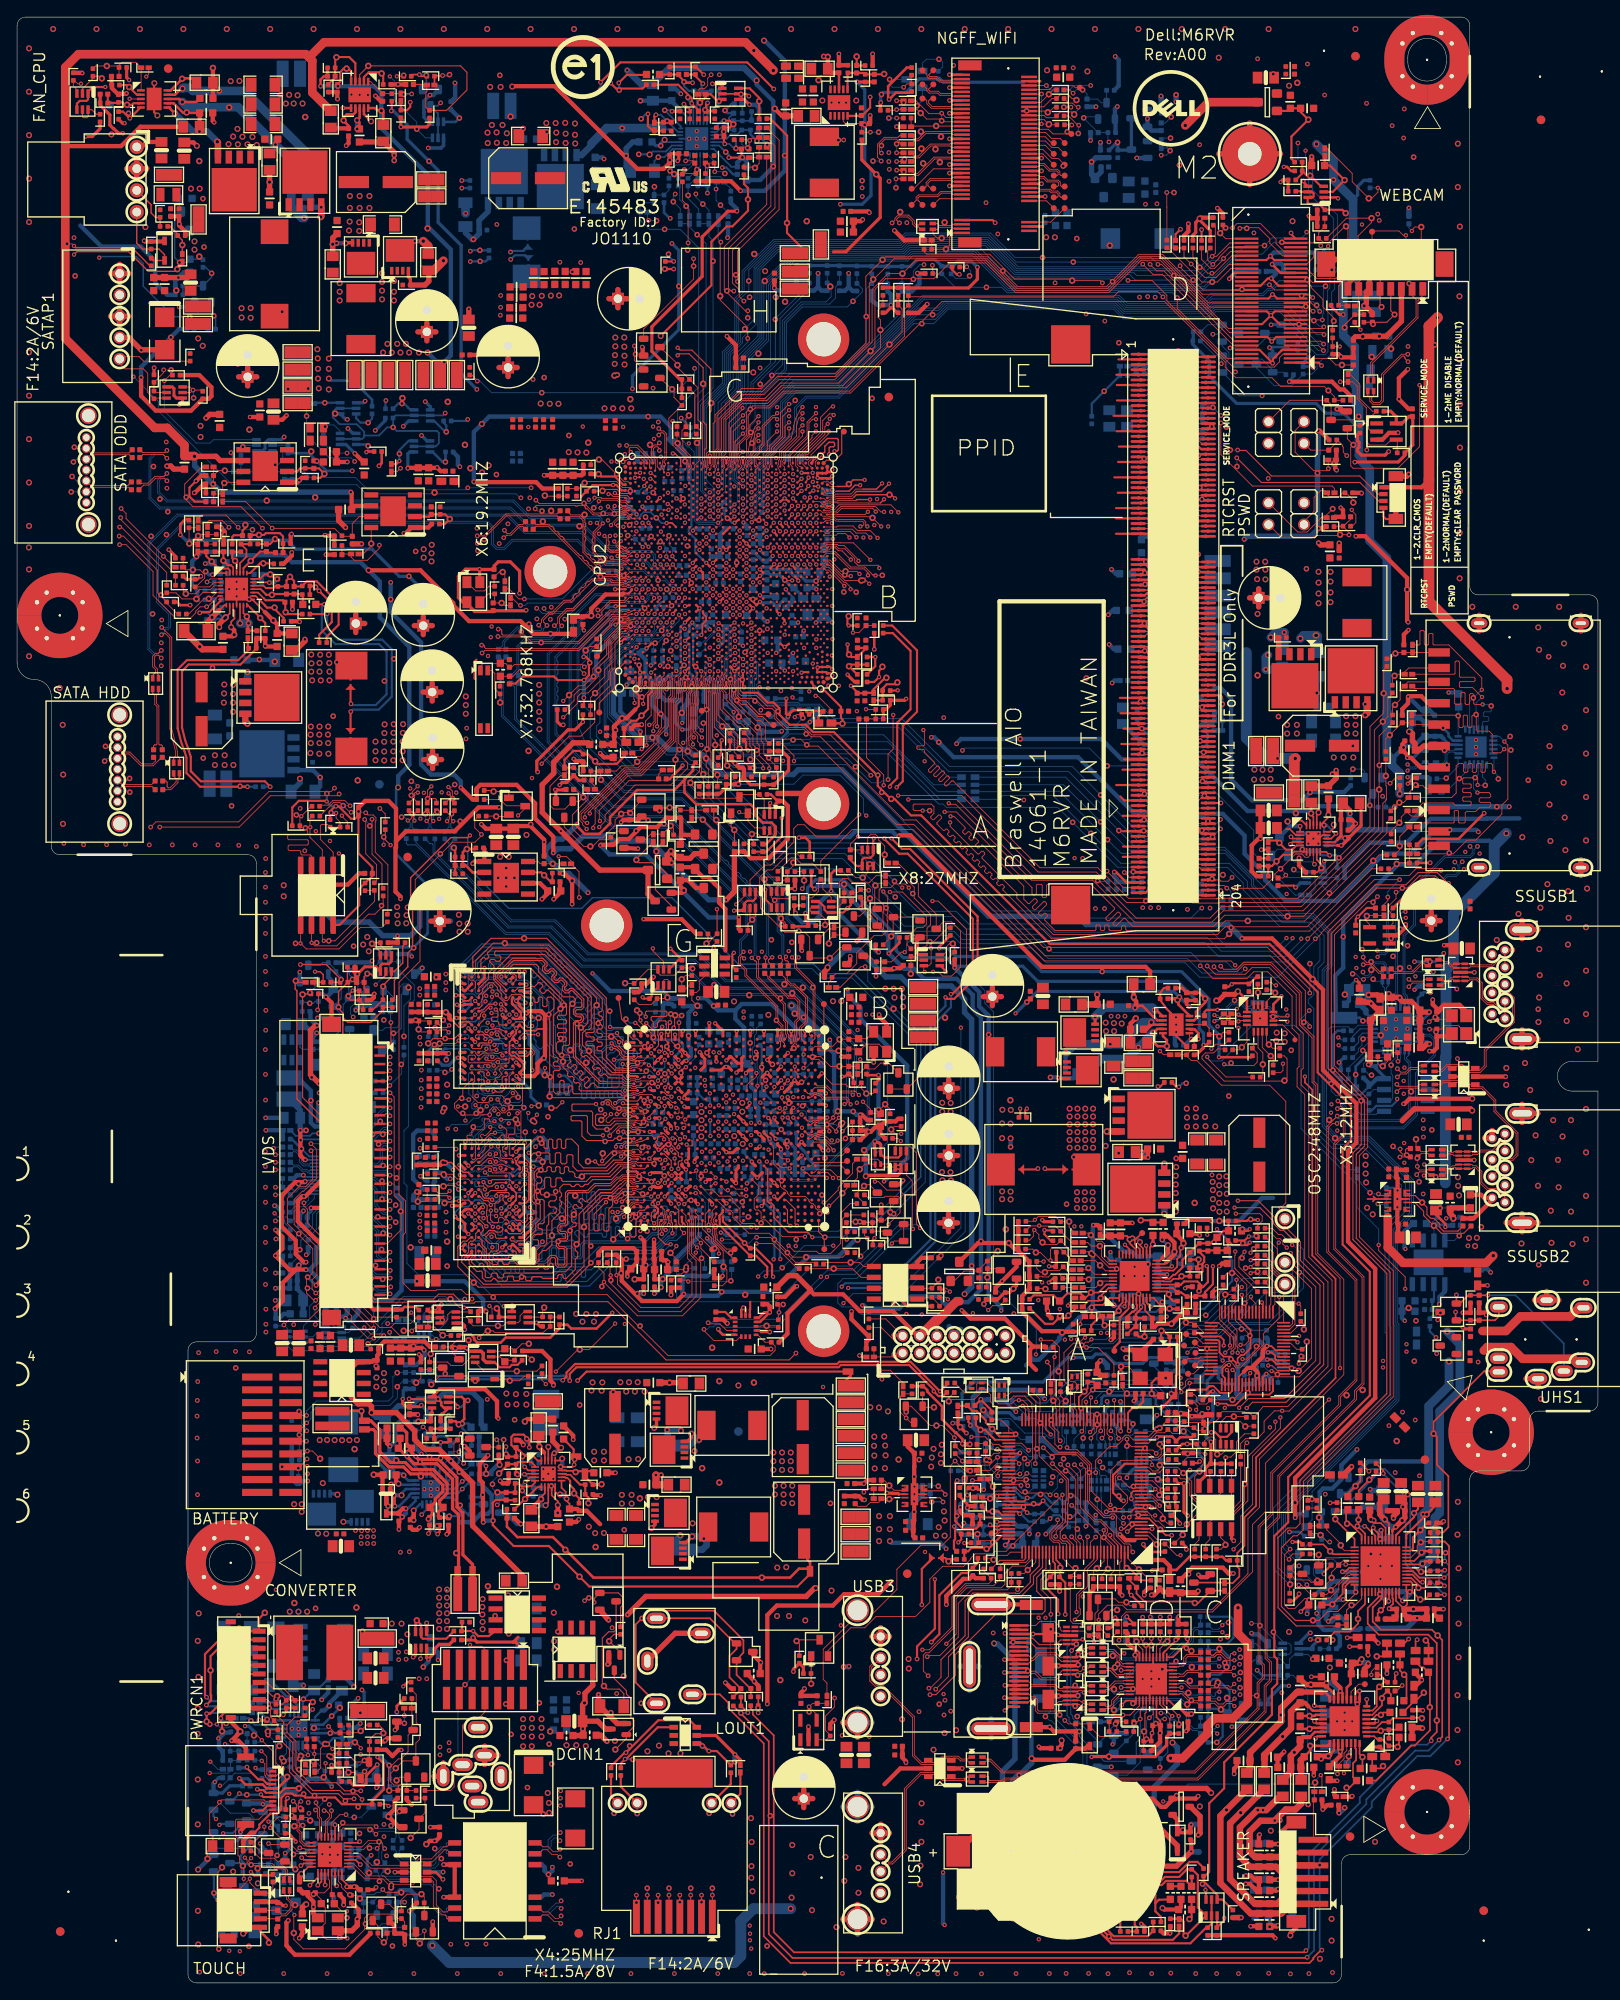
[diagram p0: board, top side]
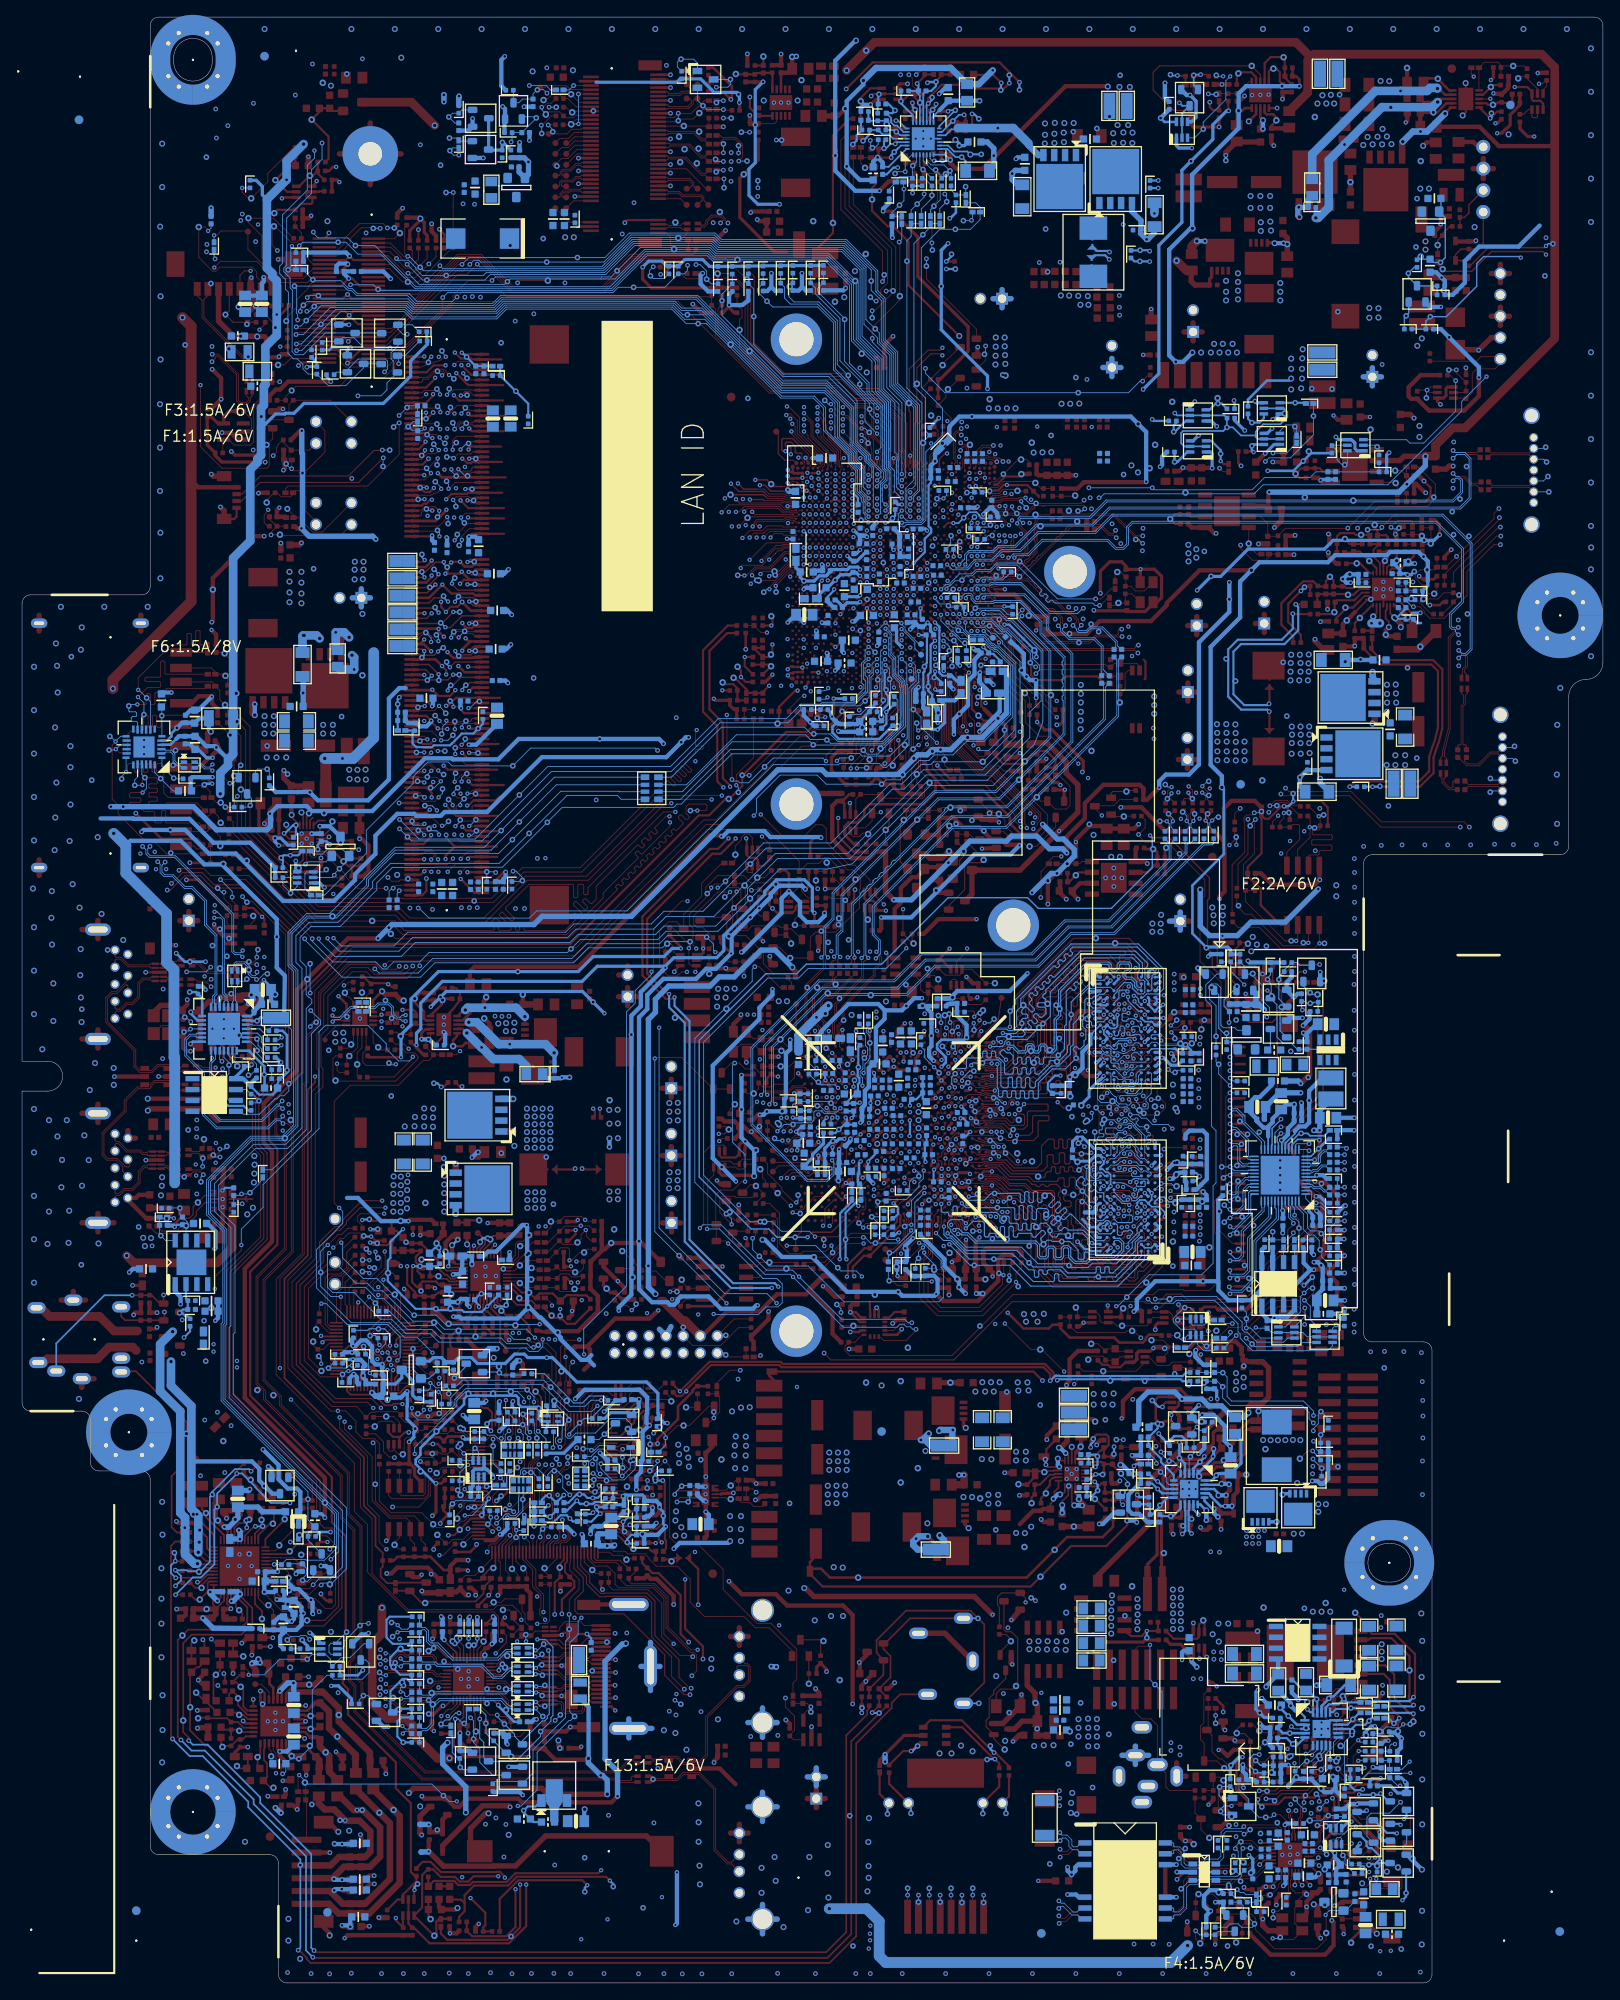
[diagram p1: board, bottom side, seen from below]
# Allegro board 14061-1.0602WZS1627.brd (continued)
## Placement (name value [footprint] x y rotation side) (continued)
R80232  0R3J-0-U-GP  [R603H22]  142.27 68.64 270 bottom
R80233  10KR2J-3-GP  [R402H16]  44.03 109.64 180 bottom
R80234  0R2J-2-GP  [R402H16]  91.73 150.64 180 bottom
R80235  0R0402-PAD-2-GP  [0R0402-PAD-1]  137.1 62 270 top
R80236  0R2J-2-GP  [R402H16]  40.94 113.86 90 top
R80237  0R2J-2-GP  [R402H16]  43.09 135.38 0 top
R80238  0R2J-2-GP  [R402H16]  155.84 110.34 90 bottom
R80239  0R2J-2-GP  [R402H16]  155.84 109.31 90 bottom
R80240  0R3J-0-U-GP  [R603H22]  88.75 154.42 270 bottom
RJ1  RJ45-8P-199-GP  [23-01120-2A03-A]  76.92 21.04 180 top
RN3  SRN33J-7-GP-U  [ARES8-CN24-UH20]  126.6 58.27 180 bottom
RN5  SRN10KJ-6-GP  [ARES8-CN24-MUH20]  127.62 62.33 0 bottom
RN6  SRN10KJ-5-GP  [ARES2H18]  123.76 70.36 0 top
RN7  SRN10KJ-5-GP  [ARES2H18]  122.89 66.01 270 bottom
RN8  SRN10KJ-6-GP  [ARES8-CN24-MUH20]  119.62 59.03 90 bottom
RN9  SRN10KJ-5-GP  [ARES2H18]  112.3 69.88 270 top
RN10  SRN75J-3-GP  [SMD-ARES8-1H28]  111.31 139.78 270 bottom
RN16  SRN2K2J-1-GP  [ARES2H16]  100.74 96.39 0 top
RN4302  SRN10KJ-5-GP  [ARES2H18]  115.22 69.34 180 top
RT1  NTC-10K-19-GP-U  [NTC-402H22-U]  101.35 158.37 0 top
RT2  NTC-10K-19-GP-U  [NTC-402H22-U]  85.8 85.52 180 top
RT3  NTC-10K-19-GP-U  [NTC-402H22-U]  75.86 200.97 0 top
RV5  P4500SCLHLRP-GP  [TVS5436-1121H105]  65.32 19.24 0 top
SATAP1  CLX-CON5-18-GP-U  [CI2505P1H00-LF-U]  12 195 270 top
SC1  SC4D7U6D3V3KX-DLGP  [C603H36]  164.76 145.09 0 bottom
SC2  SC1U16V3KX-4DLGP  [C603H36]  168.7 150.05 0 bottom
SC3  SCD1U16V2KX-3DLGP  [C402H22]  165.93 145.41 0 bottom
SC4  SC6D8P50V2CN-DL-GP  [C402H22]  162.29 156.11 180 top
SC5  SC1U16V3KX-4DLGP  [C603H36]  165.93 139.46 270 bottom
SC6  SC6D8P50V2CN-DL-GP  [C402H22]  162.11 147.88 180 top
SPK1  JWT-CON6-20-GP  [A1501WV0-6PS-5E]  149.7 13 270 top
SR1  6K2R2F-GP  [R402H16]  165.71 140.89 90 bottom
SRCON1  SKT-G6179-GP-U  [G6179-1000000-U]  35.09 127.25 0 top
SSUSB1  SKT-USB11-112-GP-U  [SKT-USB11-138165-1]  176.12 116.84 90 top
SSUSB2  SKT-USB11-112-GP-U  [SKT-USB11-138165-1]  176.12 95.34 90 top
SU1  RTS5170-GR-GP  [QFN24-G2D5H40-U]  170.73 144.6 270 bottom
TC1  ST330U2D5VDM-9GP  [CT7343H75]  131.1 204.09 270 bottom
TC5  ST100U6D3VBM-7GP  [CT3528H79]  17.28 192.98 0 top
TC10  SC10U10V5KX-2DLGP  [C805H50]  156.83 116.18 270 bottom
TC11  E100U16VM-47-GP  [ECAP-100D6D3H237]  165.49 125.55 0 top
TC13  E560U6D3VM-3-GP  [ECAP-100D6D3H375]  71.58 197.05 270 top
TC15  E560U6D3VM-3-GP  [ECAP-100D6D3H375]  57.46 190.27 0 top
TC16  E560U6D3VM-3-GP  [ECAP-100D6D3H375]  48.62 144.4 0 top
TC17  E560U6D3VM-3-GP  [ECAP-100D6D3H375]  48.57 152.3 0 top
TC18  E560U6D3VM-3-GP  [ECAP-100D6D3H375]  47.53 160.07 0 top
TC19  E560U6D3VM-3-GP  [ECAP-100D6D3H375]  39.63 160.32 0 top
TC20  E100U16VM-108-GP-U  [ECAP-100D6D3H237]  92.06 22.83 0 top
TC21  E820U2D5VM-7-GP  [ECAP-100D6D3H355]  49.46 125.5 0 top
TOUCH1  ENT-CON5-GP  [3703K-Q05N-11L]  24.7 8.5 270 top
TP2  -  [TPAD28]  158.56 204.89 270 top
TP13  -  [TPAD28]  138.42 18.54 90 bottom
TP14  -  [TPAD28]  138.29 15.32 90 bottom
TP24  -  [TPAD28]  157.72 34.95 180 top
TP35  -  [TPAD28]  71.39 157.38 180 bottom
TP37  -  [TPAD28]  122.59 214 0 top
TP38  -  [TPAD28]  121.32 215.26 0 top
TP39  -  [TPAD28]  122.59 215.26 0 top
TP46  -  [TPAD28]  114.04 52.59 0 top
TP49  -  [TPAD28]  79.8 155.41 180 bottom
TP50  -  [TPAD28]  79.8 156.65 180 bottom
TP57  -  [TPAD28]  80.12 148.84 0 top
TP62  -  [TPAD28]  107.22 208.03 0 top
TP63  -  [TPAD28]  122.59 207.65 0 top
TP64  -  [TPAD28]  121.32 207.65 0 top
TP65  -  [TPAD28]  121.32 212.72 0 top
TP66  -  [TPAD28]  122.59 212.72 0 top
TP67  -  [TPAD28]  121.32 214 0 top
TP68  -  [TPAD28]  122.59 211.46 0 top
TP69  -  [TPAD28]  121.32 211.46 0 top
TP70  -  [TPAD28]  122.59 210.19 0 top
TP71  -  [TPAD28]  121.32 210.19 0 top
TP72  -  [TPAD28]  122.59 208.91 0 top
TP73  -  [TPAD28]  121.32 208.91 0 top
TP74  -  [TPAD28]  105.95 208.03 0 top
TP75  -  [TPAD28]  104.68 208.03 0 top
TP76  -  [TPAD28]  107.22 209.93 0 top
TP77  -  [TPAD28]  105.95 209.93 0 top
TP78  -  [TPAD28]  104.68 209.93 0 top
TP79  -  [TPAD28]  105.95 220.47 0 top
TP80  -  [TPAD28]  107.22 220.47 0 top
TP81  -  [TPAD28]  105.95 222.12 0 top
TP82  -  [TPAD28]  107.22 222.12 0 top
TP83  -  [TPAD28]  105.95 223.77 0 top
TP84  -  [TPAD28]  107.22 223.77 0 top
TP85  -  [TPAD28]  124.37 221.74 0 top
TP100  -  [TPAD28]  67.88 155.22 0 top
TP101  -  [TPAD28]  123.38 216.33 0 top
TP149  -  [TPAD28]  83.98 85.85 0 top
TP150  -  [TPAD28]  83.98 84.58 0 top
TP155  -  [TPAD28]  81.34 85.83 0 top
TP158  -  [TPAD28]  81.21 89.9 180 bottom
TP159  -  [TPAD28]  88.63 97.95 180 bottom
TP163  -  [TPAD28]  97.14 97.41 0 top
TP164  -  [TPAD28]  97.14 94.92 0 top
TP165  -  [TPAD28]  97.14 96.16 0 top
TP203  -  [TPAD28]  131.67 87.73 270 top
TP204  -  [TPAD28]  128.4 73.95 90 top
TP4116  -  [TPAD28]  96.75 181.51 0 top
TP4117  -  [TPAD28]  68.13 148.64 0 top
TP4118  -  [TPAD24]  149.54 110.34 90 top
TP4124  -  [TPAD28]  137.03 71.27 180 top
TP4125  -  [TPAD28]  137.85 72.23 180 top
TP4126  -  [TPAD28]  136.65 72.69 180 top
TP4127  -  [TPAD28]  137.9 73.71 180 top
TP4128  -  [TPAD28]  136.56 74.57 180 top
TP4129  -  [TPAD28]  137.83 74.94 180 top
TP4130  -  [TPAD28]  136.81 75.92 180 top
TP4131  -  [TPAD28]  70.38 115.24 0 top
TP4132  -  [TPAD28]  94.46 85.86 0 top
TP4133  -  [TPAD28]  94.41 114.53 0 top
TP4134  -  [TPAD28]  87.92 148.44 0 top
TP4135  -  [TPAD28]  88.53 147.17 0 top
TP4136  -  [TPAD28]  80.91 152.55 180 bottom
TR1  FILTER-4P-137-GP-U  [L125100-4P-4H28]  158.41 186.87 270 top
TR3  FILTER-4P-137-GP-U  [L125100-4P-4H28]  160.11 117.82 270 bottom
TR4  FILTER-4P-137-GP-U  [L125100-4P-4H28]  165.26 106.98 180 top
TR5  FILTER-4P-137-GP-U  [L125100-4P-4H28]  112.35 23.85 0 top
TR6  FILTER-4P-137-GP-U  [L125100-4P-4H28]  165.29 104.78 180 top
TR7  FILTER-4P-137-GP-U  [L125100-4P-4H28]  112.35 26.09 0 top
TR12  MCM1012B900FBP-GP-U  [L125100-4P-1H37]  106.54 205.51 180 top
TR13  MCM1012B900FBP-GP-U  [L125100-4P-1H37]  31.55 11.46 90 top
TR20  FILTER-4P-120-GP  [L125100-4P-1H28]  126.41 32.27 0 bottom
TR21  FILTER-4P-120-GP  [L125100-4P-1H28]  126.41 34.43 0 bottom
TR22  FILTER-4P-120-GP  [L125100-4P-1H28]  126.41 36.71 0 bottom
TR23  FILTER-4P-120-GP  [L125100-4P-1H28]  126.41 38.87 0 bottom
TR24  FILTER-4P-120-GP  [L125100-4P-1H28]  126.41 32.27 0 top
TR25  FILTER-4P-120-GP  [L125100-4P-1H28]  126.41 34.43 0 top
TR26  FILTER-4P-120-GP  [L125100-4P-1H28]  126.41 36.71 0 top
TR27  FILTER-4P-120-GP  [L125100-4P-1H28]  126.41 38.87 0 top
TR28  FILTER-4P-137-GP-U  [L125100-4P-4H28]  165.43 142.5 180 bottom
TXE1  JOWLE-CON2-5-GP  [A2541WV0-1EX2PA-6T]  146.45 181.4 270 top
U1  AO6402A-GP  [SOT-6-1H50]  32.16 109.17 0 bottom
U2  SN74AUP1G34DBVR-GP  [SOT-23-5H58]  160.25 181.51 270 top
U6  ALC3661-CG-GP  [QFN48J6-G465H40]  159.55 48.77 90 top
U7  AZ1045-04F-R7G-GP  [DFN10G2510H26]  168.92 118.24 270 top
U8  W25Q64FWSSIG-GP  [SOIC8-1H86]  35.09 127.25 180 top
U9  M24C02-WMN6TP-GP-U  [SOIC8H69]  162.52 103.89 270 bottom
U15  MX25L1006EMI-10G-GP  [SOIC8H69]  140.22 55.63 0 top
U20  RTL8111G-CGT-1-GP-U2  [QFN32J4-G2D85H36]  36.61 14.99 270 top
U21  TPA3131D2RHBR-GP-U  [QFN32-G3D55H40]  155.35 30.61 270 top
U25  M24C64-WMN6TP-2-GP  [SOIC8H69]  38.01 81.79 180 bottom
U35  G2129TL1U-GP  [SC70-6H44]  88.08 135.76 180 top
U41  MBT3904DW1T1G-2-GP  [SOT-363H44]  7.65 220.12 180 top
U42  AO6402A-GP  [SOT-6-1H50]  81.62 118.97 270 top
U49  PM25LD010C-SCE-1-GP  [SOIC8H69]  102.8 81.92 90 top
U51  AZ1045-04F-R7G-GP  [DFN10G2510H26]  169.2 96.27 270 top
U52  TPS22966DPUR-GP  [SON14J3020-G2610H34]  105.01 57.18 90 top
U54  TPS22966DPUR-GP  [SON14J3020-G2610H34]  161.52 91.71 90 top
U55  BQ24727RGRR-1-GP  [QFN20G3D5-G2D15H40]  48.42 57.78 180 bottom
U109  IT8739E-GP  [LQFP128H63]  123.81 58.14 270 top
U119  AZ1117CR-ADJTRG1-GP-U  [SOT-89-4541-3PH63]  122.72 21.34 180 bottom
U120  OZ554ALN-B-0-TR-GP  [QFN20-G2D1H32]  32.93 29.72 90 bottom
U121  AZC099-04S-1-GP  [SOT-6H58]  46.64 12.95 270 top
U122  AZC099-04S-1-GP  [SOT-6H58]  46.64 12.95 270 bottom
U124  AP22802AW5-7-GP  [SOT-23-5H58]  92.62 29.59 0 top
U125  AP22802AW5-7-GP  [SOT-23-5H58]  159.42 122.57 90 top
U126  RTD2136S-CG-GP  [QFN48J6-G4D55H40]  37.78 94.5 270 bottom
U127  PS8407ATQFN40GTR2-A1-GP  [QFN40J5-G3D65H32]  132.74 35.57 270 top
U129  AZ1045-04F-R7G-GP  [DFN10G2510H26]  123.3 33.58 270 top
U130  AZ1045-04F-R7G-GP  [DFN10G2510H26]  123.3 40.64 270 top
U131  AZ1045-04F-R7G-GP  [DFN10G2510H26]  123.3 37.11 90 top
U4101  NPCE948LA0DX-GP  [LQFP64H63]  143.97 74.24 0 top
U6701  KXCNL-1010-GP  [LGA16G3-1H40]  85.25 76.83 90 top
U6702  GL850G-OHY31-GP  [QFN28-G3D75H32]  161.38 111.62 180 bottom
U6703  IP4223CZ6-1-GP  [SOT-6H44]  107.98 25.1 90 top
U6704  IP4223CZ6-1-GP  [SOT-6H44]  169.3 106.05 90 top
U6705  AZC099-04S-1-GP  [SOT-6H58]  78.19 28.96 270 top
U6706  ISL62882CHRTZ-T-GP  [QFN40-G3D5H32]  130.78 82.71 180 top
U9625  TPS2546RTER-GP  [QFN16-G1D8-UH32]  145.47 112.84 90 top
UHS1  AUDIO-JK500-GP  [2SJ3082-038111F]  176.5 75.29 90 top
UR5  330R2F-GP  [R402H16]  83.52 25.04 0 top
UR6  330R2F-GP  [R402H16]  69.5 24.71 0 top
UR7  330R2F-GP  [R402H16]  70.65 24.71 0 top
USB3  SKT-USB6-174-GP  [SKT-USB6-135063]  98.35 37.03 90 top
USB4  SKT-USB6-174-GP  [SKT-USB6-135063]  98.35 14.03 90 top
WEBCM1  JWT-CON8-4-GP  [A1251WR0-8PS-5E]  160.12 201.1 180 top
X3  XTAL-12MHZ-14GP  [SMD-OSC6H30]  168.74 112.12 90 top
X4  XTAL-25MHZ-181-GP  [OSC-3225-4P-4H36]  36.36 6.86 0 top
X6  XTAL-19D2MHZ-3-GP  [OSC-3225-4P-4H32]  53.4 162.71 270 top
X7  XTAL-32D768KHZ-67-GP  [SMD49-6914-0403H56]  54.65 150.18 270 top
X8  XTAL-27MHZ-85-GP-U  [OSC-3225-4P-4H30]  101 110.11 90 top
XDP1  SMC-CONN60A-GP  [BSH-03001-FDA]  144.09 196.82 90 top
XF1  XFORM-12P-48-GP  [XFORM12A127097H91]  55.91 11.94 90 top
XF2  XFORM-12P-48-GP  [XFORM12A127097H91]  55.91 11.94 270 bottom

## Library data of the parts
AFTP1 = AFTE14P-75: tolerance: ZZ.AFT14.101
BAT2 = 50290-0100N-001: tolerance: 20.F2196.010
BT1 = AAA-BAT-034-K01: tolerance: 62.70010.031
C3 C60 C63 C64 C67 C68 C71 C76 C77 C109 C127 C129 C405 C406 C478 C485 C1608 C1609 C1858 C4254 C6710 PC5112 PC5116 PC5212 PC5216 PC5223 PC5225 PC5257 PC5258 PC5260 PC5261 = C603H36: tolerance: 78.10610.5BLDL
C4 = C603H36: tolerance: 78.47523.5BLDL
C5 = C603H36: tolerance: 78.47422.5BLDL
C6 C8 C24 C26-C28 C35 C49 C54 C56 C61 C62 C65 C66 C69 C70 C74 C75 C78 C79 C81 C82 C89 C103 C104 C116 C131 C145 C147 C163 C179 C182 C183 C185 C186 C201 C202 C204 C211 C217 C227 C231 C270 C271 C284 C289 C290 C293 C295 C297-C303 C314-C316 C322 C324 C325 C328 C364 C372 C398 C409 C474 C483 C486 C489 C495 C500 C514 C522 C523 C525 C527-C530 C534 C536-C538 C542 C544 C547-C549 C554 C557 C562 C573 C616 C714 C721 C774 C781 C789-C792 C820 C821 C826 C829 C853 C869 C1603-C1606 C1617 C1668 C1670 C1701 C1703 C1838-C1840 C1842 C1851-C1854 C1856 C1857 C1859-C1861 C1868 C1869 C4265 C4267-C4269 C4272-C4280 C4282 C4283 C4288 C4290-C4298 C6701 C6702 C6711 C6732-C6734 C12327-C12330 C12332-C12336 C12338 C12343-C12348 PC27 PC151 PC4416 PC4516 PC4707 PC5011 PC5229 PC5264 PC5433 PC5440 SC3 = C402H22: tolerance: 78.10421.2FLDL
C7 C9 C30 C31 C170 C207 C558 C559 C561 C864 C1607 C1616 C1827 C4266 = C402H22: tolerance: 78.10523.5FL
C10 C134 C157 C159 C160 C176 C203 C267 C268 C1780 C12350 = C402H22: tolerance: 78.10134.1FLDL
C11 C112 C144 C146 C154 C155 C283 C292 C296 C450 C1674 C4261 C4263 C4289 C12326 PC21 PC4708 PC5005 PC5006 PC5430-PC5432 PC5434 PC5439 TC10 = C805H50: tolerance: 78.10623.51LDL
C14 C114 C115 C118 C119 C141 C142 C149 C151 C755 C1855 C1864 C3452 C3457 C3458 C4281 C4284-C4287 C12331 C12342 C12349 PC4427 PC4513 PC5232 PC5271 = C402H22: tolerance: 78.10324.2FLDL
C16 C90 C234 C272 C852 C1669 C1671 C1702 C1704 = C805H54: tolerance: 78.10623.51L
C20 = C805H54: tolerance: 78.47522.51LDL
C29 C50 C52 C150 C214 C218 C251 C403 C404 C407 C408 C535 C568 C597-C600 C605-C609 C612 C614 C617-C627 C629-C634 C758-C761 C765-C770 C773 C775-C779 C782 C783 C785 C786 C793-C796 C798-C803 C805-C809 C813-C819 C823-C825 C827 C835 C1491 C1633-C1636 C1638-C1641 C1643-C1663 C1665 C1666 C1698 C1699 C1867 C1877 C4101 C4102 C4259 PC1 PC163 PC4428 PC4528 PC4702 PC4905 PC4906 PC5003 PC5004 PC5233 PC5259 PC5443 = C402H22: tolerance: 78.10523.5FLDL
C32 = C603H36: tolerance: 78.10492.4BLLL
C33 = C402H22: tolerance: 78.27034.1FLLL
C36-C39 = C1206H75: tolerance: 078.10525.022D
C40 = C1206H71: tolerance: 78.10525.22LLL
C42 C86 = C402H22: tolerance: 78.10322.2FL
C43 C3456 = C402H22: tolerance: 78.10422.5FLLL
C44 = C402H22: tolerance: 078.15124.02FD
C47 C753 C1846 = C402H22: tolerance: 78.10423.2FL
C48 C543 C551 C3459 C3460 PC4401 PC4406 PC4407 PC5240 PC5241 = C805H58: tolerance: 78.10622.51LDL
C72 C73 C138 C139 C771 C780 C784 C787 C788 C797 C804 C810 C811 C828 C830 PC4917 PC4918 SC1 = C603H36: tolerance: 78.47520.5BLDL
C80 C84 C121 C132 PC5114 PC5219 PC5226 = C402H22: tolerance: 78.10134.1FL
C87 C88 C111 C191 C213 C238 C249 C380 C385 C399 C516 C572 C574-C576 C763 C764 C4230 C4260 C4262 = C402H22: tolerance: 78.10421.2FL
C93 C94 C96 C105 C397 C400 C545 C552 C12324 C12325 PC20 PC28 PC34 PC4204 PC4302 PC4402-PC4404 PC4423 PC4523 PC4703 PC4913 PC4914 PC4916 PC5008 PC5234 PC5236 PC5242 PC5273 PC5442 = C603H35: tolerance: 78.10424.2BLDL
C97 C100 C859 = C603H36: tolerance: 78.10424.2BL
C101 C110 C189 C192 C193 C208 C401 C402 C1801 PC5113 PC5213 PC5224 PC5435 PC5447 = C603H36: tolerance: 78.10522.5BLDL
C106 C107 PC8 = C402H22: tolerance: 78.33034.1FLDL
C126 PC124 = C402H22: tolerance: 78.22034.1FL
C130 = C402H22: tolerance: 78.10422.5FL
C140 C232 C391 C540 C1615 PC4426 PC4526 = C603H36: tolerance: 78.22523.5BLDL
C174 C175 C180 = C402H22: tolerance: 78.10491.4FL
C181 = C402H22: tolerance: 78.22510.5FL
C190 C194 C220 C221 = C603H36: tolerance: 78.47520.5BL
C195 PC12 = C603H36: tolerance: 78.10422.2BL
C198-C200 C210 = C603H36: tolerance: 78.27324.2BLDL
C205 C212 = C402H22: tolerance: 78.15034.1FLDL
C215 C216 C291 C641-C644 C772 = C805H54: tolerance: 78.22610.51LDL
C222 C239 C243 C263 = C603H36: tolerance: 78.10324.2BL
C223 C224 C228 C229 PC16 PC19 PC60 PC4421 PC4521 = C603H36: tolerance: 78.22422.2BLDL
C225 C235 C247 C255 = C603H36: tolerance: 78.68421.5BL
C226 C236 C248 C256 = C603H36: tolerance: 78.10234.1BLDL
C304 C305 C582 C583 C590-C592 C812 C822 C6716-C6722 C6726-C6731 PC5012 = C603H40: tolerance: 78.22610.5BLDL
C313 C752 = C402H22: tolerance: 78.47034.1FL
C393 PC59 = C603H36: tolerance: 78.10421.2BL
C493 C509 C6703 PC5115 PC5215 PC5227 = C603H38: tolerance: 78.10610.5BL
C521 = C603H36: tolerance: 78.10521.5BL
C524 PC4303 PC4413 PC4420 PC4520 = C402H22: tolerance: 78.22224.2FLDL
C531 = C402H22: tolerance: 78.10224.2FL
C571 = C402H22: tolerance: 78.10413.5FLDL
C711 C6715 = C402H22: tolerance: 78.10034.1FL
C756 C757 = C402H22: tolerance: 78.12034.1FLDL
C762 = C402H22: tolerance: 78.12134.1FLDL
C836 C6725 = C402H20: tolerance: 78.10423.5FL
C839 = C402H22: tolerance: 78.68034.1FL
C1601 C1602 = C402H22: tolerance: 78.8R064.1FLDL
C1618 C1619 = C402H22: tolerance: 78.2R774.1FL
C1620-C1625 = C402H22: tolerance: 078.47510.05FD
C1667 C1696 C1700 = C402H22: tolerance: 78.10520.5FLDL
C1672 C1673 C1705 C1706 C4202 C4270 PC7 PC4418 PC4518 PC5235 PC5272 = C402H22: tolerance: 78.10224.2FLDL
C1847 = C402H22: tolerance: 078.82321.02FD
C1848 = C603H38: tolerance: 078.68421.05BD
C1849 = C402H22: tolerance: 78.82321.2FL
C1850 C6724 PC4527 = C402H22: tolerance: 78.10322.2FLDL
C3131 = C1808H87: tolerance: 078.1013N.014D
C3455 PC4405 PC5238 = C402H22: tolerance: 78.10422.5FLDL
C12339-C12341 PC4202 PC4203 = C603H36: tolerance: 78.10422.2BLDL
CMCLR1 CMCLR2 PSWD1 TXE1 = A2541WV0-1EX2PA-6T: tolerance: 21.60909.102
CN1 = 210-41-04GB02: tolerance: 21.62889.104
CN2 = 88459-047N: tolerance: 20.F1897.004
CONVT1 = CI1410M1HRL-NH: tolerance: 20.F2266.010
CPU2 = BGA1170M2725H57: tolerance: 071.BRASW.000U
D1 D33 = SOD323AKH38: tolerance: 83.00355.D1F
D5 = SOT-23-9H44: tolerance: 75.00040.07D
D6 = SOD323AKH38: tolerance: 83.R5003.H8H
D14 = SOT23-2D4-312H48: tolerance: 75.00099.F7D
D18 = SOD323AKH40: tolerance: 83.00355.F1F
D21 = SOD523AKH28: tolerance: 83.02015.0AF
D32 = D4724AKH44: tolerance: 83.3R010.C8M
D34 D5209 = SOT23-2D4-312H44: tolerance: 75.00054.I7D
DCIN1 = 2DC3115-000111F: tolerance: 022.10015.0311
DCIN2 = 88314-077N: tolerance: 20.F1498.007
DIMM1 = AS0A621-J4R6-7H-U: tolerance: 62.10024.S21
F1 F3 F4 F13 = POLYSW-2114H30: tolerance: 069.50001.0031
F2 F14 = POLYSW-2114H30: tolerance: 069.50003.0001
F6 = POLYSW-3217-UH40: tolerance: 69.50007.B91
F16 = FUSE-1608H22: tolerance: 69.43001.441
FANC3 = HF1804H: tolerance: 021.D0086.0104
G5 = CON2C-U: tolerance: ZZ.CON2C.XXX
GPU1 = BGA631M23H82: tolerance: 71.SUNM2.M02
H1-H5 = HOLE237R158: tolerance: ZZ.0HOLE.011
H6 H9 = GEN8D5X8R5X4D5-8-F-A: tolerance: ZZ.00PAD.BV1
H7 = GEN315R138-8-F-A-1: tolerance: ZZ.00PAD.BU1
H10 = GEN315R178-8-F-A-1: tolerance: ZZ.00PAD.BR1
H11 = GEN315R138-8-F-A-2-S: tolerance: ZZ.00PAD.HK1
HDD1 ODD1 = 15-02070-5A61-A: tolerance: 020.80244.0007
HDMI1 = SKT-HDMI22-150077: tolerance: 062.10012.0121
HDMI2 = LVDFH-02004-TP00: tolerance: 20.F2139.020
HS6 = STF256R109H99: tolerance: 34.3NH01.001
L1 = L20125H42: tolerance: 68.00216.121
L2 = L3030-2709H41: tolerance: 68.2R21F.10E
L3 = L603H38: tolerance: 68.00335.091
L4 L5 L36 L37 L4103 L4104 = L125100-4P-1H36: tolerance: 68.12105.201
L7 L9 = L603H38: tolerance: 68.00335.081
L10 L52 L53 = L603H38: tolerance: 68.00335.141
L16 L17 L19 = L603H38: tolerance: 68.00230.231
L20 L21 L47-L51 L54 L62 L4102 = L402H24: tolerance: 68.00213.031
L22 = L402H22: tolerance: 68.00084.541
L31-L34 = L20125H42: tolerance: 68.00216.111
L46 PR36-PR38 PR46 PR47 PR211-PR213 PR4490-PR4493 PR4590 PR4591 PR4790 PR4791 PR4904-PR4910 PR4913 PR4915 PR4916 PR4926 PR4990 PR4991 PR5003-PR5008 PR5012 PR5013 PR5090 PR5091 PR5471 PR9788 PR9789 R101 R157 R183 R185 R1223-R1225 R79935 = 0R0805-PAD: tolerance: ZZ.R0805.ZZZ
L61 = L8080-6020H158: tolerance: 068.33010.1061
L4101 = L402H22: tolerance: 68.00084.I21
LED2 = LED1608AKH30: tolerance: 83.01608.Q70
LOUT1 = JAC331-0140A8B-9H: tolerance: 22.10277.2M1
LPC1 = HL5507F: tolerance: 21.60964.207
LVDS1 = 50524-0300N-001: tolerance: 020.K0005.0030
MEM1-MEM4 = BGA96D075130H48: tolerance: 72.51G63.R0U
MEMCD1 = 156-5101902601: tolerance: 062.10002.0161
NGFF1 = 2199230-7: tolerance: 62.10043.K51
OSC2 = SMD-OSC8H52: tolerance: 82.20013.151
PC4 PC4705 PC4909 PC4910 PC5002 PC5262 PC5446 = C402H22: tolerance: 78.22034.1FLDL
PC5 = C603H40: tolerance: 78.22422.2BL
PC6 = C402H22: tolerance: 78.15134.1FLDL
PC9 PC14 = C402H22: tolerance: 78.10324.2FL
PC11 = C402H22: tolerance: 078.39124.02FD
PC13 PC4411 PC4511 PC5268 = C402H22: tolerance: 78.33124.2FLDL
PC15 = C402H22: tolerance: 078.33322.02FD
PC17 PC18 PC22 PC33 PC58 SC2 SC5 = C603H36: tolerance: 78.10521.2BLDL
PC23 PC5267 = C603H36: tolerance: 78.15224.2BLDL
PC24 PC29 PC31 PC32 PC61 PC4424 PC4524 PC4706 PC4901-PC4904 PC5001 PC5010 PC5269 PC5270 PC5441 = C1206H71: tolerance: 78.10622.22LDL
PC41 = C402H22: tolerance: 78.22034.L1L
PC68 = C402H22: tolerance: 78.27034.1FLDL
PC2127 PC4304 PC4417 PC4517 PC5237 = C402H22: tolerance: 78.47124.2FLDL
PC4201 PC4408 = C805H54: tolerance: 78.10524.21LDL
PC4301 PC4305 = C402H22: tolerance: 78.10034.1FLDL
PC4409 PC4410 PC4509 PC4510 PC4701 PC4801 PC5211 PC5222 PC5243 PC5251 PC5254-PC5256 PC5266 PC5436 PC5444 = C402H22: tolerance: 78.10423.5FLDL
PC4412 PC4512 = C402H22: tolerance: 78.47034.1FLDL
PC4414 PC4514 = C402H22: tolerance: 78.10221.2FLDL
PC4415 PC4515 = C402H22: tolerance: 78.33224.2FLDL
PC4419 = C402H22: tolerance: 78.56124.2FLDL
PC4429 PC4529 PC4704 PC4907 PC4908 PC5009 PC5263 PC5445 = C603H36: tolerance: 78.10224.2BLDL
PC4519 = C402H22: tolerance: 78.18224.2FLDL
PC4911 PC4912 = C402H22: tolerance: 78.18034.1FLDL
PC4915 = C402H22: tolerance: 78.10521.5FLDL
PC5007 = C402H22: tolerance: 78.33321.2FLDL
PC5217 = C402H22: tolerance: 78.10423.2FLDL
PC5221 PC5228 = C402H22: tolerance: 78.22044.1FL
PC5239 = C402H22: tolerance: 78.22124.2FLDL
PC5265 = C402H22: tolerance: 78.68124.2FLDL
PD4202 = D5436AKH97: tolerance: 83.P6SBM.CAG
PD4401 = D1608-035030AKH28: tolerance: 83.1R003.N8F
PD4405 = SOD323AKH42: tolerance: 83.04148.D1H
PG3 PG4 PG4401 PG4402 PG4501 PG4502 = CON2C: tolerance: ZZ.CON2C.XX1
PG4901-PG4908 = GAP-CLOSE-PWR-3: tolerance: ZZ.CLOSE.001
PL1 PL4501 = L115100-2H158: tolerance: 68.R3610.10M
PL3 = L115100-2030H158: tolerance: 68.1R51A.10E
PL4301-PL4303 = L402H24: tolerance: 69.80007.021
PL4401 = L736630H119: tolerance: 68.R3310.201
PL4701 PL5002 PL5004 PL47001 = L686647H119: tolerance: 68.1R51A.10F
PL4903 = L686647H119: tolerance: 68.3R31A.10V
PL4904 = L686647H119: tolerance: 68.2R21B.10J
PL5003 = L7066-1830-UH119: tolerance: 68.5R610.10X
PN4401 PN4402 PN4501 PN4502 = NTC-402H24-U: tolerance: 69.60028.041
PQ7 = PPAK-5PH45: tolerance: 84.00172.A37
PQ8 = PPAK-5PH45: tolerance: 84.SRA12.037
PQ4204 = SOT323CBE2D2H44: tolerance: 84.00124.H1K
PQ4205 = SOT323CBE2D2H44: tolerance: 84.00124.K1K
PQ4206 PQ4408 = SOT23DGS2D4H44: tolerance: 84.2N702.J31
PQ4401 PQ5001 PU4502 = PPAK-8P-5262H40: tolerance: 84.06520.037
PQ4402 PQ5002 PU4503 PU4504 = PPAK-8P-5262H40: tolerance: 084.06510.0037
PQ4406 PQ5006 Q30 Q48 Q49 Q1228-Q1233 Q6701 Q9646 = SOT-363H44: tolerance: 84.2N702.A3F
PQ4409 = SOT23CBE2D4H44: tolerance: 84.T3906.A11
PQ4701 PQ4901 PQ4903 PQ4904 PQ47001 PU4403 PU4405 = PPAK-8P-3232H36: tolerance: 84.07410.A37
PQ4702 PQ4902 PQ47002 = PPAK-8P-3232H36: tolerance: 84.07506.037
PQ5003 PQ5004 Q1 Q3 Q5 Q42 Q56 Q64 Q65 Q68 Q103 Q1246 Q1254 Q1257 Q2301 Q6703 Q9628 Q9636 Q9648 Q9650 = SOT23DGS2D4H48: tolerance: 84.2N702.E31
PQ5005 = SOT-363H44: tolerance: 84.00512.03F
PR1 PR12 PR4431 PR4455 PR4458 PR4462 PR5247-PR5250 PR5476 PR8521 PR9785 R14 R92 R131 R179 R180 R206 R379 R380 R503 R565 R618 R661-R663 R701 R1154 R1155 R1234 R1260 R1261 R1267 R1268 R1576-R1578 R1591 R1620-R1623 R1697 R1791 R1840 R1841 R1846 R1892 R1920 R2079 R6706 R79664 R79665 R79682 R79697-R79700 R79755 R79756 R79913 R79938 R79946-R79948 R79951 R79954-R79957 R79960 R79961 R79964 R80054-R80057 R80059 R80061 R80063-R80065 R80074-R80081 R80090 R80091 R80099 R80100 R80107-R80109 R80113 R80115 R80122 R80123 R80132 R80134 R80147 R80156 R80203-R80211 R80218 R80231 R80234 R80236-R80239 = R402H16: tolerance: 63.R0034.1DL
PR2 PR10 PR14 PR17 PR18 PR23 PR25 PR28-PR30 PR32 PR35 PR44 PR101 PR5014 PR5110 PR5216 PR5245 PR5274 PR5288 PR9773 PR9774 R5 R88 R374 R536 R682 R1160 = 0R0402-PAD: tolerance: ZZ.R0402.ZZZ
PR3 PR4 PR7 PR15 PR26 PR31 PR33 PR96 PR102 PR103 PR4210 PR4401 PR4429 PR4501 PR4529 PR5214 PR5241 PR5251 PR5257 PR5480 PR9768-PR9770 PR9772 PR9775 PR9776 PR9780 PR9787 R46 R64 R143 R199 R225 R277 R278 R287 R293 R314 R316 R331 R336 R368 R375 R477 R544 R572 R627 R635 R646 R677 R680 R1738-R1745 R1792-R1800 R1917 R79675 R79717 R79718 R79759 R79761-R79763 R79766 R79772 R80155 = R402H16: tolerance: 63.10234.1DL
PR5 PR19 PR58 PR77 PR4450 PR4718 PR4917 PR4922 PR5001 PR5112 PR5212 PR5242 PR5282 PR5286 PR9796 R82 R266 R270 R275 R279 R354 R357 R363 R366 R370 R397 R404 R653 R655-R658 R1801-R1819 R79621 R79625 R79692-R79694 R79780 R80125 R80126 R80216 = R402H16: tolerance: 64.10025.6DL
PR6 = R402H16: tolerance: 64.19115.6DL
PR8 PR9 R208 R210 R1896 R79796 R79966 R80133 = R402H16: tolerance: 64.47025.6DL
PR11 PR4410 PR4413 PR4510 PR4513 PR5220-PR5222 PR5232-PR5234 PR5254 PR5261 PR5479 PR9806-PR9811 R15 R22 R23 R34 R35 R47 R53 R74 R86 R178 R205 R207 R222 R280 R283 R305 R318 R381 R385 R386 R395 R399 R400 R507 R515 R532 R539 R651 R652 R664 R668 R725 R729 R1165 R1166 R1203 R1209 R1214 R1240 R1241 R1258 R1263 R1264 R1569 R1571 R1584-R1589 R1592 R1593 R1596-R1599 R1601 R1602 R1604 R1606 R1608-R1612 R1627 R1628 R1637 R1668-R1672 R1683 R1689 R1747 R1776 R1778 R1835-R1839 R1891 R1916 R1984 R1985 R2080 R3586 R79618 R79633 R79634 R79660 R79668 R79684 R79685 R79712 R79713 R79715 R79939 R79949 R79950 R79977 R79980-R79982 R80050-R80053 R80092 R80093 R80103-R80106 R80153 R80154 R80235 = 0R0402-PAD-1: tolerance: ZZ.00PAD.M11
PR13 PR5016 = R402H16: tolerance: 64.80615.6DL
PR16 = R402H16: tolerance: 64.12115.6DL
PR20 = R402H16: tolerance: 64.56205.6DL
PR21 = R402H16: tolerance: 64.18715.6DL
PR34 = R402H16: tolerance: 64.82R55.6DL
PR39 PR41 PR48 PR50 PR4701 PR4713 PR4714 PR4716 PR4902 PR4903 PR4911 PR4912 PR5011 PR5018 PR5019 PR5474 PR5475 PR9783 PR9793 PR9794 PR9797 PR9805 = R805H24: tolerance: 63.2R231.16L
PR40 PR225 PR4402 PR4403 PR4422 PR4502 PR4503 PR4522 PR4712 PR4715 PR4812 PR5002 PR5213 PR5246 PR5258 PR9798 PR9803 R7 R41 R42 R44 R48-R51 R54 R56-R60 R62 R63 R65-R67 R75 R89 R95 R134 R138 R149 R156 R158 R164 R169 R172 R184 R186 R213 R221 R281 R285 R286 R296 R297 R303 R304 R310 R311 R313 R317 R323 R330 R333 R335 R340 R342 R348 R362 R364 R378 R388 R390 R391 R421 R481 R482 R498 R499 R505 R510 R514 R516 R517 R523 R530 R531 R533 R550 R552-R558 R560-R563 R567 R569 R576 R579 R581 R636 R637 R645 R675 R704 R707 R709 R717 R719 R722 R739 R1167 R1208 R1226 R1257 R1262 R1265 R1266 R1568 R1579-R1582 R1615 R1633 R1656 R1661 R1719 R1780 R1782 R1820 R1842 R1843 R1867 R1868 R1870 R1880-R1882 R1885-R1887 R1910 R1915 R5290 R6702 R79657 R79659 R79662 R79666 R79667 R79680 R79683 R79687-R79689 R79701-R79705 R79719-R79721 R79750 R79758 R79765 R79773 R79781 R79797 R79799 R79917 R79936 R79943-R79945 R79952 R79953 R80062 R80116 R80121 R80144 R80146 R80150 R80212 R80217 R80219 R80220 R80230 R80233 = R402H16: tolerance: 63.10334.1DL
PR42 = R402H16: tolerance: 64.26115.6DL
PR43 = R603H22: tolerance: 64.2R205.55L
PR45 = R603H22: tolerance: 64.36515.55L
PR51 = NTC-402H24-U: tolerance: 69.60013.131
PR53 PR4702 PR9804 R20 R1918 = R402H16: tolerance: 64.47035.6DL
PR57 = R402H16: tolerance: 63.51334.1DL
PR59 = R402H16: tolerance: 64.15825.6DL
PR60 = NTC-402H24-U: tolerance: 69.60013.141
PR78 = R402H16: tolerance: 64.69815.6DL
PR79 PR4416 PR4516 PR5283 R220 R284 R1202 R79716 = R402H14: tolerance: 64.10R05.6DL
PR1689 = R402H16: tolerance: 64.12425.6DL
PR4204 = R603H22: tolerance: 63.24434.15L
PR4207 = R603H22: tolerance: 63.47333.15L
PR4214 = R1206H28: tolerance: 63.33232.11L
PR4404 PR4504 = R402H16: tolerance: 64.47R05.6DL
PR4405 PR4505 R61 R1158 R1162 R1163 R1897 R79661 = R402H16: tolerance: 64.10015.6DL
PR4406 PR4506 = R402H16: tolerance: 64.56035.6DL
PR4407 PR4507 = R402H16: tolerance: 64.33015.6DL
PR4411 PR4511 = R402H16: tolerance: 64.15015.6DL
PR4412 PR5272 = R402H16: tolerance: 64.49925.6DL
PR4414 PR4514 = R402H16: tolerance: 64.62025.6DL
PR4415 PR4918 = R402H16: tolerance: 64.56225.6DL
PR4417 = R603H22: tolerance: 64.33035.55L
PR4418 PR9782 = R402H16: tolerance: 64.40215.6DL
PR4419 PR4519 = R402H16: tolerance: 64.75025.6DL
PR4420 PR4520 = R402H16: tolerance: 64.15035.6DL
PR4421 PR4423 PR4424 PR4521 PR4523 PR4524 PR5017 = R1206H28: tolerance: 63.2R232.11L
PR4425 PR4426 PR8519 PR8520 = R402H16: tolerance: 63.33234.1DL
PR4427 PR4901 PR4923 PR5010 PR5273 PR5275 PR5278 PR5281 PR5289 PR5297 PR9813 R26 R30 R33 R94 R132 R144 R151 R153 R155 R162 R181 R273 R321 R338 R360 R361 R424 R501 R512 R676 R1074 R1079 R1126 R1164 R1696 R1832 R1894 R1914 R6703-R6705 R79681 R79723 R79757 R79916 R80120 R80145 = R402H16: tolerance: 63.10434.1DL
PR4428 PR4528 = R805H24: tolerance: 63.1R031.16L
PR4430 PR4530 = R603H22: tolerance: 63.2R233.15L
PR4432 = R402H16: tolerance: 64.22125.6DL
PR4433 PR4533 = R402H16: tolerance: 64.18725.6DL
PR4451 = R402H16: tolerance: 64.68035.6DL
PR4515 = R402H16: tolerance: 64.45325.6DL
PR4517 = R603H22: tolerance: 64.10035.55L
PR4518 R1205 = R402H16: tolerance: 64.49915.6DL
PR4531 = R402H16: tolerance: 64.48725.6DL
PR4532 = R402H16: tolerance: 64.34825.6DL
PR4706-PR4709 PR9790-PR9792 PR9799-PR9802 = 0R0805-PAD-1-U: tolerance: ZZ.00PAD.M31
PR4717 = R402H16: tolerance: 64.36015.6DL
PR4914 = R402H16: tolerance: 64.66515.6DL
PR4919 = R402H16: tolerance: 64.68025.6DL
PR4920 PR4925 = R402H16: tolerance: 64.11035.6DL
PR4921 R332 R422 R80215 = R402H16: tolerance: 64.15025.6DL
PR4924 = R402H16: tolerance: 64.11835.6DL
PR5009 = R402H16: tolerance: 64.75035.6DL
PR5015 SR1 = R402H16: tolerance: 64.62015.6DL
PR5109 PR5209 PR5243 PR5290 PR5291 PR9767 R577 R1244 R1245 R1247 R1250-R1256 R79691 = 0R0603-PAD: tolerance: ZZ.R0603.ZZZ
PR5113 = R402H16: tolerance: 64.86615.6DL
PR5211 = R402H16: tolerance: 64.54915.6DL
PR5268 R80060 = R402H16: tolerance: 64.33025.6DL
PR5269 PR5276 = R3720H40: tolerance: 64.R0105.7FL
PR5270 = R603H22: tolerance: 64.31635.55L
PR5277 = R402H16: tolerance: 64.7R505.6DL
PR5279 = R402H16: tolerance: 64.1R505.6DL
PR5284 = R805H24: tolerance: 64.20R05.16L
PR5285 = R402H16: tolerance: 63.47434.1DL
PR5287 = R402H16: tolerance: 63.33534.1DL
PR5298 = R402H16: tolerance: 64.12035.6DL
PR5467 = R402H16: tolerance: 64.10235.6DL
PR5468 = R402H16: tolerance: 64.16935.6DL
PR5469 = R402H16: tolerance: 64.78725.6DL
PR5470 = R402H16: tolerance: 64.30935.6DL
PR5473 = R402H16: tolerance: 64.18025.6DL
PR9766 = R402H14: tolerance: 63.10134.1DL
PR9771 PR9779 = R402H16: tolerance: 64.1R005.6DL
PR9777 R215 R300 R301 R344-R346 R356 R359 R367 R1182 R1193 R80138 R80139 = 0R0603-PAD-1-U: tolerance: ZZ.00PAD.M21
PR9778 = R402H16: tolerance: 64.93115.6DL
PR9781 = R402H16: tolerance: 64.11025.6DL
PR9795 R302 = R402H16: tolerance: 64.51115.6DL
PR9812 R319 R1557-R1561 R79628 R79722 R80102 R80128 = R402H16: tolerance: 64.10035.6DL
PR9814 R19 R1919 R80112 = R402H16: tolerance: 63.10534.1DL
PT1 PT3 PT4 = ECAP-100D6D3H355: tolerance: 09.8271N.A4L
PT2 PT4491 PT4591 PT5001 PT5002 = SE361416H237: tolerance: 79.47612.A0L
PT4901 = SE361414H241: tolerance: 79.47612.3GL
PT4902 PT4903 = SE331721H237: tolerance: 79.22710.E0L
PTC9 PTC21 PTC4701 PTC4702 TC21 = ECAP-100D6D3H355: tolerance: 09.8271N.A5L
PU1 PU2 = PPAK-8P-5262H40: tolerance: 84.06552.037
PU3 PU5207 = PPAK-8P-5262H40: tolerance: 84.06508.037
PU4 PU4701 PU4705 = DFN10G3-G265175H32: tolerance: 74.08237.B73
PU7 = SOIC8-G3530H63: tolerance: 74.05912.03D
PU4201 PU5204 PU5205 = SOIC8H69: tolerance: 84.04407.G37
PU4401 PU4501 = LFQFN28J4-G2D7H40: tolerance: 074.81201.0073
PU4901 = QFN20-G1D75H32: tolerance: 074.08243.0073
PU5001 = QFN20-G1D75H32: tolerance: 74.08207.C73
PU5201-PU5203 = SOIC8-G3530H63: tolerance: 74.05930.B3D
PU5206 = DFN10G3-G265175H32: tolerance: 74.08068.A43
PWRCN1 = 51530-01041-W01: tolerance: 20.K0642.010
Q4 Q7 Q95 Q97 Q123 = SOT-363H44: tolerance: 75.27002.F7C
Q10 Q18 Q36-Q38 Q40 Q51 Q74-Q76 Q9625 = SOT23CBE2D4H44: tolerance: 84.T3904.C11
Q12 Q13 Q16 Q17 Q20 Q21 Q35 Q63 Q1206 Q9643 = SOT-363H44: tolerance: 84.M3904.B1F
Q19 Q6708 Q6710 Q6711 Q6714 Q9635 Q9642 = SOT23CBE2D4H44: tolerance: 84.T3904.H11
Q23 Q29 = SOT-363H44: tolerance: 75.27002.D7C
Q24 Q46 Q57 = SOT23-2D4-312H46: tolerance: 75.05125.07D
Q28 = SOT23DGS2D4H44: tolerance: 84.27002.W31
Q39 Q1209 Q1240 Q9629 Q9632 Q9640 Q9641 Q9647 Q9649 = SOT23DGS2D8H50: tolerance: 84.03413.B31
Q47 Q1236 Q1253 Q6702 Q6715 = SOT-23-10H44: tolerance: 84.03904.L06
Q66 Q77-Q79 Q1205 Q1214 Q1227 Q1234 Q6706 = SOT23DGS2D4H44: tolerance: 84.27002.Z31
Q1203 Q1204 Q1210 Q1212 Q1213 Q1255 Q1256 = SOT23DGS2D4H48: tolerance: 84.05067.031
Q1250 = SOIC8H69: tolerance: 084.04286.0037
Q6705 Q9624 = SOT23DGS2D8H50: tolerance: 84.03418.A31
Q9634 = SOT23DGS2D4H48: tolerance: 84.03052.031
R8 R644 = R603H22: tolerance: 63.33133.15L
R10 R329 R702 R705 R1129 R1687 R1688 R80228 = R402H16: tolerance: 63.82234.1DL
R13 R706 R1195 R80229 = R402H16: tolerance: 64.39225.6DL
R24 R216 R289 R1246 R1248 R1249 R1720 R6701 R79753 R80148 R80151 R80152 R80232 R80240 = R603H22: tolerance: 63.00000.00L
R27 R79622 = R1206H26: tolerance: 64.R3305.41L
R32 R69 R80 R133 R135 R139 R152 R324 R389 R535 R634 R659 R665 R669 R693 R720 R1883 R79669 R79670 R79673 R79677-R79679 R79686 R79914 R80140-R80142 R80201 R80202 = R402H16: tolerance: 63.47234.1DL
R37 R79631 = 0R1206-PAD-1: tolerance: ZZ.R1206.ZZ1
R39 = R402H16: tolerance: 63.22034.1DL
R43 = R402H16: tolerance: 64.22005.6DL
R45 R68 R382 R1259 R1822 R1823 R1826 R1827 R1888 R1889 R79656 R79787 R79788 = R402H14: tolerance: 64.10005.6DL
R55 R71 R72 R223 R261 R262 R272 R392 R502 R642 R721 R1204 R1844 R79690 R79732 R79733 R79736-R79739 R79764 R79798 R79967 R80110 R80111 = R402H16: tolerance: 63.22234.1DL
R73 R274 R492 R639 R643 R1830 R1831 R1845 R79774 R79786 R80157 = R402H16: tolerance: 63.20334.1DL
R76 = R402H16: tolerance: 64.82015.6DL
R81 = R603H22: tolerance: 64.10055.55L
R87 R91 R268 R80049 = R402H16: tolerance: 64.20025.6DL
R117 R122 R269 R483 R484 R542 R545 R1215 R1216 R1562 R1565 R1570 R79734 R79735 R79741-R79746 R79748 R79749 = R402H16: tolerance: 64.47015.6DL
R146 = R402H16: tolerance: 63.20234.1DL
R163 R79915 = R402H16: tolerance: 63.47334.1DL
R174 = R402H16: tolerance: 64.61905.6DL
R202 R203 R230 R885 R886 R924 R928 R945 R946 R1905 R1911 R1921-R1924 R79968 = R402H16: tolerance: 64.21015.6DL
R209 R309 R312 R337 R373 R393 R426 R681 R689 R1168-R1171 R1733 R1884 R79940-R79942 = R402H16: tolerance: 63.33034.1DL
R212 = R402H16: tolerance: 64.68R05.6DL
R267 = R402H16: tolerance: 64.51015.6DL
R299 R320 R870 R899 = R402H16: tolerance: 64.24305.6DL
R306 = R603H22: tolerance: 63.15234.15L
R322 R369 R1879 = R603H22: tolerance: 64.10045.55L
R347 = R402H16: tolerance: 64.39015.6DL
R351 R352 R667 R673 R79612 = R603H22: tolerance: 64.75R05.55L
R355 R365 = R603H22: tolerance: 64.10525.55L
R358 = R402H16: tolerance: 64.56015.6DL
R372 R394 R940 = R402H16: tolerance: 64.20015.6DL
R376 = R603H22: tolerance: 63.10033.15L
R377 R1242 = R402H16: tolerance: 64.24915.6DL
R396 R403 R415 R419 = R603H22: tolerance: 64.3R305.55L
R398 R963 R1159 R1893 R1895 R79965 = R402H15: tolerance: 63.10334.L0L
R428 R429 R79962 = R402H16: tolerance: 63.47034.1DL
R430 = R402H16: tolerance: 63.15234.1DL
R456-R458 R466 R473 R1746 = R402H16: tolerance: 63.51034.1DL
R511 = R402H16: tolerance: 64.12025.6DL
R513 R519 R1227 R1228 R1236 = R402H16: tolerance: 64.40205.6DL
R524 R1648 R1654 R80149 = R402H16: tolerance: 64.49R95.6DL
R527 R1217 = R402H16: tolerance: 64.18205.6DL
R537 R543 R549 R551 = R402H15: tolerance: 64.10025.L0L
R617 = R402H16: tolerance: 63.33334.1DL
R648 R650 = R402H16: tolerance: 64.17825.6DL
R649 = R402H16: tolerance: 64.64915.6DL
R935 = R402H16: tolerance: 64.45315.6DL
R943 R1900 R79963 = R402H16: tolerance: 64.84515.6DL
R948 R1899 = R402H16: tolerance: 64.47515.6DL
R1161 = R402H16: tolerance: 64.16915.6DL
R1200 R1890 R1906-R1909 = R402H16: tolerance: 64.40R25.6DL
R1201 = R402H16: tolerance: 64.12005.6DL
R1206 R1207 = R402H16: tolerance: 64.51R15.6DL
R1210 = R402H16: tolerance: 64.24905.6DL
R1211 R80137 = R402H16: tolerance: 64.49905.6DL
R1230 R80143 = R402H16: tolerance: 64.15005.6DL
R1239 = R402H16: tolerance: 64.20035.6DL
R1634 R79707-R79711 R79714 = R805H24: tolerance: 63.R0031.16L
R1647 R1653 = R402H16: tolerance: 64.20R05.6DL
R1714 R1729-R1732 = R402H14: tolerance: 63.10034.1DL
R1734 = R402H16: tolerance: 64.56R25.6D1
R1779 = R402H16: tolerance: 64.45R35.6DL
R1784-R1790 = R402H16: tolerance: 64.47005.6DL
R79623 R79627 = R402H16: tolerance: 64.30035.6DL
R79630 = R805H24: tolerance: 63.20131.16L
R79658 = R402H16: tolerance: 64.80R65.6DL
R79724-R79731 = R402H16: tolerance: 63.47134.1DL
R79747 = R402H16: tolerance: 64.43015.6DL
R79751 = R603H22: tolerance: 64.18005.55L
R79752 = R603H22: tolerance: 64.36R05.55L
R79754 R80124 = R805H24: tolerance: 64.10025.16L
R79785 = R402H16: tolerance: 64.11305.6DL
R79790-R79792 R79795 R79937 = R402H16: tolerance: 64.20005.6DL
R79793 R79794 = R402H16: tolerance: 64.30105.6DL
R79800 = R402H16: tolerance: 64.51025.6DL
R79802 = R402H16: tolerance: 64.59025.6DL
R80130 = R402H16: tolerance: 64.57626.6DL
RJ1 = 23-01120-2A03-A: tolerance: 062.10032.0041
RN3 = ARES8-CN24-UH20: tolerance: 66.33036.A8L
RN5 RN8 = ARES8-CN24-MUH20: tolerance: 66.10336.08L
RN6 RN7 RN9 RN4302 = ARES2H18: tolerance: 66.10336.04L
RN10 = SMD-ARES8-1H28: tolerance: 66.75036.A8L
RN16 = ARES2H16: tolerance: 66.22236.04L
RT1-RT3 = NTC-402H22-U: tolerance: 69.60011.121
RV5 = TVS5436-1121H105: tolerance: 069.A0007.0001
SATAP1 = CI2505P1H00-LF-U: tolerance: 021.60197.0105
SC4 SC6 = C402H22: tolerance: 78.6R874.1FLDL
SPK1 = A1501WV0-6PS-5E: tolerance: 21.D0278.106
SRCON1 = G6179-1000000-U: tolerance: 62.10076.011
SSUSB1 SSUSB2 = SKT-USB11-138165-1: tolerance: 022.10005.0391
SU1 = QFN24-G2D5H40-U: tolerance: 71.05170.003
TC1 = CT7343H75: tolerance: 77.23371.13L
TC5 = CT3528H79: tolerance: 77.21071.07L
TC11 = ECAP-100D6D3H237: tolerance: 09.1071D.A5L
TC13 TC15-TC19 = ECAP-100D6D3H375: tolerance: 09.56710.A8L
TC20 = ECAP-100D6D3H237: tolerance: 09.1071D.F5L
TOUCH1 = 3703K-Q05N-11L: tolerance: 020.F0146.0005
TP2 TP13 TP14 TP24 TP35 TP37-TP39 TP46 TP49 TP50 TP57 TP62-TP85 TP100 TP101 TP149 TP150 TP155 TP158 TP159 TP163-TP165 TP203 TP204 TP4116 TP4117 TP4124-TP4136 = TPAD28: tolerance: ZZ.PAD28.XXX
TP4118 = TPAD24: tolerance: ZZ.PAD24.001
TR1 TR3-TR7 TR28 = L125100-4P-4H28: tolerance: 68.01012.20B
TR12 TR13 = L125100-4P-1H37: tolerance: 68.01012.201
TR20-TR27 = L125100-4P-1H28: tolerance: 68.10129.201
U1 U42 = SOT-6-1H50: tolerance: 84.06402.B3D
U2 = SOT-23-5H58: tolerance: 73.01G34.00G
U6 = QFN48J6-G465H40: tolerance: 71.03661.003
U7 U51 U129-U131 = DFN10G2510H26: tolerance: 75.01045.073
U8 = SOIC8-1H86: tolerance: 72.25Q64.S01
U9 = SOIC8H69: tolerance: 72.24C02.M01
U15 = SOIC8H69: tolerance: 72.25106.001
U20 = QFN32J4-G2D85H36: tolerance: 71.08111.U03
U21 = QFN32-G3D55H40: tolerance: 74.03131.013
U25 = SOIC8H69: tolerance: 72.24C64.R01
U35 = SC70-6H44: tolerance: 73.02129.02J
U41 = SOT-363H44: tolerance: 75.03904.A7C
U49 = SOIC8H69: tolerance: 72.25010.R01
U52 U54 = SON14J3020-G2610H34: tolerance: 74.22966.093
U55 = QFN20G3D5-G2D15H40: tolerance: 74.24727.A73
U109 = LQFP128H63: tolerance: 071.08739.000G
U119 = SOT-89-4541-3PH63: tolerance: 074.01117.0038
U120 = QFN20-G2D1H32: tolerance: 074.00554.0073
U121 U122 U6705 = SOT-6H58: tolerance: 75.09904.07C
U124 U125 = SOT-23-5H58: tolerance: 074.22802.009F
U126 = QFN48J6-G4D55H40: tolerance: 71.02136.003
U127 = QFN40J5-G3D65H32: tolerance: 071.08407.0003
U4101 = LQFP64H63: tolerance: 071.00948.000G
U6701 = LGA16G3-1H40: tolerance: 074.01010.00B3
U6702 = QFN28-G3D75H32: tolerance: 71.0850G.003
U6703 U6704 = SOT-6H44: tolerance: 75.04223.07C
U6706 = QFN40-G3D5H32: tolerance: 74.62882.A73
U9625 = QFN16-G1D8-UH32: tolerance: 74.02546.073
UHS1 = 2SJ3082-038111F: tolerance: 022.10002.0881
UR5-UR7 = R402H16: tolerance: 64.33005.6DL
USB3 USB4 = SKT-USB6-135063: tolerance: 022.10005.01E1
WEBCM1 = A1251WR0-8PS-5E: tolerance: 20.F1245.008
X3 = SMD-OSC6H30: tolerance: 82.30006.211
X4 = OSC-3225-4P-4H36: tolerance: 82.30020.G71
X6 = OSC-3225-4P-4H32: tolerance: 82.30071.051
X7 = SMD49-6914-0403H56: tolerance: 82.30001.G11
X8 = OSC-3225-4P-4H30: tolerance: 82.30034.641
XDP1 = BSH-03001-FDA: tolerance: 20.F0441.060
XF1 XF2 = XFORM12A127097H91: tolerance: 68.68167.30D

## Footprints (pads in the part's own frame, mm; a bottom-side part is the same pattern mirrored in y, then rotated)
0R0402-PAD
  custom 0.14x0.14 smd: 1(0,0.445) 2(0,-0.445)
0R0402-PAD-1
  custom 0.14x0.14 smd: 1(0,0.445) 2(0,-0.445)
0R0603-PAD
  custom 0.216x0.216 smd: 1(0,0.851) 2(0,-0.673)
0R0603-PAD-1-U
  custom 0.216x0.216 smd: 1(0,0.762) 2(0,-0.762)
0R0805-PAD
  rect 1.397x1.562 smd: 1(0,0.965)
  rect 1.397x1.569 smd: 2(0,-0.965)
0R0805-PAD-1-U
  rect 1.397x1.562 smd: 1(0,0.965)
  rect 1.397x1.569 smd: 2(0,-0.965)
0R1206-PAD-1
  rect 1.651x2.057 smd: 1(0,1.397) 2(0,-1.397)
2DC3115-000111F
  oval 1.422x2.413 hole 0.711x1.702: 1(-1.1,1.46)
  oval 1.473x2.413 hole 0.762x1.702: 2(2.5,0) 5(4.375,0.7) 7(-4.375,0.7)
  oval 1.524x2.413 hole 0.813x1.702: 3(0,-1.13)
  oval 2.413x1.473 hole 1.702x0.762: 4(1.35,3.375) 6(1.35,-3.375)
2SJ3082-038111F
  round 0.254 hole 1.27 unplated: (0,0) (0,-6)
  oval 1.321x2.134 hole 0.61x1.422: 1(3.8,3.1) 2(-3.7,-4.5) 3(3.7,-6.8) 4(-2.7,-6.6) 5(-2.2,3.1) 6(-3.8,3.1) MS1(-4.6,-1.5) MS2(4.6,-2.5)
15-02070-5A61-A
  round 1.041 hole 0.762: 1(3.81,-0.25) 2(2.54,-0.25) 3(1.27,-0.25) 4(0,-0.25) 5(-1.27,-0.25) 6(-2.54,-0.25) 7(-3.81,-0.25)
  round 1.93 hole 1.524: 8(6.37,0) 9(-6.37,0)
23-01120-2A03-A
  rect 0.813x3.988 smd: 1(-4.445,13.3) 2(-3.175,13.3) 3(-1.905,13.3) 4(-0.635,13.3) 5(0.635,13.3) 6(1.905,13.3) 7(3.175,13.3) 8(4.445,13.3)
  round 1.321 hole 0.914: 9(-6.645,0) 10(-4.355,0) 11(4.355,0) 12(6.645,0)
  rect 8.992x3.404 smd: 13(0,-3.5)
156-5101902601
  round 0.254 hole 1.702 unplated: (-12.65,0) (12.65,0)
  rect 0.991x2.54 smd: 1(-7.57,8.245) 2(-5.07,8.245) 3(-2.57,8.245) 4(-0.07,8.245) 5(2.43,8.245) 6(4.93,8.245) 7(7.43,8.245) 8(9.055,8.245) 9(-10.07,8.245) 10(10.875,8.245) 11(-11.755,8.245)
  oval 1.118x1.93 hole 0.406x1.219: 12(-14.3,3.55) 13(14.3,3.55) 14(-14.3,-8.35) 15(14.3,-8.35)
210-41-04GB02
  round 1.422 hole 1.016: 1(-3.81,0) 3(1.27,0) 4(3.81,0)
  rect 0.025x0.025 smd: 2(-1.27,0)
3703K-Q05N-11L
  rect 0.61x1.549 smd: 1(-2,3.775) 2(-1,3.775) 3(0,3.775) 4(1,3.775) 5(2,3.775)
  rect 1.194x2.007 smd: 6(-3.3,0) 7(3.3,0)
50290-0100N-001
  rect 0.838x3.556 smd: 1A(-6.75,-3.9) 2A(-5.25,-3.9) 3A(-3.75,-3.9) 4A(-2.25,-3.9) 5A(-0.75,-3.9) 6A(0.75,-3.9) 7A(2.25,-3.9) 8A(3.75,-3.9) 9A(5.25,-3.9) 10A(6.75,-3.9)
  rect 0.838x2.642 smd: 1B(-6.75,0) 2B(-5.25,0) 3B(-3.75,0) 4B(-2.25,0) 5B(-0.75,0) 6B(0.75,0) 7B(2.25,0) 8B(3.75,0) 9B(5.25,0) 10B(6.75,0)
50524-0300N-001
  rect 0.305x1.295 smd: 1(-14.5,5.65) 2(-13.5,5.65) 3(-12.5,5.65) 4(-11.5,5.65) 5(-10.5,5.65) 6(-9.5,5.65) 7(-8.5,5.65) 8(-7.5,5.65) 9(-6.5,5.65) 10(-5.5,5.65) 11(-4.5,5.65) 12(-3.5,5.65) 13(-2.5,5.65) 14(-1.5,5.65) 15(-0.5,5.65) 16(0.5,5.65) 17(1.5,5.65) 18(2.5,5.65) 19(3.5,5.65) 20(4.5,5.65) 21(5.5,5.65) 22(6.5,5.65) 23(7.5,5.65) 24(8.5,5.65) 25(9.5,5.65) 26(10.5,5.65) 27(11.5,5.65) 28(12.5,5.65) 29(13.5,5.65) 30(14.5,5.65)
  rect 1.803x2.21 smd: 31(-17.15,0) 32(17.15,0)
51530-01041-W01
  rect 0.305x0.838 smd: 1(-2.25,3.175) 2(-1.75,3.175) 3(-1.25,3.175) 4(-0.75,3.175) 5(-0.25,3.175) 6(0.25,3.175) 7(0.75,3.175) 8(1.25,3.175) 9(1.75,3.175) 10(2.25,3.175)
  rect 0.813x2.007 smd: 11(-3.95,0) 12(3.95,0)
88314-077N
  rect 0.838x3.556 smd: 1(-4.5,-3.225) 2(-3,-3.225) 3(-1.5,-3.225) 4(0,-3.225) 5(1.5,-3.225) 6(3,-3.225) 7(4.5,-3.225)
  rect 0.838x2.642 smd: 8(-4.5,0.675) 9(-3,0.675) 10(-1.5,0.675) 11(0,0.675) 12(1.5,0.675) 13(3,0.675) 14(4.5,0.675)
88459-047N
  rect 0.508x0.991 smd: 1(1.2,1.455) 2(0.4,1.455) 3(-0.4,1.455) 4(-1.2,1.455)
  rect 1.194x1.702 smd: 5(2.5,0) 6(-2.5,0)
2199230-7
  round 0.254 hole 1.6 unplated: (-10,0)
  round 0.254 hole 1.118 unplated: (10,0)
  rect 0.305x1.854 smd: 1(9.25,-5.423) 2(9,2.423) 3(8.75,-5.423) 4(8.5,2.423) 5(8.25,-5.423) 6(8,2.423) 7(7.75,-5.423) 16(5.5,2.423) 17(5.25,-5.423) 18(5,2.423) 19(4.75,-5.423) 20(4.5,2.423) 21(4.25,-5.423) 22(4,2.423) 23(3.75,-5.423) 24(3.5,2.423) 25(3.25,-5.423) 26(3,2.423) 27(2.75,-5.423) 28(2.5,2.423) 29(2.25,-5.423) 30(2,2.423) 31(1.75,-5.423) 32(1.5,2.423) 33(1.25,-5.423) 34(1,2.423) 35(0.75,-5.423) 36(0.5,2.423) 37(0.25,-5.423) 38(0,2.423) 39(-0.25,-5.423) 40(-0.5,2.423) 41(-0.75,-5.423) 42(-1,2.423) 43(-1.25,-5.423) 44(-1.5,2.423) 45(-1.75,-5.423) 46(-2,2.423) 47(-2.25,-5.423) 48(-2.5,2.423) 49(-2.75,-5.423) 50(-3,2.423) 51(-3.25,-5.423) 52(-3.5,2.423) 53(-3.75,-5.423) 54(-4,2.423) 55(-4.25,-5.423) 56(-4.5,2.423) 57(-4.75,-5.423) 58(-5,2.423) 59(-5.25,-5.423) 60(-5.5,2.423) 61(-5.75,-5.423) 62(-6,2.423) 63(-6.25,-5.423) 64(-6.5,2.423) 65(-6.75,-5.423) 66(-7,2.423) 67(-7.25,-5.423) 68(-7.5,2.423) 69(-7.75,-5.423) 70(-8,2.423) 71(-8.25,-5.423) 72(-8.5,2.423) 73(-8.75,-5.423) 74(-9,2.423) 75(-9.25,-5.423)
  rect 1.194x2.743 smd: 76(10.35,-4.5) 77(-10.35,-4.5)
A1251WR0-8PS-5E
  rect 0.813x1.6 smd: 1(-4.375,2.9) 2(-3.125,2.9) 3(-1.875,2.9) 4(-0.625,2.9) 5(0.625,2.9) 6(1.875,2.9) 7(3.125,2.9) 8(4.375,2.9)
  rect 2.108x2.997 smd: 9(-6.925,0) 10(6.925,0)
A1501WV0-6PS-5E
  rect 0.711x3.505 smd: 1(3.75,2) 2(2.25,2) 3(0.75,2) 4(-0.75,2) 5(-2.25,2) 6(-3.75,2)
  rect 1.499x2.311 smd: 7(5.8,0) 8(-5.8,0)
A2541WV0-1EX2PA-6T
  round 1.397 hole 0.991: 1(-1.27,0) 2(1.27,0)
AAA-BAT-034-K01
  round 0.254 hole 1.067 unplated: (-7.5,0)
  round 0.254 hole 1.372 unplated: (0,0)
  rect 2.794x3.607 smd: 1(6.2,0)
  rect 2.997x2.591 smd: 2(-15.1,0)
AFTE14P-75
  round 0.356 smd: 1(0,0)
ARES2H16
  rect 0.356x0.66 smd: 1(-0.325,-0.599) 2(0.325,-0.599) 3(0.325,0.599) 4(-0.325,0.599)
ARES2H18
  rect 0.356x0.66 smd: 1(-0.325,-0.599) 2(0.325,-0.599) 3(0.325,0.599) 4(-0.325,0.599)
ARES8-CN24-MUH20
  rect 0.61x0.66 smd: 1(-0.9,-0.486) 4(0.9,-0.486) 5(0.9,0.486) 8(-0.9,0.486)
  rect 0.305x0.66 smd: 2(-0.25,-0.486) 3(0.25,-0.486) 6(0.25,0.486) 7(-0.25,0.486)
ARES8-CN24-UH20
  rect 0.61x0.66 smd: 1(-0.9,-0.486) 4(0.9,-0.486) 5(0.9,0.486) 8(-0.9,0.486)
  rect 0.305x0.66 smd: 2(-0.25,-0.486) 3(0.25,-0.486) 6(0.25,0.486) 7(-0.25,0.486)
AS0A621-J4R6-7H-U
  round 0.254 hole 1.118 unplated: (-33.4,0)
  round 0.254 hole 1.6 unplated: (33.4,0)
  custom 0.114x0.114 smd: 1(31.65,4.1) 2(31.35,-4.1) 3(31.05,4.1) 4(30.751,-4.1) 5(30.45,4.1) 6(30.15,-4.1) 7(29.85,4.1) 8(29.55,-4.1) 9(29.251,4.1) 10(28.95,-4.1) 11(28.65,4.1) 12(28.35,-4.1) 13(28.051,4.1) 14(27.751,-4.1) 15(27.45,4.1) 16(27.15,-4.1) 17(26.851,4.1) 18(26.551,-4.1) 19(26.25,4.1) 20(25.95,-4.1) 21(25.65,4.1) 22(25.35,-4.1) 23(25.051,4.1) 24(24.75,-4.1) 25(24.45,4.1) 26(24.15,-4.1) 27(23.851,4.1) 28(23.55,-4.1) 29(23.25,4.1) 30(22.95,-4.1) 31(22.651,4.1) 32(22.351,-4.1) 33(22.05,4.1) 34(21.75,-4.1) 35(21.451,4.1) 36(21.151,-4.1) 37(20.85,4.1) 38(20.55,-4.1) 39(20.25,4.1) 40(19.95,-4.1) 41(19.65,4.1) 42(19.35,-4.1) 43(19.049,4.1) 44(18.749,-4.1) 45(18.45,4.1) 46(18.15,-4.1) 47(17.85,4.1) 48(17.549,-4.1) 49(17.25,4.1) 50(16.95,-4.1) 51(16.65,4.1) 52(16.349,-4.1) 53(16.049,4.1) 54(15.75,-4.1) 55(15.45,4.1) 56(15.15,-4.1) 57(14.849,4.1) 58(14.549,-4.1) 59(14.25,4.1) 60(13.95,-4.1) 61(13.649,4.1) 62(13.349,-4.1) 63(13.05,4.1) 64(12.75,-4.1) 65(12.45,4.1) 66(12.149,-4.1) 67(11.85,4.1) 68(11.55,-4.1) 69(11.25,4.1) 70(10.95,-4.1) 71(10.649,4.1) 72(10.349,-4.1) 73(7.65,4.1) 74(7.35,-4.1) 75(7.049,4.1) 76(6.749,-4.1) 77(6.45,4.1) 78(6.15,-4.1) 79(5.85,4.1) 80(5.549,-4.1) 81(5.25,4.1) 82(4.95,-4.1) 83(4.65,4.1) 84(4.349,-4.1) 85(4.05,4.1) 86(3.75,-4.1) 87(3.45,4.1) 88(3.15,-4.1) 89(2.849,4.1) 90(2.549,-4.1) 91(2.25,4.1) 92(1.95,-4.1) 93(1.649,4.1) 94(1.349,-4.1) 95(1.05,4.1) 96(0.75,-4.1) 97(0.45,4.1) 98(0.149,-4.1) 99(-0.15,4.1) 100(-0.45,-4.1) 101(-0.75,4.1) 102(-1.051,-4.1) 103(-1.351,4.1) 104(-1.65,-4.1) 105(-1.95,4.1) 106(-2.25,-4.1) 107(-2.551,4.1) 108(-2.851,-4.1) 109(-3.15,4.1) 110(-3.45,-4.1) 111(-3.751,4.1) 112(-4.051,-4.1) 113(-4.35,4.1) 114(-4.65,-4.1) 115(-4.95,4.1) 116(-5.251,-4.1) 117(-5.55,4.1) 118(-5.85,-4.1) 119(-6.15,4.1) 120(-6.451,-4.1) 121(-6.751,4.1) 122(-7.051,-4.1) 123(-7.35,4.1) 124(-7.65,-4.1) 125(-7.951,4.1) 126(-8.251,-4.1) 127(-8.55,4.1) 128(-8.85,-4.1) 129(-9.15,4.1) 130(-9.451,-4.1) 131(-9.75,4.1) 132(-10.05,-4.1) 133(-10.35,4.1) 134(-10.651,-4.1) 135(-10.95,4.1) 136(-11.25,-4.1) 137(-11.55,4.1) 138(-11.85,-4.1) 139(-12.151,4.1) 140(-12.451,-4.1) 141(-12.75,4.1) 142(-13.05,-4.1) 143(-13.351,4.1) 144(-13.651,-4.1) 145(-13.95,4.1) 146(-14.25,-4.1) 147(-14.55,4.1) 148(-14.851,-4.1) 149(-15.15,4.1) 150(-15.45,-4.1) 151(-15.75,4.1) 152(-16.051,-4.1) 153(-16.35,4.1) 154(-16.65,-4.1) 155(-16.95,4.1) 156(-17.25,-4.1) 157(-17.551,4.1) 158(-17.851,-4.1) 159(-18.15,4.1) 160(-18.45,-4.1) 161(-18.751,4.1) 162(-19.051,-4.1) 163(-19.35,4.1) 164(-19.65,-4.1) 165(-19.95,4.1) 166(-20.251,-4.1) 167(-20.55,4.1) 168(-20.85,-4.1) 169(-21.15,4.1) 170(-21.451,-4.1) 171(-21.751,4.1) 172(-22.051,-4.1) 173(-22.35,4.1) 174(-22.65,-4.1) 175(-22.951,4.1) 176(-23.251,-4.1) 177(-23.55,4.1) 178(-23.85,-4.1) 179(-24.151,4.1) 180(-24.451,-4.1) 181(-24.75,4.1) 182(-25.05,-4.1) 183(-25.35,4.1) 184(-25.651,-4.1) 185(-25.95,4.1) 186(-26.25,-4.1) 187(-26.55,4.1) 188(-26.851,-4.1) 189(-27.151,4.1) 190(-27.451,-4.1) 191(-27.75,4.1) 192(-28.05,-4.1) 193(-28.351,4.1) 194(-28.651,-4.1) 195(-28.95,4.1) 196(-29.25,-4.1) 197(-29.55,4.1) 198(-29.851,-4.1) 199(-30.15,4.1) 200(-30.45,-4.1) 201(-30.75,4.1) 202(-31.05,-4.1) 203(-31.349,4.1) 204(-31.649,-4.1)
  rect 4.496x4.597 smd: 205(32.8,12) 206(-32.8,12)
BGA96D075130H48
  round 0.356 smd: A1(-3.2,6) A2(-2.4,6) A3(-1.6,6) A7(1.6,6) A8(2.4,6) A9(3.2,6) B1(-3.2,5.2) B2(-2.4,5.2) B3(-1.6,5.2) B7(1.6,5.2) B8(2.4,5.2) B9(3.2,5.2) C1(-3.2,4.4) C2(-2.4,4.4) C3(-1.6,4.4) C7(1.6,4.4) C8(2.4,4.4) C9(3.2,4.4) D1(-3.2,3.6) D2(-2.4,3.6) D3(-1.6,3.6) D7(1.6,3.6) D8(2.4,3.6) D9(3.2,3.6) E1(-3.2,2.8) E2(-2.4,2.8) E3(-1.6,2.8) E7(1.6,2.8) E8(2.4,2.8) E9(3.2,2.8) F1(-3.2,2) F2(-2.4,2) F3(-1.6,2) F7(1.6,2) F8(2.4,2) F9(3.2,2) G1(-3.2,1.2) G2(-2.4,1.2) G3(-1.6,1.2) G7(1.6,1.2) G8(2.4,1.2) G9(3.2,1.2) H1(-3.2,0.4) H2(-2.4,0.4) H3(-1.6,0.4) H7(1.6,0.4) H8(2.4,0.4) H9(3.2,0.4) J1(-3.2,-0.4) J2(-2.4,-0.4) J3(-1.6,-0.4) J7(1.6,-0.4) J8(2.4,-0.4) J9(3.2,-0.4) K1(-3.2,-1.2) K2(-2.4,-1.2) K3(-1.6,-1.2) K7(1.6,-1.2) K8(2.4,-1.2) K9(3.2,-1.2) L1(-3.2,-2) L2(-2.4,-2) L3(-1.6,-2) L7(1.6,-2) L8(2.4,-2) L9(3.2,-2) M1(-3.2,-2.8) M2(-2.4,-2.8) M3(-1.6,-2.8) M7(1.6,-2.8) M8(2.4,-2.8) M9(3.2,-2.8) N1(-3.2,-3.6) N2(-2.4,-3.6) N3(-1.6,-3.6) N7(1.6,-3.6) N8(2.4,-3.6) N9(3.2,-3.6) P1(-3.2,-4.4) P2(-2.4,-4.4) P3(-1.6,-4.4) P7(1.6,-4.4) P8(2.4,-4.4) P9(3.2,-4.4) R1(-3.2,-5.2) R2(-2.4,-5.2) R3(-1.6,-5.2) R7(1.6,-5.2) R8(2.4,-5.2) R9(3.2,-5.2) T1(-3.2,-6) T2(-2.4,-6) T3(-1.6,-6) T7(1.6,-6) T8(2.4,-6) T9(3.2,-6)
BGA631M23H82
  round 0.406 smd: A3(-10,10.8) A5(-9.2,10.8) A28(9.2,10.8) A30(10,10.8) A32(10.8,10.8) AH1(-10.8,-9.2) AH3(-10,-9.2) AH5(-9.2,-9.2) AH28(9.2,-9.2) AH30(10,-9.2) AH32(10.8,-9.2) AK1(-10.8,-10) AK3(-10,-10) AK5(-9.2,-10) AK28(9.2,-10) AK30(10,-10) AK32(10.8,-10) AM1(-10.8,-10.8) AM3(-10,-10.8) AM5(-9.2,-10.8) AM28(9.2,-10.8) AM30(10,-10.8) AM32(10.8,-10.8) C1(-10.8,10) C3(-10,10) C5(-9.2,10) C28(9.2,10) C30(10,10) C32(10.8,10) E1(-10.8,9.2) E3(-10,9.2) E5(-9.2,9.2) E28(9.2,9.2) E30(10,9.2) E32(10.8,9.2)
  round 0.356 smd: A7(-7.6,10.8) A9(-6,10.8) A11(-4.4,10.8) A13(-2.8,10.8) A15(-1.2,10.8) A17(0.4,10.8) A19(2,10.8) A21(3.6,10.8) A23(5.2,10.8) A25(6.8,10.8) A27(8.4,10.8) AA1(-10.8,-3.6) AA3(-10,-3.6) AA5(-9.2,-3.6) AA6(-8.4,-3.6) AA11(-4.4,-3.4) AA12(-3.4,-3.4) AA13(-2.4,-3.4) AA15(-1.4,-3.4) AA16(-0.4,-3.4) AA17(0.4,-3.4) AA18(1.4,-3.4) AA20(2.4,-3.4) AA21(3.4,-3.4) AA22(4.4,-3.4) AA27(8.4,-3.6) AA29(9.6,-3.6) AA31(10.4,-3.6) AB2(-10.4,-4.4) AB4(-9.6,-4.4) AB6(-8.4,-4.4) AB7(-7.6,-4.2) AB8(-6.8,-4.2) AB9(-6,-4.2) AB10(-5.2,-4.2) AB11(-4.4,-4.4) AB12(-3.4,-4.4) AB13(-2.4,-4.4) AB15(-1.4,-4.4) AB16(-0.4,-4.4) AB17(0.4,-4.4) AB18(1.4,-4.4) AB20(2.4,-4.4) AB21(3.4,-4.4) AB22(4.4,-4.4) AB23(5.2,-4.2) AB24(6,-4.2) AB25(6.8,-4.2) AB26(7.6,-4.2) AB27(8.4,-4.4) AB28(9.2,-4.4) AB30(10,-4.4) AB32(10.8,-4.4) AC1(-10.8,-5.2) AC3(-10,-5.2) AC5(-9.2,-5.2) AC6(-8.4,-5.2) AC7(-7.6,-5.2) AC8(-6.8,-5.2) AC9(-6,-5.2) AC10(-5.2,-5.2) AC11(-4.2,-5.2) AC13(-3,-5.2) AC14(-1.8,-5.2) AC16(-0.6,-5.2) AC17(0.6,-5.2) AC19(1.8,-5.2) AC20(3,-5.2) AC22(4.2,-5.2) AC23(5.2,-5.2) AC24(6,-5.2) AC25(6.8,-5.2) AC26(7.6,-5.2) AC27(8.4,-5.2) AC29(9.6,-5.2) AC31(10.4,-5.2) AD2(-10.4,-6) AD4(-9.6,-6) AD6(-8.4,-6) AD7(-7.6,-6) AD8(-6.8,-6) AD9(-6,-6) AD10(-5.2,-6) AD11(-4.2,-6) AD13(-3,-6) AD14(-1.8,-6) AD16(-0.6,-6) AD17(0.6,-6) AD19(1.8,-6) AD20(3,-6) AD22(4.2,-6) AD23(5.2,-6) AD24(6,-6) AD25(6.8,-6) AD26(7.6,-6) AD27(8.4,-6) AD28(9.2,-6) AD30(10,-6) AD32(10.8,-6) AE1(-10.8,-6.8) AE3(-10,-6.8) AE5(-9.2,-6.8) AE6(-8.4,-6.8) AE7(-7.6,-6.8) AE8(-6.8,-6.8) AE9(-6,-6.8) AE10(-5.2,-6.8) AE11(-4.2,-6.8) AE13(-3,-6.8) AE14(-1.8,-6.8) AE16(-0.6,-6.8) AE17(0.6,-6.8) AE19(1.8,-6.8) AE20(3,-6.8) AE22(4.2,-6.8) AE23(5.2,-6.8) AE24(6,-6.8) AE25(6.8,-6.8) AE26(7.6,-6.8) AE27(8.4,-6.8) AE29(9.6,-6.8) AE31(10.4,-6.8) AF2(-10.4,-7.6) AF4(-9.6,-7.6) AF6(-8.4,-7.6) AF7(-7.6,-7.6) AF8(-6.8,-7.6) AF9(-6,-7.6) AF10(-5.2,-7.6) AF11(-4.2,-7.6) AF13(-3,-7.6) AF14(-1.8,-7.6) AF16(-0.6,-7.6) AF17(0.6,-7.6) AF19(1.8,-7.6) AF20(3,-7.6) AF22(4.2,-7.6) AF23(5.2,-7.6) AF24(6,-7.6) AF25(6.8,-7.6) AF26(7.6,-7.6) AF27(8.4,-7.6) AF28(9.2,-7.6) AF30(10,-7.6) AF32(10.8,-7.6) AG1(-10.8,-8.4) AG3(-10,-8.4) AG5(-9.2,-8.4) AG6(-8.4,-8.4) AG7(-7.6,-8.4) AG8(-6.8,-8.4) AG9(-6,-8.4) AG10(-5.2,-8.4) AG11(-4.4,-8.4) AG12(-3.6,-8.4) AG13(-2.8,-8.4) AG14(-2,-8.4) AG15(-1.2,-8.4) AG16(-0.4,-8.4) AG17(0.4,-8.4) AG18(1.2,-8.4) AG19(2,-8.4) AG20(2.8,-8.4) AG21(3.6,-8.4) AG22(4.4,-8.4) AG23(5.2,-8.4) AG24(6,-8.4) AG25(6.8,-8.4) AG26(7.6,-8.4) AG27(8.4,-8.4) AG29(9.6,-8.4) AG31(10.4,-8.4) AH6(-8.4,-9.2) AH8(-6.8,-9.2) AH10(-5.2,-9.2) AH12(-3.6,-9.2) AH14(-2,-9.2) AH16(-0.4,-9.2) AH18(1.2,-9.2) AH20(2.8,-9.2) AH22(4.4,-9.2) AH24(6,-9.2) AH26(7.6,-9.2) AJ7(-7.6,-9.6) AJ9(-6,-9.6) AJ11(-4.4,-9.6) AJ13(-2.8,-9.6) AJ15(-1.2,-9.6) AJ17(0.4,-9.6) AJ19(2,-9.6) AJ21(3.6,-9.6) AJ23(5.2,-9.6) AJ25(6.8,-9.6) AJ27(8.4,-9.6) AK6(-8.4,-10) AK8(-6.8,-10) AK10(-5.2,-10) AK12(-3.6,-10) AK14(-2,-10) AK16(-0.4,-10) AK18(1.2,-10) AK20(2.8,-10) AK22(4.4,-10) AK24(6,-10) AK26(7.6,-10) AL7(-7.6,-10.4) AL9(-6,-10.4) AL11(-4.4,-10.4) AL13(-2.8,-10.4) AL15(-1.2,-10.4) AL17(0.4,-10.4) AL19(2,-10.4) AL21(3.6,-10.4) AL23(5.2,-10.4) AL25(6.8,-10.4) AL27(8.4,-10.4) AM6(-8.4,-10.8) AM8(-6.8,-10.8) AM10(-5.2,-10.8) AM12(-3.6,-10.8) AM14(-2,-10.8) AM16(-0.4,-10.8) AM18(1.2,-10.8) AM20(2.8,-10.8) AM22(4.4,-10.8) AM24(6,-10.8) AM26(7.6,-10.8) B6(-8.4,10.4) B8(-6.8,10.4) B10(-5.2,10.4) B12(-3.6,10.4) B14(-2,10.4) B16(-0.4,10.4) B18(1.2,10.4) B20(2.8,10.4) B22(4.4,10.4) B24(6,10.4) B26(7.6,10.4) C7(-7.6,10) C9(-6,10) C11(-4.4,10) C13(-2.8,10) C15(-1.2,10) C17(0.4,10) C19(2,10) C21(3.6,10) C23(5.2,10) C25(6.8,10) C27(8.4,10) D6(-8.4,9.6) D8(-6.8,9.6) D10(-5.2,9.6) D12(-3.6,9.6) D14(-2,9.6) D16(-0.4,9.6) D18(1.2,9.6) D20(2.8,9.6) D22(4.4,9.6) D24(6,9.6) D26(7.6,9.6) E7(-7.6,9.2) E9(-6,9.2) E11(-4.4,9.2) E13(-2.8,9.2) E15(-1.2,9.2) E17(0.4,9.2) E19(2,9.2) E21(3.6,9.2) E23(5.2,9.2) E25(6.8,9.2) E27(8.4,9.2) F2(-10.4,8.4) F4(-9.6,8.4) F6(-8.4,8.4) F7(-7.6,8.4) F8(-6.8,8.4) F9(-6,8.4) F10(-5.2,8.4) F11(-4.4,8.4) F12(-3.6,8.4) F13(-2.8,8.4) F14(-2,8.4) F15(-1.2,8.4) F16(-0.4,8.4) F17(0.4,8.4) F18(1.2,8.4) F19(2,8.4) F20(2.8,8.4) F21(3.6,8.4) F22(4.4,8.4) F23(5.2,8.4) F24(6,8.4) F25(6.8,8.4) F26(7.6,8.4) F27(8.4,8.4) F28(9.2,8.4) F30(10,8.4) F32(10.8,8.4) G1(-10.8,7.6) G3(-10,7.6) G5(-9.2,7.6) G6(-8.4,7.6) G7(-7.6,7.6) G8(-6.8,7.6) G9(-6,7.6) G10(-5.2,7.6) G11(-4.2,7.6) G13(-3,7.6) G14(-1.8,7.6) G16(-0.6,7.6) G17(0.6,7.6) G19(1.8,7.6) G20(3,7.6) G22(4.2,7.6) G23(5.2,7.6) G24(6,7.6) G25(6.8,7.6) G26(7.6,7.6) G27(8.4,7.6) G29(9.6,7.6) G31(10.4,7.6) H2(-10.4,6.8) H4(-9.6,6.8) H6(-8.4,6.8) H7(-7.6,6.8) H8(-6.8,6.8) H9(-6,6.8) H10(-5.2,6.8) H11(-4.2,6.8) H13(-3,6.8) H14(-1.8,6.8) H16(-0.6,6.8) H17(0.6,6.8) H19(1.8,6.8) H20(3,6.8) H22(4.2,6.8) H23(5.2,6.8) H24(6,6.8) H25(6.8,6.8) H26(7.6,6.8) H27(8.4,6.8) H28(9.2,6.8) H30(10,6.8) H32(10.8,6.8) J1(-10.8,6) J3(-10,6) J5(-9.2,6) J6(-8.4,6) J7(-7.6,6) J8(-6.8,6) J9(-6,6) J10(-5.2,6) J11(-4.2,6) J13(-3,6) J14(-1.8,6) J16(-0.6,6) J17(0.6,6) J19(1.8,6) J20(3,6) J22(4.2,6) J23(5.2,6) J24(6,6) J25(6.8,6) J26(7.6,6) J27(8.4,6) J29(9.6,6) J31(10.4,6) K2(-10.4,5.2) K4(-9.6,5.2) K6(-8.4,5.2) K7(-7.6,5.2) K8(-6.8,5.2) K9(-6,5.2) K10(-5.2,5.2) K11(-4.2,5.2) K13(-3,5.2) K14(-1.8,5.2) K16(-0.6,5.2) K17(0.6,5.2) K19(1.8,5.2) K20(3,5.2) K22(4.2,5.2) K23(5.2,5.2) K24(6,5.2) K25(6.8,5.2) K26(7.6,5.2) K27(8.4,5.2) K28(9.2,5.2) K30(10,5.2) K32(10.8,5.2) L1(-10.8,4.4) L3(-10,4.4) L5(-9.2,4.4) L6(-8.4,4.4) L7(-7.6,4.2) L8(-6.8,4.2) L9(-6,4.2) L10(-5.2,4.2) L11(-4.4,4.4) L12(-3.4,4.4) L13(-2.4,4.4) L15(-1.4,4.4) L16(-0.4,4.4) L17(0.4,4.4) L18(1.4,4.4) L20(2.4,4.4) L21(3.4,4.4) L22(4.4,4.4) L23(5.2,4.2) L24(6,4.2) L25(6.8,4.2) L26(7.6,4.2) L27(8.4,4.4) L29(9.6,4.4) L31(10.4,4.4) M2(-10.4,3.6) M4(-9.6,3.6) M6(-8.4,3.6) M11(-4.4,3.4) M12(-3.4,3.4) M13(-2.4,3.4) M15(-1.4,3.4) M16(-0.4,3.4) M17(0.4,3.4) M18(1.4,3.4) M20(2.4,3.4) M21(3.4,3.4) M22(4.4,3.4) M27(8.4,3.6) M28(9.2,3.6) M30(10,3.6) M32(10.8,3.6) N1(-10.8,2.8) N3(-10,2.8) N5(-9.2,2.8) N6(-8.4,2.8) N7(-7.6,3) N8(-6.8,3) N9(-6,3) N10(-5.2,3) N11(-4.4,2.4) N12(-3.4,2.4) N13(-2.4,2.4) N15(-1.4,2.4) N16(-0.4,2.4) N17(0.4,2.4) N18(1.4,2.4) N20(2.4,2.4) N21(3.4,2.4) N22(4.4,2.4) N23(5.2,3) N24(6,3) N25(6.8,3) N26(7.6,3) N27(8.4,2.8) N29(9.6,2.8) N31(10.4,2.8) P2(-10.4,2) P4(-9.6,2) P6(-8.4,2) P7(-7.6,1.8) P8(-6.8,1.8) P9(-6,1.8) P10(-5.2,1.8) P23(5.2,1.8) P24(6,1.8) P25(6.8,1.8) P26(7.6,1.8) P27(8.4,2) P28(9.2,2) P30(10,2) P32(10.8,2) R1(-10.8,1.2) R3(-10,1.2) R5(-9.2,1.2) R6(-8.4,1.2) R11(-4.4,1.4) R12(-3.4,1.4) R13(-2.4,1.4) R15(-1.4,1.4) R16(-0.4,1.4) R17(0.4,1.4) R18(1.4,1.4) R20(2.4,1.4) R21(3.4,1.4) R22(4.4,1.4) R27(8.4,1.2) R29(9.6,1.2) R31(10.4,1.2) T2(-10.4,0.4) T4(-9.6,0.4) T6(-8.4,0.4) T7(-7.6,0.6) T8(-6.8,0.6) T9(-6,0.6) T10(-5.2,0.6) T11(-4.4,0.4) T12(-3.4,0.4) T13(-2.4,0.4) T15(-1.4,0.4) T16(-0.4,0.4) T17(0.4,0.4) T18(1.4,0.4) T20(2.4,0.4) T21(3.4,0.4) T22(4.4,0.4) T23(5.2,0.6) T24(6,0.6) T25(6.8,0.6) T26(7.6,0.6) T27(8.4,0.4) T28(9.2,0.4) T30(10,0.4) T32(10.8,0.4) U1(-10.8,-0.4) U3(-10,-0.4) U5(-9.2,-0.4) U6(-8.4,-0.4) U7(-7.6,-0.6) U8(-6.8,-0.6) U9(-6,-0.6) U10(-5.2,-0.6) U11(-4.4,-0.4) U12(-3.4,-0.4) U13(-2.4,-0.4) U15(-1.4,-0.4) U16(-0.4,-0.4) U17(0.4,-0.4) U18(1.4,-0.4) U20(2.4,-0.4) U21(3.4,-0.4) U22(4.4,-0.4) U23(5.2,-0.6) U24(6,-0.6) U25(6.8,-0.6) U26(7.6,-0.6) U27(8.4,-0.4) U29(9.6,-0.4) U31(10.4,-0.4) V2(-10.4,-1.2) V4(-9.6,-1.2) V6(-8.4,-1.2) V11(-4.4,-1.4) V12(-3.4,-1.4) V13(-2.4,-1.4) V15(-1.4,-1.4) V16(-0.4,-1.4) V17(0.4,-1.4) V18(1.4,-1.4) V20(2.4,-1.4) V21(3.4,-1.4) V22(4.4,-1.4) V27(8.4,-1.2) V28(9.2,-1.2) V30(10,-1.2) V32(10.8,-1.2) W1(-10.8,-2) W3(-10,-2) W5(-9.2,-2) W6(-8.4,-2) W7(-7.6,-1.8) W8(-6.8,-1.8) W9(-6,-1.8) W10(-5.2,-1.8) W23(5.2,-1.8) W24(6,-1.8) W25(6.8,-1.8) W26(7.6,-1.8) W27(8.4,-2) W29(9.6,-2) W31(10.4,-2) Y2(-10.4,-2.8) Y4(-9.6,-2.8) Y6(-8.4,-2.8) Y7(-7.6,-3) Y8(-6.8,-3) Y9(-6,-3) Y10(-5.2,-3) Y11(-4.4,-2.4) Y12(-3.4,-2.4) Y13(-2.4,-2.4) Y15(-1.4,-2.4) Y16(-0.4,-2.4) Y17(0.4,-2.4) Y18(1.4,-2.4) Y20(2.4,-2.4) Y21(3.4,-2.4) Y22(4.4,-2.4) Y23(5.2,-3) Y24(6,-3) Y25(6.8,-3) Y26(7.6,-3) Y27(8.4,-2.8) Y28(9.2,-2.8) Y30(10,-2.8) Y32(10.8,-2.8)
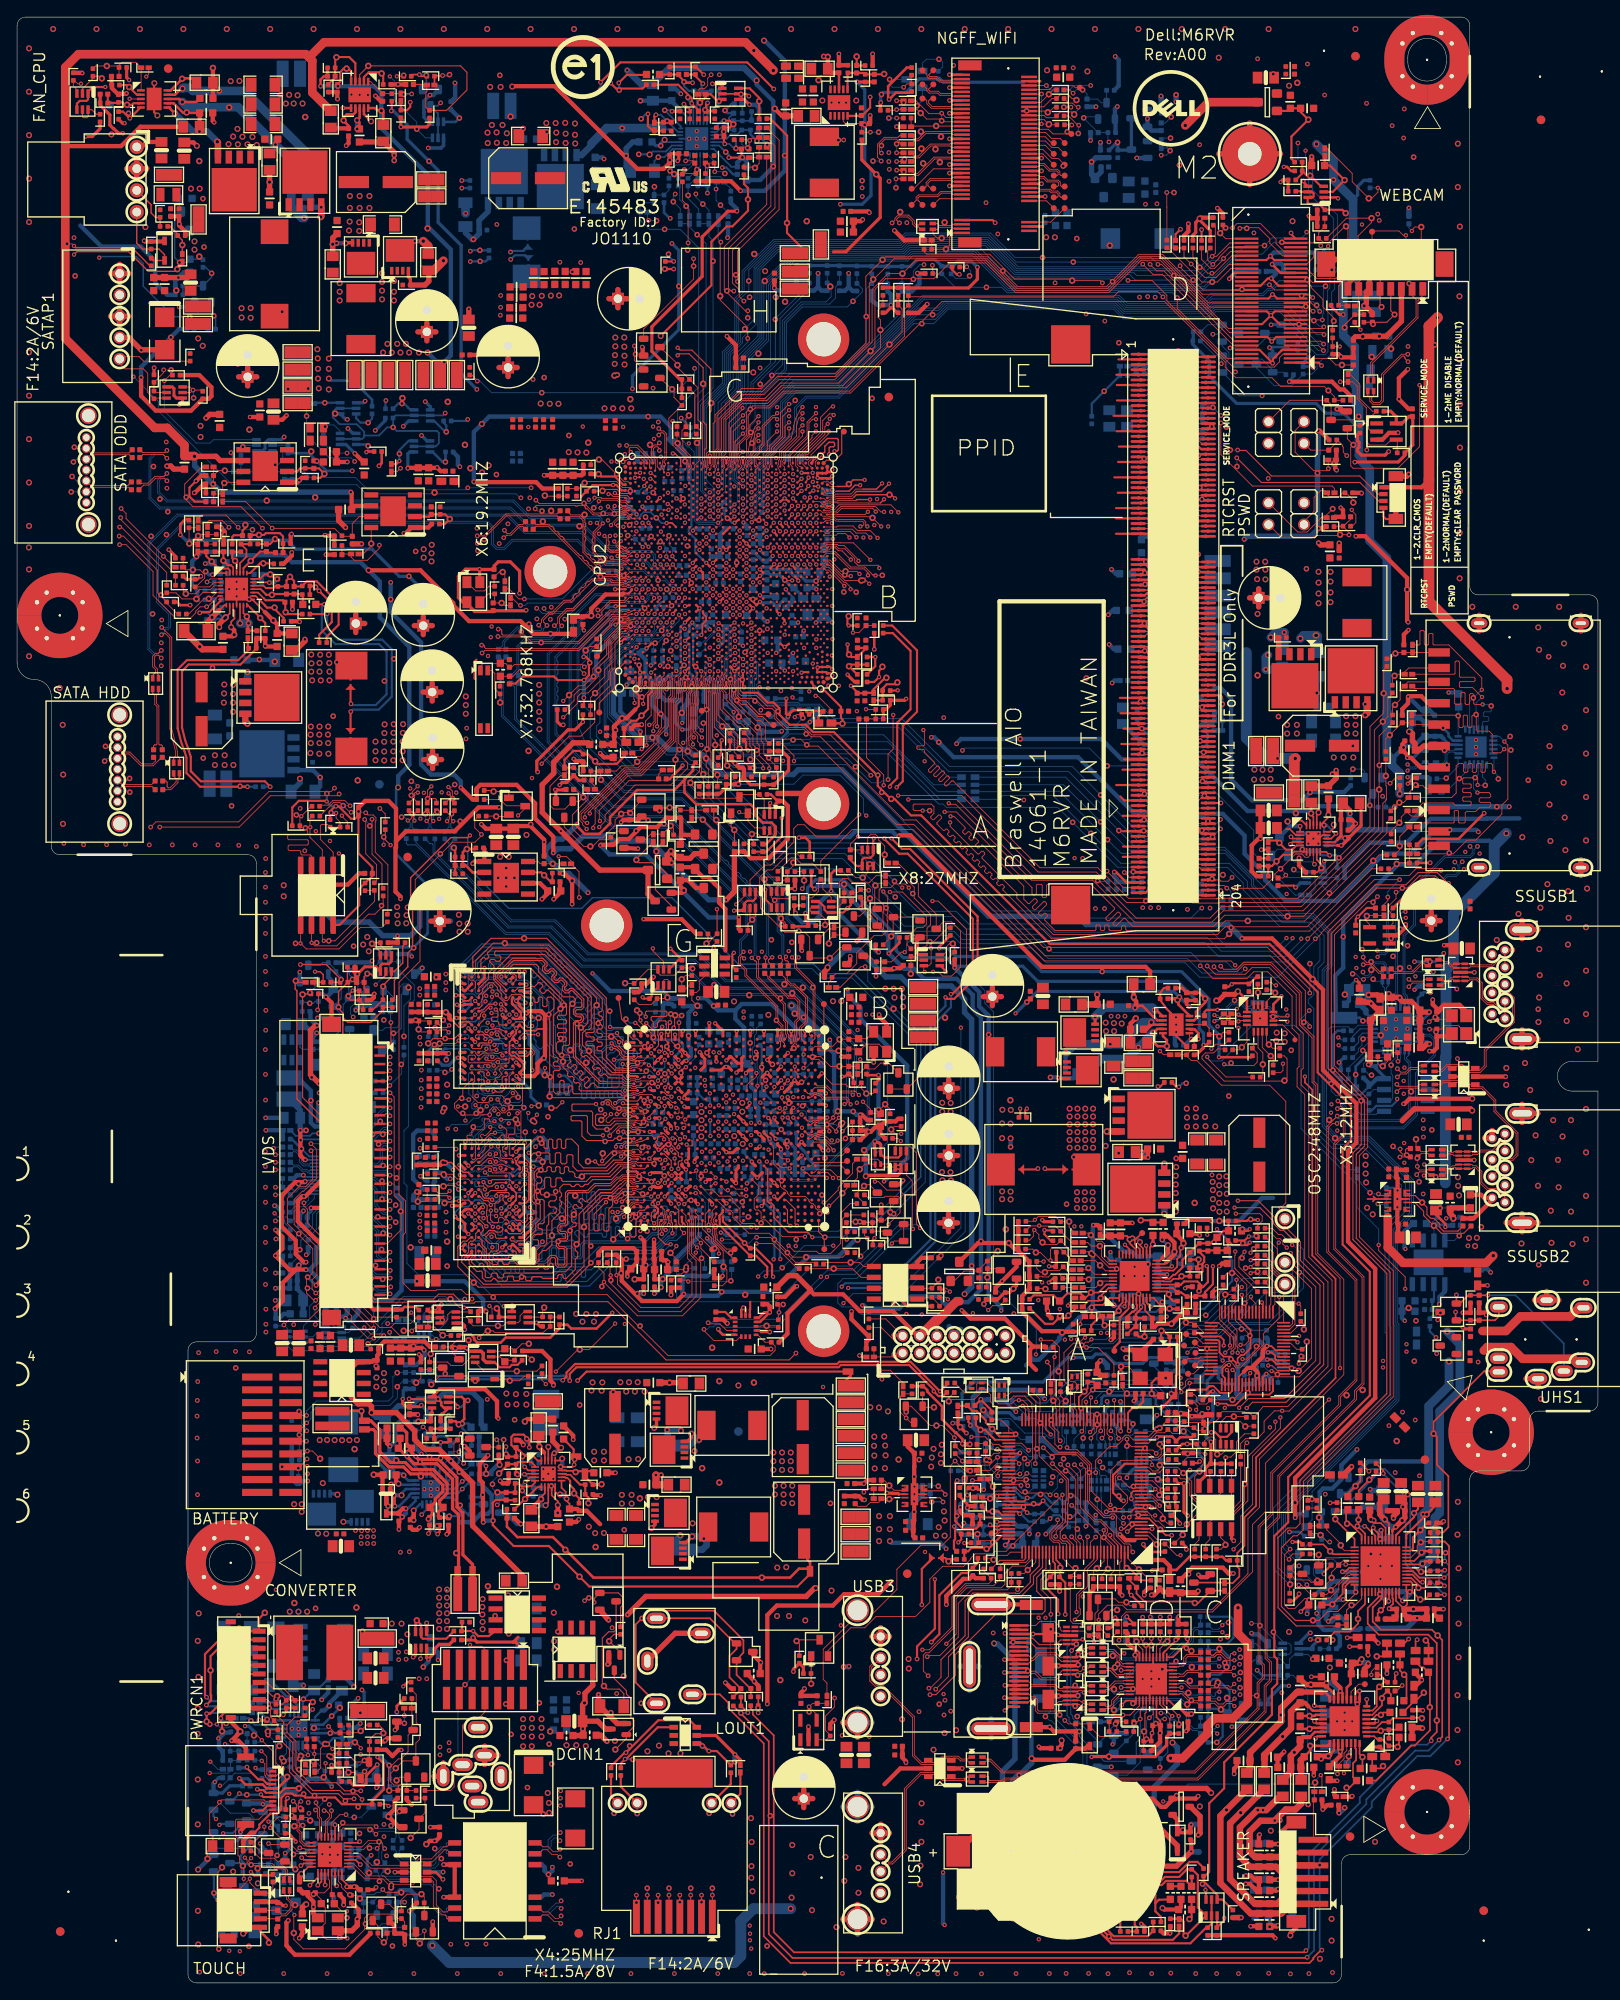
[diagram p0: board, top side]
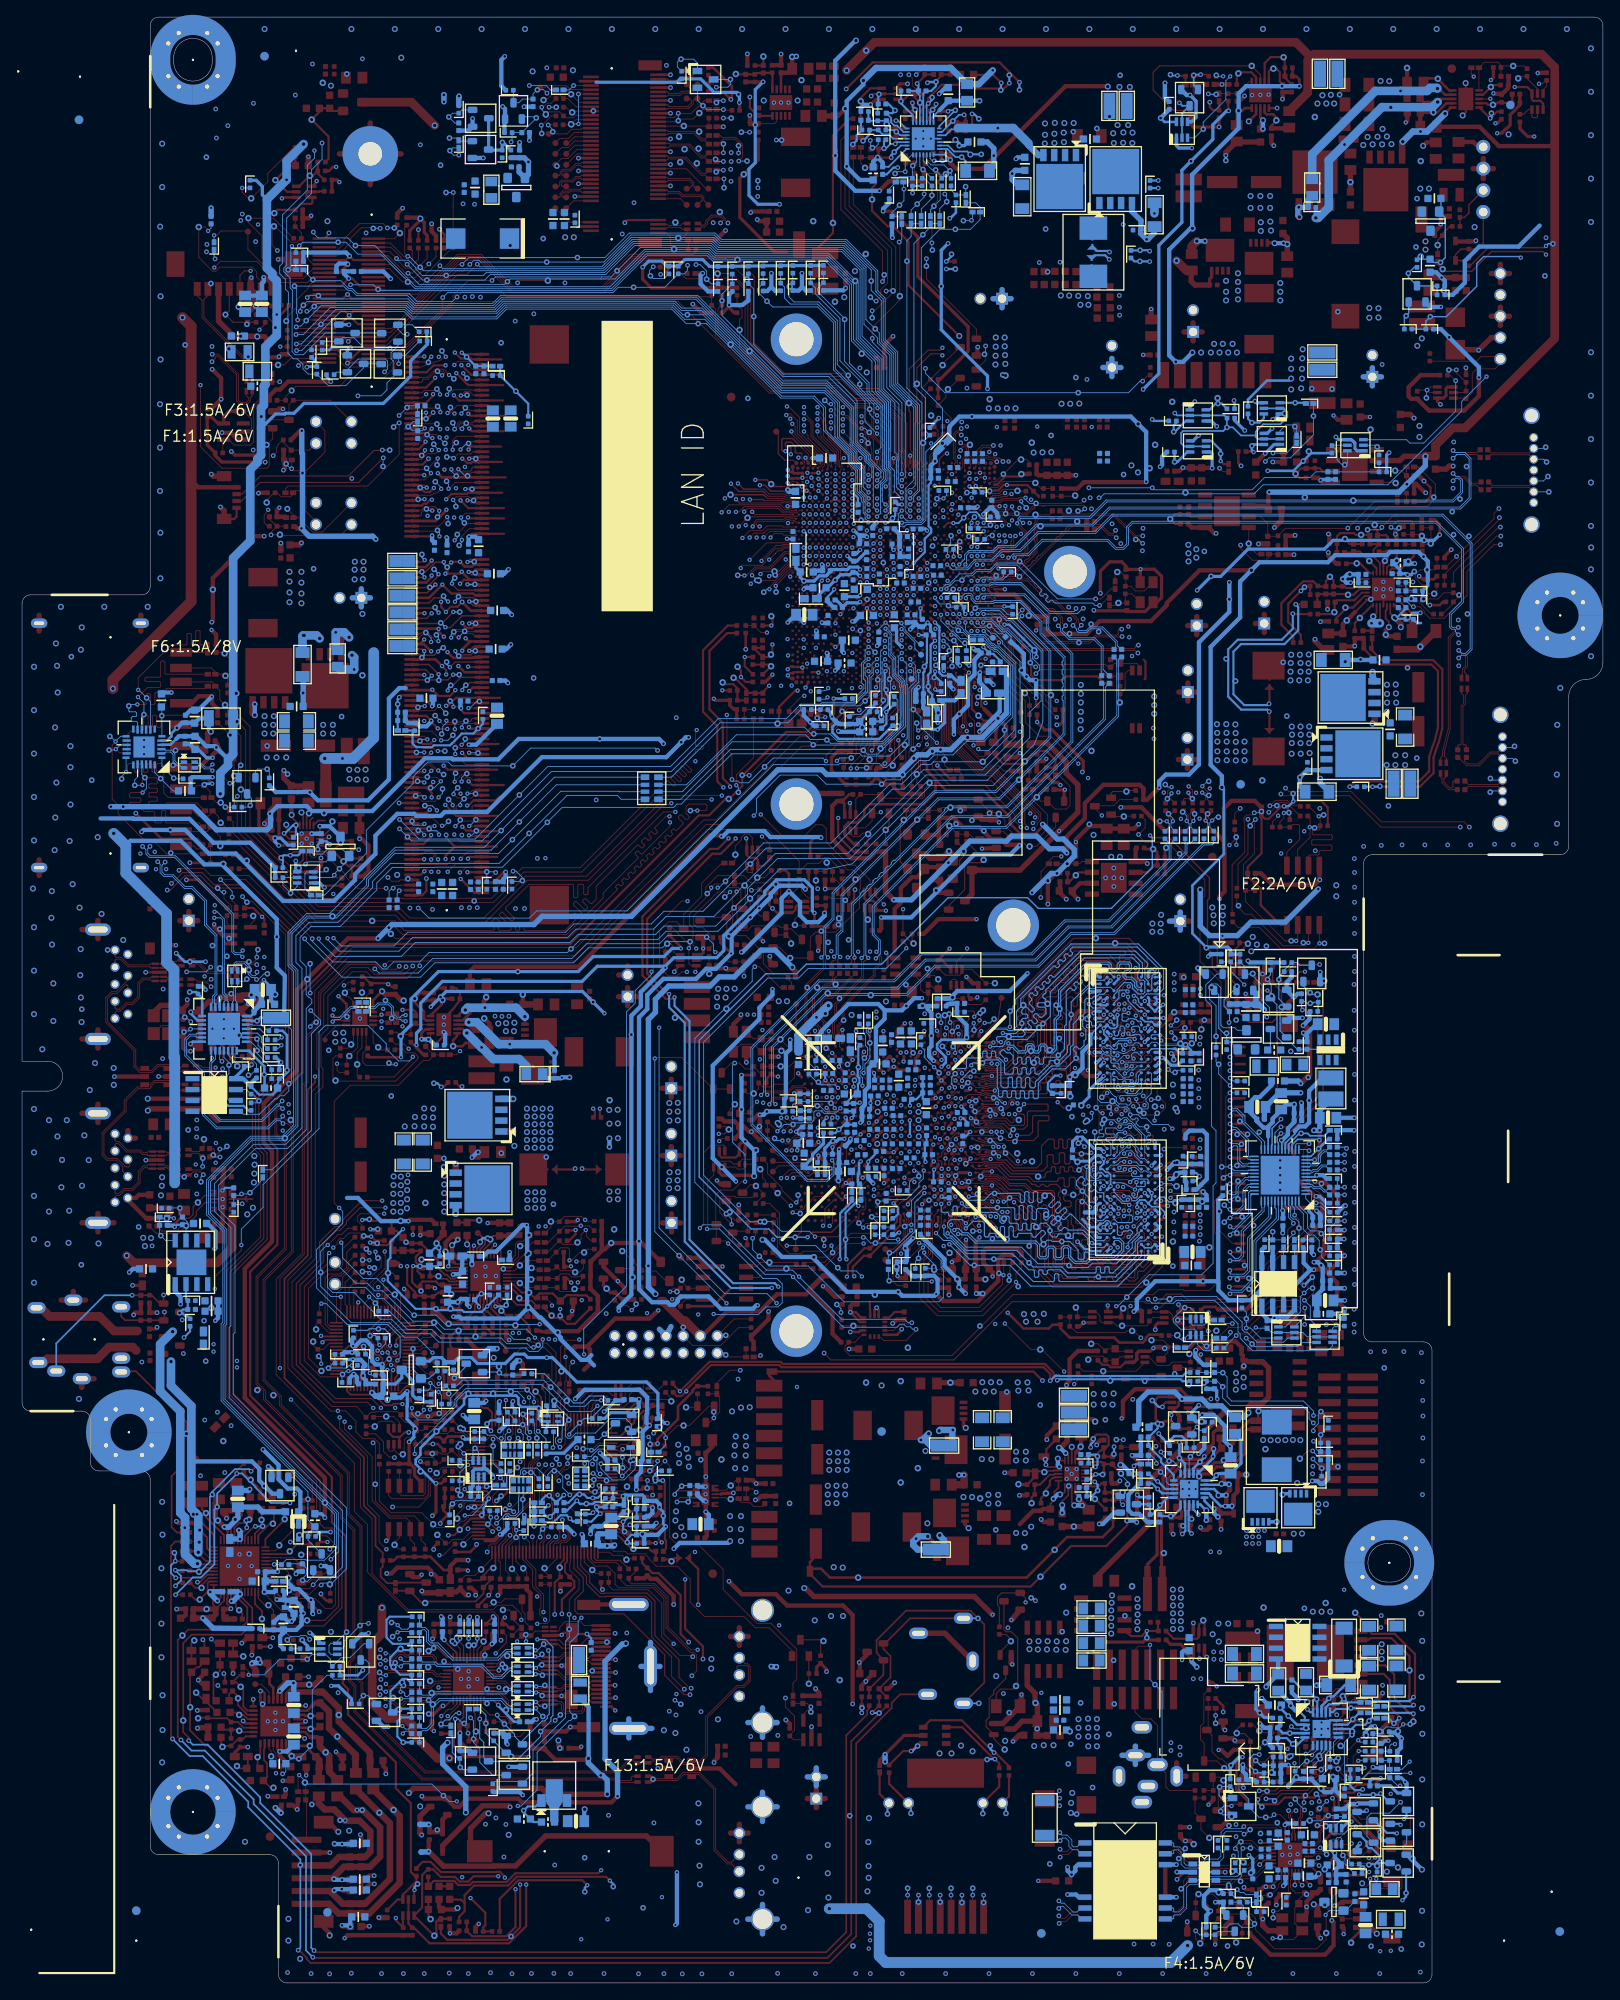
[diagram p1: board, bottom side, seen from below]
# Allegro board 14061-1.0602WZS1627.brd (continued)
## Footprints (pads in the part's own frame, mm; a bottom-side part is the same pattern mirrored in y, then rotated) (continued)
BGA1170M2725H57
  round 0.508 smd: A3(11.951,-11.814) A52(-12.383,-11.814) B2(12.383,-11.383) B53(-12.814,-11.383) BH1(12.814,11.383) BH53(-12.814,11.383) BJ2(12.383,11.814) BJ52(-12.383,11.814) C1(12.814,-10.951)
  round 0.406 smd: A5(11.17,-11.814) A6(10.447,-11.814) A49(-10.992,-11.814) A51(-11.773,-11.814) B52(-12.225,-11.225) BE1(12.814,9.992) BE53(-12.814,9.992) BG1(12.814,10.773) BG53(-12.814,10.773) BH2(12.225,11.225) BH52(-12.225,11.225) BJ3(11.773,11.814) BJ5(10.992,11.814) BJ49(-10.992,11.814) BJ51(-11.773,11.814) C53(-12.814,-10.773) E1(12.814,-10.17) E53(-12.814,-9.992) F1(12.814,-9.447)
  round 0.356 smd: A7(9.748,-11.814) A9(8.836,-11.814) A47(-9.621,-11.814) A48(-10.294,-11.814) B4(11.632,-11.238) B5(11.038,-11.222) B6(10.445,-11.221) B8(9.258,-11.224) B46(-9.258,-11.224) B48(-10.445,-11.221) B49(-11.038,-11.222) B50(-11.632,-11.238) BC1(12.814,8.621) BC2(12.246,8.852) BC52(-12.246,8.852) BC53(-12.814,8.621) BD1(12.814,9.294) BD2(12.221,9.445) BD52(-12.221,9.445) BD53(-12.814,9.294) BE2(12.222,10.038) BE52(-12.222,10.038) BF2(12.238,10.632) BF52(-12.238,10.632) BG3(11.644,10.644) BG51(-11.644,10.644) BH4(11.632,11.238) BH5(11.038,11.222) BH6(10.445,11.221) BH8(9.258,11.224) BH46(-9.258,11.224) BH48(-10.445,11.221) BH49(-11.038,11.222) BH50(-11.632,11.238) BJ6(10.294,11.814) BJ7(9.621,11.814) BJ47(-9.621,11.814) BJ48(-10.294,11.814) C3(11.644,-10.644) C51(-11.644,-10.644) D2(12.238,-10.632) D52(-12.238,-10.632) E2(12.222,-10.038) E52(-12.222,-10.038) F2(12.221,-9.445) F52(-12.221,-9.445) F53(-12.814,-9.294) G1(12.814,-8.679) G2(12.246,-8.852) G52(-12.246,-8.852) G53(-12.814,-8.621) J1(12.814,-7.816)
  oval 0.254x0.343 smd: A11(7.774,-11.814) A13(6.803,-11.814) A15(5.831,-11.814) A17(4.859,-11.814) A19(3.887,-11.814) A21(2.915,-11.814) A23(1.944,-11.814) A25(0.972,-11.814) A27(0,-11.814) A29(-0.972,-11.814) A31(-1.944,-11.814) A33(-2.915,-11.814) A35(-3.887,-11.814) A37(-4.859,-11.814) A39(-5.831,-11.814) A41(-6.803,-11.814) A43(-7.774,-11.814) A45(-8.746,-11.814) BJ9(8.746,11.814) BJ11(7.774,11.814) BJ13(6.803,11.814) BJ15(5.831,11.814) BJ17(4.859,11.814) BJ19(3.887,11.814) BJ21(2.915,11.814) BJ23(1.944,11.814) BJ25(0.972,11.814) BJ27(0,11.814) BJ29(-0.972,11.814) BJ31(-1.944,11.814) BJ33(-2.915,11.814) BJ35(-3.887,11.814) BJ37(-4.859,11.814) BJ39(-5.831,11.814) BJ41(-6.803,11.814) BJ43(-7.774,11.814) BJ45(-8.746,11.814)
  oval 0.343x0.254 smd: AA1(12.814,-1.944) AA53(-12.814,-1.944) AC1(12.814,-0.972) AC53(-12.814,-0.972) AE1(12.814,0) AE53(-12.814,0) AG1(12.814,0.972) AG53(-12.814,0.972) AJ1(12.814,1.944) AJ53(-12.814,1.944) AL1(12.814,2.915) AL53(-12.814,2.915) AN1(12.814,3.887) AN53(-12.814,3.887) AR1(12.814,4.859) AR53(-12.814,4.859) AU1(12.814,5.831) AU53(-12.814,5.831) AW1(12.814,6.803) AW53(-12.814,6.803) BA1(12.814,7.774) BA53(-12.814,7.774) J53(-12.814,-7.774) L1(12.814,-6.803) L53(-12.814,-6.803) N1(12.814,-5.831) N53(-12.814,-5.831) R1(12.814,-4.859) R53(-12.814,-4.859) U1(12.814,-3.887) U53(-12.814,-3.887) W1(12.814,-2.915) W53(-12.814,-2.915)
  round 0.279 smd: AA3(12.071,-1.944) AA51(-12.071,-1.944) AB2(12.429,-1.458) AB3(11.73,-1.458) AB51(-11.73,-1.458) AB52(-12.429,-1.458) AC3(12.071,-0.972) AC51(-12.071,-0.972) AD2(12.429,-0.486) AD3(11.715,-0.48) AD51(-11.715,-0.48) AD52(-12.429,-0.486) AE3(12.071,0) AE4(11.366,0) AE50(-11.366,0) AE51(-12.071,0) AF2(12.429,0.486) AF3(11.715,0.48) AF51(-11.715,0.48) AF52(-12.429,0.486) AG3(12.071,0.972) AG51(-12.071,0.972) AH2(12.429,1.458) AH3(11.73,1.458) AH51(-11.73,1.458) AH52(-12.429,1.458) AJ3(12.071,1.944) AJ51(-12.071,1.944) AK2(12.429,2.43) AK3(11.73,2.43) AK51(-11.73,2.43) AK52(-12.429,2.43) AL3(12.071,2.915) AL51(-12.071,2.915) AM2(12.429,3.401) AM3(11.73,3.401) AM51(-11.73,3.401) AM52(-12.429,3.401) AN3(12.071,3.887) AN51(-12.071,3.887) AP2(12.429,4.373) AP3(11.73,4.373) AP51(-11.73,4.373) AP52(-12.429,4.373) AR3(12.071,4.859) AR51(-12.071,4.859) AT2(12.429,5.345) AT3(11.73,5.345) AT51(-11.73,5.345) AT52(-12.429,5.345) AU3(12.071,5.831) AU51(-12.071,5.831) AV2(12.429,6.317) AV3(11.73,6.317) AV51(-11.73,6.317) AV52(-12.429,6.317) AW3(12.071,6.803) AW51(-12.071,6.803) AY2(12.429,7.289) AY3(11.73,7.289) AY51(-11.73,7.289) AY52(-12.429,7.289) B10(8.26,-11.429) B12(7.289,-11.429) B14(6.317,-11.429) B16(5.345,-11.429) B18(4.373,-11.429) B20(3.401,-11.429) B22(2.43,-11.429) B24(1.458,-11.429) B26(0.486,-11.429) B28(-0.486,-11.429) B30(-1.458,-11.429) B32(-2.43,-11.429) B34(-3.401,-11.429) B36(-4.373,-11.429) B38(-5.345,-11.429) B40(-6.317,-11.429) B42(-7.289,-11.429) B44(-8.26,-11.429) BA3(12.071,7.774) BA51(-12.071,7.774) BB3(11.929,8.351) BB51(-11.929,8.351) BF27(0,10.366) BG9(8.698,11.028) BG11(7.774,11.071) BG12(7.289,10.73) BG13(6.803,11.071) BG14(6.317,10.73) BG15(5.831,11.071) BG16(5.345,10.73) BG17(4.859,11.071) BG18(4.373,10.73) BG19(3.887,11.071) BG20(3.401,10.73) BG21(2.915,11.071) BG22(2.43,10.73) BG23(1.944,11.071) BG24(1.458,10.73) BG25(0.972,11.071) BG26(0.48,10.715) BG27(0,11.071) BG28(-0.48,10.715) BG29(-0.972,11.071) BG30(-1.458,10.73) BG31(-1.944,11.071) BG32(-2.43,10.73) BG33(-2.915,11.071) BG34(-3.401,10.73) BG35(-3.887,11.071) BG36(-4.373,10.73) BG37(-4.859,11.071) BG38(-5.345,10.73) BG39(-5.831,11.071) BG40(-6.317,10.73) BG41(-6.803,11.071) BG42(-7.289,10.73) BG43(-7.774,11.071) BG45(-8.698,11.028) BH10(8.26,11.429) BH12(7.289,11.429) BH14(6.317,11.429) BH16(5.345,11.429) BH18(4.373,11.429) BH20(3.401,11.429) BH22(2.43,11.429) BH24(1.458,11.429) BH26(0.486,11.429) BH28(-0.486,11.429) BH30(-1.458,11.429) BH32(-2.43,11.429) BH34(-3.401,11.429) BH36(-4.373,11.429) BH38(-5.345,11.429) BH40(-6.317,11.429) BH42(-7.289,11.429) BH44(-8.26,11.429) C9(8.698,-11.028) C11(7.774,-11.071) C12(7.289,-10.73) C13(6.803,-11.071) C14(6.317,-10.73) C15(5.831,-11.071) C16(5.345,-10.73) C17(4.859,-11.071) C18(4.373,-10.73) C19(3.887,-11.071) C20(3.401,-10.73) C21(2.915,-11.071) C22(2.43,-10.73) C23(1.944,-11.071) C24(1.458,-10.73) C25(0.972,-11.071) C26(0.48,-10.715) C27(0,-11.071) C28(-0.48,-10.715) C29(-0.972,-11.071) C30(-1.458,-10.73) C31(-1.944,-11.071) C32(-2.43,-10.73) C33(-2.915,-11.071) C34(-3.401,-10.73) C35(-3.887,-11.071) C36(-4.373,-10.73) C37(-4.859,-11.071) C38(-5.345,-10.73) C39(-5.831,-11.071) C40(-6.317,-10.73) C41(-6.803,-11.071) C42(-7.289,-10.73) C43(-7.774,-11.071) C45(-8.698,-11.028) D27(0,-10.366) H3(11.929,-8.351) H51(-11.929,-8.351) J3(12.071,-7.774) J51(-12.071,-7.774) K2(12.429,-7.289) K3(11.73,-7.289) K51(-11.73,-7.289) K52(-12.429,-7.289) L3(12.071,-6.803) L51(-12.071,-6.803) M2(12.429,-6.317) M3(11.73,-6.317) M51(-11.73,-6.317) M52(-12.429,-6.317) N3(12.071,-5.831) N51(-12.071,-5.831) P2(12.429,-5.345) P3(11.73,-5.345) P51(-11.73,-5.345) P52(-12.429,-5.345) R3(12.071,-4.859) R51(-12.071,-4.859) T2(12.429,-4.373) T3(11.73,-4.373) T51(-11.73,-4.373) T52(-12.429,-4.373) U3(12.071,-3.887) U51(-12.071,-3.887) V2(12.429,-3.401) V3(11.73,-3.401) V51(-11.73,-3.401) V52(-12.429,-3.401) W3(12.071,-2.915) W51(-12.071,-2.915) Y2(12.429,-2.43) Y3(11.73,-2.43) Y51(-11.73,-2.43) Y52(-12.429,-2.43)
  round 0.33 smd: AA16(5.307,-1.961) AA18(4.549,-1.961) AA19(3.791,-1.961) AA21(3.033,-1.961) AA22(2.275,-1.961) AA24(1.516,-1.961) AA25(0.758,-1.961) AA27(0,-1.961) AA29(-0.758,-1.961) AA30(-1.516,-1.961) AA32(-2.275,-1.961) AA33(-3.033,-1.961) AA35(-3.791,-1.961) AA36(-4.549,-1.961) AA38(-5.307,-1.961) AC16(5.307,-1.177) AC18(4.549,-1.177) AC19(3.791,-1.177) AC21(3.033,-1.177) AC22(2.275,-1.177) AC24(1.516,-1.177) AC25(0.758,-1.177) AC27(0,-1.177) AC29(-0.758,-1.177) AC30(-1.516,-1.177) AC32(-2.275,-1.177) AC33(-3.033,-1.177) AC35(-3.791,-1.177) AC36(-4.549,-1.177) AC38(-5.307,-1.177) AD16(5.307,-0.392) AD18(4.549,-0.392) AD19(3.791,-0.392) AD21(3.033,-0.392) AD22(2.275,-0.392) AD24(1.516,-0.392) AD25(0.758,-0.392) AD27(0,-0.392) AD29(-0.758,-0.392) AD30(-1.516,-0.392) AD32(-2.275,-0.392) AD33(-3.033,-0.392) AD35(-3.791,-0.392) AD36(-4.549,-0.392) AD38(-5.307,-0.392) AF16(5.307,0.392) AF18(4.549,0.392) AF19(3.791,0.392) AF21(3.033,0.392) AF22(2.275,0.392) AF24(1.516,0.392) AF25(0.758,0.392) AF27(0,0.392) AF29(-0.758,0.392) AF30(-1.516,0.392) AF32(-2.275,0.392) AF33(-3.033,0.392) AF35(-3.791,0.392) AF36(-4.549,0.392) AF38(-5.307,0.392) AG16(5.307,1.177) AG18(4.549,1.177) AG19(3.791,1.177) AG21(3.033,1.177) AG22(2.275,1.177) AG24(1.516,1.177) AG25(0.758,1.177) AG27(0,1.177) AG29(-0.758,1.177) AG30(-1.516,1.177) AG32(-2.275,1.177) AG33(-3.033,1.177) AG35(-3.791,1.177) AG36(-4.549,1.177) AG38(-5.307,1.177) AJ16(5.307,1.961) AJ18(4.549,1.961) AJ19(3.791,1.961) AJ21(3.033,1.961) AJ22(2.275,1.961) AJ24(1.516,1.961) AJ25(0.758,1.961) AJ27(0,1.961) AJ29(-0.758,1.961) AJ30(-1.516,1.961) AJ32(-2.275,1.961) AJ33(-3.033,1.961) AJ35(-3.791,1.961) AJ36(-4.549,1.961) AJ38(-5.307,1.961) AK16(5.307,2.745) AK18(4.549,2.745) AK19(3.791,2.745) AK21(3.033,2.745) AK22(2.275,2.745) AK24(1.516,2.745) AK25(0.758,2.745) AK27(0,2.745) AK29(-0.758,2.745) AK30(-1.516,2.745) AK32(-2.275,2.745) AK33(-3.033,2.745) AK35(-3.791,2.745) AK36(-4.549,2.745) AK38(-5.307,2.745) AM16(5.307,3.53) AM18(4.549,3.53) AM19(3.791,3.53) AM21(3.033,3.53) AM22(2.275,3.53) AM24(1.516,3.53) AM25(0.758,3.53) AM27(0,3.53) AM29(-0.758,3.53) AM30(-1.516,3.53) AM32(-2.275,3.53) AM33(-3.033,3.53) AM35(-3.791,3.53) AM36(-4.549,3.53) AM38(-5.307,3.53) AN16(5.307,4.314) AN18(4.549,4.314) AN19(3.791,4.314) AN21(3.033,4.314) AN22(2.275,4.314) AN24(1.516,4.314) AN25(0.758,4.314) AN27(0,4.314) AN29(-0.758,4.314) AN30(-1.516,4.314) AN32(-2.275,4.314) AN33(-3.033,4.314) AN35(-3.791,4.314) AN36(-4.549,4.314) AN38(-5.307,4.314) U16(5.307,-4.314) U18(4.549,-4.314) U19(3.791,-4.314) U21(3.033,-4.314) U22(2.275,-4.314) U24(1.516,-4.314) U25(0.758,-4.314) U27(0,-4.314) U29(-0.758,-4.314) U30(-1.516,-4.314) U32(-2.275,-4.314) U33(-3.033,-4.314) U35(-3.791,-4.314) U36(-4.549,-4.314) U38(-5.307,-4.314) V16(5.307,-3.53) V18(4.549,-3.53) V19(3.791,-3.53) V21(3.033,-3.53) V22(2.275,-3.53) V24(1.516,-3.53) V25(0.758,-3.53) V27(0,-3.53) V29(-0.758,-3.53) V30(-1.516,-3.53) V32(-2.275,-3.53) V33(-3.033,-3.53) V35(-3.791,-3.53) V36(-4.549,-3.53) V38(-5.307,-3.53) Y16(5.307,-2.745) Y18(4.549,-2.745) Y19(3.791,-2.745) Y21(3.033,-2.745) Y22(2.275,-2.745) Y24(1.516,-2.745) Y25(0.758,-2.745) Y27(0,-2.745) Y29(-0.758,-2.745) Y30(-1.516,-2.745) Y32(-2.275,-2.745) Y33(-3.033,-2.745) Y35(-3.791,-2.745) Y36(-4.549,-2.745) Y38(-5.307,-2.745)
  round 0.305 smd: AB4(11.137,-1.448) AB6(10.463,-1.448) AB7(9.752,-1.448) AB9(9.041,-1.448) AB10(8.33,-1.448) AB12(7.618,-1.448) AB13(6.907,-1.448) AB14(6.196,-1.448) AB40(-6.196,-1.448) AB41(-6.907,-1.448) AB42(-7.618,-1.448) AB44(-8.33,-1.448) AB45(-9.041,-1.448) AB47(-9.752,-1.448) AB48(-10.463,-1.448) AB50(-11.137,-1.448) AD4(10.995,-0.463) AD6(10.404,-0.525) AD7(9.752,-0.475) AD9(9.041,-0.475) AD10(8.33,-0.475) AD12(7.618,-0.475) AD13(6.907,-0.475) AD14(6.196,-0.475) AD40(-6.196,-0.475) AD41(-6.907,-0.475) AD42(-7.618,-0.475) AD44(-8.33,-0.475) AD45(-9.041,-0.475) AD47(-9.752,-0.475) AD48(-10.404,-0.525) AD50(-10.995,-0.463) AE6(10.108,0) AE8(9.396,0) AE9(8.685,0) AE11(7.974,0) AE12(7.263,0) AE14(6.552,0) AE40(-6.552,0) AE42(-7.263,0) AE43(-7.974,0) AE45(-8.685,0) AE46(-9.396,0) AE48(-10.108,0) AF4(10.995,0.463) AF6(10.404,0.525) AF7(9.752,0.475) AF9(9.041,0.475) AF10(8.33,0.475) AF12(7.618,0.475) AF13(6.907,0.475) AF14(6.196,0.475) AF40(-6.196,0.475) AF41(-6.907,0.475) AF42(-7.618,0.475) AF44(-8.33,0.475) AF45(-9.041,0.475) AF47(-9.752,0.475) AF48(-10.404,0.525) AF50(-10.995,0.463) AH4(11.137,1.448) AH6(10.463,1.448) AH7(9.752,1.448) AH9(9.041,1.448) AH10(8.33,1.448) AH12(7.618,1.448) AH13(6.907,1.448) AH14(6.196,1.448) AH40(-6.196,1.448) AH41(-6.907,1.448) AH42(-7.618,1.448) AH44(-8.33,1.448) AH45(-9.041,1.448) AH47(-9.752,1.448) AH48(-10.463,1.448) AH50(-11.137,1.448) AK4(11.137,2.439) AK6(10.463,2.439) AK7(9.752,2.439) AK9(9.041,2.439) AK10(8.33,2.439) AK12(7.618,2.439) AK13(6.907,2.439) AK14(6.196,2.439) AK40(-6.196,2.439) AK41(-6.907,2.439) AK42(-7.618,2.439) AK44(-8.33,2.439) AK45(-9.041,2.439) AK47(-9.752,2.439) AK48(-10.463,2.439) AK50(-11.137,2.439) AM4(11.137,3.386) AM6(10.463,3.412) AM7(9.752,3.412) AM9(9.041,3.412) AM10(8.33,3.412) AM12(7.618,3.412) AM13(6.907,3.412) AM14(6.196,3.412) AM40(-6.196,3.412) AM41(-6.907,3.412) AM42(-7.618,3.412) AM44(-8.33,3.412) AM45(-9.041,3.412) AM47(-9.752,3.412) AM48(-10.463,3.412) AM50(-11.137,3.386) AN5(10.819,3.887) AN6(10.108,3.887) AN8(9.396,3.887) AN9(8.685,3.887) AN11(7.974,3.887) AN12(7.263,3.887) AN14(6.552,3.887) AN40(-6.552,3.887) AN42(-7.263,3.887) AN43(-7.974,3.887) AN45(-8.685,3.887) AN46(-9.396,3.887) AN48(-10.108,3.887) AN49(-10.819,3.887) AP4(11.137,4.388) AP6(10.463,4.362) AP7(9.752,4.362) AP9(9.041,4.362) AP10(8.33,4.362) AP12(7.618,4.362) AP13(6.907,4.362) AP14(6.196,4.362) AP40(-6.196,4.362) AP41(-6.907,4.362) AP42(-7.618,4.362) AP44(-8.33,4.362) AP45(-9.041,4.362) AP47(-9.752,4.362) AP48(-10.463,4.362) AP50(-11.137,4.388) AT4(11.137,5.336) AT6(10.463,5.336) AT7(9.752,5.336) AT9(9.041,5.336) AT10(8.33,5.336) AT12(7.618,5.336) AT13(6.907,5.336) AT14(6.305,5.336) AT16(5.336,5.196) AT18(4.362,5.196) AT19(3.887,5.552) AT20(3.412,5.196) AT22(2.439,5.196) AT24(1.448,5.196) AT26(0.475,5.196) AT27(0,5.552) AT28(-0.475,5.196) AT30(-1.448,5.196) AT32(-2.439,5.196) AT34(-3.412,5.196) AT35(-3.887,5.552) AT36(-4.362,5.196) AT38(-5.336,5.196) AT40(-6.305,5.336) AT41(-6.907,5.336) AT42(-7.618,5.336) AT44(-8.33,5.336) AT45(-9.041,5.336) AT47(-9.752,5.336) AT48(-10.463,5.336) AT50(-11.137,5.336) AU16(5.336,5.907) AU18(4.362,5.907) AU20(3.412,5.907) AU22(2.439,5.907) AU24(1.448,5.907) AU26(0.475,5.907) AU28(-0.475,5.907) AU30(-1.448,5.907) AU32(-2.439,5.907) AU34(-3.412,5.907) AU36(-4.362,5.907) AU38(-5.336,5.907) AV4(11.137,6.326) AV6(10.463,6.326) AV7(9.752,6.326) AV9(9.041,6.326) AV10(8.33,6.326) AV12(7.618,6.326) AV13(6.907,6.326) AV14(6.326,6.446) AV16(5.336,6.618) AV18(4.362,6.618) AV19(3.887,6.263) AV20(3.412,6.618) AV22(2.439,6.618) AV24(1.448,6.618) AV26(0.475,6.618) AV27(0,6.263) AV28(-0.475,6.618) AV30(-1.448,6.618) AV32(-2.439,6.618) AV34(-3.412,6.618) AV35(-3.887,6.263) AV36(-4.362,6.618) AV38(-5.336,6.618) AV40(-6.326,6.446) AV41(-6.907,6.326) AV42(-7.618,6.326) AV44(-8.33,6.326) AV45(-9.041,6.326) AV47(-9.752,6.326) AV48(-10.463,6.326) AV50(-11.137,6.326) AW13(6.751,6.915) AW19(3.887,6.974) AW27(0,6.974) AW35(-3.887,6.974) AW41(-6.751,6.915) AY4(11.137,7.317) AY6(10.463,7.317) AY7(9.752,7.317) AY9(9.041,7.317) AY10(8.33,7.317) AY12(7.317,7.34) AY14(6.326,7.33) AY16(5.336,7.33) AY18(4.362,7.33) AY20(3.412,7.33) AY22(2.439,7.33) AY24(1.448,7.33) AY26(0.475,7.33) AY28(-0.475,7.33) AY30(-1.448,7.33) AY32(-2.439,7.33) AY34(-3.412,7.33) AY36(-4.362,7.33) AY38(-5.336,7.33) AY40(-6.326,7.33) AY42(-7.317,7.34) AY44(-8.33,7.317) AY45(-9.041,7.317) AY47(-9.752,7.317) AY48(-10.463,7.317) AY50(-11.137,7.317) B7(9.852,-11.23) B47(-9.852,-11.23) BA12(7.317,8.041) BA14(6.326,8.041) BA16(5.336,8.041) BA18(4.362,8.041) BA19(3.887,7.685) BA20(3.412,8.041) BA22(2.439,8.041) BA24(1.448,8.041) BA26(0.475,8.041) BA27(0,7.685) BA28(-0.475,8.041) BA30(-1.448,8.041) BA32(-2.439,8.041) BA34(-3.412,8.041) BA35(-3.887,7.685) BA36(-4.362,8.041) BA38(-5.336,8.041) BA40(-6.326,8.041) BA42(-7.317,8.041) BB4(11.258,8.307) BB5(10.547,8.307) BB7(9.835,8.307) BB8(9.124,8.307) BB10(8.307,8.17) BB19(3.887,8.396) BB27(0,8.396) BB35(-3.887,8.396) BB44(-8.307,8.17) BB46(-9.124,8.307) BB47(-9.835,8.307) BB49(-10.547,8.307) BB50(-11.258,8.307) BC10(8.307,8.764) BC12(7.317,8.752) BC14(6.326,8.752) BC16(5.336,8.752) BC18(4.362,8.752) BC20(3.412,8.752) BC22(2.439,8.752) BC24(1.448,8.752) BC26(0.475,8.752) BC28(-0.475,8.752) BC30(-1.448,8.752) BC32(-2.439,8.752) BC34(-3.412,8.752) BC36(-4.362,8.752) BC38(-5.336,8.752) BC40(-6.326,8.752) BC42(-7.317,8.752) BC44(-8.307,8.764) BD5(10.565,9.302) BD7(9.712,9.302) BD10(8.307,9.457) BD12(7.317,9.463) BD14(6.326,9.463) BD16(5.336,9.463) BD18(4.362,9.463) BD19(3.887,9.108) BD20(3.412,9.463) BD22(2.439,9.463) BD24(1.448,9.463) BD26(0.525,9.404) BD27(0,9.108) BD28(-0.525,9.404) BD30(-1.448,9.463) BD32(-2.439,9.463) BD34(-3.412,9.463) BD35(-3.887,9.108) BD36(-4.362,9.463) BD38(-5.336,9.463) BD40(-6.326,9.463) BD42(-7.317,9.463) BD44(-8.307,9.457) BD47(-9.712,9.302) BD49(-10.565,9.302) BE3(11.643,9.58) BE8(9.32,9.747) BE19(3.887,9.819) BE35(-3.887,9.819) BE46(-9.32,9.747) BE51(-11.643,9.58) BF4(11.163,10.163) BF6(10.113,10.238) BF10(8.307,10.168) BF12(7.317,10.137) BF14(6.326,10.137) BF16(5.336,10.137) BF18(4.388,10.137) BF20(3.386,10.137) BF22(2.439,10.137) BF24(1.448,10.137) BF26(0.463,9.995) BF28(-0.463,9.995) BF30(-1.448,10.137) BF32(-2.439,10.137) BF34(-3.386,10.137) BF36(-4.388,10.137) BF38(-5.336,10.137) BF40(-6.326,10.137) BF42(-7.317,10.137) BF44(-8.307,10.168) BF48(-10.113,10.238) BF50(-11.163,10.163) BG5(10.58,10.643) BG7(9.553,10.709) BG47(-9.553,10.709) BG49(-10.58,10.643) BH7(9.852,11.23) BH47(-9.852,11.23) C5(10.58,-10.643) C7(9.553,-10.709) C47(-9.553,-10.709) C49(-10.58,-10.643) D4(11.163,-10.163) D6(10.113,-10.238) D10(8.307,-10.168) D12(7.317,-10.137) D14(6.326,-10.137) D16(5.336,-10.137) D18(4.388,-10.137) D20(3.386,-10.137) D22(2.439,-10.137) D24(1.448,-10.137) D26(0.463,-9.995) D28(-0.463,-9.995) D30(-1.448,-10.137) D32(-2.439,-10.137) D34(-3.386,-10.137) D36(-4.388,-10.137) D38(-5.336,-10.137) D40(-6.326,-10.137) D42(-7.317,-10.137) D44(-8.307,-10.168) D48(-10.113,-10.238) D50(-11.163,-10.163) E3(11.643,-9.58) E8(9.32,-9.747) E19(3.887,-9.819) E35(-3.887,-9.819) E46(-9.32,-9.747) E51(-11.643,-9.58) F5(10.565,-9.302) F7(9.712,-9.302) F10(8.307,-9.457) F12(7.317,-9.463) F14(6.326,-9.463) F16(5.336,-9.463) F18(4.362,-9.463) F19(3.887,-9.108) F20(3.412,-9.463) F22(2.439,-9.463) F24(1.448,-9.463) F26(0.525,-9.404) F27(0,-9.108) F28(-0.525,-9.404) F30(-1.448,-9.463) F32(-2.439,-9.463) F34(-3.412,-9.463) F35(-3.887,-9.108) F36(-4.362,-9.463) F38(-5.336,-9.463) F40(-6.326,-9.463) F42(-7.317,-9.463) F44(-8.307,-9.457) F47(-9.712,-9.302) F49(-10.565,-9.302) G10(8.307,-8.764) G12(7.317,-8.752) G14(6.326,-8.752) G16(5.336,-8.752) G18(4.362,-8.752) G20(3.412,-8.752) G22(2.439,-8.752) G24(1.448,-8.752) G26(0.475,-8.752) G28(-0.475,-8.752) G30(-1.448,-8.752) G32(-2.439,-8.752) G34(-3.412,-8.752) G36(-4.362,-8.752) G38(-5.336,-8.752) G40(-6.326,-8.752) G42(-7.317,-8.752) G44(-8.307,-8.764) H4(11.258,-8.307) H5(10.547,-8.307) H7(9.835,-8.307) H8(9.124,-8.307) H10(8.307,-8.17) H19(3.887,-8.396) H27(0,-8.396) H35(-3.887,-8.396) H44(-8.307,-8.17) H46(-9.124,-8.307) H47(-9.835,-8.307) H49(-10.547,-8.307) H50(-11.258,-8.307) J12(7.317,-8.041) J14(6.326,-8.041) J16(5.336,-8.041) J18(4.362,-8.041) J19(3.887,-7.685) J20(3.412,-8.041) J22(2.439,-8.041) J24(1.448,-8.041) J26(0.475,-8.041) J27(0,-7.685) J28(-0.475,-8.041) J30(-1.448,-8.041) J32(-2.439,-8.041) J34(-3.412,-8.041) J35(-3.887,-7.685) J36(-4.362,-8.041) J38(-5.336,-8.041) J40(-6.326,-8.041) J42(-7.317,-8.041) K4(11.137,-7.317) K6(10.463,-7.317) K7(9.752,-7.317) K9(9.041,-7.317) K10(8.33,-7.317) K12(7.317,-7.34) K14(6.326,-7.33) K16(5.336,-7.33) K18(4.362,-7.33) K20(3.412,-7.33) K22(2.439,-7.33) K24(1.448,-7.33) K26(0.475,-7.33) K28(-0.475,-7.33) K30(-1.448,-7.33) K32(-2.439,-7.33) K34(-3.412,-7.33) K36(-4.362,-7.33) K38(-5.336,-7.33) K40(-6.326,-7.33) K42(-7.317,-7.34) K44(-8.33,-7.317) K45(-9.041,-7.317) K47(-9.752,-7.317) K48(-10.463,-7.317) K50(-11.137,-7.317) L13(6.751,-6.915) L19(3.887,-6.974) L27(0,-6.974) L35(-3.887,-6.974) L41(-6.751,-6.915) M4(11.137,-6.326) M6(10.463,-6.326) M7(9.752,-6.326) M9(9.041,-6.326) M10(8.33,-6.326) M12(7.618,-6.326) M13(6.907,-6.326) M14(6.326,-6.446) M16(5.336,-6.618) M18(4.362,-6.618) M19(3.887,-6.263) M20(3.412,-6.618) M22(2.439,-6.618) M24(1.448,-6.618) M26(0.475,-6.618) M27(0,-6.263) M28(-0.475,-6.618) M30(-1.448,-6.618) M32(-2.439,-6.618) M34(-3.412,-6.618) M35(-3.887,-6.263) M36(-4.362,-6.618) M38(-5.336,-6.618) M40(-6.326,-6.446) M41(-6.907,-6.326) M42(-7.618,-6.326) M44(-8.33,-6.326) M45(-9.041,-6.326) M47(-9.752,-6.326) M48(-10.463,-6.326) M50(-11.137,-6.326) N16(5.336,-5.907) N18(4.362,-5.907) N20(3.412,-5.907) N22(2.439,-5.907) N24(1.448,-5.907) N26(0.475,-5.907) N28(-0.475,-5.907) N30(-1.448,-5.907) N32(-2.439,-5.907) N34(-3.412,-5.907) N36(-4.362,-5.907) N38(-5.336,-5.907) P4(11.137,-5.336) P6(10.463,-5.336) P7(9.752,-5.336) P9(9.041,-5.336) P10(8.33,-5.336) P12(7.618,-5.336) P13(6.907,-5.336) P14(6.305,-5.336) P16(5.336,-5.196) P18(4.362,-5.196) P19(3.887,-5.552) P20(3.412,-5.196) P22(2.439,-5.196) P24(1.448,-5.196) P26(0.475,-5.196) P27(0,-5.552) P28(-0.475,-5.196) P30(-1.448,-5.196) P32(-2.439,-5.196) P34(-3.412,-5.196) P35(-3.887,-5.552) P36(-4.362,-5.196) P38(-5.336,-5.196) P40(-6.305,-5.336) P41(-6.907,-5.336) P42(-7.618,-5.336) P44(-8.33,-5.336) P45(-9.041,-5.336) P47(-9.752,-5.336) P48(-10.463,-5.336) P50(-11.137,-5.336) T4(11.137,-4.388) T6(10.463,-4.362) T7(9.752,-4.362) T9(9.041,-4.362) T10(8.33,-4.362) T12(7.618,-4.362) T13(6.907,-4.362) T14(6.196,-4.362) T40(-6.196,-4.362) T41(-6.907,-4.362) T42(-7.618,-4.362) T44(-8.33,-4.362) T45(-9.041,-4.362) T47(-9.752,-4.362) T48(-10.463,-4.362) T50(-11.137,-4.388) U5(10.819,-3.887) U6(10.108,-3.887) U8(9.396,-3.887) U9(8.685,-3.887) U11(7.974,-3.887) U12(7.263,-3.887) U14(6.552,-3.887) U40(-6.552,-3.887) U42(-7.263,-3.887) U43(-7.974,-3.887) U45(-8.685,-3.887) U46(-9.396,-3.887) U48(-10.108,-3.887) U49(-10.819,-3.887) V4(11.137,-3.386) V6(10.463,-3.412) V7(9.752,-3.412) V9(9.041,-3.412) V10(8.33,-3.412) V12(7.618,-3.412) V13(6.907,-3.412) V14(6.196,-3.412) V40(-6.196,-3.412) V41(-6.907,-3.412) V42(-7.618,-3.412) V44(-8.33,-3.412) V45(-9.041,-3.412) V47(-9.752,-3.412) V48(-10.463,-3.412) V50(-11.137,-3.386) Y4(11.137,-2.439) Y6(10.463,-2.439) Y7(9.752,-2.439) Y9(9.041,-2.439) Y10(8.33,-2.439) Y12(7.618,-2.439) Y13(6.907,-2.439) Y14(6.196,-2.439) Y40(-6.196,-2.439) Y41(-6.907,-2.439) Y42(-7.618,-2.439) Y44(-8.33,-2.439) Y45(-9.041,-2.439) Y47(-9.752,-2.439) Y48(-10.463,-2.439) Y50(-11.137,-2.439)
BSH-03001-FDA
  round 0.254 hole 1.016 unplated: (-10.065,0) (10.065,0)
  rect 0.279x2.769 smd: 1(-7.25,-5.526) 2(-7.25,0.198) 3(-6.75,-5.526) 4(-6.75,0.198) 5(-6.25,-5.526) 6(-6.25,0.198) 7(-5.751,-5.526) 8(-5.751,0.198) 9(-5.25,-5.526) 10(-5.25,0.198) 11(-4.75,-5.526) 12(-4.75,0.198) 13(-4.249,-5.526) 14(-4.249,0.198) 15(-3.75,-5.526) 16(-3.75,0.198) 17(-3.25,-5.526) 18(-3.25,0.198) 19(-2.75,-5.526) 20(-2.75,0.198) 21(-2.25,-5.526) 22(-2.25,0.198) 23(-1.75,-5.526) 24(-1.75,0.198) 25(-1.25,-5.526) 26(-1.25,0.198) 27(-0.751,-5.526) 28(-0.751,0.198) 29(-0.25,-5.526) 30(-0.25,0.198) 31(0.25,-5.526) 32(0.25,0.198) 33(0.751,-5.526) 34(0.751,0.198) 35(1.25,-5.526) 36(1.25,0.198) 37(1.75,-5.526) 38(1.75,0.198) 39(2.25,-5.526) 40(2.25,0.198) 41(2.75,-5.526) 42(2.75,0.198) 43(3.25,-5.526) 44(3.25,0.198) 45(3.75,-5.526) 46(3.75,0.198) 47(4.249,-5.526) 48(4.249,0.198) 49(4.75,-5.526) 50(4.75,0.198) 51(5.25,-5.526) 52(5.25,0.198) 53(5.751,-5.526) 54(5.751,0.198) 55(6.25,-5.526) 56(6.25,0.198) 57(6.75,-5.526) 58(6.75,0.198) 59(7.25,-5.526) 60(7.25,0.198)
C402H20
  custom 0.152x0.152 smd: 1(0,0.445) 2(0,-0.445)
C402H22
  custom 0.152x0.152 smd: 1(0,0.445) 2(0,-0.445)
C603H35
  custom 0.216x0.216 smd: 1(0,0.762) 2(0,-0.762)
C603H36
  custom 0.216x0.216 smd: 1(0,0.762) 2(0,-0.762)
C603H38
  custom 0.216x0.216 smd: 1(0,0.762) 2(0,-0.762)
C603H40
  custom 0.216x0.216 smd: 1(0,0.762) 2(0,-0.762)
C805H50
  rect 1.397x1.143 smd: 1(0,0.965) 2(0,-0.965)
C805H54
  rect 1.397x1.143 smd: 1(0,0.965) 2(0,-0.965)
C805H58
  rect 1.397x1.143 smd: 1(0,0.965) 2(0,-0.965)
C1206H71
  rect 1.651x1.27 smd: 1(0,1.397) 2(0,-1.397)
C1206H75
  rect 1.651x1.27 smd: 1(0,1.397) 2(0,-1.397)
C1808H87
  rect 2.286x1.27 smd: 1(0,2.032) 2(0,-2.032)
CI1410M1HRL-NH
  rect 0.61x1.549 smd: 1(-4.5,3.325) 2(-3.5,3.325) 3(-2.5,3.325) 4(-1.5,3.325) 5(-0.5,3.325) 6(0.5,3.325) 7(1.5,3.325) 8(2.5,3.325) 9(3.5,3.325) 10(4.5,3.325)
  rect 0.61x1.194 smd: 11(-5.6,0) 12(5.6,0)
CI2505P1H00-LF-U
  round 1.422 hole 1.016: 1(-5,0) 2(-2.5,0) 3(0,0) 4(2.5,0) 5(5,0)
CON2C
  custom 0.171x0.171 smd: 1(0,0.533) 2(0,-0.533)
CON2C-U
  custom 0.171x0.171 smd: 1(0,0.533) 2(0,-0.533)
CT3528H79
  rect 2.286x2.286 smd: 1(0,1.905) 2(0,-1.905)
CT7343H75
  rect 2.413x2.286 smd: 1(0,3.15) 2(0,-3.15)
D1608-035030AKH28
  rect 0.559x0.991 smd: A(0,0.691) K(0,-0.691)
D4724AKH44
  rect 2.007x1.549 smd: A(0,2.221) K(0,-2.221)
D5436AKH97
  rect 2.286x2.032 smd: A(0,2.438) K(0,-2.438)
DFN10G3-G265175H32
  rect 0.305x0.914 smd: 1(1,1.549) 2(0.5,1.549) 3(0,1.549) 4(-0.5,1.549) 5(-1,1.549) 6(-1,-1.549) 7(-0.5,-1.549) 8(0,-1.549) 9(0.5,-1.549) 10(1,-1.549)
  rect 2.642x1.753 smd: 11(0,0)
DFN10G2510H26
  rect 0.305x0.787 smd: 1(1,0.494) 5(-1,0.494) 6(-1,-0.494) 10(1,-0.494)
  rect 0.254x0.787 smd: 2(0.521,0.494) 4(-0.521,0.494) 7(-0.521,-0.494) 9(0.521,-0.494)
  rect 0.025x0.025 smd: 3(0,0.494)
  rect 0.406x1.753 smd: 8(0,-0.494)
ECAP-100D6D3H237
  rect 1.397x1.397 hole 0.991: 1(0,-1.27)
  round 1.397 hole 0.991: 2(0,1.27)
ECAP-100D6D3H355
  rect 1.397x1.397 hole 0.991: 1(0,-1.27)
  round 1.397 hole 0.991: 2(0,1.27)
ECAP-100D6D3H375
  rect 1.397x1.397 hole 0.991: 1(0,-1.27)
  round 1.397 hole 0.991: 2(0,1.27)
FUSE-1608H22
  custom 0.216x0.216 smd: 1(0,0.762) 2(0,-0.762)
G6179-1000000-U
  rect 0.635x2.108 smd: 1(1.905,3.47) 2(0.635,3.47) 3(-0.635,3.47) 4(-1.905,3.47) 5(-1.905,-3.47) 6(-0.635,-3.47) 7(0.635,-3.47) 8(1.905,-3.47)
GAP-CLOSE-PWR-3
  rect 0.66x0.762 smd: 1(-0.305,0) 2(0.305,0)
GEN8D5X8R5X4D5-8-F-A
  round 0.254 hole 5.004x4.521 unplated: (0,0)
  round 0.864 hole 0.508: 1(3.136,1.664) 2(1.918,2.882) 3(-1.918,2.882) 4(-3.136,1.664) 5(-3.136,-1.664) 6(-1.918,-2.882) 7(1.918,-2.882) 8(3.136,-1.664)
GEN315R138-8-F-A-1
  round 0.254 hole 3.505 unplated: (0,0)
  round 0.864 hole 0.508: 1(2.667,1.54) 2(1.54,2.667) 3(-1.54,2.667) 4(-2.667,1.54) 5(-2.667,-1.54) 6(-1.54,-2.667) 7(1.54,-2.667) 8(2.667,-1.54)
GEN315R138-8-F-A-2-S
  round 0.254 hole 3.505 unplated: (0,0)
  round 0.864 hole 0.508: 1(2.667,1.54) 2(1.54,2.667) 3(-1.54,2.667) 4(-2.667,1.54) 5(-2.667,-1.54) 6(-1.54,-2.667) 7(1.54,-2.667) 8(2.667,-1.54)
GEN315R178-8-F-A-1
  round 0.254 hole 4.521 unplated: (0,0)
  round 0.864 hole 0.508: 1(2.882,1.664) 2(1.664,2.882) 3(-1.664,2.882) 4(-2.882,1.664) 5(-2.882,-1.664) 6(-1.664,-2.882) 7(1.664,-2.882) 8(2.882,-1.664)
HF1804H
  round 1.651 hole 1.016: 1(-3.81,0) 2(-1.27,0) 3(1.27,0) 4(3.81,0)
HL5507F
  round 0.254 hole 1.016 unplated: (5,0)
  round 1.321 hole 0.914: 1(-6,-1) 2(-6,1) 3(-4,-1) 4(-4,1) 5(-2,-1) 6(-2,1) 7(0,-1) 8(0,1) 9(2,-1) 10(2,1) 11(4,-1) 12(4,1) 13(6,-1) 14(6,1)
HOLE237R158
  round 6.02 hole 4.013: 1(0,0)
JAC331-0140A8B-9H
  oval 1.321x2.235 hole 0.61x1.524: 1(-4.95,2.1) 4(5,2.1) P(3.25,-3.15) Q(-3.9,-2.1)
  oval 2.235x1.422 hole 1.524x0.711: 5(0,3.17)
L402H22
  custom 0.14x0.14 smd: 1(0,0.445) 2(0,-0.445)
L402H24
  custom 0.14x0.14 smd: 1(0,0.445) 2(0,-0.445)
L603H38
  custom 0.216x0.216 smd: 1(0,0.762) 2(0,-0.762)
L3030-2709H41
  rect 2.946x1.778 smd: 1(0,1.235) 2(0,-1.235)
L7066-1830-UH119
  rect 3.505x2.921 smd: 1(0,2.78) 2(0,-2.78)
L8080-6020H158
  rect 6.502x3.15 smd: 1(0,2.944) 2(0,-2.944)
L20125H42
  rect 1.397x1.143 smd: 1(0,0.965) 2(0,-0.965)
L115100-2H158
  rect 3.759x3.251 smd: 1(0,5.022) 2(0,-5.022)
L115100-2030H158
  rect 3.251x2.896 smd: 1(0,4.944) 2(0,-4.944)
L125100-4P-1H28
  rect 0.762x0.432 smd: 1(0.625,0.341) 2(-0.625,0.341) 3(-0.625,-0.341) 4(0.625,-0.341)
L125100-4P-1H36
  rect 0.762x0.432 smd: 1(0.625,0.341) 2(-0.625,0.341) 3(-0.625,-0.341) 4(0.625,-0.341)
L125100-4P-1H37
  rect 0.762x0.432 smd: 1(0.625,0.341) 2(-0.625,0.341) 3(-0.625,-0.341) 4(0.625,-0.341)
L125100-4P-4H28
  rect 0.762x0.432 smd: 1(-0.625,0.341) 2(0.625,0.341) 3(0.625,-0.341) 4(-0.625,-0.341)
L686647H119
  rect 2.159x3.429 smd: 1(-3.111,0) 2(3.111,0)
L736630H119
  rect 3.251x2.743 smd: 1(0,2.819) 2(0,-2.819)
LED1608AKH30
  custom 0.216x0.216 smd: A(0,0.762) K(0,-0.762)
LFQFN28J4-G2D7H40
  rect 0.203x0.559 smd: 1(1.2,1.873) 2(0.8,1.873) 3(0.4,1.873) 4(0,1.873) 5(-0.4,1.873) 6(-0.8,1.873) 7(-1.2,1.873) 15(-1.2,-1.873) 16(-0.8,-1.873) 17(-0.4,-1.873) 18(0,-1.873) 19(0.4,-1.873) 20(0.8,-1.873) 21(1.2,-1.873)
  rect 0.559x0.203 smd: 8(-1.873,1.2) 9(-1.873,0.8) 10(-1.873,0.4) 11(-1.873,0) 12(-1.873,-0.4) 13(-1.873,-0.8) 14(-1.873,-1.2) 22(1.873,-1.2) 23(1.873,-0.8) 24(1.873,-0.4) 25(1.873,0) 26(1.873,0.4) 27(1.873,0.8) 28(1.873,1.2)
  rect 2.692x2.692 smd: 29(0,0)
LGA16G3-1H40
  rect 0.305x0.559 smd: 1(1,1.221) 2(0.5,1.221) 3(0,1.221) 4(-0.5,1.221) 5(-1,1.221) 9(-1,-1.221) 10(-0.5,-1.221) 11(0,-1.221) 12(0.5,-1.221) 13(1,-1.221)
  rect 0.559x0.305 smd: 6(-1.221,0.5) 7(-1.221,0) 8(-1.221,-0.5) 14(1.221,-0.5) 15(1.221,0) 16(1.221,0.5)
LQFP64H63
  rect 0.203x1.524 smd: 1(3,4.242) 2(2.6,4.242) 3(2.2,4.242) 4(1.8,4.242) 5(1.4,4.242) 6(0.999,4.242) 7(0.599,4.242) 8(0.199,4.242) 9(-0.199,4.242) 10(-0.599,4.242) 11(-0.999,4.242) 12(-1.4,4.242) 13(-1.8,4.242) 14(-2.2,4.242) 15(-2.6,4.242) 16(-3,4.242) 33(-3,-4.242) 34(-2.6,-4.242) 35(-2.2,-4.242) 36(-1.8,-4.242) 37(-1.4,-4.242) 38(-0.999,-4.242) 39(-0.599,-4.242) 40(-0.199,-4.242) 41(0.199,-4.242) 42(0.599,-4.242) 43(0.999,-4.242) 44(1.4,-4.242) 45(1.8,-4.242) 46(2.2,-4.242) 47(2.6,-4.242) 48(3,-4.242)
  rect 1.524x0.203 smd: 17(-4.242,3) 18(-4.242,2.6) 19(-4.242,2.2) 20(-4.242,1.8) 21(-4.242,1.4) 22(-4.242,0.999) 23(-4.242,0.599) 24(-4.242,0.199) 25(-4.242,-0.199) 26(-4.242,-0.599) 27(-4.242,-0.999) 28(-4.242,-1.4) 29(-4.242,-1.8) 30(-4.242,-2.2) 31(-4.242,-2.6) 32(-4.242,-3) 49(4.242,-3) 50(4.242,-2.6) 51(4.242,-2.2) 52(4.242,-1.8) 53(4.242,-1.4) 54(4.242,-0.999) 55(4.242,-0.599) 56(4.242,-0.199) 57(4.242,0.199) 58(4.242,0.599) 59(4.242,0.999) 60(4.242,1.4) 61(4.242,1.8) 62(4.242,2.2) 63(4.242,2.6) 64(4.242,3)
LQFP128H63
  rect 0.203x1.524 smd: 1(6.2,7.747) 2(5.8,7.747) 3(5.4,7.747) 4(5,7.747) 5(4.6,7.747) 6(4.2,7.747) 7(3.8,7.747) 8(3.4,7.747) 9(3,7.747) 10(2.6,7.747) 11(2.2,7.747) 12(1.8,7.747) 13(1.4,7.747) 14(0.999,7.747) 15(0.599,7.747) 16(0.199,7.747) 17(-0.199,7.747) 18(-0.599,7.747) 19(-0.999,7.747) 20(-1.4,7.747) 21(-1.8,7.747) 22(-2.2,7.747) 23(-2.6,7.747) 24(-3,7.747) 25(-3.4,7.747) 26(-3.8,7.747) 27(-4.2,7.747) 28(-4.6,7.747) 29(-5,7.747) 30(-5.4,7.747) 31(-5.8,7.747) 32(-6.2,7.747) 65(-6.2,-7.747) 66(-5.8,-7.747) 67(-5.4,-7.747) 68(-5,-7.747) 69(-4.6,-7.747) 70(-4.2,-7.747) 71(-3.8,-7.747) 72(-3.4,-7.747) 73(-3,-7.747) 74(-2.6,-7.747) 75(-2.2,-7.747) 76(-1.8,-7.747) 77(-1.4,-7.747) 78(-0.999,-7.747) 79(-0.599,-7.747) 80(-0.199,-7.747) 81(0.199,-7.747) 82(0.599,-7.747) 83(0.999,-7.747) 84(1.4,-7.747) 85(1.8,-7.747) 86(2.2,-7.747) 87(2.6,-7.747) 88(3,-7.747) 89(3.4,-7.747) 90(3.8,-7.747) 91(4.2,-7.747) 92(4.6,-7.747) 93(5,-7.747) 94(5.4,-7.747) 95(5.8,-7.747) 96(6.2,-7.747)
  rect 1.524x0.203 smd: 33(-7.747,6.2) 34(-7.747,5.8) 35(-7.747,5.4) 36(-7.747,5) 37(-7.747,4.6) 38(-7.747,4.2) 39(-7.747,3.8) 40(-7.747,3.4) 41(-7.747,3) 42(-7.747,2.6) 43(-7.747,2.2) 44(-7.747,1.8) 45(-7.747,1.4) 46(-7.747,0.999) 47(-7.747,0.599) 48(-7.747,0.199) 49(-7.747,-0.199) 50(-7.747,-0.599) 51(-7.747,-0.999) 52(-7.747,-1.4) 53(-7.747,-1.8) 54(-7.747,-2.2) 55(-7.747,-2.6) 56(-7.747,-3) 57(-7.747,-3.4) 58(-7.747,-3.8) 59(-7.747,-4.2) 60(-7.747,-4.6) 61(-7.747,-5) 62(-7.747,-5.4) 63(-7.747,-5.8) 64(-7.747,-6.2) 97(7.747,-6.2) 98(7.747,-5.8) 99(7.747,-5.4) 100(7.747,-5) 101(7.747,-4.6) 102(7.747,-4.2) 103(7.747,-3.8) 104(7.747,-3.4) 105(7.747,-3) 106(7.747,-2.6) 107(7.747,-2.2) 108(7.747,-1.8) 109(7.747,-1.4) 110(7.747,-0.999) 111(7.747,-0.599) 112(7.747,-0.199) 113(7.747,0.199) 114(7.747,0.599) 115(7.747,0.999) 116(7.747,1.4) 117(7.747,1.8) 118(7.747,2.2) 119(7.747,2.6) 120(7.747,3) 121(7.747,3.4) 122(7.747,3.8) 123(7.747,4.2) 124(7.747,4.6) 125(7.747,5) 126(7.747,5.4) 127(7.747,5.8) 128(7.747,6.2)
LVDFH-02004-TP00
  rect 0.305x1.295 smd: 1(-4.75,-1.95) 2(-4.25,-1.95) 3(-3.75,-1.95) 4(-3.25,-1.95) 5(-2.75,-1.95) 6(-2.25,-1.95) 7(-1.75,-1.95) 8(-1.25,-1.95) 9(-0.75,-1.95) 10(-0.25,-1.95) 11(0.25,-1.95) 12(0.75,-1.95) 13(1.25,-1.95) 14(1.75,-1.95) 15(2.25,-1.95) 16(2.75,-1.95) 17(3.25,-1.95) 18(3.75,-1.95) 19(4.25,-1.95) 20(4.75,-1.95)
  rect 1.194x2.692 smd: 21(-7.15,0) 22(7.15,0)
  rect 2.261x1.346 smd: 23(3.9,1.975) 24(0,1.975) 25(-3.9,1.975)
NTC-402H22-U
  custom 0.14x0.14 smd: 1(0,0.445) 2(0,-0.445)
NTC-402H24-U
  custom 0.14x0.14 smd: 1(0,0.445) 2(0,-0.445)
OSC-3225-4P-4H30
  rect 1.397x1.067 smd: 1(-1.171,-0.756) 2(1.171,-0.756) 3(1.171,0.756) 4(-1.171,0.756)
OSC-3225-4P-4H32
  rect 1.397x1.067 smd: 1(-1.171,-0.756) 2(1.171,-0.756) 3(1.171,0.756) 4(-1.171,0.756)
OSC-3225-4P-4H36
  rect 1.397x1.067 smd: 1(-1.171,-0.756) 2(1.171,-0.756) 3(1.171,0.756) 4(-1.171,0.756)
POLYSW-2114H30
  rect 1.6x0.965 smd: 1(0,0.94) 2(0,-0.94)
POLYSW-3217-UH40
  rect 1.905x1.143 smd: 1(0,1.418) 2(0,-1.418)
PPAK-5PH45
  rect 0.762x1.524 smd: 1(-1.905,-3.81) 2(-0.635,-3.81) 3(0.635,-3.81) 4(1.905,-3.81)
  rect 5.283x5.08 smd: 5(0,0)
  rect 0.025x0.025 smd: 6(0.635,2.032) 7(-0.635,2.032) 8(-1.905,2.032)
PPAK-8P-3232H36
  rect 0.406x0.914 smd: 1(-0.975,-2.396) 2(-0.325,-2.396) 3(0.325,-2.396) 4(0.975,-2.396)
  rect 3.353x2.692 smd: 5(0,0)
  rect 0.025x0.025 smd: 6(0.65,0.838) 7(0,0.838) 8(-0.65,0.838)
PPAK-8P-5262H40
  rect 0.762x1.448 smd: 1(-1.905,-3.684) 2(-0.635,-3.684) 3(0.635,-3.684) 4(1.905,-3.684)
  rect 5.512x5.309 smd: 5(0,0)
  rect 0.025x0.025 smd: 6(0.635,2.146) 7(-0.635,2.146) 8(-1.905,2.146)
QFN16-G1D8-UH32
  rect 0.305x0.914 smd: 1(0.75,1.551) 2(0.25,1.551) 3(-0.25,1.551) 4(-0.75,1.551) 9(-0.75,-1.551) 10(-0.25,-1.551) 11(0.25,-1.551) 12(0.75,-1.551)
  rect 0.914x0.305 smd: 5(-1.551,0.75) 6(-1.551,0.25) 7(-1.551,-0.25) 8(-1.551,-0.75) 13(1.551,-0.75) 14(1.551,-0.25) 15(1.551,0.25) 16(1.551,0.75)
  rect 1.778x1.778 smd: 17(0,0)
QFN20-G1D75H32
  rect 0.203x0.914 smd: 1(0.8,1.551) 2(0.4,1.551) 3(0,1.551) 4(-0.4,1.551) 5(-0.8,1.551) 11(-0.8,-1.551) 12(-0.4,-1.551) 13(0,-1.551) 14(0.4,-1.551) 15(0.8,-1.551)
  rect 0.914x0.203 smd: 6(-1.551,0.8) 7(-1.551,0.4) 8(-1.551,0) 9(-1.551,-0.4) 10(-1.551,-0.8) 16(1.551,-0.8) 17(1.551,-0.4) 18(1.551,0) 19(1.551,0.4) 20(1.551,0.8)
  rect 1.753x1.753 smd: 21(0,0)
QFN20-G2D1H32
  rect 0.305x1.092 smd: 1(0.999,1.956) 5(-0.999,1.956) 11(-0.999,-1.956) 15(0.999,-1.956)
  rect 0.305x1.143 smd: 2(0.5,1.93) 3(0,1.93) 4(-0.5,1.93) 12(-0.5,-1.93) 13(0,-1.93) 14(0.5,-1.93)
  rect 1.092x0.305 smd: 6(-1.956,0.999) 10(-1.956,-0.999) 16(1.956,-0.999) 20(1.956,0.999)
  rect 1.143x0.305 smd: 7(-1.93,0.5) 8(-1.93,0) 9(-1.93,-0.5) 17(1.93,-0.5) 18(1.93,0) 19(1.93,0.5)
  rect 2.108x2.108 smd: 21(0,0)
QFN20G3D5-G2D15H40
  rect 0.305x0.914 smd: 1(1,1.801) 5(-1,1.801) 11(-1,-1.801) 15(1,-1.801)
  rect 0.305x0.965 smd: 2(0.5,1.775) 3(0,1.775) 4(-0.5,1.775) 12(-0.5,-1.775) 13(0,-1.775) 14(0.5,-1.775)
  rect 0.914x0.305 smd: 6(-1.801,1) 10(-1.801,-1) 16(1.801,-1) 20(1.801,1)
  rect 0.965x0.305 smd: 7(-1.775,0.5) 8(-1.775,0) 9(-1.775,-0.5) 17(1.775,-0.5) 18(1.775,0) 19(1.775,0.5)
  rect 2.159x2.159 smd: 21(0,0)
QFN24-G2D5H40-U
  rect 0.305x0.838 smd: 1(1.25,2.095) 6(-1.25,2.095) 13(-1.25,-2.095) 18(1.25,-2.095)
  rect 0.305x0.965 smd: 2(0.751,2.032) 3(0.25,2.032) 4(-0.25,2.032) 5(-0.751,2.032) 14(-0.751,-2.032) 15(-0.25,-2.032) 16(0.25,-2.032) 17(0.751,-2.032)
  rect 0.838x0.305 smd: 7(-2.095,1.25) 12(-2.095,-1.25) 19(2.095,-1.25) 24(2.095,1.25)
  rect 0.965x0.305 smd: 8(-2.032,0.751) 9(-2.032,0.25) 10(-2.032,-0.25) 11(-2.032,-0.751) 20(2.032,-0.751) 21(2.032,-0.25) 22(2.032,0.25) 23(2.032,0.751)
  rect 2.489x2.489 smd: 25(0,0)
QFN28-G3D75H32
  rect 0.305x0.914 smd: 1(1.5,2.551) 2(1,2.551) 3(0.5,2.551) 4(0,2.551) 5(-0.5,2.551) 6(-1,2.551) 7(-1.5,2.551) 15(-1.5,-2.551) 16(-1,-2.551) 17(-0.5,-2.551) 18(0,-2.551) 19(0.5,-2.551) 20(1,-2.551) 21(1.5,-2.551)
  rect 0.914x0.305 smd: 8(-2.551,1.5) 9(-2.551,1) 10(-2.551,0.5) 11(-2.551,0) 12(-2.551,-0.5) 13(-2.551,-1) 14(-2.551,-1.5) 22(2.551,-1.5) 23(2.551,-1) 24(2.551,-0.5) 25(2.551,0) 26(2.551,0.5) 27(2.551,1) 28(2.551,1.5)
  rect 3.759x3.759 smd: 29(0,0)
QFN32-G3D55H40
  rect 0.305x0.838 smd: 1(1.75,2.591) 8(-1.75,2.591) 17(-1.75,-2.591) 24(1.75,-2.591)
  rect 0.305x0.94 smd: 2(1.25,2.54) 3(0.751,2.54) 4(0.25,2.54) 5(-0.25,2.54) 6(-0.751,2.54) 7(-1.25,2.54) 18(-1.25,-2.54) 19(-0.751,-2.54) 20(-0.25,-2.54) 21(0.25,-2.54) 22(0.751,-2.54) 23(1.25,-2.54)
  rect 0.838x0.305 smd: 9(-2.591,1.75) 16(-2.591,-1.75) 25(2.591,-1.75) 32(2.591,1.75)
  rect 0.94x0.305 smd: 10(-2.54,1.25) 11(-2.54,0.751) 12(-2.54,0.25) 13(-2.54,-0.25) 14(-2.54,-0.751) 15(-2.54,-1.25) 26(2.54,-1.25) 27(2.54,-0.751) 28(2.54,-0.25) 29(2.54,0.25) 30(2.54,0.751) 31(2.54,1.25)
  rect 3.531x3.531 smd: 33(0,0)
QFN32J4-G2D85H36
  rect 0.203x0.864 smd: 1(1.4,2.085) 2(1,2.085) 3(0.6,2.085) 4(0.2,2.085) 5(-0.2,2.085) 6(-0.6,2.085) 7(-1,2.085) 8(-1.4,2.085) 17(-1.4,-2.085) 18(-1,-2.085) 19(-0.6,-2.085) 20(-0.2,-2.085) 21(0.2,-2.085) 22(0.6,-2.085) 23(1,-2.085) 24(1.4,-2.085)
  rect 0.864x0.203 smd: 9(-2.085,1.4) 10(-2.085,1) 11(-2.085,0.6) 12(-2.085,0.2) 13(-2.085,-0.2) 14(-2.085,-0.6) 15(-2.085,-1) 16(-2.085,-1.4) 25(2.085,-1.4) 26(2.085,-1) 27(2.085,-0.6) 28(2.085,-0.2) 29(2.085,0.2) 30(2.085,0.6) 31(2.085,1) 32(2.085,1.4)
  rect 2.845x2.845 smd: 33(0,0)
QFN40-G3D5H32
  rect 0.203x0.914 smd: 1(1.8,2.553) 10(-1.8,2.553) 21(-1.8,-2.553) 30(1.8,-2.553)
  rect 0.203x0.965 smd: 2(1.4,2.527) 3(1,2.527) 4(0.6,2.527) 5(0.2,2.527) 6(-0.2,2.527) 7(-0.6,2.527) 8(-1,2.527) 9(-1.4,2.527) 22(-1.4,-2.527) 23(-1,-2.527) 24(-0.6,-2.527) 25(-0.2,-2.527) 26(0.2,-2.527) 27(0.6,-2.527) 28(1,-2.527) 29(1.4,-2.527)
  rect 0.914x0.203 smd: 11(-2.553,1.8) 20(-2.553,-1.8) 31(2.553,-1.8) 40(2.553,1.8)
  rect 0.965x0.203 smd: 12(-2.527,1.4) 13(-2.527,1) 14(-2.527,0.6) 15(-2.527,0.2) 16(-2.527,-0.2) 17(-2.527,-0.6) 18(-2.527,-1) 19(-2.527,-1.4) 32(2.527,-1.4) 33(2.527,-1) 34(2.527,-0.6) 35(2.527,-0.2) 36(2.527,0.2) 37(2.527,0.6) 38(2.527,1) 39(2.527,1.4)
  rect 3.505x3.505 smd: 41(0,0)
QFN40J5-G3D65H32
  rect 0.203x0.94 smd: 1(1.8,2.538) 10(-1.8,2.538) 21(-1.8,-2.538) 30(1.8,-2.538)
  rect 0.203x0.965 smd: 2(1.4,2.526) 3(1,2.526) 4(0.6,2.526) 5(0.2,2.526) 6(-0.2,2.526) 7(-0.6,2.526) 8(-1,2.526) 9(-1.4,2.526) 22(-1.4,-2.526) 23(-1,-2.526) 24(-0.6,-2.526) 25(-0.2,-2.526) 26(0.2,-2.526) 27(0.6,-2.526) 28(1,-2.526) 29(1.4,-2.526)
  rect 0.94x0.203 smd: 11(-2.538,1.8) 20(-2.538,-1.8) 31(2.538,-1.8) 40(2.538,1.8)
  rect 0.965x0.203 smd: 12(-2.526,1.4) 13(-2.526,1) 14(-2.526,0.6) 15(-2.526,0.2) 16(-2.526,-0.2) 17(-2.526,-0.6) 18(-2.526,-1) 19(-2.526,-1.4) 32(2.526,-1.4) 33(2.526,-1) 34(2.526,-0.6) 35(2.526,-0.2) 36(2.526,0.2) 37(2.526,0.6) 38(2.526,1) 39(2.526,1.4)
  rect 3.658x3.658 smd: 41(0,0)
QFN48J6-G4D55H40
  rect 0.203x1.016 smd: 1(2.2,3) 2(1.8,3) 3(1.4,3) 4(1,3) 5(0.6,3) 6(0.2,3) 7(-0.2,3) 8(-0.6,3) 9(-1,3) 10(-1.4,3) 11(-1.8,3) 12(-2.2,3) 25(-2.2,-3) 26(-1.8,-3) 27(-1.4,-3) 28(-1,-3) 29(-0.6,-3) 30(-0.2,-3) 31(0.2,-3) 32(0.6,-3) 33(1,-3) 34(1.4,-3) 35(1.8,-3) 36(2.2,-3)
  rect 1.016x0.203 smd: 13(-3,2.2) 14(-3,1.8) 15(-3,1.4) 16(-3,1) 17(-3,0.6) 18(-3,0.2) 19(-3,-0.2) 20(-3,-0.6) 21(-3,-1) 22(-3,-1.4) 23(-3,-1.8) 24(-3,-2.2) 37(3,-2.2) 38(3,-1.8) 39(3,-1.4) 40(3,-1) 41(3,-0.6) 42(3,-0.2) 43(3,0.2) 44(3,0.6) 45(3,1) 46(3,1.4) 47(3,1.8) 48(3,2.2)
  rect 4.547x4.547 smd: 49(0,0)
QFN48J6-G465H40
  rect 0.203x0.965 smd: 1(2.2,3.025) 2(1.8,3.025) 3(1.4,3.025) 4(1,3.025) 5(0.6,3.025) 6(0.2,3.025) 7(-0.2,3.025) 8(-0.6,3.025) 9(-1,3.025) 10(-1.4,3.025) 11(-1.8,3.025) 12(-2.2,3.025) 25(-2.2,-3.025) 26(-1.8,-3.025) 27(-1.4,-3.025) 28(-1,-3.025) 29(-0.6,-3.025) 30(-0.2,-3.025) 31(0.2,-3.025) 32(0.6,-3.025) 33(1,-3.025) 34(1.4,-3.025) 35(1.8,-3.025) 36(2.2,-3.025)
  rect 0.965x0.203 smd: 13(-3.025,2.2) 14(-3.025,1.8) 15(-3.025,1.4) 16(-3.025,1) 17(-3.025,0.6) 18(-3.025,0.2) 19(-3.025,-0.2) 20(-3.025,-0.6) 21(-3.025,-1) 22(-3.025,-1.4) 23(-3.025,-1.8) 24(-3.025,-2.2) 37(3.025,-2.2) 38(3.025,-1.8) 39(3.025,-1.4) 40(3.025,-1) 41(3.025,-0.6) 42(3.025,-0.2) 43(3.025,0.2) 44(3.025,0.6) 45(3.025,1) 46(3.025,1.4) 47(3.025,1.8) 48(3.025,2.2)
  rect 4.648x4.648 smd: 49(0,0)
R402H14
  custom 0.14x0.14 smd: 1(0,0.445) 2(0,-0.445)
R402H15
  custom 0.14x0.14 smd: 1(0,0.445) 2(0,-0.445)
R402H16
  custom 0.14x0.14 smd: 1(0,0.445) 2(0,-0.445)
R603H22
  custom 0.216x0.216 smd: 1(0,0.762) 2(0,-0.762)
R805H24
  rect 1.397x1.143 smd: 1(0,0.965) 2(0,-0.965)
R1206H26
  rect 1.651x1.27 smd: 1(0,1.397) 2(0,-1.397)
R1206H28
  rect 1.651x1.27 smd: 1(0,1.397) 2(0,-1.397)
R3720H40
  rect 4.013x1.041 smd: 1(0,0.867) 2(0,-0.867)
SC70-6H44
  rect 0.406x1.016 smd: 1(-0.65,-0.94) 2(0,-0.94) 3(0.65,-0.94) 4(0.65,0.94) 5(0,0.94) 6(-0.65,0.94)
SE331721H237
  rect 1.422x3.556 smd: 1(0,2.574) 2(0,-2.574)
SE361414H241
  rect 1.372x3.607 smd: 1(0,2.499) 2(0,-2.499)
SE361416H237
  rect 1.422x3.556 smd: 1(0,2.574) 2(0,-2.574)
SKT-HDMI22-150077
  rect 0.305x2.007 smd: 1(4.21,3.37) 2(3.71,3.37) 3(3.21,3.37) 4(2.71,3.37) 5(2.21,3.37) 6(1.71,3.37) 7(1.21,3.37) 8(0.71,3.37) 9(0.21,3.37) 10(-0.29,3.37) 11(-0.79,3.37) 12(-1.29,3.37) 13(-1.79,3.37) 14(-2.29,3.37) 15(-2.79,3.37) 16(-3.29,3.37) 17(-3.79,3.37) 18(-4.29,3.37) 19(-4.79,3.37)
  oval 4.928x1.524 hole 4.216x0.813: 20(0,-2.53)
  oval 1.524x4.674 hole 0.813x3.962: 21(-7.25,0) 22(7.25,0)
SKT-USB6-135063
  round 1.346 hole 0.94: 1(3.5,-2.71) 2(1,-2.71) 3(-1,-2.71) 4(-3.5,-2.71)
  round 2.718 hole 2.311: 5(6.57,0) 6(-6.57,0)
SKT-USB11-138165-1
  round 1.067 hole 0.711: 1(3.5,3.5) 2(1,3.5) 3(-1,3.5) 4(-3.5,3.5) 5(-4,2) 6(-2,2) 7(0,2) 8(2,2) 9(4,2)
  oval 1.422x3.023 hole 0.711x2.311: 10(-6.4,0) 11(6.4,0)
SMD49-6914-0403H56
  rect 1.168x0.559 smd: 1(-3.38,-0.427) 2(3.38,-0.427) 3(3.38,0.427) 4(-3.38,0.427)
SMD-ARES8-1H28
  rect 0.686x1.016 smd: 1(-1.295,-0.787) 4(1.295,-0.787) 5(1.295,0.787) 8(-1.295,0.787)
  rect 0.508x1.016 smd: 2(-0.406,-0.787) 3(0.406,-0.787) 6(0.406,0.787) 7(-0.406,0.787)
SMD-OSC6H30
  rect 1.524x1.422 smd: 1(-1.048,-0.847) 2(1.048,-0.847) 3(1.048,0.847) 4(-1.048,0.847)
SMD-OSC8H52
  rect 1.803x1.6 smd: 1(-1.469,-1.4) 2(1.469,-1.4) 3(1.469,1.4) 4(-1.469,1.4)
SOD323AKH38
  rect 0.559x1.016 smd: A(0,1.143) K(0,-1.143)
SOD323AKH40
  rect 0.559x1.016 smd: A(0,1.143) K(0,-1.143)
SOD323AKH42
  rect 0.559x1.016 smd: A(0,1.143) K(0,-1.143)
SOD523AKH28
  rect 0.559x1.016 smd: A(0,0.762) K(0,-0.762)
SOIC8-1H86
  rect 0.635x1.651 smd: 1(-1.905,-3.493) 2(-0.635,-3.493) 3(0.635,-3.493) 4(1.905,-3.493) 5(1.905,3.493) 6(0.635,3.493) 7(-0.635,3.493) 8(-1.905,3.493)
SOIC8-G3530H63
  rect 0.635x1.651 smd: 1(-1.905,-2.555) 2(-0.635,-2.555) 3(0.635,-2.555) 4(1.905,-2.555) 5(1.905,2.555) 6(0.635,2.555) 7(-0.635,2.555) 8(-1.905,2.555)
  rect 3.505x2.997 smd: 9(0,0)
SOIC8H69
  rect 0.635x1.651 smd: 1(-1.905,-2.54) 2(-0.635,-2.54) 3(0.635,-2.54) 4(1.905,-2.54) 5(1.905,2.54) 6(0.635,2.54) 7(-0.635,2.54) 8(-1.905,2.54)
SON14J3020-G2610H34
  rect 0.025x0.025 smd: 1(1.2,1.105) 6(-0.8,1.105) 9(-0.8,-1.105) 14(1.2,-1.105)
  custom 0.151x0.151 smd: 2(0.8,1.105) 7(-1.2,1.105) 8(-1.2,-1.105) 13(0.8,-1.105)
  rect 0.203x0.813 smd: 3(0.4,1.105) 4(0,1.105) 5(-0.4,1.105) 10(-0.4,-1.105) 11(0,-1.105) 12(0.4,-1.105)
  rect 2.591x0.889 smd: 15(0,0)
SOT23-2D4-312H44
  custom 0.191x0.191 smd: 1(-0.984,-0.953) 2(0.984,-0.953) 3(0,0.953)
SOT23-2D4-312H46
  custom 0.191x0.191 smd: 1(-0.984,-0.953) 2(0.984,-0.953) 3(0,0.953)
SOT23-2D4-312H48
  custom 0.191x0.191 smd: 1(-0.984,-0.953) 2(0.984,-0.953) 3(0,0.953)
SOT23CBE2D4H44
  custom 0.191x0.191 smd: B(-0.984,-0.953) C(0,0.953) E(0.984,-0.953)
SOT23DGS2D4H44
  custom 0.191x0.191 smd: D(0,0.953) G(-0.984,-0.953) S(0.984,-0.953)
SOT23DGS2D4H48
  custom 0.191x0.191 smd: D(0,0.953) G(-0.984,-0.953) S(0.984,-0.953)
SOT23DGS2D8H50
  custom 0.254x0.254 smd: D(0,1.118) G(-1.016,-1.118) S(1.016,-1.118)
SOT323CBE2D2H44
  custom 0.152x0.152 smd: B(-0.65,-0.902) C(0,0.902) E(0.65,-0.902)
SOT-6-1H50
  rect 0.584x1.219 smd: 1(-0.95,-1.194) 2(0,-1.194) 3(0.95,-1.194) 4(0.95,1.194) 5(0,1.194) 6(-0.95,1.194)
SOT-6H44
  rect 0.584x1.016 smd: 1(-0.953,-1.346) 2(0,-1.346) 3(0.953,-1.346) 4(0.953,1.346) 5(0,1.346) 6(-0.953,1.346)
SOT-6H58
  rect 0.584x1.016 smd: 1(-0.953,-1.346) 2(0,-1.346) 3(0.953,-1.346) 4(0.953,1.346) 5(0,1.346) 6(-0.953,1.346)
SOT-23-5H58
  rect 0.508x1.524 smd: 1(-0.95,-1.143) 2(0,-1.143) 3(0.95,-1.143) 4(0.95,1.143) 5(-0.95,1.143)
SOT-23-9H44
  custom 0.178x0.178 smd: 1(-0.95,-0.999) 2(0.95,-0.999) 3(0,0.999)
SOT-23-10H44
  rect 0.762x1.143 smd: 1(-0.984,-0.953) 2(0.984,-0.953) 3(0,0.953)
SOT-89-4541-3PH63
  rect 0.991x1.499 smd: 1(-1.5,0) 3(1.5,0)
  custom 0.502x0.502 smd: 2(0,0)
SOT-363H44
  rect 0.406x1.016 smd: 1(-0.65,-0.94) 2(0,-0.94) 3(0.65,-0.94) 4(0.65,0.94) 5(0,0.94) 6(-0.65,0.94)
STF256R109H99
  round 6.502 hole 2.769: 1(0,0)
TPAD24
  round 0.61 smd: 1(0,0)
TPAD28
  round 0.711 smd: 1(0,0)
TVS5436-1121H105
  rect 2.337x2.007 smd: 1(0,2.299) 2(0,-2.299)
unnamed
  round 0.254 hole 2.184 unplated: (0,0)
XFORM12A127097H91
  rect 0.635x1.524 smd: 1(-4.445,-4.699) 2(-3.175,-4.699) 3(-1.905,-4.699) 4(1.905,-4.699) 5(3.175,-4.699) 6(4.445,-4.699) 7(4.445,4.699) 8(3.175,4.699) 9(1.905,4.699) 10(-1.905,4.699) 11(-3.175,4.699) 12(-4.445,4.699)

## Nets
3V_VA: C483.1 C485.2 C493.1 C495.1 L21.2 U6.23 U6.25
19V_AMP_AVCC: C208.1 R376.2 U21.12
19V_AMP_PVCC: C543.1 C545.1 C551.2 C552.1 L10.2 R376.1 U21.13 U21.14 U21.27 U21.28
+1.5V_GPU_PG: PC151.1 PR225.2 PU7.7
+3VL: PG4904.2
+5V_PWR: PC4906.1 PG4903.1 PL4904.2 PR4907.2 PR4909.2 PR4913.2 PR4915.2 PR4916.2 PR4926.2 PT4903.1
+5VL: PG4901.2 PR4918.1
AGND: C134.2 C140.2 C144.2 C145.1 C146.2 C147.1 C154.1 C155.1 C157.2 C159.2 C160.2 C267.1 C268.1 C270.1 C450.1 C483.2 C485.1 C493.2 C495.2 C1491.2 LOUT1.5 LOUT1.P Q28.S R215.2 R216.2 R221.2 R268.2 R281.2 R300.2 R301.2 R1182.2 R1193.2 U6.22 U6.28 U6.42 UHS1.5
AVCC33_2136: C292.2 C293.2 C298.1 L17.2 U126.5
AVCC_EC: C4102.1 L4101.2 R80130.1 R80133.2 U4101.52
DVCC33_2136: C283.2 C284.1 C289.1 C290.1 C291.1 L16.2 R69.1 R1074.1 R79686.1 U126.18 U126.22
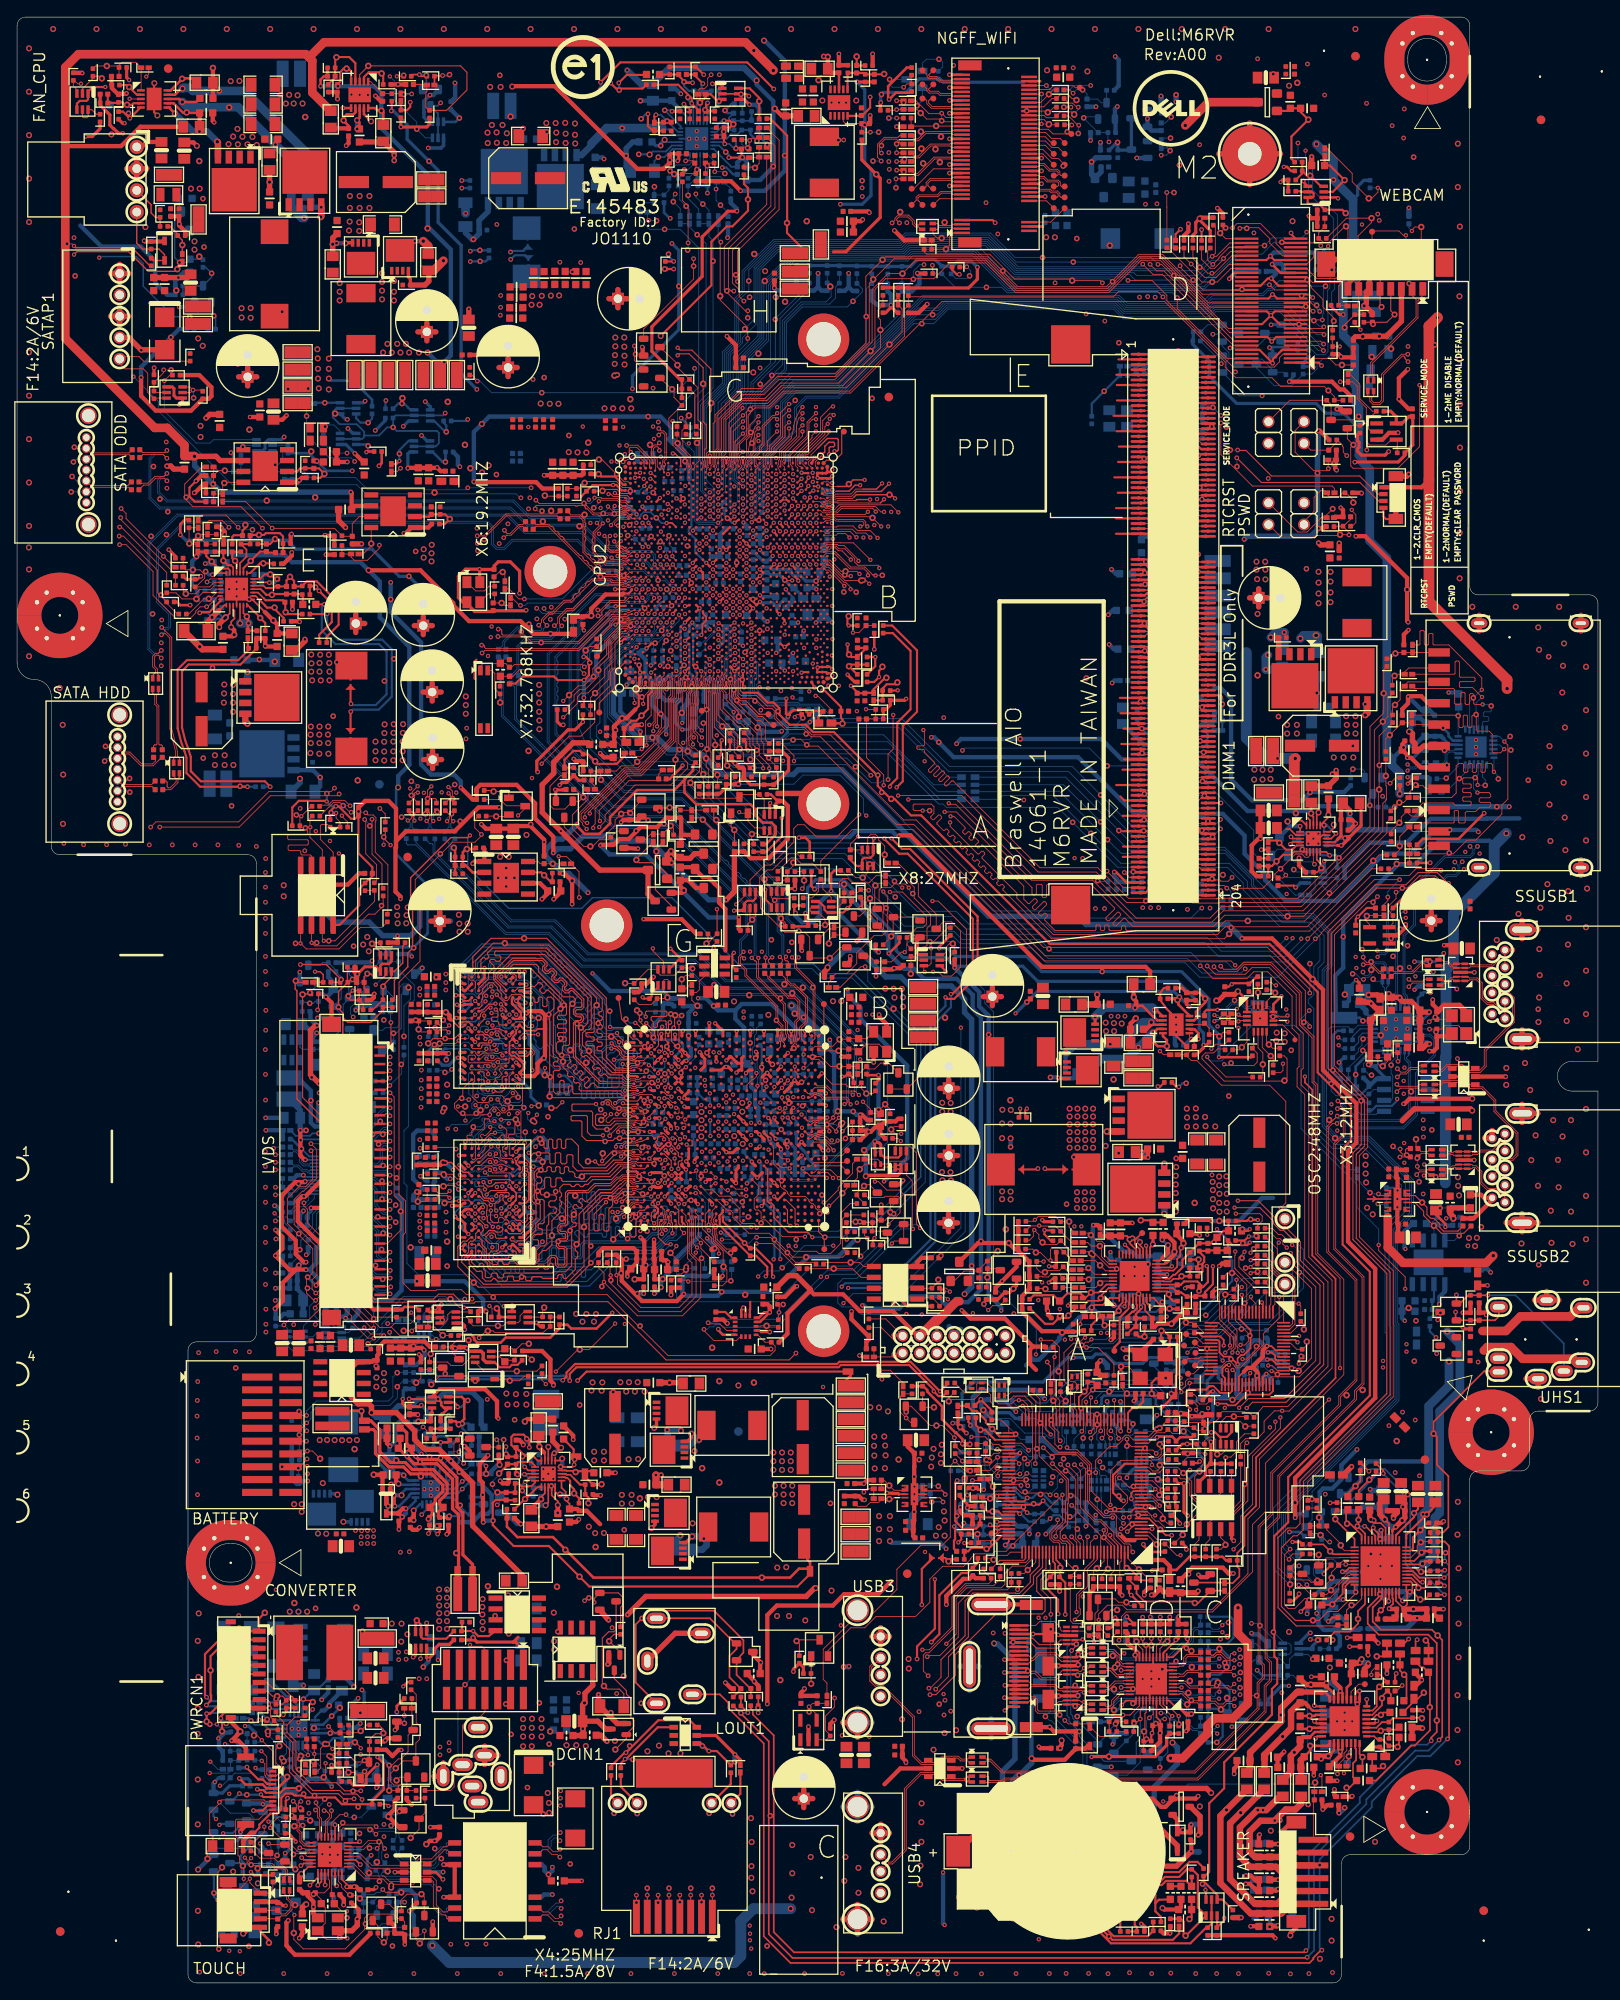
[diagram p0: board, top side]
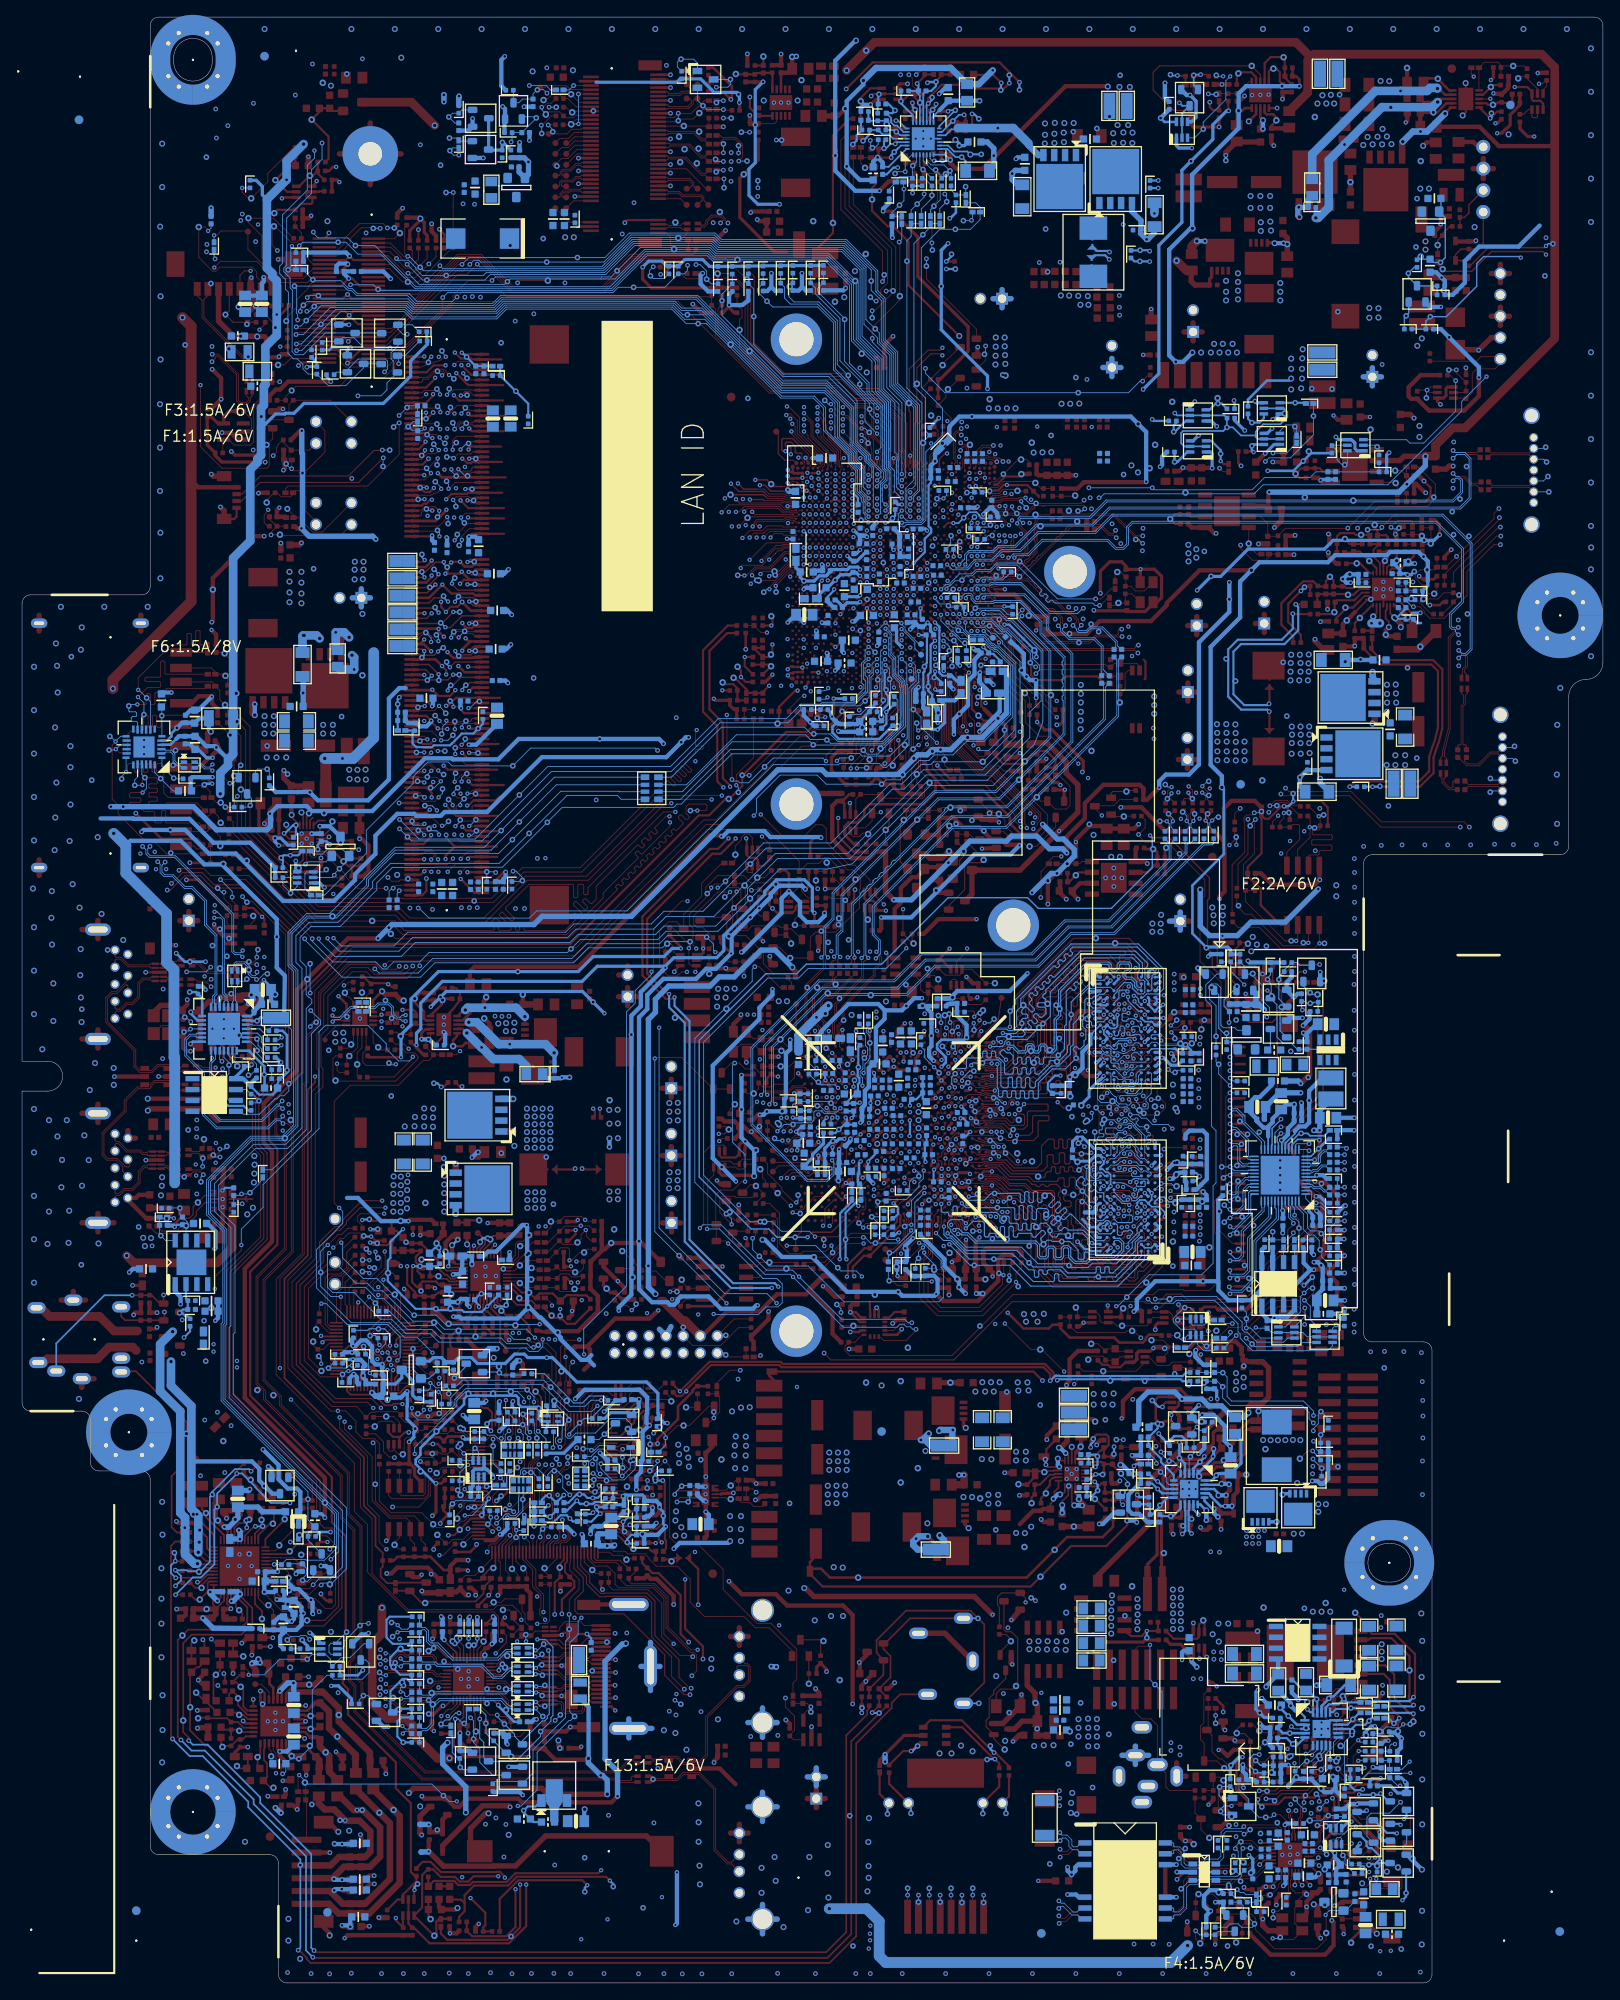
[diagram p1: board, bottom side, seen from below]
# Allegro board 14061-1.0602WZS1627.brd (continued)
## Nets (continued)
GND: AFTP1.1 BAT2.9B BAT2.10B BT1.2 C3.2 C6.2 C7.2 C8.1 C9.2 C11.2 C14.1 C16.2 C20.2 C24.1 C26.1 C27.1 C28.1 C29.2 C30.2 C31.2 C32.2 C33.2 C35.2 C36.2 C37.2 C38.2 C39.2 C40.2 C42.2 C44.1 C47.2 C48.2 C49.2 C50.2 C52.2 C60.1 C61.1 C62.1 C63.1 C64.1 C65.1 C66.1 C67.1 C68.1 C69.1 C70.1 C71.1 C72.1 C73.1 C74.1 C75.1 C76.1 C77.1 C78.1 C79.1 C80.2 C81.2 C82.1 C84.2 C86.2 C87.2 C88.2 C89.1 C90.2 C93.1 C94.1 C96.2 C100.2 C101.2 C105.1 C106.1 C107.1 C109.2 C110.2 C111.1 C112.2 C116.1 C121.1 C126.1 C127.1 C129.1 C131.1 C132.1 C163.2 C170.2 C174.1 C175.2 C176.2 C179.2 C180.2 C181.1 C182.2 C183.2 C185.2 C186.2 C189.2 C190.2 C191.2 C194.2 C195.2 C202.1 C205.2 C207.2 C212.2 C213.2 C214.2 C215.2 C216.2 C217.2 C218.2 C220.2 C221.2 C222.2 C225.2 C226.2 C227.1 C232.2 C234.1 C235.2 C236.2 C238.2 C239.2 C243.2 C247.2 C248.2 C249.2 C251.2 C255.2 C256.2 C263.2 C270.2 C271.2 C272.1 C283.1 C284.2 C289.2 C290.2 C291.2 C292.1 C293.1 C295.2 C296.1 C297.2 C298.2 C299.2 C302.2 C303.1 C304.2 C305.2 C313.2 C314.2 C364.2 C372.1 C380.1 C385.2 C391.2 C393.2 C397.1 C398.1 C399.2 C400.1 C401.2 C402.2 C403.2 C404.2 C405.1 C406.1 C407.2 C408.2 C409.2 C474.2 C478.1 C486.2 C489.2 C500.2 C509.2 C514.2 C516.2 C521.2 C522.2 C523.2 C530.1 C531.1 C534.1 C536.1 C537.1 C538.1 C540.2 C542.1 C543.2 C544.1 C545.2 C547.1 C548.1 C549.1 C551.1 C552.2 C554.1 C557.2 C558.2 C559.2 C561.2 C562.1 C568.2 C571.2 C572.2 C573.1 C574.1 C575.1 C576.1 C582.2 C583.2 C590.2 C591.2 C592.2 C597.2 C598.2 C599.2 C600.2 C605.2 C606.2 C607.2 C608.2 C609.2 C612.2 C614.2 C616.2 C617.2 C618.2 C619.2 C620.2 C621.2 C622.2 C623.2 C624.2 C625.2 C626.2 C627.2 C629.2 C630.2 C631.2 C632.2 C633.2 C634.2 C641.2 C642.2 C643.2 C644.2 C711.2 C714.1 C721.1 C752.2 C753.2 C755.1 C756.2 C757.2 C758.2 C759.2 C760.2 C761.2 C762.2 C765.2 C766.2 C767.2 C768.2 C769.2 C770.2 C771.2 C772.2 C773.2 C774.2 C775.2 C776.2 C777.2 C778.2 C779.2 C780.2 C781.2 C782.2 C783.2 C784.2 C785.2 C786.2 C787.2 C788.2 C789.2 C790.2 C791.2 C792.2 C793.2 C794.2 C795.2 C796.2 C797.2 C798.2 C799.2 C800.2 C801.2 C802.2 C803.2 C804.2 C805.2 C806.2 C807.2 C808.2 C809.2 C810.2 C811.2 C812.2 C813.2 C814.2 C815.2 C816.2 C817.2 C818.2 C819.2 C820.2 C821.2 C822.2 C823.2 C824.2 C825.2 C826.2 C827.2 C828.2 C829.2 C830.2 C835.2 C839.2 C852.2 C853.2 C859.2 C864.2 C869.2 C1601.1 C1602.1 C1605.1 C1606.2 C1607.2 C1608.1 C1609.1 C1615.2 C1616.2 C1617.2 C1618.2 C1619.2 C1620.2 C1621.2 C1622.2 C1623.2 C1624.2 C1625.2 C1633.2 C1634.2 C1635.2 C1636.2 C1638.2 C1639.2 C1640.2 C1641.2 C1643.2 C1644.2 C1645.2 C1646.2 C1647.2 C1648.2 C1649.2 C1650.2 C1651.2 C1652.2 C1653.2 C1654.2 C1655.2 C1656.2 C1657.2 C1658.2 C1659.2 C1660.2 C1661.2 C1662.2 C1663.2 C1665.2 C1666.2 C1667.2 C1668.2 C1669.2 C1670.2 C1671.2 C1672.2 C1673.2 C1674.2 C1696.2 C1698.2 C1699.2 C1700.2 C1701.2 C1702.2 C1703.2 C1704.2 C1705.2 C1706.2 C1801.2 C1827.2 C1846.2 C1847.2 C1848.2 C1849.1 C1850.2 C1851.2 C1852.2 C1853.2 C1854.2 C1855.1 C1856.2 C1857.2 C1858.2 C1859.2 C1860.2 C1861.2 C1864.2 C1867.2 C1868.2 C1869.2 C1877.2 C3131.2 C3452.2 C3459.2 C3460.2 C4101.2 C4102.2 C4202.2 C4230.1 C4254.2 C4259.2 C4260.2 C4261.1 C4262.2 C4263.1 C4266.2 C4280.1 C4281.2 C4282.2 C4283.2 C4284.2 C4285.2 C4286.2 C4287.2 C4288.2 C4289.1 C4290.1 C6701.1 C6702.1 C6703.2 C6710.2 C6711.2 C6715.2 C6716.2 C6717.2 C6718.2 C6719.2 C6720.2 C6721.2 C6722.2 C6724.1 C6726.2 C6727.2 C6728.2 C6729.2 C6730.2 C6731.2 C6732.2 C6733.2 C6734.2 C12324.2 C12326.2 C12327.2 C12328.2 C12329.2 C12330.2 C12331.1 C12332.2 C12333.2 C12334.2 C12335.2 C12336.2 C12338.2 C12339.2 C12340.2 C12341.2 C12342.2 C12343.1 C12344.1 C12345.1 C12346.1 C12347.1 C12348.1 C12349.2 C12350.1 CN1.1 CN2.4 CN2.5 CN2.6 CONVT1.10 CONVT1.11 CONVT1.12 CPU2.A5 CPU2.A7 CPU2.A11 CPU2.A15 CPU2.A19 CPU2.A23 CPU2.A31 CPU2.A39 CPU2.A43 CPU2.A47 CPU2.AA16 CPU2.AA27 CPU2.AA38 CPU2.AA53 CPU2.AB4 CPU2.AB6 CPU2.AB10 CPU2.AB12 CPU2.AB13 CPU2.AB14 CPU2.AB42 CPU2.AB47 CPU2.AB50 CPU2.AC16 CPU2.AC29 CPU2.AC33 CPU2.AC35 CPU2.AC38 CPU2.AD4 CPU2.AD21 CPU2.AD30 CPU2.AD32 CPU2.AD36 CPU2.AD44 CPU2.AE1 CPU2.AE6 CPU2.AE8 CPU2.AE9 CPU2.AE11 CPU2.AE12 CPU2.AE14 CPU2.AE40 CPU2.AE42 CPU2.AE43 CPU2.AE45 CPU2.AE46 CPU2.AE48 CPU2.AE50 CPU2.AE53 CPU2.AF10 CPU2.AF24 CPU2.AF25 CPU2.AF32 CPU2.AF38 CPU2.AF47 CPU2.AG25 CPU2.AH9 CPU2.AH10 CPU2.AH12 CPU2.AH13 CPU2.AH14 CPU2.AH41 CPU2.AH42 CPU2.AH44 CPU2.AH47 CPU2.AJ1 CPU2.AJ3 CPU2.AJ16 CPU2.AJ18 CPU2.AJ25 CPU2.AJ51 CPU2.AJ53 CPU2.AK4 CPU2.AK7 CPU2.AK16 CPU2.AK22 CPU2.AK25 CPU2.AK27 CPU2.AK29 CPU2.AK32 CPU2.AK38 CPU2.AK40 CPU2.AK44 CPU2.AK45 CPU2.AK47 CPU2.AK50 CPU2.AM4 CPU2.AM13 CPU2.AM16 CPU2.AM24 CPU2.AM27 CPU2.AM30 CPU2.AM35 CPU2.AM38 CPU2.AM42 CPU2.AM50 CPU2.AN1 CPU2.AN3 CPU2.AN5 CPU2.AN6 CPU2.AN8 CPU2.AN9 CPU2.AN11 CPU2.AN12 CPU2.AN14 CPU2.AN16 CPU2.AN21 CPU2.AN24 CPU2.AN25 CPU2.AN29 CPU2.AN30 CPU2.AN33 CPU2.AN38 CPU2.AN40 CPU2.AN42 CPU2.AN43 CPU2.AN45 CPU2.AN46 CPU2.AN48 CPU2.AN49 CPU2.AN51 CPU2.AN53 CPU2.AP4 CPU2.AP9 CPU2.AP45 CPU2.AP50 CPU2.AT3 CPU2.AT9 CPU2.AT18 CPU2.AT19 CPU2.AT27 CPU2.AT35 CPU2.AT36 CPU2.AT45 CPU2.AT51 CPU2.AU1 CPU2.AU3 CPU2.AU51 CPU2.AU53 CPU2.AV14 CPU2.AV19 CPU2.AV24 CPU2.AV27 CPU2.AV30 CPU2.AV35 CPU2.AV40 CPU2.AW13 CPU2.AW19 CPU2.AW27 CPU2.AW35 CPU2.AW41 CPU2.AY3 CPU2.AY7 CPU2.AY9 CPU2.AY20 CPU2.AY22 CPU2.AY24 CPU2.AY26 CPU2.AY28 CPU2.AY30 CPU2.AY32 CPU2.AY34 CPU2.AY45 CPU2.AY47 CPU2.AY51 CPU2.B2 CPU2.B28 CPU2.B36 CPU2.BA19 CPU2.BA24 CPU2.BA27 CPU2.BA30 CPU2.BA35 CPU2.BB4 CPU2.BB19 CPU2.BB27 CPU2.BB35 CPU2.BB50 CPU2.BC10 CPU2.BC14 CPU2.BC16 CPU2.BC26 CPU2.BC28 CPU2.BC38 CPU2.BC40 CPU2.BC44 CPU2.BD1 CPU2.BD19 CPU2.BD27 CPU2.BD35 CPU2.BD53 CPU2.BE19 CPU2.BE35 CPU2.BF4 CPU2.BF12 CPU2.BF22 CPU2.BF26 CPU2.BF27 CPU2.BF28 CPU2.BF32 CPU2.BF42 CPU2.BF50 CPU2.BG1 CPU2.BG5 CPU2.BG7 CPU2.BG14 CPU2.BG16 CPU2.BG18 CPU2.BG19 CPU2.BG20 CPU2.BG24 CPU2.BG27 CPU2.BG30 CPU2.BG34 CPU2.BG35 CPU2.BG36 CPU2.BG38 CPU2.BG40 CPU2.BG47 CPU2.BG49 CPU2.BG53 CPU2.BH1 CPU2.BH2 CPU2.BH52 CPU2.BJ7 CPU2.BJ11 CPU2.BJ15 CPU2.BJ19 CPU2.BJ23 CPU2.BJ27 CPU2.BJ31 CPU2.BJ35 CPU2.BJ39 CPU2.BJ43 CPU2.BJ47 CPU2.C1 CPU2.C3 CPU2.C20 CPU2.C22 CPU2.C28 CPU2.C30 CPU2.C36 CPU2.C39 CPU2.C47 CPU2.D10 CPU2.D16 CPU2.D24 CPU2.D27 CPU2.D32 CPU2.D38 CPU2.D40 CPU2.D42 CPU2.E19 CPU2.E35 CPU2.E46 CPU2.E51 CPU2.F1 CPU2.F5 CPU2.F19 CPU2.F24 CPU2.F27 CPU2.F32 CPU2.F35 CPU2.G12 CPU2.G14 CPU2.G22 CPU2.G26 CPU2.G28 CPU2.G30 CPU2.H8 CPU2.H19 CPU2.H27 CPU2.H35 CPU2.J18 CPU2.J19 CPU2.J22 CPU2.J27 CPU2.J30 CPU2.J35 CPU2.J38 CPU2.J42 CPU2.J53 CPU2.K4 CPU2.K12 CPU2.K14 CPU2.K16 CPU2.K22 CPU2.K24 CPU2.K30 CPU2.K32 CPU2.K34 CPU2.K36 CPU2.K45 CPU2.K50 CPU2.L1 CPU2.L19 CPU2.L27 CPU2.L35 CPU2.L41 CPU2.M9 CPU2.M14 CPU2.M19 CPU2.M24 CPU2.M27 CPU2.M35 CPU2.M40 CPU2.M45 CPU2.M50 CPU2.N22 CPU2.N24 CPU2.N32 CPU2.N51 CPU2.N53 CPU2.P4 CPU2.P10 CPU2.P19 CPU2.P22 CPU2.P27 CPU2.P32 CPU2.P35 CPU2.P36 CPU2.P42 CPU2.R1 CPU2.T9 CPU2.T14 CPU2.T47 CPU2.U5 CPU2.U6 CPU2.U8 CPU2.U9 CPU2.U11 CPU2.U12 CPU2.U14 CPU2.U18 CPU2.U21 CPU2.U25 CPU2.U29 CPU2.U30 CPU2.U32 CPU2.U33 CPU2.U36 CPU2.U38 CPU2.U40 CPU2.U42 CPU2.U43 CPU2.U45 CPU2.U46 CPU2.U48 CPU2.U49 CPU2.U53 CPU2.V16 CPU2.V21 CPU2.V25 CPU2.V32 CPU2.V38 CPU2.V41 CPU2.V42 CPU2.V44 CPU2.W1 CPU2.Y4 CPU2.Y9 CPU2.Y10 CPU2.Y14 CPU2.Y16 CPU2.Y19 CPU2.Y21 CPU2.Y22 CPU2.Y24 CPU2.Y29 CPU2.Y38 CPU2.Y40 CPU2.Y45 CPU2.Y50 D14.1 D21.A DCIN1.2 DCIN1.4 DCIN1.5 DCIN1.6 DCIN1.7 DCIN2.5 DCIN2.6 DCIN2.7 DCIN2.12 DCIN2.13 DCIN2.14 DIMM1.2 DIMM1.3 DIMM1.8 DIMM1.9 DIMM1.13 DIMM1.14 DIMM1.19 DIMM1.20 DIMM1.25 DIMM1.26 DIMM1.31 DIMM1.32 DIMM1.37 DIMM1.38 DIMM1.43 DIMM1.44 DIMM1.48 DIMM1.49 DIMM1.54 DIMM1.55 DIMM1.60 DIMM1.61 DIMM1.65 DIMM1.66 DIMM1.71 DIMM1.72 DIMM1.127 DIMM1.128 DIMM1.133 DIMM1.134 DIMM1.138 DIMM1.139 DIMM1.144 DIMM1.145 DIMM1.150 DIMM1.151 DIMM1.155 DIMM1.156 DIMM1.161 DIMM1.162 DIMM1.167 DIMM1.168 DIMM1.172 DIMM1.173 DIMM1.178 DIMM1.179 DIMM1.184 DIMM1.185 DIMM1.189 DIMM1.190 DIMM1.195 DIMM1.196 DIMM1.205 DIMM1.206 FANC3.1 GPU1.A3 GPU1.A30 GPU1.AA11 GPU1.AA13 GPU1.AA16 GPU1.AA27 GPU1.AB6 GPU1.AB10 GPU1.AB15 GPU1.AB24 GPU1.AB32 GPU1.AC9 GPU1.AC17 GPU1.AC24 GPU1.AC26 GPU1.AC27 GPU1.AD6 GPU1.AD8 GPU1.AD23 GPU1.AD25 GPU1.AD32 GPU1.AE7 GPU1.AE14 GPU1.AE22 GPU1.AE27 GPU1.AF19 GPU1.AF20 GPU1.AF23 GPU1.AF32 GPU1.AG12 GPU1.AG14 GPU1.AG23 GPU1.AG27 GPU1.AH10 GPU1.AH14 GPU1.AH28 GPU1.AH32 GPU1.AM14 GPU1.AM16 GPU1.AM18 GPU1.AM20 GPU1.AM22 GPU1.AM24 GPU1.B6 GPU1.B8 GPU1.B10 GPU1.B12 GPU1.B14 GPU1.B16 GPU1.B18 GPU1.B20 GPU1.B22 GPU1.B24 GPU1.B26 GPU1.C1 GPU1.C32 GPU1.E28 GPU1.F2 GPU1.F6 GPU1.F8 GPU1.F10 GPU1.F12 GPU1.F14 GPU1.F16 GPU1.F18 GPU1.F20 GPU1.F22 GPU1.F24 GPU1.F26 GPU1.G8 GPU1.G10 GPU1.G27 GPU1.G31 GPU1.H2 GPU1.H6 GPU1.H14 GPU1.H17 GPU1.H20 GPU1.J7 GPU1.J27 GPU1.J31 GPU1.K2 GPU1.K6 GPU1.K11 GPU1.K22 GPU1.K28 GPU1.K32 GPU1.L27 GPU1.M6 GPU1.M12 GPU1.M32 GPU1.N11 GPU1.N13 GPU1.N16 GPU1.N18 GPU1.N21 GPU1.N25 GPU1.N27 GPU1.P6 GPU1.P9 GPU1.P25 GPU1.P32 GPU1.R11 GPU1.R12 GPU1.R15 GPU1.R17 GPU1.R20 GPU1.R27 GPU1.T6 GPU1.T11 GPU1.T13 GPU1.T16 GPU1.T18 GPU1.T21 GPU1.T25 GPU1.T32 GPU1.U9 GPU1.U15 GPU1.U17 GPU1.U20 GPU1.U25 GPU1.U27 GPU1.V11 GPU1.V13 GPU1.V16 GPU1.V18 GPU1.V32 GPU1.W25 GPU1.W26 GPU1.W27 GPU1.Y10 GPU1.Y15 GPU1.Y17 GPU1.Y20 GPU1.Y25 GPU1.Y32 H1.1 H2.1 H3.1 H4.1 H5.1 H6.1 H6.2 H6.3 H6.4 H6.5 H6.6 H6.7 H6.8 H7.1 H7.2 H7.3 H7.4 H7.5 H7.6 H7.7 H7.8 H9.1 H9.2 H9.3 H9.4 H9.5 H9.6 H9.7 H9.8 H10.1 H10.2 H10.3 H10.4 H10.5 H10.6 H10.7 H10.8 H11.1 H11.2 H11.3 H11.4 H11.5 H11.6 H11.7 H11.8 HDD1.1 HDD1.4 HDD1.7 HDD1.8 HDD1.9 HDMI1.2 HDMI1.5 HDMI1.8 HDMI1.11 HDMI1.17 HDMI1.20 HDMI1.21 HDMI1.22 HDMI2.3 HDMI2.9 HDMI2.12 HDMI2.15 HDMI2.18 HDMI2.20 HDMI2.21 HDMI2.22 HDMI2.23 HDMI2.24 HDMI2.25 HS6.1 LED2.K LPC1.12 LPC1.14 LVDS1.7 LVDS1.14 LVDS1.31 LVDS1.32 MEM1.A9 MEM1.B1 MEM1.B3 MEM1.B9 MEM1.D1 MEM1.D8 MEM1.E1 MEM1.E2 MEM1.E8 MEM1.F9 MEM1.G1 MEM1.G8 MEM1.G9 MEM1.J2 MEM1.J8 MEM1.M1 MEM1.M9 MEM1.P1 MEM1.P9 MEM1.T1 MEM1.T9 MEM2.A9 MEM2.B1 MEM2.B3 MEM2.B9 MEM2.D1 MEM2.D8 MEM2.E1 MEM2.E2 MEM2.E8 MEM2.F9 MEM2.G1 MEM2.G8 MEM2.G9 MEM2.J2 MEM2.J8 MEM2.M1 MEM2.M9 MEM2.P1 MEM2.P9 MEM2.T1 MEM2.T9 MEM3.A9 MEM3.B1 MEM3.B3 MEM3.B9 MEM3.D1 MEM3.D8 MEM3.E1 MEM3.E2 MEM3.E8 MEM3.F9 MEM3.G1 MEM3.G8 MEM3.G9 MEM3.J2 MEM3.J8 MEM3.M1 MEM3.M9 MEM3.P1 MEM3.P9 MEM3.T1 MEM3.T9 MEM4.A9 MEM4.B1 MEM4.B3 MEM4.B9 MEM4.D1 MEM4.D8 MEM4.E1 MEM4.E2 MEM4.E8 MEM4.F9 MEM4.G1 MEM4.G8 MEM4.G9 MEM4.J2 MEM4.J8 MEM4.M1 MEM4.M9 MEM4.P1 MEM4.P9 MEM4.T1 MEM4.T9 MEMCD1.3 MEMCD1.6 MEMCD1.12 MEMCD1.13 MEMCD1.14 MEMCD1.15 NGFF1.7 NGFF1.18 NGFF1.23 NGFF1.24 NGFF1.29 NGFF1.30 NGFF1.33 NGFF1.36 NGFF1.39 NGFF1.45 NGFF1.57 NGFF1.63 NGFF1.69 NGFF1.75 NGFF1.76 NGFF1.77 ODD1.1 ODD1.4 ODD1.7 ODD1.8 ODD1.9 OSC2.2 PC12.2 PC17.2 PC18.2 PC21.2 PC22.2 PC24.2 PC27.2 PC28.2 PC29.2 PC31.2 PC32.2 PC33.1 PC61.2 PC124.1 PC151.2 PC2127.1 PC4202.2 PC4203.2 PC4204.1 PC4301.2 PC4302.2 PC4303.2 PC4304.2 PC4305.2 PC4401.2 PC4405.2 PC4406.2 PC4407.2 PC4409.2 PC4410.2 PC4415.2 PC4416.1 PC4417.2 PC4418.2 PC4423.2 PC4424.2 PC4426.2 PC4427.2 PC4428.2 PC4429.2 PC4509.2 PC4510.2 PC4515.2 PC4516.1 PC4517.2 PC4518.2 PC4523.1 PC4524.2 PC4526.2 PC4527.2 PC4528.2 PC4529.2 PC4701.2 PC4702.2 PC4704.2 PC4706.2 PC4707.2 PC4708.2 PC4801.2 PC4901.2 PC4902.2 PC4903.2 PC4904.2 PC4905.2 PC4906.2 PC4907.2 PC4908.2 PC4911.2 PC4912.2 PC4915.2 PC4916.1 PC4917.2 PC4918.2 PC5001.2 PC5003.2 PC5004.2 PC5005.2 PC5006.2 PC5007.2 PC5009.2 PC5010.2 PC5011.2 PC5012.2 PC5112.1 PC5113.2 PC5115.2 PC5116.1 PC5211.2 PC5212.1 PC5213.2 PC5215.2 PC5216.1 PC5217.2 PC5221.2 PC5222.2 PC5223.1 PC5224.2 PC5225.1 PC5227.2 PC5228.2 PC5229.2 PC5233.1 PC5237.2 PC5240.2 PC5241.2 PC5242.2 PC5243.2 PC5251.2 PC5254.2 PC5255.2 PC5256.2 PC5257.2 PC5258.2 PC5259.2 PC5260.2 PC5261.2 PC5263.2 PC5264.2 PC5266.2 PC5267.2 PC5269.2 PC5270.2 PC5271.1 PC5273.1 PC5430.2 PC5431.2 PC5432.2 PC5433.2 PC5434.2 PC5435.2 PC5436.2 PC5439.2 PC5440.2 PC5441.2 PC5443.2 PC5444.2 PC5445.2 PD4202.A PL4301.2 PL4302.2 PL4303.2 PN4401.2 PN4501.2 PQ8.1 PQ8.2 PQ8.3 PQ4204.E PQ4206.S PQ4402.1 PQ4402.2 PQ4402.3 PQ4406.1 PQ4406.4 PQ4408.S PQ4702.1 PQ4702.2 PQ4702.3 PQ4902.1 PQ4902.2 PQ4902.3 PQ4903.1 PQ4903.2 PQ4903.3 PQ5002.1 PQ5002.2 PQ5002.3 PQ5003.S PQ5004.S PQ5005.1 PQ5005.4 PQ47002.1 PQ47002.2 PQ47002.3 PR2.2 PR3.2 PR7.2 PR26.2 PR29.1 PR31.2 PR33.2 PR41.2 PR53.2 PR57.2 PR58.2 PR77.2 PR4207.2 PR4403.2 PR4406.2 PR4414.2 PR4415.2 PR4431.2 PR4432.2 PR4433.2 PR4451.2 PR4503.2 PR4506.2 PR4514.2 PR4515.2 PR4531.2 PR4532.2 PR4533.2 PR4702.2 PR4718.2 PR4917.2 PR4919.2 PR4920.2 PR4922.2 PR4924.2 PR4925.2 PR5001.2 PR5112.2 PR5212.2 PR5242.2 PR5251.2 PR5274.1 PR5285.2 PR5298.2 PR5473.2 PR9768.2 PR9770.2 PR9780.2 PR9796.2 PR9804.2 PR9812.1 PR9814.2 PSWD1.1 PT1.2 PT2.2 PT3.2 PT4.2 PT4491.2 PT4591.2 PT4901.2 PT4902.2 PT4903.2 PT5001.2 PT5002.2 PTC9.2 PTC21.2 PTC4701.2 PTC4702.2 PU3.1 PU3.2 PU3.3 PU4.11 PU7.1 PU4401.11 PU4401.29 PU4405.1 PU4405.2 PU4405.3 PU4501.11 PU4501.29 PU4503.1 PU4503.2 PU4503.3 PU4504.1 PU4504.2 PU4504.3 PU4701.11 PU4705.11 PU4901.21 PU5001.1 PU5001.3 PU5001.14 PU5001.21 PU5201.1 PU5202.1 PU5203.1 PU5206.11 PU5207.1 PU5207.2 PU5207.3 PWRCN1.4 PWRCN1.11 PWRCN1.12 Q1.S Q3.S Q5.S Q10.E Q12.1 Q12.4 Q13.1 Q13.4 Q16.1 Q16.4 Q17.1 Q17.4 Q20.1 Q20.4 Q21.1 Q21.4 Q23.1 Q23.4 Q24.3 Q29.1 Q29.4 Q30.1 Q30.4 Q35.1 Q35.4 Q36.E Q37.E Q38.E Q40.E Q46.3 Q48.1 Q48.4 Q49.1 Q49.4 Q57.3 Q63.1 Q64.S Q65.S Q66.S Q68.S Q74.E Q75.E Q76.E Q77.S Q79.S Q97.1 Q97.4 Q103.S Q1205.S Q1206.1 Q1206.4 Q1214.S Q1227.S Q1228.1 Q1228.4 Q1229.1 Q1229.4 Q1230.1 Q1230.4 Q1231.1 Q1231.4 Q1232.1 Q1232.4 Q1233.1 Q1233.4 Q1234.S Q1240.D Q1246.S Q1254.S Q1257.S Q6701.1 Q6701.4 Q6703.S Q6706.S Q6708.E Q6710.E Q6711.E Q6714.E Q9625.E Q9628.S Q9635.E Q9636.S Q9642.E Q9643.1 Q9643.4 Q9648.S Q9650.S R19.2 R27.2 R30.2 R33.2 R37.1 R73.1 R86.2 R94.1 R122.2 R132.2 R144.2 R146.1 R151.2 R152.2 R155.2 R156.1 R162.2 R174.2 R179.2 R181.1 R202.1 R210.2 R215.1 R216.1 R274.2 R299.1 R300.1 R301.1 R317.1 R320.1 R332.2 R360.2 R366.2 R368.2 R377.1 R394.2 R422.2 R456.1 R466.1 R483.2 R501.2 R507.1 R511.2 R512.2 R523.2 R524.1 R527.1 R533.2 R542.2 R552.2 R553.2 R555.2 R557.2 R560.2 R562.2 R579.2 R581.2 R646.2 R675.2 R676.2 R677.2 R729.2 R739.1 R870.1 R886.1 R899.1 R924.1 R940.2 R946.1 R948.2 R963.2 R1079.2 R1158.1 R1182.1 R1193.1 R1201.1 R1205.2 R1206.2 R1207.2 R1209.1 R1210.1 R1216.2 R1217.1 R1230.2 R1234.1 R1242.1 R1257.1 R1259.1 R1265.2 R1268.1 R1557.2 R1558.2 R1559.2 R1565.2 R1596.2 R1633.2 R1637.1 R1661.1 R1779.2 R1791.2 R1801.2 R1802.2 R1803.2 R1806.2 R1807.2 R1808.2 R1811.2 R1814.2 R1816.2 R1823.2 R1827.2 R1880.2 R1881.2 R1882.2 R1886.2 R1888.2 R1889.2 R1892.1 R1894.2 R1897.2 R1899.2 R1905.1 R1911.1 R1914.2 R1917.1 R1919.2 R1921.1 R1923.1 R79622.2 R79658.2 R79664.1 R79665.1 R79681.2 R79701.1 R79722.2 R79734.2 R79741.2 R79743.2 R79745.2 R79747.2 R79752.2 R79757.2 R79758.2 R79774.2 R79785.2 R79787.1 R79788.2 R79797.2 R79800.2 R79802.2 R79914.2 R79916.2 R79950.1 R80049.2 R80060.2 R80102.2 R80125.2 R80128.2 R80137.1 R80141.1 R80142.1 R80143.1 R80144.1 R80147.1 R80149.2 R80157.1 R80215.2 R80217.2 RJ1.13 RV5.1 SATAP1.2 SATAP1.4 SC1.1 SC2.2 SC3.1 SC4.2 SC5.1 SC6.2 SPK1.5 SPK1.7 SPK1.8 SR1.2 SRCON1.4 SSUSB1.4 SSUSB1.7 SSUSB1.10 SSUSB1.11 SSUSB2.4 SSUSB2.7 SSUSB2.10 SSUSB2.11 SU1.25 TC1.2 TC5.2 TC10.1 TC11.2 TC13.2 TC15.2 TC16.2 TC17.2 TC18.2 TC19.2 TC20.2 TC21.2 TOUCH1.2 TXE1.2 U2.3 U6.49 U7.3 U7.8 U8.4 U9.1 U9.2 U9.3 U9.4 U15.4 U20.33 U21.8 U21.9 U21.10 U21.17 U21.20 U21.21 U21.24 U21.33 U25.1 U25.2 U25.4 U25.7 U35.2 U41.1 U41.4 U49.4 U51.3 U51.8 U52.11 U52.15 U54.11 U54.15 U55.14 U55.21 U109.4 U109.35 U109.71 U120.20 U121.2 U122.2 U124.2 U125.2 U126.6 U126.49 U127.8 U127.15 U127.35 U127.41 U129.3 U129.8 U130.3 U130.8 U131.3 U131.8 U4101.10 U4101.21 U4101.45 U4101.53 U6701.5 U6701.10 U6701.12 U6701.13 U6701.15 U6701.16 U6702.29 U6703.2 U6704.2 U6705.2 U6706.22 U6706.27 U9625.14 U9625.17 UHS1.MS1 UHS1.MS2 USB3.4 USB3.5 USB3.6 USB4.4 USB4.5 USB4.6 WEBCM1.6 WEBCM1.8 WEBCM1.9 WEBCM1.10 X3.2 X3.4 X4.2 X4.4 X6.2 X6.4 X7.2 X7.3 X8.2 X8.4 XDP1.1 XDP1.2 XDP1.7 XDP1.8 XDP1.13 XDP1.14 XDP1.19 XDP1.20 XDP1.25 XDP1.26 XDP1.31 XDP1.32 XDP1.37 XDP1.38 XDP1.49 XDP1.50 XDP1.59
GND_AUD: C144.1 C145.2 U6.40
V1P8_FUSE: C1660.1 CPU2.U16 R1253.2
VBAT1: BT1.1 R199.1 TP14.1
VBAT1_R: D5.2 D6.A R199.2 TP13.1
VBAT2: D6.K R381.1
VBAT_SIO: C218.1 R381.2 U109.66
VCC: C20.1 C714.2 C1668.1 C1669.1 D33.A F13.1 LPC1.8 PC5435.1 PR11.1 PR44.2 PR9771.1 PU7.6 Q9624.D R183.1 R185.1 R421.1 R617.1 R650.2 R1688.1 R2080.1 R6705.1 R79935.1 U1.1 U1.2 U1.5 U1.6 U52.13 U52.14
VCC0_HOT: PU4401.2 R1604.2 R1734.2 R79786.2
VCC0_PG: PC4409.1 PR4401.2 PU4401.6 R1577.1
VCC0_SENSEN_CPU_N: CPU2.AJ32 R1585.1
VCC0_SENSEN_CPU_P: CPU2.AG32 R1584.1
VCC0_SENSEN_N: PC4414.2 PR4411.2 R1585.2 R1587.2 R1823.1
VCC0_SENSEN_P: PR4410.1 R1584.2 R1586.2 R1822.2
VCC1_SENSEN_CPU_N: CPU2.AF27 R1587.1
VCC1_SENSEN_CPU_P: CPU2.AD29 R1586.1
VCC3: C398.2 C399.1 C474.1 C478.2 C509.1 C516.1 C522.1 C836.2 C1670.1 C1671.1 C4283.1 C4285.1 C4289.2 D1.K D14.2 DIMM1.199 F1.1 F6.2 L16.1 L17.1 L21.1 LPC1.4 PR5.1 Q1255.G Q1256.G Q2301.G Q9629.S R7.1 R24.1 R32.1 R41.1 R44.2 R50.2 R64.1 R71.1 R134.1 R138.1 R143.1 R149.1 R184.1 R206.1 R213.1 R293.1 R297.1 R303.2 R310.2 R323.2 R324.1 R330.2 R331.1 R333.2 R335.2 R336.2 R354.2 R362.1 R375.2 R430.1 R482.1 R516.2 R517.1 R576.2 R634.2 R644.2 R649.2 R707.2 R1126.2 R1129.2 R1615.2 R1719.1 R1744.1 R1745.1 R6701.1 R6703.1 R6704.1 R79662.1 R79666.2 R79669.1 R79673.1 R79677.1 R79678.1 R79679.1 R79680.2 R79683.1 R79689.2 R79723.1 R79735.1 R79742.1 R79744.1 R79746.1 R79748.1 R79749.1 R79766.2 R79773.2 R79780.2 R79781.2 R79936.1 R80110.1 R80111.1 R80112.1 RN5.5(B) RN5.6(B) RN5.7(B) RN5.8(B) SC1.2 SC3.2 SU1.4 U6.11 U25.3 U25.8 U35.6 U52.8 U52.9 U119.3 U127.11 U127.37 U4101.4
VCC3_CAM: C8.2 C11.1 C16.1 F1.2 F3.2 R24.2 R79753.2 WEBCM1.3
VCC3_CARD: Q9632.S Q9641.D R80152.1
VCC3_EN: C1667.1 R1747.1 U52.5
VCC5_PANEL: C3.1 C6.1 C4254.1 F2.2 LVDS1.2 LVDS1.3 Q9647.S R481.1 R1163.1 R80233.2
VCC_EN: C1696.1 R1776.1 U52.3
VCC_FAN: C12325.2 C12326.1 C12327.1 F14.1 Q9624.S R101.2 R79914.1 R79935.2
VCC_FAN_PWR: C48.1 F14.2 FANC3.2 R80.1 R101.1
VCC_SVID_ALERT: PU4401.4 R1654.2
VCC_SVID_ALERT_R: PR5234.2 R1654.1
VCC_SVID_CLK: PU4401.5 R79790.2
VCC_SVID_CLK_R: PR5233.2 R79790.1 R79795.2
VCC_SVID_DATA: PU4401.3 R1653.2
VCC_SVID_DATA_R: PR5232.2 R1653.1 R79794.2
VCCCFIOAZA_1P80: C1656.1 CPU2.AF4 CPU2.AH4 R1248.2 R1249.2
VCCCLKDDR_1P24_1P35: C1634.1 C6722.1 CPU2.AM25 R1244.2
VCCFHVCPU0SI0_1P15: CPU2.AJ35 CPU2.AK33 R1224.1
VCCPADCF1SI0_1P8_3P3: C1655.1 CPU2.G1 R1247.2
VCCPADCF1SI0_1P80: C1651.1 C1652.1 CPU2.AD33 CPU2.AF33 CPU2.AK18 CPU2.AK19 R1251.2
VCCPADCF2SI0_E_1P80: C1648.1 C1649.1 C1650.1 CPU2.Y18 R1250.2
VCCPADCF3SI0_1P8_3P3: C1653.1 C1654.1 CPU2.E1 CPU2.E2 R1246.2 R80148.2
VCCRAM0CPU0SI1_1P15: C625.1 C626.1 C627.1 C629.1 C630.1 C631.1 CPU2.AK30 CPU2.AK35 CPU2.AK36 CPU2.AM29 R1225.1
VCCRTC_3P3: C1663.1 CPU2.B6 CPU2.C5 R1255.2
VCCRTCSUS_3P3: C1662.1 CPU2.D4 CPU2.E3 R1254.1
VCCSFRPLLDDR_1P24_1P35: C1633.1 C6721.1 CPU2.AN27 R1245.2
VCCSRAMGEN_1P15: C632.1 C633.1 C634.1 CPU2.AK21 CPU2.AM19 R1223.1
VCCUSB2_1P8: C1657.1 C1658.1 CPU2.AA29 R1252.2
VCCUSB2_3P3: C1659.1 CPU2.B22 CPU2.C23 R1256.1
VDDC_CT: C779.1 C780.1 C781.1 GPU1.AA20 GPU1.AA21 GPU1.AB20 GPU1.AB21 L48.2
VSS5: CPU2.B52
0D95V_VGA_S0: C798.1 C799.1 C800.1 C801.1 C802.1 C803.1 C804.1 GPU1.L23 GPU1.L24 GPU1.L25 GPU1.L26 GPU1.M22 GPU1.N22 GPU1.N23 GPU1.N24 GPU1.R21 GPU1.R22 GPU1.T22 GPU1.U21 GPU1.U22 GPU1.V22 L51.1 L53.1 PR4706.2 PR4707.2 PR4708.2 PR4709.2 R1161.2 R1162.2
0P95V_A: PC4705.1 PC4707.1 PC4708.1 PL4701.2 PR4706.1 PR4707.1 PR4708.1 PR4709.1 PR4717.1 PTC4701.1
1D5V_S0: PR5109.1 R205.1 R1248.1
1D8V_CARD: Q9634.S Q9640.D R80151.1
1D8V_S0: C28.2 C89.2 C90.1 C97.2 C523.1 Q6705.S R152.1 R389.2 R514.2 R645.1 R680.1 R693.2 R1266.1 R1696.2 R79688.2 R79690.1 R79764.1 R79765.2 R79798.1 R79799.2 U35.1 XDP1.44
1D8V_S0_EN: C100.1 Q23.2 R1683.1
1D8V_S0_EN1: Q23.5 Q23.6 R151.1 R153.2
1D8V_S0_EN2: Q23.3 R162.1 R163.2 R164.1
1D8V_S0_EN_G: C96.1 C97.1 Q6705.G R164.2
1D8V_S0_EN_R: PR5.2 R1683.2
1D8V_S5: C26.2 C27.2 PC5431.1 PC5432.1 PR36.2 PR37.2 PR38.2 PR211.2 PR212.2 PR213.2 PR5243.1 PR9767.1 PU7.5 PU7.9 Q1203.G Q1204.G Q1210.G Q6705.D Q9640.S R43.1 R49.2 R55.1 R56.2 R58.2 R59.2 R63.2 R72.1 R89.2 R392.1 R457.1 R458.1 R473.1 R492.2 R498.2 R499.1 R502.1 R505.2 R510.2 R530.2 R554.1 R556.1 R558.1 R561.1 R563.1 R567.1 R642.1 R709.2 R720.1 R1208.1 R1226.1 R1249.1 R1250.1 R1251.1 R1252.1 R1253.1 R1262.1 R1560.1 R1561.1 R1562.1 R1570.1 R1582.2 R1593.1 R1738.1 R1739.1 R1742.1 R1746.1 R1780.1 R1782.1 R1790.1 R1792.2 R1793.2 R1794.2 R1795.2 R1796.2 R1797.2 R1798.2 R1799.2 R1800.2 R1804.1 R1805.1 R1809.1 R1810.1 R1812.1 R1813.1 R1815.1 R1817.1 R1818.1 R1819.1 R1830.1 R1832.2 R1843.2 R1845.1 R1910.2 R79659.2 R79736.1 R79737.1 R79786.1 R80120.2 R80145.2 R80151.2 R80220.2 U2.5 U42.1 U42.2 U42.5 U42.6 XDP1.43
1D8V_S5_D: Q1231.6 R1790.2
1D8V_SPI: C116.2 R169.1 R172.1 R186.1 R1593.2 SRCON1.8 U8.8
1D8V_VGA_AVDD: C12344.2 C12346.2 GPU1.AG24 R80138.1
1D8V_VGA_S0: C794.1 C795.1 C796.1 C797.1 C852.1 C853.1 GPU1.AM30 L47.1 L48.1 L49.1 L50.1 L52.1 L4102.2 R935.1 R943.2 R1211.2 R1900.2 R1917.2 R79963.2 R80138.2 R80139.2 U42.4
1D8V_VGA_VDD1DI: C12343.2 C12345.2 GPU1.AE23 R80139.1
1D8V_VGA_VDDR4: C12347.2 C12348.2 GPU1.U12 GPU1.V12 GPU1.Y12 L4102.1
1D24V_S5: C1635.1 C1636.1 C1638.1 C1639.1 C1640.1 C1641.1 C1643.1 C1644.1 C1645.1 C1646.1 C1647.1 CPU2.AC30 CPU2.AC36 CPU2.AD35 CPU2.AD38 CPU2.AF35 CPU2.H44 CPU2.M41 CPU2.P38 CPU2.P40 CPU2.P41 CPU2.T40 CPU2.U35 CPU2.V30 CPU2.V35 CPU2.V36 CPU2.Y25 CPU2.Y27 CPU2.Y36 PR5209.1 R1787.1
1D24V_S5_D: Q1230.6 R1787.2
1D35V_S3_PWRGD: PR5010.2 PU5001.10 R1891.2
1D35V_S3_PWRGD_R: C4230.2 Q48.2 Q1240.S R1891.1
1D35V_VGA_S0: C186.1 C486.1 C489.1 C500.1 C514.1 C557.1 C616.1 C765.1 C766.1 C767.1 C768.1 C769.1 C770.1 C771.1 C772.1 C773.1 C774.1 C775.1 C776.1 C777.1 C778.1 C1851.1 C1852.1 C1853.1 C1856.1 C1857.1 C1858.1 C1859.1 C6710.1 C6711.1 C12328.1 C12329.1 C12330.1 C12332.1 C12333.1 C12336.1 C12338.1 GPU1.H13 GPU1.H16 GPU1.H19 GPU1.J9 GPU1.J10 GPU1.J23 GPU1.J24 GPU1.K9 GPU1.K10 GPU1.K23 GPU1.K24 GPU1.L11 GPU1.L12 GPU1.L13 GPU1.L20 GPU1.L21 GPU1.L22 MEM1.A1 MEM1.A8 MEM1.B2 MEM1.C1 MEM1.C9 MEM1.D2 MEM1.D9 MEM1.E9 MEM1.F1 MEM1.G7 MEM1.H2 MEM1.H9 MEM1.K2 MEM1.K8 MEM1.N1 MEM1.N9 MEM1.R1 MEM1.R9 MEM2.A1 MEM2.A8 MEM2.B2 MEM2.C1 MEM2.C9 MEM2.D2 MEM2.D9 MEM2.E9 MEM2.F1 MEM2.G7 MEM2.H2 MEM2.H9 MEM2.K2 MEM2.K8 MEM2.N1 MEM2.N9 MEM2.R1 MEM2.R9 MEM3.A1 MEM3.A8 MEM3.B2 MEM3.C1 MEM3.C9 MEM3.D2 MEM3.D9 MEM3.E9 MEM3.F1 MEM3.G7 MEM3.H2 MEM3.H9 MEM3.K2 MEM3.K8 MEM3.N1 MEM3.N9 MEM3.R1 MEM3.R9 MEM4.A1 MEM4.A8 MEM4.B2 MEM4.C1 MEM4.C9 MEM4.D2 MEM4.D9 MEM4.E9 MEM4.F1 MEM4.G7 MEM4.H2 MEM4.H9 MEM4.K2 MEM4.K8 MEM4.N1 MEM4.N9 MEM4.R1 MEM4.R9 PC5430.1 PC5434.1 PR79.2 PU7.3 PU7.4 R203.2 R230.2 R885.2 R928.2 R945.2 R1200.1 R1204.1 R1890.1 R1922.2 R1924.2 R79968.2 TC21.1
1P05V_A: PC5439.1 PC5440.1 PC5446.1 PL47001.2 PR9766.2 PR9790.1 PR9791.1 PR9792.1 PR9795.1 PR9799.1 PR9800.1 PR9801.1 PR9802.1 PTC4702.1
1P5V_GUP_FB_M: PC68.2 PR77.1 PR78.2 PU7.2
1P5V_GUP_FB_M1: PC68.1 PR78.1 PR79.1
1P05V_S5: C605.1 C606.1 C607.1 C608.1 C609.1 C612.1 C614.1 C617.1 C618.1 C619.1 C620.1 C621.1 C622.1 C623.1 C624.1 C1661.1 C6719.1 C6720.1 CPU2.AA32 CPU2.AA33 CPU2.AA35 CPU2.AA36 CPU2.AC32 CPU2.AM21 CPU2.AM22 CPU2.AM32 CPU2.AM33 CPU2.AN22 CPU2.AN32 CPU2.G10 CPU2.H10 CPU2.N18 CPU2.U19 CPU2.U22 CPU2.U24 CPU2.U27 CPU2.V18 CPU2.V19 CPU2.V22 CPU2.V24 CPU2.V27 CPU2.V29 CPU2.V33 CPU2.Y30 CPU2.Y32 CPU2.Y33 CPU2.Y35 PR9790.2 PR9791.2 PR9792.2 PR9803.1 R1734.1 R1785.1 R1831.1 R79791.1 R79793.1 R79794.1 R79795.1 R79937.1 R80240.1
1P05V_S5_D: Q1228.3 R1785.2
1P8V_PWR: PC21.1 PC22.1 PC41.1 PL3.2 PR36.1 PR37.1 PR38.1 PR59.1 PR211.1 PR212.1 PR213.1 PTC9.1
1P8V_PWR_BOOT: PR50.1 PU4.10
1P8V_PWR_BOOT_R: PC34.1 PR50.2
1P8V_PWR_CS: PR57.1 PU4.2
1P8V_PWR_FB: PC41.2 PR58.1 PR59.2 PU4.4
1P8V_PWR_LGATE: PQ8.4 PU4.6
1P8V_PWR_PHASE: PC23.1 PC34.2 PL3.1 PQ7.1 PQ7.2 PQ7.3 PQ8.5 PQ8.6 PQ8.7 PQ8.8 PU4.8 R95.2
1P8V_PWR_RF: PR53.1 PU4.5
1P8V_PWR_SNB: PC23.2 PR41.1
1P8V_PWR_UGATE: PR39.1 PU4.9
1P8V_PWR_UGATE_R: PQ7.4 PR39.2 R95.1
1P8V_PWR_V5IN: PC33.2 PR48.2 PU4.7
1P8V_S5_PG: C568.1 PU4.1 R720.2 R721.2 R79949.1
1P15V_S5: PR4812.1 PR5471.2 R1223.2 R1224.2 R1225.2 R1786.1
1P15V_S5_D: Q1229.6 R1786.2
3D3V_AUX_EC: L4101.1 PR8519.1 PR8520.1 Q9649.D R80126.1 R80230.2 R80232.2 U4101.11 U4101.22 U4101.38 U4101.44 U4101.56
3D3V_RUN_FFS: C6701.2 C6702.2 C6703.1 R6701.2 U6701.1 U6701.7 U6701.8 U6701.14
3D3V_VGA_S0: C753.1 C782.1 C783.1 C784.1 GPU1.AA17 GPU1.AA18 GPU1.AB17 GPU1.AB18 PR4.1 PR6.1 PR15.1 PR19.1 PR96.1 PR102.1 PR103.1 PR225.1 PR9769.1 PR9772.1 PR9775.1 PR9776.1 Q123.2 Q123.5 Q9629.D R302.2 R398.2 R1159.2 R1167.1 R1883.1 R1885.1 R1887.1 R1893.2 R1895.2 R79965.2 R80116.1 R80140.1 RN16.3(B) RN16.4(B) U49.3 U49.7 U49.8
1117 ADJ: R79751.2 R79752.1 U119.1
62882_COMP_R: PC6.2 PR8.1
62882_FB_VSEN: PC11.1 PR20.2
62882_NTC_R: PR60.1 PR9782.2
62883AGND: PC5.1 PC9.2 PC20.2 PC58.2 PC60.2 PC5268.2 PC5272.1 PR1.1 PR2.1 PR9.2 PR9782.1 U6706.40 U6706.41
+3D3V_PWR: C1606.1 PC4905.1 PG4902.2 PL4903.1 PR4906.2 PR4908.2 PR4910.2 PR4923.1 PT4902.1
+DCBATOUT_RT8243_1: PC4901.1 PC4902.1 PC4903.1 PC4904.1 PC4916.2 PQ4901.5 PQ4901.6 PQ4901.7 PQ4901.8 PQ4904.5 PQ4904.6 PQ4904.7 PQ4904.8 PR4492.2 PR4493.2 PR4901.1 PR4990.2 PR4991.2 PT4901.1 PU4901.11
+VGA_CORE_PHASE1: PG3.1 PR9779.2
A20GATE: R333.1 R80231.2
AC_IN: PQ5004.D PQ5005.2 PR5281.2
AC_IN_KBC#: TP4124.1 U4101.29
AC_OK#: PQ5004.G PR4427.2 R80208.1 U55.5 U4101.37
AC_OK#_ECIO: R80208.2 U109.99
AC_PRESENT_CPU: CPU2.C13 R1262.2 R1265.1
AC_PROTECT: PQ4408.G PR5287.1 PR5289.2 PR5297.2 PR5298.1 U55.3
AD+_2: PC4201.2 PQ4205.C PR4204.2 PR4207.1 PU4201.4
AD+_G_1: PQ5005.5 PQ5005.6 PR5272.2
AD+_G_2: PR5272.1 PR5275.2 PU5204.4
AD+_TO_SYS: PG4907.1 PR5275.1 PR5276.1 PU5204.1 PU5204.2 PU5204.3 R79707.2 R79708.2 R79709.2 R79710.2 R79711.2
AD_IA: PR5288.2 R80216.1 U4101.48
AD_IA_HW1: PQ5006.5 R79705.1 U109.106 U4101.59
AD_IA_HW2: PQ5006.2 R79704.1 U109.107 U4101.60
AD_JK: C4202.1 DCIN1.1 DCIN2.1 DCIN2.2 DCIN2.3 DCIN2.8 DCIN2.9 DCIN2.10 PC4201.1 PC4202.1 PC4203.1 PC4204.2 PD4202.K PQ4205.E PR4204.1 PR4214.1 PU4201.1 PU4201.2 PU4201.3
AD_OFF: R1867.1 R80210.1 U4101.36
AD_OFF_ECIO: R80210.2 U109.97
AD_OFF_L: PQ4204.C PQ4205.B
ADAPTOR_PSID_R: Q42.S R426.1
ADAPTOR_PSID_R_R: D14.3 R426.2 R430.2 R1602.1
ADAPTOR_PSID_SIO: R1602.2 R80203.1 U109.119
AMD_RST#: C752.1 GPU1.AL27 R1160.1
AMP_GND: C192.1 C193.1 C208.2 C531.2 R344.1 R346.1 R347.1 R355.2 R358.2 R365.2 R1596.1 U21.4
AMP_SPKR_L: C199.1 R355.1 R356.2
AMP_SPKR_R: C210.1 R365.1 R367.2
APU_PROCHOT#: C313.1 PQ4408.D PR4455.1 R1258.1 R1604.1 R1606.1 R79947.1 U4101.14
APU_PROCHOT#_IO: R79947.2 U109.8
APU_PROCHOT#_R: CPU2.AD50 R1258.2
APU_PWNBTN_N: CPU2.M16 R1264.1
APU_PWNBTN_N_R: Q18.C R56.1 R1264.2
APU_SATA_LED_B: Q37.B R342.2
APU_SATA_LED_N: CPU2.AH3 Q9646.4 R342.1 R514.1
APU_SPKR: CPU2.H4 R208.1
AUD_BEEP_C: C130.2 U6.2
AUD_BEEP_R: C130.1 R207.2 R208.2 R210.1
AUD_DMIC_CLK: C121.2 L54.2 WEBCM1.4
AUD_DMIC_CLK_R: R212.1 U6.12
AUD_DMIC_CLK_R_1: L54.1 R212.2
AUD_DMIC_DATA: C132.2 R222.1 WEBCM1.5
AUD_DMIC_DATA_R: R222.2 U6.13
AUD_DVDD: C127.2 C131.2 R205.2 R206.2 U6.7
AUD_GP3: R213.2 U6.3
AUD_LINK_BCLK: C126.2 RN10.4(A) U6.5
AUD_LINK_RST_N: R314.1 RN10.2(A) U6.6
AUD_LINK_RST_N_2: Q63.4 Q63.6
AUD_LINK_RST_N_R: C170.1 Q6711.B R314.2
AUD_LINK_SDIN: CPU2.AD7 R209.1
AUD_LINK_SDIN_1: R209.2 U6.8
AUD_LINK_SDO: C1780.1 Q56.D R618.2 RN10.3(A)
AUD_LINK_SDO_1: C1780.2 Q56.G R617.2
AUD_LINK_SDO_N: Q56.S R618.1 U6.4
AUD_LINK_SYNC: RN10.1(A) U6.9
AUD_REGREF: C129.2 U6.10
AZ_BCLK_M: CPU2.AD9 RN10.5(B)
AZ_RST_N_M: CPU2.AF13 RN10.7(B)
AZ_SDOUT_M: C86.1 CPU2.AF14 RN10.6(B)
AZ_SYNC_M: CPU2.AF12 RN10.8(B)
BAT_ALERT: BAT2.8B R79665.2
BAT_IN#: R1868.1 R79942.1 R80209.1 U4101.5
BAT_IN#_1: BAT2.6B PC4304.1 PL4301.1 R79942.2
BAT_IN#_ECIO: R80209.2 U109.98
BATA_SCL_1: BAT2.4B PC4305.1 PL4302.1 R79940.2
BATA_SDA_1: BAT2.5B PC4301.1 PL4303.1 R79941.2
BATT_AMBER_LED#: R80122.2 U4101.9
BATT_AMBER_LED#_C: PWRCN1.10 R79754.2 R80122.1
BATT_WHITE_LED#: R80123.2 U4101.58
BATT_WHITE_LED#_C: PWRCN1.8 Q36.C Q38.C R80123.1 R80124.2
BIST_DISABLE: R531.2 R533.1 R79670.1 U109.112
BIST_DISABLE_1: Q12.5 R79670.2
BIST_EN: Q12.3 Q12.6 Q13.2 R79683.2
BIST_EN_INV: Q13.3 Q13.6 R517.2 R79681.1 R80235.1 U126.2
BIST_EN_SIO: R311.1 R80235.2 U109.25
BIST_ENABLE: R515.1 U109.113
BIST_ENABLE_1: Q13.5 R515.2 R523.1 R79687.2
BIST_PIN25: Q9650.G R286.1 U109.24
BKLT_ADJ: C33.1 C87.1 R133.2 R79621.2
BKLT_EN: C88.1 Q6710.C R138.2 R139.2 R79625.2
BKLT_EN1: Q6710.B R135.2
BOARD1: CPU2.AH7 R557.1 R561.2
BOARD2: CPU2.AH6 R552.1 R554.2
BOARD3: CPU2.AF7 R553.1 R556.2
BOOT1_PHASE1: PC19.2 PR43.2
BQ24737_CSON_1: PC5236.2 PC5238.1 PG4908.1 PR5277.2
BQ24737_CSOP_1: PC5236.1 PG4906.1 PR5283.2
BQ24737_REGN: PC5233.2 PD4401.A PR5297.1 U55.16
BT+: BAT2.1B BAT2.2B BAT2.3B PC4302.1 PC4303.1 PC4401.1 PC5240.1 PC5241.1 PC5242.1 PG4908.2 PR5269.2 PU5205.5 PU5205.6 PU5205.7 PU5205.8
BT+_R: PG4906.2 PL5003.2 PR5269.1
BUZZER_SPKR_R: C203.1 R207.1
BVCCRTC_EXTPAD: C49.1 CPU2.F16
C_GPP_TXN2: C56.1 CPU2.C26
C_GPP_TXP2: C54.1 CPU2.B26
CAGND: C4.1 C5.2 C10.2 C43.2 C3455.2 C3456.2 C3457.2 C3458.2 C4270.2 R37.2 R61.2 R82.2 R79623.2 R79627.2 R79628.2 U120.15 U120.21
CASA0#: GPU1.G19 MEM1.K3 MEM3.K3
CASA1#: GPU1.G16 MEM2.K3 MEM4.K3
CBN: C150.2 U6.21
CBP: C150.1 U6.24
CFG: R79748.2 U127.23
CHAR_CTL1: R80063.1 U9625.6
CHAR_CTL2: R80064.1 U9625.7
CHAR_CTL3: R80065.1 U9625.8
CHAR_EN: Q9643.3 R80062.1 U9625.5
CHAR_EN_CPU: CPU2.AE4 Q9643.2 R1795.1
CHAR_ILIM_HI: R80049.1 U9625.16
CHAR_ILIM_LO: R80060.1 U9625.15
CHAR_ILIM_SEL: R80059.1 U9625.4
CHAR_STATUS: TP4118.1 U9625.9
CHAR_USBOC#: R80061.1 U9625.13
CHG_AGND: PC4403.2 PC4404.2 PC4408.2 PC5232.2 PC5238.2 PC5239.2 PQ5006.1 PQ5006.4 PR4412.2 PR5268.2 PR5274.2 PR5468.2
CHG_ON#: PQ5003.G PR5273.2 R1870.1 R80207.1 U4101.17
CHG_ON#_ECIO: R80207.2 U109.101
CHG_SMB2_CLK: PR4425.2 R380.1 R79940.1 U55.9 U4101.35
CHG_SMB2_DATA: PR4426.2 R379.1 R79941.1 U55.8 U4101.34
CK_25M_SIO: C80.1 R664.2 R79699.2 U109.44
CK_48M_SIO: OSC2.3 R318.1
CK_GLAN_DN: CPU2.A17 U20.16
CK_GLAN_DP: CPU2.C17 U20.15
CK_M_DDR0_A_DN: CPU2.BF40 DIMM1.103
CK_M_DDR0_A_DP: CPU2.BD40 DIMM1.101
CK_M_DDR1_A_DN: CPU2.BF38 DIMM1.104
CK_M_DDR1_A_DP: CPU2.BD38 DIMM1.102
CK_P_33M_EC: R79699.1 U4101.2
CK_PCIEX1_WLAN_DN: CPU2.B18 R23.2
CK_PCIEX1_WLAN_DP: CPU2.C18 R22.2
CK_PE_100M_16PORT_DN: CPU2.C21 GPU1.AK32
CK_PE_100M_16PORT_DP: CPU2.A21 GPU1.AK30
CKEA0: GPU1.K20 MEM1.K9 MEM3.K9
CKEA1: GPU1.J17 MEM2.K9 MEM4.K9
CLINK_CLK_LAN: NGFF1.42 TP67.1
CLINK_DATA_LAN: NGFF1.40 TP66.1
CLINK_RST_LAN_N: NGFF1.38 TP65.1
CLK_48M_SIO_C: R318.2 U109.34
CLK_DIFF_N4: CPU2.B16 R1267.2
CLK_DIFF_P4: CPU2.C16 R1267.1
CLKA0: GPU1.H26 MEM1.J7 MEM3.J7 R1907.1
CLKA0#: GPU1.H25 MEM1.K7 MEM3.K7 R1906.1
CLKA1: GPU1.G9 MEM2.J7 MEM4.J7 R1909.1
CLKA1#: GPU1.H9 MEM2.K7 MEM4.K7 R1908.1
CLKTESTA: C764.1 GPU1.K8
CLKTESTA_C: C764.2 R1207.1
CLKTESTB: C763.1 GPU1.L7
CLKTESTB_C: C763.2 R1206.1
COREPWROK: C111.2 CPU2.G16 R178.1 R181.2 R184.2 R1820.1
COREPWROK_XDP: R1820.2 XDP1.45
CPU_FAN_CTRL_SIO: R68.1 U109.6
CPU_FAN_TACH_SIO: R74.1 U109.5
CPU_HPD: CPU2.R51 Q6703.D R498.1
CPU_LVDS_BL_ADJ: CPU2.P52 R80219.1 R80220.1 R80236.1
CPU_LVDS_BL_ADJ_B: C29.1 Q21.2 R80219.2
CPU_LVDS_BL_ADJ_C: Q21.5 Q21.6 R50.1
CPVEE: C1491.1 U6.20
CSA0#_0: GPU1.H22 MEM1.L2 MEM3.L2
CSA1#_0: GPU1.G13 MEM2.L2 MEM4.L2
CTF_TRIP: C755.2 Q9625.B R79967.2
CTFB: Q9625.C R1920.2 R79964.2
DBG0: CPU2.AM40 XDP1.9
DBG1: CPU2.AM41 XDP1.11
DBG2: CPU2.AM44 XDP1.15
DBG3: CPU2.AM45 XDP1.17
DBG4: CPU2.AM47 XDP1.27
DBG5: CPU2.AK48 XDP1.29
DBG6: CPU2.AM48 XDP1.33
DBG7: CPU2.AK41 XDP1.35
DBG8: CPU2.AB41 XDP1.10
DBG9: CPU2.AB45 XDP1.12
DBG10: CPU2.AB44 XDP1.16
DBG11: CPU2.AC53 XDP1.18
DBG12: CPU2.AB51 XDP1.28
DBG13: CPU2.AB52 XDP1.30
DBG14: CPU2.AA51 XDP1.34
DBG15: CPU2.AB40 XDP1.36
DBG16: CPU2.AK42 XDP1.21
DC_19V: PC5235.2 PR5270.1 PR5282.1 PR5284.1 PR5285.1 PR9813.1 PU4201.5 PU4201.6 PU4201.7 PU4201.8 PU5204.5 PU5204.6 PU5204.7 PU5204.8 PU5205.4 R79707.1 R79708.1 R79709.1 R79710.1 R79711.1
DC_IN_D: PQ5005.3 PR5282.2
DCBATOUT: C32.1 C12339.1 C12340.1 C12341.1 F16.1 L10.1 PC24.1 PC61.1 PC4405.1 PC4406.1 PC4407.1 PC5235.1 PC5269.1 PC5270.1 PC5273.2 PG4905.1 PR46.2 PR47.2 PR101.1 PR4429.1 PR4458.1 PR4490.1 PR4491.1 PR4492.1 PR4493.1 PR4529.1 PR4590.1 PR4591.1 PR4790.1 PR4791.1 PR4990.1 PR4991.1 PR5090.1 PR5091.1 PR5276.2 PR9788.1 PR9789.1 PT2.1 PU1.5 PU1.6 PU1.7 PU1.8 PU2.5 PU2.6 PU2.7 PU2.8 PU4403.5 PU4403.6 PU4403.7 PU4403.8 PU5205.1 PU5205.2 PU5205.3 R20.1 R26.1 R153.1 R163.1 R273.1 R1164.1 R1918.1 R79631.1 R79915.1
DCBATOUT_1D8V: PC28.1 PC29.1 PC31.1 PC32.1 PQ7.5 PQ7.6 PQ7.7 PQ7.8 PR46.1 PR47.1
DCIN_EN: R79749.2 U127.13
DDC1L_GPU_CLK: GPU1.AE6 R80092.2
DDC1L_GPU_DATA: GPU1.AE5 R80093.2
DDCBUF: R79743.1 R79744.2 U127.14
DDI0_DDCCLK: CPU2.T51 R1234.2
DDI0_DDCDATA: CPU2.T52 R1268.2
DDI0_HPD: CPU2.U51 R1226.2 R1892.2
DDI0_RCOMP_N: CPU2.G38 R1228.1
DDI0_RCOMP_P: CPU2.F38 R1228.2
DDI1_RCOMP_N: CPU2.F49 R1227.1
DDI1_RCOMP_P: CPU2.F47 R1227.2
DDPC_CTRL_CLK_CONN: HDMI1.15 HDMI2.5 Q1255.D R79733.1 R79738.2 U127.32 U130.1 U130.10
DDPC_CTRL_DATA_CONN: HDMI1.16 HDMI2.4 Q1256.D R79732.1 R79739.2 U127.33 U130.2 U130.9
DDR3_DRAM_PWROK: C575.2 CPU2.AV28 R532.1 R537.2
DDR3_DRAM_PWROK_D: Q48.3 R532.2
DDR3_DRAMRST_N: C576.2 CPU2.BA42 R1672.2
DDR3_DRAMRST_N_A_1: C47.1 DIMM1.30 R1672.1
DDR3_VCCA_PWRGD: C380.2 C574.2 CPU2.AV26 Q49.3 R543.2 R550.2
DDR3_VCCA_PWRGD_3P3: Q49.2 R1601.1
DDR3_VCCA_PWRGD_G: Q49.5 Q49.6 R551.2
DDR3_VREF_CA: C372.2 C385.1 CPU2.AT28 R539.2
DDR3_VREF_CA_R: R539.1 R542.1 R545.2
DDR3_VREF_DQ: C572.1 C573.2 CPU2.AU28 R1214.2
DDR3_VREF_DQ_R: R1214.1 R1215.2 R1216.1
DDR_VDDQ: C60.2 C61.2 C62.2 C63.2 C64.2 C65.2 C66.2 C67.2 C68.2 C69.2 C70.2 C71.2 C76.2 C77.2 C78.2 C79.2 C641.1 C642.1 C643.1 C644.1 CPU2.AM18 CPU2.AM36 CPU2.AN18 CPU2.AN19 CPU2.AN35 CPU2.AN36 CPU2.AU18 CPU2.AU36 CPU2.AV10 CPU2.AV16 CPU2.AV38 CPU2.AV44 CPU2.AY10 CPU2.AY44 CPU2.BE1 CPU2.BE3 CPU2.BE51 CPU2.BE53 CPU2.BG3 CPU2.BG51 CPU2.BH4 CPU2.BH5 CPU2.BH49 CPU2.BH50 CPU2.BJ2 CPU2.BJ3 CPU2.BJ5 CPU2.BJ49 CPU2.BJ51 CPU2.BJ52 DIMM1.75 DIMM1.76 DIMM1.81 DIMM1.82 DIMM1.87 DIMM1.88 DIMM1.93 DIMM1.94 DIMM1.99 DIMM1.100 DIMM1.105 DIMM1.106 DIMM1.111 DIMM1.112 DIMM1.117 DIMM1.118 DIMM1.123 DIMM1.124 PR5003.2 PR5004.2 PR5005.2 PR5006.2 PR5007.2 PR5008.2 R117.1 R484.1 R537.1 R543.1 R545.1 R550.1 R572.1 R1215.1 R1244.1 R1245.1
DDSP_C_HPD_CONN: HDMI1.19 HDMI2.1 R80113.2 U127.28 U130.4 U130.7
DDSP_D_TX_N0: Q1254.D R79724.2 R79725.2 R79726.2 R79727.2 R79728.2 R79729.2 R79730.2 R79731.2
DDSP_D_TX_N2: Q1254.G R79723.2
DGPU_PWROK: PR6.2 PR14.2 PR5261.2 PR9785.2 Q97.5
DGPU_PWROK_1D5V: PC5433.1 PR5261.1 PU7.8
DIMM1_SA0: DIMM1.197 R579.1
DIMM1_SA1: DIMM1.201 R581.1
DIMM_TMPIN2+: C231.2 R397.1 RT1.1 U109.86
DIMM_TMPIN2-: C231.1 R399.2 RT1.2
DISCHANGE_EN: R1841.1 R79945.1 U109.20
DP1_AUXN: C4269.1 R1074.2 R80091.2 R80100.2
DP1_AUXP: C4268.1 R1079.1 R80090.2 R80099.2
DP1_HPD: Q6703.G R80237.1
DP1_TXN0: C301.1 R80075.1 R80078.2
DP1_TXN1: C4267.1 R80077.1 R80080.2
DP1_TXP0: C300.1 R80074.1 R80079.2
DP1_TXP1: C4265.1 R80076.1 R80081.2
DP_AUXN: NGFF1.20 TP73.1
DP_AUXP: NGFF1.22 TP72.1
DP_CPU_AUXN: CPU2.K42 R80100.1
DP_CPU_AUXP: CPU2.M42 R80099.1
DP_CPU_TXN0: CPU2.H51 R80075.2
DP_CPU_TXN1: CPU2.K52 R80077.2
DP_CPU_TXP0: CPU2.J51 R80074.2
DP_CPU_TXP1: CPU2.K51 R80076.2
DP_GPU_AUXN: GPU1.AD11 R80091.1
DP_GPU_AUXP: GPU1.AD13 R80090.1
DP_GPU_TXN0: GPU1.AK22 R80078.1
DP_GPU_TXN1: GPU1.AJ21 R80080.1
DP_GPU_TXP0: GPU1.AL23 R80079.1
DP_GPU_TXP1: GPU1.AH22 R80081.1
DP_HPD: NGFF1.31 TP78.1
DP_ML0N: NGFF1.32 TP69.1
DP_ML0P: NGFF1.34 TP68.1
DP_ML1N: NGFF1.26 TP71.1
DP_ML1P: NGFF1.28 TP70.1
DP_ML2N: NGFF1.25 TP76.1
DP_ML2P: NGFF1.27 TP77.1
DP_ML3N: NGFF1.19 TP74.1
DP_ML3P: NGFF1.21 TP75.1
DPLL_PVDD: C827.1 C829.1 C830.1 GPU1.AF14 GPU1.AF16 GPU1.AG15 GPU1.AG16 GPU1.AG17 GPU1.AG18 GPU1.AG19 L52.2
DPLL_VDDC: C825.1 C826.1 C828.1 GPU1.AD14 GPU1.AF22 GPU1.AG20 GPU1.AG21 GPU1.AG22 L53.2
DPLVDS_AUXN: C4269.2 U126.3
DPLVDS_AUXP: C4268.2 U126.4
DPLVDS_BL_EN: R1985.2 R79939.1 U126.44
DPLVDS_EDIDCLK: C1827.1 R32.2 R35.2 U126.46
DPLVDS_EDIDCLK_C: R35.1 U25.6
DPLVDS_EDIDSDA: C7.1 R79668.2 R79673.2 U126.45
DPLVDS_EDIDSDA_C: R79668.1 U25.5
DPLVDS_FWCLK: C9.1 R79678.2 U126.48
DPLVDS_FWSDA: C4266.1 R79677.2 U126.47
DPLVDS_HPD: R79675.1 U126.1
DPLVDS_ISPCLK: Q7.1 Q95.4 R69.2 U126.13
DPLVDS_ISPDAT: Q4.1 Q95.1 R79686.2 U126.14
DPLVDS_PANEL_VCC: R39.2 U126.20
DPLVDS_PIN12: R511.1 U126.12
DPLVDS_PIN16: R507.2 U126.16
DPLVDS_PWMIN: R501.1 R503.2 R79682.1 R80134.1 U126.21
DPLVDS_PWMOUT: R1984.2 U126.19
DQMA0: GPU1.E32 MEM3.E7
DQMA1: GPU1.E30 MEM3.D3
DQMA2: GPU1.A21 MEM1.D3
DQMA3: GPU1.C21 MEM1.E7
DQMA4: GPU1.E13 MEM4.E7
DQMA5: GPU1.D12 MEM2.D3
DQMA6: GPU1.E3 MEM2.E7
DQMA7: GPU1.F4 MEM4.D3
DRAM_RCOMP_0: CPU2.BA28 R527.2
DRAM_RST: C839.1 GPU1.L10 R1202.1 R1205.1
DRAM_RST_R: C762.1 R1202.2 R79962.1
DRX0N: C301.2 U126.8
DRX0P: C300.2 U126.7
DRX1N: C4267.2 U126.10
DRX1P: C4265.2 U126.9
EAPD_DEPOP: R635.1 U6.14
EAPD_DEPOP_1: R634.1 R635.2 R636.1
EAPD_DEPOP_2: Q63.2 R636.2
EC_3P3_CTL: C6724.2 PR8521.2 Q9648.G
EC_3P3_CTL_2: C6725.1 Q9649.G R80229.2
EC_3P3_CTL_3: Q9648.D R80228.1 R80229.1
EC_A20GATE: R80231.1 U109.43
EC_EUP: R304.1 R305.1 U109.127
EC_EUP_EN: C180.1 Q6706.G R305.2 R725.2
EC_HDMI_PD_N: Q1257.G R79750.2 U109.105
EC_IMS: R79951.2 U109.52
EC_PSID: R80203.2 U4101.12
EC_PWREN: PR8521.1 R363.1 R366.1 U109.57
EC_SCI: R80132.1 U4101.15
EC_SMB2_CLK: PR8519.2 R80204.1 U4101.32
EC_SMB2_DATA: PR8520.2 R80205.1 U4101.33
EC_VCORF: C4101.1 U4101.20
ECIO_GP26: R79762.1 U109.18
ECIO_GP32: R79759.1 U109.14
ECIO_GP34: R79761.1 U109.12
ECIO_GP63: R316.1 U109.3
EDM_SOC: CPU2.M13 R1257.2
EEPROM_WP: R179.1 R180.2 U9.7
EQ: R79734.1 R79735.2 U127.17
EXT_RST#: R80125.1 R80126.2 U4101.41
F_USB0N: CPU2.B42 TR4.2
F_USB0N_H: CPU2.A45 TR1.3
F_USB0P: CPU2.C42 TR4.3
F_USB0P_H: CPU2.C45 TR1.2
F_USB1N: CPU2.B44 R80050.1 U9625.2
F_USB1N_H: TR12.4 U6702.6
F_USB1P: CPU2.C43 R80052.1 U9625.3
F_USB1P_H: TR12.1 U6702.7
F_USB2N: TR7.3 U6702.12
F_USB2N_H: CPU2.A41 TR13.4
F_USB2P: TR7.2 U6702.13
F_USB2P_H: CPU2.C41 TR13.1
F_USB3N: TR5.2 U6702.15
F_USB3N_H: TR28.3 U6702.3
F_USB3N_SD: SU1.2 TR28.4
F_USB3P: TR5.3 U6702.16
F_USB3P_H: TR28.2 U6702.4
F_USB3P_SD: SU1.3 TR28.1
FALL_INT2: Q6701.2 Q6701.3 R6703.2
FAN_CTRL_POWER: R79913.1 R79936.2 U109.125
FAN_OFF_D: Q1227.D R79915.2 R79916.1 R79917.1
FAN_OFF_G: Q1227.G R79913.2
FAN_OFF_G2: C12324.1 C12325.1 Q9624.G R79917.2
FFS_INT1: Q6702.2 R6702.2 R79756.2 U109.110
FFS_INT1_C: R79756.1 U6701.11
FFS_INT2_APU: Q6715.2 R79755.2
FFS_INT2_C: Q6701.5 R6704.2 R6706.1 R79755.1 R79757.1 U6701.9
FFS_INT2_Q: Q6701.6 R6705.2 R6706.2 SATAP1.5
FWH_ID0: LPC1.6 R317.2
GP_CAMERASB09: CPU2.Y42 R1558.1 R1819.2
GP_CAMERASB11: CPU2.V40 R1557.1 R1818.2
GPIO17_THERMAL_INT: GPU1.R6 R1884.2 R1887.2 R1896.2
GPIO19_CTF: GPU1.M2 R1886.1 R79966.2
GPIO19_CTF_R: D5209.3 R1894.1 R1896.1 R79966.1 R79967.1
GPIO_8_ROMSO: GPU1.P10 R1169.1
GPIO_9_ROMSI: GPU1.P4 R1171.2
GPIO_10_ROMSCK: GPU1.P2 R1170.2
GPIO_22_ROMCS#: GPU1.N8 R1168.1
GPIO_RCOMP18: CPU2.AH40 R79787.2
GPIO_SUS0: CPU2.AD51 R1562.2 R1801.1
GPIO_SUS1: CPU2.AD52 R1570.2 R1802.1
GPIO_SUS2: CPU2.AH50 R1803.1 R1804.2
GPIO_SUS3: CPU2.AH48 R1805.2 R1806.1
GPIO_SVC: GPU1.AJ11 TP165.1
GPIO_SVD: GPU1.AK12 TP163.1
GPIO_SVT: GPU1.AL11 TP164.1
GPIO_VGA_03_DATA: Q123.4 R1165.1 RN16.2(A)
GPIO_VGA_03_DATA_R: GPU1.U8 R1165.2
GPIO_VGA_04_CLK: Q123.1 R1166.1 RN16.1(A)
GPIO_VGA_04_CLK_R: GPU1.U7 R1166.2
GPU_CLKA0_T: C1855.2 R1906.2 R1907.2
GPU_CLKA1_T: C12331.2 R1908.2 R1909.2
GPU_DMINUS: C524.2 GPU1.T2 R651.2 RT2.2
GPU_DP_DET_CN: GPU1.Y9 R80115.1
GPU_DPLUS: C524.1 GPU1.T4 R658.1 RT2.1 U109.85
GPU_GPIO16: GPU1.M4 TP155.1
GPU_HDMI_DET_CN: GPU1.AC14 R3586.2
GPU_HSYNC: GPU1.AH26 R80140.2 R80141.2
GPU_LVDS_BL_ADJ: GPU1.AB11 R80134.2
GPU_SCL: GPU1.R1 TP149.1
GPU_SDA: GPU1.R3 TP150.1
GPU_THERM_SHUTDOWN*: PR18.1 R79964.1
GPU_THERMAL_INT: R1884.1 R1885.2 R79773.1 U109.28
GPU_VCC3_CTL: C1864.1 PR5476.2 Q9628.G R1126.1
GPU_VCC3_CTL_2: C836.1 Q9629.G R1195.2
GPU_VCC3_CTL_3: Q9628.D R1129.1 R1195.1
GPU_VREFG: C1846.1 GPU1.AC16 R1210.2 R1211.1
GPU_WAKEB: GPU1.AJ27 R1883.2 R80142.2
GPU_XO_IN: GPU1.AC22 R1880.1
GPU_XO_IN2: GPU1.AB22 R1881.1
H_VID0: GPU1.T8 PR9768.1 PR9772.2 PR9774.1
H_VID1: GPU1.N1 PR103.2 PR9770.1 PR9773.1
H_VID2: GPU1.P8 PR35.1 PR102.2 PR9780.1
H_VID3: GPU1.AK10 PR32.1 PR33.1 PR9769.2
H_VID4: GPU1.AM10 PR30.1 PR31.1 PR9776.2
H_VID5: GPU1.T9 PR25.1 PR26.1 PR96.2
H_VID6: PR23.1 PR5251.1 PR9775.2
HDD_FALL_INT2_C: CPU2.M6 Q6715.3 R79799.1
HDM2_CPU_HPD: CPU2.W51 Q1246.D R1910.1
HDMI1_DATA_IC_N0: C4294.2 U127.2
HDMI1_DATA_IC_N1: C4298.2 U127.5
HDMI1_DATA_IC_N2: C4297.2 U127.7
HDMI1_DATA_IC_N3: C4291.2 U127.10
HDMI1_DATA_IC_P0: C4295.2 U127.1
HDMI1_DATA_IC_P1: C4296.2 U127.4
HDMI1_DATA_IC_P2: C4293.2 U127.6
HDMI1_DATA_IC_P3: C4292.2 U127.9
HDMI2_HPD: Q1246.G U127.3
HDMI_CTRL_CLK: CPU2.Y51 R79736.2 U127.38
HDMI_CTRL_DATA: CPU2.Y52 R79737.2 U127.39
HDMI_DATA_CPU_N0: C4294.1 CPU2.C51
HDMI_DATA_CPU_N1: C4298.1 CPU2.H50
HDMI_DATA_CPU_N2: C4297.1 CPU2.F52
HDMI_DATA_CPU_N3: C4291.1 CPU2.G52
HDMI_DATA_CPU_P0: C4295.1 CPU2.D50
HDMI_DATA_CPU_P1: C4296.1 CPU2.H49
HDMI_DATA_CPU_P2: C4293.1 CPU2.F53
HDMI_DATA_CPU_P3: C4292.1 CPU2.G53
HDMI_DATA_GPU_N0: C4279.1 GPU1.AJ17
HDMI_DATA_GPU_N1: C4274.1 GPU1.AK16
HDMI_DATA_GPU_N2: C4276.1 GPU1.AJ15
HDMI_DATA_GPU_N3: C4278.1 GPU1.AK14
HDMI_DATA_GPU_P0: C4272.1 GPU1.AH18
HDMI_DATA_GPU_P1: C4273.1 GPU1.AL17
HDMI_DATA_GPU_P2: C4275.1 GPU1.AH16
HDMI_DATA_GPU_P3: C4277.1 GPU1.AL15
HDMI_DP2_HPD: C4280.2 D33.K R79732.2 R79733.2 R79738.1 R79739.1
HDMI_GPU_CTRL_CLK: Q1255.S R80092.1 R80110.2
HDMI_GPU_CTRL_DATA: Q1256.S R80093.1 R80111.2
HDMI_HTPLG_CN1: Q2301.D R80113.1 R80157.2
HDMI_LANE0_DN: HDMI1.3 HDMI2.17 TR20.3 TR24.2 U129.2 U129.9
HDMI_LANE0_DN_C: C4279.2 R79724.1 TR20.4
HDMI_LANE0_DP: HDMI1.1 HDMI2.19 TR20.2 TR24.3 U129.1 U129.10
HDMI_LANE0_DP_C: C4272.2 R79726.1 TR20.1
HDMI_LANE0_IC_DN: TR24.1 U127.29
HDMI_LANE0_IC_DP: TR24.4 U127.30
HDMI_LANE1_DN: HDMI1.6 HDMI2.14 TR21.3 TR25.2 U129.5 U129.6
HDMI_LANE1_DN_C: C4274.2 R79725.1 TR21.4
HDMI_LANE1_DP: HDMI1.4 HDMI2.16 TR21.2 TR25.3 U129.4 U129.7
HDMI_LANE1_DP_C: C4273.2 R79728.1 TR21.1
HDMI_LANE1_IC_DN: TR25.1 U127.26
HDMI_LANE1_IC_DP: TR25.4 U127.27
HDMI_LANE2_DN: HDMI1.9 HDMI2.11 TR22.3 TR26.2 U131.4 U131.7
HDMI_LANE2_DN_C: C4276.2 R79727.1 TR22.4
HDMI_LANE2_DP: HDMI1.7 HDMI2.13 TR22.2 TR26.3 U131.5 U131.6
HDMI_LANE2_DP_C: C4275.2 R79729.1 TR22.1
HDMI_LANE2_IC_DN: TR26.1 U127.24
HDMI_LANE2_IC_DP: TR26.4 U127.25
HDMI_LANE3_DN: HDMI1.12 HDMI2.8 TR23.3 TR27.2 U131.1 U131.10
HDMI_LANE3_DN_C: C4278.2 R79730.1 TR23.4
HDMI_LANE3_DP: HDMI1.10 HDMI2.10 TR23.2 TR27.3 U131.2 U131.9
HDMI_LANE3_DP_C: C4277.2 R79731.1 TR23.1
HDMI_LANE3_IC_DN: TR27.1 U127.21
HDMI_LANE3_IC_DP: TR27.4 U127.22
HM_VCCP: G5.2 R653.1
HM_VCCP_R: C525.2 R653.2 U109.95
HPOL_CON: C134.1 Q57.1 R220.2 R221.1 R223.2 R225.2 UHS1.1
HPOR_CON: C159.1 Q57.2 R262.2 R281.1 R284.2 R627.2 UHS1.2
HPOUT-JD: R267.1 UHS1.6
HPOUT-L: R220.1 U6.26
HPOUT-R: R284.1 U6.27
HSI_C_DN2: CPU2.F22 R1609.2
HSI_C_DP2: CPU2.D22 R1608.2
HSI_LAN_DN1_R: C201.1 U20.18
HSI_LAN_DN3: C201.2 CPU2.J24
HSI_LAN_DP1_R: C204.1 U20.17
HSI_LAN_DP3: C204.2 CPU2.G24
HSO_C_DN2: C56.2 R1611.2
HSO_C_DP2: C54.2 R1610.2
HSO_C_LAN_DN3: C316.2 U20.14
HSO_C_LAN_DP3: C315.2 U20.13
HSO_LAN_DN3: C316.1 CPU2.C27
HSO_LAN_DP3: C315.1 CPU2.A27
HUB_AVDD: C105.2 C397.2 C400.2 C401.1 C402.1 R577.2 U6702.5 U6702.9 U6702.14
HUB_DVDD: C93.2 C94.2 C393.1 L3.1 R158.2 R180.1 R569.1 R577.1 R79702.1 R79703.1 R79943.1 TC10.2 U9.8 U6702.28
HUB_DVDD_R: L3.2 U6702.21
HUB_PGANG: R155.1 U6702.23
HUB_PSELF: R156.2 R569.2 U6702.22
HUB_RESET#: C101.1 R79701.2 R79702.2 U6702.17
HUB_RREF: R174.1 U6702.8
HUB_SDA: R158.1 U9.5 U6702.26
HUB_TEST/SCL: U9.6 U6702.18
HUB_VCC: R157.2 U6702.27
HUB_X1: C106.2 U6702.10 X3.3
HUB_X2: C107.2 U6702.11 X3.1
I2C0_SCL: CPU2.AK6 R1792.1
I2C1_SCL: CPU2.AF6 R1793.1
I2C2_SCL: CPU2.AF9 R1794.1
I2C4_SCL: CPU2.AC1 R1796.1
I2C5_SCL: CPU2.AB2 R1797.1
I2C6_SCL: CPU2.AA1 R1798.1
ICH_RSMRST_N_R: R1592.2 U109.82
ICLKICOMP: CPU2.P20 R1242.2
ICLKRCOMP: CPU2.N20 R524.2
IMS: LVDS1.4 R79661.2 R79758.1 R79951.1
INIT_3V: LPC1.2 R324.2
INT_SERIRQ_CPU: CPU2.T2 Q1253.3 R79688.1 U35.3
INT_SERIRQ_OE: R645.2 R646.1 U35.5
INT_TP#: CPU2.AH51 R1561.2 R1807.1
IO_SMI_N: CPU2.AM10 R510.1 R642.2 R79946.1 U4101.13
IO_SMI_R: R79946.2 U109.9
ISEN1: R79712.2 U120.17
ISEN2: R53.2 U120.16
ISEN3: R79713.2 U120.14
ISEN4: R79715.2 U120.13
ISET: R79741.1 R79742.2 U127.34
ISP_CLK1: Q7.3 Q7.6 R79679.2
ISP_DAT1: Q4.3 Q4.6 R79669.2
ISW: C10.1 R79630.2 U120.19
ISW_1: Q1250.1 Q1250.2 Q1250.3 R27.1 R79622.1 R79630.1
JACK_PSID: DCIN1.3 DCIN2.4 DCIN2.11 L22.1
JDREF: R268.1 U6.35
JENK#: TP4125.1 U4101.28
JTAG_TCK_VGA: GPU1.L3 R963.1
JTAG_TDI_VGA: GPU1.L5 R79965.1
JTAG_TDO_VGA: GPU1.K4 R1895.1
JTAG_TMS_VGA: GPU1.L1 R398.1
JTAG_TRST#_VGA: GPU1.L6 R1893.1
KBCLK: RN8.3(A) U109.78
KBRST: R330.1 U109.42
KDAT: RN8.4(A) U109.77
LAD0_FWH0: CPU2.M3 LPC1.5 R79956.2 RN5.4(A) U109.38
LAD0_FWH0_EC: R79956.1 U4101.62
LAD1_FWH1: CPU2.M2 LPC1.7 R79955.2 RN5.3(A) U109.39
LAD1_FWH1_EC: R79955.1 U4101.63
LAD2_FWH2: CPU2.N3 LPC1.9 R79954.2 RN5.2(A) U109.40
LAD2_FWH2_EC: R79954.1 U4101.64
LAD3_FWH3: CPU2.N1 LPC1.11 R79700.2 RN5.1(A) U109.41
LAD3_FWH3_EC: R79700.1 U4101.1
LAN_DISABLE_C: R374.1 R378.1 R704.1 R739.2
LAN_DISABLE_N: R374.2 U109.58
LAN_DISABLE_N_1: C558.1 Q74.B R701.1 R704.2
LAN_DISABLE_N_2: Q74.C Q75.B R701.2 R702.2
LAN_DISABLE_N_3: Q75.C Q76.C R705.2 R706.1
LAN_DISABLE_N_4: C559.1 PC163.2 Q39.G R706.2
LAN_DISABLE_V3: C561.1 Q76.B R707.1
LAN_LEDACT_R#: RJ1.10 UR5.2
LAN_MDI0_C_DN: RJ1.2 XF1.2
LAN_MDI0_C_DP: RJ1.1 XF1.1
LAN_MDI0_DN: U20.2 U121.3 XF1.11
LAN_MDI0_DP: U20.1 U121.4 XF1.12
LAN_MDI1_C_DN: RJ1.6 XF1.6
LAN_MDI1_C_DP: RJ1.3 XF1.5
LAN_MDI1_DN: U20.5 U121.1 XF1.7
LAN_MDI1_DP: U20.4 U121.6 XF1.8
LAN_MDI2_C_DN: RJ1.5 XF2.5
LAN_MDI2_C_DP: RJ1.4 XF2.6
LAN_MDI2_DN: PR5250.2 U122.3 XF2.8
LAN_MDI2_DN_R: PR5250.1 U20.7
LAN_MDI2_DP: PR5249.2 U122.4 XF2.7
LAN_MDI2_DP_R: PR5249.1 U20.6
LAN_MDI3_C_DN: RJ1.8 XF2.1
LAN_MDI3_C_DP: RJ1.7 XF2.2
LAN_MDI3_DN: PR5248.2 U122.1 XF2.12
LAN_MDI3_DN_R: PR5248.1 U20.10
LAN_MDI3_DP: PR5247.2 U122.6 XF2.11
LAN_MDI3_DP_R: PR5247.1 U20.9
LAN_RSET: R377.2 U20.31
LAN_XTALI: C205.1 R369.2 U20.28 X4.1
LAN_XTALO: C212.1 R369.1 U20.29 X4.3
LANCLK_REQ_U_N: Q47.3 R516.1 U20.12
LDR: R79714.2 U120.1
LDR_1: Q1250.4 R79714.1
LDRQ#: R303.1 R79957.2 U109.2
LDRQ#_EC: R79957.1 U4101.61
LED_5VSB: LED2.A R306.2
LEDC_ISET: R82.1 U120.12
LFRAMEJ_FW4: CPU2.P3 LPC1.13 R146.2 R149.2 R79698.2 U109.37
LFRAMEJ_FW4_EC: R79698.1 U4101.3
LINE2-VREFO: R261.1 R272.1 U6.29
LINEOUT-JD: LOUT1.Q R266.1
LINEOUT-L: R429.1 U6.19
LINEOUT-R: R428.1 U6.18
LINEOUT_C-L: L62.1 R429.2
LINEOUT_C-R: L20.1 R428.2
LINEOUT_CON-L: C268.2 L62.2 LOUT1.4 Q46.1
LINEOUT_CON-R: C267.2 L20.2 LOUT1.1 Q46.2
LINK_ACTIVITY_N: U20.27 U6705.4 UR5.1
LINK_PWR: R79618.2 RJ1.9
LPC_CLK0_R: CPU2.P2 R664.1
LPC_CLK1: C84.1 LPC1.1 R1571.2
LPC_CLK1_R: CPU2.R3 R1571.1
LPC_CLKRUN#: CPU2.T3 R79662.2
LPC_PME_N: CPU2.AD2 R392.2 R79948.2 R80132.2
LPC_PME_R: R79948.1 U109.70
LPE_I2S2_DATAOUT_1: Q1205.D R544.1 TXE1.1
LPF: C3455.1 U120.9
LVDS_BL_ADJ: R131.1 R132.1 R133.1 R134.2 R1984.1
LVDS_BL_EN_1: R79939.2 U109.54
LVDS_DET_A*: LVDS1.17 R482.2 U109.116
LVDS_DET_B*: Q103.D R79657.2 U109.117
LVDS_DET_B_C*: C869.1 LVDS1.1 Q103.G
LVDS_PU_5: LVDS1.5 R1163.2
LVDS_PU_5_1: Q9647.D R79656.1
LVDS_PU_6: LVDS1.6 R79656.2
LVDS_PU_24: LVDS1.24 R481.2
LX: D32.A L61.2 Q1250.5 Q1250.6 Q1250.7 Q1250.8
M1_SMB_CLK: NGFF1.60 R14.2
M1_SMB_DATA: NGFF1.58 R1622.2
M_CAS_A_N: CPU2.BG45 DIMM1.115
M_DATA_A0: CPU2.AK51 DIMM1.4
M_DATA_A1: CPU2.AL51 DIMM1.5
M_DATA_A2: CPU2.AT52 DIMM1.15
M_DATA_A3: CPU2.AR51 DIMM1.17
M_DATA_A4: CPU2.AL53 DIMM1.7
M_DATA_A5: CPU2.AK52 DIMM1.6
M_DATA_A6: CPU2.AR53 DIMM1.16
M_DATA_A7: CPU2.AP51 DIMM1.18
M_DATA_A8: CPU2.AP48 DIMM1.22
M_DATA_A9: CPU2.AT47 DIMM1.23
M_DATA_A10: CPU2.AY48 DIMM1.33
M_DATA_A11: CPU2.AV50 DIMM1.34
M_DATA_A12: CPU2.AP47 DIMM1.24
M_DATA_A13: CPU2.AT50 DIMM1.21
M_DATA_A14: CPU2.AY50 DIMM1.35
M_DATA_A15: CPU2.AV45 DIMM1.36
M_DATA_A16: CPU2.AT40 DIMM1.42
M_DATA_A17: CPU2.AP42 DIMM1.41
M_DATA_A18: CPU2.AT38 DIMM1.51
M_DATA_A19: CPU2.AP40 DIMM1.40
M_DATA_A20: CPU2.AT44 DIMM1.50
M_DATA_A21: CPU2.AV41 DIMM1.52
M_DATA_A22: CPU2.AP41 DIMM1.39
M_DATA_A23: CPU2.AV42 DIMM1.53
M_DATA_A24: CPU2.BD52 DIMM1.67
M_DATA_A25: CPU2.AV52 DIMM1.58
M_DATA_A26: CPU2.BC53 DIMM1.69
M_DATA_A27: CPU2.AV51 DIMM1.56
M_DATA_A28: CPU2.AW51 DIMM1.57
M_DATA_A29: CPU2.BC52 DIMM1.70
M_DATA_A30: CPU2.AW53 DIMM1.59
M_DATA_A31: CPU2.BB51 DIMM1.68
M_DATA_A32: CPU2.BG42 DIMM1.129
M_DATA_A33: CPU2.BG43 DIMM1.132
M_DATA_A34: CPU2.BG37 DIMM1.141
M_DATA_A35: CPU2.BJ37 DIMM1.140
M_DATA_A36: CPU2.BH42 DIMM1.130
M_DATA_A37: CPU2.BJ41 DIMM1.131
M_DATA_A38: CPU2.BH36 DIMM1.143
M_DATA_A39: CPU2.BH38 DIMM1.142
M_DATA_A40: CPU2.BC36 DIMM1.147
M_DATA_A41: CPU2.BA36 DIMM1.149
M_DATA_A42: CPU2.AU34 DIMM1.157
M_DATA_A43: CPU2.AU32 DIMM1.158
M_DATA_A44: CPU2.BF36 DIMM1.146
M_DATA_A45: CPU2.BD36 DIMM1.148
M_DATA_A46: CPU2.AV34 DIMM1.159
M_DATA_A47: CPU2.AV32 DIMM1.160
M_DATA_A48: CPU2.BF34 DIMM1.163
M_DATA_A49: CPU2.BC34 DIMM1.166
M_DATA_A50: CPU2.BA32 DIMM1.176
M_DATA_A51: CPU2.BD30 DIMM1.177
M_DATA_A52: CPU2.BD34 DIMM1.165
M_DATA_A53: CPU2.BA34 DIMM1.164
M_DATA_A54: CPU2.BF30 DIMM1.174
M_DATA_A55: CPU2.BD28 DIMM1.175
M_DATA_A56: CPU2.BJ33 DIMM1.181
M_DATA_A57: CPU2.BG29 DIMM1.194
M_DATA_A58: CPU2.BH34 DIMM1.180
M_DATA_A59: CPU2.BG32 DIMM1.183
M_DATA_A60: CPU2.BG28 DIMM1.193
M_DATA_A61: CPU2.BJ29 DIMM1.192
M_DATA_A62: CPU2.BH28 DIMM1.191
M_DATA_A63: CPU2.BG33 DIMM1.182
M_DQS_A_DN0: CPU2.AM51 DIMM1.10
M_DQS_A_DN1: CPU2.AV48 DIMM1.27
M_DQS_A_DN2: CPU2.AT41 DIMM1.45
M_DQS_A_DN3: CPU2.BA51 DIMM1.62
M_DQS_A_DN4: CPU2.BG39 DIMM1.135
M_DQS_A_DN5: CPU2.AT34 DIMM1.152
M_DQS_A_DN6: CPU2.BC32 DIMM1.169
M_DQS_A_DN7: CPU2.BG31 DIMM1.186
M_DQS_A_DP0: CPU2.AM52 DIMM1.12
M_DQS_A_DP1: CPU2.AV47 DIMM1.29
M_DQS_A_DP2: CPU2.AT42 DIMM1.47
M_DQS_A_DP3: CPU2.AY52 DIMM1.64
M_DQS_A_DP4: CPU2.BH40 DIMM1.137
M_DQS_A_DP5: CPU2.AT32 DIMM1.154
M_DQS_A_DP6: CPU2.BC30 DIMM1.171
M_DQS_A_DP7: CPU2.BH32 DIMM1.188
M_MA_DM0: CPU2.AP52 DIMM1.11
M_MA_DM1: CPU2.AT48 DIMM1.28
M_MA_DM2: CPU2.AP44 DIMM1.46
M_MA_DM3: CPU2.BA53 DIMM1.63
M_MA_DM4: CPU2.BG41 DIMM1.136
M_MA_DM5: CPU2.AY36 DIMM1.153
M_MA_DM6: CPU2.BD32 DIMM1.170
M_MA_DM7: CPU2.BH30 DIMM1.187
M_MAA_A0: CPU2.BB47 DIMM1.98
M_MAA_A1: CPU2.BC42 DIMM1.97
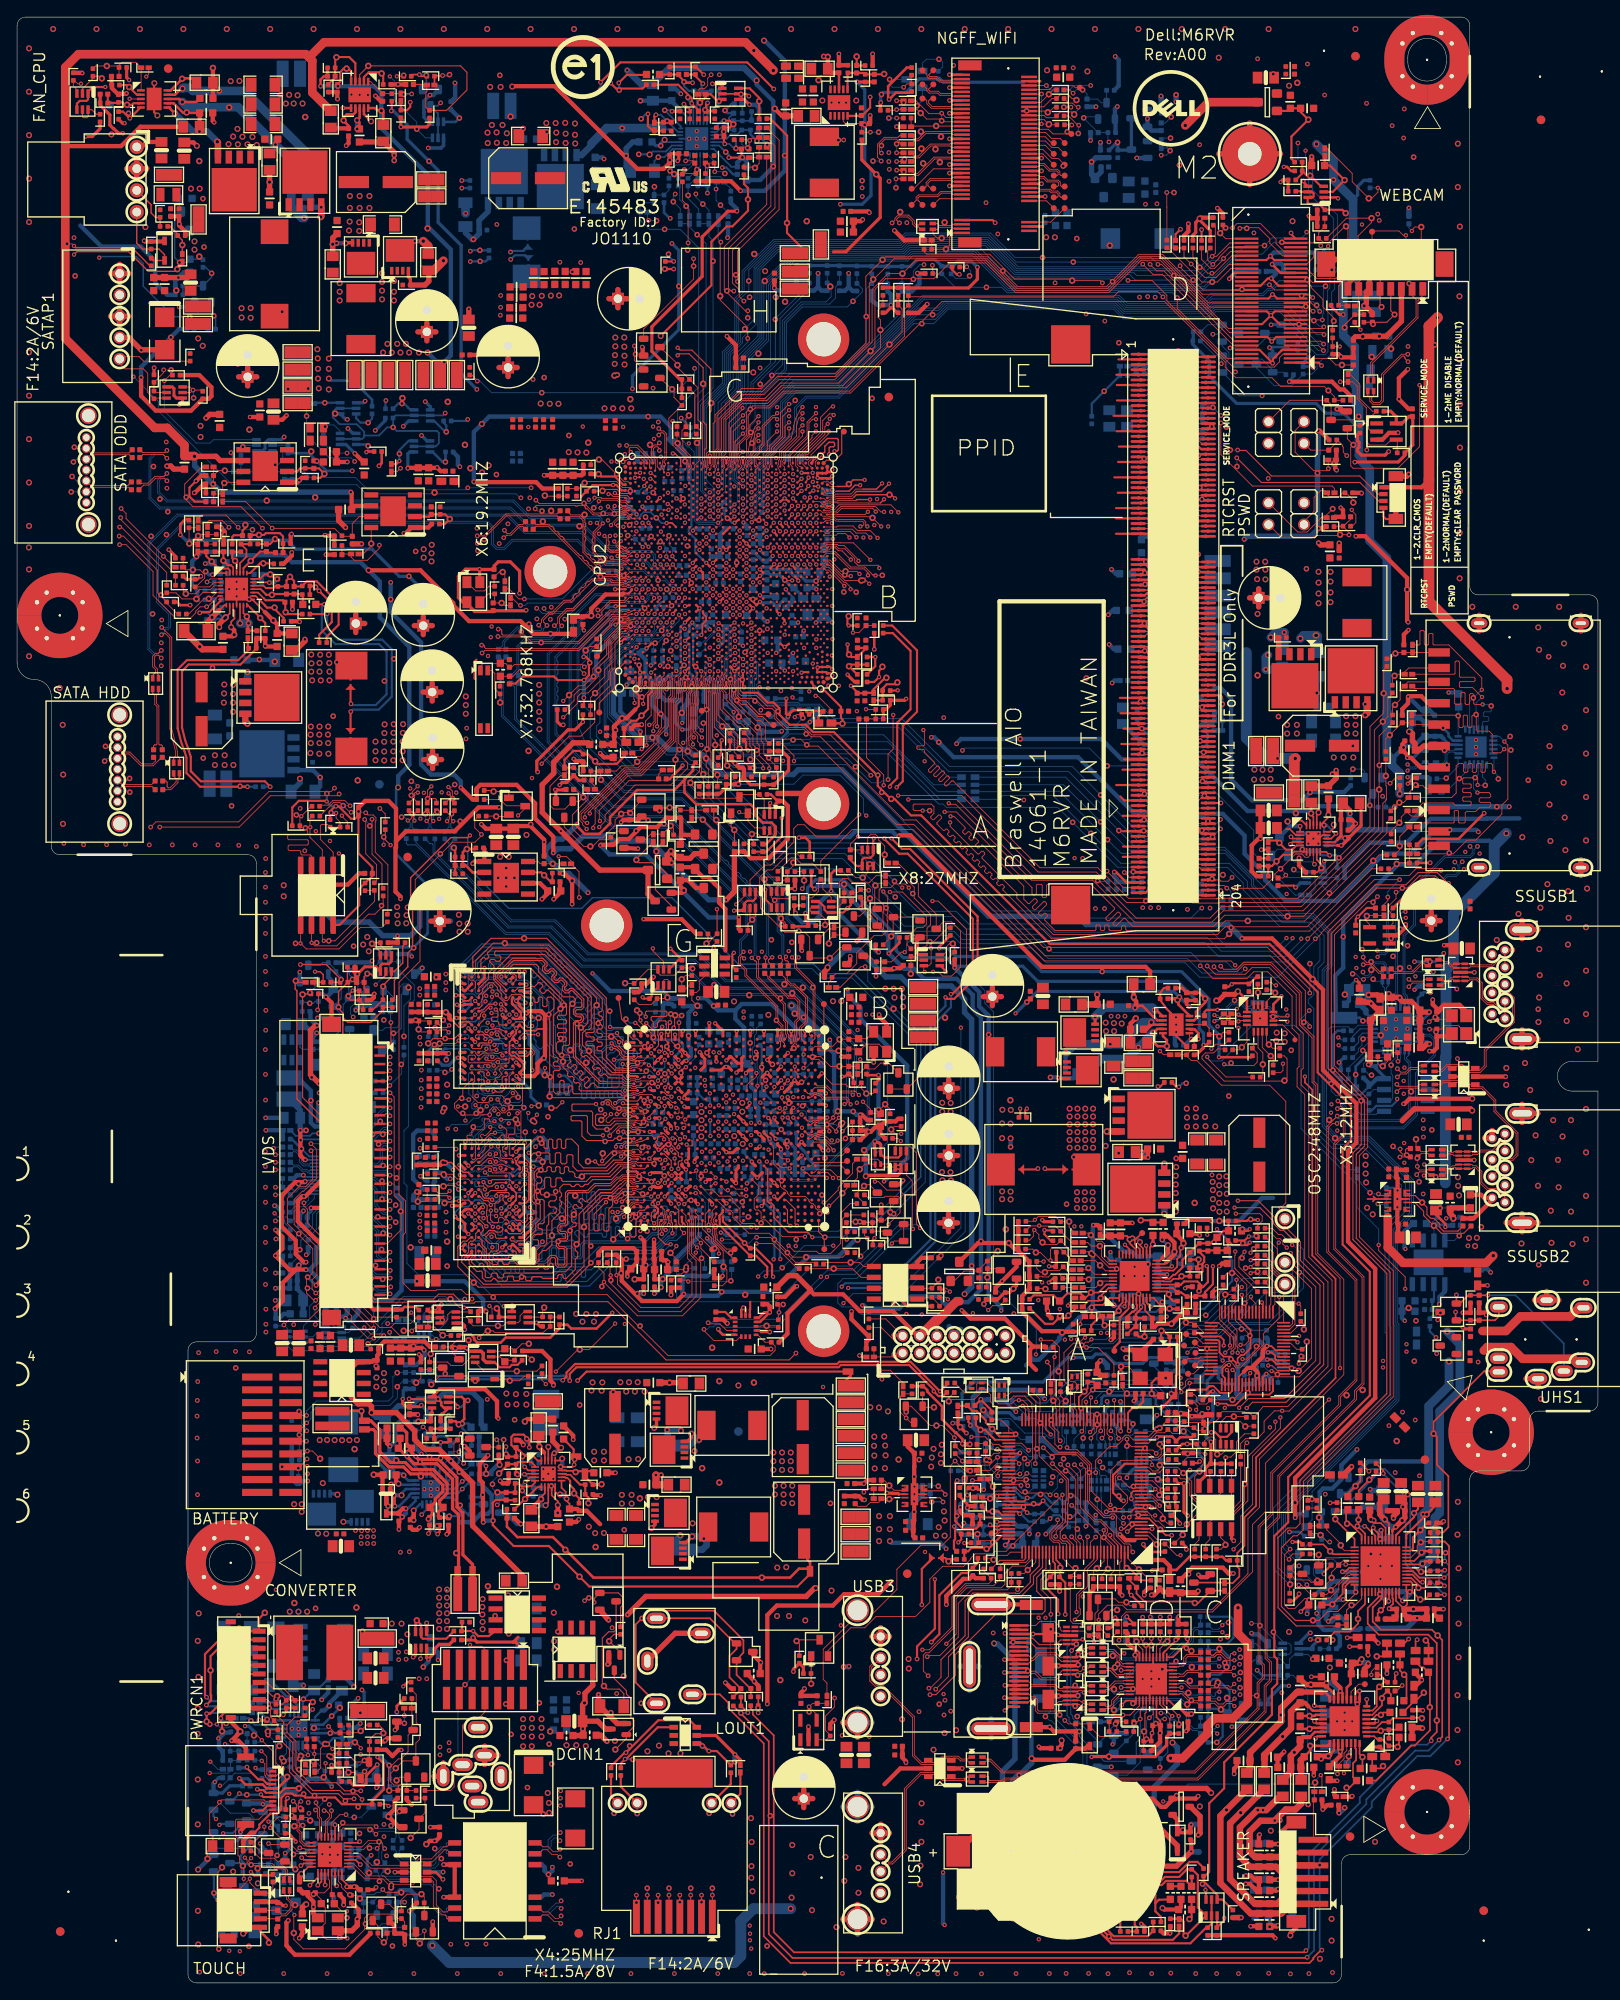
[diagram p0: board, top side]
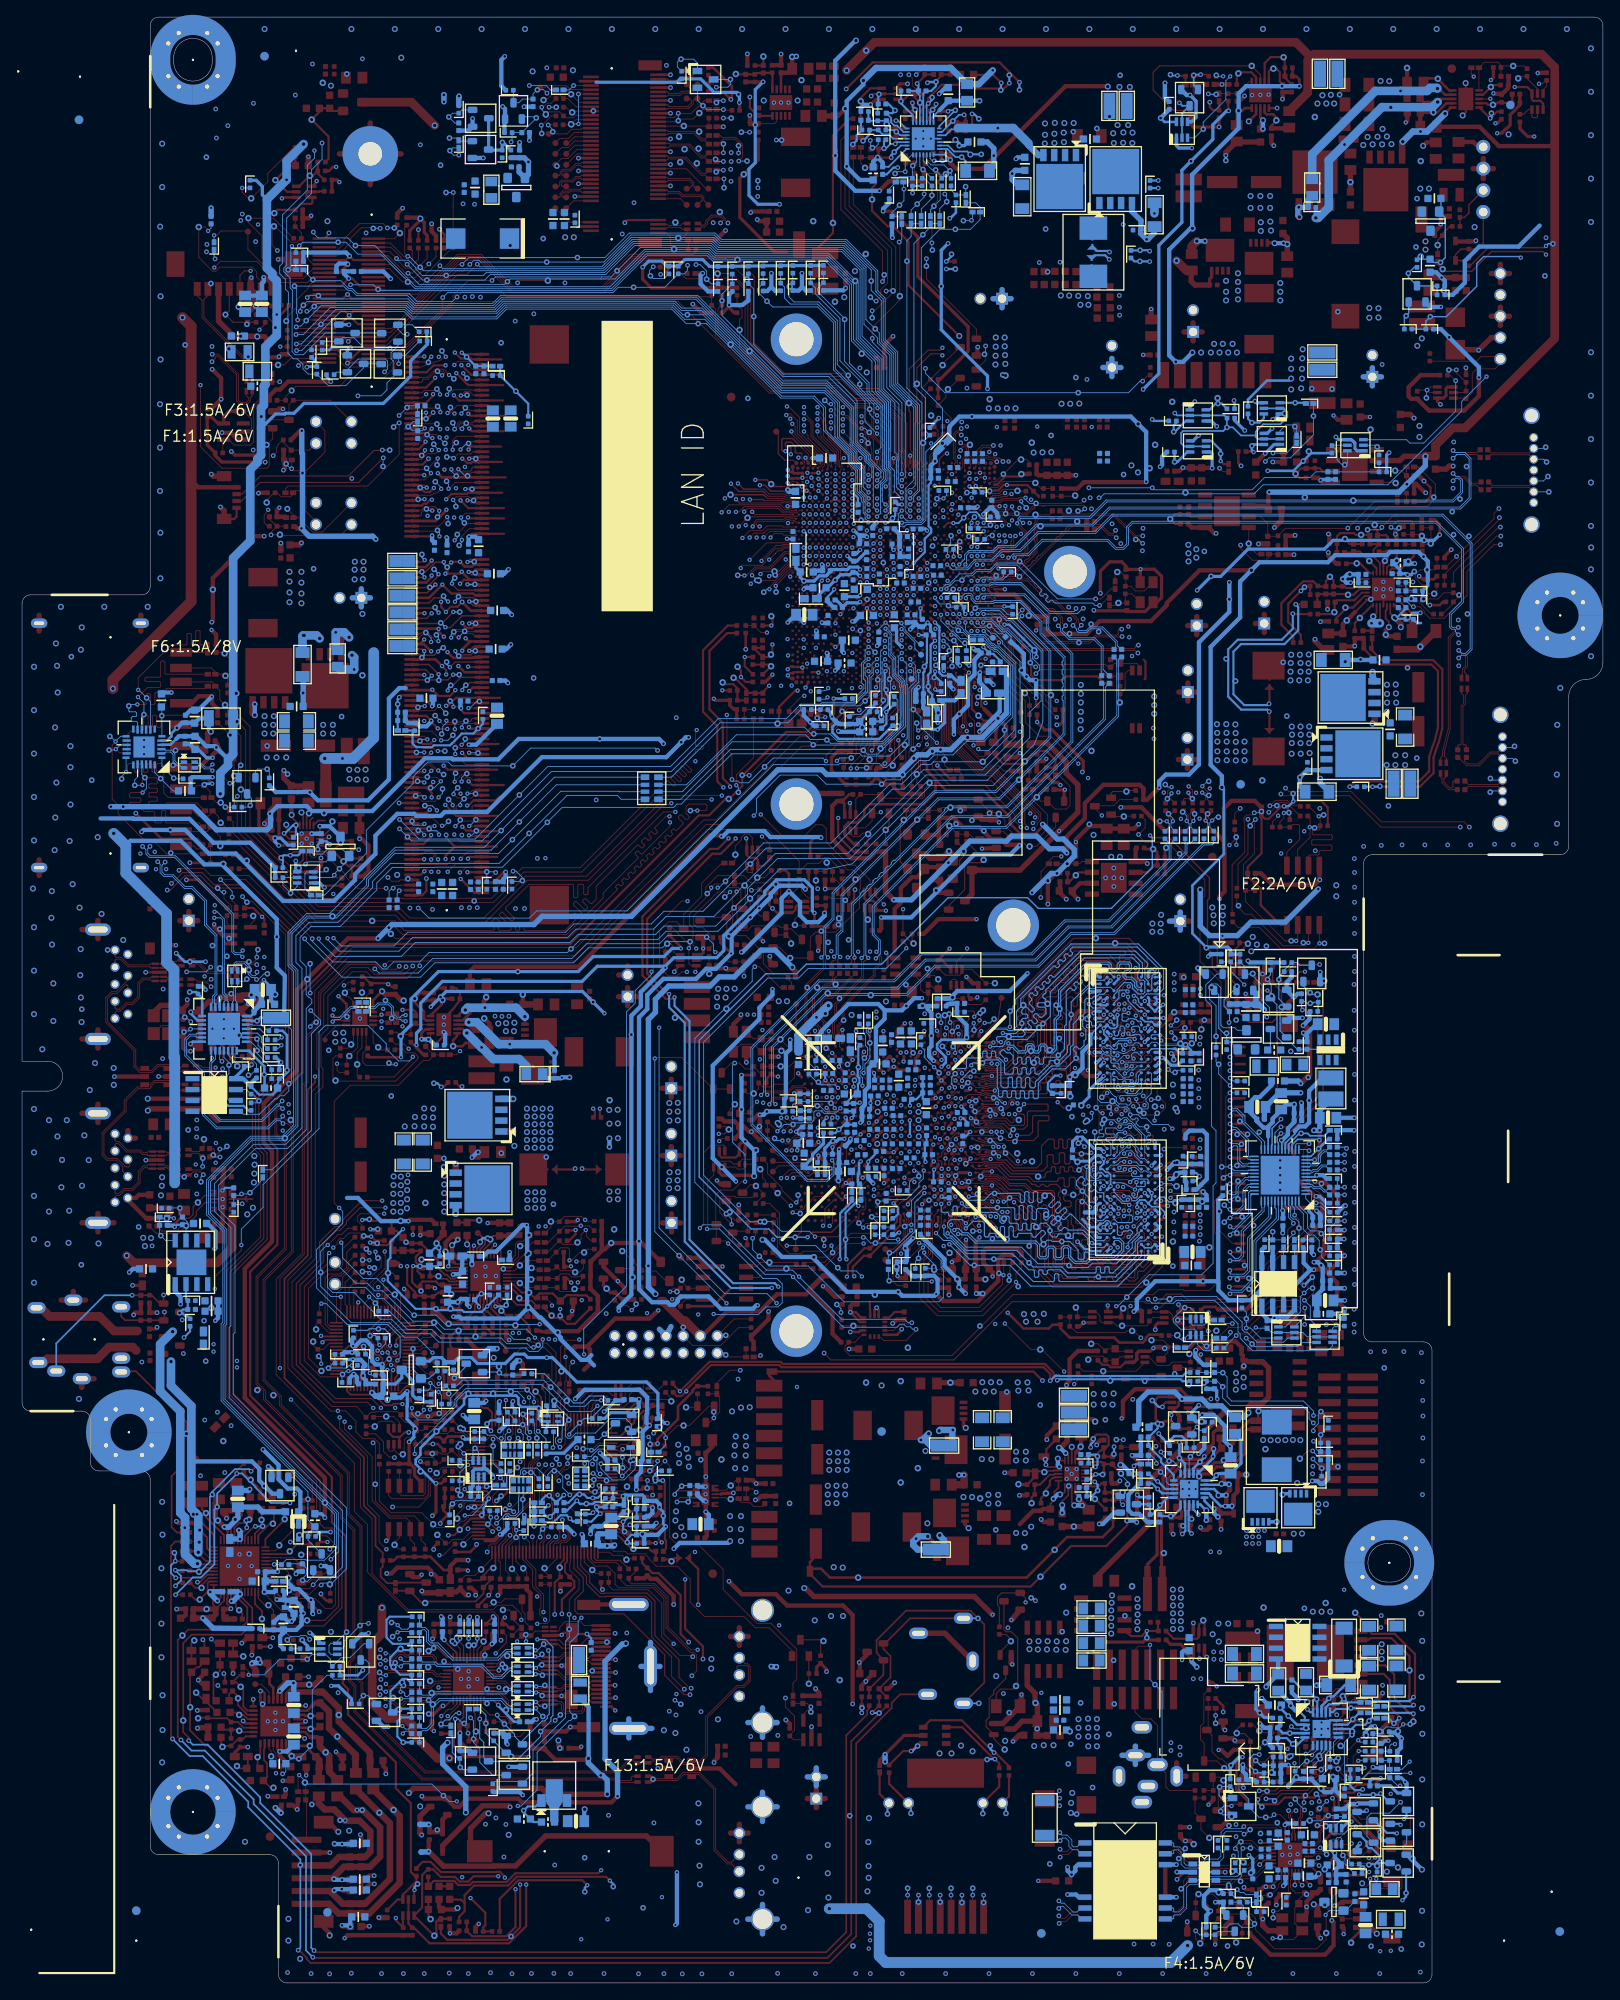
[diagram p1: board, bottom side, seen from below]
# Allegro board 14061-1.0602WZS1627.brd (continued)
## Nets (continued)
M_MAA_A2: CPU2.BJ48 DIMM1.96
M_MAA_A3: CPU2.BH47 DIMM1.95
M_MAA_A4: CPU2.BD42 DIMM1.92
M_MAA_A5: CPU2.BH48 DIMM1.91
M_MAA_A6: CPU2.BB46 DIMM1.90
M_MAA_A7: CPU2.BE46 DIMM1.86
M_MAA_A8: CPU2.BD44 DIMM1.89
M_MAA_A9: CPU2.BE52 DIMM1.85
M_MAA_A10: CPU2.BJ45 DIMM1.107
M_MAA_A11: CPU2.BB49 DIMM1.84
M_MAA_A12: CPU2.BF48 DIMM1.83
M_MAA_A13: CPU2.BF44 DIMM1.119
M_MAA_A14: CPU2.BD47 DIMM1.80
M_MAA_A15: CPU2.BD49 DIMM1.78
M_ODT_A0: CPU2.AV36 DIMM1.116
M_ODT_A1: CPU2.BA38 DIMM1.120
M_RAS_A_N: CPU2.BA40 DIMM1.110
M_SBS_A0: CPU2.BH46 DIMM1.109
M_SBS_A1: CPU2.AY40 DIMM1.108
M_SBS_A2: CPU2.BF52 DIMM1.79
M_SCKE_A0: CPU2.BB44 DIMM1.73
M_SCKE_A1: CPU2.AY42 DIMM1.74
M_SCS_A_N0: CPU2.AY38 DIMM1.114
M_SCS_A_N1: CPU2.AU38 DIMM1.121
M_WE_A_N: CPU2.BH44 DIMM1.113
MAA0: GPU1.K17 MEM1.N3 MEM2.N3 MEM3.N3 MEM4.N3
MAA1: GPU1.J20 MEM1.P7 MEM2.P7 MEM3.P7 MEM4.P7
MAA2: GPU1.H23 MEM1.P3 MEM2.P3 MEM3.P3 MEM4.P3
MAA3: GPU1.G23 MEM1.N2 MEM2.N2 MEM3.N2 MEM4.N2
MAA4: GPU1.G24 MEM1.P8 MEM2.P8 MEM3.P8 MEM4.P8
MAA5: GPU1.H24 MEM1.P2 MEM2.P2 MEM3.P2 MEM4.P2
MAA6: GPU1.J19 MEM1.R8 MEM2.R8 MEM3.R8 MEM4.R8
MAA7: GPU1.K19 MEM1.R2 MEM2.R2 MEM3.R2 MEM4.R2
MAA8: GPU1.J14 MEM1.T8 MEM2.T8 MEM3.T8 MEM4.T8
MAA9: GPU1.K14 MEM1.R3 MEM2.R3 MEM3.R3 MEM4.R3
MAA10: GPU1.J11 MEM1.L7 MEM2.L7 MEM3.L7 MEM4.L7
MAA11: GPU1.J13 MEM1.R7 MEM2.R7 MEM3.R7 MEM4.R7
MAA12: GPU1.H11 MEM1.N7 MEM2.N7 MEM3.N7 MEM4.N7
MAA13: GPU1.G20 MEM1.T3 MEM2.T3 MEM3.T3 MEM4.T3
MAA14: GPU1.G14 MEM1.T7 MEM2.T7 MEM3.T7 MEM4.T7
MAA_BA0: GPU1.J16 MEM1.M2 MEM2.M2 MEM3.M2 MEM4.M2
MAA_BA1: GPU1.L15 MEM1.N8 MEM2.N8 MEM3.N8 MEM4.N8
MAA_BA2: GPU1.G11 MEM1.M3 MEM2.M3 MEM3.M3 MEM4.M3
MCLK: RN8.1(A) U109.80
MCSI_COMP: CPU2.P44 R1230.1
MCT_R: R79612.2 RV5.2 XF1.3 XF1.4 XF2.3 XF2.4
MCT_R_1: C3131.1 R79612.1
MDA0: GPU1.K27 MEM3.F8
MDA1: GPU1.J29 MEM3.F7
MDA2: GPU1.H30 MEM3.H3
MDA3: GPU1.H32 MEM3.E3
MDA4: GPU1.G29 MEM3.G2
MDA5: GPU1.F28 MEM3.F2
MDA6: GPU1.F32 MEM3.H8
MDA7: GPU1.F30 MEM3.H7
MDA8: GPU1.C30 MEM3.D7
MDA9: GPU1.F27 MEM3.C8
MDA10: GPU1.A28 MEM3.B8
MDA11: GPU1.C28 MEM3.A7
MDA12: GPU1.E27 MEM3.A3
MDA13: GPU1.G26 MEM3.A2
MDA14: GPU1.D26 MEM3.C2
MDA15: GPU1.F25 MEM3.C3
MDA16: GPU1.A25 MEM1.A2
MDA17: GPU1.C25 MEM1.C2
MDA18: GPU1.E25 MEM1.A3
MDA19: GPU1.D24 MEM1.C3
MDA20: GPU1.E23 MEM1.A7
MDA21: GPU1.F23 MEM1.D7
MDA22: GPU1.D22 MEM1.B8
MDA23: GPU1.F21 MEM1.C8
MDA24: GPU1.E21 MEM1.G2
MDA25: GPU1.D20 MEM1.E3
MDA26: GPU1.F19 MEM1.H3
MDA27: GPU1.A19 MEM1.F2
MDA28: GPU1.D18 MEM1.H8
MDA29: GPU1.F17 MEM1.H7
MDA30: GPU1.A17 MEM1.F7
MDA31: GPU1.C17 MEM1.F8
MDA32: GPU1.E17 MEM4.F8
MDA33: GPU1.D16 MEM4.H8
MDA34: GPU1.F15 MEM4.F7
MDA35: GPU1.A15 MEM4.H7
MDA36: GPU1.D14 MEM4.H3
MDA37: GPU1.F13 MEM4.G2
MDA38: GPU1.A13 MEM4.E3
MDA39: GPU1.C13 MEM4.F2
MDA40: GPU1.E11 MEM2.C3
MDA41: GPU1.A11 MEM2.A3
MDA42: GPU1.C11 MEM2.A2
MDA43: GPU1.F11 MEM2.C2
MDA44: GPU1.A9 MEM2.A7
MDA45: GPU1.C9 MEM2.B8
MDA46: GPU1.F9 MEM2.D7
MDA47: GPU1.D8 MEM2.C8
MDA48: GPU1.E7 MEM2.E3
MDA49: GPU1.A7 MEM2.H3
MDA50: GPU1.C7 MEM2.F2
MDA51: GPU1.F7 MEM2.G2
MDA52: GPU1.A5 MEM2.H8
MDA53: GPU1.E5 MEM2.F7
MDA54: GPU1.C3 MEM2.H7
MDA55: GPU1.E1 MEM2.F8
MDA56: GPU1.G7 MEM4.D7
MDA57: GPU1.G6 MEM4.C8
MDA58: GPU1.G1 MEM4.A2
MDA59: GPU1.G3 MEM4.A7
MDA60: GPU1.J6 MEM4.B8
MDA61: GPU1.J1 MEM4.C2
MDA62: GPU1.J3 MEM4.C3
MDA63: GPU1.J5 MEM4.A3
MDAT: RN8.2(A) U109.79
ME_FWP_SOC: CPU2.AH52 R544.2 R1560.2
MEM_CALRP0: GPU1.K25 R1201.2
MEM_MA_EVENT_L: DIMM1.198 Q51.E R576.1
MEM_RST: MEM1.T2 MEM2.T2 MEM3.T2 MEM4.T2 R1204.2 R79962.2
MEM_VTT: C403.1 C404.1 C405.2 C406.2 C407.1 C408.1 DIMM1.203 DIMM1.204 PR5012.1
MIC2-L: C139.1 U6.47
MIC2-L-1: C139.2 R225.1
MIC2-R: C138.1 U6.48
MIC2-R-1: C138.2 R627.1
MIC2-VREFO-L: R223.1 U6.1
MIC2-VREFO-R: R262.1 U6.30
MIC-CAP: C154.2 U6.36
MINI_POWER_CTRL: R15.1 RN7.4(B) U109.55
MLPS_EN#: GPU1.R5 R1882.1
MODEL_ID_DET: R79722.1 R80130.2 U4101.50
MPCIE_DISABLE_N: R1620.1 RN7.3(B) U109.56
MPV18: C786.1 C790.1 C791.1 GPU1.L8 L50.2
MVREFDA: C760.1 GPU1.K26 R1888.1 R1890.2
MVREFSA: C761.1 GPU1.J26 R1200.2 R1889.1
NFC_SCL: CPU2.AA3 R1799.1
NFC_SDA: CPU2.Y2 R1800.1
NGFF_ALERT_N: NGFF1.62 R1623.2
NGFF_BT_DISABLE: R1621.1 U109.120
NGFF_CLKREQ0_N: NGFF1.53 R1612.1
NGFF_CLKREQ1_N: NGFF1.68 TP85.1
NGFF_DETECT_PCIE: CPU2.T10 R1155.2
NGFF_DETECT_PCIE_C: NGFF1.51 R1155.1 R1209.2
NGFF_DETECT_USB: CPU2.T7 R1154.2
NGFF_DETECT_USB_C: NGFF1.1 R1154.1 R1637.2
NGFF_PCIE0_RXN: NGFF1.43 R1609.1
NGFF_PCIE0_RXP: NGFF1.41 R1608.1
NGFF_PCIE0_TXN: NGFF1.37 R1611.1
NGFF_PCIE0_TXP: NGFF1.35 R1610.1
NGFF_PCIE1_RXN: NGFF1.67 TP82.1
NGFF_PCIE1_RXP: NGFF1.65 TP81.1
NGFF_PCIE1_TXN: NGFF1.61 TP80.1
NGFF_PCIE1_TXP: NGFF1.59 TP79.1
NGFF_PEWAKE0_N: NGFF1.55 NGFF1.70 R1627.2 R1628.1
NGFF_POWER_CTRL_1: Q3.G R15.2
NGFF_POWER_CTRL_V2: C864.1 Q6708.B R1615.1
NGFF_REFCLKN0: NGFF1.49 R23.1
NGFF_REFCLKN1: NGFF1.73 TP84.1
NGFF_REFCLKP0: NGFF1.47 R22.1
NGFF_REFCLKP1: NGFF1.71 TP83.1
NGFF_W_DISABLE1_N: NGFF1.56 R1620.2
NGFF_W_DISABLE2_N: NGFF1.54 R1621.2
OBSFN_C0: CPU2.Y44 R1559.1 R1817.2 XDP1.4
OCS_48M_1: L7.2 OSC2.4
OCS_48M_2: C185.1 OSC2.1 R321.2
ODTA0: GPU1.L18 MEM1.K1 MEM3.K1
ODTA1: GPU1.K16 MEM2.K1 MEM4.K1
OSD_BIST_N: R535.1 R682.2
OSD_BIST_N_1: Q12.2 R535.2
OSD_DN: C227.2 CPU2.AH2 R389.1 R393.1
OSD_DN_R: PWRCN1.2 R393.2
OSD_MENU: C549.2 CPU2.AK14 R689.1 R693.1 R80206.1 R80218.1
OSD_MENU_R: PWRCN1.1 R689.2
OSD_MENU_SIO: R80206.2 R80218.2 U109.109
OSD_UP: C542.2 CPU2.AG3 R680.2 R681.1 R682.1
OSD_UP_R: PWRCN1.3 R681.2
OVCUR1#: R80238.1 U6702.25
OVCUR2#: R80239.1 U6702.24
OZ554_ENA: C3458.1 R79625.1 R79627.1 U120.3
OZ554_PWM: C4270.1 R79621.1 R79623.1 U120.5
OZ554_VIN: C3457.1 R79716.2 U120.4
P_GFX_TXN0: C322.1 CPU2.B24
P_GFX_TXN1: C328.1 CPU2.C25
P_GFX_TXP0: C325.1 CPU2.C24
P_GFX_TXP1: C324.1 CPU2.A25
PANEL_ON_1: R33.1 R39.1 R41.2 R42.1
PANEL_ON_2: Q10.B R42.2
PANEL_ON_3: C14.2 Q5.D R19.1 R20.2 U1.3
PANEL_ON_4: Q1.G Q5.G Q10.C R26.2 R30.1
PANEL_ON_5: Q1.D R8.1
PANEL_SEL1_CABLE: CONVT1.7 R79717.2 R79721.2
PANEL_SEL1_CABLE_EC: R79717.1 U109.102
PANEL_SEL2_CABLE: CONVT1.8 R287.2 R79719.2
PANEL_SEL2_CABLE_EC: R287.1 U109.103
PANEL_SEL3_CABLE: CONVT1.9 R79718.2 R79720.2
PANEL_SEL3_CABLE_EC: R79718.1 U109.104
PB_IN_N_1: C530.2 R662.2 R668.2 R79938.2 U109.72
PB_IN_N_1_C: R79938.1 U109.111
PB_IN_SW1: PWRCN1.6 R370.2 R373.1
PCB_VER_ID: R80128.1 R80133.1 U4101.49
PCH_AUD_RST_N: R313.1 R637.1 U109.19
PCH_AUD_RST_N_1: Q63.5 R637.2
PCH_CHAR_CTL3: R80059.2 R80065.2
PCH_PCIECLKRQ2_N: CPU2.AM12 Q1236.3 R1782.2 R1843.1 R80234.1
PCH_PCIECLKRQ2_N_1: Q1236.2 R1612.2 R1842.1
PCH_PCIECLKRQ2_N_B: Q1236.1 R1844.2
PCH_RTCRST_DOWN: CMCLR1.1 R86.1
PCH_RTCRST_PULLUP: C50.1 CMCLR1.2 CPU2.J16 R87.2 R92.1
PCH_RTCX1: C1619.1 CPU2.M18 R81.1 X7.1
PCH_RTCX2: C1618.1 CPU2.K18 R81.2 R1261.1
PCH_SATA_LED_1: Q36.B Q37.C R340.2
PCH_SRTCRST_DOWN: CMCLR2.1 R729.1
PCH_SRTCRSTB_PULLUP: C52.1 CMCLR2.2 CPU2.D18 R91.2 R92.2
PCIE_CALR_RX: GPU1.AA22 R1162.1
PCIE_CALR_TX: GPU1.Y22 R1161.1
PCIE_OBS_DN: CPU2.F26 R513.2
PCIE_OBS_DP: CPU2.D26 R513.1
PCIE_RST#: NGFF1.52 NGFF1.66 RN3.1(A)
PCIE_WAKE#_CPU: Q19.C R59.1 R1263.2 R80234.2
PCIE_WAKE#_CPU_B: Q19.B R58.1
PCIRST1#: R79953.2 RN3.6(B) U109.30
PCIRST3#: R79952.2 RN3.7(B) RN3.8(B) U109.81
PD4405_A: PD4405.A PQ4409.B
PD4405_K: PD4405.K PR4458.2
PD_N: Q1257.D U127.36
PEG_C_RXN0: C1840.1 GPU1.AG31
PEG_C_RXN1: C1842.1 GPU1.AF28
PEG_C_RXP0: C1838.1 GPU1.AH30
PEG_C_RXP1: C1839.1 GPU1.AG29
PEG_RXN0: C1840.2 CPU2.J20
PEG_RXN1: C1842.2 CPU2.F20
PEG_RXP0: C1838.2 CPU2.G20
PEG_RXP1: C1839.2 CPU2.D20
PEG_TXN0: C322.2 GPU1.AE31
PEG_TXN1: C328.2 GPU1.AD28
PEG_TXP0: C325.2 GPU1.AF30
PEG_TXP1: C324.2 GPU1.AE29
PHASE1_R: PG4.1 PR45.2
PLT_RST#_CPU: C42.1 C44.2 CPU2.F14 R46.2 R72.2 R75.2
PLT_RST#_CPU_G: Q20.2 R75.1
PLT_RST#_D: Q20.5 Q20.6 R65.2
PLT_RST#_XDP: R46.1 XDP1.46
PLTRST*_EC: R79697.1 U4101.6
PLTRST*_SIO: C571.1 R336.1 R337.1 U109.46
PLTRST_LAN_N: RN3.2(A) U20.19
PLTRST_N: LPC1.3 Q20.3 R64.2 R337.2 R79697.2
PLTRST_SL_N: D34.3 D5209.1 D5209.2 R1159.1 R1160.2 RN3.3(A)
PM_DPRSLPVR: PR7.1 PR15.2 PR17.1
PM_SLP_S3#_CPU: CPU2.B14 R48.2 R49.1
PM_SLP_S3#_CPU_D: Q16.5 Q16.6 R51.1
PM_SLP_S3#_CPU_G: C30.1 Q16.2 R48.1
PM_SLP_S4#_CPU: CPU2.C12 R62.2 R63.1
PM_SLP_S4#_CPU_D: Q17.5 Q17.6 R66.1
PM_SLP_S4#_CPU_G: C31.1 Q17.2 R62.1
PMC_BATLOW#: CPU2.C14 R492.1
PMC_SUS_STAT: CPU2.D14 TP35.1
PORTC_SPK_L: R345.1 U6.43
PORTC_SPK_L_1: R345.2 R356.1
PORTC_SPK_R: R359.1 U6.44
PORTC_SPK_R_1: R359.2 R367.1
PQ4206_D: PQ4206.D PR4214.2
PQ4406_2: PQ4406.2 PR4462.2
PQ4406_3: PQ4406.3 PR4455.2
PQ4406_5: PC5447.1 PQ4406.5 PR9812.2
PQ4406_6: PC5447.2 PQ4406.6 PR4450.1
PQ4409_C: PQ4409.C PR4451.1 PR4462.1
PQ4409_E: PQ4409.E PR9813.2 PR9814.1
PRE: R79745.1 R79746.2 U127.16
PRW_VGA_CORE_RBIAS: PR9.1 U6706.3
PS_0: C1847.1 GPU1.AC19 R394.1 R79963.1
PS_1: C1849.2 GPU1.AD19 R943.1 R948.1
PS_2: C1850.1 GPU1.AE17 R1899.1 R1900.1
PS_3: C1848.1 GPU1.AE20 R935.2 R940.1
PSI#: PR3.1 PR4.2 PR10.2
PSID_D: L22.2 Q42.D R424.1
PSID_D_1: Q40.B R422.1 R424.2
PSID_G: Q40.C Q42.G R421.2
PSTBTN_N: C24.2 CPU2.AF2 R1208.2 R1266.2 XDP1.48
PW_CLEAR: CPU2.Y7 R88.2
PW_CLEAR_H: PSWD1.2 R88.1 R89.1
PWR_0P95V_BOOT: PR4714.2 PU4705.10
PWR_0P95V_BOOT_1: PC4703.1 PR4714.1
PWR_0P95V_CS: PU4705.2 R79802.1
PWR_0P95V_FB: PC4705.2 PR4717.2 PR4718.1 PU4705.4
PWR_0P95V_HG: PR4716.2 PU4705.9
PWR_0P95V_HG_1: PQ4701.4 PR4715.2 PR4716.1
PWR_0P95V_LG: PQ4702.4 PU4705.6
PWR_0P95V_LX: PC4703.2 PL4701.1 PQ4701.1 PQ4701.2 PQ4701.3 PQ4702.5 PQ4702.6 PQ4702.7 PQ4702.8 PR4713.1 PR4715.1 PU4705.8
PWR_0P95V_PG: PC4701.1 PR4712.2 PU4705.1 R1835.1 R79763.1 U109.17
PWR_0P95V_PG_L: Q1233.3 R1835.2
PWR_0P95V_RF: PR4702.1 PU4705.5
PWR_0P95V_SN: PC4704.1 PR4713.2
PWR_0P95V_VCC: PC4702.1 PR4701.1 PU4705.7
PWR_0P95V_VIN: PC4706.1 PQ4701.5 PQ4701.6 PQ4701.7 PQ4701.8 PR4790.2 PR4791.2
PWR_1D15V_A: PC5258.1 PC5261.1 PC5262.1 PC5264.1 PL5004.2 PR5471.1 R79796.1
PWR_1D15V_EN: PC5266.1 PR5479.1 PR5480.2 PU5206.5
PWR_1D15V_FB: PC5262.2 PC5265.1 PU5206.6 R79796.2 R79800.1
PWR_1D15V_FB_N: PC5265.2 PR5473.1
PWR_1D15V_LX: PL5004.1 PR5474.1 PU5206.1 PU5206.2 PU5206.3
PWR_1D15V_PVIN: PC5257.1 PC5260.1 PR5290.1 PR5291.1 PR5475.1 PU5206.9 PU5206.10
PWR_1D15V_SN: PC5263.1 PR5474.2
PWR_1D15V_SVIN: PC5259.1 PR5475.2 PU5206.8
PWR_1P05V_BOOT: PR9794.2 PU4701.10
PWR_1P05V_BOOT_1: PC5442.1 PR9794.1
PWR_1P05V_CS: PU4701.2 R80102.1
PWR_1P05V_FB: PC5446.2 PR9795.2 PR9796.1 PU4701.4
PWR_1P05V_HG: PR9797.2 PU4701.9
PWR_1P05V_HG_1: PQ47001.4 PR9797.1 PR9798.2
PWR_1P05V_LG: PQ47002.4 PU4701.6
PWR_1P05V_LX: PC5442.2 PL47001.1 PQ47001.1 PQ47001.2 PQ47001.3 PQ47002.5 PQ47002.6 PQ47002.7 PQ47002.8 PR9798.1 PR9805.1 PU4701.8
PWR_1P05V_PG: PC5444.1 PR5479.2 PR9803.2 PU4701.1 R1838.1
PWR_1P05V_PG_L: Q1229.3 R1838.2
PWR_1P05V_RF: PR9804.1 PU4701.5
PWR_1P05V_SN: PC5445.1 PR9805.2
PWR_1P05V_VCC: PC5443.1 PR9793.1 PU4701.7
PWR_1P05V_VIN: PC5441.1 PQ47001.5 PQ47001.6 PQ47001.7 PQ47001.8 PR9788.2 PR9789.2 PT5002.1
PWR_1P15V_PG: PC4801.1 PC5222.1 PR4812.2 PR5216.2 PR5241.2 PU5206.4 R1839.1
PWR_1P15V_PG_L: Q1230.3 R1839.2
PWR_3D3V_SN: PC4907.1 PR4911.2
PWR_3V_BOOT2: PR4902.2 PU4901.7
PWR_3V_BOOT2_R: PC4913.2 PR4902.1
PWR_3V_ENTRIP2: PC4912.1 PR4924.1 PU4901.4
PWR_3V_FB: PC4910.2 PG4902.1 PR4914.1
PWR_3V_FB2: PC4910.1 PR4914.2 PR4917.1 PU4901.5
PWR_3V_LGATE2: PQ4903.4 PU4901.10
PWR_3V_PHASE2: PC4913.1 PL4903.2 PQ4901.1 PQ4901.2 PQ4901.3 PQ4903.5 PQ4903.6 PQ4903.7 PQ4903.8 PR4911.1 PU4901.9
PWR_3V_UGATE2: PR4904.2 PU4901.8
PWR_3V_UGATE2R: PQ4901.4 PR4904.1
PWR_5V_BOOT1: PR4903.1 PU4901.19
PWR_5V_BOOT1_R: PC4914.1 PR4903.2
PWR_5V_BYP1: PC4909.1 PC4915.1 PG4903.2 PR4921.2 PU4901.20
PWR_5V_ENTRIP1: PC4911.1 PR4925.1 PU4901.2
PWR_5V_FB1: PC4909.2 PR4921.1 PR4922.1 PU4901.1
PWR_5V_LGATE1: PQ4902.4 PU4901.16
PWR_5V_PHASE1: PC4914.2 PL4904.1 PQ4902.5 PQ4902.6 PQ4902.7 PQ4902.8 PQ4904.1 PQ4904.2 PQ4904.3 PR4912.1 PU4901.17
PWR_5V_SN: PC4908.1 PR4912.2
PWR_5V_UGATE1: PR4905.2 PU4901.18
PWR_5V_UGATE1R: PQ4904.4 PR4905.1
PWR_CHG_ACDET: PC5232.1 PR4412.1 PR5270.2 U55.6
PWR_CHG_ACN: PC4402.1 PC4404.1 PG4905.2 U55.1
PWR_CHG_ACP: PC4402.2 PC4403.1 PG4907.2 U55.2
PWR_CHG_AD_OFF: PQ4206.G PR4210.1 R80230.1 U4101.19
PWR_CHG_AD_OFF_R: PQ4204.B PR4210.2
PWR_CHG_BTST: PR5279.1 U55.17
PWR_CHG_BTST_1: PC5234.1 PD4401.K PR5279.2
PWR_CHG_CMPIN: PR5287.2 PR5467.2 PR5468.1 PR5469.2 PR5470.1 U55.4
PWR_CHG_CMPIN_R: PQ5006.3 PR5470.2
PWR_CHG_CMPIN_RR: PQ5006.6 PR5469.1
PWR_CHG_HIDRV: PU4403.4 U55.18
PWR_CHG_ILIM: PQ5003.D PR5268.1 PR5278.2 U55.10
PWR_CHG_IOUT: PC5239.1 PR5288.1 PR5467.1 U55.7
PWR_CHG_LODRV: PC5237.1 PU4405.4 U55.15
PWR_CHG_NC: PR5286.1 U55.11
PWR_CHG_PHASE: PC5234.2 PL5003.1 PU4403.1 PU4403.2 PU4403.3 PU4405.5 PU4405.6 PU4405.7 PU4405.8 U55.19
PWR_CHG_SRN: PR5277.1 U55.12
PWR_CHG_SRP: PR5283.1 U55.13
PWR_CHG_VCC: PC4408.1 PR5284.2 U55.20
PWR_DDR4_BT: PR5019.2 PU5001.18
PWR_DDR4_BT1: PC5008.1 PR5019.1
PWR_DDR4_CS: PR5015.2 PU5001.13
PWR_DDR4_FB: PC5002.2 PR5001.1 PR5016.2 PU5001.6
PWR_DDR4_LDOIN: PR5013.1 PU5001.19
PWR_DDR4_LG: PQ5002.4 PU5001.15
PWR_DDR4_LX: PC5008.2 PL5002.1 PQ5001.1 PQ5001.2 PQ5001.3 PQ5002.5 PQ5002.6 PQ5002.7 PQ5002.8 PR5002.2 PR5017.1 PU5001.16
PWR_DDR4_SN: PC5009.1 PR5017.2
PWR_DDR4_TON: PR5009.2 PU5001.9
PWR_DDR4_UG: PR5018.2 PU5001.17
PWR_DDR4_UG1: PQ5001.4 PR5002.1 PR5018.1
PWR_DDR4_VDD: PC5004.1 PR5011.1 PR5015.1 PU5001.11
PWR_DDR4_VDDQ: PR5014.1 PU5001.5
PWR_DDR4_VIN: PC5001.1 PC5010.1 PQ5001.5 PQ5001.6 PQ5001.7 PQ5001.8 PR5009.1 PR5090.2 PR5091.2 PT5001.1
PWR_DDR4_VTT: PC5005.1 PC5006.1 PR5012.2 PU5001.2 PU5001.20
PWR_DDR4_VTTREF: PC5007.1 PU5001.4
PWR_LED_YELLOW_C: PWRCN1.9 Q65.D R351.2 R661.1
PWR_LED_YELLOW_C2: R351.1 R352.2
PWR_RT8243_EMN: PR4918.2 PR4920.1 PU4901.13
PWR_RT8243_ENLDO: PR4901.2 PU4901.12
PWR_RT8243_LDO3: PC4918.1 PG4904.1 PU4901.15
PWR_RT8243_LDO5: PC4917.1 PG4901.1 PU4901.14
PWR_RT8243_PGOOD: PR4923.2 PU4901.6
PWR_RT8243_TON: PR4919.1 PU4901.3
PWR_V1P5A: PC5114.1 PC5115.1 PC5116.2 PR5109.2 PR5113.1 PU5202.3 PU5202.4
PWR_V1P5A_FB: PC5114.2 PR5112.1 PR5113.2 PU5202.2
PWR_V1P5S_EN: PC5221.1 PR5110.1 PU5202.8
PWR_V1P5S_PG: PC27.1 PR40.2 PU5202.7
PWR_V1P8A: PC5225.2 PC5226.1 PC5227.1 PR1689.1 PR5243.2 PR9767.2 PU5203.3 PU5203.4
PWR_V1P8A_EN: PC5228.1 PR5245.1 PR5257.2 PU5203.8
PWR_V1P8A_FB: PC5226.2 PR1689.2 PR5242.1 PU5203.2
PWR_V1P8A_PG: PC5229.1 PR5246.2 PU5203.7 R1689.2
PWR_V1P24A: PC5215.1 PC5216.2 PC5219.1 PR5209.2 PR5211.1 PU5201.3 PU5201.4
PWR_V1P24A_EN: PR5216.1 PU5201.8
PWR_V1P24A_FB: PC5219.2 PR5211.2 PR5212.1 PU5201.2
PWR_V1P24A_PG: PC5217.1 PR5213.2 PR5245.2 PU4.3 PU5201.7 R1837.1
PWR_V1P24A_PG_L: Q1231.3 R1837.2
PWR_VCC0_BT: PR4424.2 PU4401.8
PWR_VCC0_BTR: PC4421.1 PR4424.1
PWR_VCC0_COMP: PC4412.1 PC4413.1 PU4401.23
PWR_VCC0_COMP1: PC4411.2 PR4404.1
PWR_VCC0_COMP2: PC4413.2 PR4407.1
PWR_VCC0_CSCOMP: PC4419.1 PC4420.2 PN4402.1 PR4418.2 PR4419.2 PU4401.19
PWR_VCC0_CSMP1: PN4402.2 PR4419.1 PR4420.2
PWR_VCC0_CSN: PG4402.2 PR4416.2
PWR_VCC0_CSP: PG4401.2 PR4417.2
PWR_VCC0_CSREF: PC4418.1 PR4416.1 PU4401.17
PWR_VCC0_CSSUM: PC4419.2 PC4420.1 PR4417.1 PR4420.1 PU4401.18
PWR_VCC0_DIFFOUT: PR4404.2 PR4405.2 PU4401.25
PWR_VCC0_FB: PC4411.1 PC4412.2 PR4405.1 PR4406.1 PR4407.2 PU4401.24
PWR_VCC0_HG: PR4423.2 PU4401.9
PWR_VCC0_HGR: PQ4401.4 PR4422.1 PR4423.1
PWR_VCC0_ILIM: PR4418.1 PU4401.21
PWR_VCC0_IMAX: PR4432.1 PU4401.16
PWR_VCC0_IOUT: PC4417.1 PR4415.1 PU4401.20
PWR_VCC0_LG: PQ4402.4 PU4401.12
PWR_VCC0_PVCC: PC4426.1 PR4428.2 PU4401.15
PWR_VCC0_ROSC: PR4433.1 PU4401.22
PWR_VCC0_SN: PC4429.1 PR4421.2
PWR_VCC0_SW: PC4421.2 PG4401.1 PL4401.1 PQ4401.1 PQ4401.2 PQ4401.3 PQ4402.5 PQ4402.6 PQ4402.7 PQ4402.8 PR4421.1 PR4422.2 PU4401.10
PWR_VCC0_TSEN: PC4416.2 PR4413.2 PU4401.13
PWR_VCC0_TSEN1: PN4401.1 PR4413.1 PR4414.1
PWR_VCC0_VBOOT/ADDR: PR4431.1 PU4401.14
PWR_VCC0_VCC: PC4428.1 PR4430.2 PU4401.28
PWR_VCC0_VIN: PC4423.1 PC4424.1 PQ4401.5 PQ4401.6 PQ4401.7 PQ4401.8 PR4490.2 PR4491.2 PT4491.1
PWR_VCC0_VRMP: PC4427.1 PR4429.2 PU4401.7
PWR_VCC0_VSN: PC4415.1 PR4411.1 PU4401.26
PWR_VCC0_VSP: PC4414.1 PR4410.2 PU4401.27
PWR_VCORE_VCC0: C304.1 C305.1 C582.1 C583.1 C1620.1 C1621.1 C1622.1 C1623.1 C1624.1 C1625.1 C6726.1 C6727.1 C6728.1 C6729.1 C6730.1 C6731.1 CPU2.AF29 CPU2.AF30 CPU2.AF36 CPU2.AG27 CPU2.AG29 CPU2.AG30 CPU2.AG33 CPU2.AG35 CPU2.AG36 CPU2.AG38 CPU2.AJ27 CPU2.AJ29 CPU2.AJ30 CPU2.AJ33 CPU2.AJ36 CPU2.AJ38 G5.1 PG4402.1 PL4401.2 R1822.1 TC13.1 TC15.1
PWR_VCORE_VGG: C590.1 C591.1 C592.1 CPU2.AD16 CPU2.AD18 CPU2.AD19 CPU2.AF16 CPU2.AF18 CPU2.AF19 CPU2.AF21 CPU2.AF22 CPU2.AG16 CPU2.AG18 CPU2.AG19 CPU2.AG21 CPU2.AG22 CPU2.AG24 CPU2.AJ19 CPU2.AJ21 CPU2.AJ22 CPU2.AJ24 CPU2.AK24 PG4502.1 PL4501.2 R1826.1 R80240.2 TC16.1 TC17.1 TC18.1 TC19.1
PWR_VCORE_VNN: C597.1 C598.1 C599.1 C600.1 C6716.1 C6717.1 C6718.1 CPU2.AA18 CPU2.AA19 CPU2.AA21 CPU2.AA22 CPU2.AA24 CPU2.AA25 CPU2.AC18 CPU2.AC19 CPU2.AC21 CPU2.AC22 CPU2.AC24 CPU2.AC25 CPU2.AD25 CPU2.AD27 PR9799.2 PR9800.2 PR9801.2 PR9802.2 R1784.1
PWR_VCORE_VNN_D: Q1228.6 R1784.2
PWR_VGA_CORE_BOOT1: PR43.1 U6706.19
PWR_VGA_CORE_COMP: PC4.2 PC6.1 PC7.2 PC8.1 PR1.2 PR13.2 U6706.7
PWR_VGA_CORE_DPRSLPVR: PR17.2 U6706.39
PWR_VGA_CORE_FB: PC8.2 PR8.2 PR20.1 PR21.1 U6706.8
PWR_VGA_CORE_FB2: PC4.1 PC5.2 U6706.9
PWR_VGA_CORE_IMON: PC59.2 PR9777.1 PR9778.2 U6706.18
PWR_VGA_CORE_ISEN1: PR12.2 U6706.11
PWR_VGA_CORE_ISEN2: PR11.2 PR12.1 U6706.10
PWR_VGA_CORE_ISUM+: PC15.1 PC16.1 PR34.1 PR42.1 PR45.1 PR9781.1 U6706.15
PWR_VGA_CORE_ISUM-: PC14.1 PR16.2 U6706.14
PWR_VGA_CORE_LGATE1A: PU3.4 PU5207.4 U6706.23
PWR_VGA_CORE_LGATE1B: TP203.1 U6706.24
PWR_VGA_CORE_NTC: PC9.1 PR60.2 U6706.5
PWR_VGA_CORE_ON: PC12.1 PR18.2 PR19.2 U6706.38
PWR_VGA_CORE_PGOOD: PR14.1 U6706.1
PWR_VGA_CORE_PHASE1: PC19.1 PG4.2 PL1.1 PR9783.1 PU1.1 PU1.2 PU1.3 PU2.1 PU2.2 PU2.3 PU3.5 PU3.6 PU3.7 PU3.8 PU5207.5 PU5207.6 PU5207.7 PU5207.8 U6706.21
PWR_VGA_CORE_PSI#: PR10.1 U6706.2
PWR_VGA_CORE_RTN: PC13.2 PC59.1 PC5272.2 PR29.2 PR9778.1 U6706.13
PWR_VGA_CORE_SNB1: PC5267.1 PR9783.2
PWR_VGA_CORE_UGATE1: PU1.4 PU2.4 U6706.20
PWR_VGA_CORE_VCCP: PC17.1 PC18.1 PR44.1 U6706.25
PWR_VGA_CORE_VDD: PC58.1 PR9771.2 PR9777.2 U6706.16
PWR_VGA_CORE_VID0: PR9774.2 U6706.31
PWR_VGA_CORE_VID1: PR9773.2 U6706.32
PWR_VGA_CORE_VID2: PR35.2 U6706.33
PWR_VGA_CORE_VID3: PR32.2 U6706.34
PWR_VGA_CORE_VID4: PR30.2 U6706.35
PWR_VGA_CORE_VID5: PR25.2 U6706.36
PWR_VGA_CORE_VID6: PR23.2 U6706.37
PWR_VGA_CORE_VIN: PC60.1 PR101.2 U6706.17
PWR_VGA_CORE_VSEN: PC11.2 PC13.1 PC5268.1 PR21.2 PR28.2 U6706.12
PWR_VGA_CORE_VSUM-: PC15.2 PC16.2 PC20.1 PR16.1 PR51.2 PR9779.1 PR9781.2
PWR_VGA_CORE_VW: PC7.1 PR13.1 U6706.6
PWR_VGG_BT: PR4524.2 PU4501.8
PWR_VGG_BTR: PC4521.1 PR4524.1
PWR_VGG_COMP: PC4512.1 PC4513.2 PU4501.23
PWR_VGG_COMP1: PC4511.2 PR4504.1
PWR_VGG_COMP2: PC4513.1 PR4507.1
PWR_VGG_CSCOMP: PC4519.1 PC4520.2 PN4502.1 PR4518.2 PR4519.2 PU4501.19
PWR_VGG_CSMP1: PN4502.2 PR4519.1 PR4520.2
PWR_VGG_CSN: PG4502.2 PR4516.2
PWR_VGG_CSP: PG4501.2 PR4517.1
PWR_VGG_CSREF: PC4518.1 PR4516.1 PU4501.17
PWR_VGG_CSSUM: PC4519.2 PC4520.1 PR4517.2 PR4520.1 PU4501.18
PWR_VGG_DIFFOUT: PR4504.2 PR4505.2 PU4501.25
PWR_VGG_FB: PC4511.1 PC4512.2 PR4505.1 PR4506.1 PR4507.2 PU4501.24
PWR_VGG_HG: PR4523.2 PU4501.9
PWR_VGG_HGR: PR4522.1 PR4523.1 PU4502.4
PWR_VGG_ILIM: PR4518.1 PU4501.21
PWR_VGG_IMAX: PR4532.1 PU4501.16
PWR_VGG_IOUT: PC4517.1 PR4515.1 PU4501.20
PWR_VGG_LG: PU4501.12 PU4503.4 PU4504.4
PWR_VGG_PVCC: PC4526.1 PR4528.2 PU4501.15
PWR_VGG_ROSC: PR4533.1 PU4501.22
PWR_VGG_SN: PC4529.1 PR4521.2
PWR_VGG_SW: PC4521.2 PG4501.1 PL4501.1 PR4521.1 PR4522.2 PU4501.10 PU4502.1 PU4502.2 PU4502.3 PU4503.5 PU4503.6 PU4503.7 PU4503.8 PU4504.5 PU4504.6 PU4504.7 PU4504.8
PWR_VGG_TSEN: PC4516.2 PR4513.2 PU4501.13
PWR_VGG_TSEN1: PN4501.1 PR4513.1 PR4514.1
PWR_VGG_VBOOT/ADDR: PR4531.1 PU4501.14
PWR_VGG_VCC: PC4528.1 PR4530.2 PU4501.28
PWR_VGG_VIN: PC4523.2 PC4524.1 PR4590.2 PR4591.2 PT4591.1 PU4502.5 PU4502.6 PU4502.7 PU4502.8
PWR_VGG_VRMP: PC4527.1 PR4529.2 PU4501.7
PWR_VGG_VSN: PC4515.1 PR4511.1 PU4501.26
PWR_VGG_VSP: PC4514.1 PR4510.2 PU4501.27
PWRBTN_N: C213.1 R373.2 R668.1 R1260.2 U4101.47
PWRCN_DET_N: C12350.2 PWRCN1.5 R536.1
PWRCN_DET_N_C: CPU2.T12 R530.1 R536.2
PWRGD_3V: C176.1 Q1214.G R278.1 R283.2 R1591.1 R1668.1 R79774.1
PWRGD_3V_B: Q1214.D Q6714.B R1687.2
PWRGD_3V_B_1: Q30.5 Q30.6 R79772.2
PWRGD_3V_C: PC5243.1 Q1212.G Q1213.G Q6714.C R1688.2
PWRGD_3V_D: Q77.D Q78.S
PWRGD_3V_G: Q77.G R1668.2
PWRGD_3V_LL: Q30.3 R278.2
PWRGD_3V_SIO: R1591.2 U109.31
PWRGD_PS_L: C174.2 Q29.2 R273.2 R274.1
PWRGD_PS_L1: Q29.5 Q29.6 R269.2
PWRGD_PS_L2: Q29.3 R280.1
PWRGOOD_GPU: GPU1.N10 R1158.2
PWROK3_1: R309.2 U109.29
PWROK3_1_R: R283.1 R293.2 R309.1
PWROK3_2: R386.1 U109.75
PWROK3_2_R: R277.1 R386.2 R79781.1
PX_EN: GPU1.AB16 TP159.1
QSAN_0: GPU1.H27 MEM3.G3
QSAN_1: GPU1.A27 MEM3.B7
QSAN_2: GPU1.C23 MEM1.B7
QSAN_3: GPU1.C19 MEM1.G3
QSAN_4: GPU1.C15 MEM4.G3
QSAN_5: GPU1.E9 MEM2.B7
QSAN_6: GPU1.C5 MEM2.G3
QSAN_7: GPU1.H4 MEM4.B7
QSAP_0: GPU1.H28 MEM3.F3
QSAP_1: GPU1.C27 MEM3.C7
QSAP_2: GPU1.A23 MEM1.C7
QSAP_3: GPU1.E19 MEM1.F3
QSAP_4: GPU1.E15 MEM4.F3
QSAP_5: GPU1.D10 MEM2.C7
QSAP_6: GPU1.D6 MEM2.F3
QSAP_7: GPU1.G5 MEM4.C7
R_USB1N: R80050.2 R80051.1
R_USB1P: R80052.2 R80053.1
RASA0#: GPU1.G22 MEM1.J3 MEM3.J3
RASA1#: GPU1.G17 MEM2.J3 MEM4.J3
RCOMP_LPC_HVT: CPU2.T4 R1259.2
RDY#: TP4130.1 U4101.23
REMOTE1+: C211.2 R404.1 RT3.1 U109.87
REMOTE1-: C211.1 R400.2 RT3.2
REXT: R79747.1 U127.18
RING2: C157.1 Q24.2 R261.2 U6.31 UHS1.3
ROM_CS#: R1167.2 R1168.2 U49.1
ROM_SI_D3: R1171.1 U49.5
ROM_SLK_D4: R1170.1 U49.6
ROM_SO_C4: R1169.2 U49.2
RSMRST*_R: Q30.2 R277.2
RSMRST_N: CPU2.F18 R94.2 R390.2 R477.2 R722.2 R1592.1 U41.3
RSMRST_N_XDP: R477.1 XDP1.39
RT: R79628.1 U120.10
RTC_INTRUDER: CPU2.G18 R79797.1
RTCX_L: R1261.2 X7.4
RTD_LVDS_BL_ADJ: Q21.3 R44.1 R79682.2 R80236.2
RTL_ISOLATE_N: Q35.6 R331.2 R332.1 U20.20
RTL_ISOLATE_N_1: C207.1 Q35.5 R368.1 R372.2
RTL_ISOLATE_N_2: Q35.2 Q35.3 R329.2
RTN1: CONVT1.1 R79712.1
RTN2: CONVT1.2 R53.1
RTN3: CONVT1.5 R79713.1
RTN4: CONVT1.6 R79715.1
S_LVDS_BL_EN: R135.1 R139.1 R143.2 R144.1 R1985.1
S_TXE0+: LVDS1.18 U126.31
S_TXE0-: LVDS1.19 U126.32
S_TXE1+: LVDS1.15 U126.29
S_TXE1-: LVDS1.16 U126.30
S_TXE2+: LVDS1.12 U126.27
S_TXE2-: LVDS1.13 U126.28
S_TXE3+: LVDS1.8 U126.23
S_TXE3-: LVDS1.9 U126.24
S_TXEC+: LVDS1.10 U126.25
S_TXEC-: LVDS1.11 U126.26
S_TXO0+: LVDS1.29 U126.41
S_TXO0-: LVDS1.30 U126.42
S_TXO1+: LVDS1.27 U126.39
S_TXO1-: LVDS1.28 U126.40
S_TXO2+: LVDS1.25 U126.37
S_TXO2-: LVDS1.26 U126.38
S_TXO3+: LVDS1.20 U126.33
S_TXO3-: LVDS1.21 U126.34
S_TXOC+: LVDS1.22 U126.35
S_TXOC-: LVDS1.23 U126.36
SATA__RXN0_C: C149.2 HDD1.5
SATA__RXN1_C: C118.2 ODD1.5
SATA__RXP0_C: C151.2 HDD1.6
SATA__RXP1_C: C119.2 ODD1.6
SATA__TXN0_C: C142.2 HDD1.3
SATA__TXN1_C: C115.2 ODD1.3
SATA__TXP0_C: C141.2 HDD1.2
SATA__TXP1_C: C114.2 ODD1.2
SATA_LED_N_C_1: Q9646.3 Q9646.6 R80201.2
SATA_RCOMP_DN: CPU2.M30 R519.1
SATA_RCOMP_DP: CPU2.N30 R519.2
SATAHDR_RX_DN0: CPU2.M28 L4104.4
SATAHDR_RX_DN0_EMI: C149.1 L4104.3
SATAHDR_RX_DN1: C118.1 CPU2.K28
SATAHDR_RX_DP0: CPU2.N28 L4104.1
SATAHDR_RX_DP0_EMI: C151.1 L4104.2
SATAHDR_RX_DP1: C119.1 CPU2.J28
SATAHDR_TX_DN0: CPU2.B30 L4103.1
SATAHDR_TX_DN0_EMI: C142.1 L4103.2
SATAHDR_TX_DN1: C115.1 CPU2.A29
SATAHDR_TX_DP0: CPU2.C31 L4103.4
SATAHDR_TX_DP0_EMI: C141.1 L4103.3
SATAHDR_TX_DP1: C114.1 CPU2.C29
SB3V: C540.1 C562.2 C1615.1 C1617.1 C1701.1 C1702.1 F3.1 PC1.1 PC163.1 PC5112.2 PR40.1 PR4401.1 PR4402.1 PR4501.1 PR4502.1 PR5010.1 PU5202.5 PU5202.9 Q39.S Q1209.S Q9641.S R10.1 R54.2 R60.2 R67.2 R269.1 R286.2 R289.2 R311.2 R316.2 R329.1 R348.1 R378.2 R382.2 R388.2 R390.1 R391.1 R531.1 R549.1 R551.1 R659.1 R665.1 R702.1 R705.1 R717.1 R722.1 R1247.1 R1254.2 R1256.2 R1568.1 R1580.2 R1634.1 R1740.1 R1741.1 R1743.1 R1789.1 R6702.1 R79657.1 R79661.1 R79687.1 R79719.1 R79720.1 R79721.1 R79750.1 R79753.1 R79759.2 R79761.2 R79762.2 R79763.2 R79772.1 R79944.2 R79952.1 R79953.1 R80062.2 R80121.2 R80146.2 R80148.1 R80150.2 R80152.2 R80155.2 R80201.1 R80202.1 RN9.1(A) RN9.2(A) RN4302.1(A) RN4302.2(A) U54.8 U54.9
SB3V_5V_PG: R1689.1 R1778.1 R1836.1 R79949.2
SB3V_5V_PG_L: Q1232.3 R1836.2
SB3V_D: Q1232.6 R1789.2
SB3V_EN: C1700.1 PR5258.2 R1778.2 U54.3 U54.5
SB5V: C1703.1 C1704.1 CN2.1 F4.1 PC5003.1 PC5113.1 PR4428.1 PR4430.1 PR4528.1 PR4530.1 PR4701.2 PR5011.2 PU5001.12 PU5202.6 R157.1 R306.1 R340.1 R352.1 R648.2 R673.1 R1687.1 R1720.1 R1788.1 R79754.1 R80124.1 RN8.5(B) RN8.6(B) RN8.7(B) RN8.8(B) U54.13 U54.14
SB5V_D: Q1233.6 R1788.2
SCALAR_SIO_PU: R285.2 R289.1 R313.2 R669.1 R1867.2 R1868.2 R1870.2 R79691.2 R79704.2 R79705.2 R79945.2 RN7.1(A) RN7.2(A)
SD_CD_BD: MEMCD1.11 R1696.1 R1832.1 R80105.1 R80109.2
SD_CD_BD_CPU: CPU2.K3 R80109.1
SD_CD_BD_IC: R80105.2 SU1.13
SD_CLK_BD: MEMCD1.5 R80103.2 R80107.2 SC6.1
SD_CLK_BD_CPU: CPU2.F2 R80107.1
SD_CLK_BD_IC: R80103.1 SU1.15
SD_CMD_BD: MEMCD1.2 R1656.2 R80104.2 R80108.2
SD_CMD_BD_CPU: CPU2.D2 R80108.1
SD_CMD_BD_IC: R80104.1 SU1.18
SD_DATA0_B: R79982.2 SU1.11
SD_DATA0_BD: MEMCD1.7 R79982.1 R80057.2
SD_DATA0_CPU: CPU2.J1 R80057.1
SD_DATA1_B: R79981.2 SU1.10
SD_DATA1_BD: MEMCD1.8 R79981.1 R80056.2
SD_DATA1_CPU: CPU2.J3 R80056.1
SD_DATA2_B: R79977.1 SU1.21
SD_DATA2_BD: MEMCD1.9 R79977.2 R80055.2
SD_DATA2_CPU: CPU2.H3 R80055.1
SD_DATA3_B: R79980.1 SU1.20
SD_DATA3_BD: MEMCD1.1 R79980.2 R80054.2
SD_DATA3_CPU: CPU2.G2 R80054.1
SD_WP_BD: MEMCD1.10 R80106.1 R80156.2 SC4.1
SD_WP_BD_CPU: CPU2.AM14 R1780.2 R80156.1
SD_WP_BD_IC: R80106.2 SU1.8
SDCARD_PWR_EN: PR9810.2 PR9811.2 Q9642.C R80146.1
SDMMC1_RCOMP: CPU2.P13 R79788.1
SDMMC3_1P8_EN: PR9806.2 R1661.2 R80120.1 R80153.1
SDMMC3_1P8_EN_R: CPU2.K2 R80153.2
SDMMC3_PWR_EN: PR9809.2 R80144.2 R80145.1 R80154.1
SDMMC3_PWR_EN_G: C12349.1 PR9809.1 Q9642.B
SDMMC3_PWR_EN_R: CPU2.L3 R80154.2
SDMMC_PWR_EN: C12342.1 PR9806.1 Q9635.B
SDMMC_PWR_EN_G: Q9635.C Q9636.G R80150.1
SDMMC_PWR_SEL: PR9807.2 PR9808.2 Q9636.D R80121.1
SEC_GPIO_SUS8: CPU2.AF51 R1565.1 R1812.2
SEC_GPIO_SUS9: CPU2.AF52 R1813.2 R1814.1
SEC_GPIO_SUS10: CPU2.AE51 R1815.2 R1816.1
SENSE_B: R266.2 R267.2 U6.33
SER_IRQ: Q1253.2 R323.1 R79689.1 U35.4 U109.36
SFD_GPIO: Q1205.G R79944.1 U109.108
SIDE_USB3_RX0+: L5.3 SSUSB1.6 U7.2 U7.9
SIDE_USB3_RX0-: L5.2 SSUSB1.5 U7.1 U7.10
SIDE_USB3_RX1+: L37.3 SSUSB2.6 U51.2 U51.9
SIDE_USB3_RX1-: L37.2 SSUSB2.5 U51.1 U51.10
SIDE_USB3_TX0+: L4.3 SSUSB1.9 U7.5 U7.6
SIDE_USB3_TX0-: L4.2 SSUSB1.8 U7.4 U7.7
SIDE_USB3_TX1+: L36.3 SSUSB2.9 U51.5 U51.6
SIDE_USB3_TX1-: L36.2 SSUSB2.8 U51.4 U51.7
SIO_AGND: C525.1 C527.1 C528.1 C529.1 C535.2 R399.1 R400.1 R651.1 R655.2 R656.2 R657.2 R79950.2 U109.83 U109.84
SIO_AMD SVID_EN: R310.1 U109.26
SIO_ATXPG: R280.2 R79780.1 U109.16
SIO_AVCC3: C214.1 C215.1 L9.2 U109.96
SIO_CE_N: R270.1 U15.1 U109.27
SIO_CLK_DB: CN1.4 RN6.2(A) U109.48
SIO_COPEN#: R677.1 U109.65
SIO_DAT_DB: CN1.3 RN6.1(A) U109.49
SIO_DEBUG_RX: R79666.1 U109.122
SIO_DEBUG_TX: R335.1 U109.121
SIO_EUP_EN#: PR5254.2 Q6706.D R296.1 R725.1 R1840.1
SIO_EUP_EN#_D: Q1228.2 Q1228.5 Q1229.2 Q1229.5 Q1230.2 Q1230.5 Q1231.2 Q1231.5 Q1232.2 Q1232.5 Q1233.2 Q1233.5 Q1234.D R5290.2
SIO_EUP_EN#_G: Q1234.G R1840.2 R1841.2
SIO_GPU_EN: PR5476.1 R354.1 U109.124
SIO_GPU_RST: D34.1 D34.2 R79766.1 U109.126
SIO_GREEN: Q9646.2 Q9646.5 R80202.2 U109.23
SIO_GREEN_PWM: R652.1 U109.15
SIO_GREEN_PWM_C_1: Q65.G Q9646.1 R652.2 R659.2 R663.1
SIO_HDD_LED: R362.2 R364.1 U109.11
SIO_HDD_LED_1: Q38.B R364.2
SIO_HOLD#: R79692.1 U15.7
SIO_INT#: R80211.1 R80212.1 U4101.39
SIO_INT_C: R80211.2 U109.100
SIO_K8PWR_EN: R79667.1 R80217.1 U109.123
SIO_LVDS_BL_ADJ: R131.2 R503.1 U109.10
SIO_MAIN_VCC3: R375.1 U109.89
SIO_MEM_EVENT_L: R348.2 R565.1 U109.53
SIO_MEM_EVENT_L_B: Q51.B R572.2
SIO_MEM_EVENT_L_C: Q51.C R565.2
SIO_PCIRSTIN#: R285.1 U109.128
SIO_PSON_D: Q66.D R644.1
SIO_PSON_N: Q66.G R669.2 U109.73
SIO_PWNBTN_B: Q18.B R55.2
SIO_PWNBTN_N: Q18.E R47.1 R57.1 R395.2 R662.1 R1260.1
SIO_SCK: C175.1 R312.2 R79693.1 U15.6
SIO_SCK_R: R312.1 U109.22
SIO_SI: R79694.1 U15.5 U109.21
SIO_SMB2_CLK: R380.2 R80204.2 RN9.3(B) U109.63
SIO_SMB2_DATA: R379.2 R80205.2 RN9.4(B) U109.62
SIO_SMCLK0: R79633.2 R79685.2 RN4302.4(B) U109.60
SIO_SMCLK0_D: Q95.3 R79685.1
SIO_SMDAT0: R79634.2 R79684.2 RN4302.3(B) U109.61
SIO_SMDAT0_D: Q95.6 R79684.1
SIO_SO: R275.1 U15.2 U109.45
SIO_VCORE: C181.2 C182.1 U109.33
SIO_VIN1: R80215.1 R80216.2 U109.94
SIO_VIN3: C527.2 R648.1 R655.1 U109.92
SIO_VIN4: C528.2 R649.1 R656.1 U109.91
SIO_VIN5: C529.2 R650.1 R657.1 U109.90
SIO_VREF: C535.1 R397.2 R404.2 R658.2 U109.88
SIO_WP#: R279.1 U15.3
SIO_WRST#: C189.1 R338.2 U109.47
SIO_YELLOW: Q68.G R661.2 R665.2 U109.7
SKEW1: CPU2.AD3 R562.1 R567.2
SKEW2: CPU2.AC3 R560.1 R563.2
SKEW3: CPU2.AB3 R555.1 R558.2
SLEEVE: C160.1 Q24.1 Q28.D R272.2 U6.32 UHS1.4
SLEEVE_G: Q28.G Q6711.C R319.2 R322.1
SLP_S0_N: Q1206.3 R1578.1 R1580.1
SLP_S3_N: D18.A PC4510.1 PR4502.2 PR4503.1 PR5110.2 PU4501.1 Q16.3 R54.1 R1576.1 R1669.1 R1747.2 R1776.2 R79961.2 R80063.2 U109.68
SLP_S3_N_EC: R79961.1 U4101.30
SLP_S3_N_G: Q78.G R1669.2
SLP_S3_N_R3: D18.K R676.1 U109.76
SLP_S4_N: PU5001.8 Q17.3 Q1240.G R67.1 R385.2 R1599.2 R79660.2 R79960.2 R80064.2
SLP_S4_N_C: R385.1 U109.74
SLP_S5_N_D: Q48.5 Q48.6 R549.2
SLP_S5_N_EC: R79960.1 U4101.51
SLP_SLP_S0#_CPU: CPU2.A13 R1581.2 R1582.1
SLP_SLP_S0#_CPU_D: Q1206.5 Q1206.6 R1579.1
SLP_SLP_S0#_CPU_G: C1607.1 Q1206.2 R1581.1
SM_RCOMP_1: CPU2.BA26 R1217.2
SMB0_ALERT#: PC5254.1 Q1210.D R1623.1 R1743.2
SMB0_ALERT#_C: CPU2.AM9 PC5251.1 Q1210.S R1742.2
SMB0_CLK_C: CPU2.AM6 Q1204.S R1739.2
SMB0_CLK_MAIN: DIMM1.202 PC5256.1 Q7.4 Q123.6 Q1212.S R1744.2 U6701.4 XDP1.53
SMB0_CLK_RESUME: Q1204.D Q1212.D R14.1 R1741.2 R80238.2
SMB0_CVT_CLK: C3456.1 R79633.1 U120.6
SMB0_CVT_DATA: C43.1 R79634.1 U120.7
SMB0_DATA_C: CPU2.AM7 Q1203.S R1738.2
SMB0_DATA_MAIN: DIMM1.200 PC5255.1 Q4.4 Q123.3 Q1213.S R1745.2 U6701.6 XDP1.51
SMB0_DATA_RESUME: Q1203.D Q1213.D R1622.1 R1740.2 R80239.2
SMBUS_ISP: C1877.1 Q4.2 Q4.5 Q7.2 Q7.5 R297.2 R2079.2 U109.115
SMBUS_ISP_G: Q95.2 Q95.5 R2079.1 R2080.2
SOC_EXTSMI_N: CPU2.AG53 R1810.2 R1811.1
SOC_RUNTIME_SCI#: CPU2.AG51 R1569.1 R1808.1 R1809.2
SOC_RUNTIME_SCI#_XDP: C1605.2 R1569.2 XDP1.47
SPEED_100*_CON: RJ1.12 UR6.2
SPEED_100_N: U20.26 U6705.6 UR6.1
SPEED_1000*_CON: RJ1.11 UR7.2
SPEED_1000_N: U20.25 U6705.1 UR7.1
SPI_CLK: CPU2.W3 R1714.1
SPI_CLK_1: R1714.2 SRCON1.6 U8.6
SPI_CS0_N: CPU2.V4 R1733.1
SPI_CS0_N_ROM_1: R172.2 R1733.2 SRCON1.1 U8.1
SPI_DATAIN: CPU2.V3 R1731.2
SPI_DATAOUT: CPU2.V2 R1732.1
SPI_IO2: CPU2.U1 R1730.2
SPI_IO3: CPU2.U3 R1729.1
SPI_MISO_ROM_1: R1731.1 SRCON1.2 U8.2
SPI_MOSI_1: R1732.2 SRCON1.5 U8.5
SPI_WP#: R169.2 R1730.1 SRCON1.3 U8.3
SPKR_DET: R388.1 R1203.1 U109.59
SPKR_DET_C: PC2127.2 R1203.2 SPK1.6
SPKR_IN_L: C199.2 C203.2 U21.6
SPKR_IN_R: C210.2 U21.31
SPKR_L+_C: C226.1 L31.2 R396.1 SPK1.1
SPKR_L+_SNB: C222.1 R396.2
SPKR_L-_C: C236.1 L32.2 R403.1 SPK1.2
SPKR_L-_SNB: C239.1 R403.2
SPKR_OUT_L+: C224.2 C225.1 L31.1 U21.16
SPKR_OUT_L-: C228.2 C235.1 L32.1 U21.18
SPKR_OUT_R+: C223.2 C247.1 L33.1 U21.25
SPKR_OUT_R-: C229.2 C255.1 L34.1 U21.23
SPKR_R+_C: C248.1 L33.2 R415.1 SPK1.4
SPKR_R+_SNB: C243.1 R415.2
SPKR_R-_C: C256.1 L34.2 R419.1 SPK1.3
SPKR_R-_SNB: C263.1 R419.2
SPV10: C785.1 C787.1 C789.1 GPU1.H8 L51.2
SPV18: C788.1 C792.1 C793.1 GPU1.H7 L49.2
SST_HOLDJ_1: R186.2 R1729.2 SRCON1.7 U8.7
SSTCMP: R45.1 U120.11
SSTCMP_1: C5.1 R45.2
STATUS: R61.1 U120.8
SUS_LED_GREEN_C: PWRCN1.7 Q68.D R663.2 R667.2
SUS_LED_GREEN_C2: R667.1 R673.2
SUS_PWR_ACK_CPU: R1697.2 U109.13
SUS_PWR_ACK_CPU_R: CPU2.AE3 R499.2 R1697.1
SUSCLK_NGFF: NGFF1.50 TP101.1
SUSCLK_SIO_C: CPU2.C15 TP100.1
SW_ON_N_SIO: R391.2 R395.1 U109.69
SWR_LX: L2.2 U126.17
SWR_V12: C295.1 C296.2 C297.1 C299.1 L2.1 U126.11 U126.15 U126.43
SYNC: TP24.1 U21.11
SYS_3VSB: R382.1 U109.67
SYS_FAN_TACH1_1: FANC3.3 R76.2 R80.2
SYS_FAN_TACH1_2: R73.2 R74.2 R76.1
SYS_PRES: BAT2.7B R79664.2
SYS_PWRGD: Q79.D R178.2 R1601.2 R1920.1
SYS_PWRGD_G: Q78.D Q79.G R717.2
SYSTEM_FAN_PWM1_1: D1.A FANC3.4 R68.2 R71.2
TAP_PRDY#: CPU2.AD45 XDP1.5
TAP_PREQ#: CPU2.AF41 R34.2 R1746.2 U2.4
TAP_PREQ#_R: C35.1 R34.1 R43.2 U2.2 XDP1.3
TCK: TP4126.1 U4101.27
TDI: TP4128.1 U4101.25
TDO: TP4129.1 U4101.24
TESTEN: GPU1.K7 R302.1 R1897.1
TMS: TP4127.1 U4101.26
TP_AD13: CPU2.AD13 TP49.1
TP_AD14: CPU2.AD14 TP50.1
TP_DET: R1719.2 TOUCH1.1 U109.118
TP_GPU_CLKREQ#: GPU1.N7 TP158.1
TP_NGFF_COEX1: NGFF1.48 TP39.1
TP_NGFF_COEX2: NGFF1.46 TP38.1
TP_NGFF_COEX3: NGFF1.44 TP37.1
TP_NGFF_LED1: NGFF1.6 TP63.1
TP_NGFF_LED2: NGFF1.16 TP64.1
TP_NGFF_MLDIR: NGFF1.17 TP62.1
TP_SIO_VIN0: TP46.1 U109.93
TP_Y3: CPU2.Y3 TP57.1
TPA3131_BSNL: C228.1 U21.19
TPA3131_BSNR: C229.1 U21.22
TPA3131_BSPL: C224.1 U21.15
TPA3131_BSPR: C223.1 U21.26
TPA3131_FAULT#: R1597.2 U21.30
TPA3131_GAIN: R358.1 R361.2 U21.3
TPA3131_GVDD: C192.2 R357.2 R361.1 U21.2
TPA3131_LINN: C200.2 U21.5
TPA3131_LINN_1: C200.1 R346.2
TPA3131_MUTE: R360.1 R1598.1 U21.7
TPA3131_PLIMIT: C193.2 R347.2 R357.1 U21.1
TPA3131_RINN: C198.2 U21.32
TPA3131_RINN_1: C198.1 R344.2
TPA3131_SD: Q63.3 Q64.G R639.2 R1598.2
TPA3131_SD1#: C521.1 Q64.D R643.2 R1597.1 U21.29
TSVDD: C758.1 C759.1 GPU1.AD17 L47.2
U1.1: SR1.1 SU1.1
U1.6: SC2.1 SU1.6
U1.24: SC5.2 SU1.24
UART1_RX: CN2.3 CPU2.AD12
UART1_TX: CN2.2 CPU2.AD10
USB1N_C_EXT: SSUSB2.2 TR6.1 U6704.6
USB1P_C_EXT: SSUSB2.3 TR6.4 U6704.1
USB2N_EXT: TR7.4 U6703.3 USB3.2
USB2P_EXT: TR7.1 U6703.4 USB3.3
USB3_OBSN: CPU2.F34 R1236.1
USB3_OBSP: CPU2.D34 R1236.2
USB3N_EXT: TR5.1 U6703.1 USB4.2
USB3P_EXT: TR5.4 U6703.6 USB4.3
USB30_RX_CPU_N0: CPU2.D28 L5.1
USB30_RX_CPU_N1: CPU2.D30 L37.1
USB30_RX_CPU_P0: CPU2.F28 L5.4
USB30_RX_CPU_P1: CPU2.F30 L37.4
USB30_TX_CPU_N0: C104.1 CPU2.C32
USB30_TX_CPU_N0_EMI: C104.2 L4.1
USB30_TX_CPU_N1: C1604.2 CPU2.C33
USB30_TX_CPU_N1_EMI: C1604.1 L36.1
USB30_TX_CPU_P0: C103.1 CPU2.B32
USB30_TX_CPU_P0_EMI: C103.2 L4.4
USB30_TX_CPU_P1: C1603.2 CPU2.A33
USB30_TX_CPU_P1_EMI: C1603.1 L36.4
USB_CPU_PN4: CPU2.C40 TR3.1
USB_CPU_PP4: CPU2.B40 TR3.4
USB_EN_1: C4260.1 R79660.1 U125.4
USB_EN_2: C249.1 R1599.1 U124.4
USB_HSIC_RCOMP: CPU2.N38 R1779.1
USB_OBSP: CPU2.B46 R80149.1
USB_OTG_ID: CPU2.B48 R1791.1
USB_PCH_DN1_NN: TR1.4 WEBCM1.2
USB_PCH_DN4_NN: C6715.1 TOUCH1.4 TR13.3
USB_PCH_DN5_NN: NGFF1.5 TR12.3
USB_PCH_DP1_PP: TR1.1 WEBCM1.1
USB_PCH_DP4_PP: C711.1 TOUCH1.3 TR13.2
USB_PCH_DP5_PP: NGFF1.3 TR12.2
USB_PN4_L: TR3.2 U6702.1
USB_PP4_L: TR3.3 U6702.2
USB_RCOMP: CPU2.A48 R79785.1
USB_VBUSSNS: CPU2.B47 R1846.1 R80147.2
USB_VBUSSNS_R: R1845.2 R1846.2
USBDN1_CHAR: R80051.2 TR6.2 U9625.11
USBDP1_CHAR: R80053.2 TR6.3 U9625.10
USBOC01: CPU2.P14 R79659.1 R80061.2 U125.3
USBOC01_H: R79943.2 U6702.20
USBOC02: CPU2.P16 R709.1 U124.3
USBOC02_H: R79703.2 U6702.19
USBP0N_EXT: SSUSB1.2 TR4.1 U6704.4
USBP0P_EXT: SSUSB1.3 TR4.4 U6704.3
USBVCC14: C409.1 C4261.2 C4262.1 C4263.2 SSUSB1.1 SSUSB2.1 TC11.1 U125.1 U6704.5 U9625.12
USBVCC56: C234.2 C238.1 C271.1 C272.2 TC20.1 U124.1 U6703.5 USB3.1 USB4.1
USBVCCTP: C1674.1 F4.2 R1720.2 TOUCH1.5
V_1P5_HDMI: C4281.1 C4282.1 C4284.1 C4286.1 C4287.1 C4288.1 C4290.2 R79751.1 U119.2 U127.12 U127.19 U127.20 U127.31 U127.40
V_1P05_LAN: C190.1 C191.1 C202.2 C534.2 C538.2 C544.2 C547.2 C548.2 C1801.1 U20.3 U20.8 U20.22 U20.24 U20.30
V_3_CARD_BD: C72.2 C73.2 C74.2 C75.2 F6.1 MEMCD1.4 SU1.5
V_3P0_BAT_VREG: D5.3 R87.1 R91.1 R322.2 R1255.1
V_3P3_A: C179.1 C183.1 C216.1 C217.1 C1666.1 C1699.1 C6725.2 D5.1 L7.1 L9.1 PC5212.2 PC5223.2 PR4425.1 PR4426.1 PR4427.1 PR4450.2 PR4712.1 PR4906.1 PR4908.1 PR4910.1 PR5213.1 PR5214.1 PR5241.1 PR5246.1 PR5257.1 PR5258.1 PR5273.1 PR5278.1 PR5281.1 PR5286.2 PR5289.1 PR5480.1 PR9787.1 PU5201.5 PU5201.9 PU5203.5 PU5203.9 Q9649.S R51.2 R57.2 R65.1 R66.2 R270.2 R275.2 R279.2 R296.2 R304.2 R319.1 R321.1 R338.1 R363.2 R370.1 R639.1 R643.1 R719.1 R1579.2 R5290.1 R79667.2 R79691.1 R79692.2 R79693.2 R79694.2 R80212.2 R80228.2 R80232.1 RN6.3(B) RN6.4(B) U15.8 U52.6 U52.7 U54.6 U54.7 U109.1 U109.32 U109.64
V_3P3_LAN: C194.1 C195.1 C220.1 C221.1 C232.1 C536.2 C537.2 C554.2 C6732.1 C6733.1 C6734.1 Q39.D R372.1 R675.1 R79618.1 U20.11 U20.23 U20.32 U121.5 U122.5 U6705.5
V_3P3_PCIVAUX: C364.1 C391.1 C1608.2 C1609.2 NGFF1.2 NGFF1.4 NGFF1.72 NGFF1.74 Q1209.D R1633.1 R1634.2 R1842.2 R1844.1 TC1.1
V_5_CODEC: C146.1 C147.2 C450.2 L19.1 U6.39
V_5_LCD1: L1.1 U1.4
V_5_LCD2: F2.1 L1.2 R8.2
V_5HDD: C109.1 C110.1 C112.1 R183.2 R185.2 SATAP1.1 SATAP1.3 TC5.1
V_5P0_A: C251.1 C314.1 C1665.1 C1698.1 C4259.1 D21.K L19.2 PC5213.1 PC5224.1 PR48.1 PR4907.1 PR4909.1 PR4913.1 PR4915.1 PR4916.1 PR4926.1 PR5290.2 PR5291.2 PR9793.2 PU5201.6 PU5203.6 U52.1 U52.2 U52.4 U54.1 U54.2 U54.4 U124.5 U125.5 U9625.1
V_5P0_HDMI_CONN: C721.2 HDMI1.18 HDMI2.2 L46.1
V_5P0_HDMI_CONN_L: F13.2 L46.2
V_19_INV: C3459.1 C3460.1 F16.2 L61.1 R79631.2 R79716.1
V_SM: PC5002.1 PC5011.1 PC5012.1 PL5002.2 PR5003.1 PR5004.1 PR5005.1 PR5006.1 PR5007.1 PR5008.1 PR5013.2 PR5014.2 PR5016.1 PTC21.1
VGA_1P8_EN1: Q97.2 Q97.3 R1164.2 R1914.1
VGA_1P8_EN2: Q97.6 R1915.1 R1918.2 R1919.1
VGA_1P8_EN3: R1916.2 U42.3
VGA_1P8_EN4: C859.1 R1915.2 R1916.1
VGA_CORE: C805.1 C806.1 C807.1 C808.1 C809.1 C810.1 C811.1 C812.1 C813.1 C814.1 C815.1 C816.1 C817.1 C818.1 C819.1 C820.1 C821.1 C822.1 C823.1 C824.1 GPU1.AA12 GPU1.AA15 GPU1.M11 GPU1.M13 GPU1.M15 GPU1.M16 GPU1.M17 GPU1.M18 GPU1.M20 GPU1.M21 GPU1.N12 GPU1.N15 GPU1.N17 GPU1.N20 GPU1.R13 GPU1.R16 GPU1.R18 GPU1.T12 GPU1.T15 GPU1.T17 GPU1.T20 GPU1.U11 GPU1.U13 GPU1.U16 GPU1.U18 GPU1.V15 GPU1.V17 GPU1.V20 GPU1.V21 GPU1.Y13 GPU1.Y16 GPU1.Y18 GPU1.Y21 PC5271.2 PG3.2 PL1.2 PR28.1 PT1.1 PT3.1 PT4.1
VGG_HOT: PU4501.2 R1606.2 R1830.2 R1831.2
VGG_PG: PC4410.1 PC4509.1 PR4402.2 PR4403.1 PR4501.2 PU4401.1 PU4501.6
VGG_SENSEN_CPU_N: CPU2.AD22 R1589.1
VGG_SENSEN_CPU_P: CPU2.AD24 R1588.1
VGG_SENSEN_N: PC4514.2 PR4511.2 R1589.2 R1827.1
VGG_SENSEN_P: PR4510.1 R1588.2 R1826.2
VGG_SVID_ALERT: PU4501.4 R1648.2
VGG_SVID_ALERT_R: PR5222.2 R1648.1
VGG_SVID_CLK: PU4501.5 R79792.2
VGG_SVID_CLK_R: PR5220.2 R79792.1 R79937.2
VGG_SVID_DATA: PU4501.3 R1647.2
VGG_SVID_DATA_R: PR5221.2 R1647.1 R79793.2
VNN_SENSEN_CPU: CPU2.AC27 PR9766.1
VOUT_INV: C36.1 C37.1 C38.1 C39.1 C40.1 CONVT1.3 CONVT1.4 D32.K U120.18
VR_SVID_ALERT#: CPU2.AD40 PR5222.1 PR5234.1 R79791.2
VR_SVID_CLK: CPU2.AD42 PR5220.1 PR5233.1
VR_SVID_DATA: CPU2.AD41 PR5221.1 PR5232.1
VR_TT#: TP204.1 U6706.4
VRAM1_VREFCA: C12335.1 MEM3.M8 R885.1 R886.2
VRAM1_VREFDQ: C12334.1 MEM3.H1 R924.2 R928.1
VRAM2_VREFCA: C163.1 MEM1.M8 R230.1 R1905.2
VRAM2_VREFDQ: C835.1 C1854.1 MEM1.H1 R202.2 R203.1
VRAM3_VREFCA: C1869.1 MEM4.M8 R1923.2 R1924.1
VRAM3_VREFDQ: C1867.1 C1868.1 MEM4.H1 R1921.2 R1922.1
VRAM4_VREFCA: C1861.1 MEM2.M8 R1911.2 R79968.1
VRAM4_VREFDQ: C1860.1 MEM2.H1 R945.1 R946.2
VRAM_ZQ1: MEM3.L8 R870.2
VRAM_ZQ2: MEM1.L8 R899.2
VRAM_ZQ3: MEM4.L8 R299.2
VRAM_ZQ4: MEM2.L8 R320.2
VREF: C4.2 U120.2
VREF_1: C140.1 U6.41
VREF_CA_0: R117.2 R122.1 R1671.2
VREF_CA_DIMM1: C81.1 C82.2 DIMM1.126 R1671.1
VREF_DQ_0: R483.1 R484.2 R1670.2
VREF_DQ_DIMM1: C302.1 C303.2 DIMM1.1 R1670.1
VREG_PCIAUX_PCH: Q3.D Q6708.C R10.2 R13.1
VREG_PCIAUX_PCH_1: C1616.1 PC1.2 Q1209.G R13.2
VRP: C155.2 U6.38
VSDIO: Q9632.D Q9634.D R1246.1 R1656.1
VSUM_RC: PC14.2 PR34.2
VSUM_RR: PR42.2 PR51.1
VTT_EN: PU5001.7 R1576.2 R1577.2 R1578.2
WAKE_N: Q19.E R60.1 R1627.1 R1628.2 U20.21
WAKE_N_APU: CPU2.N16 R1263.1
WEA0#: GPU1.G25 MEM1.L3 MEM3.L3
WEA1#: GPU1.H10 MEM2.L3 MEM4.L3
WEBCAM_DET: R5.2 R7.2 U109.114
WEBCAM_DET_M: PC124.2 R5.1 WEBCM1.7
XDP_H_TCK: CPU2.AF42 R466.2 XDP1.57
XDP_H_TDI: CPU2.AD47 R457.2 XDP1.56
XDP_H_TDO: CPU2.AF40 R473.2 XDP1.52
XDP_H_TMS: CPU2.AD48 R458.2 XDP1.58
XDP_H_TRST_N: CPU2.AB48 R456.2 XDP1.54
XDP_PRESENT_N: R1568.2 XDP1.60
XDP_PWNBTN_N: R47.2 TP2.1 XDP1.41
XRF_TDC2: C3452.1 XF1.9 XF1.10 XF2.9 XF2.10
XTAL19D2M_IN: C1601.2 R1239.1 R1240.2 X6.1
XTAL19D2M_IN_R: CPU2.P24 R1240.1
XTAL19D2M_OUT: C1602.2 R1239.2 R1241.2 X6.3
XTAL19D2M_OUT_R: CPU2.M22 R1241.1
XTALIN: C756.1 GPU1.AM28 R1879.1 X8.1
XTALOUT: C757.1 GPU1.AK28 R1879.2 X8.3
N29033036: R721.1 U41.2
N29033116: R719.2 U41.5 U41.6
N31212897: Q47.2 R505.1
N31244723: PC5211.1 PR5214.2 PR5254.1 PU4701.3
N31772467: C1673.1 U52.12
N31772502: C1672.1 U52.10
N31826669: CPU2.BH53 TP4116.1
N31993654: Q47.1 R502.2
N32783600: C1706.1 U54.12
N32783618: C1705.1 U54.10
N33728196: R512.1 R79675.2 R79680.1 R80115.2 R80116.2 R80237.2
N33875524: CPU2.P12 R79658.1
N33886165: CPU2.Y6 TP4136.1
N34111482: CPU2.AF3 TP4135.1
N34111484: CPU2.AG1 TP4134.1
N34388192: Q6702.1 R79764.2
N34388234: Q6702.3 R79765.1
N35052779: Q6715.1 R79798.2
N35059072: Q1253.1 R79690.2
N37176357: CPU2.A6 TP4117.1
N37302844: PC5436.1 PR9785.1 PR9787.2 PU4705.3
N37429584: PR9807.1 Q9632.G
N37429627: PR9808.1 Q9634.G
N37652823: GPU1.AD22 R80137.2
N37662300: GPU1.AF17 R80143.2
N37690583: PR9810.1 Q9640.G
N37690585: PR9811.1 Q9641.G
N37778405: Q9643.5 Q9643.6 R80155.1
N37779677: Q2301.S R3586.1 R80112.2
N37842456: GPU1.A32 TP4131.1
N37842467: GPU1.AM1 TP4132.1
N37842487: GPU1.AM32 TP4133.1
N38212737: Q9647.G Q9650.D R80233.1

Pads without a net: BAT2 1A 2A 3A 4A 5A 6A 7A 8A 9A 10A; CN1 2; CPU2 A3 A9 A35 A37 A49 A51 A52 AA30 AB7 AB9 AC51 AD6 AF44 AF45 AF48 AF50 AH45 AK2 AK3 AK9 AK10 AK12 AK13 AL1 AL3 AM2 AM3 AP2 AP3 AP6 AP7 AP10 AP12 AP13 AP14 AR1 AR3 AT2 AT4 AT6 AT7 AT10 AT12 AT13 AT14 AT16 AT20 AT22 AT24 AT26 AT30 AU16 AU20 AU22 AU24 AU26 AU30 AV2 AV3 AV4 AV6 AV7 AV9 AV12 AV13 AV18 AV20 AV22 AW1 AW3 AY2 AY4 AY6 AY12 AY14 AY16 AY18 B4 B5 B7 B8 B10 B12 B20 B34 B38 B49 B50 B53 BA1 BA3 BA12 BA14 BA16 BA18 BA20 BA22 BB3 BB5 BB7 BB8 BB10 BC1 BC2 BC12 BC18 BC20 BC22 BC24 BD2 BD5 BD7 BD10 BD12 BD14 BD16 BD18 BD20 BD22 BD24 BD26 BE2 BE8 BF2 BF6 BF10 BF14 BF16 BF18 BF20 BF24 BG9 BG11 BG12 BG13 BG15 BG17 BG21 BG22 BG23 BG25 BG26 BH6 BH7 BH8 BH10 BH12 BH14 BH16 BH18 BH20 BH22 BH24 BH26 BJ6 BJ9 BJ13 BJ17 BJ21 BJ25 C7 C9 C11 C19 C34 C35 C37 C38 C49 C53 D6 D12 D36 D44 D48 D52 E8 E52 E53 F7 F10 F12 F36 F40 F42 F44 G32 G34 G36 G40 G42 G44 H5 H7 H46 H47 J12 J14 J26 J32 J34 J36 J40 K6 K7 K9 K10 K20 K26 K38 K40 K44 K47 K48 L13 L51 L53 M4 M7 M10 M12 M20 M26 M32 M34 M36 M38 M44 M47 M48 M51 M52 N26 N34 N36 P6 P7 P9 P18 P26 P28 P30 P34 P45 P47 P48 P50 P51 R53 T6 T13 T41 T42 T44 T45 T48 T50 V6 V7 V9 V10 V12 V13 V14 V45 V47 V48 V50 V51 V52 W53 Y12 Y13 Y41 Y47 Y48; DIMM1 77 122 125; GPU1 AA1 AA3 AA5 AA6 AA29 AA31 AB2 AB4 AB7 AB8 AB9 AB12 AB13 AB23 AB25 AB26 AB27 AB28 AB30 AC1 AC3 AC5 AC6 AC7 AC8 AC10 AC11 AC13 AC20 AC23 AC25 AC29 AC31 AD2 AD4 AD7 AD9 AD10 AD16 AD20 AD24 AD26 AD27 AD30 AE1 AE3 AE8 AE9 AE10 AE11 AE13 AE16 AE19 AE24 AE25 AE26 AF2 AF4 AF6 AF7 AF8 AF9 AF10 AF11 AF13 AF24 AF25 AF26 AF27 AG1 AG3 AG5 AG6 AG7 AG8 AG9 AG10 AG11 AG13 AG25 AG26 AH1 AH3 AH5 AH6 AH8 AH12 AH20 AH24 AJ7 AJ9 AJ13 AJ19 AJ23 AJ25 AK1 AK3 AK5 AK6 AK8 AK18 AK20 AK24 AK26 AL7 AL9 AL13 AL19 AL21 AL25 AM3 AM5 AM6 AM8 AM12 AM26 J8 J22 J25 K13 K30 L9 L16 L17 L29 L31 M27 M28 M30 N3 N5 N6 N9 N26 N29 N31 P7 P23 P24 P26 P27 P28 P30 R29 R31 T7 T10 T23 T24 T26 T27 T28 T30 U1 U3 U5 U6 U10 U23 U24 U26 U29 U31 V2 V4 V6 V27 V28 V30 W1 W3 W5 W6 W7 W8 W9 W10 W23 W24 W29 W31 Y2 Y4 Y6 Y7 Y8 Y11 Y23 Y24 Y26 Y27 Y28 Y30; HDMI1 13 14; HDMI2 6 7; LPC1 10; MEM1 J1 J9 L1 L9 M7; MEM2 J1 J9 L1 L9 M7; MEM3 J1 J9 L1 L9 M7; MEM4 J1 J9 L1 L9 M7; NGFF1 64; PU5206 7; RN3 4 5; SU1 7 9 12 14 16 17 19 22 23; TOUCH1 6 7; U2 1; U6 15 16 17 34 37 45 46; U109 50 51; U130 5 6; U4101 7 8 16 18 31 40 42 43 46 54 55 57; U6701 2 3; U6705 3; U6706 26 28 29 30; XDP1 6 22 23 24 40 42 55

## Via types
v1: diameter 0.508, hole 0.254, TOP to BOTTOM, 2049 vias
v2: diameter 0.559, hole 0.305, TOP to BOTTOM, 1416 vias
v3: diameter 0.762, hole 0.381, TOP to BOTTOM, 669 vias
v4: diameter 0.66, hole 0.33, TOP to BOTTOM, 1164 vias
v5: diameter 0.711, hole 0.356, TOP to BOTTOM, 15 vias
v6: diameter 0.711, hole 0.406, TOP to BOTTOM, 837 vias
v7: diameter 0.102, hole 0.051, TOP to BOTTOM, 1 via

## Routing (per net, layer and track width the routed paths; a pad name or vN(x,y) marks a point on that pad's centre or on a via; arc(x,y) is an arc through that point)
3V_VA: length 19.1
  TOP w0.203: U6.23 161.35,45.08 161.36,45.07 161.36,44.71 C495.1 162.33,43.94 162.67,44.28 162.67,45.75 162.57,45.85 U6.25
  TOP w0.635: 163.53,42.7 C493.1 162.33,43.14 C495.1 v3(163.41,43.74) C483.1 164.97,42.71 C485.2 164.91,42.69 164.06,42.69 163.53,42.7 ; 163.53,42.7 v2(163.84,42.7)
  BOTTOM w0.635: v2(163.84,42.7) 162.64,41.5 L21.2
19V_AMP_AVCC: length 5.8
  TOP w0.305: C208.1 156.04,36.07 156.04,34.98 155.6,34.54 U21.12
  TOP w0.635: C208.1 156.14,37.29 R376.2 156.9,37.41 v3(157.34,37.86)
19V_AMP_PVCC: length 14.3
  TOP w0.305: U21.13 155.1,33.89 v2(154.85,34.14) 154.6,33.89 U21.14 ; U21.28 155.1,27.32 v2(154.85,27.07) 154.6,27.32 U21.27
  TOP w0.508: C552.1 154.06,25.78 154.85,26.58 v2(154.85,27.07) ; C545.1 154.16,35.23 154.85,34.54 v2(154.85,34.14)
  BOTTOM w0.508: v2(154.85,27.07) 153.99,27.07 C551.2
  BOTTOM w0.635: C543.1 153.2,35.06 v4(153.24,35.1) 153.9,35.1 v2(154.85,34.14)
  vias: v6(153.63,36.91)
+1.5V_GPU_PG: length 4.3
  TOP w0.254: PR225.2 PC151.1 62.44,128.83 61.68,129.59 v3(61.68,129.6) 61.67,129.6 61.34,129.93 PU7.7
+5V_PWR: length 2
  TOP w0.305: PG4903.1 97.54,71.03 97.38,70.87 97.37,70.87 96.6,70.1 PR4907.2
  vias: v3(86.23,70.24)
+5VL: length 2.4
  TOP w0.254: PR4918.1 66.45,59.23 PG4901.2
  TOP w0.381: PR4918.1 68.36,58.3 v3(68.4,58.34)
AGND: length 41.5
  TOP w0.203: v2(159.62,52.96) 159.74,52.84 U6.42 ; U6.22 160.95,45.01 161.02,44.94 161.02,44.35 160.56,43.89 v2(160.56,43.79) ; U6.28 163.29,47.77 164.17,46.89 v2(164.47,46.89)
  TOP w0.381: C157.2 169.39,76.52 v2(169.2,76.71) ; R1182.2 v2(172.07,81.61)
  TOP w0.508: R216.2 85.44,36.16 86.25,35.34 v2(86.25,35.27) 86.76,34.77 C267.1 ; v2(159.29,39.75) 158.63,40.41 R300.2 ; R281.2 R221.2 v2(169.2,78.42) ; v2(171.94,78.16) 171.94,78.23 171.75,78.42 C134.2 C159.2 ; v2(154.69,19.89) 154.66,19.93 C270.1 ; v2(82.89,35.13) 83.6,34.42 C268.1 ; v2(166.94,54) 166.89,54 166.71,53.82 R268.2 ; v2(160.56,43.79) 160.66,43.79 160.71,43.74 C495.2 161.44,42.89 C493.2 ; v2(166.91,43.74) 165.88,43.74 C483.2 165.86,43.01 C485.1
  TOP w0.635: v2(156.17,60.4) 155.2,59.44 R1193.2 ; v2(161.07,54.36) 161.07,54.58 161.51,55.03 C147.1 C145.1 ; C1491.2 161.12,42.57 C493.2 ; LOUT1.P 77.01,40.91 LOUT1.5
  BOTTOM w0.635: Q28.S 155.8,60.04 v2(156.17,60.4) ; C450.1 158.5,57.61 v2(158.35,57.75) ; R215.2 159.52,51.94 v4(159.49,51.92) 159.47,51.94 159.47,52.79 159.62,52.94 v2(159.62,52.96) ; v4(155.35,20.5) 154.74,19.89 v2(154.69,19.89)
  vias: v2(161.27,59.72) v2(163.62,65.86) v2(164.12,59.33) v2(170.98,72.64) v3(161.45,63.4) v6(152.46,2.82)
AVCC33_2136: length 20.7
  TOP w0.508: v2(33.71,93.78) 33.69,93.78 33.6,93.69 32.54,93.69 30.97,92.13 30.97,88.49 32.61,86.85 32.61,85.28 33.56,84.33 v2(33.82,84.33)
  BOTTOM w0.203: v2(33.71,93.78) 33.84,93.9 U126.5
  BOTTOM w0.508: C292.2 33.47,80.48 32.79,81.16 C293.2 C298.1 32.79,83.77 v4(32.97,83.95) 33.35,84.33 v2(33.82,84.33)
  BOTTOM w0.635: L17.2 C292.2
AVCC_EC: length 8.8
  TOP w0.203: U4101.52 147.33,72.44 146.83,72.94 v1(146.3,72.94)
  BOTTOM w0.381: v1(146.3,72.94) 147.05,72.94 R80130.1
  BOTTOM w0.508: L4101.2 144.38,70.08 144.38,70.08 C4102.1 144.75,70.47 145.09,70.82 v4(145.09,71.05) 145.09,71.1 145.09,71.1 145.09,72.04 R80133.2 144.86,72.39 145.37,72.9 146.26,72.9 v1(146.3,72.94)
DVCC33_2136: length 58.3
  TOP w0.305: 45.03,78.78 45.35,79.1 46.65,79.1 R69.1
  TOP w0.508: v2(37.63,98.59) 36.15,97.12 36.15,94.45 33.72,92.02 v2(33.56,92.02) 33.39,92.02 32.85,91.49 32.85,89.1 35.92,86.03 35.92,82.55 ; 45.03,78.78 R79686.1 44.39,78.79 41.73,78.79 38.33,82.19 36.28,82.19 35.92,82.55 ; 35.92,82.55 v2(34.98,81.61)
  BOTTOM w0.203: U126.22 39.18,99.02 ; U126.18 37.58,98.54 v2(37.63,98.59)
  BOTTOM w0.305: v2(34.98,81.61) 34.97,81.61 v4(34,82.58)
  BOTTOM w0.381: v2(33.56,92.02) 33.12,92.02 32.28,91.19 R1074.1
  BOTTOM w0.508: 36.14,102.78 v4(36.13,102.79) ; 36.14,102.78 37.05,102.78 C291.1 37.65,102.11 38.65,101.1 38.65,100.7 39.18,100.18 39.18,100.06 ; 36.14,102.78 C290.1 C289.1 36.14,100.69 36.86,99.96 36.86,99.26 37.52,98.6 37.62,98.6 v2(37.63,98.59) ; 39.18,100.06 39.73,100.06 40.49,100.82 40.51,100.82 C284.1 41.41,101.97 C283.2 41.41,102.92 40.7,103.63 40.17,103.63 38.78,105.02 L16.2 ; 39.18,100.06 39.18,99.02
GND: length 2005.2
  TOP w0.127: GPU1.B22 v1(71.17,104.4) ; GPU1.B26 72.59,107.59 71.54,107.59 v1(71.53,107.58) ; v1(59.52,95.79) 59.16,95.42 59.16,95.02 58.81,94.68 MEM2.M1 ; GPU1.B6 72.59,91.6 72.56,91.63 71.72,91.63 71.52,91.43 v1(71.46,91.43) ; v1(71.49,93.3) 71.6,93.2 GPU1.B8 ; GPU1.H2 76.27,89.53 v1(76.27,88.69) ; v1(71.65,96.4) GPU1.B12 ; v1(94.75,94.18) 94.52,94.41 92.82,94.41 92.43,94.8 GPU1.AH10 ; v1(71.34,97.82) 71.41,97.82 71.59,98 GPU1.B14 ; GPU1.B20 71.02,102.8 v1(70.9,102.93)
  TOP w0.203: U4101.45 145.77,70.83 v1(146.18,71.25) ; PU5001.14 152.76,134.28 152.36,133.88 v1(151.7,133.88) ; v1(132.74,34.68) 132.54,34.48 U127.35 ; U109.35 129.21,64.63 v2(129.14,64.57) ; U127.8 134.63,36.57 v1(133.63,35.57) ; v1(143.31,80.49) 143.37,80.43 U4101.10 ; v1(141.21,74.57) 141.21,75.23 140.8,75.64 U4101.21 138.68,75.64 138.25,76.07 C4101.2 ; U6706.27 130.18,85.83 v1(129.65,86.36) ; U4101.53 147.44,72.84 147.37,72.91 147.36,72.91 147.22,73.04 147.22,73.38 146.83,73.77 v1(146.39,73.77) ; U127.15 132.94,36.66 v1(132.74,36.46) ; U52.11 v1(105.01,57.18) ; U109.4 v2(132.82,53.14) ; v2(117.36,62) 117.29,61.94 U109.71 ; PU4501.11 v1(25.69,162.23) ; v1(132.12,86.26) 132.18,86.2 U6706.22 ; v2(149.08,134.09) 149.28,133.88 PU5001.3 ; PU5001.1 v2(150.15,135.33)
  TOP w0.229: v1(75.08,97.48) 75.25,97.48 75.56,97.79 75.57,97.79 75.68,97.91 75.72,97.91 76.01,98.2 GPU1.H14
  TOP w0.254: v2(155.66,40.39) 155.68,40.41 R300.1 ; v1(134.46,185.75) 133.86,185.15 DIMM1.19 128.72,185.15 ; v2(135.36,134.32) 135.36,133.95 134.36,132.95 ; v1(71.51,106.11) 72.44,106.11 72.55,106 GPU1.B24 ; v1(132.75,179.4) 132.75,179.54 132.54,179.75 DIMM1.37 128.94,179.75 ; CN2.6 161.33,171.27 160.18,171.27 159.89,171.56 CN2.4 ; DIMM1.144 138.4,145.25 138.11,144.96 137.22,144.96 v1(136.76,145.42) ; v2(146.92,189.5) 146.85,189.57 XDP1.2 ; v2(146.92,189.5) 146.92,189.53 145.38,191.07 XDP1.8 ; v2(146.92,189.5) 146.95,189.53 146.95,189.97 147.3,190.32 147.3,190.32 147.99,191.01 148.06,191.08 149.6,191.08 XDP1.7 ; C4290.1 R79747.2 130.71,42.01 v2(129.87,42.84) ; v1(89.49,136.3) 89.49,134.14 87.7,132.35 C522.2 R646.2 ; DIMM1.44 138.13,177.65 v2(137.45,178.33) ; PC5228.2 20.78,173.3 20.18,173.91 20.18,174.96 v2(20.94,175.72) ; v2(136.89,183.73) 137.57,183.05 DIMM1.26 ; XDP1.32 146.44,197.07 v2(146.91,197.55) 146.99,197.55 147.46,197.07 XDP1.31 ; C24.1 135.57,204.6 v2(136.15,205.18) ; v1(132.72,144.87) 132.64,144.95 DIMM1.145 129.23,144.95 ; C4283.2 132.9,29.31 v2(132.81,29.22) 132.73,29.13 R79741.2 ; R360.2 161.26,36.07 v2(161.39,36.2) ; 129.36,141.95 DIMM1.155 135.2,141.95 v1(135.67,142.42) ; GPU1.Y20 85.66,102.66 85.66,102.88 v1(85.72,102.94) ; Q1206.4 88.26,126.1 87.62,126.73 87.62,127.81 v2(87.52,127.91) ; v2(114.46,205.94) 114.15,206.25 NGFF1.7 ; v1(73.03,88.6) 73,88.63 GPU1.C1 ; C4260.2 157.94,125.77 v1(156.91,124.74) 156.65,124.48 C4259.2 ; v1(137.13,147.68) 137.13,147.56 v1(136.35,146.79) 136.28,146.71 v1(135.24,146.71) ; v1(137.13,147.68) 137.19,147.61 137.19,147.56 137.7,147.05 DIMM1.138 ; v1(137.13,147.68) 137.7,148.25 DIMM1.134 ; v1(120.73,81.94) 121.22,82.42 PR26.2 ; Q9643.4 85.12,126.3 85.42,126.61 86.15,126.61 86.42,126.88 Q9643.1 ; MEM1.T1 52.4,105.68 52.14,105.94 v1(51.94,105.94) ; U41.4 7,219.87 7.33,220.2 8.14,220.2 8.3,220.37 U41.1 8.3,221.27 8.85,221.82 v1(10.32,221.82) ; v1(133.59,189.28) 133.17,188.86 133.15,188.86 132.46,188.17 132.46,188.15 DIMM1.9 128.64,188.15 ; C380.1 97.51,131.4 98.22,130.69 Q49.4 98.89,131.42 99.11,131.64 99.88,131.64 100.2,131.96 Q49.1 100.2,133.84 v1(100.26,133.91) ; XDP1.25 147.2,195.57 v2(146.72,195.1) ; U21.17 151.91,32.36 v2(151.81,32.46) ; v1(87.13,90.91) 87.4,91.18 GPU1.AB6 ; v2(152.94,47.85) 152.94,48.04 C126.1 ; XDP1.38 145.52,198.57 146.36,199.42 v2(146.77,199.42) 147.61,198.57 XDP1.37 ; v1(90.59,111.37) 90.6,111.36 GPU1.AF32 ; Q97.1 75,116.49 74.25,115.75 74.25,115.4 R1914.2 73.36,115.16 v1(73.21,115.32) ; v2(139.75,64.41) 140.21,64.41 140.74,63.88 140.84,63.88 ; DIMM1.128 137.69,150.05 v1(137.01,149.37) ; PC4701.2 135.64,110.81 v1(135.64,111.25) ; 129.39,136.55 DIMM1.173 132.14,136.55 132.15,136.54 134.19,136.54 v1(135.47,137.82) ; 140.84,63.88 141.58,63.88 142.14,64.44 Q30.1 ; 140.84,63.88 Q30.4 ; v1(137.94,131.47) 138.53,131.47 138.55,131.45 DIMM1.190 ; PR4718.2 134.2,116.4 133.77,115.81 PR4702.2 133.77,114.99 134.56,113.93 135.01,113.48 135.01,112.73 135.37,112.37 135.39,112.37 v1(135.64,112.12) ; U21.20 152.07,30.86 v2(151.82,30.61) 152.07,30.36 U21.21 ; 128.84,177.95 DIMM1.43 132.32,177.95 132.46,177.81 132.89,177.81 133.41,178.33 v1(133.48,178.33) ; C1618.2 57.65,152.02 58.33,152.02 59.16,152.86 62.82,152.86 63.25,152.43 v2(66.35,152.43) 66.92,152.99 66.92,154.81 66.58,155.14 v2(66.3,155.14) ; R1217.1 100.43,154.05 v1(100.43,155.13) R1216.2 ; v2(150.22,43.43) 151.01,44.22 C129.1 ; DIMM1.2 137.98,190.25 v1(137.93,190.3) ; v1(135.36,173.58) 134.73,174.22 132.93,174.22 132.8,174.35 DIMM1.55 128.81,174.35 ; v2(29.62,139.95) 28.99,140.59 21.51,140.59 20.42,141.68 20.42,141.68 20.33,141.77 20.33,143.45 19.99,144.51 19.68,145.36 19.3,146.87 19.3,153.48 20.07,154.25 26.14,154.25 27.99,156.1 PR4514.2 ; v1(132.77,183.59) 132.53,183.35 DIMM1.25 128.31,183.35 ; v1(84.94,178.42) CPU2.AJ53 ; U21.8 v2(157.94,33.17) ; v6(16.06,222.28) 16.04,222.25 PU4.11 16.04,218.87 v6(16.42,218.49) ; R562.2 85.3,145.15 85.3,144.45 v1(85.55,144.2) ; R80157.1 130.4,45.36 v2(130.39,45.36) 130.12,45.63 C180.2 ; v1(134.18,188.34) 132.79,186.95 DIMM1.13 128.7,186.95 ; v1(70.04,161.06) 70.09,161.11 CPU2.A19 ; C545.2 v2(151.47,35.81) ; 128.6,172.55 DIMM1.61 132.78,172.55 v1(133.69,173.46) ; v1(132.7,169.21) 132.36,169.55 DIMM1.71 128.6,169.55 ; v1(132.81,171.46) 132.7,171.35 DIMM1.65 128.59,171.35 ; GPU1.A3 71.95,90 v1(71.64,89.69) ; 14.58,191.08 v2(14.54,191.03) ; v1(132.82,131.53) 132.79,131.53 132.57,131.75 DIMM1.189 129.39,131.75 ; v1(110.15,51.54) 110.48,51.88 R80215.2 ; v1(132.7,146.92) 132.53,146.75 DIMM1.139 129.47,146.75 ; DIMM1.72 137.11,169.25 v1(137.02,169.34) ; v1(70.67,156.82) 70.67,156.88 71.02,157.23 CPU2.A11 ; U9625.14 145.72,113.09 v1(145.47,112.84) ; GPU1.F14 74.6,97.89 74.99,97.5 75.06,97.5 v1(75.08,97.48) ; v2(152.65,189.23) 152.31,189.57 XDP1.1 ; v1(83.88,120.52) 83.71,120.36 83.71,118.89 84.07,118.53 R1917.1 ; v1(134.35,190.75) 134.35,190.75 133.64,190.05 132.46,190.05 132.36,189.95 DIMM1.3 128.88,189.95 ; DIMM1.14 137.71,186.65 136.66,187.71 v1(136.66,187.81) ; DIMM1.8 137.64,188.45 136.84,189.26 v1(135.44,189.26) ; v1(137.13,134.29) 137.13,134.13 138.01,133.25 DIMM1.184 ; 51.94,90.04 v1(51.92,90.04) ; v1(136.74,135.36) 137.37,135.36 137.65,135.08 138.32,135.08 138.35,135.05 DIMM1.178 ; PQ4406.4 55.9,72.6 56.47,72.03 57.62,72.03 57.9,72.31 58.57,72.31 PR9812.1 ; DIMM1.38 138.57,179.45 137.79,180.22 v1(137.79,180.33) ; v1(133.5,143.91) 132.74,143.15 DIMM1.151 129.53,143.15 ; v1(82.22,161.59) 82.59,161.97 CPU2.AD21 ; XDP1.59 149.09,204.6 v2(149.09,204.75) ; v1(137.07,181.84) 137.57,181.33 138.21,181.33 138.29,181.25 DIMM1.32 ; v1(132.75,140.59) 132.31,140.15 DIMM1.161 128.63,140.15 ; 128.41,176.15 DIMM1.49 ; CPU2.A15 70.37,159.17 70.12,158.92 v1(70.04,158.92) ; R542.2 103.03,151.21 v1(103.06,151.23) ; v2(66.33,150.37) 66.33,149.59 R1265.2 ; CPU2.BJ43 v1(95.42,172.77) ; v1(71.51,94.94) 72.46,94.94 GPU1.B10 ; v1(76.46,121.01) 77.81,119.66 R1919.2 77.35,119.65 Q97.4 ; v1(121.84,40.72) 121.6,40.97 HDMI2.25 120.52,40.82 v2(118.9,40.82) ; v1(78.14,151.35) CPU2.R1 ; CPU2.AE1 83,151.65 82.96,151.61 v1(82.96,151.56) ; GPU1.A30 71.98,110 71.94,110.04 71.55,110.04 71.53,110.02 v1(71.32,110.02) ; GPU1.AC17 88.2,100.91 v1(87.92,101.19) ; 131.43,73.56 OSC2.2 ; 129.37,134.75 DIMM1.179 132.38,134.75 132.45,134.82 133.03,134.82 v1(133.48,135.28) ; v1(100.34,87.15) 100.15,86.96 R1894.2 ; 53.75,154.81 53.53,154.59 53.53,152.62 53.63,152.53 ; v1(132.66,181.86) 132.37,181.57 132.37,181.55 DIMM1.31 128.66,181.55 ; v1(136.89,140.51) 136.89,140.39 137.42,139.85 137.67,139.85 ; CPU2.AJ1 84.94,151.72 v1(85.07,151.59) ; PR31.2 121.51,83.82 120.81,83.82 120.78,83.85 v1(120.76,83.85) ; GPU1.F6 74.38,91.38 74.38,91.13 v1(74.37,91.12) 74.68,90.81 74.77,90.81 75.01,90.57 75.01,90.18 74.6,89.77 GPU1.F2 ; U21.24 152.18,28.86 v2(151.93,28.6) ; MEM1.D8 58.01,115.21 57.9,115.1 57.9,114.59 MEM1.E8 58.38,114.11 MEM1.F9 58.96,113.54 58.96,113.14 58.81,113 MEM1.G9 58.73,112.8 58.1,112.8 MEM1.G8 ; U21.9 v2(157.1,34.15) 156.87,34.15 156.6,33.89 U21.10 ; CPU2.A43 v1(70.61,172.77) ; C132.1 153.92,42.76 153.5,42.34 153.5,42.34 v2(153.45,42.29) ; DIMM1.156 138.1,141.65 v1(137.93,141.82) ; R332.2 31.43,21.29 31.64,21.5 v2(31.64,21.62) ; v1(96.53,106.05) 96.85,106.05 97.15,106.34 C752.2 97.73,105.95 R80142.1 ; 129.43,132.95 DIMM1.185 134.36,132.95 ; PR9770.2 121.12,88.05 120.26,88.05 v1(120.23,88.09) 120.23,87.58 120.96,86.84 PR9780.2 ; 134.36,132.95 135.44,131.87 v1(135.44,131.5) ; XDP1.14 146.32,192.58 146.82,192.07 v2(146.82,192.05) 146.85,192.05 147.37,192.58 XDP1.13 ; Q17.4 108.05,119.01 108.67,118.39 v2(108.67,118.3) ; 137.67,139.85 DIMM1.162 ; 137.67,139.85 137.07,139.24 v1(137.07,138.71) ; v2(146.72,195.1) 147.76,194.06 149.36,194.06 149.38,194.08 XDP1.19 ; v2(146.72,195.1) 146.24,195.57 XDP1.26 ; v2(146.72,195.1) 145.7,194.08 XDP1.20 ; Q16.4 93.85,126.53 94.48,125.9 94.48,125.56 94.81,125.23 Q16.1 96.69,125.23 v2(97.18,125.72) 97.58,126.12 97.58,126.5 C30.2 ; 91.8,98.37 v1(91.8,98.4) ; DIMM1.196 138.33,129.65 v1(137.92,130.06) ; R677.2 114.05,66.98 112.82,68.21 112.82,68.25 v2(112.78,68.29) 112.78,68.25 C218.2 ; v1(140.47,113.85) 139.2,113.85 138.95,113.59 PC5436.2 ; v1(71.69,101.39) 72.41,101.39 GPU1.B18 ; DIMM1.20 137.74,184.85 136.9,185.69 v1(136.9,185.88) ; R555.2 82.36,143.68 82.36,145.29 v1(82.46,145.39) ; v1(88.59,92.01) GPU1.AD6 GPU1.AE7 ; CPU2.AD36 82.63,169.55 CPU2.AF38 ; v2(26.9,25.25) 26.9,25.13 28.23,23.8 28.75,23.8 29.26,23.29 29.34,23.29 29.47,23.29 29.51,23.25 PWRCN1.4 ; v1(69.98,163.06) 69.99,163.06 CPU2.A23 ; v1(137.04,173.53) 137.21,173.53 137.68,173.06 138,173.06 138.21,172.85 DIMM1.60 ; v1(137.93,176.4) 137.98,176.45 DIMM1.48 ; v1(76.01,151.36) 76.2,151.55 CPU2.L1 ; XDP1.50 146.21,201.57 v2(146.67,202.03) 147.12,201.57 XDP1.49 ; C4230.1 149.41,128.38 149.61,128.18 v2(149.61,128.17) ; C531.1 v2(155.94,39.34) ; v2(138.38,61.01) 138.18,60.81 C175.2 ; 129.12,148.55 DIMM1.133 133.24,148.55 133.63,148.93 v1(133.63,149.13) ; U7.8 U7.3 v2(170.53,118.24) ; v1(135.37,149.41) 135.18,149.41 134.24,150.35 DIMM1.127 129.06,150.35 ; v1(80.08,151.6) CPU2.W1 ; C314.2 141.78,116.55 142.07,116.84 v1(142.15,116.84) 142.27,116.96 144.07,116.96 R80049.2 144.39,117.08 144.95,117.64 R80060.2 ; GPU1.B16 72.58,99.58 71.69,99.58 71.69,99.59 v1(71.58,99.59) ; DIMM1.168 v2(140.88,138.05) ; CPU2.AA53 v1(81.06,178.69) ; DIMM1.150 138.19,143.45 138.18,143.43 137.63,143.43 v1(137.13,143.94) ; 174.19,106.05 v2(174.2,106.03) ; v1(78.01,88.61) 77.98,88.64 77.98,88.84 77.8,89.02 GPU1.K2 ; v1(73.52,151.61) 73.55,151.65 CPU2.F1 ; v1(92.2,111.38) GPU1.AH32 ; R456.1 v2(138.62,205.13) ; DIMM1.172 137.71,136.85 v1(137.29,137.26) ; R1558.2 109.42,200.44 109.96,199.9 v2(110.27,199.9) ; U54.11 v1(161.52,91.71) ; v1(132.88,129.95) DIMM1.195 ; 66.02,173.82 66.02,173.99 66.09,173.99 R80149.2 67.34,175.24 69.73,175.24 v1(69.76,175.26) 70.12,175.26 70.76,174.62 CPU2.A47 ; v1(132.91,137.76) 132.76,137.76 132.17,138.35 DIMM1.167 129.57,138.35 129.11,138.81 ; CPU2.A31 v1(70.26,166.94) ; v1(83.37,144.25) 83.42,144.3 R560.2 ; CPU2.AE53 v1(83,178.39) ; C1659.2 66.17,158.39 v1(66.33,158.24) ; DIMM1.54 138.1,174.65 137.87,174.42 137.3,174.42 v1(136.81,174.91) ; v1(84.94,153.47) CPU2.AJ3
  TOP w0.305: HDMI1.2 HDMI2.18 115.61,33.32 v2(115.55,33.38) ; v1(115.58,31.88) 116.02,32.32 HDMI2.20 ; v2(120.31,209.01) 120.29,209 NGFF1.18 ; MEM2.J8 53.21,92.02 v1(53.61,92.42) ; MEM2.E1 58.81,88.81 v1(58.41,88.41) ; v2(43.64,103.25) 43.4,103.5 LVDS1.7 ; MEM1.D1 52.14,115.56 v1(51.36,115.56) ; MEM2.A9 52.39,85.62 v1(52.01,86) 52.04,86.03 52.04,86.05 MEM2.B9 ; v1(150.53,210.82) 150.53,210.7 Q23.4 ; U6701.12 86.94,77.34 v2(88.07,78.46) 87.43,78.46 86.81,77.83 U6701.13 ; Q21.1 42.51,119.01 42.73,119.23 43.49,119.23 43.81,119.55 Q21.4 ; v1(58.76,118.32) 58.76,117.73 MEM1.A9 ; MEM2.G1 v1(58.41,90.02) ; v1(77.88,142.44) 77.88,142.38 76.37,140.87 C80.2 ; MEM2.E2 58.01,88.81 v1(58.41,88.41) ; MEM2.B3 57.15,86.42 v1(56.78,86.06) ; U6701.10 86.89,76.33 87.07,76.16 v2(88.07,76.16) ; NGFF1.24 v2(119.88,210.5) ; U6701.16 84.75,78.75 v2(85,78.99) 85.25,78.74 U6701.15 ; v1(57.62,91.62) 58.01,92.02 MEM2.J2 ; v1(51.48,114.44) 51.53,114.39 52.25,114.39 52.34,114.48 MEM1.E1 MEM1.E2 ; MEM2.D1 58.81,88.02 v1(58.41,88.41) ; v1(52.81,95.62) 52.41,96.01 MEM2.P9 ; NGFF1.23 v2(109.12,210.25) ; C1704.2 166.05,89.89 167.14,88.8 v1(167.14,88.44) ; MEM2.T1 58.79,97.62 58.41,97.24 v1(58.4,97.24) ; v1(54.7,118.75) 54.7,117.56 MEM1.B3 ; v1(58.43,106.09) 58.43,106.06 MEM1.T9 ; NGFF1.30 v2(119.88,212) ; v2(82.06,76.49) 82.06,76.37 82.59,75.84 U6701.5 ; HDMI1.11 v2(115.55,37.82) ; MEM2.E8 53.24,88.82 v1(53.63,88.42) 53.23,88.02 MEM2.D8 ; MEM1.B1 52.23,116.88 52.13,116.98 52,116.98 v1(51.9,117.08) ; MEM2.P1 59.29,96.02 v1(59.52,95.79) ; MEM2.G8 53.11,90.52 52.51,90.52 MEM2.G9 52.36,90.42 51.97,90.04 51.94,90.04 52.36,89.62 MEM2.F9 ; HDMI1.17 v2(118.9,40.82) ; v1(52.46,98.42) 52.41,98.37 MEM2.T9 ; MEM1.B9 59.51,116.88 v1(59.6,116.79) ; NGFF1.63 v2(109.12,220.25) ; NGFF1.69 v2(109.12,221.75) ; v2(43.64,96.62) 43.52,96.5 LVDS1.14 ; NGFF1.36 v2(119.88,213.5) ; v1(51.82,94.53) 51.93,94.42 MEM2.M9 ; v1(59.81,86.58) 59.65,86.42 MEM2.B1 ; Q23.1 154.48,208.9 v1(154.59,208.79) ; v1(148.24,212.47) 148.62,212.47 149.09,212 R162.2 ; NGFF1.33 v2(109.12,212.75) ; NGFF1.57 v2(109.12,218.75) ; HDMI1.8 HDMI2.12 v2(115.55,36.32) ; NGFF1.29 v2(109.12,211.75) ; NGFF1.39 v2(109.12,214.25) ; v2(115.6,34.82) HDMI1.5 ; NGFF1.45 v2(109.12,215.75) ; NGFF1.75 v2(109.12,223.25)
  TOP w0.33: v1(136.34,176.64) 135.85,176.15 DIMM1.49 ; v1(135.34,172.36) 135.34,172.31 136.6,171.05 DIMM1.66
  TOP w0.356: v1(59.48,108.87) 59.46,108.88 MEM1.M9 ; v1(58.4,107.68) 58.42,107.68 MEM1.P9 ; v1(105.29,121.03) 105.29,120.52 105.5,120.31 Q17.1 ; GPU1.Y25 85.65,106.8 v1(85.3,106.45) ; v1(76.52,99.95) 76.52,100.26 76.2,100.58 GPU1.H17 ; GPU1.AD25 v1(89.4,107.2) ; GPU1.AG12 91.4,96.4 v1(91.8,96.8) ; GPU1.U9 84.02,93.58 v1(84.13,93.58) 84.13,95.1 84.4,95.37 GPU1.V11 ; v1(86.9,97.85) 86.65,97.6 GPU1.AA13 ; v1(81.69,112.27) 82.6,111.36 GPU1.T32 ; v1(121.87,37.11) U131.3 U131.8 ; GPU1.F26 74.91,107.91 74.92,107.91 v1(75,107.99) 75.4,108.39 GPU1.G27 ; v1(81.34,91.09) 81.34,91.26 GPU1.P6 ; v1(78.27,95.15) 77.8,95.62 GPU1.K11 ; GPU1.AF20 90.18,103.42 v1(90.18,103.63) ; GPU1.AC9 88.2,94 v1(88.6,93.6) 89,93.2 GPU1.AD8 ; GPU1.F24 74.58,106.02 v1(74,106.02) ; MEM1.J2 53.21,111.28 v1(52.81,111.69) ; v1(45.13,68.33) 45.13,67.78 45.48,67.42 PR5274.1 47.14,67.42 v2(47.3,67.59) ; v1(83.01,107.93) 83.4,108.32 GPU1.U27 83.5,108.4 84.3,107.6 GPU1.W26 ; GPU1.P32 v1(81,112.29) ; GPU1.AM22 94.34,104.4 v1(94.65,104.09) ; Q1206.1 89.9,128.03 90.97,128.03 v2(91.01,127.98) ; v1(79.41,111.37) 79.4,111.36 GPU1.M32 ; Q1229.4 85.1,220.37 v2(85.7,219.76) ; GPU1.F22 74.3,104.4 v1(74.05,104.65) ; GPU1.J27 77,108.39 77.4,107.99 v1(77.4,107.98) ; Q6701.4 18.18,186.73 18.36,186.55 18.36,185.71 18.65,185.43 Q6701.1 19.37,185.05 v2(19.01,184.68) ; v1(90.15,97.77) 90.15,97.85 GPU1.AE14 ; GPU1.AC27 87.82,108.02 87.81,108.02 v1(87.8,108.01) 87.82,107.98 87.82,107.98 GPU1.AC26 ; GPU1.F20 74.73,102.8 75,102.53 v1(75.09,102.53) ; Q1229.1 82.53,221.95 82.29,222.19 v2(81.38,222.19) ; v1(74.04,99.57) 74.11,99.57 74.13,99.6 GPU1.F16 ; v1(57.95,79.26) 57.95,78.61 Q12.1 ; GPU1.K32 77.8,111.26 v1(77.93,111.4) ; GPU1.AA11 85.97,96.03 v1(85.97,96.09) ; GPU1.AF19 90.6,102.15 v1(90.84,102.39) ; R533.2 61.22,76.81 60.78,77.25 v1(60.78,77.25) Q12.4 ; GPU1.AE22 90.6,105 GPU1.AF23 90.63,105.2 90.99,105.55 v1(90.99,105.61) 91,105.61 91.4,105.2 GPU1.AG23 ; PQ4406.1 52.96,73.9 v1(52.61,74.26) ; GPU1.H6 76.51,91.29 76.51,91.21 v1(76.54,91.18) ; v1(86.47,108.94) 86.6,108.81 GPU1.AA27 ; v1(83.9,125.45) 83.93,125.48 84.84,125.48 Q9643.4 ; R523.2 48.29,78.5 Q13.4 49.46,79.17 v2(49.66,79.38) ; GPU1.J7 77.36,92.04 77.36,92.03 v1(77.39,92) 77.4,92 GPU1.K6 ; GPU1.AD23 89,105.21 v1(89.41,105.61) ; GPU1.AA16 86.55,99.6 v1(86.87,99.28) 87.4,98.75 GPU1.AB15 ; U129.8 121.88,33.58 v1(121.87,33.57) ; U130.8 122.78,40.67 121.9,40.67 v1(121.84,40.72) ; v1(81.84,107.8) 81.8,107.85 GPU1.R27 ; MEM1.P1 52.4,107.28 52.03,107.65 v1(51.92,107.65) ; GPU1.T6 82.99,91.21 v1(83.01,91.21) ; v1(84.18,106.5) 84.48,106.8 GPU1.W25 GPU1.W26 ; GPU1.W26 84.8,108.2 GPU1.W27 ; GPU1.Y10 86.03,94.8 v1(86.62,94.21) 87.2,94.79 GPU1.AB10 ; GPU1.AE27 v1(90.2,108.8) ; GPU1.K22 77.79,104.2 v1(77.37,104.62) ; GPU1.E28 73.82,109.2 v1(74.22,109.61) ; GPU1.AC24 88.2,106 87.72,106.48 87.76,106.48 v1(87.79,106.45) 87.79,106.55 87.76,106.55 87.21,106 GPU1.AB24 ; v1(75.24,96.32) 75.16,96.4 GPU1.F12 ; GPU1.G31 v1(75.4,111.03) ; v1(59.39,112.82) 59.33,112.88 MEM1.G9 ; GPU1.Y17 85.01,100.79 v1(84.99,100.79) 84.4,101.39 GPU1.V18 ; MEM1.G1 51.77,112.88 51.76,112.9 v1(51.42,112.9) ; GPU1.V16 84.41,99.6 v1(84.94,99.06) 85.4,98.61 GPU1.Y15 ; v1(75.16,101.15) 75.14,101.15 75.1,101.2 GPU1.F18 ; GPU1.V13 84.21,97.6 83.75,97.13 83.06,97.13 v1(82.99,97.21) 82.99,97.21 GPU1.T13 ; GPU1.AD32 v1(89,111.51) ; GPU1.N25 80.49,107.29 80.49,108.11 GPU1.N27 80.11,108.49 80.11,108.67 v1(79.89,108.89) ; v1(76.54,102.54) 76.54,102.59 76.2,102.93 GPU1.H20 ; GPU1.AM20 94.49,102.8 v1(94.64,102.65) ; Q21.1 41.97,118.88 40.69,118.88 v2(39.83,118.03) ; GPU1.J31 v1(77,110.96) ; GPU1.K28 78.12,108.88 78.12,108.87 v1(78.19,108.8) 78.59,108.4 GPU1.L27 ; MEM1.J8 v1(57.61,110.88) ; v1(79.67,91.11) 79.4,91.37 GPU1.M6 ; GPU1.V32 v1(84.2,111.36) ; v1(80.57,93.71) 80.87,94 GPU1.P9 ; v1(79.28,96.06) 79.28,96.28 GPU1.M12 ; v1(72.75,111.36) 73,111.11 GPU1.C32 ; GPU1.AM24 94.17,106.37 v1(94.17,106.43) ; U35.2 88.08,138 v1(88.13,138.05) ; Q13.1 52.07,77.2 52.38,76.89 v2(52.38,76.43) ; GPU1.AH14 91.83,98.37 91.8,98.37 91.43,98 GPU1.AG14 ; GPU1.AM14 94.11,97.69 94.11,97.59 v1(94.29,97.41) ; v1(74.06,94.64) 74.08,94.64 74.24,94.8 GPU1.F10 GPU1.G10 ; GPU1.G8 75.27,93.07 74.73,93.07 GPU1.F8 74.6,93.2 74.37,93.2 v1(74.09,92.91) ; GPU1.AM16 94.41,99.6 v1(94.42,99.59) ; GPU1.P25 GPU1.T25 82.78,107.18 v1(82.99,107.18) 83.22,107.18 GPU1.U25 ; GPU1.Y32 v1(85.8,111.4) ; MEM1.M1 51.89,108.88 v1(51.86,108.84) ; v1(94.8,101.24) 94.76,101.2 GPU1.AM18 ; GPU1.AB32 v1(87.4,111.36)
  TOP w0.381: PR33.2 121.61,83.87 PR31.2 ; v2(59.57,160.6) 59.51,160.54 55.74,160.54 C1602.1 55.6,160.45 53.56,160.45 52.64,161.37 X6.2 52.18,161.54 51.65,162.08 51.65,164.57 52.48,165.4 v1(54.11,165.4) 54.14,165.38 ; U15.4 142.12,51.98 142.37,51.73 v2(142.37,51.73) ; v1(119.97,89.26) 120.16,89.06 PR9768.2 ; C12342.2 63.9,139.63 63.84,139.58 63.15,139.58 63.12,139.6 v1(62.97,139.6) 63.05,139.52 Q9635.E ; PR53.2 12.35,217.58 v1(12.58,217.58) ; X6.4 54.14,163.9 54.14,165.38 ; v1(132.82,48.23) 132.9,48.31 C179.2 ; R1801.2 102.98,195.41 102.26,196.14 ; 102.26,196.14 102.26,196.03 101.65,195.41 R1802.2 ; 102.26,196.14 v2(102.26,196.3) ; v1(31.43,9.04) 31.1,9.04 30.83,9.31 30.57,9.31 C711.2 ; v2(58.81,162.59) 58.81,165.18 57.72,166.27 56.31,166.27 55.84,165.8 55.84,165.42 C1601.1 55.82,165.38 54.14,165.38 ; U121.2 v2(44.2,12.95) ; v2(42.01,11.18) 42.01,11.17 41.75,10.92 41.56,10.92 C554.1 ; R79757.2 16.02,188.96 v2(16.04,188.98) ; C94.1 157.08,116.97 v1(156.7,117.35)
  TOP w0.406: v2(170.52,96.27) U51.3 U51.8 ; PQ5005.4 v2(47.93,42.11) ; v2(46.35,38.11) 46.63,38.39 PQ5005.1 ; PQ4406.4 54.9,72.6 54.54,72.96 54.54,73.66 54.3,73.9 PQ4406.1
  TOP w0.508: X8.2 101.75,112.17 100.87,113.06 v2(100.87,113.28) ; v1(162.52,123.85) 162.52,123.57 161.51,122.57 U125.2 ; v2(161.6,181.38) 161.58,181.36 160.55,181.36 159.75,180.56 U2.3 ; v2(135.95,42.85) 135.91,42.81 C4288.2 C4285.2 ; U124.2 v2(92.62,29.97) ; D14.1 44.44,29.81 v2(44.23,29.59) ; LVDS1.31 36.8,114.69 v2(36.13,115.36) ; C793.2 C792.2 75.57,84.55 75.99,84.55 v1(76.19,84.34) 76.12,84.27 C788.2 ; C1607.2 91.03,128.07 91.01,128.05 v2(91.01,127.98) ; v2(68.28,57.05) 67.49,57.05 PR4920.2 ; C27.1 162.83,184.16 v2(161.7,185.29) 161.7,187.75 v2(162.75,188.8) ; v2(52.31,62.79) 52.41,62.79 52.98,62.22 PQ5004.S ; PC18.2 PC17.2 130.49,88.93 v1(130.51,88.9) ; Q6706.S 139.27,47.47 138.53,47.47 v1(138.24,47.76) ; v2(154.16,22.63) 154.16,21.98 R1596.2 ; v2(165.29,109.02) 165.76,109.02 166.15,109.41 C107.1 166.21,110.77 167.55,110.77 167.84,111.07 X3.4 ; v2(53.32,130.96) 53.56,131.2 PU7.1 54.68,132.69 PR77.2 ; v2(88.62,198.29) 88.63,198.29 C634.2 ; v2(145.4,17.35) 145.32,17.27 C248.2 ; v2(99.65,99.59) 99.91,99.59 100.53,100.22 C1848.2 ; v2(99.65,99.59) 98.72,98.66 C1850.2 ; v2(99.65,99.59) 99.52,99.72 R1899.2 ; PC22.2 v1(27.26,183.21) ; PR3.2 128.35,75.54 128.04,75.22 v1(127.99,75.22) ; v2(99.73,207.13) 99.6,207.26 PC5264.2 ; R1791.2 66.28,177.59 66.28,176.6 R79785.2 66.07,176.39 C6716.2 C6717.2 C6718.2 v2(61.68,176.39) ; v1(166.99,121.41) 167.72,121.41 C4261.1 ; v1(47.05,73.53) 47.25,73.33 PR4451.2 ; PWRCN1.12 26.75,18.41 26.14,17.81 v1(26.14,17.64) ; C226.2 145.3,6.63 v2(144.36,6.63) ; PC5433.2 v1(61.68,133.48) 61.68,133.76 60.08,135.36 58.37,135.36 PC5432.2 56.08,135.05 PC5431.2 54.85,135.04 v2(54.34,135.56) ; v2(45.27,169.6) 45.47,169.6 46.16,170.28 PU5201.1 48.13,170.28 PR5212.2 ; v2(92.13,34.43) 92.13,34.34 91.73,33.93 C251.2 C249.2 ; v2(39.53,178.94) 40.52,177.95 PC5212.1 ; R963.2 68.05,85.45 68.56,85.97 72.12,85.97 C785.2 C789.2 72.51,84.24 C787.2 71.41,83.15 v1(71.41,82.66) ; PC4916.1 65.44,53.92 v2(65.74,54.23) ; PR4533.2 31.19,166.03 32.14,166.98 v2(32.14,167.36) ; C1703.2 161.51,95.13 C1698.2 C1665.2 161.55,94.17 v1(161.55,92.71) ; FANC3.1 14.59,214.81 15.17,215.39 C48.2 ; R181.1 C111.1 ; C111.1 151.45,206.47 v1(151.16,206.76) ; C111.1 152.16,206.48 R151.2 ; v1(30.34,5.71) 30.35,5.72 30.35,6.43 C6715.2 ; v6(149,5.55) 149,5.81 149.7,6.5 SPK1.7 ; v2(65.07,63.56) 65.07,64.05 PC4918.2 ; v1(44.97,27.25) 44.64,27.25 AFTP1.1 43.19,27.28 C88.2 ; v1(148.27,27.05) 148.27,27.03 147.66,26.42 C235.2 147.51,25.25 C255.2 ; PC4515.2 24.16,169.36 v2(24.28,169.48) 24.28,169.81 23.72,170.37 R1827.2 ; v2(143.77,11.58) 144.27,11.58 145.06,10.79 C236.2 C256.2 144.86,12.06 144.38,12.55 v2(143.8,12.55) ; Q46.3 86.1,38.42 v2(87.03,37.49) 86.97,37.43 R216.1 ; PC5003.2 156.19,136.09 v2(156.65,135.64) 155.89,134.88 PC5004.2 ; v2(126.78,72.81) 126.39,72.42 C189.2 ; v2(98.96,206.31) 98.93,206.31 98.74,206.12 PC5261.2 PC5258.2 ; v1(91.84,120.76) 91.77,120.84 Q1214.S ; C1848.2 101.61,100.8 R940.2 102.8,100.8 103.11,101.1 R1880.2 ; C1848.2 101.03,99.35 R1881.2 ; SPK1.8 149.11,18.8 v6(147.99,17.68) ; PC4917.2 v2(70.01,59.69) ; PU5203.1 32.8,175.57 v2(33.03,175.81) 33.33,176.1 PR5242.2 ; v2(38.21,9.12) 38.23,9.14 38.23,9.8 37.78,10.25 C212.2 ; v2(73.16,191.39) 73.21,191.34 73.21,190.62 Q1246.S ; v2(96.17,225.68) PC5259.2 96.18,224.37 R79800.2 ; CONVT1.12 25,30.58 26.12,29.46 v3(26.12,29.41) 25.76,29.06 25.76,29.01 v1(25.1,28.35) 25.89,28.35 26.75,27.49 PWRCN1.11 ; v2(99.83,218.49) 99.83,217.63 PC4801.2 ; v2(38.64,177.95) PC5225.1 PC5227.2 ; v2(62.8,126.8) 63.58,127.58 63.58,127.73 PC5435.2 63.54,127.85 PC151.2 ; U6703.2 v2(110.6,25.1) ; HDMI2.22 120.81,29.92 v2(120.84,29.95) 121.36,29.43 C4280.1 C714.1 ; Q6710.E 42.17,22.93 v2(42.07,22.83) ; Q9628.S 116.96,83.79 v1(115.27,82.11) 114.5,81.34 C1864.2 ; PC21.2 31.02,182.88 v1(31.53,183.39) ; C568.2 11.04,222.1 PR57.2 11.09,221.69 PR58.2 11.98,221.03 12.76,221.03 v1(12.81,221.08) ; PR5473.2 v2(100.12,225.69) ; C106.1 166.15,114 165.67,114.48 v2(165.67,115.04) ; PC5229.2 21.57,176.35 v2(20.94,175.72) ; SC6.2 162.11,149.05 162.77,149.71 162.77,150.47 v1(162.8,150.5) 162.85,150.55 164.32,150.55 165.15,149.72 MEMCD1.6 ; C12326.2 20.63,215.34 v6(21.04,214.93) ; C552.2 153.68,23.65 v1(154.49,23.65) ; C12341.2 C12340.2 C12339.2 46.16,74.29 47.37,74.29 v2(47.63,74.03) ; R1886.2 R1882.2 82.31,82.47 v1(82.56,82.71) ; C205.2 34.01,10.19 34.68,9.51 v2(34.68,8.9) 34.68,8.12 X4.4 ; v1(136.81,29.46) 137.03,29.68 C4282.2 ; PR5251.2 PR26.2 ; Q76.E 44.16,6.73 44.16,5.86 C561.2 44.25,5.77 45.18,5.77 C559.2 45.35,5.12 45.37,5.09 v1(45.37,4.5) ; C755.1 v2(101.13,91.03) ; v2(97.65,78.56) 97.65,77.65 99.52,75.78 R317.1 99.68,75.31 99.39,75.02 C84.2 ; R80102.2 v2(44.58,222.12) PC5211.2 ; v2(129.42,74.22) 129.6,74.04 130.94,74.04 131.43,73.56 131.43,73.75 C185.2 ; Q6714.E 97.49,119.58 v2(97.49,120.12) ; v2(32.11,169.52) 32.01,169.42 PR4506.2 ; v1(105.01,58.06) 104.99,58.09 v2(104.99,59.23) 104.99,60.41 105,60.43 C1668.2 104.22,62.75 C1669.2 ; C711.2 30.38,9.5 TOUCH1.2 ; Q9625.E 103.25,93.44 v1(103.69,93.88) ; v2(45.73,177.22) 45.78,177.27 PC5216.1 PC5215.2 49.13,177.27 v2(49.16,177.29) 49.57,176.88 C1647.2 ; C8.1 156.39,191.3 C35.2 155.01,190.19 v2(154.92,190.27) 154.63,190.56 R94.1 ; C52.2 154.39,178.24 R729.2 154.29,178.14 154.29,177.74 154.26,177.72 154.26,177.14 v2(154.41,176.99) ; C31.2 103.37,118.72 v2(102.65,118.72) 102.57,118.72 102.43,118.58 PC5243.2 ; v1(104.99,56.34) v2(104.99,55.12) 104.99,54.09 C1699.2 C1666.2 104.87,52.29 C1670.2 ; v2(39.81,7.47) 39.97,7.64 39.97,8.51 39.94,8.55 39.94,8.6 39.46,9.08 39.4,9.08 R377.1 ; v1(161.53,90.75) 161.53,88.86 C1701.2 161.62,87.52 C1702.2 ; LED2.K 171.33,92.21 171.69,91.84 SSUSB2.4 172.62,91.61 170.45,89.44 C1705.2 C1706.2 ; C12327.2 R79914.2 18.96,205.82 v2(18.98,205.79) 18.98,205.61 19.68,204.92 R73.1 ; PR9814.2 52.38,74.37 52.49,74.37 v1(52.61,74.26) ; C4284.2 119.74,27.46 v1(119.57,27.64) ; v2(88.07,78.46) 88.07,79.15 87.8,79.41 C6702.1 ; PC5006.2 PC5005.2 v2(145.51,133.86) 145.25,133.86 144.47,133.07 144.47,130.09 145.07,129.49 PR5001.2 ; MEMCD1.3 164.24,142.22 163.13,143.33 v1(162.69,143.33) 162.69,143.66 C73.1 162.11,144.89 C75.1 ; WEBCM1.8 155.75,198.77 156.55,199.57 v1(156.73,199.57) ; PC4518.2 v2(32.23,160.71) ; PC5440.2 v1(53.8,190.47) ; PC5237.2 46.3,53.01 46.81,53.01 v2(47.09,53.29) ; PR9796.2 36.43,221.23 PR9804.2 37.47,220.43 v2(37.5,220.41) ; PC12.2 120.52,78.73 v1(120.63,78.61) 120.63,78.19 PR7.2 ; v1(154.89,172.6) 155.17,172.32 C50.2 154.21,171.53 R86.2 ; C270.2 153.31,20.8 v2(152.8,20.29) PC2127.1 ; C6701.1 82.65,77.61 83.09,77.17 v2(83.12,77.17) ; v2(142.43,24.46) 142.43,25.07 142.76,25.4 C225.2 ; Q79.S 105.29,121.96 v1(105.29,121.03) ; SRCON1.4 33.18,129.11 v2(33.13,129.06) 33.18,129.06 33.74,128.5 38.69,128.5 40.01,129.81 C116.1 ; C217.2 135.75,66.56 R79774.2 136.89,66.56 137.16,66.29 v1(137.5,66.29) 138.71,66.29 138.87,66.45 ; HDMI1.21 118.63,44.28 HDMI2.21 ; C1655.2 72.33,147.19 73.07,147.19 v2(73.1,147.22) ; v2(59.24,62.94) 59.24,63.06 58.78,63.51 PC4915.2 ; C631.2 C630.2 84.11,191.62 v2(83.08,192.65) ; v2(148.98,15.24) 148.99,15.25 SPK1.5 ; v1(46.16,20.85) 45.6,21.41 R422.2 ; C1606.2 58.9,53.7 v2(58.95,53.7) ; R1559.2 105.4,200 v2(105.36,200.04) ; C232.2 33.38,5.74 33.31,5.66 33.31,5.62 33.26,5.57 33.26,5.46 v2(33.03,5.23) ; CONVT1.10 27.45,32.15 25.79,33.81 v2(25.79,33.91) ; PC4905.2 C1667.2 98.52,56.96 98.97,56.52 v2(99.17,56.52) ; C756.2 v1(96.48,108.37) ; C6703.2 v2(88.22,74.17) ; C1696.2 99.5,58.83 v2(99.09,58.42) PC4906.2 ; v1(36.8,25.48) R144.2 ; PC4526.2 29.09,156.36 v2(29.04,156.41) PR4531.2 PC4516.1 27.99,157.23 PR4514.2 ; PC5443.2 38.79,215.24 v2(38.51,214.96) ; U6704.2 174.19,106.05 ; R80144.1 66.25,142.86 R1661.1 66.11,142.88 66.03,142.95 65.41,142.95 v1(65.14,143.22) ; v1(103.03,83.82) U49.4 105.34,84.33 105.85,84.84 C753.2 ; PC5444.2 42.57,220.15 v2(41.94,220.78) ; PR4532.2 33,159.31 v2(33.05,159.26) ; PR4922.2 57.53,58.57 PR4917.2 56.82,58.45 v2(56.53,58.74) ; Q9636.S 72.65,132.69 v1(72.66,132.71) ; PC5233.1 v2(44.69,53.06) ; R1808.2 105.48,195.39 v2(106.51,196.42) ; v1(70.68,135.79) 70.93,136.04 71.68,136.04 C12349.2 72.7,136.08 Q9642.E ; PC33.1 22.89,217.86 v1(23.07,217.68) ; v2(104.02,25.78) 104.02,25.93 103.6,26.35 C238.2 C271.2 ; v2(102.67,205.03) 103.82,203.89 R1637.1 ; v1(98.28,121.87) 98.91,122.5 Q77.S ; v1(151.75,24.28) C247.2 ; v2(48.37,18.22) C3452.2 ; R1209.1 v2(102.93,217.17) ; C182.2 130.88,68.29 v1(130.69,68.1) ; X8.4 v2(100.24,107.71) ; v2(76.51,80.48) 76.54,80.5 76.54,80.6 76.54,80.61 R1207.2 R1206.2 ; v1(162.82,158.29) 162.29,157.76 SC4.2 ; Q75.E v2(48.64,7.16) ; PC5222.2 v2(36.15,167.11)
  TOP w0.635: 171.1,158.17 MEMCD1.13 171.1,160 ; C176.2 138.89,66.47 138.87,66.45 ; 176.12,87.87 SSUSB2.10 ; SSUSB2.10 174.25,88.94 ; SSUSB2.10 177.99,88.94 ; SSUSB2.10 176.12,90.01 ; v1(121.87,33.57) 121.07,33.57 HDMI2.23 ; Q1205.S 155.13,183.86 154.85,184.15 v1(154.47,184.15) ; X3.2 169.59,113.57 168.79,114.37 166.98,114.37 166.24,113.63 C106.1 ; 176.12,100.67 SSUSB2.11 ; SSUSB2.11 176.12,102.81 ; SSUSB2.11 177.99,101.74 ; 96.64,7.46 USB4.6 ; USB4.6 100.07,7.46 ; USB4.6 98.35,5.74 ; USB4.6 98.35,9.17 ; v6(130.41,19.84) 130.75,19.84 132.52,18.07 132.52,16.48 BT1.2 ; CN2.5 162.62,176.29 v2(162.85,176.52) ; v1(69.12,37.27) 69.24,37.39 PQ4204.E ; v2(22.11,183.08) 22.54,183.51 PC5223.1 ; v2(17.53,177.47) 17.99,177.47 18.35,177.11 PC5224.2 ; v2(161.78,172.67) 161.35,172.24 CN2.6 ; PC5011.2 v2(154.72,168.45) ; X4.2 39.18,6.1 39.81,6.73 v2(39.81,7.47) ; WEBCM1.10 153.7,201.1 154.25,201.65 v1(155.02,201.65) ; SATAP1.4 13.07,192.5 14.49,191.08 TC5.2 ; 115.18,117.93 PTC4701.2 114.13,118.99 ; C205.2 33.45,10.54 C202.1 ; R501.2 39.54,118.33 v2(39.83,118.03) 39.72,117.92 C29.2 ; HDMI2.24 120.7,37.11 v1(121.87,37.11) ; PC5012.2 152.53,168.25 v2(152.31,168.48) ; HS6.1 144.25,217.61 ; HS6.1 144.25,210.39 ; HS6.1 140.64,214 ; HS6.1 147.86,214 ; 49.88,25.74 DCIN1.6 48.79,24.18 ; 183,131.4 MEMCD1.14 183,129.58 ; PQ4206.S 69.08,42.6 v1(69.22,42.46) ; SSUSB1.10 177.99,110.44 ; SSUSB1.10 176.12,109.37 ; SSUSB1.10 176.12,111.51 ; H3.1 93.14,139.17 C523.2 ; C100.2 v1(151.5,213.66) ; 178,69.67 UHS1.MS1 176.58,70.69 ; 177.58,79.89 UHS1.MS2 ; UHS1.MS2 179,80.91 ; UHS1.MS2 180.42,79.89 ; C110.2 C109.2 v2(18.88,199.52) 19.93,199.52 C112.2 ; PR4207.2 68.31,28.98 v1(69.03,28.26) ; PC5213.2 37.63,171.09 v2(38.44,170.28) ; 183,160 MEMCD1.15 183,158.17 ; SSUSB1.11 177.99,123.24 ; SSUSB1.11 176.12,124.31 ; SSUSB1.11 176.12,122.17 ; C121.1 158.6,195.37 157.76,196.22 v5(157.64,196.22) 157.89,196.47 157.89,197.84 WEBCM1.6 158.25,199.36 158.17,199.44 v1(158.17,199.51) ; C571.2 126.79,71.08 C189.2 ; PC5439.2 v1(52.87,195.83) ; 98.35,28.74 USB3.6 96.64,30.46 ; PC5217.2 v2(40.3,168.36)
  L3 w0.254: v1(134.18,188.34) 134,188.16 134,188.06 133.63,187.69 132.69,187.69 v2(125.11,195.28) 121.48,198.91 v2(121.47,198.91) 120.48,199.9 v2(110.27,199.9) 110.14,200.03 105.37,200.03 v2(105.36,200.04) 105.33,200.04 105.32,200.03 v2(97.32,200.03) v2(93.73,200.03) 90.38,200.03 88.65,198.29 v2(88.62,198.29) 88.62,198.27 86.8,196.44 86.8,189.1 v2(86.95,188.95)
  L3 w0.635: 170.17,61.76 H11.2 171.75,61.76 ; 175.17,62.1 H11.4 175.17,63.68 ; 163.34,16.33 H10.2 162.55,17.12 ; 166.66,16.33 H10.3 167.45,17.12 ; MEMCD1.15 183,160 ; MEMCD1.15 183,158.17 ; MEMCD1.15 181.68,159.09 ; 176.58,70.69 UHS1.MS1 178,69.67 ; 174.83,61.76 H11.3 173.25,61.76 ; 167.45,22.88 H10.6 166.66,23.67 ; MEMCD1.14 183,131.4 ; MEMCD1.14 181.68,130.49 ; MEMCD1.14 183,129.58 ; 168.67,18.34 H10.4 167.88,17.55 ; 23.08,45.48 H9.6 22.29,46.27 ; 22.29,52.03 H9.3 23.08,52.82 ; 168.67,226.92 H6.3 167.88,227.71 ; 175.17,66.76 H11.5 175.17,65.18 ; 168.67,223.08 H6.2 167.88,222.29 ; 167.88,22.45 H10.5 168.67,21.66
  L4 w0.254: v2(86.95,188.95) 86.95,189.65 88.57,191.27 88.7,191.48 89.86,193.32 89.94,193.46 90.35,194.15 90.43,194.29 92.64,196.5 97.82,196.5 v2(102.26,196.3) 102.37,196.42 v2(106.51,196.42) 106.83,196.1 v2(125.11,195.28) 125.53,195.26 126.6,195.13 v2(127.29,194.44) 132.14,194.44 135.5,194.02 136.17,193.36 136.36,193.17 137.93,191.59 v1(137.93,190.3) ; 121.19,134.82 121.65,134.82 122.72,133.76 133,133.76 v2(133.54,134.29)
  L4 w0.635: 167.88,22.45 H10.5 168.67,21.66 ; 167.45,17.12 H10.3 166.66,16.33 ; 175.17,66.76 H11.5 175.17,65.18 ; 173.25,61.76 H11.3 174.83,61.76 ; 167.88,222.29 H6.2 168.67,223.08 ; 168.67,18.34 H10.4 167.88,17.55 ; 175.17,63.68 H11.4 175.17,62.1 ; 23.08,45.48 H9.6 22.29,46.27 ; 168.67,226.92 H6.3 167.88,227.71 ; 170.17,61.76 H11.2 171.75,61.76 ; 167.45,22.88 H10.6 166.66,23.67 ; 23.08,52.82 H9.3 22.29,52.03
  BOTTOM w0.127: MEM2.M1 59.13,94.11 59.58,94.11 60,94.53 60,95.32 59.54,95.79 59.53,95.79 v1(59.52,95.79) ; v1(72.52,159.17) 72.39,159.3 71.58,159.3 71.08,158.8 71.08,158.79 70.36,158.08 69.8,158.08 69.27,157.55 C49.2
  BOTTOM w0.203: v2(33.5,94.51) 33.7,94.3 U126.6 ; MEM2.B9 52.83,86.01 53.6,86.01 MEM4.B3 ; PU4401.11 v1(78.65,215.77) v1(79.54,215.77)
  BOTTOM w0.254: MEM2.E2 58.01,88.81 v1(58.41,88.41) 58.02,88.02 MEM4.D8 ; v1(94.29,97.41) 94.29,98.2 C830.2 93.64,98.94 C829.2 94.09,99.27 v1(94.42,99.59) 93.88,100.13 C827.2 ; MEM1.G9 59.33,112.88 v1(59.39,112.82) ; v1(75.09,102.53) 74.67,102.11 C770.2 ; PC4428.2 83.81,211.59 83.01,212.39 v2(82.53,212.39) ; R552.2 82.94,149.61 v1(83.85,148.69) 83.85,147.29 84.35,146.8 C1656.2 ; C762.2 82.77,87.55 82.53,87.79 v1(82.35,87.79) ; C768.2 79.6,103.52 C812.2 ; C768.2 C765.2 C766.2 ; C768.2 80.36,103.38 C798.2 81.08,103.19 81.08,103.07 81.1,103.05 v1(81.1,102.65) ; R394.2 C1847.2 94.71,101.16 v1(94.8,101.24) ; C767.2 74.53,99.09 v1(74.04,99.57) ; C721.1 118.4,40.32 v2(118.9,40.82) ; R1259.1 77.68,151.17 77.96,151.17 v1(78.14,151.35) ; v1(57.62,91.62) 58.01,92.02 MEM2.J2 ; v1(58.41,90.02) 58.81,89.62 MEM4.F9 ; v1(58.41,90.02) 58.01,90.41 MEM4.G8 ; v1(58.41,90.02) MEM2.G1 ; C769.2 77.25,91.86 v1(77.39,92) ; v1(59.52,95.79) 59.29,96.02 MEM2.P1 ; v1(90.84,101.24) 90.84,101.21 91.21,100.84 R80143.1 ; v1(56.67,117.73) 56.67,117.46 57.21,116.91 MEM3.B3 ; v1(53.61,92.42) 53.21,92.02 MEM2.J8 ; C1869.2 47.59,94.76 v2(47.2,94.37) 47.2,94.31 47.69,93.82 R1923.1 ; v1(161.5,103.43) 161.5,103.24 160.88,102.62 159.06,102.62 158.53,102.08 R179.2 ; v1(161.55,92.71) 161.23,93.03 C1700.2 ; C1663.2 70.53,154.7 71.33,155.5 71.78,155.5 C617.2 71.88,155.66 v1(72.5,156.29) ; MEM1.B1 52.4,116.88 52.3,116.98 52,116.98 v1(51.9,117.08) ; MEM3.D8 53.21,115.23 53.1,115.11 53.1,114.59 MEM1.E2 MEM3.F9 52.3,113.79 52.3,113.85 51.98,114.17 51.74,114.17 v1(51.48,114.44) ; v1(79.28,96.06) 79.34,96.13 C774.2 79.34,98.04 C807.2 79.15,98.24 C806.2 ; 29.09,101.22 v2(29.08,101.21) ; v1(63.48,106.15) 64.12,106.15 64.96,105.32 64.96,104.55 64.62,104.22 64.56,104.22 C12334.2 R924.1 ; v1(59.81,86.58) 59.7,86.47 58.87,86.47 MEM2.B1 ; v4(61.59,19.75) 62.11,19.75 v6(62.26,19.9) ; v1(85.3,106.45) 85.3,106.27 85.22,106.2 C813.2 ; PN4401.2 v2(52.04,209.99) ; R1210.1 91.8,96.09 v1(91.8,96.8) ; v2(29.11,99.75) 29.13,99.77 ; v1(88.6,93.6) 88.47,93.48 PC5271.1 87.89,92.55 PR29.1 ; C79.1 95.44,168.92 v1(95.48,168.96) ; R79797.2 69.99,161.02 v1(70.04,161.06) ; PN4501.2 v2(29.62,139.95) ; R948.2 C1849.1 94.49,104.03 94.55,104.09 v1(94.65,104.09) ; C818.2 85.67,102.99 v1(85.72,102.94) 85.68,102.9 85.68,102.37 C782.2 C783.2 ; v1(51.42,112.9) 51.72,112.9 51.73,112.88 MEM1.G1 MEM3.G8 ; v1(90.15,97.77) 90.15,97.25 C1846.2 ; v1(87.92,101.19) 87.68,101.43 C779.2 C781.2 ; C12344.1 91.91,108.48 v1(92.04,108.62) 91.97,108.7 R80141.1 ; MEM3.D1 59.05,115.05 59.15,115.05 v1(59.5,114.69) 59.3,114.48 MEM3.E1 58.71,114.38 58.12,114.38 MEM1.E8 ; R1205.2 82.99,89.45 82.48,89.96 82.48,90.69 82.92,91.14 82.94,91.14 v1(83.01,91.21) ; C775.2 78.33,95.09 v1(78.27,95.15) ; U120.20 34.25,31.67 v2(34.58,32) ; v1(90.99,105.61) 91.02,105.64 C12345.1 91.07,106.34 R80137.1 ; v1(89.4,107.2) 89.31,107.29 C12346.1 ; v1(81.13,99.09) 81.11,99.12 v1(81.11,100.92) ; v1(82.56,82.71) 82.61,82.76 R1897.2 ; v1(87.84,174.4) 87.64,174.19 87.63,174.19 87.19,173.75 C627.2 ; U55.14 47.92,55.38 47.35,54.81 v2(47.35,54.79) ; C773.2 74.43,100.73 74.85,101.15 v1(75.16,101.15) ; R524.1 75.86,161.86 75.57,161.57 75.38,161.57 R1242.1 74.77,160.33 v1(74.6,160.16) ; v1(70.04,158.92) 69.47,158.92 66.3,155.75 v2(66.3,155.14) ; C819.2 85.17,97.17 85.17,96.95 85.97,96.15 v1(85.97,96.09) 85.99,96.07 C12347.1 ; MEM1.B9 59.51,116.88 v1(59.6,116.79) ; MEM3.A9 52.04,117.68 51.94,117.78 v1(51.86,117.78) ; PR5112.2 165.34,76.23 v2(166.05,75.51) ; PC27.2 166.87,88.71 v1(167.14,88.44) ; MEM4.A9 59.95,85.62 60.18,85.85 60.61,85.85 v2(61.48,86.72) ; C632.2 90.75,162.15 89.96,162.94 v1(89.96,163.05)
  BOTTOM w0.305: v1(156.7,117.35) 155.86,116.51 TC10.1
  BOTTOM w0.356: v1(52.46,98.42) 52.41,98.37 MEM2.T9 ; MEM2.B9 52.01,86.02 v1(52.01,86) ; MEM2.P9 52.41,96.01 v1(52.81,95.62) ; v1(29.42,18.87) 29.77,18.87 30.52,18.12 Q35.4 ; MEM1.J2 53.21,111.28 v1(52.81,111.69) ; C776.2 62.07,98.45 61.56,98.96 60.9,98.96 59.56,97.62 MEM2.T1 58.79,97.62 58.41,97.24 v1(58.4,97.24) ; MEM1.P9 58.42,107.68 v1(58.4,107.68) ; MEM4.D1 52.3,88.02 v1(51.86,88.47) 52.01,88.47 52.36,88.82 MEM4.E1 ; MEM1.P1 52.29,107.28 v1(51.92,107.65) ; MEM2.G9 52.36,90.42 51.97,90.04 v1(51.92,90.04) ; MEM2.E8 53.24,88.82 v1(53.63,88.42) ; MEM2.M9 51.93,94.42 v1(51.82,94.53) ; v1(58.43,106.09) 58.43,106.06 MEM1.T9 58.88,105.68 59,105.56 59.01,105.56 60.13,104.45 60.13,103.67 C777.2 ; MEM1.M9 59.46,108.88 v1(59.48,108.87) ; v1(51.94,105.94) 52.2,105.68 MEM1.T1 ; v1(51.86,108.84) 51.89,108.88 MEM1.M1 ; v2(31.25,180.87) 30.93,180.56 Q20.4 29.44,180.56 29.29,180.42 29.27,180.42 29.09,180.24 29.09,180.21 29.01,180.14 29.01,179.51 28.76,179.26 Q20.1 ; MEM1.J8 v1(57.61,110.88)
  BOTTOM w0.381: v1(25.1,28.35) 25.48,28.35 25.83,28 C227.1 ; Q1231.4 40.51,184.88 40.7,185.06 v2(40.72,185.06) ; R155.2 155.27,108.27 v2(154.69,107.7) 154.9,107.49 R156.1 ; v1(162.69,143.33) 163.39,143.33 164.39,144.33 SC1.1 ; v2(47.33,181.05) 47.96,180.42 Q1230.4 ; Q68.S 24.03,22.22 24.87,23.06 C12350.1 ; C542.1 25.94,25.16 26.81,25.16 v2(26.9,25.25) ; v2(33.03,175.81) 32.93,175.91 C44.1 C42.2 ; Q1232.4 39.29,181.3 v2(38.72,181.86) ; v2(45.19,182.12) 45.82,182.75 Q1228.4 ; v1(23.15,23.5) 23.15,23.56 23.59,24 C213.2 ; v1(82.05,172.97) 82.5,172.97 R79787.1 ; v2(47.3,67.59) 48.1,66.79 PQ4408.S 47.63,65.66 46.66,65.66 PR5298.2 ; v2(39.53,178.94) 38.48,179.99 Q1232.1 ; C612.2 79.52,158.66 v1(79.02,159.16) 78.69,158.83 78.69,158.18 78.31,157.81 C1648.2 ; C591.2 82.67,158.29 82.67,156.92 82.3,156.55 82.29,156.55 v1(82.05,156.31) ; C549.1 27.81,29.35 27.11,30.05 v1(26.68,30.05) ; Q1231.1 38.45,182.93 v2(38.64,182.93) ; v2(45.73,177.22) 45.73,178.92 45.93,179.12 Q1230.1 ; v1(88.43,166.95) 87.81,166.34 C614.2 87.31,166.34 86.25,167.4 C625.2 ; Q63.1 151.17,40.92 151.31,40.92 v2(151.34,40.95) ; C607.2 79.28,170.11 v1(79.09,169.92) ; C629.2 87.01,169.32 87.62,169.93 v1(87.71,169.93) ; v1(45.13,68.33) 45.19,68.39 45.19,69.31 45.38,69.5 PC4301.2 ; v2(47.76,185.01) 48.34,184.43 Q1228.1 ; C537.1 40.98,14.48 v2(41.44,14.94) ; R366.2 116.81,66.04 116.14,66.71 114.06,66.71 113.8,66.45 Q66.S
  BOTTOM w0.406: Q38.E 25.74,16.64 26.14,17.04 v1(26.14,17.64) ; Q1233.4 48.14,217.75 47.62,218.27 47.62,218.88 47.61,218.89 47.61,220.17 v2(48.32,220.88) ; Q1233.1 49.91,214.98 49.61,214.68 v2(48.12,214.68) ; v1(28.44,16.31) 28.44,16.22 28.75,15.92 Q36.E ; Q48.4 152.97,130.14 v2(152.97,131.27) ; 130.93,60.31 130.69,60.07 130.59,60.07 129.88,59.36 v2(129.88,59.11) ; 130.93,60.31 Q29.4 ; 130.93,60.31 131.12,60.12 132.01,60.12 132.23,59.9 Q29.1 132.23,58.14 C174.1 ; Q48.1 150.18,128.69 149.66,128.17 v2(149.61,128.17) ; v2(31.38,15.19) 31.45,15.19 31.87,15.61 Q35.1
  BOTTOM w0.508: v2(48.32,220.88) 48.71,220.88 Q1234.S ; v2(128.05,25.27) 126.46,25.27 Q1257.S ; R80217.2 126.23,53.88 v1(126.23,54.75) ; v2(37.47,87.73) 37.45,87.76 C295.2 ; C1827.2 U25.7 38.64,83.24 38.34,82.93 v2(37.75,82.93) ; v1(137.13,147.68) 137.13,147.56 137.68,147.02 138.41,147.02 138.8,147.4 R122.2 139.85,147.4 C81.2 140.15,148.66 C82.1 ; C64.1 128.58,164.87 v2(128.07,165.38) ; 112.83,68.24 112.83,67.28 Q66.S ; 112.83,68.24 C183.2 ; 112.83,68.24 v2(112.78,68.29) ; v1(23.15,23.5) 22.98,23.33 Q68.S ; C6722.2 93.36,163.22 v1(93.53,163.06) ; v2(38.44,77.77) 38.44,78.08 38.64,78.28 U25.2 ; v2(38.44,77.77) 38.26,77.95 36.91,77.95 36.1,78.77 U25.4 ; v2(38.44,77.77) 38.73,77.48 C1877.2 39.3,77.7 39.91,78.31 U25.1 ; v6(21.18,13.26) 22.93,15.01 Q37.E ; C313.2 83.19,204.24 v2(83.14,204.19) ; Q1254.S 143.4,30.66 142.7,29.97 v1(142.15,29.97) ; v1(36.8,25.48) 36.82,25.5 37.59,25.5 C87.2 C33.2 R132.2 ; v1(163.53,116.2) 163.91,116.59 R174.2 ; v2(35.16,112.9) 36.69,112.9 Q1.S ; PC5113.2 163.28,88.85 162.36,87.94 162.36,85.98 v1(162.47,85.88) ; v1(87.82,159.3) 87.6,159.3 C592.2 ; v1(105.01,58.06) 105.82,58.06 105.95,58.19 C1673.2 ; v2(47.63,74.03) 47.69,73.97 47.69,73.26 46.73,72.3 PL4302.2 46.39,72.31 PC4305.2 ; C4281.2 125.33,30.56 125.05,30.84 v2(124.8,30.84) ; R80128.2 146.67,70.76 v1(146.18,71.25) 145.81,70.87 145.81,70.25 C4102.2 ; v1(156.73,199.57) 156.73,199.05 156.94,198.84 C16.2 C11.2 ; Q3.S v2(131.03,213.52) ; C393.2 155.86,114.91 TC10.1 ; v1(49.25,37.78) 49.25,38.66 49.06,38.86 C32.2 ; PC5115.2 162.06,79.79 PC5116.1 162.06,77.8 v1(162.39,77.47) ; R80125.2 145.89,73.77 v1(146.39,73.77) 146.4,73.79 147.26,73.79 R79722.2 ; C6733.2 31.22,13.32 C194.2 30.74,14.03 31.38,14.66 v2(31.38,15.19) ; C6733.2 31.22,11.74 C6732.2 ; C6733.2 31.17,12.69 C562.1 ; C181.1 129.19,67.94 v2(129.12,68.02) ; C633.2 90.05,160.94 90.75,161.65 C632.2 ; v1(81.05,158.36) 80.52,158.9 C599.2 ; v2(166.45,79.41) 166.45,80.26 167.08,80.89 PU5202.1 ; PQ5003.S 57.19,55.02 58.52,53.7 v2(58.95,53.7) ; R274.2 C174.1 ; v1(91.4,165.95) 91.32,165.87 C1633.2 92.26,165.23 C6721.2 ; SC3.1 165.4,144.97 SC1.1 ; SC2.2 168.53,150.98 v1(167.52,150.98) ; v1(162.72,141.07) 165.08,141.07 SR1.2 165.26,139.56 SC5.1 ; C864.2 132.73,216.73 Q6708.E v2(132.28,218.12) ; v1(46.18,120.09) 45.91,120.37 R79758.2 ; C20.2 33.55,112.17 34.58,111.15 v2(35.06,111.15) 35.06,111.12 34.63,110.69 C14.1 R19.2 ; v1(92.06,158.22) 92.06,158.13 92.01,158.08 C78.1 ; v1(75.24,154.14) 75.53,154.43 R79788.2 ; C77.1 92.46,178.41 v1(92.47,178.39) ; C216.2 130.92,67.87 v1(130.69,68.1) ; C1621.2 82.29,169.49 C605.2 82.3,169.22 C1651.2 82.3,167.74 v1(82.21,167.66) 82.27,167.6 C1624.2 82.26,166.88 C606.2 ; 97.32,198.42 97.78,197.95 R1811.2 ; 97.32,198.42 v2(97.32,200.03) ; 97.32,198.42 96.87,197.98 R1565.2 ; C1662.2 71.8,152.36 v1(71.33,151.89) ; C4266.2 v2(30.23,83.06) ; C7.2 34.07,85.42 v2(33.84,85.19) ; C6720.2 89.01,155.78 v1(88.83,155.6) ; v1(137.01,149.37) 136.91,149.47 C71.1 ; C60.1 131.94,169.21 v1(132.7,169.21) 132.75,169.16 C61.1 ; v1(76.01,151.36) 76.46,151.82 C1660.2 ; R79734.2 v2(131.72,42.78) ; C12324.2 19.51,200.15 v2(18.88,199.52) 18.51,199.16 R79916.2 ; PR4406.2 86.84,219.34 86.44,219.74 85.73,219.74 v2(85.7,219.76) ; v2(30.29,87.04) R512.2 31.08,87.04 C9.2 ; v2(129.87,42.84) 129.69,42.67 C4286.2 ; R1257.1 74.48,154.46 v1(74.17,154.14) ; v2(33.51,90.33) 33.06,89.88 C299.2 C297.2 ; v2(45.35,9.45) C558.2 44.42,8.29 Q74.E ; C170.2 152.71,48.15 152.94,47.91 v2(152.94,47.85) ; PL4301.2 PC4304.2 32.14,61.17 R79664.1 32.15,58.97 32.73,58.39 R79665.1 33.07,58.39 33.4,58.72 v2(34.01,58.72) ; v2(33.08,118.26) Q10.E ; R1807.2 88.89,198.03 v2(88.62,198.29) ; C65.1 135.26,169.06 v1(135.31,169.11) ; v2(77.67,221.02) 76.95,221.74 PC4426.2 ; C68.1 128.33,156.06 v2(127.8,156.59) ; v1(137.02,169.34) 137.02,168.78 136.75,168.52 C66.1 ; v1(162.8,150.5) 164.37,148.92 C72.1 165.27,148.92 C74.1 ; v1(151.11,134.47) 151.1,134.45 PC5007.2 ; v1(132.72,144.87) 131.85,144.87 C641.2 ; v2(127.69,160.07) 128.2,160.58 C67.1 ; R1079.2 32.36,94.11 32.76,94.51 v2(33.5,94.51) ; C1671.2 104.63,54.76 v2(104.99,55.12) ; Q65.S 28.67,21 v1(28.76,20.9) 29.69,20.9 R368.2 C207.2 ; v2(105.36,200.04) 105.6,199.8 105.6,198.79 104.71,197.9 R1557.2 ; v1(18.96,196.09) 20.19,196.09 Q1227.S ; R1806.2 100.01,196.83 100.74,196.3 v2(102.26,196.3) 102.26,197.53 R1803.2 ; v2(150.02,48.79) 149.99,48.77 149.43,48.77 Q6711.E ; v1(91.4,159.17) 91.33,159.11 C62.1 ; v1(72.5,171.82) 71.73,172.59 C1641.2 70.89,171.96 70.89,171.62 R1779.2 ; v1(86.14,169.17) 86.3,169.33 C629.2 86.93,168.49 C1622.2 ; R676.2 C530.1 117.34,62 v2(117.36,62) ; C516.2 154.91,42.82 C509.2 153.88,42.29 v2(153.45,42.29) 153.45,42.31 153.17,42.6 C478.1 153.87,43.93 C474.2 ; v2(93.73,200.03) 93.73,198.45 93.71,198.42 ; R553.2 92.31,147.07 v1(92.77,147.52) 93.52,148.27 R557.2 ; v1(93.48,159.16) 93.52,159.16 94.42,160.06 C642.2 94.49,160.07 v1(95.39,159.17) ; v1(127.95,85.5) 127.95,84.86 127.97,84.84 PR2.2 ; v2(144.46,40.92) 144.61,40.77 145.28,40.77 Q64.S ; v2(30.13,90.93) 30.28,90.93 31.04,90.17 R79681.2 ; C76.1 90.73,155.52 v1(90.81,155.6) ; v1(84.95,156.44) 84.74,156.64 C86.2 ; v2(49.86,12.98) 49.83,12.95 U122.2 ; PL4303.2 46.39,69.5 PC4301.2 ; v2(172.45,83.13) 172.04,83.54 PC5112.1 ; v2(146.77,199.42) 147.32,199.96 C26.1 146.2,200.25 C28.1 ; R79743.2 v2(133.78,42.82) ; v6(119.16,20.32) 119.21,20.27 C4289.1 ; 93.71,198.42 94.13,198.01 R1814.2 ; 93.71,198.42 93.29,198.01 R1816.2 ; R79802.2 135.49,109.83 135.49,111.1 v1(135.64,111.25) ; C1636.2 73.31,172.6 v1(73.19,172.72) ; v2(35.29,102.98) 35.25,102.95 C290.2 C289.2 ; Q1240.D 148.98,135.33 v2(150.15,135.33) ; PC5254.2 v2(126.26,219.52) ; v1(104.99,56.34) 105.09,56.44 105.28,56.44 105.96,57.05 C1672.2 ; C70.1 128.43,152.38 v2(128.15,152.1) ; C598.2 80.53,159.18 C599.2 ; C1616.2 v2(126.78,215.34) ; C296.1 29.09,101.22 ; v2(30.23,81.28) C293.1 C298.2 ; C1605.1 152.07,201.42 R466.1 147.08,202.45 v2(146.67,202.03) ; C4287.2 135.79,42.69 v2(135.95,42.85) ; v1(133.63,149.13) 133.7,149.21 C69.1 ; PC4429.2 68.51,213.59 v2(68.69,213.41) ; v1(80.08,151.6) 80.41,151.28 C1649.2 ; v2(66.33,150.37) 66.33,152.4 v2(66.35,152.43) 67.05,152.43 v4(67.46,152.84) 67.77,153.15 67.77,155.51 68.55,156.29 C49.2 ; C1620.2 85.44,170.42 v1(85,170.87) ; R79658.2 v1(77.15,153.49) ; v1(167.14,88.44) 167.29,88.6 PC5221.2 ; R146.1 128.19,65.52 v2(129.14,64.57) ; C599.2 80,158.66 C612.2 ; C292.1 v2(30.21,79.85) ; R30.2 36.42,118.32 36.42,117.67 37,117.08 Q5.S 37,116.12 36.24,115.36 v2(36.13,115.36) 36.09,115.36 35.72,115.72 R33.2 ; v2(132.62,42.82) 132.74,42.71 R79745.2 ; v2(118.47,52.53) 118.45,52.55 118.45,53.09 118.1,53.43 C214.2 117.06,53.43 C215.2 115.18,54.43 R79950.1 ; 29.13,99.77 31.06,99.77 R507.1 R511.2 ; PC5251.2 v2(125.62,215.57)
  BOTTOM w0.635: v2(129.42,74.22) 130.34,74.22 Q9648.S ; 96.64,20.6 USB4.5 ; USB4.5 100.07,20.6 ; USB4.5 98.35,18.88 ; USB4.5 98.35,22.31 ; TC20.2 93.11,24.1 ; TC20.2 92.06,25.16 ; TC20.2 92.06,23.05 ; TC20.2 91,24.1 ; 98.35,28.74 USB3.6 ; USB3.6 98.35,32.17 ; USB3.6 100.07,30.46 ; USB3.6 96.64,30.46 ; 111.3,29.78 HDMI1.22 ; HDMI1.22 113.99,28.66 ; HDMI1.22 113.99,30.9 ; C4254.2 C3.2 41.82,114.53 C6.2 43.7,114.53 C869.2 ; C4254.2 40.59,115.79 Q103.S ; C4254.2 40.26,114.48 39.64,113.87 v1(39.64,113.8) ; PC124.1 v1(162.88,207.68) ; HDMI1.20 112.58,37.03 ; HDMI1.20 110.34,37.03 ; HDMI1.20 111.46,39.85 ; HDMI1.20 111.46,34.21 ; USB4.6 100.07,7.46 ; USB4.6 96.64,7.46 ; USB4.6 98.35,5.74 ; USB4.6 98.35,9.17 ; C1650.2 80.41,149.95 C1649.2 ; v2(35.36,104.14) 37.63,104.14 C291.2 37.85,104.11 C283.1 39.62,102.35 C284.2 ; v2(33.52,34.8) 33.47,34.85 C39.2 ; Q9650.S 46.69,118.03 v2(47.4,118.75) ; C63.1 95.22,174.51 v1(95.4,174.69) ; C6724.1 127.59,72.27 127.05,72.81 v2(126.78,72.81)
  vias: v1(24.82,163.07) v1(24.82,3.76) v1(25.69,163.93) v1(25.69,163.07) v1(26.07,3.71) v1(26.55,163.07) v1(35.72,15.06) v1(36.61,15.88) v1(36.61,14.99) v1(36.61,14.07) v1(37.52,14.99) v1(39.12,220.93) v1(40.09,220.9) v1(41.05,220.88) v1(46.01,139.75) v1(47.2,136.22) v1(47.61,139.24) v1(47.66,57.78) v1(48.42,58.55) v1(48.42,57.78) v1(48.42,57.02) v1(49.18,57.78) v1(49.39,136.19) v1(49.69,139.29) v1(51.39,139.27) v1(55.1,155.24) v1(55.43,157.44) v1(55.53,158.7) v1(59.82,182.04) v1(61.59,60.12) v1(61.58,58.98) v1(62.16,59.56) v1(62.71,60.1) v1(62.75,58.97) v1(66.2,182.09) v1(66.91,173.53) v1(67.09,170.81) v1(68.11,169.54) v1(68.23,146.39) v1(68.28,172.57) v1(69.15,171.12) v1(69.55,178) v1(70.02,169.35) v1(70.49,179.88) v1(70.67,169.36) v1(70.73,165.49) v1(70.92,182.04) v1(70.95,170.36) v1(71.13,178.87) v1(72.47,170.83) v1(72.47,169.84) v1(72.53,166.98) v1(72.47,163.06) v1(73.34,175.97) v1(73.87,173.77) v1(73.89,164.05) v1(73.89,158.18) v1(74.43,182.09) v1(74.53,180.64) v1(75.22,167.89) v1(75.34,178.56) v1(75.34,169.8) v1(75.26,166.93) v1(75.31,159.17) v1(75.43,171.79) v1(76.18,176.53) v1(76.17,174.35) v1(76.71,182.74) v1(76.69,164.03) v1(77.17,171.5) v1(77.17,156.34) v1(78.14,172.97) v1(78.14,163.98) v1(78.19,175.15) v1(78.16,166.94) v1(78.16,163.06) v1(78.16,160.16) v1(78.16,155.6) v1(78.61,180.12) v1(79.54,216.66) v1(79.54,214.88) v1(80.07,173.69) v1(80.42,215.77) v1(80.65,163.86) v1(80.65,162.36) v1(81.06,176.53) v1(81.06,174.4) v1(81.06,156.24) v1(81.06,153.47) v1(81.08,101.88) v1(81.14,97.27) v1(81.08,95.89) v1(81.43,164.62) v1(82.05,153.47) v1(82.08,96) v1(82.99,103.02) v1(82.99,100.79) v1(83.04,99.09) v1(83.79,163.1) v1(83.93,175.08) v1(84.03,157.02) v1(84.94,181.98) v1(84.91,176.51) v1(84.94,173.69) v1(84.94,172.97) v1(84.96,159.05) v1(85.77,120.66) v1(85.93,172.26) v1(85.93,157.74) v1(85.93,153.47) v1(85.96,176.45) v1(86.13,163.87) v1(86.76,180.4) v1(86.89,178.39) v1(86.91,163.87) v1(86.89,151.61) v1(87.16,120.65) v1(87.74,96.09) v1(87.84,155.6) v1(87.94,97.49) v1(88.83,178.41) v1(88.83,176.53) v1(88.83,174.4) v1(88.83,153.47) v1(88.94,184.37) v1(88.94,182.23) v1(89.82,172.26) v1(89.82,157.74) v1(90.34,183.3) v1(90.3,120.72) v1(90.69,167.93) v1(90.81,176.53) v1(90.81,174.4) v1(90.81,153.47) v1(91.4,170.83) v1(91.92,182.94) v1(92.11,171.82) v1(92.1,156.2) v1(92.16,173.8) v1(92.7,151.12) v1(93.1,176.68) v1(93.12,175.62) v1(93.12,154.36) v1(93.49,184.37) v1(93.49,182.23) v1(93.52,173.8) v1(93.53,172.81) v1(93.53,170.83) v1(93.53,166.94) v1(93.53,157.19) v1(93.52,156.2) v1(94.15,178.46) v1(94.94,151.79) v1(95.1,183) v1(95.1,164.54) v1(95.31,219.99) v1(95.36,170.8) v1(95.39,163.08) v1(95.39,161.11) v1(95.42,157.23) v1(95.36,155.31) v1(95.64,166.55) v1(96.18,220) v1(96.17,151.76) v1(97.01,219.99) v1(98.28,148.79) v1(98.27,102.97) v1(98.35,111.49) v1(99.04,169.11) v1(99.35,113.28) v1(100.11,113.28) v1(100.31,170.56) v1(100.64,173.61) v1(101.93,170.41) v1(102.29,172.11) v1(123.76,131.6) v1(131.72,35.56) v1(132.74,35.57) v1(133.18,177.37) v1(133.69,139.14) v1(134.22,174.88) v1(134.4,183.62) v1(134.44,171.45) v1(135.24,181.84) v1(135.32,180.82) v1(135.42,179.37) v1(135.57,177.06) v1(135.62,112.98) v1(136.23,190.24) v1(136.28,130) v1(137.04,179.35) v1(137.54,171.66) v1(140.48,111.91) v1(142.74,113.97) v1(142.93,111.73) v1(148.52,113.89) v1(151.11,133.3) v1(152.28,134.47) v1(152.28,133.3) v1(153.8,102.79) v1(153.76,101.81) v1(154.49,99.72) v1(154.47,30.61) v1(155.28,24.54) v1(155.35,31.62) v1(155.35,30.61) v1(155.35,29.59) v1(156.24,30.61) v1(156.65,120.04) v1(156.73,118.75) v1(157.39,205.73) v1(158.12,48.77) v1(159.55,50.14) v1(159.55,48.77) v1(159.55,47.27) v1(160.21,111.63) v1(160.89,48.79) v1(161.37,112.75) v1(161.38,111.62) v1(161.4,110.52) v1(162.26,105.54) v1(162.28,104.03) v1(162.32,98.26) v1(162.34,95.96) v1(162.44,126.09) v1(162.35,107.09) v1(162.72,111.63) v1(163.64,117.76) v1(164.63,94.46) v1(164.68,95.76) v1(168.14,130.31) v1(169.32,130.3) v1(169.48,132.33) v1(170.72,145.41) v1(170.73,144.6) v1(170.72,143.76) v1(171.15,132.13) v2(5.47,133.32) v2(7.78,133.17) v2(10.47,133.17) v2(12.68,133.22) v2(15.48,133.15) v2(16.92,159.46) v2(16.87,156.79) v2(16.87,154.1) v2(17.46,180.29) v2(17.53,174.88) v2(18.17,133.15) v2(20.84,133.15) v2(21.14,70.36) v2(21.09,68.15) v2(21.06,66.32) v2(21.06,63.75) v2(21.12,61.06) v2(21.12,57.12) v2(21.24,73.74) v2(21.36,1.26) v2(23.3,73.86) v2(23.5,133.15) v2(25.56,73.89) v2(25.79,34.82) v2(25.94,133.1) v2(25.94,42.98) v2(25.99,41.57) v2(26.12,1.09) v2(27.19,73.84) v2(28,132.97) v2(29.05,109.19) v2(29.09,131.55) v2(29.07,129.92) v2(29.07,128.2) v2(29.07,126.44) v2(29.07,124.54) v2(29.07,122.78) v2(29.07,120.1) v2(29.07,118.34) v2(29.13,116.82) v2(29.11,113.79) v2(29.09,111.47) v2(29.07,106.3) v2(29.07,103.29) v2(29.06,97.29) v2(29.06,95.53) v2(29.07,93.1) v2(29.07,91.34) v2(29.07,88.4) v2(29.07,86.64) v2(29.07,83.47) v2(29.07,81.71) v2(29.12,78.82) v2(29.12,77.06) v2(29.12,76.15) v2(31.2,1.09) v2(32.37,77.01) v2(33.94,60.44) v2(33.98,59.56) v2(34.07,21.11) v2(34.15,19.84) v2(34.91,77.04) v2(36.28,1.09) v2(36.53,20.88) v2(37.78,96.23) v2(37.78,95.36) v2(37.78,94.5) v2(37.78,93.64) v2(37.78,92.77) v2(39.61,52.93) v2(40.32,52.91) v2(40.27,52.2) v2(40.27,51.41) v2(41,52.93) v2(41,52.2) v2(41,51.41) v2(41.36,1.09) v2(41.71,52.93) v2(41.71,52.2) v2(41.74,51.41) v2(42.93,18.54) v2(42.93,17.12) v2(43.24,14.86) v2(44.64,38.68) v2(44.66,37.82) v2(45.55,38.73) v2(45.52,37.87) v2(46.44,1.09) v2(47.05,35.59) v2(47.12,116.34) v2(47.12,115.57) v2(47.12,110.64) v2(47.12,98.65) v2(47.12,89.89) v2(47.12,89.12) v2(47.13,88.36) v2(47.12,87.55) v2(47.17,109.83) v2(47.17,97.64) v2(47.21,86.78) v2(47.31,106.8) v2(47.3,105.63) v2(47.3,104.62) v2(47.3,103.52) v2(47.27,102.46) v2(47.94,35.59) v2(49.49,27.6) v2(49.49,26.68) v2(50.55,28.11) v2(50.55,27.19) v2(50.76,4.52) v2(51.52,1.09) v2(52.53,145.57) v2(52.61,146.81) v2(52.64,4.55) v2(53.82,170.19) v2(53.89,167.56) v2(54.87,4.55) v2(55.02,68.28) v2(56.42,168.4) v2(56.59,197.43) v2(56.59,196.04) v2(56.56,195.12) v2(56.6,1.09) v2(57.44,170.71) v2(59.85,172.47) v2(60,173.76) v2(60.83,159.58) v2(61.68,1.09) v2(62.41,159.53) v2(62.52,160.96) v2(63.52,201.33) v2(63.61,22.48) v2(63.58,21.62) v2(63.59,20.74) v2(64.09,159.56) v2(65.96,201.28) v2(66.76,1.09) v2(71.84,1.09) v2(74.42,186.59) v2(75.04,182.63) v2(76.92,1.09) v2(79.37,113.39) v2(82,1.09) v2(85.73,1.09) v2(87.43,1.09) v2(92.16,1.09) v2(96.55,28.96) v2(96.58,1.12) v2(99.73,28.83) v2(102.01,214.15) v2(102.01,213.11) v2(102.04,210.79) v2(101.95,1.07) v2(102.07,212.19) v2(104.12,205.94) v2(105.44,1.06) v2(107.74,1.06) v2(108.44,148.03) v2(109.59,224.35) v2(109.88,1.08) v2(111.06,18.72) v2(112.86,1.06) v2(114.76,204.62) v2(116.9,1.09) v2(117.81,138.4) v2(120.8,1.09) v2(122.76,1.11) v2(123.59,224.07) v2(124.7,131.57) v2(125.39,1.11) v2(126.2,125.7) v2(127.26,125.7) v2(127.66,1.07) v2(128.02,113.11) v2(128.38,18.54) v2(128.84,113.08) v2(129.65,113.11) v2(130.18,1.19) v2(131.73,125.81) v2(132.05,208.1) v2(132.65,125.81) v2(132.78,1.09) v2(133.39,208.15) v2(133.59,125.81) v2(135.01,1.15) v2(136.96,125.6) v2(137.93,1.09) v2(139.83,94.54) v2(140.38,1.09) v2(140.83,40.23) v2(142.93,1.09) v2(143.01,35.51) v2(143.06,38.99) v2(143.06,37.29) v2(143.11,33.73) v2(145.17,225.12) v2(146.47,1.13) v2(149.01,1.06) v2(151.01,224.51) v2(151.18,1.09) v2(153.02,220.88) v2(153.09,57.18) v2(153.93,1.22) v2(157.92,219.91) v2(160.54,65.2) v2(160.92,217.3) v2(162.14,66.78) v2(162.34,219.25) v2(162.25,215.85) v2(162.77,191.47) v2(164.55,100.97) v2(164.57,99.95) v2(164.57,98.96) v2(166.12,73.63) v2(166.25,77.57) v2(168.49,116.28) v2(168.56,108.14) v3(24.82,219.43) v3(45.8,116.46) v3(46.06,86.06) v3(72.88,56.69) v3(127.87,203.28) v3(137.8,91.26) v3(159.6,110.87) v3(162.85,78.97) v4(22.87,153.87) v4(23.6,3.96) v4(25.59,71.96) v4(27.16,161.87) v4(43.92,4.32) v4(46.64,112.65) v4(61.98,216.59) v4(62.52,58.14) v4(64.57,181.05) v4(66.2,29.74) v4(69.48,31.62) v4(69.76,69.14) v4(87.76,4.32) v4(88.15,19.56) v4(94.39,225.4) v4(100.06,185.39) v4(111.16,23.83) v4(112.33,8.79) v4(122.41,212.57) v4(127.77,5.44) v4(128.94,191.9) v4(132.09,126.59) v4(135.64,96.47) v4(136.41,17.91) v4(147,223.34) v4(151.09,20.88) v4(156.32,144.73) v4(156.85,32.61) v4(158.43,50.19) v4(163.43,213.61) v4(165.56,99.8) v4(165.92,191.64) v4(178.01,113.92) v4(178.06,84.02) v4(179.23,155.17) v6(1.4,226.34) v6(1.4,221.26) v6(1.4,216.18) v6(1.4,211.1) v6(1.4,206.02) v6(1.4,190.78) v6(1.4,185.7) v6(1.4,180.62) v6(1.4,175.54) v6(1.4,170.46) v6(1.38,167.94) v6(1.4,165.38) v6(1.4,155.22) v6(4.22,228.6) v6(4.99,151.51) v6(5.34,147.19) v6(5.39,141.38) v6(5.37,135.61) v6(9.3,228.6) v6(14.38,228.6) v6(19.46,228.6) v6(21.15,40.02) v6(21.13,29.15) v6(21.15,23.8) v6(21.15,18.55) v6(21.22,35.79) v6(21.16,32.13) v6(21.16,8.43) v6(21.2,4.5) v6(21.25,43.23) v6(24.25,151.91) v6(24.22,150.86) v6(24.19,149.79) v6(24.54,228.6) v6(24.75,215.14) v6(25,222.5) v6(25.28,216.03) v6(25.27,151.89) v6(25.26,150.81) v6(25.26,149.79) v6(25.26,148.72) v6(25.79,216.92) v6(25.84,215.11) v6(26.02,222.53) v6(26.37,216) v6(26.96,215.11) v6(27.54,215.98) v6(28.05,215.04) v6(29.62,228.6) v6(34.7,228.6) v6(38.84,205.03) v6(38.95,209.07) v6(38.95,207.67) v6(38.92,206.07) v6(39.78,228.6) v6(40.04,205.99) v6(40.04,204.98) v6(40.09,209.07) v6(40.09,207.67) v6(41.23,209.07) v6(41.23,207.67) v6(44.86,228.6) v6(49.94,228.6) v6(55.02,228.6) v6(60.1,228.6) v6(61.93,217.6) v6(62.1,22.23) v6(62.24,21.06) v6(63.03,217.6) v6(63.1,216.48) v6(63.08,215.37) v6(64.14,217.63) v6(64.19,216.36) v6(64.19,215.26) v6(64.3,27.81) v6(65.18,228.6) v6(65.29,217.55) v6(65.29,216.23) v6(65.31,215.21) v6(65.44,27.81) v6(66.56,27.71) v6(67.22,69.32) v6(67.34,70.26) v6(68.41,69.29) v6(68.49,70.26) v6(70.26,228.6) v6(70.59,70.28) v6(70.77,57.1) v6(70.77,56.08) v6(71.28,69.19) v6(71.61,70.28) v6(71.92,57.1) v6(71.92,56.08) v6(72.3,69.19) v6(72.63,70.28) v6(73.44,69.19) v6(73.82,56.85) v6(73.77,27.1) v6(74.84,56.85) v6(75.12,27.76) v6(75.34,228.6) v6(76.23,26.85) v6(77.63,26.85) v6(80.42,228.6) v6(85.5,228.6) v6(85.89,19.28) v6(85.94,13.67) v6(85.92,12.29) v6(85.96,16.48) v6(86.06,10.72) v6(88.5,62.05) v6(88.5,61.04) v6(88.5,60.02) v6(88.68,58.17) v6(88.68,57.15) v6(89.52,62.05) v6(89.52,61.04) v6(89.52,60.02) v6(89.7,58.17) v6(89.7,57.15) v6(89.7,56.13) v6(90.54,62.05) v6(90.54,61.04) v6(90.54,60.02) v6(90.58,228.6) v6(90.63,9.98) v6(90.71,58.17) v6(90.71,57.15) v6(90.71,56.13) v6(90.71,16.13) v6(90.71,12.83) v6(92.87,14.73) v6(93.02,8.51) v6(94.24,220.24) v6(95.66,228.6) v6(95.89,6.53) v6(96.81,11.94) v6(96.93,14.73) v6(98.2,220.24) v6(98.46,13.46) v6(98.46,10.54) v6(100.74,228.6) v6(101.4,7.19) v6(104.33,37.9) v6(104.35,36.78) v6(105.72,13.72) v6(105.67,11.53) v6(105.82,228.6) v6(105.85,21.01) v6(105.82,18.8) v6(105.82,16.51) v6(107.25,27.28) v6(108.54,29.24) v6(109.89,29.57) v6(110.9,228.6) v6(115.98,228.6) v6(121.06,228.6) v6(126.14,228.6) v6(127.39,112.34) v6(127.44,111.35) v6(128.05,17.32) v6(128.35,112.29) v6(128.38,111.35) v6(129.27,112.24) v6(131.22,228.6) v6(135.64,95.45) v6(135.59,94.44) v6(135.59,93.42) v6(135.59,92.41) v6(135.59,91.26) v6(135.59,90.25) v6(136.3,228.6) v6(139.91,93.73) v6(139.94,92.76) v6(139.94,91.69) v6(139.96,90.63) v6(140.67,94.34) v6(140.67,93.32) v6(140.7,92.33) v6(140.67,91.26) v6(140.7,90.22) v6(141.38,228.6) v6(141.51,94.36) v6(141.54,93.34) v6(141.56,92.33) v6(141.56,91.24) v6(141.56,90.25) v6(146.46,228.6) v6(146.72,17.81) v6(153.83,7.49) v6(153.83,4.95) v6(154.08,143.38) v6(155.23,143.38) v6(155.53,148.21) v6(155.61,147.19) v6(155.61,146.18) v6(156.37,143.38) v6(156.62,228.6) v6(156.62,148.21) v6(156.62,147.19) v6(156.62,146.18) v6(158.91,16.51) v6(168.6,215.19) v6(168.6,210.11) v6(168.6,56.28) v6(168.56,52.45) v6(168.56,33.66) v6(168.56,29.59) v6(168.6,25.8) v6(168.69,48.51) v6(168.69,44.96) v6(168.69,42.04) v6(168.69,38.1) v6(168.84,205.49) v6(168.79,197.33) v6(168.79,189.94) v6(168.82,169.67) v6(168.82,164.34) v6(168.86,184.71) v6(168.86,179.63) v6(168.86,174.55) v6(170.3,161) v6(174.27,107.05) v6(174.26,105.07) v6(175.38,161) v6(175.7,125.07) v6(176.06,86.51) v6(176.46,107.62) v6(177.07,104.47) v6(177.2,96.27) v6(177.71,99.16) v6(178.01,158.6) v6(178.04,112.42) v6(177.99,93.27) v6(178.11,155.98) v6(178.14,120.95) v6(178.11,115.29) v6(178.19,117.91) v6(178.26,125.81) v6(178.34,68.33) v6(179.08,128.55) v6(179.33,144.7) v6(179.33,142.24) v6(179.33,137.87) v6(179.43,133.6) v6(179.48,90.35) v6(179.56,86.59) v6(179.76,100.94) v6(180.32,96.29) v6(180.4,93.09) v6(180.46,161) v6(180.83,150.98) v6(180.91,154.1) v6(180.86,99.03) v6(181.03,156.72) v6(180.98,140.44) v6(181.14,146.89) v6(181.11,136.35) v6(181.19,132.54) v6(181.34,116.94) v6(181.34,112.55) v6(181.52,127.74) v6(181.49,121.49) v6(181.57,124.61) v6(181.85,100.94) v6(181.85,90.25) v6(182.02,86.46) v6(182.64,109.24) v6(183.6,153.99) v6(183.6,148.91) v6(183.6,143.83) v6(183.6,138.75) v6(183.6,133.67) v6(183.6,123.51) v6(183.6,118.43) v6(183.6,113.35) v6(183.6,102.24) v6(183.6,97.16) v6(183.6,92.08) v6(183.6,87) v6(183.6,81.92) v6(183.73,128.04)
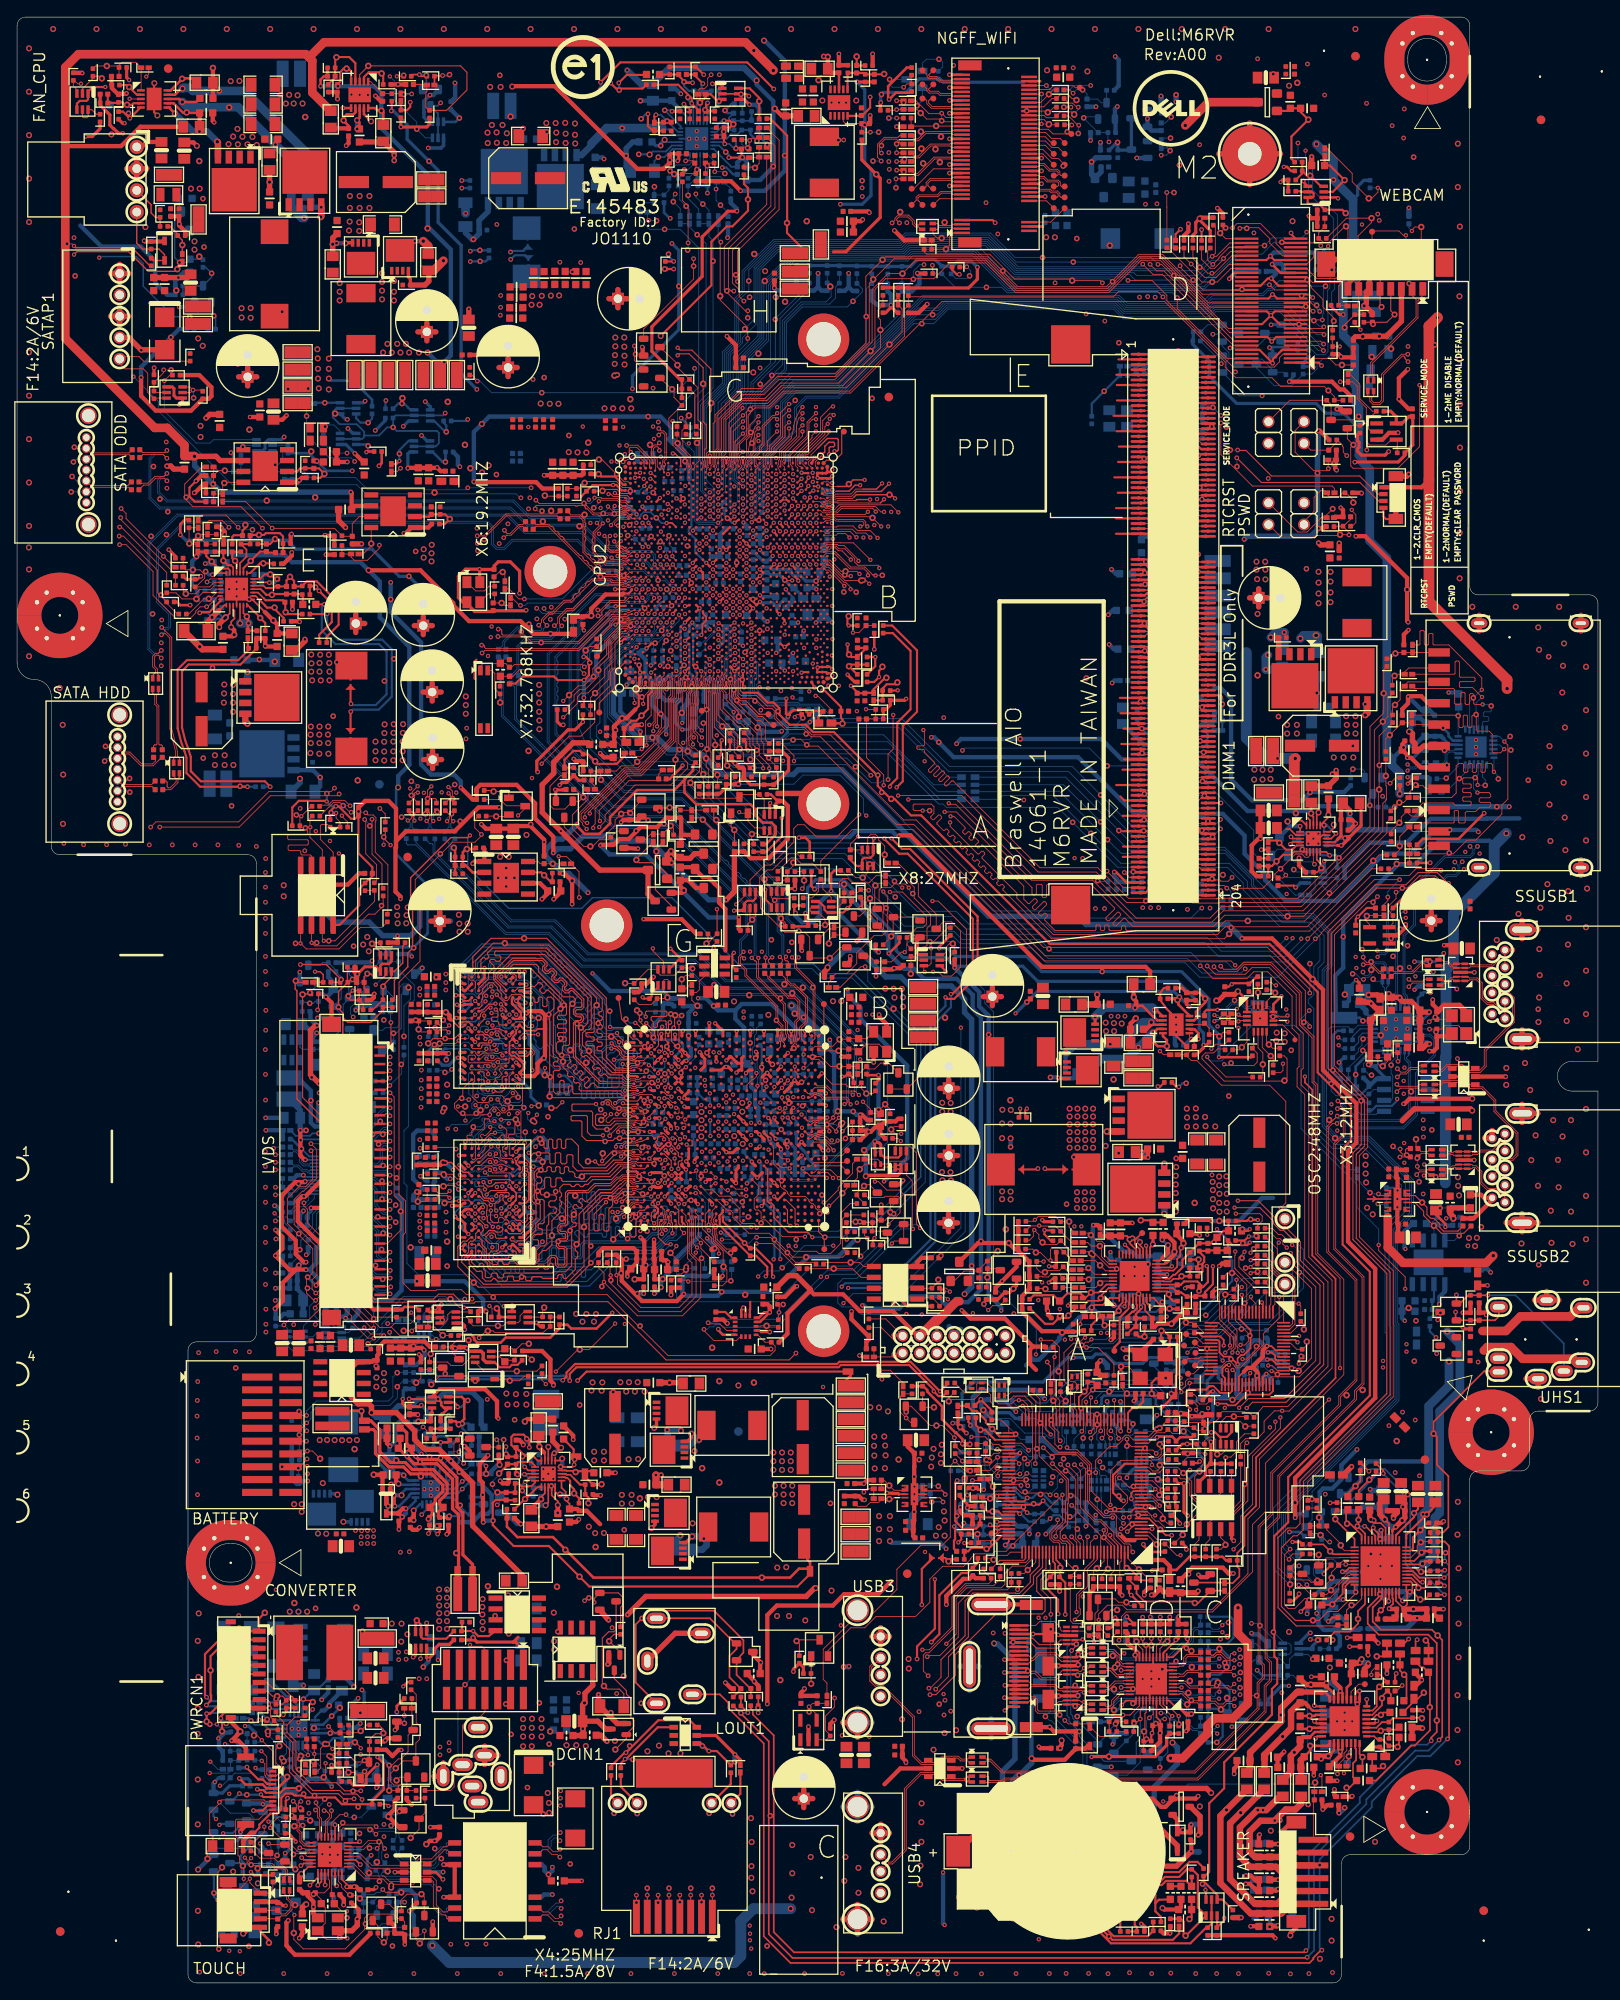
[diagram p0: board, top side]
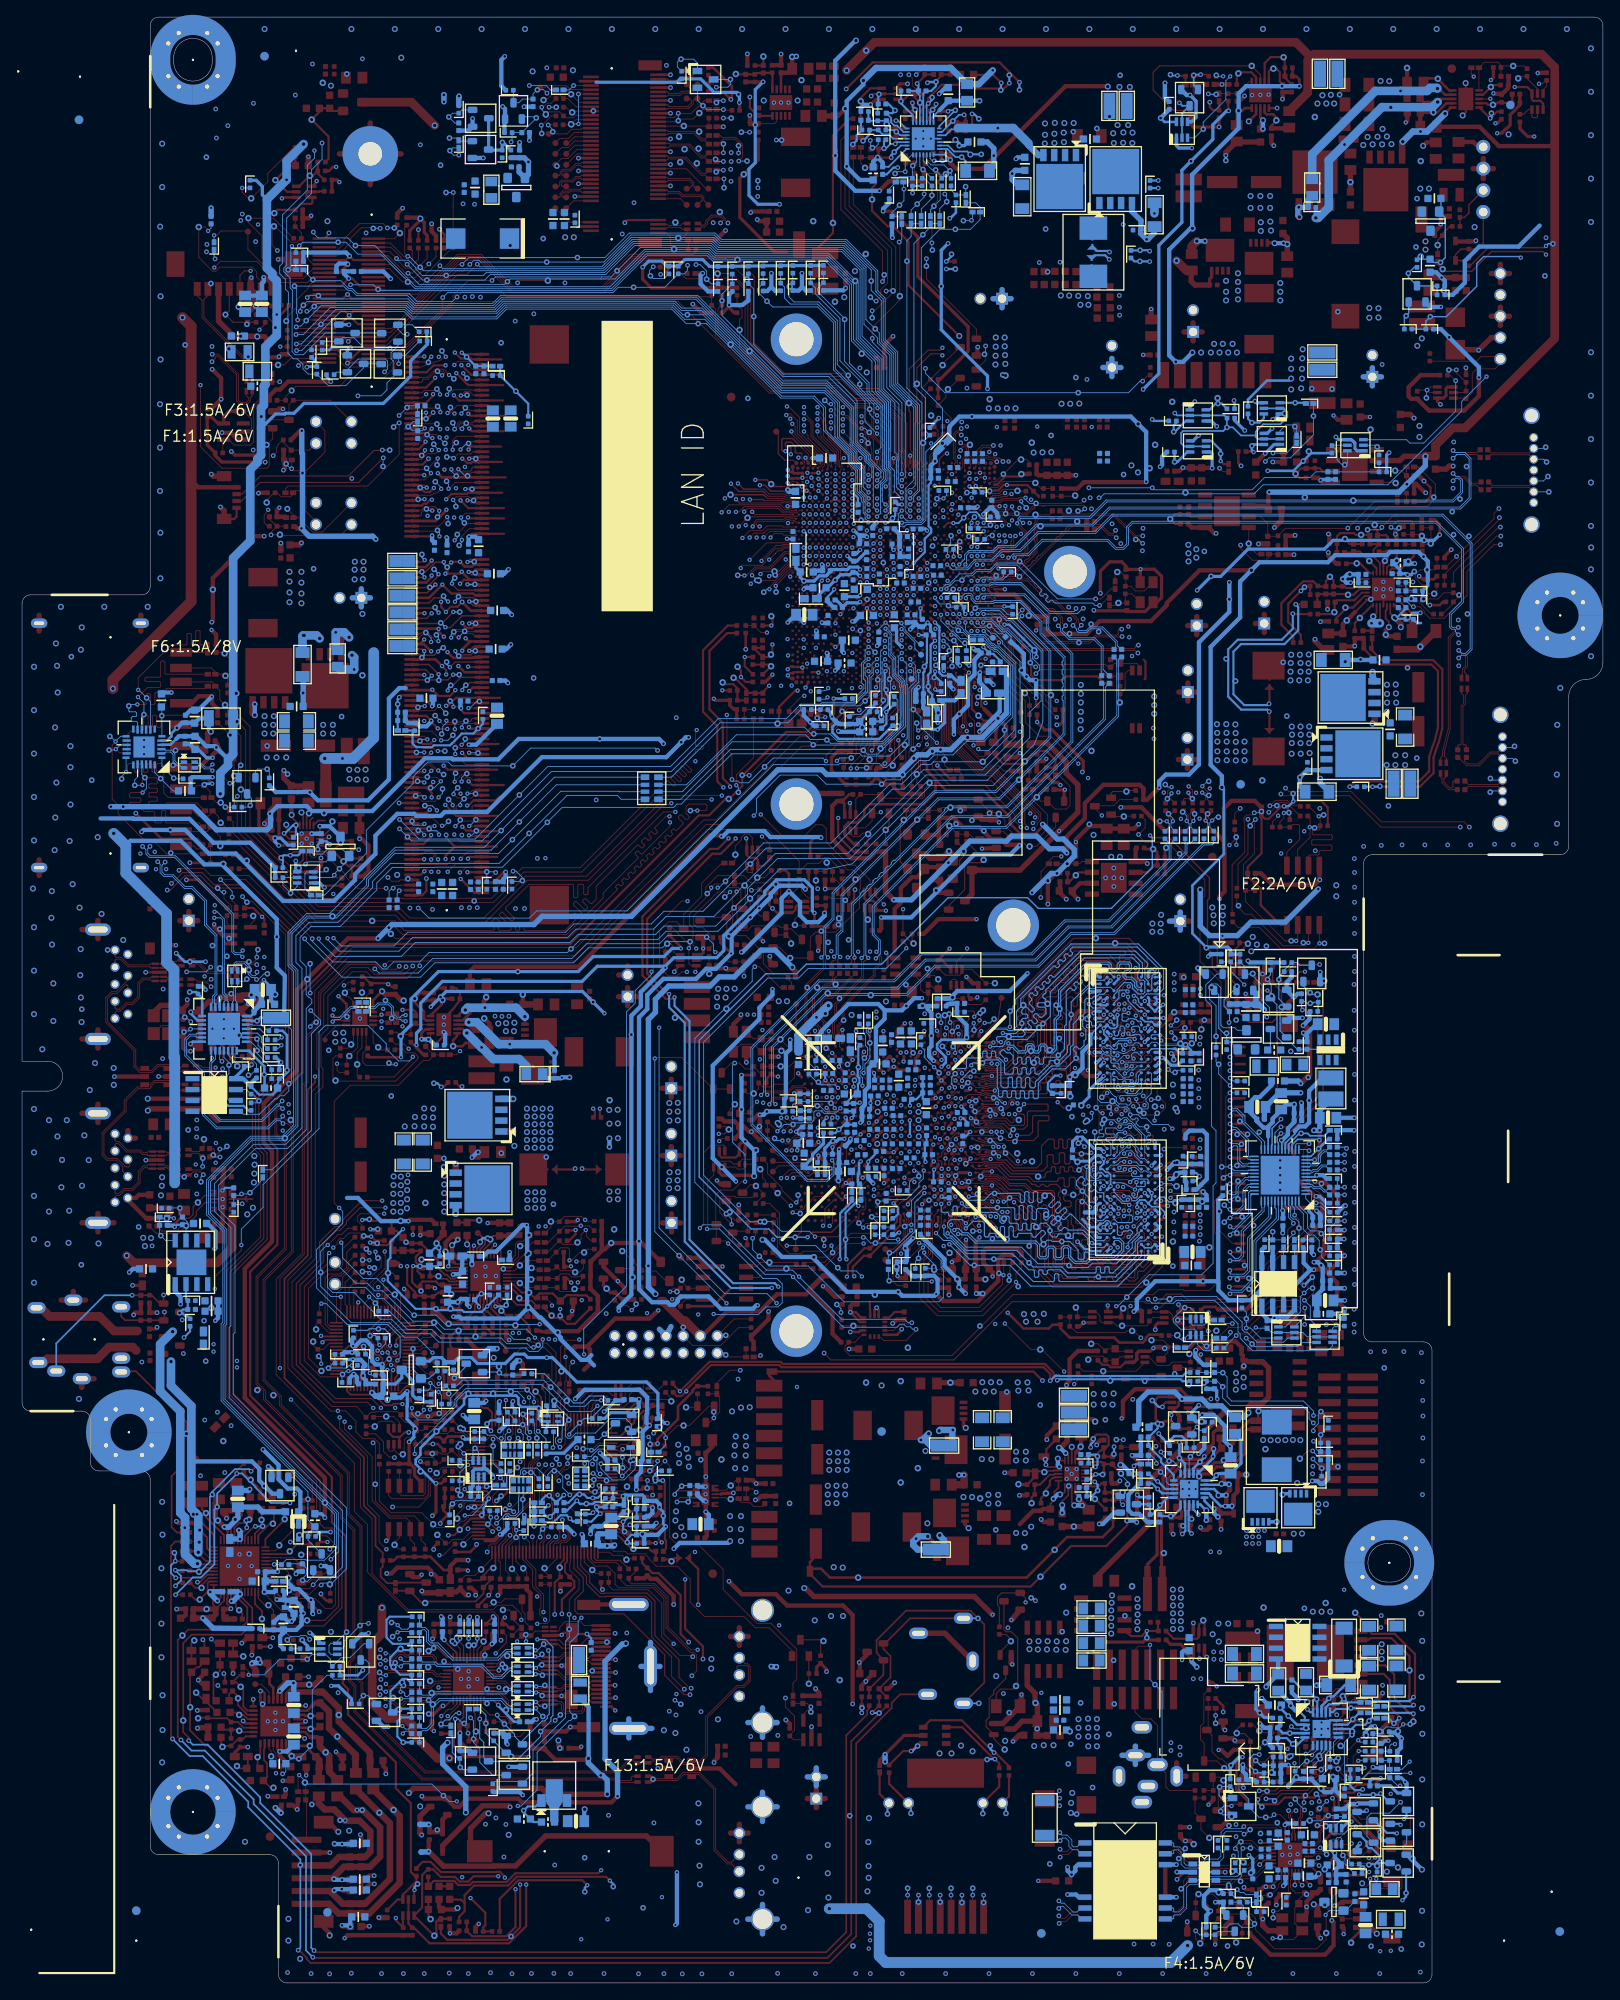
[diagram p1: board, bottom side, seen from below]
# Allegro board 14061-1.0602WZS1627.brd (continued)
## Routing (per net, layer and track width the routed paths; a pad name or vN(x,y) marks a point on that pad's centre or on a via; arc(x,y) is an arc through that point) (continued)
GND_AUD: length 5.4
  TOP w0.203: U6.40 160.55,53.74 v3(160.05,54.23)
  TOP w0.635: v3(160.05,54.23) 159.48,54.8 C145.2 159.48,56.12 C144.1
V1P8_FUSE: length 10.1
  TOP w0.305: CPU2.U16 78.68,159.69 v1(78.16,159.17)
  BOTTOM w0.254: C1660.1 77.28,152.95 77.66,153.32 77.66,153.75 v4(78.06,154.16) 78.06,154.17 77.66,154.58 77.66,158.21 77.63,158.24 77.63,158.64 v1(78.16,159.17)
  BOTTOM w0.381: R1253.2 75.62,152.34 76.23,152.95 C1660.1
VBAT1: length 32.5
  TOP w0.508: v1(137.41,15.38) 137.41,16.66 R199.1
  TOP w0.635: v1(137.41,15.38) 135.69,13.66 129.79,13.66 129.77,13.69 127.24,13.69 123.73,17.2 111.93,17.2 BT1.1
  BOTTOM w0.635: v1(137.41,15.38) 137.47,15.32 TP14.1
VBAT1_R: length 5.7
  TOP w0.559: D5.2 135.78,19.11 D6.A 135.78,17.66 R199.2 137.3,17.67 137.3,18.43 v1(137.39,18.52)
  BOTTOM w0.635: v1(137.39,18.52) 137.42,18.54 TP13.1
VBAT2: length 106.3
  TOP w0.381: v2(111.09,64.32) 111.07,64.32 v3(110.36,65.03) 110.12,65.28 110.12,66.12 110.08,66.15 R381.1
  TOP w0.635: v2(127.9,20.59) 128.04,20.73 131.12,20.73 135.78,16.07 D6.K
  L3 w0.508: v2(111.09,64.32) 111.23,64.32 111.42,64.52 111.95,64.52 112.48,63.98 114.83,63.98 115.29,63.53 121.23,63.53 121.79,64.09 123.32,64.09 124.44,62.97 130.53,62.97 131.45,63.88 132.17,63.88 133.03,64.74 133.79,64.74 133.85,64.68 138.4,64.68 139.17,65.46 146.13,65.46 146.59,65 v1(146.62,65)
  L4 w0.508: v2(127.9,20.59) 131.34,24.03 136.2,24.03 141.36,29.19 141.36,38.07 141.33,38.09 141.33,39.6 142.63,40.89 142.63,42.29 143.77,43.43 143.77,56.36 145.64,58.23 145.64,61.85 146.54,62.75 146.54,64.92 v1(146.62,65)
VBAT_SIO: length 7.7
  TOP w0.203: U109.66 114.98,63.94
  TOP w0.254: R381.2 111.16,67.52 C218.1 111.21,67.51 111.79,66.93 112.26,66.93 113.38,65.82 113.38,65.55 v3(114.11,64.81) 114.98,63.94
VCC: length 368.7
  TOP w0.305: R1688.1 100.57,118.36 100.52,118.31 v2(100.52,117.78) ; R421.1 45.69,35.19 v1(45.19,34.7) ; v2(150.02,45.52) 150.02,45.36 149.35,44.69 R617.1
  TOP w0.381: v1(134.53,77.95) 134.45,77.95 134.28,77.79 PR11.1
  TOP w0.508: v2(61.42,126.8) 62.1,127.47 PC5435.1 61.2,128.66 PU7.6 ; PR44.2 126.46,88.67 v1(125.94,88.67) ; v6(118.73,26.26) 118.8,26.26 118.96,26.11 122.6,26.11 C714.2 123.9,27.41 124.98,27.41 125.28,27.71 D33.A
  TOP w0.635: v6(116.52,22.07) 123.48,22.07 124.16,22.76 139.2,22.76 v6(139.73,22.23)
  L3 w0.508: v6(139.73,22.23) 140.27,22.76 142.3,22.76 143.75,24.21 143.75,26.31 146.38,28.94 146.38,36.04 146.39,36.05 146.39,41.99 149.92,45.52 v2(150.02,45.52)
  L3 w0.635: v6(118.73,26.26) 116.67,28.32 106.08,28.32 v6(103.56,30.84)
  L3 w1.016: v6(92.24,42.42) 92.24,65.3 87.64,69.9 v6(84.41,69.9) ; v1(45.19,34.7) 45.22,34.67 50.45,34.67 51.67,35.89 v6(71,35.89)
  L3 w2.54: 64.1,78.54 62.29,78.54 58.81,82.02 49.21,82.02 45.42,85.8 45.42,118.36
  L4 w0.508: v2(100.52,117.78) 97.65,117.78 95.41,120.02 94.16,120.02 93.37,119.23 80.19,119.23 78.9,120.52 78.18,120.52 69.65,129.05 63.68,129.05 v2(61.42,126.8) 61.33,126.7 56.39,126.7 53.79,129.3 46.13,129.3 40.98,124.14 v6(40.98,122.38)
  L4 w0.762: v6(92.24,42.42) 94.37,40.28 94.37,37.83 101.37,30.84 v6(103.56,30.84)
  L4 w1.016: v6(92.24,42.42) 92.24,36.14 91.24,35.15 87.67,35.15 86.63,36.19 82.65,36.19 82.36,35.89 v6(71,35.89)
  BOTTOM w0.508: 125.69,79.1 124.44,77.85 124.31,77.85 121.98,75.52 121.98,75.32 119.56,72.9 118.92,72.9 ; 125.69,79.1 125.89,79.3 v4(125.89,85.19) 125.89,88.37 125.92,88.4 125.92,88.56 125.94,88.58 v1(125.94,88.67) 126.42,88.67 129.52,85.57 130.45,85.57 131.02,85 PR9771.1 ; 125.69,79.1 127.05,77.74 133.61,77.74 133.83,77.95 v1(134.53,77.95) ; 118.92,72.9 118.37,73.44 ; 118.92,72.9 118.71,72.9 118.07,72.25 ; F13.1 118.7,32.28 118.7,26.29 v6(118.73,26.26)
  BOTTOM w0.635: 109.06,76.78 LPC1.8 110.41,76.48 ; v6(118.73,26.26) 118.73,25.73 v4(117.28,24.28) 117.08,24.28 116.52,23.72 v6(116.52,22.07)
  vias: v3(21.32,201.98) v4(21.88,203.1) v4(39.38,121.3) v4(51.29,74.24) v4(72.91,76.86) v4(105.57,61.21) v6(20.76,203.76) v6(20.76,202.79) v6(21.19,192.41) v6(21.72,191.54) v6(31.2,128.42) v6(31.2,127.14) v6(40.5,121.49) v6(41.16,120.7) v6(65.43,78.28) v6(66.16,77.36) v6(66.62,78.26) v6(67.51,77.37) v6(67.75,78.25) v6(107.04,61.47) v6(106.97,60.4) v6(107.25,62.48) v6(108.11,61.85) v6(108.11,60.83) v6(108.21,62.97)
VCC0_HOT: length 6.7
  BOTTOM w0.102: R79786.2 83.52,209.92 R1604.2 82.75,210.88 82.3,211.33 81,211.33 R1734.2 80.81,212.58 v4(80.77,212.61) 80.34,213.05 PU4401.2
VCC0_PG: length 6.1
  TOP w0.102: v2(78.24,213.18) 79.04,213.18 PC4409.1 79.43,212.79 PR4401.2 77.93,211.7 R1577.1 76.9,211.62 v3(76.89,211.63)
  BOTTOM w0.102: v2(78.24,213.18) 78.47,213.18 78.73,213.45 PU4401.6
VCC0_SENSEN_CPU_N: length 56.4
  TOP w0.102: v2(85.05,196.77) 84.51,197.31 84.51,198.09 83.73,198.88 83.73,202.32 83.73,202.72 88.69,207.69 88.69,214.93 R1585.1 ; CPU2.AJ32 v1(85.35,166.9)
  L4 w0.127: v2(85.05,196.77) 85.05,195.89 85,195.85 85,193.53 83.14,191.67 83.14,178.85 83.42,178.57 83.42,178.22 83.28,178.09 83.28,170.52 83.92,169.89 83.92,166.95 84.4,166.48 84.93,166.48 v1(85.35,166.9)
  BOTTOM w0.102: v2(85.05,196.77) 85.26,196.77 v4(85.72,197.23)
VCC0_SENSEN_CPU_P: length 52.7
  TOP w0.102: R1584.1 87.73,208.09 82.76,203.12 82.76,198.1 85.22,195.64 v2(85.51,195.64) ; CPU2.AG32 v1(84.57,166.9)
  L4 w0.127: v1(84.57,166.9) 84.15,167.32 84.15,169.98 84.13,170 84.13,170 83.51,170.62 83.51,177.99 83.65,178.13 83.65,191.46 85.51,193.32 v2(85.51,195.64)
  BOTTOM w0.102: v4(85.51,194.82) v2(85.51,195.64)
VCC0_SENSEN_N: length 6.7
  TOP w0.102: R1823.1 85.66,215.65 v2(85.73,215.57) ; v2(85.73,215.57) 85.99,215.82 86.76,215.82 R1585.2 R1587.2 ; v2(85.73,215.57) 85.65,215.49 PC4414.2
  BOTTOM w0.102: v2(85.73,215.57) 85.73,214.96 v4(85.48,214.71) 85.22,214.71 84.81,215.13 R1823.1
VCC0_SENSEN_P: length 5.1
  TOP w0.102: R1586.2 R1584.2 ; R1584.2 86.78,213.56 PR4410.1 ; R1584.2 86.84,212.85 v3(86.35,212.37) 86.26,212.45 R1822.2
VCC1_SENSEN_CPU_N: length 60
  TOP w0.102: v1(82.99,164.62) 83.37,165 CPU2.AF27 ; R1587.1 89.17,215.6 89.17,207.49 84.31,202.62 v2(84.31,199.06)
  L4 w0.127: v2(84.31,199.06) 84.18,198.93 83.94,198.93 80.47,195.46 80.47,187.53 81.28,186.73 81.28,179.26 81.77,178.77 81.77,177.73 82.47,177.03 82.47,168.82 81.57,167.92 81.57,167.39 82.16,166.8 82.16,165.5 82.99,164.67 v1(82.99,164.62)
  BOTTOM w0.102: v4(84.1,199.85) 84.1,199.27 v2(84.31,199.06)
VCC1_SENSEN_CPU_P: length 56.3
  TOP w0.102: v2(83.88,197.94) 83.6,197.94 83.24,198.3 83.24,202.12 83.24,202.52 83.24,202.52 83.24,202.92 88.21,207.89 88.21,214.21 87.73,214.69 R1586.1 ; v1(83,165.38) CPU2.AD29
  L4 w0.127: v2(83.88,197.94) 83.67,197.94 80.98,195.25 80.98,187.81 81.51,187.29 81.51,179.36 82,178.87 82,177.83 82.69,177.13 82.69,168.73 81.8,167.83 81.8,167.48 82.41,166.87 82.41,165.97 v1(83,165.38)
  BOTTOM w0.102: v2(83.88,197.94) 83.85,197.97 v4(83.07,197.97)
VCC3: length 1125.9
  TOP w0.203: C4283.1 133.79,30.63 133.34,31.08 U127.37 ; v2(155.18,44.86) 155.45,45.13 155.45,46.42 155.99,46.97 U6.11 ; v2(136.96,40.24) 137.02,40.19 137.02,39.86 135.26,38.11 U127.11 ; v1(145.66,79.62) 145.7,79.58 145.7,79.46 145.77,79.39 U4101.4
  TOP w0.305: R303.2 134.27,50.42 132.54,50.42 131.83,51.13 131.83,51.16 131.81,51.18 v2(131.81,51.31) ; R293.1 137.5,63.85 136.11,63.85 R310.2 135.63,63.47 135.17,63.93 133.51,63.93 v2(133.41,63.83) ; v2(44.43,31.7) 44.43,32.4 R430.1 ; v1(128.5,42.77) 128.78,42.49 128.78,41.99 R79748.1 128.41,41.98 127.96,41.53 R80112.1 ; R79781.2 110.32,56.9 111.16,56.06 111.16,55.66 v2(111.21,55.6) ; v6(161.81,139.12) 161.83,139.14 R576.2 ; R213.1 150.13,51.59 v1(149.26,51.59) ; v1(27.37,12.98) 27.75,12.6 29.81,12.6 R1719.1 ; v2(128.4,129.97) 128.6,129.97 129.82,128.75 DIMM1.199 ; v1(32.6,16.51) 32.6,16.65 32.04,17.2 32.04,17.25 31.79,17.5 R331.1 ; R7.1 153.77,196.15 154.72,195.2 v2(155.19,195.2) ; R143.1 39.36,23.09 40.57,23.09 40.88,23.39 40.88,24.27 v2(42.14,25.53) ; v2(65.57,135.56) 65.57,135.29 66.41,134.44 68.16,134.44 69.4,135.68 69.4,136.42 72.54,139.56 76.91,139.56 78.1,140.75 ; 78.1,140.75 78.1,139.28 79.48,137.9 85.82,137.9 86.43,137.29 86.43,136.59 87.26,135.76 88.3,135.76 88.78,135.28 U35.6 88.72,134.72 88.72,134.3 87.66,133.24 C522.1 ; 78.1,140.75 78.1,140.84 78.21,140.95 78.21,140.96 79.1,141.85 79.1,142.47 R79662.1
  TOP w0.508: 32.65,83.46 31.86,83.46 v2(30.23,85.09) 31.02,85.88 31.02,87.32 v2(30.25,88.09) ; 32.65,83.46 33.79,83.46 v2(33.82,83.44) ; 32.65,83.46 31.1,81.92 31.1,79.79 30.2,78.89 v2(30.18,78.89) ; R79742.1 133.75,28.21 v2(133.75,29.24) 133.79,29.27 C4283.1 ; R79683.1 R517.1 54.08,78.66 54.77,78.66 v2(54.88,78.55) ; LPC1.4 105.38,75.7 102.51,78.57 R324.1 99.65,78.6 98.62,78.6 96.65,80.57 93.25,80.57 92.82,81 90.15,78.33 90.15,75.96 R6704.1 ; D1.K 17.19,203.75 R71.1 14.98,203.75 14.89,203.84 v2(14.87,203.84) ; R50.2 R44.2 v1(44.52,122.5) ; v2(14.51,187.83) 14.51,185.67 16.23,183.96 20.35,183.96 R6703.1 22.42,185.33 22.74,185.65 22.74,186.69 21.32,188.11 R64.1 ; v1(131.55,6.91) 131.92,6.54 R362.1 ; R138.1 42.96,28.24 v2(43.09,28.37) 43.32,28.61 D14.2 ; v2(136.96,40.24) 136.96,40.34 136.78,40.52 136.78,40.96 136.8,40.99 C4285.1 ; v2(111.21,55.6) 111.23,55.6 111.41,55.78 R375.2 ; v2(31.73,7.32) 31.73,7.29 31.52,7.08 31.52,4.38 31.88,4.01 31.88,3.94 32.52,3.3 38.89,3.3 41.33,5.74 R707.2 ; Q2301.G 125.5,45.59 125.94,46.03 R335.2 R79666.2 R354.2 R79766.2 129.04,45.62 v2(129.32,45.34) ; v2(134.9,42.82) R79749.1 134.89,41.99 R79744.1 133.78,41.98 R79746.1 R79735.1
  TOP w0.635: R184.1 94.48,118.32 94.85,118.69 v6(94.85,118.82) ; v2(35.36,105.23) 34.34,106.26 34.34,111.45 34.9,112.01 v2(35.09,112.01) ; 92.82,81 92.82,81.13 91.19,82.75 90.25,82.75 R6701.1
  TOP w1.016: 110.27,79.76 109.98,79.76 107.72,77.5 107.43,77.5 LPC1.4
  L3 w0.381: v1(149.26,51.59) 150.73,50.11 150.73,47.83 151.65,46.91 151.65,43.66 v2(152.08,43.23)
  L3 w0.508: v2(14.51,187.83) 14.6,187.75 14.6,184.32 14.63,184.29 14.63,152.34 15.4,151.56 15.4,141.26 15.43,141.24 15.43,140.7 19.18,136.94 28.72,136.94 28.72,136.93 28.9,136.93 32.62,133.21 32.62,133.18 32.72,133.08 32.72,130.73 33.79,129.67 33.79,128.37 33.58,128.26 v2(33.31,127.98) 33.62,127.67 33.62,122.07 33.8,121.89 33.8,121.36 33.62,121.19 33.62,120.46 35.5,118.58 35.5,115.66 35.47,115.63 35.47,114.46 35.82,114.11 35.82,112.63 35.43,112.24 35.31,112.24 v2(35.09,112.01) ; 145.68,78.21 145.68,79.61 v1(145.66,79.62) ; v2(130.77,18.57) 132.13,19.93 v6(133.07,19.93)
  L3 w0.635: v2(31.73,7.32) 31.73,8.23 32.35,8.85 32.35,16.24 32.6,16.48 v1(32.6,16.51) 35.47,19.38 37.03,19.38 38.49,20.84 38.49,21.88 v2(42.14,25.53) 42.27,25.53 43.09,26.34 v2(43.09,28.37) 43.09,30.33 44.33,31.57 44.33,31.6 v2(44.43,31.7) 45.05,32.32 51.67,32.32 52.34,32.99 65.29,32.99 v6(69.96,28.32) ; v6(138.41,20.65) 139.51,20.65 140.66,21.81 142.69,21.81 145.19,24.31 145.19,25.15 148.9,28.85 148.9,34.33 148.83,34.4 v1(148.83,34.75) 148.85,34.77 148.85,35.66 154.67,41.48 154.67,44.35 v2(155.18,44.86) ; v6(135.21,28.12) 135.21,29.13 136.74,30.66 136.74,33.96 137.03,34.25 137.03,34.37 137.09,34.43 137.09,40.12 v2(136.96,40.24) 136.99,40.24 136.99,40.27 137.02,40.29 137.02,41.35 136.26,42.11 135.49,42.11 134.9,42.7 v2(134.9,42.82) 134.1,43.62 129.55,43.62 128.72,42.8 128.53,42.8 ; v2(37.88,81.03) 38.5,81.65 38.5,102.1 v2(35.36,105.23) ; 128.53,42.8 v1(128.5,42.77) ; 128.53,42.8 128.53,44.55 v2(129.32,45.34) 129.32,46.97 132.05,49.71 132.05,51.07 v2(131.81,51.31)
  L3 w1.016: v2(130.77,18.57) 126.14,13.94 122.82,13.94 v2(122.66,13.79) ; v6(129.8,73.14) 132.01,75.35 133.18,75.35 135.38,77.55 138.82,77.55 139.45,78.18 145.65,78.18 145.68,78.21 145.89,78.21 147.1,79.41 148.09,79.41 150.96,82.28 150.96,87 152.15,88.19 152.15,103.48 152.48,103.81 152.48,111.94 154.36,113.82 154.36,127.28 161.81,134.72 v6(161.81,139.12)
  L4 w0.381: v2(128.4,129.97) 129.79,128.58 138.96,128.58 140.69,130.31 148.61,130.31 148.66,130.26 154.2,130.26 161.81,137.87 v6(161.81,139.12)
  L4 w0.508: v1(32.6,16.51) 31.76,16.51 28.23,12.98 v1(27.37,12.98) ; 129.7,66.57 128.43,66.57 127.64,67.36 127.64,67.94 v2(127.55,68.03) ; v1(131.55,6.91) 131.43,7.04 131.43,9.96 132.65,11.18 132.65,16.46 130.77,18.34 v2(130.77,18.57)
  L4 w0.635: v2(14.87,203.84) 14.89,203.81 14.89,203.66 15.26,203.29 15.26,188.58 v2(14.51,187.83) ; v6(135.21,28.12) 135.21,28.19 134.17,29.24 v2(133.75,29.24) 133.75,28.82 132.85,27.91 v1(128.2,27.91) ; v6(152.05,215.14) 147.38,219.81 138.28,219.81 137.55,219.07 135.19,219.07 133.87,220.4 v2(133.87,220.75) ; v6(133.07,19.93) 136.6,19.93 137.32,20.65 v6(138.41,20.65) ; v2(116.37,19.61) 111.74,24.23 95.18,24.23 93.49,25.92 73.3,25.92 70.9,28.32 v6(69.96,28.32) ; v6(47.12,127.91) 53.17,127.91 55.72,125.36 62.39,125.36 64.74,127.72 66.65,127.72 v2(66.81,127.56) 68.95,127.56 75.75,120.75 75.75,120.72 78.58,117.9 93.93,117.9 v6(94.85,118.82)
  L4 w1.016: LPC1.4 104.34,77 103.1,77 102.34,76.24 102.34,73.16 103.39,72.11 107.59,72.11 109.94,69.76 113.41,69.76 115.51,67.66 115.51,66.92 117.38,65.05 121.75,65.05 124.72,62.08 124.72,61.9 125.64,60.98 v2(126.72,60.98)
  BOTTOM w0.305: SU1.4 167.9,144.88 167.63,144.88 166.96,145.54
  BOTTOM w0.381: PR5.1 157.6,210.9 156.88,210.19 156.88,209.19 156.34,208.66 ; R323.2 R79689.2 133.2,63.63 v2(133.41,63.83) ; v2(127.55,68.03) 127.64,67.94 127.64,67.44 127.3,67.09 R149.1 ; R1745.1 137.64,192.15 R1744.1 137.59,191.71 139.53,189.76 139.53,187.99 142.72,184.8 152.01,184.8 153.16,183.65 154.15,183.65 154.24,183.57 155.33,183.57 157.03,181.86 ; R336.2 123.59,61.98 121.6,61.98 120.35,63.22 120.31,63.22 R644.2 ; R79723.1 146.44,33.23 147.96,34.75 v1(148.83,34.75)
  BOTTOM w0.457: R79680.2 v2(30.25,88.09) ; R79677.1 31.09,85.05 R79678.1 30.26,85.06 v2(30.23,85.09)
  BOTTOM w0.508: v2(35.09,112.01) 34.33,112.77 34.33,113.59 R41.1 ; R32.1 39.91,85.79 U25.8 39.91,81.1 39.83,81.03 ; 34.22,83.44 36.38,81.28 37.63,81.28 v2(37.88,81.03) ; 34.22,83.44 v2(33.82,83.44) ; 34.22,83.44 35.02,84.24 35.02,85.98 R79673.1 ; R80110.1 128.65,29.21 Q1255.G 128.34,28.05 v1(128.2,27.91) ; C474.1 154.31,45.76 R206.1 ; C474.1 153.23,44.82 C478.2 153.1,44.75 152.31,43.96 152.31,43.46 v2(152.08,43.23) 152.28,43.03 152.28,42.23 152.29,42.21 152.29,41.92 152.92,41.3 C509.1 ; C474.1 155.14,44.82 v2(155.18,44.86) ; C399.1 C398.2 128.68,129.15 128.4,129.43 v2(128.4,129.97) ; C509.1 154.41,40.94 154.8,40.56 154.8,39.48 R634.2 ; C509.1 154.43,41.31 C516.1 157.06,41.31 L21.1 ; 45.14,82.07 45.02,82.19 45.02,91.58 R482.1 ; 45.14,82.07 44.99,81.92 44.99,81.03 43.84,79.87 R79669.1 41.22,79.87 40.06,81.03 39.83,81.03 ; 45.14,82.07 45.17,82.09 v4(46.79,82.09) 52.38,82.09 54.54,79.93 54.54,78.89 v2(54.88,78.55) ; 39.83,81.03 v2(37.88,81.03) ; L17.1 31.21,78.28 30.67,77.74 R79679.1 30.26,78.82 v2(30.18,78.89) ; 160.89,143.18 v4(162.26,144.54) 162.42,144.7 163.46,144.7 164.61,145.86 SC1.2 164.76,145.86 SC3.2 166.64,145.86 166.96,145.54 ; v2(37.88,81.03) 37.88,80.95 37.37,80.44 U25.3 ; R649.2 112.1,54.46 111.97,54.58 111.64,54.58 111.24,54.98 111.24,55.58 v2(111.21,55.6) ; R79936.1 18.96,193.5 v4(17.99,192.53) 14.51,189.05 v2(14.51,187.83) ; v2(120.38,52.5) 121.22,53.34 R297.1 ; R134.1 40.76,23.72 41.65,23.72 R516.2 41.77,23.84 41.77,24.38 42.14,24.76 v2(42.14,25.53) ; Q1256.G 132.54,27.15 R80111.1 133.75,27.17 v2(133.75,29.24)
  BOTTOM w0.635: v6(133.07,19.93) 133.07,22.93 135.78,25.64 135.78,27.55 v6(135.21,28.12) ; v6(94.85,118.82) 96.87,120.84 98.52,120.84 101.65,117.7 103.41,117.7 104.48,116.64 109.33,116.64 110.88,115.08 110.88,113.55 111.7,112.73 v4(111.7,83.9) 111.7,81.42 v6(110.88,80.59) ; L16.1 35.66,105.52 v2(35.36,105.23) ; v2(66.81,127.56) 64.56,129.81 v4(63.89,129.81) 61.86,131.84 61.86,132.58 63.11,133.83 63.84,133.83 v2(65.57,135.56) ; v6(47.12,127.91) 47.12,123.62 46.04,122.53 44.55,122.53 v1(44.52,122.5) 44.5,122.53 42.78,122.53 41.19,124.12 37.17,124.12 v2(33.31,127.98) ; R1615.2 133.89,220.52 133.87,220.55 v2(133.87,220.75)
  BOTTOM w1.016: v6(152.05,215.14) 154.05,213.14 v4(154.05,210.96) 156.34,208.66 156.34,200.62 155.71,199.99 155.71,199.67 155.19,199.15 v2(155.19,195.2) 155.19,192.76 156.52,191.43 F1.1 156.52,186.99 R24.1 156.7,184.6 157.03,184.27 157.03,178.74 157.46,178.31 157.46,177.9 158.3,177.07 158.3,168.71 160.3,166.71 F6.2 160.3,143.77 160.89,143.18 160.89,142.47 161.81,141.55 v6(161.81,139.12)
  vias: v4(119.16,14.66) v6(107.53,52.32) v6(107.86,53.31) v6(108.47,55.17) v6(108.54,54.1) v6(108.54,52.32)
VCC3_CAM: length 10.4
  TOP w0.584: v6(157.47,192.62) 156.61,192.62 156.39,192.4 C8.2
  TOP w0.635: WEBCM1.3 162,194.42 160.24,192.66 v3(159.42,192.66) 157.54,192.66 157.5,192.62 v6(157.47,192.62)
  vias: v4(158.69,194.06)
VCC3_CARD: length 5.8
  TOP w0.635: Q9641.D 79.3,132.13 78.75,131.57 77.62,131.57 R80152.1 77.24,131.69 v3(76.52,132.41) 76.07,131.96 Q9632.S
VCC3_EN: length 6.5
  TOP w0.102: U52.5 102.62,56.78 102.44,56.6 v3(102.07,56.6) 101.2,56.6 R1747.1 101.14,56.53 100.82,56.21 99.83,56.21 99.38,55.75 98.39,55.75 C1667.1
VCC5_PANEL:
  vias: v2(43.64,108.33) v2(43.64,107.52) v4(42.92,112.66)
VCC_EN: length 4.3
  TOP w0.102: U52.3 103.39,57.58 103.33,57.63 102.62,57.63 v3(102.06,58.19) 101.43,58.83 C1696.1 R1776.1
VCC_FAN:
  vias: v3(21.32,213.16) v4(21.75,208.76) v6(20.35,209.93) v6(21.37,209.93)
VCC_FAN_PWR: length 4.7
  TOP w0.635: 14,211.09 FANC3.2 ; FANC3.2 14,213.45 ; FANC3.2 15.18,212.27 ; FANC3.2 12.82,212.27
VCC_SVID_ALERT: length 3.9
  BOTTOM w0.102: R1654.2 77.38,211.38 78.09,212.09 v4(78.09,212.12) 78.48,212.12 79.54,213.17 PU4401.4
VCC_SVID_ALERT_R: length 4.1
  BOTTOM w0.102: PR5234.2 78.7,207.47 78.29,207.87 v4(78.29,207.88) 78.29,207.88 77.55,208.61 77.55,210.07 R1654.1
VCC_SVID_CLK: length 4.8
  BOTTOM w0.102: R79790.2 76.28,211.88 76.41,212.01 v4(76.41,212.01) 77.1,212.7 78.62,212.7 79.13,213.21 PU4401.5
VCC_SVID_CLK_R: length 3.5
  BOTTOM w0.102: R79790.1 76.28,209.76 R79795.2 74.58,209.19 PR5233.2 74.55,210.13 v4(74.58,210.16)
VCC_SVID_DATA: length 3.4
  BOTTOM w0.102: R1653.2 78.53,211.14 v4(79.56,212.17) 79.94,212.54 PU4401.3
VCC_SVID_DATA_R: length 5.6
  BOTTOM w0.102: R79794.2 79.41,211.14 R1653.1 v4(78.52,209.14) 78.52,208.79 79.76,207.54 79.76,206.74 PR5232.2
VCCCFIOAZA_1P80: length 10
  TOP w0.254: CPU2.AH4 v1(83.95,153.47) 83.64,153.81 83.47,153.98 83.47,154 CPU2.AF4
  BOTTOM w0.254: v1(83.95,153.47) 84.06,153.37 84.06,151.46 v4(83.88,151.28) 83.88,150.82 83.63,150.57 83.63,149.63 84.41,148.84 C1656.1 84.5,147.6 R1249.2 R1248.2
VCCCLKDDR_1P24_1P35: length 7.1
  TOP w0.254: CPU2.AM25 86.54,164.24 v1(86.92,164.62)
  BOTTOM w0.381: v1(86.92,164.62) 87.01,164.62 87.39,165.01 C1634.1 87.9,165 88.14,164.76 89.21,164.76 v4(89.84,164.13) 90.74,163.22 C6722.1 91.96,162.18 R1244.2
VCCFHVCPU0SI0_1P15: length 32.2
  TOP w0.254: CPU2.AJ35 v1(85.35,168.41) CPU2.AK33
  L4 w0.254: v1(85.35,168.41) 85.12,168.64 85.12,170.05 84.46,170.71 84.46,175.23 84.28,175.41 84.28,177.24
  L4 w0.508: 84.28,177.24 84.28,189.51 88.78,194.01 v6(88.78,197.23)
  vias: v3(89.87,196.7)
VCCPADCF1SI0_1P8_3P3: length 8.8
  TOP w0.254: C1655.1 71.04,146.85 71.08,146.89 71.13,146.89 71.91,147.68 72.47,147.68 v3(73.07,148.28) 73.85,149.05 73.85,150.63 74.28,151.06 74.28,152.01 74.32,152.06 CPU2.G1
  TOP w0.381: R1247.2 71.04,145.41 C1655.1
VCCPADCF1SI0_1P80: length 30.8
  TOP w0.254: v1(94.24,151.2) 94.5,151.2 96.41,149.29 C1652.1 96.41,148.01 96.59,147.83 v3(96.59,147.34) 96.57,147.36 95.92,147.36 95.87,147.41 R1251.2 ; CPU2.AF33 83.37,168.03 v1(83,167.65) 82.61,168.03 CPU2.AD33 ; CPU2.AK19 85.76,161.21 v1(86.14,160.83) CPU2.AK18
  L4 w0.254: v1(94.24,151.2) 94.24,151.54 92,153.79 91.36,153.79 86.54,158.6 86.54,160.43 v1(86.14,160.83) 86.04,160.93 86.04,162.41 84.28,164.16 84.28,165.63 83.12,166.8 83.12,167.54 v1(83,167.65)
  BOTTOM w0.254: v1(83,167.65) 83.19,167.84 C1651.1
VCCPADCF2SI0_E_1P80: length 13.4
  TOP w0.203: CPU2.Y18 80.25,160.23 80.64,159.85 80.64,159.4 80.19,158.96 80.19,157.84 v1(80.06,157.71)
  BOTTOM w0.254: v1(80.06,157.71) 80.04,157.69 79.23,157.69 C1648.1 79.11,157.62 79.11,154.46 79.4,154.17 v4(79.4,154.02) 79.4,153.43 79.53,153.3 79.53,151.59 79.52,151.58 C1649.1
  BOTTOM w0.508: R1250.2 79.53,149.15 C1650.1 79.53,150.82 C1649.1
VCCPADCF3SI0_1P8_3P3: length 11
  TOP w0.254: CPU2.E1 72.83,151.9 72.45,151.52 72.45,150.95 72.74,150.66 72.74,149.39 72.37,149.01
  TOP w0.305: CPU2.E2 72.83,152.65 CPU2.E1
  TOP w0.508: 72.37,149.01 71.32,147.96 v3(70.79,147.96) 69.88,147.05 C1653.1 C1654.1 69.88,145.04 R80148.2 69.74,144.9 R1246.2
VCCRAM0CPU0SI1_1P15: length 5.3
  L4 w0.127: 86.09,176.96 86.42,176.63 86.42,171.75
  vias: v1(85.35,166.13) v1(86.14,169.93) v3(86.27,202.29) v3(86.75,190.63) v4(86.81,171.14) v6(86.15,188.43)
VCCRTC_3P3:
  vias: v1(72.24,154.93) v4(72.79,154.18)
VCCRTCSUS_3P3: length 5
  TOP w0.254: CPU2.E3 73.38,153.32 v1(72.9,153.32) 72.84,153.38 CPU2.D4
  BOTTOM w0.508: v1(72.9,153.32) 72.93,153.29 72.93,152.39 C1662.1 72.96,152.18 72.11,151.32 72.11,151 R1254.1 72.65,150.46 v4(73.12,150.46)
VCCSFRPLLDDR_1P24_1P35: length 10.7
  TOP w0.254: v1(86.92,165.38) CPU2.AN27
  BOTTOM w0.381: v1(86.92,165.38) 87.19,165.65 88.13,165.65 88.43,165.35 90.3,165.35 C1633.1 90.43,165.1 90.81,164.72 90.81,164.72 90.9,164.63 91.69,164.63 92.3,164.02 v4(93.51,164.02) 93.94,164.45 C6721.1 94.44,165.58 R1245.2
VCCSRAMGEN_1P15: length 48.3
  TOP w0.254: v1(86.93,161.59) 86.55,161.21 CPU2.AM19 85.77,161.97 CPU2.AK21
  L4 w0.254: v1(86.93,161.59) 86.93,161.67 86.39,162.21 86.39,162.59 84.64,164.34 84.64,165.81 83.62,166.83 83.62,169.77 82.99,170.4 82.99,177.29 82.29,177.99 82.29,179.35
  L4 w0.508: 82.29,179.35 82.06,179.58 82.06,194.8 v6(87.54,200.28)
  BOTTOM w0.381: C632.1 89.76,161.85 89,161.08 C633.1 88.47,161.47 87.05,161.47 v1(86.93,161.59)
  vias: v3(87.5,199.13)
VCCUSB2_1P8: length 15.3
  TOP w0.254: CPU2.AA29 81.04,165.76 v1(80.65,166.14)
  BOTTOM w0.254: v1(80.65,166.14) 80.6,166.14 79.35,167.39 79.35,168.97 78.6,169.72 78.6,170.12 78.91,170.42 78.91,175.27 78.66,175.51 C1658.1
  BOTTOM w0.508: C1658.1 C1657.1 78.66,177.52 v4(78.15,178.03) 78.15,178.95 R1252.2
VCCUSB2_3P3: length 8.8
  TOP w0.254: CPU2.C23 71.92,163.04 71.92,162.91 CPU2.B22 70.95,162.57
  TOP w0.508: 70.95,162.57 70.82,162.45 68.87,162.45 67.19,160.77 v3(67.19,159.97) 67.11,159.89 66.21,159.89 C1659.1 65.73,159.85 65.35,159.85 R1256.1
VDDC_CT: length 9.4
  BOTTOM w0.254: v1(86.98,103) 87.08,102.89 C779.1 C781.1 88.57,102.96 87.52,104 C780.1 87.18,104.08 87.18,105.12 87,105.3 87,105.87 87.21,106.07 87.21,107.01 87.13,107.08 v4(87.13,107.13) 87.13,109.53 L48.2
0D95V_VGA_S0: length 72.6
  TOP w0.508: L51.1 v2(73.34,80.65)
  L4 w0.508: v1(101.46,93.78) 100.01,92.33 91.54,92.33 88.48,89.27 88.48,85.53 81.63,78.69 74.75,78.69 73.34,80.1 v2(73.34,80.65)
  BOTTOM w0.508: v2(73.34,80.65) v4(72.58,80.65) ; v1(97.19,116.28) 97.19,115.61 98.71,114.09 98.71,112.78 104.17,107.31 104.17,96.49 v4(103.13,95.45) v1(101.46,93.78)
  BOTTOM w1.016: L53.1 94.13,110.85 92.03,112.95 v4(92.03,112.98) 92.01,112.98 v6(90.63,114.35)
  vias: v1(79.35,107.07) v1(80.47,105.64) v1(80.51,104.96) v1(81.07,104.07) v1(82.98,103.81) v1(83.79,103.92) v1(85.02,113.64) v1(85.02,112.93) v3(102.57,113.97) v6(101.61,116.33) v6(102.57,116.31) v6(102.67,115.29) v6(103.54,116.31) v6(103.67,115.32) v6(103.67,114.22)
0P95V_A: length 28.3
  TOP w0.381: v1(137.17,114.2) 136.86,114.5 PC4705.1 136.88,114.96 PR4717.1
  TOP w0.635: PTC4701.1 114.13,116.45 ; PTC4701.1 114.13,114.34 ; PTC4701.1 113.08,115.39 ; PTC4701.1 115.18,115.39
  BOTTOM w0.381: v1(116.85,113.44) v4(118.17,114.76) 119.41,116 135.36,116 v4(136.02,115.34) v1(137.17,114.2)
  vias: v3(108.59,112.93)
1D5V_S0: length 206.2
  L3 w0.635: v2(106.99,145.73) 105.45,145.73 104.81,146.38 89.54,146.38 v2(89.47,146.46)
  L4 w0.381: v2(150.96,43.18) 151.53,43.75 151.53,46.88 150.85,47.56 150.85,59.63 153.82,62.6 153.82,63.66 162.59,72.43 v1(162.59,73.86)
  L4 w0.508: v2(171,134.67) 172.91,132.77 172.91,129.69 167.83,124.61 167.83,93.04 166.97,92.19 166.97,91.03 163.4,87.46 163.4,85.74 161.75,84.1 161.75,76.52 162.59,75.68 v1(162.59,74.73) v1(162.59,73.86)
  BOTTOM w0.508: R1248.1 89.39,146.38 v2(89.47,146.46) ; v2(171,134.67) 170.77,134.9 v4(167.65,134.9) 165.91,134.9 163.13,132.13 159.98,132.13 154.45,126.59 148.49,126.59 146.03,129.05 146.03,129.72 143.64,132.11 143.64,134.23 141.1,136.78 139.1,136.78 138.87,136.55 135.99,136.55 135.54,136.99 130.58,136.99 124.16,143.41 109.61,143.41 v4(107.86,145.16) 107.86,145.2 107.32,145.73 v2(106.99,145.73) ; R205.1 154.04,46.99 153.13,46.07 152.62,46.07 151.35,44.81 v4(151.19,44.81) 151.19,44.74 151.01,44.57 151.01,43.23 v2(150.96,43.18)
  vias: v4(163.51,72.75)
1D8V_CARD: length 6.1
  TOP w0.508: Q9634.S 77.78,127.54 78.03,127.8 v3(78.03,127.82) 78.03,127.85 77.62,128.27 R80151.1 78.53,129.02 79.45,128.1 Q9640.D
1D8V_S0: length 700.9
  TOP w0.254: v2(141.87,199.39) 141.87,199.49 142.45,200.07 XDP1.44
  TOP w0.305: v2(171.69,136.86) 168.69,133.86 164.51,133.86 R1696.2 ; R79688.2 88.21,139.05 88.86,138.4 88.94,138.4 C523.1 88.78,137.99 88.78,137.26 U35.1
  TOP w0.381: v2(90.85,36.42) 90.85,36.7 R79765.2 92.02,36.93 R79764.1
  TOP w0.508: R79690.1 83.95,132.38 R645.1 85.85,131.58 87.96,131.58 90.19,133.82 90.19,137.71 89.62,138.28 C523.1 ; v1(51.93,139.85) 53.33,138.45 R79799.2 R79798.1 53.77,139.75 54.2,140.17 58.45,140.17 60.62,138 60.62,136.23 62.75,134.11 v1(62.75,132.21) ; v2(137.07,205.81) 137.07,204.93 136.56,204.42 R1266.1
  TOP w0.635: v1(82.99,126.72) 83.95,127.68 R79690.1 ; R514.2 143.03,7.64 143.04,7.65 v2(143.24,7.65)
  L3 w0.508: v1(23.55,28.6) 23.71,28.75 23.78,28.75 24.26,29.24 29.47,29.24 30.33,28.37 33.27,28.37 34.73,29.84 34.73,30.67 41.06,37.01 49.39,37.01 52.56,40.18 53.88,40.18 53.93,40.13 61.42,40.13 62.85,41.55 v2(69.63,41.55)
  L3 w0.635: v2(90.85,36.42) 90.85,30.71 98.58,22.99 119.35,22.99 122.66,19.68 128.92,19.68 129.3,19.3 v2(129.55,19.3) ; v1(119.57,5.11) 119.83,4.84 142.25,4.84 143.24,5.83 v2(143.24,7.65) ; v2(141.87,199.39) 142.3,199.82 142.3,203.42 143.81,204.93 143.81,205.58 143.4,205.99 143.37,206.02 143.32,206.06 140.84,206.06 139.19,204.41 138.32,204.41 137.07,205.65 v2(137.07,205.81) 137.07,206.04 135.63,207.48 v2(135.63,220.09) ; v2(171.69,136.86) 172.51,136.03 172.51,129.14 170.09,126.72 170.09,121.69 167.23,118.83 167.23,102.35 169.78,99.8 169.78,90.7 171.71,88.78 171.71,85.71 164.94,78.95 164.94,71.59 152.22,58.86 152.22,47.54 152.8,46.95 152.8,42.93 151.55,41.68 151.04,41.68 147.94,38.57 147.94,34.04 v2(148.01,33.96)
  L4 w0.508: v2(137.07,205.81) 137.04,205.84 127.79,205.84 126.57,207.07 119.08,207.07 118.9,207.25 101.18,207.25 98.78,204.85 82.87,204.85 82.41,204.4 76.13,204.4 67.5,195.76 67.5,194.66 64.98,192.15 60.66,192.15 58.73,190.22 57.15,190.22 56.07,189.13 56.07,182.64 54.23,180.8 51.73,180.8 43.49,172.56 43.49,164.09 v2(43.72,163.86) ; v2(90.85,36.42) 88.49,38.79 75.14,38.79 72.37,41.55 v2(69.63,41.55)
  L4 w0.635: v2(171.69,136.86) 171.69,147.93 169.41,150.2 169.41,159.73 167.35,161.79 167.35,190.8 164.54,193.61 164.54,207.6 162.09,210.06 160.76,210.06 v6(148.85,221.97) 136.72,221.97 135.63,220.88 v2(135.63,220.09) ; v2(148.01,33.96) 147.71,33.66 147.71,32.73 137.15,22.17 131.58,22.17 129.55,20.14 v2(129.55,19.3) 129.55,18.01 131.49,16.07 131.49,11.65 128.58,8.74 121.35,8.74 119.77,7.16 119.77,5.31 v1(119.57,5.11)
  BOTTOM w0.508: C28.2 142.72,200.24 v2(141.87,199.39) ; v2(43.72,163.86) v4(43.72,161.87) 43.72,160.4 47.28,156.84 47.28,142.54 48.44,141.38 51.14,141.38 51.93,140.59 v1(51.93,139.85) ; R680.1 24.07,27.08 R389.2 23.63,27.52 23.63,28.52 v1(23.55,28.6) 23.71,28.75 23.78,28.75 24.31,29.29 24.92,29.29 R693.2
  BOTTOM w0.635: v1(82.99,126.72) 80.93,126.72 v4(76.59,131.06) 74.06,133.59 69.79,133.59 69.21,134.18 66.25,134.18 64.76,132.69 63.23,132.69 v1(62.75,132.21) ; v2(135.63,220.09) v4(135.63,220.9)
  vias: v3(149.81,222.31)
1D8V_S0_EN: length 7.2
  TOP w0.254: R1683.1 153.02,213.74 C100.1 153.64,212.63 v3(155.35,210.92) 153.97,209.55 Q23.2
1D8V_S0_EN1: length 8.9
  TOP w0.254: v3(155.48,207.06) 155.09,207.45 R151.1 152.34,208.15 151.16,208.15 151.03,208.29 Q23.6 151.61,208.9 151.72,209.01 151.72,209.37 151.54,209.55 Q23.5 150.27,209.55 150.21,209.62 R153.2
1D8V_S0_EN2: length 5.7
  TOP w0.254: R164.1 150.4,213.03 R162.1 ; R162.1 150.96,211.44 v3(151.33,211.44) 152.57,210.2 Q23.3 ; R162.1 150.4,211.71 R163.2
1D8V_S0_EN_G: length 10.5
  TOP w0.254: R164.2 149.13,213.41 149.13,216.02 v3(151.11,218) 150.2,218.91 C96.1 C97.1 148.7,219.02 Q6705.G
1D8V_S0_EN_R: length 10.9
  TOP w0.102: v1(159.25,210.01) 159.25,209.51 158.53,208.79 v3(158.18,208.79) 156.24,210.73 156.24,211.71 153.31,214.64 R1683.2
  BOTTOM w0.102: PR5.2 v1(159.25,210.01)
1D8V_S5: length 1119
  TOP w0.254: R505.2 38.01,20.9 37.22,21.69 33.72,21.69 33.49,21.92 32.63,21.92 32.6,21.95 32.42,21.95 32.21,22.15 31.42,22.15 30.92,21.65 30.92,20.73 30.9,20.63 30.89,20.63 30.89,20.38 30.87,20.26 30.42,19.81 29.64,19.81 28.35,18.53 28.35,18.16 27.77,17.58
  TOP w0.305: v1(42.17,26.42) 42.89,25.7 42.89,22.63 41.57,21.31 41.55,21.31 R505.2 ; R49.2 98.87,127.01 98.87,125.88 v2(98.71,125.73) ; XDP1.43 147.87,200.07 146.87,201.07 v2(146.87,201.07) ; R1251.1 93.77,148.2 R1780.1 94.29,148.82 93.11,148.82 R556.1 92.39,148.73 92.39,148.81 92.22,148.97 91.43,148.97 91.38,148.92 90.82,148.92 90.38,148.48 90.38,148.32 90.21,148.15 ; R79659.2 164.3,129.06 v2(165.77,129.06) ; v2(93.33,127.97) 92.94,128.36 92.94,129.58 R1582.2 ; R63.2 103.26,121.69 v1(102.01,120.45) ; R1782.1 104.54,221.15 102.84,221.15 102.12,220.43 ; 90.21,148.15 90.21,148.26 89.99,148.48 89.99,150.23 v1(90.03,150.27) ; 90.21,148.15 v1(90.21,148.15) ; R56.2 R55.1 106.07,69.81 106.51,69.37 106.51,69.19 108.24,67.46 108.24,65.95 109.8,64.39 109.87,64.39 110.62,63.63 v2(110.62,63.09) ; R79737.1 R79736.1 ; 102.12,220.43 101.94,220.61 101.94,221.91 104.12,224.09 R1843.2 ; 102.12,220.43 v2(102.05,220.37) ; R1910.2 77.8,187.6 R1226.1 77.8,185.47 R498.2 ; R1832.2 165.34,131.04 v2(165.36,131.06) ; R1262.1 v1(66.21,147.52)
  TOP w0.381: R1208.1 R642.1 89.5,144.13 90.28,143.36 90.28,141.88 88.65,140.25 88.58,140.25 R499.1 R1795.2 85.82,140.2 85.06,140.96 R567.1 84.21,140.25 R1797.2 R558.1 82.99,139.9 82.25,139.17 82.01,139.17 R1798.2 R1799.2 R1800.2 ; R1570.1 R1562.1 104.27,198.34 R1809.1 111.35,198.31 112.38,199.34 v2(112.38,200.74) ; v1(13.11,222.63) 12.82,222.92 R720.1 ; R80145.2 65.72,140.72 R80120.2 64.3,140.44 63.78,140.44 v1(63.49,140.15) ; R1830.1 18.53,166.91 v2(17.75,167.69) ; R473.1 137.6,204.47 137.93,204.8 137.93,205.97 v6(138.39,206.43) 138.39,206.26 139.63,205.01 R457.1 ; R43.1 160.75,183.89 161.4,183.24 U2.5 161.43,182.43 162.04,182.43 162.89,183.27 C27.2 163.33,183.22 163.33,179.95 R1746.1 162.4,178.73 161.63,177.95 156.57,177.95 v2(156.55,177.93) ; R79736.1 134.53,28.8 134.53,27.81 133.19,26.48 v3(127.77,26.48) 125.78,26.48 v1(125.74,26.44) ; v2(60.92,141.68) 60.82,141.78 60.82,142.96 64.47,146.61 65.3,146.61 v1(66.21,147.52) ; v2(63.91,147.19) 63.6,147.19 63.22,147.57 R492.2 ; v2(84.23,207.29) 83.19,207.29 80.17,204.27 80.17,199.65 74.28,193.77 74.28,190.9 77.58,187.61 R1910.2
  TOP w0.508: R563.1 83.59,143.12 v2(84.03,142.67) 84.54,142.16 R1796.2 85.06,141.99 R567.1 ; R458.1 138.5,206.54 v6(138.39,206.43) ; R1560.1 156.05,185.67 155.29,186.44 154.78,186.44 153.87,187.35 v2(148.88,187.35) ; R80220.2 41.44,115.01 41.74,115.32 41.74,115.66 v1(41.81,115.72) ; v2(53.45,175.64) 53.5,175.59 60.74,175.59 61.49,174.84 R1845.1 ; R80151.2 79.14,130.54 Q9640.S 79.34,130.29 80.26,129.37 80.88,129.37 81.63,128.63 82.16,128.09 82.16,126.38 82.89,125.65 82.89,120.79 ; R709.2 95.16,30.3 v2(95.63,30.77) ; v2(87.8,32.64) 87.8,43.03 88.91,44.15 95.46,44.15 96.78,45.47 100.76,45.47 v2(102.27,46.98) ; R1593.1 40.74,138.29 43.47,138.29 44.34,137.41 44.34,133.58 ; R392.1 110.7,63.02 v2(110.62,63.09) ; 44.34,133.58 44.34,132.85 44.28,132.79 44.28,127.69 44.86,127.1 v1(44.86,126.82) ; 44.34,133.58 45.5,134.73 51.2,134.73 54.01,137.54 v2(56.42,137.54) ; v2(162.8,159.21) 162.67,159.33 v3(162.67,163.02) 162.67,164.36 157.77,169.27 v2(156.66,169.27) ; v2(157.34,174.29) 157.28,174.35 R89.2 ; 27.77,17.58 27.39,17.58 26.46,16.65 R59.2 R58.2
  TOP w1.016: v6(136.71,217.32) 139.43,220.04 Q6705.D
  L3 w0.508: v6(59.61,134.32) 62.09,134.32 63.81,136.04 64.09,136.04 66.91,138.86 83.45,138.86 84.01,139.42 ; v1(71.12,77.09) 79.59,77.09 82.66,80.16 98.03,80.16 v1(98.92,79.27) ; v2(102.05,220.37) 102.05,217.11 106.51,212.65 106.51,209.42 107.22,208.71 112.96,208.71 v2(113.39,208.29) 112.68,207.58 112.68,201.04 v2(112.38,200.74) ; 84.01,139.42 84.01,142.34 84.03,142.37 v2(84.03,142.67) 84.03,143.28 84.71,143.96 84.71,145.08 85.61,145.97 87.94,145.97 90.12,148.15 v1(90.21,148.15) ; 84.01,139.42 85.12,138.3 85.12,138.28 86.77,136.63 86.77,134.52 v2(93.33,127.97) ; v2(157.34,174.29) 157.13,174.5 157.13,177.34 v2(156.55,177.93) 156.43,178.04 156.43,191.42 155.99,191.86 155.99,201.31 155.79,201.51 155.79,202.97 153.14,205.61 149.77,205.61 v6(149.26,206.12) 148.37,205.23 148.37,202.57 v2(146.87,201.07) 146.87,200.99 147.57,200.29 147.57,194.82 v2(146.74,194) 146.74,193.95 147.48,193.22 147.48,191.77 147.04,191.33 v2(146.57,191.33) 148.37,189.53 148.37,188.37 148.88,187.86 v2(148.88,187.35) ; v1(125.74,26.44) 123.4,26.44 121.27,24.31 99.85,24.31 95.63,28.53 v2(95.63,30.77) ; v2(63.91,147.19) 64.04,147.32 66.01,147.32 v1(66.21,147.52) ; v1(44.86,126.82) 43.82,126.82 39.28,122.28 39.28,120.86 40.86,119.28 40.86,116.67 v1(41.81,115.72) ; v2(70.16,33.86) 69.45,34.57 52.31,34.57 51.01,33.27 44.84,33.27 42.08,30.52 42.08,26.51 v1(42.17,26.42)
  L3 w0.635: v1(13.11,222.63) 13.93,221.82 13.93,219.05 17.37,215.61 17.37,208.43 21.56,204.24 21.56,202.46 21.05,201.95 21.05,199.71 22.93,197.83 22.93,196.46 27.19,192.2 28.02,192.2 30.61,189.61 33.74,189.61
  L3 w1.016: v6(136.71,217.32) 136.76,217.27 136.76,208.41 138.39,206.78 v6(138.39,206.43)
  L4 w0.381: v2(162.8,159.21) 163.48,158.52 163.48,147.62 166.45,144.65 166.45,136.09 165.34,134.98 165.34,131.09 v2(165.36,131.06) 165.34,131.04 165.34,129.49 v2(165.77,129.06) ; v2(84.03,142.67) 83.98,142.72 83.52,142.72 80.73,145.52 80.73,146.73 80.35,147.1 79.01,147.1 78.54,146.63 v1(77.86,146.63)
  L4 w0.508: v2(70.16,33.86) 70.17,33.85 76.06,33.85 77.73,32.18 81.82,32.18 82.28,32.64 v2(87.8,32.64) 88.49,33.33 94.55,33.33 95.63,32.26 v2(95.63,30.77) ; v6(136.71,217.32) 131.63,217.32 129.42,219.53 v2(128.76,219.53) ; v2(156.66,169.27) 157.49,170.09 157.49,174.14 v2(157.34,174.29) ; v2(102.27,46.98) 102.27,47.65 95.19,54.73 95.19,62.94 83.39,74.74 73.48,74.74 71.14,77.09 v1(71.12,77.09) ; v1(98.92,79.27) 98.92,78.56 97.54,77.19 97.54,71.33 100.83,68.05 103.34,68.05 106.55,64.83 108.85,64.83 109.24,64.44 109.96,64.44 110.62,63.77 v2(110.62,63.09)
  L4 w0.635: v6(35.31,186.56) 35.31,183.11 31.24,179.04 v2(25.03,179.04) 25.03,175.16 25.05,175.13 25.05,173.4 19.34,167.69 v2(17.75,167.69) ; v6(138.39,206.43) 138.76,206.06 142.55,206.06 142.6,206.01 143.38,206.01 143.4,205.99 143.48,205.91 143.52,205.91 143.55,205.9 143.59,205.87 143.68,205.83 143.75,205.81 143.8,205.8 143.84,205.79 143.89,205.78 143.95,205.77 144.05,205.76 144.11,205.76 144.16,205.76 144.21,205.77 144.26,205.77 144.31,205.78 144.37,205.79 144.46,205.82 144.51,205.84 144.56,205.86 144.61,205.89 144.66,205.91 149.05,205.91 v6(149.26,206.12)
  L4 w1.016: v6(138.39,206.43) 137.93,206.88 128.19,206.88 126.99,208.09 119.5,208.09 119.3,208.29 v2(113.39,208.29) 99.59,208.29 98.82,207.51 98.82,207.5 98.18,206.86 84.67,206.86 v2(84.23,207.29) 83.87,207.29 81.99,205.41 75.02,205.41 65.49,195.88 62.44,195.88 59.75,193.19 57.23,193.19 55.02,190.99 55.02,183.03 54.41,182.42 ; 54.41,182.42 54.41,182.73 51.09,186.06 38.51,186.06 36.86,187.71 v6(36.48,187.71) ; 54.41,182.42 v6(54.39,182.4)
  BOTTOM w0.305: R1794.2 85.29,149.57 85.29,149.4 85.82,148.87 R1793.2 85.86,148.72 R1249.1 ; R1739.1 149.37,187.96 148.88,187.46 v2(148.88,187.35) ; R1790.1 41.54,185.24 39.3,187.48 36.71,187.48 v6(36.48,187.71) ; 89.43,147.31 89.83,147.31 90.16,146.98 90.16,146.29 89.42,145.54 84.68,145.54 R554.1 ; v2(146.57,191.33) 146.84,191.33 146.9,191.4 148.69,191.4 149.04,191.05 R1738.1 ; R510.2 v1(90.03,150.27)
  BOTTOM w0.381: v2(146.74,194) 146.77,194.02 Q1203.G ; R72.1 25.31,178.76 v2(25.03,179.04) ; R530.2 77.04,149.49 77.04,147.44 77.78,146.7 77.8,146.7 v1(77.86,146.63) 77.88,146.66 78.56,146.66 R1250.1 ; v2(146.57,191.33) 146.64,191.26 146.64,191.26 146.93,190.97 Q1204.G ; R502.1 43.61,23.88 43.61,25.39 v4(43.54,25.45) 42.58,26.42 v1(42.17,26.42) ; R1561.1 92.69,200.95 R1815.1 R1813.1 96.2,200.93 R1812.1 98.25,200.9 R1810.1 99.98,200.88 R1805.1 101.86,200.85 R1804.1 R1818.1 104.54,200.83 105.35,201.64 107.42,201.64 R1817.1 R1819.1 109.52,200.85 110.12,201.45 111.67,201.45 v2(112.38,200.74) ; v1(90.21,148.15) 90.34,148.28 90.34,148.61 R561.1
  BOTTOM w0.508: R1742.1 128.54,218 Q1210.G 128.47,219.25 v2(128.76,219.53) ; C26.2 148.2,200.87 147.91,201.17 146.97,201.17 v2(146.87,201.07) ; v2(93.33,127.97) 93.73,128.37 96.42,128.37 97.39,127.4 97.39,127.05 v2(98.71,125.73) v4(99.77,124.67) 101.96,122.48 101.96,120.5 v1(102.01,120.45) 103.8,118.66 104.94,118.66 106.12,117.47 109.96,117.47 111.82,115.61 111.82,115.59 111.83,115.58 111.83,113.95 112.8,112.98 v4(112.8,86.78) 112.8,81.16 111.27,79.64 109.48,79.64 109.19,79.35 108.66,79.35 108.29,79.72 108.29,79.95 107.92,80.31 104.66,80.31 103.22,78.88 99.46,78.88 99.07,79.27 v1(98.92,79.27) ; v2(84.23,207.29) 84.23,207.56 83.52,208.27 83.52,208.74 R79786.1 ; R1252.1 76.49,180.61 76.49,181.99 76.4,182.17 75.3,183.26 v4(73.85,183.26) 55.25,183.26 v6(54.39,182.4) 53.45,181.46 v2(53.45,175.64) ; R1249.1 87.29,147.28 R1792.2 89.24,147.28 89.26,147.31 89.43,147.31 89.77,147.65 89.83,147.65 90.21,148.03 v1(90.21,148.15) ; R530.2 76.94,150.06 75.86,150.06 R1253.1
  vias: v2(56.29,129.29) v2(57.24,130.44) v2(57.24,129.3) v2(57.24,128.28) v2(58.2,129.29) v3(37.22,183.62) v4(34.07,186.54) v4(46.64,167.49) v4(60.1,135.56) v6(35.14,191.13) v6(35.19,190.07) v6(35.21,188.85) v6(35.21,187.71) v6(36.48,190.04) v6(36.48,188.85) v6(36.48,186.44) v6(47.58,167.73) v6(47.58,166.76) v6(48.52,168.26) v6(48.5,167.26) v6(48.5,166.32) v6(56.52,131.75) v6(57.54,131.75)
1D8V_S5_D: length 3.3
  BOTTOM w0.254: R1790.2 41.54,183.01 v4(41.08,182.55) 40.19,182.55 39.68,183.05 Q1231.6
1D8V_SPI: length 29.9
  TOP w0.254: SRCON1.8 37.73,123.78 40.04,126.09 40.04,128.01 R186.1 41.1,129.08 41.16,129.08 41.57,129.49 C116.2 41.57,130.55 39.95,132.17 R1593.2 39.54,136.2 39.09,136.2 37.62,137.67 v2(37.31,137.67) 37.21,137.67 36.64,137.09 R172.1 ; R169.1 32.21,137.53 32.98,138.3 36.15,138.3 v1(36.23,138.23)
  BOTTOM w0.254: v4(36.25,139.15) 36.25,138.25 v1(36.23,138.23) 36.79,137.67 v2(37.31,137.67)
1D8V_VGA_AVDD: length 1.4
  TOP w0.127: GPU1.AG24 91.4,106.29 91.02,106.67 v1(91.02,107.2)
  vias: v4(90.91,109.35)
1D8V_VGA_S0: length 75.9
  TOP w0.508: R935.1 99.49,100.95 98.86,101.57 v1(98.66,101.57) 98.66,101.3 98.65,101.28 R1900.2 ; v2(74.58,80.65) 74.61,80.67 L49.1
  L3 w0.508: v1(91.96,95.3) 91.96,94.99 91.18,94.21 87.87,94.21 87.26,93.6 85.45,93.6 v1(85.4,93.55)
  L4 w0.508: v1(91.96,95.3) 91.98,95.33 91.98,95.38 92.54,95.94 92.54,100.24 94.15,101.85 98.38,101.85 v1(98.66,101.57) ; v2(74.58,80.65) 74.58,80.65 75.59,79.64 80.78,79.64 87.18,86.04 87.18,88.93 86.19,89.92 86.19,92.81 85.45,93.55 v1(85.4,93.55)
  BOTTOM w0.381: L52.1 92.49,96.55 92.49,96.93 91.21,98.21 L47.1
  BOTTOM w0.508: v1(85.4,93.55) 85.97,94.12 L4102.2 ; v2(74.58,80.65) 74.62,80.65 v4(75.35,81.38) 75.35,82.18 77.05,83.87 77.05,84.67 79.23,86.86 79.29,86.86 79.88,87.44 L50.1 ; R1211.2 91.91,95.26 v1(91.96,95.3) 92.01,95.3 92.03,95.33 93.24,95.33 L52.1 ; v2(95.11,110.34) 95.11,109.25 95.61,108.74 95.61,103.57 R943.2 95.79,102.05 R79963.2 97.83,101.98 v4(97.85,101.96) 98.23,101.57 v1(98.66,101.57)
  vias: v3(85.68,115.57) v4(88.86,112.62) v6(83.9,114.83) v6(87.92,113.26) v6(95.49,114.86) v6(96.45,114.86)
1D8V_VGA_VDD1DI: length 0.6
  TOP w0.127: v1(90.2,105.6) GPU1.AE23
  vias: v4(88.4,107.47)
1D8V_VGA_VDDR4:
  vias: v1(84.01,96.22) v1(84.95,96.19)
1D24V_S5: length 9.2
  TOP w0.254: v1(75.22,173.74) 75.09,173.61 75.09,173.57 CPU2.H44 ; v1(79.86,165.38) 80.24,165 CPU2.Y27 CPU2.Y25 ; v1(79.07,166.13) 79.45,166.52 CPU2.V30 ; CPU2.AC30 v1(81.43,166.14)
  L4 w0.203: v1(81.43,169.94) 81.43,168.54 81.07,168.17 81.07,167.11 81.43,166.75 v1(81.43,166.14)
  BOTTOM w0.508: v2(51.81,177.39) 51.59,177.62 51.59,178.56 R1787.1
  vias: v1(77.22,172.29) v1(78.16,171.55) v1(78.16,170.84) v1(78.17,168.98) v3(53.04,177.22) v4(56.09,176.48) v4(70.16,176.53) v4(78.44,168.12) v6(54.41,176.73) v6(55.18,177.55)
1D24V_S5_D: length 3.5
  BOTTOM w0.305: R1787.2 50.13,177.97 v4(50.12,177.95) 49.79,177.95 48.63,179.12 Q1230.6
1D35V_S3_PWRGD: length 5.4
  TOP w0.203: v2(153.6,131.93) 153.2,132.33 PU5001.10
  BOTTOM w0.254: PR5010.2 154.48,131.39 154.69,131.61 v4(154.69,131.64) 154.4,131.93 v2(153.6,131.93) 152.7,131.93 R1891.2
1D35V_S3_PWRGD_R: length 11.9
  TOP w0.102: C4230.2 148.13,129.27 v2(148.46,129.6)
  BOTTOM w0.102: R1891.1 150.95,132.08 149.82,132.08 149.26,132.64 147.51,132.64 Q1240.S 146.72,131.5 147.86,130.36 v4(147.86,130.36) 147.86,130.36 148.46,129.75 v2(148.46,129.6) 148.46,129.57 148.7,129.34 Q48.2
1D35V_VGA_S0: length 171
  TOP w0.203: v1(51.88,112.27) 51.91,112.27 52.1,112.47 52.24,112.47 52.25,112.47 52.58,112.47 52.59,112.47 52.82,112.47 53.2,112.08 MEM1.H2 ; v1(58.41,111.68) 58.41,111.68 58.41,111.12 58.07,110.78 58.07,110.54 MEM1.K8 57.62,110.09 57.62,108.72 57.86,108.47 58.2,108.47 58.52,108.15 58.75,108.15 MEM1.N9 ; v1(51.99,114.9) 52.83,114.9 MEM1.D2 ; v1(58.42,96.39) 58.42,95.84 58.81,95.45 MEM2.N1 ; 61.78,111.61 60.89,111.61 60.69,111.41 59.49,111.41 MEM1.H9 ; MEM2.H2 58.28,91.48 58.41,91.61 58.41,92.43 MEM2.K2
  TOP w0.305: MEM2.A1 MEM2.B2 58.01,86.42 57.61,86.02 v1(57.61,86.01) ; MEM2.H2 58.01,91.21 v1(57.61,90.81) ; v1(54.51,90.76) 54.33,90.76 54.01,90.44 MEM2.G7 ; GPU1.L11 78.6,95.81 78.3,96.11 v1(78.3,96.12) 78.3,96.13 78.31,96.14 78.31,96.16 78.6,96.46 GPU1.L12 GPU1.L13 ; v1(51.6,87.31) 51.69,87.22 MEM2.C9 ; v1(52.82,87.62) 52.41,88.02 MEM2.D9 MEM2.E9 51.9,89.33 51.6,89.33 v1(51.27,89.66) ; MEM2.A8 53.21,85.39 52.6,84.77 v1(52.5,84.77) ; MEM2.H9 52.23,91.22 52.05,91.04 ; v1(57.61,93.22) 57.61,93.22 MEM2.K2 ; v1(57.63,88.43) 57.63,88.4 58,88.02 MEM2.D2 ; v1(52.81,92.42) 52.81,92.42 MEM2.K8 ; v2(60.16,88.55) 60.14,88.53 60.14,88.18 59.74,87.78 59.74,87.78 v1(59.36,87.4) 59.18,87.22 MEM2.C1 ; MEM2.N9 51.94,95.7 v1(51.75,95.7) ; v1(58.42,96.39) 58.81,96.78 MEM2.R1 ; MEM1.H9 58.81,112.08 v1(58.41,111.68) ; v1(59.59,113.45) 59.59,113.45 59.33,113.72 59.33,113.78 58.81,114.29 MEM1.E9 ; MEM1.B2 MEM1.C1 52.28,116.08 51.96,116.4 v1(51.95,116.4) ; v1(51.71,96.82) 51.71,96.82 MEM2.R9
  TOP w0.356: GPU1.K9 77.8,94.01 v1(77.4,94.41) ; v1(51.78,113.65) 51.81,113.68 MEM1.F1 ; GPU1.J23 77.01,105.2 v1(77.41,105.6) ; MEM1.C9 59.16,116.08 59.35,115.89 v1(60.06,115.89) ; MEM1.D9 58.81,115.28 v1(58.41,114.89) 58.81,114.49 MEM1.E9 ; v1(59.36,90.75) 59.36,90.16 MEM2.F1 ; v1(78.08,102.53) 78.12,102.53 78.25,102.4 GPU1.L20 ; v1(75.88,97.43) 75.93,97.38 75.93,97.31 76.2,97.04 GPU1.H13 ; v1(77.4,94.41) 77,94.01 GPU1.J9 ; v1(77.4,94.41) 77.01,94.8 GPU1.J10 ; v1(77.4,94.41) 77.79,94.8 GPU1.K10 ; MEM1.R1 52.12,106.77 51.91,106.77 51.89,106.79 v1(51.89,106.79) ; v1(77.41,105.6) 77.01,106 GPU1.J24 ; v1(77.41,105.6) 77.8,105.99 GPU1.K24 ; v1(77.41,105.6) 77.8,105.21 GPU1.K23 ; v1(58.45,110.08) 58.42,110.08 MEM1.K8 ; GPU1.H19 76.2,101.76 v1(76.58,101.38) ; MEM1.N1 52.35,108.08 52.21,108.23 51.62,108.23 v1(51.61,108.24) ; v1(50.89,90.93) 51.94,90.93 52.05,91.04 ; MEM1.K2 v1(53.61,110.08) ; MEM1.G7 57.07,112.88 56.82,113.12 56.82,113.22 56.81,113.23 v1(56.81,113.27) ; MEM1.N9 59.23,107.67 v1(59.32,107.67) 59.32,106.99 MEM1.R9 59.2,106.1 v1(59.22,106.1) ; GPU1.L21 78.32,103.4 78.18,103.55 v1(78.09,103.55) 78.09,103.79 78.6,104.3 GPU1.L22 ; GPU1.H16 75.87,99.73 v1(75.87,99.95) ; MEM1.A8 58.01,117.67 v1(57.62,117.28)
  TOP w0.508: v1(59.22,106.1) 60.48,106.1 60.9,106.52 60.9,107.56 61.78,108.44 61.78,112.76 61.79,112.77 61.79,113.23 61.32,113.7 59.89,113.7 59.64,113.45 v1(59.59,113.45)
  TOP w0.635: TC21.1 50.52,124.23 ; TC21.1 49.46,125.29 ; TC21.1 49.46,123.18 ; TC21.1 48.41,124.23
  L3 w0.508: v1(60.06,115.89) 60.01,115.84 59.36,115.84 58.67,115.15 58.67,115.15 v1(58.41,114.89) 58.23,115.07 58.23,116.67 v1(57.62,117.28) 57.95,117.61 58.93,117.61 59.39,118.06 59.39,118.22 59.4,118.23 v1(59.4,118.31) 66.5,118.31 67.14,118.31 v1(67.34,118.11)
  L3 w0.635: TC21.1 50.52,124.23 ; TC21.1 48.41,124.23 ; TC21.1 49.46,125.29 ; TC21.1 49.46,123.18
  L4 w0.305: v1(59.36,90.75) 58.81,91.31 58.11,91.31 v1(57.61,90.81)
  L4 w0.635: TC21.1 50.52,124.23 ; TC21.1 49.46,123.18 ; TC21.1 49.46,125.29
  BOTTOM w0.152: MEM4.E9 58.76,88.87 58.48,88.87 58.18,89.18 57.87,89.18 57.63,88.94 v1(57.63,88.43)
  BOTTOM w0.203: v1(56.81,113.27) 56.81,113.23 56.81,113.23 56.81,111.92 57.06,111.67 57.61,111.67 MEM3.H2 ; MEM3.H9 52.81,112.47 53.61,112.47 MEM3.G7 ; MEM1.K8 58.01,110.59 58.08,110.65 58.08,110.69 58.41,111.02 v1(58.41,111.68) ; v1(54.51,90.76) 54.51,91.27 54.17,91.6 53.6,91.6 MEM4.H2 ; v1(57.61,93.22) 57.61,94.56 57.89,94.84 58.17,94.84 58.55,95.22 MEM2.N1 ; MEM4.H2 52.81,90.81 51.93,90.81 51.27,90.16 v1(51.27,89.66) ; MEM4.H2 52.81,91.63 52.81,92.18 v1(52.81,92.42)
  BOTTOM w0.229: MEM2.N1 58.81,95.45 58.42,95.84 58.42,96.18 58.42,96.19 v1(58.42,96.39)
  BOTTOM w0.305: v1(51.61,108.24) 52.25,108.24 MEM1.N1 ; MEM2.K2 58.01,92.82 v1(57.61,93.22) ; MEM4.G7 57.21,90.45 57.57,90.81 v1(57.61,90.81) ; v1(51.89,106.79) 52.2,106.48 MEM1.R1 ; v1(51.75,95.7) 52.23,95.22 MEM2.N9 ; v1(52.81,92.42) 52.81,92.42 MEM2.K8 ; MEM4.E9 59.22,88.41 59.23,88.41 ; v1(59.36,87.4) 59.18,87.22 MEM2.C1 ; 59.23,88.41 58.84,88.02 MEM4.D9 ; 59.23,88.41 60.02,88.41 v2(60.16,88.55) 60.59,88.99 60.59,89.04 60.93,89.38 ; v1(59.36,90.75) 59.36,90.79 58.93,91.22 MEM4.H9 ; v1(51.71,96.82) 51.71,96.82 MEM2.R9
  BOTTOM w0.356: v1(59.32,107.67) 59.22,107.67 MEM1.N9 ; MEM3.H9 52.08,112.08 51.89,112.27 v1(51.88,112.27) ; MEM3.B2 v1(57.62,117.28) ; MEM3.E9 52.41,114.54 52.06,114.89 52,114.89 v1(51.99,114.9) 51.99,114.9 52.37,115.28 MEM3.D9 ; v1(51.95,116.4) 51.98,116.4 52.03,116.35 52.05,116.35 52.32,116.08 MEM1.C1 ; MEM1.C9 58.84,116.06 59.17,116.06 59.26,115.97 59.91,115.97 59.99,115.89 v1(60.06,115.89) ; v1(57.61,86.01) 58,85.62 MEM4.A8 ; v1(58.41,111.68) MEM3.H2 ; v1(59.59,113.45) 59.59,113.45 59.59,113.49 59.41,113.68 MEM3.F1 ; MEM1.K2 v1(53.61,110.08) ; MEM3.A1 58.99,117.68 59.4,118.09 v1(59.4,118.31) ; MEM3.D2 58.02,115.28 v1(58.41,114.89) ; v1(52.45,118.56) 52.49,118.6 52.89,118.6 53.21,118.27 MEM3.A8 ; MEM1.K8 58.42,110.08 v1(58.45,110.08) ; v1(58.42,96.39) 58.81,96.78 MEM2.R1 59.39,96.82 60.06,96.14 61.64,96.14 C776.1 ; v1(59.22,106.1) 58.84,106.48 MEM1.R9
  BOTTOM w0.381: R230.2 49.26,107.89 49.78,107.37 50.54,107.37 51.42,108.24 v1(51.61,108.24)
  BOTTOM w0.508: R1204.1 v1(85.91,88.43) ; R1924.2 47.59,92.81 46.36,94.04 46.36,99.26 46.81,99.71 48.39,99.71 48.85,99.26 48.85,98.81 48.89,98.78 ; 60.63,90.15 59.62,90.15 59.36,90.41 v1(59.36,90.75) ; R1890.1 R1200.1 76.42,115.18 75.55,116.05 69.4,116.05 v1(67.34,118.11)
  BOTTOM w0.635: 49.46,123.18 TC21.1 ; TC21.1 50.73,124.23 ; TC21.1 49.46,125.29
  vias: v2(50.17,118.03) v2(50.17,117.04) v2(50.17,116.17) v2(50.19,90.19) v2(50.22,89.05) v2(50.19,87.83) v2(51.34,99.88) v3(49.99,102.34) v3(50.33,86.74) v4(49.06,117.65) v4(49.81,101.93) v4(50.33,83.87) v4(62.14,101.35) v4(63.03,92.58) v4(72.68,99.57) v4(72.8,94.36) v6(50.32,105.1) v6(50.32,103.75) v6(51.7,124.97) v6(51.75,123.93) v6(51.77,122.99) v6(52.73,123.94) v6(52.74,122.99)
1P05V_A: length 56.1
  TOP w0.305: PR9795.1 36.33,224.06 PC5446.1 35.91,223.08 35.52,222.69 v2(35.52,221.91)
  TOP w0.635: 47.96,192.12 PTC4702.1 ; PTC4702.1 46.9,193.17 ; PTC4702.1 47.96,194.22 ; PTC4702.1 49.01,193.17
  L3 w0.635: 47.96,192.12 PTC4702.1 ; PTC4702.1 46.9,193.17 ; PTC4702.1 49.01,193.17 ; PTC4702.1 47.96,194.22
  BOTTOM w0.508: v6(48.04,190.75) 49.13,189.66 v4(49.99,189.66) 50.76,190.42 50.76,202.8 48.07,205.49 48.07,211.57 42.63,217 42.63,221.06 41.77,221.91 v4(37.55,221.91) v2(35.52,221.91)
  vias: v6(42.83,190.75) v6(43.34,191.77) v6(43.85,190.75) v6(44.48,191.77) v6(44.86,190.75) v6(45.5,191.77) v6(45.88,190.75) v6(47.02,190.75)
1P5V_GUP_FB_M: length 6.3
  TOP w0.305: PU7.2 53.31,129.93 52.47,130.77 PC68.2 52.15,131.81 PR78.2 52.17,132.3 52.53,132.66 v3(52.64,132.66) 53.55,132.66 PR77.1
1P5V_GUP_FB_M1: length 3.3
  TOP w0.305: PR79.1 PC68.1 51.26,131.81 PR78.1 51.26,132.67 v3(51.11,132.82)
1P05V_S5: length 168.2
  TOP w0.254: v2(43.8,219.02) 43.85,219.07 PR9803.1 ; CPU2.N18 v1(76.74,160.16) ; CPU2.V18 v1(79.86,160.83) CPU2.V19 ; v1(73.67,156.15) 73.69,156.15 CPU2.G10 CPU2.H10 ; v1(78.16,161.09) 78.34,161.09 CPU2.U19 ; v2(21.5,164.58) 21.14,164.22 R1831.1 ; v1(79.08,165.38) 79.46,165.76 CPU2.V29
  TOP w0.305: R1831.1 19.78,164.22 R79793.1 ; R79937.1 18.72,161.58 19.1,161.2 v2(20.25,161.2)
  L3 w0.254: v2(89.39,151.19) 87.11,148.92 v2(87.03,148.92) 85.38,148.92 84.57,148.12 83.49,148.12 83,147.62 80.91,147.62 80.82,147.71 80.42,147.71 80.42,147.71 79.65,147.71 78.07,146.13 76,146.13 v1(75.95,146.08)
  L3 w0.508: v2(76.63,203.51) 76.44,203.71 v2(76.44,206.46) 76.52,206.54 77.91,206.54 v2(80.79,209.41)
  L4 w0.381: v2(20.25,161.2) 20.25,163.47 21.36,164.58 v2(21.5,164.58) 21.43,164.65 22.25,165.46 22.3,165.46 26.62,169.78 26.62,170.23 37.56,181.18 39.78,181.18 41.32,182.71 52.52,182.71 v2(52.74,182.93)
  L4 w0.508: v1(86.93,167.67) 87.53,167.06 87.53,163.16 86.93,162.56 v1(86.93,162.36) 87.04,162.36 88.43,160.97 88.43,159.05 88.07,158.69 88.07,158.69 v2(87.8,158.42)
  BOTTOM w0.254: C612.1 79.86,159.75 v1(79.86,160.83) ; R1785.1 52.56,182.75 v2(52.74,182.93) ; v2(80.79,209.41) 80.79,209.64 80.81,209.66 R1734.1 R79794.1
  BOTTOM w0.305: R79795.1 75.71,208.3 75.71,207.12 76.38,206.46 v2(76.44,206.46) ; R79791.1 78.28,182.47 78.28,182.51 v2(77.71,183.08)
  BOTTOM w0.381: v1(86.93,167.67) 87.36,167.23 C614.1 ; v2(53.8,186.44) 51.96,188.28 51.96,203.3 49.27,205.99 49.27,212.07 v4(48.21,213.13) 45.65,215.69 45.65,217.4 44.03,219.02 v2(43.8,219.02) ; v2(72.02,186.51) 72.02,188.01 77.43,193.43 v4(77.43,198.5) 77.43,202.71 v2(76.63,203.51) ; v1(86.93,162.36) 87.1,162.18 C6719.1
  BOTTOM w0.508: v1(75.95,146.08) 75.95,147.83 v4(75.31,148.47) 74.31,149.47 74.31,152.33 73.54,153.1 73.54,154.83 C617.1 73.09,155.92 73.44,155.92 v1(73.67,156.15)
  vias: v1(79.08,164.62) v1(79.08,163.09) v1(79.86,168.41) v1(79.85,167.66) v1(80.65,169.16) v1(80.65,168.4) v3(50.4,184.99) v3(71.76,185.29) v4(78.9,163.8) v4(86.89,158.21) v6(61.27,184.78) v6(62.34,184.76) v6(63.36,184.76) v6(68.74,184.23) v6(69.76,184.23) v6(70.82,184.23) v6(71.86,184.23)
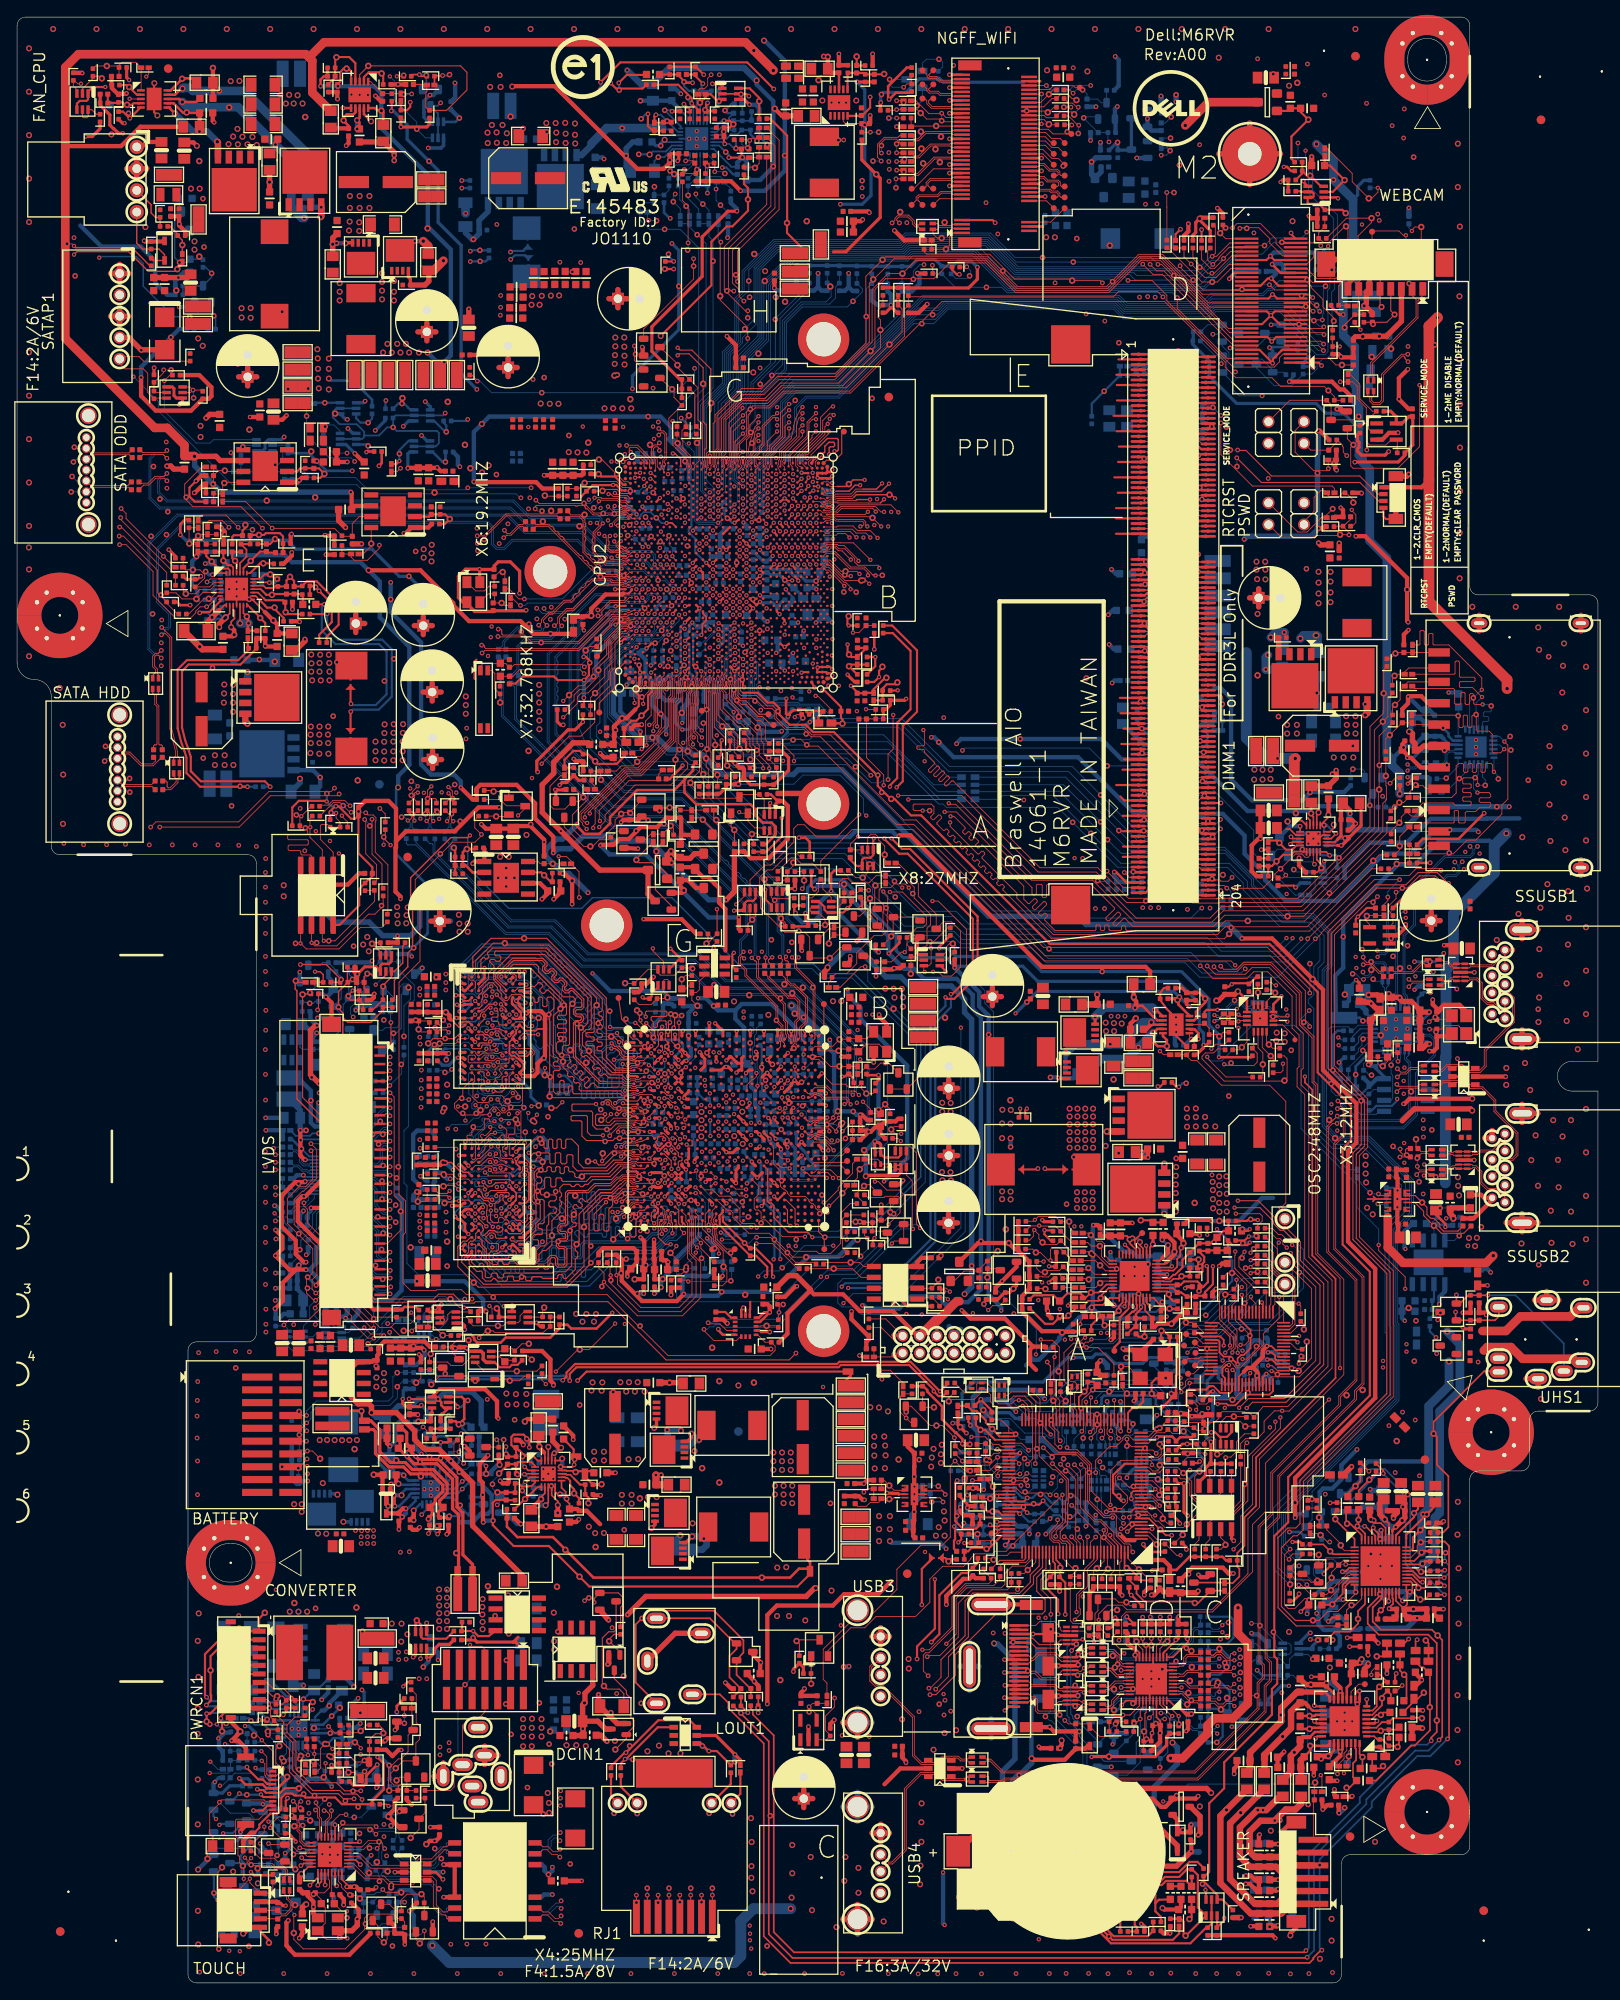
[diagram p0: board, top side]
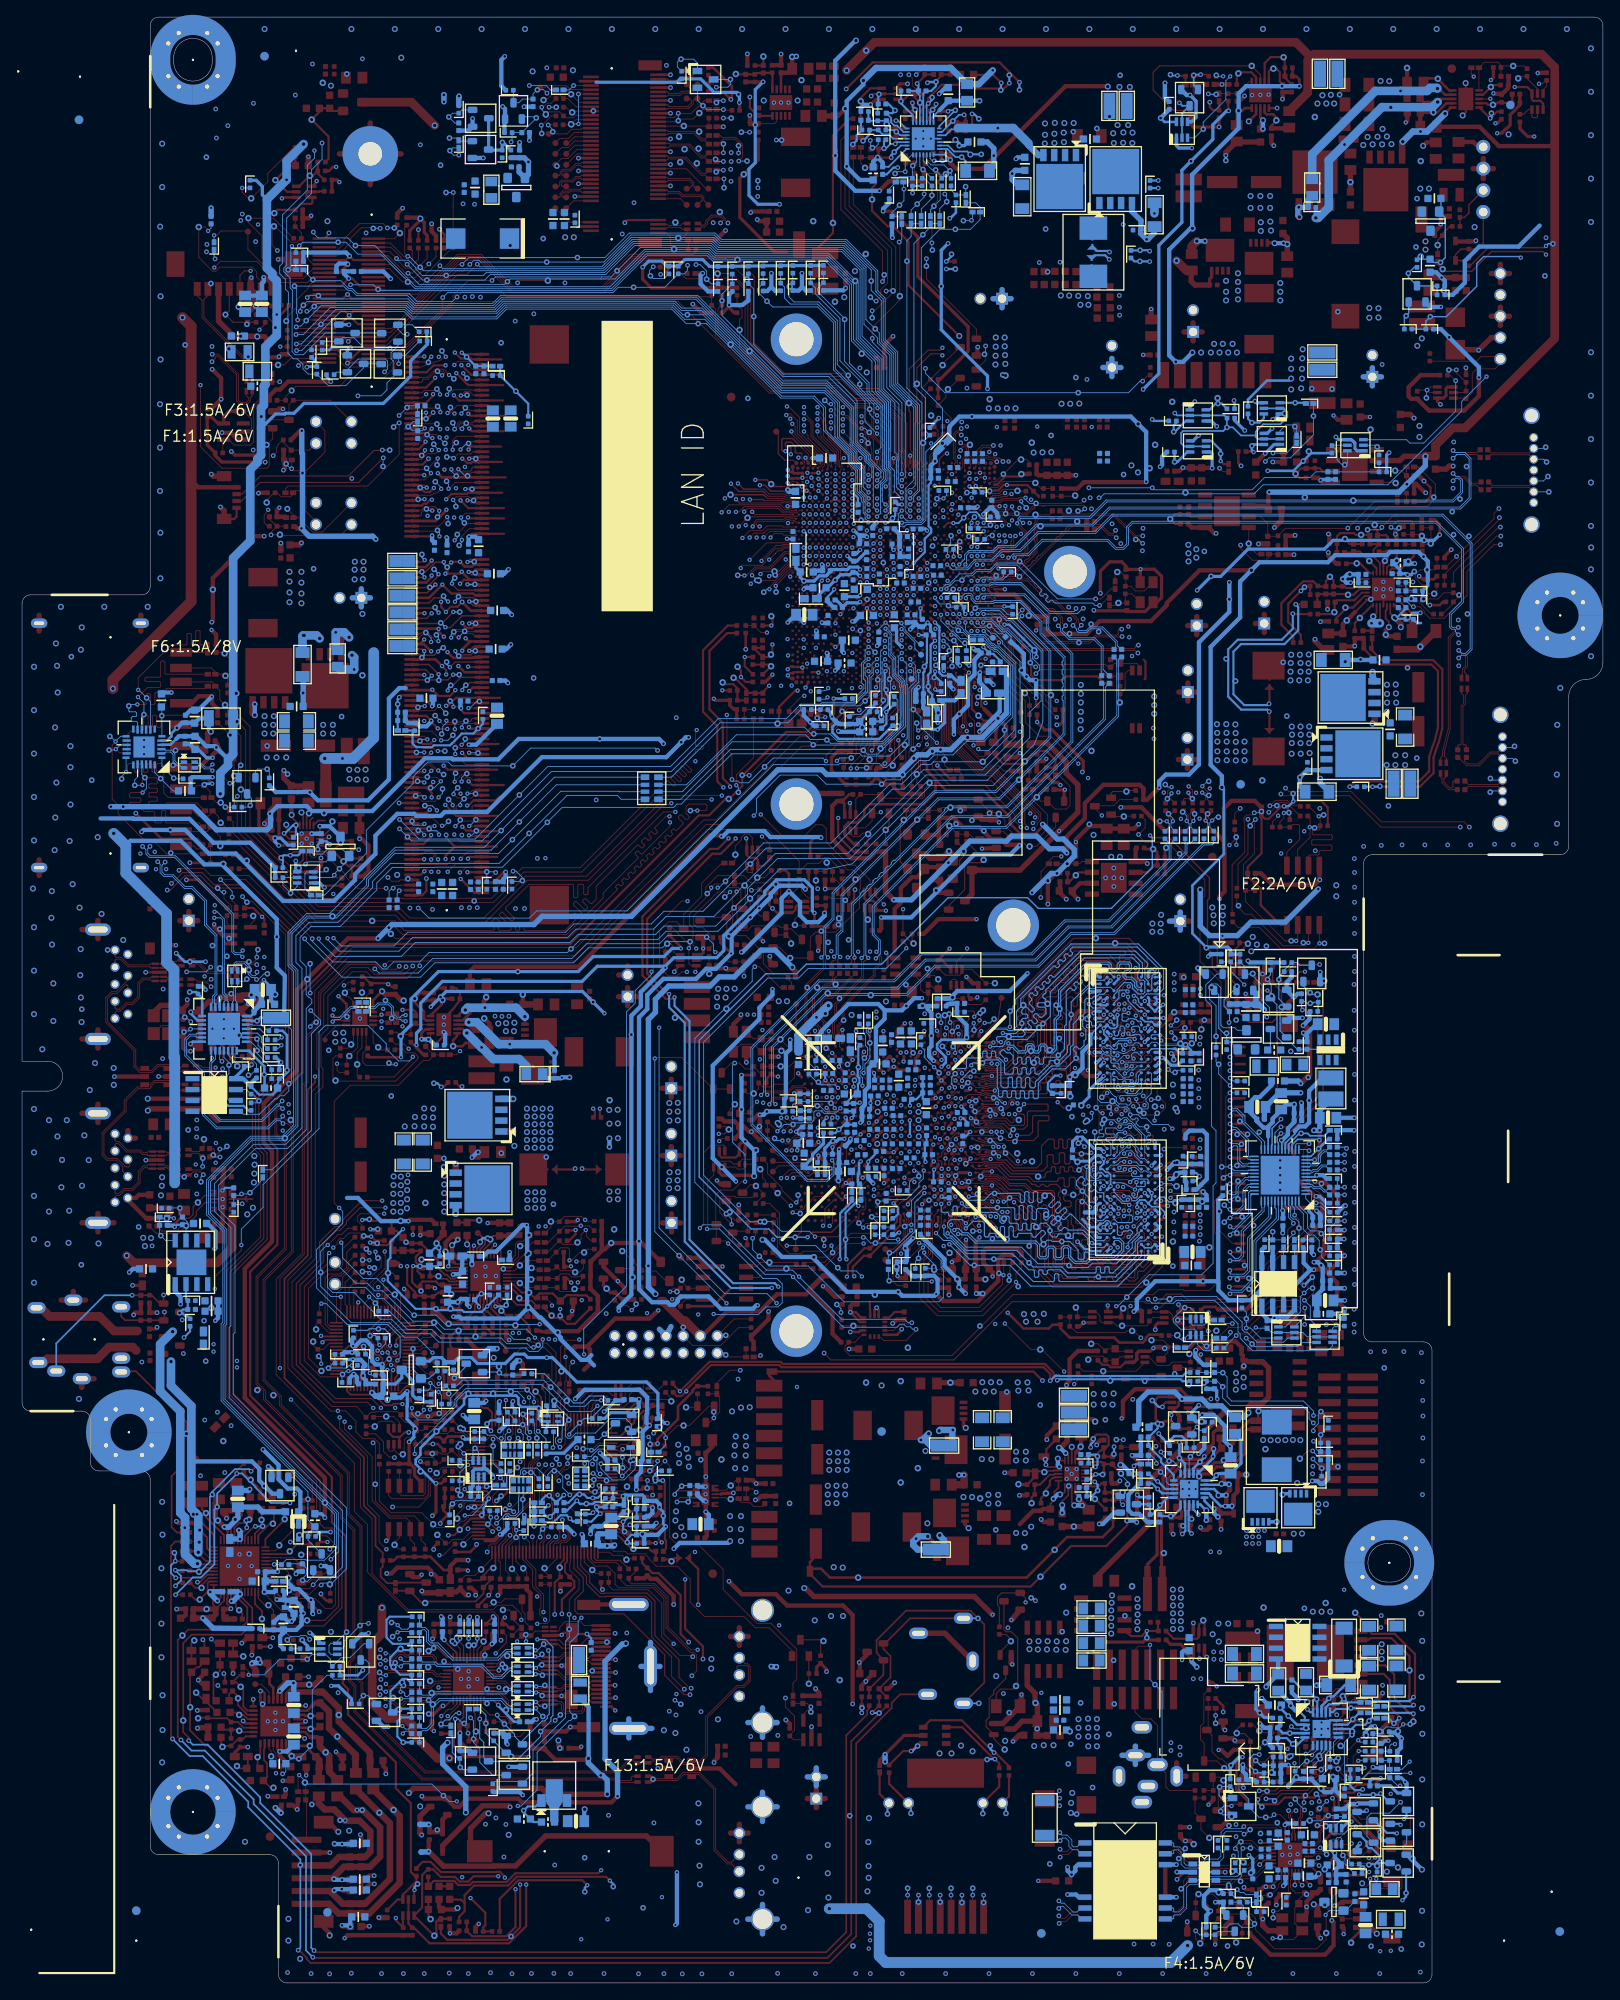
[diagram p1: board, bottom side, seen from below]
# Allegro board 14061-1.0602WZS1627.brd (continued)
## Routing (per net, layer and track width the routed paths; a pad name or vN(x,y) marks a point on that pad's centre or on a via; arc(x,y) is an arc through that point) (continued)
1P05V_S5_D: length 3.8
  BOTTOM w0.254: R1785.2 49.92,182.53 50.23,182.22 v4(50.23,181.47) 50.1,181.47 48.82,182.75 Q1228.3
1P8V_PWR: length 48.1
  TOP w0.381: v1(12.38,216.41) 11.86,216.41 11.71,216.55 11.32,216.95 11.27,216.95 10.85,217.37 10.85,218.57 9.72,219.7 PR59.1 PC41.1
  TOP w0.635: PTC9.1 26.98,188.96 ; PTC9.1 26.98,186.85 ; PTC9.1 25.93,187.91 ; PTC9.1 28.04,187.91
  L3 w0.508: v2(25.84,189.36) 25.28,189.92 25.28,192.23 21.6,195.91 21.6,197.28 19.72,199.16 19.72,204.11 16.04,207.8 16.04,214.48 14.11,216.41 v1(12.38,216.41)
  BOTTOM w0.635: PTC9.1 28.04,187.91 ; PTC9.1 26.98,186.85 ; PTC9.1 25.93,187.91 ; PTC9.1 26.98,188.96
  vias: v4(31.02,195.53) v4(31.71,186.49) v6(26.27,195.93) v6(26.27,194.85) v6(27.34,195.96) v6(27.34,194.82)
1P8V_PWR_BOOT: length 4.2
  TOP w0.305: PU4.10 17.97,221.42 19.26,222.71 19.26,222.73 v3(19.31,222.78) 19.36,222.83 20.48,222.83 PR50.1
1P8V_PWR_BOOT_R: length 3.6
  TOP w0.508: v3(22.92,224.05) PR50.2 PC34.1
1P8V_PWR_CS: length 3
  TOP w0.254: PR57.1 12.89,222.05 v3(13.11,221.82) 14.01,220.92 PU4.2
1P8V_PWR_FB: length 5.1
  TOP w0.254: PU4.4 13.63,219.92 13.44,219.74 v3(12.86,219.74) 12.58,219.74 12.29,220.03 PR58.1 11.81,219.96 PR59.2 PC41.2
1P8V_PWR_LGATE: length 9.3
  TOP w0.305: PU4.6 17.77,219.42 v6(18.47,218.72)
  TOP w0.762: PQ8.4 23.5,215.34 v6(23.43,215.42)
  BOTTOM w0.762: v6(23.43,215.42) 22.23,216.61 v4(21.34,216.61) 20.58,216.61 v6(18.47,218.72)
1P8V_PWR_PHASE: length 28.5
  TOP w0.305: PC34.2 20.96,220.07 v6(19.34,220.07) 18.98,220.42 PU4.8
  BOTTOM w0.508: R95.2 v6(33.6,206.5)
  BOTTOM w1.016: v6(19.34,220.07) 19.95,219.46 25.86,219.46 v4(30.23,215.09) 32.09,213.23 32.09,207.75 33.33,206.5 v6(33.6,206.5)
1P8V_PWR_RF: length 4.1
  TOP w0.254: PU4.5 14.45,219.42 v2(13.19,218.16) 13.17,218.16 12.39,218.94 PR53.1
  BOTTOM w0.254: v4(13.04,218.75) 13.04,218.31 v2(13.19,218.16)
1P8V_PWR_SNB: length 2.6
  TOP w0.635: PC23.2 v3(29.55,210.69) PR41.1
1P8V_PWR_UGATE: length 22.9
  TOP w0.305: v6(19.36,221.64) 19.21,221.64 18.49,220.92 PU4.9
  BOTTOM w1.016: v6(19.36,221.64) 19.44,221.72 20.23,221.72 20.58,221.36 v4(23.68,221.36) 26.63,221.36 34.02,213.97 PR39.1
1P8V_PWR_UGATE_R: length 5.4
  TOP w0.762: PQ7.4 35.59,206.68 v6(35.52,206.6)
  BOTTOM w0.635: PR39.2 34.49,208.62 R95.1 v4(35.59,207.75) 35.69,207.65 35.69,206.78 v6(35.52,206.6)
1P8V_PWR_V5IN: length 5.9
  TOP w0.305: PC33.2 19.9,218.8 v3(19.85,218.85) 19.79,218.8 19.44,218.8 18.31,219.92 PU4.7
  TOP w0.508: PR48.2 PC33.2
1P8V_S5_PG: length 10.2
  TOP w0.102: R720.2 C568.1 ; R720.2 11.76,224.28 v3(10.5,224.28) 9.19,224.28 R721.2 ; R720.2 11.93,224.37 12.28,224.71 13.88,224.71 R79949.1 14.51,221.45 PU4.1
1P15V_S5: length 34.9
  TOP w0.254: R1786.1 88.14,218.12 90.11,216.14 90.11,205.93 v3(90.1,205.92) 90.1,204.75 91.98,202.87 R1225.2
  TOP w0.381: PR4812.1 98.85,213.3 v3(100.54,211.61) 101,211.15 101,206.56 96.98,202.54 95.54,202.54
  vias: v3(95.16,198.48)
1P15V_S5_D: length 5.3
  TOP w0.254: R1786.2 v3(86.85,220.15) 86.85,220.55 85.73,221.67 Q1229.6
3D3V_AUX_EC: length 44.7
  TOP w0.203: 143.57,71.53 142.97,70.93 U4101.38 ; v1(146.26,74.51) 146.78,74.51 147.25,74.04 U4101.56 ; 145.17,71.46 145.37,71.26 U4101.44 ; U4101.22 140.49,75.24 140.7,75.03 140.7,73.78 141.19,73.28 141.92,73.28 v1(142.83,72.36) 142.83,73.06 143.22,73.45 143.52,73.45 144.34,74.27 144.34,76.36 142.97,77.73 U4101.11
  TOP w0.508: 144.68,71.96 144.68,72.18 145.78,73.28 145.78,74.03 146.25,74.5 146.25,74.5 v1(146.26,74.51) ; 144.68,71.96 145.17,71.46 ; 144.68,71.96 144,71.96 143.57,71.53
  BOTTOM w0.381: PR8519.1 137.89,67.98 138.3,68.39 PR8520.1 138.93,68.39 139.28,68.73 139.28,70.45 Q9649.D 140.56,70.81 141.3,70.08 L4101.1
  BOTTOM w0.508: R80230.2 146.37,75.32 146.37,74.62 v1(146.26,74.51) 145.99,74.51 145.33,75.18 144.73,75.18 144.04,74.48 144.04,72.76 143.64,72.36 v1(142.83,72.36) 142.83,72 142.86,71.97 142.86,71.2 R80126.1 142.7,71.05 142.7,70.12 L4101.1
  BOTTOM w0.635: L4101.1 142.74,68.93 R80232.2 143.63,68.64 v4(144.05,69.06)
3D3V_RUN_FFS: length 4.2
  TOP w0.254: U6701.1 83.54,77.83 82.88,78.5 C6701.2 ; 85.79,79.7 85.79,78.83 85.75,78.79 U6701.14
  vias: v3(81.34,74.32) v3(85.2,80.52)
3D3V_VGA_S0: length 165.5
  TOP w0.254: RN16.3 101.49,96.57 103.13,96.57 103.41,96.85 Q123.5
  TOP w0.305: R1167.1 104.16,79.17 102.27,81.06 ; R1883.1 100.9,105.71 100.9,106.11 v2(100.81,106.2) 99.5,106.2 R1159.2
  TOP w0.356: RN16.4 100.42,97.55 100.36,97.61 v2(100.36,98.45) 100.37,98.45 100.39,98.41 100.9,98.27 101.07,98.1 RN16.3
  TOP w0.381: PR6.1 124.25,76.19 124.39,76.33 PR4.1
  TOP w0.406: Q123.2 103.41,94.87 103.03,94.49 99.42,94.49 v6(99.32,94.39)
  TOP w0.508: PR9769.1 117.13,86.42 117.15,86.44 117.15,86.88 PR102.1 PR103.1 117.17,89.11 PR9772.1 ; PR9769.1 116.78,85.85 v3(116.06,86.56) 112.46,86.56 Q9629.D ; PR9769.1 117.15,85.7 117.15,85.67 117.63,85.19 117.66,85.19 PR9776.1 118.46,84.38 118.46,83.03 PR96.1 118.49,82.65 PR9775.1 117.61,80.36 PR19.1 PR15.1 117.61,78.58 119.94,76.25 122.16,76.25 v3(122.31,76.1) 122.4,76.19 PR6.1 ; v1(73.31,124.46) 77.76,124.46 79.48,122.74 R80116.1 ; PR225.1 64.01,129.85 64.9,128.96 v3(64.96,128.96) v2(64.96,126.21) ; v1(78.03,80.6) 77.21,79.78 73.14,79.78 70.76,82.15 70.76,84.66 70.48,84.94 70.36,84.94 R1895.2 69.09,85.18 R398.2
  L3 w0.508: v1(79.69,115.21) 75.47,119.43 75.11,119.43 73.03,121.5 73.03,124.18 v1(73.31,124.46) 70.87,126.9 67.22,126.9 66.44,126.12 65.05,126.12 v2(64.96,126.21)
  BOTTOM w0.508: 84.06,113.79 82.02,113.79 v4(81.51,114.31) 80.6,115.21 v1(79.69,115.21) ; 84.06,113.79 84.06,112.79 85.07,111.78 85.07,107.87 C784.1 85.91,107.03 85.91,104.83 86.37,104.37 86.37,102.74 86.71,102.4 C782.1 C783.1 86.71,100.84 v1(86.89,100.66) ; 84.06,113.79 84.79,114.53 88.3,114.53 91.45,111.38 91.45,111.23 91.97,110.71 R80140.1 ; R302.2 80.8,82.69 R79965.2 79.33,82.69 R1893.2 78.98,82.72 78.96,82.75 78.27,82.75 77.87,82.35 77.87,80.75 v1(78.03,80.6) 78.23,80.39 82,80.39 v4(82.46,80.85) 88.46,80.85 92.54,84.94 96.07,84.94 98.08,86.94 v6(98.36,86.94) ; v6(99.32,94.39) 99.32,97.41 v2(100.36,98.45) 100.81,98.89 v4(100.81,102.18) v2(100.81,106.2)
1117 ADJ: length 5.3
  BOTTOM w0.254: R79751.2 125.15,18.82 R79752.1 126.3,19.96 v4(126.3,20.17) 125.81,20.65 124.9,20.65 124.22,21.34 U119.1
62882_COMP_R: length 2.3
  TOP w0.254: PR8.1 131.95,75.63 v3(131.94,75.62) 131.26,75.62 PC6.2
62882_FB_VSEN: length 1.1
  TOP w0.508: PC11.1 137.93,78.45 PR20.2
62882_NTC_R: length 27.7
  TOP w0.254: PR9782.2 139.26,87.55 v1(139.28,87.53) ; v2(135.95,104.83) 135.68,104.83 PR60.1
  L4 w0.254: v2(135.95,104.83) 136.91,103.86 138.96,103.86 143.54,99.28 143.54,90.83 143.29,90.58 143.29,89.46 142.7,88.87 140.32,88.87 139.37,87.93 139.37,87.63 v1(139.28,87.53)
  BOTTOM w0.254: v2(135.95,104.83) 136.38,105.26 v4(136.81,105.26)
62883AGND: length 8.3
  TOP w0.203: U6706.40 128.98,80.91 v1(130.78,82.71)
  TOP w0.381: v1(136.69,81.28) 136.74,81.28 136.91,81.45 PC5272.1
  TOP w0.508: PC60.2 138.21,87.66 138.37,87.49 ; v1(140.29,81.2) 139.9,80.81 PC5268.2 ; PR9782.1 138.37,87.49 ; 138.37,87.49 v1(138.39,87.48) ; PC20.2 141.03,84.18 140.72,83.87 v1(140.67,83.87)
  vias: v1(129.55,82.7) v1(130.78,83.79) v1(131.91,82.7) v4(128.68,83.54) v4(138.31,80.95) v4(140.06,86.66)
+3D3V_PWR: length 41.7
  TOP w0.305: PR4923.1 C1606.1 57.32,53.38 58.54,52.16 62.71,52.16 64.16,50.71 ; 92.46,49.56 92.79,49.23 PG4902.2 91.5,48.46 90.46,47.42 v3(87.16,47.42) 67.44,47.42 64.16,50.71 ; 64.16,50.71 v3(64.16,50.67)
+DCBATOUT_RT8243_1: length 8
  TOP w0.203: PU4901.11 63.71,57.94 64.19,57.46 64.19,56.52 64.65,56.06 PC4916.2
  TOP w0.508: 68.23,53.67 66.66,55.24 PR4901.1 65.55,55.45 PC4916.2
  vias: v3(67.7,51) v4(65.84,67.61) v4(71.05,53.01) v6(66.91,53.37) v6(67.53,62.15) v6(67.53,61.13) v6(67.65,52.62) v6(68.67,62.15) v6(68.67,61.13) v6(68.67,52.64) v6(71.56,61.26) v6(72.68,61.29)
+VGA_CORE_PHASE1: length 55.3
  TOP w0.254: v2(119.46,95.28) 119.36,95.17 PG3.1 ; v1(144.15,87.33) 144.13,87.33 143.66,86.86 PR9779.2
  L4 w0.254: v1(144.15,87.33) 144.87,88.04 144.87,88.54 144.69,88.72 144.69,89.63 145.63,90.57 145.63,100.04 139.8,105.87 138.24,105.87 137.55,106.55 128.89,106.55 126.02,103.68 121.91,103.68 121.91,103.68 121.59,103.68 119.64,101.73 119.64,95.45 v2(119.46,95.28)
  BOTTOM w0.254: v1(144.15,87.33) 144.94,87.33 v4(145.01,87.4)
A20GATE: length 3.3
  BOTTOM w0.102: R333.1 124.7,63.68 v4(124.76,63.74) 124.76,64.06 125.05,64.35 125.05,65.48 R80231.2
AC_IN: length 38.9
  TOP w0.102: PQ5005.2 47.28,38 v2(47.21,37.93) ; PQ5004.D 56.36,62.69 PR5281.2 56.37,63.3 v2(56.12,63.55)
  L4 w0.127: v2(47.21,37.93) 48.27,38.99 48.9,38.99 53.84,43.93 53.84,59.86 52.29,61.42 51.77,61.42 51.25,61.93 51.25,62.4 52.4,63.55 v2(56.12,63.55)
  BOTTOM w0.102: v4(56.94,63.56) 56.94,63.55 v2(56.12,63.55)
AC_IN_KBC#: length 3.2
  TOP w0.102: TP4124.1 137.68,71.27 138.84,72.44 U4101.29
AC_OK#: length 168.8
  TOP w0.102: PQ5004.G 52.48,63.67 51.75,62.94 51.75,62.15 v2(51.72,62.13) ; R80208.1 114.97,47.17 114.28,46.48 111.06,46.48 109.64,45.06 109.64,41.56 106.72,38.63 106.32,38.63 106.05,38.37 106.05,36.5 v2(106.62,35.93) ; U4101.37 142.57,71.39 v1(142.25,71.72)
  L4 w0.127: v1(142.25,71.72) 142.25,71.6 141.21,70.56 141.21,67.81 140.76,67.37 140.76,65.39 140.27,64.9 140.27,63.07 139.53,62.33 139.53,59.72 137.96,58.15 137.96,50.04 135.97,48.06 135.97,43.54 135.48,43.04 135.48,42.68 133.28,40.49 133.28,39.93 125.06,31.7 121.94,31.7 121.3,32.34 110.51,32.34 106.91,35.93 v2(106.62,35.93) 103.35,32.67 100.7,32.67 95.6,37.77 95.6,40.69 92.62,43.68 69.04,43.68 68.56,43.19 63.95,43.19 55.04,52.1 55.04,59.02 51.93,62.13 v2(51.72,62.13)
  BOTTOM w0.102: U55.5 49.42,60.18 50.3,61.06 v4(50.77,61.06) 50.77,61.06 50.79,61.06 51.72,62 v2(51.72,62.13) 51.67,62.18 50.92,62.18 PR4427.2
AC_OK#_ECIO: length 4.8
  TOP w0.102: R80208.2 115.04,48.77 115.48,49.2 118.04,49.2 118.41,49.57 U109.99
AC_PRESENT_CPU: length 12.3
  TOP w0.089: CPU2.C13 71.78,158.2 71.77,158.19 71.63,158.19 71.34,157.91 70.79,157.91 70.31,157.42
  TOP w0.102: R1262.2 R1265.1 67.1,150.38 67.62,150.9 v3(67.65,150.9) 67.65,150.93 69.25,152.53 69.25,153.45 69.6,153.81 69.6,156.72 70.31,157.42
AC_PROTECT: length 10
  TOP w0.102: v2(47.51,65.05) 47.94,64.62 PR5287.1
  BOTTOM w0.102: U55.3 48.42,61.41 v4(48.27,61.57) 47.85,61.99 PR5289.2 47.85,63.31 48.1,63.56 PQ4408.G 48.1,64.45 v2(47.51,65.05) 47.08,64.63 PR5297.2 45.74,65.46 PR5298.1
AD+_2: length 12.9
  TOP w0.635: PC4201.2 66.25,30.56 PR4207.1 66.21,28.94 PR4204.2 ; PC4201.2 66.18,32.53 v3(66.4,32.75) 66.4,32.81 66.45,32.86 66.45,33.9 67.37,34.81 PU4201.4 ; PC4201.2 67.94,30.62 68.87,29.7 PQ4205.C
AD+_G_1: length 7.9
  TOP w0.254: PQ5005.6 46.63,42.28 v3(46.77,42.42) 47.28,41.91 PQ5005.5 47.28,40.47 47.47,40.27 50.22,40.27 PR5272.2
AD+_G_2: length 6.3
  TOP w0.254: PU5204.4 55.2,40.58 53.97,40.58 v1(53.37,41.17) 52.01,41.17 ; 52.01,41.17 52.06,41.22 PR5275.2 ; 52.01,41.17 PR5272.1
  BOTTOM w0.254: v1(53.37,41.17) v4(53.37,40.39)
AD+_TO_SYS: length 2.3
  TOP w0.254: PR5276.1 53.3,45.51 PG4907.1
  vias: v3(55.1,46.41) v4(55.94,42.95) v4(57.26,37.74) v6(54.48,44.91) v6(54.45,43.99) v6(54.45,43.1) v6(54.48,42.24) v6(54.48,41.38) v6(57.45,45.34) v6(57.49,44.48) v6(57.54,43.59) v6(57.54,42.7) v6(57.54,41.78) v6(57.54,40.87)
AD_IA: length 158.6
  TOP w0.203: v1(140.49,67.72) 140.53,67.77 141.53,67.77 141.73,67.57 142.56,67.57 143.82,68.83 146.56,68.83 146.97,69.24 U4101.48
  TOP w0.254: v1(107.4,47.22) 107.4,41.45 105.32,39.37 v2(105.32,37.9) ; v2(54.87,60.47) 54.87,59.8 54.9,59.78 v3(54.9,59.56) ; R80216.1 111.58,51.46 v1(110.85,51.46)
  L3 w0.254: v1(106.26,50.42) 106.28,50.44 107.35,50.44 108.24,51.33 109.63,51.33 109.94,51.03 110.37,51.03 110.8,51.46 v1(110.85,51.46)
  L4 w0.254: v1(107.4,47.22) 107.4,48.67 106.26,49.81 v1(106.26,50.42) ; v2(54.87,60.47) 54.87,59.89 55.49,59.28 55.49,52.28 64.13,43.64 68.38,43.64 68.86,44.12 92.8,44.12 95.98,40.94 99.5,40.94 100.01,41.46 101.63,41.46 105.19,37.9 v2(105.32,37.9) 105.58,37.9 110.63,32.84 122.03,32.84 122.63,33.44 125.18,33.44 131.12,39.39 131.12,40.45 131.76,41.09 132.8,41.09 134.32,42.61 134.32,43 135.53,44.21 135.53,48.24 137.51,50.22 137.51,58.33 138.91,59.73 138.91,61.23 138.54,61.6 138.54,62.23 139.17,62.86 139.17,64.59 140.32,65.74 140.32,67.55 140.49,67.72 v1(140.49,67.72)
  BOTTOM w0.254: PR5288.2 54.64,60.71 v2(54.87,60.47)
AD_IA_HW1: length 158.9
  TOP w0.203: U4101.59 149.56,75.24 v1(149.84,74.96) ; R79705.1 121.47,48.07 121.47,49.05 121.21,49.31 U109.106
  TOP w0.254: PQ5006.5 51.16,67.92 51.54,67.54 v2(51.54,67.39) ; R79705.1 120.9,47.51 120.38,46.99 120.38,46.28 121.83,44.84 v2(121.83,43.18)
  L3 w0.254: v1(136.16,70.8) 136.18,70.82 136.25,70.82 136.8,71.37 139.11,71.37 139.26,71.21 143.32,71.21 143.53,71.01 143.77,70.76 146.67,70.76 149.84,73.94 v1(149.84,74.96)
  L4 w0.254: v1(136.16,70.8) 136.09,70.73 135.96,70.73 134.03,68.8 134.03,61.9 133.33,61.2 133.33,60.4 131.87,58.94 131.87,52.28 132.34,51.82 132.34,51.09 130.43,49.17 122.57,49.17 120.04,46.64 120.04,44.97 v2(121.83,43.18) 121.83,42.98 121.06,42.21 119.33,42.21 118.3,43.25 118.3,46.52 117.58,47.24 109.03,47.24 107.81,46.01 102.05,46.01 100.08,47.98 65.35,47.98 60.51,52.82 60.51,60.73 58.68,62.56 58.68,63.28 56.99,64.97 56.56,64.97 55.22,66.31 52.62,66.31 v2(51.54,67.39)
  BOTTOM w0.254: v4(52.74,68.15) 51.98,67.39 v2(51.54,67.39)
AD_IA_HW2: length 168
  TOP w0.203: v1(150.02,75.69) 149.96,75.64 U4101.60 ; R79704.1 122.08,47.61 v3(122.08,48.59) 122.08,49 121.61,49.47 U109.107
  TOP w0.254: R79704.1 122.66,46.82 v2(122.66,43.1) ; v2(45.88,68.33) 45.91,68.3 47.56,68.3 47.94,67.92 PQ5006.2
  L3 w0.254: v1(136.24,70.09) 137.01,70.86 143.17,70.86 143.62,70.41 147.03,70.41 150.35,73.73 150.35,75.26 150.02,75.59 v1(150.02,75.69)
  L4 w0.254: v1(136.24,70.09) 134.54,68.39 134.54,61.86 133.75,61.07 133.75,60.21 132.26,58.71 132.26,52.44 132.72,51.97 132.72,50.93 130.46,48.67 122.78,48.67 120.54,46.43 120.54,45.22 121.41,44.35 121.42,44.35 v2(122.66,43.1) 121.27,41.71 119.12,41.71 117.77,43.05 117.77,46.32 117.37,46.73 109.24,46.73 108.02,45.5 101.7,45.5 99.73,47.47 65.14,47.47 60,52.61 60,60.52 58.16,62.36 58.16,63.08 56.77,64.47 56.34,64.47 55.01,65.8 51.85,65.8 51.01,66.64 51.01,66.66 50.71,66.95 49.94,66.95 48.93,65.94 46.68,65.94 45.88,66.73 v2(45.88,68.33)
AD_JK: length 20.4
  TOP w0.635: DCIN1.1 54.71,27.7 ; DCIN1.1 54.71,25.56 ; DCIN1.1 56.28,26.63 ; v1(68.04,33.73) 68.04,32.54 PR4214.1 70.23,30.35 PQ4205.E
  L3 w0.635: 54.71,25.56 DCIN1.1 ; DCIN1.1 54.71,27.7 ; DCIN1.1 56.28,26.63
  L4 w0.635: v1(65.72,33.93) 67.84,33.93 v1(68.04,33.73)
  BOTTOM w0.635: DCIN1.1 56.28,26.63 ; DCIN1.1 54.71,25.56 ; DCIN1.1 53.15,26.63 ; DCIN1.1 54.71,27.7
  vias: v3(62.38,29.42) v4(57.18,32.64) v4(57.82,29.08) v4(59.72,22.86) v4(61.12,32.77) v4(62.26,27.94) v4(62.57,25.63) v6(59.22,30.86) v6(59.22,29.84) v6(59.22,28.83) v6(59.22,27.69) v6(60.23,29.84) v6(60.23,28.83) v6(60.23,27.69) v6(60.26,30.91) v6(61.37,30.86) v6(61.37,29.84) v6(61.37,28.83)
AD_OFF: length 144.5
  TOP w0.203: 139.82,69.82 140.02,69.82 140.67,69.17 140.67,69.15 140.79,69.03 141.96,69.03 142.17,69.24 U4101.36
  TOP w0.254: v1(137.26,67.08) 137.24,67.11 137.24,67.22 136.84,67.63 136.84,69.16 137.1,69.42 139.14,69.42 139.54,69.82 139.82,69.82 ; R80210.1 112.43,49.14 R1867.1 111.59,48.3 111.58,48.3 111.24,47.96 110.52,47.96 107.93,45.37 107.93,40.82 v2(106.99,39.88)
  L4 w0.254: v1(137.26,67.08) 136.82,66.64 136.82,64.38 135.94,63.49 135.94,61.27 135.2,60.54 135.2,59.68 134.88,59.36 134.88,56.82 134.98,56.72 134.98,55.24 134.5,54.76 134.5,52.45 134.12,52.06 134.12,49.48 133.45,48.81 133.45,45.1 133.02,44.68 131.53,44.68 130.85,43.99 129.01,43.99 125.2,40.18 125.2,39.93 123.62,38.35 114.26,38.35 112.43,40.18 107.3,40.18 v2(106.99,39.88) 106.56,39.88 103.03,43.41 100.85,43.41 99.04,45.21 95.01,45.21 94.91,45.3 92.98,45.3 92.97,45.31 67,45.31 v2(66.41,44.72) 64.3,44.72 56.73,52.3 56.73,56.92 55.99,57.65 55.99,59.75 55.58,60.16 55.58,61.11 v2(57.21,62.74)
  BOTTOM w0.254: v4(57.22,61.87) 57.21,61.88 57.21,62.19 57.21,62.19 v2(57.21,62.74) ; v4(66.91,45.05) 66.73,45.05 v2(66.41,44.72)
AD_OFF_ECIO: length 4.7
  TOP w0.102: U109.97 116.24,50.39 115.87,50.03 114.78,50.03 v3(114.27,49.52) 114.1,49.69 R80210.2
AD_OFF_L: length 11.1
  TOP w0.127: PQ4204.C 69.89,35.6 71.31,34.19 71.31,33.8 71.82,33.28 71.82,31.07 72.18,30.72 72.18,29.98 71.29,29.09 PQ4205.B 71.29,28.58 v3(70.01,27.3)
ADAPTOR_PSID_R: length 4.8
  TOP w0.508: R426.1 44.18,21.27 44.18,20.33 43.47,19.62 43.47,19.46 ; 43.47,19.46 44.71,18.22 Q42.S ; 43.47,19.46 v3(43.45,19.46)
ADAPTOR_PSID_R_R: length 13.2
  TOP w0.102: R426.2 43.56,22.52 v3(43.54,22.5) 43.47,22.58 43.47,25.06 44.62,26.21 44.91,26.21 45.75,27.05 45.75,28.99 D14.3 46.2,29.74 R1602.1 R430.2
ADAPTOR_PSID_SIO: length 157.5
  TOP w0.102: v1(123.79,42.49) 124.42,43.12 124.42,43.74 124.28,43.87 124.28,45.38 125.26,46.35 125.26,48.39 126.41,49.54 U109.119 ; R1602.2 45.32,32.12 v2(45.32,31.29)
  L3 w0.127: v1(123.79,42.49) 123.87,42.42 123.87,42.12 120.82,39.07 115.37,39.07 113.95,37.65 113.95,35.83 108.99,30.86 106.54,30.86 105.66,31.74 v2(105.54,31.74)
  L4 w0.127: v1(143.41,73.98) 143.58,74.15 143.58,74.82 142.73,75.68 140.32,75.68 137.89,73.26 137.89,69.42 136.65,68.17 135.62,67.14 135.62,64.88 135.11,64.37 135.11,61.62 134.32,60.83 134.32,59.97 133.65,59.3 133.65,57.58 133.26,57.19 133.26,55.4 132.74,54.88 132.74,54.51 133.29,53.96 133.29,52.95 133.04,52.69 133.04,50.72 132.07,49.75 132.07,49.65 130.63,48.21 122.95,48.21 120.99,46.24 120.99,45.4 121.6,44.79 121.64,44.79 123.13,43.3 123.13,43.07 123.71,42.49 v1(123.79,42.49) ; v2(105.54,31.74) 105.54,31.11 104.06,29.63 102.9,29.63 101.63,28.36 96.38,28.36 94.64,30.1 94.63,30.1 93.91,30.82 92.26,30.82 91.7,30.26 82.63,30.26 81.56,31.33 73.6,31.33 72.55,32.38 65.9,32.38 62.6,35.69 62.6,35.69 62.42,35.86 49.04,35.86 45.32,32.14 v2(45.32,31.29)
  BOTTOM w0.102: R80203.1 142.48,74.76 143.26,73.98 v1(143.41,73.98) ; v2(45.32,31.29) v4(45.32,30.38)
AMD_RST#: length 5.4
  TOP w0.102: GPU1.AL27 94.02,108.4 95.19,107.23 96.21,107.23 v3(96.22,107.24) 96.23,107.23 C752.1 R1160.1
AMP_GND: length 15.1
  TOP w0.305: v2(159.13,30.65) 158.84,30.36 U21.4
  TOP w0.381: R344.1 160.1,26.96 R347.1 158.59,27.6 v2(158.58,27.58)
  TOP w0.508: R365.2 163.63,36.22 164.37,35.48 v2(164.37,35.43) 163.7,34.76 R346.1 ; C531.2 158.06,38.4 v2(158.11,38.35) ; v2(156.24,21.84) 156.19,21.79 R1596.1 ; R355.2 v2(160.31,36.2) ; v2(164.5,31.88) 164.46,31.92 R358.2
  TOP w0.635: v2(164.47,29.81) 164.33,29.81 164.28,29.86 163.38,29.86 C192.1 C193.1 ; C208.2 157.67,36.73 158.12,37.19 v2(158.12,37.37)
  BOTTOM w0.635: v4(157.16,37.47) 158.02,37.47 v2(158.12,37.37)
AMP_SPKR_L: length 5.9
  TOP w0.203: C199.1 162.59,33.32 162.59,35.78 v3(162.32,36.06) 161.83,36.54 R355.1 R356.2
AMP_SPKR_R: length 18.5
  TOP w0.203: R367.2 163.63,37.6 164.32,36.92 164.59,36.92 R365.1 165.34,36.17 165.34,32.26 v3(165.32,32.25) 165.34,32.24 165.34,29.54 163.56,27.76 163.1,27.76 159.01,23.67 C210.1
APU_PROCHOT#: length 485.3
  TOP w0.102: v2(12.17,172.5) 12.75,171.92 12.75,171.33 17.13,166.95 v2(17.13,166.9) 18.4,165.63 R1606.1 ; PR4455.1 61.42,70.51 v1(61.87,70.07) ; v1(142.84,73.72) 142.84,74.39 142.76,74.48 142.76,76.36 141.77,77.34 U4101.14
  L3 w0.127: v2(129.47,54.45) 130.68,53.25 130.68,50.97 131.03,50.61 131.03,50.22 130.76,49.95 130.45,49.95 130.39,49.89 130.03,49.89 124.77,44.63 123.87,44.63 122.91,43.66 118.91,43.66 116.75,41.5 114.79,41.5 v2(114.23,40.94) ; v1(50.5,66.45) 50.67,66.61 59.68,66.61 61.87,68.81 v1(61.87,70.07) 60.74,71.2 55.43,71.2 55.25,71.37 53.82,72.81 43.7,72.81 41.07,75.45 41.07,76.87 40.76,77.17 40.76,104.55 37.74,107.57 37.74,119.34 36.39,120.69 36.39,130.4 29.27,137.52 20.48,137.52 15.97,142.03 15.97,152.03 15.25,152.76 15.25,165.02 v2(17.13,166.9)
  L4 w0.127: v1(142.84,73.72) 142.74,73.82 142.74,74.69 141.98,75.45 140.63,75.45 138.27,73.1 138.27,69.26 136.81,67.79 136,66.99 136,64.72 135.36,64.08 135.36,61.51 134.63,60.77 134.63,59.92 134.16,59.45 134.16,55.58 133.68,55.1 133.68,52.79 133.29,52.41 133.29,50.61 132.33,49.65 132.33,49.37 130.79,47.83 123.11,47.83 121.37,46.08 121.37,45.56 121.75,45.17 121.8,45.17 123.54,43.43 123.54,43.2 123.8,42.94 123.98,42.94 124.24,42.68 124.24,42.31 122.21,40.28 114.9,40.28 v2(114.23,40.94) 113.13,42.05 106.29,42.05 103.46,44.88 101.51,44.88 99.36,47.03 64.95,47.03 58.44,53.54 58.44,59.8 57.69,60.55 57.69,62.92 56.59,64.02 56.16,64.02 54.9,65.28 51.7,65.28 50.53,66.45 v1(50.5,66.45) ; v2(12.17,172.5) 12.17,184.57 5.07,191.68 5.07,225.04 6,225.97 80.91,225.97 83.2,223.68 83.2,219.96 82.25,219.01 82.25,213.57 83,212.82 83,211.95 81.8,210.75 v2(81.8,209.88)
  BOTTOM w0.102: PQ4408.D 50.01,65.32 50.5,65.81 v1(50.5,66.45) ; R1604.1 81.86,209.94 v2(81.8,209.88) 81.8,208.52 v4(82.32,208) 83.19,207.13 C313.1 R1258.1 ; R79947.1 129.38,54.54 v2(129.47,54.45)
APU_PROCHOT#_IO: length 3.3
  TOP w0.102: U109.8 130.42,54.74 v2(130.16,54.48)
  BOTTOM w0.102: v4(130.5,53.65) 130.16,53.99 v2(130.16,54.48) 130.27,54.6 R79947.2
APU_PROCHOT#_R: length 32.9
  TOP w0.102: CPU2.AD50 82.54,176.04 v1(82.05,176.53) ; v2(82.35,203.68) 82.35,203.45 82.28,203.38 v3(82.28,197.35) 82.28,196.9 85.5,193.68 v2(85.5,192.41)
  BOTTOM w0.102: v1(82.05,176.53) 82.05,179.12 82.03,179.14 82.03,184.88 83.8,186.64 83.8,188.96 83.8,190.29 85.5,191.99 v2(85.5,192.41) ; v2(82.35,203.68) 82.05,203.99 R1258.2
APU_PWNBTN_N: length 201.6
  TOP w0.102: CPU2.M16 v1(76.03,159.17) ; v2(100.95,71.68) 102.19,71.68 103.69,70.18 R1264.1
  L3 w0.127: v1(122.61,75.26) 123.04,74.83 124.23,74.83 124.51,75.1 124.51,75.65 128.89,80.04 137.8,80.04 138.4,80.64 141.89,80.64 143.33,82.09 144.75,82.09 146.31,83.65 146.31,85.22 146.5,85.41 146.5,86.86 147.38,87.73 147.38,104.27 145.15,106.49 145.15,109.04 144.39,109.8 144.39,110.36 143.52,111.24 143.52,113.81 138.84,118.49 138.21,118.49 137.7,119 136.61,120.09 135.24,121.46 133.51,123.19 123.26,123.19 119.74,126.72 112.26,126.72 111.39,127.58 104.15,127.58 v1(103.59,128.14)
  L4 w0.127: v2(100.95,71.68) 100.37,72.26 100.37,77.05 102.28,78.97 102.99,78.97 103.33,79.3 106.34,79.3 107.39,78.24 111.02,78.24 111.61,78.83 112.1,78.83 112.66,78.27 113.84,78.27 115.11,79.54 117.45,79.54 119.84,77.15 120.72,77.15 v1(122.61,75.26)
  BOTTOM w0.102: v1(76.03,159.17) 75.89,159.17 75.48,158.76 75.24,158.76 74.81,158.33 74.81,158.23 74.15,157.57 72.55,157.57 72.13,157.15 72.13,157.07 71.52,156.46 71.33,156.46 71.07,156.21 70.73,156.21 68.91,154.38 68.91,146.48 72.51,142.88 78.33,142.88 78.66,142.54 79.78,142.54 82.04,140.28 83.43,140.28 90.33,133.38 98.2,133.38 v4(102.68,128.9) 103.43,128.14 v1(103.59,128.14)
APU_PWNBTN_N_R: length 6.2
  TOP w0.102: R56.1 R1264.2 103.36,68.59 103.36,66.78 v2(104.04,66.1) 104.57,65.57 Q18.C
  BOTTOM w0.102: v4(104.05,66.8) 104.04,66.8 v2(104.04,66.1)
APU_SATA_LED_B: length 133.3
  TOP w0.254: R342.2 138.93,13.36 138.13,14.16 137.19,14.16 135.99,12.96 129.51,12.96 129.48,12.99 129.06,12.99 128.5,12.43 v1(128.5,12.31)
  L3 w0.254: v1(23.46,9.67) 23.25,9.46 23.25,3.59 24.25,2.6 84.18,2.6 84.83,3.25 84.83,4.89 85.69,5.75 v1(85.77,5.75)
  L4 w0.254: v1(128.5,12.31) 127.95,12.31 127.67,12.6 119.06,12.6 110.95,4.5 87.03,4.5 v1(85.77,5.75)
  BOTTOM w0.254: v1(23.46,9.67) 23.04,10.1 v4(23.04,10.52) 23.04,11.81 Q37.B
APU_SATA_LED_N: length 206.4
  TOP w0.089: CPU2.AH3 84.46,152.99 84.74,152.7 84.74,152.43 84.67,152.35 84.67,151.23 84.95,150.95
  TOP w0.254: R514.1 141.05,9.75 Q9646.4 140.43,10.31 138.85,11.9 R342.1 139,12.49 139.5,12.99 139.5,21.02 141.26,22.77 141.26,25.81 146.85,31.39 146.85,34.39 147.47,35.01 147.47,37.86 147.12,38.2 147.12,52.27 148.75,53.9 148.75,59.18 158.3,68.73 158.3,83.21 155.12,86.39 155.12,97.61 156.09,98.58 156.09,102.63 152.19,106.53 152.19,115.94 146.57,121.56 120.84,121.56 105.8,136.6 104.6,136.6 102.68,138.53 v3(102.3,138.53) 102.23,138.53 100.72,140.04 100.72,141.22 95.58,146.36 93.15,146.36 92.3,147.21 90.4,147.21 89.21,148.39 89.21,149.13 88.54,149.81 87.84,149.81 86.69,150.95 84.95,150.95
APU_SPKR: length 178.8
  TOP w0.102: CPU2.H4 v1(74.2,153.3) ; v2(159.2,127.1) 158.64,126.54 158.07,126.54 154.16,122.64 154.16,107.33 158.05,103.44 158.05,97.76 157.08,96.79 157.08,87.27 161.04,83.31 161.04,68.57 151.04,58.56 R208.1
  L4 w0.127: v1(74.2,153.3) 74.3,153.2 74.3,152.47 77.8,148.97 81.26,148.97 85.54,144.69 103.09,144.69 108.49,139.29 109.43,139.29 121.72,127 148.35,127 148.39,126.96 148.76,126.96 148.89,127.1 v2(159.2,127.1)
  BOTTOM w0.102: v4(158.68,126.44) 158.68,126.42 159.2,126.94 v2(159.2,127.1)
AUD_BEEP_C: length 4.9
  TOP w0.102: U6.2 155.33,50.57 154.9,51 v3(154.9,51.2) 154.9,51.37 153.26,53.01 C130.2
AUD_BEEP_R: length 4.3
  TOP w0.102: R207.2 151.33,53.47 C130.1 152.36,53.48 v3(152.36,54.46) 152.36,55.31 R210.1 R208.2
AUD_DMIC_CLK: length 7.1
  TOP w0.127: WEBCM1.4 160.75,195.65 v5(161.2,195.2) 160.29,194.3 C121.2 158.6,194.3 L54.2
AUD_DMIC_CLK_R: length 188.8
  TOP w0.127: v2(168,127.86) 167.63,127.86 165.96,129.53 164.11,129.53 162.68,128.09 159.1,128.09 153.8,122.79 153.8,107.17 157.68,103.29 157.68,97.91 156.93,97.16 156.71,96.95 156.71,87.12 160.68,83.16 160.68,68.82 150.53,58.67 150.53,53.02 149.82,52.31 149.35,52.31 147.95,50.91 147.95,44.05 149.58,42.42 v3(151.65,42.42) 152.35,42.42 153.4,43.46 154.54,43.46 156.52,45.44 U6.12 ; v1(157.22,193.42) 156.54,194.09 R212.1
  L4 w0.127: v2(168,127.86) 168,129.16 167.69,129.47 167.69,135.12 167.98,135.41 167.98,145.47 165.55,147.9 165.55,158.95 164.63,159.88 164.63,181.6 158.57,187.66 158.57,192.3 157.45,193.42 v1(157.22,193.42)
AUD_DMIC_CLK_R_1: length 3.1
  TOP w0.127: L54.1 157.6,195.18 R212.2 155.35,193.99 v5(155.35,193.68)
AUD_DMIC_DATA: length 197.2
  TOP w0.127: v5(159.67,196.09) 159.5,196.26 WEBCM1.5 159.5,199.77 158.96,200.31 v1(158.25,200.31) ; R222.1 155.56,41.87 C132.2 154.35,41.87 154.25,41.77 149.69,41.77 147.57,43.89 147.57,52.09 148.71,53.23 149.64,53.23 150.13,53.72 150.13,58.82 160.29,68.98 160.29,83 156.33,86.97 156.33,97.1 156.33,97.1 157.3,98.07 157.3,103.13 153.41,107.02 153.41,122.94 158.94,128.48 162.52,128.48 163.95,129.91 166.2,129.91 167.46,128.64 v2(167.51,128.64)
  L4 w0.127: v2(167.51,128.64) 167.31,128.84 167.31,135.3 167.6,135.59 167.6,145.16 165.07,147.69 165.07,158.72 164.22,159.57 164.22,180.99 156.73,188.49 156.73,198.78 v1(158.25,200.31)
AUD_DMIC_DATA_R: length 3.9
  TOP w0.127: R222.2 155.58,43.61 v3(156.17,44.2) 156.57,44.2 157.35,44.97 U6.13
AUD_DVDD: length 8.1
  TOP w0.203: U6.7 155.9,48.57 155.49,48.16 155.15,48.16 v2(155.1,48.11)
  BOTTOM w0.508: C127.2 156.52,46.99 R205.2 ; C127.2 156.64,46.92 v4(156.64,45.73) 155.51,45.73 R206.2 ; C127.2 156.55,48.09 C131.2 v2(155.1,48.11)
AUD_GP3: length 5.7
  TOP w0.203: R213.2 152.85,51.31 v3(153.66,50.5) 153.99,50.17 U6.3
AUD_LINK_BCLK: length 147.2
  TOP w0.102: U6.5 155.9,49.37 155.79,49.48 155.27,49.48 C126.2 153.83,48.04 v3(153.83,47.4) 153.83,47.26 152.7,46.13 151.39,46.13 v2(150.93,46.58)
  BOTTOM w0.102: RN10.4 114.89,138.48 115.35,138.94 121.22,138.94 v4(125.66,134.49) 129.17,130.99 141.87,130.99 143.97,128.88 143.97,128.14 148.03,124.09 151.38,124.09 152.94,122.53 152.94,119.41 152.24,118.71 152.24,100.03 154.15,98.12 157.88,98.12 162.47,93.54 162.47,90.27 160.56,88.37 160.56,76.89 160.76,76.68 160.76,68.5 147.51,55.24 147.51,48.67 148.9,47.27 150.25,47.27 v2(150.93,46.58)
AUD_LINK_RST_N: length 143.4
  TOP w0.102: U6.6 155.59,48.97 155.58,48.97 v2(155.48,48.97)
  BOTTOM w0.102: RN10.2 122.46,140.18 v4(126.8,135.84) 130.11,132.54 141.32,132.54 144.69,129.18 144.69,128.44 148.31,124.82 151.66,124.82 153.65,122.83 153.65,119.1 152.95,118.4 152.95,100.33 154.45,98.83 158.18,98.83 163.18,93.83 163.18,89.97 161.27,88.06 161.27,77.19 161.48,76.99 161.48,68.2 148.22,54.94 148.22,50.85 149.61,49.45 151.75,49.45 151.83,49.53 154.07,49.53 R314.1 155.46,48.95 v2(155.48,48.97)
AUD_LINK_RST_N_2: length 4.7
  BOTTOM w0.102: v4(147.02,41.05) 148.12,39.95 Q63.6 148.84,39.74 149.08,39.5 149.08,38.68 148.84,38.44 Q63.4
AUD_LINK_RST_N_R: length 6.1
  BOTTOM w0.102: R314.2 153.68,49.03 C170.1 152.2,48.99 151.72,48.51 151.72,47.77 152.17,47.32 v4(152.17,47.11) 152.06,46.99 151.57,46.99 150.93,47.63 Q6711.B
AUD_LINK_SDIN: length 185.2
  TOP w0.102: v2(149.99,46.56) 150.27,46.56 151.38,45.44 R209.1 ; CPU2.AD7 v1(82.05,154.89)
  BOTTOM w0.102: v2(149.99,46.56) 149.77,46.79 148.7,46.79 147.02,48.47 147.02,55.58 160.28,68.83 160.28,75.9 160.08,76.1 160.08,88.57 161.98,90.47 161.98,93.34 157.68,97.64 153.93,97.64 151.75,99.83 151.75,114 151.09,114.65 151.09,115.05 151.36,115.32 151.43,115.32 151.75,115.64 151.75,118.9 152.46,119.61 152.46,122.33 151.2,123.6 147.77,123.6 143.49,127.88 143.49,128.68 141.67,130.51 136.74,130.51 136.71,130.53 128.79,130.53 v4(123.53,135.79) 121.78,137.54 108.75,137.54 108.36,137.92 107.86,137.92 105.78,140 105.74,140 101.94,143.8 88.39,143.8 88.36,143.83 86.97,143.83 86.67,143.54 83.47,143.54 83.21,143.79 82.79,144.22 81.41,145.59 81.41,151.89 81.46,151.93 81.46,154.31 v1(82.05,154.89)
AUD_LINK_SDIN_1: length 4.9
  TOP w0.102: U6.8 155.97,48.17 155.68,47.88 155.65,47.88 154.44,46.67 154.44,46.63 v3(153.75,45.95) 153.25,45.44 R209.2
AUD_LINK_SDO: length 141.2
  TOP w0.102: Q56.D 149.65,47.85 C1780.1 150.41,50.01 R618.2 149.28,50.19 148.85,49.76 v2(148.85,49.56)
  BOTTOM w0.102: v2(148.85,49.56) 147.99,50.42 147.99,55.04 161.25,68.3 161.25,76.89 161.04,77.09 161.04,88.16 162.95,90.07 162.95,93.74 158.08,98.6 154.35,98.6 152.73,100.23 152.73,118.5 153.43,119.2 153.43,122.73 151.57,124.59 148.21,124.59 144.46,128.34 144.46,129.08 141.38,132.16 129.22,132.16 v4(127.62,133.76) 121.96,139.42 115.15,139.42 115.1,139.37 RN10.3
AUD_LINK_SDO_1: length 5.8
  TOP w0.102: R617.2 148.93,46.58 v3(148.98,46.63) 148.95,46.66 C1780.2 149.17,47.66 149.69,47.14 151.16,47.14 151.44,46.87 Q56.G
AUD_LINK_SDO_N: length 6.9
  TOP w0.102: U6.4 154.77,49.77 154.73,49.73 153.21,49.73 Q56.S 152.32,50.08 v3(152.33,50.09) 152.23,50.19 R618.1
AUD_LINK_SYNC: length 151.9
  TOP w0.102: U6.9 156.03,47.77 155.91,47.65 155.74,47.65 154.67,46.57 154.67,46.07 153.58,44.98 150.71,44.98 149.53,43.81 148.75,43.81 148.32,44.25 148.32,50.09 v2(148.98,50.75)
  BOTTOM w0.102: RN10.1 122.69,141.07 v4(128.94,134.82) 130.89,132.87 141.32,132.87 144.97,129.22 144.97,129.15 148.99,125.12 151.68,125.12 153.88,122.92 153.88,119 153.24,118.36 153.24,100.36 154.54,99.06 158.27,99.06 163.41,93.93 163.41,89.87 161.5,87.96 161.5,77.32 161.7,77.11 161.7,68.1 148.45,54.85 148.45,51.31 148.98,50.77 v2(148.98,50.75)
AUD_REGREF: length 5.8
  TOP w0.203: C129.2 153.83,44.22 v3(153.91,44.3) 154.67,45.06 154.67,45.07 155.12,45.51 155.12,46.56 155.93,47.37 U6.10
AZ_BCLK_M: length 42.6
  TOP w0.102: CPU2.AD9 v1(82.05,155.6)
  BOTTOM w0.102: v1(82.05,155.6) 82.45,155.2 82.45,153.09 81.69,152.33 81.69,151.88 81.62,151.8 81.62,147 84.86,143.76 86.09,143.76 v4(86.55,144.22) 86.65,144.32 102.1,144.32 107.94,138.48 RN10.5
AZ_RST_N_M: length 44.9
  TOP w0.102: CPU2.AF13 v1(83.95,158.45)
  BOTTOM w0.089: 83.1,155.12 83.41,155.43 83.41,157.76 83.95,158.3 v1(83.95,158.45)
  BOTTOM w0.102: RN10.7 107.25,140.18 101.4,146.02 93.3,146.02 92.77,145.49 90.88,145.49 v4(90.82,145.43) 90.77,145.43 90.38,145.03 84.2,145.03 82.02,147.21 82.02,151.63 82.1,151.71 82.1,152.16 82.96,153.02 82.96,153.16 82.97,153.17 82.97,154.99 83.1,155.12
AZ_SDOUT_M: length 47.2
  TOP w0.102: CPU2.AF14 v1(83.95,159.16)
  BOTTOM w0.089: v1(83.95,159.16) 83.55,158.76 83.55,158.18 83.22,157.85 83.22,155.53 82.9,155.21
  BOTTOM w0.102: RN10.6 107.74,139.37 101.89,145.21 92.77,145.21 v4(92.41,144.86) 92.39,144.83 84.11,144.83 81.82,147.12 81.82,151.72 81.9,151.79 81.9,152.25 82.76,153.11 82.76,155.07 82.9,155.21 ; C86.1 84.74,158.37 v1(83.95,159.16)
AZ_SYNC_M: length 44
  TOP w0.102: v1(83.95,157.74) 83.6,157.38 CPU2.AF12
  BOTTOM w0.089: v1(83.95,157.74) 83.6,157.39 83.6,155.28 83.17,154.85
  BOTTOM w0.102: RN10.8 109,141.07 103.16,146.91 93.43,146.91 92.65,146.13 v4(92.34,146.13) 90.44,146.13 89.54,145.24 84.28,145.24 82.23,147.29 82.23,151.55 82.3,151.63 82.3,152.08 83.17,152.95 83.17,154.85
BAT_ALERT: length 4.8
  TOP w0.102: BAT2.8B 33.07,60.39 33.93,61.25 v2(33.93,61.3)
  BOTTOM w0.102: R79665.2 32.91,60.17 32.91,60.18 v4(32.91,60.22) 33.93,61.23 v2(33.93,61.3)
BAT_IN#: length 190.5
  TOP w0.102: R80209.1 113.13,48.21 R1868.1 113.99,47 113.7,46.71 110.96,46.71 109.41,45.15 109.41,41.65 106.74,38.98 v1(105.94,38.98) ; U4101.5 145.37,74.48 143.88,72.99 v1(143.41,72.99)
  L3 w0.127: v2(33.89,64.59) 31.87,62.58 31.87,55.75 34.65,52.97 34.65,52.37 36.1,50.91 57.55,50.91 61.34,47.12 82.08,47.12 89.54,39.66 94.23,39.66 v1(96.4,41.83)
  L4 w0.127: v1(96.4,41.83) 96.44,41.8 99.36,41.8 99.72,42.16 101.92,42.16 105.1,38.98 v1(105.94,38.98) 106.37,38.98 106.98,38.37 106.98,38.1 110.96,34.12 116.37,34.12 117.84,35.6 124.99,35.6 128.12,38.72 128.12,40.28 129.76,41.92 130.2,41.92 131.82,43.55 133.24,43.55 134.83,45.14 134.83,48.53 135.45,49.15 135.45,50.79 136.09,51.42 136.09,52.98 135.59,53.47 135.59,54.28 135.94,54.62 135.94,58.04 135.83,58.15 135.83,59.15 136.02,59.34 136.02,60.13 136.76,60.87 136.76,61.87 138.17,63.28 138.17,65.01 138.68,65.52 138.68,67.55 139.49,68.36 139.49,72.44 141.21,74.16 141.56,74.16 141.8,73.91 141.8,73.59 142.4,72.99 v1(143.41,72.99)
  BOTTOM w0.102: R79942.1 32.14,65.99 v4(33,66.85) 33.3,66.55 33.3,65.43 33.89,64.84 v2(33.89,64.59)
BAT_IN#_1: length 6.8
  TOP w0.102: v2(33.87,63.39) 33.86,63.39 BAT2.6B
  BOTTOM w0.102: v2(33.87,63.39) 33.56,63.08 33.56,62.48 33.24,62.16 PC4304.1 PL4301.1 v4(33.03,64.13) 33.03,64.21 32.32,64.92 R79942.2
BAT_IN#_ECIO: length 5.2
  TOP w0.127: R80209.2 115.02,49.44 117.8,49.44 118.01,49.65 U109.98
BATA_SCL_1: length 19.1
  TOP w0.102: BAT2.4B v2(33.87,66.39)
  BOTTOM w0.102: v2(33.87,66.39) 33.87,66.9 35.05,68.08 43.44,68.08 43.98,68.61 43.98,70.88 v4(44.49,71.39) 44.51,71.42 PC4305.1 46.39,71.42 PL4302.1 46.41,71.43 R79940.2
BATA_SDA_1: length 18.9
  TOP w0.102: v2(33.89,65.52) 33.89,65.5 33.28,64.89 BAT2.5B
  BOTTOM w0.102: R79941.2 47.42,70.4 PL4303.1 45.46,70.4 PC4301.1 45.14,70.39 v4(44.5,69.75) 44.5,68.45 43.61,67.56 35.22,67.56 34.38,66.73 34.38,66.01 v2(33.89,65.52)
BATT_AMBER_LED#: length 6.8
  TOP w0.102: U4101.9 143.77,79.33 143.9,79.46 143.9,81.68 142.53,83.06 v3(142.17,83.06) 141.64,83.06 R80122.2
BATT_AMBER_LED#_C: length 190.3
  TOP w0.102: R80122.1 141.13,81.28 140.72,80.87 140.72,77.65 142.55,75.82 142.55,74.26 142.22,73.93 v1(142.22,73.76) ; v1(26.53,12.18) 26.53,13.59 v3(26.42,13.69) 26.04,14.07 26.04,14.73 25.84,14.93 25.84,16.89 25.57,17.16 25.57,19.03 25.69,19.15 28.3,19.15 29.4,20.25 PWRCN1.10
  L3 w0.127: v1(108.43,33.79) 108.43,37.05 113.6,42.21 116.54,42.21 118.37,44.04 122.74,44.04 123.89,45.19 124.7,45.19 v1(124.72,45.2)
  L4 w0.127: v1(26.53,12.18) 26.55,12.2 26.55,13.51 27.08,14.05 27.45,14.05 28.95,15.54 28.95,16.5 29.23,16.78 30.48,16.78 31.19,17.49 37.39,17.49 44.17,24.27 44.17,27.83 47.09,30.76 47.09,31.75 49.53,34.19 61.68,34.19 65.11,30.76 71.76,30.76 72.72,29.81 80.74,29.81 81.81,28.74 93.75,28.74 95.65,26.83 102.27,26.83 103.3,27.86 104.45,27.86 107.22,30.63 107.22,32.58 v1(108.43,33.79) ; v1(142.22,73.76) 142.36,73.9 142.36,74.75 141.89,75.22 140.94,75.22 138.66,72.94 138.66,69.1 136.96,67.41 136.38,66.83 136.38,64.56 135.62,63.8 135.62,61.41 134.88,60.67 134.88,59.81 134.46,59.39 134.46,56.61 134.54,56.53 134.54,55.42 134.06,54.94 134.06,52.63 133.68,52.25 133.68,49.67 132.69,48.68 132.64,48.68 131.38,47.42 126.93,47.42 v1(124.72,45.2)
  BOTTOM w0.102: v1(142.22,73.76) 142.05,73.59 v4(142.05,72.99) ; R79754.2 26.53,11.94 26.55,11.96 26.53,11.96 v1(26.53,12.18)
BATT_WHITE_LED#: length 3.6
  TOP w0.102: v3(150.93,75.03) 150.93,74.62 150.44,74.13 R80123.2 149.75,74.13 149.05,74.83 148.71,74.83 148.7,74.84 U4101.58
BATT_WHITE_LED#_C: length 231.1
  TOP w0.102: v1(147.84,66.17) 147.84,64.9 144.58,61.65 144.58,56 143.21,54.63 143.21,51.59 v1(142.36,50.73) ; R80123.1 149.99,72.85 v1(149.99,72.44) ; PWRCN1.8 29.05,21.25 28.89,21.41 23.94,21.41 v2(23.68,21.15) 23.68,21.01 22.54,19.86 22.54,17.48 22.87,17.14 R80124.2 22.28,15.42 v3(22.28,14.53)
  L3 w0.127: v1(142.36,50.73) 140.61,48.99 140.61,43.41 141.49,42.53 141.49,26.67 136.93,22.11 136.93,16.26 134.64,13.98 134.64,9.69 135.12,9.21 135.12,8.32 134.49,7.68 116.73,7.68 v1(116.49,7.44)
  L4 w0.127: v1(147.84,66.17) 147.91,66.17 148.65,66.91 148.65,70.08 149.77,71.2 149.77,72.21 v1(149.99,72.44) ; v1(116.49,7.44) 116.49,7.42 112.42,3.34 27.94,3.34 26.53,4.75 26.12,4.75 23.91,6.96 23.91,9.86 23.29,10.47 23.29,14.7 24.59,16 24.59,19.79 24,20.38 23.68,20.7 v2(23.68,21.15)
  BOTTOM w0.102: Q38.C 22.98,16.27 23.5,15.75 26.18,15.75 Q36.C 27.62,17.18 27.62,19.37 27.12,19.86 24.97,19.86 24.38,20.45 v2(23.68,21.15) ; v4(150.27,73.32) 149.99,73.04 v1(149.99,72.44)
BIST_DISABLE: length 101.8
  TOP w0.102: R531.2 63.29,77.9 R79670.1 R533.1 61.55,76.09 55.89,76.09 55.68,76.29 v3(55.09,76.29) 54.88,76.29 v2(54.07,75.48) ; v2(122.54,52.2) 122.68,52.2 123.61,51.26 U109.112
  L3 w0.127: v2(54.07,75.48) 54.25,75.48 56.88,72.85 88.48,72.85 95.49,65.84 95.49,52.89 99.22,49.16 103.98,49.16 104.4,49.58 113.91,49.58 114.25,49.92 120.26,49.92 v2(122.54,52.2)
BIST_DISABLE_1: length 2.9
  TOP w0.102: Q12.5 61.47,77.9 R79670.2 61.5,78.84 v3(61.68,79.02)
BIST_EN: length 10
  TOP w0.102: Q13.2 52.66,77.85 R79683.2 53.07,77.19 53.37,76.89 v3(56.27,76.89) 56.9,76.89 57.26,77.25 Q12.3 58.64,77.25 58.86,77.47 58.86,78.05 59.35,78.55 Q12.6
BIST_EN_INV: length 146.1
  TOP w0.102: v2(33.56,91.26) 33.56,90.92 33.97,90.52 33.97,88.93 39.17,83.72 39.17,82.19 41.72,79.64 49,79.64 49.37,80.01 v3(50.71,80.01) 50.78,80.01 51.79,79.01 v1(52.29,79.01) 52.31,78.99 52.61,78.99 R517.2 53.03,78.5 Q13.3 50.72,78.5 50.4,78.18 50.4,77.62 49.98,77.2 Q13.6 ; v1(139.05,61.89) 138.93,62 R80235.1
  L3 w0.127: v1(119.5,79.88) 119.15,80.24 113.05,80.24 111.34,78.52 111.34,78.42 111.07,78.16 107.93,78.16 106.85,79.24 103.68,79.24 97.89,73.44 93.75,73.44 92.24,74.96 92.03,74.96 89.85,77.14 87.42,77.14 86.18,75.9 59.6,75.9 55.86,79.64 54.48,79.64 53.84,79.01 v1(52.29,79.01)
  L4 w0.127: v1(126.26,67.96) 126.26,75.39 125.08,76.57 123.56,76.57 121.07,79.06 120.33,79.06 v1(119.5,79.88)
  BOTTOM w0.102: U126.2 34.22,92.7 34.09,92.57 34.09,91.59 33.76,91.26 v2(33.56,91.26) 32.96,91.26 31.97,90.28 R79681.1 ; v1(126.26,67.96) 126.26,68.43 127.01,69.18 133.09,69.18 134.12,68.15 134.12,67.56 139.08,62.6 139.08,61.92 v1(139.05,61.89)
BIST_EN_SIO: length 5.9
  TOP w0.102: R80235.2 136.08,62 135.95,61.87 135.2,61.87 R311.1 134.69,62.33 133.62,61.26 132.82,61.26 132.55,61.54 U109.25
BIST_ENABLE: length 101.7
  TOP w0.102: v2(123.4,52.2) 123.4,52.13 124.01,51.52 U109.113 ; v3(45.24,76.3) 46.16,76.3 v2(46.18,76.28) 46.64,76.73 R515.1
  L3 w0.127: v2(46.18,76.28) 46.24,76.23 48.83,76.23 49.99,75.06 50,75.06 50.22,74.84 53.77,74.84 54.17,74.44 56.01,72.59 88.37,72.59 95.23,65.73 95.23,52.79 99.11,48.91 104.11,48.91 104.5,49.3 113.99,49.3 114.35,49.66 120.69,49.66 123.22,52.2 v2(123.4,52.2)
BIST_ENABLE_1: length 5.6
  TOP w0.102: Q13.5 48.06,77.85 R523.1 R515.2 48.85,76.73 v3(49.79,75.79) 49.84,75.74 R79687.2
BIST_PIN25: length 171
  TOP w0.102: v1(132.81,60.6) 132.81,60.92 132.59,61.14 U109.24 129.17,61.14 127.95,59.92 v1(127.95,55.93)
  L3 w0.127: v1(120.35,42.72) 120.44,42.63 122.86,42.63 123.13,42.91 123.13,43.35 124.03,44.25 125.19,44.25 125.35,44.41 130.64,49.69 130.86,49.69 131.29,50.12 131.29,50.72 130.93,51.07 130.93,53.35 130.63,53.66 130.63,54.68 130.34,54.97 128.91,54.97 v1(127.95,55.93)
  L4 w0.127: v1(120.35,42.72) 118.99,44.08 118.99,46.81 117.83,47.97 108.78,47.97 107.54,46.74 105.05,46.74 96.81,54.98 96.81,63.17 84.16,75.82 74.62,75.82 71.21,79.24 58.61,79.24 58.13,78.75 57.37,78.75 v1(56.95,79.17)
  BOTTOM w0.102: v1(56.95,79.17) 56.77,79.17 v4(55.71,80.23) 53.09,82.85 46.96,82.85 45.63,84.19 45.63,93.24 45.28,93.59 45.28,99.71 45.8,100.23 45.8,114.3 46.48,114.97 46.48,116.76 46.18,117.06 46.16,117.06 45.18,118.03 Q9650.G ; v1(132.81,60.6) 132.88,60.6 133.78,59.7 R286.1 133.78,57.9 v4(134.02,57.66)
BKLT_ADJ: length 4.2
  BOTTOM w0.165: C87.1 38.64,25.46 R133.2 40.08,25.46 v4(40.64,26.02) ; C87.1 C33.1 ; C87.1 R79621.2
BKLT_EN: length 9
  TOP w0.127: R139.2 39.61,25.84 Q6710.C 41.24,25.91 C88.1 R138.2 41.24,28.47 41.93,29.16 42.79,29.16 v3(42.85,29.22) 42.85,29.66 42.33,30.19 R79625.2
BKLT_EN1: length 2.9
  TOP w0.127: Q6710.B 39.51,24.63 v3(38.79,24.63) 38.58,24.83 R135.2
BOARD1: length 12.8
  TOP w0.102: CPU2.AH7 v1(84.94,154.89)
  BOTTOM w0.089: v1(84.94,154.89) 85.53,154.3 85.53,153.3 85.66,153.17
  BOTTOM w0.102: R557.1 91.6,148.98 R561.2 91.32,149.26 91.15,149.43 86.9,149.43 v4(86.34,149.99) 86.34,149.99 85.86,150.47 85.86,152.97 85.66,153.17
BOARD2: length 7.6
  TOP w0.102: v1(83.95,154.18) CPU2.AH6
  BOTTOM w0.102: v1(83.95,154.18) 83.47,153.7 v4(83.47,152.53) 83.37,152.43 83.37,150.94 R552.1 82.51,150.08 82.51,148.6 R554.2
BOARD3: length 15.1
  TOP w0.102: R556.2 91.21,148.41 91.01,148.21 v1(91.01,148.09) ; CPU2.AF7 83.95,155.6 v1(84.03,155.6)
  L4 w0.127: v1(84.03,155.6) 84.03,155.43 84.42,155.04 84.42,153.4 89.23,148.59 90.39,148.59 90.9,148.09 v1(91.01,148.09)
  BOTTOM w0.102: R553.1 91.16,147.2 v4(91.96,148) 91.27,148 91.24,148.03 91.07,148.03 v1(91.01,148.09)
BOOT1_PHASE1: length 2.7
  TOP w0.254: v3(131.5,89.22) 132.66,89.22 132.67,89.23 PC19.2 PR43.2
BQ24737_CSON_1: length 20.1
  TOP w0.381: 44.37,60.88 43.71,60.88 42.45,62.14 42.45,64.71 41.39,65.77 PG4908.1 ; 44.37,60.88 v3(44.37,61.15) ; 44.37,60.88 45.44,60.88 46.26,60.06 48.72,60.06 49.54,59.23 49.62,59.16 50.33,58.45 50.33,57.3 49.44,56.41 49.44,56.04 PC5236.2 49.29,55.09 49.29,54.59 PR5277.2 50.48,54.44 PC5238.1
BQ24737_CSOP_1: length 18
  TOP w0.381: PG4906.1 41.69,64.76 41.94,64.5 41.94,61.93 43.5,60.38 43.92,60.38 45.23,60.38 46.05,59.55 47.25,59.55 ; 47.25,59.55 48.51,59.55 49.19,58.87 49.82,58.24 49.82,57.51 48.93,56.62 48.93,56.25 PC5236.1 48.59,55.36 48.59,54.82 PR5283.2 ; 47.25,59.55 v3(47.25,59.27)
BQ24737_REGN: length 26.8
  TOP w0.508: PD4401.A 44.68,54.93 PC5233.2 44.69,55.05 45.13,55.5 v2(45.5,55.5)
  L4 w0.508: v2(45.5,55.5) 45.5,55.14 46.51,54.13 51.95,54.13 52.76,54.94 52.76,58.95 51.37,60.34 51.32,60.34 50.17,61.49 50.17,61.54 49.82,61.89 v1(47.32,61.89)
  BOTTOM w0.305: v2(45.5,55.5) 45.73,55.5 46.62,56.39 U55.16
  BOTTOM w0.508: PR5297.1 46.65,62.56 v1(47.32,61.89) ; v2(45.5,55.5) 45.5,54.95 45.07,54.52 v4(45.06,54.52)
BT+: length 2.3
  TOP w0.305: PG4908.2 40.34,66.86 v3(40.29,66.9) 40.25,66.94 39.14,66.94 39.12,66.93
BT+_R:
  vias: v3(39.49,62.45) v6(35.41,63.52) v6(36.28,63.53) v6(37.16,63.51) v6(38.03,63.49) v6(38.89,63.51) v6(39.77,63.52)
BUZZER_SPKR_R: length 26.1
  TOP w0.102: v2(162.09,34.8) 161.45,34.16 C203.1 ; v2(153.6,51.59) 153.35,51.59 v3(152.53,52.4) 152.34,52.59 R207.1
  L4 w0.127: v2(162.09,34.8) 161.96,34.67 161.07,34.67 159.16,36.58 157.69,36.58 156.8,37.47 156.8,48.97 154.19,51.59 v2(153.6,51.59)
BVCCRTC_EXTPAD: length 4.6
  TOP w0.102: CPU2.F16 v1(73.18,159.17)
  BOTTOM w0.089: v1(73.18,159.17) 72.78,158.77 71.81,158.77 v4(71.8,158.78)
  BOTTOM w0.102: 69.89,157.51 70.24,157.85 70.71,157.85 71.64,158.78 v4(71.8,158.78)
C_GPP_TXN2: length 14.7
  TOP w0.089: 70.14,164.57 70.16,164.57 70.16,164.56 70.18,164.56 70.21,164.52 70.22,164.52 70.43,164.31 71.35,164.31 71.45,164.22 71.69,164.22 72,164.52 CPU2.C26
  TOP w0.102: 70.14,164.57 68,164.57 62.15,170.42 60.74,170.42 C56.1
C_GPP_TXP2: length 14.9
  TOP w0.089: 70.14,164.78 70.15,164.78 70.17,164.76 70.22,164.76 70.24,164.75 70.25,164.75 70.29,164.71 70.3,164.71 70.35,164.66 70.5,164.51 CPU2.B26
  TOP w0.102: 61.53,170.64 60.73,170.64 C54.1 ; 61.53,170.64 62.24,170.64 62.45,170.42 62.61,170.42 62.83,170.21 62.83,170.05 63.04,169.83 63.2,169.83 63.42,169.62 63.42,169.46 63.63,169.24 63.79,169.24 64,169.03 64,168.87 65.64,167.23 65.64,167.23 65.86,167.02 66.01,167.02 66.23,166.8 66.23,166.64 66.45,166.43 66.6,166.43 66.82,166.21 66.82,166.06 67.03,165.84 67.19,165.84 67.41,165.62 67.41,165.47 68.09,164.78 68.4,164.78 68.51,164.89 68.81,164.89 68.93,164.78 70.14,164.78 ; 61.53,170.64 v3(61.53,170.99)
CAGND: length 28.3
  L3 w0.508: v1(36.81,22.96) 38.08,22.96 39.33,24.21 39.33,29.51 v2(40.17,30.35)
  BOTTOM w0.305: U120.15 31.93,30.72 v1(32.93,29.72)
  BOTTOM w0.508: R79623.2 38.99,27.84 38.99,28.62 C4270.2 C3457.2 39.66,29.84 v2(40.17,30.35) ; R82.2 30.63,21.85 31.3,22.52 31.3,22.83 ; 31.3,22.83 31.81,22.33 32.62,22.33 34.07,23.78 R79628.2 C3455.2 36,23.86 R61.2 36.81,23.1 v1(36.81,22.96) ; 31.3,22.83 C5.2 ; C4.1 39.91,33.27 v2(39.91,33.3) ; v2(35.64,33.12) 35.64,33.2 36.41,33.96 C10.2
  vias: v1(32.16,29.74) v1(32.93,30.48) v1(32.95,29.01) v1(33.69,29.69) v3(34.74,29.83) v3(37.77,32.19)
CASA0#: length 44.7
  TOP w0.127: GPU1.G19 75.78,102.18 v1(75.78,102.59) ; v1(63.81,103.04) 63.14,102.37 v3(62.51,102.37) ; MEM1.K3 53.78,110.48 53.65,110.61 53.65,110.8 53.78,110.93 54.48,110.93 54.68,110.74 54.68,110.74 54.8,110.62 v1(54.8,110.44)
  L3 w0.102: v1(75.78,102.59) 75.3,103.08 74.78,103.08 74.31,103.55 73.97,103.55 73.79,103.36 73.67,103.36
  L3 w0.165: v1(63.81,103.04) 63.89,102.96 64.91,102.96 65.03,103.09 65.03,103.29 65.16,103.41 66.4,103.41 66.53,103.29 66.53,103.08 66.65,102.95 67.17,102.95 67.3,103.08 67.3,103.24 67.42,103.36 71.62,103.36 71.76,103.23 71.76,102.89 71.9,102.75 73,102.75 73.13,102.87 73.13,103.24 73.26,103.36 73.67,103.36
  L4 w0.165: v1(54.8,110.44) 54.95,110.59 55.67,110.59 55.74,110.52 56.65,110.52 57.53,109.64 58.65,109.64 58.89,109.89 60.84,109.89 62.62,108.11 62.62,105.8 62.74,105.67 63.94,105.67 64.06,105.54 64.06,105.14 63.94,105.01 62.74,105.01 62.62,104.88 62.62,104.48 62.74,104.35 63.96,104.35 64.09,104.22 64.09,103.82 63.96,103.69 62.74,103.69 62.62,103.56 62.62,101.76 62.74,101.63 63.68,101.63 63.81,101.76 v1(63.81,103.04)
  BOTTOM w0.127: MEM3.K3 55.79,110.48 55.69,110.58 54.94,110.58 v1(54.8,110.44)
CASA1#: length 43.4
  TOP w0.127: v1(77.37,95.25) 77.37,96.04 77.5,96.17 77.73,96.17 77.83,96.27 77.83,96.52 77.71,96.65 77.5,96.65 77.37,96.78 77.37,97.13 76.99,97.52 76.99,97.65 76.54,98.09 76.54,98.34 76.29,98.59 76.29,98.78 75.68,99.4 GPU1.G16 ; MEM2.K3 57.1,92.7 55.41,92.7 v1(54.95,92.24)
  L3 w0.165: v2(60.67,97.84) 60.67,97.38 61,97.05 61.39,97.05 61.91,96.53 61.91,96.14 62.17,95.88 67.19,95.88 67.54,95.54 68.66,95.54 68.85,95.73 72.55,95.73 72.85,95.43 74.48,95.43 75.04,94.87 75.84,94.87 76.1,95.12 76.1,95.86 76.22,95.99 76.88,95.99 77.37,95.5 v1(77.37,95.25)
  L4 w0.102: 55.9,93.49 55.9,93.75 56.06,93.91 59.76,93.91
  L4 w0.165: v2(60.67,97.84) 61.09,97.84 61.22,97.71 61.22,97.16 61.09,97.04 60.75,97.04 60.62,96.91 60.62,96.29 61.25,95.66 61.25,94.25 60.9,93.91 59.76,93.91 ; 55.9,93.49 55.3,92.89 55.3,92.59 v1(54.95,92.24)
  BOTTOM w0.127: MEM4.K3 54.06,92.87 54.23,92.87 54.33,92.77 54.33,92.62 54.48,92.48 54.48,92 54.63,91.84 54.84,91.84 54.95,91.95 v1(54.95,92.24) ; v2(60.67,97.84) 60.67,97.84 61.08,98.24 v4(61.38,98.24)
CBN: length 3.7
  TOP w0.203: v2(160.51,44.65) 160.55,44.69 U6.21
  BOTTOM w0.635: v2(160.51,44.65) 160.32,44.65 v4(159.48,45.49) 159.76,45.77 C150.2
CBP: length 4.1
  TOP w0.203: v2(162.14,44.7) 161.74,45.09 U6.24
  BOTTOM w0.635: v2(162.14,44.7) 162.98,45.55 v4(162.98,45.75) 162.97,45.77 C150.1
CFG: length 7.3
  TOP w0.127: U127.23 v2(129.2,36.57) ; R79748.2 128.33,40.65 128.33,39.8 v1(129.57,38.56)
  L3 w0.127: v1(129.57,38.56) 129.2,38.18 v2(129.2,36.57)
  BOTTOM w0.127: v2(129.2,36.57) 129.2,36.88 v4(128.79,37.29)
CHAR_CTL1: length 5.7
  TOP w0.102: U9625.6 145.22,109.41 145.78,108.85 v3(145.78,107.47) 145.78,106.28 R80063.1
CHAR_CTL2: length 4.4
  TOP w0.102: U9625.7 145.72,109.43 v3(146.71,108.45) 146.99,108.16 R80064.1
CHAR_CTL3: length 3.1
  TOP w0.102: R80065.1 146.93,109.36 v3(146.49,109.79) 146.22,110.07 U9625.8
CHAR_EN: length 77.3
  TOP w0.102: v1(84.16,126.19) 84.36,126.39 84.36,126.41 85.12,127.17 Q9643.3 ; v1(141.25,107.48) 141.4,107.34 144.74,107.34 145.12,107.72 145.12,108.78 144.56,109.33 R80062.1 144.72,109.52 U9625.5
  L3 w0.127: v1(141.25,107.48) 140.78,107.48 139,109.27 138.45,109.27 137.58,110.13 137.58,113.08 134.56,116.1 134.55,116.1 132.39,118.26 132.36,118.26 131.98,118.65 121.88,118.65 118,122.53 105.31,122.53 105.14,122.71 97.87,122.71 97.82,122.66 87.82,122.66 84.28,126.19 v1(84.16,126.19)
  BOTTOM w0.102: v1(141.25,107.48) 141.92,107.48 v4(142.06,107.63)
CHAR_EN_CPU: length 49.4
  TOP w0.089: 82.6,151.34 82.56,151.38 82.56,151.73 82.7,151.87 82.7,152.34 82.8,152.43 82.8,152.71 82.7,152.81 82.7,152.93 arc(82.71,153) 82.73,153.07 82.77,153.13 82.92,153.3 83,153.46 CPU2.AE4
  TOP w0.102: Q9643.2 85.77,129.04 87.51,130.78 88.2,130.78 90.89,133.48 90.89,135.06 91.34,135.51 92.12,135.51 93.54,134.09 95.93,134.09 v1(98.55,136.71) ; R1795.1 88.02,141.69 v1(88.02,142.1) 88.02,142.44 86.85,143.61 86.85,144.81 86.6,145.06 86.6,146.16 84.62,148.14 v3(84.45,148.14) 84.45,148.67 84.26,148.86 84.02,149.1 84.02,149.1 82.96,150.15 82.96,150.98 82.6,151.34
  L3 w0.127: v1(98.55,136.71) 98.55,139.68 96.83,141.4 90.43,141.4 89.74,142.1 v1(88.02,142.1)
CHAR_ILIM_HI: length 1.8
  TOP w0.102: U9625.16 144.72,115.42 R80049.1
CHAR_ILIM_LO: length 2.5
  TOP w0.102: U9625.15 145.22,115.76 145.22,115.76 v3(145.22,115.87) 145.22,116.19 145.19,116.21 R80060.1
CHAR_ILIM_SEL: length 4.1
  TOP w0.102: U9625.4 143.92,110.06 v3(143.32,109.46) 143.03,109.17 R80059.1
CHAR_STATUS: length 3.4
  TOP w0.102: TP4118.1 149.54,110.66 148.1,112.09 U9625.9
CHAR_USBOC#: length 3.2
  TOP w0.102: R80061.1 146.88,116.19 v3(147.23,115.85) 147.23,115.54 147.1,115.42 146.79,115.42 146.22,114.84 U9625.13
CHG_AGND: length 60.8
  TOP w0.305: 49.74,66.52 50.43,67.21 PQ5006.4 49.96,67.27 49.64,67.59 49.64,67.94 49.01,68.57 PQ5006.1
  TOP w0.356: 49.44,69.46 PQ5006.1
  TOP w0.508: v1(56.32,66.04) 56.17,66.19 56.17,68.07 54.77,69.46 49.44,69.46 ; PR5274.2 46.83,66.54 v2(46.9,66.47) ; v2(50.29,52.49) 50.49,52.7 PC5238.2 ; 49.74,66.52 49.56,66.34 PR5468.2 ; v1(43.64,62.79) 43.29,63.14 PC4404.2 PC4403.2 ; v2(55.1,61.72) 54.14,60.76 54.14,58.88 54.49,58.52 v2(54.49,57.11) 54.49,57.02 54.52,57 54.52,53.92 v2(54.55,53.89)
  L3 w0.508: v2(55.1,61.72) 55.1,64.23 56.33,65.45 56.33,66.03 v1(56.32,66.04) 56.01,66.04 55.38,65.41 48.08,65.41 47.78,65.71 47.66,65.71 v2(46.9,66.47) ; v2(54.55,53.89) 51.68,53.89 v2(50.29,52.49)
  BOTTOM w0.305: PR5268.2 54.24,56.83 54.49,57.09 v2(54.49,57.11)
  BOTTOM w0.508: v2(46.9,66.47) 45.55,66.47 44.26,65.17 44.26,63.4 v1(43.64,62.79) 43.57,62.71 PC4408.2 ; v2(54.55,53.89) 54.76,54.09 v4(55.7,54.09) ; v2(55.1,61.72) PC5239.2 PR4412.2 PC5232.2
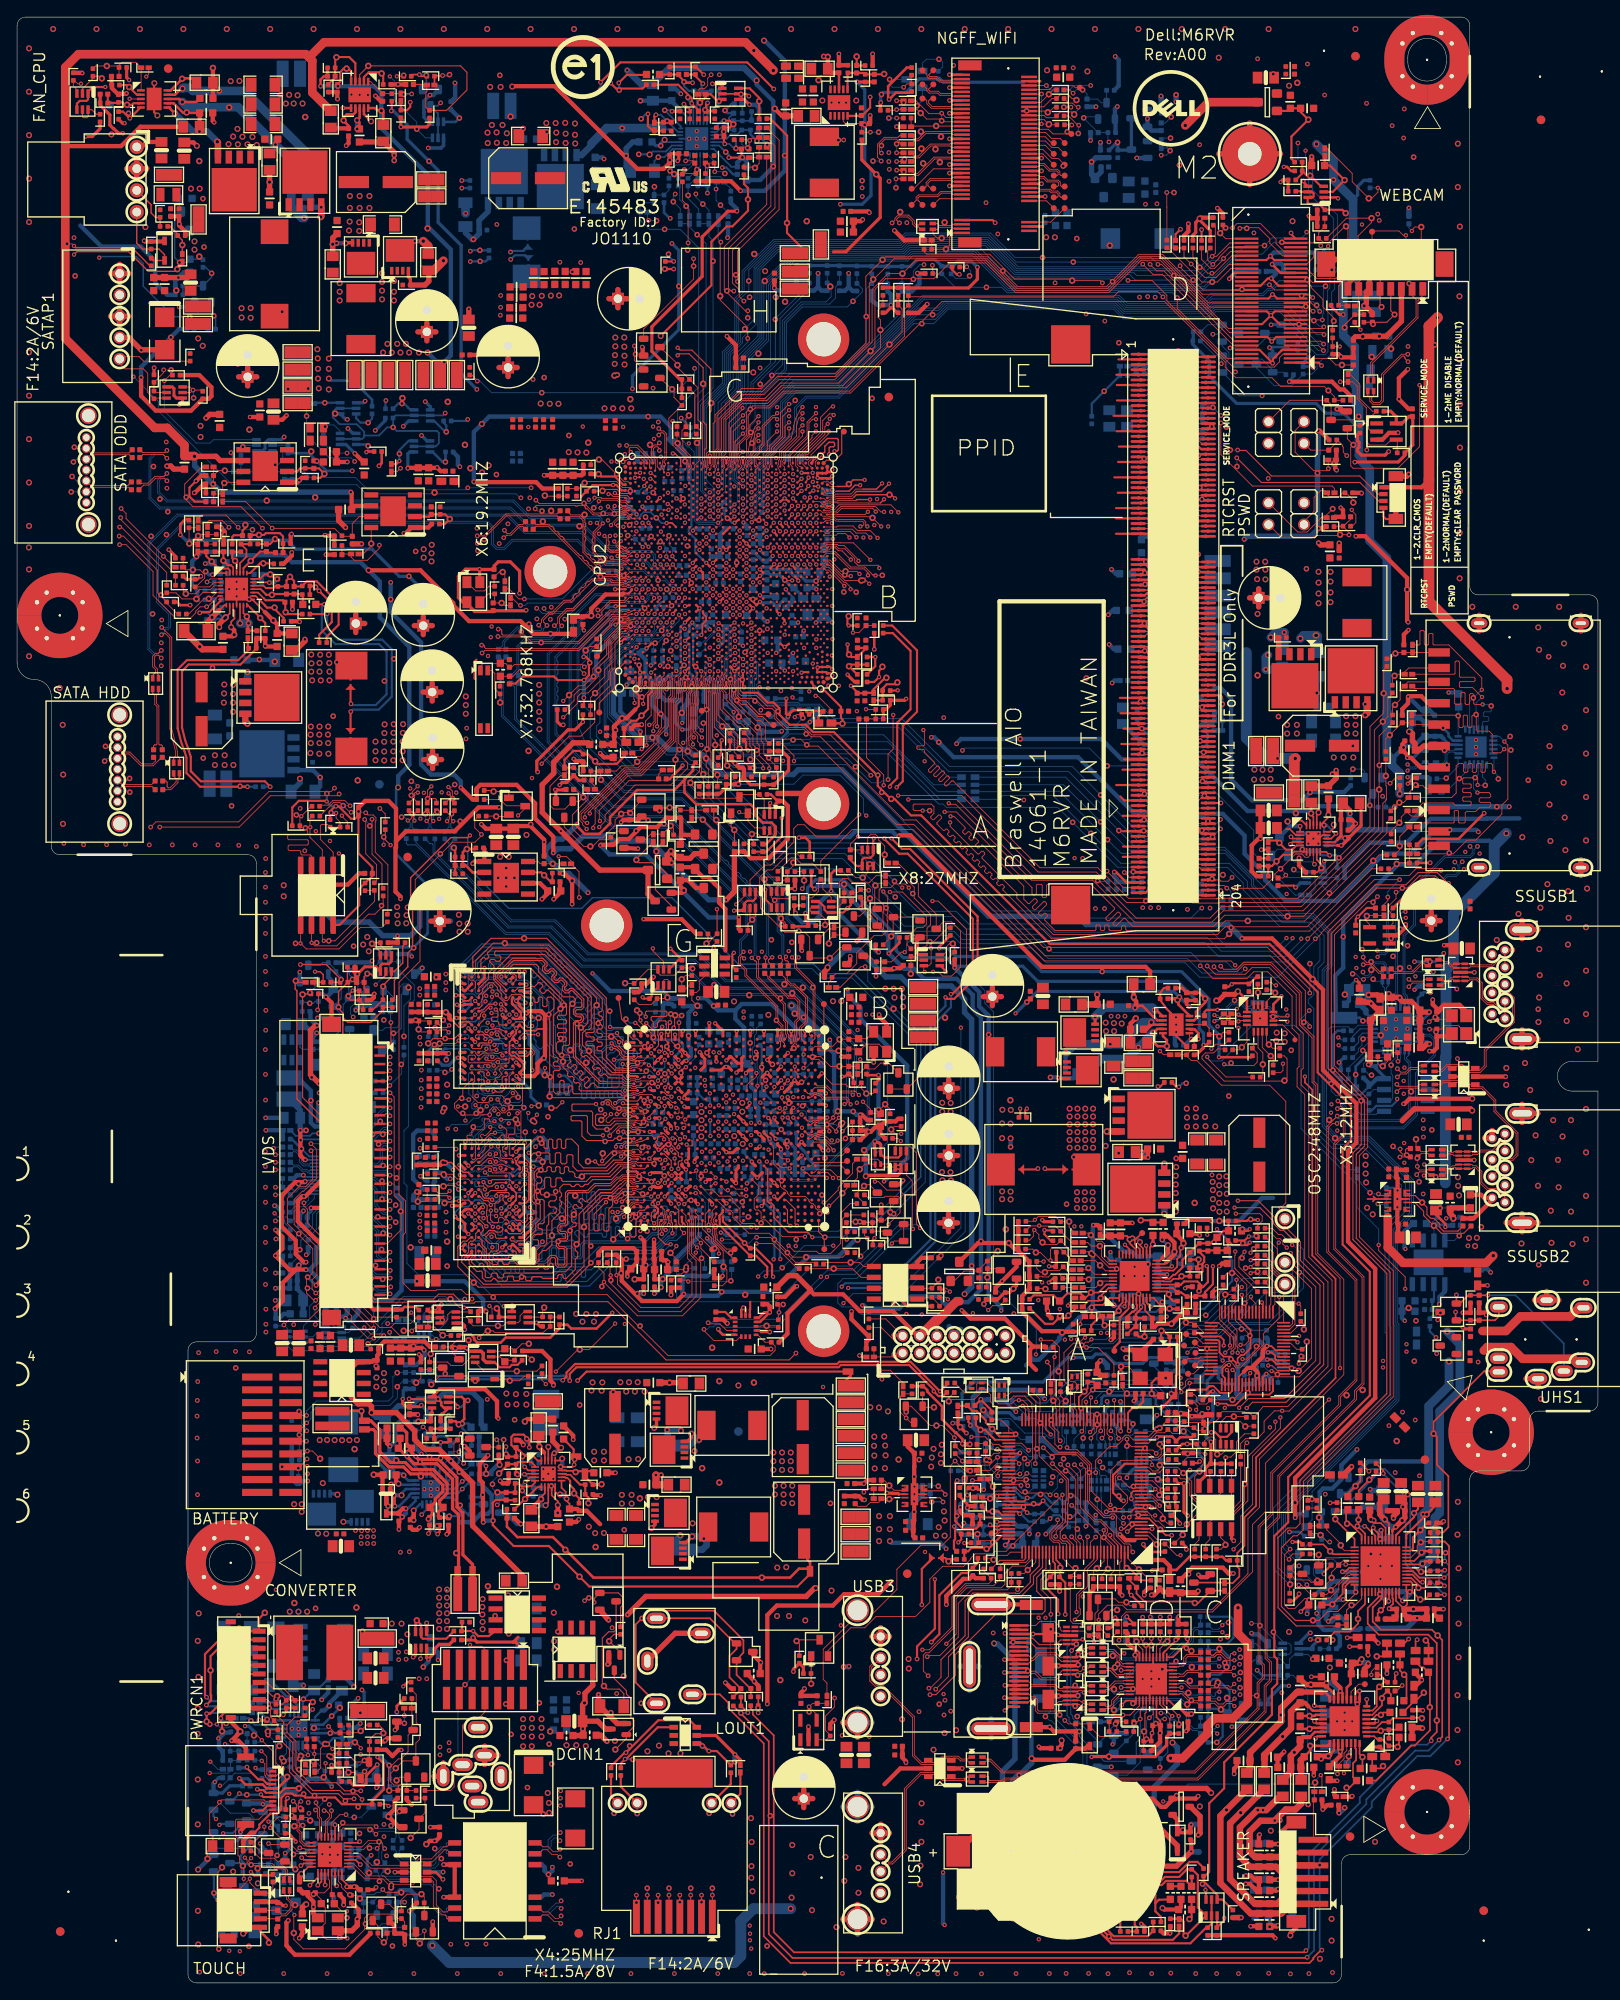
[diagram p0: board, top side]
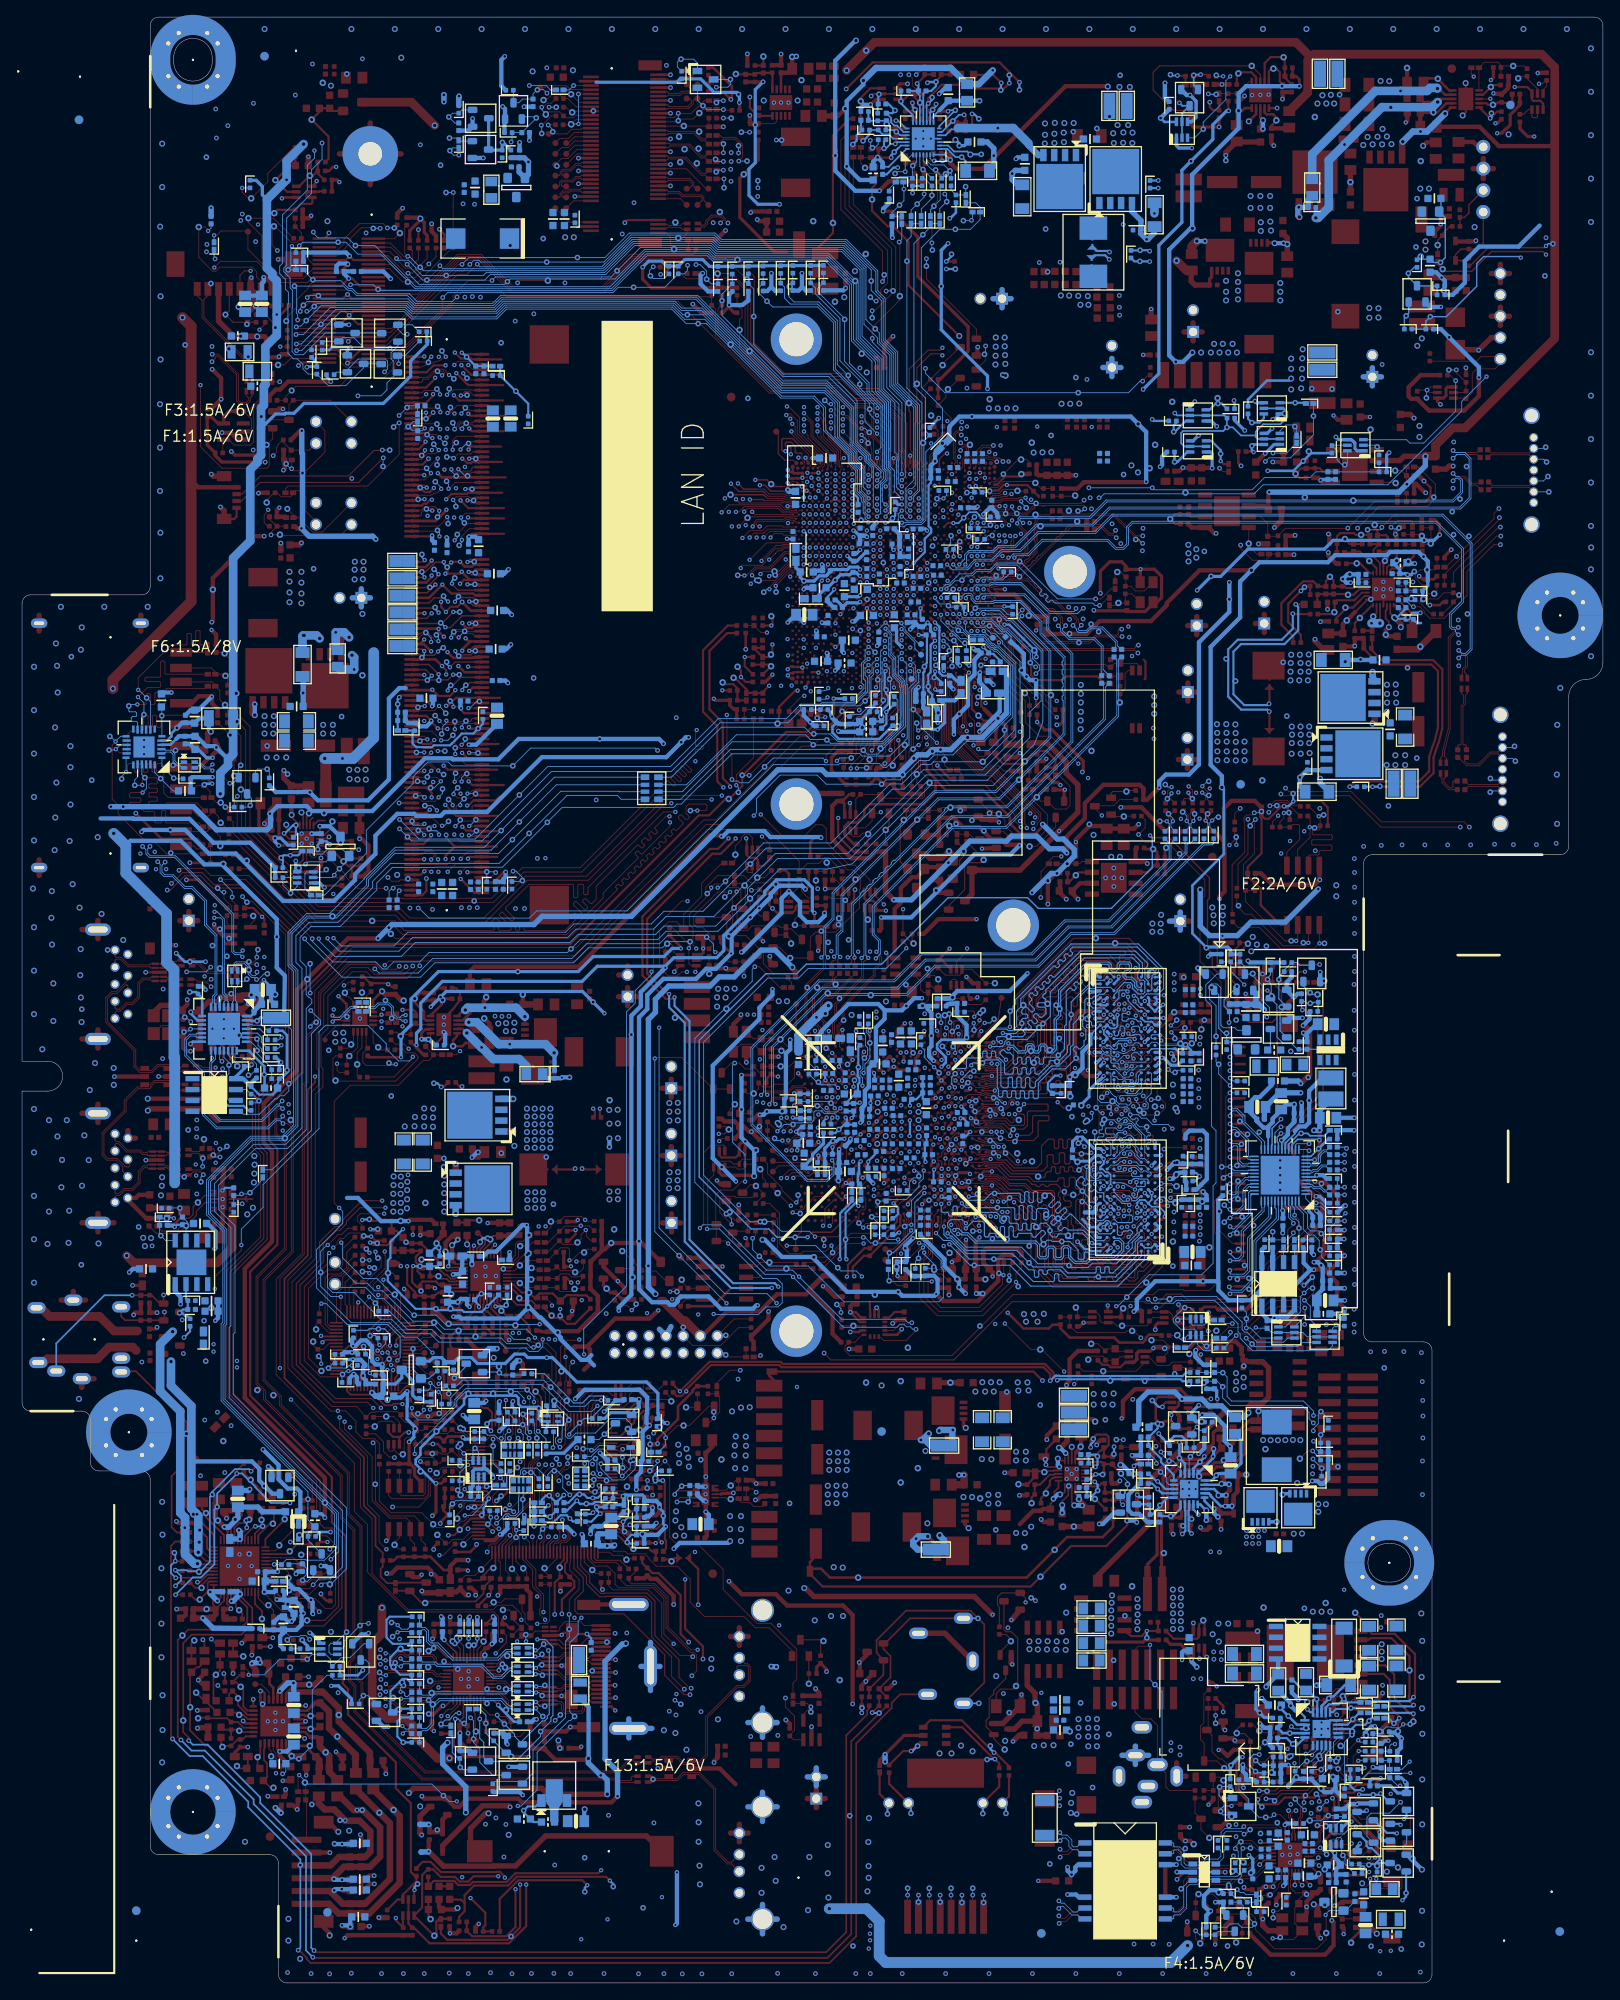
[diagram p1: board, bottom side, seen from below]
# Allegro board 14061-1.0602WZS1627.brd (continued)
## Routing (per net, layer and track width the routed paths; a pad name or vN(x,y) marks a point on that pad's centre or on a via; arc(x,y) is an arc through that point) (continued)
CHG_ON#: length 155.6
  TOP w0.102: v1(141.38,73.74) 141.82,74.17 142.11,74.17 142.35,74.41 142.35,75.48 140.59,77.24 U4101.17 ; R80207.1 R1870.1 116.35,46.47 115.88,46 111.73,46 110.14,44.41 110.14,40.46 107.98,38.3 106.64,38.3 v2(106.51,38.18)
  L4 w0.127: v1(141.38,73.74) 140.5,72.85 140.5,69.01 138.93,67.44 138.93,65.41 138.42,64.91 138.42,63.17 137.02,61.76 137.02,60.76 136.28,60.03 136.28,59.23 136.09,59.04 136.09,58.25 136.2,58.14 136.2,54.28 136.53,53.95 136.53,51.51 135.71,50.68 135.71,49.05 135.08,48.43 135.08,44.79 133.09,42.8 133.09,42.63 132.13,41.67 129.86,41.67 128.39,40.2 128.39,38.64 125.07,35.31 117.95,35.31 116.51,33.87 110.82,33.87 v2(106.51,38.18) 106.32,38.37 105.35,38.37 101.81,41.9 99.83,41.9 99.32,41.39 96.16,41.39 92.98,44.56 68.47,44.56 67.99,44.08 64.32,44.08 56.19,52.21 v2(56.19,55.94)
  BOTTOM w0.102: v2(56.19,55.94) 56.48,56.23 PQ5003.G 55.63,57.84 v4(55.63,58.34) 55.63,58.67 56.36,59.4 PR5273.2
CHG_ON#_ECIO: length 3.7
  TOP w0.102: U109.101 119.21,49.24 v3(118.27,48.31) 117.87,47.9 R80207.2
CHG_SMB2_CLK: length 126.4
  TOP w0.203: U4101.35 141.77,71.51 v1(141.57,71.7)
  TOP w0.254: v2(64.67,70.46) 64.67,71.25 65.45,72.03 96.13,72.03 96.38,72.29 104.4,72.29 107.27,69.41 v1(107.27,69.22) 107.83,68.66 108.36,68.66 R380.1
  L3 w0.254: v2(64.67,70.46) 64.67,68.5 59.64,63.47 59.02,63.47 58.2,62.65 58.2,59.12 56.91,57.83 52.15,57.83 v2(52.1,57.78) ; v1(107.27,69.22) 107.63,68.86 107.65,68.86 107.8,68.71 108.22,68.71 108.37,68.86 119.1,68.86 122.17,68.86 122.32,69.01 131.71,69.01 133.27,70.57 135.07,70.57 136.42,71.92 141.36,71.92 v1(141.57,71.7)
  BOTTOM w0.254: 50.11,71.01 63.6,71.01 63.64,71.05 63.95,71.05 63.95,71.05 64.08,71.05 64.66,70.46 v2(64.67,70.46) ; 50.11,71.01 v4(50.11,71.27) ; 50.11,71.01 49.18,71.01 48.76,71.43 R79940.1 ; U55.9 51.6,57.28 v2(52.1,57.78) 52.74,58.42 PR4425.2
CHG_SMB2_DATA: length 126.5
  TOP w0.203: v1(141.82,72.3) 141.49,72.3 141.05,71.86 141.05,71.06 141.37,70.75 U4101.34
  TOP w0.254: R379.1 108.84,70.04 v1(108.01,69.22) 104.55,72.67 96.22,72.67 95.97,72.42 65.3,72.42 64.29,71.41 64.29,70.94 v2(63.86,70.51)
  L3 w0.254: v2(63.86,70.51) 64.27,70.1 64.27,68.64 59.49,63.86 58.86,63.86 57.82,62.81 57.82,59.28 56.75,58.21 52.57,58.21 v2(52.1,58.67) ; v1(108.01,69.22) 108.19,69.22 108.21,69.24 122.01,69.24 122.16,69.39 131.55,69.39 133.11,70.95 134.91,70.95 136.26,72.3 v1(141.82,72.3)
  BOTTOM w0.254: R79941.1 48.76,70.39 49.18,70.39 49.41,70.62 53.62,70.62 ; v2(63.86,70.51) 63.75,70.62 53.62,70.62 ; U55.8 51.18,57.78 52.07,58.67 v2(52.1,58.67) 52.23,58.67 53.12,59.56 PR4426.2 ; 53.62,70.62 v4(53.62,70.39)
CK_25M_SIO: length 181.7
  TOP w0.102: U109.44 125.61,68.44 v1(125.67,68.5) ; v1(143.64,85.55) 142.98,84.89 142.98,83.8 144.79,81.99 R79699.2 ; v1(68.21,135.94) 68.13,136.02 68.13,137.19 71.61,140.67 74.87,140.67 C80.1 75.08,141.43 R664.2
  L3 w0.127: v2(116.64,78.31) 119.44,78.31 120.09,77.66 122.49,77.66 127.03,82.19 133.22,82.19 134.43,83.4 135.53,83.4 135.76,83.63 138.04,83.63 138.99,84.58 142.92,84.58 143.64,85.3 v1(143.64,85.55) 143.71,85.61 143.71,88.93 144.15,89.37 144.15,89.37 144.86,90.09 144.86,90.93 144.86,103.61 142.99,105.48 142.99,105.58 142.99,108.15 142.23,108.9 142.23,109.47 139.62,112.09 139.62,114.53 137.82,116.33 137.32,116.33 136.46,117.19 135.42,118.23 135.3,118.23 133.23,120.29 133.21,120.29 132.72,120.78 132.3,120.78 132.3,120.78 122.62,120.78 118.84,124.56 106.16,124.56 105.7,125.02 99.42,125.02 99.14,124.74 98.28,124.74 98,125.02 97.21,125.02 96.88,124.69 88.73,124.69 77.18,136.24 68.58,136.24 68.28,135.94 v1(68.21,135.94)
  L4 w0.127: v1(125.67,68.5) 125.67,74.48 125.34,74.82 124.95,74.82 124.53,74.4 124.53,73.41 123.8,72.68 123.1,72.68 119.94,75.84 119.11,75.84 v2(116.64,78.31)
  BOTTOM w0.102: v1(143.64,85.55) 143.64,85.1 v4(143.35,84.81)
CK_48M_SIO: length 4.2
  TOP w0.102: R318.1 129.19,71.01 v3(129.19,72.11) 130.05,72.11 OSC2.3
CK_GLAN_DN: length 189.3
  TOP w0.089: CPU2.A17 71.12,160.07 69.84,160.07 69.83,160.09 69.81,160.09
  TOP w0.102: v2(54.36,156.51) 54.62,156.51 54.72,156.41 54.72,156.24 54.85,156.11 65.62,156.11 69.59,160.09 69.81,160.09 ; v2(34.92,20.23) 35.17,19.98 35.17,19.37 35.39,19.15 35.39,17.68 35.21,17.5 U20.16
  L4 w0.127: v2(54.36,156.51) 53.98,156.51 53.85,156.39 53.85,154.93 54.86,153.92 54.86,145.55 53.75,144.45 53.75,138.95 52.6,137.8 52.6,135.29 49.72,132.41 45.14,132.41 35.14,122.41 35.14,118.68 35.31,118.5 35.31,117.95 34.17,116.8 34.17,102.45 35.78,100.83 35.78,91.29 32.47,87.98 32.47,78.1 32.96,77.61 32.96,76.49 26.33,69.87 26.33,55.54 38.12,43.75 38.12,34.45 34.39,30.72 34.39,29.7 30.6,25.92 30.6,20.98 31.21,20.37 34.79,20.37 v2(34.92,20.23)
  BOTTOM w0.102: v4(36,21.51) 35.77,21.29 35.77,21.08 v2(34.92,20.23)
CK_GLAN_DP: length 188.5
  TOP w0.089: 69.68,159.87 69.7,159.88 70.95,159.88 70.95,159.88 71,159.88 71.02,159.86 71.35,159.86 71.52,160.02 CPU2.C17
  TOP w0.102: 69.68,159.87 65.71,155.89 54.71,155.89 v2(54.42,155.6) ; U20.15 35.61,19.24 35.39,19.46 35.39,20.45 34.98,20.85 v2(34.98,21.1)
  L4 w0.127: v2(34.98,21.1) 34.53,20.64 31.32,20.64 30.87,21.09 30.87,25.81 34.65,29.59 34.65,30.61 38.39,34.34 38.39,43.86 26.6,55.65 26.6,69.76 33.22,76.38 33.22,77.73 32.74,78.21 32.74,87.87 36.05,91.18 36.05,100.94 34.43,102.56 34.43,116.69 35.58,117.84 35.58,118.61 35.4,118.79 35.4,122.3 45.25,132.15 49.83,132.15 52.87,135.18 52.87,137.69 54.02,138.84 54.02,144.34 55.12,145.44 55.12,154.03 54.12,155.04 54.12,155.38 54.33,155.6 v2(54.42,155.6)
  BOTTOM w0.102: v2(34.98,21.1) 34.98,21.75 v4(34.81,21.92)
CK_M_DDR0_A_DN: length 61.2
  TOP w0.102: v1(133.9,157.42) 134.08,157.42 134.31,157.65 134.31,158 134.18,158.13 133.57,158.13 133.32,157.88 132.87,157.88 132.86,157.87 132.28,157.87 131.96,157.55 DIMM1.103 ; CPU2.BF40 v1(93.53,171.82)
  L4 w0.089: 94.53,172.66 94.38,172.5 94.27,172.5 93.99,172.22 93.49,172.22 93.39,172.12 93.39,171.96 v1(93.53,171.82)
  L4 w0.127: 94.53,172.66 95.12,173.24 95.88,173.24 100.37,177.73 112.15,177.73 112.24,177.64 128.31,161.57 129.76,160.13 130.74,160.13 131.02,160.41 131.02,160.87 131.15,161 131.66,161 131.79,160.87 131.79,160.41 132.07,160.13 133.09,160.13 133.92,159.29 133.92,159.29 134.44,158.77 134.44,158.32 134.32,158.19 133.66,158.19 133.54,158.06 133.54,157.55 133.66,157.42 v1(133.9,157.42)
  BOTTOM w0.102: v1(133.9,157.42) 133.9,157.44 v4(133.2,158.15)
CK_M_DDR0_A_DP: length 60.9
  TOP w0.102: CPU2.BD40 v1(92.82,171.82) ; DIMM1.101 132.11,158.15 132.18,158.09 132.77,158.09 132.78,158.09 133.23,158.09 133.48,158.34 134.27,158.34 134.53,158.09 134.53,157.66 v1(134.78,157.4)
  L4 w0.089: v1(92.82,171.82) 93.41,172.41 93.91,172.41 93.95,172.45 94.19,172.69 94.27,172.69 94.33,172.76 94.33,172.84 94.34,172.85
  L4 w0.127: v1(134.78,157.4) 134.71,157.47 134.71,158.88 134.19,159.4 133.2,160.39 132.18,160.39 132.05,160.52 132.05,160.98 131.77,161.26 131.04,161.26 130.76,160.98 130.76,160.52 130.63,160.39 129.87,160.39 112.26,178 100.26,178 95.77,173.51 95.01,173.51 94.34,172.85
  BOTTOM w0.102: v1(134.78,157.4) 134.78,157.76 v4(134.47,158.07)
CK_M_DDR1_A_DN: length 62.2
  TOP w0.102: v1(92.82,170.83) CPU2.BF38 ; v1(137.13,156.89) 137.08,156.94 137.08,157.23 137.58,157.73 138.18,157.73 138.67,157.25 DIMM1.104
  L4 w0.089: 96.39,171.72 96.38,171.71 96.33,171.71 96.3,171.68 96.29,171.68 95.84,171.23 95.68,171.23 95.6,171.23 95.6,171.23 92.78,171.23 92.7,171.16 92.7,170.95 v1(92.82,170.83)
  L4 w0.127: 96.39,171.72 101.38,176.71 111.72,176.71 127.89,160.54 128.16,160.27 128.16,160.21 129.84,158.54 130.24,158.54 130.62,158.92 130.8,158.92 131.16,158.56 131.16,158.38 130.78,158 130.78,157.6 131.98,156.39 136.31,156.39 136.8,156.89 v1(137.13,156.89)
  BOTTOM w0.102: v1(137.13,156.89) 137.13,157.37 v4(137.75,157.99)
CK_M_DDR1_A_DP: length 61.7
  TOP w0.102: DIMM1.102 138.4,157.85 138.3,157.95 137.5,157.95 136.54,156.99 v1(136.28,156.99) ; v1(92.11,170.83) CPU2.BD38
  L4 w0.089: 96.2,171.91 96.2,171.86 95.76,171.42 92.7,171.42 v1(92.11,170.83)
  L4 w0.127: 96.2,171.91 97.05,172.76 101.27,176.97 111.83,176.97 128,160.81 128.43,160.38 128.43,160.32 129.95,158.8 130.13,158.8 130.51,159.19 130.91,159.19 131.43,158.67 131.43,158.27 131.05,157.89 131.05,157.71 132.09,156.66 135.79,156.66 136.12,156.99 v1(136.28,156.99)
  BOTTOM w0.102: v4(136.51,157.72) 136.28,157.49 v1(136.28,156.99)
CK_P_33M_EC: length 3.9
  TOP w0.102: U4101.2 146.57,79.26 146.72,79.41 146.72,81.32 R79699.1
CK_PCIEX1_WLAN_DN: length 123.1
  TOP w0.102: CPU2.B18 71.5,160.69 70.79,160.69 70.73,160.63 69.36,160.63 65.69,156.96 60.14,156.96 59.4,157.7 56.85,157.7 56.73,157.82 56.73,158.26 56.6,158.39 v2(56.31,158.39) ; R23.2 103.31,216.15 103.09,215.93 101.49,215.93 100.69,215.14 100.69,213.59 v2(101.13,213.16)
  L3 w0.127: v2(101.13,213.16) 100.99,213.3 100.73,213.3 100.51,213.08 100.51,206.78 98.29,204.56 85.09,204.56 82.84,202.31 69.91,202.31 65.78,198.18 56.59,198.18 55.84,197.43 55.84,194.17 53.25,191.58 53.25,184.96 56.16,182.04 56.16,172.56 55.04,171.45 55.04,158.47 55.35,158.17 55.58,158.17 55.74,158.09 56.01,158.09 v2(56.31,158.39)
  BOTTOM w0.102: v2(101.13,213.16) v4(100.16,213.16)
CK_PCIEX1_WLAN_DP: length 123.1
  TOP w0.089: CPU2.C18 71.78,160.41 71.69,160.33 71.45,160.33 71.3,160.48
  TOP w0.102: v2(56.27,157.53) 56.32,157.48 59.32,157.48 60.05,156.74 65.78,156.74 69.45,160.42 70.82,160.42 70.88,160.48 71.3,160.48 ; R22.2 103.49,215.14 102.91,215.72 101.58,215.72 100.91,215.05 100.91,214.34 v2(101.15,214.1)
  L3 w0.127: v2(101.15,214.1) 100.25,213.19 100.25,206.89 98.18,204.83 84.98,204.83 82.73,202.58 69.8,202.58 65.67,198.45 56.48,198.45 55.57,197.54 55.57,194.28 52.98,191.69 52.98,184.84 55.89,181.93 55.89,172.67 54.78,171.56 54.78,158.36 55.24,157.9 55.52,157.9 55.8,157.76 56.24,157.56 v2(56.27,157.53)
  BOTTOM w0.102: v2(101.15,214.1) v4(101.15,214.96)
CK_PE_100M_16PORT_DN: length 72.9
  TOP w0.102: GPU1.AK32 92.84,110.8 92.72,110.93 92.72,111.15 92.84,111.28 93.07,111.28 93.15,111.36 93.15,116.61 90.98,118.78 90.98,119.68 v1(90.68,119.98) ; CPU2.C21 71.63,162.08 71.06,161.51 69.47,161.51 68.44,160.48 68.44,160.1 68.28,159.94 v2(67.98,159.94)
  BOTTOM w0.102: 90.95,121.74 90.95,120.26 v1(90.68,119.98) ; 90.95,121.74 v4(90.66,121.74) ; 90.95,121.74 90.95,123.48 89.99,124.45 89.99,127.46 78.18,139.27 71.01,139.27 64.61,145.66 64.61,155.87 68.24,159.5 68.24,159.68 v2(67.98,159.94)
CK_PE_100M_16PORT_DP: length 73
  TOP w0.102: CPU2.A21 71.19,161.94 70.97,161.73 69.38,161.73 68.29,160.63 v2(67.95,160.63) ; GPU1.AK30 93,110.13 93.37,110.5 93.37,116.7 91.2,118.86 91.2,119.73 v1(91.46,119.98)
  BOTTOM w0.102: 91.17,123.06 91.17,120.27 v1(91.46,119.98) ; 91.17,123.06 91.17,123.57 90.2,124.54 90.2,127.55 78.27,139.48 71.1,139.48 64.83,145.75 64.83,155.78 68.46,159.41 68.46,160.12 v2(67.95,160.63) ; 91.17,123.06 v4(91.47,123.06)
CKEA0: length 54.9
  TOP w0.127: v1(77.48,103.53) 77.48,103.32 GPU1.K20 ; MEM1.K9 58.81,110.68 59.22,111.09 59.63,111.09 59.77,110.94 60.95,110.94 v1(60.97,110.96) ; v3(48.11,109.93) 48.66,110.47 51.16,110.47 51.56,110.87 v1(51.83,110.87)
  L3 w0.165: v1(51.83,110.87) 51.13,110.87 51.01,111 51.01,111.71 51.13,111.84 52.22,111.84 52.33,111.73 52.33,111.35 52.54,111.14 53.78,111.14 54.18,111.55 54.18,111.63 54.64,112.09 54.7,112.09 54.95,112.34 v1(55.07,112.34) 55.18,112.45 55.81,112.45 56.06,112.2 56.06,112.01 56.89,111.18 56.89,110.6 57.32,110.17 57.91,110.17 58.25,110.52 58.67,110.52 59.22,109.96 61.72,109.96 62.39,109.3 68.92,109.3 69.36,108.86 73.5,108.86 73.76,108.59 73.76,108.59 74.02,108.33 74.03,108.33 74.8,107.55 75.98,107.55 76.78,108.35 76.78,108.35 77.15,108.72 77.65,108.72 78.01,108.36 78.45,108.36 78.75,108.06 78.75,104.81 77.93,103.98 77.9,103.98 77.65,103.73 77.65,103.71 v1(77.48,103.53)
  L4 w0.165: v1(55.07,112.34) 55.18,112.45 55.81,112.45 55.81,112.45 56.07,112.45 56.92,111.59 57.88,111.59 58.25,111.23 59.72,111.23 60,110.94 60.71,110.94 60.73,110.96 v1(60.97,110.96)
  BOTTOM w0.127: MEM3.K9 52.77,110.48 52.87,110.57 52.87,110.8 52.74,110.93 51.89,110.93 v1(51.83,110.87)
CKEA1: length 47.5
  TOP w0.127: MEM2.K9 51.67,92.82 v2(51.66,92.84) 51.18,93.32 49.98,93.32 v3(49.88,93.22) ; v1(77.26,100) 77,100.26 GPU1.J17
  L3 w0.165: v2(51.66,92.84) 51.68,92.86 53.79,92.86 54.05,92.6 54.05,92.41 54.67,91.79 55.13,91.79 55.41,92.07 55.46,92.07 55.88,92.49 56,92.49 56.19,92.68 56.33,92.68 56.78,93.14 v1(56.78,93.18) 56.78,93.46 56.98,93.66 58.65,93.66 59.26,93.05 59.62,93.05 59.88,93.31 59.88,93.74 60.43,94.29 61.52,94.29 61.6,94.21 66.39,94.21 66.56,94.04 69.7,94.04 69.84,93.89 72.22,93.89 72.76,93.35 74.38,93.35 74.59,93.14 76.77,93.14 77.34,93.71 77.65,93.71 78.07,94.13 78.07,94.29 78.71,94.93 78.71,95.33 78.45,95.59 78.21,95.59 77.81,95.98 77.81,96.34 79.03,97.56 79.03,98.7 78.14,99.59 77.81,99.59 77.4,100 v1(77.26,100)
  L4 w0.165: v1(58.42,93.22) 58.59,93.39 58.92,93.39 59.08,93.23 59.08,92.94 58.77,92.63 56.96,92.63 56.86,92.53 56.86,92.37 56.73,92.24 56.55,92.24 56.29,92.5 56.29,92.65 56.59,92.94 56.59,92.99 v1(56.78,93.18)
  BOTTOM w0.127: v1(58.42,93.22) 58.71,93.22 58.81,93.12 MEM4.K9
CLINK_CLK_LAN: length 3.3
  TOP w0.102: NGFF1.42 120.31,215 TP67.1
CLINK_DATA_LAN: length 4.9
  TOP w0.102: NGFF1.40 120.06,214.5 121.1,213.46 121.85,213.46 TP66.1
CLINK_RST_LAN_N: length 3.4
  TOP w0.102: TP65.1 120.04,214 NGFF1.38
CLK_48M_SIO_C: length 4.4
  TOP w0.102: R318.2 129.37,69.47 v3(129.88,68.96) 129.61,68.69 U109.34
CLK_DIFF_N4: length 5
  TOP w0.089: 69.9,159.68 70.08,159.68 70.11,159.66 CPU2.B16
  TOP w0.102: R1267.2 68.05,157.47 68.05,157.54 69.36,158.85 69.36,159.14 69.9,159.68
CLK_DIFF_P4: length 7.9
  TOP w0.089: 69.99,159.46 71.34,159.46 71.45,159.36 71.69,159.36 71.83,159.49 72.11,159.49 CPU2.C16
  TOP w0.102: v3(66.54,155.91) 66.97,156.35 R1267.1 68.27,156.79 68.27,157.45 69.58,158.76 69.58,159.05 69.99,159.46
CLKA0: length 48.9
  TOP w0.127: GPU1.H26 76.6,107.2 v1(76.6,107.2) ; MEM1.J7 56.66,111.52 56.4,111.63 55.88,111.63 55.68,111.6 55.58,111.59 v1(54.95,111.39) ; R1907.1 49.75,111.76 50.3,111.76 v1(50.57,112.03)
  L4 w0.152: v1(76.6,107.2) 76.42,107.2 76.24,107.38 74.98,107.38 73.25,109.11 73.25,109.18 63.08,119.35 55.91,119.35 52.85,116.29 52.85,112.71 53.24,112.32 53.95,112.32 54.75,111.52 54.82,111.52 v1(54.95,111.39) 54.78,111.23 52.6,111.23 52.17,111.65 50.94,111.65 v1(50.57,112.03)
  BOTTOM w0.127: MEM3.J7 54.21,111.48 54.21,111.76 54.38,111.93 54.86,111.93 54.89,111.9 55.01,111.9 55.16,111.75 55.16,111.6 v1(54.95,111.39) ; v4(49.88,112.65) 50.5,112.03 v1(50.57,112.03)
CLKA0#: length 49.3
  TOP w0.127: v1(55.53,111.08) 55.69,111.08 56,111.38 56.34,111.38 57.21,110.51 MEM1.K7 ; v1(76.6,106.41) 76.58,106.41 76.2,106.79 GPU1.H25 ; v1(50.51,111.22) 50.22,111.51 49.4,111.51 R1906.1
  L4 w0.152: v1(76.6,106.41) 76.6,106.64 76.47,106.77 76.42,106.77 76.11,107.07 74.85,107.07 72.94,108.98 72.94,109.06 62.96,119.04 56.04,119.04 53.15,116.16 53.15,112.84 53.37,112.62 54.07,112.62 54.84,111.86 55.17,111.86 55.55,111.48 55.55,111.09 v1(55.53,111.08) 55.24,111.08 55.09,110.92 52.47,110.92 52.05,111.35 50.64,111.35 v1(50.51,111.22)
  BOTTOM w0.127: v4(50.09,110.49) 50.09,110.8 v1(50.51,111.22) ; v1(55.53,111.08) 55.32,110.86 55,110.86 54.95,110.91 54.8,110.91 54.74,110.98 54.28,110.98 54.01,110.71 MEM3.K7
CLKA1: length 49.7
  TOP w0.127: R1909.1 49.33,92.11 50.35,92.11 v1(50.6,91.86) ; v1(55.43,91.01) 55.43,91.18 55.09,91.52 54.65,91.52 54.15,92.02 MEM2.J7 ; GPU1.G9 75.4,93.76 75.24,93.6 v1(75.01,93.6)
  L4 w0.152: v1(75.01,93.6) 75.21,93.6 75.44,93.83 75.44,94.2 74.49,95.15 74.49,96.56 74.34,96.72 74.34,98.09 72.31,100.12 66.19,100.12 65.85,100.45 65.85,100.87 65.73,100.99 65.37,100.99 65.25,100.87 65.25,100.45 64.91,100.12 64.36,100.12 64.03,100.45 64.03,100.66 63.87,100.82 63.57,100.82 62.87,100.12 62.6,100.12 61.94,99.46 61.94,98.84 62.53,98.26 62.53,97.65 62.22,97.34 61.97,97.34 61.81,97.19 61.81,96.89 61.97,96.74 62.23,96.74 62.56,96.4 62.56,95.85 62.23,95.52 61.97,95.52 61.81,95.36 61.81,95.06 61.97,94.91 62.23,94.91 62.56,94.58 62.56,93.67 61.1,92.22 59.16,92.22 59,92.05 57.37,92.05 56.62,91.29 55.86,91.29 55.77,91.2 55.62,91.2 v1(55.43,91.01) 55.06,91.39 52.66,91.39 52.08,91.97 50.71,91.97 v1(50.6,91.86)
  BOTTOM w0.127: MEM4.J7 57.08,92.02 56.25,91.19 55.61,91.19 v1(55.43,91.01) ; v4(74.23,93.75) 74.38,93.6 v1(75.01,93.6)
CLKA1#: length 50.2
  TOP w0.127: R1908.1 49.33,92.36 50.31,92.36 v1(50.61,92.67) ; v1(55.59,91.64) 55.2,91.79 55.14,91.81 54.76,91.81 54.72,91.82 54.5,92.05 54.34,92.49 MEM2.K7 ; GPU1.H9 76.2,93.99 v1(75.81,93.6)
  L4 w0.152: v1(75.81,93.6) 75.75,93.65 75.75,94.32 74.8,95.27 74.8,96.69 74.64,96.84 74.64,98.22 72.43,100.42 66.31,100.42 66.16,100.58 66.16,100.99 65.85,101.3 65.25,101.3 64.94,100.99 64.94,100.58 64.79,100.42 64.48,100.42 64.33,100.58 64.33,100.79 64,101.12 63.44,101.12 62.74,100.42 62.48,100.42 61.64,99.58 61.64,98.72 62.22,98.13 62.22,97.78 62.1,97.65 61.84,97.65 61.51,97.32 61.51,96.76 61.84,96.43 62.1,96.43 62.25,96.28 62.25,95.97 62.1,95.82 61.84,95.82 61.51,95.49 61.51,94.93 61.84,94.6 62.1,94.6 62.25,94.45 62.25,93.8 60.98,92.52 59.04,92.52 58.87,92.35 57.25,92.35 56.49,91.6 55.63,91.6 v1(55.59,91.64) 55.54,91.69 52.79,91.69 52.21,92.27 51.01,92.27 v1(50.61,92.67)
  BOTTOM w0.127: MEM4.K7 57.21,92.53 56.14,91.46 55.77,91.46 v1(55.59,91.64) ; v4(75.75,94.44) 75.81,94.38 v1(75.81,93.6)
CLKTESTA: length 10
  TOP w0.102: C764.1 77.15,84.71 76.46,85.4 v3(76.46,85.42) 77.15,86.1 v1(77.15,86.21) ; GPU1.K8 77.48,92.88 77.48,92.83 v1(77.45,92.8)
  L3 w0.127: v1(77.15,86.21) 77.15,87.86 76.7,88.31 76.7,90.42 76.95,90.67 76.95,92.31 v1(77.45,92.8)
CLKTESTA_C: length 3.4
  TOP w0.102: C764.2 78.22,83.48 v3(78.27,83.44) 77.76,82.93 77.38,82.93 76.67,82.22 R1207.1
CLKTESTB: length 10.7
  TOP w0.102: v1(79.41,92.41) 79.32,92.41 79.32,92.4 GPU1.L7
  BOTTOM w0.102: C763.1 83.62,85.3 v4(83.5,85.42) 83.01,85.42 80.98,87.46 80.96,87.46 80.52,87.9 80.52,91.29 v1(79.41,92.41)
CLKTESTB_C: length 7.5
  TOP w0.102: v1(78.55,82.07) 78.39,82.22 R1206.1
  BOTTOM w0.102: C763.2 83.62,82.24 v4(83.53,82.14) 83.44,82.06 78.55,82.06 v1(78.55,82.07)
COREPWROK: length 224.9
  TOP w0.102: CPU2.G16 v1(73.89,159.17) ; v2(155.13,202.69) 155.74,203.3 155.74,205.31 v3(155.52,205.52) 155.39,205.52 153.51,203.64 152.88,203.64 152.41,204.11 R1820.1 152.32,204.77 R181.2 C111.2 ; R178.1 94.97,117.08 95.23,117.34 95.23,117.51 R184.2 95.83,118.11 97.1,118.11 98.26,119.26 98.26,120.51 100.27,122.53 101.25,122.53 101.89,123.17 101.89,124.27 101.81,124.35 101.81,125.03 101.89,125.11 101.89,127.14 101.36,127.67 v1(101.38,127.69)
  L3 w0.127: v1(149.26,122.23) 149.26,122.79 150.74,124.27 150.74,128.89 150.75,128.89 150.75,130.47 152.35,132.08 152.85,132.08 153.18,132.41 154.98,132.41 157.92,135.34 157.92,140.7 159.96,142.75 159.96,144.46 160.03,144.53 160.03,167.46 155.33,172.16 155.33,172.79 154.97,173.15 154.97,179.21 155.39,179.63 155.39,191.47 154.58,192.28 154.58,202.15 v2(155.13,202.69)
  BOTTOM w0.089: 71.93,158.22 71.94,158.22 72.3,158.58 73.3,158.58 v1(73.89,159.17)
  BOTTOM w0.102: 71.93,158.22 71.63,157.91 71.17,157.91 70.86,157.6 70.86,157.58 70.26,156.99 70.26,156.68 68.21,154.62 68.21,147.46 67.82,147.07 67.82,145.8 72.3,141.33 79.2,141.33 88.38,132.15 96.85,132.15 100.72,128.28 100.72,128.24 101.27,127.69 v1(101.38,127.69) 101.38,127.44 104.05,124.76 109.63,124.76 111.11,123.29 120.18,123.29 121.14,122.33 139.28,122.33 140.89,120.72 147.88,120.72 149.26,122.09 v1(149.26,122.23)
COREPWROK_XDP: length 20.4
  TOP w0.102: XDP1.45 150.96,200.57 150.96,200.53 152.07,199.42 154.48,199.42 156.93,201.88 156.93,204.4 158.51,205.97 v3(158.51,206.47) 155.57,206.47 R1820.2
CPU_FAN_CTRL_SIO: length 293.9
  TOP w0.165: v2(129.2,53.14) 129.57,53.14 130.37,53.94 U109.6 ; v1(6.66,203.23) 6.87,203.02 13.42,203.02 15.54,200.9 R68.1
  L3 w0.165: v1(6.66,203.23) 7.2,202.69 7.2,189.03 13.59,182.63 13.59,151.77 14.29,151.06 14.29,140.23 18.59,135.93 28.3,135.93 31.48,132.74 31.48,130.26 32.19,129.56 32.19,123.68 32.18,123.67 32.18,98.88 32.91,98.15 32.91,78.58 33.28,78.21 33.28,74.14 29.33,70.19 29.33,54.63 32.1,51.85 32.1,51.32 35.56,47.85 58.46,47.85 60.68,45.63 81.46,45.63 88.93,38.17 96.75,38.17 100.64,42.06 107.83,42.06 112.05,46.28 115.07,46.28 115.96,47.17 123.38,47.17 128.6,52.39 128.6,52.67 128.87,52.94 129,52.94 v2(129.2,53.14)
  BOTTOM w0.165: v1(6.66,203.23) 6.41,203.48 v4(5.85,203.48)
CPU_FAN_TACH_SIO: length 296.9
  TOP w0.165: R74.1 19.34,201.09 v3(18.75,200.51) 18.5,200.25 15.35,200.25 13.04,202.56 7.02,202.56 v1(6.66,202.21) ; U109.5 130.66,53.54 v2(129.93,52.81)
  L3 w0.165: v1(6.66,202.21) 6.66,188.62 13.17,182.11 13.17,151.59 13.87,150.89 13.87,140.05 18.41,135.51 28.13,135.51 31.07,132.57 31.07,130.09 31.77,129.39 31.77,123.85 31.76,123.84 31.76,98.7 32.37,98.09 32.37,78.51 32.86,78.02 32.86,74.33 28.91,70.38 28.91,54.46 31.68,51.68 31.68,51.14 35.39,47.43 58.29,47.43 60.51,45.21 81.29,45.21 88.75,37.75 96.94,37.75 100.79,41.61 107.98,41.61 112.22,45.85 115.25,45.85 116.15,46.75 123.99,46.75 129.93,52.68 v2(129.93,52.81)
CPU_HPD: length 13.5
  TOP w0.089: 78.15,178.5 78.41,178.23 78.41,177.64 78.33,177.55 78.33,177.26 CPU2.R51
  TOP w0.102: Q6703.D v3(76.65,186.45) 76.88,186.22 76.88,185.49 R498.1 77.77,184.57 76.27,183.07 76.27,182.15 76.74,181.69 76.74,179.91 78.15,178.5
CPU_LVDS_BL_ADJ: length 106.4
  TOP w0.165: R80220.1 40.49,114.56 R80236.1 ; R80220.1 40.04,115.01 R80219.1 40.01,116.1 v1(39.26,116.1) 39.26,116.07 38.76,115.56 v5(38.76,115.46) 38.76,115.23 39.01,114.99 R80220.1 ; CPU2.P52 77.66,178.28 77,178.94 v1(76.74,178.94)
  L3 w0.165: v1(39.26,116.1) 39.26,119.86 38.01,121.12 38.01,131.8 v1(37.66,132.14)
  L4 w0.165: v1(76.74,178.94) 76.36,179.32 76.36,181.96 73.53,184.79 64.34,184.79 49.18,169.63 49.18,157.73 47.26,155.81 47.26,142.09 45.37,140.21 45.37,139.64 42.65,136.93 42.05,136.93 41.58,137.39 40.6,137.39 40.31,137.11 40.31,136.45 40.18,136.32 40.18,134.77 37.66,132.24 v1(37.66,132.14)
CPU_LVDS_BL_ADJ_B: length 5.2
  TOP w0.165: R80219.2 40.61,116.4 C29.1 40.61,117.72 v5(40.98,118.08) 41.36,118.08 41.82,117.62 42.85,117.62 43.16,117.93 Q21.2
CPU_LVDS_BL_ADJ_C: length 4.6
  TOP w0.165: Q21.6 42.51,120.61 v3(41.54,121.59) 41.66,121.72 R50.1 42.51,121.45 43.16,120.8 Q21.5
CPVEE: length 3.6
  TOP w0.203: U6.20 160.14,45.03 159.98,44.86 159.98,43.99 v3(159.6,43.61) 159.23,43.24 C1491.1
CSA0#_0: length 44.6
  TOP w0.127: v1(56.1,109.15) 55.49,109.15 55.36,109.28 55.36,109.61 55.24,109.74 54.49,109.74 54.38,109.62 54.38,109.44 54.25,109.31 53.34,109.31 53.21,109.43 MEM1.L2 ; v1(75.84,104.78) 75.84,104.4 76.04,104.2 GPU1.H22
  L3 w0.102: 73.11,106.14 73.4,106.43 74.26,106.43 74.7,105.99 75.94,105.99 76.17,105.76 76.17,105.11 v1(75.84,104.78)
  L3 w0.165: v1(56.1,109.15) 55.95,109.3 55.55,109.3 55.07,108.82 54.44,108.82 54.23,109.02 54.23,109.38 54.03,109.58 52.89,109.58 52.66,109.35 52.66,107.9 52.86,107.7 55.51,107.7 55.73,107.92 55.79,107.92 56.06,108.18 56.51,108.18 56.67,108.03 57.26,108.03 58.12,107.17 60.07,107.17 60.18,107.28 61.07,107.28 61.19,107.15 61.19,106.84 61.43,106.6 61.96,106.6 62.14,106.79 62.39,106.79 62.67,106.51 62.97,106.51 63.25,106.79 66.96,106.79 67.09,106.91 67.09,107.56 67.21,107.69 68.23,107.69 68.61,107.31 69.08,106.84 69.35,106.84 69.53,106.66 69.86,106.66 69.98,106.53 69.98,106.2 70.11,106.07 70.73,106.07 70.86,106.2 70.86,106.52 71,106.66 72.01,106.66 72.27,106.41 72.27,106.18 72.47,105.97 72.94,105.97 73.11,106.14
  BOTTOM w0.127: v1(75.84,104.78) 76.21,105.15 76.21,105.97 v4(75.8,106.38) ; v1(56.1,109.15) 56.1,109.37 56.3,109.57 56.3,109.75 56.43,109.87 56.7,109.87 56.85,109.72 56.85,109.37 56.98,109.24 57.29,109.24 57.73,109.68 MEM3.L2
CSA1#_0: length 43.7
  TOP w0.127: MEM2.L2 57.65,93.98 55.6,93.98 v1(55.32,93.7) ; v1(76.59,95.23) 76.54,95.27 76.54,96.2 76.09,96.66 76.06,96.66 75.71,97 GPU1.G13
  L3 w0.165: v1(76.59,95.23) 76.59,95.08 76.06,94.55 74.78,94.55 74.5,94.83 74.24,95.08 72.57,95.08 72.23,95.42 70.63,95.42 70.49,95.27 67.06,95.27 66.9,95.44 62.24,95.44 60.08,97.59 58.66,97.59 58.58,97.67 57.36,97.67 57.23,97.8 57.23,98.35 57.36,98.48 59.19,98.48 v2(59.4,98.28)
  L4 w0.102: 58.97,94.38 58.71,94.12 55.74,94.12 v1(55.32,93.7)
  L4 w0.165: 58.97,94.38 58.97,95.89 59.33,96.26 60.2,96.26 60.33,96.38 60.33,97.43 60.14,97.62 60.14,97.69 60.14,97.69 60.14,98.58 60.04,98.68 59.81,98.68 v2(59.4,98.28)
  BOTTOM w0.127: MEM4.L2 53.21,93.92 53.34,94.05 54.32,94.05 54.4,94.13 54.76,94.13 54.82,94.07 54.96,94.07 v1(55.32,93.7) ; v2(59.4,98.28) 59.47,98.34 v4(59.47,99.55)
CTF_TRIP: length 4.4
  TOP w0.102: Q9625.B 102.19,91.08 v3(102.19,90.17) 102.19,89.84 101.59,89.24 C755.2 100.72,89.24 R79967.2
CTFB: length 4.8
  TOP w0.102: R79964.2 98.27,92.08 R1920.2 98.27,92.39 v3(99.12,93.24) 99.27,93.4 99.74,93.4 Q9625.C
DBG0: length 88.8
  TOP w0.102: v1(85.97,170.89) 86.01,170.89 CPU2.AM40 ; XDP1.9 152.29,191.57 v2(152.88,190.98)
  BOTTOM w0.102: v2(152.88,190.98) 152.28,190.98 147.71,195.55 140.29,195.55 139.43,194.69 129.45,194.69 128.3,195.84 108.98,195.84 107.27,194.13 v4(105.87,194.13) 104.91,194.13 104.83,194.06 96.2,185.42 92.39,185.42 91.21,184.23 91.21,181.65 88.31,178.75 88.31,177.8 87.43,176.93 87.43,174.43 86.75,173.74 86.75,173.35 86.57,173.17 86.57,172.01 86.34,171.78 86.34,171.38 86.32,171.36 86.32,171.35 85.97,171 v1(85.97,170.89)
DBG1: length 88.2
  TOP w0.102: v2(152.89,191.74) 152.56,192.07 XDP1.11 ; CPU2.AM41 v1(85.93,171.55)
  BOTTOM w0.102: v2(152.89,191.74) 152.33,191.74 v4(150.02,194.06) 148.29,195.78 140.2,195.78 139.33,194.92 129.54,194.92 128.39,196.07 108.89,196.07 107.46,194.64 105.09,194.64 96.1,185.65 92.3,185.65 90.97,184.31 90.97,181.7 88.11,178.84 88.11,177.89 87.22,177.01 87.22,174.51 86.54,173.83 86.54,173.43 86.34,173.23 86.34,172.07 85.93,171.66 v1(85.93,171.55)
DBG2: length 87.3
  TOP w0.102: XDP1.15 152.73,193.07 v2(152.94,192.86) ; CPU2.AM44 v1(85.93,172.97)
  BOTTOM w0.102: v1(85.93,172.97) 85.93,173.11 86.34,173.52 86.34,173.91 86.98,174.55 86.98,177.05 87.9,177.97 87.9,178.92 89.88,180.9 89.88,184.83 91.1,186.06 96.19,186.06 105.3,195.17 v4(107.14,195.17) 107.67,195.17 108.79,196.3 128.48,196.3 129.43,195.35 139.44,195.35 140.1,196.01 148.93,196.01 152.08,192.86 v2(152.94,192.86)
DBG3: length 86.5
  TOP w0.102: CPU2.AM45 v1(85.93,173.69) ; v2(152.92,193.75) 152.74,193.57 XDP1.17
  BOTTOM w0.102: v2(152.92,193.75) 152.82,193.85 152.39,193.85 v4(151.75,194.49) 149.99,196.24 140.01,196.24 139.35,195.58 129.53,195.58 128.58,196.53 108.7,196.53 107.85,195.68 105.49,195.68 96.13,186.32 91.04,186.32 89.55,184.83 89.55,180.86 87.7,179.01 87.7,178.06 86.77,177.13 86.77,174.63 85.93,173.79 v1(85.93,173.69)
DBG4: length 83.1
  TOP w0.102: XDP1.27 151.18,196.07 v2(151.67,195.58) ; CPU2.AM47 v1(85.93,174.4)
  BOTTOM w0.102: v1(85.93,174.4) 86.57,175.03 86.57,177.22 87.5,178.14 87.5,179.09 89.35,180.95 89.35,184.95 90.99,186.59 96.08,186.59 105.45,195.96 107.81,195.96 108.6,196.76 128.67,196.76 129.62,195.81 139.25,195.81 139.91,196.47 150.48,196.47 v4(150.81,196.14) 151.37,195.58 v2(151.67,195.58)
DBG5: length 84.8
  TOP w0.102: XDP1.29 151.43,196.57 v2(152.44,195.56) ; v1(85.93,175.11) CPU2.AK48
  BOTTOM w0.102: v1(85.93,175.11) 86.37,175.54 86.37,177.3 87.29,178.23 87.29,179.18 88.1,179.98 88.1,184.09 90.95,186.94 96.1,186.94 106.15,196.99 128.78,196.99 129.73,196.04 139.16,196.04 139.85,196.73 151.64,196.73 v4(152.08,196.29) 152.44,195.93 v2(152.44,195.56)
DBG6: length 82.4
  TOP w0.102: XDP1.33 151.23,197.58 v2(151.62,197.18) ; CPU2.AM48 v1(85.93,175.82)
  BOTTOM w0.102: v2(151.62,197.18) 151.4,197.41 v4(150.32,197.41) 149.94,197.03 139.82,197.03 139.06,196.27 129.83,196.27 128.88,197.22 106.05,197.22 96.01,187.17 90.85,187.17 87.89,184.21 87.89,180.06 86.37,178.54 86.37,178.07 85.55,177.26 85.55,176.29 85.59,176.25 85.59,176.16 v1(85.93,175.82)
DBG7: length 95
  TOP w0.102: XDP1.35 147.17,198.07 v2(146.56,198.68) ; CPU2.AK41 v1(84.94,171.55)
  BOTTOM w0.102: v2(146.56,198.68) 143.88,198.68 v4(143.34,198.15) 143.19,197.99 115.95,197.99 111.81,202.13 104.86,202.13 104.17,201.45 90.98,201.45 88.17,198.64 88.17,189.51 85.88,187.23 85.88,186.18 84.28,184.58 84.28,177.14 83.97,176.83 83.97,175.9 84.54,175.33 84.54,174.83 84.54,174.82 84.54,171.96 v1(84.94,171.55)
DBG8: length 97
  TOP w0.102: CPU2.AB41 v1(81.06,172.26) ; v2(131.73,201.09) 132.93,199.9 134.02,199.9 142.34,191.57 XDP1.10
  BOTTOM w0.089: 80.85,174.84 81.18,174.84 81.46,174.56 81.46,172.69 81.06,172.29 v1(81.06,172.26)
  BOTTOM w0.102: v2(131.73,201.09) 131.43,200.79 117.14,200.79 116.82,201.11 116.81,201.11 113.72,204.21 104.02,204.21 103.32,203.5 88.71,203.5 85.63,200.42 v4(85.63,199.13) 85.63,198.04 84.45,196.86 84.45,192.09 82.99,190.63 82.99,186.98 80.42,184.41 80.42,175.26 80.85,174.84
DBG9: length 95.4
  TOP w0.102: XDP1.12 142.43,192.07 134.2,200.3 133.36,200.3 v2(132.6,201.07) ; CPU2.AB45 v1(81.06,173.69)
  BOTTOM w0.102: v2(132.6,201.07) 132.11,201.55 131.54,201.55 131.34,201.34 v4(123.6,201.34) 116.91,201.34 113.75,204.5 103.99,204.5 103.23,203.73 88.62,203.73 85.08,200.2 85.08,197.88 85.04,197.84 85.04,197.83 84.22,197.01 84.22,192.18 82.76,190.72 82.76,187.08 80.19,184.51 80.19,174.65 81.06,173.79 v1(81.06,173.69)
DBG10: length 96.1
  TOP w0.102: v2(133.51,201.07) 133.93,201.07 141.91,193.09 142.14,193.07 XDP1.16 ; CPU2.AB44 v1(81.06,172.97)
  BOTTOM w0.102: v2(133.51,201.07) 132.71,201.87 v4(120.01,201.87) 116.79,201.87 113.93,204.73 103.9,204.73 103.13,203.96 88.52,203.96 84.85,200.29 84.85,197.98 83.99,197.12 83.99,192.28 82.53,190.82 82.53,187.17 79.96,184.6 79.96,174.59 80.65,173.9 80.65,173.38 v1(81.06,172.97)
DBG11: length 84.6
  TOP w0.089: CPU2.AC53 82.03,178.28 82.17,178.43 82.17,179.19 82.28,179.3
  TOP w0.102: XDP1.18 141.75,193.57 133.77,201.55 131.54,201.55 127.76,197.76 116.84,197.76 113.36,201.24 109.14,201.24 107.29,199.39 101.64,199.39 100.39,198.13 100.39,191.44 v3(99.87,190.92) 96.12,187.17 89.32,187.17 87.51,185.37 84.79,185.37 82.41,182.98 82.41,179.42 82.28,179.3
DBG12: length 85
  TOP w0.089: 82.08,179.38 81.85,179.16 81.85,178.38 81.76,178.28 81.76,177.64 81.83,177.57 81.83,177.29 81.73,177.19 81.73,176.92 CPU2.AB51
  TOP w0.102: 82.08,179.38 82.14,179.44 82.14,183.04 84.95,185.85 87.41,185.85 89.14,187.59 95.68,187.59 100.06,191.96 100.06,198.13 101.93,200 v3(103.61,200) 105.11,201.5 113.43,201.5 116.94,197.99 127.66,197.99 131.45,201.78 133.87,201.78 139.57,196.07 XDP1.28
DBG13: length 85
  TOP w0.089: 81.82,179.42 81.66,179.26 81.66,178.46 81.54,178.34 CPU2.AB52
  TOP w0.102: XDP1.30 139.39,196.57 133.96,202.01 131.35,202.01 127.57,198.22 117.03,198.22 113.53,201.73 102.63,201.73 100.22,199.31 v3(100.19,199.31) 100.19,199.28 99.73,198.83 99.73,191.95 95.72,187.95 88.99,187.95 87.23,186.18 84.74,186.18 81.91,183.35 81.91,179.51 81.82,179.42
DBG14: length 86
  TOP w0.089: 81.46,178.9 81.46,178.52 81.34,178.41 81.34,177.65 81.2,177.51 81.2,177.21 CPU2.AA51
  TOP w0.102: 81.46,178.9 81.46,182.46 81.68,182.68 81.68,183.44 84.77,186.54 87.05,186.54 88.84,188.32 95.77,188.32 99.32,191.87 99.32,199.65 v3(101.28,201.61) 101.62,201.96 113.62,201.96 117.13,198.45 127.47,198.45 131.26,202.24 134.06,202.24 138.72,197.58 XDP1.34
DBG15: length 94.6
  TOP w0.102: XDP1.36 138.77,198.07 136.1,200.75 v2(136.1,200.91) ; CPU2.AB40 v1(81.06,171.55)
  BOTTOM w0.089: v1(81.06,171.55) 81.06,171.6 81.65,172.2 81.65,174.82 81.09,175.38
  BOTTOM w0.102: v2(136.1,200.91) 135.75,200.56 117.02,200.56 113.62,203.96 104.1,203.96 103.41,203.28 88.81,203.28 86.24,200.71 86.24,194.61 v4(85.15,193.52) 84.68,193.05 84.68,191.99 83.22,190.53 83.22,186.89 80.65,184.32 80.65,175.82 81.09,175.38
DBG16: length 93.3
  TOP w0.102: CPU2.AK42 85.08,172.26 v1(84.94,172.26) ; v2(152.75,194.56) 152.74,194.57 XDP1.21
  BOTTOM w0.102: v1(84.94,172.26) 85.38,172.7 85.38,176.16 85.35,176.18 85.35,177.34 86.16,178.16 86.16,178.62 87.69,180.15 87.69,184.33 90.78,187.43 95.92,187.43 105.94,197.45 128.98,197.45 129.93,196.49 138.97,196.49 139.88,197.41 145.84,197.41 146.43,198 146.84,198 147.37,198.53 v4(153.12,198.53) 152.86,198.27 152.86,195.79 152.9,195.75 152.9,195.37 152.75,195.23 v2(152.75,194.56)
DC_19V: length 74.3
  TOP w0.381: 58.57,39.65 58.34,39.88 58.07,39.88 ; 58.07,39.88 58.63,40.44 ; 58.07,39.88 53.82,39.88 53.57,40.13 PR5282.1
  TOP w0.508: PU5205.4 41.54,72.67 41.71,72.85 42.11,72.85 PC5235.2 42.15,72.89 42.15,73.41 42.3,73.56 42.3,74.14 PR5285.1 42.27,74.35 42.97,75.04 47.7,75.04 48.32,74.42 PR9813.1
  TOP w0.635: R79708.1 59.11,47.68 53.31,53.48 53.31,58.49 49.38,62.42 47.78,62.42 47.61,62.59 47.51,62.59 46.53,63.58 46.53,64.59 44.4,66.72 v6(41.48,66.72) 41.48,67.44 41.17,67.74 39.91,67.74 39.13,68.53 39.13,71.99 39.81,72.67 PU5205.4
  BOTTOM w0.635: PR5270.1 54.31,65.35 54.31,68.07 53.25,69.14 50.08,69.14 v4(49.26,68.31) 46.92,68.31 46.12,67.51 44.62,67.51 43.28,66.17 PR5284.1 42.03,66.17 v6(41.48,66.72)
  vias: v3(63.18,46.35) v4(63.28,41.1) v6(62.81,43.32) v6(62.82,39.98) v6(62.87,38.96) v6(63.91,39.95) v6(63.96,38.99) v6(64.98,39.98) v6(65.06,39.01) v6(66.05,39.98) v6(66.12,39.01) v6(67.11,39.95) v6(67.11,39.04)
DC_IN_D: length 6.8
  TOP w0.381: PR5282.2 50.6,39.61 49.4,39.61 48.83,39.04 48.83,38.6 48.14,37.91 v1(48.14,37.85) 47.93,38.06 PQ5005.3
  BOTTOM w0.508: v4(47.53,36.96) 47.53,36.98 48.14,37.59 v1(48.14,37.85)
DCBATOUT: length 174.4
  TOP w0.254: PG4905.1 51.54,45.53 PR5276.2
  TOP w0.381: v1(147.86,210.69) 148.12,210.95 R163.1 R153.1
  TOP w0.508: v1(74.48,117.7) 74.47,117.7 73.71,116.94 R1918.1 73.1,116.33 72.74,115.91 R1164.1 ; v6(57.95,221.87) 58,221.92 62.9,221.92 72.58,212.24 75.66,212.24 PR4429.1 ; v1(139.78,89.13) 139.63,89.28 137.08,89.28 PR101.1
  L3 w0.508: v2(146.41,176.02) 148.46,178.07 148.46,186.42 145.47,189.41 145.47,202.9 146.74,204.17 146.74,209.58 v1(147.86,210.69) ; v1(74.48,117.7) 71.23,120.95 60.89,120.95 54.36,127.48 54.36,127.58 52.37,129.58 52.27,129.58 52.23,129.62 47.78,129.62 46.03,127.86 46.03,126.14 v6(45.71,125.82)
  L4 w0.508: v6(144.8,141.96) 144.14,142.62 144.14,148.73 142.69,150.17 142.69,159.4 143.58,160.29 143.58,167.95 144.27,168.64 144.27,173.88 v2(146.41,176.02)
  BOTTOM w0.305: PR4529.1 21.74,159.11 21.29,159.11
  BOTTOM w0.508: 146.97,91.85 145.7,91.85 142.98,89.13 v1(139.78,89.13) ; 7.4,205.61 9.86,203.15 14.47,203.15 16.16,201.45 16.16,198.91 17.56,197.51 R79915.1 ; R26.1 38.88,119.38 R20.1 41.35,119.39 v2(41.54,119.58)
  vias: v4(6.79,199.72) v4(25.1,137.71) v4(31.01,60.39) v4(42.02,72.18) v4(42.65,126.04) v4(56.49,223.19) v4(58.22,65.89) v4(141.8,103.77) v4(143.67,58.35) v4(149.1,109.12) v6(32.42,56.01) v6(33.31,56.01) v6(33.31,55.12) v6(35.21,52.58) v6(36.18,52.55) v6(42.05,70.83) v6(42.04,69.75) v6(42.93,71.34) v6(42.92,70.35) v6(42.96,69.41) v6(43.85,42.04) v6(44.47,125.87) v6(44.48,124.91) v6(44.53,123.97) v6(44.99,42.04) v6(44.95,39.93) v6(45.54,123.98) v6(45.58,124.92) v6(45.68,40.79) v6(49.39,46.04) v6(49.39,45.07) v6(49.39,44.16) v6(49.39,43.24) v6(49.39,42.33) v6(49.39,41.41) v6(50.33,46.01) v6(50.31,45.07) v6(50.31,44.16) v6(50.31,43.24) v6(50.31,42.33) v6(50.31,41.41) v6(55.36,221.83) v6(56.58,221.83) v6(57.26,68.96) v6(57.39,67.67) v6(58.38,68.88) v6(58.43,67.69) v6(59.6,68.91) v6(59.6,67.67) v6(136.89,102.29) v6(136.91,101.25) v6(136.91,100.17) v6(137.94,102.31) v6(137.94,101.3) v6(137.94,100.2) v6(139.02,101.32) v6(139.07,100.23) v6(140.22,100.2) v6(144.76,140.78) v6(145.75,140.79) v6(145.75,141.94) v6(146.71,141.95) v6(146.67,140.86) v6(147.4,111.18) v6(147.35,110.24) v6(148.34,111.1) v6(148.34,110.11) v6(148.85,41.07)
DCBATOUT_1D8V:
  vias: v3(33.71,218.31) v4(30.82,220.93) v6(31.45,219.89) v6(31.83,220.9) v6(32.37,219.89) v6(32.82,220.85) v6(33.41,219.89)
DCIN_EN: length 3.5
  TOP w0.127: U127.13 133.74,39.1 v3(134.61,39.97) 134.9,40.26 R79749.2
DDC1L_GPU_CLK: length 114
  TOP w0.127: v1(91.26,88.59) 91.04,88.81 91.04,90.55 89.99,91.6 GPU1.AE6
  L4 w0.127: v1(91.26,88.59) 97.48,88.59 98.99,87.08 98.99,86.97 100.52,85.43 103.5,85.43 103.86,85.07 104.45,84.48 119.01,84.48 120.11,83.38 122.37,83.38 128.35,77.39 135.27,77.39 135.32,77.35 139.1,77.35 139.15,77.39 141.98,77.39 144.35,75.02 144.35,72.16 142.48,70.28 142.48,67.16 141.96,66.64 141.96,65.33 141.13,64.5 141.13,62.67 140.41,61.94 140.41,59.38 138.82,57.79 138.82,49.61 137.68,48.46 137.68,47.08 136.88,46.28 136.88,42.23 136.85,42.2 136.85,42.1 135.06,40.31 135.06,33.17 134.48,32.59 134.48,31.07 v2(134.3,30.89)
  BOTTOM w0.127: R80092.2 133,31.76 133,30.61 v4(133.26,30.35) 133.41,30.35 133.94,30.89 v2(134.3,30.89)
DDC1L_GPU_DATA: length 113.4
  TOP w0.127: GPU1.AE5 90.15,90.45 90.15,88.92 v1(90.5,88.57)
  L4 w0.127: v2(133.87,31.57) 133.92,31.62 133.92,32.92 134.4,33.4 134.4,40.26 136.42,42.28 136.42,47.89 138.39,49.86 138.39,57.97 139.97,59.55 139.97,62.14 140.7,62.87 140.7,64.72 141.51,65.53 141.51,66.8 142.04,67.34 142.04,70.41 144.12,72.49 144.12,74.93 142.14,76.91 128.12,76.91 122.12,82.92 119.83,82.92 118.7,84.05 104.27,84.05 103.55,84.77 103.32,85 99.53,85 97.54,86.98 97.54,87.14 96.55,88.14 90.93,88.14 v1(90.5,88.57)
  BOTTOM w0.127: R80093.2 135.79,30.09 v4(135.98,30.28) 135.48,30.77 135,30.77 134.74,31.03 134.74,31.1 134.27,31.57 v2(133.87,31.57)
DDCBUF: length 5.9
  TOP w0.127: U127.14 133.34,39.44 133.79,39.89 133.79,40.26 v2(133.75,40.29) 133.78,40.32 R79744.2
  BOTTOM w0.127: R79744.2 134.4,40.48 134.4,39.75 v4(134.36,39.71) 134.08,39.71 133.75,40.04 v2(133.75,40.29)
DDI0_DDCCLK: length 7.6
  TOP w0.089: 78.24,179.25 78.82,178.67 78.82,177.66 78.93,177.55 78.93,177.31 78.63,177.01 CPU2.T51
  TOP w0.102: v3(78.62,183.39) 78.27,183.03 R1234.2 77.81,181.62 77.81,180.57 77.91,180.47 77.91,179.58 78.24,179.25
DDI0_DDCDATA: length 4.4
  TOP w0.089: CPU2.T52 78.63,178.54 77.92,179.25
  TOP w0.102: R1268.2 77.22,180.21 v3(77.3,180.14) 77.3,179.87 77.92,179.25
DDI0_HPD: length 10.6
  TOP w0.089: CPU2.U51 79.3,177.26 79.3,177.55 79.81,178.07 79.81,179.93 v3(79.56,180.19)
  TOP w0.102: v3(79.56,180.19) 80.02,180.64 80.02,181.57 R1892.2 79.32,182.27 79.32,185.87 R1226.2
DDI0_RCOMP_N: length 2.2
  TOP w0.102: CPU2.G38 74.25,170.48 v1(73.89,170.83)
  BOTTOM w0.102: R1228.1 74.01,170.71 v1(73.89,170.83) 73.89,171.16 v4(73.54,171.51)
DDI0_RCOMP_P: length 2.9
  TOP w0.102: CPU2.F38 73.54,170.48 v1(73.18,170.83)
  BOTTOM w0.102: v1(73.18,170.83) 73.12,170.77 R1228.2 72.92,170.18 72.77,170.33 71.93,170.33 v4(71.68,170.59)
DDI1_RCOMP_N: length 2.5
  TOP w0.102: v1(73.4,175.14) 73.4,175.27 CPU2.F49
  BOTTOM w0.102: v1(73.4,175.14) 73.39,175.14 R1227.1 71.9,174.41 v4(71.76,174.55)
DDI1_RCOMP_P: length 2.5
  TOP w0.102: v1(74.12,175.08) 74.01,175.08 73.7,174.78 CPU2.F47
  BOTTOM w0.102: v4(74.42,174.37) 73.59,174.37 R1227.2 73.55,174.63 74,175.08 v1(74.12,175.08)
DDPC_CTRL_CLK_CONN: length 31
  TOP w0.127: R79733.1 R79738.2 128.41,31.17 129.22,31.17 v2(129.4,31.34) 130.25,31.34 131.34,32.43 U127.32 ; v2(123.4,38.89) 123.79,39.28 U130.1 U130.10 122.27,39.64 121.8,39.17 119.29,39.17 118.63,39.82 HDMI1.15
  BOTTOM w0.127: v2(129.4,31.34) 129.4,31.15 v4(128.54,30.3) 128.54,30.29 127.36,29.11 127.36,28.84 Q1255.D 126.44,28.33 124.12,30.65 123.84,30.65 123.54,30.96 123.54,31.23 123.3,31.47 123.3,38.79 v2(123.4,38.89)
DDPC_CTRL_DATA_CONN: length 38.2
  TOP w0.127: v1(124.69,40.19) 124.58,40.19 124.51,40.12 U130.2 U130.9 122.12,40.12 121.57,39.57 119.62,39.57 118.87,40.32 HDMI1.16 ; U127.33 131.74,32.17 131.44,31.88 v2(131.44,30.89) 131.11,30.56 R79739.2 R79732.1
  BOTTOM w0.127: v2(131.44,30.89) 131.44,28.62 130.97,28.14 130.97,26.37 130.54,25.93 Q1256.D 127.22,25.93 124.32,28.84 v4(124.32,29.41) 123.11,30.62 123.11,31.05 122.87,31.29 122.87,39.29 123.77,40.19 v1(124.69,40.19)
DDR3_DRAM_PWROK: length 85.2
  TOP w0.102: CPU2.AV28 v1(89.97,165.95) ; R537.2 C575.2 98.52,157.99 v1(97.82,157.99)
  L3 w0.127: v1(89.97,165.95) 90.84,165.09 91.91,165.09 92.7,164.3 92.7,162.71 95.47,159.94 95.71,159.94 96.9,158.76 96.9,158.64 97.55,157.99 v1(97.82,157.99)
  L4 w0.127: v2(110.63,144.2) 109.91,144.2 105.09,149.02 103.79,149.02 97.82,154.99 v1(97.82,157.99)
  BOTTOM w0.102: v2(110.63,144.2) 110.91,144.48 125.48,144.48 v4(127.57,142.39) 134.68,142.39 135.14,142.85 137.51,142.85 137.99,142.37 139.23,141.13 139.23,140.35 144.71,134.86 144.71,132.16 149.59,127.28 R532.1
DDR3_DRAM_PWROK_D: length 5.5
  BOTTOM w0.102: R532.2 151.9,128 151.9,129.79 151.71,129.99 Q48.3 149.69,129.99 149.42,130.26 v4(149.4,130.26)
DDR3_DRAMRST_N: length 81.1
  TOP w0.102: CPU2.BA42 v1(91.4,172.81)
  L4 w0.127: v2(140.88,183.39) 140.4,182.91 140.4,181.78 140.95,181.23 140.95,175.08 140.12,174.25 140.12,166.03 137.24,163.16 128.18,163.16 112.7,178.64 100.41,178.64 95.64,173.86 94.6,173.86 93.99,173.25 91.95,173.25 91.51,172.81 v1(91.4,172.81)
  BOTTOM w0.102: R1672.2 138.73,183.57 C576.2 139.73,184.53 v4(139.94,184.32) v2(140.88,183.39)
DDR3_DRAMRST_N_A_1: length 5.1
  TOP w0.102: DIMM1.30 139.19,181.85 139.19,181.85 137.92,181.85 137.88,181.89 v1(137.88,181.89)
  BOTTOM w0.102: v1(137.88,181.89) 138.17,181.6 C47.1 139.31,181.6 v4(139.81,182.09) 139.24,182.66 R1672.1
DDR3_VCCA_PWRGD: length 43.3
  TOP w0.102: v1(101.42,140.13) 101.42,141.33 99.4,143.35 C574.2 R550.2 R543.2 99.37,149 v1(99.35,149.02) ; v1(90.71,164.09) 90.05,164.09 CPU2.AV26 ; v1(98.41,134.13) 97.51,133.24 C380.2 Q49.3
  L3 w0.127: v1(101.42,140.13) 101.42,140.12 100.79,139.49 100.79,136.62 98.41,134.24 v1(98.41,134.13) ; v1(99.35,149.02) 99.35,152.94 95.84,156.45 95.84,157.62 91.18,162.29 91.18,162.84 90.71,163.31 v1(90.71,164.09)
  BOTTOM w0.102: v1(101.42,140.13) 101.42,140.12 101.18,139.88 v4(101.18,139.29)
DDR3_VCCA_PWRGD_3P3: length 6.5
  TOP w0.102: R1601.1 101.53,131.41 v3(101.53,132) 101.53,133.01 100.82,133.72 100.82,134.01 100.43,134.4 99.93,134.4 99.55,134.02 Q49.2
DDR3_VCCA_PWRGD_G: length 5
  TOP w0.102: Q49.6 100.2,130.06 100.04,129.91 99.61,129.91 99.55,129.97 ; 99.55,129.97 99.55,129.9 v3(98.96,129.31) 98.13,129.31 R551.2 ; 99.55,129.97 Q49.5
DDR3_VREF_CA: length 24.2
  TOP w0.254: v1(88.6,165.99) 88.2,165.58 CPU2.AT28 ; v1(97.58,151.76) 98.31,151.04 C372.2 98.31,150.89 C385.1 99.26,150.94 R539.2 100.24,151.35 101.58,152.7 v3(101.73,152.7)
  L3 w0.254: v1(97.58,151.76) 96.43,152.91 96.43,155.19 88.65,162.97 88.65,165.94 v1(88.6,165.99)
DDR3_VREF_CA_R: length 4.5
  TOP w0.254: R539.1 101.28,150.05 R545.2 R542.1 101.29,151.47 101.77,151.94 102.8,151.94 v3(103.01,152.16)
DDR3_VREF_DQ: length 19
  TOP w0.254: v1(89.26,165.95) 88.91,165.6 CPU2.AU28 ; C572.1 98.35,156.2 C573.2 99.32,156.12 R1214.2 97.65,155.13 v3(97.36,155.42) 97.19,155.59 v1(97.19,156.59)
  L3 w0.254: v1(97.19,156.59) 97.19,157.93 96.6,158.52 96.6,158.64 95.59,159.65 95.35,159.65 92.38,162.62 92.38,164.18 91.76,164.8 90.42,164.8 v1(89.26,165.95)
DDR3_VREF_DQ_R: length 3.6
  TOP w0.254: R1215.2 98.3,153.1 v3(97.35,154.05) 97.54,154.24 R1214.1 R1216.1
DDR_VDDQ: length 123.4
  TOP w0.254: v1(133.55,165.1) 133.77,164.88 135.22,164.88 ; CPU2.AY10 v1(89.82,156.31) CPU2.AV10 ; CPU2.AY44 v1(89.82,173.69) CPU2.AV44 ; DIMM1.87 131.99,162.35 132.2,162.56 134.77,162.56 v1(135.82,163.6) ; 138.46,156.65 v1(137.94,157.18) ; CPU2.AV16 89.81,159.48 v1(89.81,159.08) ; v1(134.3,151.26) 134.3,151.19 134.91,150.57 136.26,150.57 v1(136.99,151.31) ; v1(91.8,176.7) 91.86,176.64 CPU2.BE51 ; v1(89.23,160.14) 88.91,160.46 CPU2.AU18 ; v1(135.36,153.09) 135.36,153.59 v1(135.85,154.08) ; CPU2.BE53 v1(93.32,178.44) ; v1(133.74,166.27) 134.7,166.27 v1(134.78,166.19) 135.22,165.75 135.22,164.88 ; CPU2.AU36 v1(88.55,169.84) ; 135.22,164.88 v1(135.46,164.88) ; v1(91.8,153.3) 91.86,153.36 CPU2.BE3 ; v1(136.25,158.42) 136.25,158.12 v1(135.64,157.51) ; CPU2.AV38 v1(89.26,170.83) ; 132.59,164.15 133.29,164.15 v1(133.74,163.7) ; v1(95.4,153.7) 95.08,154.01 CPU2.BJ5 94.77,153.96 CPU2.BH5 93.74,153.96 v1(93.68,153.9) 93.64,153.87 CPU2.BG3 93.66,153.37 CPU2.BH4 94.67,153.37 CPU2.BJ3 95.13,153.23 v1(95.39,152.97) 95.03,152.62 CPU2.BJ2 ; CPU2.BE1 v1(93.32,151.56) ; v1(135.96,161.59) 135.96,160.97 v1(135.39,160.4) 135.39,160.44 134.82,161.01 134.06,161.01 v2(133.5,161.57) ; CPU2.BJ52 CPU2.BJ51
  TOP w0.305: v1(137.07,166.42) 137.07,166.34 137.76,165.65 DIMM1.76 ; DIMM1.75 132.13,165.95 132.37,165.71 133.18,165.71 v1(133.74,166.27) ; v1(135.85,154.08) 136.62,154.85 DIMM1.112 ; v1(135.82,163.6) 137.37,162.05 DIMM1.88 ; DIMM1.100 136.28,158.45 v1(136.25,158.42) ; DIMM1.123 132.28,151.55 v1(132.68,151.15) ; 132.55,156.95 DIMM1.105 ; 132.55,156.95 133.49,156.01 v1(133.49,155.86) ; 132.55,156.95 132.73,156.95 v1(133.1,157.32) ; DIMM1.81 132.59,164.15 v1(133.55,165.1) ; v1(137.13,155.8) 137.14,155.8 137.98,156.64 138.16,156.64 138.17,156.65 DIMM1.106 ; DIMM1.111 131.29,155.06 132.22,155.06 132.25,155.03 134.54,155.03 v1(135.21,155.7) ; v1(133.48,159.11) 133.43,159.06 133.43,158.98 132.98,158.52 132.36,158.52 132.13,158.75 DIMM1.99 ; DIMM1.117 133.22,153.35 v1(133.94,154.08) ; v1(137.93,153.03) 138.46,153.03 138.48,153.05 DIMM1.118 ; v1(95.4,176.3) 95.08,175.99 CPU2.BJ49 94.77,176.04 CPU2.BH49 93.74,176.04 v1(93.68,176.1) 93.64,176.13 CPU2.BG51 94.23,176.64 CPU2.BH50 94.67,176.63 CPU2.BJ51 95.13,176.77 v1(95.39,177.03) ; v1(137.07,164.67) 137.09,164.64 137.09,164.47 137.71,163.85 DIMM1.82 ; R537.1 v2(100.31,156.03) ; DIMM1.94 137.9,160.25 v1(137.9,160.25)
  TOP w0.33: DIMM1.124 137.05,151.25 v1(136.99,151.31) ; DIMM1.93 132.47,160.55 v2(133.5,161.57)
  TOP w0.381: R550.1 R543.1 101.39,149.02 101.71,149.02 102.18,149.49 R545.1 103.87,150.06 v1(104.05,150.24) ; v1(97.19,153.06) 97.19,153.03 98.01,152.21 R1215.1
  BOTTOM w0.508: 140.1,151.5 140.85,151.5 142.07,150.28 142.07,140.81 144.51,138.37 150.39,138.37 v4(151.32,139.29) 151.37,139.34 152.74,139.34 152.76,139.32 155.3,139.32 R572.1
  vias: v1(87.71,169.17) v1(87.71,160.83) v4(125.13,152.67)
DDSP_C_HPD_CONN: length 18.5
  TOP w0.102: v1(126.02,39.95) 126.02,40.07 R80113.2 124.92,41.16 U130.4 U130.7 122.27,41.16 122.08,41.35 122.08,41.61 121.41,42.28 119.65,42.28 119.2,41.82 HDMI1.19 ; U127.28 v2(129.2,34.57)
  L3 w0.127: v1(126.02,39.95) 128.15,37.82 128.15,35.64 129.2,34.59 v2(129.2,34.57)
  BOTTOM w0.102: v1(126.02,39.95) 126.04,39.98 v4(126.04,40.74)
DDSP_D_TX_N0: length 32.4
  BOTTOM w0.254: R79726.2 v4(140.39,28.14) 141.08,28.83 141.08,30.61 140.62,31.06 R79724.2 R79728.2 141.19,32.08 Q1254.D 141.89,31.92 141.89,34.14 140.47,35.56 139.95,35.56 R79725.2 R79729.2 139.44,36.07 140.77,36.07 141.92,37.22 141.92,38.07 141.05,38.94 R79727.2 R79731.2 139.67,39.67 141.63,39.67 142.35,40.4 142.35,42.47 141.97,42.85 R79730.2
DDSP_D_TX_N2: length 3.1
  BOTTOM w0.102: Q1254.G 144.5,33.61 145.04,33.61 v4(145.05,33.61) 145.55,33.11 R79723.2
DGPU_PWROK: length 171.2
  TOP w0.102: v2(65.79,126.99) 65.76,127.03 65.76,130.01 PR5261.2 64.83,131.25 64.28,131.8 v1(63.38,131.8) ; PR6.2 124.4,77.08 v1(124.42,77.06) 124.42,77.41 PR14.2 ; v1(139.76,109.3) 140.29,109.83 141.32,109.83 PR9785.2 ; Q97.5 75.65,119.51 74.4,120.75 v1(74.4,121.03)
  L3 w0.127: v1(63.38,131.8) 63.38,131.8 79.41,131.8 88.04,123.16 97.59,123.16 97.65,123.22 105.35,123.22 105.52,123.04 118.21,123.04 122.09,119.16 132.19,119.16 132.58,118.77 132.6,118.77 134.67,116.71 134.78,116.71 135.18,116.31 136.69,114.81 137.19,114.81 138.09,113.9 138.09,111.45 139.76,109.78 v1(139.76,109.3) ; v1(74.4,121.03) 74.4,124.41 70.78,128.03 66.61,128.03 65.79,127.2 v2(65.79,126.99)
  L4 w0.127: v1(147.65,86.61) 149.44,88.4 149.44,100.17 140.31,109.3 v1(139.76,109.3)
  BOTTOM w0.102: v1(124.42,77.06) 124.45,77.03 135.43,77.03 136.53,78.13 v4(139.11,78.13) 139.18,78.13 143.48,82.42 145.07,82.42 147.48,84.83 147.48,86.45 v1(147.65,86.61)
DGPU_PWROK_1D5V: length 4.3
  TOP w0.102: PU7.8 60.97,131.2 61.21,130.95 PC5433.1 61.69,130.94 v3(62.69,130.94) 63.94,130.94 PR5261.1
DIMM1_SA0: length 4.1
  TOP w0.102: v2(129.57,129.92) 130.14,129.35 DIMM1.197
  BOTTOM w0.102: v2(129.57,129.92) 129.65,130 v4(130.61,130) R579.1
DIMM1_SA1: length 7.5
  TOP w0.102: v2(127.54,130.07) 127.54,130.07 129.47,128.15 DIMM1.201
  BOTTOM w0.102: R581.1 126.55,128.87 v4(126.45,128.97) 126.45,129.34 127.18,130.07 v2(127.54,130.07)
DIMM_TMPIN2+: length 162.4
  TOP w0.203: U109.86 119.6,55.94 v2(120.07,56.41)
  TOP w0.254: v1(108.64,115.32) 108.82,115.14 109.67,115.14 112.4,117.87 112.4,124.26 112.4,124.73 112.4,124.73 112.4,124.78 104.5,132.68 103.56,132.68 v1(102.33,133.91) ; v1(102.93,139.88) 103.65,140.59 103.65,147.06 105.31,148.73 105.31,155.91 102.41,158.81 RT1.1
  L3 w0.254: v1(102.93,139.88) 102.34,139.29 102.34,133.92 v1(102.33,133.91)
  L4 w0.254: v1(96.5,81.46) 95.51,80.47 92.77,80.47 90.84,78.53 90.84,74.79 95.21,70.42 95.21,68.9 99.54,64.57 101.71,64.57 104.24,62.03 104.24,61.47 106.48,59.23 107.46,59.23 107.77,59.54 108.79,59.54 109.15,59.89 111.09,59.89 111.57,60.38 114.81,60.38 116.18,59.01 118.94,59.01 119.21,59.28 122.4,59.28 122.85,58.84 122.85,56.89 122.37,56.41 v2(120.07,56.41)
  BOTTOM w0.254: C231.2 121.22,55.27 v2(120.07,56.41) 119.72,56.06 v4(118.96,56.06) 118.2,56.06 118.05,56.21 118,56.21 117.95,56.26 117.17,56.26 R397.1 ; v1(108.64,115.32) 108.64,114.31 106.89,112.55 106.89,86.96 101.79,81.86 96.91,81.86 v1(96.5,81.46)
DIMM_TMPIN2-: length 151.2
  TOP w0.254: v1(101.49,133.9) 101.49,133.84 103.21,132.12 104.22,132.12 111.84,124.5 111.84,118.1 109.44,115.7 v1(109.28,115.7) ; v1(102.14,139.95) 102.14,140.1 102.99,140.95 102.99,147.44 104.55,149.01 104.55,155.85 102.48,157.92 RT1.2
  L3 w0.254: v1(102.14,139.95) 102.12,139.95 101.66,139.5 101.66,134.06 v1(101.49,133.9)
  L4 w0.254: v2(123.41,55.87) 123.41,58.82 122.08,60.15 115.58,60.15 114.8,60.93 111.34,60.93 110.86,60.45 108.91,60.45 108.63,60.17 107.6,60.17 107.23,59.79 106.71,59.79 104.8,61.7 104.8,62.26 101.94,65.13 99.78,65.13 95.77,69.14 95.77,70.65 91.4,75.02 91.4,78.3 93,79.91 95.87,79.91 v1(97.26,81.31)
  BOTTOM w0.254: v2(123.41,55.87) 123.45,55.87 R399.2 123.57,54.54 v4(123.21,54.54) 122.47,55.27 C231.1 ; v1(109.28,115.7) 109.28,114.15 107.45,112.32 107.45,86.73 102.02,81.31 v1(97.26,81.31)
DISCHANGE_EN: length 317.9
  TOP w0.102: U109.20 130.09,59.54 130.07,59.56 128.85,59.56 128.56,59.27 128.56,58.34 129.93,56.97 129.93,56.48 129.94,56.47 129.94,56.21 129.23,55.5 127.77,55.5 125.71,57.56 125.71,60.72 124.05,62.38 123.12,62.38 v2(122.87,62.64) ; v1(44.44,223.07) 44.48,223.07 44.48,223.08 R1841.1
  L3 w0.127: v1(44.44,223.07) 41.52,225.99 11.99,225.99 6.57,220.58 6.57,205.55 10.08,202.04 10.08,189.66 11.36,188.38 14.95,188.38 15.32,188.01 15.32,169.39 17.6,167.12 17.6,166.66 15.63,164.69 15.63,153.03 16.4,152.26 16.4,142.55 16.4,142.13 20.64,137.9 29.49,137.9 30.29,137.09 30.29,137.09 31.25,136.13 36.77,130.6 36.77,120.88 38.12,119.53 38.12,115.9 39.43,114.59 39.85,114.59 41.4,113.04 41.4,80.05 43.55,77.89 49.44,77.89 50.33,77 54.88,77 57.51,74.37 87.04,74.37 87.82,75.15 88.89,75.15 92.79,71.25 95.6,71.25 96.03,70.82 101.02,70.82 v2(101.2,70.64)
  L4 w0.127: v2(122.87,62.64) 122.84,62.64 121.99,61.79 118.24,61.79 117.55,62.47 116.86,62.47 111.56,67.77 107.04,67.77 104.67,70.14 103.93,70.14 102.58,70.14 101.7,70.14 v2(101.2,70.64)
  BOTTOM w0.102: v2(122.87,62.64) 122.8,62.7 R79945.1 ; v4(45.25,223.19) 45.13,223.07 v1(44.44,223.07)
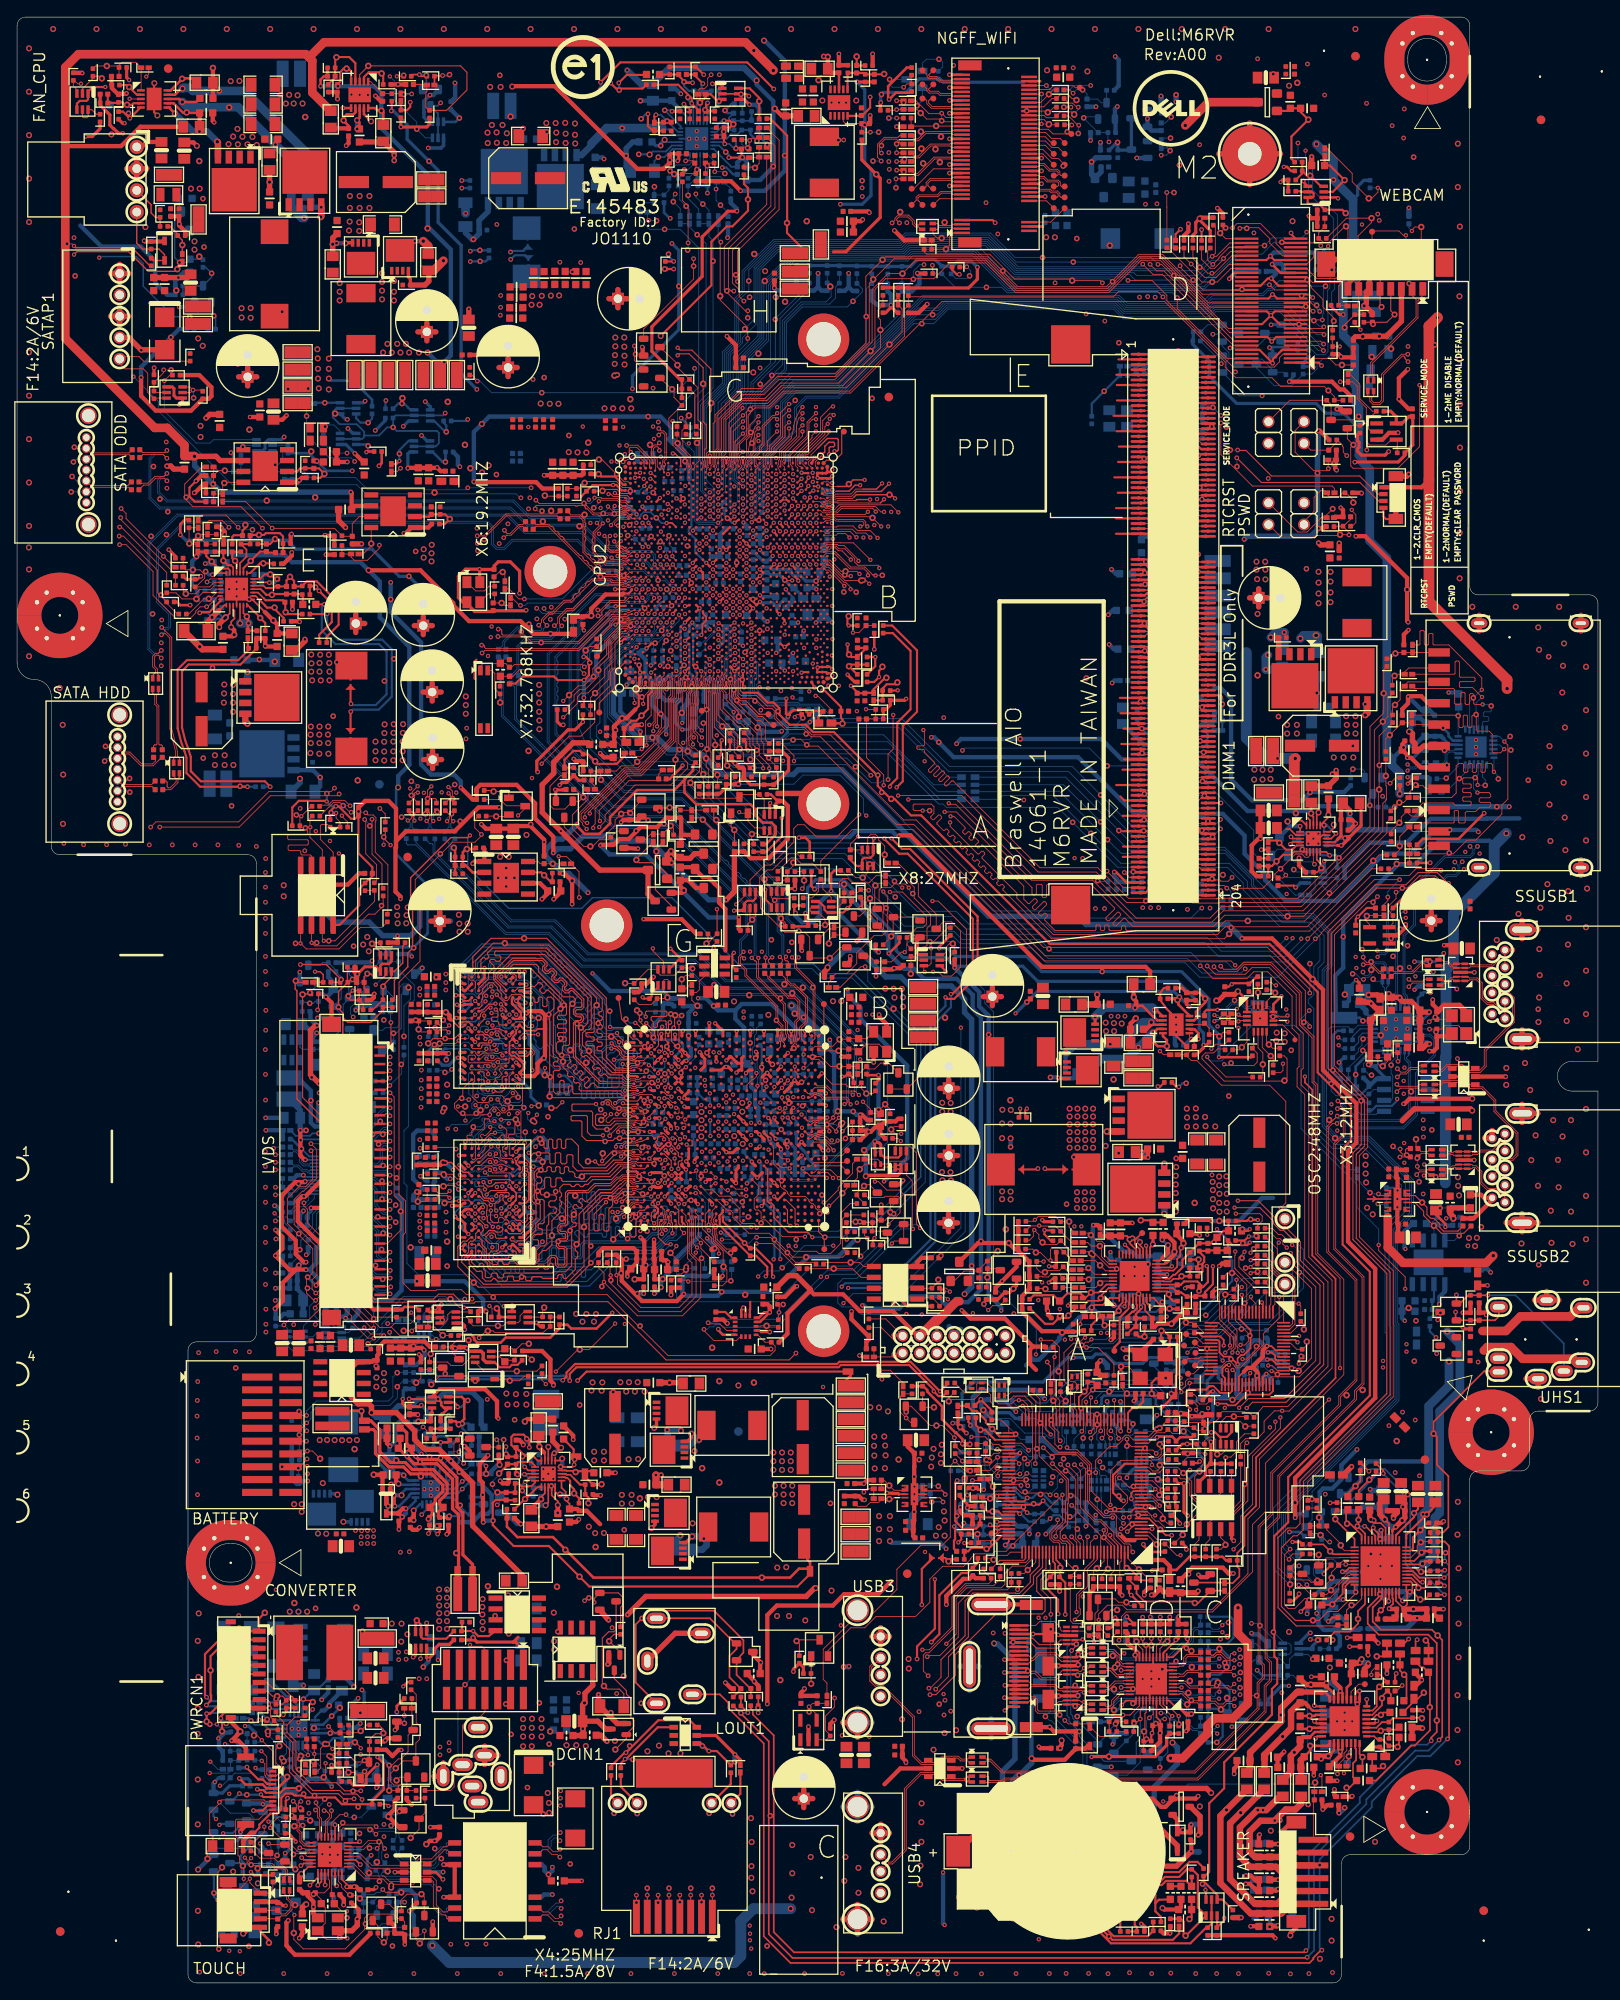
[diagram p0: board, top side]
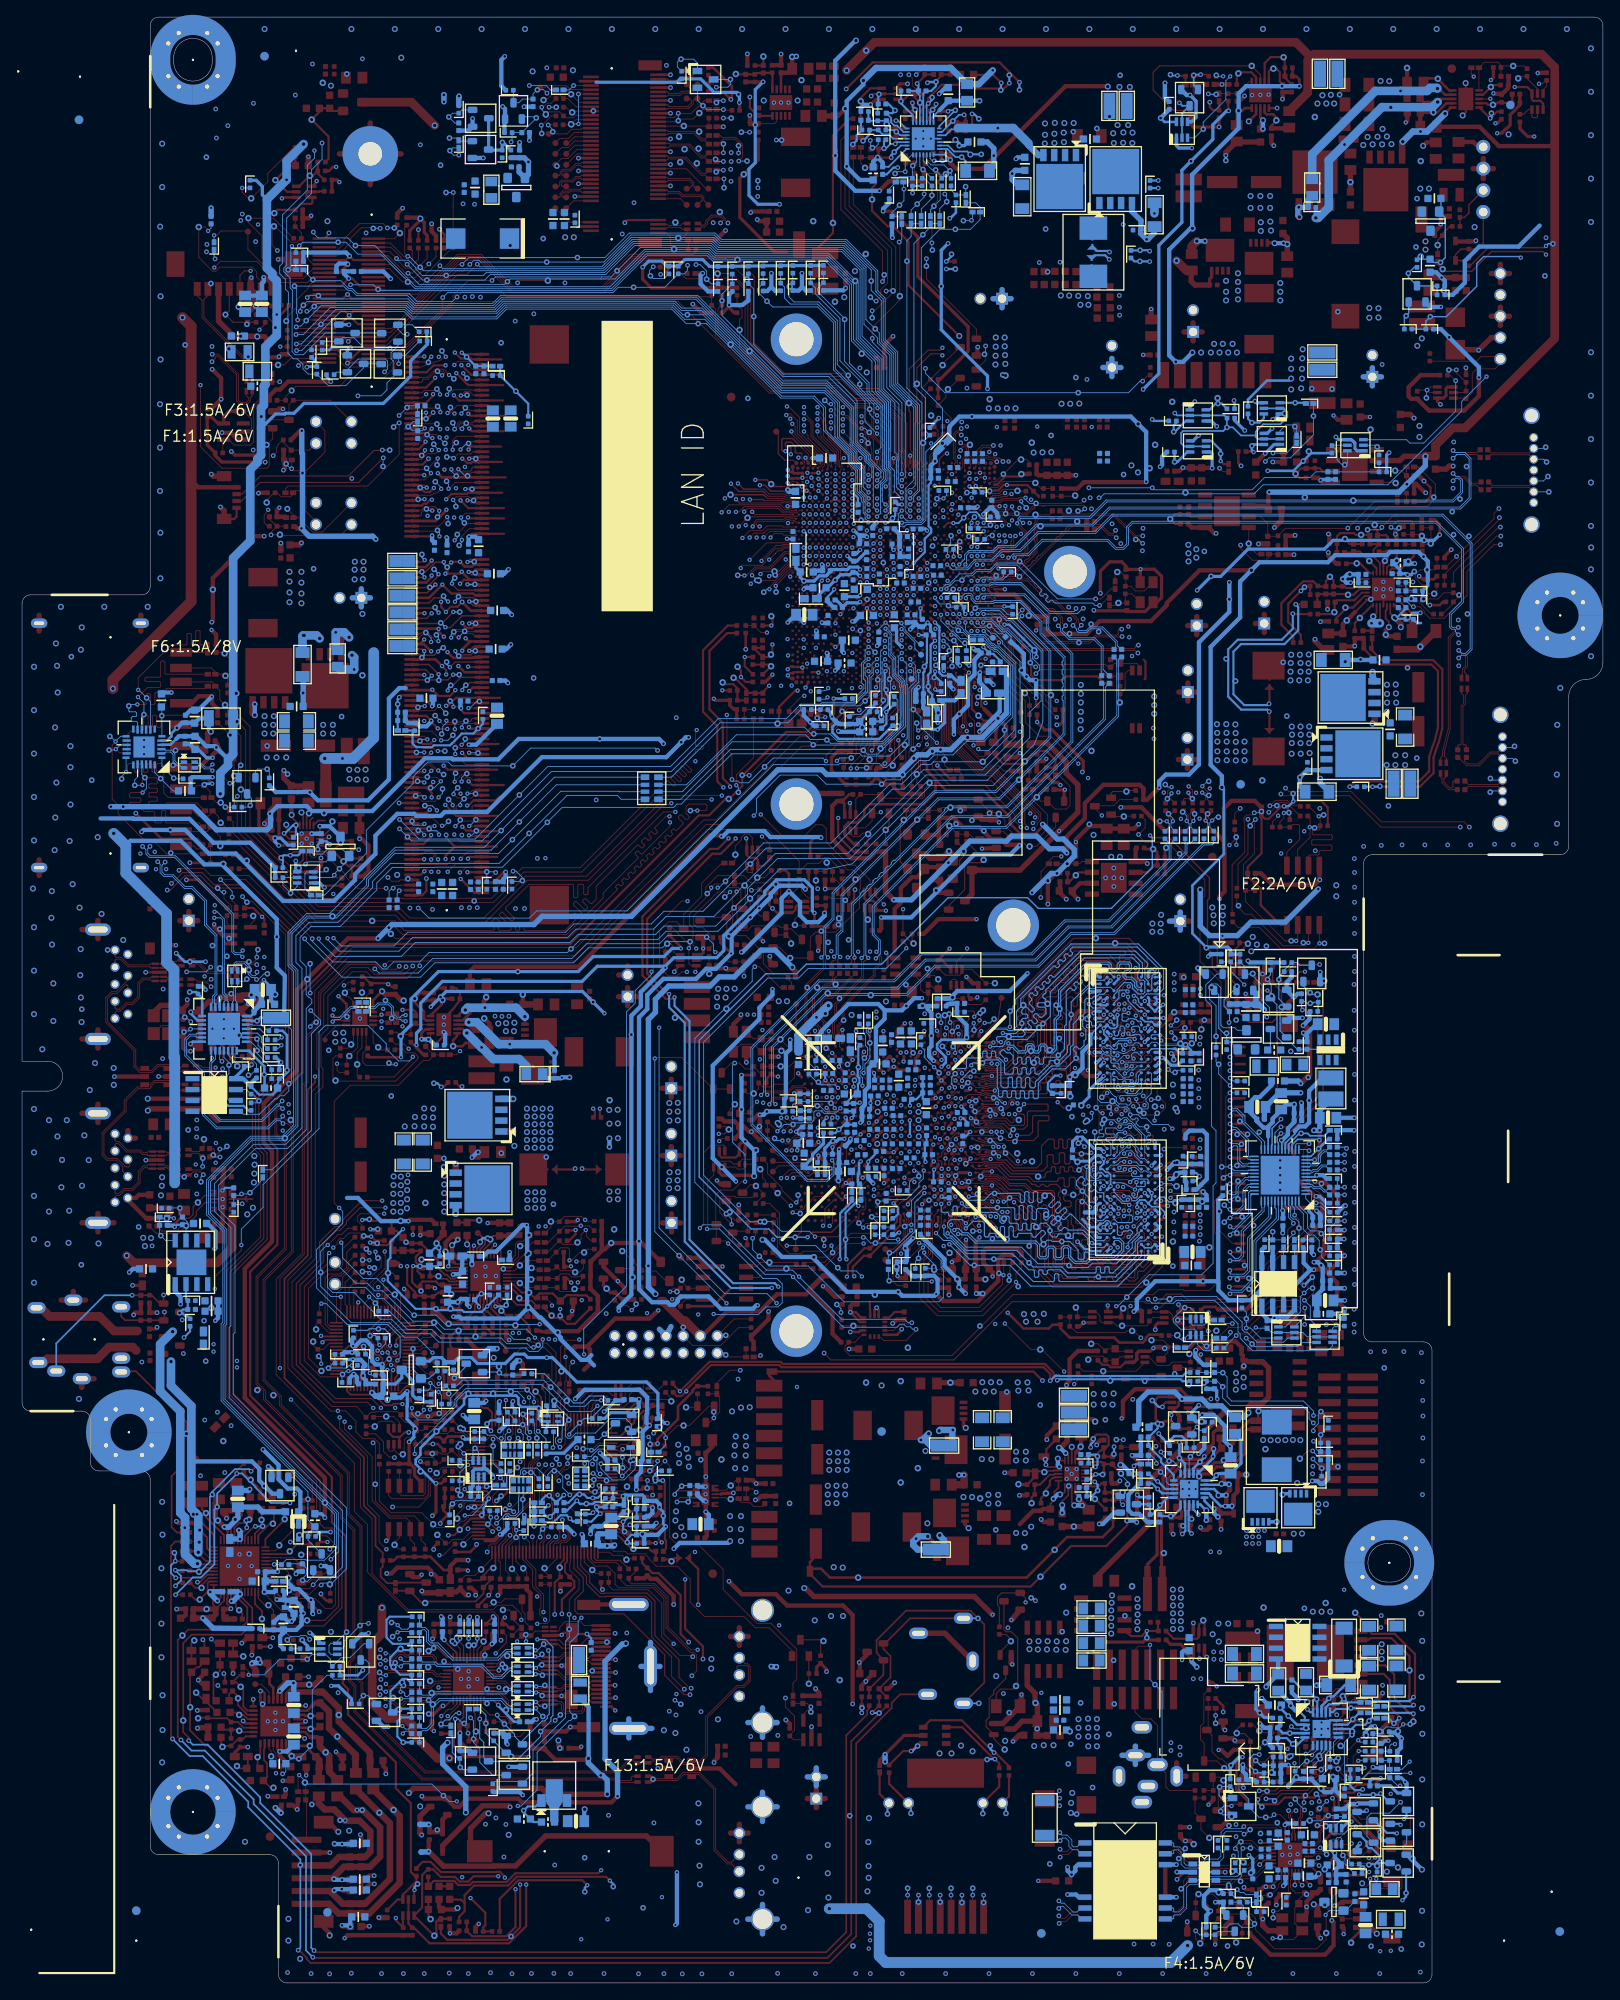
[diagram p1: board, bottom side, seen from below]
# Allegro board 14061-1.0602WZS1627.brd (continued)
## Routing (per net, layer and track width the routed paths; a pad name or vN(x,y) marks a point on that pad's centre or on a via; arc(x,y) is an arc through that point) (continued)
DP1_AUXN: length 62.1
  TOP w0.102: R80100.2 50.6,136.67 50.6,136.21 v1(50.32,135.92)
  L4 w0.127: v2(30.23,92.2) 30.54,92.51 30.87,92.51 31.38,93.02 31.38,94.75 32.59,95.97 32.59,99.35 31.67,100.27 31.67,122.6 43.02,133.95 48.48,133.95 50.15,135.62 50.15,135.75 v1(50.32,135.92)
  BOTTOM w0.102: v4(50.83,136.78) 50.32,136.26 v1(50.32,135.92) 50.54,135.69 50.54,135.22 R80091.2 ; v2(30.23,92.2) C4269.1 R1074.2
DP1_AUXP: length 62.2
  TOP w0.102: v1(51.04,135.91) 50.82,136.14 50.82,136.79 R80099.2
  L4 w0.127: v2(30.23,93.09) 31.11,93.97 31.11,94.86 32.32,96.08 32.32,99.24 31.41,100.16 31.41,122.71 42.91,134.22 48.37,134.22 49.84,135.69 49.84,136.1 50.11,136.36 50.59,136.36 v1(51.04,135.91)
  BOTTOM w0.102: R80090.2 50.76,135.22 50.76,135.63 v1(51.04,135.91) v4(51.85,135.91) ; v2(30.23,93.09) C4268.1 R1079.1
DP1_HPD: length 78.1
  TOP w0.102: v2(42.45,137.41) 43.09,136.78 R80237.1 ; Q6703.G 72.24,189.84 v2(72.24,191.52)
  L4 w0.127: v2(42.45,137.41) 42.45,138.51 44.89,140.94 45.09,140.94 46.45,142.31 46.45,167.96 60.38,181.89 60.38,186.16 63.84,189.61 65.47,189.61 68.92,193.06 71.28,193.06 72.24,192.1 v2(72.24,191.52)
  BOTTOM w0.102: v4(72.37,190.55) 72.24,190.68 v2(72.24,191.52)
DP1_TXN0: length 57.3
  TOP w0.102: v1(47.92,135.94) 47.96,135.94 48.3,136.28 48.3,136.86 R80075.1
  L4 w0.127: v2(30.23,96.01) 30.54,95.7 30.85,95.7 31.55,96.4 31.55,98.82 30.63,99.74 30.63,123.11 42.57,135.05 48.09,135.05 48.42,135.38 48.42,135.59 48.22,135.79 48.07,135.79 v1(47.92,135.94)
  BOTTOM w0.102: C301.1 v2(30.23,96.01) ; v4(47.79,136.78) 47.79,136.08 v1(47.92,135.94) 48,135.87 48,135.85 48.21,135.63 48.21,135.21 R80078.2
DP1_TXN1: length 54.4
  TOP w0.102: v1(45.73,136) 45.89,136 46.2,136.31 46.2,136.51 45.86,136.85 R80077.1
  L4 w0.127: v1(45.73,136) 45.55,135.82 44.68,135.82 44.27,136.23 42.64,136.23 31.62,125.21 30.86,125.21 29.82,124.17 29.82,99.44 29.95,99.31 29.96,99.31 30.77,98.5 30.77,97.49 30.65,97.36 30.36,97.36 30.08,97.64 v2(30.01,97.64)
  BOTTOM w0.102: C4267.1 30.13,97.79 30.01,97.66 v2(30.01,97.64) ; v4(44.99,136.4) 45.33,136.4 v1(45.73,136) 46,135.72 46,135.23 R80080.2
DP1_TXP0: length 57.8
  TOP w0.102: v1(48.7,135.94) 48.52,136.12 48.52,136.6 R80074.1
  L4 w0.127: v1(48.7,135.94) 48.7,135.28 48.2,134.78 42.68,134.78 30.9,123 30.9,99.85 31.82,98.93 31.82,96.29 30.96,95.43 30.54,95.43 v2(30.23,95.12)
  BOTTOM w0.102: R80079.2 48.43,135.21 48.43,135.6 48.7,135.88 v1(48.7,135.94) 48.7,136.53 v4(49.18,137.01) ; C300.1 v2(30.23,95.12)
DP1_TXP1: length 54.5
  TOP w0.102: R80076.1 46.41,136.67 46.41,136.08 v1(46.5,135.99)
  L4 w0.127: v2(30.23,96.9) 30.42,97.09 30.76,97.09 31.04,97.37 31.04,98.61 30.12,99.53 30.12,99.54 30.09,99.58 30.09,124.06 30.97,124.94 31.73,124.94 42.75,135.97 44.16,135.97 44.57,135.56 46.07,135.56 v1(46.5,135.99)
  BOTTOM w0.102: v4(46.26,136.78) 46.5,136.54 v1(46.5,135.99) 46.22,135.71 46.22,135.23 R80081.2 ; C4265.1 v2(30.23,96.9)
DP_AUXN: length 4.4
  TOP w0.102: NGFF1.20 119.5,209.5 119.65,209.65 120.81,209.65 121.01,209.45 121.67,209.45 121.83,209.3 121.83,209.04 121.7,208.91 TP73.1
DP_AUXP: length 4.8
  TOP w0.102: TP72.1 122.16,208.91 122.03,209.04 122.03,209.38 121.76,209.65 121.1,209.65 120.9,209.85 119.65,209.85 119.5,210 NGFF1.22
DP_CPU_AUXN: length 69
  TOP w0.102: R80100.1 50.72,138.65 50.72,138.96 v1(50.49,139.19) ; CPU2.K42 75.68,172.34 v1(76.23,172.34)
  L4 w0.127: v1(50.49,139.19) 51.67,140.37 51.67,168.81 64.18,181.32 71.62,181.32 75.33,177.6 75.33,174.21 75.64,173.91 75.64,172.93 75.96,172.61 75.97,172.61 v1(76.23,172.34)
  BOTTOM w0.102: v4(50.97,138.55) 50.49,139.03 v1(50.49,139.19)
DP_CPU_AUXP: length 69.3
  TOP w0.102: R80099.1 50.93,138.29 50.93,139.45 v1(50.47,139.91) ; CPU2.M42 76.27,173.02 v1(76.13,173.02)
  L4 w0.127: v1(76.13,173.02) 75.9,173.25 75.9,174.02 75.6,174.33 75.6,177.72 71.73,181.58 64.07,181.58 51.4,168.92 51.4,140.48 50.83,139.91 v1(50.47,139.91)
  BOTTOM w0.102: v4(51.21,140.21) 50.91,139.91 v1(50.47,139.91)
DP_CPU_TXN0: length 68.6
  TOP w0.089: 74.46,178.47 74.48,178.47 74.72,178.23 74.72,177 CPU2.H51
  TOP w0.102: R80075.2 48.04,138.08 48.04,139.55 v1(48.48,139.99) ; 74.34,179.69 74.24,179.59 74.24,178.7 74.46,178.47 ; 74.34,179.69 v3(74.07,179.96) ; 74.34,179.69 74.59,179.94 74.92,179.94 v2(75.17,180.19)
  L4 w0.127: v2(75.17,180.19) 75.14,180.19 74.92,179.96 74.58,179.96 71.74,182.8 64.19,182.8 50.57,169.18 50.57,141.36 49.18,139.97 48.5,139.97 v1(48.48,139.99)
DP_CPU_TXN1: length 71.6
  TOP w0.089: CPU2.K52 75.87,177.58 75.87,177.74 75.87,177.74 75.72,177.89 75.72,177.91 75.71,177.91 75.71,178.03 76,178.32 76,179.03 76.02,179.05 76.02,179.07
  TOP w0.102: v2(75.09,181.86) 75.37,181.58 75.66,181.58 76.02,181.23 76.02,179.07 ; v1(46.88,140.01) 46.3,139.43 46.3,138.48 45.87,138.05 R80077.2
  L4 w0.127: v2(75.09,181.86) 74.9,181.67 74.19,181.67 72.28,183.58 63.87,183.58 49.79,169.49 49.79,142.47 47.33,140.01 v1(46.88,140.01)
  BOTTOM w0.102: v4(46.13,140.59) 46.3,140.59 v1(46.88,140.01)
DP_CPU_TXP0: length 69
  TOP w0.089: CPU2.J51 74.91,177.38 74.91,178.31 74.66,178.56 74.66,178.58 74.66,178.58
  TOP w0.102: 74.66,178.58 74.46,178.79 74.46,179.5 74.68,179.73 74.95,179.73 75.17,179.51 v2(75.17,179.3) ; v1(48.5,139.25) 48.25,139 48.25,138.71 48.38,138.58 48.94,138.58 49.07,138.46 R80074.2
  L4 w0.127: v2(75.17,179.3) 74.77,179.69 74.47,179.69 71.63,182.54 64.3,182.54 50.84,169.07 50.84,141.25 49.26,139.67 48.8,139.67 48.5,139.38 v1(48.5,139.25)
  BOTTOM w0.102: v1(48.5,139.25) 48.5,139.02 v4(48.04,138.56)
DP_CPU_TXP1: length 71.4
  TOP w0.089: CPU2.K51 75.67,176.77 75.67,177.03 75.41,177.29 75.41,177.56 75.52,177.67 75.52,178.11 75.81,178.4 75.81,179.03 75.8,179.05 75.8,179.07
  TOP w0.102: 75.8,179.07 75.8,181.14 75.57,181.37 75.35,181.37 v2(75.09,181.1) ; R80076.2 46.91,138.06 46.51,138.46 46.51,139.19 46.59,139.27 v1(46.89,139.27)
  L4 w0.127: v1(46.89,139.27) 46.96,139.27 50.06,142.36 50.06,169.38 63.98,183.31 72.17,183.31 74.08,181.41 74.79,181.41 v2(75.09,181.1)
  BOTTOM w0.102: v1(46.89,139.27) 46.56,138.94 v4(46.13,138.94)
DP_GPU_AUXN: length 84.6
  TOP w0.102: GPU1.AD11 89.02,95.8 89.39,95.43 90.28,95.43 v1(90.41,95.3)
  BOTTOM w0.102: 98.98,99.94 93.05,94.01 90.84,94.01 90.22,94.63 90.22,95.14 90.38,95.3 v1(90.41,95.3) ; 98.98,99.94 99.49,100.44 99.49,109.35 91.7,117.13 82.89,117.13 79.74,120.28 66.78,120.28 62.91,124.15 57.79,124.15 50.54,131.39 50.54,133.37 R80091.1 ; 98.98,99.94 v4(98.71,100.2)
DP_GPU_AUXP: length 86.1
  TOP w0.102: v1(90.21,96.24) 90.03,96.42 89.58,96.42 GPU1.AD13
  BOTTOM w0.102: v1(90.21,96.24) 90,96.03 90,94.54 90.75,93.79 93.14,93.79 99.7,100.35 99.7,109.44 92.9,116.24 ; 92.9,116.24 91.79,117.35 82.98,117.35 79.83,120.5 66.87,120.5 63,124.37 57.88,124.37 50.76,131.48 50.76,133.37 R80090.1 ; 92.9,116.24 v4(93.12,116.46)
DP_GPU_TXN0: length 72.2
  TOP w0.102: v1(97.8,103.91) 97.8,103.94 97.61,104.12 95.32,104.12 94.71,104.74 93.34,104.74 GPU1.AK22
  BOTTOM w0.102: v1(97.8,103.91) 98,104.11 98,109.58 91.31,116.27 82.51,116.27 81.78,117 ; 81.78,117 79.21,119.57 66.36,119.57 62.49,123.44 57.44,123.44 48.67,132.21 48.67,133.19 48.57,133.29 48.31,133.29 R80078.1 ; 81.78,117 v4(81.57,116.79)
DP_GPU_TXN1: length 74.6
  TOP w0.102: GPU1.AJ21 92.7,103.6 arc(92.85,103.62) 93,103.69 arc(93.05,103.72) 93.1,103.77 93.2,103.87 arc(93.22,103.88) 93.23,103.89 arc(93.29,103.92) 93.35,103.93 93.46,103.93 93.52,103.92 93.75,103.82 93.87,103.82 94.28,103.42 97.02,103.42 97.15,103.29 97.15,102.98 96.98,102.82 v1(96.83,102.82)
  BOTTOM w0.102: v4(89.34,115.19) 89.34,115.54 ; 89.34,115.54 81.42,115.54 78.1,118.85 66,118.85 62.2,122.66 57.15,122.66 46.66,133.15 45.73,133.15 45.54,133.33 R80080.1 ; 89.34,115.54 90.97,115.54 97.07,109.44 97.07,103.06 v1(96.83,102.82)
DP_GPU_TXP0: length 72.1
  TOP w0.102: GPU1.AL23 93.65,104.95 94.8,104.95 95.41,104.34 97.62,104.34 97.62,104.34 97.98,104.34 97.98,104.34 98,104.34 98,104.34 98.06,104.34 v1(98.51,103.89)
  BOTTOM w0.102: v1(98.51,103.89) 98.22,104.18 98.22,109.67 91.4,116.48 82.6,116.48 79.3,119.79 66.45,119.79 62.58,123.65 57.53,123.65 49.31,131.88 ; 49.31,131.88 48.89,132.3 R80079.1 ; 49.31,131.88 v4(49.54,132.11)
DP_GPU_TXP1: length 74.4
  TOP w0.102: v1(97.54,102.79) 97.37,102.97 97.37,103.38 97.11,103.63 94.37,103.63 93.96,104.04 93.79,104.04 93.59,104.12 arc(93.53,104.14) 93.48,104.15 93.35,104.15 arc(93.22,104.13) 93.11,104.07 93.11,104.07 arc(93.08,104.05) 93.05,104.02 93.04,104.01 92.75,104.01 92.73,104.02 arc(92.59,104.05) 92.47,104.13 GPU1.AH22
  BOTTOM w0.102: 78.82,118.44 81.51,115.76 91.06,115.76 97.29,109.53 97.29,103.15 97.54,102.89 v1(97.54,102.79) ; 78.82,118.44 v4(79.05,118.67) ; 78.82,118.44 78.19,119.07 66.09,119.07 62.29,122.87 57.24,122.87 46.68,133.43 R80081.1
DP_HPD: length 6.9
  TOP w0.102: TP78.1 104.94,209.93 107.25,212.25 NGFF1.31
DP_ML0N: length 4.6
  TOP w0.102: NGFF1.32 119.5,212.5 119.65,212.65 120.12,212.65 120.78,211.99 121.67,211.99 121.83,211.84 121.83,211.58 121.7,211.46 TP69.1
DP_ML0P: length 5
  TOP w0.102: TP68.1 122.16,211.46 122.03,211.58 122.03,211.92 121.76,212.19 120.87,212.19 120.21,212.85 119.65,212.85 119.5,213 NGFF1.34
DP_ML1N: length 4.6
  TOP w0.102: NGFF1.26 119.5,211 119.65,211.15 120.1,211.15 120.53,210.72 121.77,210.72 121.88,210.61 121.88,210.31 121.75,210.19 TP71.1
DP_ML1P: length 4.9
  TOP w0.102: NGFF1.28 119.5,211.5 119.65,211.35 120.18,211.35 120.61,210.92 121.85,210.92 122.08,210.69 122.08,210.31 122.21,210.19 TP70.1
DP_ML2N: length 5.3
  TOP w0.102: TP76.1 106.94,209.93 106.59,210.29 106.59,210.57 106.92,210.9 109.35,210.9 109.5,210.75 NGFF1.25
DP_ML2P: length 5.4
  TOP w0.102: TP77.1 106.13,209.93 106.38,210.19 106.38,210.65 106.83,211.1 109.35,211.1 109.5,211.25 NGFF1.27
DP_ML3N: length 6.5
  TOP w0.102: NGFF1.19 109.5,209.25 109.35,209.4 108.17,209.4 107.76,208.99 105.57,208.99 105.42,208.84 105.42,208.56 TP74.1
DP_ML3P: length 6.8
  TOP w0.102: NGFF1.21 109.5,209.75 109.35,209.6 108.09,209.6 107.68,209.19 105.48,209.19 105.21,208.93 105.21,208.56 TP75.1
DPLL_PVDD:
  vias: v1(91.8,101.6) v1(91.85,100.05) v1(91.85,99.16) v4(94.55,96.49)
DPLL_VDDC: length 4.5
  TOP w0.356: v1(89.39,97.54) 89.39,97.67 89,98.06 GPU1.AD14
  BOTTOM w0.508: v4(89.47,93.86) 89.47,93.9 89.46,93.9 C828.1 89.46,94.98 89.39,95.05 C825.1 v1(89.39,97.54)
  vias: v1(90.84,103.63) v1(91.98,103.63)
DPLVDS_AUXN: length 3.3
  BOTTOM w0.102: U126.3 34.32,93.1 34.23,93.19 34.15,93.19 33.88,92.93 33.03,92.93 32.63,92.54 32.31,92.54 C4269.2
DPLVDS_AUXP: length 3.6
  BOTTOM w0.102: 32.94,93.15 33.79,93.15 34.06,93.41 34.23,93.41 34.33,93.5 U126.4 ; 32.94,93.15 v4(32.94,93.51) ; 32.94,93.15 32.55,92.75 32.31,92.75 C4268.2
DPLVDS_BL_EN: length 182.3
  TOP w0.127: v1(40.22,27.46) 40.22,27.54 39.6,28.15 v3(39.54,28.15) 38.79,28.15 R1985.2 ; R79939.1 120.91,70.16 120.91,72.19 120.63,72.47 120.63,72.57 v2(120.56,72.64) ; v2(36.23,88.87) 36.23,88.74 36.89,88.08 36.89,86.61 39.58,83.92 39.58,82.3 41.88,80 48.74,80 49.32,80.58 51.05,80.58 52.1,79.54 53.46,79.54 53.63,79.7 69.13,79.7 75.95,72.89 90.34,72.89 v2(91.14,73.69)
  L3 w0.127: v2(45.91,50.44) 45.32,49.86 35.67,49.86 33.59,51.93 33.59,52.54 30.82,55.31 30.82,69.27 35.76,74.21 35.76,88.4 v2(36.23,88.87) ; v2(120.56,72.64) 120.43,72.52 102.99,72.52 101.68,71.21 96.48,71.21 96.05,71.64 93.19,71.64 v2(91.14,73.69)
  L4 w0.127: v1(40.22,27.46) 43.3,30.54 43.3,43.32 45.78,45.8 45.78,50.32 v2(45.91,50.44)
  BOTTOM w0.102: v2(36.23,88.87) 36.23,89 36.77,89.55 36.77,90.49 37.18,90.89 U126.44
DPLVDS_EDIDCLK: length 9.1
  TOP w0.102: v2(36.23,87.76) 36.23,87.83 35.59,88.47 35.59,89.34 v2(36.09,89.83)
  BOTTOM w0.102: v2(36.09,89.83) 36.09,90.64 36.38,90.93 U126.46 ; C1827.1 R32.2 ; C1827.1 v4(38.64,87.89) ; C1827.1 R35.2 36.9,86.93 36.23,87.6 v2(36.23,87.76)
DPLVDS_EDIDCLK_C: length 1.7
  BOTTOM w0.102: U25.6 R35.1
DPLVDS_EDIDSDA: length 7.5
  BOTTOM w0.102: C7.1 R79673.2 R79668.2 35.57,87.47 v4(35.57,88.31) 35.57,89.01 35.92,89.37 36.28,89.37 36.54,89.64 36.54,90.77 36.78,91 U126.45
DPLVDS_EDIDSDA_C: length 1.7
  BOTTOM w0.102: U25.5 R79668.1
DPLVDS_FWCLK: length 8.5
  BOTTOM w0.102: U126.48 35.58,90.96 35.01,90.39 35.01,90.38 34.57,89.95 34.57,88.36 34.2,87.99 33.29,87.99 v4(32.97,87.67) 32.68,87.38 32.68,86.86 31.97,86.15 C9.1 31.97,85.06 R79678.2
DPLVDS_FWSDA: length 10.4
  BOTTOM w0.102: U126.47 35.98,90.93 35.06,90.02 35.06,88.16 34.4,87.5 33.83,87.5 33.2,86.88 33.2,85.9 v4(33.09,85.78) 32.9,85.6 32.9,84.95 R79677.2 31.97,84.02 C4266.1
DPLVDS_HPD: length 57.6
  L4 w0.127: v1(42.9,133.16) 42.9,132.93 32.24,122.28 32.24,101.65 33.65,100.24 33.65,97.32 33.1,96.77 33.1,95.53 32.04,94.46 32.04,92.86 30.69,91.52 30.69,90.6 v1(30.13,90.04)
  BOTTOM w0.102: U126.1 34.78,91.76 33.82,90.81 32.93,90.81 32.42,90.29 32.42,89.41 32.17,89.15 R79675.1 31.97,89.17 31.53,89.61 30.56,89.61 v1(30.13,90.04) ; v1(42.9,133.16) 42.91,133.18 v4(42.91,134.06)
DPLVDS_ISPCLK: length 48.9
  TOP w0.102: R69.2 46.73,77.84 46.03,77.14 44.15,77.14 43.77,76.76 ; 43.77,76.76 43.7,76.68 42.45,76.68 41.84,77.29 41.49,77.29 38.44,80.34 35.42,80.34 v2(34.93,79.86) 34.73,79.86 33.87,80.72 33.87,82.34 34.6,83.08 34.6,85.88 31.63,88.85 31.63,91.8 32.98,93.14 33.73,93.14 34.58,93.99 34.58,97.18 34.39,97.37 v2(34.39,97.37) ; 43.77,76.76 44.79,75.74 47.97,75.74 48.4,75.31 v2(49.06,75.31)
  BOTTOM w0.102: v2(34.93,79.86) 34.25,79.17 34.25,77.6 33.51,76.86 Q7.1 ; v2(34.39,97.37) 34.53,97.5 U126.13 ; Q95.4 48.57,75.79 v2(49.06,75.31) 49.44,75.31 v4(49.87,75.74)
DPLVDS_ISPDAT: length 44
  TOP w0.102: v1(46.13,78.42) 45.6,77.89 R79686.2 41.66,77.89 38.07,81.48 35.85,81.48 35.09,80.72 v2(34.96,80.72) 34.53,81.15 34.53,82.27 35.09,82.83 35.09,86.08 32.42,88.74 32.42,91.66 33.39,92.63 33.54,92.63 35.06,94.15 35.06,97.51 v2(34.39,98.19)
  BOTTOM w0.102: Q95.1 46.8,77.67 46.13,78.34 v1(46.13,78.42) ; U126.14 35.98,98.04 35.83,98.19 v2(34.39,98.19) ; Q4.1 37.15,76.75 35.42,78.48 35.42,80.26 v2(34.96,80.72) 34.39,81.29 v4(33.98,81.29)
DPLVDS_PANEL_VCC: length 21.7
  TOP w0.127: v2(37.68,100.15) 36.86,100.15 33.41,103.61 v3(33.41,115.65) 33.48,115.72 R39.2
  BOTTOM w0.102: v2(37.68,100.15) 38.38,99.45 U126.20
DPLVDS_PIN12: length 3.6
  BOTTOM w0.203: U126.12 34.18,96.7 v4(33.27,97.6)
  BOTTOM w0.305: v4(33.27,97.6) 32.15,98.73 R511.1
DPLVDS_PIN16: length 6.3
  BOTTOM w0.203: U126.16 36.78,98.13 35.51,99.39 v4(35.33,99.39) 34.55,99.39 34.27,99.11 32.61,99.11 R507.2
DPLVDS_PWMIN: length 29.6
  TOP w0.165: v2(37.68,101.07) 38.11,101.51 38.11,112.97 ; 38.11,112.97 38.11,113.49 37.62,113.99 v5(37.62,114.17) 37.62,115.99 R503.2 38.65,117.11 R501.1 ; 38.11,112.97 38.69,112.39 41.42,112.39 42.79,113.77 42.79,114.12 R79682.1 43.9,114.15 R80134.1
  BOTTOM w0.165: U126.21 38.78,98.01 38.71,98.07 38.71,99.98 37.68,101.02 v2(37.68,101.07)
DPLVDS_PWMOUT: length 23.9
  TOP w0.165: v2(37.68,99.39) 36.79,99.39 32.75,103.43 32.75,116.08 32.55,116.28 32.55,117.17 v3(32.61,117.24) 32.78,117.07 R1984.2
  BOTTOM w0.165: v2(37.68,99.39) 38.12,98.95 38.12,98.39 37.98,98.25 U126.19
DQMA0: length 37
  TOP w0.127: GPU1.E32 73.47,111.13 73.47,111.28 72.43,112.32 v1(72.34,112.32)
  L3 w0.165: v1(72.34,112.32) 71.94,111.91 71.94,111.18 71.81,111.05 71.07,111.05 70.95,111.18 70.95,111.43 70.57,111.82 70.13,111.82 69.5,111.18 69.25,111.18 68.92,110.85 62.62,110.85 62.07,111.4 60.79,111.4 60.55,111.16 59.97,111.16 59.67,111.46 59.07,111.46 58.78,111.17 58.15,111.17 57.7,111.63 57.39,111.63 56,113.02 55.39,113.02 55.37,113.04 55.34,113.04 55.09,113.3 55.09,113.4 54.84,113.64 54.11,113.64 53.8,113.95 53.14,113.95 53.02,113.82 53.02,113.06 52.89,112.93 52.53,112.93 52.41,113.06 52.41,114.39 52.53,114.51 52.84,114.51 52.96,114.64 52.96,115.47 53.09,115.6 54.06,115.6 54.18,115.47 54.18,114.43 54.39,114.23 54.91,114.23 55.22,114.54 55.22,114.54 55.35,114.67 55.35,114.97 55.13,115.19 55.13,115.25 v1(54.9,115.49)
  BOTTOM w0.127: MEM3.E7 54.34,114.8 54.34,115.09 54.73,115.49 v1(54.9,115.49) ; v4(71.25,112.77) 71.7,112.32 v1(72.34,112.32)
DQMA1: length 35.6
  TOP w0.127: v1(71.71,109.55) 71.79,109.63 73.43,109.63 GPU1.E30
  BOTTOM w0.127: v1(71.71,109.55) 70.31,109.55 70,109.87 70,110.11 69.73,110.37 67.39,110.37 v4(65.53,112.23) 64.67,113.09 64.67,115.93 60.67,119.93 55.03,119.93 54.26,119.16 54.26,118.47 54.44,118.28 54.44,117.59 54.16,117.32 53.76,117.32 53.61,117.16 53.61,115.89 53.79,115.71 54.38,115.71 55.05,116.39 55.05,116.78 55.31,117.03 56.02,117.03 56.86,116.18 56.86,115.92 57.21,115.57 MEM3.D3
DQMA2: length 36.1
  TOP w0.102: 57.59,115.17 57.37,114.95 57.08,114.95 56.72,115.31 56.72,115.68 56.39,116.01
  TOP w0.127: 56.39,116.01 56.21,116.19 56.21,116.47 55.66,117.01 55.2,117.01 54.49,116.31 54.49,116 54.01,115.52 MEM1.D3 ; GPU1.A21 72.17,103.57 62.48,103.57 v3(62.32,103.73) 62.32,113.51 62.82,114.01 62.82,115.01 62.49,115.34 62.14,115.34 62.02,115.22 62.02,114.36 61.89,114.23 61.64,114.23 61.51,114.36 61.51,115.22 61.38,115.34 61.13,115.34 61,115.22 61,114.84 60.87,114.71 60.62,114.71 60.49,114.84 60.49,115.22 60.37,115.34 59.24,115.34 58.96,115.62 57.87,115.62 57.59,115.34 57.59,115.17
DQMA3: length 36.1
  TOP w0.127: v1(56.13,115.62) 56.13,115.59 57.21,114.5 MEM1.E7 ; GPU1.C21 72.58,103.18 71.28,103.18 71.11,103.34 70.4,103.34 v1(69.98,102.93)
  L4 w0.165: v1(56.13,115.62) 56.13,116.07 56.38,116.33 58.21,116.33 58.55,116.67 59.1,116.67 59.44,116.33 60.04,116.33 60.43,116.72 61.06,116.72 61.45,116.33 62.02,116.33 66.01,112.34 66.01,111.74 65.62,111.35 65.62,111.17 65.94,110.85 66.12,110.85 66.66,111.4 66.9,111.4 67.13,111.16 67.13,110.93 66.56,110.36 66.56,110.18 66.85,109.89 67.03,109.89 67.27,110.14 67.56,110.14 67.72,109.97 67.72,108.2 69.24,106.68 69.4,106.68 69.98,106.1 69.98,105.69 69.88,105.59 69.53,105.59 69.4,105.47 69.4,105.05 69.56,104.88 70.45,104.88 70.62,104.72 70.62,104.35 70.45,104.19 69.61,104.19 69.45,104.02 69.45,103.69 69.61,103.53 69.82,103.53 69.98,103.36 v1(69.98,102.93)
  BOTTOM w0.127: v4(71.31,103.56) 70.92,103.56 70.29,102.93 v1(69.98,102.93)
DQMA4: length 35.5
  TOP w0.102: v1(70.67,96.7) 70.84,96.87 71.14,96.87 71.28,97.01 71.88,97.01 72.11,96.87 72.27,96.87 72.42,96.93 72.78,96.93 72.93,96.87 73.2,96.87 73.53,97.2 GPU1.E13
  L4 w0.165: v1(70.67,96.7) 69.98,96.7 69.69,96.99 67.17,96.99 66.58,96.4 66.58,89.84 62.19,85.45 58.96,85.45 58.76,85.65 58.76,86.35 58.63,86.48 58.21,86.48 58.08,86.35 58.08,85.67 57.86,85.45 56.77,85.45 56.35,85.87 56.35,86.46 v1(55.52,87.29)
  BOTTOM w0.127: MEM4.E7 56.99,88.82 56.81,88.64 56.81,87.6 56.68,87.47 56.38,87.47 56.25,87.6 56.25,87.77 56.06,87.96 55.58,87.96 55.45,88.09 55.27,88.09 55.05,87.86 55.05,87.68 55.44,87.29 v1(55.52,87.29) ; v1(70.67,96.7) 71.07,97.1 v4(71.31,97.1)
DQMA5: length 36.8
  TOP w0.102: 71.09,96.53 71.37,96.81 71.82,96.81 72.05,96.67 72.31,96.67 72.33,96.68 72.53,96.72 72.57,96.73 72.72,96.73 72.9,96.6 73.1,96.4 GPU1.D12
  TOP w0.127: MEM2.D3 57.56,87.68 58.96,87.68 59.22,87.94 59.22,88.24 59.99,89.02 60.3,89.02 60.73,89.45 60.73,91 60.25,91.48 60.25,95.03 59.97,95.31 59.97,95.95 59.28,96.64 59.28,97.48 60.52,98.72 v3(61.19,98.72) 61.54,98.72 61.66,98.59 61.66,97.76 61.79,97.63 62.04,97.63 62.17,97.76 62.17,98.59 62.3,98.72 62.55,98.72 62.68,98.59 62.68,97.76 62.81,97.63 63.06,97.63 63.19,97.76 63.19,98.59 63.31,98.72 63.57,98.72 63.7,98.59 63.7,97.76 63.82,97.63 64.08,97.63 64.2,97.76 64.2,98.59 64.33,98.72 64.9,98.72 65.69,97.93 65.69,95.93 66.27,95.36 68.89,95.36 69.8,96.27 70.83,96.27 71.09,96.53 71.09,96.53
DQMA6: length 30.7
  TOP w0.127: v1(73.41,89.6) 73.8,89.99 GPU1.E3 ; v1(56.31,88.4) 56.32,88.41 56.69,88.41 56.85,88.25 56.85,88.1 56.59,87.84 56.06,87.84 55.88,88.02 55.22,88.02 54.64,87.44 54.48,87.44 54.28,87.64 54.28,87.77 54.58,88.06 54.58,88.23 54.47,88.33 54.47,88.57 54.23,88.82 MEM2.E7
  L3 w0.165: v1(73.41,89.6) 72.94,89.13 72.12,89.13 72.11,89.13 69.61,89.13 69.45,88.96 69.45,88.55 69.28,88.38 68.95,88.38 68.79,88.55 68.79,88.96 68.62,89.13 68.23,89.13 68.06,88.96 68.06,87.84 67,86.77 66.38,86.77 66.21,86.61 66.21,86.42 66.05,86.25 65.72,86.25 65.55,86.42 65.55,86.61 65.39,86.77 65.05,86.77 64.89,86.61 64.89,86.42 64.72,86.25 64.39,86.25 64.23,86.42 64.23,86.61 64.06,86.77 63.73,86.77 63.57,86.61 63.57,86.42 63.4,86.25 63.07,86.25 62.91,86.42 62.91,86.61 62.74,86.77 62.36,86.77 62.13,86.54 62.13,86.37 61.97,86.2 60.05,86.2 59.99,86.14 59.62,86.14 59.37,86.4 59.37,86.67 58.54,87.5 56.92,87.5 56.31,88.12 v1(56.31,88.4)
  BOTTOM w0.127: v4(72.4,89.61) 72.41,89.6 v1(73.41,89.6)
DQMA7: length 31.9
  TOP w0.127: v1(74.55,88.88) 74.23,89.21 74.23,90.08 74.54,90.4 GPU1.F4
  BOTTOM w0.127: v1(74.55,88.88) 74.98,89.3 76.32,89.3 76.69,88.94 76.69,88.52 76.32,88.15 76.32,87.9 74.51,86.09 68.05,86.09 66.1,84.14 62.69,84.14 v4(62.49,83.94) 62.25,83.7 60.25,83.7 59.75,84.21 56.89,84.21 55.08,86.01 55.08,86.66 54.26,87.48 54.26,87.77 MEM4.D3
DRAM_RCOMP_0: length 13.5
  TOP w0.254: CPU2.BA28 v1(90.69,165.95) ; v3(97.32,159.9) 97.17,159.76 97.17,158.96 v1(97.32,158.81) R527.2
  L3 w0.254: v1(90.69,165.95) 91.26,165.38 92.14,165.38 93.18,164.35 93.18,163.39 93.05,163.26 93.05,162.86 93.18,162.73 93.18,162.65 95.59,160.24 95.84,160.24 97.27,158.81 v1(97.32,158.81)
DRAM_RST: length 10.9
  TOP w0.102: v1(79.48,95.05) 79.48,95.03 79.26,94.8 GPU1.L10
  BOTTOM w0.102: v1(79.48,95.05) 79.53,95 79.53,94.12 80.04,93.6 80.04,93.15 81.54,91.65 83.71,91.65 C839.1 84.75,91.48 v4(84.87,91.37) 84.87,90.96 84.24,90.34 R1202.1 R1205.1
DRAM_RST_R: length 4.5
  BOTTOM w0.102: C762.1 84.13,88.43 R79962.1 84.37,88.43 v4(85.57,89.63) 84.31,89.63 R1202.2
DRX0N: length 3.3
  BOTTOM w0.102: C301.2 32.29,95.69 32.94,95.69 33.45,95.18 33.91,95.18 34.1,95 34.22,95 34.33,95.1 U126.8
DRX0P: length 3.3
  BOTTOM w0.102: U126.7 34.25,94.7 34.17,94.78 34.01,94.78 33.82,94.96 33.36,94.96 32.85,95.48 32.33,95.48 C300.2
DRX1N: length 4.1
  BOTTOM w0.102: U126.10 34.31,95.9 34.22,95.81 33.58,95.81 33.28,96.11 33.28,96.88 32.7,97.45 32.31,97.45 C4267.2
DRX1P: length 4.1
  BOTTOM w0.102: C4265.2 32.31,97.24 32.61,97.24 33.06,96.79 33.06,96.02 33.49,95.59 34.23,95.59 34.33,95.5 U126.9
EAPD_DEPOP: length 8.5
  TOP w0.203: R635.1 154.23,41.1 155.99,41.1 156.93,42.04 v3(156.93,42.59) 156.93,43.51 157.74,44.33 U6.14
EAPD_DEPOP_1: length 6.3
  TOP w0.102: v2(151.34,40.19) 151.41,40.13 R635.2
  BOTTOM w0.102: R636.1 R634.1 153.51,39.68 v4(153.96,40.13) 153.56,40.53 152.53,40.53 152.41,40.64 151.79,40.64 v2(151.34,40.19)
EAPD_DEPOP_2: length 2.9
  BOTTOM w0.381: v4(152.2,40.13) 152.13,40.06 152.13,39.96 151.58,39.41 R636.2 Q63.2
EC_3P3_CTL: length 5.1
  BOTTOM w0.127: Q9648.G 129.22,71.47 v4(129.14,71.4) 128.86,71.12 C6724.2 126.41,71.12 PR8521.2
EC_3P3_CTL_2: length 7.1
  BOTTOM w0.127: C6725.1 136.42,71.62 R80229.2 137.42,70.72 Q9649.G 138.33,70.86 139.26,71.79 139.26,74.08 139.25,74.09 v4(139.25,74.19)
EC_3P3_CTL_3: length 4.3
  BOTTOM w0.127: Q9648.D 133.02,72.16 v4(134.41,70.76) 134.49,70.85 R80228.1 134.96,71.72 R80229.1
EC_A20GATE: length 5.2
  TOP w0.127: v1(125.56,64.44) 126.01,64.89 U109.43
  BOTTOM w0.127: v1(125.56,64.44) 125.81,64.69 125.81,65.83 126.38,66.41 v4(126.38,66.54) 126.26,66.65 R80231.1
EC_EUP: length 5.6
  TOP w0.203: U109.127 129.61,48.78 v3(129.85,48.54) 130.16,48.54 131.03,47.65 R305.1 131.27,47.1 R304.1
EC_EUP_EN: length 13.5
  TOP w0.203: R305.2 130.14,47.14 C180.1 131,45.75 131,45.56 131.93,44.63 137.65,44.63 v3(137.83,44.45) 138.22,44.45 Q6706.G 139.65,45.89 R725.2
EC_HDMI_PD_N: length 34
  TOP w0.102: v2(120.98,43.11) 120.96,43.13 120.96,44.88 120.67,45.17 120.67,45.2 119.82,46.05 119.82,47.22 120.9,48.3 120.9,49.1 120.81,49.2 U109.105
  BOTTOM w0.102: R79750.2 129.64,23.57 126.68,23.57 Q1257.G 125.2,24.56 125.2,27.25 121.39,31.06 121.39,40.01 120.97,40.43 v4(120.97,41.38) 120.96,41.38 120.96,43.1 v2(120.98,43.11)
EC_IMS: length 3.7
  TOP w0.102: R79951.2 122.11,68.69 v3(122.72,68.08) 122.41,67.78 U109.52
EC_PSID: length 7.1
  TOP w0.102: v1(143.16,74.65) 143.19,74.63 143.66,74.63 144.09,75.06 144.09,75.98 142.57,77.5 U4101.12
  BOTTOM w0.102: v1(143.16,74.65) 143.37,74.85 R80203.2 143.64,75.73 v4(144.27,75.73)
EC_PWREN: length 19.3
  TOP w0.127: v1(120.96,64.16) 120.41,64.72 U109.57
  BOTTOM w0.127: v1(120.96,64.16) 120.96,64.3 v4(119.74,65.52) 119.22,66.04 R366.1 118.3,66.18 116.44,68.03 R363.1 116.96,68.67 118.61,68.67 119.43,67.86 120.45,67.86 123.87,71.28 PR8521.1
EC_SCI: length 3.2
  TOP w0.102: U4101.15 141.37,80.53 v3(141.38,80.54) 142.14,80.54 R80132.1
EC_SMB2_CLK: length 8.5
  TOP w0.102: U4101.32 138.97,71.24 138.4,70.66 137.02,70.66 136.74,70.38 136.74,69.85 136.25,69.37 v1(136.25,69.13)
  BOTTOM w0.102: v4(136.19,66.62) 135.9,66.92 R80204.1 135.92,67.75 135.92,68.8 v1(136.25,69.13) 136.86,69.13 PR8519.2
EC_SMB2_DATA: length 9
  TOP w0.102: v1(137.22,70.18) 140.79,70.18 U4101.33
  BOTTOM w0.102: PR8520.2 137.54,69.28 137.22,69.6 v1(137.22,70.18) 137.13,70.18 136.58,69.63 135.62,69.63 R80205.1 135.07,69.52 v4(135.07,68.94)
EC_VCORF: length 3.5
  TOP w0.102: U4101.20 138.93,76.04 138.01,76.96 C4101.1 137.49,77.27 v3(136.79,77.27)
ECIO_GP26: length 3.5
  TOP w0.102: R79762.1 133.81,57.81 132.89,58.74 U109.18
ECIO_GP32: length 3.8
  TOP w0.102: R79759.1 134.55,55.73 133.76,56.52 133.46,56.52 132.83,57.14 U109.14
ECIO_GP34: length 5.1
  TOP w0.102: U109.12 132.98,56.34 133.28,56.04 133.28,55.61 134.08,54.81 v3(134.08,54.32) 134.08,54.29 134.59,53.78 R79761.1
ECIO_GP63: length 5.8
  TOP w0.102: U109.3 132.53,52.74 133.38,51.89 134.59,51.89 135.02,51.46 R316.1 135.47,51.49 v3(136.41,52.43)
EDM_SOC: length 3.5
  TOP w0.102: v1(76.24,157.74) 76.32,157.74 CPU2.M13
  BOTTOM w0.102: R1257.2 74.48,156.58 v4(74.66,156.76) 74.95,156.76 75.75,157.56 75.76,157.56 75.95,157.74 v1(76.24,157.74)
EEPROM_WP: length 4.3
  BOTTOM w0.102: U9.7 158.73,104.52 R180.2 158,103.99 157.28,103.28 v4(157.28,103.2) 157.51,102.97 R179.1
EQ: length 4.9
  TOP w0.127: R79735.2 v2(131.72,40.29) 131.72,39.56 132.14,39.14 U127.17
  BOTTOM w0.127: R79735.2 v2(131.72,40.29) 131.72,39.91 v4(132.11,39.52)
EXT_RST#: length 5.6
  TOP w0.102: v1(144.3,71.35) 144.3,71.31 144.17,71.19 U4101.41
  BOTTOM w0.102: v4(145.03,74.47) 144.8,74.24 R80125.1 144.44,73.22 144.44,71.49 v1(144.3,71.35) 144.04,71.09 R80126.2
F_USB0N: length 153.3
  TOP w0.089: v1(69.15,172.75) 69.72,172.17 70.84,172.17 70.94,172.28 70.95,172.28 71.41,172.28 71.42,172.29 CPU2.B42
  TOP w0.102: v2(161.53,105.99) 161.88,106.34 162.55,106.34 163.09,106.88 163.87,106.88 164.11,106.64 TR4.2
  L4 w0.127: v2(161.53,105.99) 161.2,106.32 161.2,106.57 161.07,106.69 160.55,106.69 160.01,107.23 160.01,108.37 155.85,112.54 155.85,114.53 152.16,118.22 144.53,118.22 144.21,117.91 137.9,117.91 137.43,118.37 118.84,118.37 107.65,129.56 78.89,129.56 65.63,142.81 65.63,143.55 65.37,143.81 65.37,158.61 65.63,158.86 65.63,161.73 65.93,162.04 65.93,170.65 66.85,171.56 68.43,171.56 69.16,172.3 69.16,172.68 69.15,172.69 v1(69.15,172.75)
  BOTTOM w0.102: v4(68.59,171.92) 69.15,172.48 v1(69.15,172.75)
F_USB0N_H: length 226
  TOP w0.102: v1(69.21,174.2) 69.47,174.2 69.76,173.91 70.39,173.91 70.48,173.82 71.11,173.82 CPU2.A45 ; v2(162.78,189.69) 162.41,190.05 162.41,190.21 162.29,190.33 162.1,190.33 159.89,188.12 159.89,185.08 159.51,184.7 158.67,184.7 158.3,185.06 158.3,185.48 158.07,185.71 TR1.3
  L4 w0.127: v2(162.78,189.69) 163.07,189.98 163.07,190.13 163.22,190.28 163.75,190.28 166.17,187.87 166.17,161 167.98,159.18 167.98,147.76 169.69,146.05 169.69,134.41 170.33,133.77 170.33,133.27 v2(170.03,132.97) ; v1(69.21,174.2) 69.47,174.2 69.85,173.82 70.15,173.82 71.37,172.6 71.37,167.41 69.3,165.33 69.3,157.88 69.71,157.48 69.71,144.1 80.64,133.17 110.15,133.17 120.99,122.33 141.37,122.33 141.94,122.9 154.51,122.9 155.91,121.5 158.81,121.5 159.18,121.13 v1(159.18,120.78)
  BOTTOM w0.102: v1(159.18,120.78) 159.44,120.53 160.03,120.53 160.24,120.73 160.24,125.07 165.65,130.49 167.04,131.88 167.6,131.88 ; 167.6,131.88 169.99,131.88 170.29,132.18 170.29,132.71 v2(170.03,132.97) ; 167.6,131.88 v4(167.6,132.21)
F_USB0P: length 153
  TOP w0.089: v1(69.93,172.8) 69.73,172.6 69.73,172.43 69.8,172.37 70.76,172.37 70.86,172.47 70.87,172.47 71.33,172.47 71.45,172.59 71.69,172.59 71.99,172.29 CPU2.C42
  TOP w0.102: v2(161.53,106.96) 161.93,106.56 162.47,106.56 163,107.09 163.87,107.09 164.11,107.33 TR4.3
  L4 w0.127: v2(161.53,106.96) 160.66,106.96 160.28,107.34 160.28,108.48 156.12,112.65 156.12,114.64 152.27,118.49 144.42,118.49 144.1,118.17 138.01,118.17 137.54,118.64 118.95,118.64 107.76,129.82 79,129.82 65.9,142.92 65.9,143.66 65.64,143.92 65.64,158.5 65.9,158.75 65.9,161.62 66.2,161.93 66.2,170.54 66.96,171.3 68.54,171.3 69.93,172.69 v1(69.93,172.8)
  BOTTOM w0.102: v4(69.9,171.9) 69.9,172.76 v1(69.93,172.8)
F_USB0P_H: length 226.5
  TOP w0.102: TR1.2 158.75,185.71 158.52,185.48 158.52,185.15 158.76,184.91 159.42,184.91 159.67,185.17 159.67,188.21 162.01,190.55 v2(162.75,190.55) ; v1(69.96,174.32) 70.15,174.13 70.48,174.13 70.57,174.03 71.39,174.03 71.72,173.7 CPU2.C45
  L4 w0.127: v1(69.96,174.32) 70.03,174.32 71.64,172.71 71.64,167.29 69.57,165.22 69.57,157.99 69.82,157.74 69.97,157.59 69.97,144.21 80.75,133.43 110.26,133.43 121.1,122.6 141.26,122.6 141.83,123.17 154.62,123.17 156.02,121.77 158.92,121.77 159.64,121.04 159.64,120.48 v1(159.21,120.05) ; v2(170.9,132.97) 170.59,133.27 170.59,133.88 169.96,134.52 169.96,146.16 168.25,147.87 168.25,159.29 166.43,161.11 166.43,187.98 163.86,190.55 v2(162.75,190.55)
  BOTTOM w0.102: v1(159.21,120.05) 159.47,120.31 160.12,120.31 160.45,120.64 160.45,122.2 ; 160.45,122.2 160.45,124.99 165.8,130.34 167.13,131.66 170.08,131.66 170.51,132.09 170.51,132.58 v2(170.9,132.97) ; 160.45,122.2 v4(160.79,122.2)
F_USB1N: length 133
  TOP w0.102: U9625.2 143.12,113.09 v1(142.93,113.28) 142.21,113.28 R80050.1 ; CPU2.B44 71.45,173.26 71.42,173.29 71.24,173.46 70.53,173.46 70.3,173.69 68.43,173.69 68.35,173.76 v1(67.57,173.76)
  L4 w0.127: v1(67.57,173.76) 67.57,173.22 65.12,170.77 65.12,162.54 64.71,162.14 64.71,159.29 64.43,159.01 64.43,142.74 78.51,128.66 107.17,128.66 118.36,117.47 137.06,117.47 137.52,117.01 140.4,117.01 143.82,113.58 143.82,113.15 143.66,112.99 143.23,112.99 v1(142.93,113.28)
  BOTTOM w0.102: v1(67.57,173.76) 67.57,173.58 67.1,173.11 v4(66.34,173.11)
F_USB1N_H: length 159
  TOP w0.102: v3(103.34,207.2) 103.34,206.83 ; 103.34,206.83 103.11,206.83 102.73,206.45 102.73,206.24 v2(102.4,205.92) ; 103.34,206.83 104.33,206.83 104.99,206.17 104.99,205.89 105.21,205.66 105.49,205.66 105.68,205.85 TR12.4
  L4 w0.127: v2(168.26,131.14) 168.61,131.5 168.61,145.74 166.19,148.16 166.19,159.39 165.26,160.32 165.26,182.53 160.87,186.92 160.87,199.43 158.14,202.16 157.76,202.16 157.23,202.69 157.23,202.87 156.38,203.72 126.62,203.72 125.14,205.2 103.29,205.2 102.58,205.92 v2(102.4,205.92)
  BOTTOM w0.102: U6702.6 162.38,114.57 162.47,114.67 162.47,115.38 162.2,115.66 162.2,122.62 163.43,123.85 163.43,126.64 165.06,128.27 165.92,128.27 167.3,129.65 168.29,129.65 168.63,129.99 168.63,130.77 v2(168.26,131.14)
F_USB1P: length 132.5
  TOP w0.089: CPU2.C43 71.83,172.88 71.53,172.88 71.37,173.04 71.36,173.04
  TOP w0.102: 71.36,173.04 71.15,173.25 70.44,173.25 70.21,173.47 68.2,173.47 v1(68.08,173.35) ; R80052.1 142.26,112.5 v1(142.93,112.5) 143.03,112.59 U9625.3
  L4 w0.127: v1(142.93,112.5) 143.16,112.73 143.77,112.73 144.09,113.04 144.09,113.69 140.51,117.27 137.63,117.27 137.17,117.73 118.47,117.73 107.28,128.92 78.62,128.92 64.7,142.85 64.7,158.9 64.98,159.18 64.98,162.03 65.39,162.43 65.39,170.66 v1(68.08,173.35)
  BOTTOM w0.102: v1(68.08,173.35) 68.08,173.18 v4(67.49,172.59)
F_USB1P_H: length 158.8
  TOP w0.102: TR12.1 105.77,205.17 105.49,205.45 105.12,205.45 104.77,205.8 104.77,206.08 104.24,206.62 103.2,206.62 102.94,206.36 102.94,206.23 v2(103.26,205.92)
  L4 w0.127: v2(103.26,205.92) 103.26,205.61 103.4,205.47 105.22,205.47 105.36,205.6 105.74,205.6 105.88,205.47 106.26,205.47 106.4,205.6 106.78,205.6 106.92,205.47 107.3,205.47 107.43,205.6 107.81,205.6 107.95,205.47 108.33,205.47 108.47,205.6 108.85,205.6 108.99,205.47 109.37,205.47 109.51,205.6 109.89,205.6 110.02,205.47 125.26,205.47 126.73,203.99 156.49,203.99 157.5,202.98 157.5,202.8 157.87,202.43 158.25,202.43 161.14,199.54 161.14,187.03 165.53,182.64 165.53,160.43 166.46,159.5 166.46,148.27 168.88,145.85 168.88,131.42 v2(169.12,131.18)
  BOTTOM w0.102: 162.42,121.36 162.42,115.75 162.69,115.47 162.69,114.76 162.88,114.58 U6702.7 ; 162.42,121.36 162.42,122.53 163.65,123.76 163.65,126.55 165.15,128.05 166.01,128.05 167.39,129.44 168.38,129.44 168.84,129.9 168.84,130.9 v2(169.12,131.18) ; 162.42,121.36 v4(162.72,121.36)
F_USB2N: length 134.9
  TOP w0.102: 155.33,69.01 156.79,70.47 156.79,82.28 153.48,85.59 153.48,100.1 153.94,100.56 v2(154.47,100.56) ; 155.33,69.01 154.88,68.57 154.88,67.58 146.93,59.63 146.93,54.82 145.45,53.34 145.45,37.72 145.96,37.21 145.96,35.66 145.33,35.04 145.33,32.04 137.87,24.57 115.24,24.57 113.86,25.96 113.42,25.96 113.2,25.74 TR7.3 ; 155.33,69.01 v3(155.58,68.76)
  BOTTOM w0.102: v2(154.47,100.56) 154.78,100.88 155.24,100.88 156.19,99.92 162.26,99.92 163.86,101.52 163.86,106.37 165.96,108.47 165.96,110.43 165.39,111 164.66,111 164.53,111.12 U6702.12
F_USB2N_H: length 213.8
  TOP w0.102: v1(27.38,14.61) 27.13,14.35 27.13,14.17 27.33,13.97 29.85,13.97 30.26,13.56 31.3,13.56 31.66,13.2 31.66,12.6 31.9,12.37 TR13.4 ; CPU2.A41 71.05,171.8 71.01,171.76 70.44,171.76 70.36,171.68 70.19,171.68 70.11,171.76 69.86,171.76 69.78,171.68 69.58,171.68 69.5,171.76 69.17,171.76 69.09,171.68 68.87,171.68 68.79,171.76 68.44,171.76 68.33,171.65 68.08,171.65 67.98,171.76 67.42,171.76 66.71,172.47 66.58,172.47 66.48,172.57 66.48,172.69 66.3,172.87 65.67,172.87 65.59,172.8 65.36,172.8 65.29,172.87 60.76,172.87 60.64,172.75 v2(60.64,172.47)
  L4 w0.127: v1(27.38,14.61) 27.08,14.91 27.08,16 28.49,17.41 30.22,17.41 30.93,18.12 36.06,18.12 37.61,19.67 37.61,20.89 35.49,23.01 35.49,27.69 41.1,33.3 41.1,43.7 28.4,56.4 28.4,68.98 35.9,76.48 35.9,82.58 38.68,85.36 38.68,123.01 45.95,130.28 51.67,130.28 55.39,134 55.39,137.39 56,138 56,143.7 57.11,144.81 57.11,158.72 55.91,159.92 55.91,169.96 58.92,172.96 60.47,172.96 60.64,172.8 v2(60.64,172.47)
  BOTTOM w0.102: v4(61.42,172.21) 60.89,172.21 v2(60.64,172.47)
F_USB2P: length 134.6
  TOP w0.102: 153.8,100.72 153.27,100.19 153.27,85.5 156.57,82.19 156.57,70.56 154.67,68.66 154.67,67.67 146.72,59.72 146.72,54.91 145.23,53.43 145.23,37.63 145.74,37.12 145.74,35.75 145.12,35.13 145.12,32.13 137.78,24.79 115.33,24.79 113.95,26.17 113.43,26.17 113.18,26.43 TR7.2 ; 153.8,100.72 v2(154.5,101.42) ; 153.8,100.72 v3(153.55,100.96)
  BOTTOM w0.102: v2(154.5,101.42) 154.5,101.29 154.69,101.09 155.33,101.09 156.28,100.14 162.17,100.14 163.65,101.61 163.65,106.46 165.74,108.56 165.74,110.34 165.3,110.78 164.7,110.78 164.54,110.62 U6702.13
F_USB2P_H: length 213.7
  TOP w0.089: 70.91,171.97 71.03,172.09 71.35,172.09 71.63,171.81 71.93,171.81 CPU2.C41
  TOP w0.102: 70.91,171.97 67.51,171.97 66.63,172.85 66.39,173.08 61.11,173.08 v2(60.71,173.48) ; v1(26.65,14.66) 26.91,14.4 26.91,14.08 27.24,13.75 28.15,13.75 ; 28.15,13.75 v3(28.15,13.4) ; 28.15,13.75 29.76,13.75 30.17,13.35 31.21,13.35 31.45,13.11 31.45,12.6 31.21,12.37 TR13.1
  L4 w0.127: v2(60.71,173.48) 60.46,173.23 58.81,173.23 55.65,170.07 55.65,159.81 56.84,158.61 56.84,144.92 55.74,143.81 55.74,138.11 55.13,137.5 55.13,134.11 51.56,130.54 45.84,130.54 38.41,123.12 38.41,85.47 35.63,82.69 35.63,76.59 28.13,69.09 28.13,56.29 40.84,43.59 40.84,33.41 35.22,27.8 35.22,22.9 37.35,20.78 37.35,19.78 35.95,18.39 30.82,18.39 30.11,17.68 28.38,17.68 26.81,16.11 26.81,14.82 v1(26.65,14.66)
F_USB3N: length 132.3
  TOP w0.102: TR5.2 113.57,24.19 113.7,24.06 113.7,23.8 113.83,23.67 115.25,23.67 115.54,23.96 138.12,23.96 145.94,31.79 145.94,34.79 146.13,34.98 146.13,34.98 146.57,35.41 146.57,37.46 146.06,37.97 146.06,53.03 147.54,54.52 147.54,59.35 154.4,66.21 156.52,68.33 156.52,69.29 157.4,70.17 157.4,82.53 154.09,85.84 154.09,98.2 154.48,98.59 ; 154.48,98.59 155.19,99.3 155.19,101.99 154.9,102.29 v2(154.52,102.29) ; 154.48,98.59 v3(154.24,98.83)
  BOTTOM w0.102: U6702.15 162.88,108.56 162.61,108.29 162.61,108.14 162.62,108.12 162.88,107.87 163.02,107.72 163.02,101.98 161.82,100.77 156.92,100.77 155.08,102.62 154.85,102.62 v2(154.52,102.29)
F_USB3N_H: length 34.8
  L4 w0.127: v1(162.72,141.84) 162.89,142.01 163.56,142.01 163.91,141.66 163.91,137.19 162.67,135.94 162.67,126.92 163.66,125.93 163.66,125.3 163.46,125.09 162.95,125.09 162.72,125.32 v1(162.47,125.32)
  BOTTOM w0.102: v4(161.02,120.12) 161.34,120.12 ; 161.34,120.12 161.34,124.5 162.16,125.32 v1(162.47,125.32) ; 161.34,120.12 161.34,115.84 161.02,115.52 161.02,114.92 160.88,114.78 U6702.3 ; TR28.3 164.61,142.16 164.37,142.4 164.36,142.4 164.35,142.41 164.02,142.41 163.65,142.04 162.92,142.04 v1(162.72,141.84)
F_USB3N_SD: length 4.3
  BOTTOM w0.102: TR28.4 166.27,142.16 166.52,142.41 166.82,142.41 167.11,142.69 ; 167.11,142.69 167.33,142.92 167.33,143.74 167.6,144.01 168.19,144.01 168.35,143.85 SU1.2 ; 167.11,142.69 v4(167.33,142.47)
F_USB3P: length 132.6
  TOP w0.102: 157.18,69.65 157.61,70.08 157.61,82.62 154.31,85.93 154.31,98.11 155.4,99.21 155.4,102.08 154.88,102.61 154.88,102.87 v2(154.57,103.18) ; 157.18,69.65 v3(157.46,69.37) ; 157.18,69.65 156.74,69.2 156.74,68.24 147.76,59.26 147.76,54.43 146.27,52.95 146.27,38.06 146.78,37.55 146.78,35.32 146.35,34.89 146.35,34.89 146.16,34.7 146.16,31.7 138.21,23.75 115.63,23.75 115.34,23.46 113.03,23.46 TR5.3
  BOTTOM w0.102: U6702.16 162.38,108.07 162.66,107.78 162.72,107.72 162.81,107.63 162.81,102.07 161.73,100.99 157.01,100.99 155.16,102.83 154.92,102.83 v2(154.57,103.18)
F_USB3P_H: length 35.2
  L4 w0.127: v1(162.72,142.55) 162.99,142.28 163.67,142.28 164.18,141.77 164.18,137.07 162.94,135.83 162.94,127.03 163.93,126.04 163.93,125.19 163.57,124.83 162.95,124.83 162.73,124.61 v1(162.52,124.61)
  BOTTOM w0.102: TR28.2 164.56,142.84 164.35,142.62 163.93,142.62 163.56,142.25 163.02,142.25 v1(162.72,142.55) ; v1(162.52,124.61) 161.76,124.61 161.55,124.41 161.55,123.29 ; 161.55,123.29 161.55,115.75 161.23,115.43 161.23,114.92 161.38,114.78 U6702.4 ; 161.55,123.29 v4(161.86,123.29)
F_USB3P_SD: length 4.3
  BOTTOM w0.102: TR28.1 166.19,142.84 166.4,142.63 166.73,142.63 167.12,143.01 167.12,143.83 167.27,143.98 ; 167.27,143.98 167.51,144.22 168.19,144.22 168.31,144.35 SU1.3 ; 167.27,143.98 v4(167.04,144.21)
FALL_INT2: length 4.8
  TOP w0.102: R6703.2 21.58,186.36 v2(20.58,186.36) ; Q6701.3 20.22,186.73 v2(20.58,186.36) ; Q6701.2 20.3,186.08 v2(20.58,186.36)
  BOTTOM w0.102: v4(20.66,185.45) 20.66,186.26 20.58,186.33 v2(20.58,186.36)
FAN_CTRL_POWER: length 297.4
  TOP w0.127: v2(127.9,52.37) 127.9,52.12 128.81,51.21 U109.125
  L3 w0.165: v2(127.9,52.37) 127.64,52.12 127.64,52.08 123.18,47.61 115.67,47.61 114.76,46.71 110.47,46.71 106.24,42.48 100.45,42.48 96.56,38.59 89.1,38.59 81.64,46.05 60.86,46.05 58.63,48.27 35.74,48.27 32.52,51.49 32.52,52.03 29.74,54.8 29.74,70.01 33.85,74.11 33.85,82.3 34.36,82.82 34.36,89.72 35.31,90.66 35.31,100.13 32.6,102.84 32.6,123.49 32.61,123.51 32.61,129.73 31.9,130.44 31.9,132.92 28.47,136.35 18.76,136.35 14.71,140.4 14.71,151.24 14.01,151.94 14.01,183.89 9.68,188.22 9.68,201.78 v1(9.61,201.85)
  BOTTOM w0.165: R79913.1 R79936.2 20.72,194.42 v4(20.2,194.94) 18.32,194.94 14.77,198.5 14.77,201.17 13.95,201.98 9.74,201.98 v1(9.61,201.85)
FAN_OFF_D: length 6.6
  BOTTOM w0.165: R79917.1 22.07,200.72 v4(22.77,200.03) 22.77,199.58 Q1227.D 21.74,198.55 R79916.1 R79915.2
FAN_OFF_G: length 3.4
  BOTTOM w0.165: Q1227.G 22.73,195.33 v4(23.02,195.05) 23.24,194.83 R79913.2
FAN_OFF_G2: length 11
  BOTTOM w0.165: R79917.2 21.69,201.68 C12324.1 19.85,201.29 v4(19.01,201.29) 18.45,201.85 18.45,206.53 Q9624.G 18.96,207.44 C12325.1
FFS_INT1: length 96.4
  TOP w0.102: R6702.2 89.19,79.18 89.19,78.47 v2(89.16,78.44) 89.09,78.37 R79756.2 ; U109.110 122.81,51.31 122.68,51.44 122.26,51.44 121.9,51.79 121.36,51.79 121.09,52.06 121.09,52.67 122.34,53.92 v1(122.34,57.11) 118.75,53.52 115.73,50.5 114.42,50.5 114.12,50.2 112.11,50.2 111.6,49.69 111.6,49.58 110.77,48.74 108.31,48.74 106.81,47.25 106.81,44.54 105.15,42.88 100.52,42.88 99.2,41.55 97.56,41.55 94.9,38.89 Q6702.2
  L4 w0.127: v2(89.16,78.44) 89.54,78.06 89.54,73.61 98.69,64.47 98.69,61.1 101.15,58.64 107.71,58.64 108.02,58.94 109.04,58.94 109.4,59.3 111.34,59.3 111.82,59.78 114.96,59.78 116.07,58.67 118.49,58.67 119.19,57.98 121.47,57.98 v1(122.34,57.11)
  BOTTOM w0.102: v4(89.64,79.38) 89.16,78.89 v2(89.16,78.44)
FFS_INT1_C: length 2.7
  TOP w0.102: U6701.11 87.02,76.83 87.07,76.88 v3(87.71,76.88) 88.9,76.88 R79756.1
FFS_INT2_APU: length 2.8
  TOP w0.102: R79755.2 56.02,136.52 v3(56.07,136.47) 57.33,136.47 Q6715.2
FFS_INT2_C: length 205.2
  TOP w0.102: Q6701.5 16.18,186.08 R6706.1 16.02,187.26 R79757.1 17.15,188.4 v2(17.15,188.72) ; U6701.9 86.66,75.84 87.54,74.96 R6704.2 88.71,74.51 88.71,74.01 88.11,73.41 76.17,73.41 69.04,80.53 52.57,80.53 52,81.1 49.11,81.1 49.01,81.01 46.05,81.01 45.15,81.9 45.15,87.48 45.45,87.78 45.45,91.5 44.69,92.25 44.69,117.08 47.15,119.54 47.15,126.59 46.59,127.15 46.59,129.09 50.97,133.46 53.58,133.46 54.34,134.22 v2(54.34,134.37) 53.56,135.14 53.56,136.07 R79755.1
  L3 w0.127: v2(54.34,134.37) 53.73,134.37 53.17,133.81 44.59,133.81 44.3,134.1 41.39,134.1 40.92,134.57 38.48,134.57 38.4,134.65 36.69,134.65 33.29,138.05 32.22,138.05 30.83,139.45 21.28,139.45 18.54,142.19 18.54,165.37 19.58,166.41 19.58,169.63 18.52,170.69 18.52,187.59 17.53,188.58 17.29,188.58 v2(17.15,188.72)
  BOTTOM w0.102: v2(17.15,188.72) 17.16,188.71 v4(18.03,188.71)
FFS_INT2_Q: length 17.7
  TOP w0.102: Q6701.6 16.09,185.43 R6706.2 15.29,186.08 15.29,188.33 14.77,188.85 12.61,188.85 12,189.46 SATAP1.5 12.27,190.27 14.28,190.27 14.82,189.74 20.24,189.74 R6705.2
FWH_ID0: length 10.3
  TOP w0.102: LPC1.6 106.51,74.57 103.23,74.57 101.14,76.67 R317.2
  BOTTOM w0.102: v4(107.63,76.71) 107.63,75.71 LPC1.6
GP_CAMERASB09: length 63.9
  TOP w0.102: R1558.1 111.11,200.76 v2(111.13,200.79) ; v1(80.07,172.26) 80.21,172.26 CPU2.Y42
  L4 w0.127: v2(111.13,200.79) 109.57,200.79 109.1,200.32 105.79,200.32 105.28,200.83 85.12,200.83 78.67,194.37 78.67,187.57 80.41,185.83 80.41,174.13 80.48,174.05 80.48,172.68 v1(80.07,172.26)
  BOTTOM w0.102: R1819.2 109.85,199.42 111.15,199.42 v4(111.47,199.73) 111.57,199.84 111.57,200.35 v2(111.13,200.79)
GP_CAMERASB11: length 60.6
  TOP w0.102: CPU2.V40 79.84,171.45 v1(80.07,171.45)
  L4 w0.127: v2(106.13,201.04) 105.84,201.33 84.91,201.33 78.16,194.58 78.16,187.43 79.41,186.18 79.41,173.43 79.65,173.19 79.65,172.09 80.07,171.67 v1(80.07,171.45)
  BOTTOM w0.102: v2(106.13,201.04) 105.65,201.04 104.88,200.28 v4(104.88,199.32) 104.35,198.79 R1557.1 R1818.2
GPIO17_THERMAL_INT: length 25.5
  TOP w0.102: R1896.2 R1884.2 96.6,89.4 96.6,85.99 R1887.2 96.62,84.91 v3(92.34,84.91) 90.81,84.91 88.3,87.43 88.02,87.71 85.63,87.71 83.76,89.57 83.76,90.1 83.47,90.4 83.09,90.4 81.89,91.6 GPU1.R6
GPIO19_CTF: length 41.3
  TOP w0.102: GPU1.M2 79.4,87.19 v1(80.02,86.57) 80.02,85.94 R1886.1 ; v2(99.5,87.12) 99.16,87.46 99.16,87.94 R79966.2
  BOTTOM w0.102: v1(80.02,86.57) 79.9,86.45 79.4,86.45 77.45,84.5 77.45,83.7 77.18,83.43 77.18,80.19 77.69,79.69 88.8,79.69 92.98,83.87 97.57,83.87 v4(98.71,85.01) 99.5,85.8 v2(99.5,87.12)
GPIO19_CTF_R: length 6.9
  TOP w0.102: v3(98.13,89.05) 98.22,88.96 R1896.1 R79967.1 100.11,88.01 R79966.1 101.68,87.95 D5209.3 101.85,86.87 101.32,86.33 R1894.1
GPIO_8_ROMSO: length 39.7
  TOP w0.102: R1169.1 108.75,81.28 v1(109.15,80.88) ; v1(81.74,94.21) 81.74,94.26 GPU1.P10
  L3 w0.127: v1(81.74,94.21) 81.31,93.78 81.31,92.32 83.77,89.87 86.04,89.87 88.05,87.86 88.05,84.38 88.98,83.44 99.83,83.44 101,82.27 107.76,82.27 v1(109.15,80.88)
  BOTTOM w0.102: v4(108.36,80.88) v1(109.15,80.88)
GPIO_9_ROMSI: length 17.5
  TOP w0.102: v2(86.55,87.22) 88.18,87.22 91.1,84.3 93.29,84.3 R1171.2 ; GPU1.P4 80.53,89.93 80.53,89.05 80.53,89.05 80.53,88.47 v1(80.96,88.04)
  BOTTOM w0.102: v2(86.55,87.22) 86.34,87.22 85.69,86.57 v4(85.14,86.57) 82.31,86.57 80.96,87.92 v1(80.96,88.04)
GPIO_10_ROMSCK: length 14.6
  TOP w0.102: GPU1.P2 80.91,89.51 80.91,88.72 v1(80.93,88.7) ; R1170.2 91.33,83.57 88.38,86.51 v1(86.52,86.51)
  L3 w0.127: v1(86.52,86.51) 85.68,86.51 83.5,88.7 v1(80.93,88.7)
  BOTTOM w0.102: v1(80.93,88.7) 81.54,88.7 v4(81.73,88.5)
GPIO_22_ROMCS#: length 39.3
  TOP w0.102: R1168.1 108.69,80.21 v1(108.92,79.98) ; GPU1.N8 80.09,93.2 80.5,92.79 81.41,92.79 82.15,92.05 83.42,92.05 83.75,91.72 83.75,91.41 84.59,90.58 84.59,89.14 84.88,88.85 86.24,88.85 86.56,88.53 v1(86.56,88.36)
  L3 w0.127: v1(86.56,88.36) 86.73,88.36 87.61,87.48 87.61,84.18 88.6,83.19 99.19,83.19 100.71,81.67 106.8,81.67 108.49,79.98 v1(108.92,79.98)
  BOTTOM w0.102: v4(87.07,88.91) 87.07,88.88 v1(86.56,88.36)
GPIO_RCOMP18: length 2.8
  TOP w0.254: CPU2.AH40 v1(83.95,170.84)
  BOTTOM w0.254: R79787.2 82.82,171.67 v4(83.13,171.36) 83.65,170.84 v1(83.95,170.84)
GPIO_SUS0: length 35.8
  TOP w0.089: 82.95,179.25 82.95,178.91 82.6,178.56 82.6,178.23 82.7,178.14 82.7,178.13 82.7,178.12 82.7,177.66 82.8,177.57 82.8,177.29 82.52,177.01 CPU2.AD51
  TOP w0.102: R1562.2 R1801.1 103.56,195.85 103.56,193.17 v3(102.09,191.7) 97.03,186.64 89.64,186.64 87.79,184.78 84.85,184.78 82.95,182.88 82.95,179.25
GPIO_SUS1: length 34
  TOP w0.089: 82.7,179.25 82.41,178.96 82.41,178.15 82.51,178.05 CPU2.AD52
  TOP w0.102: R1570.2 R1802.1 100.74,195.72 100.74,194.87 101.03,194.58 v3(101.03,193.4) 101.03,191.29 96.61,186.87 89.44,186.87 87.71,185.14 84.89,185.14 82.7,182.95 82.7,179.25
GPIO_SUS2: length 36.2
  TOP w0.102: CPU2.AH50 84.94,175.82 v1(84.94,175.79)
  BOTTOM w0.102: R1804.2 R1803.1 103.09,197.59 v4(103.09,196.83) 103.09,195.09 95.96,187.96 90.64,187.96 87.49,184.8 87.49,180.23 85.96,178.71 85.96,178.24 84.51,176.79 84.51,176.23 v1(84.94,175.79)
GPIO_SUS3: length 35.7
  TOP w0.102: CPU2.AH48 84.73,175.26 84.97,175.09 v1(84.97,175.08)
  BOTTOM w0.102: R1805.2 R1806.1 99.37,198.18 v4(99.37,194.97) 99.37,191.69 95.91,188.23 90.37,188.23 87.28,185.14 87.28,180.31 85.73,178.77 85.73,178.3 84.18,176.75 84.18,176.03 84.54,175.67 84.54,175.62 84.97,175.19 v1(84.97,175.08)
GPIO_SVC: length 4.8
  TOP w0.102: TP165.1 96.98,96.01 93.3,96.01 92.89,95.6 GPU1.AJ11
GPIO_SVD: length 4.6
  TOP w0.102: TP163.1 96.5,96.77 93.37,96.77 GPU1.AK12
GPIO_SVT: length 4
  TOP w0.102: TP164.1 96.46,95.6 GPU1.AL11
GPIO_VGA_03_DATA: length 7.6
  TOP w0.102: v3(99.12,97.43) 99.12,96.43 R1165.1 100.71,96.37 101.07,96.02 RN16.2 101.33,95.79 101.34,95.81 101.76,95.81 102.09,96.14 103.87,96.14 104.06,96.33 Q123.4
GPIO_VGA_03_DATA_R: length 19.3
  TOP w0.102: v1(94.39,91.31) 94.62,91.31 96.1,92.79 96.1,93.07 97.77,94.74 97.77,95.85 R1165.2 ; GPU1.U8 83.77,93.2 84.1,92.87 85.27,92.87 v1(85.3,92.84)
  L3 w0.127: v1(85.3,92.84) 92.87,92.84 v1(94.39,91.31)
  BOTTOM w0.102: v4(94.18,92.18) 94.18,91.52 v1(94.39,91.31)
GPIO_VGA_04_CLK: length 7.1
  TOP w0.102: R1166.1 97.99,93.84 98.33,94.18 98.33,94.92 v3(98.61,95.2) 99.2,95.79 RN16.1 100.42,95.44 100.64,95.21 101.25,95.21 101.49,95.45 Q123.1
GPIO_VGA_04_CLK_R: length 15.7
  TOP w0.102: R1166.2 97.1,92.92 v3(96.58,92.41) 95.11,90.93 v1(95.03,90.93) ; v1(85.33,92.08) 84.94,92.08 84.94,92.07 84.54,92.07 84.21,92.4 GPU1.U7
  L3 w0.127: v1(95.03,90.93) 94.99,90.89 94.03,90.89 92.5,92.43 85.68,92.43 v1(85.33,92.08)
GPU_CLKA0_T: length 4.8
  TOP w0.102: C1855.2 48.08,112.55 R1907.2 R1906.2 47.29,111.26 v3(46.99,111.56) C1855.2
GPU_CLKA1_T: length 3.5
  TOP w0.102: C12331.2 47.02,92.09 46.9,91.96 v3(46.9,91.41) 47.25,91.41 47.26,91.43 47.77,91.43 R1909.2 R1908.2
GPU_DMINUS: length 71.6
  TOP w0.254: v1(88.48,82.63) 88.35,82.75 88.35,84.02 86.41,85.96 RT2.2 85.72,85.96 82.6,89.09 GPU1.T2
  L4 w0.254: v1(88.48,82.63) 88.43,82.58 88.43,81.86 87.54,80.98 87.54,74.07 98.03,63.58 98.03,56.9 99.15,55.78 103.57,55.78 104.76,54.58 105.21,54.58 106.08,55.46 106.08,56.15 108.17,58.24 112.02,58.24 112.58,58.8 114.43,58.8 115.6,57.63 121.12,57.63 121.6,57.15 v2(121.6,57.07)
  BOTTOM w0.254: R651.2 124.18,56.53 123.69,57.02 v4(123.31,57.02) C524.2 122.47,56.2 v2(121.6,57.07)
GPU_DP_DET_CN: length 72.4
  TOP w0.102: v1(81.52,121.06) 81.52,121.46 R80115.1 ; v1(92.21,87.3) 89.56,87.3 87.6,89.27 87.26,89.27 87.07,89.46 87.07,90.13 86.77,90.42 86.44,90.42 86.27,90.6 86.27,91.73 86.77,92.24 86.77,93.23 GPU1.Y9
  BOTTOM w0.102: v1(92.21,87.3) 92.84,87.93 96.12,87.93 97.25,89.07 98.62,89.07 v4(98.62,89.06) 98.62,89.07 99.8,89.07 105.24,94.5 105.24,110.06 97.74,117.56 94.13,117.56 93.01,118.68 83.89,118.68 v1(81.52,121.06)
GPU_DPLUS: length 74.2
  TOP w0.203: v2(118.22,56.74) 117.82,56.34 U109.85
  TOP w0.254: v1(87.61,82.68) 87.79,82.85 87.79,83.77 86.49,85.07 RT2.1 82.23,88.64 82.23,89.38 82.19,89.42 82.19,89.78 82.6,90.19 GPU1.T4
  L4 w0.254: v2(118.22,56.74) 118.05,56.91 115.54,56.91 114.2,58.24 112.81,58.24 112.25,57.68 108.4,57.68 106.64,55.92 106.64,55.22 105.44,54.03 104.53,54.03 103.34,55.22 98.92,55.22 97.47,56.67 97.47,63.32 86.98,73.81 86.98,81.21 87.61,81.84 v1(87.61,82.68)
  BOTTOM w0.254: R658.1 116.73,57.65 117.61,56.77 118.19,56.77 v2(118.22,56.74) 118.83,56.74 119.24,57.16 v4(119.76,57.16) 120.08,57.16 121.06,56.18 C524.1
GPU_GPIO16: length 5.4
  TOP w0.102: TP155.1 79.73,87.44 79.73,89.75 79.4,90.09 GPU1.M4
GPU_HDMI_DET_CN: length 116.1
  TOP w0.102: GPU1.AC14 88.53,97.87 88.53,95.8 89.34,94.99 89.34,93.19 89.66,92.87 89.8,92.87 90.18,92.49 90.18,92.36 90.53,92 92.27,92 92.67,91.6 92.67,91.46 92.97,91.16 93.15,91.16 93.44,90.86 93.44,90.65 93.65,90.44 94.52,90.44 v1(94.83,90.13) ; v1(127.06,39.95) 127.06,40.12 R3586.2
  L3 w0.127: v1(94.32,69.72) 95.94,68.1 95.94,52.8 99.32,49.42 103.86,49.42 104.27,49.83 113.8,49.83 114.14,50.17 120.14,50.17 122.07,52.1 122.07,52.39 122.36,52.68 125.35,52.68 126.92,54.25 126.92,55.53 127.76,56.38 128.13,56.38 128.5,56.01 128.5,55.99 129.27,55.22 130.44,55.22 130.88,54.78 130.88,53.76 131.19,53.46 131.19,51.18 131.54,50.82 131.54,50.01 130.97,49.44 130.76,49.44 127.59,46.27 127.59,40.49 v1(127.06,39.95)
  L4 w0.127: v1(94.32,69.72) 94.32,69.85 90.08,74.09 90.08,85.12 89.83,85.36 89.83,88.5 90.79,89.46 94.15,89.46 v1(94.83,90.13)
  BOTTOM w0.102: v1(94.83,90.13) 94.71,90.02 v4(93.94,90.02)
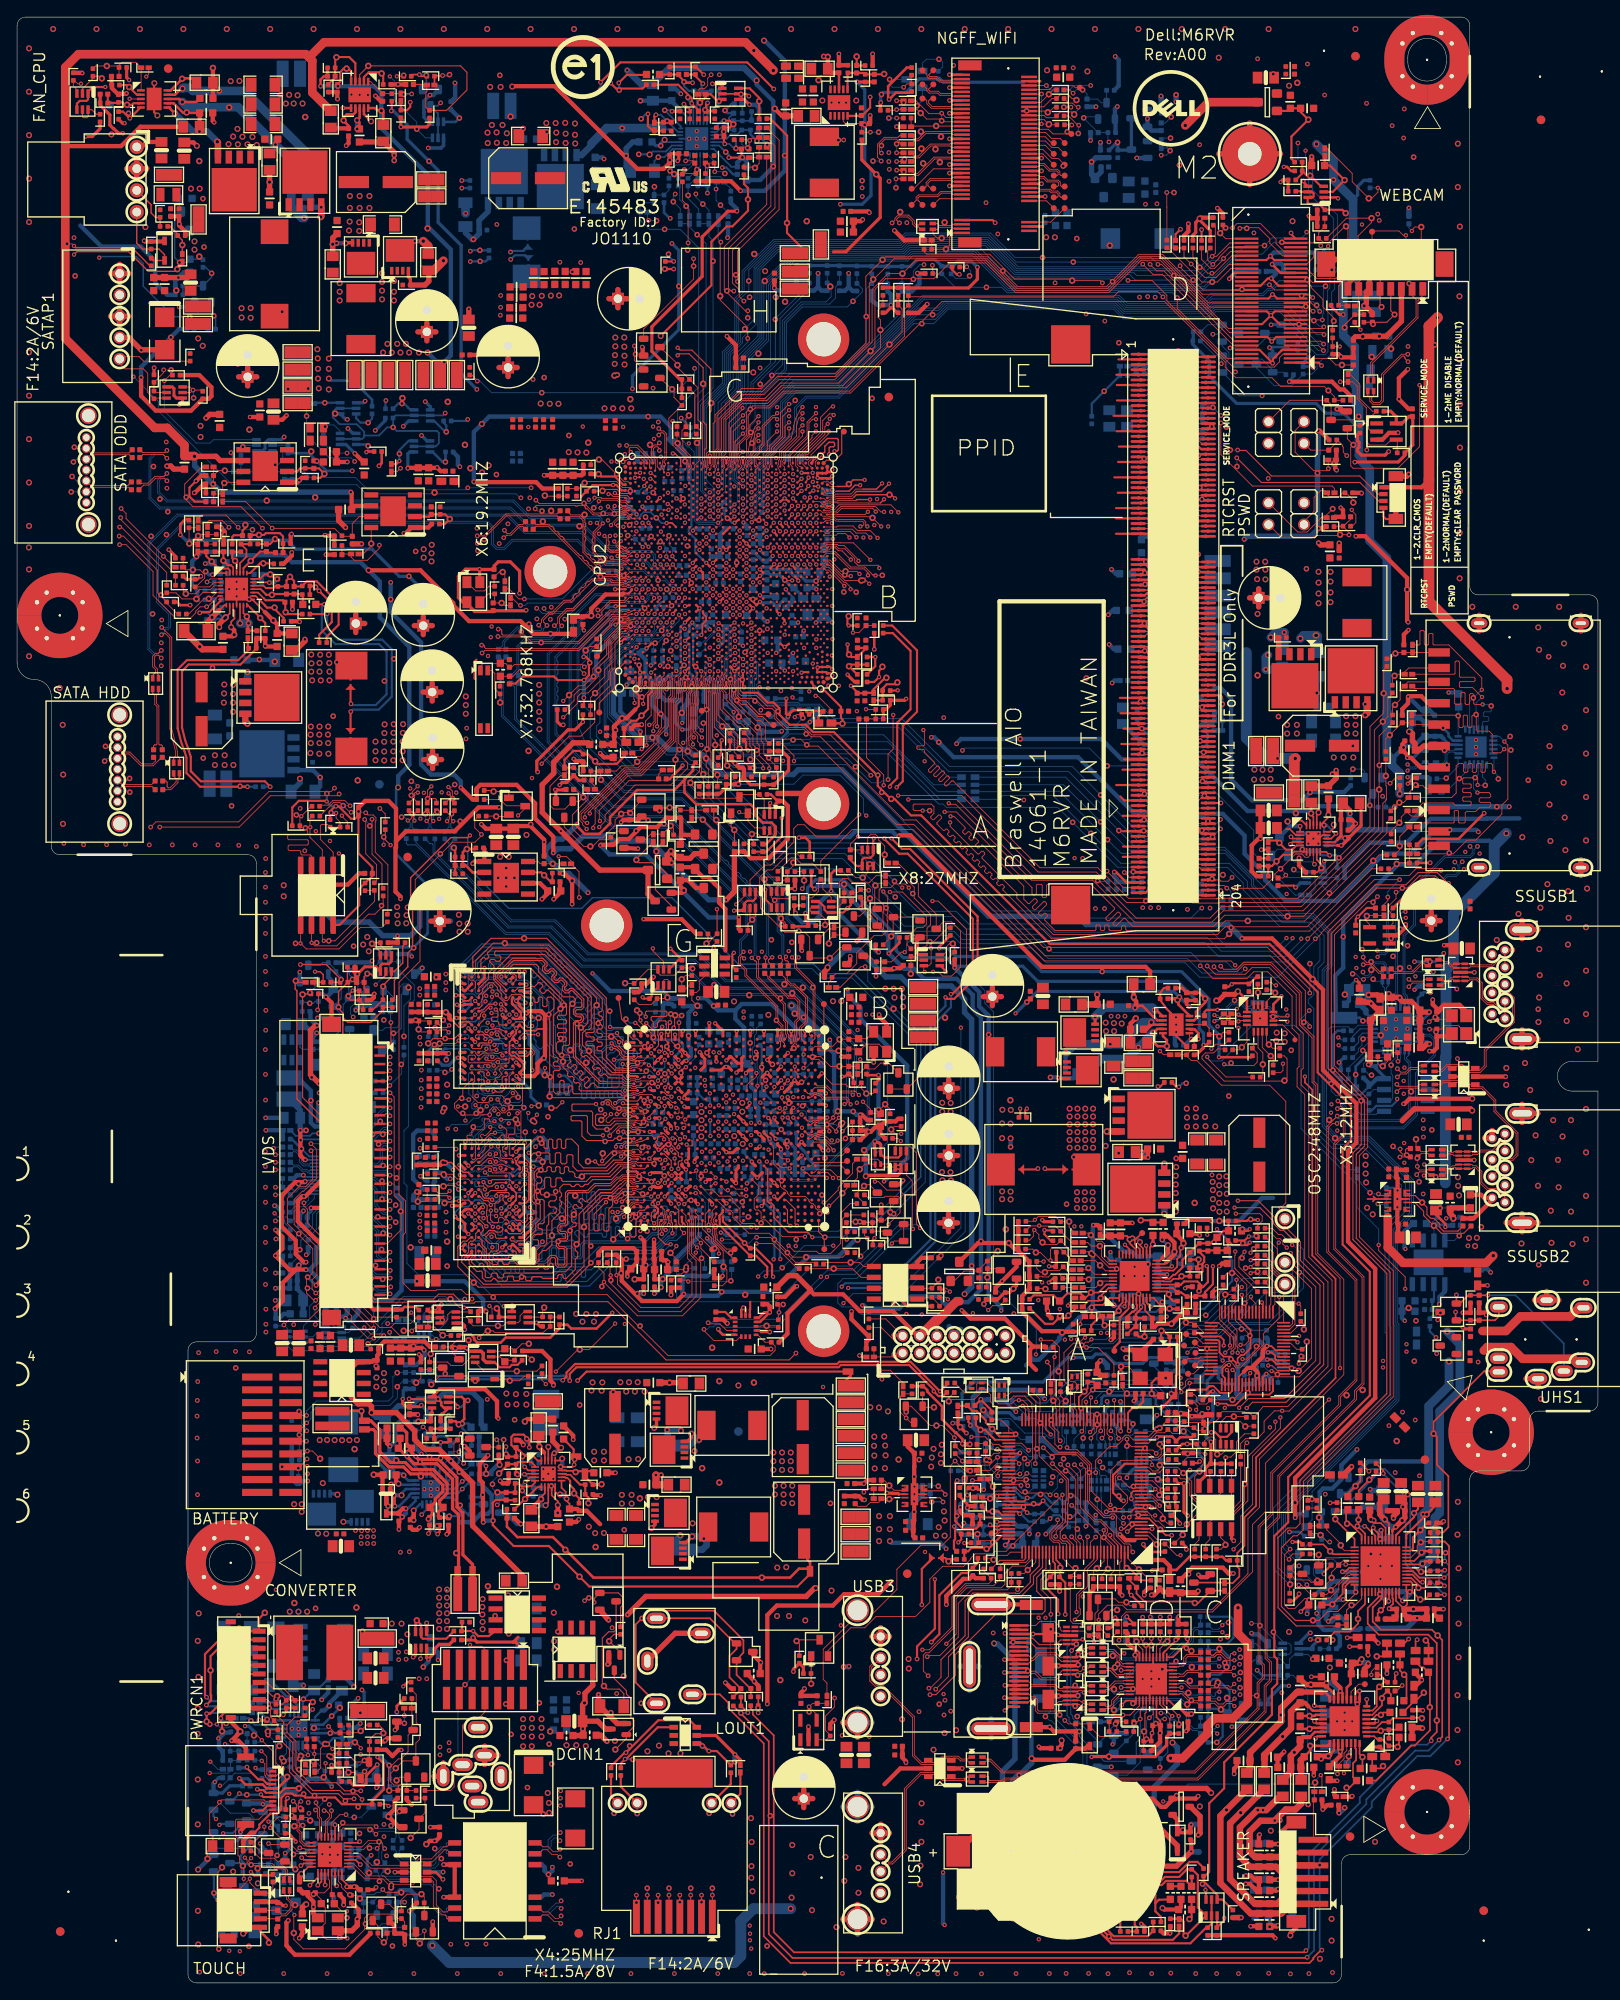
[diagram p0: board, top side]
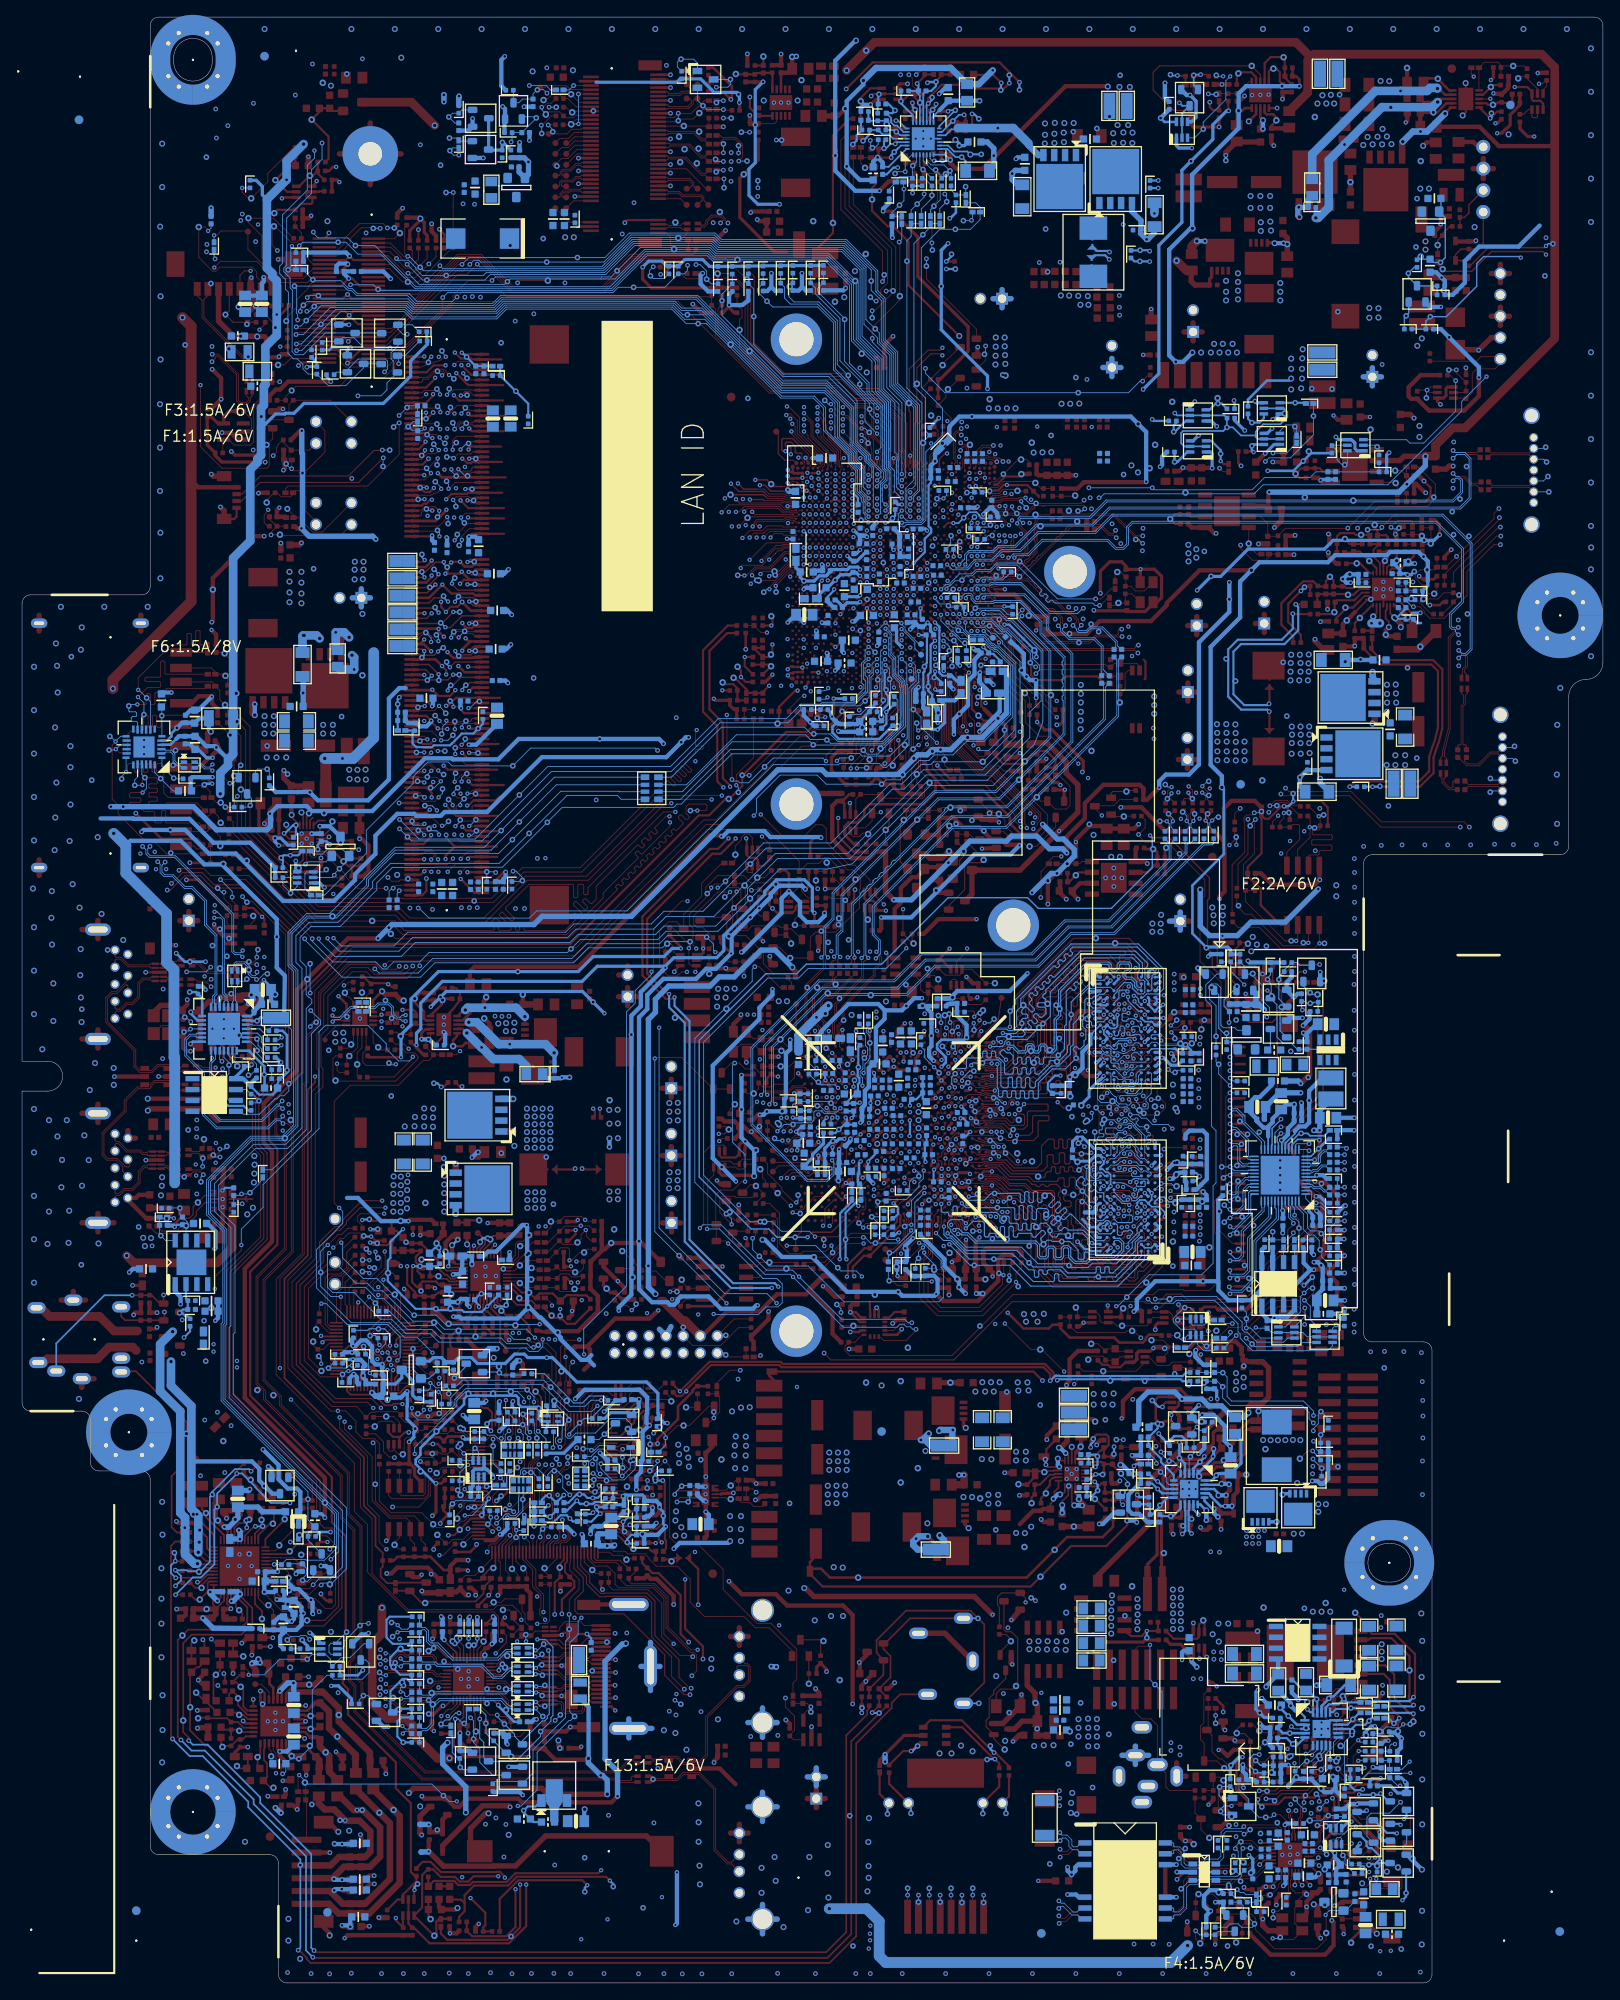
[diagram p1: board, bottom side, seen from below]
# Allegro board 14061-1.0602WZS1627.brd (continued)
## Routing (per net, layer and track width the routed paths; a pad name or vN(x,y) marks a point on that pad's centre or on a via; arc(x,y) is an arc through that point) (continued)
GPU_HSYNC: length 4.7
  TOP w0.102: v1(92.02,107.04) 92.2,107.21 GPU1.AH26
  BOTTOM w0.102: R80140.2 R80141.2 93.08,109.1 v4(93.08,108.36) 93.08,107.83 92.29,107.04 v1(92.02,107.04)
GPU_LVDS_BL_ADJ: length 134.3
  TOP w0.165: v1(52.99,134.25) 52.73,134 50.74,134 46.05,129.31 46.05,126.9 46.28,126.68 46.28,121.05 45.72,120.49 45.72,118.87 44.15,117.31 44.15,115.26 R80134.2 ; GPU1.AB11 87.84,95.16 87.84,91.45 88.05,91.24 88.27,91.24 88.56,90.95 88.56,89.53 90.25,87.83 92.49,87.83 v1(93.07,87.25)
  BOTTOM w0.165: v1(52.99,134.25) 52.74,134 52.74,130.51 57.52,125.72 66.08,125.72 67.32,126.97 76.62,126.97 84.4,119.2 93.22,119.2 94.34,118.08 97.03,118.08 97.95,118.08 105.4,110.62 105.75,110.27 105.75,94.29 104.44,92.97 104.44,92.97 99.67,88.21 97.61,88.21 96.65,87.25 v4(94.53,87.25) v1(93.07,87.25)
GPU_SCL: length 4.8
  TOP w0.102: GPU1.R1 81.8,87.63 81.92,87.5 81.92,86.96 83.02,85.86 83.98,85.86 TP149.1
GPU_SDA: length 6.6
  TOP w0.102: TP150.1 81.72,86.84 81.72,87.4 81.59,87.53 81.59,88.84 arc(81.58,88.92) 81.53,88.99 arc(81.49,89.05) 81.47,89.13 81.47,89.33 81.47,89.34 81.64,89.5 arc(81.76,89.68) 81.8,89.9 GPU1.R3
GPU_THERM_SHUTDOWN*: length 51.2
  TOP w0.102: v1(122.98,79.25) 122.98,79.44 123.68,80.14 PR18.1 ; v1(90.28,86.26) 90.94,85.6 93.56,85.6 93.83,85.32 95.19,85.32 96.38,86.51 96.38,90.07 97.49,91.19 R79964.1
  L4 w0.127: v1(90.28,86.26) 90.28,85.69 94.33,81.64 95.26,81.64 95.52,81.9 98.32,81.9 98.57,81.65 111.32,81.65 111.85,81.11 118.14,81.11 118.89,80.37 121.86,80.37 v1(122.98,79.25)
  BOTTOM w0.102: v4(90.15,85.44) 90.15,86.13 v1(90.28,86.26)
GPU_THERMAL_INT: length 81.9
  TOP w0.102: R1884.1 97.12,88.9 R1885.2 97.12,87.01 v1(97.09,86.97) ; v2(129.88,63.63) 129.88,63.27 130.41,62.74 U109.28
  L3 w0.127: v1(141.33,67.28) 140.33,66.28 139.19,66.28 138.16,65.25 132.9,65.25 131.99,64.34 130.89,64.34 130.18,63.63 v2(129.88,63.63)
  L4 w0.127: v1(141.33,67.28) 141.61,67.56 141.61,70.37 143.9,72.66 143.9,74.83 142.32,76.41 128,76.41 121.93,82.49 119.65,82.49 118.52,83.62 104.1,83.62 103.14,84.57 99.35,84.57 97.09,86.83 v1(97.09,86.97)
  BOTTOM w0.102: R79773.1 129.88,60.79 v4(129.88,62.81) v2(129.88,63.63)
GPU_VCC3_CTL: length 5.1
  TOP w0.381: C1864.1 114.73,79.94 115.57,80.77 PR5476.2 116.14,80.77 v3(116.59,81.23) 116.96,81.6 Q9628.G
  TOP w0.508: C1864.1 113.43,79.94 R1126.1
GPU_VCC3_CTL_2: length 7
  TOP w0.102: Q9629.G 109.67,82.13 110.83,83.29 112.46,83.29 C836.1 112.55,83.45 R1195.2 114.59,85.5 114.64,85.5 v3(114.76,85.62)
GPU_VCC3_CTL_3: length 3.8
  TOP w0.102: Q9628.D 114.88,83.57 R1195.1 113.55,82.56 v3(113.55,82.55) 113.43,82.43 R1129.1
GPU_VREFG: length 6.7
  TOP w0.254: v1(88.77,98.76) 88.77,98.83 GPU1.AC16
  BOTTOM w0.381: R1210.2 91.06,96.02 C1846.1 91.06,97.64 90.2,98.5 v4(90.1,98.5) 89.64,98.5 89.39,98.76 v1(88.77,98.76)
  BOTTOM w0.508: R1210.2 R1211.1
GPU_WAKEB: length 11.3
  TOP w0.102: R1883.2 100.13,104.06 v3(99.38,104.06) 98.8,104.63 R80142.2 98.32,104.83 97.26,104.83 96.93,105.16 95.38,105.16 94.6,105.94 94.6,107.27 93.81,108.06 92.94,108.06 GPU1.AJ27
GPU_XO_IN: length 21.2
  TOP w0.102: GPU1.AC22 88.2,104.23 88.62,104.64 v1(88.62,104.83) ; R1880.1 102.66,100.22 v3(102.29,99.85) 102.29,99.82 102.78,99.34 v1(103.46,99.34)
  L4 w0.127: v1(88.62,104.83) 88.66,104.83 88.97,105.14 98.24,105.14 100.06,103.33 100.06,102.74 v1(103.46,99.34)
GPU_XO_IN2: length 21.8
  TOP w0.102: GPU1.AB22 87.69,104.69 v1(87.69,104.86) ; R1881.1 103.11,98.81 v1(103.41,98.5)
  L4 w0.127: v1(103.41,98.5) 103.41,98.68 99.73,102.36 99.73,103.3 98.33,104.7 90.11,104.7 89.71,104.3 88.25,104.3 v1(87.69,104.86)
  BOTTOM w0.102: v1(87.69,104.86) 87.69,105.51 v4(87.59,105.61)
H_VID0: length 48.8
  TOP w0.102: PR9774.1 123.11,88.43 v3(123.11,89.08) 123.1,89.06 PR9768.1 121.49,89.69 119.51,89.69 v1(119.11,89.28) 118.94,89.11 PR9772.2 ; v1(83.17,92.75) 82.85,92.75 GPU1.T8
  L3 w0.127: v1(83.17,92.75) 83.79,92.75 85.06,91.48 90.92,91.48 95.96,86.44 95.96,86.21 96.69,85.48 111.14,85.48 114.94,89.28 v1(119.11,89.28)
H_VID1: length 53.8
  TOP w0.102: GPU1.N1 80.2,89.01 80.19,89 80.19,88.23 80.96,87.46 80.98,87.46 81.29,87.15 81.29,86.66 82.13,85.82 v1(82.13,85.32) ; PR103.2 118.61,88.57 119.59,88.57 v1(119.62,88.6) 119.67,88.54 121.5,88.54 122.1,87.95 PR9770.1 123.43,86.63 PR9773.1
  L3 w0.127: v1(82.13,85.32) 84.31,85.32 86.72,82.91 v1(86.72,82.65) ; v1(119.62,88.6) 118.93,88.6 118.61,88.91 114.99,88.91 111.27,85.2 96.57,85.2 v1(95.51,86.26)
  BOTTOM w0.102: v1(86.72,82.65) 87.37,83.3 89.16,83.3 v4(89.54,83.68) 92.12,86.26 v1(95.51,86.26)
H_VID2: length 54
  TOP w0.102: GPU1.P8 81.55,93.55 v1(81.73,93.55) ; PR102.2 118.48,86.89 118.93,87.35 118.93,87.99 v1(119.03,88.09) 119.57,87.55 119.57,87.07 v3(120,86.64) 120.26,86.38 121.66,86.38 PR9780.1 123.41,85.55 PR35.1
  L3 w0.127: v1(81.73,93.55) 81.87,93.55 82.49,94.17 83.19,94.17 83.43,93.93 83.43,93.58 83.18,93.32 83.15,93.32 82.75,92.92 82.75,92.57 85,90.32 88.15,90.32 93.56,84.92 111.42,84.92 115.13,88.63 118.49,88.63 v1(119.03,88.09)
H_VID3: length 50.8
  TOP w0.102: GPU1.AK10 93.26,94.8 93.59,95.13 95.2,95.13 v1(96.17,94.16) ; PR32.1 123.49,84.51 PR33.1 121.99,86 121.11,86 120.94,85.83 v1(120.94,84.53) 120.68,84.53 119.75,85.47 v3(119.23,85.47) 118.84,85.85 PR9769.2
  L3 w0.127: v1(120.94,84.53) 120.95,84.55 120.95,89.3 120.25,90 114.85,90 110.88,86.03 97.23,86.03 96.5,86.76 96.5,93.83 v1(96.17,94.16)
H_VID4: length 48.1
  TOP w0.102: PR30.1 122.78,83.44 PR31.1 121.97,83.34 120.47,83.34 v3(120.28,83.16) 119.75,83.16 119.32,83.58 PR9776.2 119.94,84.41 119.95,84.4 v1(120.12,84.4) ; GPU1.AM10 94.87,94.8 v1(95.49,94.18)
  L3 w0.127: v1(95.49,94.18) 96.27,93.4 96.27,86.29 96.8,85.76 111.01,85.76 114.98,89.73 120.13,89.73 120.67,89.19 120.67,85.2 120.12,84.66 v1(120.12,84.4)
H_VID5: length 50.5
  TOP w0.102: v1(83.01,93.75) 82.94,93.75 82.69,94 GPU1.T9 ; PR25.1 123.29,82.4 PR26.1 121.99,82.96 121.04,82.96 120.68,82.59 120.02,82.59 119.94,82.68 PR96.2 119.35,82.46 119.84,81.97 119.95,81.97 v1(119.96,81.95)
  L3 w0.127: v1(91.12,86.21) 87.23,90.09 84.91,90.09 82.52,92.48 82.52,93.26 v1(83.01,93.75)
  L4 w0.127: v1(91.12,86.21) 93.19,84.14 102.08,84.14 103.04,83.19 118.24,83.19 119.46,81.97 119.95,81.97 v1(119.96,81.95)
  BOTTOM w0.102: v4(91.18,86.98) 91.18,86.27 v1(91.12,86.21)
H_VID6: length 4.9
  TOP w0.102: PR9775.2 120.3,81.23 v3(120.34,81.19) 120.63,80.9 122.08,80.9 122.37,81.19 PR5251.1 PR23.1
HDD_FALL_INT2_C: length 51.9
  TOP w0.102: R79799.1 56.54,138.45 57.26,137.73 59.41,137.73 Q6715.3 59.46,137.42 v1(58.63,136.6) ; v1(76.24,154.88) 76.59,154.54 CPU2.M6
  L3 w0.127: v1(81.88,145.97) 81.88,144.2 78.31,140.63 66.25,140.63 63.38,137.76 63.1,137.76 62.24,136.89 59.57,136.89 59.27,136.6 v1(58.63,136.6)
  L4 w0.127: v1(76.24,154.88) 76.22,154.86 76.22,154.53 75.42,153.72 74.02,153.72 73.78,153.48 73.78,152.67 77.99,148.46 80.68,148.46 81.94,147.21 81.94,146.02 v1(81.88,145.97)
  BOTTOM w0.102: v1(76.24,154.88) 76.18,154.82 76.18,154.05 v4(76.16,154.03)
HDM2_CPU_HPD: length 16.6
  TOP w0.089: 80.27,177.49 80.27,177.55 80.36,177.64 80.36,177.99 80.22,178.13 80.22,179.78
  TOP w0.102: 80.22,179.78 80.22,182.35 79.68,182.88 79.68,186.61 R1910.1 78.69,187.61 77.27,189.03 v3(77.27,189.28) 77.27,189.44 Q1246.D ; 80.27,177.49 80.27,177.26 CPU2.W51
HDMI1_DATA_IC_N0: length 4.2
  TOP w0.102: 136.81,33.68 136.38,34.11 135.98,34.11 135.98,34.11 135.92,34.17 U127.2 ; 136.81,33.68 v3(137.07,33.93) ; 136.81,33.68 137.47,33.02 138.25,33.02 C4294.2
HDMI1_DATA_IC_N1: length 4
  TOP w0.102: 136.98,35.06 136.74,35.31 136,35.31 135.93,35.37 U127.5 ; 136.98,35.06 v3(137.24,35.33) ; 136.98,35.06 137.29,34.75 138.18,34.75 C4298.2
HDMI1_DATA_IC_N2: length 4
  TOP w0.102: 137.47,36.58 136.89,36.58 136.44,36.13 136.1,36.13 136.06,36.17 U127.7 ; 137.47,36.58 v3(137.47,36.96) ; 137.47,36.58 138.2,36.58 C4297.2
HDMI1_DATA_IC_N3: length 4.5
  TOP w0.102: U127.10 136.01,37.37 136.05,37.33 136.31,37.33 136.53,37.55 136.53,38.06 136.9,38.43 137.42,38.43 ; 137.42,38.43 138.25,38.43 C4291.2 ; 137.42,38.43 v3(137.42,38.84)
HDMI1_DATA_IC_P0: length 4.3
  TOP w0.102: 137.24,32.89 136.27,33.86 136.1,33.86 136.01,33.77 U127.1 ; 137.24,32.89 137.37,32.77 138.15,32.77 C4295.2 ; 137.24,32.89 v3(136.94,32.59)
HDMI1_DATA_IC_P1: length 3.6
  TOP w0.102: U127.4 135.91,34.97 136,35.05 136.63,35.05 137.19,34.49 138.22,34.49 C4296.2
HDMI1_DATA_IC_P2: length 3.6
  TOP w0.102: U127.6 135.91,35.77 136.02,35.87 136.55,35.87 136.99,36.32 138.2,36.32 C4293.2
HDMI1_DATA_IC_P3: length 4.2
  TOP w0.102: U127.9 135.94,36.97 136.04,37.07 136.41,37.07 136.78,37.44 136.78,37.95 137.01,38.18 138.15,38.18 C4292.2
HDMI2_HPD: length 288.3
  TOP w0.102: v1(153.53,68.25) 146.11,60.83 146.11,55.17 144.58,53.64 144.58,48.1 139.89,43.4 129.78,43.4 129.24,42.86 129.24,40.38 v2(128.95,40.09) ; v2(79.17,201.73) 79.17,199.35 73.32,193.51 Q1246.G ; v1(136.27,34.57) U127.3
  L3 w0.127: v2(128.95,40.09) 128.98,40.13 128.98,40.65 129.79,41.46 135.06,41.46 135.17,41.35 135.34,41.35 136.2,40.49 136.2,39.93 136.32,39.81 136.32,34.74 136.27,34.69 v1(136.27,34.57)
  L4 w0.127: v1(153.53,68.25) 156.72,68.25 160.35,71.88 160.35,86.19 165.62,91.47 165.62,93.19 166.24,93.81 166.24,121.79 166.94,122.48 166.94,127.42 166.09,128.27 165.84,128.27 164.83,129.28 164.83,135.2 165.93,136.31 165.93,144.42 162.3,148.05 162.3,150.73 162.34,150.77 162.34,158.95 162.33,158.96 162.33,159.46 162.76,159.89 162.76,175.94 159.81,178.88 159.81,180.87 153.74,186.94 150.29,186.94 145.73,191.5 145.73,193.45 136.3,202.88 83.34,202.88 82.19,201.73 v2(79.17,201.73)
  BOTTOM w0.102: v2(79.17,201.73) v4(79.17,200.86)
HDMI_CTRL_CLK: length 351.4
  TOP w0.089: CPU2.Y51 80.69,176.85 80.69,177.13 80.86,177.29 80.86,177.31 80.86,177.57 80.78,177.64 80.78,178.4 80.66,178.52 80.66,178.94 80.77,179.05
  TOP w0.102: 81.05,179.62 81.05,179.33 80.77,179.05
  TOP w0.127: R79736.2 134.9,30.93 v1(135.19,31.22) 135.11,31.22 133.74,32.59 U127.38 ; v1(77.3,191.31) 77.58,191.03 78.98,191.03 81.19,188.82 81.19,184.86 v3(81.21,184.84) 81.21,183.93 81.05,183.77 81.05,179.62 ; v1(143.01,67.28) 144.09,68.36 148.32,68.36 152.47,72.52 152.47,81.63 149.75,84.35 149.75,86.5 148.2,88.05 147.82,88.05 147.04,88.83 147.04,89.11 145.44,90.7 v1(142.48,90.7)
  L3 w0.127: v1(142.48,90.7) 142.48,90.91 142.4,90.98 142.4,102.49 135.16,109.73 135.16,113.29 131.63,116.81 120.63,116.81 118.12,119.33 102.83,119.33 102.75,119.41 97.52,119.41 95.71,121.21 83.57,121.21 75.45,129.33 60.74,129.33 57.78,132.3 55.46,132.3 54.61,131.44 41.69,131.44 40.04,133.1 36.49,133.1 34.96,134.63 v1(34.96,134.75)
  L4 w0.127: v1(34.96,134.75) 34.96,136.3 32.58,138.68 23.4,138.68 19.64,142.44 19.64,156.98 22.81,160.15 22.81,163.62 25.56,166.37 38.71,166.37 41.76,163.32 44.06,163.32 44.33,163.59 44.33,171.18 53.02,179.87 53.37,179.87 54.18,179.87 57.04,182.73 57.04,186.22 61.93,191.11 65.41,191.11 68.23,193.93 75.47,193.93 77.3,192.09 v1(77.3,191.31) ; v1(143.01,67.28) 143.01,67.06 142.45,66.5 142.45,66.49 142.39,66.43 142.39,65.15 141.56,64.32 141.56,62.49 140.84,61.76 140.84,59.14 139.26,57.57 139.26,48.06 137.31,46.1 137.31,41.67 136.25,40.61 136.25,39.96 135.82,39.53 135.82,33.3 135.19,32.66 v1(135.19,31.22)
HDMI_CTRL_DATA: length 349.2
  TOP w0.089: CPU2.Y52 80.57,178.05 80.47,178.15 80.47,179.4
  TOP w0.127: 135.93,31.22 v1(135.94,31.22) ; 135.93,31.22 135.15,32 134.72,32 134.14,32.59 U127.39 ; 135.93,31.22 135.93,31.18 135.94,31.18 R79737.2 ; 80.47,179.4 80.65,179.58 80.65,182.3 80.28,182.66 v3(80.28,187.1) 80.28,188.96 78.65,190.6 77.48,190.6 v1(77.3,190.42) ; v1(142.86,91.52) 145.24,91.52 147.47,89.28 147.47,89.01 148,88.48 148.38,88.48 150.19,86.68 150.19,84.53 152.91,81.81 152.91,72.34 148.5,67.93 144.57,67.93 v1(143.9,67.26)
  L3 w0.127: v1(142.86,91.52) 142.83,91.54 142.83,102.69 136.57,108.96 136.57,112.66 134.14,115.08 134.13,115.08 131.97,117.25 121.57,117.25 119.06,119.76 103.01,119.76 102.93,119.84 98.94,119.84 97.14,121.64 83.8,121.64 75.67,129.77 60.92,129.77 57.96,132.73 55.28,132.73 54.43,131.88 42.14,131.88 40.49,133.53 36.69,133.53 v1(36.61,133.6)
  L4 w0.127: v1(143.9,67.26) 143.82,67.26 142.82,66.26 142.82,64.97 141.99,64.14 141.99,59.69 139.69,57.39 139.69,46.11 137.74,44.16 137.74,33.02 v1(135.94,31.22) ; v1(77.3,190.42) 76.47,191.25 76.47,192.31 75.29,193.49 68.51,193.49 65.69,190.68 62.11,190.68 57.48,186.04 57.48,182.54 54.38,179.44 53.19,179.44 44.76,171.01 44.76,163.41 44.16,162.81 41.66,162.81 38.53,165.94 35.38,165.94 25.74,165.94 23.24,163.44 23.24,159.97 20.07,156.8 20.07,142.62 23.57,139.12 33.24,139.12 36.61,135.75 v1(36.61,133.6)
HDMI_DATA_CPU_N0: length 240.4
  TOP w0.102: CPU2.C51 72.87,176.64 v1(72.9,176.68) ; 141.59,32.94 141.46,32.94 141.14,32.63 140.58,32.63 140.24,32.97 139.72,32.97 C4294.1 ; 141.59,32.94 v3(141.59,33.35) ; 141.59,32.94 142.16,32.94 v1(142.48,33.26)
  L4 w0.102: v1(142.48,33.26) 144.14,33.26 146.59,35.71 146.59,55.09 148.48,56.98 148.48,60.71 151.34,63.57 151.34,68.32 152.66,69.64 152.66,95.51 152.9,95.75 153.63,95.75 153.75,95.87 153.75,96.13 153.63,96.26 152.9,96.26 152.66,96.49 152.66,96.99 152.9,97.22 153.69,97.22 153.82,97.35 153.82,97.6 153.69,97.73 152.9,97.73 152.66,97.96 152.66,101.07 141.99,111.74 141.99,114.21 140.04,116.15 137.17,116.15 136.71,116.62 117.88,116.62 110.7,123.8 78.98,123.8 70.61,132.18 64.91,132.18 59.24,137.85 59.24,142.67 60.08,143.51 60.08,162.02 58.83,163.26 58.83,166.59 63.74,171.5 63.74,173.52 65.89,175.67 67.91,175.67 68.92,176.68 v1(72.9,176.68)
HDMI_DATA_CPU_N1: length 243.1
  TOP w0.102: 140.52,34.77 141.77,34.77 141.92,34.62 142.07,34.62 v1(142.43,34.98) ; 140.52,34.77 v3(140.52,35.15) ; 140.52,34.77 139.72,34.77 C4298.1 ; CPU2.H50 v1(74.13,176.66)
  L4 w0.102: v1(74.13,176.66) 74.05,176.58 73.9,176.58 73.16,177.33 68.53,177.33 67.58,176.38 65.57,176.38 62.99,173.8 62.99,171.8 58.1,166.9 58.1,160.87 59.34,159.62 59.34,143.81 58.53,143 58.53,137.39 64.49,131.43 70.29,131.43 78.63,123.09 110.28,123.09 116.11,117.26 116.11,116.93 116.58,116.45 116.91,116.45 117.46,115.91 136.41,115.91 136.88,115.44 138.59,115.44 138.77,115.27 138.77,113.71 139.03,113.45 139.7,113.45 139.96,113.71 139.96,114.58 140.09,114.71 140.49,114.71 141.28,113.91 141.28,111.45 151.91,100.82 151.91,69.91 150.61,68.62 150.61,63.85 147.77,61 147.77,57.28 145.88,55.39 145.88,38.13 145.62,37.88 145.62,37.33 145.88,37.07 145.88,36.47 145.11,35.71 144.97,35.71 144.28,36.39 143.95,36.39 143.6,36.04 143.6,35.71 144.28,35.02 144.28,34.88 143.87,34.47 142.93,34.47 v1(142.43,34.98)
HDMI_DATA_CPU_N2: length 242.6
  TOP w0.089: CPU2.F52 73.37,177.41 73.37,177.96 73.35,177.99 73.35,178
  TOP w0.102: 141.54,36.55 142.1,36.55 v1(142.43,36.88) ; 141.54,36.55 v3(141.54,36.96) ; 141.54,36.55 139.75,36.55 C4297.1 ; v2(70.92,177.98) 71.05,178.1 71.28,178.1 71.43,178.26 71.94,178.26 72.12,178.44 72.92,178.44 73.35,178.01 73.35,178
  L4 w0.102: v1(142.43,36.88) 142.48,36.83 143.31,36.83 145.17,38.68 145.17,39.32 145.07,39.42 144.08,39.42 143.82,39.68 143.82,40.1 144.08,40.36 145.07,40.36 145.17,40.46 145.17,55.77 147.04,57.64 147.04,61.27 149.89,64.13 149.89,68.95 151.18,70.24 151.18,100.21 137.96,113.43 137.96,114.23 137.45,114.73 136.58,114.73 136.12,115.19 116.66,115.19 115.37,113.9 113.33,113.9 112.43,114.8 112.43,119.41 109.46,122.38 78.32,122.38 69.99,130.7 61.38,130.7 57.74,134.34 57.74,143.33 58.55,144.15 58.55,159.32 57.34,160.54 57.34,167.21 62.24,172.12 62.24,174.29 65.19,177.24 67.36,177.24 68.76,178.64 70.26,178.64 v2(70.92,177.98)
HDMI_DATA_CPU_N3: length 241.3
  TOP w0.089: 74.04,177.8 74.04,178.13
  TOP w0.102: 140.7,38.68 140.34,38.68 140.01,38.35 139.75,38.35 C4291.1 ; 140.7,38.68 140.95,38.68 141.64,38 141.84,38 141.97,38.13 141.97,38.43 142.1,38.56 v1(142.45,38.56) ; 140.7,38.68 v3(140.7,39.09) ; v1(71.81,179.12) 71.81,179.14 71.64,179.32 71.64,179.53 71.76,179.65 72.53,179.65 74.04,178.14 74.04,178.13 ; 74.04,177.8 74.04,177.67 74,177.63 74,177.37 74.12,177.25 CPU2.G52
  L4 w0.102: v1(142.45,38.56) 142.25,38.76 142.25,39.22 143.62,40.59 143.62,41.99 144.69,43.05 144.69,55.98 146.55,57.85 146.55,61.47 149.39,64.31 149.39,69.15 150.7,70.47 150.7,99.93 136.13,114.5 135.92,114.71 116.87,114.71 116.73,114.58 115.58,113.42 113.12,113.42 110.75,115.79 110.75,120.12 109.02,121.84 103.87,121.84 103.46,121.44 82.07,121.44 81.79,121.72 81.24,121.72 80.96,121.44 78.56,121.44 69.79,130.21 60.94,130.21 57.26,133.88 57.26,143.69 58,144.43 58,159.07 56.78,160.29 56.78,167.45 61.69,172.36 61.69,174.47 65.16,177.94 67.27,177.94 68.53,179.2 70.76,179.2 70.98,179.42 71.52,179.42 v1(71.81,179.12)
HDMI_DATA_CPU_P0: length 240.3
  TOP w0.102: v3(140.88,31.98) 140.88,32.37 ; 140.88,32.37 140.48,32.37 140.14,32.71 139.72,32.71 C4295.1 ; 140.88,32.37 141.25,32.37 141.57,32.69 142.15,32.69 v1(142.45,32.38) ; CPU2.D50 72.38,176.16 v1(72.32,176.1)
  L4 w0.102: v1(72.32,176.1) 72.32,176.31 72.18,176.45 69.01,176.45 68,175.44 65.98,175.44 63.96,173.42 63.96,171.4 59.06,166.5 59.06,163.36 60.31,162.11 60.31,143.42 59.47,142.58 59.47,137.94 65,132.41 70.7,132.41 79.08,124.03 110.8,124.03 117.98,116.85 136.8,116.85 137.27,116.38 140.14,116.38 142.22,114.3 142.22,111.83 152.89,101.17 152.89,98.06 152.99,97.96 153.79,97.96 154.05,97.7 154.05,97.25 153.79,96.99 152.99,96.99 152.89,96.89 152.89,96.59 152.99,96.48 153.72,96.48 153.98,96.22 153.98,95.78 153.72,95.52 152.99,95.52 152.89,95.42 152.89,69.55 151.57,68.22 151.57,63.47 148.71,60.61 148.71,56.88 146.82,54.99 146.82,35.62 144.23,33.03 143.1,33.03 v1(142.45,32.38)
HDMI_DATA_CPU_P1: length 243.6
  TOP w0.102: v1(74.11,175.98) 74.26,175.98 CPU2.H49 ; v1(142.43,34.07) 142.13,34.37 141.82,34.37 141.67,34.52 139.72,34.52 C4296.1
  L4 w0.102: v1(74.11,175.98) 73.74,176.35 73.74,176.42 73.06,177.1 68.62,177.1 67.67,176.15 65.67,176.15 63.22,173.71 63.22,171.7 58.33,166.8 58.33,160.96 59.57,159.72 59.57,143.72 58.76,142.91 58.76,137.48 64.59,131.66 70.39,131.66 78.73,123.32 110.37,123.32 116.33,117.35 116.33,117.02 116.68,116.68 117.01,116.68 117.55,116.13 136.51,116.13 136.97,115.67 138.69,115.67 139,115.36 139,113.8 139.12,113.68 139.61,113.68 139.73,113.8 139.73,114.67 139.99,114.94 140.58,114.94 141.51,114.01 141.51,111.54 152.13,100.92 152.13,69.82 150.84,68.53 150.84,63.75 148,60.91 148,57.19 146.11,55.3 146.11,38.04 145.85,37.78 145.85,37.42 146.11,37.17 146.11,36.38 145.21,35.48 144.87,35.48 144.19,36.16 144.05,36.16 143.83,35.94 143.83,35.8 144.51,35.12 144.51,34.78 143.97,34.24 142.59,34.24 v1(142.43,34.07)
  BOTTOM w0.102: v1(142.43,34.07) 142.65,34.07 v4(143.13,34.54)
HDMI_DATA_CPU_P2: length 243.2
  TOP w0.102: v2(70.21,178) 70.62,178.41 71.23,178.41 71.33,178.51 71.83,178.51 72.01,178.69 73.03,178.69 73.65,178.07 73.65,177.87 CPU2.F53 ; C4293.1 139.7,36.3 142.12,36.3 v1(142.43,35.99)
  L4 w0.102: v2(70.21,178) 69.81,178.41 68.85,178.41 67.46,177.01 65.29,177.01 62.47,174.19 62.47,172.02 57.56,167.12 57.56,160.63 58.78,159.41 58.78,144.05 57.97,143.24 57.97,134.44 61.48,130.93 70.09,130.93 78.41,122.61 109.56,122.61 112.66,119.51 112.66,114.9 113.42,114.13 115.28,114.13 116.57,115.42 136.21,115.42 136.68,114.96 137.55,114.96 138.19,114.32 138.19,113.53 151.41,100.3 151.41,70.14 150.12,68.85 150.12,64.03 147.26,61.18 147.26,57.54 145.4,55.68 145.4,40.37 145.16,40.13 144.18,40.13 144.05,40.01 144.05,39.78 144.18,39.65 145.16,39.65 145.4,39.41 145.4,38.59 143.41,36.6 143.04,36.6 142.91,36.47 142.91,36.12 142.78,35.99 v1(142.43,35.99)
  BOTTOM w0.102: v4(143.16,36.32) 142.83,35.99 v1(142.43,35.99)
HDMI_DATA_CPU_P3: length 241.7
  TOP w0.102: v1(142.45,37.74) 141.53,37.74 140.85,38.43 140.42,38.43 140.11,38.12 139.72,38.12 C4292.1 ; v2(71.33,179.88) 71.36,179.91 72.64,179.91 74.38,178.16 CPU2.G53
  L4 w0.102: v1(142.45,37.74) 142.45,37.8 142.07,38.18 142.07,38.33 142.02,38.38 142.02,39.31 143.39,40.68 143.39,42.08 144.46,43.15 144.46,56.08 146.32,57.94 146.32,61.57 149.16,64.4 149.16,69.25 150.47,70.57 150.47,99.83 136.03,114.27 135.82,114.48 116.96,114.48 115.67,113.19 113.03,113.19 110.52,115.7 110.52,120.02 108.93,121.62 103.96,121.62 103.56,121.21 81.97,121.21 81.7,121.49 81.34,121.49 81.06,121.21 78.46,121.21 69.69,129.98 60.84,129.98 57.03,133.79 57.03,143.79 57.77,144.53 57.77,158.97 56.55,160.19 56.55,167.54 61.46,172.45 61.46,174.57 65.06,178.17 67.18,178.17 68.43,179.43 70.67,179.43 71.12,179.88 v2(71.33,179.88)
  BOTTOM w0.102: v1(142.45,37.74) 142.81,37.74 v4(143.16,38.1)
HDMI_DATA_GPU_N0: length 127
  TOP w0.102: v1(96.17,101.22) 95.54,100.58 93.79,100.58 93.67,100.65 93.65,100.66 93.59,100.67 93.57,100.69 93.52,100.72 93.46,100.73 93.35,100.73 arc(93.29,100.72) 93.23,100.69 arc(93.22,100.68) 93.2,100.67 93.1,100.57 arc(93.05,100.52) 93,100.49 arc(92.85,100.42) 92.7,100.4 GPU1.AJ17
  L4 w0.102: v1(96.17,101.22) 95.54,100.58 93.78,100.58 93.33,100.13 93.33,96.93 94.39,95.86 101.35,95.86 102.45,94.76 102.45,93.39 102.9,92.93 102.9,87.3 104.94,85.27 121.57,85.27 128.22,78.61 135.08,78.61 135.62,78.07 142.29,78.07 144.93,75.43 144.93,67.3 143.6,65.98 143.6,64.73 142.72,63.84 142.72,59.39 140.42,57.09 140.42,45.81 138.46,43.86 138.46,33.56 138.64,33.39 138.64,30.51 139.09,30.06 v1(140.5,30.06)
  BOTTOM w0.102: C4279.1 139.75,29.7 140.14,29.7 v1(140.5,30.06) ; v4(96.6,100.63) 96.17,101.07 v1(96.17,101.22)
HDMI_DATA_GPU_N1: length 122.3
  TOP w0.102: v1(95.05,99.64) 95.05,99.9 94.93,100.03 93.1,100.03 93,99.93 GPU1.AK16
  L4 w0.102: v1(95.05,99.64) 95.36,99.93 95.36,99.93 95.36,100.03 95.29,100.1 94.18,100.1 93.89,99.8 93.89,97.18 94.5,96.57 101.75,96.57 103.16,95.17 103.16,93.74 103.64,93.26 103.64,87.58 105.24,85.98 121.86,85.98 128.03,79.81 133.14,79.81 133.62,79.32 133.9,79.32 134.14,79.56 135.16,79.56 135.8,78.92 142.49,78.92 145.73,75.68 145.73,67.09 144.32,65.68 144.32,64.4 143.43,63.51 143.43,59.09 141.13,56.79 141.13,45.52 139.17,43.56 139.17,36.93 139.44,36.67 139.44,36 139.2,35.76 139.2,33.83 139.61,33.43 140.09,33.43 140.22,33.55 140.22,33.91 140.34,34.04 140.67,34.04 v1(140.7,34.06)
  BOTTOM w0.102: v4(140.37,34.8) 140.44,34.8 140.7,34.54 v1(140.7,34.06) 140.67,34.04 140.34,34.04 140.22,33.91 140.22,33.63 140.09,33.5 139.88,33.5 C4274.1
HDMI_DATA_GPU_N2: length 113.8
  TOP w0.102: v1(96.02,98.55) 95.64,98.17 95.16,98.17 94.39,98.93 93.96,98.93 93.66,99.06 93.65,99.06 93.59,99.07 93.57,99.09 93.52,99.12 93.46,99.13 93.35,99.13 arc(93.29,99.12) 93.23,99.09 arc(93.22,99.08) 93.2,99.07 93.1,98.97 arc(93.05,98.92) 93,98.89 arc(92.85,98.82) 92.7,98.8 GPU1.AJ15
  L4 w0.102: v1(96.02,98.55) 96.02,98.21 96.95,97.28 102.13,97.28 104.35,95.07 104.35,87.96 105.54,86.77 122.08,86.77 128.33,80.52 135.2,80.52 136.05,79.68 142.86,79.68 147.76,74.78 147.76,71.6 146.44,70.28 146.44,66.8 145.03,65.39 145.03,63.22 144.24,62.43 144.24,58.81 142.37,56.94 142.37,54.45 141.84,53.92 141.84,53.64 142.08,53.4 142.08,52.33 141.84,52.1 141.84,47.3 142.08,47.06 142.08,46.39 141.84,46.15 141.84,44.86 139.94,42.95 139.94,38.09 140.19,37.84 140.59,37.84 v1(140.7,37.95)
  BOTTOM w0.102: v4(96.93,98.81) 96.68,98.55 v1(96.02,98.55) ; C4276.1 139.73,37.59 140.34,37.59 v1(140.7,37.95)
HDMI_DATA_GPU_N3: length 127.4
  TOP w0.102: v1(94.93,97.41) 94.91,97.42 94.91,97.75 94.29,98.37 93.2,98.37 93,98.17 GPU1.AK14
  L4 w0.102: v1(94.93,97.41) 95.05,97.54 95.05,97.82 94.6,98.28 94.6,98.82 94.99,99.21 96.37,99.21 97.59,97.99 102.57,97.99 105.24,95.33 105.24,89.78 107.44,87.58 112.77,87.58 112.87,87.68 112.87,88.89 113.13,89.15 113.55,89.15 113.81,88.89 113.81,87.68 113.91,87.58 114.19,87.58 114.29,87.68 114.29,88.92 114.55,89.18 114.97,89.18 115.23,88.92 115.23,87.68 115.33,87.58 115.61,87.58 115.71,87.68 115.71,88.23 115.98,88.49 116.39,88.49 116.65,88.23 116.65,87.68 116.76,87.58 117.04,87.58 117.14,87.68 117.14,88.23 117.4,88.49 117.82,88.49 118.08,88.23 118.08,87.68 118.18,87.58 122.44,87.58 128.79,81.23 135.54,81.23 135.92,80.85 136.94,80.85 138.39,82.3 141.82,82.3 142.76,81.36 142.76,80.44 143.14,80.06 143.56,80.06 143.88,79.75 144.16,79.46 145.05,78.58 145.19,78.58 146.17,79.55 146.54,79.55 146.83,79.26 146.83,78.89 145.86,77.91 145.86,77.77 146.05,77.57 146.2,77.57 147.17,78.54 147.54,78.54 147.84,78.25 147.84,77.88 146.86,76.9 146.86,76.76 148.42,75.2 148.42,71.37 147.4,70.36 147.4,66.76 145.81,65.17 145.81,63 144.95,62.14 144.95,58.51 143.09,56.64 143.09,44.96 140.72,42.6 140.72,42.21 141.04,41.9 v1(141.04,41.86)
  BOTTOM w0.102: v4(141.77,42.16) 141.38,42.16 141.08,41.86 v1(141.04,41.86) 141.04,41.82 140.6,41.38 139.88,41.38 C4278.1
HDMI_DATA_GPU_P0: length 127.1
  TOP w0.102: v3(96.05,101.98) 95.51,101.45 v1(95.51,101.24) 95.1,100.84 93.79,100.84 93.74,100.86 93.59,100.92 arc(93.53,100.94) 93.48,100.95 93.35,100.95 arc(93.22,100.93) 93.11,100.87 arc(93.11,100.87) 93.11,100.87 arc(93.08,100.85) 93.05,100.82 93.04,100.81 92.75,100.81 92.73,100.82 arc(92.59,100.85) 92.47,100.93 GPU1.AH18
  L4 w0.102: v1(95.51,101.24) 95.08,100.81 93.68,100.81 93.1,100.23 93.1,96.83 94.3,95.63 101.25,95.63 102.22,94.67 102.22,93.29 102.67,92.84 102.67,87.21 104.84,85.04 121.47,85.04 128.13,78.38 134.98,78.38 135.53,77.84 142.2,77.84 144.7,75.33 144.7,67.4 143.38,66.07 143.38,64.82 142.49,63.94 142.49,59.48 140.19,57.18 140.19,45.91 138.23,43.95 138.23,33.47 138.41,33.29 138.41,30.41 138.99,29.83 140.05,29.83 140.15,29.73 140.15,29.46 v1(140.44,29.17)
  BOTTOM w0.102: v1(140.44,29.17) 140.17,29.44 139.67,29.44 C4272.1
HDMI_DATA_GPU_P1: length 122.6
  TOP w0.102: GPU1.AL17 93.52,100.28 95.21,100.28 v1(95.87,99.62) 95.87,99.9 v3(96.43,100.46)
  L4 w0.102: v1(140.66,33.25) 140.62,33.25 140.57,33.2 139.51,33.2 138.97,33.74 138.97,35.86 139.21,36.09 139.21,36.57 138.95,36.84 138.95,43.66 140.9,45.61 140.9,56.89 143.2,59.19 143.2,63.61 144.09,64.49 144.09,65.78 145.5,67.19 145.5,75.58 142.4,78.69 135.71,78.69 135.06,79.33 134.23,79.33 134,79.1 133.53,79.1 133.04,79.58 127.94,79.58 121.77,85.75 105.15,85.75 103.41,87.48 103.41,93.17 102.93,93.65 102.93,95.07 101.66,96.34 94.4,96.34 93.66,97.09 93.66,99.9 94.09,100.33 95.38,100.33 95.59,100.12 95.59,99.91 v1(95.87,99.62)
  BOTTOM w0.102: C4273.1 139.53,33.25 v1(140.66,33.25)
HDMI_DATA_GPU_P2: length 113.9
  TOP w0.102: GPU1.AH16 92.47,99.33 arc(92.59,99.25) 92.73,99.22 92.75,99.21 93.04,99.21 93.05,99.22 arc(93.08,99.25) 93.11,99.27 arc(93.11,99.27) 93.11,99.27 arc(93.22,99.33) 93.35,99.35 93.48,99.35 arc(93.53,99.34) 93.59,99.32 93.71,99.27 93.74,99.26 94.01,99.19 94.5,99.19 95.11,98.58 v1(95.33,98.58)
  L4 w0.102: v1(140.67,37.03) 140.02,37.68 139.71,38 139.71,43.05 141.61,44.95 141.61,46.25 141.85,46.48 141.85,46.97 141.61,47.2 141.61,52.19 141.85,52.43 141.85,53.31 141.61,53.54 141.61,54.01 142.15,54.55 142.15,57.03 144.01,58.9 144.01,62.53 144.8,63.31 144.8,65.48 146.21,66.89 146.21,70.38 147.53,71.7 147.53,74.69 142.77,79.45 135.95,79.45 135.11,80.29 128.23,80.29 121.99,86.54 105.45,86.54 104.12,87.87 104.12,94.97 102.04,97.05 96.86,97.05 v1(95.33,98.58)
  BOTTOM w0.102: v4(141.34,37.46) 141.34,37.42 140.95,37.03 v1(140.67,37.03) 140.37,37.34 139.71,37.34 139.41,37.04 C4275.1
HDMI_DATA_GPU_P3: length 127.3
  TOP w0.102: GPU1.AL15 93.57,98.63 94.4,98.63 95.33,97.69 95.33,97.59 95.52,97.41 v1(95.56,97.41)
  L4 w0.102: v1(141.05,41.03) 141.05,41.04 140.5,41.59 140.5,42.7 142.86,45.06 142.86,56.74 144.72,58.61 144.72,62.23 145.59,63.09 145.59,65.26 147.18,66.85 147.18,70.45 148.19,71.47 148.19,75.11 146.63,76.67 146.63,77 147.61,77.97 147.61,78.15 147.45,78.32 147.27,78.32 146.29,77.34 145.96,77.34 145.63,77.67 145.63,78 146.6,78.98 146.6,79.16 146.44,79.32 146.26,79.32 145.28,78.35 144.95,78.35 144.07,79.23 143.78,79.52 143.47,79.83 143.04,79.83 142.53,80.35 142.53,81.26 141.72,82.07 138.48,82.07 137.03,80.62 135.82,80.62 135.44,81 128.69,81 122.34,87.35 118.08,87.35 117.85,87.59 117.85,88.14 117.72,88.27 117.49,88.27 117.37,88.14 117.37,87.59 117.13,87.35 116.66,87.35 116.43,87.59 116.43,88.14 116.3,88.27 116.07,88.27 115.94,88.14 115.94,87.59 115.71,87.35 115.24,87.35 115,87.59 115,88.82 114.88,88.95 114.65,88.95 114.52,88.82 114.52,87.59 114.29,87.35 113.82,87.35 113.58,87.59 113.58,88.8 113.45,88.93 113.23,88.93 113.1,88.8 113.1,87.59 112.86,87.35 107.35,87.35 105.01,89.69 105.01,95.23 102.48,97.76 97.49,97.76 96.27,98.98 95.08,98.98 94.83,98.73 94.83,98.37 95.28,97.92 95.28,97.69 v1(95.56,97.41)
  BOTTOM w0.102: C4277.1 139.53,41.12 140.96,41.12 v1(141.05,41.03) 141.08,41.03 141.08,41.01 141.09,41.01 141.59,40.51 v4(141.64,40.51)
HDMI_DP2_HPD: length 11.3
  TOP w0.102: R79733.2 R79732.2 ; R79733.2 128.69,29.39 128.13,28.83 126.7,28.83 D33.K 125.22,30.31 C4280.2 123.01,30.31 v2(122.61,30.71) ; R79733.2 R79738.1 R79739.1
  BOTTOM w0.102: v4(122,31.37) 122,31.32 v2(122.61,30.71)
HDMI_GPU_CTRL_CLK: length 6.8
  BOTTOM w0.127: Q1255.S 128.42,26.93 R80110.2 130.72,29.22 v4(130.72,30.36) 130.72,31.34 131.42,32.05 R80092.1
HDMI_GPU_CTRL_DATA: length 6.1
  BOTTOM w0.127: Q1256.S 133.45,24.95 v4(133.71,25.21) 133.77,25.27 R80111.2 133.95,26.26 134.65,26.96 134.65,29.04 R80093.1
HDMI_HTPLG_CN1: length 8.4
  TOP w0.102: R80113.1 126.14,42.22 126.14,43.2 126.49,43.55 Q2301.D 126.54,44.93 128.51,44.93 128.91,44.53 v3(129.81,44.53) 130.23,44.12 R80157.2
HDMI_LANE0_DN: length 13.3
  TOP w0.102: TR24.2 125.14,32.61 v1(124.88,32.87) 124.53,32.87 124.33,33.06 U129.2 U129.9 122.42,33.06 122.28,32.92 121.9,32.92 121.62,32.64 121.62,32.03 121.39,31.8 119.57,31.8 119.41,31.96 119.41,33.18 119.12,33.47 118.71,33.47 118.37,33.82 HDMI1.3
  BOTTOM w0.102: TR24.2 125.14,32.61 v1(124.88,32.87) 124.38,32.37 v4(123.83,32.37)
HDMI_LANE0_DN_C: length 16
  BOTTOM w0.102: TR20.4 127.57,32.61 127.78,32.39 127.98,32.39 128.86,33.27 136.21,33.27 137.12,32.37 137.12,31.47 ; 137.12,31.47 137.12,30.33 137.68,29.77 138.21,29.77 C4279.2 R79724.1 ; 137.12,31.47 v4(137.42,31.47)
HDMI_LANE0_DP: length 13.4
  TOP w0.102: TR24.3 125.09,31.93 v1(124.87,32.14) 124.75,32.14 124.32,32.58 U129.1 U129.10 122.37,32.58 122.28,32.66 122.01,32.66 121.88,32.53 121.88,31.93 121.5,31.55 119.46,31.55 119.16,31.85 119.16,33.07 119.01,33.22 118.71,33.22 118.32,32.82 HDMI1.1
  BOTTOM w0.102: v4(124.06,31.17) 124.87,31.99 v1(124.87,32.14) 125.09,31.93 TR24.3
HDMI_LANE0_DP_C: length 16.1
  BOTTOM w0.102: v4(130.59,32.69) 130.59,33.02 ; 130.59,33.02 128.97,33.02 128.09,32.14 127.78,32.14 127.57,31.93 TR20.1 ; 130.59,33.02 136.11,33.02 136.86,32.26 136.86,30.22 137.57,29.51 138.16,29.51 C4272.2 R79726.1
HDMI_LANE0_IC_DN: length 4.3
  TOP w0.102: TR24.1 127.18,32.61 127.41,32.38 127.89,32.38 128.09,32.57 128.09,33.06 129.09,34.06 129.45,34.06 129.56,34.17 U127.29
HDMI_LANE0_IC_DP: length 4.6
  TOP w0.102: v3(128.36,31.94) 128.09,32.21 ; 128.09,32.21 128.34,32.47 128.34,32.96 129.19,33.81 129.41,33.81 129.45,33.77 U127.30 ; 128.09,32.21 128,32.12 127.45,32.12 127.26,31.93 TR24.4
HDMI_LANE1_DN: length 11.1
  TOP w0.102: HDMI1.6 118.32,35.32 118.71,34.92 121.48,34.92 121.95,34.44 122.31,34.44 122.45,34.58 U129.6 U129.5 124.15,34.58 124.27,34.47 124.62,34.47 v1(124.83,34.68) 124.92,34.77 TR25.2
  BOTTOM w0.102: TR25.2 124.92,34.77 v1(124.83,34.68) 124,34.68 123.87,34.81 v4(123.82,34.81)
HDMI_LANE1_DN_C: length 13.4
  BOTTOM w0.102: 130.59,34.06 128.51,34.06 128.1,34.47 127.77,34.47 127.47,34.77 TR21.4 ; 130.59,34.06 v4(130.59,34.39) ; 130.59,34.06 136.77,34.06 137.16,33.67 138.18,33.67 C4274.2 R79725.1
HDMI_LANE1_DP: length 10.9
  TOP w0.102: TR25.3 124.95,34.09 v1(124.84,33.97) 124.6,34.21 124.24,34.21 124.13,34.1 U129.4 U129.7 122.38,34.1 122.29,34.19 121.85,34.19 121.37,34.67 118.67,34.67 118.33,34.32 HDMI1.4
  BOTTOM w0.102: TR25.3 124.95,34.09 v1(124.84,33.97) 124.49,33.97 v4(124.14,33.62)
HDMI_LANE1_DP_C: length 13.3
  BOTTOM w0.102: 137.42,33.42 138.19,33.42 C4273.2 R79728.1 ; 137.42,33.42 137.05,33.42 136.66,33.81 128.4,33.81 127.99,34.21 127.7,34.21 127.57,34.09 TR21.1 ; 137.42,33.42 v4(137.42,33.07)
HDMI_LANE1_IC_DN: length 3.6
  TOP w0.102: TR25.1 127.3,34.77 127.48,34.59 127.72,34.59 128.45,35.32 129.46,35.32 129.51,35.37 U127.26
HDMI_LANE1_IC_DP: length 4
  TOP w0.102: 128.11,34.62 128.56,35.06 129.48,35.06 129.57,34.97 U127.27 ; 128.11,34.62 v3(128.37,34.36) ; 128.11,34.62 127.83,34.33 127.42,34.33 127.17,34.09 TR25.4
HDMI_LANE2_DN: length 11.4
  TOP w0.102: HDMI1.9 118.28,36.82 118.63,36.47 119.19,36.47 119.95,35.71 121.47,35.71 122.35,36.59 U131.4 U131.7 124.12,36.59 124.26,36.45 124.48,36.45 v1(124.86,36.83) 125.36,36.83 125.58,37.05 TR26.2
  BOTTOM w0.102: v4(124.18,37.22) 124.47,37.22 v1(124.86,36.83) 125.09,37.05 TR26.2
HDMI_LANE2_DN_C: length 14.1
  BOTTOM w0.102: 135.62,37.29 131.17,37.29 129.78,35.89 128.94,35.89 127.99,36.84 127.78,36.84 127.57,37.05 TR22.4 ; 135.62,37.29 v4(135.62,37.62) ; 135.62,37.29 136.35,37.29 136.61,37.54 138.11,37.54 C4276.2 R79727.1
HDMI_LANE2_DP: length 11.2
  TOP w0.102: HDMI1.7 118.32,35.82 118.71,36.22 119.09,36.22 119.84,35.46 121.58,35.46 122.23,36.11 U131.5 U131.6 124.15,36.11 124.24,36.2 124.81,36.2 v1(124.89,36.12) 124.89,36.12 125.14,36.37 TR26.3
  BOTTOM w0.102: v4(124.11,36) 124.23,36.12 v1(124.89,36.12) 125.14,36.37 TR26.3
HDMI_LANE2_DP_C: length 14.1
  BOTTOM w0.102: 134.02,37.03 131.28,37.03 129.88,35.64 128.83,35.64 127.88,36.59 127.78,36.59 127.57,36.37 TR22.1 ; 134.02,37.03 136.46,37.03 136.71,37.29 138.26,37.29 C4275.2 R79729.1 ; 134.02,37.03 v4(134.02,36.7)
HDMI_LANE2_IC_DN: length 4
  TOP w0.102: 128.2,36.62 128,36.82 127.51,36.82 127.28,37.05 TR26.1 ; 128.2,36.62 128.73,36.09 128.74,36.08 129.48,36.08 129.57,36.17 U127.24 ; 128.2,36.62 v3(128.48,36.91)
HDMI_LANE2_IC_DP: length 3.6
  TOP w0.102: TR26.4 127.26,36.37 127.45,36.57 127.9,36.57 128.55,35.91 128.64,35.82 129.49,35.82 129.54,35.77 U127.25
HDMI_LANE3_DN: length 11.8
  TOP w0.102: HDMI1.12 118.37,38.32 118.71,37.97 118.81,37.97 119.47,38.63 121.55,38.63 122.07,38.11 U131.1 U131.10 124.12,38.11 124.91,38.89 v1(124.91,38.91) 124.92,38.91 125.22,39.21 TR27.2
  BOTTOM w0.102: TR27.2 125.22,39.21 124.92,38.91 v1(124.91,38.91) 124.69,38.91 v4(123.96,39.65)
HDMI_LANE3_DN_C: length 15.6
  BOTTOM w0.102: R79730.1 138.5,42.8 C4278.2 138.21,41.58 137.8,41.58 137.42,41.2 137.42,40.05 137.14,39.78 136.3,39.78 134.55,38.02 130.84,38.02 ; 130.84,38.02 v4(130.84,38.35) ; 130.84,38.02 129.37,38.02 128.39,39 127.78,39 127.57,39.21 TR23.4
HDMI_LANE3_DP: length 11.4
  TOP w0.102: TR27.3 125.27,38.53 v1(124.92,38.18) 124.72,38.18 124.18,37.63 U131.9 U131.2 122.19,37.63 121.45,38.38 119.57,38.38 118.91,37.72 118.71,37.72 118.32,37.32 HDMI1.10
  BOTTOM w0.102: TR27.3 125.27,38.53 v1(124.92,38.18) 124.44,38.18 124.18,38.44 v4(124.17,38.44)
HDMI_LANE3_DP_C: length 15.6
  BOTTOM w0.102: 136.84,39.52 137.25,39.52 137.68,39.95 137.68,41.09 137.91,41.33 138.16,41.33 C4277.2 R79731.1 ; 136.84,39.52 v4(136.84,39.17) ; 136.84,39.52 136.41,39.52 134.66,37.77 129.26,37.77 128.29,38.74 127.78,38.74 127.57,38.53 TR23.1
HDMI_LANE3_IC_DN: length 4.3
  TOP w0.102: U127.21 129.54,37.37 129.49,37.32 129.39,37.32 128.97,37.74 128.97,38.38 128.33,39.02 127.45,39.02 127.26,39.21 TR27.1
HDMI_LANE3_IC_DP: length 4.7
  TOP w0.102: 128.47,38.52 128.71,38.27 128.71,37.64 129.29,37.06 129.48,37.06 129.57,36.97 U127.22 ; 128.47,38.52 128.22,38.76 127.51,38.76 127.28,38.53 TR27.4 ; 128.47,38.52 v3(128.23,38.28)
HM_VCCP: length 2.1
  TOP w0.254: R653.1 109.23,49.56 v3(109,49.33) 108.62,49.71 G5.2
HM_VCCP_R: length 7
  TOP w0.203: 114.85,51.98 115.21,52.34 U109.95
  TOP w0.254: 114.85,51.98 113.66,50.78 v3(113.46,50.78) 113.34,50.91 111.7,50.91 111.29,50.5 C525.2 R653.2
HPOL_CON: length 58.5
  TOP w0.203: R223.2 153.79,56.2 153.75,56.16 v2(153.65,56.16) ; UHS1.1 173.4,77.99 172.94,77.53 C134.1 R221.1 168.46,77.53 Q57.1 168.34,77.62 v2(168.34,78.49) ; R225.2 159.88,59.93 v2(159.88,59.6) ; R220.2 v2(167.04,45.42)
  L4 w0.203: v2(168.34,78.49) 168.34,77.62 168.61,77.34 168.61,68.88 159.88,60.15 v2(159.88,59.6)
  BOTTOM w0.203: v2(153.65,56.16) 155.87,56.16 157.68,57.96 157.68,58.03 159.25,59.6 v2(159.88,59.6) 159.88,59.55 162.17,57.26 v4(162.17,55.7) 162.49,55.38 162.49,48.98 164.03,47.45 165.01,47.45 v2(167.04,45.42)
HPOR_CON: length 69.3
  TOP w0.203: R262.2 166.99,48.21 v2(167.06,48.29) ; v2(167.04,46.46) 166.68,46.81 R284.2 ; v2(172.12,80.45) C159.1 R281.1 169.82,80.45 168.85,79.48 Q57.2 v2(168.44,80.49) ; R627.2 157.22,60.85 v2(158.2,59.87)
  L4 w0.203: v2(158.2,59.87) 158.95,59.87 168.16,69.07 168.16,76.86 167.8,77.22 167.8,79.85 v2(168.44,80.49)
  BOTTOM w0.203: v2(167.04,46.46) 166.4,47.09 166.4,47.62 v2(167.06,48.29) 165.72,48.29 165.62,48.18 164.11,48.18 163.02,49.27 163.02,56.85 v4(162.74,57.14) 162.74,57.46 160.09,60.11 158.44,60.11 v2(158.2,59.87) ; UHS1.2 181,74.81 175.36,80.45 v2(172.12,80.45)
HPOUT-JD: length 24.7
  TOP w0.203: R267.1 166.89,52.7 167.5,53.31 167.5,59.28 166.15,60.63 166.15,63.88 v3(165.77,64.26) 165.77,65.66 171.67,71.56 173.33,71.56 UHS1.6
HPOUT-L: length 4.4
  TOP w0.203: U6.26 163.08,46.97 163.28,46.76 163.28,45.77 164.19,44.86 v3(164.21,44.86) 164.74,44.86 R220.1
HPOUT-R: length 3.6
  TOP w0.203: U6.27 163.15,47.37 164,46.52 v3(164,46.22) 164.73,46.22 R284.1
HSI_C_DN2: length 116.8
  TOP w0.102: v1(73.89,163.06) CPU2.F22 ; v2(102.93,214.12) R1609.2
  L3 w0.127: v2(102.93,214.12) 103.3,213.75 104.12,213.75 105.63,212.23 105.63,206.29 102.05,202.7 86.3,202.7 82.49,198.89 69.04,198.89 65.72,195.57 62.88,195.57 59.75,192.44 57.04,192.44 55.62,191.01 55.62,185.14 58.9,181.86 58.9,178.19 61.56,175.53 61.56,169.49 59.57,167.49 59.57,163.6 61.37,161.8 61.37,161.1 v2(61.67,160.81)
  BOTTOM w0.089: 70.93,163.84 70.95,163.84 70.96,163.83 71.64,163.83 71.82,163.65 73.3,163.65 v1(73.89,163.06)
  BOTTOM w0.102: 70.93,163.84 68.07,163.84 64.66,160.44 61.89,160.44 61.67,160.67 v2(61.67,160.81) ; v2(102.93,214.12) v4(102.93,215.16)
HSI_C_DP2: length 116.8
  TOP w0.102: CPU2.D22 72.86,162.74 v1(73.18,163.06) ; v2(102.93,213.11) R1608.2
  L3 w0.127: v2(60.8,160.83) 61.11,161.14 61.11,161.69 59.3,163.49 59.3,167.6 61.3,169.6 61.3,175.42 58.63,178.08 58.63,181.75 55.35,185.03 55.35,191.12 56.93,192.7 59.64,192.7 62.77,195.83 65.61,195.83 68.93,199.16 82.37,199.16 86.19,202.97 101.94,202.97 105.37,206.4 105.37,212.12 104.01,213.48 103.3,213.48 v2(102.93,213.11)
  BOTTOM w0.089: 70.93,163.63 70.95,163.63 70.96,163.64 71.56,163.64 71.74,163.46 73.22,163.46 73.35,163.33 73.35,163.22 v1(73.18,163.06)
  BOTTOM w0.102: 70.93,163.63 68.16,163.63 64.75,160.22 61.48,160.22 60.87,160.83 v2(60.8,160.83) ; v4(103.84,213.36) 103.59,213.11 v2(102.93,213.11)
HSI_LAN_DN1_R: length 5.1
  TOP w0.102: 32.76,18.34 32.76,17.81 33.09,17.48 33.09,16.52 33.59,16.03 33.89,16.03 33.93,15.99 U20.18 ; 32.76,18.34 v3(32.43,18.34) ; 32.76,18.34 32.76,19.02 C201.1
HSI_LAN_DN3: length 216.5
  TOP w0.102: C201.2 32.68,20.52 32.68,20.89 v2(32.32,21.26) ; CPU2.J24 v1(75.31,163.06)
  L4 w0.127: v2(32.32,21.26) 32.55,21.49 32.55,21.5 32.56,21.51 32.56,26.45 35.59,29.49 35.59,30.33 39.11,33.85 39.11,44.03 28.25,54.9 28.25,54.9 27.23,55.92 27.23,69.47 33.88,76.11 33.88,82.66 36.7,85.48 36.7,122.7 45.48,131.48 51.04,131.48 53.5,133.94 53.5,137.34 54.77,138.61 54.77,144.17 55.81,145.21 55.81,156.06 54.67,157.2 54.67,170.69 64.59,180.61 71.64,180.61 74.88,177.36 74.88,174.68 74.8,174.6 74.8,166.88 74.18,166.27 74.18,164.99 75.17,164.01 75.17,163.2 v1(75.31,163.06)
  BOTTOM w0.102: v4(33.17,20.42) 33.12,20.47 33.11,20.47 v2(32.32,21.26)
HSI_LAN_DP1_R: length 5.8
  TOP w0.102: v3(34.3,19) 33.93,19.37 C204.1 33.17,19.37 32.98,19.18 32.98,18.73 33.09,18.62 33.09,18.32 32.98,18.2 32.98,17.9 33.31,17.57 33.31,16.61 33.68,16.24 33.88,16.24 34.02,16.39 U20.17
HSI_LAN_DP3: length 216.6
  TOP w0.102: CPU2.G24 v1(74.6,163.06) ; v2(33.21,21.23) 33.1,21.23 32.9,21.03 32.9,20.47 33.12,20.26 C204.2
  L4 w0.127: v1(74.6,163.06) 74.9,163.35 74.9,163.9 73.92,164.88 73.92,166.38 74.53,166.99 74.53,174.71 74.62,174.79 74.62,177.25 71.53,180.34 64.7,180.34 54.94,170.58 54.94,157.31 56.08,156.17 56.08,145.1 55.04,144.06 55.04,138.5 53.77,137.23 53.77,133.82 51.15,131.21 50.92,131.21 50.92,131.21 50.81,131.21 50.8,131.21 45.59,131.21 36.96,122.58 36.96,85.37 34.14,82.55 34.14,76 27.5,69.35 27.5,56.03 28.52,55.01 28.52,55.01 39.38,44.14 39.38,43.76 39.52,43.62 39.52,43.24 39.38,43.11 39.38,42.73 39.52,42.59 39.52,42.21 39.38,42.07 39.38,41.69 39.52,41.55 39.52,41.17 39.38,41.03 39.38,35.95 39.52,35.82 39.52,35.44 39.38,35.3 39.38,33.74 35.86,30.22 35.86,29.38 32.82,26.34 32.82,24.72 32.96,24.59 32.96,24.21 32.82,24.07 32.82,23.69 32.96,23.55 32.96,23.17 32.82,23.03 32.82,22.65 32.96,22.51 32.96,22.13 32.82,22 32.82,21.62 v2(33.21,21.23)
  BOTTOM w0.102: v4(33.54,22.1) 33.21,21.77 v2(33.21,21.23)
HSO_C_DN2: length 89.1
  TOP w0.102: v2(56.95,169.09) 57.3,169.38 57.42,169.37 57.8,169.37 58.84,170.41 59.17,170.41 C56.2 ; v2(102.93,212.09) R1611.2
  L3 w0.127: v2(56.95,169.09) 56.68,169.37 56.45,169.37 56.04,169.77 56.04,171.19 57.01,172.16 57.01,182.1 54.44,184.66 54.44,191.69 56.36,193.61 59.22,193.61 62.42,196.8 65.3,196.8 68.56,200.06 81.92,200.06 85.78,203.92 98.55,203.92 98.55,203.93 101.24,206.62 101.24,211.15 101.8,211.71 102.55,211.71 v2(102.93,212.09)
  BOTTOM w0.102: v4(103.77,211.89) 103.56,212.09 v2(102.93,212.09)
HSO_C_DP2: length 89.3
  TOP w0.102: R1610.2 v2(102.85,211.07) ; v2(57.03,169.95) 57.32,169.6 57.37,169.6 57.43,169.59 57.71,169.59 58.75,170.63 59.17,170.63 C54.2
  L3 w0.127: v2(102.85,211.07) 102.48,211.44 101.91,211.44 101.51,211.04 101.51,206.51 99.35,204.34 98.66,203.66 85.9,203.66 82.03,199.79 68.67,199.79 65.41,196.53 62.53,196.53 59.33,193.34 56.47,193.34 54.71,191.58 54.71,184.77 57.27,182.21 57.27,181.71 57.41,181.57 57.41,181.19 57.27,181.06 57.27,180.68 57.41,180.54 57.41,180.16 57.27,180.02 57.27,179.64 57.41,179.5 57.41,179.12 57.27,178.98 57.27,178.41 57.41,178.27 57.41,177.89 57.27,177.75 57.27,177.37 57.41,177.24 57.41,176.85 57.27,176.72 57.27,176.34 57.41,176.2 57.41,175.82 57.27,175.68 57.27,174.94 57.41,174.8 57.41,174.42 57.27,174.28 57.27,173.9 57.41,173.77 57.41,173.39 57.27,173.25 57.27,172.05 56.31,171.08 56.31,169.88 56.56,169.63 56.71,169.63 v2(57.03,169.95)
  BOTTOM w0.102: v2(102.85,211.07) v4(102.85,210.03)
HSO_C_LAN_DN3: length 197.3
  TOP w0.102: U20.14 36.01,17.48 36.09,17.55 36.09,18.96 36.57,19.45 36.57,19.73 36.32,19.98 36.32,19.98 36.13,20.16 v2(35.92,20.16) ; C316.2 63.19,171.65 57.28,171.65 54.06,168.43 v2(53.86,168.43)
  L4 w0.127: v2(53.86,168.43) 53.17,167.74 53.17,154.33 54.03,153.46 54.03,145.72 52.9,144.59 52.9,139.23 51.96,138.29 51.96,135.56 49.45,133.05 44.85,133.05 33.98,122.18 33.98,117.7 33.4,117.12 33.4,102.17 35.13,100.44 35.13,93.89 33.88,92.64 33.49,92.64 31.96,91.11 31.96,89.36 31.17,88.57 31.17,78.36 30.56,77.76 30.56,75.16 25.68,70.27 25.68,55.2 29.78,51.1 29.78,51.08 37.27,43.59 37.27,43.21 37.41,43.07 37.41,42.69 37.27,42.55 37.27,42.17 37.41,42.03 37.41,41.65 37.27,41.51 37.27,41.13 37.41,41 37.41,40.61 37.27,40.48 37.27,35.89 37,35.62 37,35.43 36.73,35.16 36.54,35.16 36.27,34.89 36.27,34.69 36,34.42 35.8,34.42 35.53,34.16 35.53,33.96 35.27,33.69 35.07,33.69 31.48,30.1 31.48,29.91 31.21,29.64 31.02,29.64 30.75,29.37 30.75,29.17 30.48,28.9 30.28,28.9 29.79,28.41 29.79,19.94 30.4,19.34 30.6,19.34 30.74,19.47 31.12,19.47 31.26,19.34 31.64,19.34 31.77,19.47 32.16,19.47 32.29,19.34 32.67,19.34 32.81,19.47 33.19,19.47 33.33,19.34 35.59,19.34 35.94,19.69 35.94,20.14 v2(35.92,20.16)
  BOTTOM w0.102: v2(53.86,168.43) 54.32,168.88 v4(54.67,168.88)
HSO_C_LAN_DP3: length 196.9
  TOP w0.102: C315.2 63.18,171.87 62.49,171.87 ; 62.49,171.87 57.19,171.87 54.62,169.3 v2(53.85,169.3) ; 62.49,171.87 v3(62.49,172.24) ; v2(36.79,20.16) 36.79,19.36 36.3,18.87 36.3,17.58 36.41,17.47 U20.13
  L4 w0.127: v2(53.85,169.3) 52.91,168.36 52.91,154.21 53.77,153.35 53.77,145.83 52.64,144.7 52.64,139.34 51.7,138.4 51.7,135.67 49.34,133.31 44.74,133.31 44.58,133.16 33.71,122.29 33.71,117.81 33.13,117.23 33.13,102.06 34.86,100.32 34.86,94 33.77,92.91 33.38,92.91 31.69,91.22 31.69,89.47 30.9,88.68 30.9,78.47 30.3,77.87 30.3,75.27 25.42,70.38 25.42,55.09 29.51,50.99 29.51,50.97 37,43.48 37,36 29.52,28.52 29.52,19.83 30.29,19.07 35.7,19.07 v2(36.79,20.16)
HSO_LAN_DN3: length 13.1
  TOP w0.089: 70.01,165.19 70.19,165.19 70.68,164.7 71.16,164.7 71.17,164.71 71.35,164.71 71.63,165 CPU2.C27
  TOP w0.102: C316.1 64.67,171.54 65.78,171.54 66.23,171.09 66.23,170.43 ; 70.01,165.19 68.4,165.19 66.23,167.36 66.23,170.43 ; 66.23,170.43 v3(65.82,170.43)
HSO_LAN_DP3: length 13
  TOP w0.089: 70.01,165.41 70.02,165.41 70.04,165.39 70.09,165.39 70.1,165.38 70.27,165.38 70.76,164.9 71.08,164.9 CPU2.A27
  TOP w0.102: 66.12,171.5 65.87,171.75 64.8,171.75 64.43,172.12 C315.1 ; 66.12,171.5 66.44,171.18 66.44,170.88 66.55,170.77 66.55,170.46 66.44,170.35 66.44,170.05 66.55,169.93 66.55,169.63 66.44,169.52 66.44,169.21 66.55,169.1 66.55,168.8 66.44,168.68 66.44,167.45 66.72,167.17 66.88,167.17 67.09,166.96 67.09,166.8 67.31,166.58 67.47,166.58 67.68,166.37 67.68,166.21 67.9,166 68.05,166 68.27,165.78 68.27,165.62 68.49,165.41 70.01,165.41 ; 66.12,171.5 v3(66.4,171.78)
HUB_AVDD: length 18.1
  TOP w0.635: C401.1 C402.1 164.17,110.69 C400.2 C105.2 164.57,109.45 164.99,109.86 v2(165.29,109.86) ; C401.1 164.4,113.59 v2(165.26,113.59) ; C401.1 163.15,114.83 162.11,114.83 161.82,115.13 v2(161.82,115.27) 161.77,115.32 C397.2 160.76,115.27 R577.2 159.16,115.6 v3(158.17,115.6)
  BOTTOM w0.305: v2(165.29,109.86) 165.29,109.88 165.04,110.12 U6702.14 ; v2(165.26,113.59) 165.26,113.41 164.47,112.62 U6702.9 ; U6702.5 161.88,115.21 v2(161.82,115.27)
HUB_DVDD: length 34.5
  TOP w0.635: v2(158.15,107.44) 158.35,107.65 R79702.1 158.38,108.41 C93.2 159.49,113.72 R577.1 159.32,113.74 v2(158.48,114.58) 158.35,114.71 157.79,114.71 157.64,114.86 C94.2
  BOTTOM w0.254: R569.1 155.2,104.83 L3.1 155.25,104.34 155.66,103.94 157.26,103.94 R180.1
  BOTTOM w0.305: R158.2 154.52,111.4 153.98,110.87 v4(153.98,106.78) 153.98,106.52 154.65,105.89 R569.1 ; 157.84,113.49 158.21,113.12 U6702.28
  BOTTOM w0.381: v2(158.15,107.44) 158.35,107.24 R79703.1 159,107 159.98,106.02 U9.8
  BOTTOM w0.508: R79943.1 158.2,105.27 R180.1 159.11,105.79 U9.8
  BOTTOM w0.635: v2(158.48,114.58) 158,115.06 158,115.98 TC10.2 156.98,115.37 C393.1 157.12,114.5 157.84,113.78 157.84,113.49
HUB_DVDD_R: length 6.6
  BOTTOM w0.305: U6702.21 158.39,109.07 158.39,108.98 156.65,107.24 v4(156.65,106.27) 156.65,106.2 156.62,106.17 L3.2
HUB_PGANG: length 4.1
  BOTTOM w0.102: U6702.23 157.72,110.62 157.54,110.44 v4(157.51,110.44) 157.38,110.31 157.38,109.71 156.98,109.3 156.98,108.97 R155.1
HUB_PSELF: length 5.9
  BOTTOM w0.102: U6702.22 158.24,110.12 157.49,109.37 v4(157.49,109.09) 157.49,108.74 155.79,107.03 R156.2 R569.2
HUB_RESET#: length 6.6
  TOP w0.102: R79702.2 159.24,107.57 159.55,107.26 v3(159.81,107.26) 160.38,107.83 C101.1 160.89,108.84 R79701.2 161.55,107.87 v2(161.6,107.82)
  BOTTOM w0.102: v2(161.6,107.82) 161.62,107.82 161.88,108.07 U6702.17
HUB_RREF: length 3.9
  BOTTOM w0.305: v4(165.39,115.93) 164.63,115.93 R174.1 163.93,115.23 U6702.8
HUB_SDA: length 20.8
  BOTTOM w0.102: U6702.26 158.06,112.12 157.98,112.04 156.93,112.04 156.29,111.4 R158.1 156.12,111.53 155.79,111.86 153.78,111.86 153.47,111.55 153.47,105.52 v4(153.78,105.21) 153.78,104.37 154.36,103.79 154.82,103.79 155.17,103.44 155.42,103.44 157.23,101.63 159.06,101.63 159.42,101.98 U9.5
HUB_TEST/SCL: length 7
  BOTTOM w0.102: 159.98,103.25 160.76,103.25 160.98,103.47 160.98,106.18 160.79,106.37 v4(160.79,107.39) 160.79,107.7 161.38,108.28 U6702.18
HUB_VCC: length 2.7
  BOTTOM w0.305: U6702.27 158.2,112.62 158.13,112.55 v4(157.5,112.55) 157.13,112.92 R157.2
HUB_X1: length 5.3
  TOP w0.102: X3.3 167.47,112.74 C106.2 165.54,112.74 v2(165.26,112.46)
  BOTTOM w0.102: v4(165.96,112.99) 165.79,112.99 v2(165.26,112.46) 164.93,112.12 U6702.10
HUB_X2: length 7.2
  TOP w0.102: X3.1 168.79,111.86 168.79,111.89 168.68,112.01 167.11,112.01 166.73,111.63 166.73,111.59 C107.2 165.29,111.59 v2(165.29,111.6)
  BOTTOM w0.102: v4(166.05,111.25) 166,111.25 165.87,111.38 165.5,111.38 v2(165.29,111.6) 165.26,111.62 U6702.11
I2C0_SCL: length 9.7
  TOP w0.102: CPU2.AK6 v1(84.94,154.18)
  BOTTOM w0.089: 85.45,152.96 85.34,153.07 85.34,153.78 v1(84.94,154.18)
  BOTTOM w0.102: 85.45,152.96 85.66,152.76 85.66,149.61 86.84,148.42 87.92,148.42 R1792.1 88.44,148.17 v4(89.03,148.77)
I2C1_SCL: length 7.2
  TOP w0.102: CPU2.AF6 83.91,154.86 v1(84.01,154.86)
  BOTTOM w0.089: v1(84.01,154.86) 84.35,154.52 84.35,152.27 84.39,152.24 84.39,150.87
  BOTTOM w0.102: 84.39,150.87 84.39,150.23 v4(84.21,150.06) 84.21,149.74 84.93,149.01 R1793.1
I2C2_SCL: length 7
  TOP w0.102: v1(84.01,156.31) 83.95,156.31 CPU2.AF9
  BOTTOM w0.089: v1(84.01,156.31) 84.54,155.77 84.54,153.16 84.87,152.84 v4(84.87,152.47)
  BOTTOM w0.102: R1794.1 84.62,151.14 84.62,152.22 v4(84.87,152.47)
I2C4_SCL: length 11.6
  TOP w0.089: 81.97,150.98 81.97,152 82.03,152.05 CPU2.AC1
  TOP w0.102: 81.97,150.98 82.05,150.9 82.05,148.31 84.34,146.03 84.34,144.63 v3(84.54,144.42) 84.54,144.37 85,143.92 85,142.94 R1796.1
I2C5_SCL: length 12.5
  TOP w0.089: CPU2.AB2 81.54,150.99
  TOP w0.102: 81.54,150.99 81.54,150.99 81.54,150.82 81.59,150.77 81.59,146.91 82.89,145.62 82.89,142.65 v3(83.1,142.43) 83.88,141.66 83.88,141.6 84.03,141.45 R1797.1
I2C6_SCL: length 12.6
  TOP w0.089: 81.08,151.12 81.06,151.15 CPU2.AA1
  TOP w0.102: R1798.1 v3(81.95,141.35) 81.95,141.45 81.2,142.2 81.2,144.01 81.09,144.11 81.09,151.11 81.08,151.12
ICH_RSMRST_N_R: length 3.7
  TOP w0.102: U109.82 114.52,57.54 113.87,56.9 v3(113.87,56.68) 113.09,56.68 R1592.2
ICLKICOMP: length 3.7
  TOP w0.102: CPU2.P20 77.8,161.71 v1(78.16,162.07)
  BOTTOM w0.102: R1242.2 76.41,160.96 v4(76.59,161.14) 76.79,161.34 77.61,161.34 78.16,161.89 v1(78.16,162.07)
ICLKRCOMP: length 3.9
  TOP w0.102: v1(77.45,162.07) 77.09,161.71 CPU2.N20
  BOTTOM w0.102: v1(77.45,162.07) 77.45,162.3 77.05,162.7 76.53,162.7 76.18,163.05 v4(76.03,163.05) 76.03,162.8 R524.2
IMS: length 135.1
  TOP w0.102: R79951.1 122.03,70.14 122.03,71.41 v3(121.89,71.55) 121.97,71.63 121.97,74.4 121.18,75.18 119.88,75.18 v1(119.79,75.27) ; v2(43.65,106.73) 43.42,106.5 LVDS1.4
  L3 w0.127: v1(41.97,116.79) 43.05,115.71 43.05,107.33 v2(43.65,106.73) 42.65,105.73 42.65,80.23 43.24,79.64 48.73,79.64 49.47,78.91 49.86,78.91 50.75,78.02 55.3,78.02 57.93,75.39 86.39,75.39 87.64,76.63 89.64,76.63 93.33,72.94 98.88,72.94 103.18,77.24 104.91,77.24 v1(105.87,78.21)
  L4 w0.127: v1(105.87,78.21) 105.98,78.21 107.26,76.92 112.9,76.92 113.03,77.06 117.16,77.06 118.88,75.34 119.73,75.34 v1(119.79,75.27)
  BOTTOM w0.102: R79758.1 R79661.2 43.56,119.47 43.56,118.38 v1(41.97,116.79)
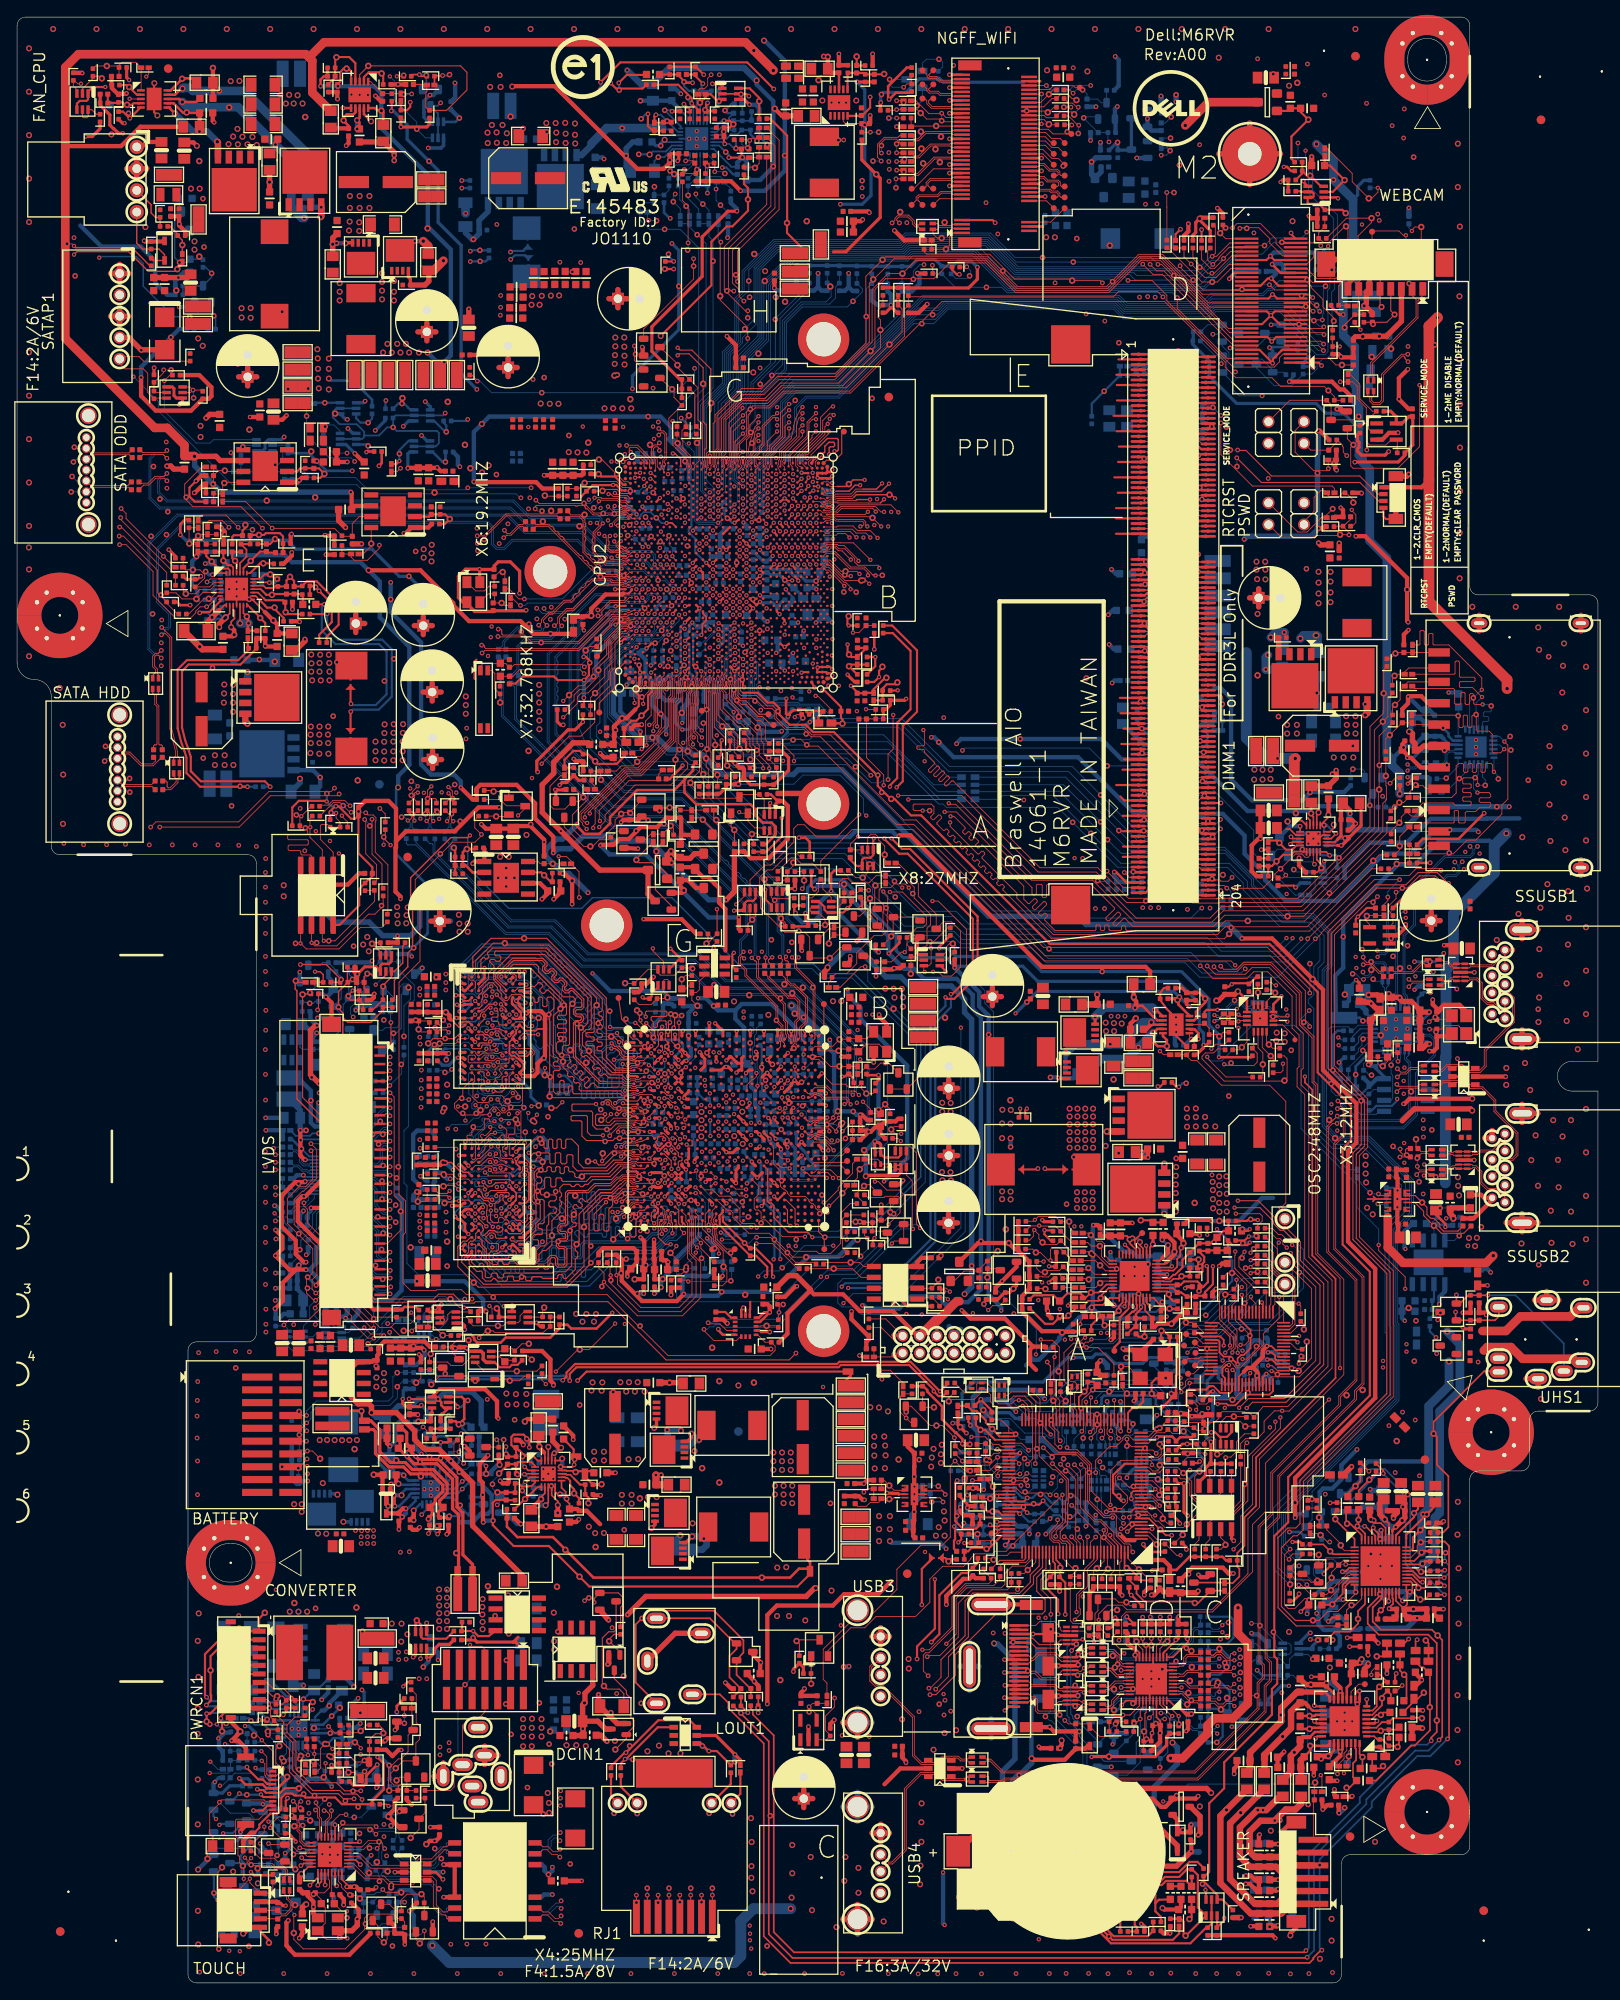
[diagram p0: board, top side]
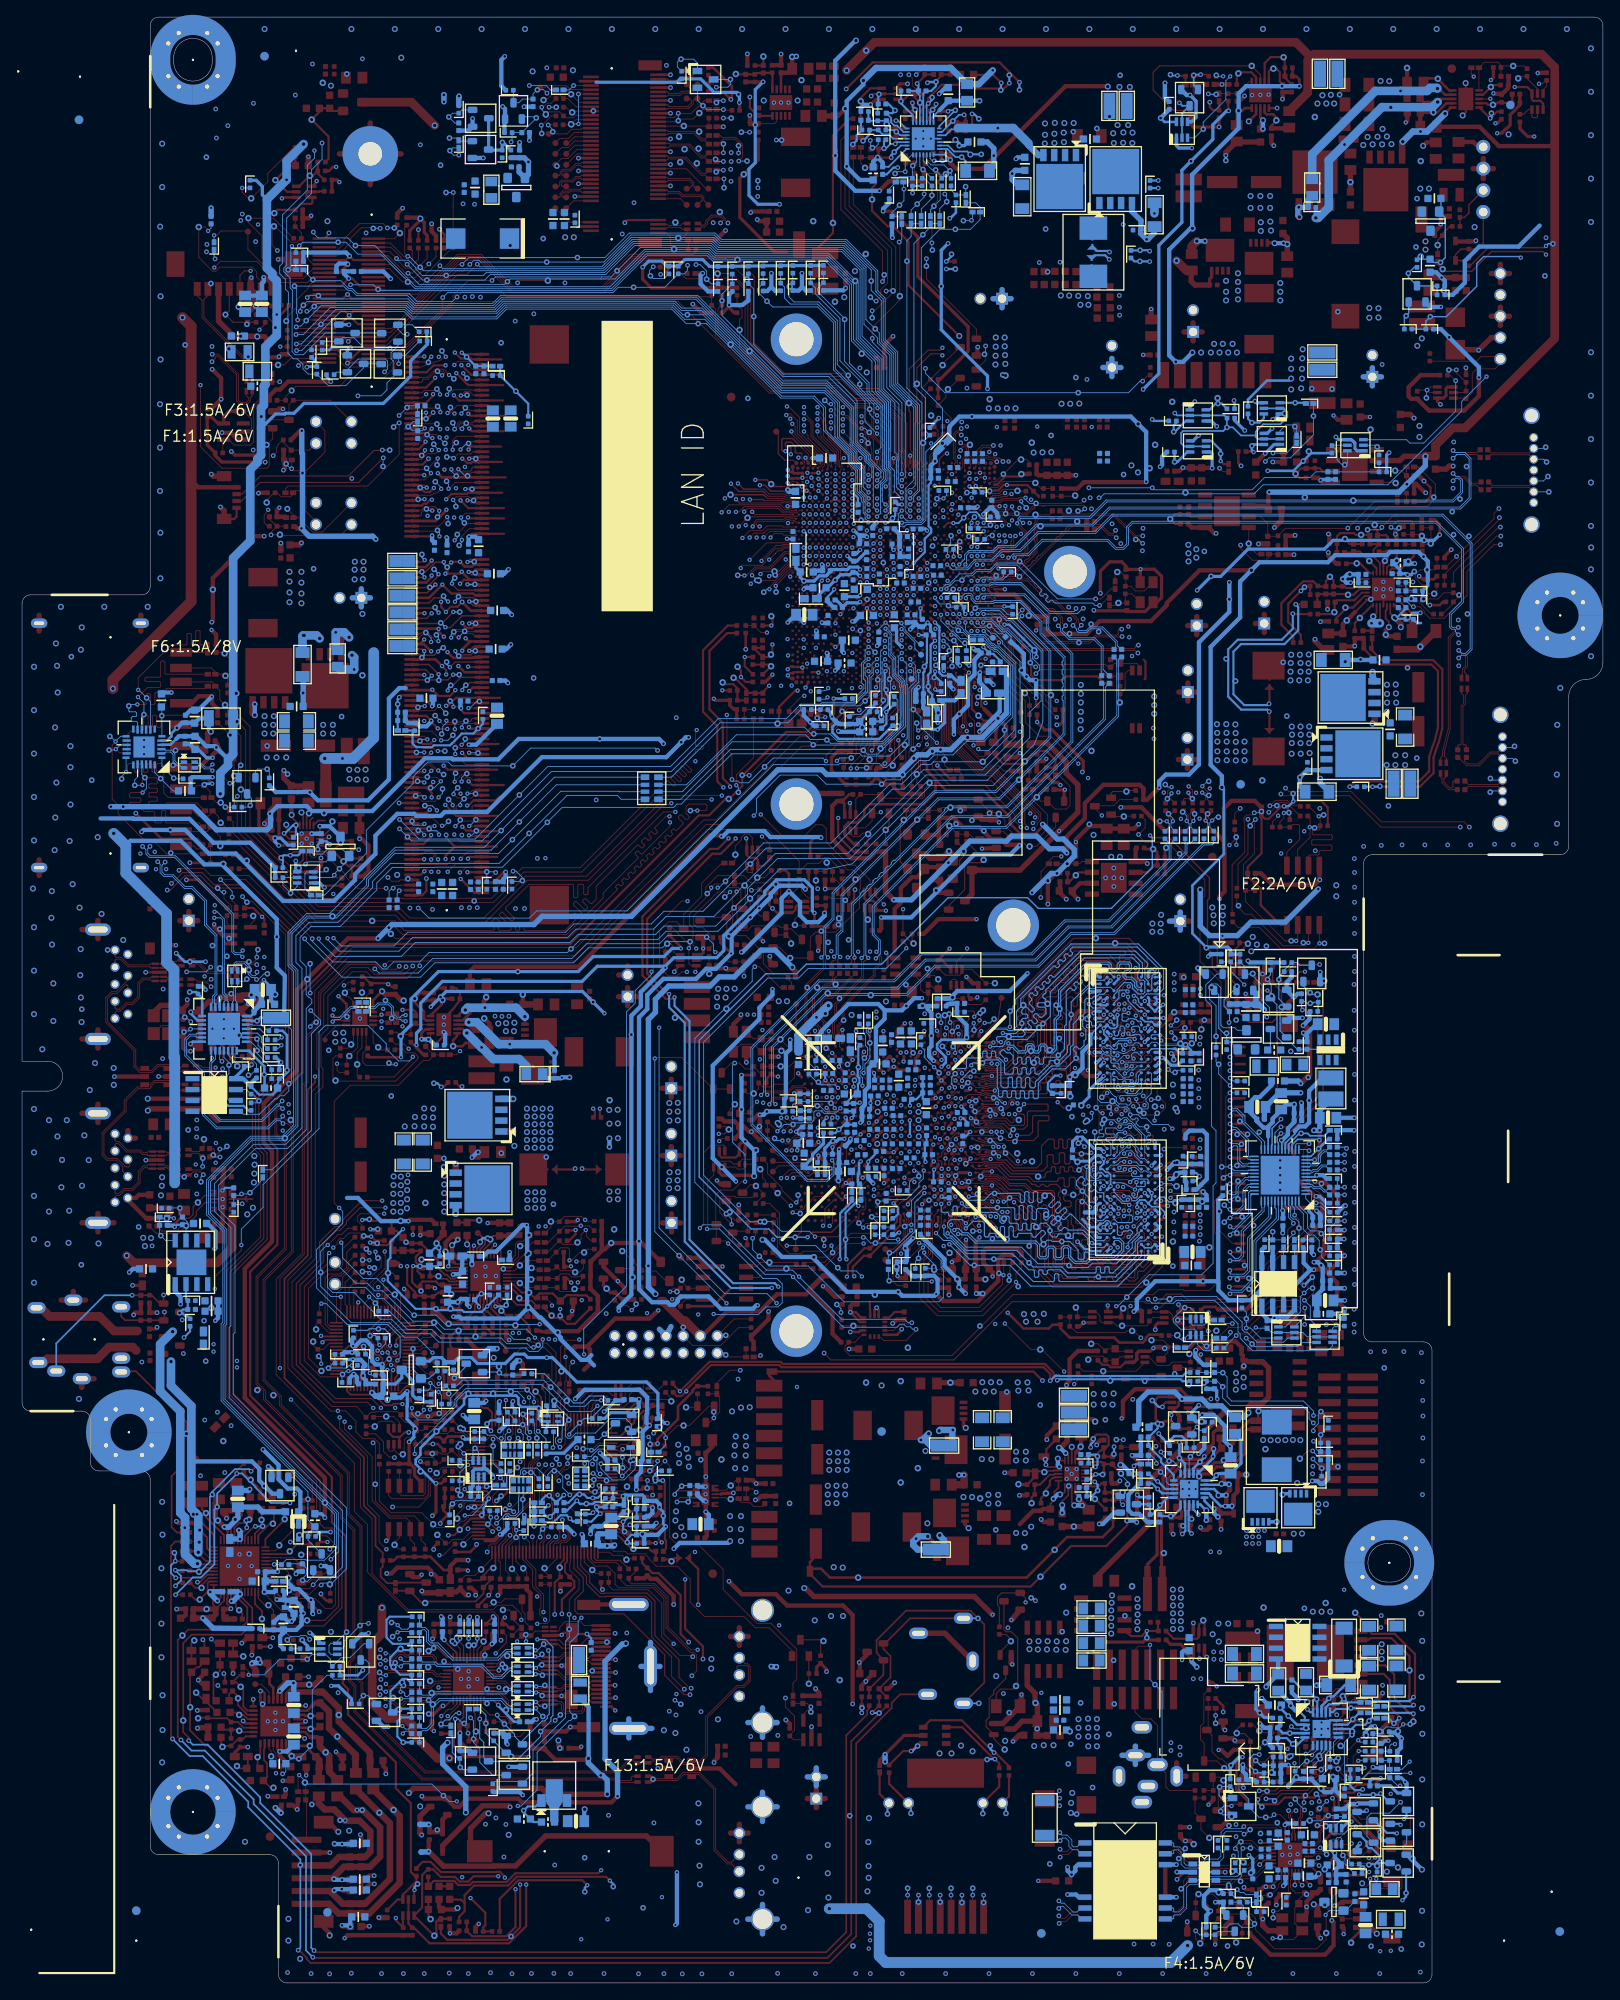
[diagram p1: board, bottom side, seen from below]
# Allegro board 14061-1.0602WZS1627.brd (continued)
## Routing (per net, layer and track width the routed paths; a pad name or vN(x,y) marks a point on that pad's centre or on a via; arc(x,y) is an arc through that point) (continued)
INIT_3V: length 5.8
  TOP w0.102: LPC1.2 101.65,77.69 R324.2
  BOTTOM w0.102: v4(102.65,75.77) 102.72,75.7 LPC1.2
INT_SERIRQ_CPU: length 25.6
  TOP w0.089: 78.56,150.63 78.56,150.91 78.73,151.09 78.73,151.63 78.63,151.73 CPU2.T2
  TOP w0.102: U35.3 87.43,138.5 R79688.1 84.84,139.05 Q1253.3 84.39,138.61 79.6,138.61 79.38,138.82 79.38,139.7 78.8,140.28 v3(78.8,140.41) 78.8,140.72 79.85,141.77 79.85,143.93 79.3,144.48 78.96,144.48 78.62,144.81 78.62,145.36 78.56,145.43 78.56,150.63
INT_SERIRQ_OE: length 5.2
  TOP w0.102: U35.5 88.08,134.49 87.7,134.11 87.03,134.11 86.62,134.52 86.09,134.52 v3(85.99,134.42) 85.96,134.39 85.96,133.78 86.19,133.55 R646.1 85.08,133.24 R645.2
INT_TP#: length 27.3
  TOP w0.089: v1(84.94,179.13) 84.54,178.73 84.54,178.25 84.66,178.14 84.66,177.65 84.76,177.55 84.76,177.31 84.46,177.01 CPU2.AH51
  BOTTOM w0.102: R1561.2 R1807.1 91.9,198.23 91.9,197.9 88.74,194.73 v4(88.74,194.63) 88.74,189.7 86.13,187.09 86.13,186.1 84.49,184.46 84.49,179.63 84.94,179.17 v1(84.94,179.13)
IO_SMI_N: length 196
  TOP w0.102: CPU2.AM10 v1(85.93,156.31) ; v2(101.93,140.79) 101.93,143.75 102.51,144.34 102.51,147.94 102.53,147.96 v1(102.53,148.35) ; v1(90.91,142.95) 90.91,143.59 89.48,145.02 R642.2 ; R79946.1 143.19,63.11 143.76,63.68 145.13,63.68 145.93,64.48 145.93,65.71 147.15,66.93 v1(148.04,66.93) 148.06,66.9 148.85,66.9 153.88,71.94 153.88,82.21 151.16,84.93 151.16,104.19 150.27,105.08 150.27,106.78 150.5,107.01 150.5,111.1 149.69,111.91 149.69,115.64 146.55,118.78 144.51,118.78 143.73,118 140.25,118 v2(139.28,118.97) ; v1(143.31,81.41) 142.86,80.95 142.86,80.59 142.85,80.59 142.85,79.94 142.17,79.26 U4101.13
  L3 w0.127: v2(101.93,140.79) 101.98,140.84 108.38,140.84 125.01,124.21 133.93,124.21 138.42,119.72 138.53,119.72 v2(139.28,118.97)
  L4 w0.127: v1(102.53,148.35) 101.03,149.85 91.9,149.85 90.92,150.83 90.38,150.83 89.83,151.37 89.83,151.38 89.57,151.64 89.57,151.64 86.62,154.58 86.62,155.63 v1(85.93,156.31) ; v1(148.04,66.93) 148.14,67.03 148.14,70.41 149.13,71.4 149.13,78.11 145.83,81.41 v1(143.31,81.41)
  BOTTOM w0.102: R510.1 87.65,150.27 86.48,151.44 86.48,151.84 86.59,151.95 86.75,152.1 86.75,154.41 86.34,154.82 86.34,155.91 v1(85.93,156.31) 85.81,156.31 v4(85.18,155.68) ; v2(101.93,140.79) 101.9,140.79 101.72,140.61 101.22,140.61 101.02,140.42 99.98,140.42 v4(98.11,142.29) 97.09,143.31 91.27,143.31 v1(90.91,142.95)
IO_SMI_R: length 18.1
  TOP w0.102: R79946.2 143.19,56.39 141.82,55.02 138.24,55.02 v3(136.89,53.66) 136.51,53.29 134.31,53.29 133.57,54.03 133.24,54.03 132.75,54.52 132.75,54.66 132.27,55.14 U109.9
ISEN1: length 5.2
  BOTTOM w0.254: U120.17 32.43,32.23 32.07,32.59 30.94,32.59 v4(30.31,33.22) 29.9,32.82 R79712.2
ISEN2: length 5.7
  BOTTOM w0.254: U120.16 31.6,31.67 31.22,32.05 29.6,32.05 v4(29.5,32.16) 26.66,32.16 R53.2
ISEN3: length 3.2
  BOTTOM w0.254: U120.14 29.89,30.22 v4(29.27,30.84) 28.51,31.6 R79713.2
ISEN4: length 5.1
  BOTTOM w0.254: U120.13 29.8,29.72 29.79,29.71 29.4,29.71 28.91,30.2 27.82,30.2 v4(27.36,30.66) 27.36,30.71 27.11,30.96 R79715.2
ISET: length 6
  TOP w0.127: U127.34 132.14,31.68 131.99,31.52 131.99,29.51 v3(131.88,29.41) 131.84,29.37 R79741.1 R79742.2
ISP_CLK1: length 24.1
  TOP w0.102: v2(31.22,76.99) 31.83,77.6 34.16,77.6 35.05,78.49 35.09,78.49 35.36,78.77 35.36,78.82 35.67,79.12 38.06,79.12 39.12,78.05 39.12,77.37 41.05,75.44 v2(41.74,75.44)
  BOTTOM w0.102: Q7.6 31.63,76.58 v2(31.22,76.99) 31.08,76.85 R79679.2 ; Q7.3 35.2,74.94 35.69,74.45 40.75,74.45 v4(41.06,74.76) 41.74,75.44 v2(41.74,75.44)
ISP_DAT1: length 18.2
  TOP w0.102: v2(34.88,78.97) 34.88,79.1 35.64,79.86 38.23,79.86 41.47,76.62 v2(41.73,76.62)
  BOTTOM w0.102: Q4.3 40.07,75.45 41.24,76.62 v2(41.73,76.62) 41.72,76.62 v4(41.72,77.71) 41.72,78.46 R79669.2 ; Q4.6 34.86,77.99 34.86,78.94 v2(34.88,78.97)
ISW: length 5.4
  BOTTOM w0.254: C10.1 36.29,35.45 35.06,34.21 R79630.2 34.53,34.21 v4(33.51,33.2) 33.43,33.11 U120.19
ISW_1:
  vias: v4(40.42,41.15)
JACK_PSID: length 34.7
  TOP w0.102: DCIN2.11 54.75,31.7 53.93,30.89 52.88,30.89 52.12,30.13 DCIN1.3 51.14,24.54 51.14,22.94 50.72,22.52 L22.1 ; v1(53,39.55) 53.17,39.38 54.38,39.38 54.75,39.01 DCIN2.4
  BOTTOM w0.102: v1(53,39.55) 53,35.48 v4(52.42,34.9) 51.6,34.07 51.6,26.06 DCIN1.3
JDREF: length 4.8
  TOP w0.203: 163.33,50.81 163.09,50.57 U6.35
  TOP w0.254: 163.33,50.81 163.36,50.84 163.36,52.12 v3(164.21,52.98) 165.06,53.82 R268.1
JENK#: length 2.1
  TOP w0.102: TP4125.1 138.45,72.84 U4101.28
JTAG_TCK_VGA: length 27.4
  TOP w0.102: GPU1.L3 78.93,89.27 78.93,85.38 80,84.3 80,80.19 77.87,78.06 72.59,78.06 68.68,81.96 v1(68.68,82) 68.68,83.05 68.05,83.68 R963.1
  BOTTOM w0.102: v4(68.43,81.48) 68.43,81.75 v1(68.68,82)
JTAG_TDI_VGA: length 8
  TOP w0.102: GPU1.L5 78.98,90.42 78.98,89.65 79.13,89.32 79.13,86.48 v1(79.57,86.05)
  BOTTOM w0.102: v1(79.57,86.05) 80.09,85.52 v4(80.09,84.78) 80.45,84.42 80.45,83.61 R79965.1
JTAG_TDO_VGA: length 24.1
  TOP w0.102: R1895.1 70.12,82.83 v1(70.15,82.8) 70.26,82.69 70.26,81.75 72.99,79.02 77.47,79.02 78.98,80.53 78.98,84.25 78.45,84.78 78.45,88.88 78.27,89.06 78.27,89.77 77.8,90.24 GPU1.K4
  BOTTOM w0.102: v1(70.15,82.8) 70.45,82.8 v4(70.68,83.03)
JTAG_TMS_VGA: length 24.5
  TOP w0.102: R398.1 69.08,84.09 69.4,83.77 69.4,82.86 v1(69.47,82.79) 69.47,81.86 72.79,78.54 77.67,78.54 79.46,80.33 79.46,84.51 78.65,85.32 78.65,89.15 GPU1.L1
  BOTTOM w0.102: v4(69.49,82.21) 69.47,82.24 v1(69.47,82.79)
JTAG_TRST#_VGA: length 10.6
  TOP w0.102: GPU1.L6 78.11,91.11 v1(78.07,91.11)
  L3 w0.127: v1(79.43,85.45) 77.59,87.29 77.59,90.63 v1(78.07,91.11)
  BOTTOM w0.102: v1(79.43,85.45) 79.37,85.39 79.37,85.17 78.31,84.12 v4(78.31,83.77) 78.48,83.61 R1893.1
KBCLK: length 5.4
  TOP w0.102: U109.78 117.11,59.14 117.17,59.08 117.64,59.08 v2(118.17,59.61)
  BOTTOM w0.102: RN8.3 118.75,59.28 118.42,59.61 v2(118.17,59.61) 118.08,59.61 117.55,59.08 116.91,59.08 v4(116.61,58.78)
KBRST: length 5.3
  TOP w0.102: U109.42 126.41,64.93 126.3,64.82 126.3,64.47 125.66,63.84 v2(125.66,63.73)
  BOTTOM w0.102: R330.1 125.71,63.67 125.66,63.72 v2(125.66,63.73) 125.66,63.87 126.08,64.28 126.08,64.99 v4(126.41,65.32)
KDAT: length 5.5
  TOP w0.102: v2(117.35,59.54) 117.35,59.54 U109.77
  BOTTOM w0.102: v2(117.35,59.54) 117.72,59.92 117.72,61.18 v4(117.89,61.35) 118.23,61.35 118.7,60.88 118.7,60.36 RN8.4
LAD0_FWH0: length 214.8
  TOP w0.089: CPU2.M3 76.68,152.99 76.4,152.71 76.4,152.43 76.48,152.35 76.48,150.69
  TOP w0.102: v1(66.66,135) 66.66,135.03 66.18,135.51 66.18,135.69 65.78,136.08 65.78,136.86 71.08,142.15 72.64,142.15 75.1,144.61 75.1,145.89 76.21,147 76.21,150.42 76.48,150.69 ; U109.38 v2(128.01,64.59) ; v1(144.35,85.43) 144.35,85.43 R79956.2
  L3 w0.127: LPC1.5 108.49,74.56 108.49,76.12 109.51,77.14 112.22,77.14 112.48,77.39 119.49,77.39 119.73,77.15 122.7,77.15 127.24,81.69 133.43,81.69 134.04,82.3 135.46,82.3 136.28,83.12 141.85,83.12 142.73,84 143.06,84 144.15,85.09 144.15,85.24 v1(144.35,85.43) 144.35,85.64 144.81,86.11 144.81,87.6 145.73,88.52 145.73,103.48 143.5,105.71 143.5,105.79 143.5,108.36 142.74,109.12 142.74,109.68 141.15,111.27 141.15,113.8 138.11,116.84 137.53,116.84 136.83,117.53 135.63,118.74 135.62,118.74 133.07,121.29 122.84,121.29 119.05,125.07 106.37,125.07 105.91,125.53 99.19,125.53 98.93,125.26 98.5,125.26 97.57,126.19 94.93,126.19 94.47,125.73 88.41,125.73 77.4,136.75 68.34,136.75 67.62,136.02 67.62,135.97 v1(66.66,135)
  L4 w0.127: v2(128.01,64.59) 128.01,64.36 128.44,63.92 128.44,63.53 127.92,63.01 124.93,63.01 122.07,65.86 120.36,65.86 114.49,71.73 109.61,71.73 LPC1.5
  BOTTOM w0.102: v1(144.35,85.43) 144.71,85.8 v4(144.71,85.88) ; v2(128.01,64.59) 128.46,64.14 128.46,63.51 128.52,63.45 RN5.4
LAD0_FWH0_EC: length 13.1
  TOP w0.102: U4101.62 148.91,76.44 149.54,77.06 149.54,82.5 149.1,82.93 147.78,82.93 147,83.72 147,85.47 146.26,86.21 R79956.1
LAD1_FWH1: length 209.7
  TOP w0.089: 76.68,150.52 CPU2.M2
  TOP w0.102: R79955.2 144.94,85.14 v1(144.36,84.56) ; v1(66.71,135.71) 66.49,135.71 66.01,136.19 66.01,136.76 71.17,141.93 72.74,141.93 76.41,145.6 76.41,150.25 76.68,150.52 ; v2(127.97,63.73) 127.97,63.81 127.55,64.24 127.55,64.78 127.61,64.84 U109.39
  L3 w0.127: v1(66.71,135.71) 66.88,135.71 68.17,137 79.21,137 90.23,125.98 94.22,125.98 94.67,126.44 99.02,126.44 99.69,125.78 106.01,125.78 106.47,125.32 119.16,125.32 122.69,121.79 132.92,121.79 135.72,118.99 135.73,118.99 136.94,117.78 137.63,117.09 138.21,117.09 141.4,113.91 141.4,111.38 143,109.78 143,109.22 143.75,108.46 143.75,106.63 143.75,105.83 145.98,103.61 145.98,88.39 145.11,87.52 145.11,85.99 144.91,85.8 144.91,85.12 v1(144.36,84.56) 144.2,84.56 143.38,83.74 142.83,83.74 141.95,82.87 136.39,82.87 135.56,82.04 134.15,82.04 133.54,81.43 127.34,81.43 122.81,76.9 119.53,76.9 119.29,77.14 112.73,77.14 112.48,76.89 109.61,76.89 108.78,76.05 108.78,74.55 LPC1.7
  L4 w0.127: LPC1.7 111.17,72.16 114.43,72.16 120.48,66.12 122.36,66.12 125.21,63.26 127.5,63.26 v2(127.97,63.73)
  BOTTOM w0.102: RN5.3 127.87,63.62 v2(127.97,63.73) ; v4(145.14,84.58) 144.38,84.58 v1(144.36,84.56)
LAD1_FWH1_EC: length 11.1
  TOP w0.102: R79955.1 146.77,84.39 146.77,83.62 147.69,82.7 148.69,82.7 149.26,82.13 149.26,77.14 148.95,76.84 U4101.63
LAD2_FWH2: length 203
  TOP w0.089: 76.9,150.42 76.9,152.36 76.98,152.45 76.98,152.74 CPU2.N3
  TOP w0.102: v1(144.35,83.75) 144.72,84.12 R79954.2 ; v2(126.96,63.74) 127.26,64.05 127.26,64.78 127.21,64.84 U109.40 ; v1(66.44,136.37) 66.44,136.87 71.27,141.7 72.83,141.7 76.61,145.48 76.61,150.14 76.9,150.42
  L3 w0.127: v1(66.44,136.37) 67.18,136.37 68.07,137.25 79.34,137.25 90.36,126.24 94.09,126.24 94.55,126.7 99.31,126.7 99.97,126.03 106.12,126.03 106.58,125.58 119.26,125.58 122.79,122.05 133.03,122.05 135.83,119.25 135.84,119.25 137.03,118.05 137.74,117.35 138.32,117.35 141.66,114.01 141.66,111.49 143.25,109.89 143.25,109.33 144.01,108.57 144.01,106.53 144.01,105.96 146.24,103.73 146.24,88.27 145.36,87.39 145.36,85.89 145.17,85.7 145.17,84.57 v1(144.35,83.75) 143.83,83.75 143.57,83.49 142.94,83.49 142.06,82.61 136.49,82.61 135.67,81.79 134.25,81.79 133.64,81.18 127.45,81.18 122.92,76.64 119.25,76.64 119.01,76.89 113.19,76.89 112.5,76.2 112.5,74.66 112.24,74.4 LPC1.9
  L4 w0.127: v2(126.96,63.74) 126.14,64.56 126.14,64.72 124.42,66.45 120.88,66.45 120.85,66.42 120.56,66.42 114.36,72.62 112.72,72.62 LPC1.9
  BOTTOM w0.102: v1(144.35,83.75) 143.88,83.75 v4(143.77,83.64) ; RN5.2 127.37,63.33 v2(126.96,63.74)
LAD2_FWH2_EC: length 7.8
  TOP w0.102: U4101.64 148.21,80.65 147.48,81.38 147.48,82.58 146.02,84.04 R79954.1
LAD3_FWH3: length 199.2
  TOP w0.089: CPU2.N1 77.17,150.38
  TOP w0.102: v1(144.36,83.04) 144.43,83.11 R79700.2 ; 77.17,150.38 76.82,150.03 76.82,145.36 72.93,141.47 71.4,141.47 67.01,137.08 v1(67.01,136.83) ; U109.41 v2(126.81,64.59)
  L3 w0.127: LPC1.11 112.76,74.58 112.76,76.1 113.29,76.63 118.75,76.63 119.21,76.17 122.17,76.17 122.8,76.17 127.55,80.92 133.75,80.92 134.36,81.53 136.07,81.53 136.73,82.19 142,82.19 142.84,83.04 v1(144.36,83.04) 145.42,84.11 145.42,85.59 145.61,85.78 145.61,87.26 146.49,88.14 146.49,103.86 144.26,106.09 144.26,106.11 144.26,108.67 143.5,109.43 143.5,110 141.91,111.59 141.91,114.12 138.42,117.6 137.84,117.6 137.07,118.37 135.94,119.5 135.94,119.5 133.13,122.3 122.9,122.3 119.37,125.83 106.68,125.83 106.23,126.29 100.08,126.29 99.42,126.95 94.42,126.95 93.96,126.49 90.48,126.49 79.47,137.51 67.89,137.51 67.22,136.83 v1(67.01,136.83)
  L4 w0.127: LPC1.11 113.96,73.7 120.96,66.7 124.54,66.7 124.77,66.47 124.93,66.47 v2(126.81,64.59)
  BOTTOM w0.102: v1(144.36,83.04) 144.55,83.24 v4(145.17,83.24) ; v2(126.81,64.59) 126.35,64.14 126.35,63.59 126.72,63.22 RN5.1
LAD3_FWH3_EC: length 5.2
  TOP w0.102: U4101.1 146.97,79.18 147.2,79.41 147.2,81.93 R79700.1
LAN_DISABLE_C: length 5.6
  BOTTOM w0.102: R739.2 40.53,9.42 R374.1 41.61,9.44 R704.1 42.24,10.06 43.15,10.06 R378.1 43.53,11.19 v4(43.8,11.46)
LAN_DISABLE_N: length 153.6
  TOP w0.102: v2(42.8,10.92) 42.91,10.81 42.91,10.81 43.13,10.59 44.91,10.59 44.91,10.59 v3(44.96,10.59) ; U109.58 120.01,63.96 121.89,62.08 124.03,62.08 125.48,60.62 125.48,56.45 127.28,54.66 127.82,54.66 128.03,54.88 128.39,54.88 128.65,54.62 128.65,54.27 128.63,54.25 128.63,52.3 129.57,51.36 130.16,51.36 130.36,51.16 130.36,50.62 v2(130.56,50.42)
  L3 w0.127: v2(130.56,50.42) 130.28,50.14 129.01,50.14 124.58,45.7 123.68,45.7 122.53,44.55 118.02,44.55 116.19,42.72 113.39,42.72 107.09,36.42 107.09,35.74 106.23,34.88 106.23,33.67 108.02,31.88 109.17,31.88 v2(109.26,31.8)
  L4 w0.127: v2(109.26,31.8) 109.26,30.87 104.89,26.5 104.87,26.5 104.85,26.52 103.8,26.52 102.84,25.55 94.94,25.55 93.19,27.3 81.44,27.3 80.21,28.54 71.71,28.54 71.16,29.08 64.57,29.08 60.89,32.77 49.97,32.77 48.36,31.16 48.36,30.15 45.99,27.77 45.99,23.75 43.91,21.67 43.91,14.21 42.8,13.1 v2(42.8,10.92)
  BOTTOM w0.102: R374.2 41.78,10.33 42.02,10.57 42.44,10.57 v2(42.8,10.92)
LAN_DISABLE_N_1: length 9.7
  BOTTOM w0.102: C558.1 R704.2 42.1,9.04 Q74.B 41.75,7.94 40.77,6.95 v4(40.77,6.91) 40.77,6.78 41.04,6.5 42.27,6.5 42.68,6.91 43.6,6.91 43.99,6.52 R701.1
LAN_DISABLE_N_2: length 8.2
  TOP w0.102: Q75.B 46.67,5.07 v3(47.12,4.62) 47.66,5.16 v2(47.66,6.1)
  BOTTOM w0.102: v2(47.66,6.1) 47.19,5.63 R702.2 R701.2 44.99,6.03 Q74.C
LAN_DISABLE_N_3: length 9.3
  TOP w0.102: Q76.C 43.57,9.2 44.35,8.42 R706.1 44.98,9.03 44.89,9.12 44.89,9.64 45.64,10.39 v3(47.32,10.39) 47.65,10.06 R705.2 47.65,7.9 Q75.C
LAN_DISABLE_N_4: length 23.9
  TOP w0.102: v1(32.44,7.95) 32.38,7.89 v3(32.38,5.84) 32.38,5.09 33.48,3.99 38.41,3.99 40.66,6.24 40.66,7.57 41.14,8.05 44.04,8.05 44.56,7.53 R706.2 45.35,7.17 C559.1
  BOTTOM w0.102: v1(32.44,7.95) 32.44,8.05 32.04,8.46 Q39.G 30.11,8.46 PC163.2
LAN_DISABLE_V3: length 4.4
  TOP w0.102: Q76.B 42.21,6.7 R707.1 42.21,5.38 42.85,4.74 v3(42.92,4.74) 43.31,5.13 C561.1
LAN_LEDACT_R#: length 5.8
  TOP w0.254: UR5.2 83.52,23.29 RJ1.10
  BOTTOM w0.254: RJ1.10 80.98,20.75 v4(80.98,19.84)
LAN_MDI0_C_DN: length 28.5
  TOP w0.089: XF1.2 61.08,8.76 61.55,8.3 62.21,8.3 62.97,7.54 63.36,7.54 v2(63.66,7.84) ; RJ1.2 v2(80.1,10.27)
  L4 w0.102: v2(63.66,7.84) 63.97,7.53 65.44,7.53 66.49,6.48 79.75,6.48 80.78,7.52 80.78,10.14 80.65,10.27 v2(80.1,10.27)
  BOTTOM w0.089: v2(80.1,10.27) v4(80.1,9.45)
LAN_MDI0_C_DP: length 28.5
  TOP w0.089: XF1.1 61.01,7.49 61.47,7.96 62.07,7.96 62.83,7.19 63.39,7.19 v2(63.63,6.96) ; RJ1.1 v2(81.37,10.27)
  L4 w0.102: v2(81.37,10.27) 81.11,10.01 81.11,7.38 79.88,6.15 79.61,6.15 66.35,6.15 65.3,7.2 63.87,7.2 v2(63.63,6.96)
  BOTTOM w0.089: v2(81.37,10.27) v4(81.37,11.08)
LAN_MDI0_DN: length 17.7
  TOP w0.089: 41.19,12.52 40.8,12.52 39.34,13.99 U20.2 ; 41.19,12.52 42.92,12.52 43.56,11.88 45.18,11.88 U121.3 45.42,11.88 46.23,11.88 46.81,12.47 48.57,12.47 49.06,11.98 49.06,9.12 49.87,8.3 50.32,8.3 50.78,8.76 XF1.11 ; 41.19,12.52 v3(41.19,12.88)
LAN_MDI0_DP: length 17.7
  TOP w0.089: XF1.12 50.38,7.49 50.3,7.57 50.3,7.75 50.09,7.96 49.73,7.96 48.71,8.98 48.71,11.84 48.55,12 U121.4 47.87,12.12 46.95,12.12 46.37,11.54 43.77,11.54 ; v3(43.77,11.16) 43.77,11.54 ; 43.77,11.54 43.42,11.54 42.78,12.18 40.66,12.18 39.25,13.59 U20.1
LAN_MDI1_C_DN: length 29.6
  TOP w0.089: RJ1.6 v2(75.02,10.27) ; v2(63.53,15.64) 63.24,15.35 62.74,15.35 62.17,15.92 61.54,15.92 61.08,16.38 XF1.6
  L4 w0.102: v2(63.53,15.64) 63.84,15.34 64.48,15.34 64.9,14.92 64.9,11.08 68.11,7.87 76.53,7.87 76.89,8.23 76.89,9.53 76.76,9.65 75.22,9.65 75.02,9.85 v2(75.02,10.27)
  BOTTOM w0.089: v2(75.02,10.27) v4(75.02,9.4)
LAN_MDI1_C_DP: length 29.5
  TOP w0.089: v2(63.52,14.72) 63.23,15.01 62.59,15.01 62.03,15.58 61.49,15.58 61.03,15.11 XF1.5 ; RJ1.3 v2(78.83,10.27)
  L4 w0.102: v2(63.52,14.72) 63.8,15.01 64.35,15.01 64.57,14.79 64.57,10.94 67.97,7.54 76.67,7.54 77.22,8.09 77.22,9.53 77.35,9.65 78.21,9.65 v2(78.83,10.27)
  BOTTOM w0.089: v4(78.83,11.08) 78.83,10.62 78.83,10.61 v2(78.83,10.27)
LAN_MDI1_DN: length 14.7
  TOP w0.089: XF1.7 50.76,16.38 50.29,15.92 49.89,15.92 48.47,14.5 47,14.5 46.25,13.76 45.78,13.76 45.63,13.91 U121.1 45.15,13.76 42.1,13.76 ; 42.1,13.76 41.52,13.76 40.13,15.15 39.2,15.15 39.17,15.19 U20.5 ; 42.1,13.76 v3(42.1,14.14)
LAN_MDI1_DP: length 14.8
  TOP w0.089: 43.37,13.42 46.4,13.42 47.14,14.16 47.74,14.16 U121.6 48.24,14.16 48.61,14.16 50.03,15.58 50.32,15.58 50.78,15.11 XF1.8 ; 43.37,13.42 v3(43.37,13.05) ; 43.37,13.42 41.38,13.42 39.99,14.81 39.15,14.81 39.12,14.79 U20.4
LAN_MDI2_C_DN: length 25.2
  TOP w0.089: RJ1.5 v2(76.29,10.27)
  L3 w0.102: v2(76.29,10.27) 76.81,10.27 76.93,10.14 76.93,7.84 76.26,7.16 66.87,7.16 66.02,8.01 66.02,8.85 65.55,9.33 63.93,9.33 v2(63.66,9.6)
  BOTTOM w0.089: XF2.5 61.07,8.76 61.54,8.29 62.01,8.29 63.06,9.34 63.41,9.34 v2(63.66,9.6) ; v2(76.29,10.27) v4(76.29,11.08)
LAN_MDI2_C_DP: length 25.2
  TOP w0.089: RJ1.4 v2(77.56,10.27)
  L3 w0.102: v2(63.67,8.71) 63.96,9 65.41,9 65.69,8.71 65.69,7.87 66.73,6.83 76.39,6.83 77.26,7.7 77.26,9.98 v2(77.56,10.27)
  BOTTOM w0.089: XF2.6 61.01,7.49 61.47,7.95 62.15,7.95 63.14,8.93 63.45,8.93 v2(63.67,8.71) ; v2(77.56,10.27) v4(77.56,9.45)
LAN_MDI2_DN: length 13.3
  BOTTOM w0.089: PR5250.2 42.65,12.79 42.65,12.6 42.78,12.47 46.92,12.47 47.51,11.88 47.87,11.88 U122.3 48.11,11.88 48.48,11.88 49.06,11.3 49.06,11.01 ; 49.06,11.01 v4(49.36,11.01) ; 49.06,11.01 49.06,8.86 49.62,8.3 50.13,8.3 50.22,8.39 50.22,8.67 50.31,8.76 XF2.8
LAN_MDI2_DN_R: length 8.4
  TOP w0.089: U20.7 39.11,15.99 39.17,15.93 40.37,15.93 41.12,16.68 42.44,16.68 42.73,16.38 42.73,16 v2(43.02,15.71)
  BOTTOM w0.089: v4(42.36,16.52) 42.39,16.48 42.49,16.48 43.02,15.95 v2(43.02,15.71) 42.67,15.37 42.67,14.42 PR5250.1
LAN_MDI2_DP: length 13.9
  BOTTOM w0.089: PR5249.2 42.31,12.83 42.31,12.46 42.64,12.13 ; 42.64,12.13 v4(42.4,11.89) ; 42.64,12.13 45.17,12.13 U122.4 45.42,12.13 46.78,12.13 47.37,11.54 48.33,11.54 48.71,11.16 48.71,8.72 49.48,7.96 50.13,7.96 50.22,7.87 50.22,7.58 50.31,7.49 XF2.7
LAN_MDI2_DP_R: length 7.5
  TOP w0.089: v2(42.13,15.74) 42.39,15.99 42.39,16.24 42.3,16.33 41.26,16.33 40.51,15.58 38.7,15.58 U20.6
  BOTTOM w0.089: PR5249.1 42.33,14.42 42.33,15.54 v2(42.13,15.74) 42.09,15.78 v4(41.24,15.78)
LAN_MDI3_C_DN: length 25.9
  TOP w0.089: RJ1.8 v2(72.48,10.27)
  L3 w0.102: v2(63.56,17.59) 63.56,17.42 63.76,17.22 64.9,17.22 65.61,16.51 65.61,11.3 68.39,8.52 72.55,8.52 73.05,9.01 73.05,10.03 72.81,10.27 v2(72.48,10.27)
  BOTTOM w0.089: v2(72.48,10.27) v4(72.48,9.4) ; XF2.1 61.07,16.38 61.53,15.93 61.96,15.93 62.15,16.12 62.15,16.72 62.72,17.3 63.33,17.3 63.56,17.53 v2(63.56,17.59)
LAN_MDI3_C_DP: length 26
  TOP w0.089: RJ1.7 v2(73.75,10.27)
  L3 w0.102: v2(73.75,10.27) 73.74,10.27 73.38,9.91 73.38,8.88 72.69,8.19 68.26,8.19 65.28,11.16 65.28,16.38 64.77,16.89 63.78,16.89 v2(63.52,16.64)
  BOTTOM w0.089: v2(63.52,16.64) 63.23,16.96 62.87,16.96 62.49,16.58 62.49,15.98 62.1,15.59 61.51,15.59 61.03,15.11 XF2.2 ; v2(73.75,10.27) v4(73.75,11.08)
LAN_MDI3_DN: length 10.5
  BOTTOM w0.089: PR5248.2 44.71,15.46 44.71,14.81 45.03,14.49 46.43,14.49 47.14,13.78 47.86,13.78 U122.1 48.12,13.78 48.76,13.78 49.02,14.04 49.02,15.38 49.12,15.48 ; XF2.12 50.31,16.38 50.22,16.29 50.22,16.01 50.13,15.92 49.55,15.92 49.12,15.48 ; v4(48.87,15.72) 49.12,15.48
LAN_MDI3_DN_R: length 10
  TOP w0.089: v2(42.02,18.29) 41.83,18.48 38.02,18.48 37.64,18.1 37.64,17.53 37.61,17.5 U20.10
  BOTTOM w0.089: v4(43.76,18.4) 43.76,18.08 ; 43.76,18.08 42.22,18.08 v2(42.02,18.29) ; 43.76,18.08 44.23,18.08 44.69,17.62 44.69,17.02 PR5248.1
LAN_MDI3_DP: length 11.1
  BOTTOM w0.089: XF2.11 50.31,15.11 50.22,15.2 50.22,15.49 50.13,15.58 49.7,15.58 49.36,15.24 49.36,14.55 ; 49.36,14.55 49.36,13.89 48.9,13.44 47,13.44 46.28,14.15 45.54,14.15 U122.6 45.27,13.91 45.03,14.15 44.88,14.15 44.37,14.66 44.37,15.42 PR5247.2 ; 49.36,14.55 v4(49.65,14.55)
LAN_MDI3_DP_R: length 9.9
  TOP w0.089: v2(41.99,17.4) 41.64,17.75 41.64,18.01 41.51,18.14 38.16,18.14 37.98,17.96 37.98,17.53 38.01,17.5 U20.9
  BOTTOM w0.089: v4(41.29,17.94) 41.82,17.4 v2(41.99,17.4) 42.34,17.74 44.09,17.74 44.35,17.48 44.35,17.02 PR5247.1
LAN_RSET: length 4.6
  TOP w0.102: v3(40.12,9.88) 39.75,10.25 R377.2 38.91,10.25 37.96,11.2 37.96,11.51 37.61,11.85 U20.31
LAN_XTALI: length 13.9
  TOP w0.102: v1(38.64,5.21) 38.13,5.21 38.01,5.08 36.21,5.08 X4.1 36.06,6.98 36.06,8.8 R369.2 35.59,9.75 34.89,10.45 C205.1 35.95,10.54 36.56,11.15 36.56,12 36.41,12.15 U20.28
  BOTTOM w0.102: v1(38.64,5.21) 38.01,5.21 37.88,5.33 v4(37.75,5.33)
LAN_XTALO: length 7.8
  TOP w0.102: U20.29 36.81,10.4 C212.1 36.89,9.5 R369.1 37.99,8.39 v1(38.59,8.39) 37.81,7.61 X4.3
  BOTTOM w0.102: v1(38.59,8.39) v4(38.59,7.62)
LANCLK_REQ_U_N: length 11
  TOP w0.102: v2(38.49,19.68) 37.76,19.68 36.75,18.68 36.75,17.87 36.81,17.81 U20.12
  BOTTOM w0.102: v2(38.49,19.68) 38.79,19.38 v4(39.46,19.38) 40.25,19.38 41.45,20.58 Q47.3 41.45,21.5 42.59,22.64 R516.1
LDR: length 5
  BOTTOM w0.254: 35.64,31.88 34.88,31.11 U120.1
  BOTTOM w0.508: R79714.2 36.53,32.72 v4(36.53,32.44) 35.97,31.88 35.64,31.88
LDR_1: length 3.9
  BOTTOM w0.508: v4(39.4,34.65) 39.4,34.72 R79714.1 38.01,37.64 Q1250.4
LDRQ#: length 45.7
  TOP w0.102: v1(136.15,50.04) 136.13,50.01 135.72,50.01 134.37,51.36 R303.1 133.41,51.36 v3(133.36,51.31) 132.33,52.34 U109.2 ; R79957.2 150.22,79.22 v1(149.97,79.48)
  L4 w0.127: v1(141.08,72.82) 140.8,72.54 140.8,68.66 139.86,67.72 139.86,65.91 138.73,64.78 138.73,63.04 137.79,62.1 137.79,59.8 137.07,59.08 137.07,55.69 136.51,55.13 136.51,54.41 136.84,54.08 136.84,51.38 136.15,50.7 v1(136.15,50.04)
  BOTTOM w0.102: v1(141.08,72.82) 140.75,73.15 140.75,75.57 142.23,77.04 146.96,77.04 149.39,79.48 v1(149.97,79.48)
LDRQ#_EC: length 3.8
  TOP w0.102: v3(150.59,76.46) 150.59,77.04 R79957.1 150.22,77.2 149.06,76.04 U4101.61
LED_5VSB: length 3.7
  TOP w0.635: v3(168.08,89.43) 168.08,89.64 167.7,90.02 R306.2 167.86,90.68 LED2.A
LEDC_ISET: length 8.3
  BOTTOM w0.102: U120.12 29.56,29.22 v4(29.37,29.03) 30.23,28.17 R82.1
LFRAMEJ_FW4: length 201.4
  TOP w0.089: CPU2.P3 77.66,152.99 77.37,152.71 77.37,152.43 77.44,152.36 77.44,152.01 77.36,151.93 77.36,150.91 77.4,150.87
  TOP w0.102: v1(128.38,68.18) 128.41,68.15 U109.37 ; v1(142.55,85.57) 142.55,85.14 142.5,85.09 142.5,83.6 142.55,83.55 142.55,83.54 145.16,80.94 R79698.2 ; 77.4,150.87 77.4,150.19 77.02,149.81 77.02,145.24 73.02,141.24 71.5,141.24 67.65,137.39 67.65,135.6 67.42,135.37 v1(67.42,135.13)
  L3 w0.127: v1(67.42,135.13) 67.98,134.57 77.36,134.57 88.25,123.67 97.37,123.67 97.42,123.72 99.6,123.72 99.88,124 105.28,124 105.73,123.55 118.42,123.55 122.2,119.76 132.3,119.76 132.79,119.28 132.81,119.28 134.88,117.21 134.99,117.21 135.63,116.57 136.9,115.32 137.4,115.32 138.6,114.11 138.6,111.66 141.22,109.04 141.22,108.48 141.98,107.73 141.98,105.02 143.85,103.15 143.85,90.51 143.13,89.79 143.13,89.79 142.63,89.29 142.63,85.72 142.55,85.65 v1(142.55,85.57) 142.48,85.65 138.62,85.65 137.77,84.8 134.16,84.8 133.74,84.38 126.77,84.38 122.03,79.64 v1(122.03,78.84)
  L4 w0.127: v1(122.03,78.84) 122.26,78.61 123.53,78.61 128.4,73.74 128.4,68.2 ; 128.4,68.2 127.96,68.64 127.35,68.64 126.86,68.15 126.86,67.93 126.44,67.52 124.91,67.52 120.04,72.4 120.04,73.35 119.41,73.98 115.91,73.98 LPC1.13 ; 128.4,68.2 v1(128.38,68.18)
  BOTTOM w0.102: v1(128.38,68.18) 128.42,68.14 128.42,67.01 R149.2 127.3,65.89 R146.2 ; v4(122.03,78.05) v1(122.03,78.84)
LFRAMEJ_FW4_EC: length 2.4
  TOP w0.102: U4101.3 146.17,80.75 R79698.1
LINE2-VREFO: length 10.2
  TOP w0.203: U6.29 163.36,48.17 164.13,47.4 v2(167.01,47.4) ; v2(167.06,49.35) 167.04,49.33 R261.1 R272.1
  BOTTOM w0.203: v2(167.01,47.4) 167.57,47.96 167.57,48.84 v2(167.06,49.35) 167.06,50.23 v4(167.17,50.33)
LINEOUT-JD: length 157
  TOP w0.203: LOUT1.Q 82.24,33.76 83.23,32.77 83.23,32.17 87.38,28.02 87.38,5.46 90.51,2.34 151.24,2.34 151.7,2.79 151.7,2.95 152.58,3.83 v2(152.69,3.83) ; v2(167.39,28.55) 167.57,28.73 167.57,51.13 167.06,51.64 R266.1
  BOTTOM w0.203: v2(167.39,28.55) 165.39,26.54 163.86,26.54 158.53,21.21 158.53,20.55 152.43,14.45 v4(152.43,13.79) 152.43,4.08 v2(152.69,3.83)
LINEOUT-L: length 150.1
  TOP w0.203: v2(166.4,28.42) 166.77,28.79 166.77,40.11 v3(166.24,40.65) 165.56,41.33 159.59,41.33 158.64,42.27 158.64,43.93 159.65,44.93 159.65,45 159.74,45.1 U6.19 ; R429.1 87.97,28.26 87.97,5.7 90.75,2.92 150.89,2.92 v2(150.97,3)
  BOTTOM w0.203: v2(150.97,3) 151.77,3.8 151.77,14.81 157.89,20.93 157.89,21.46 163.61,27.18 165.16,27.18 v2(166.4,28.42)
LINEOUT-R: length 147.5
  TOP w0.203: U6.18 159.35,45.16 158.06,43.87 158.06,42.03 159.34,40.74 165.14,40.74 166.14,39.75 v3(166.14,30.71) 166.14,29.35 165.49,28.7 v2(165.49,28.35) ; v2(150.83,3.78) 150.63,3.58 90.92,3.58 88.55,5.95 88.55,28.95 86.1,31.4 86.1,31.86 85.85,32.12 R428.1
  BOTTOM w0.203: v2(165.49,28.35) 165.02,27.88 163.29,27.88 157.13,21.72 157.13,21.06 151.16,15.09 151.16,4.12 v2(150.83,3.78)
LINEOUT_C-L: length 3
  TOP w0.203: L62.1 R429.2 84.73,32.41 v2(85.52,31.62)
  BOTTOM w0.203: v4(84.71,31.58) 85.11,31.58 85.11,31.57 85.47,31.57 v2(85.52,31.62)
LINEOUT_C-R: length 2.5
  TOP w0.203: L20.1 R428.2 86.74,31.6 v2(86.73,31.6)
  BOTTOM w0.203: v4(86.71,32.18) v2(86.73,31.6)
LINEOUT_CON-L: length 19.8
  TOP w0.203: L62.2 84.7,34.34 C268.2 83.37,35.75 83.37,38.25 84.2,39.08 Q46.1 84.01,39.72 81.07,42.66 LOUT1.4
  BOTTOM w0.203: v4(73.13,42.65) 73.15,42.66 LOUT1.4
LINEOUT_CON-R: length 34.4
  TOP w0.203: L20.2 85.87,33.5 C267.2 85.81,34.44 84.2,36.06 Q46.2 85,38.65 85,40.11 81.55,43.55 74,43.55 72.4,41.94 72.4,35.14 LOUT1.1
  BOTTOM w0.203: LOUT1.1 v4(73.03,32.71)
LINK_ACTIVITY_N: length 60.9
  TOP w0.203: U20.27 36.01,11.99
  TOP w0.254: U6705.4 80.08,28 v2(80.96,27.13) 81.88,27.13 UR5.1 ; 36.01,11.99 36.01,11.5 v2(36.05,11.46)
  L3 w0.254: v2(36.05,11.46) 36.74,12.15 37.88,12.15 39.5,13.76 39.5,17.22 41.54,19.26 57.24,19.26 62.53,24.55 78.38,24.55 v2(80.96,27.13)
  BOTTOM w0.254: v2(80.96,27.13) 80.79,27.13 v4(80.2,27.72)
LINK_PWR: length 5.4
  TOP w0.254: R79618.2 84.64,22.12 RJ1.9
  BOTTOM w0.254: v4(83.73,19.76) 83.73,20.88 RJ1.9
LPC_CLK0_R: length 11.3
  TOP w0.089: 77.69,150.45 77.69,150.96 77.55,151.1 77.55,151.85 77.66,151.95 CPU2.P2
  TOP w0.102: R664.1 77.05,142.51 v3(77.05,143.13) 77.05,143.67 77.22,143.85 77.22,149.61 77.69,150.07 77.69,150.45
LPC_CLK1: length 5.6
  TOP w0.102: LPC1.1 103.18,73.25 100.29,73.25 R1571.2 C84.1
  BOTTOM w0.102: v4(102.65,73.48) 102.87,73.7 LPC1.1
LPC_CLK1_R: length 189.4
  TOP w0.089: 77.9,150.42 77.9,151.03 77.74,151.18 77.74,151.77 77.86,151.88 77.86,152.35 77.95,152.45 77.95,152.74 CPU2.R3
  TOP w0.102: R1571.1 98.76,73.23 v2(98.59,73.41) ; v1(68.13,135.23) 68.81,135.92 68.81,136.66 72.31,140.16 76.49,140.16 78.47,142.14 78.47,142.74 77.88,143.32 77.88,144.55 77.43,145 77.43,148.25 v3(77.78,148.6) 77.9,148.72 77.9,150.42
  L3 w0.127: v1(68.13,135.23) 77.45,135.23 88.5,124.18 97.11,124.18 97.16,124.23 99.37,124.23 99.65,124.51 105.49,124.51 105.94,124.05 118.63,124.05 122.41,120.27 132.51,120.27 133,119.79 133.02,119.79 135.09,117.72 135.2,117.72 136,116.93 137.11,115.82 137.61,115.82 139.11,114.32 139.11,111.88 141.73,109.26 141.73,108.69 142.48,107.94 142.48,105.23 144.36,103.36 144.36,90.3 143.64,89.58 143.64,89.58 143.14,89.08 143.14,85.51 142.75,85.13 138.82,85.13 137.98,84.29 134.6,84.29 133.46,83.15 126.26,83.15 122.54,79.43 122.54,78.43 122.27,78.17 120.3,78.17 119.65,78.82 115.65,78.82 115.36,79.11 114.67,79.11 113.83,78.27 112.57,78.27 111.95,77.65 107.63,77.65 106.55,78.73 103.91,78.73 v2(98.59,73.41)
LPC_CLKRUN#: length 10.6
  TOP w0.089: 78.33,150.87 78.33,150.96 78.54,151.18 78.54,151.54 78.42,151.66 78.42,152.36 78.34,152.43 78.34,152.71 78.63,152.99 CPU2.T3
  TOP w0.102: R79662.2 78.93,143.65 v3(78.48,144.09) 78.38,144.19 78.38,145.27 78.33,145.33 78.33,148.36 78.34,148.37 78.34,148.83 78.33,148.85 78.33,150.87
LPC_PME_N: length 199
  TOP w0.089: CPU2.AD2 82.51,151.95 82.37,151.81 82.37,151.28 82.64,151.01 82.64,150.94
  TOP w0.102: v1(142.7,82.27) 142.7,81.48 R80132.2 ; R392.2 112.4,63.11 R79948.2 113.41,63.11 114.08,62.43 v2(114.71,62.43) ; v1(87.31,142.11) 87.31,142.47 86.37,143.41 86.37,144.6 86.11,144.86 86.11,145.96 84.71,147.37 84.44,147.37 82.64,149.16 82.64,150.94
  L3 w0.127: v1(123.35,75.34) 123.43,75.34 128.63,80.54 137.58,80.54 138.83,81.79 142.22,81.79 v1(142.7,82.27) 143.04,82.6 144.17,82.6 144.17,82.59 144.54,82.59 145.8,83.86 145.8,85.43 145.99,85.62 145.99,87.08 146.87,87.96 146.87,104.04 144.64,106.27 144.64,108.83 143.89,109.59 143.89,110.15 142.29,111.75 142.29,114.27 138.58,117.98 138,117.98 137.34,118.64 136.1,119.88 136.1,119.88 133.29,122.68 123.05,122.68 119.53,126.21 112.05,126.21 111.18,127.08 103.87,127.08 102.32,128.63 99.32,128.63 93.09,134.86 93.09,135.58 87.31,141.36 v1(87.31,142.11)
  L4 w0.127: v2(114.71,62.43) 113.76,62.43 111.87,64.33 111.75,64.33 109.84,66.24 106.41,66.24 104.04,68.62 102.45,68.62 101.07,68.62 98.12,71.57 98.12,76.95 101.65,80.49 106.59,80.49 107.54,79.54 110.05,79.54 110.56,80.05 117.72,80.05 120.1,77.66 121.03,77.66 v1(123.35,75.34)
  BOTTOM w0.102: v4(86.17,142.16) 86.17,142.16 87.26,142.16 v1(87.31,142.11)
LPC_PME_R: length 4.1
  TOP w0.102: R79948.1 113.34,61.32 v3(113.44,61.21) 113.57,61.21 114.32,61.96 114.88,61.96 114.89,61.98 114.9,61.98 115.27,62.34 U109.70
LPE_I2S2_DATAOUT_1: length 13.7
  TOP w0.102: v5(157.01,183.26) 156.75,183.26 156.37,182.88 Q1205.D 153.77,184.66 R544.1 148.95,185.17 TXE1.1
LPF: length 4.4
  BOTTOM w0.102: C3455.1 34.54,25.25 34.04,25.25 33.08,26.21 v4(33.08,26.21) 33.08,26.59 32.43,27.25 U120.9
LVDS_BL_ADJ: length 117.5
  TOP w0.165: R1984.1 R131.1 35.82,117.96 35.47,118.31 v1(34.87,118.31)
  L3 w0.165: v2(44.86,50.39) 44.86,50.39 35.88,50.39 34.12,52.15 34.12,52.76 31.34,55.53 31.34,68.62 36.72,74 36.72,100.73 34.57,102.88 34.57,118.01 v1(34.87,118.31)
  L4 w0.165: v2(44.86,50.39) 44.89,50.37 44.89,45.66 42.77,43.54 42.77,31.56 42.77,31.56 42.77,31.35 39.75,28.33 39.75,27.18 v2(40.22,26.72)
  BOTTOM w0.165: v2(40.22,26.72) 40.88,26.72 41.33,26.26 41.33,25.41 v4(40.66,24.73) 40.5,24.57 R133.1 39.66,23.51 R134.2 R132.1
LVDS_BL_EN_1: length 3.6
  TOP w0.102: R79939.2 120.98,68.89 120.99,68.88 120.99,68.39 v3(121.26,68.12) 121.53,67.85 121.53,67.26 121.61,67.18 U109.54
LVDS_DET_A*: length 137.1
  TOP w0.102: LVDS1.17 v2(43.63,93.5) ; v2(125.28,52.2) 125.21,52.12 U109.116 ; v1(63.05,71.53) 65.63,74.1 v3(65.84,74.1) 66.94,74.1 v1(69.98,77.14)
  L3 w0.127: v1(69.98,77.14) 69.26,76.42 60.16,76.42 57.5,79.07 57.5,79.25 56.86,79.9 53.79,79.9 53.43,79.54 52.19,79.54 51.58,80.15 43.45,80.15 43.16,80.44 43.16,93.03 v2(43.63,93.5) ; v1(63.05,71.53) 87.95,71.53 94.22,65.26 94.22,52.37 98.69,47.89 104.57,47.89 104.81,48.13 114.26,48.13 115.2,49.07 122.16,49.07 v2(125.28,52.2)
  BOTTOM w0.102: R482.2 43.99,93.5 v2(43.63,93.5)
LVDS_DET_B*: length 154.1
  TOP w0.102: v2(126.22,52.17) 125.61,51.56 U109.117
  L3 w0.127: v2(126.22,52.17) 122.74,48.69 115.2,48.69 114.38,47.88 104.94,47.88 104.69,47.64 98.59,47.64 93.96,52.26 93.96,65.15 88.03,71.08 62.17,71.08 61.68,71.58 55.59,71.58 54.03,73.14 54.03,73.14 53.98,73.19 49.79,73.19 48.28,74.7 43.09,74.7 42.73,75.07 42.72,75.07 42.21,75.58 42.21,75.63 42.17,75.67 42.17,76.4 42.2,76.43 42.2,76.82 42.17,76.84 42.17,78.64 41.14,79.67 41.14,104.7 39.47,106.38 39.47,112.87 v2(39.33,113.01)
  BOTTOM w0.102: v2(39.33,113.01) 39.33,113.03 39.02,113.34 39.02,114.12 39.88,114.99 39.88,116.72 41.18,118.02 Q103.D 41.9,118.9 R79657.2
LVDS_DET_B_C*: length 8.8
  TOP w0.127: LVDS1.1 43.39,109.5 43.75,109.86 v2(43.75,112.37)
  BOTTOM w0.127: v2(43.75,112.37) 43.7,112.42 C869.1 43.95,113.89 43.96,113.89 44.33,114.27 44.33,115.02 43.24,116.12 Q103.G
LVDS_PU_5: length 2.3
  TOP w0.102: LVDS1.5 43.25,105.5 v2(43.62,105.87)
  BOTTOM w0.102: R1163.2 43.28,105.52 v2(43.62,105.87)
LVDS_PU_5_1: length 16.8
  BOTTOM w0.102: Q9647.D 42.77,111.46 43.08,111.76 44.42,111.76 44.71,112.05 44.71,116.43 45.16,116.88 45.83,116.88 46.05,116.65 46.05,115.11 45.27,114.33 v4(45.27,110.75) R79656.1
LVDS_PU_6: length 5.6
  TOP w0.102: LVDS1.6 43.12,104.5 v2(43.62,105)
  BOTTOM w0.102: v2(43.62,105) 44.97,106.35 v4(44.97,107.47) 45.27,107.77 R79656.2
LVDS_PU_24: length 20.6
  TOP w0.102: LVDS1.24 43.31,86.5 44.94,88.13 44.94,90.22 v5(44.89,90.27) 44.94,90.32 44.94,91.29 44.13,92.1 44.13,103.66 v2(43.64,104.14)
  BOTTOM w0.102: R481.2 v2(43.64,104.14)
LX:
  vias: v3(32.44,44.45) v4(34.93,43.83) v6(31.91,43.43) v6(32.93,43.43) v6(33.94,43.43)
M1_SMB_CLK: length 6.4
  TOP w0.102: v3(123.98,220.29) 123.81,220.46 123.46,220.46 123.15,220.77 122.97,220.95 122.12,220.95 R14.2 121.11,220.47 120.14,219.5 NGFF1.60
M1_SMB_DATA: length 3.5
  TOP w0.102: R1622.2 121.35,219.46 120.75,218.85 v3(120.62,218.85) 120.47,219 NGFF1.58
M_CAS_A_N: length 55.4
  TOP w0.089: CPU2.BG45 94.41,173.7 94.58,173.53 94.65,173.46 94.99,173.46 95.14,173.6 95.8,173.6 95.87,173.68 96.03,173.68
  TOP w0.102: 97.95,173.86 97.78,173.68 96.03,173.68
  TOP w0.165: v1(102.75,173.69) 102.32,174.12 v3(102.09,174.12) 98.21,174.12 97.95,173.86 ; DIMM1.115 132.75,153.95 v1(132.8,154)
  L3 w0.216: v1(132.8,154) 132.77,153.97 130.94,153.97 130.81,153.84 130.81,152.35 130.69,152.22 130.08,152.22 129.95,152.35 129.95,153.84 129.82,153.97 126.74,153.97 126.52,153.76 126.52,152.81 126.3,152.6 125.87,152.6 125.66,152.81 125.66,153.76 125.44,153.97 124.37,153.97 110.29,168.05 110.29,169.45 109.59,170.15 108.48,170.15 105.19,173.44 102.99,173.44 v1(102.75,173.69)
M_DATA_A0: length 70.1
  TOP w0.089: 85.36,179.25 85.36,178.27 85.23,178.14 85.23,177.65 85.13,177.55 85.13,177.31 85.43,177.01 CPU2.AK51
  TOP w0.102: 85.36,179.25 85.36,180.53 85.76,180.93 85.76,182.3 v1(86.76,183.3) ; v1(137.12,190.27) 137.73,189.65 DIMM1.4
  L4 w0.102: v1(86.76,183.3) 86.76,187.03
  L4 w0.127: 86.76,187.03 89.34,191.13 90.56,193.08 90.98,193.79 91.01,193.85 92.94,195.78 95.45,195.78 126.35,193.59 127.47,193.33 131.82,192.5 132.06,192.27 132.23,192.23 134.47,191.26 134.66,191.07 136.21,190.85 v1(137.12,190.27)
  BOTTOM w0.102: v1(137.12,190.27) 137.45,189.93 v4(137.45,189.6)
M_DATA_A1: length 69.1
  TOP w0.089: 85.8,178.97 85.8,178.89 85.8,178.89 85.8,178.14 85.63,177.98 85.63,177.65 85.92,177.37 CPU2.AL51
  TOP w0.102: v1(86.76,181.88) 86.37,181.48 86.26,180.78 86.15,180.54 86.15,180.38 86.15,180.37 86.15,179.32 85.8,178.97 ; v1(134.41,189.3) 133.99,189.72 132.6,189.72 132.23,189.35 DIMM1.5
  L4 w0.102: 87.75,186.01 87.45,185.47 87.45,182.56 v1(86.76,181.88)
  L4 w0.127: 87.75,186.01 88.23,187.03 89.79,189.65 89.97,189.69 90.32,189.48 90.49,189.52 90.62,189.74 90.58,189.92 90.23,190.13 90.18,190.3 90.31,190.52 90.49,190.56 90.84,190.35 91.01,190.4 91.14,190.62 91.1,190.79 90.75,191 90.71,191.17 91.98,193.3 93.39,194.71 95.41,194.71 125.83,192.56 127.69,192.2 130.53,191.66 130.74,191.62 132.54,189.82 133,189.82 133.09,189.73 133.99,189.73 v1(134.41,189.3)
  BOTTOM w0.102: v1(86.76,181.88) 86.32,181.88 v4(85.85,181.41)
M_DATA_A2: length 68.8
  TOP w0.089: 88.81,179.37 88.81,179.04 88.35,178.58 88.35,177.58 88.35,177.58 CPU2.AT52
  TOP w0.102: v1(90.34,181.88) 90.34,180.91 88.81,179.37 ; DIMM1.15 132.44,186.35 132.49,186.4 134.46,186.4 135.05,185.81 v1(135.27,185.81)
  L4 w0.102: 91.82,187.35 89.53,185.06 89.53,182.69 v1(90.34,181.88)
  L4 w0.127: 91.82,187.35 96.44,187.35 96.7,187.61 97.58,188.49 97.66,188.49 99.14,189.97 100.04,189.97 100.16,189.84 100.16,189.1 100.29,188.98 100.57,188.98 100.7,189.1 100.7,189.84 100.82,189.97 101.1,189.97 101.23,189.84 101.23,189.1 101.36,188.98 101.64,188.98 101.76,189.1 101.76,189.84 101.89,189.97 102.17,189.97 102.3,189.84 102.3,189.1 102.42,188.98 102.7,188.98 102.83,189.1 102.83,189.84 102.96,189.97 120.25,189.97 121.73,188.49 127.6,188.49 127.97,188.86 128.55,188.86 128.92,188.49 129.83,188.49 131.44,186.88 131.78,186.54 132.06,186.26 134.83,186.26 v1(135.27,185.81)
  BOTTOM w0.102: v4(135.01,186.51) 135.01,186.16 135.27,185.89 v1(135.27,185.81)
M_DATA_A3: length 71.6
  TOP w0.089: 88.58,179.25 88.58,179.08 88.16,178.66 88.16,177.66 88.14,177.65 88.05,177.55 88.05,177.26 CPU2.AR51
  TOP w0.102: DIMM1.17 132.16,185.75 132.59,186.17 133.2,186.17 v1(133.65,185.72) ; v1(90.34,182.59) 89.86,182.11 89.86,180.85 88.58,179.57 88.58,179.25
  L4 w0.102: v1(90.34,182.59) 89.73,183.2 89.73,184.97 91.59,186.84 91.73,186.84
  L4 w0.127: 91.73,186.84 96.68,186.84 97.8,187.96 97.88,187.96 99.09,189.16 99.35,189.16 100.07,188.44 102.92,188.44 103.91,189.43 104.45,189.43 104.57,189.31 104.57,188.49 104.7,188.37 109.61,188.37 109.74,188.49 109.74,188.77 109.61,188.9 105.23,188.9 105.11,189.03 105.11,189.31 105.23,189.43 120.03,189.43 121.51,187.96 129.61,187.96 131.84,185.72 133.65,185.72 v1(133.65,185.72)
  BOTTOM w0.102: v1(133.65,185.72) 132.98,185.72 v4(132.92,185.77)
M_DATA_A4: length 70.5
  TOP w0.102: CPU2.AL53 86,177.9 86,178.8 86.35,179.15 86.35,180.19 86.35,180.21 86.35,180.5 86.43,180.66 86.76,180.99 v1(86.76,181.12) ; v1(132.78,189.29) 132.24,188.75 DIMM1.7
  L4 w0.102: 88.59,186.29 87.7,185.39 87.7,182.05 v1(86.76,181.12)
  L4 w0.127: 88.59,186.29 88.59,186.6 91.35,189.36 91.63,189.36 91.76,189.48 91.76,189.87 91.89,189.99 92.14,189.99 92.27,189.87 92.27,189.48 92.39,189.36 93.05,189.36 93.17,189.48 93.17,189.79 93.3,189.91 93.58,189.91 93.71,189.79 93.71,189.48 93.83,189.36 95.16,189.36 96.62,190.82 98.62,192.82 98.62,193 98.42,193.2 98.24,193.2 97.25,192.2 97.07,192.2 96.87,192.4 96.87,192.58 97.33,193.05 97.33,193.8 97.44,193.9 97.77,193.9 97.82,193.85 99.97,193.85 100.5,193.81 100.62,193.68 100.58,193.14 100.7,193 100.98,192.98 101.11,193.1 101.15,193.64 101.29,193.76 101.56,193.74 101.68,193.6 101.64,193.06 101.76,192.92 102.04,192.9 102.18,193.02 102.21,193.57 102.35,193.68 125.76,192.03 130.48,191.13 132.32,189.29 v1(132.78,189.29)
  BOTTOM w0.102: v1(86.76,181.12) 85.99,180.34 v4(85.99,180.15)
M_DATA_A5: length 68.3
  TOP w0.089: CPU2.AK52 85.43,178.05 85.55,178.16 85.55,178.97 85.61,179.44
  TOP w0.102: 85.61,179.44 85.73,180.08 85.79,180.36 86.15,181.41 86.15,181.55 86.35,182.05 86.59,182.28 v1(86.76,182.59) ; DIMM1.6 138.29,189.05 137.01,189.55 136.18,189.79 135.97,189.89 135.88,189.98 v1(135.42,190.26)
  L4 w0.102: 87.7,187.22 87.19,185.93 87.19,183.34 87.12,183.09 86.94,182.91 v1(86.76,182.59)
  L4 w0.127: v1(135.42,190.26) 133.31,190.26 133.02,190.55 130.97,192.12 130.84,192.15 126.11,193.05 126.09,193.07 95.43,195.24 93.16,195.24 91.45,193.53 87.7,187.22
  BOTTOM w0.102: v1(135.42,190.26) 135.42,190.33 135.86,190.78 v4(135.86,190.94)
M_DATA_A6: length 71.6
  TOP w0.089: 88.3,179.37 88.3,179.13 87.86,178.68 87.86,178.68 CPU2.AR53
  TOP w0.102: v1(136.09,185.86) 136.54,186.31 137.94,186.31 138.2,186.05 DIMM1.16 ; v1(90.34,184.01) 89.6,183.27 89.6,180.96 88.3,179.65 88.3,179.37
  L4 w0.102: v1(90.34,184.01) 89.93,184.42 89.93,184.89 91.43,186.39 91.98,186.39
  L4 w0.127: 91.98,186.39 96.98,186.39 98.02,187.43 98.1,187.43 98.51,187.83 118.98,187.83 119.11,187.96 119.11,188.24 118.98,188.37 115.32,188.37 115.2,188.49 115.2,188.77 115.32,188.9 119.52,188.9 119.64,188.77 119.64,187.96 119.77,187.83 120.88,187.83 121.28,187.43 128.74,187.43 131.4,184.76 135.52,184.76 136.09,185.33 v1(136.09,185.86)
  BOTTOM w0.102: v4(136.45,186.48) 136.09,186.12 v1(136.09,185.86)
M_DATA_A7: length 73.2
  TOP w0.089: 88.05,179.2 87.57,178.72 87.57,177.65 87.67,177.55 87.67,177.31 87.5,177.13 87.37,177.01 CPU2.AP51
  TOP w0.102: DIMM1.18 138.19,185.45 137.76,185.88 v1(137.71,185.88) ; v1(90.34,184.72) 89.35,183.73 89.35,181.13 88.05,179.83 88.05,179.2
  L4 w0.102: 91.98,186 91.62,186 v1(90.34,184.72)
  L4 w0.127: 91.98,186 97.22,186 97.52,186.3 97.73,186.3 98.68,187.25 120.71,187.25 121.06,186.89 122.56,186.89 122.69,186.77 122.69,185.95 122.82,185.83 127.86,185.83 127.98,185.95 127.98,186.23 127.86,186.36 123.55,186.36 123.43,186.49 123.43,186.77 123.55,186.89 128.52,186.89 131.18,184.23 136.01,184.23 137.66,185.88 v1(137.71,185.88)
  BOTTOM w0.102: v4(91.06,185.15) 90.63,184.72 v1(90.34,184.72)
M_DATA_A8: length 80.2
  TOP w0.102: v1(136.05,183.77) 136.53,184.25 DIMM1.22 ; CPU2.AP48 v1(87.84,175.82)
  L3 w0.089: 87.94,177.25 87.38,176.69 87.38,176.28 v1(87.84,175.82)
  L3 w0.127: 87.94,177.25 87.94,187.48 88.06,187.6 88.06,194.93 91.76,198.63 114.85,198.63 115.78,197.7 119.49,197.7 132.51,184.69 135.13,184.69 v1(136.05,183.77)
  BOTTOM w0.102: v4(136.37,184.45) 136.37,184.44 136.05,184.12 v1(136.05,183.77)
M_DATA_A9: length 81.7
  TOP w0.102: v1(133.59,183.62) 133.18,184.02 132.59,184.02 132.52,183.95 DIMM1.23 ; v1(88.83,175.11) CPU2.AT47
  L3 w0.089: 89.23,178.76 89.23,177.85 88.24,176.86 88.24,175.7
  L3 w0.102: 88.83,175.11 88.24,175.7
  L3 w0.127: v1(133.59,183.62) 133.59,183.34 133.4,183.15 132.54,183.15 119.05,196.63 118.61,196.63 112.53,196.63 112.41,196.76 112.41,197.44 112.28,197.57 112,197.57 111.87,197.44 111.87,196.76 111.75,196.63 111.47,196.63 111.34,196.76 111.34,197.44 111.21,197.57 110.93,197.57 110.81,197.44 110.81,196.76 110.68,196.63 110.4,196.63 110.27,196.76 110.27,197.44 110.15,197.57 109.87,197.57 109.74,197.44 109.74,196.76 109.61,196.63 109.08,196.63 108.85,196.87 108.85,197.41 108.69,197.57 92.2,197.57 89.12,194.49 89.12,187.35 88.52,186.75 88.52,179.47 89.23,178.76 ; v1(88.83,175.11) 88.83,175.11
  BOTTOM w0.102: v4(133.12,184.29) 133.12,184.13 133.59,183.67 v1(133.59,183.62)
M_DATA_A10: length 76.5
  TOP w0.102: CPU2.AY48 v1(90.81,175.11) ; DIMM1.33 134.14,180.95 134.6,180.49 v1(134.6,179.37)
  L3 w0.089: v1(90.81,175.11) 91.4,175.7 91.4,177.1 91.49,177.19 91.71,177.19 91.8,177.27 91.8,177.45 91.71,177.54 91.49,177.54 91.4,177.63 91.4,177.81 91.49,177.9 91.71,177.9 91.8,177.99 91.8,178.16 91.71,178.25 91.49,178.25 91.4,178.34 91.4,178.52 91.49,178.61 91.71,178.61 91.8,178.7 91.8,178.87 91.71,178.96 91.49,178.96 91.4,179.05 91.4,179.24 91.51,179.35
  L3 w0.102: 91.79,185.52 91.51,185.25 91.51,179.35
  L3 w0.127: 91.79,185.52 98.29,192.03 117.25,192.03 130.91,178.37 132.03,177.5 132.67,177.5 132.99,177.81 133.36,177.81 133.58,177.6 134.7,177.6 134.83,177.72 134.83,177.88 134.96,178 135.29,178 135.42,177.88 135.42,177.62 135.53,177.51 135.75,177.51 135.94,177.32 136.12,177.32 136.35,177.55 136.35,177.73 135.91,178.17 135.91,178.3 135.9,178.31 135.9,178.77 135.77,178.89 135.39,178.89 135.24,178.74 134.83,178.74 134.6,178.97 v1(134.6,179.37)
  BOTTOM w0.102: v4(134.19,180.21) 134.6,179.8 v1(134.6,179.37)
M_DATA_A11: length 76.4
  TOP w0.102: DIMM1.34 138.4,180.65 138.07,180.99 137.36,180.99 137.17,181.18 136.49,181.18 v1(136.14,180.82) ; CPU2.AV50 v1(89.82,176.53)
  L3 w0.102: 90.75,185.14 90.75,177.6 89.82,176.67 v1(89.82,176.53)
  L3 w0.127: 90.75,185.14 90.75,186.63 91.45,187.33 91.45,193.53 91.51,193.58 92.23,194.31 93.16,195.24 100.03,195.24 101.27,194.01 101.8,194.01 101.93,194.13 101.93,194.18 102.06,194.31 102.34,194.31 102.46,194.18 102.46,194.13 102.59,194.01 103.19,194.01 103.31,194.13 103.31,194.18 103.44,194.31 103.72,194.31 103.85,194.18 103.85,194.13 103.97,194.01 104.25,194.01 104.38,194.13 104.38,194.18 104.51,194.31 104.79,194.31 104.91,194.18 104.91,194.13 105.04,194.01 105.32,194.01 105.45,194.13 105.45,194.18 105.57,194.31 105.85,194.31 105.98,194.18 105.98,194.13 106.11,194.01 118.39,194.01 131.86,180.54 131.86,180.52 131.99,180.39 134.06,180.39 134.93,181.27 135.84,181.27 135.85,181.25 135.99,181.25 136.14,181.1 v1(136.14,180.82)
  BOTTOM w0.102: v1(136.14,180.82) 136.14,180.74 v4(135.52,180.12)
M_DATA_A12: length 81
  TOP w0.102: CPU2.AP47 v1(87.84,175.11) ; DIMM1.24 137.79,183.65 v1(137.73,183.72)
  L3 w0.089: 87.6,179.25 87.6,178.56 87.18,176.73 87.18,176.09 87.81,175.11 v1(87.84,175.11)
  L3 w0.127: v1(137.73,183.72) 137.73,183.81 135.32,185.22 133.7,185.22 133.48,185.25 132.1,185.99 119.95,198.14 116.02,199.17 91.54,199.17 87.52,195.15 87.52,183.63 87.54,183.62 87.54,179.31 87.6,179.25
  BOTTOM w0.102: v4(137.73,183) 137.73,183.01 v1(137.73,183.72)
M_DATA_A13: length 79.7
  TOP w0.102: DIMM1.21 134.08,184.55 134.95,183.68 v1(135.21,183.68) ; CPU2.AT50 v1(87.84,176.53)
  L3 w0.102: 88.24,177.25 88.24,177.23 87.84,176.82 v1(87.84,176.53)
  L3 w0.127: v1(135.21,183.68) 134.73,184.15 132.29,184.15 119.27,197.17 118.39,197.17 114.76,197.17 114.63,197.3 114.63,197.92 114.5,198.04 114.22,198.04 114.1,197.92 114.1,197.3 113.97,197.17 113.43,197.17 112.5,198.1 91.98,198.1 88.59,194.71 88.59,187.39 88.37,187.16 88.24,187.03 88.24,177.25
  BOTTOM w0.102: v4(134.86,184.33) 134.86,184.03 v1(135.21,183.68)
M_DATA_A14: length 78.5
  TOP w0.102: CPU2.AY50 v1(90.81,175.82) ; DIMM1.35 132.74,180.35 v1(133.69,179.4)
  L3 w0.089: 91.26,179.48 91.21,179.44 91.21,176.22 v1(90.81,175.82)
  L3 w0.102: 91.26,185.14 91.26,179.48
  L3 w0.127: v1(133.69,179.4) 133.69,178.97 133.56,178.84 132.55,178.84 132.25,178.54 131.56,178.54 131.38,178.68 131.38,178.96 117.77,192.56 117.58,192.56 100.36,192.56 100.23,192.69 100.23,193.32 100.1,193.45 99.82,193.45 99.7,193.32 99.7,192.69 99.57,192.56 99.29,192.56 99.16,192.69 99.16,193.32 99.04,193.45 98.76,193.45 98.63,193.32 98.63,192.69 98.5,192.56 97.97,192.56 97.39,193.15 97.09,193.15 96.91,192.97 96.91,192.79 97.39,192.31 97.39,192.07 97.26,191.95 97.07,191.95 96.94,191.82 96.94,191.43 95.5,189.99 95.09,189.99 94.96,189.87 94.96,189.45 93.36,187.85 93.18,187.85 93,188.03 93,188.21 94.33,189.54 94.33,189.72 94.15,189.91 93.84,189.91 93.6,189.67 93.18,189.67 92.96,189.89 92.64,189.89 92.51,189.76 92.51,189.54 92.97,189.08 92.97,188.9 92.58,188.51 92.58,187.07 91.26,185.75 91.26,185.14
  BOTTOM w0.102: v4(132.74,180.11) 133,180.11 133.69,179.42 v1(133.69,179.4)
M_DATA_A15: length 80.5
  TOP w0.102: CPU2.AV45 v1(89.82,174.4) ; DIMM1.36 138.68,180.05 137.97,180.76 137.23,180.76 137.22,180.75 v1(136.99,180.75)
  L3 w0.102: 91,185.14 91,177.42 90.37,176.78 90.37,174.94 v1(89.82,174.4)
  L3 w0.127: v1(136.99,180.75) 136.99,180.19 136.86,180.06 134.53,180.06 134.33,179.86 131.48,179.86 117.97,193.37 101.15,193.37 99.94,194.58 99.7,194.58 99.58,194.46 99.58,194.06 99.45,193.93 99.31,193.93 98.96,194.28 98.96,194.58 98.83,194.71 98.24,194.71 98.11,194.58 98.11,193.88 97.98,193.75 97.7,193.75 97.58,193.88 97.58,194.58 97.45,194.71 97.17,194.71 97.04,194.58 97.04,193.88 96.92,193.75 96.64,193.75 96.51,193.88 96.51,194.58 96.38,194.71 93.39,194.71 91.98,193.3 91.98,187.22 91,186.25 91,185.14
  BOTTOM w0.102: v4(137.6,181.14) 137.59,181.14 137.19,180.75 v1(136.99,180.75)
M_DATA_A16: length 69.5
  TOP w0.102: DIMM1.42 138.24,178.25 137.57,178.92 136.58,178.92 136.23,179.27 v1(136.23,179.35) ; CPU2.AT40 v1(87.84,171.55)
  L4 w0.089: v1(87.84,171.55) 87.44,171.95 87.44,172.39 86.87,172.96 86.87,177.03 87.74,177.91 87.74,178.54
  L4 w0.102: 87.74,178.54 90.18,180.97 90.41,180.97
  L4 w0.127: 90.41,180.97 91.96,180.97 92.77,181.78 92.77,184.24 93.57,185.04 97.9,185.04 98.47,185.61 119.87,185.61 120.75,184.73 120.93,184.73 121.12,184.91 121.3,184.91 121.49,184.71 121.49,184.53 121.31,184.35 121.31,184.17 123.35,182.13 123.95,182.13 124.08,182.26 124.08,182.37 124.21,182.5 124.49,182.5 124.62,182.37 124.62,182.26 124.74,182.13 128.35,182.13 130.63,179.84 134.92,179.84 135.45,179.84 135.73,179.77 136.16,179.35 v1(136.23,179.35)
  BOTTOM w0.102: v1(136.23,179.35) 136.82,179.94 v4(136.82,180.03)
M_DATA_A17: length 69.5
  TOP w0.102: DIMM1.41 132.46,178.55 v1(132.67,178.33) ; CPU2.AP42 v1(87.84,172.97)
  L4 w0.089: 93.66,180.64 93.35,180.34 90.18,180.34 88.17,178.33 88.17,177.7 87.25,176.77 87.25,173.62 87.84,173.03 v1(87.84,172.97)
  L4 w0.127: v1(132.67,178.33) 130.53,178.33 129.79,179.07 129.13,179.07 128.93,179.27 128.93,179.46 127.81,180.58 126.23,180.58 125.75,181.06 124.1,181.06 122.98,179.95 122.98,179.91 122.78,179.71 122.43,179.71 118.55,183.58 118.55,183.8 118.71,183.95 118.93,183.95 121.72,181.17 121.94,181.17 122.1,181.32 122.1,181.54 119.15,184.49 100.08,184.49 99.78,184.19 98.98,184.19 95.85,181.05 95.32,181.05 95.27,181.1 94.11,181.1 93.66,180.64
  BOTTOM w0.102: v1(132.67,178.33) v4(131.9,178.33)
M_DATA_A18: length 63.3
  TOP w0.102: v1(135.08,174.83) 135.01,174.83 134.29,175.55 DIMM1.51 ; CPU2.AT38 88.2,170.48 v1(88.55,170.83)
  L4 w0.089: v1(88.55,170.83) 88.87,171.15 89,171.15 89.1,171.26 89.76,171.26 90.25,171.75 90.25,173.07 90.41,173.23 90.41,176.7 91.34,177.62 94.49,177.62 95,178.13
  L4 w0.127: v1(135.08,174.83) 135.08,174.82 134.51,174.24 132.82,174.24 131.22,172.64 123.43,172.64 115.54,180.54 113.09,180.54 99.93,180.54 97.52,178.13 95,178.13
  BOTTOM w0.102: v4(135.32,175.7) 135.32,175.57 135.08,175.34 v1(135.08,174.83)
M_DATA_A19: length 67
  TOP w0.102: DIMM1.40 138.73,178.85 138.15,179.03 v1(137.85,179.32) ; CPU2.AP40 v1(87.66,170.71)
  L4 w0.089: 86.68,177.21 86.68,172.9 86.82,172.56 v1(87.66,170.71)
  L4 w0.127: v1(137.85,179.32) 137.23,179.79 135.89,180.31 135.77,180.31 135.52,180.38 135.14,180.38 134.53,180.38 128.57,182.66 120.09,186.14 98.43,186.14 98.27,185.98 97.5,185.64 96.25,185.42 94.01,185.42 91.72,184.77 91.35,184.39 91.14,183.61 90.8,181.75 90.46,181.4 90.3,181.4 90.09,181.19 87.53,178.63 87.53,178.59 86.68,177.21
  BOTTOM w0.102: v1(137.85,179.32) 137.85,179.09 v4(138.23,178.71)
M_DATA_A20: length 69.7
  TOP w0.102: DIMM1.50 137.87,175.85 137.17,176.56 137.17,176.62 v1(137.15,176.64) ; CPU2.AT44 v1(88.83,173.69)
  L4 w0.089: v1(88.83,173.69) 89.23,174.09 89.23,176.88 89.22,176.89
  L4 w0.102: 89.22,176.89 90.87,178.53 91.52,178.53 92.21,179.22 93.78,179.22 94.44,179.88 97.24,179.88
  L4 w0.127: 97.24,179.88 99.5,182.14 109.47,182.14 116.45,182.14 122.7,175.88 130.19,175.88 130.32,175.76 130.32,175.44 130.44,175.31 130.72,175.31 130.85,175.44 130.85,175.76 130.98,175.88 134.63,175.88 134.64,175.9 134.78,175.9 134.97,176.09 134.97,176.23 135.22,176.48 135.53,176.48 135.73,176.28 135.73,176.09 135.93,175.88 136.4,175.88 136.41,175.88 139.81,175.88 140.01,176.09 140.01,177.42 139.81,177.62 137.36,177.62 137.15,177.42 v1(137.15,176.64)
  BOTTOM w0.102: v4(137.66,177.21) 137.66,177.16 137.15,176.65 v1(137.15,176.64)
M_DATA_A21: length 68.4
  TOP w0.102: DIMM1.52 139.4,175.25 137.95,175.25 v1(137.65,174.96) ; CPU2.AV41 v1(88.83,171.55)
  L4 w0.089: v1(88.83,171.55) 89.42,172.14 89.42,176.75 89.46,176.79
  L4 w0.102: 89.46,176.79 90.95,178.28 91.67,178.28 92.24,178.85 93.81,178.85 93.94,178.98 93.94,179.09 94.35,179.5 94.61,179.5 94.73,179.63 95.07,179.63 95.2,179.5 95.37,179.5 95.5,179.63 95.94,179.63 96.12,179.45
  L4 w0.127: 96.12,179.45 97.46,179.45 99.62,181.61 109.69,181.61 116.03,181.61 122.86,174.78 123.39,174.78 123.52,174.9 123.52,175.22 123.64,175.35 123.92,175.35 124.05,175.22 124.05,174.9 124.18,174.78 124.71,174.78 124.84,174.9 124.84,175.22 124.97,175.35 125.24,175.35 125.37,175.22 125.37,174.9 125.5,174.78 125.78,174.78 125.91,174.9 125.91,175.22 126.03,175.35 126.31,175.35 126.44,175.22 126.44,174.9 126.57,174.78 126.85,174.78 126.97,174.9 126.97,175.22 127.1,175.35 127.38,175.35 127.51,175.22 127.51,174.9 127.63,174.78 127.91,174.78 128.04,174.9 128.04,175.22 128.17,175.35 128.45,175.35 128.57,175.22 128.57,174.9 128.7,174.78 128.98,174.78 129.11,174.9 129.11,175.22 129.23,175.35 129.51,175.35 129.64,175.22 129.64,174.9 129.77,174.78 130.51,174.78 131.06,174.23 131.31,174.23 131.57,174.5 131.57,175.11 131.77,175.31 134.02,175.31 134.04,175.32 134.83,175.32 134.86,175.36 135.31,175.36 135.32,175.35 136.63,175.35 136.63,175.35 137.07,175.35 137.46,174.96 v1(137.65,174.96)
  BOTTOM w0.102: v1(137.65,174.96) v4(138.4,174.96)
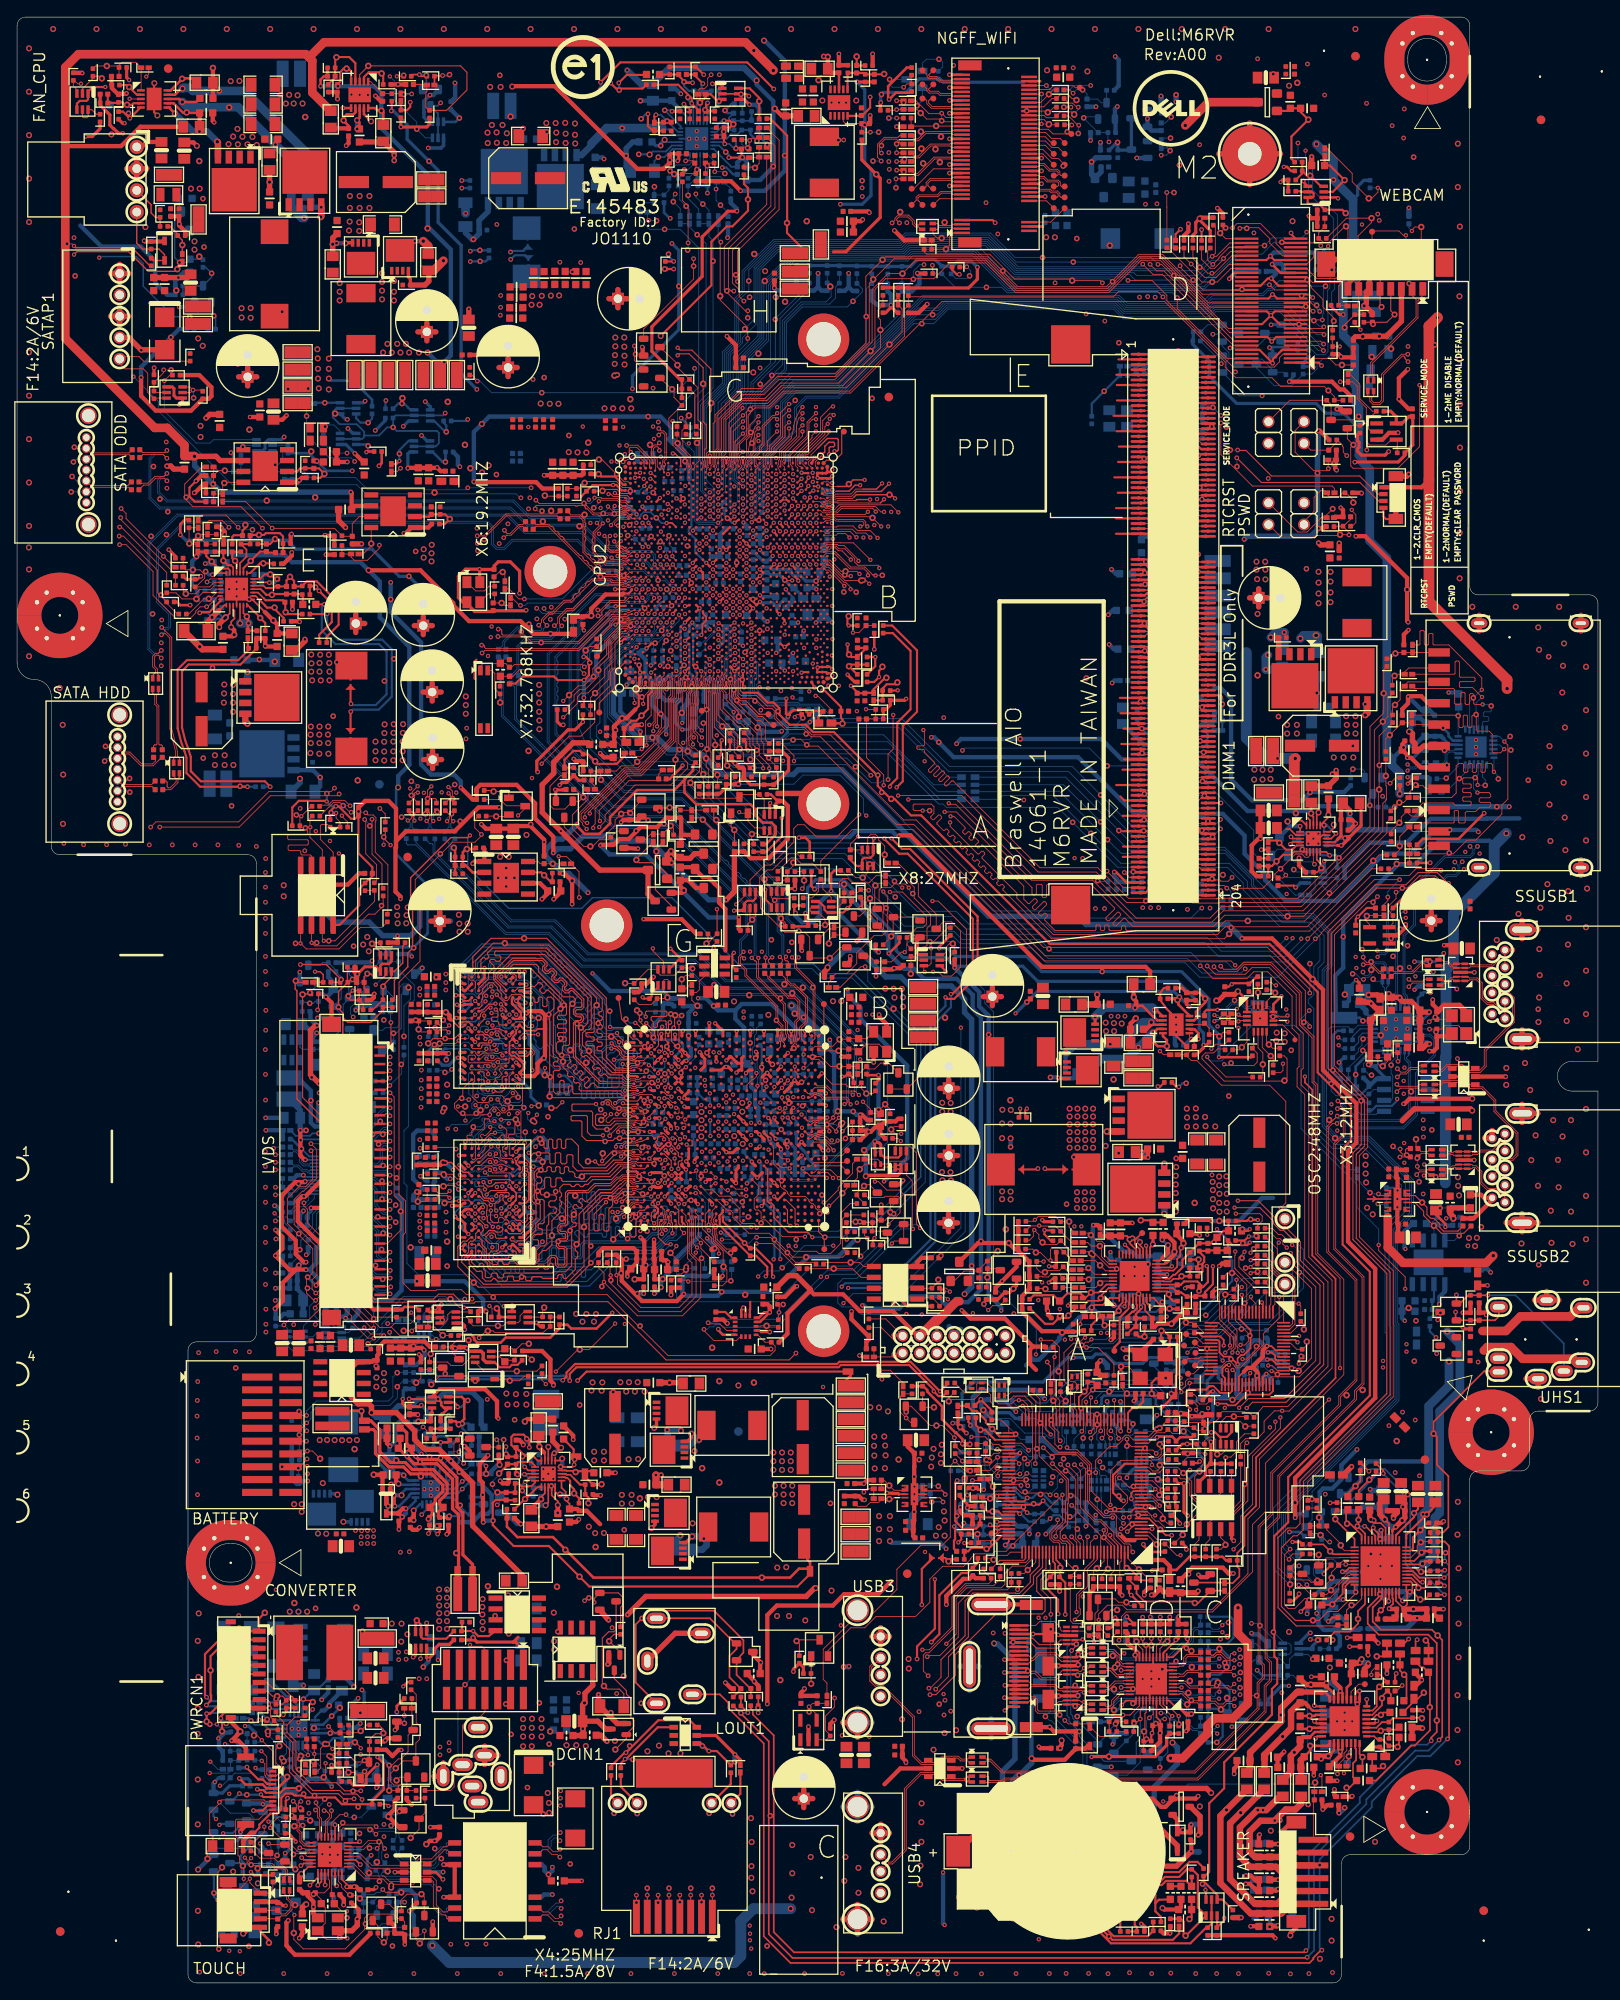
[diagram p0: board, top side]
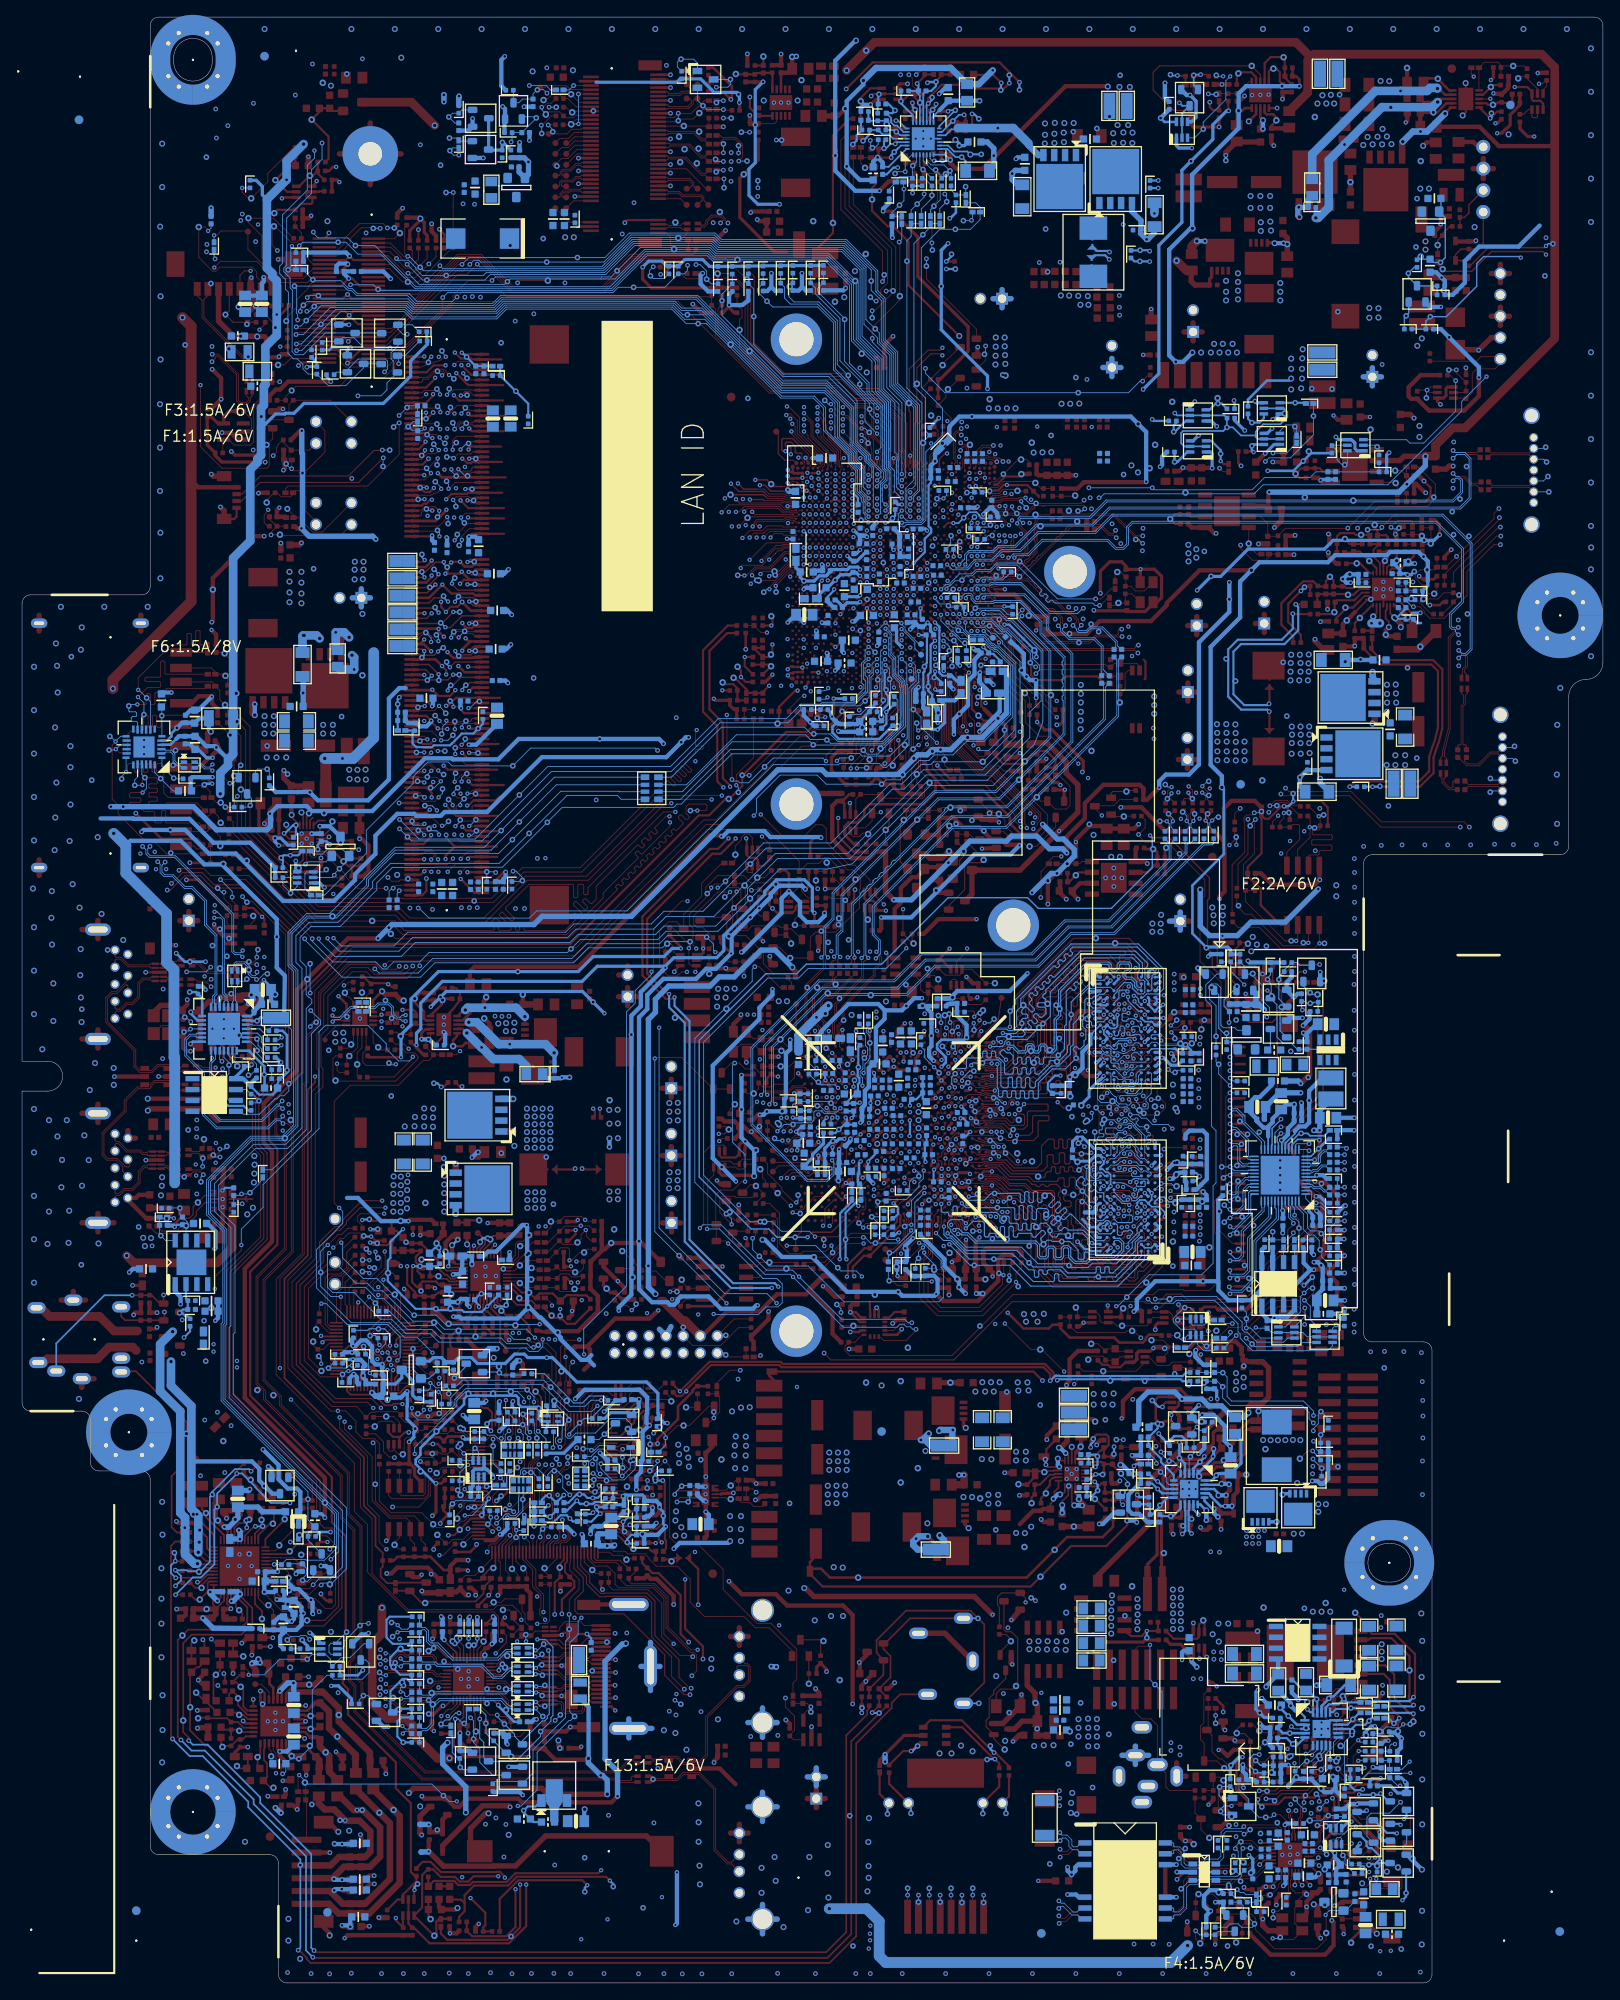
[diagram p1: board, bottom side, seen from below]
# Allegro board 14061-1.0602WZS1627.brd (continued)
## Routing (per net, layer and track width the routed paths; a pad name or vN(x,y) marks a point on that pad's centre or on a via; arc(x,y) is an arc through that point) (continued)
M_DATA_A22: length 66
  TOP w0.102: DIMM1.39 132.24,179.15 132.52,178.87 134.02,178.87 v2(134.5,178.38) ; CPU2.AP41 v1(87.84,172.26)
  L4 w0.089: v1(87.84,172.26) 87.06,173.04 87.06,176.94 87.94,177.82 87.94,178.36 90.15,180.57 90.28,180.57
  L4 w0.127: 90.28,180.57 93.13,180.57 94.37,181.81 94.37,182.89 95.4,183.92 96.2,183.92 96.58,183.54 97.15,183.54 98.69,185.08 119.51,185.08 122.61,181.98 122.61,181.78 122.63,181.76 122.63,181.25 122.83,181.05 123.33,181.05 123.63,181.35 123.63,181.38 123.83,181.58 123.87,181.58 123.88,181.6 125.97,181.6 125.98,181.58 128.14,181.58 130.86,178.87 134.27,178.87 134.5,178.64 v2(134.5,178.38)
  BOTTOM w0.102: v4(135.29,178.53) 134.65,178.53 v2(134.5,178.38)
M_DATA_A23: length 69.5
  TOP w0.102: v1(133.13,174.78) 132.96,174.95 DIMM1.53 ; CPU2.AV42 v1(89.82,172.97)
  L4 w0.089: v1(89.82,172.97) 90.22,173.37 90.22,176.77 91.3,177.85 94.31,177.85 94.9,178.43
  L4 w0.127: v1(133.13,174.78) 132.6,174.78 131,173.18 123.76,173.18 123.6,173.33 123.6,173.55 123.76,173.71 130.08,173.71 130.23,173.87 130.23,174.09 130.08,174.24 122.64,174.24 115.81,181.07 113.31,181.07 113.31,181.08 109.91,181.08 109.91,181.07 99.88,181.07 97.24,178.43 94.9,178.43
  BOTTOM w0.102: v1(133.13,174.78) v4(132.34,174.78)
M_DATA_A24: length 64.4
  TOP w0.089: 92.96,179.25 92.51,178.8 92.32,178.8 91.96,178.45 91.96,177.67 92.15,177.48 92.16,177.48 92.42,177.22 CPU2.BD52
  TOP w0.102: v1(94.96,181.52) 94.96,181.26 92.96,179.25 ; v1(134.37,168.78) 134.37,168.92 134.35,168.95 134.35,169.24 132.84,170.75 DIMM1.67
  L3 w0.127: v1(134.37,168.78) 134.5,168.66 136.35,168.66 136.48,168.53 136.48,168.15 136.35,168.02 135.72,168.02 135.64,168.1 132.77,168.1 132.1,168.77 131.77,168.77 114.57,185.97 101.63,185.97 101.33,185.67 99.19,185.67 95.04,181.52 v1(94.96,181.52)
  BOTTOM w0.102: v4(134.07,169.47) 134.07,169.08 v1(134.37,168.78)
M_DATA_A25: length 66
  TOP w0.089: CPU2.AV52 89.32,178.05 89.47,178.21 89.47,179.25 89.48,179.25
  TOP w0.102: v1(137.9,173.6) 138.05,173.45 DIMM1.58 ; 89.48,179.25 91.22,180.99 91.22,182.19 91.45,183.05 91.92,183.52 v1(91.92,183.66)
  L3 w0.127: v1(137.9,173.6) 137.66,173.84 136.45,174.22 134.86,174.22 134.64,174.43 134.04,174.43 133.78,174.69 133.78,175.27 133.58,175.47 133.4,175.56 131.72,176.36 131.62,176.46 130.2,177.57 116.81,190.96 98.73,190.96 92.33,184.56 92.33,184.07 v1(91.92,183.66)
  BOTTOM w0.102: v1(137.9,173.6) 138.62,173.6 v4(138.65,173.57)
M_DATA_A26: length 65
  TOP w0.089: 92.59,179.25 92.34,179 92.24,179 91.77,178.52 91.77,178.52 91.62,178.37 CPU2.BC53
  TOP w0.102: 92.59,179.25 94.53,181.2 94.53,182.08 v1(94.86,182.41) ; v1(133.53,168.83) 133.61,168.92 133.61,169.19 132.65,170.15 DIMM1.69
  L3 w0.127: v1(94.86,182.41) 94.86,182.65 94.66,182.85 94.37,182.85 94.24,182.73 94.24,181.81 94.37,181.69 94.54,181.69 94.79,181.94 95.14,181.94 95.46,182.26 95.46,182.66 98.85,186.05 100.95,186.05 101.4,186.5 114.8,186.5 131.21,170.09 131.91,169.39 132.25,169.39 132.39,169.54 132.39,169.75 132.49,169.85 134.83,169.85 134.96,169.72 134.96,169.44 134.83,169.31 133.33,169.31 133.23,169.21 133.23,168.96 133.36,168.83 v1(133.53,168.83)
  BOTTOM w0.102: v1(133.53,168.83) 133.53,168.58 133.84,168.27 133.84,168.26 133.85,168.25 v4(133.85,168.19)
M_DATA_A27: length 67.3
  TOP w0.089: 89.23,179.36 89.23,178.31 89.23,178.31 89.23,178.23 89.17,178.18 89.12,178.12 89.12,177.65 89.02,177.55 89.02,177.42 arc(89.04,177.31) 89.1,177.22 89.11,177.22 CPU2.AV51
  TOP w0.102: DIMM1.56 137.23,174.05 136.35,174.41 v1(135.95,174.8) ; 89.23,179.36 90.59,180.72 90.83,181.72 90.87,182.19 91.1,183.02 91.6,183.98 v1(91.92,184.37)
  L3 w0.127: v1(91.92,184.37) 91.92,184.9 98.51,191.5 117.03,191.5 130.55,177.97 132.07,176.79 135.72,175.03 v1(135.95,174.8)
  BOTTOM w0.102: v1(135.95,174.8) 135.95,174.95 v4(136.64,175.64)
M_DATA_A28: length 66.2
  TOP w0.089: CPU2.AW51 89.8,177.37 89.52,177.65 89.52,177.98 89.71,178.17 89.71,179.14 91.07,180.49
  TOP w0.102: 91.07,180.49 91.51,180.93 91.51,181.83 v1(91.92,182.23) ; v1(134.55,173.52) 134.18,173.89 132.7,173.89 132.56,173.75 DIMM1.57
  L3 w0.127: v1(134.55,173.52) 134.17,173.9 133.18,173.9 132.83,174.26 132.81,174.26 132.68,174.38 132.68,174.64 132.47,174.85 132,174.85 131.83,175.02 131.83,175.56 131.53,175.86 131.52,175.87 131.02,175.87 116.45,190.43 98.95,190.43 94.84,186.31 94.52,186.31 92.61,184.4 92.61,183.64 92.36,183.4 92.36,183.13 92.61,182.89 92.61,182.02 92.48,181.89 92.14,181.89 91.92,182.11 v1(91.92,182.23)
  BOTTOM w0.102: v4(134.24,172.74) 134.24,173.12 134.55,173.43 v1(134.55,173.52)
M_DATA_A29: length 65
  TOP w0.089: 92.23,179.25 92.22,179.25 91.28,178.31 91.28,177.67 91.54,177.42 91.68,177.42 CPU2.BC52
  TOP w0.102: DIMM1.70 136.69,169.85 136.15,169.32 v1(136.15,169.24) ; 92.23,179.25 93.01,180.04 94.28,181.3 94.28,182.78 95.09,183.59 95.41,183.59 v1(95.56,183.44)
  L3 w0.127: v1(136.15,169.24) 136.7,169.79 137.04,169.79 137.17,169.91 137.17,170.23 137.04,170.36 136.51,170.36 136.35,170.21 135.23,170.21 135.05,170.38 131.67,170.38 115.02,187.04 101,187.04 100.87,186.91 100.87,186.73 100.57,186.43 98.89,186.43 96.14,183.67 95.8,183.67 v1(95.56,183.44)
  BOTTOM w0.102: v1(136.15,169.24) 136.15,169.72 v4(136.39,169.95)
M_DATA_A30: length 64
  TOP w0.089: 90.13,179.2 89.91,178.98 89.91,177.92 CPU2.AW53
  TOP w0.102: v1(91.92,181.52) 91.92,180.99 90.13,179.2 ; DIMM1.59 132.44,173.15 132.75,173.46 v1(132.88,173.46)
  L3 w0.127: v1(132.88,173.46) 132.61,173.72 132.37,173.72 116.2,189.89 99.18,189.89 95.36,186.08 94.93,186.08 94.61,186.08 92.84,184.3 92.84,180.39 92.71,180.26 92.54,180.26 92.41,180.14 92.41,179.88 92.29,179.76 92.03,179.76 91.83,179.96 91.83,180.67 91.96,180.8 92.21,180.8 92.34,180.92 92.34,181.39 92.21,181.52 v1(91.92,181.52)
  BOTTOM w0.102: v4(132.16,173.45) 132.16,173.46 v1(132.88,173.46)
M_DATA_A31: length 66.7
  TOP w0.089: 91.99,179.37 91.09,178.48 91.09,177.52 91.35,177.26 CPU2.BB51
  TOP w0.102: v1(95.49,184.45) 95.3,184.45 94.02,183.17 94.02,181.41 91.99,179.37 ; DIMM1.68 136.2,170.45 135.25,171.4 v1(135.25,171.51)
  L3 w0.127: v1(135.25,171.51) 135.39,171.65 135.69,171.65 135.87,171.47 136.51,171.47 136.63,171.35 136.63,171.02 136.51,170.89 136.29,170.89 136.18,170.79 135.4,170.79 135.27,170.92 131.89,170.92 115.24,187.57 100.14,187.57 99.97,187.4 99.97,186.93 99.84,186.8 98.83,186.8 96.47,184.45 v1(95.49,184.45)
  BOTTOM w0.102: v4(135.14,170.74) 135.14,171.4 v1(135.25,171.51)
M_DATA_A32: length 57.9
  TOP w0.089: CPU2.BG42 94.01,172.29 94.31,171.99 94.55,171.99 94.65,172.09 94.98,172.09 95.07,171.99 95.97,171.99 96.03,172.06
  TOP w0.102: DIMM1.129 133.62,149.75 134.07,149.3 v1(134.53,149.3) ; v1(100.49,172.13) 100.09,172.53 96.5,172.53 96.03,172.06
  L4 w0.127: v1(100.49,172.13) 100.19,172.13 100.06,172.01 100.06,171.7 100.19,171.58 108.19,171.58 125.92,153.85 125.92,153.67 125.65,153.4 125.65,153.22 125.85,153.03 126.03,153.03 126.3,153.29 126.48,153.29 127.15,152.62 127.15,151.68 127.73,151.09 128.69,151.09 129.85,149.93 130.16,149.62 134.4,149.62 134.53,149.49 v1(134.53,149.3)
  BOTTOM w0.102: v1(134.53,149.3) 134.53,149.61 v4(134.9,149.98)
M_DATA_A33: length 58.2
  TOP w0.089: 96.03,172.77 95.64,172.37 95.25,172.37 95.14,172.49 94.65,172.49 94.37,172.77 94.23,172.77 94.22,172.77 CPU2.BG43
  TOP w0.102: 96.03,172.77 96.2,172.93 102.25,172.93 v1(103.13,172.06) ; DIMM1.132 136.76,148.85 v1(136.2,149.4)
  L4 w0.127: v1(103.13,172.06) 103.33,172.26 104.94,172.26 105.09,172.11 108.41,172.11 127.68,152.84 127.68,151.9 127.96,151.63 128.91,151.63 130.38,150.15 136.22,150.15 136.41,149.96 136.41,149.61 v1(136.2,149.4)
  BOTTOM w0.102: v4(135.42,148.55) 135.65,148.79 135.65,148.85 v1(136.2,149.4)
M_DATA_A34: length 60
  TOP w0.089: CPU2.BG37 94.37,169.86 94.65,169.57 94.99,169.57 95.24,169.83 96.03,169.83
  TOP w0.102: v1(133.54,146.89) 132.8,146.15 DIMM1.141 ; v1(98.23,169.14) 98.17,169.14 97.49,169.83 96.03,169.83
  L4 w0.127: v1(98.23,169.14) 98.47,169.14 98.87,169.53 100.02,169.53 100.06,169.49 101.1,169.49 101.53,169.06 103.95,169.06 104.66,168.35 105.32,167.96 105.66,167.76 106,167.42 106,167.24 105.78,167.03 105.78,166.85 105.98,166.65 106.16,166.65 106.37,166.86 106.55,166.86 106.75,166.66 106.75,166.48 106.54,166.27 106.54,166.09 106.73,165.89 106.91,165.89 107.13,166.11 107.31,166.11 107.51,165.91 107.51,165.73 107.29,165.52 107.29,165.34 107.49,165.14 107.67,165.14 107.88,165.35 108.06,165.35 122.99,150.43 122.99,150.25 122.78,150.03 122.78,149.85 122.97,149.66 123.15,149.66 123.37,149.87 123.55,149.87 123.74,149.67 123.74,149.49 123.53,149.28 123.53,149.1 123.73,148.9 123.91,148.9 124.12,149.12 124.3,149.12 124.5,148.92 124.5,148.74 124.28,148.52 124.28,148.34 124.85,147.78 125.03,147.78 125.29,148.04 125.47,148.04 125.67,147.85 125.67,147.67 125.41,147.4 125.41,147.22 125.89,146.74 126.43,146.74 126.55,146.86 126.55,147.22 126.68,147.35 126.95,147.35 126.96,147.34 127.09,147.22 127.09,146.86 127.21,146.74 131.86,146.74 132.12,146.48 133.13,146.48 v1(133.54,146.89)
  BOTTOM w0.102: v4(133.05,147.64) 133.05,147.61 133.54,147.13 v1(133.54,146.89)
M_DATA_A35: length 58.9
  TOP w0.089: 96.03,170.08 95.04,170.08 CPU2.BJ37
  TOP w0.102: 96.03,170.08 97.74,170.08 98.19,169.63 99.33,169.63 v1(99.85,169.11) ; DIMM1.140 137.02,146.45 v1(135.95,145.38)
  L4 w0.127: v1(99.85,169.11) 99.85,168.81 99.72,168.68 99.14,168.68 99.02,168.55 99.02,168.34 99.14,168.21 102.91,168.21 125.71,145.41 135.92,145.41 v1(135.95,145.38)
  BOTTOM w0.102: v4(134.59,145.98) 134.68,145.89 134.68,145.87 135.17,145.38 v1(135.95,145.38)
M_DATA_A36: length 56.2
  TOP w0.089: 96.03,172.37 95.85,172.18 95.17,172.18 95.07,172.29 CPU2.BH42
  TOP w0.102: v1(137.88,149.38) 137.95,149.45 DIMM1.130 ; v1(101.45,172.11) 101.09,172.11 100.47,172.73 96.39,172.73 96.03,172.37
  L4 w0.127: v1(137.88,149.38) 136.57,150.68 130.61,150.68 108.64,172.64 102.23,172.64 101.7,172.11 v1(101.45,172.11)
  BOTTOM w0.102: v1(137.88,149.38) 138.38,149.38 138.52,149.24 v4(138.67,149.24)
M_DATA_A37: length 56.8
  TOP w0.089: CPU2.BJ41 96.03,171.8
  TOP w0.102: 96.03,171.8 99.24,171.8 v1(99.56,172.12) ; v1(132.75,149.15) 132.75,149.15 DIMM1.131
  L4 w0.127: v1(132.75,149.15) 132.66,149.06 129.01,149.06 128.55,149.52 128.55,149.7 128.84,150 128.84,150.18 128.65,150.38 128.47,150.56 127.51,150.56 126.61,151.46 126.61,152.31 126.43,152.49 125.63,152.49 125.12,153 125.12,153.9 124.63,154.39 124.45,154.39 124.19,154.13 124.01,154.13 123.81,154.32 123.81,154.5 124.07,154.76 124.07,154.94 123.88,155.14 123.7,155.14 123.44,154.88 123.26,154.88 123.06,155.08 123.06,155.26 123.32,155.52 123.32,155.7 123.12,155.9 122.94,155.9 122.68,155.64 122.5,155.64 122.3,155.83 122.3,156.01 122.56,156.27 122.56,156.45 122.37,156.65 122.19,156.65 121.93,156.39 121.75,156.39 121.55,156.59 121.55,156.77 121.81,157.03 121.81,157.21 107.97,171.04 105.09,171.04 105.05,171.09 99.91,171.09 99.56,171.44 v1(99.56,172.12)
  BOTTOM w0.102: v4(131.48,149.94) 131.81,149.94 132.6,149.15 v1(132.75,149.15)
M_DATA_A38: length 58.1
  TOP w0.089: 96.03,169.57 95.84,169.38 94.44,169.38 CPU2.BH36
  TOP w0.102: DIMM1.143 132.87,145.55 v1(133.56,144.86) ; v1(97.41,169.11) 96.95,169.57 96.03,169.57
  L4 w0.127: v1(97.41,169.11) 97.68,169.11 97.81,168.98 97.81,168.96 98.05,168.72 98.08,168.72 98.2,168.59 98.2,168.35 98.08,168.22 97.67,168.22 97.54,168.1 97.54,167.95 97.75,167.74 102.44,167.74 125.75,144.43 126.34,144.43 126.47,144.55 126.47,144.75 126.6,144.88 126.88,144.88 127,144.75 127,144.55 127.13,144.43 127.41,144.43 127.54,144.55 127.54,144.75 127.66,144.88 127.94,144.88 128.07,144.75 128.07,144.55 128.2,144.43 128.48,144.43 128.6,144.55 128.6,144.75 128.73,144.88 129.01,144.88 129.14,144.75 129.14,144.55 129.26,144.43 129.54,144.43 129.67,144.55 129.67,144.75 129.8,144.88 130.08,144.88 130.2,144.75 130.2,144.55 130.33,144.43 130.61,144.43 130.74,144.55 130.74,144.75 130.86,144.88 131.14,144.88 131.27,144.75 131.27,144.55 131.4,144.43 133.43,144.43 133.56,144.55 v1(133.56,144.86)
  BOTTOM w0.102: v4(133.13,145.54) 133.13,145.29 v1(133.56,144.86)
M_DATA_A39: length 59.4
  TOP w0.089: CPU2.BH38 95.91,170.34 96.03,170.46
  TOP w0.102: DIMM1.142 137.93,145.85 v1(137.57,145.49) ; v1(100.69,169.06) 99.83,169.92 98.36,169.92 97.82,170.46 96.03,170.46
  L4 w0.127: v1(137.57,145.49) 137.12,145.94 125.93,145.94 116.88,154.99 116.88,155.17 117.07,155.35 117.07,155.53 116.87,155.73 116.69,155.73 116.51,155.55 116.33,155.55 116.13,155.74 116.13,155.92 116.31,156.11 116.31,156.29 116.12,156.48 115.94,156.48 115.75,156.3 115.57,156.3 115.38,156.5 115.38,156.68 115.56,156.86 115.56,157.04 115.36,157.24 115.18,157.24 115,157.06 114.82,157.06 114.62,157.25 114.62,157.43 114.8,157.62 114.8,157.8 114.61,157.99 114.43,157.99 114.24,157.81 114.06,157.81 103.24,168.63 101.15,168.63 100.71,169.06 v1(100.69,169.06)
  BOTTOM w0.102: v4(138.44,145.31) 138.26,145.49 v1(137.57,145.49)
M_DATA_A40: length 67.8
  TOP w0.102: DIMM1.147 132.32,144.35 132.39,144.42 133.74,144.42 134.35,145.03 v1(134.35,146.69) ; CPU2.BC36 v1(92.11,169.84)
  L3 w0.089: v1(92.11,169.84) 92.11,170.28 92.26,170.43 94.03,170.43 94.83,171.23 97.36,171.23
  L3 w0.127: v1(134.35,146.69) 134.51,146.85 134.51,147.83 134.64,147.96 134.88,147.96 135.01,148.08 135.01,148.54 134.88,148.67 133.99,148.67 133.87,148.54 133.87,147.55 133.7,147.38 133.42,147.38 133.33,147.47 133.33,148.49 133.21,148.62 132.86,148.62 132.74,148.49 132.74,147.59 131.96,146.81 131.78,146.81 131.58,147.02 131.58,147.2 132.04,147.66 132.04,148.21 130.75,149.5 125.96,149.5 104.02,171.44 97.57,171.44 97.36,171.23
  BOTTOM w0.102: v4(134.36,147.59) 134.35,147.58 v1(134.35,146.69)
M_DATA_A41: length 67.2
  TOP w0.102: CPU2.BA36 v1(91.4,169.84) ; v1(132.69,143.93) 132.51,143.75 DIMM1.149
  L3 w0.089: v1(91.4,169.84) 91.4,169.7 91.65,169.44 93.96,169.44 94.17,169.65 96.8,169.65 97.04,169.89
  L3 w0.127: 97.04,169.89 103.31,169.89 126.03,147.17 127.54,147.17 129.8,144.91 129.8,144.73 129.6,144.53 129.42,144.53 127.36,146.59 127.14,146.59 126.98,146.43 126.98,146.21 129.27,143.93 130.26,143.93 130.39,144.05 130.39,144.87 130.51,144.99 131.94,144.99 132.06,144.87 132.06,144.59 131.94,144.46 131.07,144.46 130.94,144.33 130.94,144.05 131.07,143.93 v1(132.69,143.93)
  BOTTOM w0.102: v4(131.65,143.9) 131.68,143.93 v1(132.69,143.93)
M_DATA_A42: length 67
  TOP w0.102: v1(134.37,140.54) 133.56,141.35 DIMM1.157 ; CPU2.AU34 v1(89.26,167.93)
  L3 w0.089: 94.34,168.52 89.81,168.52 89.54,168.47 89.26,168.2 v1(89.26,167.93)
  L3 w0.127: 94.34,168.52 94.87,167.99 102.32,167.99 104.5,165.81 104.5,165.41 127.86,142.05 128.69,141.22 128.95,141.22 129.33,141.6 130.06,141.6 130.16,141.5 130.16,141.05 130.26,140.94 130.87,140.94 130.97,141.05 130.97,141.5 131.07,141.6 132.47,141.6 132.6,141.48 132.6,141.32 132.87,141.05 133.21,141.05 133.33,141.17 133.33,141.43 133.46,141.55 133.63,141.55 134.17,141.38 134.22,141.37 134.39,141.2 134.6,141.12 134.96,140.99 135.16,140.92 135.34,140.74 135.34,140.46 135.21,140.34 135.07,140.34 134.86,140.12 134.49,140.12 134.37,140.23 v1(134.37,140.54)
  BOTTOM w0.102: v1(134.37,140.54) 134.37,141.4 134.27,141.51 v4(134.27,141.53)
M_DATA_A43: length 66.7
  TOP w0.102: v1(136,140.59) 136.46,141.05 DIMM1.158 ; CPU2.AU32 v1(89.26,166.94)
  L3 w0.089: v1(89.26,166.94) 89.85,167.53 93.97,167.53 94.12,167.38
  L3 w0.127: 94.12,167.38 101.68,167.38 103.59,165.47 103.59,164.57 103.72,164.44 103.83,164.44 129.46,138.81 132.28,138.81 132.43,138.96 132.43,139.33 132.69,139.59 135.08,139.59 135.3,139.8 135.91,139.8 136.23,140.12 136.23,140.46 136.1,140.59 v1(136,140.59)
  BOTTOM w0.102: v1(136,140.59) 136.76,139.83 v4(137.19,139.83)
M_DATA_A44: length 66
  TOP w0.102: v1(136.34,144.14) 136.54,144.14 136.86,144.45 138.07,144.45 138.27,144.65 DIMM1.146 ; CPU2.BF36 93.14,169.45 v1(93.53,169.84)
  L3 w0.089: 96.59,170.13 96.31,169.84 v1(93.53,169.84)
  L3 w0.127: 96.59,170.13 97.46,170.13 98.31,170.98 103.27,170.98 104.91,169.34 104.91,169.04 125.73,148.22 126.38,148.22 126.51,148.1 126.51,147.98 126.63,147.85 126.91,147.85 127.04,147.98 127.04,148.1 127.17,148.22 128.75,148.22 130.5,146.47 130.5,146.24 130.35,146.09 130.13,146.09 128.53,147.68 128.31,147.68 128.15,147.53 128.15,147.31 129.93,145.53 132.16,145.53 132.25,145.43 134.58,145.43 135.68,144.34 136.01,144.34 136.21,144.14 v1(136.34,144.14)
  BOTTOM w0.102: v4(135.52,144.13) 135.53,144.14 v1(136.34,144.14)
M_DATA_A45: length 65.5
  TOP w0.102: DIMM1.148 138.04,144.05 137.96,143.97 v1(137.94,143.97) ; CPU2.BD36 v1(92.82,169.84)
  L3 w0.089: v1(92.82,169.84) 93.22,170.24 94.54,170.24
  L3 w0.102: 94.54,170.24 94.67,170.37 96.99,170.37
  L3 w0.127: v1(137.94,143.97) 138.06,143.97 138.18,144.09 138.18,146.02 138.06,146.15 131.58,146.15 129.8,147.93 129.8,148.15 129.95,148.31 130.18,148.31 130.95,147.53 131.13,147.53 131.33,147.73 131.33,147.91 130.35,148.89 125.81,148.89 103.5,171.21 97.83,171.21 96.99,170.37
  BOTTOM w0.102: v1(137.94,143.97) v4(138.84,143.97)
M_DATA_A46: length 67
  TOP w0.102: v1(133.56,140.56) 133.1,141.02 132.57,141.02 132.3,140.75 DIMM1.159 ; CPU2.AV34 v1(89.97,167.93)
  L3 w0.089: v1(89.97,167.93) 90.37,168.33 93.92,168.33 94.11,168.14
  L3 w0.127: 94.11,168.14 94.11,167.9 94.29,167.71 102.1,167.71 104.12,165.69 104.12,164.91 128.91,140.12 129.04,140.12 129.17,140.25 129.17,140.69 129.29,140.82 129.62,140.82 129.75,140.69 129.75,139.52 129.87,139.4 130.34,139.4 130.46,139.52 130.46,140.28 130.59,140.41 130.94,140.41 131.07,140.28 131.07,139.45 131.17,139.34 131.55,139.34 131.66,139.45 131.66,140.94 131.78,141.07 132.09,141.07 132.21,140.94 132.21,140.26 132.34,140.13 133.48,140.13 133.61,140.26 133.61,140.51 v1(133.56,140.56)
  BOTTOM w0.102: v4(132.95,141.48) 133.08,141.48 133.56,141 v1(133.56,140.56)
M_DATA_A47: length 67.2
  TOP w0.102: v1(89.97,166.94) 89.62,167.3 CPU2.AV32 ; DIMM1.160 v1(137.93,140.45)
  L3 w0.089: v1(89.97,166.94) 90.37,167.34 93.82,167.34 94.14,167.03
  L3 w0.127: 94.14,167.03 101.28,167.03 103.06,165.25 103.06,164.19 103.18,164.06 103.46,164.06 129.24,138.28 135.12,138.28 135.39,138.55 135.39,139.14 135.52,139.27 136.53,139.27 136.66,139.4 136.66,139.8 136.79,139.93 137.27,139.93 137.4,139.8 137.4,139.4 137.52,139.27 138.16,139.27 138.26,139.37 138.26,140.34 138.14,140.45 v1(137.93,140.45)
  BOTTOM w0.102: v4(138.72,140.59) 138.7,140.6 138.08,140.6 v1(137.93,140.45)
M_DATA_A48: length 63.1
  TOP w0.102: DIMM1.163 132.26,139.55 132.67,139.14 v1(132.88,139.14) ; CPU2.BF34 v1(93.53,167.93)
  L4 w0.127: v1(93.53,167.93) 94.09,167.93 94.92,167.1 95.67,167.1 98.65,164.12 102.82,164.12 123.33,143.62 123.33,143.44 123.15,143.26 123.15,143.08 123.35,142.88 123.53,142.88 123.71,143.06 123.89,143.06 124.08,142.86 124.08,142.68 123.9,142.5 123.9,142.32 124.1,142.12 124.28,142.12 124.46,142.3 124.64,142.3 124.84,142.11 124.84,141.93 124.66,141.75 124.66,141.57 124.85,141.37 125.03,141.37 125.21,141.55 125.39,141.55 125.59,141.35 125.59,141.17 125.41,140.99 125.41,140.81 125.61,140.62 125.79,140.62 125.97,140.8 126.15,140.8 126.43,140.51 126.96,140.51 127.09,140.39 127.09,140 127.22,139.88 127.5,139.88 127.62,140 127.62,140.39 127.75,140.51 128.03,140.51 128.16,140.39 128.16,140 128.29,139.88 128.56,139.88 128.69,140 128.69,140.39 128.82,140.51 129.1,140.51 129.23,140.39 129.23,140 129.35,139.88 129.63,139.88 129.76,140 129.76,140.39 129.89,140.51 130.26,140.51 130.39,140.39 130.39,139.42 130.51,139.29 130.94,139.29 131.07,139.42 131.07,140.39 131.2,140.51 131.64,140.51 131.77,140.39 131.77,140.18 131.77,139.75 131.9,139.62 132.33,139.62 132.34,139.61 132.61,139.61 132.88,139.34 v1(132.88,139.14)
  BOTTOM w0.102: v4(131.93,139.13) 131.94,139.14 v1(132.88,139.14)
M_DATA_A49: length 64
  TOP w0.102: DIMM1.166 138.58,138.65 138.18,138.25 136.71,138.25 v1(136.25,138.71) ; CPU2.BC34 v1(92.11,167.93)
  L4 w0.102: v1(92.11,167.93) 92.73,168.56 94.26,168.56 94.77,168.05
  L4 w0.127: 94.77,168.05 95.05,167.77 95.73,167.77 97.54,165.95 100.33,165.95 100.46,166.08 100.46,166.29 100.58,166.42 100.84,166.42 100.96,166.29 100.96,166.08 101.09,165.95 101.96,165.95 102.09,165.82 102.09,165.74 102.65,165.18 103.29,165.18 103.47,165 103.53,164.96 103.76,164.83 125.17,143.43 125.87,143.28 126.39,143.15 126.48,143 126.37,142.55 126.46,142.4 126.74,142.33 126.89,142.43 127,142.87 127.15,142.97 134.34,141.2 134.98,140.55 134.98,140.22 135.03,140.17 135.03,139.12 135.44,138.71 v1(136.25,138.71)
  BOTTOM w0.102: v4(135.8,139.7) 135.8,139.17 v1(136.25,138.71)
M_DATA_A50: length 64
  TOP w0.102: v1(90.69,166.94) 91.04,167.3 CPU2.BA32 ; v1(137.91,135.61) 137.95,135.65 DIMM1.176
  L4 w0.089: v1(90.69,166.94) 91.04,166.59 92.11,166.35 93.61,166.35 93.83,166.28 94.37,165.44
  L4 w0.127: 94.37,165.44 94.41,165.26 94.48,165 94.48,164.93 94.69,164.36 94.74,164.31 94.79,164.25 94.93,164.12 94.93,164.12 95.68,163.44 96.85,162.27 97.62,161.72 98.14,161.54 99.82,161.07 105.99,157.67 118.25,145.41 118.25,144.1 119.33,143.02 121.11,141.1 124.16,138.29 126.18,137.05 126.84,136.9 126.99,136.85 128.58,136.5 134.65,136.5 135.44,136.42 135.62,136.37 v1(137.91,135.61)
  BOTTOM w0.102: v1(137.91,135.61) 138.07,135.46 139.22,135.46 139.36,135.59 v4(139.36,135.92)
M_DATA_A51: length 64.5
  TOP w0.102: DIMM1.177 132.66,135.35 v1(132.67,135.36) ; v1(92.82,165.95) 92.46,166.31 CPU2.BD30
  L4 w0.127: v1(92.82,165.95) 92.82,164.74 97.19,160.37 98.96,159.86 100.83,159.29 105.34,156.81 111.65,150.5 111.65,150.32 111.01,149.68 111.01,149.5 111.2,149.31 111.38,149.31 112.02,149.95 112.2,149.95 112.4,149.75 112.4,149.57 111.76,148.93 111.76,148.75 111.96,148.55 112.14,148.55 112.78,149.19 112.96,149.19 113.15,148.99 113.15,148.81 112.52,148.17 112.52,148 112.71,147.8 112.89,147.8 113.53,148.44 113.71,148.44 113.91,148.24 113.91,148.06 113.27,147.42 113.27,147.24 113.47,147.04 113.65,147.04 114.29,147.68 114.47,147.68 114.84,147.3 114.84,145.65 116.11,144.38 116.45,144.38 118.56,142.28 120.36,140.34 123.52,137.44 125.77,136.05 126.55,135.87 126.7,135.82 127.1,135.73 127.47,135.36 v1(132.67,135.36)
  BOTTOM w0.102: v4(131.88,136.09) 132.62,135.36 v1(132.67,135.36)
M_DATA_A52: length 63.7
  TOP w0.102: CPU2.BD34 v1(92.82,167.93) ; DIMM1.165 132.08,138.95 132.39,138.63 134.04,138.63 v1(134.5,139.09)
  L4 w0.102: 94.07,168.34 93.23,168.34 v1(92.82,167.93)
  L4 w0.127: 94.07,168.34 94.97,167.44 95.74,167.44 97.74,165.43 100.41,165.43 101.12,164.72 102.98,164.72 126.65,141.05 127.22,141.05 127.34,141.17 127.34,142.11 127.47,142.24 127.75,142.24 127.88,142.11 127.88,141.17 128,141.05 128.28,141.05 128.41,141.17 128.41,141.78 128.54,141.91 128.82,141.91 128.94,141.78 128.94,141.17 129.07,141.05 129.73,141.05 129.86,141.17 129.86,141.25 129.99,141.38 130.26,141.38 130.39,141.25 130.39,141.17 130.52,141.05 131.66,141.05 131.71,141.1 132.18,141.1 132.3,140.97 132.3,140.4 132.56,140.14 132.83,140.14 132.86,140.12 134.08,140.12 134.5,139.7 v1(134.5,139.09)
  BOTTOM w0.102: v4(134.02,139.83) 134.5,139.34 v1(134.5,139.09)
M_DATA_A53: length 61.4
  TOP w0.102: CPU2.BA34 v1(91.4,167.93) ; v2(137.9,138.71) 138.44,139.25 DIMM1.164
  L4 w0.102: v1(91.4,167.93) 91.94,168.34 92.85,168.88 94.44,168.88
  L4 w0.127: 94.44,168.88 95.19,168.42 96.9,167.59 97.7,167.27 100.31,167.02 101.83,166.51 104.08,165.27 125.43,143.92 125.99,143.8 134.61,141.69 135.52,140.78 135.52,140.44 135.89,140.07 v2(137.9,138.71)
  BOTTOM w0.102: v4(138.95,138.9) 138.09,138.9 v2(137.9,138.71)
M_DATA_A54: length 65.2
  TOP w0.102: DIMM1.174 136.89,136.25 136.02,135.38 v1(135.85,135.38) ; CPU2.BF30 v1(93.53,165.95)
  L4 w0.127: v1(135.85,135.38) 135.34,135.89 127.69,135.89 127.36,136.22 126.84,136.33 126.7,136.39 125.97,136.55 123.84,137.87 120.73,140.72 118.94,142.65 117.71,143.88 117.71,145.19 117.34,145.57 117.16,145.57 116.51,144.92 116.33,144.92 116.13,145.12 116.13,145.3 116.78,145.94 116.78,146.12 116.58,146.32 116.4,146.32 115.75,145.67 115.57,145.67 115.38,145.87 115.38,146.05 116.02,146.7 116.02,146.88 105.66,157.24 101.04,159.78 98.98,160.42 96.8,161.09 93.53,164.35 v1(93.53,165.95)
  BOTTOM w0.102: v4(135.09,135.9) 135.61,135.38 v1(135.85,135.38)
M_DATA_A55: length 63.9
  TOP w0.102: CPU2.BD28 92.4,165.66 v1(92.11,165.95) ; v1(134.29,135.34) 133.68,135.95 DIMM1.175
  L4 w0.127: v1(92.11,165.95) 92.59,164.65 93.14,164.1 97.05,160.18 98.2,159.53 98.81,159.35 100.63,158.8 100.73,158.74 108.39,151.08 108.57,151.08 109.15,151.66 109.33,151.66 109.53,151.46 109.53,151.28 108.95,150.7 108.95,150.52 109.15,150.32 109.33,150.32 109.91,150.9 110.09,150.9 110.29,150.71 110.29,150.53 109.7,149.94 109.7,149.76 124.64,134.82 133.77,134.82 v1(134.29,135.34)
  BOTTOM w0.102: v4(133.72,136.07) 133.72,135.91 v1(134.29,135.34)
M_DATA_A56: length 62.3
  TOP w0.089: 95.85,168.1 95.85,168.1 95,168.1 CPU2.BJ33
  TOP w0.102: 95.85,168.1 96.16,167.79 96.87,167.79 98.02,166.64 98.02,166.23 98.39,165.86 100.77,165.86 100.9,165.74 v1(100.9,165.53) ; v1(132.7,134.26) 132.65,134.26 132.53,134.15 DIMM1.181
  L3 w0.127: v1(100.9,165.53) 100.97,165.61 101.18,165.61 101.3,165.48 101.3,165.07 101.43,164.94 101.81,164.94 101.94,164.81 101.94,164.56 101.81,164.43 101.58,164.43 101.46,164.3 101.46,163.79 128.47,136.78 128.48,136.78 128.88,136.37 129.22,136.37 129.52,136.68 129.67,136.68 129.9,136.45 129.9,136.27 129.42,135.79 129.42,135.61 129.6,135.43 129.88,135.43 131.12,136.68 131.45,136.68 131.63,136.5 131.63,136.32 130.54,135.23 130.54,135.05 130.69,134.9 130.97,134.9 131.3,135.23 131.56,135.23 131.69,135.09 131.69,134.86 131.55,134.72 131.55,134.54 131.73,134.37 132.59,134.37 v1(132.7,134.26)
  BOTTOM w0.102: v4(131.83,134.8) 132.37,134.26 v1(132.7,134.26)
M_DATA_A57: length 63.1
  TOP w0.089: 94.98,166.26 94.66,166.26 94.42,166.03 94.13,166.03 CPU2.BG29
  TOP w0.102: 94.98,166.26 96.65,164.59 v1(97.57,164.59) ; v1(137.1,130) 137.24,130 137.74,130.49 138.38,130.49 138.62,130.25 DIMM1.194
  L3 w0.127: v1(97.57,164.59) 97.99,164.17 97.99,161.49 100.07,159.41 125.13,134.35 128.92,130.56 136.55,130.56 v1(137.1,130)
  BOTTOM w0.102: v4(96.86,164.72) 97.44,164.72 v1(97.57,164.59)
M_DATA_A58: length 62.2
  TOP w0.089: 96.34,168.49 96.32,168.5 94.53,168.5 CPU2.BH34
  TOP w0.102: v1(99.86,166.5) 97.86,168.49 96.34,168.49 ; v1(136.2,134.34) 136.61,134.74 138.19,134.74 138.48,134.45 DIMM1.180
  L3 w0.127: v1(136.2,134.34) 136.2,134.35 134.25,136.3 134.25,136.48 134.4,136.63 134.4,136.81 134.2,137 134.02,137 133.87,136.86 133.69,136.86 133.24,137.31 132.73,137.31 132.29,137.74 129.02,137.74 102.56,164.21 102.56,165.22 101.47,166.31 101.37,166.31 101.18,166.5 v1(99.86,166.5)
  BOTTOM w0.102: v4(137.37,135.03) 137.16,134.82 136.51,134.82 136.2,134.51 v1(136.2,134.34)
M_DATA_A59: length 62.5
  TOP w0.089: CPU2.BG32 94.01,167.43 94.29,167.72 94.57,167.72 94.64,167.64 94.99,167.64 95.24,167.9
  TOP w0.102: 95.24,167.9 95.76,167.9 96.09,167.56 96.53,167.56 v7(96.83,167.26) 96.93,167.16 96.93,167.15 v1(97.57,166.52) ; v1(134.42,134.37) 134.42,134.26 133.71,133.55 DIMM1.183
  L3 w0.127: v1(134.42,134.37) 133.96,134.83 133.07,134.83 133,134.91 132.37,134.91 132.22,135.05 132.22,135.54 132.48,135.8 133.21,135.8 133.33,135.93 133.33,136.47 133.02,136.78 132.5,136.78 132.07,137.21 130.84,137.21 130.64,137.01 130.28,137.01 130.08,137.21 128.8,137.21 128.7,137.31 128.69,137.31 103.11,162.89 103.11,162.91 102.26,163.75 102.26,165.19 101.37,166.08 99.46,166.08 98.75,166.79 98.1,166.79 97.84,166.52 v1(97.57,166.52)
M_DATA_A60: length 64.1
  TOP w0.089: CPU2.BG28 94,165.48 94.31,165.78 94.55,165.78 94.71,165.63
  TOP w0.102: v1(133.76,129.92) 133.64,129.92 133.01,130.55 DIMM1.193 ; 94.71,165.63 94.99,165.63 96.74,163.88 96.95,163.88 97.54,163.29 v1(97.54,163.06)
  L3 w0.127: v1(133.76,129.92) 133.61,129.92 132.7,129.01 132.16,129.01 132.04,129.13 132.04,129.59 131.91,129.72 131.63,129.72 131.5,129.59 131.5,129.13 131.38,129.01 131.1,129.01 130.97,129.13 130.97,129.59 130.84,129.72 130.56,129.72 130.44,129.59 130.44,129.13 130.31,129.01 127.9,129.01 126,130.9 126,132.72 124.91,133.81 99.69,159.04 99.06,159.66 98.84,159.66 97.54,160.97 v1(97.54,163.06)
  BOTTOM w0.102: v1(97.54,163.06) 97.86,163.06 v4(98.2,162.71)
M_DATA_A61: length 63.3
  TOP w0.102: v1(99.73,163.7) 99.35,164.08 v3(98.79,164.08) 96.87,164.08 95.1,165.86 94.93,165.86 CPU2.BJ29 ; v1(134.58,131.55) 135.27,130.85 DIMM1.192
  L3 w0.127: v1(99.73,163.7) 99.73,162.01 127.16,134.58 127.16,134.4 126.96,134.2 126.96,134.02 127.16,133.83 127.34,133.83 127.53,134.02 127.71,134.02 127.91,133.82 127.91,133.64 127.72,133.45 127.72,133.27 127.91,133.07 128.09,133.07 128.29,133.27 128.47,133.27 128.67,133.07 128.67,132.89 128.47,132.7 128.47,132.52 128.67,132.32 128.85,132.32 129.04,132.51 129.22,132.51 129.41,132.32 129.41,131.93 129.54,131.8 129.81,131.8 130.04,132.03 130.24,132.03 130.37,131.9 130.37,131.75 130.49,131.62 130.77,131.62 130.9,131.75 130.9,131.9 131.03,132.03 134.09,132.03 v1(134.58,131.55)
M_DATA_A62: length 64.6
  TOP w0.102: v1(96.81,163.45) 96.27,163.99 96.27,164 94.97,165.3 94.61,165.3 CPU2.BH28 ; DIMM1.191 132.6,131.15 132.81,130.94 134.25,130.94 v1(135.19,130)
  L3 w0.127: v1(96.81,163.45) 96.81,160.83 125.38,132.26 125.38,130.73 127.68,128.44 134.06,128.44 135.19,129.57 v1(135.19,130)
  BOTTOM w0.102: v1(96.81,163.45) 96.76,163.4 v4(96.76,162.74)
M_DATA_A63: length 62.2
  TOP w0.089: CPU2.BG33 94.24,168.09 94.54,168.09 94.75,168.3 95.72,168.3
  TOP w0.102: v1(98.46,166.37) 98.46,166.49 96.78,168.17 96.13,168.17 95.99,168.3 95.73,168.3 95.72,168.3 ; v1(137.94,134.31) 137.94,134.19 138.28,133.85 DIMM1.182
  L3 w0.127: v1(98.46,166.37) 99.05,165.77 99.49,165.77 100.17,165.09 100.64,165.09 100.88,164.84 100.88,163.39 129.9,134.37 130.68,134.37 131.23,133.82 134.33,133.82 134.52,133.79 134.63,133.76 137.35,133.76 137.9,134.31 v1(137.94,134.31)
  BOTTOM w0.102: v4(138.64,134.84) 138.39,134.84 137.94,134.39 v1(137.94,134.31)
M_DQS_A_DN0: length 72.1
  TOP w0.089: 86.48,178.47 86.48,177.77 86.7,177.55 86.7,177.31 86.4,177.01 CPU2.AM51
  TOP w0.102: v1(135.03,188.13) 135.29,188.39 135.29,188.46 135.63,188.8 136.63,188.8 137.58,187.85 DIMM1.10 ; 86.48,178.47 86.48,178.56 87.09,179.17 87.09,179.63 87.41,179.95 87.41,182.08 88.46,183.14 88.75,183.14 v1(88.94,182.94)
  L4 w0.089: 91.21,187.91 88.2,184.9 88.2,183.51 88.45,183.26 88.51,183.2 88.77,182.94 v1(88.94,182.94)
  L4 w0.127: v1(135.03,188.13) 134.87,188.13 134.31,187.56 132.21,187.56 130.25,189.52 129.34,189.52 128.98,189.89 127.54,189.89 127.18,189.52 126.27,189.52 126.19,189.6 126.14,189.65 126.14,190.33 125.77,190.7 125.22,190.7 124.85,190.33 124.85,189.65 124.72,189.52 124.21,189.52 124.08,189.65 124.08,190.59 123.81,190.86 123.06,190.86 122.79,190.59 122.79,189.65 122.66,189.52 122.15,189.52 122.03,189.65 122.03,190.72 121.74,191.01 98.72,191.01 97.24,189.52 97.15,189.52 95.69,188.06 91.37,188.06 91.21,187.91
  BOTTOM w0.102: v1(135.03,188.13) 134.92,188.13 v4(134.47,187.68)
M_DQS_A_DN1: length 79
  TOP w0.102: DIMM1.27 132.09,182.75 132.33,182.51 132.85,182.51 133.21,182.64 133.83,182.64 134.07,182.39 134.07,182.13 v2(134.38,181.79) ; CPU2.AV48 v1(89.82,175.82)
  L3 w0.089: v1(89.82,175.82) 89.55,175.82 89.42,175.95 89.42,176.96 90.08,177.62 90.08,179.68 89.94,179.83 89.94,185.34 89.97,185.38 89.97,185.39
  L3 w0.127: v2(134.38,181.79) 134.15,181.79 133.51,181.15 132.32,181.15 118.41,195.07 108.11,195.07 107.82,195.36 107.82,195.68 107.7,195.81 107.19,195.81 107.06,195.68 107.06,195.36 106.78,195.07 106.05,195.07 105.77,195.36 105.77,195.88 105.64,196.01 105.13,196.01 105,195.88 105,195.36 104.72,195.07 103.99,195.07 103.71,195.36 103.71,195.88 103.58,196.01 103.07,196.01 102.95,195.88 102.95,195.36 102.66,195.07 101.68,195.07 100.75,196.01 92.85,196.01 91.92,195.07 91.91,195.07 90.74,193.9 90.68,193.84 90.68,187.35 89.97,186.64 89.97,185.39
  BOTTOM w0.102: v4(134.59,182.53) 134.38,182.32 v2(134.38,181.79)
M_DQS_A_DN2: length 71.8
  TOP w0.102: CPU2.AT41 v1(88.83,172.26) ; DIMM1.45 132.24,177.35 132.37,177.22 132.37,177.01 132.51,176.87 133.84,176.87 133.94,176.98 v1(133.94,177.11)
  L4 w0.089: v1(88.83,172.26) 88.48,172.26 88.35,172.39 88.35,172.64 88.43,172.73 88.43,173.1 88.24,173.3 88.24,173.45 88.24,176.77 90.52,179.06 91.29,179.06 92,179.77 93.68,179.77 94.41,180.5 95.44,180.5 95.48,180.54 95.51,180.54
  L4 w0.127: 95.51,180.54 96.8,180.54 99.46,183.2 117.1,183.2 123.39,176.91 124.15,176.91 124.28,177.04 124.28,179.41 124.64,179.77 125.21,179.77 125.57,179.41 125.57,177.04 125.7,176.91 126.21,176.91 126.33,177.04 126.33,178.93 126.69,179.29 127.27,179.29 127.63,178.93 127.63,177.04 127.76,176.91 128.3,176.91 128.43,177.04 128.43,177.49 128.71,177.77 129.26,177.77 129.75,177.28 129.75,177.04 129.88,176.91 133.75,176.91 v1(133.94,177.11)
  BOTTOM w0.102: v4(132.86,176.32) 132.89,176.34 133.17,176.34 133.94,177.11 v1(133.94,177.11)
M_DQS_A_DN3: length 66
  TOP w0.089: 90.98,179.22 90.48,178.73 90.48,177.66 90.7,177.44 90.7,177.15 CPU2.BA51
  TOP w0.102: v1(93.49,182.94) 93.08,182.94 92.66,182.52 92.66,180.91 90.98,179.22 ; DIMM1.62 138.34,172.25 137.89,172.71 136.65,172.71 v1(136.18,172.24)
  L3 w0.089: 94.61,185.04 94.23,184.66 94.23,183.68 v1(93.49,182.94)
  L3 w0.127: 94.61,185.04 94.94,185.37 96.1,185.37 96.77,186.04 96.77,186.4 97.07,186.71 97.44,186.71 97.87,187.13 97.87,187.5 98.17,187.8 98.54,187.8 99.6,188.87 115.77,188.87 131.95,172.69 134.73,172.69 134.84,172.81 135.6,172.81 135.91,173.11 136.24,173.11 136.33,173.03 136.33,172.38 v1(136.18,172.24)
  BOTTOM w0.102: v1(136.18,172.24) 136.18,171.71 136.38,171.51 v4(136.38,171.51)
M_DQS_A_DN4: length 58.5
  TOP w0.089: CPU2.BG39 94.33,170.83 94.52,171.02 94.55,171.02 94.67,171.14 95.14,171.14 95.23,171.23 95.6,171.23 95.8,171.03 96.14,171.03 96.16,171.01
  TOP w0.102: v1(98.68,170.41) 98.86,170.41 99.09,170.64 99.09,170.84 98.93,171.01 96.16,171.01 ; v1(135.34,147.68) 135.12,147.46 133.91,147.46 133.8,147.57 132.57,147.57 132.44,147.7 132.44,147.82 132.32,147.95 DIMM1.135
  L4 w0.127: v1(98.68,170.41) 98.66,170.41 98.53,170.28 98.53,170.08 98.66,169.95 99.83,169.95 100.08,169.83 100.18,169.78 100.34,169.78 100.49,169.76 100.84,169.72 103.64,169.72 104.21,169.5 104.24,169.49 104.93,169.07 105.22,168.9 105.32,168.85 105.51,168.73 106.13,168.37 106.13,168.37 125.7,148.8 128.34,147.52 128.39,147.5 134.18,147.5 134.42,147.74 134.86,147.74 135.32,147.7 v1(135.34,147.68)
  BOTTOM w0.102: v4(135.9,146.12) 135.78,146.24 135.78,146.99 135.34,147.42 v1(135.34,147.68)
M_DQS_A_DN5: length 65
  TOP w0.102: CPU2.AT34 v1(87.84,167.93) ; v1(136.29,141.85) 136.47,141.85 136.69,142.06 136.69,142.22 137.18,142.71 137.98,142.71 138.12,142.85 DIMM1.152
  L3 w0.089: 97.46,168.59 97.35,168.59 97.31,168.55 94.99,168.55 94.62,168.92 94.11,168.92 94.11,168.92 91.33,168.92 91.33,168.92 89.9,168.92 89.86,168.92 88.64,168.7 88.54,168.64 87.84,167.94 v1(87.84,167.93)
  L3 w0.127: 97.46,168.59 102.77,168.59 128.73,142.63 133.63,142.63 134.85,142.25 135.04,142.06 136.11,141.67 v1(136.29,141.85)
  BOTTOM w0.102: v1(136.29,141.85) 135.83,141.38 v4(135.67,141.38)
M_DQS_A_DN6: length 62.9
  TOP w0.102: CPU2.BC32 91.7,167.39 91.7,167.21 91.8,167.11 91.8,167.06 91.92,166.94 v1(92.11,166.94) ; DIMM1.169 132.21,137.75 132.34,137.63 132.34,137.16 132.43,137.06 133.88,137.06 134.2,137.38 134.22,137.43 134.22,137.57 134.17,137.62 134.17,137.69 134.06,137.8 v1(133.72,137.8)
  L4 w0.089: 94.29,166.92 94.29,166.99 93.93,167.34 91.93,167.34 91.8,167.22 91.8,167.07 91.93,166.94 v1(92.11,166.94)
  L4 w0.127: 94.29,166.92 96.64,164.57 96.64,164.55 98.2,162.99 99.43,162.99 99.61,162.81 100.43,162.81 100.6,162.99 102.5,162.99 121.09,144.4 122.12,143.37 122.12,142.65 125.29,139.48 126.16,139.48 126.79,138.85 127.19,138.85 127.31,138.72 127.31,138.51 127.6,138.23 128.32,138.23 128.61,138.51 128.61,138.72 128.73,138.85 129.24,138.85 129.37,138.72 129.37,138.51 129.5,138.38 129.65,138.23 132.6,138.23 132.65,138.28 133.69,138.28 133.89,138.07 133.89,137.97 v1(133.72,137.8)
  BOTTOM w0.102: v1(133.72,137.8) 133.72,138.09 v4(133.26,138.55)
M_DQS_A_DN7: length 63
  TOP w0.089: 95.68,167.22 95.65,167.25 95.64,167.25 94.67,167.25 94.38,166.96 94.36,166.94 CPU2.BG31
  TOP w0.102: DIMM1.186 137.98,132.65 137.9,132.56 137.07,132.56 136.57,132.07 136.57,131.7 v1(136.31,131.45) ; 95.68,167.22 95.85,167.05 95.99,166.9 97.46,165.44 99.13,165.44 99.57,165 v1(99.57,164.69)
  L3 w0.127: v1(99.57,164.69) 100.19,164.07 100.19,162.62 129.48,133.34 130.26,133.34 130.8,132.79 134.27,132.79 135.89,132.3 136.31,131.87 v1(136.31,131.45)
  BOTTOM w0.102: v1(99.57,164.69) 99.02,164.14 v4(99.02,164.11)
M_DQS_A_DP0: length 72.1
  TOP w0.089: CPU2.AM52 86.28,177.55 86.28,177.64
  TOP w0.102: DIMM1.12 138.28,187.25 138.13,187.4 138.13,187.53 138.03,187.63 137.49,187.63 136.55,188.58 135.72,188.58 135.56,188.43 135.56,188.37 v1(135.84,188.09) ; 86.28,177.64 86.28,178.37 86.26,178.39 86.26,178.65 86.87,179.26 86.87,179.72 87.19,180.04 87.19,182.17 88.38,183.36 88.65,183.36 v1(88.94,183.66)
  L4 w0.089: v1(88.94,183.66) 88.94,183.5 88.77,183.33 88.65,183.33 88.39,183.59 88.39,184.82 91.27,187.7 91.3,187.7 91.31,187.71 91.39,187.71 91.4,187.72
  L4 w0.127: v1(135.84,188.09) 135.84,187.83 135.7,187.69 134.81,187.69 134.42,187.3 132.1,187.3 131.98,187.42 130.14,189.26 129.23,189.26 128.87,189.62 127.66,189.62 127.29,189.26 126.16,189.26 126,189.41 125.87,189.54 125.87,190.22 125.66,190.44 125.33,190.44 125.11,190.22 125.11,189.54 124.83,189.26 124.1,189.26 123.82,189.54 123.82,190.47 123.7,190.59 123.17,190.59 123.05,190.47 123.05,189.54 122.77,189.26 122.04,189.26 121.76,189.54 121.76,190.61 121.63,190.74 98.83,190.74 97.35,189.26 97.26,189.26 95.8,187.79 91.48,187.79 91.4,187.72
  BOTTOM w0.102: v4(136.39,188.57) 135.91,188.09 v1(135.84,188.09)
M_DQS_A_DP1: length 79
  TOP w0.102: v1(89.82,175.11) CPU2.AV47 ; v2(133.52,181.84) 133.72,181.84 133.86,181.97 133.86,182.3 133.74,182.42 133.24,182.42 132.89,182.3 132.27,182.3 132.12,182.15 DIMM1.29
  L3 w0.089: v1(89.82,175.11) 89.23,175.7 89.23,177.04 89.89,177.7 89.89,179.6 89.75,179.75 89.75,185.34 89.71,185.38 89.71,185.39
  L3 w0.127: 89.71,185.39 89.71,186.75 90.42,187.46 90.42,193.95 90.48,194.01 91.8,195.34 92.74,196.27 100.86,196.27 101.79,195.34 102.55,195.34 102.68,195.47 102.68,195.99 102.96,196.27 103.69,196.27 103.98,195.99 103.98,195.47 104.1,195.34 104.61,195.34 104.74,195.47 104.74,195.99 105.02,196.27 105.75,196.27 106.03,195.99 106.03,195.47 106.16,195.34 106.67,195.34 106.8,195.47 106.8,195.79 107.08,196.08 107.81,196.08 108.09,195.79 108.09,195.47 108.22,195.34 117.66,195.34 118.52,195.34 132.43,181.42 133.4,181.42 133.52,181.54 v2(133.52,181.84)
  BOTTOM w0.102: v4(133.02,182.48) 133.04,182.48 133.52,182 v2(133.52,181.84)
M_DQS_A_DP2: length 71.4
  TOP w0.102: v1(134.76,177.09) 134.42,176.87 134.03,176.66 132.42,176.66 132.32,176.75 DIMM1.47 ; CPU2.AT42 v1(88.83,172.97)
  L4 w0.089: v1(88.83,172.97) 88.62,173.18 88.43,173.37 88.43,176.7 90.6,178.87 91.37,178.87 92.08,179.58 93.76,179.58 94.49,180.31 95.44,180.31 95.48,180.27 95.51,180.27
  L4 w0.127: v1(134.76,177.09) 134.31,176.64 129.77,176.64 129.48,176.93 129.48,177.17 129.15,177.51 128.82,177.51 128.69,177.38 128.69,176.93 128.41,176.64 127.65,176.64 127.36,176.93 127.36,178.82 127.16,179.02 126.8,179.02 126.6,178.82 126.6,176.93 126.32,176.64 125.59,176.64 125.31,176.93 125.31,179.3 125.1,179.5 124.75,179.5 124.54,179.3 124.54,176.93 124.26,176.64 123.28,176.64 116.99,182.93 99.57,182.93 96.92,180.27 95.51,180.27
  BOTTOM w0.102: v1(134.76,177.09) 134.76,176.88 v4(134.18,176.3)
M_DQS_A_DP3: length 65.9
  TOP w0.089: CPU2.AY52 90.29,177.43 90.29,178.8 90.78,179.29 90.78,179.3 90.82,179.34 90.82,179.37 90.82,179.37
  TOP w0.102: v1(136.99,172.26) 137.23,172.49 137.8,172.49 138.27,172.02 138.27,171.78 138.4,171.65 DIMM1.64 ; 90.82,179.37 92.45,181 92.45,182.61 v1(93.49,183.66)
  L3 w0.089: 94.4,185.21 94.4,185.1 94.04,184.74 94.04,183.76 93.86,183.59 93.56,183.59 v1(93.49,183.66)
  L3 w0.127: v1(136.99,172.26) 136.82,172.26 136.6,172.48 136.6,173.14 136.35,173.38 135.8,173.38 135.49,173.08 134.73,173.08 134.62,172.96 132.06,172.96 115.88,189.13 99.49,189.13 98.43,188.07 98.06,188.07 97.6,187.61 97.6,187.42 97.6,187.24 97.33,186.97 96.96,186.97 96.5,186.51 96.5,186.33 96.5,186.15 95.99,185.64 94.83,185.64 94.4,185.21
  BOTTOM w0.102: v1(136.99,172.26) 137.49,172.26 v4(137.68,172.45)
M_DQS_A_DP4: length 57.6
  TOP w0.089: 96.22,171.22 95.87,171.22 95.67,171.42 95.15,171.42 95.06,171.33 94.44,171.33 CPU2.BH40
  TOP w0.102: v1(136.15,147.65) 135.75,147.25 133.82,147.25 133.71,147.35 132.43,147.35 132.42,147.35 DIMM1.137 ; 96.22,171.22 99.02,171.22 99.31,170.93 99.31,170.52 99.42,170.41 v1(99.5,170.41)
  L4 w0.127: v1(136.15,147.65) 135.59,148.06 135.52,148.12 135.15,148.12 135.04,148.01 134.31,148.01 134.07,147.76 128.46,147.76 125.85,149.02 106.28,168.59 106.25,168.6 105.45,169.08 105.36,169.13 105.07,169.3 104.37,169.72 104.34,169.73 104.33,169.74 103.69,169.99 100.86,169.99 100.35,170.05 100.24,170.05 100.2,170.07 v1(99.5,170.41)
  BOTTOM w0.102: v4(136.66,148.27) 136.15,147.76 v1(136.15,147.65)
M_DQS_A_DP5: length 65
  TOP w0.102: DIMM1.154 138.52,142.25 138.28,142.49 137.27,142.49 136.9,142.13 136.9,142.02 v1(137.11,141.82) ; v1(88.55,167.93) CPU2.AT32
  L3 w0.089: v1(88.55,167.93) 88.55,168.39 88.65,168.49 88.7,168.51 89.89,168.73 89.91,168.73 91.25,168.73 91.25,168.73 94.19,168.73 94.19,168.73 94.54,168.73 94.91,168.36 97.41,168.36 97.45,168.32 97.46,168.32
  L3 w0.127: 97.46,168.32 102.66,168.32 128.62,142.37 133.59,142.37 134.7,142.02 134.89,141.83 136.06,141.4 136.69,141.4 v1(137.11,141.82)
  BOTTOM w0.102: v4(137.57,141.1) 137.57,141.35 v1(137.11,141.82)
M_DQS_A_DP6: length 62.9
  TOP w0.102: CPU2.BC30 v1(91.4,166.94) ; v1(134.6,137.79) 134.39,137.26 133.97,136.84 132.34,136.84 132.04,137.15 DIMM1.171
  L4 w0.089: 94.48,167.11 94.47,167.12 94.42,167.12 94.01,167.53 91.85,167.53 91.61,167.3 v1(91.4,166.94)
  L4 w0.127: v1(134.6,137.79) 134.55,137.79 133.8,138.54 132.54,138.54 132.49,138.49 129.76,138.49 129.69,138.57 129.64,138.62 129.64,138.83 129.35,139.12 128.62,139.12 128.34,138.83 128.34,138.62 128.21,138.49 127.71,138.49 127.58,138.62 127.58,138.83 127.3,139.12 126.9,139.12 126.27,139.75 125.4,139.75 122.39,142.76 122.39,143.48 121.28,144.59 102.61,163.26 100.49,163.26 100.31,163.08 99.72,163.08 99.55,163.26 98.31,163.26 96.91,164.66 96.91,164.68 94.48,167.11
  BOTTOM w0.102: v1(134.6,137.79) 134.6,137.97 v4(135.09,138.45)
M_DQS_A_DP7: length 63
  TOP w0.089: 95.83,167.38 95.77,167.44 95.73,167.44 95.72,167.44 94.59,167.44 94.58,167.44 94.44,167.44 CPU2.BH32
  TOP w0.102: v1(137.13,131.44) 136.79,131.78 136.79,131.98 137.16,132.35 137.83,132.35 138.13,132.05 DIMM1.188 ; v1(100.46,164.67) 100.41,164.72 100.15,164.72 99.22,165.66 97.55,165.66 96.21,166.99 96.06,167.14 96.06,167.14 95.83,167.38
  L3 w0.127: v1(100.46,164.67) 100.46,162.73 129.59,133.6 130.37,133.6 130.91,133.06 134.27,133.06 134.35,133.05 135.96,132.55 136.08,132.49 v1(137.13,131.44)
  BOTTOM w0.102: v4(101.25,164.69) 100.59,164.67 v1(100.46,164.67)
M_MA_DM0: length 70.6
  TOP w0.089: 87.65,179.25 87.31,178.91 87.31,177.68 87.37,177.62 CPU2.AP52
  TOP w0.102: DIMM1.11 132.59,187.55 v1(133.37,188.33) ; v1(88.94,181.52) 87.79,180.37 87.79,179.93 87.79,179.93 87.79,179.39 87.65,179.25
  L4 w0.102: v1(88.94,181.52) 88,182.46 88,185.25 89.02,186.27
  L4 w0.127: 89.02,186.27 91.57,188.82 94.93,188.82 94.94,188.82 95.38,188.82 96.84,190.28 96.92,190.28 98.43,191.8 99.16,191.8 99.28,191.92 99.28,193.01 99.41,193.14 99.69,193.14 99.82,193.01 99.82,191.92 99.94,191.8 105.13,191.8 105.25,191.92 105.25,192.2 105.13,192.33 102.78,192.33 102.65,192.46 102.65,192.74 102.78,192.86 105.66,192.86 105.79,192.74 105.79,191.92 105.91,191.8 121.48,191.8 125.69,191.5 128.73,190.92 130.22,190.64 130.57,190.28 130.57,190.28 132.53,188.33 v1(133.37,188.33)
  BOTTOM w0.102: v1(133.37,188.33) 133.37,188.19 v4(132.93,187.76)
M_MA_DM1: length 81.1
  TOP w0.102: DIMM1.28 139.37,182.42 136.71,182.42 v1(136.08,181.79) ; v1(88.83,175.82) CPU2.AT48
  L3 w0.089: v1(88.83,175.82) 88.43,176.22 88.43,176.7 88.67,176.93 88.7,176.93 89.57,177.8 89.57,179.38
  L3 w0.102: 89.35,185.53 89.35,179.59 89.57,179.38
  L3 w0.127: 89.35,185.53 89.35,187.02 89.66,187.33 89.66,194.27 92.42,197.03 107.93,197.03 108.86,196.1 118.83,196.1 132.32,182.61 133.19,182.61 133.2,182.6 134.73,182.6 134.86,182.73 134.86,182.91 134.98,183.03 136.96,183.03 137.09,182.91 137.09,182.49 136.84,182.25 136.2,182.25 136.08,182.12 v1(136.08,181.79)
  BOTTOM w0.102: v4(136.45,182.39) 136.45,182.16 v1(136.08,181.79)
M_MA_DM2: length 68.5
  TOP w0.102: DIMM1.46 137.66,177.05 v1(136.35,178.36) ; CPU2.AP44 v1(87.84,173.69)
  L4 w0.089: v1(87.84,173.69) 87.44,174.09 87.44,176.7 88.36,177.62 88.6,177.62 88.99,178.01 89,178.01 89.23,178.24 89.23,178.25 89.77,178.79
  L4 w0.102: 94.72,180.82 94.39,180.82 93.63,180.06 91.04,180.06 89.77,178.79
  L4 w0.127: v1(136.35,178.36) 136.58,178.36 136.79,178.16 136.79,177.81 136.58,177.6 135.9,177.6 135.77,177.72 135.77,178.36 135.57,178.56 135.24,178.56 135.03,178.36 135.03,177.88 134.83,177.67 134.26,177.67 134.06,177.87 133.6,177.87 133.58,177.89 133.3,177.89 133.29,177.9 133.1,177.9 133.01,177.81 132.99,177.81 132.85,177.67 130.43,177.67 129.57,178.54 128.6,178.54 128.39,178.74 128.39,179.24 127.59,180.05 126.01,180.05 125.53,180.53 124.32,180.53 123.52,179.72 123.52,178.51 123.31,178.31 123.07,178.31 117.42,183.96 99.08,183.96 95.94,180.82 94.72,180.82
  BOTTOM w0.102: v1(136.35,178.36) 136.35,177.74 136.43,177.67 v4(136.43,177.61)
M_MA_DM3: length 63.4
  TOP w0.089: 91.63,179.37 90.77,178.52 CPU2.BA53
  TOP w0.102: 91.63,179.37 93.03,180.78 93.03,181.06 v1(93.49,181.52) ; v1(133.63,171.45) 133.61,171.45 133.11,171.95 DIMM1.63
  L3 w0.127: v1(93.49,181.52) 93.3,181.52 93.17,181.39 93.17,180.85 93.3,180.72 93.9,180.72 93.93,180.74 94.19,181 94.19,181.46 93.91,181.74 93.91,182.85 94.52,183.46 94.99,183.46 95.21,183.68 95.21,183.92 95.11,184.02 94.75,184.02 94.62,184.15 94.62,184.56 95,184.94 96.53,184.94 98.72,187.13 99.31,187.13 99.45,187.27 99.45,187.64 99.92,188.1 115.46,188.1 132.04,171.53 132.24,171.53 132.65,171.93 133.5,171.93 133.63,171.81 v1(133.63,171.45)
  BOTTOM w0.102: v1(133.63,171.45) 133.63,171.2 133.25,170.83 v4(133.24,170.83)
M_MA_DM4: length 56.6
  TOP w0.089: CPU2.BG41 94.26,171.62 94.55,171.62 94.65,171.52 94.98,171.52 95.07,171.61 95.97,171.61 96.03,171.55
  TOP w0.102: DIMM1.136 v1(137.94,147.65) ; v1(101.12,170.41) 101.11,170.41 v3(100.1,171.42) 99.97,171.55 96.03,171.55
  L4 w0.127: v1(101.12,170.41) 101.54,170.83 104.78,170.83 105.09,170.51 106.8,170.51 112.82,164.5 113,164.5 113.01,164.52 113.19,164.52 113.39,164.32 113.39,164.14 113.37,164.12 113.37,163.94 113.57,163.74 113.75,163.74 113.77,163.76 113.95,163.76 114.14,163.56 114.14,163.38 114.13,163.37 114.13,163.19 128.79,148.53 133.75,148.53 133.99,148.77 134.75,148.77 134.86,148.88 135.84,148.88 135.96,148.77 136.82,148.77 v1(137.94,147.65)
M_MA_DM5: length 67.6
  TOP w0.102: v1(134.3,143.79) 133.06,142.55 DIMM1.153 ; CPU2.AY36 v1(90.69,169.84)
  L3 w0.089: 97.25,169.57 97.04,169.36 94.27,169.36 94.16,169.25 91.56,169.25 91.37,169.44 91.23,169.44 91.23,169.44 91.03,169.44 90.84,169.25 90.41,169.25 90.28,169.38 90.28,169.58 90.54,169.84 v1(90.69,169.84)
  L3 w0.127: v1(134.3,143.79) 134.3,144.22 134.43,144.35 134.85,144.35 135.08,144.12 135.08,143.66 135.2,143.54 136.54,143.54 136.71,143.36 136.71,142.82 136.58,142.7 136.13,142.7 135.96,142.86 135.31,142.86 135.25,142.92 133.79,143.38 133.78,143.39 129.05,143.39 102.87,169.57 97.25,169.57
  BOTTOM w0.102: v1(134.3,143.79) v4(134.3,144.5)
M_MA_DM6: length 65.9
  TOP w0.102: DIMM1.170 137.72,137.45 137.47,137.69 136.96,137.69 v1(136.46,137.19) ; CPU2.BD32 v1(92.82,166.94)
  L4 w0.089: 94.22,166.54 93.22,166.54 v1(92.82,166.94)
  L4 w0.127: 94.22,166.54 96.21,164.55 96.21,163.64 96.39,163.46 96.39,163.28 96.63,163.03 96.82,163.03 97.62,162.23 102.18,162.23 119.26,145.15 119.26,144.98 118.78,144.5 118.78,144.32 118.98,144.12 119.16,144.12 119.63,144.6 119.81,144.6 120.01,144.4 120.01,144.22 119.54,143.75 119.54,143.57 119.73,143.37 119.91,143.37 120.39,143.84 120.57,143.84 121.36,143.05 121.36,142.33 124.97,138.72 125.78,138.72 127.13,137.36 132.67,137.36 132.73,137.31 133.13,137.31 133.41,137.04 134.39,137.04 134.4,137.03 135.04,137.03 135.37,137.36 136.33,137.36 136.46,137.24 v1(136.46,137.19)
  BOTTOM w0.102: v1(136.46,137.19) 137.01,137.74 v4(137.86,137.74)
M_MA_DM7: length 61.5
  TOP w0.102: CPU2.BH30 94.44,166.47 95.13,166.47 96.45,165.15 v3(96.95,165.15) 98.28,165.15 v1(98.58,164.85) ; v1(133.66,131.52) 132.83,132.35 DIMM1.187
  L3 w0.127: v1(98.59,164.85) 98.59,161.65 123.26,136.97 123.44,136.97 123.52,137.05 123.7,137.05 123.9,136.85 123.9,136.67 123.82,136.59 123.82,136.41 124.02,136.22 124.2,136.22 124.39,136.41 124.57,136.41 124.77,136.21 124.77,136.03 124.57,135.84 124.57,135.66 124.77,135.46 124.95,135.46 125.14,135.66 125.32,135.66 125.52,135.46 125.52,135.28 125.33,135.09 125.33,134.91 125.52,134.71 125.7,134.71 125.9,134.9 126.08,134.9 126.28,134.7 126.28,134.53 126.08,134.33 126.08,134.15 129.14,131.09 133.23,131.09 v1(133.66,131.52)
M_MAA_A0: length 64.5
  TOP w0.165: v1(91.75,175.23) 91.75,175.23 CPU2.BB47 ; DIMM1.98 135.88,159.05 v1(134.53,160.4)
  L3 w0.089: 95.8,174.47 95.62,174.29 94.84,174.29 93.76,173.21 91.47,173.21 91.35,173.34 91.35,175.11 91.47,175.23 v1(91.75,175.23)
  L3 w0.102: 95.8,174.47 97.09,175.76
  L3 w0.216: v1(134.53,160.4) 134.5,160.38 129.55,160.38 128.41,161.51 127.85,161.51 126.3,161.51 123.68,164.13 123.68,164.71 123.35,165.04 123.35,165.05 122.35,166.05 121.66,166.05 120.89,166.81 118.85,168.86 118.85,168.86 118.18,169.53 118.18,170.9 118.5,171.22 118.5,171.43 110.86,179.07 100.08,179.07 97.86,176.85 97.86,176.53 97.09,175.76
  BOTTOM w0.165: v1(134.53,160.4) 133.78,160.4 v4(133.78,160.4)
M_MAA_A1: length 67.6
  TOP w0.165: v1(132.67,159.05) 132.37,159.35 DIMM1.97 ; CPU2.BC42 v1(92.11,172.81)
  L3 w0.089: v1(92.11,172.81) 91.96,172.81 91.75,172.6 91.75,172.35 91.88,172.22 94.01,172.22 94.97,173.18
  L3 w0.216: 94.97,173.18 95.31,173.52 96.03,173.52 96.44,173.93 96.75,173.93 96.96,173.72 97.14,173.72 97.57,174.15 97.57,174.33 97.36,174.54 97.36,174.85 97.77,175.29 100.29,177.8 109,177.8 109.13,177.67 109.13,177.52 108.29,176.68 108.29,176.5 108.95,175.85 109.13,175.85 109.91,176.63 109.91,177.5 110.04,177.62 110.54,177.62 111.35,176.81 111.35,176.51 109.96,175.12 109.96,174.94 110.39,174.5 110.57,174.5 111.96,175.9 112.27,175.9 112.78,175.38 112.78,175.08 112.09,174.38 112.09,173.91 112.93,173.06 114.15,171.84 115.46,170.54 116.11,170.54 116.55,170.98 116.81,170.98 116.93,170.85 116.93,169.81 116.67,169.54 116.67,169.27 116.93,169.01 117.6,168.34 121.14,164.8 121.84,164.8 122.11,164.54 122.11,164.53 122.44,164.2 122.44,163.62 125.06,161 125.79,160.27 126.96,160.27 127.18,160.05 127.18,159.86 127.48,159.56 128.61,159.56 129.03,159.13 132.59,159.13 v1(132.67,159.05)
  BOTTOM w0.165: v4(131.92,159.06) 131.93,159.05 v1(132.67,159.05)
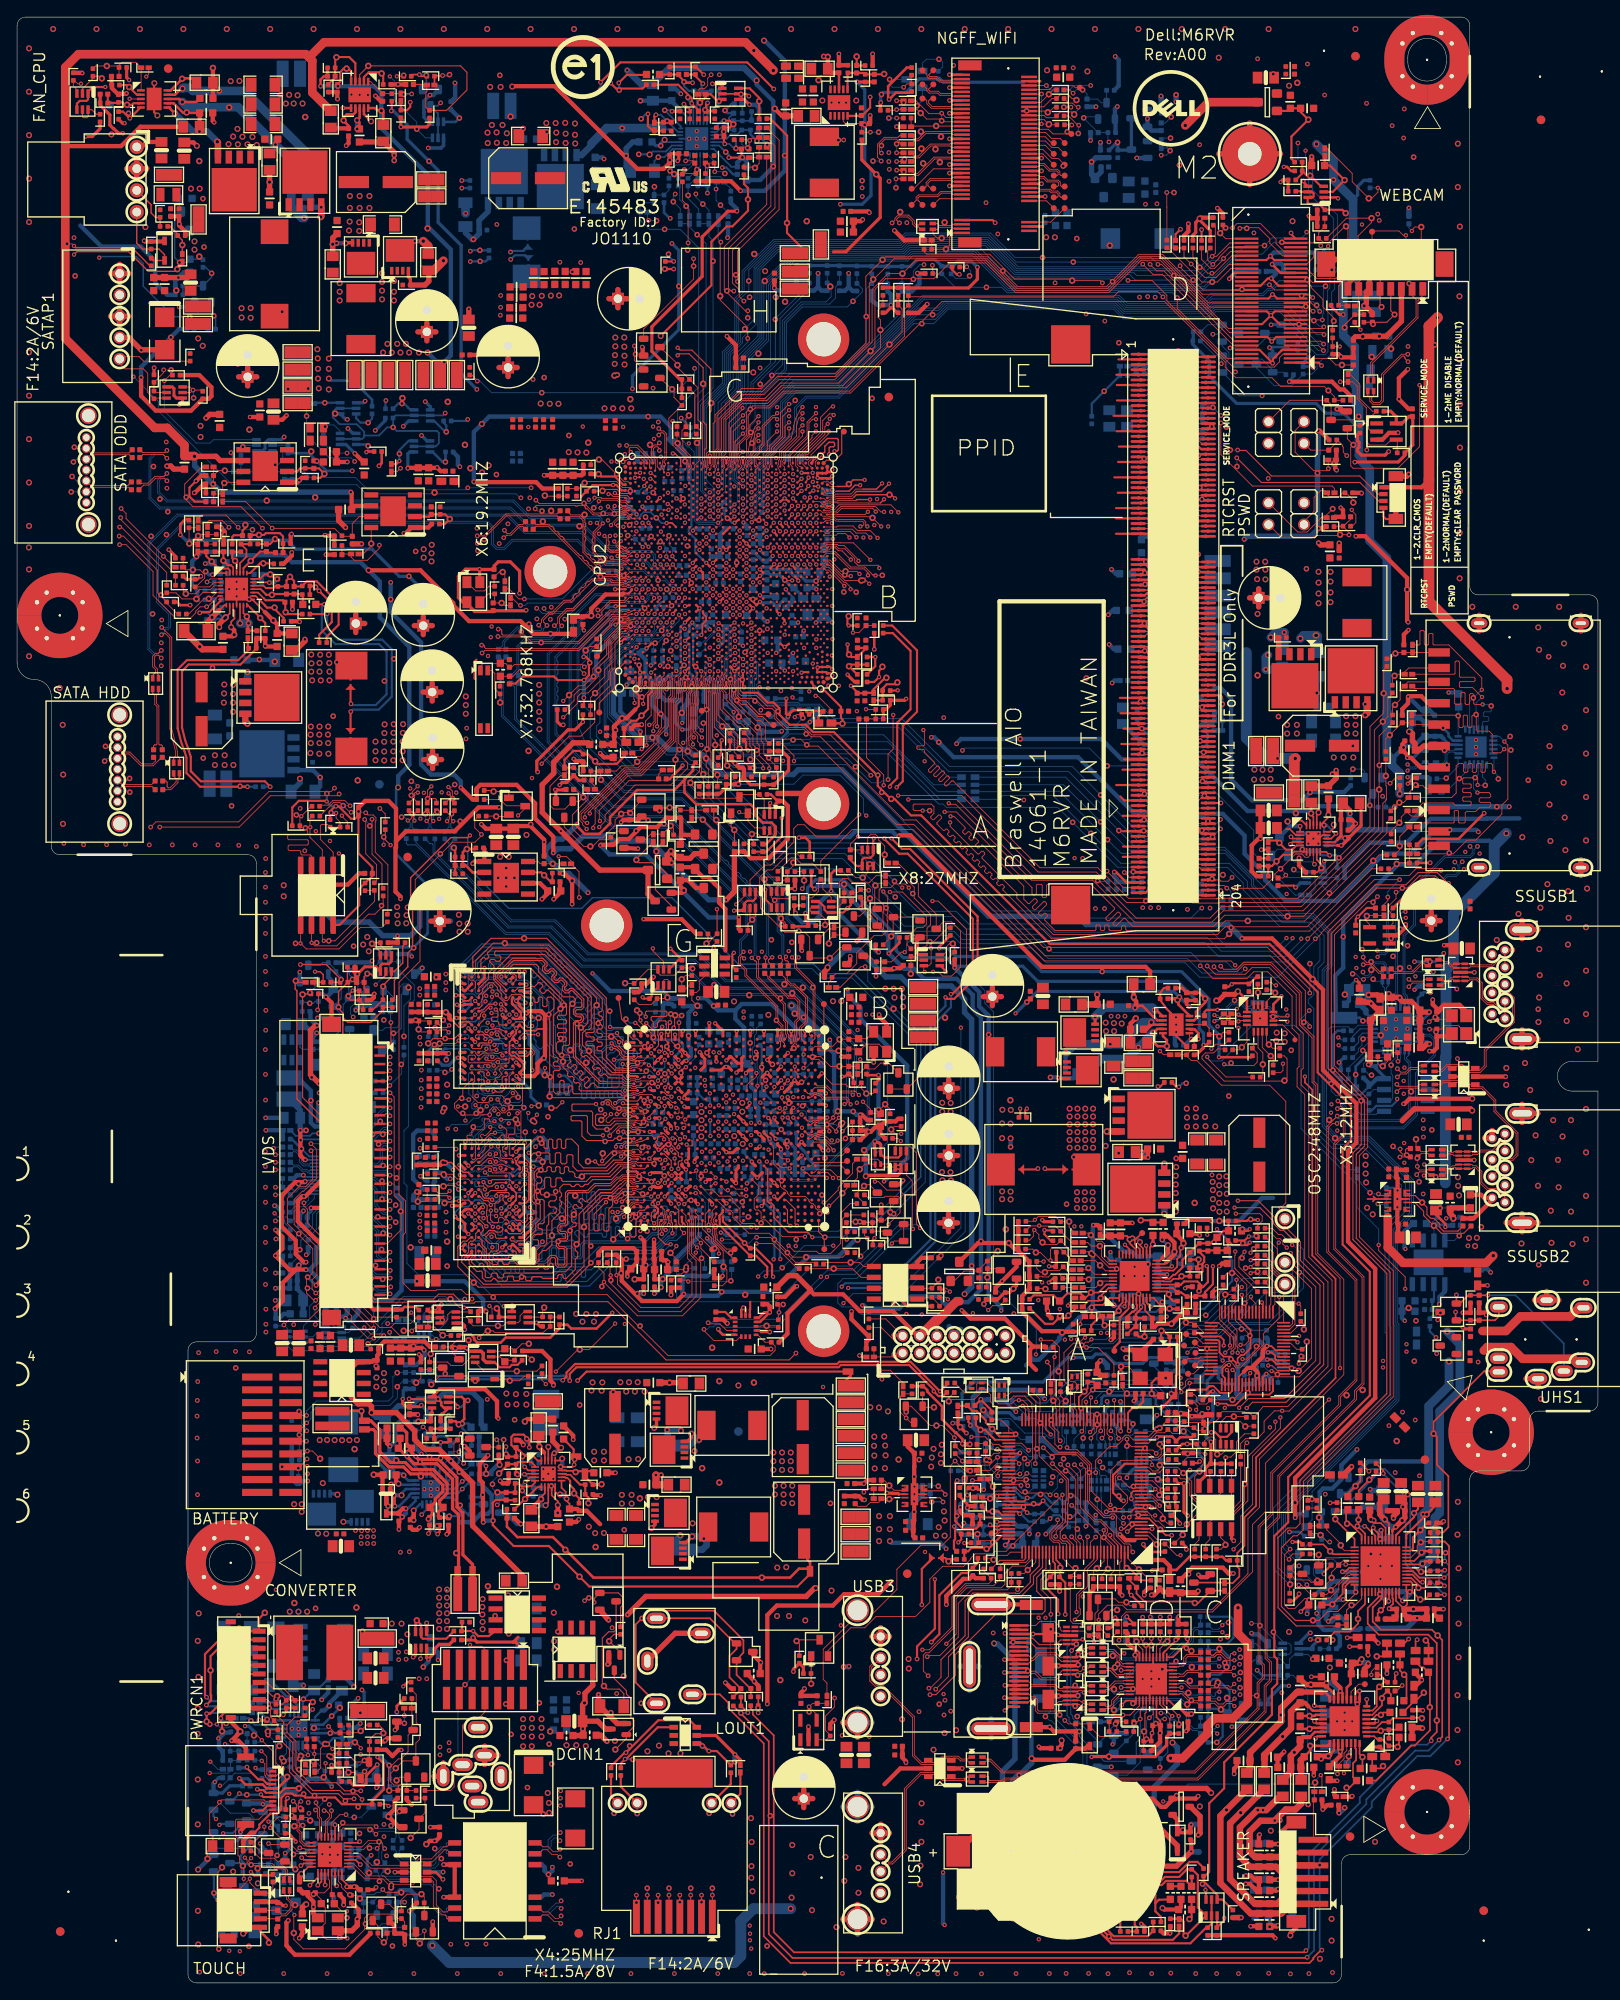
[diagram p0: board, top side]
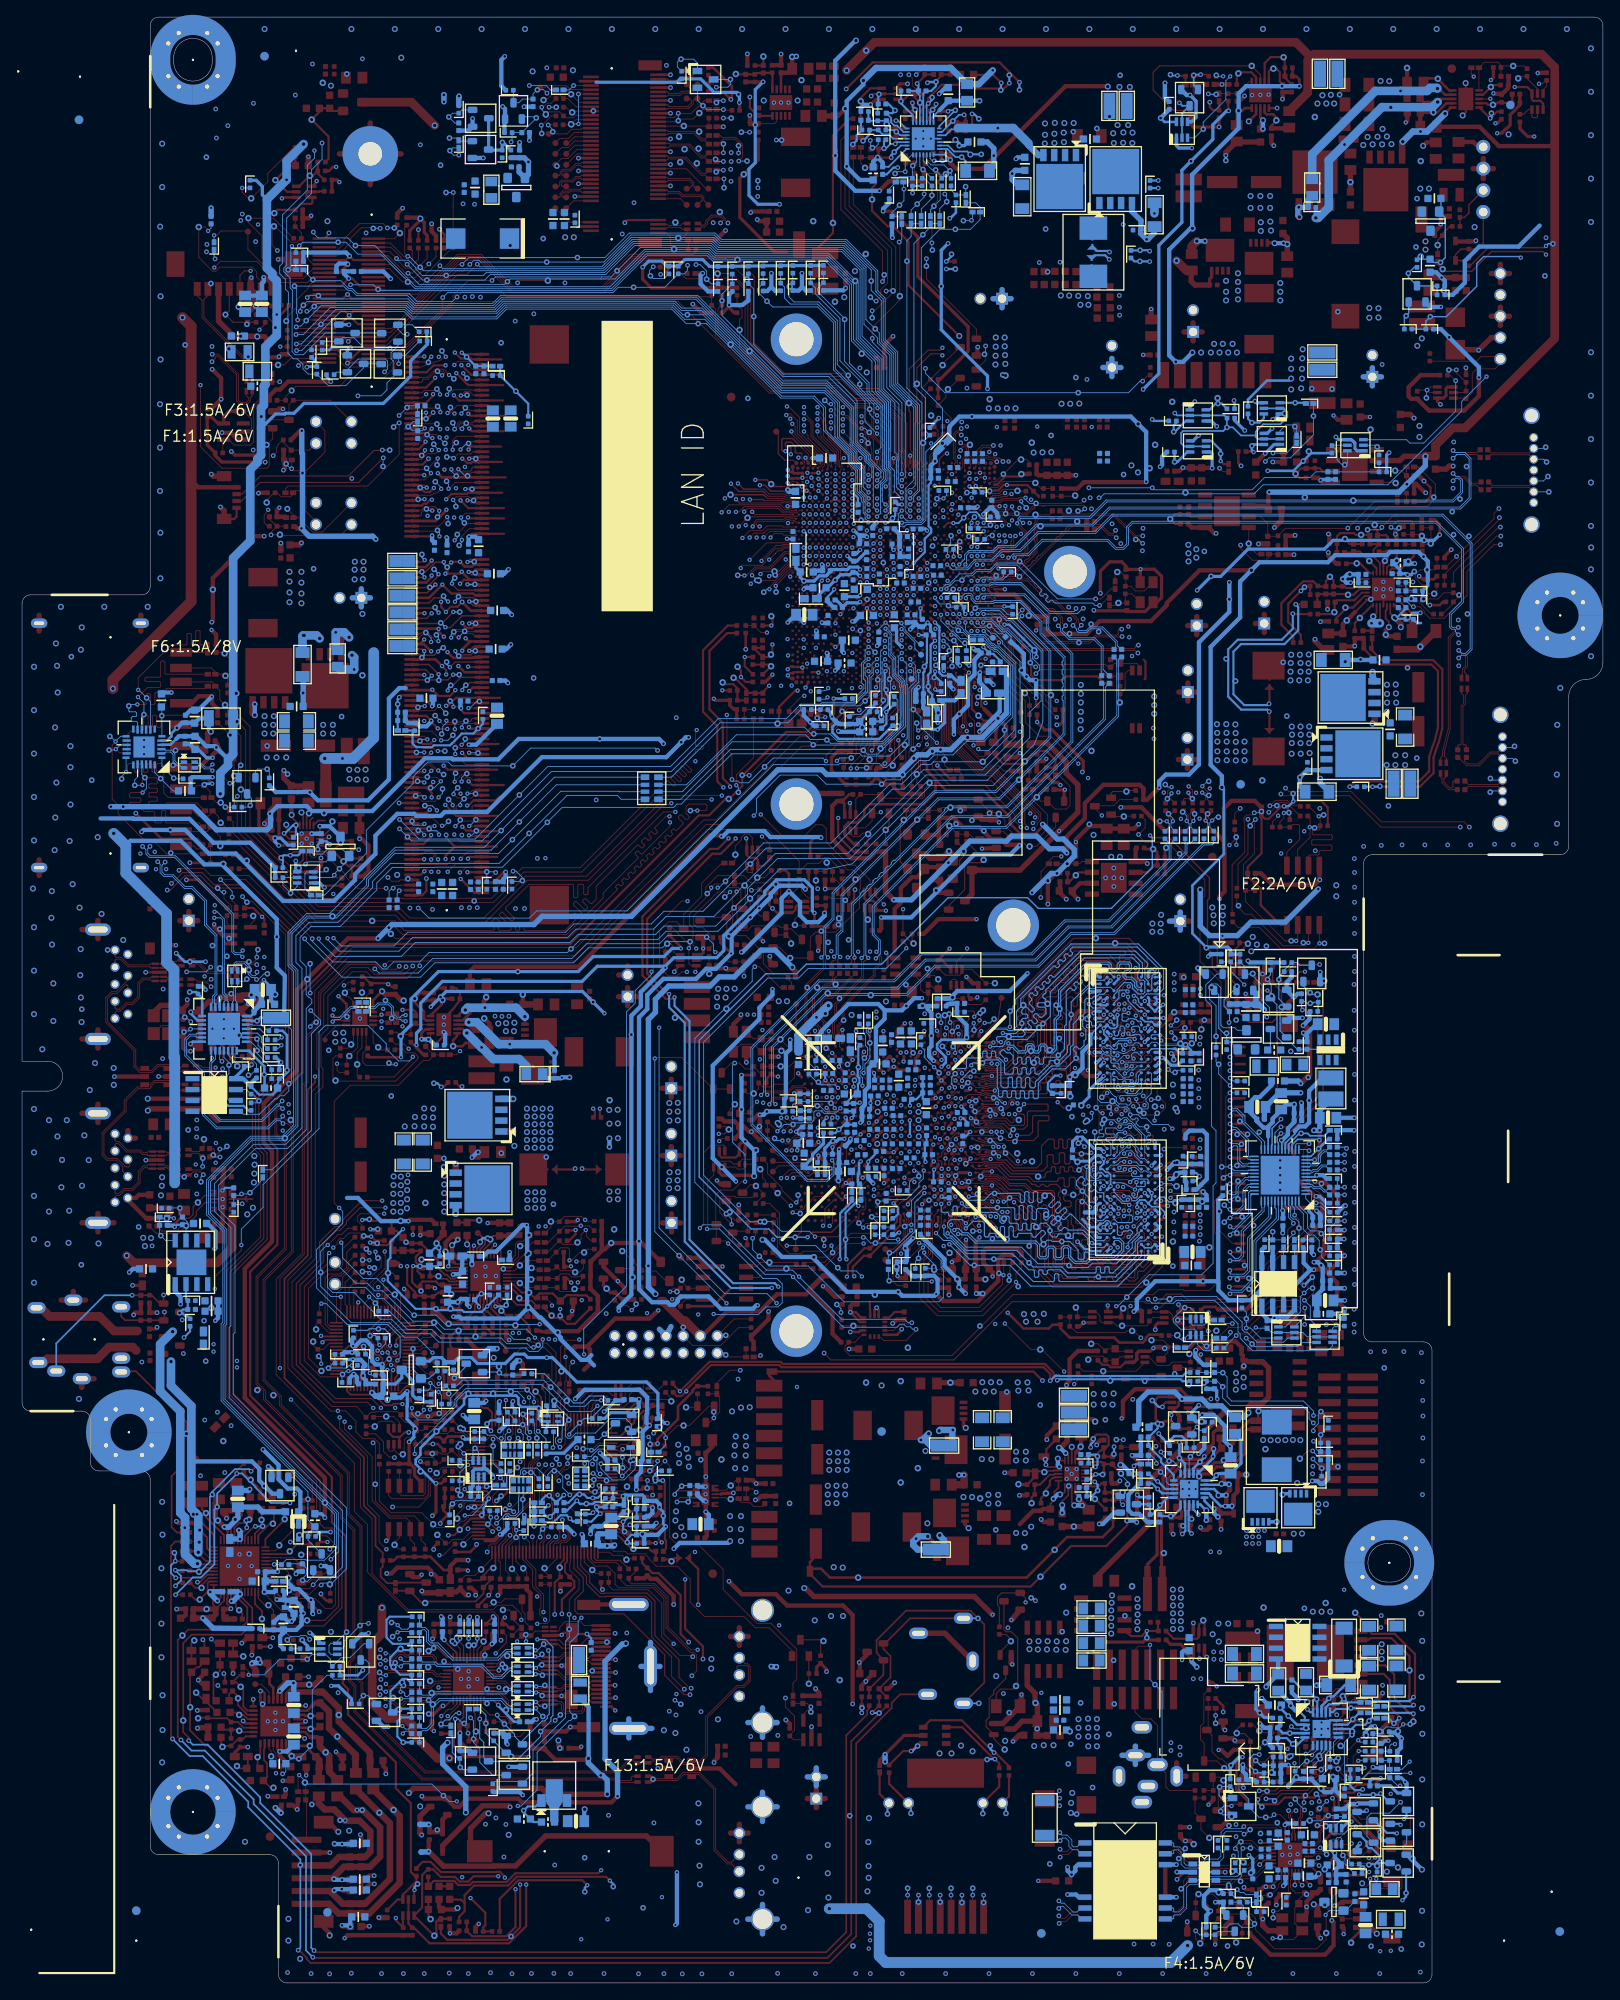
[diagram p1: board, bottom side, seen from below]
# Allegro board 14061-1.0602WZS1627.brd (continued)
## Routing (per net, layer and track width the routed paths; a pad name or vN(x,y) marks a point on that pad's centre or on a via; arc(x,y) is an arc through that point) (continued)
M_MAA_A2: length 57.8
  TOP w0.089: CPU2.BJ48 94.93,175.29 95.13,175.09 96.02,175.09
  TOP w0.165: v1(99.19,175.85) 97.83,175.85 v3(97.34,175.36) 97.06,175.08 96.03,175.08 96.02,175.09 ; DIMM1.96 137.66,159.65 v1(137.06,160.24)
  L3 w0.216: v1(137.06,160.24) 137.8,159.5 137.8,158.8 137.68,158.67 136.79,158.67 136.23,159.24 135.21,159.24 135.05,159.08 134.14,159.08 133.6,158.53 133.44,158.53 133.42,158.51 128.75,158.51 128.32,158.93 127.22,158.93 126.51,159.65 125.53,159.65 124.44,160.74 121.82,163.36 121.82,163.94 121.57,164.18 120.88,164.18 120.12,164.95 120.12,164.95 116.98,168.08 116.31,168.75 116.05,169.02 116.05,169.79 115.92,169.91 115.2,169.91 113.89,171.22 112.49,172.63 111.23,173.88 110.03,173.88 107.67,176.25 107.67,176.94 107.43,177.18 100.81,177.18 99.48,175.85 v1(99.19,175.85)
M_MAA_A3: length 57.8
  TOP w0.089: CPU2.BH47 94.48,174.6 94.48,174.48 94.56,174.4 94.56,174.4 94.71,174.25 95.52,174.25 95.81,174.54 95.87,174.54
  TOP w0.165: DIMM1.95 133.5,159.95 134.88,158.57 135.42,158.57 v1(135.46,158.62) ; v1(98.66,175.23) 98.06,175.23 97.36,174.54 95.87,174.54
  L3 w0.216: v1(135.46,158.62) 135.62,158.62 135.75,158.49 135.75,158.09 135.65,157.99 135.15,157.99 134.69,158.46 134.4,158.46 133.85,157.91 133.7,157.91 133.68,157.89 128.49,157.89 128.13,158.25 128.06,158.31 126.96,158.31 126.25,159.02 125.16,159.02 119.86,164.33 119.86,164.33 116.36,167.83 115.69,168.5 115.43,168.76 115.43,169.16 115.3,169.29 114.94,169.29 113.64,170.6 111.51,172.72 110.98,173.26 109.77,173.26 107.04,175.99 107.04,176.43 106.92,176.56 101.23,176.56 99.9,175.23 v1(98.66,175.23)
  BOTTOM w0.165: v1(135.46,158.62) 135.98,159.13 v4(136.01,159.13)
M_MAA_A4: length 68.5
  TOP w0.165: DIMM1.92 136.55,160.85 136.25,160.55 v1(136.25,160.32) ; CPU2.BD42 v1(92.82,172.81)
  L3 w0.089: 96.03,174.15 95.75,173.87 95.2,173.87 93.74,172.41 93.22,172.41 v1(92.82,172.81)
  L3 w0.102: 98.47,176.59 96.03,174.15
  L3 w0.216: v1(136.25,160.32) 136.25,159.97 136.15,159.86 134.87,159.86 134.76,159.75 129.29,159.75 128.15,160.89 126.04,160.89 125.68,161.26 123.06,163.88 123.06,164.45 122.73,164.79 122.73,164.79 122.09,165.43 121.4,165.43 120.63,166.19 117.56,169.27 117.56,171.49 117.02,172.02 116.72,172.02 115.94,171.24 115.63,171.24 115.33,171.55 115.33,171.85 116.11,172.63 116.11,172.94 115.8,173.24 115.49,173.24 114.72,172.47 114.41,172.47 114.1,172.77 114.1,173.08 114.88,173.86 114.88,174.16 114.58,174.47 114.27,174.47 113.49,173.69 113.19,173.69 112.88,173.99 112.88,174.3 113.66,175.08 113.66,175.38 110.62,178.42 100.3,178.42 98.47,176.59
  BOTTOM w0.165: v1(136.25,160.32) 136.67,160.74 v4(136.67,160.93)
M_MAA_A5: length 60.9
  TOP w0.089: v1(95.4,175.49) 95.09,175.49 94.95,175.63 94.67,175.63 94.41,175.63 CPU2.BH48
  TOP w0.165: v1(132.66,161.62) 132.19,161.15 DIMM1.91
  L3 w0.089: v1(95.4,175.49) 95.68,175.49 96.03,175.84
  L3 w0.102: 97.17,177.71 96.41,176.95 96.41,176.22 96.03,175.84
  L3 w0.216: v1(132.66,161.62) 130.06,161.62 128.52,163.17 128.05,163.17 127.64,162.76 127.33,162.76 126.82,162.76 124.93,164.65 124.93,165.23 123.8,166.36 123.8,167.1 124.09,167.39 124.09,167.6 123.59,168.1 123.28,168.1 122.48,167.29 122.17,167.29 121.87,167.6 121.87,167.9 122.67,168.71 122.67,169.01 122.36,169.32 122.06,169.32 121.25,168.52 120.95,168.52 120.64,168.82 120.64,169.13 121.45,169.93 121.45,170.24 121.14,170.54 120.84,170.54 120.03,169.74 119.73,169.74 119.42,170.04 119.42,170.35 120.23,171.15 120.23,171.46 111.32,180.36 99.83,180.36 97.17,177.71
  BOTTOM w0.165: v4(131.89,161.62) v1(132.66,161.62)
M_MAA_A6: length 63.9
  TOP w0.165: DIMM1.90 137.37,161.45 136.77,162.05 135.68,162.05 135.24,161.62 v1(135.15,161.62) ; CPU2.BB46 v1(91.8,174.56)
  L3 w0.089: v1(91.8,174.56) 91.7,174.46 91.7,173.64 91.93,173.4 93.68,173.4 95,174.71 95,174.86 95.23,175.09 95.79,175.09 96.03,175.33
  L3 w0.102: 97.59,177.39 96.92,176.72 96.92,176.22 96.03,175.33
  L3 w0.216: v1(135.15,161.62) 134.58,161.06 132.98,161.06 132.92,161 129.81,161 128.67,162.14 127.59,162.14 126.56,162.14 124.3,164.39 124.3,164.97 123.97,165.3 123.97,165.31 123.18,166.1 123.18,166.29 122.79,166.67 121.91,166.67 121.15,167.44 119.47,169.11 119.47,169.12 118.8,169.79 118.8,170.61 119.34,171.14 119.34,171.47 111.1,179.7 99.9,179.7 97.59,177.39
  BOTTOM w0.165: v4(135.68,162.26) 135.68,162.13 135.18,161.62 v1(135.15,161.62)
M_MAA_A7: length 65.8
  TOP w0.165: CPU2.BE46 v1(93.19,174.59) ; DIMM1.86 137.58,162.65 v1(136.63,163.6)
  L3 w0.089: v1(93.19,174.59) 93.85,174.59 94.53,175.28 94.53,175.73 94.66,175.86 94.88,175.86 95,175.99 95,176.13 95,176.14 95,176.47 95,176.48 95,176.84 94.99,176.86 94.99,177.19 95.22,177.43 95.36,177.43 96.03,178.1
  L3 w0.102: 96.03,178.1 96.44,178.51
  L3 w0.165: 96.44,178.51 99.39,181.46
  L3 w0.216: 99.39,181.46 99.55,181.62 111.85,181.62 127.58,165.89 128.29,165.89 128.59,165.59 128.59,165.14 130.75,162.98 136.01,162.98 136.79,162.2 136.79,161.59 136.91,161.47 138.06,161.47 138.18,161.59 138.18,163.12 138.06,163.25 136.76,163.25 136.63,163.37 v1(136.63,163.6)
  BOTTOM w0.165: v1(136.63,163.6) 136.96,163.27 v4(137.28,163.27)
M_MAA_A8: length 65.2
  TOP w0.165: v1(134.34,161.6) 133.85,162.08 132.22,162.08 131.88,161.75 DIMM1.89 ; CPU2.BD44 v1(92.81,173.8)
  L3 w0.089: v1(92.81,173.8) 93.2,174.19 93.36,174.19 93.4,174.24 93.76,174.24 94.72,175.2 94.72,175.38 95.24,175.9 95.56,175.9 96.03,176.37 96.03,177.44
  L3 w0.102: 96.75,178.16 96.03,177.44
  L3 w0.165: 99.59,181 96.75,178.16
  L3 w0.216: v1(134.34,161.6) 134.34,162.23 134.21,162.36 130.21,162.36 128.44,164.13 128.13,164.13 127.38,163.38 127.08,163.38 126.77,163.69 126.77,163.99 127.52,164.74 127.52,165.05 127.21,165.35 126.91,165.35 126.16,164.6 125.85,164.6 125.55,164.91 125.55,165.21 126.3,165.96 126.3,166.27 125.86,166.71 125.55,166.71 125.03,166.19 124.85,166.19 124.42,166.62 124.42,166.8 124.94,167.32 124.94,167.62 111.58,180.99 111.48,180.99 111.46,181 99.59,181
  BOTTOM w0.165: v1(134.34,161.6) 134.34,161.7 133.93,162.11 v4(133.93,162.19)
M_MAA_A9: length 62.5
  TOP w0.089: CPU2.BE52 92.63,177.63 92.63,177.99 92.91,178.27 92.91,178.78 93.55,179.42
  TOP w0.102: 93.55,179.42 93.67,179.54
  TOP w0.165: v1(134.68,163.73) 134.68,163.65 133.98,162.95 DIMM1.85 ; 93.67,179.54 94.83,180.7 95.97,180.7 96.1,180.57 96.1,179.35 95.97,179.22 v1(95.66,179.22)
  L3 w0.165: 99.65,182.88 97.4,180.62 97.11,180.62 96.96,180.47 96.96,180.19 96.66,179.88 96.35,179.88 96.15,179.68 96.15,179.37 96,179.22 v1(95.66,179.22)
  L3 w0.216: 99.65,182.88 112.25,182.88 112.26,182.87 112.36,182.87 112.37,182.87 113.14,182.87 123.7,172.3 123.7,171.53 125.23,170 125.23,170 126.34,168.89 126.34,168.89 126.89,168.34 126.89,168.34 127.22,168.01 127.22,168.01 127.77,167.46 128.54,167.46 130.44,165.57 130.44,165.06 131.03,164.47 132.92,164.47 133.2,164.19 133.48,164.19 133.61,164.31 133.61,164.47 133.83,164.69 134.07,164.69 134.68,164.09 v1(134.68,163.73)
  BOTTOM w0.165: v4(134.36,164.38) 134.68,164.07 v1(134.68,163.73)
M_MAA_A10: length 55.7
  TOP w0.089: 96.03,173.94 95.8,173.94 95.7,173.84 94.91,173.84 CPU2.BJ45
  TOP w0.102: 98.09,174.36 97.67,173.94 96.03,173.94
  TOP w0.165: 98.09,174.36 98.23,174.5 101.13,174.5 v1(102.04,175.41) ; v1(132.67,155.85) 132.18,156.35 DIMM1.107
  L3 w0.216: v1(102.04,175.41) 102.14,175.31 105.96,175.31 109.26,172.02 110.36,172.02 119.1,163.28 119.1,162.97 118.75,162.62 118.75,162.32 119.06,162.01 119.36,162.01 119.71,162.36 120.02,162.36 120.32,162.06 120.32,161.75 119.97,161.4 119.97,161.09 120.28,160.79 120.58,160.79 120.93,161.14 121.24,161.14 121.55,160.83 121.55,160.53 121.19,160.18 121.19,159.87 121.5,159.57 121.81,159.57 122.16,159.92 122.46,159.92 122.77,159.61 122.77,159.31 122.42,158.96 122.42,158.65 122.72,158.34 123.03,158.34 123.38,158.7 123.68,158.7 124.12,158.25 124.12,156.98 125.25,155.85 131.78,155.85 132.24,156.31 132.44,156.31 132.67,156.08 v1(132.67,155.85)
  BOTTOM w0.165: v1(132.67,155.85) v4(131.96,155.85)
M_MAA_A11: length 64.7
  TOP w0.165: v1(136.27,164.81) 136.48,164.59 136.48,164.42 137.14,163.76 137.7,163.25 DIMM1.84 ; CPU2.BB49 v1(91.8,175.99)
  L3 w0.089: v1(91.8,175.99) 92.11,176.37 92.2,176.57 92.2,176.78 92.07,178.08 92.07,178.56 92.51,179.47
  L3 w0.165: 92.51,179.47 93.17,180.03 94.27,180.64 95.01,180.95 97.29,183.22
  L3 w0.216: 97.29,183.22 99.45,185.39 114.33,185.39 131.54,168.19 131.87,168.19 132.53,167.53 135.4,167.53 136.3,166.62 136.3,164.85 v1(136.27,164.81)
  BOTTOM w0.165: v1(136.27,164.81) 136.27,164.87 136.78,165.38 v4(136.78,165.39)
M_MAA_A12: length 62.5
  TOP w0.165: DIMM1.83 131.2,163.55 132.8,163.55 v1(132.88,163.63) ; CPU2.BF48 v1(93.76,175.07)
  L3 w0.089: v1(93.76,175.07) 94.05,175.07 94.34,175.36 94.34,175.81 94.39,175.86 94.39,176.1 94.57,176.28 94.57,176.61 94.39,176.78 94.39,176.99 94.55,177.14
  L3 w0.165: 94.55,177.14 94.78,177.37 94.78,177.88 94.94,178.04 95.41,178.04 95.54,178.17 95.54,178.51 95.66,178.64 96.05,178.64 96.23,178.83 96.23,178.97 99.51,182.24
  L3 w0.216: v1(132.88,163.63) 132.66,163.84 130.77,163.84 129.21,165.4 129.21,165.85 128.91,166.15 128.55,166.52 127.83,166.52 123.02,171.33 123.02,171.95 122.89,172.08 122.27,172.08 122,172.36 122,172.61 122.12,172.74 122.12,173 121.94,173.18 121.68,173.18 121.56,173.05 121.3,173.05 121.12,173.24 121.12,173.49 121.24,173.62 121.24,173.88 121.06,174.06 120.8,174.06 120.67,173.93 120.42,173.93 120.23,174.12 120.23,174.37 120.36,174.5 120.36,174.76 120.18,174.94 119.92,174.94 119.79,174.81 119.54,174.81 119.35,175 119.35,175.25 119.48,175.38 119.48,175.64 119.3,175.82 119.04,175.82 118.91,175.69 118.66,175.69 118.47,175.88 118.47,176.13 118.6,176.26 118.6,176.52 118.42,176.7 118.16,176.7 118.03,176.57 117.78,176.57 117.59,176.76 117.59,177.01 117.72,177.14 117.72,177.4 117.54,177.58 117.28,177.58 117.15,177.46 116.9,177.46 116.71,177.64 116.71,177.9 116.84,178.02 116.84,178.28 116.66,178.46 116.4,178.46 116.27,178.34 116.02,178.34 115.83,178.52 115.83,178.78 115.96,178.9 115.96,179.16 115.78,179.34 115.52,179.34 115.39,179.22 115.13,179.22 114.95,179.4 114.95,179.66 115.08,179.78 115.08,180.04 114.9,180.22 114.64,180.22 114.51,180.1 114.25,180.1 114.07,180.28 114.07,180.54 114.2,180.66 114.2,180.92 114.02,181.1 113.76,181.1 113.63,180.98 113.37,180.98 113.19,181.16 113.19,181.42 113.32,181.54 113.32,181.8 113.14,181.98 112.88,181.98 112.75,181.86 112.49,181.86 112.11,182.24 111.59,182.24 99.51,182.24
  BOTTOM w0.165: v4(132.01,163.63) 132.01,163.63 v1(132.88,163.63)
M_MAA_A13: length 65.6
  TOP w0.089: CPU2.BF44 93.96,173.31 94.31,172.96 94.55,172.96 94.65,173.06 95.14,173.06 95.25,173.17 96.03,173.17
  TOP w0.102: 96.03,173.17 96.05,173.15 99.66,173.15 99.66,173.15 101.02,173.15 101.05,173.18
  TOP w0.165: v1(135.19,151.21) 133.64,152.75 DIMM1.119 ; 101.05,173.18 v1(101.45,173.58)
  L3 w0.216: v1(135.19,151.21) 134.91,151.21 134.79,151.33 134.79,151.46 134.78,151.47 134.78,152.3 134.91,152.43 136.25,152.43 136.38,152.3 136.38,150.47 136.25,150.34 125.94,150.34 108.96,167.32 108.96,168.73 108.84,168.85 107.43,168.85 103.76,172.52 102.53,172.52 102.48,172.57 101.23,172.57 101.1,172.7 101.1,173.45 101.23,173.58 v1(101.45,173.58)
  BOTTOM w0.165: v1(135.19,151.21) 135.19,151.46 v4(134.83,151.82)
M_MAA_A14: length 61.6
  TOP w0.165: v1(137.9,164.45) 137.91,164.45 DIMM1.80 ; CPU2.BD47 v1(92.6,175.14)
  L3 w0.089: 94.86,179.66 94.6,179.4 94.5,179.17 94.5,178.67 94.55,178.63 94.55,178.26 94.13,177.17 94.08,176.57 94.08,175.93 93.85,175.7 93.84,175.7 93.82,175.68 93.4,175.33 arc(93.38,175.31) 93.36,175.29 93.33,175.26 93.25,175.21 93.06,175.18 92.8,175.14 v1(92.6,175.14)
  L3 w0.165: 94.86,179.66 99.25,184.06 99.35,184.06
  L3 w0.216: v1(137.9,164.45) 137.77,164.31 arc(137.62,164.21) 137.45,164.18 136.12,164.18 arc(136.05,164.18) 135.99,164.19 135.32,164.33 134.12,165.52 arc(133.92,165.66) 133.67,165.71 132.91,165.71 arc(132.81,165.72) 132.7,165.74 132.38,165.86 arc(132.29,165.9) 132.2,165.96 130.99,166.9 130.94,166.95 113.74,184.15 99.83,184.15 99.35,184.06
  BOTTOM w0.165: v1(137.9,164.45) 137.9,164.54 138.21,164.85 v4(138.21,165.1)
M_MAA_A15: length 62.8
  TOP w0.165: v1(135.64,166.24) 135.64,166.23 135.66,166.22 136.61,166.22 136.87,165.96 136.92,165.96 137.83,165.05 DIMM1.78 ; CPU2.BD49 v1(92.62,176.12)
  L3 w0.089: v1(92.62,176.12) 92.62,176.87 92.89,177.14 92.89,179.23 92.95,179.29
  L3 w0.165: 92.95,179.29 93.29,179.63 93.53,179.63 93.66,179.5 93.66,179.15 93.78,179.02 94.04,179.02 94.22,179.19 94.22,179.88 94.34,180.01 94.73,180.01 96.82,182.1
  L3 w0.216: 96.82,182.1 99.49,184.77 114.08,184.77 131.28,167.57 131.57,167.57 132.27,166.88 135.17,166.88 135.64,166.4 v1(135.64,166.24)
  BOTTOM w0.165: v4(135.25,165.63) 135.64,166.02 v1(135.64,166.24)
M_ODT_A0: length 65
  TOP w0.165: v1(137.06,152.93) 137.77,153.65 DIMM1.116 ; CPU2.AV36 v1(89.97,169.84)
  L4 w0.089: 100.5,173.09 99.24,173.09 95.76,169.62 94.92,169.62 94.74,169.44 90.37,169.44 v1(89.97,169.84)
  L4 w0.216: 100.5,173.09 101.62,173.09 101.92,173.39 101.92,173.51 102.56,174.15 102.94,174.15 103.25,173.84 110.41,173.84 127.28,156.98 127.28,156.38 127.58,156.08 128.18,156.08 129.76,154.5 130.06,154.5 130.07,154.52 130.38,154.52 130.68,154.21 130.68,153.9 130.67,153.89 130.67,153.59 132,152.26 133.36,152.26 133.81,151.82 137.35,151.82 137.47,151.94 137.47,152.81 137.35,152.93 v1(137.06,152.93)
  BOTTOM w0.165: v1(137.06,152.93) 137.06,152.93 137.57,152.43 v4(137.57,152.42)
M_ODT_A1: length 63.1
  TOP w0.165: v1(134.55,153.06) 135.16,152.45 DIMM1.120 ; CPU2.BA38 v1(90.69,170.83)
  L4 w0.089: v1(90.69,170.83) 91.09,170.43 93.78,170.43 93.82,170.39 95.52,170.39 96.42,171.28
  L4 w0.216: 96.42,171.28 100.04,174.9 103.11,174.9 104.1,175.9 105.62,175.9 105.84,175.68 105.84,175.43 106.05,175.21 106.48,175.21 106.7,175.43 106.7,175.68 106.92,175.9 111.14,175.9 127.48,159.56 127.48,159.32 130.44,156.36 130.92,156.02 132.84,154.65 133.29,154.2 133.37,154.04 133.37,153.97 133.61,153.69 134.21,153.26 v1(134.55,153.06)
  BOTTOM w0.165: v4(133.84,153.06) 133.97,153.06 133.97,153.06 v1(134.55,153.06)
M_RAS_A_N: length 68.3
  TOP w0.165: v1(136.31,155.77) 136.75,155.34 138.39,155.34 138.5,155.45 DIMM1.110 ; CPU2.BA40 v1(91.4,171.82)
  L3 w0.089: 94.54,172.22 93.74,171.42 91.8,171.42 v1(91.4,171.82)
  L3 w0.216: v1(136.31,155.77) 136.31,155.61 135.91,155.21 133.95,155.21 133.95,155.22 125,155.22 123.5,156.72 123.5,157.58 123.36,157.72 122.46,157.72 117.76,162.42 117.76,162.81 118.13,163.18 118.13,163.37 117.69,163.81 117.38,163.81 117.03,163.46 116.73,163.46 116.42,163.77 116.42,164.07 116.77,164.42 116.77,164.73 116.47,165.03 116.16,165.03 115.81,164.68 115.5,164.68 115.2,164.99 115.2,165.29 115.55,165.64 115.55,165.95 115.24,166.25 114.94,166.25 114.59,165.9 114.28,165.9 113.98,166.21 113.98,166.51 114.33,166.87 114.33,167.17 114.02,167.48 113.72,167.48 113.37,167.13 113.06,167.13 112.76,167.43 112.76,167.74 113.11,168.09 113.11,168.39 112.8,168.7 112.5,168.7 112.14,168.35 111.84,168.35 111.53,168.65 111.53,168.96 111.88,169.31 111.88,169.61 110.11,171.39 109,171.39 105.7,174.69 105.18,174.69 105.15,174.73 99.02,174.73 97.35,173.05 96.3,173.05 96.2,172.95 96.2,172.34 96.08,172.22 94.54,172.22
  BOTTOM w0.165: v4(135.71,156.21) 135.88,156.21 v1(136.31,155.77)
M_SBS_A0: length 64
  TOP w0.089: CPU2.BH46 94.43,174.06 95.64,174.06 95.78,174.19 96.03,174.19
  TOP w0.102: 98.99,174.78 98.15,174.78 97.57,174.19 96.03,174.19
  TOP w0.165: v1(101.22,175.44) 100.56,174.78 98.99,174.78 ; v1(134.3,155.83) 133.86,155.39 132.47,155.39 132.12,155.75 DIMM1.109
  L3 w0.216: v1(134.3,155.83) 134.3,156.06 134.42,156.19 135.36,156.19 135.49,156.32 135.49,156.74 135.36,156.87 133.34,156.87 133.3,156.83 132.89,156.83 132.46,157.26 131.84,157.26 131.62,157.05 131.62,156.69 131.4,156.48 130.97,156.48 130.76,156.69 130.76,157.05 130.54,157.26 130.11,157.26 129.89,157.05 129.89,156.69 129.68,156.48 129.24,156.48 129.03,156.69 129.03,157.14 128.9,157.26 128.23,157.26 127.81,157.69 127.36,157.69 127.24,157.56 127.24,156.62 127.11,156.49 126.58,156.49 126.45,156.62 126.45,157.95 125.99,158.4 125.81,158.4 125.69,158.27 125.69,156.84 125.56,156.72 125.26,156.72 124.75,157.23 124.75,158.56 119.6,163.7 119.6,163.7 115.74,167.57 115.07,168.24 114.8,168.5 114.8,168.55 113.38,169.98 110.72,172.64 109.51,172.64 106.22,175.93 105.07,175.93 105.06,175.92 101.35,175.92 101.22,175.79 v1(101.22,175.44)
  BOTTOM w0.165: v1(134.3,155.83) 134.3,155.65 v4(133.89,155.24)
M_SBS_A1: length 67.8
  TOP w0.165: CPU2.AY40 v1(90.69,171.82) ; DIMM1.108 138.16,156.05 v1(137.94,155.83)
  L3 w0.089: 94.18,171.46 93.96,171.23 90.83,171.23 90.69,171.37 v1(90.69,171.82)
  L3 w0.216: v1(137.94,155.83) 138.18,155.58 138.18,155.4 138.06,155.27 137.9,155.27 137.78,155.14 137.78,154.48 137.9,154.36 138.06,154.36 138.18,154.23 138.18,153.7 138.06,153.57 136.61,153.57 136.48,153.7 136.48,154.46 136.35,154.58 133.02,154.58 133.01,154.59 124.75,154.59 122.88,156.46 122.88,156.97 122.75,157.1 122.21,157.1 110.91,168.39 110.91,169.71 109.85,170.77 108.74,170.77 105.45,174.07 104.38,174.07 104.05,174.39 99.4,174.39 99.27,174.26 99.27,173.49 99.14,173.37 98.39,173.37 98.18,173.15 98.18,172.77 98.31,172.64 98.86,172.64 98.99,172.52 98.99,172.14 98.86,172.01 97.21,172.01 96.96,171.76 94.48,171.76 94.18,171.46
  BOTTOM w0.165: v4(138.21,155.07) 137.94,155.34 v1(137.94,155.83)
M_SBS_A2: length 60.5
  TOP w0.089: 93.75,178.88 93.75,178.31 93.51,178.08 93.41,177.97 93.41,177.46 CPU2.BF52
  TOP w0.165: v1(132.74,165.09) 132.4,164.75 DIMM1.79 ; v1(95.03,178.85) 95.03,179.6 95.16,179.73 95.54,179.73 95.66,179.86 95.66,180.14 95.54,180.26 95,180.26 94.52,179.78 94.52,179.12 94.39,178.99 93.86,178.99 93.75,178.88
  L3 w0.165: 99.52,183.53 99.36,183.53 95.56,179.73 95.3,179.73 94.78,179.2 94.78,178.98 94.9,178.85 v1(95.03,178.85)
  L3 w0.216: v1(132.74,165.09) 131.71,165.09 131.58,165.21 131.58,165.65 131.37,165.81 131.07,165.81 128.67,168.21 128.41,168.21 128.29,168.08 128.03,168.08 127.85,168.27 127.85,168.52 127.97,168.65 127.97,168.91 127.79,169.09 127.53,169.09 127.41,168.96 127.15,168.96 126.97,169.15 126.97,169.4 127.09,169.53 127.09,169.79 126.91,169.97 126.65,169.97 126.53,169.84 126.27,169.84 126.09,170.03 126.09,170.28 126.21,170.41 126.21,170.67 126.03,170.85 125.77,170.85 125.64,170.72 125.39,170.72 125.2,170.91 125.2,171.16 125.33,171.29 125.33,171.55 125.15,171.73 124.89,171.73 124.76,171.6 124.51,171.6 124.32,171.79 124.32,172.04 124.45,172.17 124.45,172.43 113.36,183.53 99.52,183.53 99.52,183.53
  BOTTOM w0.165: v1(132.74,165.09) 132.07,165.09 v4(131.97,164.98)
M_SCKE_A0: length 57.2
  TOP w0.165: DIMM1.73 132.57,166.55 v1(132.88,166.24) ; CPU2.BB44 v1(90.81,173.69)
  L4 w0.089: v1(90.81,173.69) 91.21,174.09 91.21,176.73 91.83,177.34 94.64,177.34 94.82,177.51
  L4 w0.216: 94.82,177.51 94.97,177.66 97.79,177.66 100.09,179.96 110.37,179.96 112.85,179.96 112.85,179.96 114.68,179.96 115.42,179.23 115.42,178.93 115.19,178.7 115.19,178.39 115.49,178.09 115.8,178.09 116.03,178.32 116.33,178.32 116.64,178.01 116.64,177.7 116.41,177.48 116.41,177.17 116.72,176.87 117.02,176.87 117.25,177.09 117.55,177.09 117.86,176.79 117.86,176.48 117.63,176.25 117.63,175.95 117.94,175.64 118.24,175.64 118.47,175.87 118.78,175.87 122.79,171.86 v1(132.88,166.24)
  BOTTOM w0.165: v4(132.09,166.29) 132.83,166.29 v1(132.88,166.24)
M_SCKE_A1: length 57.7
  TOP w0.165: v1(137.88,166.47) 137.88,166.45 138.07,166.25 DIMM1.74 ; CPU2.AY42 v1(90.69,172.81)
  L4 w0.089: 96.02,175.5 95.68,175.21 95.56,175.09 95.29,175.09 94.49,174.72 93.36,174.19 93.02,174.19 93.02,174.2 91.99,174.2 90.69,172.9 v1(90.69,172.81)
  L4 w0.216: 96.02,175.5 98.4,177.57 98.4,177.62 100.12,179.34 110.63,179.34 113.27,179.34 119.22,173.39 122.8,170.52 124.59,169.44 129.05,166.94 131.94,165.86 132.52,165.73 132.76,165.59 133.81,165.59 136.59,165.78 137.28,165.93 137.88,166.33 v1(137.88,166.47)
  BOTTOM w0.165: v1(137.88,166.47) 138.21,166.8 v4(138.21,167.13)
M_SCS_A_N0: length 63.2
  TOP w0.165: CPU2.AY38 v1(89.97,170.83) ; DIMM1.114 137.39,154.25 v1(136.25,153.11)
  L4 w0.089: v1(89.97,170.83) 90.56,170.24 93.7,170.24 93.74,170.2 95.81,170.2 96.72,171.12
  L4 w0.216: 96.72,171.12 100.07,174.47 111.45,174.47 130.03,155.89 131.24,155.03 131.69,154.58 131.69,153.54 132.34,152.89 132.79,152.89 132.8,152.88 133.62,152.88 134.06,152.44 135.58,152.44 v1(136.25,153.11)
  BOTTOM w0.165: v1(136.25,153.11) 136.25,152.81 136.23,152.79 136.23,152.41 v4(136.22,152.4)
M_SCS_A_N1: length 59.2
  TOP w0.165: DIMM1.121 132.59,152.15 v1(133.48,151.26) ; CPU2.AU38 v1(89.26,169.84)
  L4 w0.089: v1(89.26,169.84) 89.85,169.25 95.01,169.25 95.13,169.37 95.97,169.37 99.27,172.67 99.63,172.67
  L4 w0.216: v1(133.48,151.26) 133.48,151.26 133.1,151.64 130.97,151.64 109.39,173.22 102.42,173.22 101.87,172.67 99.63,172.67
  BOTTOM w0.165: v4(133.06,151.83) 133.48,151.41 v1(133.48,151.26)
M_WE_A_N: length 64.6
  TOP w0.089: CPU2.BH44 95.07,173.26 95.17,173.36 95.97,173.36 96.03,173.43
  TOP w0.102: 96.03,173.43 98.15,173.43
  TOP w0.165: DIMM1.113 134.31,154.55 v1(134.93,153.92) ; 98.15,173.43 98.28,173.55 v1(99.83,173.55)
  L3 w0.216: v1(99.83,173.55) 99.83,173.96 99.94,174.07 101.68,174.07 102.83,172.92 104.23,172.92 107.68,169.47 109.1,169.47 109.58,168.99 109.58,167.57 123.82,153.34 124.9,153.34 125.03,153.21 125.03,152.13 125.58,151.58 126.91,151.58 127.26,151.94 127.26,153.06 127.39,153.19 129.09,153.19 129.22,153.06 129.22,151.26 129.34,151.13 131.81,151.13 131.94,151.26 131.94,153.06 132.06,153.19 132.7,153.19 132.82,153.06 132.82,151.97 132.95,151.84 133.79,151.84 133.92,151.97 133.92,153.34 134.5,153.92 v1(134.93,153.92)
  BOTTOM w0.165: v1(134.93,153.92) 135.31,154.3 v4(135.31,154.55)
MAA0: length 56.9
  TOP w0.102: MEM1.N3 54.2,108.08 54.67,108.55 55.42,108.55 v1(55.61,108.36) ; v1(56.58,95.37) 56.58,95.09 56.69,94.99 56.98,94.99 MEM2.N3 ; GPU1.K17 78.14,100.6 78.26,100.47 78.26,100.15 78.14,100.03 v1(77.99,100.03) ; v1(60.2,102.57) 60.29,102.66 v3(61.04,102.66)
  L3 w0.127: v1(60.2,102.57) 60.08,102.44 60.08,102.14 60.2,102.01 60.84,102.01 60.97,102.14 60.97,102.52 61.09,102.65 61.45,102.65 61.57,102.52 61.57,101.92 61.98,101.51 62.88,101.51 63,101.38 63,100.99 63.13,100.87 63.38,100.87 63.51,100.99 63.51,101.55 63.64,101.68 63.89,101.68 64.02,101.55 64.02,100.99 64.15,100.87 64.4,100.87 64.53,100.99 64.53,101.58 64.65,101.71 64.91,101.71 65.04,101.58 65.04,100.99 65.16,100.87 65.42,100.87 65.54,100.99 65.54,101.6 65.67,101.73 65.92,101.73 66.05,101.6 66.05,100.99 66.18,100.87 66.43,100.87 66.56,100.99 66.56,101.4 66.69,101.53 68.31,101.53 68.73,101.11 71.38,101.11 71.6,100.89 72.85,100.89 72.99,101.03 72.99,101.4 73.12,101.53 73.37,101.53 73.5,101.4 73.5,101.03 73.82,100.72 74.25,100.72 74.38,100.84 74.71,100.84 74.83,100.72 75.24,100.72 75.47,100.49 76.08,100.49 76.21,100.61 76.66,100.61 76.79,100.49 77.65,100.49 77.99,100.15 v1(77.99,100.03)
  L4 w0.127: v1(56.58,95.37) 56.46,95.49 56.46,96.2 57.59,97.33 57.59,98.14 59.83,100.38 60.14,100.38 60.42,100.66 60.42,101.28 60.23,101.47 60.23,102.01 60.36,102.14 60.64,102.14 60.77,102.27 60.77,102.44 60.64,102.57 v1(60.2,102.57) 60.23,102.59 60.23,105.45 60.71,105.94 60.71,106.95 60.45,107.21 57.56,107.21 56.67,108.09 56.63,108.09 56.36,108.36 v1(55.61,108.36)
  BOTTOM w0.102: v1(55.61,108.36) 55.76,108.51 56.1,108.51 56.76,107.85 56.98,107.85 MEM3.N3 ; MEM4.N3 54.13,95.22 54.53,95.62 56.33,95.62 v1(56.58,95.37)
MAA1: length 51
  TOP w0.102: GPU1.J20 76.67,103 76.2,103.47 76.19,103.47 76.15,103.51 v1(75.75,103.51) ; v1(55.33,96.95) 55.12,96.95 54.2,96.02 MEM2.P7 ; v1(55.94,106.4) 55.94,106.9 56.32,107.28 MEM1.P7
  L3 w0.127: v1(75.75,103.51) 75.3,103.95 74.55,103.95 74.51,103.99 71.35,103.99 71.34,103.98 70.86,103.98 70.68,104.17 64.76,104.17 64.62,104.03 59.66,104.03 59.28,103.66 57.71,103.66 57.58,103.79 55.65,103.79 55.64,103.79 55.3,103.79 55.29,103.79 55.23,103.79 55.02,103.58 55.02,103.23 54.07,102.28 52.85,102.28 52.62,102.5 52.62,103.11 v2(52.86,103.34)
  L4 w0.127: v1(55.94,106.4) 55.64,106.4 55.22,106.83 54.97,106.83 54.72,107.07 54.72,107.31 54.62,107.41 54.27,107.41 54.17,107.31 54.17,107.03 54.07,106.93 53.66,106.93 53.05,106.32 53.05,105.94 52.44,105.33 52.44,103.76 v2(52.86,103.34) 52.86,102.88 54.14,101.6 54.14,98.14 v1(55.33,96.95)
  BOTTOM w0.102: v4(52.04,103.5) 52.19,103.34 v2(52.86,103.34) ; v1(55.94,106.4) 55.8,106.4 55.38,106.82 55.08,106.82 55.08,106.82 54.97,106.82 54.51,107.28 MEM3.P7 ; v1(55.33,96.95) 55.7,96.58 56.42,96.58 56.98,96.02 MEM4.P7
MAA2: length 56
  TOP w0.102: MEM2.P3 57.05,96.18 56.63,96.18 56.24,96.58 55.91,96.58 55.82,96.67 55.82,96.82 v1(56.04,97.03) ; GPU1.H23 76.48,104.92 v1(76.48,104.73) ; MEM1.P3 54.25,107.05 54.47,107.05 54.58,107.15 54.58,107.33 54.67,107.43 54.96,107.43 v1(55.14,107.24)
  L3 w0.127: v1(58.01,104.12) 58.24,103.89 58.98,103.89 59.39,104.3 59.39,104.91 59.52,105.03 59.82,105.03 59.95,104.91 59.95,104.45 60.08,104.32 60.33,104.32 60.46,104.45 60.46,104.92 60.58,105.04 60.84,105.04 60.97,104.92 60.97,104.46 61.09,104.33 61.43,104.33 61.52,104.42 61.52,104.92 61.65,105.04 61.87,105.04 62,104.92 62,104.69 62.24,104.45 64.57,104.45 64.62,104.5 64.98,104.5 65.11,104.63 65.11,105.09 65.24,105.22 65.49,105.22 65.62,105.09 65.62,104.63 65.74,104.5 66,104.5 66.12,104.63 66.12,105.09 66.25,105.22 66.51,105.22 66.63,105.09 66.63,104.63 66.76,104.5 67.01,104.5 67.14,104.63 67.14,105.09 67.27,105.22 67.52,105.22 67.65,105.09 67.65,104.63 67.78,104.5 68.03,104.5 68.16,104.63 68.16,105.09 68.28,105.22 68.54,105.22 68.66,105.09 68.66,104.63 68.79,104.5 70.51,104.5 70.85,104.84 71.56,104.84 71.68,104.71 71.68,104.45 71.81,104.32 72.34,104.32 72.47,104.45 72.47,104.71 72.6,104.84 73.26,104.84 73.39,104.71 73.39,104.36 73.51,104.23 74.47,104.23 74.48,104.22 74.61,104.22 74.65,104.18 75.62,104.18 75.81,103.99 76.3,103.99 76.61,104.31 76.61,104.6 v1(76.48,104.73)
  L4 w0.127: v1(56.04,97.03) 56.82,97.82 56.82,98.43 58.99,100.6 58.99,102.9 58.01,103.88 v1(58.01,104.12) 57.68,104.12 57.42,104.37 57.42,104.9 57.55,105.02 57.87,105.02 58,105.15 58,105.47 57.87,105.6 56.36,105.6 56.18,105.78 56.18,106.03 56.31,106.16 57.08,106.16 57.21,106.29 57.21,106.52 56.9,106.82 55.56,106.82 v1(55.14,107.24)
  BOTTOM w0.102: MEM4.P3 54.81,96.82 54.81,97 55.16,97.35 55.72,97.35 v1(56.04,97.03) ; MEM3.P3 57.12,107.28 56.67,106.83 55.68,106.83 55.26,107.24 v1(55.14,107.24) ; v1(58.01,104.12) 58.28,103.85 58.41,103.85 v4(58.64,103.62)
MAA3: length 60.4
  TOP w0.102: MEM1.N2 53.5,108.08 53.63,108.21 53.63,108.42 53.5,108.55 52.91,108.55 52.79,108.42 52.79,107.78 52.91,107.65 55.46,107.65 v1(55.77,107.34) ; v1(75,104.85) 75.05,104.85 GPU1.G23 ; MEM2.N2 56.8,95.78 56.48,95.78 56.19,95.68 55.86,95.68 v1(55.35,96.05)
  L3 w0.127: v1(58.65,104.89) 58.52,104.76 58.05,104.76 57.92,104.89 57.92,105.06 57.79,105.19 56.98,105.19 56.6,105.57 56.6,106.23 56.73,106.35 57.89,106.35 58.01,106.23 58.01,105.69 58.14,105.57 59.64,105.57 59.76,105.69 59.76,105.82 59.89,105.95 60.15,105.95 60.27,105.82 60.27,105.69 60.4,105.57 60.65,105.57 60.78,105.69 60.78,105.82 60.91,105.95 61.16,105.95 61.29,105.82 61.29,105.69 61.42,105.57 62.4,105.57 62.7,105.27 64.13,105.27 64.5,105.63 64.5,105.83 64.62,105.95 67.55,105.95 67.95,106.35 68.39,106.35 68.74,106 69.19,106 69.81,105.39 71.91,105.39 71.96,105.34 74.51,105.34 v1(75,104.85)
  L4 w0.127: v1(55.35,96.05) 55.84,96.54 56.13,96.54 57.05,97.45 57.05,98.24 59.22,100.41 59.22,103 58.65,103.57 v1(58.65,104.89) 58.34,104.89 58.23,105 58.23,105.5 58.34,105.61 59.52,105.61 59.64,105.74 59.64,106.45 59.42,106.67 57.38,106.67 56.74,107.31 55.8,107.31 v1(55.77,107.34)
  BOTTOM w0.102: MEM4.N2 53.64,95.64 54.2,95.64 54.6,96.05 v1(55.35,96.05) ; v1(55.77,107.34) 55.77,107.16 55.9,107.03 56.53,107.03 56.63,107.13 56.63,107.49 56.76,107.61 57.46,107.61 57.59,107.74 57.59,107.89 57.56,107.92 57.56,108.26 57.84,108.55 58.15,108.55 58.28,108.68 58.53,108.68 58.63,108.58 58.63,108.36 58.48,108.22 58.48,108.21 58.36,108.08 58.24,108.08 58.23,108.08 MEM3.N2
  BOTTOM w0.127: v1(75,104.85) 74.79,104.85 v4(74.3,105.33)
MAA4: length 55.8
  TOP w0.102: v1(75,105.55) 75.01,105.56 75.01,105.61 GPU1.G24 ; v1(55.49,97.87) 55.49,97.76 54.17,96.45 53.9,96.45 53.48,96.02 MEM2.P8 ; v1(56.01,105.36) 55.96,105.41 55.96,105.68 55.96,105.68 55.96,105.82 56.08,105.94 56.38,105.94 56.73,106.3 56.73,106.42 56.44,106.72 56.44,106.86 56.64,107.06 56.83,107.06 57.04,106.85 58.06,106.85 58.16,106.95 58.16,107.14 MEM1.P8
  L3 w0.127: v2(53.78,103.77) 53.78,105.78 53.91,105.91 55.34,105.91 55.36,105.92 56.24,105.92 56.37,106.05 56.37,106.46 56.49,106.58 59.67,106.58 59.8,106.46 59.8,106.3 59.92,106.18 62.4,106.18 62.49,106.08 62.62,105.96 62.62,105.8 62.74,105.67 63.96,105.67 64.09,105.8 64.09,106.25 64.2,106.36 67.39,106.36 67.51,106.49 67.51,106.74 67.51,106.74 67.51,107.14 67.64,107.26 68.05,107.26 68.91,106.41 69.19,106.41 69.93,105.67 73.76,105.67 73.82,105.6 74.17,105.6 74.24,105.67 74.88,105.67 v1(75,105.55)
  L4 w0.127: v1(56.01,105.36) 55.95,105.41 55.95,105.88 55.85,105.99 55.38,105.99 55.3,105.91 54.95,105.91 54.94,105.91 54.93,105.91 54.7,106.14 54.4,106.14 53.78,105.52 v2(53.78,103.77) 53.78,103.16 54.54,102.39 54.54,102.39 54.6,102.33 54.6,98.76 v1(55.49,97.87)
  BOTTOM w0.102: MEM3.P8 53.67,106.83 54.13,106.83 54.63,106.34 54.63,105.46 54.74,105.35 54.74,105.32 54.97,105.08 55.35,105.08 55.42,105.15 55.8,105.15 v1(56.01,105.36) ; v1(55.49,97.87) 55.69,97.87 56.09,97.47 56.17,97.47 56.54,97.11 56.54,97.03 57.14,96.43 57.61,96.43 MEM4.P8
  BOTTOM w0.127: v4(73.62,106.68) 74.12,106.68 75,105.8 v1(75,105.55)
MAA5: length 56.9
  TOP w0.102: v1(55.12,106.32) 55.12,106.64 54.94,106.83 53.07,106.83 52.98,106.93 52.98,107.04 MEM1.P2 ; v1(56.26,97.88) 56.4,97.74 56.4,97.5 56.55,97.35 56.55,96.67 56.75,96.47 57.85,96.47 58.01,96.31 MEM2.P2 ; v1(75.77,105.59) 75.79,105.59 GPU1.H24 ; v1(53.65,102.7) 54.24,102.11 v3(54.24,102.11)
  L3 w0.127: v1(75.77,105.59) 75.42,105.24 75.42,104.67 75.17,104.43 74.83,104.43 74.47,104.78 74.47,104.82 74.23,105.07 69.73,105.07 69.1,105.69 67.87,105.69 67.72,105.55 64.99,105.55 64.3,104.86 62.41,104.86 61.98,105.29 59.29,105.29 59.1,105.1 59.1,104.75 58.77,104.42 58.3,104.42 58.19,104.54 57.85,104.54 57.63,104.75 57.25,104.75 56.91,104.41 56.56,104.41 56.08,104.89 54.92,104.89 54.67,104.64 54.67,104.07 54.18,103.58 54.18,103.23 v1(53.65,102.7)
  L4 w0.127: v1(55.12,106.32) 54.93,106.52 53.86,106.52 53.45,106.1 53.45,105.4 53.32,105.28 52.9,105.28 52.77,105.15 52.77,104.92 52.9,104.79 53.32,104.79 53.45,104.67 53.45,104.46 53.32,104.34 52.9,104.34 52.77,104.21 52.77,104.01 52.9,103.88 53.2,103.88 53.32,103.75 53.32,102.82 53.45,102.7 v1(53.65,102.7) 54.37,101.97 54.37,98.67 55.07,97.97 55.07,97.7 55.32,97.45 55.66,97.45 55.67,97.46 55.79,97.46 56.21,97.88 v1(56.26,97.88)
  BOTTOM w0.102: v1(55.12,106.32) 55.47,105.98 56.16,105.98 57.04,106.86 57.6,106.86 MEM3.P2 ; v1(56.26,97.88) 55.86,98.28 55.32,98.28 54.68,97.64 54.68,97.34 54.51,97.17 54.51,96.85 54.11,96.45 53.64,96.45 MEM4.P2
MAA6: length 65.3
  TOP w0.102: MEM1.R8 57.59,106.05 57.59,104.85 57.91,104.52 58.18,104.52 58.42,104.29 58.42,104.26 58.59,104.08 58.59,103.81 58.46,103.68 57.92,103.68 v3(57.39,103.15) 56.74,103.81 55.16,103.81 54.77,103.42 54.61,103.42 v1(54.6,103.4) ; GPU1.J19 77.09,101.71 77.34,101.71 77.47,101.83 77.47,102.26 77.34,102.38 v1(77.12,102.38) ; v1(55.37,100.15) 55.48,100.04 55.48,99.78 54.84,99.14 54.68,99.14 54.53,99.29 54.37,99.29 54.25,99.17 54.25,99 54.4,98.85 54.4,98.71 54.26,98.56 54.12,98.56 53.94,98.74 53.77,98.74 53.65,98.63 53.65,98.46 53.83,98.28 53.83,98.13 53.64,97.94 53.64,96.47 53.5,96.33 53.34,96.33 53.21,96.46 MEM2.R8
  L3 w0.127: v1(77.12,102.38) 77.12,102.32 76.89,102.09 76.25,102.09 75.94,101.78 75.55,101.78 75.25,102.09 74.81,102.09 74.58,102.32 74.3,102.32 74.07,102.09 73.74,102.09 73.46,102.37 67.49,102.37 67.33,102.53 66.3,102.53 66.1,102.73 66.1,102.93 65.97,103.05 65.59,103.05 65.46,102.93 65.46,102.67 65.32,102.54 63.49,102.54 63.37,102.66 63.37,103.24 63.24,103.37 62.74,103.37 62.61,103.24 62.61,102.11 62.48,101.98 62.19,101.98 62.06,102.11 62.06,103.21 61.93,103.34 61.67,103.34 61.45,103.11 61.05,103.11 60.83,103.33 60.83,103.34 59.79,103.34 59.56,103.1 56.88,103.1 56.49,102.7 55.83,102.7 55.7,102.58 55.7,102.2 55.83,102.08 v1(55.86,102.08)
  L4 w0.127: v1(55.37,100.15) 55.37,101.01 55.86,101.49 v1(55.86,102.08) 55.86,102.27 55.13,103 55.01,103 54.61,103.4 v1(54.6,103.4)
  BOTTOM w0.102: v1(54.6,103.4) 54.58,103.38 54.58,103.06 54.25,102.73 54.25,102.43 54.09,102.27 54.09,102.25 53.34,102.25 53.21,102.38 53.21,102.89 53.47,103.14 53.47,103.44 52.87,104.05 52.87,104.52 52.73,104.66 51.85,104.66 51.72,104.79 51.72,105.09 51.85,105.22 52.72,105.22 52.82,105.32 52.82,106.38 52.92,106.48 MEM3.R8 ; MEM4.R8 57.67,96.82 57.57,96.92 57.57,98.18 57.84,98.44 58.02,98.44 58.15,98.57 58.15,98.78 58.02,98.9 57.22,98.9 57.09,99.03 57.09,99.21 57.22,99.33 58.07,99.33 58.2,99.46 58.2,99.9 58.07,100.03 57.03,100.03 56.72,99.72 56.27,99.72 55.9,100.09 55.43,100.09 v1(55.37,100.15)
MAA7: length 61.6
  TOP w0.102: v1(55.47,103.38) 55.09,103 53.95,103 53.35,103.59 53.35,105.33 53.54,105.52 53.54,106.15 MEM1.R2 ; v1(56.65,101) 56.7,101 56.71,101.02 v3(58.35,101.02) 58.26,100.92 58.26,99.38 58.16,99.28 57.62,99.28 57.52,99.18 57.52,98.85 57.62,98.75 58.23,98.75 58.33,98.65 58.33,98.32 58.23,98.22 57.75,98.22 57.65,98.12 57.65,96.92 57.75,96.82 MEM2.R2 ; v1(77.36,101.22) 77.81,101.22 77.93,101.35 77.93,101.67 77.81,101.8 GPU1.K19
  L3 w0.127: v1(56.92,102.2) 56.92,102.77 57.02,102.87 57.29,102.87 57.54,102.63 57.82,102.63 58.07,102.87 59.79,102.87 59.9,102.99 60.69,102.99 60.81,102.87 61.68,102.87 61.8,102.75 61.8,102.61 61.8,102.01 62.08,101.74 62.72,101.74 62.85,101.86 62.85,102.06 62.98,102.18 63.43,102.18 63.64,101.97 64,101.97 64.21,102.18 64.65,102.18 64.8,102.04 65.33,102.04 65.69,102.4 65.88,102.4 66.41,101.87 66.62,101.87 66.94,102.2 67.18,102.2 67.52,101.86 68.41,101.86 68.69,102.14 70.32,102.14 70.51,101.95 70.75,101.95 70.94,102.14 72.03,102.14 72.16,102.01 72.16,101.24 72.27,101.12 72.55,101.12 72.66,101.24 72.66,102.01 72.79,102.14 73.23,102.14 73.52,101.85 74.17,101.85 74.3,101.72 74.3,101.43 74.44,101.29 74.68,101.29 74.81,101.41 74.81,101.66 74.94,101.78 75.2,101.78 75.47,101.52 76,101.52 76.29,101.8 77.09,101.8 77.25,101.96 77.61,101.96 77.9,101.68 77.9,101.35 77.77,101.22 v1(77.36,101.22)
  L4 w0.127: v1(56.65,101) 56.66,101 56.98,101 57.1,101.13 57.1,102.08 56.98,102.2 v1(56.92,102.2) 56.92,103.26 56.39,103.78 56.05,103.78 55.64,103.38 v1(55.47,103.38)
  BOTTOM w0.102: MEM3.R2 57.67,106.48 57.57,106.38 57.57,105.31 57.67,105.2 58.08,105.2 58.18,105.1 58.18,104.75 58.08,104.65 57.97,104.65 57.61,104.29 57.61,104.17 57.16,103.73 57.04,103.73 56.94,103.63 56.94,103.14 56.63,102.84 55.79,102.84 55.66,102.71 55.43,102.71 55.22,102.91 55.22,103.07 55.47,103.32 v1(55.47,103.38) ; v1(56.65,101) 56.5,101 56.46,101.04 56.32,101.04 56.13,101.23 55.69,101.23 55.22,100.76 55.12,100.76 54.76,100.4 54.76,100.3 53.61,99.14 53.61,97.21 MEM4.R2
MAA8: length 61.2
  TOP w0.102: v1(55.86,100.82) 55.78,100.74 55.4,100.74 55.26,100.87 55.26,101.01 55.16,101.11 54.78,101.11 54.68,101.01 54.68,99.94 54.55,99.82 53.34,99.82 53.21,99.69 53.21,99.28 53.11,99.18 52.75,99.18 52.64,99.08 52.64,98.85 52.75,98.75 53.11,98.75 53.21,98.65 MEM2.T8 ; v1(76.71,98.81) 77.04,98.81 77.17,98.68 77.17,98.33 77.04,98.2 GPU1.J14 ; v1(56.22,103.37) 56.49,103.1 56.49,102.92 56.74,102.67 57.09,102.67 57.16,102.6 57.63,102.6 57.68,102.65 58.96,102.65 59.15,102.84 59.15,105.03 58.85,105.33 58.36,105.33 MEM1.T8
  L3 w0.127: v1(56.32,101.64) 56.44,101.76 56.95,101.76 57.07,101.64 57.07,101.1 57.17,101.01 57.63,101.01 57.75,101.13 57.75,101.23 58.14,101.61 58.14,102.01 58.3,102.17 58.83,102.17 58.97,102.03 58.97,101.41 58.85,101.29 58.5,101.29 58.27,101.06 58.27,100.71 58.4,100.58 60.94,100.58 62.09,99.43 62.47,99.43 62.75,99.16 63.27,99.16 63.55,99.43 64.15,99.43 64.25,99.33 67.09,99.33 67.22,99.2 67.22,98.68 67.35,98.56 67.69,98.56 67.83,98.7 67.83,99.59 67.96,99.72 69.77,99.72 69.9,99.59 69.9,99.15 70.02,99.02 71.67,99.02 72.08,99.43 72.54,99.43 73.5,98.47 74.4,98.47 74.59,98.28 76.56,98.28 76.71,98.44 v1(76.71,98.81)
  L4 w0.127: v1(55.86,100.82) 56.14,100.82 56.23,100.92 56.23,101.56 v1(56.32,101.64) 56.32,102.21 56.22,102.31 v1(56.22,103.37)
  BOTTOM w0.102: MEM3.T8 53.45,105.68 53.57,105.55 53.57,105.25 53.45,105.13 52.98,105.13 52.86,105.01 52.86,104.84 52.98,104.72 53.72,104.72 53.9,104.54 53.9,104.27 54.14,104.02 54.42,104.02 54.63,103.81 56.42,103.81 56.55,103.68 56.55,103.49 56.42,103.37 v1(56.22,103.37) ; MEM4.T8 58.59,98.19 58.59,98.48 58.69,98.58 59.02,98.58 59.14,98.7 59.14,98.86 59.02,98.98 58.52,98.98 58.4,99.1 58.4,99.27 58.52,99.39 58.86,99.39 58.96,99.49 58.96,99.69 58.86,99.8 58.69,99.8 58.59,99.9 v4(58.59,100.53) 58.14,100.98 57.25,100.98 56.93,100.66 56.93,100.66 56.86,100.59 56.16,100.59 55.93,100.82 v1(55.86,100.82)
MAA9: length 53.1
  TOP w0.102: GPU1.K14 77.5,98.2 77.39,98.09 v1(77.39,97.77) ; MEM1.R3 54.15,106.61 54.55,106.61 54.65,106.51 54.65,106.12 54.85,105.92 54.87,105.92 55.14,105.64 v1(55.14,105.49) ; MEM2.R3 57.21,97.15 57.11,97.25 56.93,97.25 56.82,97.35 56.82,97.72 57.09,97.99 57.09,99.1 56.99,99.21 56.71,99.21 56.44,98.94 v1(56.44,98.69)
  L3 w0.127: v1(58.56,101.75) 58.53,101.73 58.53,101.69 58.36,101.52 58.36,101.47 58.02,101.13 58.02,100.47 58.15,100.35 60.85,100.35 61.99,99.2 62.38,99.2 62.66,98.93 62.99,98.93 63.12,98.8 63.12,98.37 63.24,98.24 63.52,98.24 63.64,98.37 63.64,99.06 63.77,99.19 64.02,99.19 64.15,99.06 64.15,98.46 64.27,98.33 64.53,98.33 64.66,98.46 64.66,98.88 64.77,99 65.04,99 65.16,98.88 65.16,98.46 65.29,98.33 65.54,98.33 65.67,98.46 65.67,98.86 65.81,99 66.71,99 66.89,98.82 66.89,98.55 67.21,98.23 67.68,98.23 67.68,98.23 67.87,98.23 67.96,98.32 67.96,98.51 68.22,98.76 68.42,98.76 68.55,98.64 68.55,98.29 68.67,98.16 68.93,98.16 69.05,98.29 69.05,98.52 69.18,98.65 69.55,98.65 69.7,98.8 71.9,98.8 72.01,98.91 72.01,99.04 72.16,99.19 72.46,99.19 72.72,98.93 72.72,98.62 72.8,98.54 73.11,98.54 73.41,98.24 74.31,98.24 74.5,98.05 74.99,98.05 75.14,97.9 75.51,97.9 75.66,98.05 75.96,98.05 76.11,97.9 76.56,97.9 76.75,98.09 77.07,98.09 v1(77.39,97.77)
  L4 w0.127: v1(55.14,105.49) 55.29,105.49 55.83,104.94 56.25,104.94 56.57,105.25 56.91,105.25 57.16,105.01 57.16,104.31 58.51,102.96 58.51,101.79 v1(58.56,101.75) 58.56,100.78 56.46,98.69 v1(56.44,98.69)
  BOTTOM w0.102: v1(55.14,105.49) 55.35,105.69 55.77,105.69 55.84,105.77 56.18,105.77 56.25,105.69 56.66,105.69 56.99,106.02 57.26,106.02 57.37,106.14 57.37,106.37 57.26,106.48 MEM3.R3 ; v4(59.31,102.41) 59.31,102.31 58.85,101.85 58.77,101.85 58.67,101.75 v1(58.56,101.75) ; v1(56.44,98.69) 56.32,98.69 56.12,98.9 55.92,98.9 55.63,99.18 55.29,99.18 55.2,99.09 55.17,99.09 54.93,98.85 54.93,98.82 54.72,98.61 54.72,97.98 54.4,97.66 54.4,97.46 54.01,97.08 MEM4.R3
MAA10: length 59.7
  TOP w0.102: v1(54.75,92.84) 54.75,93.07 54.58,93.24 54.11,93.24 54.01,93.34 MEM2.L7 ; v1(55.86,109.75) 56.03,109.92 56.94,109.92 57.18,109.68 MEM1.L7 ; v1(76.94,96.46) 77,96.4 GPU1.J11
  L3 w0.127: v1(60.58,99.62) 60.77,99.43 61.04,99.43 61.62,98.86 61.62,98.55 62.21,97.97 62.54,97.97 63.45,97.06 66.11,97.06 66.43,97.39 72.98,97.39 73.5,96.87 74.17,96.87 74.3,96.74 75.41,96.74 75.43,96.73 76.81,96.73 76.94,96.6 v1(76.94,96.46)
  L4 w0.127: v1(55.86,109.75) 56.39,109.75 57.39,108.75 57.62,108.75 57.75,108.63 57.75,108.54 57.88,108.41 61.22,108.41 61.35,108.28 61.35,102.1 61.48,101.97 61.98,101.97 62.11,101.85 62.11,100.8 61.63,100.32 61.63,100.05 61.2,99.62 v1(60.58,99.62) 60.12,99.16 59.64,99.16 58.86,98.38 58.86,97.03 58.63,96.81 58.25,96.81 58.25,96.8 58.01,96.8 57.33,96.13 57.33,94.85 57.03,94.55 55.1,94.55 54.83,94.27 53.27,94.27 53.14,94.15 53.14,93.87 53.27,93.74 53.95,93.74 54.06,93.64 54.06,93.42 53.95,93.32 53.15,93.32 53.05,93.22 53.05,92.94 53.15,92.84 53.43,92.84 53.44,92.84 53.78,92.84 53.79,92.84 v1(54.75,92.84)
  BOTTOM w0.102: MEM4.L7 56.39,93.62 56.02,93.51 55.75,93.41 v1(54.75,92.84) ; MEM3.L7 54.33,109.99 54.72,109.99 55,109.71 55.82,109.71 v1(55.86,109.75) ; v1(60.58,99.62) 60.58,99.65 60.66,99.72 v4(61.45,99.72)
MAA11: length 53.2
  TOP w0.102: MEM2.R7 54.76,97.57 54.76,98.08 55.34,98.66 v1(55.34,98.68) ; v1(56.74,104.83) 56.77,104.86 56.77,105.95 56.89,106.08 57.25,106.08 57.38,106.21 57.38,106.35 57.25,106.48 MEM1.R7 ; GPU1.J13 76.75,97 76.57,97.18 v1(76.57,97.47)
  L3 w0.127: v1(76.57,97.47) 76.57,97.06 76.47,96.96 75.52,96.96 75.43,97.05 74.75,97.05 74.63,97.18 74.63,97.39 74.5,97.52 74.3,97.52 74.17,97.39 74.17,97.21 74.06,97.1 73.61,97.1 73.48,97.22 73.48,97.71 72.9,98.29 72.55,98.29 72.42,98.16 72.42,97.75 72.3,97.62 72.04,97.62 71.92,97.75 71.92,98.42 71.79,98.55 71.26,98.55 70.93,98.23 70.6,98.23 70.28,98.55 69.89,98.55 69.78,98.44 69.78,98.19 69.78,98.13 69.59,97.93 69.53,97.93 69.52,97.93 68.94,97.93 68.66,97.66 68.21,97.66 67.96,97.91 67.96,97.93 67.48,97.93 67.28,97.73 66.64,97.73 66.52,97.86 66.52,98.15 66.52,98.15 66.52,98.53 66.39,98.66 66.16,98.66 66.06,98.57 66.06,97.53 65.94,97.4 65.68,97.4 65.56,97.53 65.56,97.87 65.43,98 65.18,98 65.05,97.87 65.05,97.53 64.92,97.41 64.67,97.41 64.54,97.53 64.54,97.84 64.41,97.97 64.16,97.97 64.03,97.84 64.03,97.44 63.91,97.31 63.65,97.31 63.52,97.44 63.52,97.87 63.4,98 63.09,98 62.71,98.37 62.43,98.37 60.76,100.04 60.41,100.04 60.17,99.8 60.17,99.62 60.04,99.5 59.77,99.5 59.64,99.62 59.64,99.95 59.51,100.08 59.24,100.08 59.11,99.95 59.11,99.62 58.99,99.5 58.71,99.5 58.58,99.62 58.58,99.9 58.45,100.03 58.18,100.03 58.05,99.9 58.05,99.69 57.92,99.56 57.63,99.56 57.29,99.89 57.29,100.32 v1(57.54,100.57)
  L4 w0.127: v1(55.34,98.68) 55.34,98.57 55.46,98.45 55.79,98.45 55.92,98.57 55.92,98.87 56.15,99.11 56.56,99.11 57.54,100.09 v1(57.54,100.57) 57.98,101.01 57.98,102.89 56.74,104.13 v1(56.74,104.83)
  BOTTOM w0.102: MEM4.R7 56.84,97.19 56.84,97.87 56.43,98.28 56.23,98.28 56.15,98.36 56.08,98.36 55.8,98.64 55.6,98.64 55.56,98.68 55.34,98.68 v1(55.34,98.68) ; v1(56.74,104.83) 56.41,104.83 56.29,104.95 55.51,104.95 55.43,104.88 54.89,104.88 54.35,105.42 54.35,106.15 MEM3.R7
  BOTTOM w0.127: v4(76.22,98.1) 76.23,98.09 76.23,98.07 76.57,97.73 v1(76.57,97.47)
MAA12: length 55
  TOP w0.102: v1(55.95,95.19) 55.89,95.19 55.52,95.57 54.89,95.57 54.54,95.22 MEM2.N7 ; MEM1.N7 56.94,108.08 56.94,108.07 56.53,108.07 56.42,108.19 56.08,108.19 55.8,107.91 55.15,107.91 v1(54.92,108.14) ; GPU1.H11 76.15,95.8 v1(75.66,95.3)
  L3 w0.127: v1(75.66,95.3) 75.11,95.3 74.68,95.74 73.34,95.74 73.09,95.98 71.48,95.98 71.29,96.17 70.3,96.17 69.87,96.6 66.83,96.6 66.48,96.25 62.86,96.25 61.95,97.16 61.81,97.16 61.12,97.85 61.12,98.02 60.86,98.28 60.68,98.28 60.15,98.81 57.33,98.81 56.88,99.26 56.43,99.26 56.33,99.16 56.2,99.16 56.1,99.06 55.75,99.06 55.61,99.2 55.28,99.2 55.16,99.07 53.9,99.07 52.46,100.5 v1(52.46,100.89)
  L4 w0.127: v1(54.92,108.14) 54.55,108.14 52.66,106.25 52.66,106.07 52.21,105.63 52.21,101.67 52.46,101.42 v1(52.46,100.89) 53.78,100.89 53.91,100.76 53.91,100.21 53.78,100.08 53.23,100.08 53.1,99.95 53.1,99.7 53.23,99.57 53.78,99.57 53.91,99.44 53.91,98.05 54.84,97.11 54.84,95.74 54.97,95.61 55.52,95.61 55.94,95.19 v1(55.95,95.19)
  BOTTOM w0.102: MEM4.N7 56.94,94.94 56.19,94.94 55.95,95.18 v1(55.95,95.19) ; v1(52.46,100.89) 52.46,101.43 v4(52.16,101.74) ; v1(54.92,108.14) 55.19,108.41 55.19,108.58 54.89,108.87 54.5,108.87 54.01,108.39 MEM3.N7
MAA13: length 54.1
  TOP w0.102: MEM2.T3 57.4,97.81 57.4,98.52 57.31,98.61 57.31,99.78 56.96,100.13 56.71,100.13 56.65,100.19 v1(56.57,100.19) ; GPU1.G20 75.12,103.28 v1(75.12,103.48)
  TOP w0.127: v1(55.09,104.47) 54.39,104.47 54.26,104.6 54.26,104.95 54.39,105.08 54.53,105.08 54.66,105.21 54.66,105.55 54.53,105.68 MEM1.T3
  L3 w0.127: v1(54.96,102.56) 54.79,102.56 54.16,101.93 53.6,101.93 53.45,101.78 53.45,101.55 54.39,100.61 55.33,100.61 55.43,100.72 55.43,101.03 55.33,101.13 55.04,101.13 54.87,101.3 54.87,101.78 55.44,102.36 55.44,102.72 55.66,102.94 56.4,102.94 56.88,103.42 59.53,103.42 59.73,103.62 64.79,103.62 65,103.84 70.62,103.84 70.71,103.75 71.43,103.75 71.45,103.76 74.42,103.76 74.7,103.48 v1(75.12,103.48)
  L4 w0.127: v1(56.57,100.19) 56.03,100.19 55.57,99.73 55.18,99.73 54.85,100.06 54.85,102.41 54.96,102.51 v1(54.96,102.56) 54.7,102.56 54.18,103.08 54.18,103.58 54.55,103.95 54.55,104.36 54.43,104.49 54.2,104.49 54.07,104.61 54.07,104.91 54.2,105.04 55.35,105.04 55.48,104.91 55.48,104.65 55.29,104.47 v1(55.09,104.47)
  BOTTOM w0.102: v4(53.72,101.74) 54.14,101.74 v1(54.96,102.56) ; MEM3.T3 57.21,104.75 57.15,104.69 57.15,104.67 56.91,104.43 56.56,104.43 56.35,104.64 56.32,104.64 56.3,104.65 56.03,104.65 55.93,104.75 55.59,104.75 55.46,104.61 55.23,104.61 v1(55.09,104.47) ; MEM4.T3 54.01,99.25 54.97,100.2 54.97,100.32 55.2,100.55 55.54,100.55 55.7,100.39 56.36,100.39 v1(56.57,100.19)
MAA14: length 49.8
  TOP w0.127: v1(55.76,104.34) 56.04,104.34 56.15,104.23 56.73,104.23 57.21,104.71 MEM1.T7 ; GPU1.G14 75.4,98.1 75.21,97.91 75.07,97.91 74.95,98.03 74.95,98.17 74.79,98.33 74.79,98.47 74.95,98.63 74.95,98.93 75.07,99.06 75.59,99.06 75.71,98.94 v1(75.71,98.7) ; v1(55.92,99.48) 55.81,99.36 55.38,99.36 54.01,97.99 MEM2.T7
  L3 w0.127: v1(75.71,98.7) 75.71,98.87 75.59,99 75.31,99 75.17,98.86 75.17,98.63 75.05,98.51 74.72,98.51 74.59,98.64 74.59,98.73 74.47,98.86 74.26,98.86 74.1,98.7 73.87,98.7 73.71,98.86 73.44,98.86 73.13,99.16 73.13,100 73.01,100.13 72.64,100.13 72.51,100 72.51,99.78 72.4,99.66 72.14,99.66 72.02,99.78 72.02,99.98 71.88,100.13 71.38,100.13 71.21,100.3 70.85,100.3 70.61,100.06 70.17,100.06 70.17,100.06 69.45,100.06 69.45,100.06 68.73,100.06 68.32,100.06 68.19,100.19 68.19,100.41 68.09,100.51 67.77,100.51 67.67,100.41 67.67,99.9 67.44,99.66 64.25,99.66 64.15,99.76 63.54,99.76 63.16,99.39 62.85,99.39 62.57,99.66 62.18,99.66 61.76,100.08 61.76,100.47 61.54,100.7 61.15,100.7 61.03,100.81 60.84,100.81 60.44,100.81 60.25,101.01 59.76,101.01 59.56,100.81 59.2,100.81 59.07,100.94 59.07,101.18 59.2,101.32 59.2,101.84 59.33,101.97 59.4,101.97 59.71,102.28 59.71,102.52 59.58,102.64 59.24,102.64 59.02,102.43 58.75,102.43 58.53,102.64 58.53,102.64 58.16,102.64 57.92,102.4 57.45,102.4 57.34,102.29 57.34,101.78 57.46,101.65 v1(57.56,101.65)
  L4 w0.127: v1(55.76,104.34) 56.16,104.34 57.56,102.94 v1(57.56,101.65) 57.61,101.65 57.74,101.52 57.74,101.11 57.61,100.99 57.28,100.99 56.99,100.7 56.99,99.86 56.48,99.35 56.05,99.35 v1(55.92,99.48)
  BOTTOM w0.127: v1(55.76,104.34) 55.76,104.17 55.63,104.04 54.72,104.04 54.52,104.24 54.52,104.25 54.01,104.75 MEM3.T7 ; v1(55.92,99.48) 56.75,99.48 56.87,99.35 56.87,98.94 57.35,98.47 57.35,97.75 57.22,97.62 MEM4.T7 ; v1(57.56,101.65) 57.56,102.26 v4(57.77,102.46)
MAA_BA0: length 60.2
  TOP w0.102: v3(60.37,100.88) 60.37,101.11 v1(60.84,101.58) ; v1(55.32,95.11) 55.66,94.77 56.13,94.77 56.13,94.77 57.67,94.77 MEM2.M2 ; v1(77.59,98.72) 77,99.31 GPU1.J16 ; MEM1.M2 53.33,109 53.56,109 53.68,108.87 53.68,108.74 53.88,108.55 53.88,108.55 53.97,108.53 54.12,108.53 54.6,108.78 55.89,108.78 55.93,108.74 56.37,108.74 56.47,108.84 56.67,108.84 56.8,108.72 v1(56.8,108.51)
  L3 w0.127: v1(77.59,98.72) 77.63,98.72 77.74,98.83 77.74,99.3 77.54,99.5 75.72,99.5 75.45,99.77 75.45,100.18 75.25,100.39 74.62,100.39 74.5,100.27 74.5,100.14 74.38,100.02 73.77,100.02 73.64,100.14 73.64,100.46 73.51,100.59 71.57,100.59 71.28,100.88 70.68,100.88 70.55,100.75 70.55,100.64 70.42,100.52 70.17,100.52 70.04,100.64 70.04,100.75 69.91,100.88 69.66,100.88 69.53,100.75 69.53,100.64 69.41,100.52 69.15,100.52 69.03,100.64 69.03,100.75 68.9,100.88 68.63,100.88 68.34,101.18 67.06,101.18 66.93,101.05 66.93,100.44 66.81,100.32 64.25,100.32 64.24,100.32 62.77,100.32 62.65,100.44 62.65,101.06 62.48,101.23 61.69,101.23 61.49,101.43 61.49,101.68 61.34,101.83 60.98,101.83 60.84,101.69 v1(60.84,101.58)
  L4 w0.127: v1(56.8,108.51) 57.22,108.1 59.88,108.1 61,106.98 61,102.13 60.84,101.97 v1(60.84,101.58) 61.3,101.58 61.43,101.45 61.43,101.13 61.3,101 60.88,101 60.75,100.88 60.75,100.31 60.48,100.04 60.2,100.04 59.41,99.26 59.41,99.25 58.63,98.47 58.63,97.95 58.5,97.83 58.11,97.83 57.98,97.7 57.98,97.15 57.01,96.18 57.01,95.21 56.58,94.78 55.66,94.78 v1(55.32,95.11)
  BOTTOM w0.102: v1(56.8,108.51) 56.88,108.43 57.44,108.43 57.56,108.56 57.56,109.21 57.7,109.35 58.15,109.35 58.33,109.53 58.5,109.53 58.68,109.35 58.68,109.21 58.48,109.02 58.48,109.01 58.36,108.88 MEM3.M2 ; MEM4.M2 52.99,94.42 52.86,94.55 52.86,94.74 52.99,94.87 53.34,94.87 53.47,95 53.75,95 53.88,94.87 54.13,94.87 54.67,95.41 55.19,95.41 55.32,95.28 v1(55.32,95.11)
MAA_BA1: length 57.5
  TOP w0.102: v1(56.02,96.08) 55.97,96.08 55.58,96.47 55.12,96.47 54.3,95.65 53.64,95.65 MEM2.N8 ; v1(56.27,107.74) 56.27,107.65 56.39,107.52 56.99,107.52 57.08,107.61 57.45,107.61 57.56,107.73 57.56,108.11 57.67,108.21 57.88,108.21 MEM1.N8 ; GPU1.L15 78.9,98.6 79,98.5 79,98.44 79,98.44 79,98.06 79,98.06 79,98.03 78.9,97.93 78.46,97.93 78.36,98.02 v1(78.36,98.08)
  L3 w0.127: v1(78.36,98.08) 78.36,97.59 78.24,97.46 77.95,97.46 77.81,97.6 77.81,97.95 77.56,98.19 77.29,98.19 77.17,98.32 77.17,99.06 76.99,99.24 75.34,99.24 75.21,99.37 75.21,99.95 75.09,100.08 74.83,100.08 74.71,99.95 74.71,99.24 74.55,99.09 73.57,99.09 73.38,99.28 73.38,100.23 73.26,100.36 71.47,100.36 71.29,100.54 70.77,100.54 70.52,100.29 70.07,100.29 70.07,100.29 69.54,100.29 69.54,100.29 68.63,100.29 68.5,100.42 68.5,100.68 68.35,100.84 67.43,100.84 67.3,100.71 67.3,100.28 67.01,99.99 62.6,99.99 61.52,101.07 60.61,101.07 60.41,101.27 60.05,101.27 59.82,101.51 v1(59.82,101.79)
  L4 w0.127: v1(56.02,96.08) 57.36,97.42 57.36,98.23 59.48,100.36 59.48,100.5 59.61,100.63 60.06,100.63 60.18,100.75 60.18,101.02 60.06,101.14 59.57,101.14 59.44,101.26 59.44,101.67 59.57,101.79 v1(59.82,101.79) 59.78,101.82 59.78,104.57 59.87,104.66 59.87,106.54 59.44,106.98 57.46,106.98 56.7,107.74 v1(56.27,107.74)
  BOTTOM w0.102: MEM4.N8 57.55,95.68 56.87,95.68 56.47,96.08 v1(56.02,96.08) ; MEM3.N8 53.56,107.74 55.53,107.74 55.54,107.74 56,107.74 56.01,107.74 v1(56.27,107.74) ; v1(59.82,101.79) 59.75,101.72 59.75,101.07 60.08,100.73 v4(60.56,100.73)
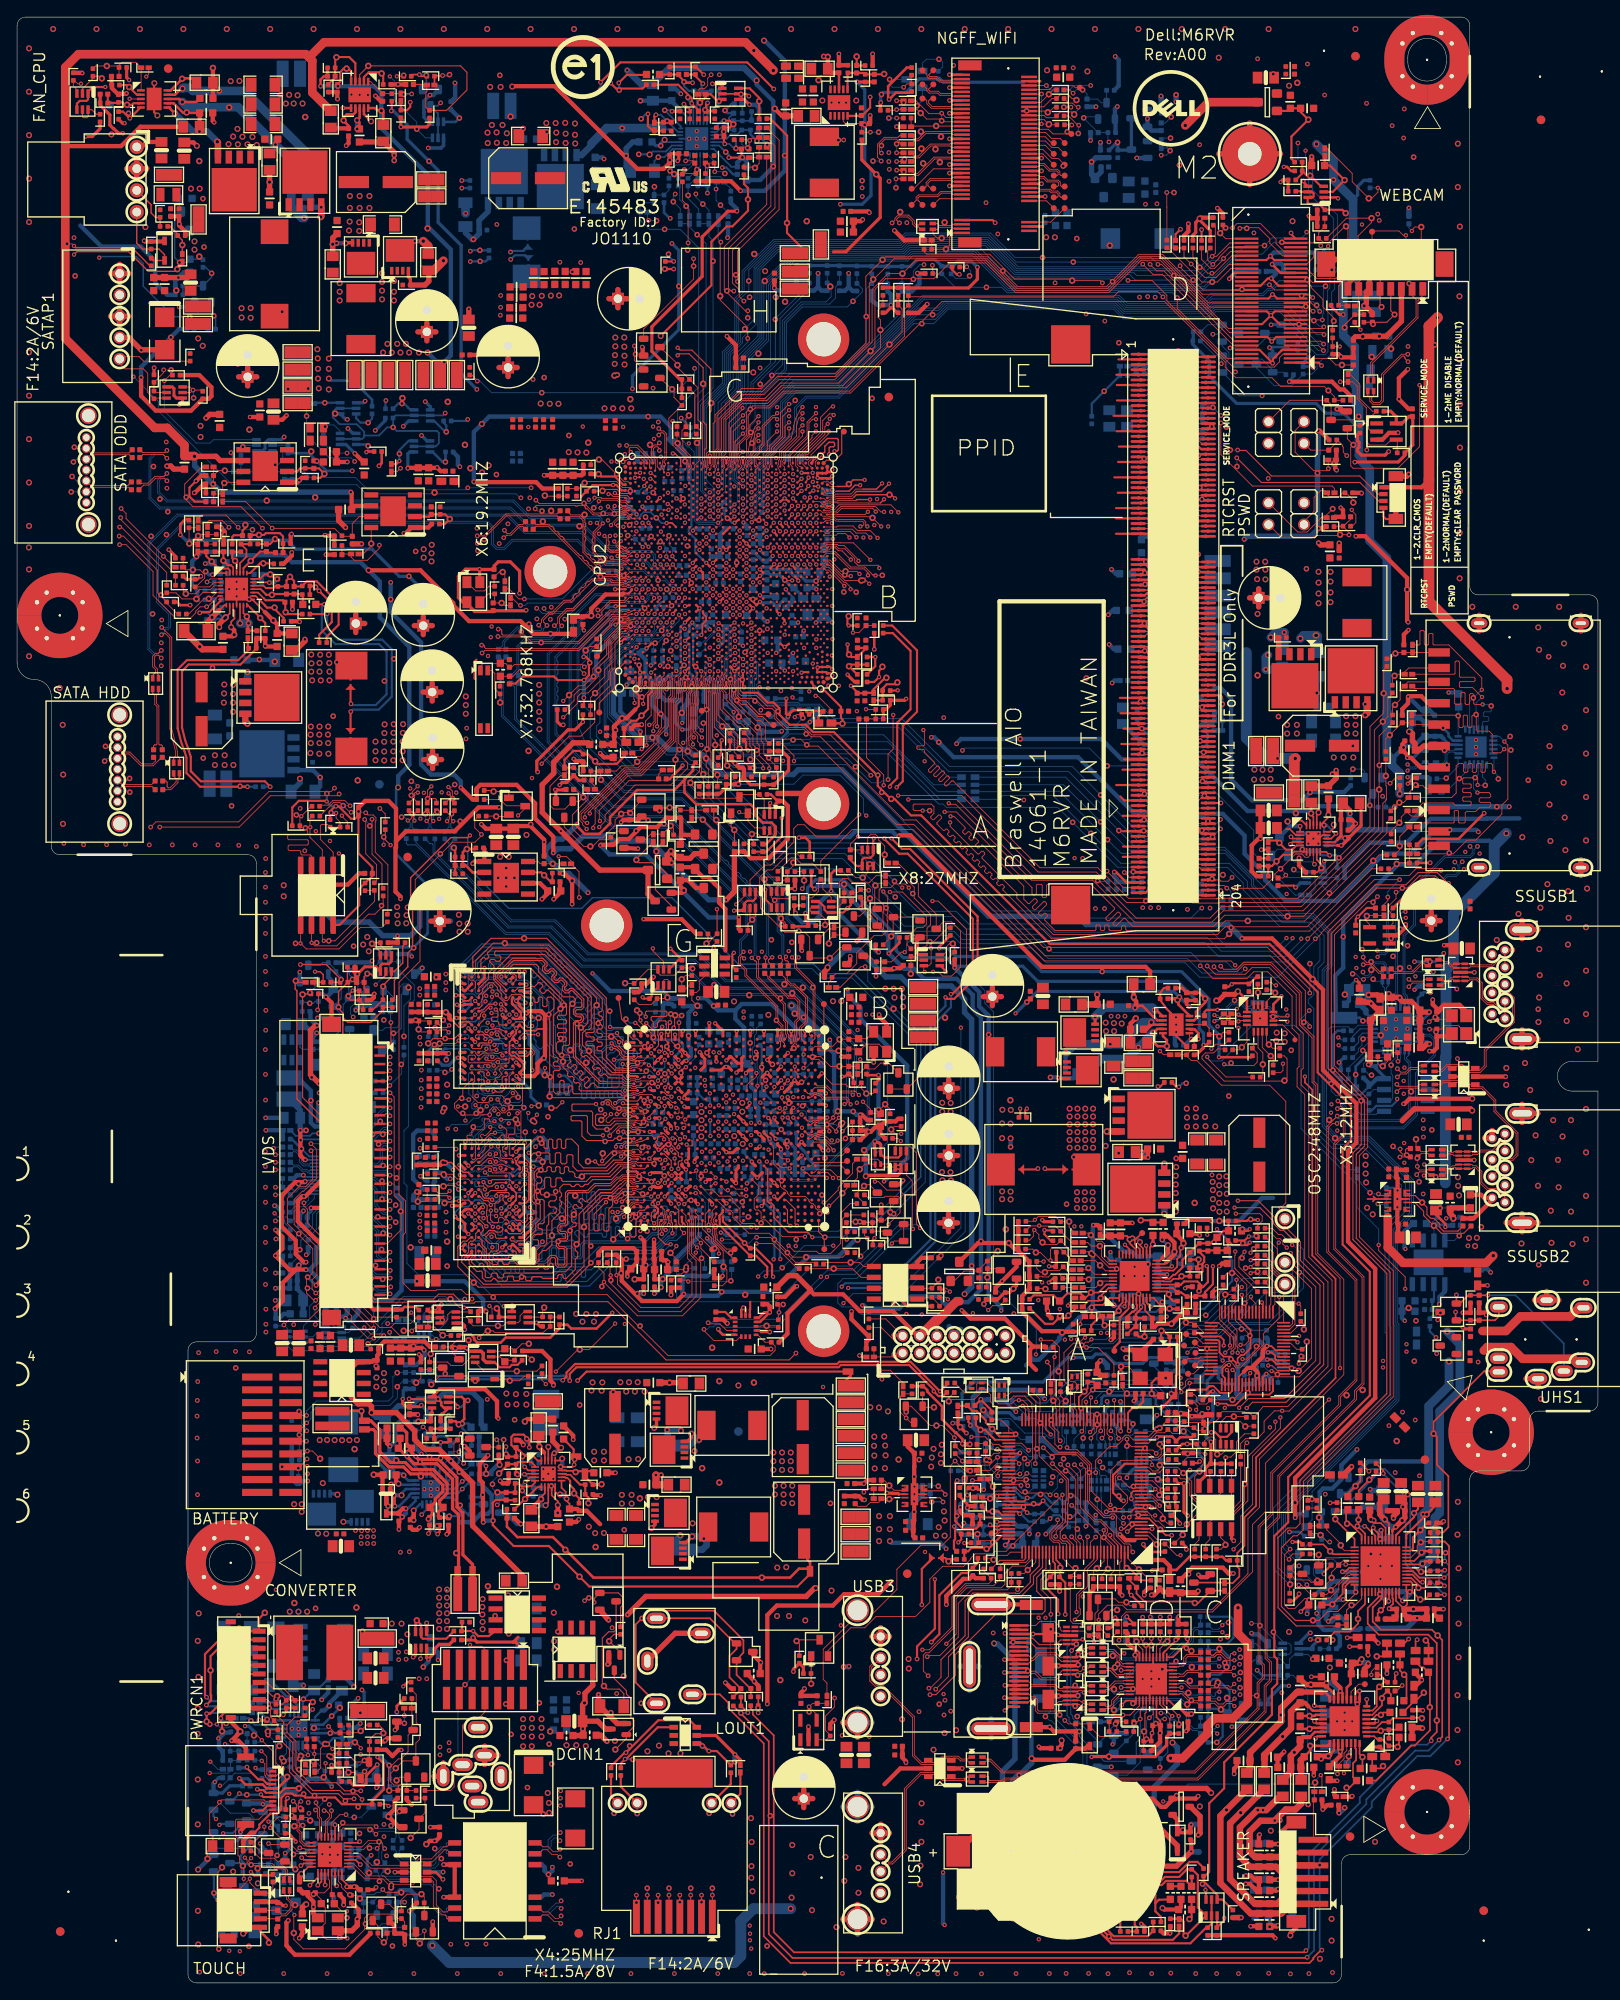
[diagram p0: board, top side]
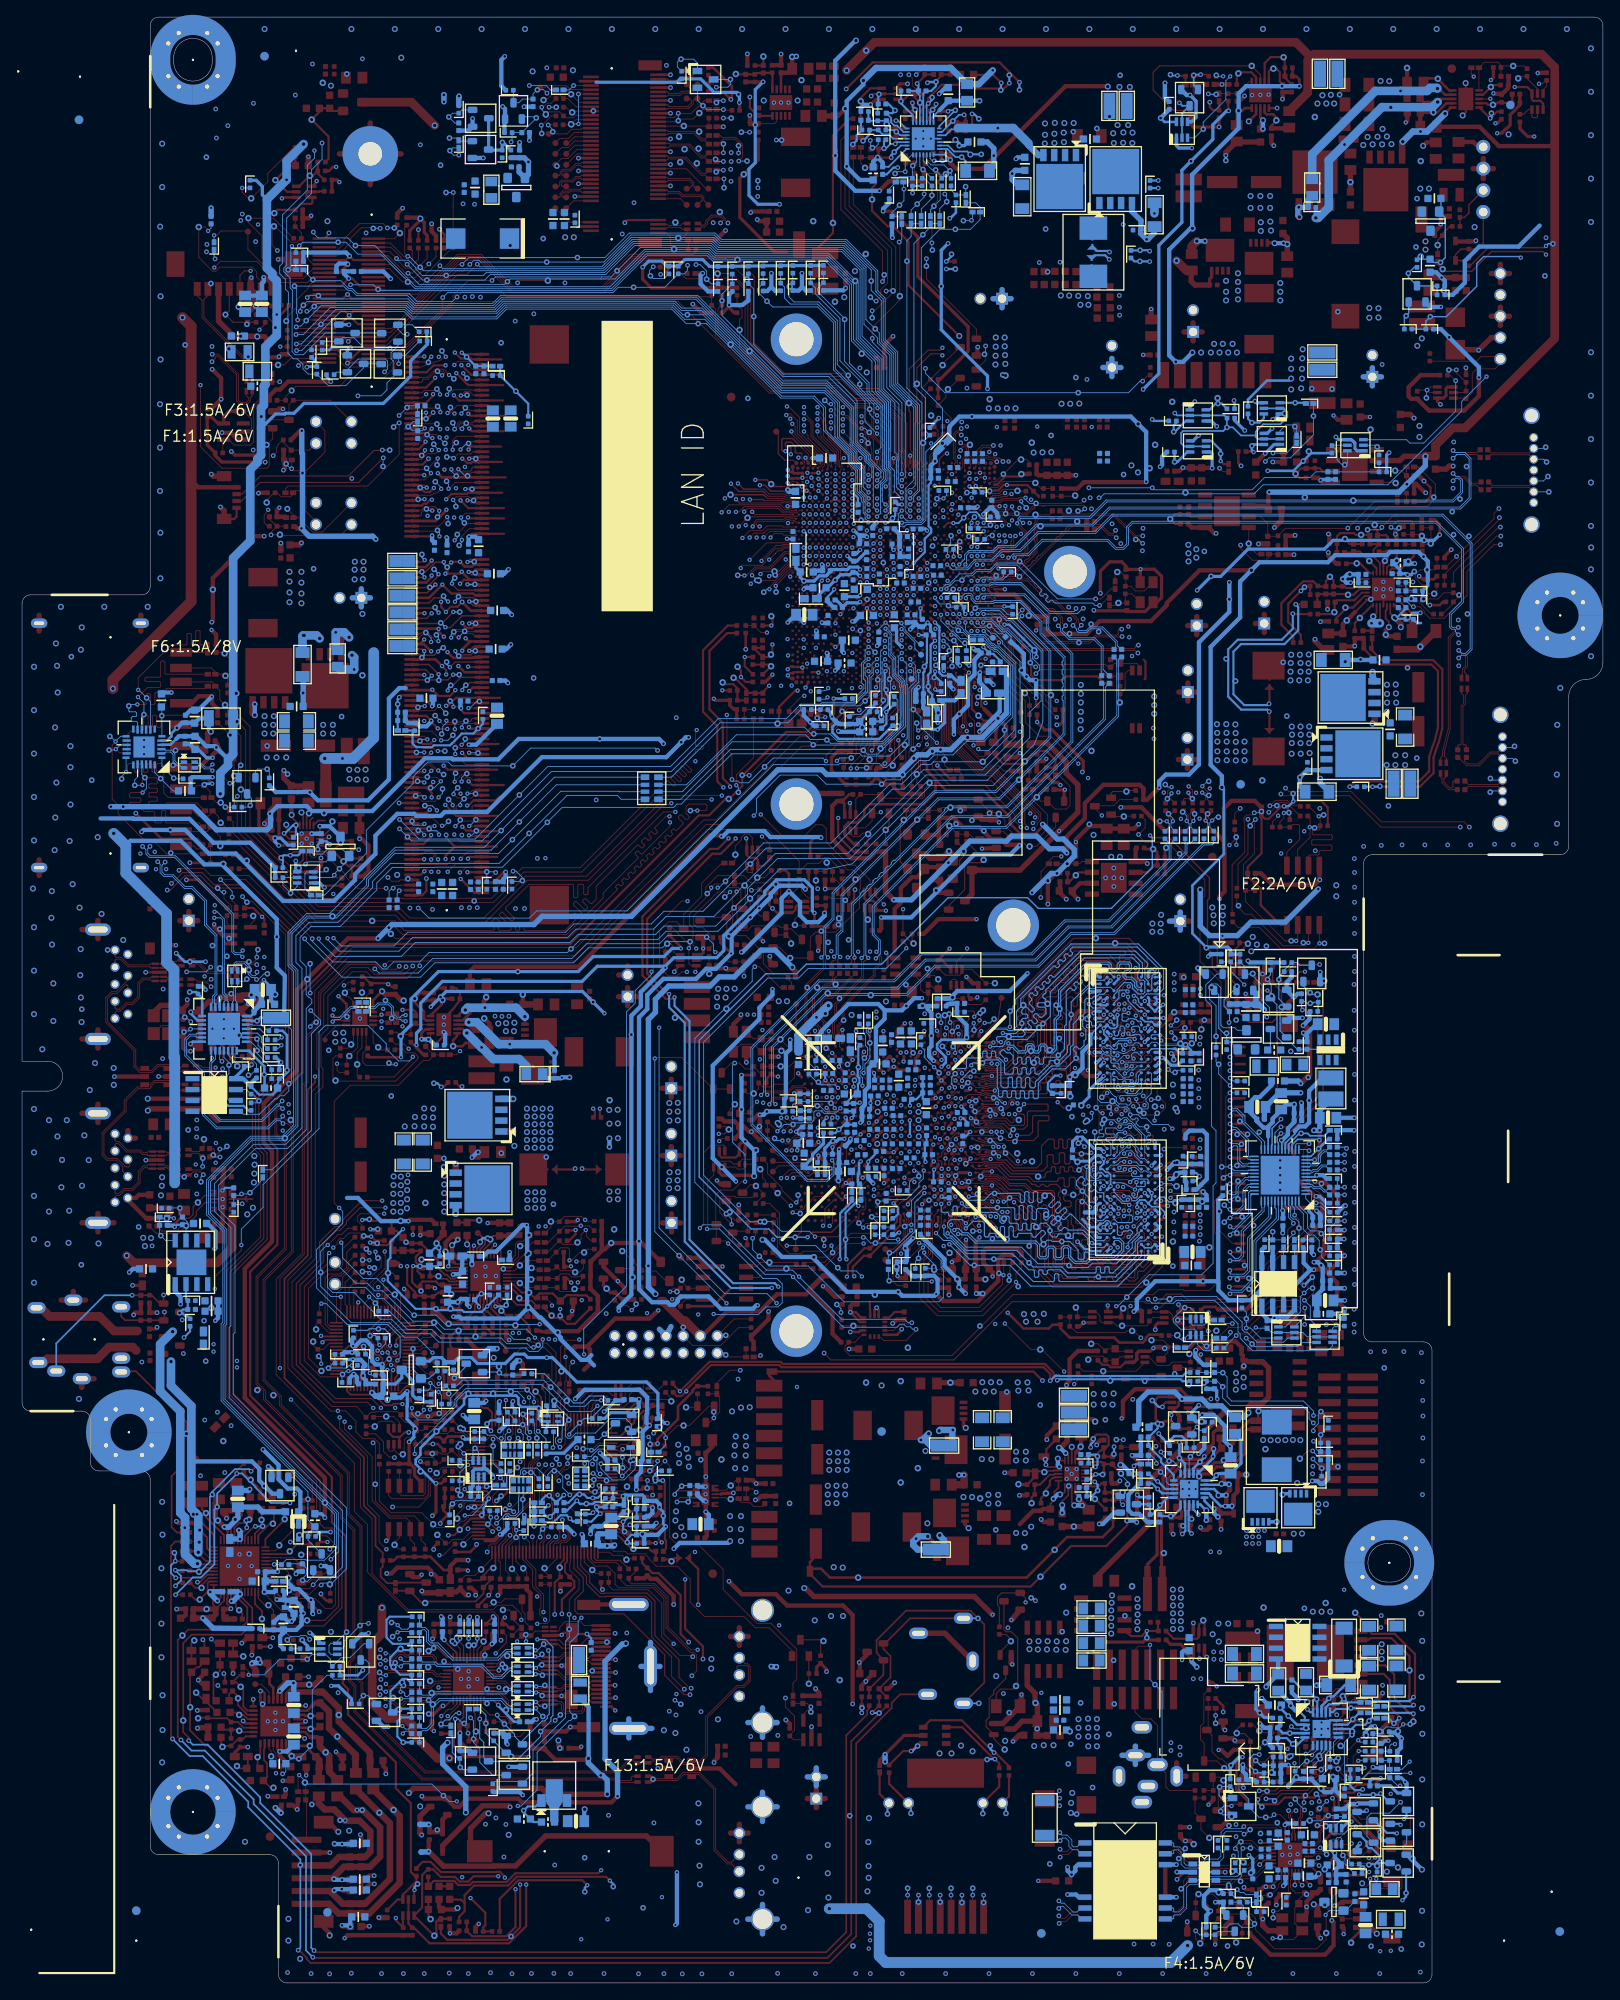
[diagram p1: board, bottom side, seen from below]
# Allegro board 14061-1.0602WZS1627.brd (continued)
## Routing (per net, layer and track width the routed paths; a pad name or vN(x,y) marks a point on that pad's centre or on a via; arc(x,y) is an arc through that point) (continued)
MDA63: length 33.2
  TOP w0.127: GPU1.J5 77.43,90.37 77.43,88.81 77.59,88.65 77.59,88.44 77.63,88.41 77.63,88.14 77.96,87.81 77.96,87.81 v1(78.05,87.73)
  BOTTOM w0.127: v1(78.05,87.73) 77.18,86.87 76.33,86.87 74.15,84.69 v4(71.27,84.69) 69.3,84.69 69.11,84.5 69.09,84.5 66.65,82.06 64.31,82.06 64.18,82.19 64.18,82.85 64.06,82.97 63.8,82.97 63.67,82.85 63.67,82.19 63.55,82.06 56.99,82.06 54.01,85.03 MEM4.A3
MDAT: length 4.3
  TOP w0.102: v2(118.27,58.17) 117.69,58.75 117.12,58.75 117.11,58.74 U109.79
  BOTTOM w0.102: RN8.2 118.75,58.78 118.65,58.88 v4(118.09,58.88) 118.09,58.35 v2(118.27,58.17)
ME_FWP_SOC: length 87.1
  TOP w0.089: CPU2.AH52 84.46,178.07 84.35,178.17 84.35,178.88 84.54,179.07 84.54,179.25
  TOP w0.102: 84.54,179.25 84.54,180 85.55,181.01 85.55,183.46 86.37,184.28 88.04,184.28 89.77,186 97.52,186 108.24,196.72 134.31,196.72 140.11,190.92 140.24,190.8 140.24,190.79 141.38,189.64 141.38,189.04 142.62,187.81 146.85,187.81 147.86,186.79 152.97,186.79 v5(153.45,186.31) 154.15,185.61 R544.2 R1560.2
MEM_CALRP0: length 4.8
  TOP w0.102: GPU1.K25 78.13,107.13 v1(78.27,107.13)
  BOTTOM w0.102: v4(77.68,106.48) 77.68,106.55 v1(78.27,107.13) 79.38,108.25 79.38,109.11 79.81,109.55 R1201.2
MEM_MA_EVENT_L: length 35
  TOP w0.102: v2(160.69,140.36) 161.34,141.01 R576.1 ; DIMM1.198 140.74,129.05 140.89,128.89 141.73,128.89 v2(142.18,129.34)
  L4 w0.127: v2(160.69,140.36) 161.33,140.36 162.35,139.34 162.35,137.7 154.12,129.46 149,129.46 148.45,128.91 143.55,128.91 143.11,129.34 v2(142.18,129.34)
  BOTTOM w0.102: v2(160.69,140.36) 160.31,140.36 Q51.E 159.65,142.23 v4(159.42,142.46)
MEM_RST: length 94.7
  TOP w0.102: MEM1.T2 52.16,104.63 52.16,103.87 51.19,102.9 51.19,102.37 52.01,101.55 54.53,101.55 54.56,101.58 v2(55.31,101.58) 55.31,102.1 55.69,102.48 56.06,102.48 56.75,101.8 57.08,101.8 57.44,102.16 58.72,102.16 58.96,101.92 58.96,98.57 MEM2.T2
  L3 w0.127: v1(82.48,86.97) 82.44,86.94 82.44,86.84 80.54,84.94 69.69,84.94 68.35,83.6 51.69,83.6 47.79,87.5 47.79,99.69 48.04,99.94 v1(50.38,99.94)
  BOTTOM w0.102: v2(55.31,101.58) 54.4,101.58 53.99,101.17 53.42,101.17 52.69,100.44 50.89,100.44 v1(50.38,99.94) ; v2(55.31,101.58) 55.45,101.72 55.45,102.25 55.69,102.48 56.03,102.48 56.05,102.46 56.59,102.46 56.75,102.61 56.77,102.61 57.12,102.96 57.65,102.96 57.69,102.99 58.74,102.99 59.15,103.41 59.15,104.83 59.09,104.89 59.09,105.02 58.88,105.23 58.87,105.23 58.77,105.33 58.65,105.33 58.3,105.68 MEM3.T2 ; v2(55.31,101.58) 55.31,101.25 55.04,100.98 54.89,100.98 54.69,101.19 54.52,101.19 54.4,101.07 54.4,100.9 54.61,100.69 54.61,100.55 54.22,100.16 v4(53.39,100.16) 53.39,99.6 53.29,99.5 53.08,99.5 52.96,99.38 52.96,99.22 53.08,99.1 53.29,99.1 53.39,99 53.39,98.79 53.29,98.69 53.03,98.69 52.91,98.57 52.91,98.4 53.03,98.28 53.29,98.28 53.39,98.18 53.39,97.79 MEM4.T2 ; v1(82.48,86.97) 82.5,87 83.68,87 84.13,87.45 R79962.2 85.17,87.54 R1204.2
MEM_VTT: length 6.6
  TOP w0.254: DIMM1.204 138.19,127.25 137.69,127.75 v2(137.69,129.21) ; v1(133.66,129.16) 133.66,129.18 133.38,128.9 133.38,128.88 132.05,127.55
  TOP w0.305: DIMM1.203 132.05,127.55
  vias: v4(139.84,129.19) v6(141.1,129.64)
MIC2-L: length 3.9
  TOP w0.203: C139.1 156.98,55.35 v3(156.98,54.18) 156.98,53.34 157.74,52.57 U6.47
MIC2-L-1: length 3.8
  TOP w0.203: R225.1 159.04,59.66 v3(158.24,58.87) 157.01,57.63 C139.2
MIC2-R: length 4.6
  TOP w0.203: U6.48 157.35,52.39 156,53.73 v3(155.64,53.73) 155.53,53.84 155.53,55.17 C138.1
MIC2-R-1: length 3.7
  TOP w0.203: C138.2 155.74,57.25 v3(156.62,58.13) 157.18,58.69 R627.1
MIC2-VREFO-L: length 5.4
  TOP w0.203: R223.1 154.26,55.11 v3(154.26,54.25) 154.29,54.23 154.29,54.18 156.52,51.95 U6.1
MIC2-VREFO-R: length 3
  TOP w0.203: U6.30 163.61,48.57 164.07,48.11 v3(164.29,48.11) 165.25,48.11 R262.1
MIC-CAP: length 6.7
  TOP w0.203: U6.36 162.57,51.99
  TOP w0.254: C154.2 165.97,55.84 v3(164.95,54.82) 162.57,52.44 162.57,51.99
MINI_POWER_CTRL: length 217.1
  TOP w0.102: U109.55 121.21,65.13 121.9,64.44 121.9,63.6 v2(122.07,63.43)
  L3 w0.127: v2(122.07,63.43) 123.35,63.43 124.26,62.52 130.72,62.52 131.63,63.44 132.35,63.44 133.21,64.3 133.6,64.3 133.79,64.11 138.78,64.11 139.55,64.88 144.34,64.88 144.79,64.43 146.87,64.43 153.7,71.26 153.7,72.24 157.39,75.93 157.39,83.71 159.83,86.16 159.83,106.77 159.76,106.84 159.76,114.96 161.07,116.27 161.07,120.68 162.97,122.59 162.97,130.84 165.25,133.11 165.25,159.7 165.07,159.88 165.07,183.07 160.48,187.66 160.48,205.13 v2(159.41,206.21)
  L4 w0.127: v2(133.89,213.84) 135.72,213.84 139.64,209.92 157.3,209.92 159.74,207.48 159.74,206.43 159.52,206.21 v2(159.41,206.21)
  BOTTOM w0.102: v2(133.89,213.84) 134.5,213.84 134.93,214.27 v4(134.93,214.38) 134.61,214.69 R15.1 ; RN7.4 121.94,66.34 121.79,66.18 121.79,63.67 122,63.45 122.05,63.45 v2(122.07,63.43)
MLPS_EN#: length 11.4
  TOP w0.102: GPU1.R5 81.35,90.35 81.35,89.57 arc(81.34,89.51) 81.3,89.46 81.2,89.22 81.2,89 81.36,88.84 81.36,87.45 81.52,87.3 81.52,86.74 82.63,85.62 82.63,83.84 v3(82.67,83.8) 83.06,83.41 83.06,82.08 82.56,81.58 R1882.1
MODEL_ID_DET: length 7
  TOP w0.102: v1(146.41,72.24) 146.87,72.24 147.47,71.64 U4101.50
  BOTTOM w0.102: v1(146.41,72.24) 146.73,72.24 147.04,71.93 v4(149.15,71.93) 148.57,72.5 R80130.2 148.39,72.51 R79722.1
MPCIE_DISABLE_N: length 230
  TOP w0.102: v2(124.24,217.35) 124.14,217.35 123.05,218.44 R1620.1 ; v2(122.05,62.69) 121.81,62.69 121.45,63.06 121.45,64.53 120.81,65.17 U109.56
  L3 w0.127: v2(159.23,206.95) 159.23,206.95 159.33,206.95 160.74,205.54 160.74,187.91 165.32,183.32 165.32,159.98 165.5,159.8 165.5,133.01 163.3,130.81 163.3,122.56 161.32,120.58 161.32,116.16 160.68,115.51 160.68,86.64 157.64,83.61 157.64,75.82 154.01,72.19 154.01,71.21 146.97,64.17 144.69,64.17 144.44,64.43 140.43,64.43 139.85,63.86 136.53,63.86 135.86,63.18 131.74,63.18 130.82,62.27 123.95,62.27 123.11,63.11 122.47,63.11 v2(122.05,62.69)
  L4 w0.127: v2(159.23,206.95) 159.23,206.95 159.23,207.33 156.93,209.63 139.58,209.63 136.76,212.45 128.08,212.45 124.24,216.29 v2(124.24,217.35)
  BOTTOM w0.102: RN7.3 122.29,64 122.58,63.72 122.58,63.21 v2(122.05,62.69) ; v2(124.24,217.35) 124.19,217.3 v4(124.19,216.38)
MPV18: length 0.7
  TOP w0.381: v1(78.25,92.82) 78.33,92.82 78.71,93.2 GPU1.L8
  vias: v4(78.87,91.57)
MVREFDA: length 8.6
  TOP w0.356: v1(78.31,107.88) 78.29,107.9 78.1,107.9 GPU1.K26
  BOTTOM w0.508: R1890.2 78.98,114.29 C760.1 79.01,113.93 78.58,113.5 R1888.1 v4(78.58,110.82) 78.58,109.59 78.85,109.33 78.85,108.41 v1(78.31,107.88)
MVREFSA: length 13.5
  TOP w0.356: GPU1.J26 77,107.59 77.35,107.24 v1(77.4,107.19)
  BOTTOM w0.305: v1(77.4,107.19) 76.89,107.7 76.89,108.3 77.92,109.33 77.92,109.83 77.41,110.34 74.74,110.34 v4(74.47,110.61)
  BOTTOM w0.508: R1200.2 76.63,114.53 76.44,114.53 76.4,114.57 76.17,114.57 76.16,114.58 75.62,114.58 C761.1 R1889.1 75.59,113.19 74.47,112.06 v4(74.47,110.61)
NFC_SCL: length 13.3
  TOP w0.089: CPU2.AA3 81.06,152.63 80.78,152.36 80.78,152.01 80.87,151.93 80.87,151.06 80.89,151.03 80.89,150.52
  TOP w0.102: 80.89,150.52 80.89,144.47 80.64,144.21 v3(80.64,143.27) 80.64,142.28 80.89,142.03 80.89,140 R1799.1
NFC_SDA: length 13.1
  TOP w0.089: 80.68,150.64 80.68,151.85 80.57,151.95 CPU2.Y2
  TOP w0.102: 80.68,150.64 80.68,144.67 80.08,144.07 80.08,141.7 80.3,141.48 v3(80.3,141.43) 80.3,140.45 R1800.1
NGFF_ALERT_N: length 3.8
  TOP w0.102: R1623.2 121.26,221.49 v3(120.75,220.97) 119.78,220 NGFF1.62
NGFF_BT_DISABLE: length 236.3
  TOP w0.102: R1621.1 123.38,217.42 v2(123.43,217.37) ; U109.120 126.81,52.36 124.14,55.03 124.14,59.39 122.97,60.56 v2(122.97,60.61)
  L3 w0.127: v2(163.37,203.4) 162.95,202.98 162.95,200.51 162.28,199.83 162.28,187.87 166.09,184.06 166.09,160.3 166.26,160.12 166.26,130.62 164.4,128.76 164.4,122.27 162.4,120.28 162.4,114.87 163.31,113.97 163.31,93.53 162.78,93.01 162.78,87.67 158.4,83.29 158.4,75.37 155.52,72.48 155.52,71.64 147.29,63.41 144.37,63.41 144.12,63.67 142.62,63.67 141.27,62.32 139.3,62.32 139.29,62.33 137.23,62.33 133.59,62.33 133.5,62.42 132.11,62.42 131.14,61.45 123.81,61.45 v2(122.97,60.61)
  L4 w0.127: v2(163.37,203.4) 161.3,203.4 155.34,209.36 139.48,209.36 136.93,211.91 128.26,211.91 123.43,216.74 v2(123.43,217.37)
  BOTTOM w0.102: v2(123.43,217.37) 122.89,216.84 v4(122.89,216.59)
NGFF_CLKREQ0_N: length 6.6
  TOP w0.102: R1612.1 105.32,219.2 v3(105.74,218.77) 106.45,218.07 108.17,218.07 108.49,217.75 NGFF1.53
NGFF_CLKREQ1_N: length 6.2
  TOP w0.102: TP85.1 123.83,221.74 123.6,221.97 121.29,221.97 120.85,221.53 118.45,221.53 NGFF1.68
NGFF_DETECT_PCIE: length 188.2
  TOP w0.102: R1155.2 v2(102.93,218.19) ; CPU2.T10 v1(78.16,156.31)
  L3 w0.127: v2(133.18,197.23) 132.71,196.76 126.71,196.76 117.91,205.55 117.91,207.82 107.51,218.22 106.37,218.22 105.61,218.99 103.73,218.99 v2(102.93,218.19)
  L4 w0.127: v1(78.16,156.31) 79.18,155.29 79.18,151.91 80.72,150.38 81.74,150.38 82.98,149.14 84.06,149.14 87.22,145.99 104.39,145.99 109.41,140.97 110.07,140.97 118.79,132.25 139.07,132.25 141.6,134.78 141.6,149.38 141.36,149.62 141.36,160.92 142.25,161.81 142.25,173.74 143.45,174.95 143.45,185.54 140.01,188.98 140.01,191.11 135.29,195.83 134.58,195.83 v2(133.18,197.23)
  BOTTOM w0.102: v2(102.93,218.19) v4(102.01,218.19)
NGFF_DETECT_PCIE_C: length 7
  TOP w0.102: NGFF1.51 107.59,217.25 107.58,217.26 v3(107.56,217.26) 107.54,217.25 104.94,217.25 104.86,217.17 R1209.2 R1155.1
NGFF_DETECT_USB: length 175.3
  TOP w0.102: R1154.2 106.14,202.55 106.44,202.26 113.83,202.26 116.72,199.36 123.27,199.36 v3(123.47,199.17) 126.75,199.17 v2(127.01,198.91) ; CPU2.T7 v1(78.16,154.89)
  L4 w0.127: v1(78.16,154.89) 78.63,154.43 78.63,152.15 80.98,149.8 81.46,149.8 85.52,145.73 104.26,145.73 109.28,140.72 109.94,140.72 119.55,131.1 125.58,131.1 126.46,131.99 139.17,131.99 141.85,134.67 141.85,149.48 141.61,149.73 141.61,160.81 142.5,161.7 142.5,173.64 143.71,174.84 143.71,185.64 140.27,189.08 140.27,191.75 135.39,196.62 134.05,197.97 127.95,197.97 v2(127.01,198.91)
NGFF_DETECT_USB_C: length 6
  TOP w0.102: R1637.2 R1154.1 107.03,202.84 v3(108.7,202.84) 109.11,203.25 109.11,204.27 109.59,204.75 NGFF1.1
NGFF_PCIE0_RXN: length 7.1
  TOP w0.102: R1609.1 105,213.74 105.46,213.74 106.08,214.36 ; 106.08,214.36 106.86,215.14 109.17,215.14 109.28,215.25 NGFF1.43 ; 106.08,214.36 v3(105.83,214.61)
NGFF_PCIE0_RXP: length 7.2
  TOP w0.102: v3(107.47,214.54) 107.47,214.92 ; 107.47,214.92 109.16,214.92 109.33,214.75 NGFF1.41 ; 107.47,214.92 106.95,214.92 105.55,213.53 105.04,213.53 R1608.1
NGFF_PCIE0_TXN: length 7.3
  TOP w0.102: 106.3,212.62 105.39,211.71 105,211.71 R1611.1 ; 106.3,212.62 v3(106.03,212.89) ; 106.3,212.62 107.3,213.61 109.38,213.61 109.52,213.75 NGFF1.37
NGFF_PCIE0_TXP: length 7.4
  TOP w0.102: 107.99,213.4 107.39,213.4 105.48,211.49 105.04,211.49 R1610.1 ; 107.99,213.4 v3(107.99,213.03) ; 107.99,213.4 109.41,213.4 109.55,213.25 NGFF1.35
NGFF_PCIE1_RXN: length 5
  TOP w0.102: TP82.1 106.67,221.58 106.67,221.47 106.82,221.32 107.82,221.32 108.07,221.07 109.31,221.07 109.5,221.25 NGFF1.67
NGFF_PCIE1_RXP: length 5.3
  TOP w0.102: TP81.1 106.46,221.62 106.46,221.38 106.73,221.11 107.73,221.11 107.98,220.85 109.4,220.85 109.51,220.75 NGFF1.65
NGFF_PCIE1_TXN: length 5.1
  TOP w0.102: NGFF1.61 109.48,219.75 109.28,219.54 107.08,219.54 106.67,219.95 106.67,220.22 106.93,220.47 TP80.1
NGFF_PCIE1_TXP: length 5.3
  TOP w0.102: TP79.1 106.21,220.47 106.46,220.22 106.46,219.86 106.99,219.33 109.38,219.33 109.46,219.25 NGFF1.59
NGFF_PEWAKE0_N: length 24.7
  TOP w0.102: R1628.1 105.19,220.22 106.7,218.71 108.16,218.71 v2(108.2,218.75) 108.7,218.25 NGFF1.55 ; v2(120.45,221.99) 120.44,222 NGFF1.70
  L4 w0.127: v2(108.2,218.75) 108.67,219.22 109.12,219.22 111.59,221.69 119.81,221.69 120.1,221.99 v2(120.45,221.99)
  BOTTOM w0.102: v2(108.2,218.75) v4(108.2,217.88) ; R1627.2 120.96,221.48 v2(120.45,221.99)
NGFF_POWER_CTRL_1: length 2.8
  BOTTOM w0.102: v4(134.98,215.85) 134.16,215.85 R15.2 133.8,215.49 Q3.G
NGFF_POWER_CTRL_V2: length 4.6
  BOTTOM w0.102: C864.1 134.36,217.61 v4(135.06,218.31) 134.61,218.76 R1615.1 133.5,219.14 Q6708.B
NGFF_REFCLKN0: length 6.9
  TOP w0.102: 106.02,216.35 105.76,216.09 105.76,216.09 105.41,215.75 105.02,215.75 R23.1 ; 106.02,216.35 106.27,216.6 109.35,216.6 109.5,216.75 NGFF1.49 ; 106.02,216.35 v3(105.77,216.6)
NGFF_REFCLKN1: length 5
  TOP w0.102: TP84.1 106.7,223.25 106.7,223.14 106.79,223.05 107.62,223.05 108.05,222.61 109.29,222.61 109.43,222.75 NGFF1.73
NGFF_REFCLKP0: length 6.9
  TOP w0.102: v3(108.12,216.01) 108.12,216.39 ; 108.12,216.39 109.35,216.39 109.49,216.25 NGFF1.47 ; 108.12,216.39 106.36,216.39 105.85,215.87 105.85,215.87 105.5,215.53 105.01,215.53 R22.1
NGFF_REFCLKP1: length 5.4
  TOP w0.102: TP83.1 106.48,223.24 106.48,223.05 106.7,222.83 107.53,222.83 107.96,222.4 109.35,222.4 109.5,222.25 NGFF1.71
NGFF_W_DISABLE1_N: length 5.8
  TOP w0.102: NGFF1.56 120.18,218.5 120.45,218.23 121.42,218.23 R1620.2 122.1,218.91 123.39,218.91 v3(123.71,218.59)
NGFF_W_DISABLE2_N: length 3.5
  TOP w0.102: NGFF1.54 120.18,218 v3(120.73,217.45) 120.78,217.4 R1621.2
OBSFN_C0: length 98
  TOP w0.102: v2(135.77,197.18) 135.77,195.91 140.56,191.11 140.94,190.74 140.94,190.74 141.6,190.07 XDP1.4 ; CPU2.Y44 80.42,173.33 v1(80.07,172.97) ; R1559.1 107.16,200.93 v2(107.12,200.96)
  L4 w0.089: 79.66,175.13 79.66,173.52 80.07,173.12 v1(80.07,172.97)
  L4 w0.127: 79.66,175.13 79.66,186.25 78.41,187.5 78.41,194.48 85.01,201.08 105.43,201.08 105.93,200.57 106.73,200.57 v2(107.12,200.96)
  BOTTOM w0.102: v2(107.12,200.96) 107.12,200.36 107.51,199.96 R1817.2 109.79,198.38 v4(113.44,198.38) 115.23,198.38 115.85,197.76 135.19,197.76 v2(135.77,197.18)
OCS_48M_1: length 4.2
  TOP w0.254: L7.2 133,68.71 v3(132.77,68.94) 132.77,70.2 133.29,70.73 OSC2.4
OCS_48M_2: length 4.6
  TOP w0.254: OSC2.1 134.36,73.98 134.89,74.51 R321.2 134.18,76.3 v3(133.92,76.3) 133.88,76.26 C185.1
ODTA0: length 46.7
  TOP w0.102: v3(49.44,109.9) 51.33,109.9 v1(51.68,110.26) 51.89,110.47 52,110.47 52.02,110.48 MEM1.K1 ; v1(78.19,101.02) 78.57,101.4 GPU1.L18
  L3 w0.127: v1(51.68,110.26) 52.04,110.26 52.66,110.87 53.86,110.87 54.53,111.54 54.53,111.57 54.86,111.9 55.25,111.9 55.37,112.01 v1(55.62,112.01) 55.71,112.01 56.65,111.08 56.65,110.5 57.49,109.66 61.43,109.66 62.21,108.88 68.74,108.88 69.18,108.43 73.52,108.43 74.68,107.27 76.08,107.27 76.42,107.62 76.45,107.62 76.98,108.15 76.98,108.15 77.23,108.4 77.57,108.4 77.85,108.13 77.85,106.96 77.91,106.89 77.91,104.57 77.54,104.2 77.48,104.2 77.01,103.73 77.01,103.22 77.63,102.6 77.63,102.32 78.19,101.75 v1(78.19,101.02)
  L4 w0.127: v1(59.38,110.58) 58.11,110.58 57.97,110.45 57.45,110.45 55.88,112.01 v1(55.62,112.01)
  BOTTOM w0.102: v1(59.38,110.58) 59.27,110.48 MEM3.K1
ODTA1: length 46.5
  TOP w0.102: GPU1.K16 77.8,99.3 v1(78.16,98.94) ; v1(59.44,93.49) 58.81,92.86 MEM2.K1
  L3 w0.127: v1(78.16,98.94) 78.78,98.32 78.78,97.66 78.24,97.12 77.78,97.12 77.56,97.34 77.12,97.34 76.99,97.21 76.99,97.01 77.19,96.8 77.37,96.8 77.5,96.68 77.5,96.39 77.27,96.16 77.27,95.95 77.79,95.43 77.79,94.61 77.82,94.58 77.82,94.23 77.55,93.96 77.12,93.96 77.05,94.03 76.43,94.03 76.42,94.04 74.78,94.04 74.4,93.65 73.14,93.65 72.65,94.14 70.91,94.14 70.53,94.52 69.63,94.52 69.57,94.47 66.73,94.47 66.56,94.63 61.25,94.63 60.9,94.98 60.1,94.98 59.97,94.85 59.97,94.38 59.58,93.99 58.81,93.99 58.68,94.12 58.68,94.39 58.55,94.52 58.3,94.52 58.17,94.39 58.17,94.12 58.04,93.99 57.79,93.99 57.66,94.12 57.66,94.39 57.54,94.52 57.28,94.52 57.16,94.39 57.16,94.12 57.03,93.99 56.66,93.99 56.47,94.19 55.91,94.19 55.81,94.09 55.81,93.81 56.01,93.6 56.02,93.6 56.15,93.48 v1(56.15,93.12) 55.21,93.12 55.06,93.27 54.26,93.27 54,93.53 v2(51.69,93.53)
  L4 w0.127: v1(56.15,93.12) 56.15,93.44 56.35,93.64 59.29,93.64 v1(59.44,93.49)
  BOTTOM w0.102: v4(49.94,93.2) 50.18,93.2 50.48,93.5 50.94,93.5 50.96,93.53 v2(51.69,93.53) 51.72,93.53 52.41,92.83 MEM4.K1
OSD_BIST_N: length 260.8
  TOP w0.102: v1(55.28,79.2) 55.58,78.89 55.58,77.99 R535.1
  L4 w0.127: v1(119.54,42.72) 118.74,43.52 118.74,46.7 117.73,47.71 108.88,47.71 107.62,46.45 104.61,46.45 96.23,54.84 96.23,63.01 83.93,75.31 74.41,75.31 70.75,78.98 58.72,78.98 58.23,78.5 55.98,78.5 v1(55.28,79.2) ; v1(22.61,25.88) 22.99,25.51 22.99,24.38 22.28,23.67 22.28,5.68 25.63,2.32 112.85,2.32 120.41,9.89 128.11,9.89 130.35,12.13 130.35,14.25 126.98,17.62 v1(126.98,20.7)
  BOTTOM w0.102: R682.2 23.5,24.99 v1(22.61,25.88) ; v1(126.98,20.7) 126.6,20.7 124.72,22.58 124.72,26.97 120.99,30.7 120.82,30.7 v4(120.34,31.18) 120.91,31.75 120.91,39.78 119.92,40.77 119.92,42.34 v1(119.54,42.72)
OSD_BIST_N_1: length 2.6
  TOP w0.305: Q12.2 56.39,77.9 R535.2 56.38,78.68 v3(56.14,78.92)
OSD_DN: length 345.9
  TOP w0.089: CPU2.AH2 84.46,150.9 84.54,150.83
  TOP w0.102: v2(99.9,141.28) 95.16,146.03 93.01,146.03 92.16,146.88 90.02,146.88 88.83,148.06 88.83,149.05 88.48,149.4 87.77,149.4 86.56,150.62 84.74,150.62 84.54,150.83 ; v2(140.06,118.9) 140.6,118.36 142.79,118.36 143.57,119.14 146.7,119.14 150.05,115.79 150.05,112.09 151.54,110.59 151.54,105.38 151.98,104.95 151.98,85.27 154.82,82.42 v1(154.82,71.93)
  L3 w0.127: v2(140.06,118.9) 138.86,120.1 138.58,120.1 134.09,124.59 125.17,124.59 108.47,141.28 v2(99.9,141.28)
  L4 w0.127: v1(24.34,27.94) 23.94,27.94 21.77,25.77 21.77,5.47 25.42,1.82 113.06,1.82 120.62,9.37 128.31,9.37 130.86,11.91 130.86,15.65 128.91,17.59 128.91,20.41 131.35,22.85 136.19,22.85 146.62,33.28 146.62,33.86 147.82,35.07 147.82,54.55 149.62,56.36 149.62,60.1 152.62,63.1 152.62,68.11 154.82,70.31 v1(154.82,71.93)
  BOTTOM w0.102: R393.1 25.98,27.13 C227.2 24.95,27.11 R389.1 24.94,27.75 24.75,27.94 v1(24.34,27.94) ; v2(99.9,141.28) 99.92,141.3 v4(100.72,141.3)
OSD_DN_R: length 8.9
  TOP w0.102: v1(28.58,27.12) 29.22,26.48 29.22,24.41 29.38,24.25 PWRCN1.2 30.35,24.25 30.67,24.56 30.67,25.37 30.28,25.76 30.28,27.33 v3(30.69,27.73)
  BOTTOM w0.102: v1(28.58,27.12) 28.57,27.13 R393.2
OSD_MENU: length 339.7
  TOP w0.102: v2(37.14,139.79) 36.74,139.39 29.46,139.39 25.92,135.85 16.24,135.85 v2(15.63,135.23) ; v1(124.71,42.01) 124.67,42.05 123.58,42.05 123.25,42.38 R80218.1 R80206.1 ; v1(85.93,159.16) 85.58,158.8 CPU2.AK14
  L3 w0.127: v1(124.71,42.01) 124.71,41.8 121.65,38.73 115.4,38.73 114.28,37.62 114.28,35.8 109.09,30.61 106.01,30.61 104.31,32.31 98.59,32.31 93.54,37.35 88.59,37.35 81.12,44.81 68.47,44.81 67.74,44.08 65.75,44.08 65.02,44.81 60.34,44.81 58.19,46.96 45.7,46.96 44.74,46 v1(30.28,46) 31.08,46.8 31.08,51.46 28.35,54.2 28.35,70.61 31.77,74.03 31.77,98.09 30.97,98.9 30.97,126.6 30.66,126.91 30.66,128.65 30.67,128.66 30.67,132.4 28.04,135.03 17.79,135.03 17.11,135.7 16.04,135.7 15.63,135.28 v2(15.63,135.23) ; v2(37.14,139.79) 43.05,139.79 44.61,141.35 59.34,141.35 61.56,143.57 62.64,143.57 64.1,145.03 70.26,145.03 72.63,147.4 72.63,147.41 72.9,147.69 72.92,147.69 72.93,147.7 75,147.7 75.73,146.98 76.76,146.98 78.07,148.28 81.06,148.28 81.15,148.19 82.76,148.19 83.7,149.14 85.14,149.14 85.75,149.74 86.1,150.09 87.13,150.09 87.88,150.84 v1(87.88,151.49)
  L4 w0.127: v1(30.28,46) 29.42,46 28.23,44.81 24.34,44.81 22.05,42.52 22.05,34.57 22.69,33.93 22.69,30.94 v1(23.38,30.25) ; v1(87.88,151.49) 86.63,152.75 86.07,152.75 85.52,153.3 85.52,158.74 85.93,159.15 v1(85.93,159.16)
  BOTTOM w0.102: R689.1 C549.2 26.14,29.16 R693.1 25.36,29.95 24.77,29.95 24.67,29.85 23.78,29.85 v1(23.38,30.25) 23.36,30.27 v4(22.56,30.27)
OSD_MENU_R: length 6.2
  TOP w0.102: PWRCN1.1 29.93,27.11 v1(28.63,28.4) 28.07,28.96 v3(27.72,28.96)
  BOTTOM w0.102: R689.2 28.4,28.17 v1(28.63,28.4)
OSD_MENU_SIO: length 4.9
  TOP w0.102: U109.109 122.41,49.63 123.52,48.52 v3(123.86,48.52) 123.86,48.14 R80218.2 R80206.2
OSD_UP: length 352.1
  TOP w0.089: 84.26,150.66 84.26,152.35 83.97,152.63 83.97,152.93 CPU2.AG3
  TOP w0.102: v2(151.28,115.81) 151.28,116.19 151.24,116.23 151.24,116.29 146.88,120.65 146.82,120.65 146.31,121.16 120.12,121.16 105.21,136.07 103.74,136.07 94.01,145.8 92.92,145.8 92.07,146.65 89.92,146.65 88.6,147.97 88.6,148.84 88.32,149.12 87.47,149.12 86.3,150.29 84.63,150.29 84.26,150.66
  L4 w0.127: v1(22.54,24.56) 22.02,24.04 22.02,5.57 25.52,2.07 112.95,2.07 120.51,9.63 128.21,9.63 130.6,12.02 130.6,15.54 127.91,18.23 127.91,19.76 131.5,23.36 136.34,23.36 146.11,33.13 146.11,34.15 147.31,35.36 147.31,54.77 149.21,56.66 149.21,60.4 152.12,63.31 152.12,68.07 154.26,70.22 154.26,84.27 159.79,89.8 159.79,101.82 150.74,110.86 150.74,115.28 v2(151.28,115.81)
  BOTTOM w0.102: v1(22.54,24.56) 22.57,24.54 24.7,24.54 24.96,24.8 R682.1 R680.2 25.93,26.04 C542.2 25.95,26.06 R681.1 ; v2(151.28,115.81) 151.29,115.83 v4(151.29,119.25)
OSD_UP_R: length 6.9
  TOP w0.102: v1(28.63,25.99) 28.99,25.63 28.99,24.31 29.08,24.22 29.08,24.11 29.45,23.75 PWRCN1.3 30.49,23.75 30.97,24.23 30.97,25.7 v3(31.2,25.93)
  BOTTOM w0.102: R681.2 28.56,26.06 v1(28.63,25.99)
OVCUR1#: length 3.3
  BOTTOM w0.127: R80238.1 156.28,110.73 157.17,111.62 U6702.25
OVCUR2#: length 3.7
  BOTTOM w0.127: R80239.1 156.55,109.6 156.99,110.05 156.99,110.66 157.46,111.12 U6702.24
OZ554_ENA: length 7.2
  TOP w0.102: R79625.1 40.92,30.19 v3(40.21,29.48) 40.01,29.27 R79627.1 38.77,29.25 C3458.1 37.21,29.25 v2(36.46,30)
  BOTTOM w0.102: U120.3 36.13,29.72 36.41,30 v2(36.46,30)
OZ554_PWM: length 6.2
  BOTTOM w0.254: U120.5 35.66,27.94 v4(36.3,27.94) 37.02,28.65 C4270.1 38.07,27.81 R79623.1 37.69,27.43 R79621.1
OZ554_VIN: length 4.7
  BOTTOM w0.305: U120.4 v4(36.65,29.22) 37.44,29.22 C3457.1
  BOTTOM w0.508: R79716.2 37.75,30.16 C3457.1
P_GFX_TXN0: length 21.5
  TOP w0.089: 69.2,163.69 69.23,163.66 70.84,163.66 70.94,163.55 71.44,163.55 71.45,163.54 CPU2.B24
  TOP w0.102: 69.2,163.69 67.95,163.69 65.07,160.81 64.31,160.81 63.27,159.77 63.27,159.09 62.97,158.8 v2(62.87,158.8)
  BOTTOM w0.102: C322.1 58.49,153.67 58.49,156.4 59.47,157.38 62.39,157.38 62.64,157.63 ; 62.64,157.63 63.24,158.23 63.24,158.43 v2(62.87,158.8) ; 62.64,157.63 v4(62.42,157.86)
P_GFX_TXN1: length 20.8
  TOP w0.089: 69.61,163.86 70.9,163.86 71.02,163.74 71.35,163.74 71.52,163.91 71.81,163.91 CPU2.C25
  TOP w0.102: 69.61,163.86 69.47,164 69.43,164.04 67.35,164.04 64.86,161.56 64.11,161.56 62.68,160.13 62.28,160.13 61.59,159.45 61.59,159.25 v2(62.01,158.83)
  BOTTOM w0.102: C328.1 57.06,156.17 57.06,156.87 58.62,158.43 59.01,158.43 ; 59.01,158.43 59.96,158.43 60.4,158 61.36,158 61.62,158.25 61.62,158.43 v2(62.01,158.83) ; 59.01,158.43 v4(59.01,158.09)
P_GFX_TXP0: length 21.6
  TOP w0.089: 69.15,163.47 69.15,163.47 70.76,163.47 70.87,163.36 71.33,163.36 71.45,163.24 71.69,163.24 71.81,163.35 72.08,163.35 CPU2.C24
  TOP w0.102: v2(63.74,158.78) 63.48,159.03 63.48,159.68 64.4,160.59 65.16,160.59 68.04,163.47 69.15,163.47
  BOTTOM w0.102: 61.32,157.16 59.56,157.16 58.71,156.31 58.71,153 C325.1 ; 61.32,157.16 v4(61.32,156.82) ; 61.32,157.16 62.48,157.16 63.46,158.14 63.46,158.5 v2(63.74,158.78)
P_GFX_TXP1: length 20.7
  TOP w0.089: CPU2.A25 71.16,164.05 69.73,164.05 69.72,164.06
  TOP w0.102: 69.72,164.06 69.62,164.16 69.52,164.26 67.26,164.26 66.99,163.99 66.81,163.99 66.54,163.72 66.54,163.54 66.27,163.27 66.1,163.27 65.83,163 65.83,162.83 65.56,162.56 65.38,162.56 65.11,162.29 65.11,162.11 64.77,161.77 64.02,161.77 62.59,160.35 62.19,160.35 61.37,159.54 61.37,159.18 v2(61.04,158.85)
  BOTTOM w0.102: v4(59.9,158.98) 59.9,158.65 ; 59.9,158.65 60.05,158.65 60.49,158.22 61.27,158.22 61.4,158.34 61.4,158.47 61.04,158.83 v2(61.04,158.85) ; 59.9,158.65 58.53,158.65 56.84,156.96 56.84,156.48 56.38,156.02 C324.1
PANEL_ON_1: length 6.2
  TOP w0.127: v2(35.16,113.84) 35.28,113.95 R39.1
  BOTTOM w0.127: R41.2 33.31,113.73 R42.1 33.81,114.74 33.94,114.61 v4(34.25,114.61) 34.67,114.61 34.89,114.83 R33.1 35.27,113.94 v2(35.16,113.84)
PANEL_ON_2: length 2.7
  BOTTOM w0.127: Q10.B 35.05,116.66 v4(34.26,115.87) 34.02,115.63 R42.2
PANEL_ON_3: length 15.1
  BOTTOM w0.127: U1.3 33.11,109.51 33.39,109.23 C14.2 R19.1 35.76,109.23 36.53,110.01 37.49,110.01 38.15,110.66 38.15,112.07 38.15,112.08 38.15,114.46 Q5.D 38.91,115.83 38.82,115.92 38.82,116.85 39.25,117.28 v4(39.25,117.4) 39.25,117.6 38.9,117.95 R20.2
PANEL_ON_4: length 12.9
  BOTTOM w0.127: Q1.G 37.76,111.39 37.76,112.23 37.77,112.23 37.77,113.46 Q5.G 37.93,115.15 v4(37.93,117.39) 37.93,117.7 R30.1 37.3,118.49 R26.2 35.78,119.38 35.47,119.06 Q10.C
PANEL_ON_5: length 2.6
  BOTTOM w0.127: Q1.D 38.91,109.47 R8.1
PANEL_SEL1_CABLE: length 8.4
  TOP w0.127: CONVT1.7 29.22,35.15 29.95,34.42 31.22,34.42 R79721.2 34.41,33.06 v3(34.6,32.87) 33.9,32.17 R79717.2
PANEL_SEL1_CABLE_EC: length 125
  TOP w0.102: v2(106.7,34.48) 106.85,34.48 108.12,35.75
  TOP w0.127: U109.102 119.61,48.78 118.56,47.74 118.56,46.85 117.27,45.56 116.88,45.56 116.83,45.61 111.86,45.61 110.94,44.69 110.94,40.63 108.12,37.82 108.12,35.75 ; R79717.1 33.51,31.1 32.53,31.1 31.58,30.16 31.58,29.32 32.64,28.26 32.64,25.02 34.24,23.42 37.38,23.42 38.32,22.48 v2(40.22,22.48)
  L4 w0.127: v2(106.7,34.48) 106.01,33.79 106.01,31.04 104.22,29.25 103.06,29.25 101.79,27.98 96.22,27.98 93.75,30.44 92.42,30.44 91.86,29.88 82.48,29.88 81.41,30.95 73.43,30.95 72.37,32 65.74,32 62.42,35.33 49.06,35.33 45.79,32.07 45.79,31.1 45.3,30.61 44.04,30.61 40.74,27.31 40.74,23.01 v2(40.22,22.48)
  BOTTOM w0.127: v2(40.22,22.48) 39.34,22.48 v4(39.31,22.44)
PANEL_SEL2_CABLE: length 5.1
  TOP w0.127: R287.2 31.05,32.6 R79719.2 31.5,33.12 31.07,33.55 v3(30.44,33.55) 29.88,33.55 29.28,34.15 CONVT1.8
PANEL_SEL2_CABLE_EC: length 125.4
  TOP w0.102: v2(107.5,34.37) 108.99,35.85 108.99,38.14
  TOP w0.127: 108.99,38.14 111.32,40.48 111.32,44.53 112.02,45.23 116.67,45.23 116.72,45.18 117.43,45.18 118.94,46.69 118.94,47.58 120.01,48.65 U109.103 ; v2(40.37,21.46) 39.73,22.1 38.16,22.1 37.74,22.52 34.6,22.52 32.26,24.86 32.26,28.11 31.2,29.17 31.2,30.5 30.51,31.19 30.46,31.24 R287.1
  L4 w0.127: v2(40.37,21.46) 40.4,21.46 41.6,22.66 41.6,23.03 43.78,25.21 43.78,27.99 46.71,30.92 46.71,31.91 49.37,34.57 62.06,34.57 65.39,31.24 72.06,31.24 73.11,30.19 80.9,30.19 81.97,29.12 93.98,29.12 95.88,27.22 102.1,27.22 103.37,28.49 104.54,28.49 106.78,30.73 106.78,33.01 107.5,33.73 v2(107.5,34.37)
  BOTTOM w0.127: v4(39.91,20.59) 40.37,21.05 v2(40.37,21.46)
PANEL_SEL3_CABLE: length 6.3
  TOP w0.127: CONVT1.9 29.27,33.15 29.65,32.77 29.65,31.13 R79720.2 30.51,30.26 R79718.2 29.54,29.6 v3(29.34,29.41)
PANEL_SEL3_CABLE_EC: length 124.3
  TOP w0.127: v2(39.43,21.54) 38.18,21.54 37.59,22.14 34.44,22.14 31.88,24.7 31.88,27.35 R79718.1 ; v2(106.83,33.73) 107.53,33.73 109.79,35.99 109.79,38.41 114.55,43.17 119.96,43.17 120.3,43.51 120.3,44.84 119.32,45.82 119.32,47.42 120.41,48.51 U109.104
  L4 w0.127: v2(106.83,33.73) 106.4,33.29 106.4,30.88 104.38,28.87 103.21,28.87 101.94,27.6 96.06,27.6 94.16,29.5 82.12,29.5 81.05,30.57 73.27,30.57 72.21,31.62 65.58,31.62 62.26,34.95 49.21,34.95 46.33,32.07 46.33,31.1 45.36,30.12 44.1,30.12 41.22,27.25 41.22,22.82 40.33,21.93 39.82,21.93 v2(39.43,21.54)
  BOTTOM w0.127: v2(39.43,21.54) 38.65,21.54 v4(38.42,21.31)
PB_IN_N_1: length 12.3
  TOP w0.102: R662.2 R668.2 112.72,60.58 113.77,60.58 114.69,61.49 v2(114.74,61.49) 114.79,61.54 U109.72
  BOTTOM w0.102: v2(114.74,61.49) 114.71,61.47 v4(114.71,60.27) 114.73,60.27 C530.2 116.91,62.46 117.55,62.46 118.39,61.61 118.39,61.57 R79938.2
PB_IN_N_1_C: length 14.1
  TOP w0.127: U109.111 123.21,51.32 122.84,51.69 122.38,51.69 122.07,52 122.07,52.82 122.94,53.69 122.94,56.07 123.01,56.14 123.01,58.91 v2(121.17,60.76)
  BOTTOM w0.102: R79938.1 121.07,61.57 v4(121.12,61.52) 121.12,60.8 v2(121.17,60.76)
PB_IN_SW1: length 8.9
  TOP w0.254: v2(28.11,22.65) 28.21,22.56 28.81,22.56 29.12,22.25 PWRCN1.6 30.8,22.25 31.21,22.66 31.22,22.66 31.34,22.78 32.95,22.78 v3(32.98,22.76)
  BOTTOM w0.254: v2(28.11,22.65) 28.21,22.56 29.04,22.56 29.57,23.08 R373.1 R370.2
PCB_VER_ID: length 4.7
  TOP w0.102: v1(146.8,71.58) 146.94,71.58 147.29,71.24 U4101.49
  BOTTOM w0.102: R80128.1 147.56,71.13 v4(147.5,71.2) 147.11,71.58 v1(146.8,71.58) 146.43,71.58 R80133.1
PCH_AUD_RST_N: length 4.2
  TOP w0.102: R637.1 R313.1 133.58,58.84 v3(133.49,58.92) 133.28,59.14 U109.19
PCH_AUD_RST_N_1: length 32.1
  TOP w0.102: v2(141.64,55.68) 138.58,55.68 137.23,57.02 137.23,58.42 136.67,58.98 136.19,58.98 135.53,59.64 R637.2
  L3 w0.127: v2(141.64,55.68) 143.52,53.8 143.52,51.17 140.86,48.51 140.86,43.84 142.65,42.06 v2(144.46,42.06)
  BOTTOM w0.102: v2(144.46,42.06) 145.19,42.06 v4(145.45,41.81) 147.25,40.01 147.25,39.42 147.58,39.09 Q63.5
PCH_CHAR_CTL3: length 17.8
  TOP w0.102: R80059.2 141.26,109.27 140.5,109.27 140.04,108.81 139.07,108.81 138.67,108.41 138.67,108.12 141.27,105.51 148.25,105.51 v3(148.32,105.57) 148.62,105.88 148.62,108.13 148.28,108.47 R80065.2
PCH_PCIECLKRQ2_N: length 180.6
  TOP w0.102: R1843.1 R1782.2 104.14,222.19 v2(103.75,221.79) ; CPU2.AM12 86.29,157.38 v1(85.93,157.03)
  L3 w0.127: v2(103.75,221.79) 103.75,221.28 106.5,218.53 107.64,218.53 118.22,207.95 118.22,205.68 126.54,197.36 131.22,197.36 v2(131.35,197.23)
  L4 w0.127: v1(85.93,157.03) 86.7,156.26 86.7,155.87 86.85,155.72 86.85,154.81 89.14,152.53 89.62,152.53 v1(90.66,151.49) 91.99,150.16 93.63,150.16 93.69,150.23 101.34,150.23 103.69,147.88 104.13,147.88 105.87,146.14 106.73,146.14 106.8,146.2 107.19,146.2 120.08,133.31 137.57,133.31 139.45,135.2 139.45,161.04 140.83,162.41 140.83,174.06 141.46,174.69 141.46,186.36 138.5,189.32 138.5,191.65 134.88,195.28 133.31,195.28 v2(131.35,197.23)
  BOTTOM w0.102: R80234.1 90.91,151.24 v1(90.66,151.49) ; Q1236.3 102.11,222.71 v4(102.11,222.7) 102.11,222.1 102.41,221.79 v2(103.75,221.79)
PCH_PCIECLKRQ2_N_1: length 6.8
  TOP w0.102: R1612.2 102.95,219.2 v2(102.93,219.18) 102.84,219.09 R1842.1
  BOTTOM w0.102: Q1236.2 105.96,220.28 v4(105.32,219.63) 104.86,219.18 v2(102.93,219.18)
PCH_PCIECLKRQ2_N_B: length 4.9
  BOTTOM w0.102: Q1236.1 105.96,224.62 106.41,225.07 v4(107.88,225.07) 107.98,225.07 108.31,224.74 108.31,224.17 R1844.2
PCH_RTCRST_DOWN: length 10.2
  TOP w0.102: v5(153.96,172.47) 153.23,171.74 R86.1 152.65,171.44 150.96,169.75 149.87,169.75 CMCLR1.1
PCH_RTCRST_PULLUP: length 177.6
  TOP w0.102: R92.1 155.21,170.43 155.5,170.72 155.51,170.72 155.74,170.96 155.83,171.01 156.06,171.24 C50.1 ; R92.1 155.86,169.7 v2(155.86,169.42) 155.84,169.44 v3(154.82,169.44) 154.73,169.35 151.94,169.35 151.73,169.14 147.94,169.14 CMCLR1.2 ; R92.1 154.17,170.42 R87.2 ; CPU2.J16 v1(74.6,159.17)
  L3 w0.127: v1(148.55,122.24) 148.55,123.07 150.11,124.63 150.11,130.73 152.09,132.72 152.59,132.72 153.47,133.6 155.28,133.6 157.28,135.61 157.28,140.97 159.33,143.01 159.33,144.73 159.39,144.79 159.39,167.2 156.86,169.74 156.18,169.74 v2(155.86,169.42)
  BOTTOM w0.102: v1(74.6,159.17) 74.6,158.31 74.06,157.77 72.46,157.77 71.93,157.24 71.93,157.16 71.44,156.67 71.24,156.67 70.99,156.41 70.65,156.41 68.7,154.47 68.7,145.82 72.59,141.94 79.52,141.94 81.79,139.67 83.15,139.67 90.05,132.77 97.93,132.77 v4(99.78,130.91) 105.32,125.37 109.89,125.37 110.57,124.69 110.57,124.69 111.36,123.9 120.43,123.9 121.39,122.94 139.86,122.94 141.47,121.33 147.63,121.33 v1(148.55,122.24)
PCH_RTCX1: length 26.7
  TOP w0.102: X7.1 54.22,154.06 54.52,154.36 56.5,154.36 R81.1 56.6,154.36 57.2,154.36 C1619.1 57.88,153.94 58.19,154.25 66.1,154.25 v2(66.38,153.97) ; CPU2.M18 v1(76.03,160.16)
  BOTTOM w0.089: v1(76.03,160.16) 75.88,160.16 75.29,159.57 72.2,159.57
  BOTTOM w0.102: v2(66.38,153.97) 66.51,153.97 v4(67.01,154.47) 67.01,155.6 69.71,158.29 70.27,158.29 70.84,158.86 70.84,158.86 71.54,159.57 72.2,159.57
PCH_RTCX2: length 25.8
  TOP w0.102: CPU2.K18 v1(75.31,160.16) ; v2(66.35,153.19) 65.9,153.64 58.8,153.64 58.03,152.87 C1618.1 57.6,152.88 R81.2 56.52,152.86 R1261.1
  BOTTOM w0.089: v1(75.31,160.16) 74.91,159.76 72.3,159.76 72.26,159.79
  BOTTOM w0.102: v2(66.35,153.19) 65.95,153.59 65.95,154.17 66.76,154.99 66.76,155.64 69.64,158.51 70.2,158.51 70.64,158.95 v4(70.64,159.52) 70.92,159.79 72.26,159.79
PCH_SATA_LED_1: length 7.6
  BOTTOM w0.254: R340.2 26.44,13.89 27.31,13.89 v4(27.39,13.82) ; R340.2 26.28,14.02 Q37.C ; R340.2 26.42,14.15 26.14,14.43 26.14,14.87 27.05,15.77 27.4,15.77 27.67,16.04 27.67,16.53 28.53,17.39 Q36.B
PCH_SRTCRST_DOWN: length 10.8
  TOP w0.102: CMCLR2.1 149.56,181.63 149.56,179.1 151.73,176.93 153.21,176.93 v2(153.45,177.16) 153.44,177.18 R729.1
  BOTTOM w0.102: v4(154.09,177.74) 154.08,177.73 154.08,177.67 153.58,177.16 v2(153.45,177.16)
PCH_SRTCRSTB_PULLUP: length 187.5
  TOP w0.102: CMCLR2.2 151.4,179.33 C52.1 154.43,180.26 R91.2 154.49,180.53 155.1,179.92 155.1,179.77 155.2,179.67 155.2,179.1 v2(155.61,178.69) ; v1(156.19,172.35) 156.19,172.26 156.67,171.79 156.67,170.86 156.24,170.43 R92.2 ; CPU2.D18 v1(72.47,160.16)
  L3 w0.127: v2(155.61,178.69) 155.61,173.41 155.97,173.05 155.97,172.57 v1(156.19,172.35) 160.66,167.88 160.66,144.26 160.6,144.2 160.6,142.48 158.55,140.44 158.55,135.08 151.89,128.41 151.89,123.79 v1(150.27,122.17)
  BOTTOM w0.102: v1(150.27,122.17) 150.27,121.97 148.41,120.11 140.61,120.11 139,121.72 120.89,121.72 119.92,122.68 110.85,122.68 109.89,123.65 103.82,123.65 v4(101.68,125.78) 100.11,127.36 100.11,128.03 96.59,131.54 88.11,131.54 78.94,140.72 72.05,140.72 67.06,145.7 67.06,148.68 65.74,150 65.74,155.8 69.33,159.38 69.79,159.38 70.56,160.16 v1(72.47,160.16)
PCIE_CALR_RX: length 8.8
  TOP w0.102: v1(86.65,104.97) 86.65,104.65 GPU1.AA22
  BOTTOM w0.102: R1162.1 86.52,111.7 86.52,111.07 86.29,110.85 86.29,109.65 86.06,109.42 86.06,108.57 v4(86.42,108.22) 86.42,108.18 86.6,108 86.6,106.95 86.93,106.62 86.93,106.19 86.65,105.91 v1(86.65,104.97)
PCIE_CALR_TX: length 8.9
  TOP w0.102: GPU1.Y22 85.4,105.07 86,105.67 86.13,105.67 86.52,106.05 v1(86.52,106.45)
  BOTTOM w0.102: R1161.1 85.97,111.98 86.21,111.74 86.21,111.22 85.78,110.79 v4(85.78,109.98) 85.78,108.19 85.95,108.02 85.95,107.93 86.37,107.51 86.37,106.6 v1(86.52,106.45)
PCIE_OBS_DN: length 4.8
  TOP w0.102: CPU2.F26 v1(73.18,164.05)
  BOTTOM w0.102: 71.01,164.37 70.31,164.37 70.13,164.56 R513.2 ; 71.01,164.37 v4(71.01,164.67) ; 71.01,164.37 71.65,164.37 71.74,164.47 72.67,164.47 73.1,164.05 v1(73.18,164.05)
PCIE_OBS_DP: length 5.7
  TOP w0.102: CPU2.D26 v1(72.47,164.05)
  BOTTOM w0.102: v1(72.47,164.05) 72.27,164.25 71.83,164.25 71.73,164.16 70.23,164.16 69.89,164.49 69.83,164.49 R513.1 68.83,165.08 v4(68.27,164.53)
PCIE_RST#: length 235.7
  TOP w0.102: NGFF1.52 v1(119.88,217.5) ; NGFF1.66 v2(119.88,221)
  L3 w0.127: v1(133.18,54.69) 133.25,54.76 134.63,54.76 135.24,55.37 140.19,55.37 141.78,56.96 146.89,56.96 161.91,71.98 161.91,81.51 166.47,86.07 166.47,121.78 168.47,123.79 168.47,129.35 167.69,130.13 167.69,130.14 167.65,130.19 167.65,130.77 167.04,131.38 167.04,160.42 166.85,160.61 166.85,184.98 163.46,188.37 163.46,202.5 v2(163.42,202.54)
  L4 w0.127: v1(119.88,217.5) 121.32,217.5 127.67,211.15 135.16,211.15 137.46,208.85 153.49,208.85 159.8,202.54 v2(163.42,202.54)
  BOTTOM w0.102: RN3.1 129.92,57.78 131.05,56.65 131.05,55.95 132.31,54.69 v1(133.18,54.69) ; v2(119.88,221) v1(119.88,217.5) v4(120.78,217.5)
PCIE_WAKE#_CPU: length 242.9
  TOP w0.102: v2(16.7,135.23) 25.99,135.23 29.67,138.9 37.49,138.9 v2(37.69,139.1) ; Q19.C 28.63,15.2 28.62,15.21 R59.1 27.74,16.48 28.92,17.66 v1(28.92,18.28)
  L3 w0.127: v1(90.74,150.41) 90.74,150.36 87.91,147.52 83.79,147.52 83.32,147.05 79.86,147.05 78.36,145.55 77.7,145.55 76.5,144.36 v1(73.1,144.36) 73.05,144.31 73.01,144.31 71.87,143.17 65.82,143.17 65.32,143.66 64.9,143.66 60.55,139.31 53,139.31 51.9,138.21 44.16,138.21 43.09,139.28 38.7,139.28 38.53,139.1 v2(37.69,139.1) ; v2(16.7,135.23) 17.41,134.52 27.83,134.52 30.15,132.2 30.15,126.7 30.46,126.39 30.46,98.69 31.26,97.88 31.26,78.39 30.61,77.74 30.61,73.63 27.84,70.86 27.84,53.99 29.71,52.12 29.71,45.98 27.19,43.46 25.76,43.46 23.3,41 23.3,30.81 22.93,30.44 22.93,27.73 27.14,23.52 27.14,19.88 28.74,18.28 v1(28.92,18.28)
  BOTTOM w0.102: R1263.2 72.48,157.13 72.44,157.09 71.61,156.26 71.41,156.26 71.16,156.01 70.92,156.01 69.11,154.2 69.11,148.07 70.03,147.15 v4(70.03,146.59) 70.03,146.04 71.87,144.2 72.93,144.2 v1(73.1,144.36) ; v1(90.74,150.41) 90.95,150.2 R80234.2
PCIE_WAKE#_CPU_B: length 6.1
  TOP w0.102: R58.1 27.55,15.44 28.41,14.58 30.1,14.58 30.47,14.22 Q19.B 31.63,14.22 v3(32.56,13.3)
PCIRST1#: length 11.4
  TOP w0.102: v2(126.22,59.72) 126.22,61.13 127.84,62.75 128.61,62.75 129.41,63.55 129.41,63.8 129.69,64.08 130.07,64.08 130.61,63.54 U109.30
  BOTTOM w0.102: R79953.2 125.24,59.72 v4(125.46,59.72) 125.46,59.72 v2(126.22,59.72) 126.35,59.58 RN3.6
PCIRST3#: length 16.7
  TOP w0.102: U109.81 116.89,57.94 117.52,57.31 120.52,57.31 120.73,57.1 v2(120.9,57.1)
  BOTTOM w0.102: 126.85,59.31 RN3.7 ; 126.85,59.31 126.68,59.48 126.68,59.9 126.36,60.23 124.72,60.23 R79952.2 123.47,59.49 123.04,59.92 v4(122.71,59.92) 122.36,59.92 121.72,59.28 121.72,57.93 v2(120.9,57.1) ; 126.85,59.31 126.93,59.39 127.34,59.39 127.5,59.22 RN3.8
PD4405_A: length 5.7
  TOP w0.102: v3(48.47,70.03) 49.44,71 PQ4409.B 52.48,71 52.84,70.64 PD4405.A
PD4405_K: length 4.2
  TOP w0.102: PR4458.2 59.33,70.98 58.81,70.46 v3(57.65,70.46) 57.48,70.64 PD4405.K
PD_N: length 11.6
  TOP w0.102: U127.36 132.94,31.44 v2(132.51,31.01)
  BOTTOM w0.102: v2(132.51,31.01) 132.17,30.67 v4(132.17,28.53) 132.17,28.12 131.43,27.38 131.43,25.81 129.93,24.31 Q1257.D
PEG_C_RXN0: length 9.9
  TOP w0.102: v3(89.8,116.84) 90.06,117.11 ; 90.06,117.11 90.51,116.66 90.89,116.66 92.27,115.28 92.27,112.51 91.58,111.81 91.58,110.58 GPU1.AG31 ; 90.06,117.11 89.91,117.26 89.91,117.54 C1840.1
PEG_C_RXN1: length 11.7
  TOP w0.102: 91.37,113.41 91.37,114.81 90.97,115.21 90.2,115.21 88.31,117.11 88.2,117.22 87.87,117.55 87.87,117.74 C1842.1 ; 91.37,113.41 91.37,112.86 91.01,112.5 91.01,111.56 91.02,111.56 91.02,110.97 90.92,110.71 90.85,110.42 90.85,110.22 90.93,110.11 90.93,109.87 90.6,109.53 GPU1.AF28 ; 91.37,113.41 v3(90.99,113.41)
PEG_C_RXP0: length 10.2
  TOP w0.102: C1838.1 90.13,118.01 90.13,117.35 90.6,116.88 90.98,116.88 91.68,116.18 ; 91.68,116.18 92.49,115.37 92.49,112.42 91.79,111.72 91.79,110.41 GPU1.AH30 ; 91.68,116.18 v3(91.96,116.46)
PEG_C_RXP1: length 11.2
  TOP w0.102: 90.71,115.43 91.05,115.43 91.59,114.9 91.59,112.77 91.23,112.41 91.23,111.56 91.23,110.92 91.1,110.59 91.06,110.42 91.06,110.29 91.15,110.18 91.15,109.85 GPU1.AG29 ; 90.71,115.43 v3(90.71,115.8) ; 90.71,115.43 90.29,115.43 88.46,117.26 88.08,117.64 88.08,117.8 C1839.1
PEG_RXN0: length 69.1
  TOP w0.102: v1(75.18,162.06) 75.18,161.81 CPU2.J20 ; C1840.2 89.33,119.27 89.54,119.48 89.54,119.76 v1(89.26,120.04)
  BOTTOM w0.102: 88.95,126.67 88.95,123.05 89.5,122.49 89.5,120.28 v1(89.26,120.04) ; 88.95,126.67 v4(88.65,126.67) ; 88.95,126.67 88.95,127.22 77.74,138.42 70.6,138.42 62.95,146.07 62.95,155.17 65.65,157.87 65.65,159.27 68.1,161.72 71.3,161.72 71.41,161.6 73.37,161.6 73.73,161.96 73.73,162.34 73.94,162.55 74.67,162.55 75.16,162.06 v1(75.18,162.06)
PEG_RXN1: length 67.1
  TOP w0.102: CPU2.F20 v1(73.18,162.07) ; C1842.2 87.59,119.11 v1(87.59,119.96)
  BOTTOM w0.102: 75.19,137.49 76.39,137.49 86.69,127.18 87.74,126.14 87.74,120.47 87.59,120.32 v1(87.59,119.96) ; 75.19,137.49 v4(75.19,137.16) ; 75.19,137.49 69.72,137.49 62.03,145.17 62.03,155.52 64.92,158.41 64.92,159.79 67.65,162.52 72.73,162.52 v1(73.18,162.07)
PEG_RXP0: length 68.8
  TOP w0.102: C1838.2 90.24,119.46 90.11,119.58 89.95,119.58 89.82,119.71 89.82,119.94 89.95,120.07 v1(89.97,120.07) ; CPU2.G20 74.54,161.88 v1(74.54,162.02)
  BOTTOM w0.102: 89.16,123.83 89.16,123.14 89.72,122.58 89.72,120.32 v1(89.97,120.07) ; 89.16,123.83 v4(89.47,123.83) ; 89.16,123.83 89.16,127.3 77.83,138.64 70.69,138.64 63.16,146.16 63.16,150.02 63.29,150.15 63.29,150.53 63.16,150.65 63.16,151.03 63.29,151.16 63.29,151.54 63.16,151.66 63.16,152.04 63.29,152.17 63.29,152.55 63.16,152.67 63.16,153.05 63.29,153.18 63.29,153.56 63.16,153.68 63.16,154.06 63.29,154.19 63.29,154.57 63.16,154.69 63.16,155.08 65.87,157.78 65.87,159.18 68.19,161.51 71.21,161.51 71.32,161.39 73.46,161.39 73.94,161.87 73.94,162.25 74.03,162.33 74.43,162.33 74.54,162.22 v1(74.54,162.02)
PEG_RXP1: length 67.5
  TOP w0.102: CPU2.D20 72.86,161.81 72.77,161.9 72.77,161.9 72.61,162.07 v1(72.47,162.07) ; v1(88.37,119.99) 88.22,119.99 88.02,119.79 87.9,119.67 87.9,119.47 88.36,119.01 C1839.2
  BOTTOM w0.102: 87.95,122.05 87.95,126.23 87.37,126.82 86.85,127.34 86.85,127.51 86.58,127.78 86.4,127.78 86.13,128.05 86.13,128.23 85.86,128.5 85.69,128.5 85.42,128.77 85.42,128.94 85.15,129.21 84.97,129.21 84.7,129.48 84.7,129.66 84.43,129.93 84.26,129.93 83.99,130.2 83.99,130.37 83.72,130.64 83.54,130.64 83.27,130.91 83.27,131.09 83,131.36 82.83,131.36 77.07,137.12 77.07,137.27 76.85,137.49 76.69,137.49 76.48,137.71 69.81,137.71 62.25,145.26 62.25,155.44 65.13,158.32 65.13,159.7 67.74,162.31 72.23,162.31 v1(72.47,162.07) ; 87.95,122.05 87.95,120.21 88.17,119.99 v1(88.37,119.99) ; 87.95,122.05 v4(88.27,122.05)
PEG_TXN0: length 59.5
  TOP w0.102: GPU1.AE31 90.05,110.65 90.05,110.89 89.94,111.01 89.94,112.35 89.68,112.61 89.68,114.48 86.53,117.62 86.53,119.48 86.43,119.58 86.32,119.58 v1(85.97,119.93)
  BOTTOM w0.102: v4(73.85,136.02) 73.85,136.33 ; 73.85,136.33 69.71,136.33 61.21,144.83 61.21,144.84 58.82,147.23 58.82,147.23 58.23,147.82 58.23,151.59 C322.2 ; 73.85,136.33 76.12,136.33 86.25,126.2 86.25,120.21 v1(85.97,119.93)
PEG_TXN1: length 64.8
  TOP w0.102: v1(85.01,120.64) 84.42,120.05 84.42,119.21 85.17,118.46 85.17,117.81 88.81,114.17 88.81,112.52 89.41,111.92 89.41,111.19 89.4,111.18 89.4,110.92 89.4,110.92 89.26,110.55 89.26,110.21 89.33,110.11 89.33,109.53 GPU1.AD28
  BOTTOM w0.102: v4(75.7,135.61) 75.7,135.31 ; 75.7,135.31 69.87,135.31 60.6,144.58 60.6,144.58 56.89,148.29 56.89,154.81 C328.2 ; 75.7,135.31 76.17,135.31 85.5,125.98 85.5,122.63 84.78,121.91 84.78,120.87 v1(85.01,120.64)
PEG_TXP0: length 59.5
  TOP w0.102: GPU1.AF30 90.54,110.06 90.54,110.39 90.27,110.66 90.27,110.98 90.16,111.1 90.16,112.44 89.89,112.7 89.89,114.57 86.75,117.71 v1(86.75,119.93)
  BOTTOM w0.102: v4(71.79,136.86) 71.79,136.55 ; 71.79,136.55 69.79,136.55 61.43,144.92 61.43,144.93 58.91,147.44 58.91,147.44 58.45,147.91 58.45,151.85 C325.2 ; 71.79,136.55 76.21,136.55 86.47,126.29 86.47,120.21 v1(86.75,119.93)
PEG_TXP1: length 65
  TOP w0.102: v1(85.08,119.87) 84.9,120.05 84.73,120.05 84.64,119.96 84.64,119.3 85.38,118.55 85.38,117.9 89.02,114.26 89.02,112.61 89.62,112.01 89.62,111.02 89.6,110.88 89.46,110.51 89.46,110.28 89.54,110.18 89.8,109.92 GPU1.AE29
  BOTTOM w0.102: 72.45,135.09 76.08,135.09 85.29,125.89 85.29,122.72 84.56,122 84.56,120.38 v1(85.08,119.87) ; 72.45,135.09 69.78,135.09 60.38,144.49 60.38,144.49 56.68,148.2 56.68,154.89 56.43,155.13 C324.2 ; 72.45,135.09 v4(72.45,134.8)
PHASE1_R: length 52.6
  TOP w0.254: PG4.1 120.38,95.17 v2(120.28,95.28) ; v1(144.25,88.18) 144.05,87.99 PR45.2
  L4 w0.254: v1(144.25,88.18) 144.31,88.24 144.31,89.79 145.24,90.73 145.24,99.89 139.64,105.49 138.08,105.49 137.4,106.17 129.05,106.17 126.18,103.3 121.75,103.3 120.02,101.57 120.02,95.53 v2(120.28,95.28)
  BOTTOM w0.254: v4(143.38,88.18) v1(144.25,88.18)
PLT_RST#_CPU: length 216.1
  TOP w0.102: CPU2.F14 v1(73.18,158.18) ; R46.2 134.55,207.77 134.54,207.78 v2(134.54,209.48)
  L3 w0.127: v2(98.91,209.01) 98.79,208.89 98.79,207.7 97.12,206.02 89.77,206.02 87.42,208.37 87.42,216 86.3,217.13 81.75,217.13 81.03,217.85 77.08,217.85 75.29,219.65 54.25,219.65 54.02,219.42 51.13,216.53 51.13,201.21 51.99,200.35 51.99,180.73 52.73,179.99 52.73,174.94 v2(52.74,174.93) ; v2(60.15,174.93) 59.24,174.93 58.4,174.09 58.4,169.49 57.67,168.76 57.67,159.77 59.14,158.29 64.35,158.29 65.16,159.11 68.77,159.11 69.07,159.41 71.41,159.41 71.88,158.94 71.92,158.94 72.21,158.65 72.71,158.65 v1(73.18,158.18)
  L4 w0.127: v2(134.54,209.48) 132.84,209.48 132.84,209.48 120.11,209.48 119.88,209.25 99.12,209.25 98.91,209.03 v2(98.91,209.01)
  BOTTOM w0.102: v2(134.54,209.48) 135.38,209.48 v4(135.39,209.47) ; R75.2 26.2,176.79 R72.2 26.21,176.8 C42.1 C44.2 33.61,176.8 34.28,176.12 39.61,176.12 41.03,174.7 52.51,174.7 v2(52.74,174.93) v2(60.15,174.93)
PLT_RST#_CPU_G: length 2.7
  BOTTOM w0.102: R75.1 26.2,179.49 v4(26.42,179.72) 26.61,179.91 Q20.2
PLT_RST#_D: length 6.7
  BOTTOM w0.102: Q20.6 29.9,177.83 30.11,177.62 v4(30.21,177.62) 30.51,177.62 31.09,178.2 31.09,179.26 R65.2 31.67,179.91 Q20.5
PLT_RST#_XDP: length 11.6
  TOP w0.102: R46.1 134.65,203.01 138.65,199.01 v5(139.86,199.01) 140.47,199.01 142.03,200.57 XDP1.46
PLTRST*_EC: length 4.2
  TOP w0.102: U4101.6 144.97,79.47 144.39,80.05 v1(144.39,80.29)
  BOTTOM w0.102: R79697.1 143.27,79.14 v4(143.66,79.53) 144.23,80.1 144.23,80.13 v1(144.39,80.29)
PLTRST*_SIO: length 11.9
  TOP w0.102: v2(124.59,64.54) 124.81,64.75 U109.46 124.81,67.28 124.62,67.46 124.62,68.19 125.06,68.63 125.13,68.63 125.69,69.19 v3(127.81,69.19) 128.13,69.19 128.35,69.42 R337.1 C571.1
  BOTTOM w0.102: v2(124.59,64.54) 123.68,63.63 R336.1
PLTRST_LAN_N: length 139.3
  TOP w0.102: v2(33.08,15.8) 33.14,15.73 33.6,15.73 33.75,15.59 U20.19
  L3 w0.127: v2(129.47,53.77) 129.63,53.77 130.4,53 130.4,52.41 124.2,46.21 123.47,46.21 122.32,45.06 117.81,45.06 115.98,43.23 113.17,43.23 105.72,35.78 105.72,33.46 107.81,31.37 108.45,31.37 v2(108.47,31.35)
  L4 w0.127: v2(33.08,15.8) 34.01,16.73 38.24,16.73 45.45,23.93 45.45,28 47.85,30.41 47.85,31.44 49.84,33.43 60.97,33.43 64.8,29.59 71.37,29.59 71.92,29.04 80.42,29.04 81.65,27.81 93.4,27.81 95.15,26.06 102.63,26.06 103.59,27.03 104.69,27.03 108.47,30.8 v2(108.47,31.35)
  BOTTOM w0.102: v2(129.47,53.77) 128.65,54.59 128.65,54.62 128.39,54.88 128.03,54.88 127.82,54.66 127.28,54.66 126.91,55.03 126.91,56.78 126.85,56.83 RN3.2 ; v4(32.34,15.04) 32.75,15.44 32.75,15.47 v2(33.08,15.8)
PLTRST_N: length 261.2
  TOP w0.102: R337.2 128.35,72.48 126.49,74.35 v2(125.14,74.35) ; R64.2 17.88,188.11 v2(17.23,187.46)
  L3 w0.127: LPC1.3 104.78,74.55 101.86,74.55 99.74,72.43 93.12,72.43 89.89,75.65 87.61,75.65 86.83,74.88 57.72,74.88 55.09,77.51 50.54,77.51 49.65,78.4 46.79,78.4 46.32,78.87 43.3,78.87 41.9,80.26 41.9,113.25 40.06,115.1 39.64,115.1 38.63,116.11 38.63,119.75 37.28,121.09 37.28,130.82 32.56,135.54 30.8,137.3 30.8,137.31 29.7,138.4 20.85,138.4 16.91,142.34 16.91,152.05 16.91,152.47 16.14,153.25 16.14,164.47 18.22,166.55 18.22,167.88 15.86,170.25 15.86,186.14 17.17,187.46 v2(17.23,187.46)
  L4 w0.127: LPC1.3 106.78,74.85 111.99,74.85 112.78,75.65 112.78,76.05 113.28,76.55 116.39,76.55 118.27,74.68 119.43,74.68 120.96,73.14 120.96,73.04 121.22,72.78 121.32,72.78 121.93,72.17 124.01,72.17 125.14,73.31 v2(125.14,74.35)
  BOTTOM w0.102: v2(17.23,187.46) 17.23,183.9 20.97,180.16 22.59,180.16 22.98,180.56 Q20.3 ; v4(124.59,74.63) 124.87,74.35 v2(125.14,74.35) 125.44,74.35 125.88,74.79 128.25,74.79 128.91,75.45 136.04,75.45 137.03,76.44 139.87,76.44 142.02,78.59 R79697.2
PLTRST_SL_N: length 100.3
  TOP w0.102: v1(102.37,86.51) 102.66,86.8 D5209.1 D5209.2 103.82,88.83 103.82,92.2 103.26,92.76 101.79,92.76 100.79,93.75 v1(100.39,93.75) ; R1160.2 98.52,106.34 R1159.1 99.69,106.93 100.36,106.93 101.05,107.62 v2(101.61,107.62) 102,107.62 D34.3 ; v2(120.1,62.61) 120.86,61.85 123.94,61.85 125.26,60.53 125.26,56.36 127.18,54.43 128.2,54.43 v1(128.21,54.44)
  L4 w0.127: v1(104.07,78.26) 103.76,77.95 102.7,77.95 101.39,76.63 101.39,72.77 103,71.16 107.2,71.16 109.55,68.81 113.19,68.81 113.61,68.39 113.61,67.16 117.6,63.17 118.56,63.17 119.12,62.61 v2(120.1,62.61)
  BOTTOM w0.102: v1(104.07,78.26) 104.05,78.26 103.98,78.19 98.85,78.19 97.95,79.1 96.53,79.1 96.05,79.58 96.05,81.79 96.68,82.42 98.28,82.42 v1(102.37,86.51) ; RN3.3 126.35,56.61 v4(126.4,56.57) 126.4,55.21 127.18,54.43 128.2,54.43 v1(128.21,54.44) ; v1(100.39,93.75) 100.39,96.9 101.87,98.39 101.87,107.35 v2(101.61,107.62)
PM_DPRSLPVR: length 7
  TOP w0.254: PR17.1 123.82,78.87 v3(123.02,78.08) 122.75,77.8 PR7.1 121.23,77.11 120.3,77.11 PR15.2
PM_SLP_S3#_CPU: length 67.1
  TOP w0.089: 68.99,156.84 68.99,156.97 69.13,157.11 69.14,157.11 70.72,158.68 CPU2.B14
  TOP w0.102: v2(99.65,127.84) 99.57,127.92 R49.1 98.35,127.55 R48.2 ; 68.99,156.84 68.99,155.39 67.38,153.78 67.38,152.82 66.33,151.77 65.69,151.77 v3(64.59,150.67) 63.91,149.99 v1(63.91,149.99)
  L4 w0.127: v1(63.91,149.99) 62.94,149.01 62.94,142.58 69.35,136.16 69.35,135.39 77.85,126.89 82.09,126.89 82.53,127.33 85.5,127.33 85.92,126.91 96.95,126.91 97.87,127.84 v2(99.65,127.84)
PM_SLP_S3#_CPU_D: length 4.9
  TOP w0.102: R51.1 94.47,123.7 v3(94.55,123.78) 94.55,124.48 93.8,125.23 Q16.6 93.01,125.23 92.81,125.43 92.81,125.69 93,125.88 Q16.5
PM_SLP_S3#_CPU_G: length 3.8
  TOP w0.102: v3(96.78,128.55) 96.78,128.32 96.77,128.31 R48.1 C30.1 96.77,126.55 96.11,125.88 Q16.2
PM_SLP_S4#_CPU: length 81.7
  TOP w0.089: CPU2.C12 71.99,157.71 71.71,157.43 71.43,157.43 71.36,157.5 70.78,157.5 69.97,156.68 69.97,156.55
  TOP w0.102: v1(61.39,142.65) 64.61,145.87 65.97,145.87 67.6,147.5 67.6,149.99 69.45,151.84 69.45,153.37 69.97,153.88 69.97,156.55 ; R62.2 104.15,121.45 R63.1 105.31,123.47 105.99,123.47 106.41,123.88 106.41,124.84 103.61,127.64 v1(102.14,127.64)
  L4 w0.127: v1(61.39,142.65) 62.13,142.65 68.84,135.93 68.84,135.18 77.75,126.28 83.26,126.28 83.73,126.75 85.07,126.75 85.42,126.4 100.91,126.4 v1(102.14,127.64)
  BOTTOM w0.102: v4(102.77,127.06) 102.72,127.06 v1(102.14,127.64)
PM_SLP_S4#_CPU_D: length 5.6
  TOP w0.102: Q17.6 108.43,120.31 108.75,120.62 108.75,121.23 109.1,121.59 v3(109.51,121.59) 109.72,121.38 R66.1 108.75,119.66 Q17.5
PM_SLP_S4#_CPU_G: length 3.7
  TOP w0.102: v3(104.58,118.06) 104.59,118.07 C31.1 104.6,119.06 R62.1 105.02,120.1 105.47,119.66 Q17.2
PMC_BATLOW#: length 14.3
  TOP w0.089: CPU2.C14 71.99,158.68 71.71,158.4 71.43,158.4 71.36,158.47 70.77,158.47 69.2,156.9
  TOP w0.102: 69.2,156.9 69.2,156.9 69.2,155.08 68.02,153.91 68.02,153.58 v3(68.02,153.58) 68.02,153.58 68.02,152.87 66.49,151.35 65.84,151.35 65.18,150.69 65.18,150.05 R492.1
PMC_SUS_STAT: length 2
  TOP w0.102: CPU2.D14 v1(72.47,158.18)
  BOTTOM w0.102: v1(72.47,158.18) 71.67,157.38 TP35.1
PORTC_SPK_L: length 19.7
  TOP w0.203: R345.1 162.36,39.75 v2(162.85,40.23) ; U6.43 159.35,52.52 158.71,53.15 v2(158.71,53.26)
  L4 w0.203: v2(162.85,40.23) 162.72,40.36 162.72,50.93 161.7,51.94 159.67,51.94 158.71,52.91 v2(158.71,53.26)
  BOTTOM w0.203: v4(158.76,54.1) 158.71,54.05 v2(158.71,53.26)
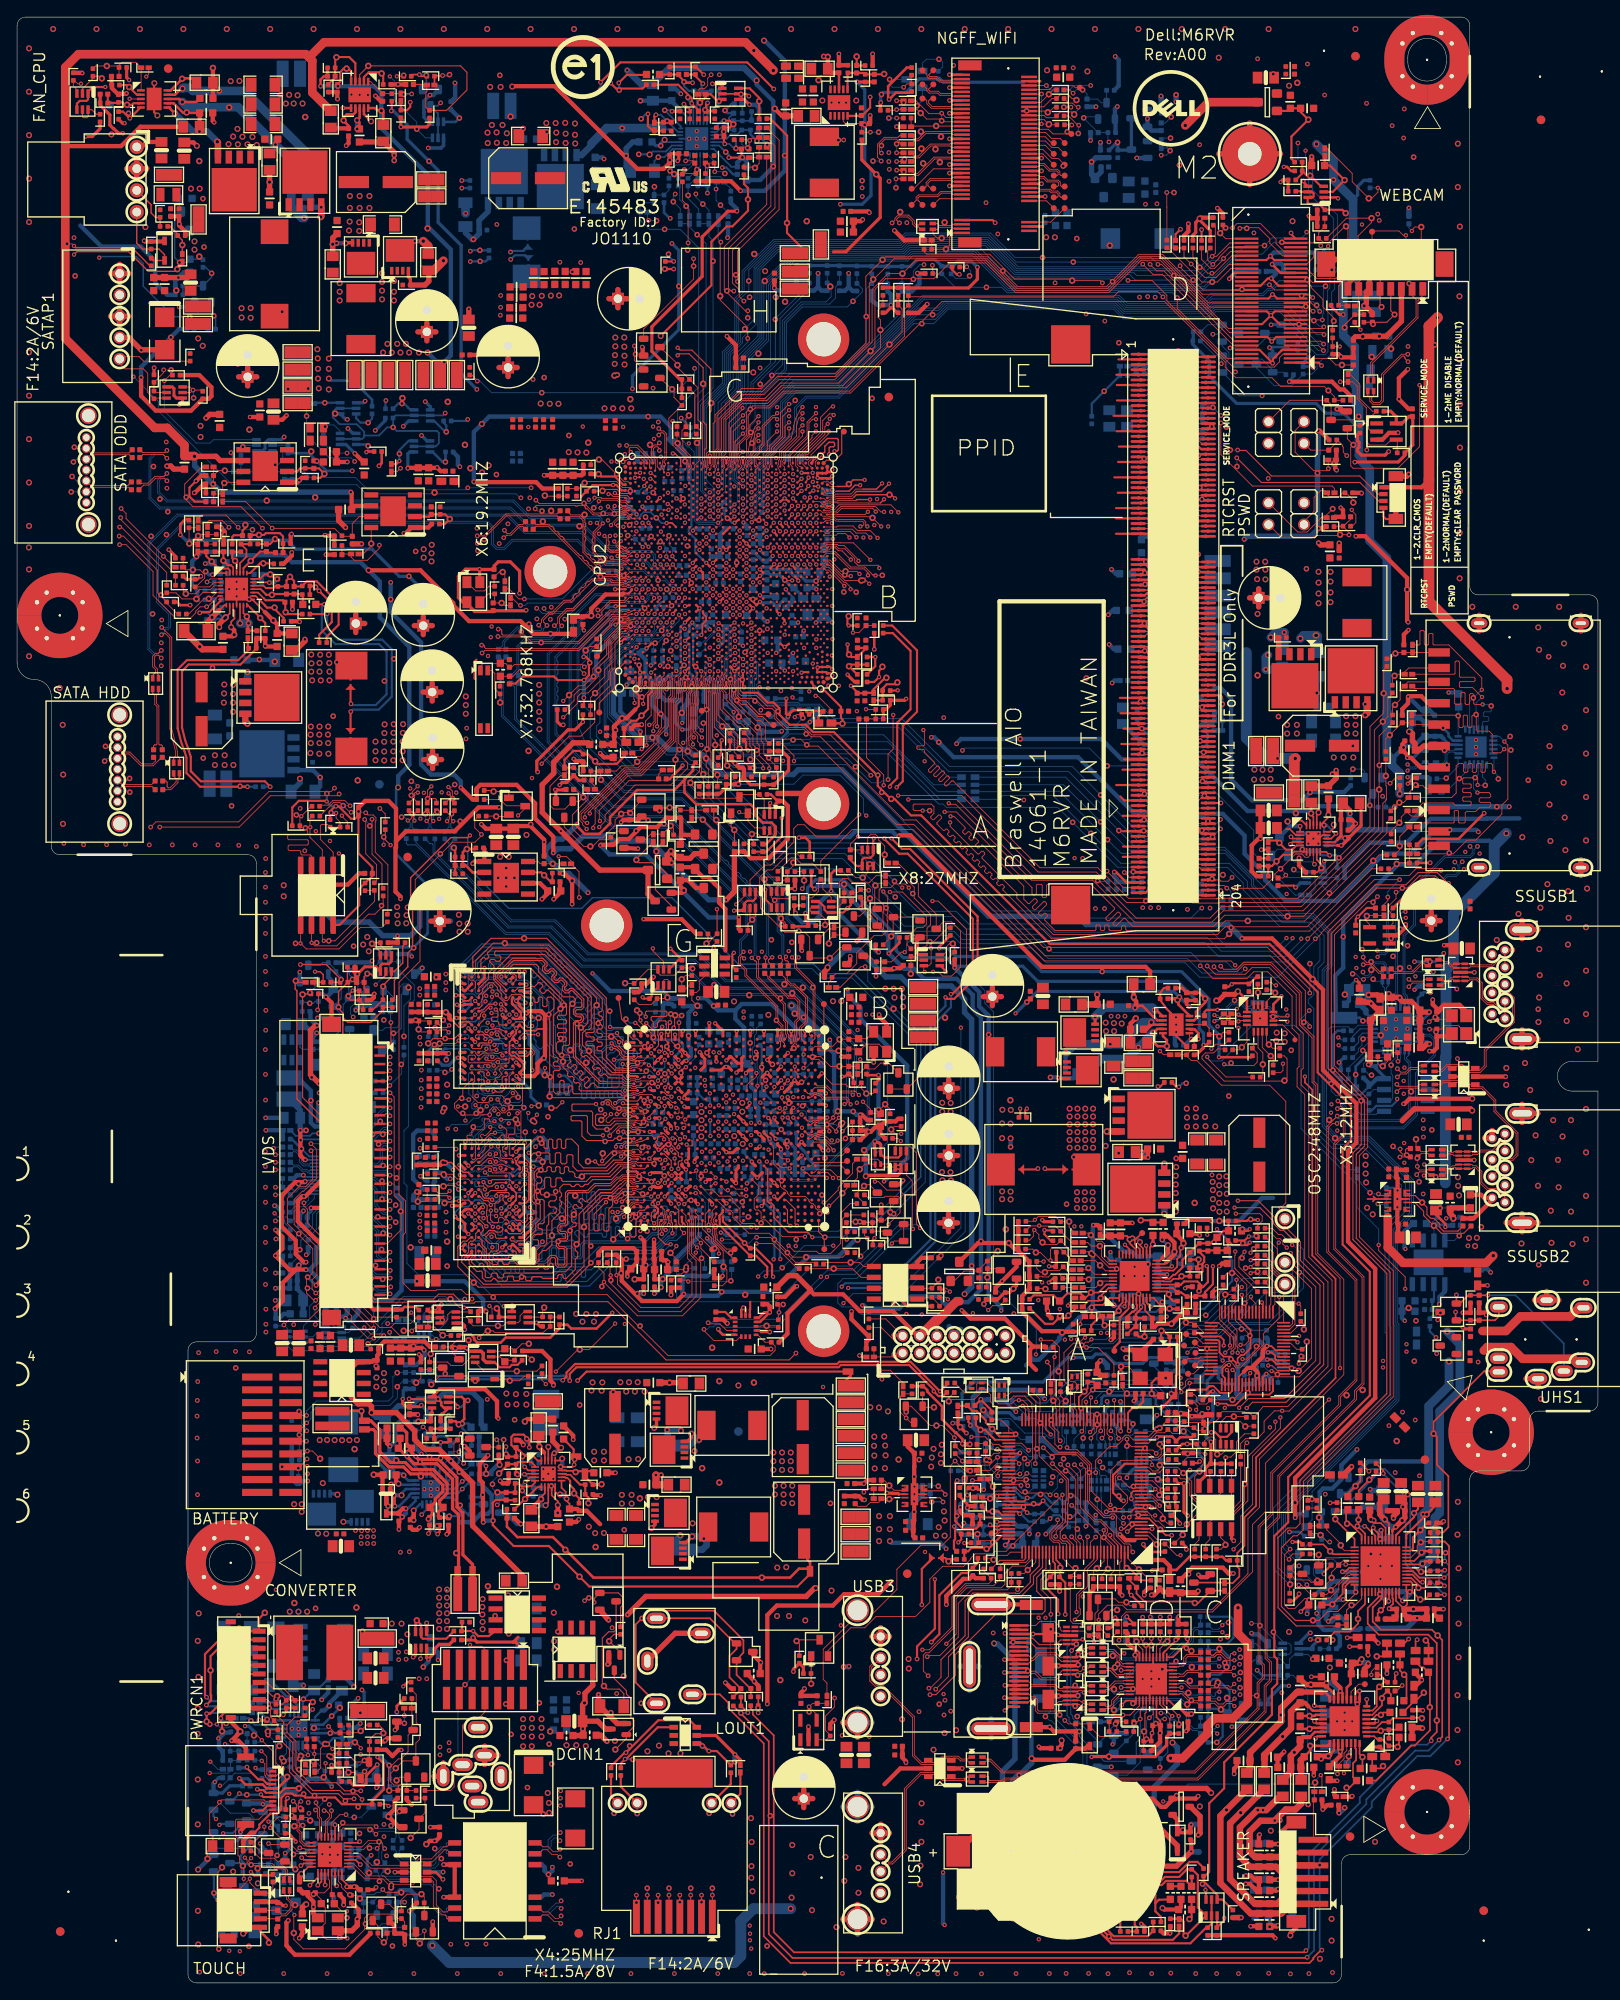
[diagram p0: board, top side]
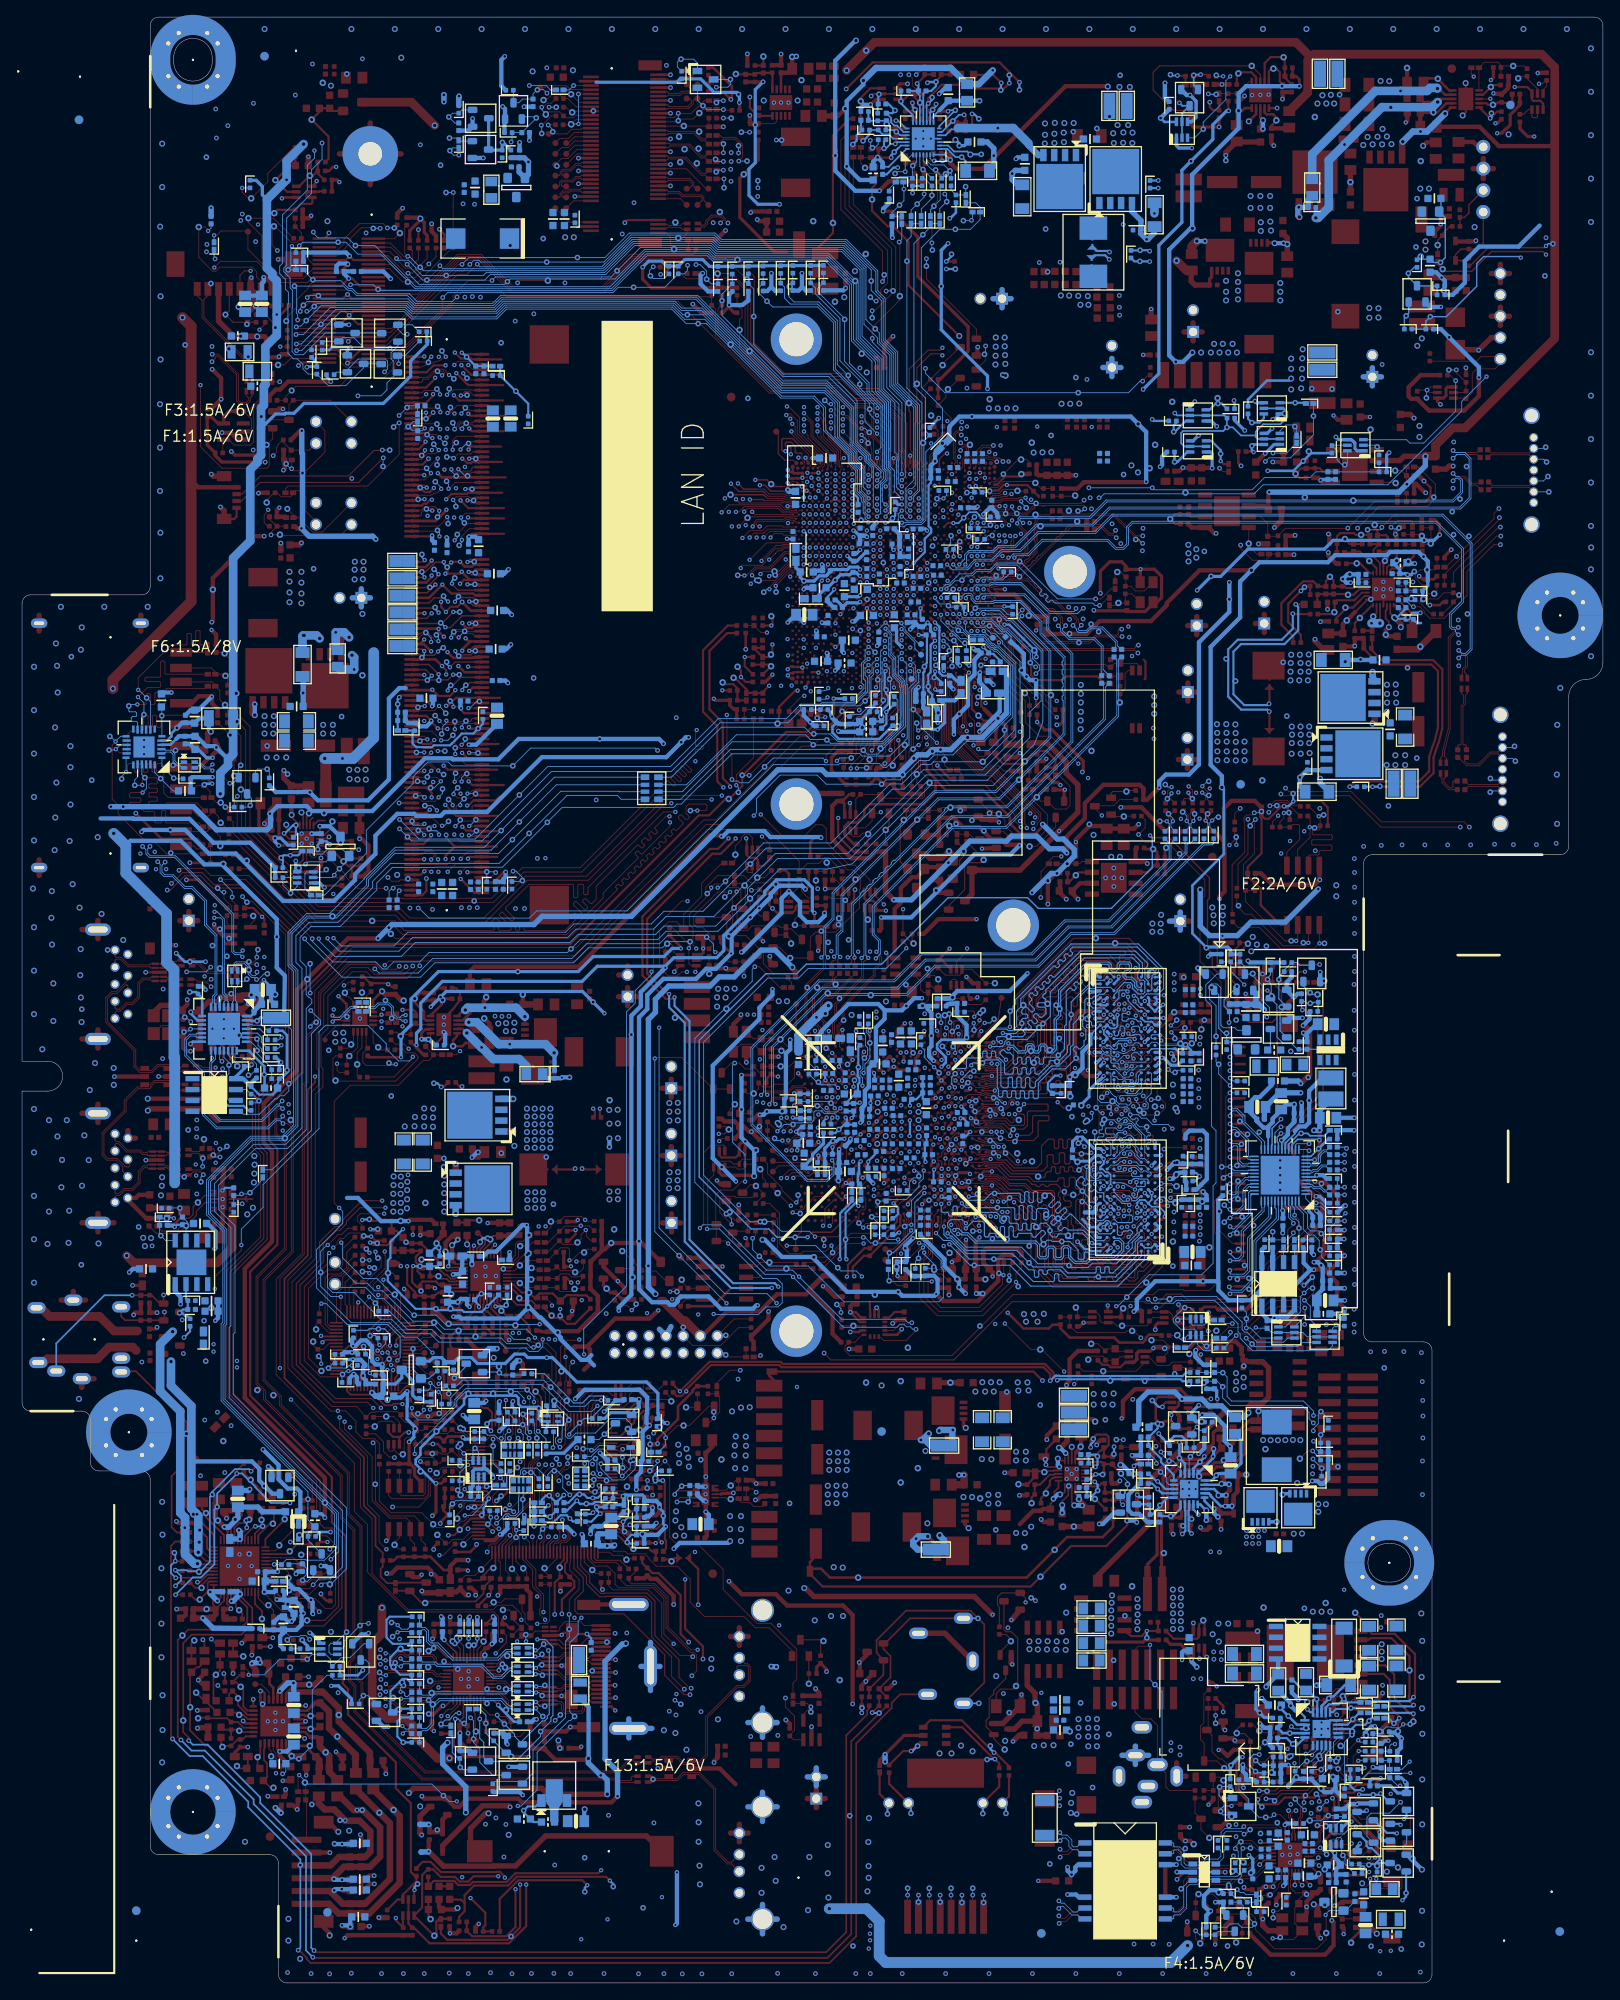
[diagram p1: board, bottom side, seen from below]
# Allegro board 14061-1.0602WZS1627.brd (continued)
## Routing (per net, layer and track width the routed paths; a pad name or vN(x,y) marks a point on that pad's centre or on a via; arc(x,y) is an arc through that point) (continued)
PORTC_SPK_L_1: length 2.6
  TOP w0.203: v3(159.11,38.21) 160.04,38.21 R356.1 R345.2
PORTC_SPK_R: length 22.7
  TOP w0.203: U6.44 158.95,52.31 157.84,53.42 v2(157.69,53.42) ; R359.1 163.66,39.98 v2(163.84,40.16)
  L4 w0.203: v2(157.69,53.42) 158.25,53.98 159.67,53.98 161.07,52.58 161.96,52.58 163.3,51.23 163.3,40.69 v2(163.84,40.16)
  BOTTOM w0.203: v4(156.84,53.44) 156.86,53.42 v2(157.69,53.42)
PORTC_SPK_R_1: length 2.6
  TOP w0.203: v3(164.85,40.07) 165.18,39.73 R359.2 R367.1
PQ4206_D: length 15.2
  TOP w0.127: PR4214.2 71,33.85 70.47,34.37 69.04,34.37 v3(68.68,34.73) 68.49,34.92 68.49,40.35 69.22,41.08 69.82,41.08 70.1,41.36 70.1,44.6 PQ4206.D
PQ4406_2: length 6.9
  TOP w0.102: PQ4406.2 53.14,73.25 52.13,72.24 50.78,72.24 50.38,72.64 PR4462.2 48.28,73.47 v3(48.39,73.59)
PQ4406_3: length 8.5
  TOP w0.102: PR4455.2 60.81,71.57 v3(58.48,71.57) 54.63,71.57 PQ4406.3
PQ4406_5: length 5.6
  TOP w0.102: v3(60.23,72.92) 59.82,73.33 58.49,73.33 58.21,73.05 PR9812.2 57.26,72.85 PC5447.1 56.5,73.25 PQ4406.5
PQ4406_6: length 5
  TOP w0.102: v3(59.89,74.78) 59.08,74.78 PR4450.1 57.98,74.19 PC5447.2 56.79,73.9 PQ4406.6
PQ4409_C: length 4.4
  TOP w0.102: PQ4409.C 49.03,71.98 48.8,71.75 PR4462.1 47.25,71.75 PR4451.1 47.25,70.78 v3(46.7,70.23)
PQ4409_E: length 5.2
  TOP w0.102: PR9814.1 50.93,74.41 PR9813.2 ; PR9814.1 50.92,73.76 PQ4409.E ; PR9814.1 50.92,74.65 51.47,75.2 v3(52.83,75.2)
PRE: length 3.9
  TOP w0.127: R79746.2 v2(132.74,40.29) 132.73,40.29 v3(132.73,39.5) 132.54,39.3 U127.16
  BOTTOM w0.127: R79746.2 v2(132.74,40.29)
PRW_VGA_CORE_RBIAS: length 3.7
  TOP w0.203: v1(129.6,79.15) 129.6,79.23 129.71,79.34 129.71,79.62 129.78,79.69 U6706.3
  BOTTOM w0.254: PR9.1 128.23,79.42 v4(128.34,79.3) 128.5,79.15 v1(129.6,79.15)
PS_0: length 7.6
  TOP w0.102: GPU1.AC19 88.74,102.34 v1(89.24,102.34)
  BOTTOM w0.102: v1(89.24,102.34) 89.24,102.31 89.65,101.9 90.94,101.9 91.65,102.62 v4(91.93,102.62) 92.3,102.62 R394.1 C1847.1 93.95,101.98 R79963.1
PS_1: length 6.6
  TOP w0.102: v1(89.9,102.34) 89.69,102.13 89.66,102.13 89.33,101.8 GPU1.AD19
  BOTTOM w0.102: R943.1 94.23,103.4 C1849.2 R948.1 90.55,103.14 v4(90.33,102.92) 89.9,102.49 v1(89.9,102.34)
PS_2: length 13.4
  TOP w0.102: C1850.1 97.76,98.67 R1899.1 R1900.1 97.7,100.74 v1(96.6,99.64) ; GPU1.AE17 89.52,100.88 89.52,101.19 v1(89.57,101.24)
  BOTTOM w0.102: v1(96.6,99.64) 95.82,100.43 v4(94.78,100.43) 94.57,100.63 92.62,100.63 92.34,100.91 92.34,101.88 92.18,102.03 91.45,102.03 91.12,101.7 89.92,101.7 89.57,101.35 v1(89.57,101.24)
PS_3: length 16.6
  TOP w0.102: GPU1.AE20 89.52,103.28 v1(89.52,103.61) ; v1(98.99,103.1) 99.88,102.21 R935.2 99.98,101.74 C1848.1 101.03,102.24 v3(101.58,102.8) 102.17,102.22 R940.1
  L4 w0.127: v1(89.52,103.61) 89.52,103.63 90.36,104.47 93.67,104.47 94.72,103.42 98.67,103.42 v1(98.99,103.1)
PSI#: length 4.6
  TOP w0.254: PR3.1 127.3,76.97 v3(127.26,76.94) 127.08,77.11 127.08,77.89 PR10.2 126.75,78 125.7,76.95 PR4.2
PSID_D: length 6.4
  TOP w0.102: R424.1 L22.2 47.73,19.9 Q42.D 47.04,17.95 v3(46.06,16.97)
PSID_D_1: length 4.1
  TOP w0.102: R424.2 R422.1 45.6,23.98 Q40.B 44.78,24.07 v3(44.41,23.7)
PSID_G: length 17.8
  TOP w0.102: Q42.G 45.02,20.3 45.02,22.77 44.65,23.14 44.1,23.14 43.7,23.54 43.7,24.5 v3(44.32,25.12) 45.17,25.97 Q40.C 46.67,28.07 47.1,28.5 47.1,30.05 46.71,30.44 46.71,33.74 46.15,34.3 R421.2
PSTBTN_N: length 206.2
  TOP w0.089: CPU2.AF2 83.49,151.95 83.59,151.85 83.59,151.05
  TOP w0.102: v2(151.26,111.89) 151.26,112.12 150.76,112.62 150.76,116.09 146.68,120.17 120.3,120.17 104.92,135.55 102.92,135.55 93.76,144.7 92.52,144.7 91.71,145.52 88.51,145.52 R1208.2 87.56,145.48 87.56,147.15 87.03,147.68 86.51,147.68 85.84,148.34 85.71,148.34 83.59,150.47 83.59,151.05 ; C24.2 R1266.2 136.56,201.96 v2(137.4,201.12) 138.96,199.55 140.33,199.55 141.85,201.07 XDP1.48
  L3 w0.127: v2(157.94,179.35) 159.24,178.05 159.24,170.92 160.69,169.47 161.81,168.35 161.81,143.79 161.74,143.73 161.74,140.75 160.85,139.86 160.85,135.04 153.54,127.73 153.54,114.16 v2(151.26,111.89)
  L4 w0.127: v2(157.94,179.35) 157.89,179.4 157.89,179.86 154.67,183.08 152.48,183.08 145.22,190.34 145.22,191.72 137.4,199.54 v2(137.4,201.12)
  BOTTOM w0.102: v4(150.58,112.39) 150.76,112.39 v2(151.26,111.89)
PW_CLEAR: length 155.8
  TOP w0.102: v2(140.87,182.52) 140.87,178.83 144.57,175.13 153.88,175.13 154.17,174.84 R88.2 ; CPU2.Y7 v1(81.06,154.89)
  L3 w0.127: v2(138.64,125.76) 138.64,125.86 138.79,126.01 138.79,138.88 138.99,139.08 138.99,149.46 138.86,149.59 138.86,180.51 v2(140.87,182.52)
  BOTTOM w0.089: 81.05,154.75 81.06,154.75 v1(81.06,154.89) ; 81.05,154.75 80.47,154.17 80.47,153.3 80.38,153.22 80.38,152.32 80.68,152.02
  BOTTOM w0.102: 81.05,154.75 81.05,154.75 ; 80.68,152.02 81.21,151.49 81.21,144.84 83.84,142.21 84.22,142.21 84.67,142.67 89.34,142.67 89.49,142.52 91.09,142.52 91.13,142.56 97.06,142.56 114.19,125.43 124.77,125.43 125.61,124.59 137.37,124.59 138.54,125.76 v2(138.64,125.76) ; v2(140.87,182.52) 141.03,182.52 v4(141.52,182.03)
PW_CLEAR_H: length 9.8
  TOP w0.102: v3(156.37,173.2) 156.37,173.48 155.51,174.35 R89.1 155.15,174.35 154.69,173.89 153.58,173.89 153.28,174.18 R88.1 153.03,174.6 152.56,174.6 151.77,173.81 151.77,172.16 150.6,170.99 PSWD1.2
PWR_0P95V_BOOT: length 4.2
  TOP w0.305: PU4705.10 134.09,110.77 134.55,110.31 v3(134.55,109.59) 133.48,109.59 133.09,109.98 PR4714.2
PWR_0P95V_BOOT_1: length 3.1
  TOP w0.508: v3(130.91,112.85) 130.31,112.25 PC4703.1 PR4714.1
PWR_0P95V_CS: length 4
  TOP w0.305: v1(138.26,110.44) 138.26,111.11 137.82,111.55 137.26,111.55 PU4705.2
  BOTTOM w0.508: v1(138.26,110.44) 138.22,110.4 137.47,110.4 137.46,110.39 v4(137.44,110.39) 137.34,110.39 136.67,109.72 R79802.1
PWR_0P95V_FB: length 7.6
  TOP w0.305: PU4705.4 137.74,112.62 137.96,112.83 137.96,113.63 139.04,114.71 v3(139.04,115.16) 139.04,115.17 138.36,115.84 PR4717.2
  TOP w0.381: PR4717.2 136.88,115.84 PC4705.2 136.33,116.4 PR4718.1
PWR_0P95V_HG: length 10.8
  TOP w0.305: v6(132.95,111.14) 133.42,111.62 PU4705.9
  BOTTOM w1.016: PR4716.2 125.99,107.26 126.82,108.09 129.85,108.09 v4(131.22,109.45) 131.26,109.45 v6(132.95,111.14)
PWR_0P95V_HG_1: length 4.4
  TOP w0.381: v1(121.83,105.92) 121.94,105.81 PQ4701.4
  BOTTOM w0.508: v4(120.93,105.95) 121.8,105.95 v1(121.83,105.92) 121.89,105.85 PR4715.2 123.59,105.85 PR4716.1
PWR_0P95V_LG: length 9.7
  TOP w0.305: v6(133.13,113.83) 133.32,113.83 134.03,113.12 PU4705.6
  TOP w0.381: PQ4702.4 v6(126.15,113.06)
  BOTTOM w1.016: v6(133.13,113.83) 132.86,114.1 v4(130.83,114.1) 127.19,114.1 v6(126.15,113.06)
PWR_0P95V_LX: length 16.4
  TOP w0.305: 132.72,112.32 132.93,112.12 PU4705.8
  TOP w0.508: PC4703.2 132.14,111.58 132.72,112.17 v6(132.72,112.39)
  BOTTOM w0.508: PR4715.1 122.69,108.76 v6(122.74,108.81)
  BOTTOM w1.016: v6(132.72,112.39) 131.78,112.39 129.21,109.83 v4(127.93,109.83) 127.84,109.83 127.84,109.83 123.76,109.83 v6(122.74,108.81)
PWR_0P95V_PG: length 79.9
  TOP w0.102: PU4705.1 137.19,110.54 137.76,109.97 PC4701.1 137.76,109.5 PR4712.2 ; PR4712.2 136.85,108.47 137.4,107.92 138.06,107.92 140.95,105.03 146.58,105.03 148.47,103.14 148.47,91.26 v1(147.89,90.68) ; PR4712.2 135.85,108.58 R1835.1 ; U109.17 132.63,58.34 v1(133.21,57.76) 133.69,57.28 v3(133.69,57.07) 133.99,56.77 R79763.1
  L4 w0.127: v1(133.21,57.76) 133.21,59.22 134.07,60.08 134.07,60.93 134.86,61.72 134.86,64.69 134.87,64.71 135.11,64.95 135.11,67.65 136.15,68.68 136.44,68.68 136.7,68.94 136.7,73.19 136.96,73.46 v1(136.96,73.74)
  BOTTOM w0.102: v1(136.96,73.74) 138.7,75.48 140.22,75.48 141.99,77.25 146.48,77.25 150.55,81.32 150.55,85.78 147.48,88.85 147.48,90.27 v1(147.89,90.68)
PWR_0P95V_PG_L: length 272.5
  TOP w0.102: R1835.2 134.15,108.61 v1(133.74,109.02)
  L3 w0.127: v1(133.74,109.02) 133.74,113.99 131.42,116.31 120.4,116.31 117.89,118.82 110.61,118.82 109.12,117.34 105.2,117.34 104.83,117.7 102.08,117.7 101.54,118.25 98.86,118.25 98.43,118.68 97.33,118.68 96.64,119.37 82.44,119.37 73.08,128.73 60.33,128.73 58.15,130.91 54.72,130.91 54.24,130.43 53.04,130.43 52.81,130.66 52.78,130.66 52.74,130.7 41.72,130.7 39.83,132.59 36.23,132.59 34.45,134.37 32.92,135.9 31.31,137.51 31.31,137.52 29.91,138.91 21.06,138.91 17.66,142.31 17.66,165.25 18.73,166.32 18.73,168.3 16.37,170.66 16.37,185.19 17.7,186.52 17.7,187.66 17.32,188.04 16.04,188.04 15.15,188.92 11.53,188.92 10.59,189.87 10.59,202.27 7.08,205.78 7.08,220.37 12.2,225.49 41.2,225.49 v1(43.62,223.06)
  BOTTOM w0.102: v1(43.62,223.06) 44.13,222.55 44.13,220.34 46.77,217.7 v4(46.77,216.89) 47.79,215.87 Q1233.3
PWR_0P95V_RF: length 3.7
  TOP w0.305: v3(135.8,114.99) 135.89,114.9 135.89,114.48 137.19,113.18 PU4705.5
  TOP w0.381: v3(135.8,114.99) 135.64,115.15 PR4702.1
PWR_0P95V_SN: length 2.9
  TOP w0.508: v3(126.4,115.64) PC4704.1
  TOP w0.762: PC4704.1 126.37,114.48 PR4713.2
PWR_0P95V_VCC: length 6.5
  TOP w0.305: PU4705.7 133.44,112.62 133,113.06 132.96,113.06 131.68,114.33 PC4702.1
  TOP w0.508: PC4702.1 130.96,114.84 130.69,115.12 v3(130.69,115.33) 130.69,115.59 130.66,115.62 PR4701.1
PWR_0P95V_VIN:
  vias: v3(128.31,105.7)
PWR_1D15V_A: length 20
  TOP w0.381: PC5262.1 100.31,222.41 R79796.1 98.3,222.41 v2(98.28,222.43)
  BOTTOM w0.381: v2(98.28,222.43) 99.19,221.51 v4(99.19,217.4) 99.19,212.95 99.93,212.22 99.93,209.14 98.89,208.1 v2(96.35,208.1)
  vias: v3(92.41,206.12)
PWR_1D15V_EN: length 66.3
  TOP w0.254: PR5479.1 PR5480.2 45.64,219.11 46.01,219.48 v2(46.01,220.04) ; PU5206.5 98.76,218.45 PC5266.1 98.92,218.49 99.83,219.41 v2(99.83,220.65) ; v2(68.28,222.38) 70.6,224.7 85.44,224.7 88.55,221.59 v2(88.55,221.59)
  L3 w0.254: v2(99.83,220.65) 99.8,220.68 99.8,220.83 99.04,221.59 v2(88.55,221.59)
  L4 w0.254: v2(46.01,220.04) 46.62,219.43 49.91,219.43 53.11,222.63 68.03,222.63 v2(68.28,222.38)
  BOTTOM w0.254: v2(68.28,222.38) v4(68.28,221.49)
PWR_1D15V_FB: length 6.3
  TOP w0.254: PU5206.6 97.18,223.44 R79800.1 98.23,223.48 PC5265.1 99.1,223.46 R79796.2 100.31,223.3 PC5262.2 101.43,223.3 v3(101.47,223.34)
PWR_1D15V_FB_N: length 2
  TOP w0.254: v3(98.25,225.39) 98.25,225.27 98.25,225.26 PC5265.2 98.27,224.33 PR5473.1
PWR_1D15V_LX: length 0.6
  BOTTOM w0.254: v2(96.73,215.62) 96.5,215.6 v4(96.12,215.6)
PWR_1D15V_PVIN:
  vias: v3(93.79,222.62)
PWR_1D15V_SN: length 3.1
  TOP w0.508: PC5263.1 89.52,218.43 v3(88.67,219.29)
  TOP w0.635: PC5263.1 91.4,218.43 PR5474.2
PWR_1D15V_SVIN: length 4.8
  TOP w0.305: PU5206.8 96.18,223.47 PC5259.1
  TOP w0.508: v3(94.88,225.35) PR5475.2 95.35,223.48 PC5259.1
PWR_1P05V_BOOT: length 3.4
  TOP w0.305: PU4701.10 41.89,219.35 42.13,219.11 42.57,219.11 v3(42.63,219.05) 42.86,218.82 PR9794.2
PWR_1P05V_BOOT_1: length 5.6
  TOP w0.635: v2(44.13,213.82) 44.13,214.17 PR9794.1 42.81,215.39 PC5442.1
  BOTTOM w0.254: v2(44.13,213.82) v4(44.13,213.22)
PWR_1P05V_CS: length 4.2
  TOP w0.254: R80102.1 42.84,223.22 v3(42.66,223.41) 42.62,223.41 42.48,223.55 41.16,223.55 40.59,222.98 PU4701.2
PWR_1P05V_FB: length 8.2
  TOP w0.254: PU4701.4 39.59,224.61 38.87,225.32 37.4,225.32 v3(37.37,225.3) 37.22,225.15 PR9795.2 37.22,224.06 PC5446.2 37.22,222.92 PR9796.1
PWR_1P05V_HG: length 22.2
  TOP w0.305: PU4701.9 40.59,218.65 v6(41.44,217.81)
  TOP w1.016: PR9797.2 48.12,203.2 v6(47.53,203.78)
  L4 w1.016: v6(47.53,203.78) 45.68,203.78 44.99,204.47 44.99,211.48 44.86,211.61 44.86,211.63 41.69,214.81 41.69,217.55 v6(41.44,217.81)
  BOTTOM w0.508: v6(47.53,203.78) v4(46.58,203.78)
PWR_1P05V_HG_1: length 7.6
  TOP w0.381: PQ47001.4 45.79,199.6 46.02,199.36 PR9798.2
  TOP w0.635: PR9798.2 47.73,198.65 48.18,199.1 48.18,200.29 PR9797.1
  TOP w1.016: v3(49.89,201.5) 48.75,200.36 PR9797.1
PWR_1P05V_LG: length 19.5
  TOP w0.305: PU4701.6 v2(38.13,219.35)
  TOP w0.406: PQ47002.4 38.47,203.59 v6(38.42,203.54)
  L4 w1.016: v2(38.13,219.35) 37.24,218.47 37.24,204.72 v6(38.42,203.54)
  BOTTOM w0.508: v6(38.42,203.54) v4(37.38,203.54)
PWR_1P05V_LX: length 24.3
  TOP w0.305: PU4701.8 40.09,218.24 v6(39.78,217.93) 39.81,217.93 40.06,217.68 PC5442.2
  L4 w1.016: v6(44.1,199.14) 44.1,202.82 43.21,203.71 43.21,210.95 39.78,214.38 v6(39.78,217.93)
  BOTTOM w0.508: v6(39.78,217.93) v4(39.78,216.91)
  vias: v6(37.75,198.88) v6(37.75,197.87) v6(37.75,196.85) v6(42.71,200.03) v6(42.71,199.01) v6(42.71,197.99) v6(42.71,196.98) v6(44.1,197.87) v6(44.1,196.85)
PWR_1P05V_PG: length 46.6
  TOP w0.102: v2(46.17,221.01) 46.08,221.01 46.05,221.04 PR5479.2 PR9803.2 PC5444.1 41.37,222.45 PU4701.1 ; v2(81.22,223.26) 80.82,222.85 80.82,221.99 80.49,221.66 79.9,221.66 79.69,221.45 R1838.1
  L3 w0.127: v2(81.22,223.26) 80.76,222.79 71.61,222.79 70.77,223.63 53.89,223.63 51.61,221.35 48.12,221.35 47.73,220.95 46.23,220.95 v2(46.17,221.01)
  BOTTOM w0.102: v2(46.17,221.01) 46.12,220.95 v4(45.26,220.95)
PWR_1P05V_PG_L: length 3.4
  TOP w0.254: v3(79.92,219.99) 80.58,220.65 R1838.2 81.17,220.97 81.77,220.37 Q1229.3
PWR_1P05V_RF: length 4.4
  TOP w0.254: PU4701.5 39.09,223.67 38.78,223.97 v3(38.56,223.97) 38.22,223.97 37.81,223.56 37.81,222.45 PR9804.1
PWR_1P05V_SN: length 2.9
  TOP w0.635: PR9805.2 v3(36.94,203.43) 36.94,204.17 PC5445.1
PWR_1P05V_VCC: length 5.8
  TOP w0.305: PU4701.7 39.59,218.85 39.36,218.62 38.59,218.62 38.21,218.24 38.21,217.93 v3(38.21,217.92) 38.21,217.86 38.79,217.28 PC5443.1
  TOP w0.508: PC5443.1 36.8,216.98 PR9793.1
PWR_1P05V_VIN:
  vias: v3(48.04,205.28)
PWR_1P15V_PG: length 124.6
  TOP w0.102: v2(42.39,168.22) 42.39,167.85 40.99,166.45 39.45,166.45 39.09,166.81 PR5216.2 38.09,167.18 PC5222.1 PR5241.2 ; PU5206.4 96.68,217.8 96.95,217.54 PC4801.1 98.85,216.53 PR4812.2 99.85,216.53 v2(99.86,216.53) ; v2(44.86,177.22) 44.46,176.81 R1839.1
  L3 w0.127: v2(44.86,177.22) 45.5,177.86 47.88,177.86 50.92,180.89 50.92,199.57 50.11,200.37 50.11,216.95 53.6,220.44 53.83,220.66 76.44,220.66 76.95,220.15 78.2,218.9 85.83,218.9 87.89,220.95 98.53,220.95 98.86,220.62 98.86,217.53 v2(99.86,216.53)
  L4 w0.127: v2(42.39,168.22) 42.39,174.75 v2(44.86,177.22)
  BOTTOM w0.102: v2(99.86,216.53) v4(100.82,216.53)
PWR_1P15V_PG_L: length 4.5
  TOP w0.254: v1(44.74,178.05) 44.38,177.7 R1839.2
  BOTTOM w0.254: v1(44.74,178.05) v4(44.74,178.92) 44.74,179.34 45.82,180.42 Q1230.3
PWR_3D3V_SN: length 3.2
  TOP w0.864: PR4911.2 PC4907.1 74.76,59.41 v2(74.75,59.42)
  BOTTOM w0.508: v4(75.36,59.42) 75.34,59.44 74.76,59.44 v2(74.75,59.42)
PWR_3V_BOOT2: length 3.3
  TOP w0.203: PU4901.7 61.76,57.28 61.32,56.84 v3(61.32,56.59)
  TOP w0.508: v3(61.32,56.59) 60.18,55.46 PR4902.2
PWR_3V_BOOT2_R: length 3.1
  TOP w0.635: PC4913.2 v3(61.91,53.39) 60.21,53.39 PR4902.1
PWR_3V_ENTRIP2: length 5.1
  TOP w0.203: v2(59.47,58.62) 60.01,59.16 PU4901.4
  BOTTOM w0.254: PC4912.1 PR4924.1 59.8,56.93 v4(59.13,57.61) 59.13,58.28 v2(59.47,58.62)
PWR_3V_FB: length 46.1
  TOP w0.254: PR4914.1 57.26,56.48 PC4910.2 56,56.5 55.66,56.16 55.66,53.57 58.11,51.12 62.22,51.12 v3(65.82,47.52) 66.96,46.38 91.32,46.38 PG4902.1
PWR_3V_FB2: length 6
  TOP w0.203: 59.85,58.12 60.18,58.12 60.61,58.55 PU4901.5
  TOP w0.254: 59.85,58.12 59.82,58.09 59.04,58.09 58.68,58.45 PR4917.1 58.29,57.38 PR4914.2 58.25,57.39 PC4910.1 v3(56.21,57.39)
PWR_3V_LGATE2: length 15.5
  TOP w0.203: PU4901.10 62.96,57.47 63.28,57.15 v6(63.53,57.15)
  TOP w0.406: v6(74.23,53.2) 74.65,53.63 PQ4903.4
  L3 w1.016: v6(74.23,53.2) 72.57,54.86 67.93,54.86 65.64,57.15 v6(63.53,57.15)
  BOTTOM w0.508: v4(64.31,56.64) 63.79,57.15 v6(63.53,57.15)
PWR_3V_PHASE2: length 23.5
  TOP w0.203: v6(63.28,55.91) 63.28,56.34 62.56,57.05 PU4901.9
  TOP w0.508: PC4913.1 v6(63.28,55.91)
  L4 w1.016: v6(63.28,55.91) 63.71,55.47 63.71,54.97 67.4,51.28 74.14,51.28 76.89,54.03 78.8,54.03 v6(79.05,53.77)
  BOTTOM w0.508: v6(63.28,55.91) 63.28,55.01 v4(63.27,55)
  vias: v3(82.18,58.55)
PWR_3V_UGATE2: length 25.4
  TOP w0.203: v6(61.86,55.88) 62.16,56.18 PU4901.8
  L4 w1.016: v6(61.86,55.88) 61.86,54.49 66.71,49.63 74.86,49.63 v6(77.6,52.37)
  BOTTOM w0.508: v4(60.93,55.85) 60.96,55.88 61.24,55.88 61.24,55.88 61.57,55.88 61.57,55.88 v6(61.86,55.88)
  BOTTOM w0.762: PR4904.2 77.1,51.79 77.6,52.3 v6(77.6,52.37)
PWR_3V_UGATE2R: length 5.7
  TOP w0.406: v6(79,52.25) 78.27,51.52 PQ4901.4
  BOTTOM w0.762: v6(79,52.25) 80.1,52.25 v4(80.37,51.98) 80.7,51.65 80.7,51.2 80.2,50.7 PR4904.1
PWR_5V_BOOT1: length 3.2
  TOP w0.203: 61.65,62.08 61.76,61.97 PU4901.19
  TOP w0.508: PR4903.1 61.07,64.01 61.07,62.79 v3(61.12,62.74) 61.12,62.61 61.65,62.08
PWR_5V_BOOT1_R: length 3.4
  TOP w0.508: PR4903.2 59.71,65.97 v3(59.42,65.68)
  TOP w0.762: PC4914.1 62.68,65.97 PR4903.2
PWR_5V_BYP1: length 53.8
  TOP w0.203: PU4901.20 60.92,61.11 60.59,61.44
  TOP w0.254: v2(59.95,62.65) 59.95,63.48 59.28,64.15 58.12,64.15 57.84,63.88 57.84,62.94 58.16,62.62 PC4915.1 ; 60.59,61.44 60.33,61.7 59.39,61.7 58.8,62.29 58.73,62.29 PC4915.1 ; PC4915.1 PR4921.2 PC4909.1 ; PG4903.2 66.64,71.53 v2(65.59,70.47)
  L3 w0.254: v2(65.59,70.47) 65.59,68.09 60.15,62.65 v2(59.95,62.65)
  BOTTOM w0.254: v2(59.95,62.65) 59.95,62.99 59.64,63.3 v4(59.64,63.65)
PWR_5V_ENTRIP1: length 4.9
  TOP w0.203: v2(59.39,60.38) 59.81,59.96 PU4901.2
  BOTTOM w0.254: v2(59.39,60.38) 59.15,60.62 v4(59.15,61.6) 59.35,61.81 PC4911.1 60.2,60.88 PR4925.1
PWR_5V_FB1: length 6.2
  TOP w0.203: PU4901.1 60.61,60.5 60.18,60.93 59.52,60.93
  TOP w0.254: v3(56.41,59.61) 56.41,59.61 57.39,60.59 PC4909.2 PR4921.1 ; PR4921.1 58.4,59.6 PR4922.1 ; PR4921.1 58.64,60.93 59.52,60.93
PWR_5V_LGATE1: length 15.4
  TOP w0.203: v6(63.79,61.34) 63.56,61.11 PU4901.16
  TOP w0.406: v6(74.56,64.94) 74.56,64.94 74.83,65.21 PQ4902.4
  L3 w1.016: v6(63.79,61.34) 63.99,61.54 65.49,61.54 67.67,63.73 73.35,63.73 v6(74.56,64.94)
  BOTTOM w0.508: v6(63.79,61.34) 63.79,60.57 v4(63.61,60.39)
PWR_5V_PHASE1: length 26.2
  TOP w0.203: PU4901.17 62.56,61.77 62.75,61.95 63,61.95 v6(63.66,62.61)
  TOP w0.635: v6(63.66,62.61) 63.45,62.61 62.69,63.37 PC4914.2
  L4 w1.016: v6(63.66,62.61) 63.66,62.8 63.67,62.82 63.67,63.5 66.72,66.55 75.24,66.55 75.99,65.8 75.99,63.92 77.68,62.23 v6(79.28,62.23)
  BOTTOM w0.508: v6(63.66,62.61) 63.51,62.61 v4(62.87,61.97)
  vias: v3(80.17,60.22) v3(82.18,70.41)
PWR_5V_SN: length 2.8
  TOP w0.635: PC4908.1 v3(76.36,70.23) 77.83,70.23 PR4912.2
PWR_5V_UGATE1: length 26.6
  TOP w0.203: PU4901.18 v6(62.16,62.71)
  L4 w1.016: v6(77.68,64.59) 77.68,66.5 75.98,68.2 66.04,68.2 62.02,64.18 62.02,62.85 v6(62.16,62.71)
  BOTTOM w0.762: PR4905.2 76.13,64.64 v4(76.07,64.7) 77.57,64.7 v6(77.68,64.59)
PWR_5V_UGATE1R: length 4.5
  TOP w0.406: PQ4904.4 78.45,63.36 78.9,63.8 v6(78.9,64.26)
  BOTTOM w0.762: 79.64,63.52 v4(79.81,63.52) ; 79.64,63.52 v6(78.9,64.26) ; 79.64,63.52 79.3,63.52 79.05,63.26 79.05,63.25 78.66,62.87 PR4905.1
PWR_CHG_ACDET: length 9.7
  BOTTOM w0.254: U55.6 50.22,59.44 51.7,60.91 51.7,61.32 53.18,62.8 PR4412.1 PC5232.1 53.11,63.88 52.1,64.89 v4(52.1,65.45) 52.85,65.45 53.12,65.18 PR5270.2
PWR_CHG_ACN: length 23.9
  TOP w0.381: v3(51.39,50.29) 51.66,50.29 ; 51.66,50.29 51.66,54.77 50.96,55.47 50.96,58.92 49.13,60.74 46.77,60.74 46.48,60.74 v2(45.63,61.59) 44.66,62.56 PC4402.1 44.81,62.76 PC4404.1 ; 51.66,50.29 51.66,48.55 PG4905.2
  BOTTOM w0.305: U55.1 45.63,61.38 v2(45.63,61.59)
  BOTTOM w0.381: v4(45.56,62.49) 45.56,61.66 v2(45.63,61.59)
PWR_CHG_ACP: length 24.1
  TOP w0.381: PC4403.1 45.04,64.92 45.6,64.36 45.6,63.09 PC4402.2 46.13,62.1 v2(46.64,61.59) 46.99,61.25 49.34,61.25 51.47,59.13 51.47,55.68 52.17,54.98 52.17,50.1 53.3,48.97 PG4907.2
  BOTTOM w0.305: v2(46.64,61.59) 46.64,61.47 v4(47.16,60.95) 47.92,60.19 U55.2
PWR_CHG_AD_OFF: length 127.9
  TOP w0.127: U4101.19 141.08,76.44 141.94,75.58 v1(141.94,74.57) ; PR4210.1 70.62,43.95 70.86,44.19 70.86,45.14 70.37,45.63 PQ4206.G 67.56,45 v1(67.56,44.53)
  L4 w0.127: v1(141.94,74.57) 141.52,74.99 141.03,74.99 138.95,72.91 138.95,68.78 138.42,68.26 138.42,66.05 137.73,65.35 137.73,63.19 136.51,61.97 136.51,60.97 135.77,60.24 135.77,59.45 135.58,59.25 135.58,57.39 135.68,57.29 135.68,54.94 135.34,54.6 135.34,53.28 135.83,52.78 135.83,51.63 135.05,50.84 135.05,49.15 134.44,48.54 134.44,45.1 133.19,43.85 131.76,43.85 130.11,42.2 129.68,42.2 127.67,40.2 127.67,39.94 125.14,37.41 124.55,37.41 123.55,36.41 116.31,36.41 114.28,34.38 111.07,34.38 107.75,37.69 107.75,37.96 103.3,42.41 99.62,42.41 99.26,42.05 96.82,42.05 94.05,44.82 67.85,44.82 v1(67.56,44.53)
  BOTTOM w0.127: v1(141.94,74.57) 141.94,75.88 142.6,76.54 143.26,76.54 v4(143.29,76.5) 143.32,76.54 144.38,76.54 144.56,76.36 R80230.1
PWR_CHG_AD_OFF_R: length 3.9
  TOP w0.127: PQ4204.B 70.54,38.72 v3(69.29,39.98) 69.29,40.21 69.86,40.78 PR4210.2
PWR_CHG_BTST: length 6.1
  TOP w0.508: PR5279.1 43.66,57.65 44.08,57.23 44.08,55.91 v2(44.2,55.78)
  BOTTOM w0.305: U55.17 46.11,57.28 45.88,57.05 45.88,56.95 44.71,55.78 v2(44.2,55.78)
  BOTTOM w0.508: v2(44.2,55.78) 43.42,55.78 v4(43.42,55.79)
PWR_CHG_BTST_1: length 4.4
  TOP w0.508: v3(41.73,59.46) 42.8,59.46 PC5234.1 42.77,59.37 PR5279.2 42.77,57.47 43.21,57.02 PD4401.K
PWR_CHG_CMPIN: length 9.8
  TOP w0.305: PR5467.2 50.39,63.25 v2(49.56,63.25) 48.99,63.25 PR5287.2 48.83,64.17 48.42,64.58 PR5470.1 PR5468.1 PR5469.2
  BOTTOM w0.305: U55.4 48.92,60.76 v4(49.56,61.4) v2(49.56,63.25)
PWR_CHG_CMPIN_R: length 3.1
  TOP w0.305: PQ5006.3 48.55,66.65
  TOP w0.508: v3(46.96,65.67) 47.01,65.72 PR5470.2 48.42,66.52 48.55,66.65
PWR_CHG_CMPIN_RR: length 6.4
  TOP w0.305: PR5469.1 51.31,65.72 v3(51.69,65.34) 52.33,65.99 52.33,68.28 52.04,68.57 PQ5006.6
PWR_CHG_HIDRV: length 11.4
  L3 w1.016: v6(44.99,57.05) 44.91,57.12 v6(37.49,57.12)
  BOTTOM w0.305: v6(44.99,57.05) 45.02,57.07 45.02,57.3 45.5,57.78 U55.18
  BOTTOM w0.406: v6(37.49,57.12) 37.38,57.24 PU4403.4
  BOTTOM w0.508: v6(44.99,57.05) v4(44.1,57.05)
PWR_CHG_ILIM: length 6.4
  BOTTOM w0.254: PQ5003.D 53.18,56.01 PR5268.1 53,55.83 52.99,55.73 PR5278.2 52.75,54.8 51.85,55.7 v4(51.85,55.88) 50.94,56.79 U55.10
PWR_CHG_IOUT: length 10.2
  TOP w0.102: PR5467.1 51.11,63.08 51.11,61.93 v2(52.26,60.78)
  BOTTOM w0.102: U55.7 50.76,58.29 51.1,58.63 51.1,59.12 v4(51.76,59.78) 52.07,60.09 52.57,60.09 PR5288.1 PC5239.1 52.89,61.72 52.26,61.09 v2(52.26,60.78)
PWR_CHG_LODRV: length 13.5
  TOP w0.508: PC5237.1 46.41,54.58 v6(46.41,55.27)
  L3 w1.016: v6(46.41,55.27) 46.41,55.12 45.4,54.1 38.34,54.1 v6(38.18,53.95)
  BOTTOM w0.305: v6(46.41,55.27) 47.13,55.98 U55.15
  BOTTOM w0.406: PU4405.4 v6(38.18,53.95)
  BOTTOM w0.508: v6(46.41,55.27) v4(46.41,54.14)
PWR_CHG_NC: length 3.4
  BOTTOM w0.254: U55.11 49.42,55.49 50.3,54.61 v4(50.58,54.61) 51.66,54.61 PR5286.1
PWR_CHG_PHASE: length 13.3
  TOP w0.508: PC5234.2 44.36,58.67 v6(44.64,58.39)
  L3 w1.016: v6(35.78,58.48) 36.07,58.78 44.25,58.78 v6(44.64,58.39)
  BOTTOM w0.305: U55.19 44.77,58.29 44.64,58.42 v6(44.64,58.39)
  BOTTOM w0.508: v4(43.74,58.32) 43.82,58.39 v6(44.64,58.39)
PWR_CHG_SRN: length 5.1
  TOP w0.254: PR5277.1 49.44,52.75 v2(49.21,52.52)
  BOTTOM w0.254: 48.86,53.48 48.86,55.21 48.92,55.27 U55.12 ; 48.86,53.48 48.86,52.87 v2(49.21,52.52) ; 48.86,53.48 v4(49.15,53.48)
PWR_CHG_SRP: length 5
  TOP w0.254: PR5283.1 48.26,52.7 v2(48.14,52.58)
  BOTTOM w0.254: v4(48.14,54.27) 48.48,54.27 ; 48.48,54.27 48.48,55.28 48.42,55.35 U55.13 ; 48.48,54.27 48.48,52.92 v2(48.14,52.58)
PWR_CHG_VCC: length 8.9
  BOTTOM w0.305: U55.20 45.77,58.78 45.25,59.31 v4(45.25,59.39)
  BOTTOM w0.381: PR5284.2 43.05,64.23 42.35,63.53 42.35,60.81 PC4408.1 45.04,59.59 v4(45.25,59.39)
PWR_DDR4_BT: length 2.8
  TOP w0.203: PU5001.18 151.7,136.42 151.43,136.68 v3(151.43,136.84) 151.43,138.06 PR5019.2
PWR_DDR4_BT1: length 4.8
  TOP w0.635: v2(154.36,141.86) 154.36,140.94 PC5008.1 153.45,140.03 PR5019.1
  BOTTOM w0.254: v4(153.93,141.43) 153.95,141.44 153.95,141.45 v2(154.36,141.86)
PWR_DDR4_CS: length 4.7
  TOP w0.203: PU5001.13 153.78,133.88 154.34,134.44 v2(154.34,134.49)
  BOTTOM w0.254: PR5015.2 152.95,134.32 v4(152.95,135.45) 153.28,135.45 154.24,134.49 v2(154.34,134.49)
PWR_DDR4_FB: length 7.4
  TOP w0.203: PU5001.6 150.48,132.33 150.45,132.36 149.47,132.36 149.11,132 149.04,132
  TOP w0.254: PR5016.2 146.83,130.67 v3(147.38,131.22) 148.17,132 149.04,132 ; PR5016.2 146.41,129.5 PR5001.1 ; PR5016.2 PC5002.2
PWR_DDR4_LDOIN: length 1
  TOP w0.203: PU5001.19 151.3,136.04 151.02,136.31 150.96,136.31
  vias: v3(149.65,136.86)
PWR_DDR4_LG: length 18.6
  TOP w0.203: PU5001.15 153.64,134.68 154.08,135.13 v6(154.08,135.51)
  TOP w0.762: 158.02,149.83 158.02,148.59 v6(157.77,148.34)
  L3 w1.016: v6(154.08,135.51) 154.77,136.19 154.77,140.16 157.77,143.15 v6(157.77,148.34)
  BOTTOM w0.508: v6(157.77,148.34) v4(157.77,149.61)
PWR_DDR4_LX: length 29.6
  TOP w0.203: PU5001.16 153.45,136.39 v6(153.45,136.65)
  TOP w0.508: PC5008.2 153.47,136.68 v6(153.45,136.65)
  L4 w1.016: v6(153.45,136.65) 153.45,138.05 152.96,138.54 152.96,152.38 150.17,155.17 v6(150.17,157.3)
  BOTTOM w1.016: v6(150.17,157.3) 150.53,157.66 v4(152.1,157.66) 152.18,157.58 PR5017.1
  vias: v3(151.98,157.66)
PWR_DDR4_SN: length 3.5
  BOTTOM w0.635: PR5017.2 152.1,152.78 v4(152.1,150.93) PC5009.1
PWR_DDR4_TON: length 3.2
  TOP w0.203: PR5009.2 152.13,129.95 v3(152.63,130.44) 152.63,130.89 152.1,131.42 PU5001.9
PWR_DDR4_UG: length 27.1
  TOP w0.203: PU5001.17 152.1,136.74 v6(152.3,136.94)
  L4 w1.016: v6(146.39,155.35) 147.45,155.35 151.31,151.49 151.31,137.69 152.06,136.94 v6(152.3,136.94)
  BOTTOM w1.016: PR5018.2 147.73,153.67 v4(146.13,153.67) 146.13,155.09 v6(146.39,155.35)
PWR_DDR4_UG1: length 6.9
  TOP w0.635: v6(146.72,157.43) 146.74,157.4 PR5002.1 147.63,157.39 PQ5001.4
  BOTTOM w1.016: v6(146.72,157.43) 147.3,158.01 v4(148.29,158.01) 148.29,156.16 PR5018.1
PWR_DDR4_VDD: length 11.3
  TOP w0.203: PU5001.11 154.52,133.08
  TOP w0.381: 154.52,133.08 v2(154.96,133.08) 155.05,133.08 155.76,133.79 PC5004.1 155.86,133.99 157.28,135.42 157.28,137.85 PR5011.1
  BOTTOM w0.381: v2(154.96,133.08) 155.39,133.52 v4(155.39,133.94) 154.72,133.94 153.92,133.13 PR5015.1
PWR_DDR4_VDDQ: length 4.5
  TOP w0.203: PU5001.5 149.73,133.08 149.39,132.74 149.35,132.74 149.19,132.59
  TOP w0.254: 149.19,132.59 148.5,132.59 147.71,133.37 v3(147.71,133.38) 147.71,133.38 147.43,133.65 146.58,133.65 PR5014.1
PWR_DDR4_VIN: length 17.1
  TOP w0.508: v2(150.02,131.62) 150.02,130.75 PR5009.1
  L4 w0.381: v6(148.62,146.18) 148.62,135.64 150.02,134.24 v2(150.02,131.62)
  vias: v3(145.17,152.98) v4(147.61,148.16) v6(148.62,147.19) v6(149.77,147.19) v6(149.77,146.18)
PWR_DDR4_VTT: length 3.5
  TOP w0.203: PU5001.2 149.65,134.28 148.93,135 148.52,135 ; PU5001.20 150.34,135.99 149.54,135.99
  vias: v3(148.68,135.89)
PWR_DDR4_VTTREF: length 3.5
  TOP w0.203: PU5001.4 149.26,133.48 v2(149,133.22)
  BOTTOM w0.254: v2(149,133.22) 149.35,133.57 PC5007.1 150.4,133.16 v4(150.4,132.62)
PWR_LED_YELLOW_C: length 167.2
  TOP w0.254: 133.21,9.32 133.21,8.38 133.85,7.73 R661.1 ; 133.21,9.32 133.21,10.28 132.09,11.4 128.12,11.4 127.1,12.42 116.67,12.42 v1(116.21,11.96) ; 133.21,9.32 133.61,9.73 133.69,9.73 R351.2 ; PWRCN1.9 29.32,20.75 28.74,20.17 v2(27.66,20.17)
  L4 w0.254: v2(27.66,20.17) 27.59,20.1 26.44,20.1 25.61,19.28 25.61,15.8 24.21,14.4 24.21,14.12 24.06,13.97 24.06,10.76 24.66,10.17 24.66,7.64 25.93,6.37 26.71,6.37 28.81,4.27 43.84,4.27 47.73,8.16 47.73,16.58 47.43,16.89 47.43,18.61 48.27,19.46 57.61,19.46 62.09,23.93 67.52,23.93 68.72,22.73 85.53,22.73 88.51,19.75 88.51,8.92 91.72,5.71 110.32,5.71 116.21,11.61 v1(116.21,11.96)
  BOTTOM w0.254: Q65.D 27.81,20.02 v2(27.66,20.17) ; v1(116.21,11.96) 115.81,11.56 v4(115.81,11.27)
PWR_LED_YELLOW_C2: length 1.2
  TOP w0.254: R352.2 R351.1
PWR_RT8243_EMN: length 5.6
  TOP w0.203: 65.19,59 64.74,59.45 64.31,59.45 64.19,59.56 PU4901.13
  TOP w0.254: v3(66.86,56.13) 66.86,56.79 PR4920.1 PR4918.2 65.89,58.3 65.19,59
PWR_RT8243_ENLDO: length 4.2
  TOP w0.203: 64.73,58.75 64.38,59.09 64.2,59.09 64.13,59.16 PU4901.12
  TOP w0.254: PR4901.2 65.76,56.7 v3(65.18,57.28) 65.18,57.75 64.73,58.21 64.73,58.75
PWR_RT8243_LDO3: length 5.8
  TOP w0.203: v2(65.18,60.63) 65.18,60.55 64.99,60.36 PU4901.15
  TOP w0.254: PC4918.1 65.13,62.43 65.13,61.61 PG4904.1 65.14,61.56 65.14,61.1 65.18,61.05 v2(65.18,60.63)
  BOTTOM w0.254: v4(65.25,61.24) 65.25,61.24 65.18,61.17 v2(65.18,60.63)
PWR_RT8243_LDO5: length 4
  TOP w0.203: PU4901.14 64.25,59.96 64.31,59.91 65.22,59.91 65.26,59.87
  TOP w0.254: PC4917.1 67.32,59.87 PG4901.1 65.46,59.87 v3(65.36,59.77) 65.26,59.87
PWR_RT8243_PGOOD: length 4.2
  TOP w0.203: 60.76,57.89 60.88,58.01 PU4901.6
  TOP w0.254: 60.76,57.89 59.49,56.62 v3(59.45,56.62) 59.41,56.62 PR4923.2
PWR_RT8243_TON: length 3.4
  TOP w0.203: PU4901.3 59.42,59.56 v2(59.36,59.51)
  BOTTOM w0.254: PR4919.1 60.06,58.89 59.45,59.51 v2(59.36,59.51) 59.31,59.51 59.3,59.51 58.6,59.51 58.56,59.48 v4(58.55,59.48)
PWR_V1P5A:
  vias: v4(163.7,77.48)
PWR_V1P5A_FB: length 5.7
  BOTTOM w0.254: PU5202.2 165.81,80.04 PR5113.2 PC5114.2 166.17,78.79 v4(166.57,78.39) 166.27,78.39 165.86,77.98 165.6,77.98 PR5112.1
PWR_V1P5S_EN: length 4.1
  BOTTOM w0.102: PR5110.1 PC5221.1 168.9,87.57 v4(168.77,87.43) 168.2,86.86 PU5202.8
PWR_V1P5S_PG: length 5.5
  BOTTOM w0.102: PR40.2 167.74,90.68 166.56,90.68 v4(166.53,90.65) 166.53,89.9 PC27.1 165.69,89.07 165.67,89.04 165.67,88.29 165.81,88.14 PU5202.7
PWR_V1P8A:
  vias: v3(34.42,179.19)
PWR_V1P8A_EN: length 5.7
  TOP w0.102: PC5228.1 PR5257.2 23.07,174.21 PR5245.1 24.06,175.27 24.25,175.46 v3(24.25,175.48) 24.28,175.48 24.37,175.57 PU5203.8
PWR_V1P8A_FB: length 6.2
  TOP w0.254: PR5242.1 35.49,176.1 v3(35.97,176.57) 35.34,177.2 PC5226.2 34.71,177.21 PR1689.2 33.14,177.21 32.77,176.84 PU5203.2
PWR_V1P8A_PG: length 5.8
  TOP w0.102: PC5229.1 23.57,176.94 v3(24.31,176.94) 24.4,176.84 PU5203.7 ; PC5229.1 R1689.2 ; PC5229.1 PR5246.2
PWR_V1P24A:
  vias: v3(48.85,174.37)
PWR_V1P24A_EN: length 4
  TOP w0.102: PR5216.1 40.51,167.18 41.45,168.12 v3(41.45,168.4) PU5201.8
PWR_V1P24A_FB: length 5.9
  TOP w0.254: PU5201.2 48.2,171.55 PC5219.2 PR5211.2 50.09,171.82 v3(50.64,171.27) 50.05,170.69 PR5212.1
PWR_V1P24A_PG: length 106.2
  TOP w0.102: PR5245.2 26.74,173.32 v2(29.85,170.21) 29.88,170.18 37.16,170.18 PR5213.2 38.08,169.25 PC5217.1 39.23,170.74 40.04,171.55 PU5201.7 ; v1(13.16,220.45) 13.19,220.42 PU4.3
  L3 w0.127: v1(13.16,220.45) 12.99,220.45 9.9,217.36 9.9,206.44 13,203.34 13,203.06 15.02,201.04 15.02,195.07 20.98,189.12 20.98,187.67 21.92,186.72 21.92,185.3 24.16,183.06 24.16,176 29.85,170.31 v2(29.85,170.21)
  L4 w0.127: v2(29.85,170.21) 29.85,170.46 37.82,178.43 39.08,178.43 v2(39.5,178)
  BOTTOM w0.102: R1837.1 v4(33.88,183.32) 33.88,181.11 36.56,178.44 39.07,178.44 v2(39.5,178)
PWR_V1P24A_PG_L: length 3.1
  BOTTOM w0.254: Q1231.3 v4(36.01,184.88) 34.86,184.88 R1837.2
PWR_VCC0_BT: length 4.8
  BOTTOM w0.203: PR4424.2 74.58,213.17 75.02,213.61 v4(75.04,213.61) 75.75,213.61 76.71,214.57 PU4401.8
PWR_VCC0_BTR: length 4.6
  BOTTOM w0.635: PC4421.1 72.04,215.39 71.28,214.63 v4(71.28,213.79) 71.28,212.52 PR4424.1
PWR_VCC0_COMP: length 6.2
  BOTTOM w0.203: PC4412.1 83.29,218.2 83.29,217.67 82.94,217.32 82.61,217.32 81.86,216.57 PU4401.23
  BOTTOM w0.254: PC4413.1 83.6,219.84 v4(82.84,219.08) 83.16,218.76 PC4412.1
PWR_VCC0_COMP1: length 3.3
  BOTTOM w0.254: v4(87.78,215.1) 87.33,215.55 87.33,216.17 PR4404.1 86.84,216.92 PC4411.2
PWR_VCC0_COMP2: length 2.3
  BOTTOM w0.203: PR4407.1 84.87,219.77 PC4413.2
  BOTTOM w0.254: v4(84.72,220.96) 84.81,220.88 PC4413.2
PWR_VCC0_CSCOMP: length 58.6
  TOP w0.254: PC4419.1 78.33,223.29 PR4419.2 79.39,223.09 v2(80.26,222.22)
  L4 w0.254: v2(80.26,222.22) 79.48,222.99 74.69,222.99 71.07,219.38 54.06,219.38 51.09,216.41 51.09,202.95 51.67,202.36 52.79,202.36 v2(53.04,202.62)
  BOTTOM w0.203: PU4401.19 79.94,220.8 80.11,220.97 PC4420.2
  BOTTOM w0.254: PR4418.2 PC4420.2 80.11,222.07 v2(80.26,222.22) ; v2(53.04,202.62) 53.14,202.72 v4(54.16,202.72) 54.17,202.7 PN4402.1
PWR_VCC0_CSMP1: length 56.4
  TOP w0.254: v2(80.36,223.26) 79.44,224.18 PR4419.1 76.38,224.18 PR4420.2
  L4 w0.254: v2(53.04,201.4) 52.76,201.68 51.64,201.68 50.58,202.74 50.58,205.97 50.58,205.97 50.58,215.09 50.58,215.09 50.58,216.62 52.56,218.6 53.85,219.89 70.86,219.89 74.48,223.5 80.12,223.5 v2(80.36,223.26)
  BOTTOM w0.254: v2(53.04,201.4) 53.07,201.42 v4(54.19,201.42) 54.83,201.42 PN4402.2
PWR_VCC0_CSN: length 55.6
  TOP w0.254: PR4416.2 73.2,221.64 70.09,221.64 v2(69.46,222.27)
  L4 w0.254: v2(69.46,222.27) 68.38,221.18 53.41,221.18 49.11,216.87 49.11,202.08 51.13,200.05 54.34,200.05 56.01,201.73 57.69,201.73 v2(57.77,201.65)
  BOTTOM w0.254: PG4402.2 59.49,202.13 58.25,202.13 v2(57.77,201.65) ; v4(69.46,223.22) v2(69.46,222.27)
PWR_VCC0_CSP: length 53.9
  TOP w0.254: v2(70.41,222.3) 71.35,223.24 73.61,223.24 PR4417.2
  L4 w0.254: v2(70.41,222.3) 68.73,220.62 53.58,220.62 51.65,218.7 51.6,218.65 51.6,218.65 49.61,216.66 49.61,202.29 51.32,200.58 54.01,200.58 55.76,202.34 57.56,202.34 v2(57.74,202.51)
  BOTTOM w0.254: v2(70.41,222.3) 70.44,222.27 70.44,221.48 v4(70.46,221.46) ; v2(57.74,202.51) 57.87,202.64 59.27,202.64 PG4401.2
PWR_VCC0_CSREF: length 10.1
  TOP w0.254: PR4416.1 77.36,222.09 78.95,220.5 v2(78.95,219.89) 79.74,219.1 PC4418.1
  BOTTOM w0.203: v2(78.95,219.89) 79.13,219.71 PU4401.17
  BOTTOM w0.254: v4(78.5,220.61) 78.5,220.34 v2(78.95,219.89)
PWR_VCC0_CSSUM: length 11.2
  TOP w0.254: v2(79.05,222.32) 78.25,222.32 77.43,223.13 PC4419.2 77.43,223.28 PR4420.1 75.18,223.28 PR4417.1
  BOTTOM w0.203: PC4420.1 79.54,221.04 PU4401.18
  BOTTOM w0.254: v2(79.05,222.32) 78.94,222.42 v4(78.05,222.42) 78.05,221.92 78.61,221.36 PC4420.1
PWR_VCC0_DIFFOUT: length 6.4
  BOTTOM w0.203: PU4401.25 83.04,215.77 83.55,216.28 84.3,216.28 PR4405.2 PR4404.2
  BOTTOM w0.254: PR4404.2 85.82,216.28 v4(86.58,215.52)
PWR_VCC0_FB: length 7
  BOTTOM w0.203: PU4401.24 82.25,216.17 82.67,216.6 v4(82.69,216.6) 82.88,216.79 PR4405.1 83.92,217.81 PC4412.2 PR4407.2 85.89,217.87 PC4411.1
  BOTTOM w0.254: PR4406.1 PC4411.1
PWR_VCC0_HG: length 31
  L4 w1.016: v2(52.48,207.04) 53.02,207.57 67.67,207.57 v6(74.02,213.92)
  BOTTOM w0.203: v6(74.02,213.92) 74.38,214.27 75.93,214.27 76.63,214.97 PU4401.9
  BOTTOM w0.254: v6(74.02,213.92) 74,213.94 v4(72.75,213.94)
  BOTTOM w1.016: PR4423.2 v2(52.48,207.04)
PWR_VCC0_HGR: length 7
  BOTTOM w0.635: PR4423.1 52.48,204.75 53.25,203.99 v4(53.4,203.99) 54.1,204.69 PR4422.1 54.06,205.12 54.06,206.2 55.11,207.25 PQ4401.4
PWR_VCC0_ILIM: length 4.3
  BOTTOM w0.203: 81.35,219.11 80.73,218.5 PU4401.21
  BOTTOM w0.254: PR4418.1 82.14,220.25 82.15,220.24 v4(82.15,220.15) 82.15,219.92 81.35,219.11
PWR_VCC0_IMAX: length 3.6
  TOP w0.254: v2(78.04,219.81) 78.72,219.13 PR4432.1
  BOTTOM w0.203: PU4401.16 78.73,218.86 v4(78.44,219.15) 78.04,219.56 v2(78.04,219.81)
PWR_VCC0_IOUT: length 4.6
  TOP w0.254: PR4415.1 PC4417.1 80.63,219.79 v2(80.81,219.96)
  BOTTOM w0.203: v2(80.81,219.96) 80.81,219.49 80.49,219.18 v4(80.49,219.16) 80.34,219 PU4401.20
PWR_VCC0_LG: length 14
  BOTTOM w0.203: PU4401.12 76.93,216.17 76.23,216.87 75.64,216.87 75.49,217.02
  BOTTOM w0.762: 67.22,215.22 67.22,215.01 66.06,213.85 PQ4402.4
  BOTTOM w1.016: 75.49,217.02 v4(70.81,217.02) 69.01,217.02 67.22,215.22
PWR_VCC0_PVCC: length 7
  BOTTOM w0.203: PU4401.15 78.34,218.41 77.61,219.13
  BOTTOM w0.508: 77.61,219.13 76.61,220.13 PC4426.1 PR4428.2 72.96,220.22 v4(72.95,220.21)
PWR_VCC0_ROSC: length 4.2
  TOP w0.254: PR4433.1 83.42,217.07 v3(83.82,217.46) 83.4,217.88 v2(82.72,217.88)
  BOTTOM w0.203: PU4401.22 81.57,216.97 82.48,217.88 v2(82.72,217.88)
PWR_VCC0_SN: length 3.8
  BOTTOM w0.635: PC4429.1 68.77,212.06 v4(69.14,211.69) 69.14,210.98 68.52,210.36 PR4421.2
PWR_VCC0_SW: length 29.3
  L4 w1.016: v6(75.78,215.65) 75.8,215.62 75.8,213.18 68.36,205.74 v2(56.14,205.74)
  BOTTOM w0.203: PU4401.10 76.05,215.37 v6(75.78,215.65)
  BOTTOM w0.381: PC4421.2 74.73,214.96 v4(75.32,214.96) 75.32,215.19 v6(75.78,215.65)
  vias: v4(65.21,205.21)
PWR_VCC0_TSEN: length 5.8
  TOP w0.254: v2(74.76,218.57) 74.58,218.39 PR4413.2 75.6,217.64 PC4416.2
  BOTTOM w0.203: v2(74.76,218.57) 75.34,218.57 76.07,217.84 v4(76.07,217.84) 76.07,217.84 77.34,216.57 PU4401.13
PWR_VCC0_TSEN1: length 33.6
  TOP w0.254: PR4414.1 74.65,216.69 PR4413.1 74.34,216.75 73.82,217.27 v2(73.82,218.67)
  L4 w0.254: v2(73.82,218.67) 73.64,218.85 54.87,218.85 52.28,216.26 52.28,211.12 v2(52.04,210.88)
  BOTTOM w0.254: v4(73.03,218.1) 73.59,218.67 v2(73.82,218.67) ; PN4401.1 v2(52.04,210.88)
PWR_VCC0_VBOOT/ADDR: length 4.8
  TOP w0.381: PR4431.1 76.65,218.99 v2(76.64,218.97)
  BOTTOM w0.203: v2(76.64,218.97) 76.51,219.1 v4(75.79,219.1) 77.66,217.23 PU4401.14
PWR_VCC0_VCC: length 6.4
  BOTTOM w0.203: PU4401.28 81.5,214.57 83.59,212.48 PC4428.1
  BOTTOM w0.508: PR4430.2 85.4,213.06 v4(84.88,213.58) 84.28,212.99 PC4428.1
PWR_VCC0_VIN:
  vias: v3(57.74,218.36) v4(59.22,216.96) v6(55.05,216.48) v6(55.07,215.26) v6(55.56,217.37) v6(56.12,216.51) v6(56.14,215.29) v6(56.8,217.37) v6(57.23,215.26) v6(57.31,216.41)
PWR_VCC0_VRMP: length 5.2
  TOP w0.381: v2(77.3,213.18) 77.44,213.32 PC4427.1 76.55,214.02 PR4429.2
  BOTTOM w0.203: PU4401.7 76.99,213.9 v4(76.37,213.28) 76.47,213.18 v2(77.3,213.18)
PWR_VCC0_VSN: length 5
  TOP w0.254: PC4415.1 82.72,215.25 v2(82.81,215.16)
  BOTTOM w0.203: PU4401.26 82.6,215.37 v2(82.81,215.16) 83.37,215.16 83.89,214.64 v4(84.13,214.64)
  BOTTOM w0.254: PR4411.1 84.13,215.43 v4(84.13,214.64)
PWR_VCC0_VSP: length 5.1
  TOP w0.254: PC4414.1 84.76,213.56 PR4410.2 83.57,213.56 83.56,213.57 v2(83.29,213.57)
  BOTTOM w0.203: 82.5,214.63 82.16,214.97 PU4401.27
  BOTTOM w0.254: v2(83.29,213.57) 83.29,213.84 82.93,214.2 v4(82.93,214.21) 82.92,214.21 82.5,214.63
PWR_VCORE_VCC0: length 272.4
  TOP w0.254: G5.1 107.04,49.61 105.87,48.44 v2(105.87,44.25) ; v6(75.32,192.69) 81.25,198.62 81.25,203.71 83.05,205.51 83.7,205.51 85.53,207.34 v3(85.53,208.66) 85.53,210 85.06,210.47 R1822.1
  TOP w0.635: 69.26,197.05 TC13.1 ; TC13.1 70.31,196 ; TC13.1 70.31,198.11 ; TC13.1 71.37,197.05 ; 57.46,187.95 TC15.1 ; TC15.1 58.52,189 ; TC15.1 57.46,190.06 ; TC15.1 56.41,189
  L3 w0.305: v2(105.87,44.25) 104.88,45.24 97.67,45.24 93.07,40.64 89.95,40.64 82.49,48.1 62.55,48.1 54.31,56.34 51.14,56.34 50.73,56.74 50.73,60.04 44.67,66.1 43.44,66.1 40.65,68.9 40.65,72.68 37.5,75.83 37.5,79.44 39.35,81.29 39.35,102.45 36.99,104.81 36.99,114.59 36.76,114.82 36.76,118.97 35.01,120.72 35.01,129.82 33.66,131.17 v2(33.66,132.46)
  L3 w0.635: TC15.1 58.52,189 ; TC15.1 57.46,187.95 ; TC15.1 56.41,189 ; TC15.1 57.46,190.06 ; 69.26,197.05 TC13.1 ; TC13.1 70.31,198.11 ; TC13.1 70.31,196 ; TC13.1 71.37,197.05
  L4 w0.254: v2(33.66,132.46) 36.18,132.46 39.59,135.87 39.59,136.56 39.64,136.61 39.64,137.27 43.88,141.52 44.85,141.52 45.88,142.54 45.88,169.38 58.53,182.03 58.53,185.75 v2(60.38,187.6)
  BOTTOM w0.635: TC15.1 58.52,189 ; TC15.1 57.46,190.06 ; TC15.1 56.41,189 ; TC15.1 57.46,187.95 ; TC13.1 70.31,198.11 ; TC13.1 70.31,196 ; TC13.1 71.37,197.05 ; TC13.1 69.26,197.05
  vias: v1(83,166.14) v1(83.78,165.38) v1(83.78,164.62) v1(84.56,169.93) v1(84.57,169.17) v1(84.57,168.41) v1(84.57,167.65) v1(85.35,167.65) v1(85.35,165.38) v1(85.35,164.62) v3(69.91,188.06) v4(61.68,187.83) v4(64.98,200.2) v4(70.24,188.14) v4(84.21,166.17) v6(60.21,196.34) v6(60.28,197.36) v6(61.15,196.34) v6(61.4,197.38) v6(62.47,197.41) v6(63.43,197.43) v6(69.94,189.43) v6(70.01,192.51) v6(70.01,191.48) v6(69.97,190.45) v6(71.05,192.52) v6(71.06,191.43) v6(71.07,190.38) v6(71.09,189.36)
PWR_VCORE_VGG: length 66.2
  TOP w0.305: R1826.1 20.01,171.25 19.68,171.25 19.11,170.67 v2(19.11,169.43)
  TOP w0.635: 47.52,151.03 TC17.1 ; TC17.1 48.57,149.97 ; TC17.1 48.57,152.08 ; TC17.1 49.63,151.03 ; 48.62,142.07 TC16.1 ; TC16.1 48.62,144.18 ; TC16.1 47.57,143.13 ; TC16.1 49.68,143.13 ; 46.48,158.8 TC18.1 ; TC18.1 48.59,158.8 ; TC18.1 47.53,157.75 ; TC18.1 47.53,159.86 ; TC19.1 40.69,159.05 ; TC19.1 39.63,160.11 ; TC19.1 39.63,158
  L3 w0.635: 46.48,158.8 TC18.1 ; TC18.1 48.59,158.8 ; TC18.1 47.53,159.86 ; TC18.1 47.53,157.75 ; TC17.1 48.57,152.08 ; TC17.1 49.63,151.03 ; TC17.1 48.57,149.97 ; TC17.1 47.52,151.03 ; 39.63,158 TC19.1 ; TC19.1 38.58,159.05 ; TC19.1 40.69,159.05 ; TC19.1 39.63,160.11 ; 47.57,143.13 TC16.1 ; TC16.1 48.62,144.18 ; TC16.1 49.68,143.13
  BOTTOM w0.381: v2(19.11,169.43) 19.75,168.78 v4(20.91,168.78) 31.57,168.78 32.59,167.76 41.53,167.76 44.72,164.57 v4(45.85,164.57) v2(47.48,162.94)
  BOTTOM w0.508: v1(89.85,153.54) 89.51,153.88 R80240.2
  vias: v1(82.99,161.59) v1(82.99,160.84) v1(83.78,162.35) v1(83.78,161.59) v1(83.79,160.84) v1(83.78,160.07) v1(84.57,163.1) v1(84.57,162.34) v1(84.56,161.59) v1(84.56,160.84) v1(84.56,160.06) v1(85.35,162.35) v1(85.35,161.57) v1(85.37,160.83) v3(39.86,140.69) v3(59.85,144.15) v4(86.11,161.87) v6(41.94,145.24) v6(41.94,144.09) v6(41.94,143.05) v6(43.01,147.24) v6(42.98,146.23) v6(42.96,145.21) v6(42.96,144.07) v6(42.96,143.03) v6(44.03,145.24) v6(44.03,144.09) v6(44.03,143.05) v6(44.08,147.27) v6(44.05,146.25) v6(45.14,146.25) v6(45.12,145.24) v6(45.12,144.09) v6(45.12,143.05) v6(45.17,147.27) v6(52.51,150.52) v6(52.51,149.5) v6(52.51,148.49) v6(61.09,151.87) v6(61.09,150.83) v6(61.09,149.81) v6(61.09,148.72) v6(61.12,147.7) v6(61.12,146.69)
PWR_VCORE_VNN: length 1
  BOTTOM w0.254: R1784.1 43.11,185.09 v2(43.16,185.14)
  vias: v1(81.43,163.1) v1(81.43,162.35) v1(81.43,160.83) v1(82.21,162.35) v3(45.09,185.42) v3(52.41,179.96) v3(66.84,180.21) v6(64.56,179.1) v6(65.59,179.08) v6(66.62,179.05)
PWR_VCORE_VNN_D: length 3
  BOTTOM w0.254: R1784.2 44.61,184.78 v4(45.04,184.78) 45.3,184.78 45.76,184.33 45.76,184.31 46.02,184.05 Q1228.6
PWR_VGA_CORE_BOOT1: length 5.6
  TOP w0.203: U6706.19 134.28,84.11 134.48,84.31
  TOP w0.508: PR43.1 134.6,87.45 135.44,86.61 135.44,85.56 v3(135.45,85.55) 135.45,85.26 135.06,84.88 135.05,84.88 134.48,84.31
PWR_VGA_CORE_COMP: length 9.4
  TOP w0.203: U6706.7 131.38,79.25 v1(131.53,79.1)
  TOP w0.254: PC7.2 130.94,77.71 PC6.1 130.82,76.82 PR13.2 ; PC7.2 130.92,77.81 130.92,78.24 131.53,78.85 v1(131.53,79.1) ; PC7.2 PC8.1
  BOTTOM w0.254: v1(131.53,79.1) 131.53,79.28 132.04,79.79 PC4.2 131.35,80.63 v4(131.25,80.63) 130.4,80.63 PR1.2
PWR_VGA_CORE_DPRSLPVR: length 4.7
  TOP w0.203: U6706.39 127.74,81.31 126.81,80.38 v3(126.81,80.12) 126.78,80.09 126.78,80.03 126.56,79.81 125.36,79.81 PR17.2
PWR_VGA_CORE_FB: length 9.7
  TOP w0.203: PC8.2 132.01,78.68 132.01,79.3 131.78,79.53 U6706.8
  TOP w0.508: PR21.1 136.91,78.4 PR20.1 136.35,78.38 v3(135.08,77.11) 135.07,77.13 133.47,77.13 133.1,76.76 PR8.2 PC8.2
PWR_VGA_CORE_FB2: length 4.7
  TOP w0.203: v1(132.64,79.1) 132.34,79.39 132.34,79.43 132.18,79.6 U6706.9
  BOTTOM w0.508: v1(132.64,79.1) 132.93,79.39 PC4.1 133.01,80.03 133.66,80.03 v4(134.02,79.66) 134.04,79.65 135.16,79.65 PC5.2
PWR_VGA_CORE_IMON: length 6.6
  TOP w0.203: v1(135.14,83.85) 135,83.71 U6706.18
  BOTTOM w0.254: v1(135.14,83.85) 135.01,83.97 PR9777.1 135.87,85.04 PR9778.2 136.13,85.91 v4(136.24,86.01) 136.68,86.01 PC59.2
PWR_VGA_CORE_ISEN1: length 3.2
  TOP w0.203: U6706.11 134.59,80.91 134.78,80.72 v3(134.78,80.56)
  TOP w0.254: v3(134.78,80.56) 134.78,80.28 135.09,79.97 135.09,79.97 135.29,79.77 PR12.2
PWR_VGA_CORE_ISEN2: length 4.3
  TOP w0.203: U6706.10 133.01,80.16 133.87,79.19 PR11.2
  TOP w0.254: PR11.2 134.08,78.89 v3(134.86,78.89) 134.87,78.88 PR12.1
PWR_VGA_CORE_ISUM+: length 13.6
  TOP w0.203: U6706.15 134.26,82.51 134.38,82.4 134.84,82.4 135.3,82.86 135.51,82.86 135.94,83.28
  TOP w0.254: v3(140.69,89.15) PR42.1 141.77,89.14 PR45.1 141.18,87.99 PC16.1 139.72,86.53 PC15.1 138.36,86.53 PR9781.1 138.32,86.53 PR34.1 136.38,84.59 136.38,83.72 135.94,83.28
PWR_VGA_CORE_ISUM-: length 5.2
  TOP w0.203: v3(136.27,82.68) 136.25,82.68 135.94,82.37 135.3,82.37 135,82.07 134.2,82.07 134.15,82.11 U6706.14
  TOP w0.254: PC14.1 PR16.2 136.35,82.68 136.35,82.68 v3(136.27,82.68)
PWR_VGA_CORE_LGATE1A: length 15.2
  TOP w0.203: U6706.23 131.78,85.92 131.39,86.3 v6(131.39,86.68)
  TOP w0.762: PU3.4 v6(134.25,95.83)
  L4 w0.762: v6(131.39,86.68) 131.35,86.68 131.4,86.73 131.4,87.15 v6(134.25,89.99) v6(134.25,95.83)
  BOTTOM w0.305: v6(131.39,86.68) 131.34,86.73 131.34,86.88 131.08,87.13 v4(130.52,87.13)
  BOTTOM w0.762: v6(134.25,89.99) 134.26,90 PU5207.4
PWR_VGA_CORE_LGATE1B: length 3.1
  TOP w0.203: U6706.24 131.38,85.85 130.81,86.42 130.81,86.92 131.62,87.73 TP203.1
PWR_VGA_CORE_NTC: length 51.5
  TOP w0.203: v1(130.56,79.15) 130.58,79.16 U6706.5
  TOP w0.254: PR60.2 133.78,104.88 v2(133.51,104.88)
  L4 w0.254: v2(133.51,104.88) 134.02,105.38 136.23,105.38 137.23,104.38 139.16,104.38 144.05,99.49 144.05,90.62 143.8,90.37 143.8,89.2 142.81,88.21 140.44,88.21 v1(140.42,88.19)
  BOTTOM w0.254: v1(140.42,88.19) 141.89,86.72 141.89,84.82 142.2,84.52 142.2,82.12 138.95,78.87 136.58,78.87 v4(136.58,78.87) 136.42,78.71 133.51,78.71 133.3,78.5 131.21,78.5 v1(130.56,79.15) 129.6,80.11 PC9.1
PWR_VGA_CORE_ON: length 11.6
  TOP w0.203: PR18.2 125.03,80.14 v3(125.66,80.77) 126.55,80.77 127.49,81.71 U6706.38
  TOP w0.254: PR18.2 124.71,80.4 124.44,80.67 122.89,80.67 PC12.1 121.3,80.43 121.26,80.47 119.99,80.47 119.97,80.44 118.96,80.44 PR19.2
PWR_VGA_CORE_PGOOD: length 4.8
  TOP w0.203: v3(125.76,79.02) 126.07,79.32 127.06,79.32 127.87,80.14 128.96,80.14 U6706.1
  TOP w0.254: PR14.1 125.76,78.04 v3(125.76,79.02)
PWR_VGA_CORE_PHASE1: length 24.4
  TOP w0.203: v6(132.92,86.41) 132.9,86.41 132.63,86.14 132.63,86.06 132.58,86.01 U6706.21
  TOP w0.381: PC19.1 132.93,86.42 v6(132.92,86.41)
  L4 w0.762: v6(132.92,86.41) 133.28,86.77 133.28,86.89 134.1,87.71 134.53,87.71 137.09,90.27 137.09,95.89 135.05,97.93 v6(127.39,97.93)
  vias: v4(122.82,91.11) v4(123.65,96.62) v4(128.91,97.08) v6(123.17,102.29) v6(123.17,101.37) v6(123.17,100.46) v6(123.17,99.54) v6(123.17,98.63) v6(123.17,97.71) v6(124.04,92.51) v6(124.04,91.59) v6(124.04,90.68) v6(124.09,102.29) v6(124.09,101.37) v6(124.09,100.46) v6(124.09,99.54) v6(124.09,98.63) v6(124.09,97.71) v6(125,102.29) v6(125,101.37) v6(125,100.46) v6(125,99.54) v6(125,98.63) v6(125,97.71) v6(124.95,92.51) v6(124.95,91.59) v6(124.95,90.68) v6(125.92,102.29) v6(125.92,101.37) v6(125.92,100.46) v6(125.92,99.54) v6(125.92,98.63) v6(125.92,97.71) v6(125.86,92.51) v6(125.86,91.59) v6(125.86,90.68)
PWR_VGA_CORE_PSI#: length 3.1
  TOP w0.203: v3(128.91,78.64) 128.91,79.15 129.38,79.61 U6706.2
  TOP w0.254: v3(128.91,78.64) 128.86,78.64 128.23,78 PR10.1
PWR_VGA_CORE_RTN: length 78.1
  TOP w0.203: PC13.2 135.73,81.71 U6706.13
  TOP w0.254: PC13.2 136.16,81.67 136.56,82.07 138.13,82.07 138.41,81.79 PC5272.2 138.81,81.45 139.35,81.99 139.35,83.74 v1(139.23,83.87)
  L3 w0.254: v1(89.31,84.68) 89.54,84.45 101.1,84.45 102.32,83.24 121.36,83.24 122.38,84.26 122.38,85.99 123.73,87.33 v1(123.73,88.51)
  L4 w0.254: v1(123.73,88.51) 123.73,87.76 127.19,84.3 131.53,84.3 134.02,81.81 135.67,81.81 137.73,83.87 v1(139.23,83.87)
  BOTTOM w0.254: PR29.2 87.89,91.41 89.26,90.04 89.26,84.73 v1(89.31,84.68) ; v1(139.23,83.87) 139.2,83.85 v4(138.44,83.85) PC59.1 136.38,83.85 PR9778.1
PWR_VGA_CORE_SNB1: length 3.7
  TOP w0.508: PC5267.1 132.34,97.53 v2(132.34,96.57) 131.53,96.57 PR9783.2
  BOTTOM w0.508: v2(132.34,96.57) 131.73,97.18 v4(131.63,97.18)
PWR_VGA_CORE_UGATE1: length 34.4
  TOP w0.203: 134.02,84.79 133.74,84.51 U6706.20
  TOP w0.508: 134.02,84.79 134.68,85.45 v6(134.68,86.31)
  TOP w0.762: PU1.4 v6(127.53,99.62)
  L4 w0.762: v6(134.68,86.31) 135.19,86.31 138.49,89.61 138.49,96.47 135.34,99.62 v6(127.53,99.62) v6(127.53,103.43)
  BOTTOM w0.305: v6(134.68,86.31) 134.66,86.31 v4(134.01,86.96)
  BOTTOM w0.762: PU2.4 v6(127.53,103.43)
PWR_VGA_CORE_VCCP: length 5.8
  TOP w0.203: PC17.1 129.87,87.4 130.2,87.06 v3(130.2,86.99) 130.2,86.53 130.43,86.31 130.98,85.76 U6706.25
  TOP w0.508: PC17.1 PC18.1 126.84,87.4 PR44.1
PWR_VGA_CORE_VDD: length 6.4
  TOP w0.203: v1(134.58,82.88) 134.32,82.88 134.29,82.91 U6706.16
  BOTTOM w0.508: v1(134.58,82.88) 134.55,82.88 134.46,82.91 133.81,82.91 PC58.1 133.48,83.31 PR9777.2 132.4,85.04 PR9771.2 132.36,84.33 132.36,84.32 v4(132.36,84.08)
PWR_VGA_CORE_VID0: length 5.6
  TOP w0.102: U6706.31 127.92,84.51 127.27,85.16 127.27,86.45 126.94,86.78 126.37,86.78 v3(125.66,87.49) 125.42,87.73 PR9774.2
PWR_VGA_CORE_VID1: length 5.2
  TOP w0.102: PR9773.2 125.29,86.63 125.7,86.22 v3(126.71,86.22) 126.9,86.03 126.9,84.98 127.76,84.11 U6706.32
PWR_VGA_CORE_VID2: length 4.3
  TOP w0.102: U6706.33 127.77,83.71 126.13,85.35 v3(125.71,85.35) 125.52,85.55 PR35.2
PWR_VGA_CORE_VID3: length 4.3
  TOP w0.102: PR32.2 126.18,84.51 v3(126.74,83.95) 127.38,83.31 U6706.34
PWR_VGA_CORE_VID4: length 4.2
  TOP w0.102: U6706.35 126.12,82.91 v3(125.38,83.64) 125.18,83.44 PR30.2
PWR_VGA_CORE_VID5: length 4
  TOP w0.102: PR25.2 125.33,82.4 v3(125.42,82.31) 125.62,82.51 U6706.36
PWR_VGA_CORE_VID6: length 3.9
  TOP w0.102: PR23.2 126.23,81.36 126.74,81.87 v3(126.74,81.88) 126.75,81.88 126.98,82.11 U6706.37
PWR_VGA_CORE_VIN: length 8.3
  TOP w0.203: v3(136.49,86.53) 136.13,86.16 136.13,85.08 135.76,84.71 135.76,83.78 135.31,83.34 134.8,83.34 134.78,83.36 133.92,83.36 133.86,83.31 U6706.17
  TOP w0.508: PR101.2 135.72,88.81 PC60.1 135.72,87.53 136.49,86.75 v3(136.49,86.53)
PWR_VGA_CORE_VSEN: length 78.4
  TOP w0.203: U6706.12 134.64,81.31 134.64,81.31 135.14,81.31 135.15,81.31 135.25,81.31 PC13.1
  TOP w0.254: v1(139.94,83.85) 139.94,81.75 139.01,80.82 PC5268.1 138.98,80.39 138.02,80.39 PC11.2 PR21.2 136.2,80.78 PC13.1
  L3 w0.254: v1(88.53,84.66) 89.24,83.95 100.69,83.95 101.91,82.73 121.57,82.73 122.89,84.05 122.89,85.78 124.44,87.33 124.44,88.41 v1(124.54,88.51)
  L4 w0.254: v1(124.54,88.51) 124.49,88.46 124.49,87.73 127.41,84.81 131.76,84.81 134.22,82.35 135.47,82.35 137.6,84.48 139.33,84.48 139.43,84.38 139.45,84.38 139.94,83.9 v1(139.94,83.85)
  BOTTOM w0.254: PR28.2 87.09,91.63 88.63,90.09 v4(88.63,86.97) 88.63,84.76 v1(88.53,84.66)
PWR_VGA_CORE_VSUM-: length 63.4
  TOP w0.254: v1(144.26,86.62) 143.96,86.33 142.23,86.33 141.7,86.86 ; 141.7,86.86 PR9779.1 ; 141.7,86.86 141.7,85.79 PC20.1 PC16.2 139.42,85.7 PC15.2 139.35,85.64 PR9781.2 138.35,85.53 138.92,84.96 138.92,84.35 138.72,84.15 138.72,83.27 138.35,82.91 138.35,82.89 PR16.1 ; PR51.2 117.38,101.41 v1(117.38,102.29)
  L4 w0.254: v1(117.38,102.29) 117.38,102.43 120.24,105.28 125.28,105.28 128.05,108.05 138.62,108.05 139.1,107.57 140.35,107.57 147.15,100.77 147.15,90.27 145.52,88.65 145.52,87.89 v1(144.26,86.62)
  BOTTOM w0.254: v1(144.26,86.62) 143.52,86.62 v4(143.43,86.54)
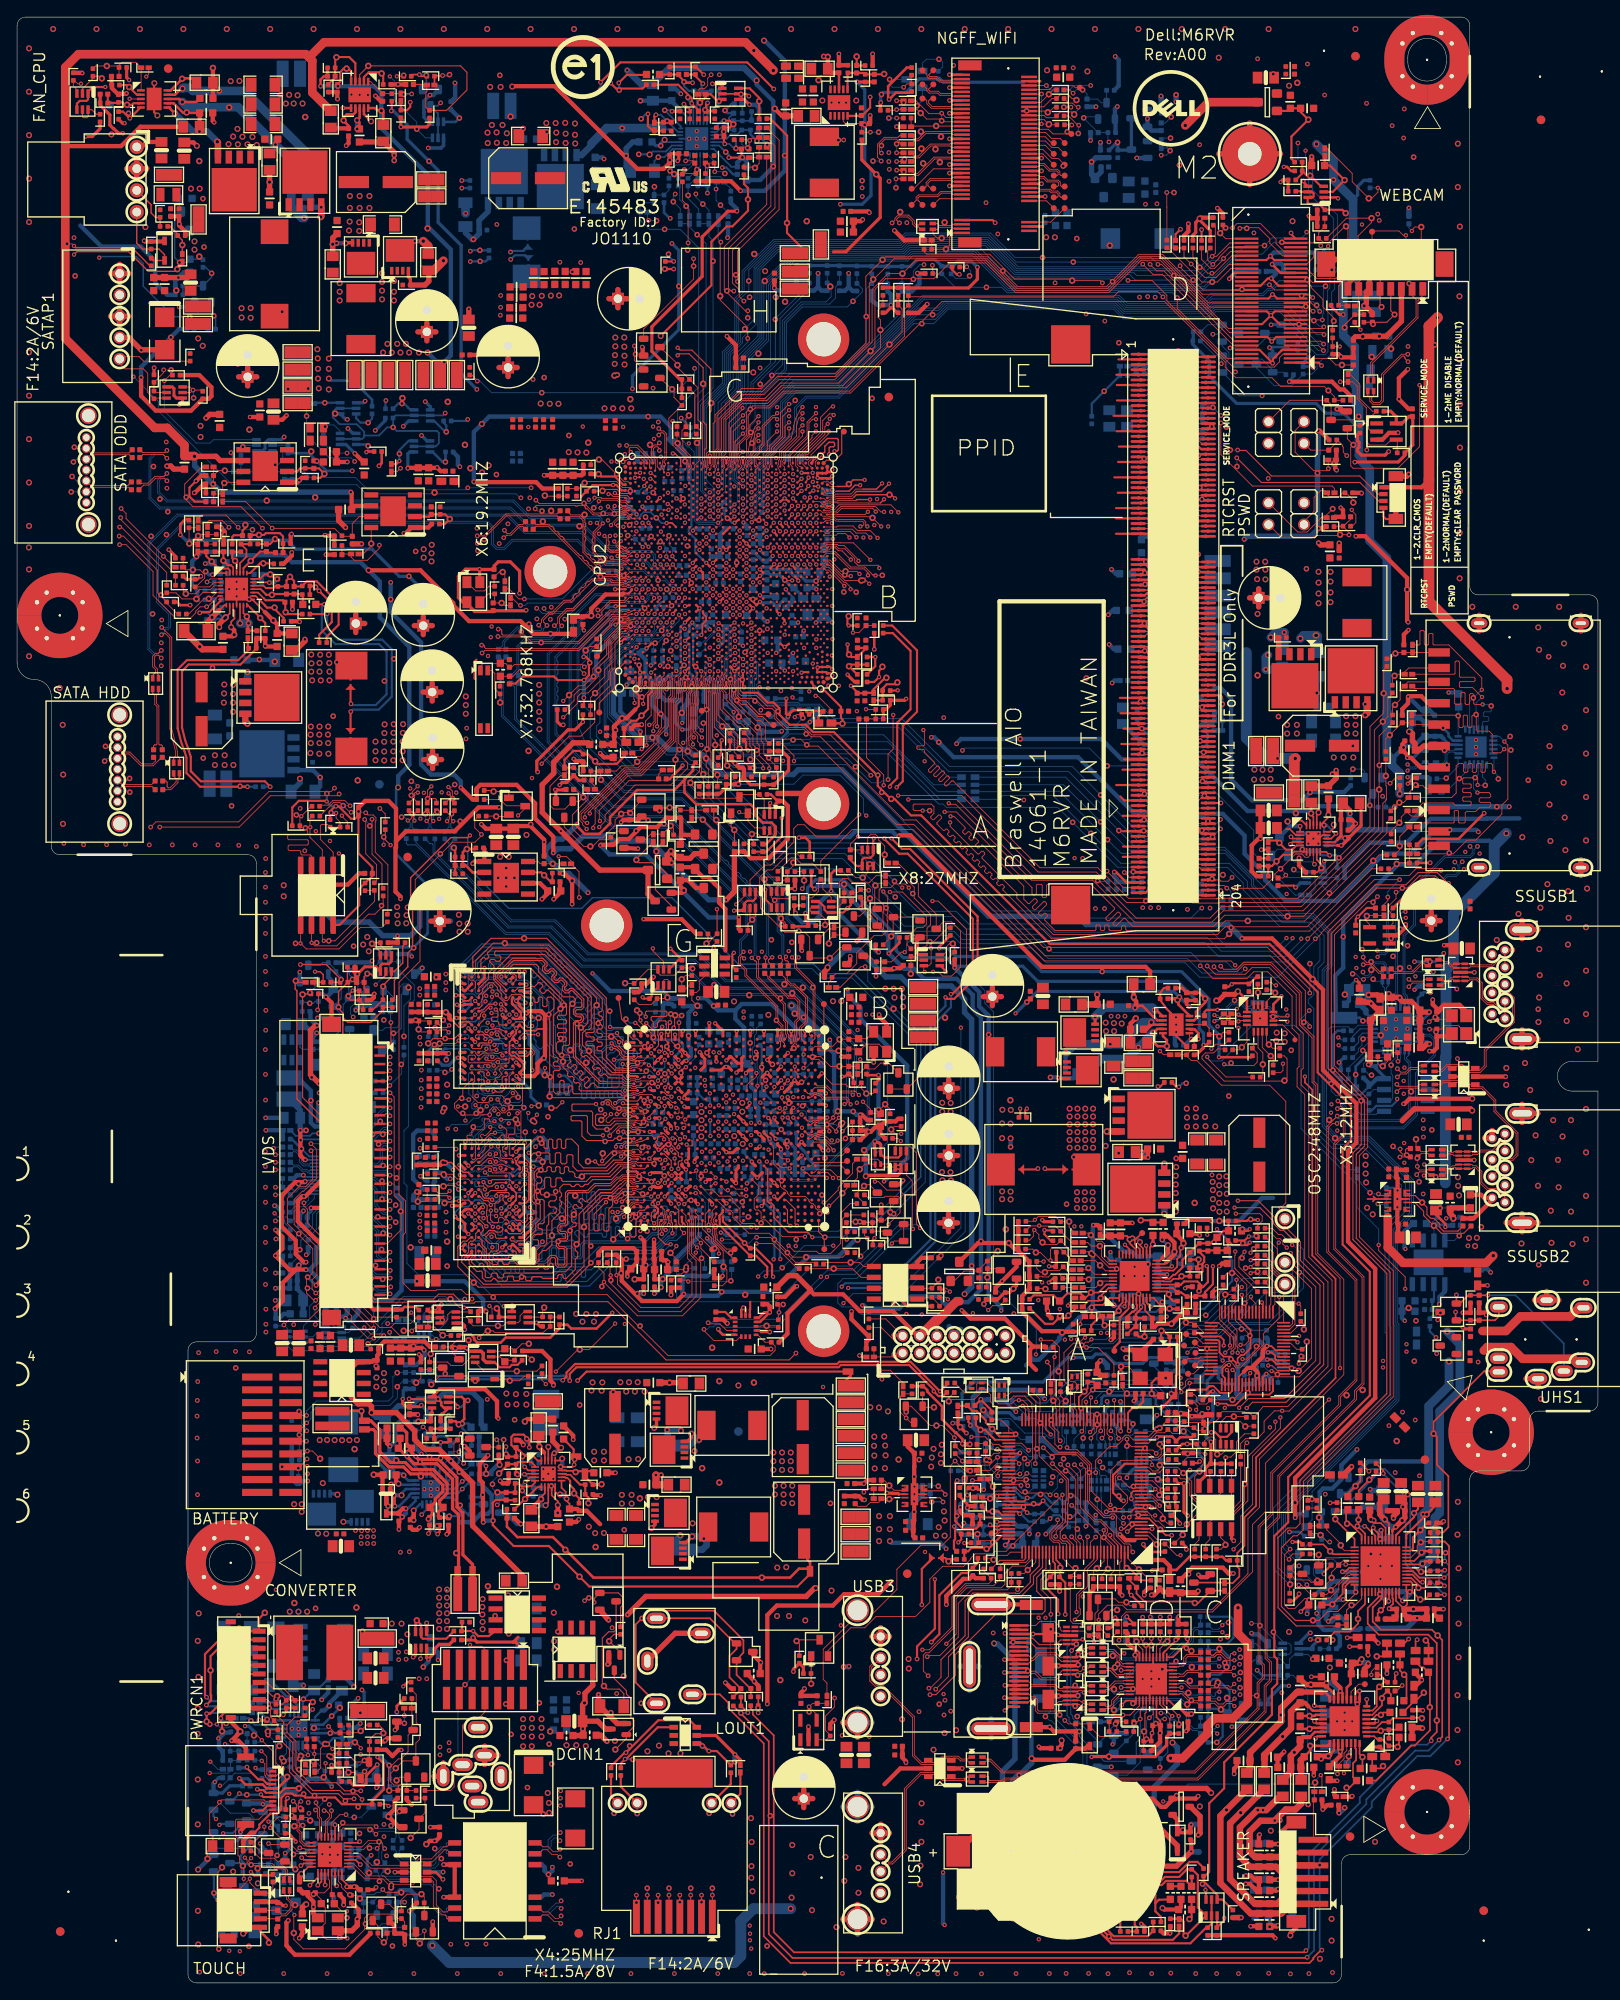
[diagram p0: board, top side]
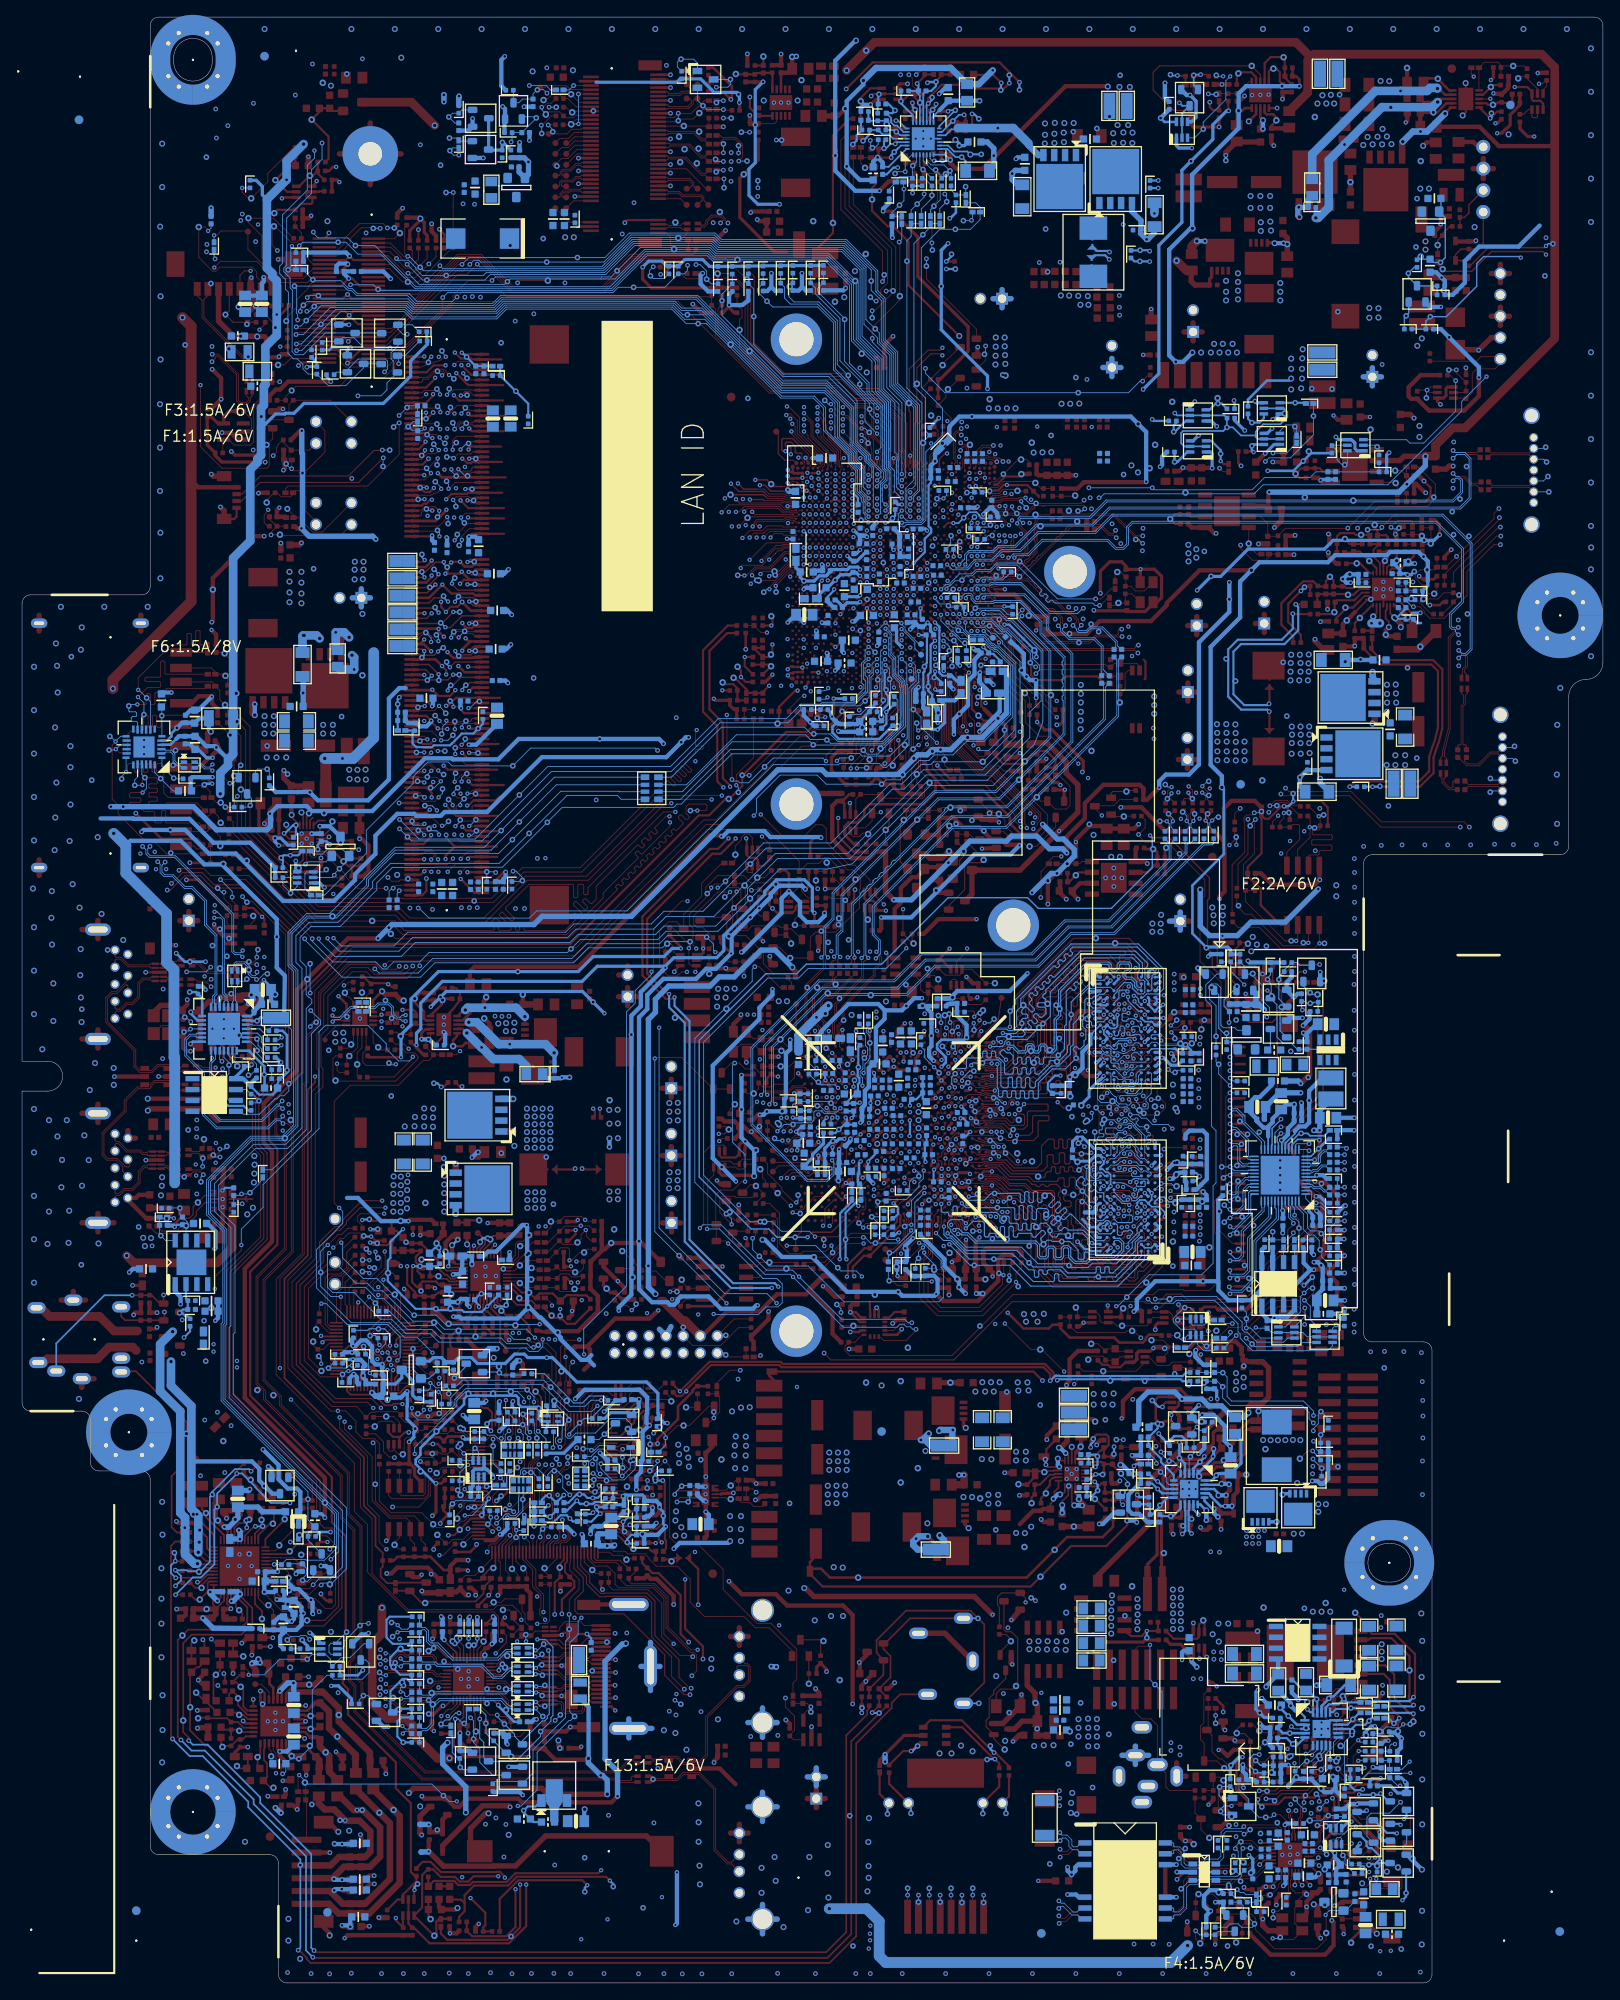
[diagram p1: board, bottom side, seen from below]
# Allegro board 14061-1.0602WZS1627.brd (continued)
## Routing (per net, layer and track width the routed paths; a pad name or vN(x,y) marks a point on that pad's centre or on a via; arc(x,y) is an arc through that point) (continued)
PWR_VGA_CORE_VW: length 4
  TOP w0.203: U6706.6 130.98,79.42 131.05,79.35 131.05,78.91 130.87,78.73
  TOP w0.254: PC7.1 129.99,78.03 130.49,78.54 130.67,78.54 130.87,78.73
  TOP w0.508: PC7.1 129.93,77.71 PR13.1
PWR_VGG_BT: length 4.1
  TOP w0.203: PU4501.8 24.25,161.2 23.6,160.55
  TOP w0.635: 23.6,160.55 v3(22.82,159.77) 22.33,159.28 PR4524.2
PWR_VGG_BTR: length 5.4
  TOP w0.762: PR4524.1 v3(21.37,156.34) 21.67,156.03 PC4521.1
PWR_VGG_COMP: length 5.2
  TOP w0.203: 26.49,165.52 PU4501.23
  TOP w0.254: 26.49,165.52 v3(27.34,166.37) 28.43,167.46 PC4513.2 29.3,167.35 PC4512.1
PWR_VGG_COMP1: length 3.5
  TOP w0.254: v3(26.71,170.58) 26.71,170.24 26.38,169.91 PC4511.2 26.34,169.38 25.37,169.38 25.18,169.19 PR4504.1
PWR_VGG_COMP2: length 2.3
  TOP w0.254: PR4507.1 28.17,168.35 PC4513.1 29.61,168.35 v3(30.19,168.94)
PWR_VGG_CSCOMP: length 18.5
  TOP w0.203: PU4501.19 28.84,163.47 29.12,163.19
  TOP w0.254: 29.12,163.19 30.01,163.19 30.2,163.39 PR4518.2 PC4519.1 31.53,164.1 v3(31.94,164.51) 32.42,164.03 PC4520.2 33.31,163.39 PR4519.2 33.9,163.98 35.07,163.98 37.63,161.43 37.63,158.9 36.24,157.52 PN4502.1
PWR_VGG_CSMP1: length 10.2
  TOP w0.254: PN4502.2 35.35,157.73 36.82,159.21 36.82,161.38 v2(35.34,162.86) 34.75,163.45 PR4519.1 PR4520.2
  BOTTOM w0.254: v4(34.92,163.31) 34.92,163.28 v2(35.34,162.86)
PWR_VGG_CSN: length 26
  TOP w0.254: PG4502.2 39.02,148.72 v2(39.05,148.74) ; v2(36.29,160.2) 36.24,160.15 PR4516.2
  BOTTOM w0.254: 43.85,154.91 43.85,156.03 42.72,157.16 37.58,157.16 36.29,158.45 v2(36.29,160.2) ; 43.85,154.91 43.85,150.5 42.32,148.97 39.28,148.97 v2(39.05,148.74) ; 43.85,154.91 v4(44.1,154.91)
PWR_VGG_CSP: length 24.8
  TOP w0.254: PG4501.2 39.02,149.71 v2(39.07,149.66) ; PR4517.1 v2(35.95,161.29)
  BOTTOM w0.254: v4(42.98,152.32) 43.24,152.32 ; 43.24,152.32 43.24,150.77 41.97,149.5 39.23,149.5 v2(39.07,149.66) ; 43.24,152.32 43.24,155.75 42.35,156.64 37.26,156.64 35.66,158.24 35.66,161 v2(35.95,161.29)
PWR_VGG_CSREF: length 7.5
  TOP w0.203: 28.86,162 28.2,162.67 PU4501.17
  TOP w0.254: PR4516.1 31.65,160.15 v3(31.43,160.37) 31.39,160.41 31.39,161.49 PC4518.1 31.11,161.77 29.09,161.77 28.86,162
PWR_VGG_CSSUM: length 7.3
  TOP w0.203: 28.71,162.86 28.51,163.07 PU4501.18
  TOP w0.254: 28.71,162.86 29.17,162.41 v3(29.83,162.41) 29.92,162.5 PC4519.2 PC4520.1 33.31,162.5 PR4520.1 33.43,162.37 PR4517.2
PWR_VGG_DIFFOUT: length 3.7
  TOP w0.203: PU4501.25 25.69,165.79
  TOP w0.254: PR4505.2 PR4504.2 25.18,166.69 25.49,166.38 v3(25.51,166.38) 25.69,166.21 25.69,165.79
PWR_VGG_FB: length 12.1
  TOP w0.203: PU4501.24 26.09,166.11 26.84,166.87 26.84,167.69 PR4505.1
  TOP w0.254: PC4512.2 31.13,168.38 PR4506.1 31.12,169.24 30.74,169.62 29.11,169.62 28.9,169.42 v3(28.3,169.42) 27.34,169.42 PC4511.1 27.27,168.35 PR4507.2 27.26,168.34 PR4505.1
PWR_VGG_HG: length 31.2
  TOP w0.203: v3(24.42,159.77) 24.89,160.24 PU4501.9
  TOP w0.635: v3(24.42,159.77) 23.66,159 v6(23.66,158.62)
  L3 w1.016: v6(33.1,140.89) 33.1,141.12 31.25,142.98 26.49,142.98 21.55,147.91 21.55,153.35 23.3,155.09 23.3,158.27 v6(23.66,158.62)
  BOTTOM w0.635: v6(33.1,140.89) 33.1,140.41 PR4523.2
PWR_VGG_HGR: length 5.4
  BOTTOM w0.508: PU4502.4 34.54,141.88 PR4522.1 34.59,141.92 v4(35.47,141.05) 35.47,139.98 PR4523.1
PWR_VGG_ILIM: length 3.4
  TOP w0.203: PR4518.1 30.14,164.27 v3(29.62,164.8) 28.94,164.8 28.41,164.27 PU4501.21
PWR_VGG_IMAX: length 5.2
  TOP w0.203: 28.46,161.72 27.91,162.27 PU4501.16
  TOP w0.254: PR4532.1 31.19,159.7 30.13,160.76 v3(30.13,160.91) 29.24,160.91 29.01,161.14 29.01,161.16 28.46,161.72
PWR_VGG_IOUT: length 6.1
  TOP w0.203: PU4501.20 29.48,163.87 v2(29.52,163.83)
  BOTTOM w0.508: PR4515.1 PC4517.1 29.89,164.8 v4(30.44,164.24) 30.03,163.83 v2(29.52,163.83)
PWR_VGG_LG: length 17.6
  TOP w0.203: PU4501.12 26.09,159.09 v6(26.09,159.08)
  TOP w0.762: PU4503.4 26.71,147.6 v6(26.96,147.35)
  L4 w1.016: v6(26.09,159.08) 26.96,158.22 v6(26.96,153.37) v6(26.96,147.35)
  BOTTOM w0.762: v6(26.96,153.37) 26.96,152.91 PU4504.4
  BOTTOM w1.016: v4(27.08,159.08) v6(26.09,159.08)
PWR_VGG_PVCC: length 6.9
  TOP w0.203: PU4501.15 27.56,161.83 28.99,160.4
  TOP w0.508: PR4528.2 PC4526.1 30.44,158.95 v3(29.98,159.41) 28.99,160.4
PWR_VGG_ROSC: length 3.6
  TOP w0.203: 27.39,165.05 27.28,164.94 PU4501.22
  TOP w0.254: 27.39,165.05 28.43,166.09 v3(28.81,166.09) 29.97,166.09 PR4533.1
PWR_VGG_SN: length 3.3
  BOTTOM w0.508: PC4529.1 28.3,154.79 v4(28.35,154.84) 28.4,154.79 PR4521.2
PWR_VGG_SW: length 29.2
  TOP w0.203: v6(25.05,158.62) 25.05,159.26 25.43,159.64 25.43,160.55 25.29,160.7 PU4501.10
  TOP w0.508: PC4521.2 25.23,157.56 v3(25.41,157.73) 25.41,158.27 v6(25.05,158.62)
  L3 w1.016: v6(34.32,143.89) 32.67,143.89 31.93,144.63 27.17,144.63 23.2,148.6 23.2,152.51 25.2,154.51 25.2,158.47 v6(25.05,158.62)
  vias: v3(30.16,154.58) v4(36.99,148.21) v4(37.42,154.51) v6(34.35,146.05) v6(34.42,155.42) v6(34.42,153.42) v6(34.37,146.99) v6(34.37,145.06) v6(34.45,154.38) v6(34.53,152.4) v6(35.39,154.43) v6(35.39,153.42) v6(35.39,146.99) v6(35.36,146.05) v6(35.39,145.06) v6(35.36,143.81) v6(35.47,155.4) v6(35.54,152.4) v6(36.41,146.99) v6(36.38,146.05) v6(36.41,145.06) v6(36.43,143.81) v6(36.48,155.4) v6(36.53,154.43) v6(36.56,153.42) v6(36.56,152.4)
PWR_VGG_TSEN: length 4.3
  TOP w0.203: PU4501.13 26.49,160.26 v3(26.88,159.87)
  TOP w0.254: PC4516.2 PR4513.2 27.01,159.74 v3(26.88,159.87)
PWR_VGG_TSEN1: length 32.6
  TOP w0.254: v2(26.96,139.95) 21.42,139.95 19.82,141.56 19.82,143.37 19.59,144.1 19.3,144.91 19.19,145.21 18.81,146.71 18.79,146.8 18.79,153.69 19.86,154.76 25.89,154.76 27.1,155.97 PR4514.1 27.01,156.25 PR4513.1
  BOTTOM w0.254: PN4501.1 v2(26.96,139.95) 26.14,139.95 v4(26.09,140)
PWR_VGG_VBOOT/ADDR: length 3.9
  TOP w0.203: 27.31,160.88 27,161.2 PU4501.14
  TOP w0.254: PR4531.1 29.04,159.11 v3(28.45,159.7) 28.45,159.72 28.25,159.92 28.25,159.94 27.31,160.88
PWR_VGG_VCC: length 5.2
  TOP w0.203: PU4501.28 23.05,164.94 v2(22.86,164.75)
  BOTTOM w0.381: v4(22.07,165.14) 22.45,164.75 v2(22.86,164.75) 22.99,164.88 PC4528.1 23.78,165.36 24.46,166.04 PR4530.2
PWR_VGG_VIN:
  vias: v4(21.79,143.3) v6(23.15,143.64) v6(23.15,142.49) v6(24.29,143.64) v6(24.29,142.49) v6(25.31,142.49)
PWR_VGG_VRMP: length 8.2
  TOP w0.254: PU4501.7 23.81,161.7 22.51,160.4 21.6,160.4 21.5,160.3 v2(21.37,160.3)
  BOTTOM w0.254: v4(24.27,159.61) 24.23,159.61 ; 24.23,159.61 23.13,159.61 PR4529.2 22.3,160.3 v2(21.37,160.3) ; 24.23,159.61 23.22,160.62 23.22,160.66 23.06,160.83 PC4527.1
PWR_VGG_VSN: length 4.2
  TOP w0.203: PU4501.26 25.29,165.63 25.05,165.86
  TOP w0.254: 25.05,165.86 24.68,165.86 v3(24.14,166.41) 24.14,167.43 PC4515.1 PR4511.1
PWR_VGG_VSP: length 5.3
  TOP w0.203: 24.7,165.48 24.89,165.29 PU4501.27
  TOP w0.254: PR4510.2 PC4514.1 22.13,166.94 v3(22.77,166.3) 23.59,165.48 24.7,165.48
PWRBTN_N: length 332.6
  TOP w0.102: v1(149.05,85.39) 149.26,85.19 149.26,84.14 151.97,81.43 151.97,72.82 150.07,70.91 146.76,70.91 146.57,70.72 U4101.47 ; R668.1 110.7,60.99 v2(110.62,61.06) 109.79,61.9 R1260.2
  L3 w0.127: v2(110.62,61.06) 110.62,60.28 109.55,59.2 109.55,54.36 110.81,53.1 115.07,53.1 115.68,53.71 123.96,53.71 127.13,56.88 128.34,56.88 129.01,56.22 129.01,56.2 129.48,55.73 130.66,55.73 131.39,54.99 131.39,53.97 131.69,53.67 131.69,53.07 133.33,51.44 133.44,51.44 133.78,51.1 133.78,46.82 138.23,42.37 138.23,33.66 138.06,33.48 138.06,26.25 134.79,22.99 134.79,20.88 128.64,14.73 v2(128.61,14.73)
  L4 w0.127: v2(128.61,14.73) 129.84,13.5 129.84,12.34 127.9,10.39 120.2,10.39 112.64,2.83 27.73,2.83 26.32,4.24 25.91,4.24 22.78,7.37 22.78,22.13 v1(23.73,23.08) ; v1(124.06,75.29) 123.99,75.36 123.99,75.42 121.24,78.17 120.37,78.17 117.93,80.61 111.64,80.61 111.1,81.14 110.65,81.14 109.94,80.43 107.36,80.43 106.8,81 99.42,81 96.84,78.43 96.84,71.04 98.12,69.77 98.12,68.31 100.11,66.32 103.06,66.32 105.26,64.13 108.54,64.13 110.62,62.04 v2(110.62,61.06)
  BOTTOM w0.102: v4(111.54,59.92) 110.62,60.84 v2(110.62,61.06) ; v1(124.06,75.29) 124.06,74.44 124.64,73.86 125.64,73.86 126.04,74.27 128.41,74.27 129.11,74.97 136.24,74.97 137.23,75.96 140.07,75.96 141.75,77.65 143.03,77.65 146.16,80.78 148.65,80.78 149.26,81.39 149.26,85.19 v1(149.05,85.39) ; R373.2 28.06,23.93 27.46,24.54 25.49,24.54 25.48,24.55 C213.1 24.01,23.08 v1(23.73,23.08)
PWRCN_DET_N: length 391
  TOP w0.305: v3(31.61,24.1) 31.61,23.88 30.48,22.75 PWRCN1.5 29.2,22.75 28.74,23.22 26.72,23.22 v2(26.02,23.92)
  L3 w0.305: v1(133.5,12.37) 130.89,12.37 128.56,10.03 v1(110.12,10.03)
  L4 w0.203: v2(26.02,23.92) 26.02,23.67 28.16,21.53 28.16,18.41 26.14,16.39 26.14,15.64 24.7,14.2 24.7,10.9 29.24,6.35 45.24,6.35 47.25,8.36 47.25,11.15 46.95,11.46 46.95,18.81 48.07,19.94 57.39,19.94 61.86,24.41 67.72,24.41 68.89,23.24 85.7,23.24 89,19.95 89,9.4 90.8,7.59 95.44,7.59 97.26,9.42 109.51,9.42 v1(110.12,10.03)
  L4 w0.305: v2(163.53,119.48) 163.53,121.27 158.38,126.43 141.43,126.43 141.34,126.52 121.54,126.52 109.23,138.82 108.29,138.82 103.07,144.05 89.09,144.05 88.7,143.66 84.71,143.66 83.59,144.78 82.31,144.78 81.34,145.75 81.34,146.96 80.6,147.7 78.11,147.7 v1(77.83,147.42) ; v2(166.96,120.47) 166.71,120.22 166.71,93.6 166.19,93.08 166.19,91.36 160.82,85.99 160.82,71.68 156.38,67.25 156.32,67.25 153.09,64.02 153.09,62.9 150.09,59.9 150.09,56.16 148.29,54.36 148.29,42.53 149.49,41.33 149.49,34.65 148.84,34.01 148.84,32.27 143.57,27 143.57,23.94 133.5,13.87 v1(133.5,12.37)
  BOTTOM w0.305: v2(163.53,119.48) v4(165.35,119.48) 165.97,119.48 v2(166.96,120.47)
  BOTTOM w0.381: v2(26.02,23.92) 26.05,23.88 27.02,23.88 27.27,23.64 C12350.2 ; v1(77.83,147.42) 77.91,147.5 R536.1
PWRCN_DET_N_C: length 9.4
  TOP w0.254: CPU2.T12 v1(78.16,157.03)
  BOTTOM w0.254: R530.1 78.5,150.73 78.94,151.17 v4(78.94,151.67) 78.94,153.09 78.68,153.35 78.68,156.51 v1(78.16,157.03)
  BOTTOM w0.635: R536.2 77.91,149.17 78.5,149.76 R530.1
PWRGD_3V: length 135.8
  TOP w0.102: v1(104.35,128.14) 103.92,128.57 102.67,128.57 102.24,128.15 101.16,128.15 100.88,127.87 100.88,126.66 101.4,126.13 101.4,125.31 101.33,125.23 101.33,124.15 101.4,124.07 101.4,123.37 101.18,123.15 100.1,123.15 99.58,123.67 96.43,123.67 96.26,123.51 R1668.1 95.41,123.32 94.97,123.32 Q1214.G ; R1591.1 135.67,65.67 R79774.1 136.69,65.57 138.82,65.57 R283.2 138.88,65.58 140.14,65.58 140.66,66.1 C176.1 141.02,66.83 143.63,66.83 143.69,66.76 144.15,66.76 R278.1 145.82,67.44 148.7,67.44 153.4,72.14 153.4,82.01 150.68,84.73 150.68,103.96 149.79,104.85 149.79,106.98 150.02,107.21 150.02,110.9 149.21,111.71 149.21,115.44 146.35,118.3 144.71,118.3 143.93,117.52 139.94,117.52 v2(138.46,119)
  L3 w0.127: v2(138.46,119) 138.42,119 133.72,123.7 124.8,123.7 121.27,127.23 112.47,127.23 111.55,128.14 v1(104.35,128.14)
  BOTTOM w0.102: v4(104.81,127.45) 104.35,127.91 v1(104.35,128.14)
PWRGD_3V_B: length 24.2
  TOP w0.102: R1687.2 91.63,131.77 91.28,132.12 90.3,132.12 88.4,130.22 87.79,130.22 86.9,129.34 86.9,128.02 87,127.91 87,125.76 89.83,122.94 92.16,122.94 92.75,122.34 Q1214.D 93.02,119.91 v3(95.11,119.91) 96.35,121.16 Q6714.B
PWRGD_3V_B_1: length 7.1
  TOP w0.102: R79772.2 138.95,63.42 139.39,63.86 139.98,63.86 140.28,63.56 140.28,62.02 v3(140.44,61.85) 140.95,61.85 141.49,62.38 ; Q30.5 141.49,62.38 ; 141.49,62.38 141.64,62.23 142.02,62.23 142.14,62.35 Q30.6
PWRGD_3V_C: length 128.4
  TOP w0.102: Q6714.C 99.72,120.17 100.43,119.47 R1688.2 PC5243.1 102.33,119.47 103.46,120.6 v1(103.87,120.6)
  L3 w0.127: v2(145.7,185.69) 145.7,185.22 144.53,184.05 144.53,178.03 142.53,176.02 142.53,129.66 142.91,129.28 142.91,127.86 142.58,127.53 142.58,120.21 142.91,119.88 142.91,119.46 v2(143.72,118.64)
  BOTTOM w0.102: v2(145.7,185.69) 143,185.69 142.3,186.39 142.3,187.19 Q1212.G 141.56,188.92 141.56,189.77 141.82,190.02 141.82,190.73 141.02,191.53 Q1213.G ; v1(103.87,120.6) 104.1,120.83 104.1,121.56 v4(104.88,122.35) 105.09,122.56 109.43,122.56 110.4,121.59 118.93,121.59 120.68,119.84 136.97,119.84 138.66,118.16 143.23,118.16 v2(143.72,118.64)
PWRGD_3V_D: length 6.8
  TOP w0.102: Q77.D 98.63,124.83 99.32,125.52 99.32,126.4 v3(99.81,126.88) 99.81,125.37 100.66,124.52 Q78.S
PWRGD_3V_G: length 2.7
  TOP w0.102: v3(95,121.61) 95,122.02 R1668.2 96.64,122.62 Q77.G
PWRGD_3V_LL: length 4
  TOP w0.102: Q30.3 140.84,65.59 141.51,66.27 v3(142.38,66.27) 143.76,66.27 R278.2
PWRGD_3V_SIO: length 3.9
  TOP w0.102: U109.31 132.45,63.94 133.11,64.6 133.37,64.6 v3(133.7,64.93) 134.56,65.79 R1591.2
PWRGD_PS_L: length 7.1
  BOTTOM w0.102: Q29.2 131.59,59.22 C174.2 R274.1 132.05,56.46 134.22,56.46 v4(134.64,56.05) 134.96,55.73 R273.2
PWRGD_PS_L1: length 4.7
  BOTTOM w0.102: R269.2 133.75,61.11 Q29.6 132.23,62.31 v4(131.99,62.54) 131.58,62.13 Q29.5
PWRGD_PS_L2: length 2.4
  BOTTOM w0.102: R280.1 129.9,58.24 130.05,58.09 v4(130.64,58.09) 130.93,58.38 Q29.3
PWRGOOD_GPU: length 4.2
  TOP w0.102: GPU1.N10 80.35,94.8 80.57,95.03 v1(80.6,95.03)
  BOTTOM w0.102: R1158.2 81.13,93.01 81.13,93.72 80.67,94.19 80.27,94.19 v4(80.07,94.39) 80.07,94.77 80.32,95.03 v1(80.6,95.03)
PWROK3_1: length 6.1
  TOP w0.102: U109.29 132.39,63.14 132.72,63.47 132.72,63.79 133.3,64.37 134.29,64.37 R309.2 134.73,64.75 135.19,64.29 136.27,64.29 v3(136.51,64.53)
PWROK3_1_R: length 3.6
  TOP w0.102: R309.1 135.9,65.09 137.6,65.09 R293.2 138.03,64.66 R283.1
PWROK3_2: length 4.2
  TOP w0.102: U109.75 114.95,60.34 R386.1 113.62,58.65 v3(114.21,58.07)
PWROK3_2_R: length 40.3
  TOP w0.102: v2(141.42,61.47) 141.47,61.52 142.04,61.52 142.7,62.18 142.7,63.31 143.56,64.16 143.57,64.16 143.66,64.25 R277.1 ; R386.2 112.57,58.79 v2(111.81,58.79) 111.44,58.42 110.79,58.42 R79781.1
  L3 w0.127: v2(111.81,58.79) 113.04,60.02 117.66,60.02 117.72,60.08 125.21,60.08 125.64,60.51 130.56,60.51 131.35,61.3 137.38,61.3 138.15,60.54 139.18,60.54 139.46,60.82 140.77,60.82 v2(141.42,61.47)
  BOTTOM w0.102: v4(111.84,57.89) 111.87,57.92 111.87,58.67 111.82,58.72 111.82,58.78 v2(111.81,58.79)
PX_EN: length 2.2
  TOP w0.305: v1(88.06,98.76) 88.06,98.79 87.4,99.45 GPU1.AB16
  BOTTOM w0.508: v1(88.06,98.76) 88.07,98.76 88.07,98.53 TP159.1
QSAN_0: length 37.5
  TOP w0.127: v1(75.8,108.81) 76.04,108.81 76.2,108.65 GPU1.H27
  L3 w0.152: v1(75.8,108.81) 76.1,109.11 76.1,109.76 76.4,110.05 76.4,110.23 76.13,110.49 75.95,110.49 75.72,110.27 74.96,110.27 74.57,110.65 74.57,113.6 73.92,114.25 72.68,114.25 72.14,114.79 72.14,115.32 72.42,115.6 72.42,115.84 71.3,116.96 68.84,116.96 68.33,116.45 68.33,115.58 67.9,115.14 67.13,115.14 66.8,115.47 66.8,115.6 66.64,115.75 66.34,115.75 66.19,115.6 66.19,115.47 65.86,115.14 65.3,115.14 64.97,115.47 64.97,115.6 64.82,115.75 64.51,115.75 64.36,115.6 64.36,115.47 64.03,115.14 63.54,115.14 63.04,114.63 62.43,114.63 62.12,114.94 62.12,116.82 62,116.95 61.52,116.95 61.4,116.82 61.4,114.26 61.29,114.15 61.29,114.12 60.88,113.71 59.95,113.71 59.86,113.8 59.85,113.8 59.74,113.91 57.35,113.91 57.19,113.75 57.19,113.55 57.46,113.28 v1(57.62,113.28)
  BOTTOM w0.127: v4(76.04,109.56) 75.8,109.32 v1(75.8,108.81) ; MEM3.G3 57.21,113.14 57.35,113.28 v1(57.62,113.28)
QSAN_1: length 35.1
  TOP w0.102: GPU1.A27 71.04,108.4 70.75,108.68 70.75,108.79
  TOP w0.127: 70.75,108.79 70.75,108.96 70.13,109.58 69.93,109.58 v1(69.58,109.94)
  BOTTOM w0.127: MEM3.B7 54.01,116.55 54.12,116.44 54.33,116.44 54.54,116.65 54.54,117.13 55.09,117.67 55.76,117.67 55.91,117.82 55.91,118.09 55.78,118.21 55.49,118.21 55.17,118.53 55.17,119.18 55.44,119.46 56.59,119.46 56.85,119.19 56.85,118.82 57.05,118.62 57.33,118.62 57.53,118.82 57.53,119.18 57.78,119.43 60.42,119.43 63.71,116.15 63.71,114.39 ; 63.71,114.39 63.71,113.26 64.22,112.75 64.22,109.28 64.45,109.05 64.91,109.05 65.03,109.17 65.03,109.58 65.31,109.86 65.77,109.86 66.05,109.58 66.05,109.17 66.18,109.05 66.43,109.05 66.56,109.17 66.56,109.61 66.83,109.88 67.3,109.88 67.57,109.61 67.57,109.17 67.7,109.05 68.33,109.05 68.99,109.71 69.35,109.71 v1(69.58,109.94) ; 63.71,114.39 v4(63.99,114.39)
QSAN_2: length 36
  TOP w0.102: GPU1.C23 73,105.05 72.9,104.96 72.44,104.96 72.35,104.88 72.34,104.87 72.06,104.87 71.92,105.01 71.03,105.01 70.83,105.21 68.81,105.21 68.79,105.23
  TOP w0.127: 65.11,109.15 65.11,112.32 65.38,112.6 65.89,112.6 66.02,112.72 66.02,112.98 65.89,113.1 65.38,113.1 65.11,113.38 65.11,113.84 65.38,114.12 65.94,114.12 66.07,114.25 66.07,115 64.97,116.1 64.79,116.1 64.53,115.83 64.14,115.83 63.81,116.16 63.81,116.55 64.07,116.81 64.07,116.99 63.75,117.32 63.57,117.32 63.29,117.04 62.9,117.04 62.57,117.37 62.57,117.76 62.85,118.04 62.85,118.22 62.67,118.4 62.49,118.4 62.21,118.12 61.82,118.12 61.49,118.45 61.49,118.84 61.77,119.12 61.77,119.3 61.45,119.62 58.08,119.62 56.61,118.15 56.5,118.15 56.25,117.91 56.25,117.56 56.92,116.9 57.2,116.9 MEM1.B7 ; 65.11,109.15 65.11,108.28 68.16,105.23 68.79,105.23 ; 65.11,109.15 v3(64.72,109.15)
QSAN_3: length 35
  TOP w0.102: GPU1.C19 72.99,102 72.72,102.27 72.47,102.27 arc(72.39,102.28) 72.32,102.33 72.06,102.33 71.97,102.24 71.09,102.24 69.78,102.24 v1(69.12,102.9)
  TOP w0.127: MEM1.G3 54.21,113.08 54.21,113.34 54.48,113.6 54.67,113.6 55.17,114.1 v1(55.4,114.1)
  L4 w0.152: v1(55.4,114.1) 55.28,114.23 55.28,114.61 55.5,114.84 55.64,114.84 55.74,114.94 55.75,114.94 56,115.19 56.29,115.19 56.33,115.23 56.98,115.23 57.58,115.83 59.4,115.83 59.84,115.4 61.02,115.4 61.44,114.98 61.65,114.98 61.93,115.26 62.4,115.26 62.8,114.86 62.8,114.4 62.03,113.63 62.03,113.39 62.23,113.2 62.46,113.2 63.23,113.96 63.69,113.96 64.09,113.57 64.09,113.1 63.45,112.46 63.45,112.23 63.65,112.03 63.88,112.03 64.45,112.6 64.93,112.6 65.31,112.22 65.31,111.73 65.1,111.53 65.1,110.9 67.14,108.87 67.14,108.08 68.94,106.27 68.94,103.08 v1(69.12,102.9)
QSAN_4: length 35.3
  TOP w0.102: v1(70.09,97.84) 70.09,97.84 70.09,98.14 70.17,98.21 70.83,98.21 71.09,98.47 72.32,98.47 72.52,98.57 72.75,98.68 GPU1.C15
  L4 w0.152: v1(54.49,90.11) 54.57,90.11 54.9,89.78 55.35,89.78 55.87,89.25 56.65,89.25 57.11,88.8 57.11,86.92 57.21,86.81 57.56,86.81 57.66,86.91 57.66,87.1 57.99,87.44 58.71,87.44 59.35,86.8 59.35,86.32 59.52,86.14 61.56,86.14 61.97,86.56 62.17,86.56 63.04,87.43 63.04,87.64 62.8,87.88 62.8,88.37 63.18,88.74 63.67,88.74 63.9,88.51 64.12,88.51 64.34,88.72 64.34,88.94 64.05,89.22 64.05,89.71 64.43,90.08 64.92,90.08 65.2,89.8 65.41,89.8 65.76,90.14 65.76,96.79 66.75,97.79 70.04,97.79 v1(70.09,97.84)
  BOTTOM w0.127: v1(54.49,90.11) 54.12,90.11 54.01,90.22 MEM4.G3 ; v4(69.91,97.08) 70.09,97.26 v1(70.09,97.84)
QSAN_5: length 36.7
  TOP w0.102: 69.4,93.27 69.45,93.27 70.25,94.07 70.61,94.07 70.87,94.33 71.76,94.33 72.31,94.33 72.52,94.27 72.67,94.27 72.82,94.3 72.87,94.32 72.89,94.33 73.08,94.33 GPU1.E9
  TOP w0.127: MEM2.B7 54.17,86.27 54.65,85.78 54.65,84.62 55.07,84.2 55.07,83.72 55.29,83.5 60.9,83.5 61.14,83.74 61.53,83.74 61.76,83.5 62.09,83.5 62.37,83.78 62.37,84.7 62.54,84.87 62.84,84.87 63.01,84.7 63.01,83.99 63.26,83.74 64.07,83.74 64.34,84.01 64.34,85.9 64.06,86.18 63.47,86.18 63.37,86.28 63.37,86.7 63.48,86.81 64.21,86.81 64.42,87.02 64.42,87.7 64.18,87.93 63.62,87.93 63.53,88.02 63.53,88.42 63.68,88.56 64.16,88.56 64.42,88.83 64.42,92.33 64.55,92.46 65.31,92.46 ; 65.31,92.46 v3(65.31,92.1) ; 65.31,92.46 66.87,92.46 67.69,93.27 69.4,93.27
QSAN_6: length 30
  TOP w0.102: GPU1.C5 72.73,91.07 72.5,91.07 72.27,91.16 72.05,91.16 70.92,90.02 70.76,90.02 70.53,89.79 70.08,89.79 ; 70.08,89.79 v3(70.08,89.41) ; 70.08,89.79 v1(69.68,90.2)
  TOP w0.127: v1(56.7,89.99) 56.7,89.99 56.79,89.99 MEM2.G3
  L3 w0.152: v1(69.68,90.2) 69.4,90.48 67.87,90.48 66.87,89.48 66.87,88.06 66.56,87.75 66.07,87.75 65.76,88.06 65.76,88.82 65.64,88.95 65.38,88.95 65.26,88.82 65.26,88.06 64.95,87.75 64.47,87.75 64.16,88.06 64.16,88.82 64.04,88.95 63.78,88.95 63.66,88.82 63.66,88.06 63.35,87.75 62.82,87.75 62.51,88.06 62.51,88.82 62.39,88.95 62.03,88.95 61.9,88.82 61.9,87.88 61.6,87.57 60.99,87.57 60.69,87.88 60.69,89.89 60.56,90.01 59.85,90.01 59.72,89.89 59.72,89.17 59.42,88.87 57.26,88.87 56.88,89.26 56.88,89.81 v1(56.7,89.99)
QSAN_7: length 32.4
  TOP w0.102: GPU1.H4 76.05,90.4 75.94,90.29 75.94,89.87 75.89,89.75 75.87,89.72 75.84,89.68 75.84,89.59 75.93,89.39 75.93,88.96 75.85,88.87 75.79,88.81 75.79,88.81 75.62,88.65 75.62,88.44 75.52,88.34 75.52,88.23 75.66,88.09 v1(75.9,88.09)
  BOTTOM w0.127: 71.44,86.81 v4(71.44,87.08) ; 71.44,86.81 66.34,86.81 65.92,86.39 65.92,85.09 65.79,84.97 65.27,84.97 65.15,85.09 65.15,85.94 64.87,86.21 64.3,86.21 64.03,85.94 64.03,84.99 63.9,84.87 63.52,84.87 63.39,84.99 63.39,85.98 63.12,86.25 62.55,86.25 62.28,85.98 62.28,84.97 61.74,84.43 60.46,84.43 60.01,84.89 57.17,84.89 56.33,85.73 56.33,86.54 56.66,86.87 57.07,86.87 57.21,86.73 MEM4.B7 ; 71.44,86.81 73.32,86.81 74.28,87.77 74.89,87.77 75.39,88.27 75.72,88.27 v1(75.9,88.09)
QSAP_0: length 37.8
  TOP w0.127: GPU1.H28 76.2,109.19 v1(76.6,108.79)
  L3 w0.152: v1(76.6,108.79) 76.41,108.98 76.41,109.63 76.7,109.92 76.7,110.36 76.26,110.8 75.82,110.8 75.6,110.57 75.09,110.57 74.88,110.78 74.88,113.73 74.05,114.56 72.8,114.56 72.45,114.91 72.45,115.19 72.73,115.47 72.73,115.97 71.43,117.27 68.71,117.27 68.03,116.58 68.03,115.7 67.77,115.45 67.25,115.45 67.1,115.6 67.1,115.73 66.77,116.06 66.21,116.06 65.88,115.73 65.88,115.6 65.73,115.45 65.43,115.45 65.27,115.6 65.27,115.73 64.94,116.06 64.38,116.06 64.05,115.73 64.05,115.6 63.9,115.45 63.42,115.45 62.91,114.94 62.55,114.94 62.43,115.07 62.43,116.95 62.12,117.25 61.4,117.25 61.09,116.95 61.09,114.39 60.98,114.28 60.98,114.25 60.75,114.02 60.07,114.02 59.98,114.1 59.98,114.1 59.86,114.22 57.23,114.22 56.89,113.89 v1(56.67,113.89)
  BOTTOM w0.127: MEM3.F3 57.06,113.83 v1(56.67,113.89) ; v4(77.31,109.58) 77.3,109.58 76.6,108.88 v1(76.6,108.79)
QSAP_1: length 35.5
  TOP w0.102: 70.5,108.65 70.95,108.2 71.93,108.2 72.01,108.11 72.07,108.09 72.12,108.07 72.21,108.07 72.27,108.07 72.34,108.1 72.43,108.16 72.67,108.4 GPU1.C27
  TOP w0.127: 70.5,108.65 70.5,108.86 70.03,109.33 v1(69.55,109.33)
  BOTTOM w0.127: MEM3.C7 54.12,116.19 54.44,116.19 54.8,116.55 54.8,117.02 55.2,117.42 55.87,117.42 56.16,117.72 56.16,118.19 55.89,118.47 55.6,118.47 55.43,118.64 55.43,119.08 55.55,119.2 56.48,119.2 56.59,119.09 56.59,118.71 56.94,118.36 57.44,118.36 57.79,118.71 57.79,119.08 57.89,119.18 60.32,119.18 63.45,116.04 63.45,113.15 63.96,112.64 63.96,110.51 ; 63.96,110.51 v4(63.61,110.51) ; 63.96,110.51 63.96,109.17 64.34,108.79 65.01,108.79 65.29,109.07 65.29,109.48 65.41,109.61 65.67,109.61 65.8,109.48 65.8,109.07 66.07,108.79 66.54,108.79 66.81,109.07 66.81,109.5 66.94,109.63 67.19,109.63 67.32,109.5 67.32,109.07 67.59,108.79 68.43,108.79 69.09,109.45 69.43,109.45 v1(69.55,109.33)
QSAP_2: length 36.1
  TOP w0.102: GPU1.A23 72.02,105.2 72.01,105.21 71.12,105.21 70.92,105.41 68.91,105.41 68.88,105.45 68.84,105.45 68.8,105.49 68.79,105.49
  TOP w0.127: v3(66.59,107.66) 66.34,107.41 ; 66.34,107.41 65.36,108.39 65.36,112.21 65.49,112.34 66,112.34 66.27,112.62 66.27,113.08 66,113.36 65.49,113.36 65.36,113.48 65.36,113.74 65.49,113.87 66.05,113.87 66.32,114.14 66.32,115.1 65.08,116.35 64.69,116.35 64.42,116.09 64.24,116.09 64.06,116.27 64.06,116.45 64.33,116.71 64.33,117.1 63.85,117.57 63.46,117.57 63.19,117.3 63.01,117.3 62.83,117.48 62.83,117.66 63.1,117.93 63.1,118.32 62.77,118.65 62.38,118.65 62.11,118.37 61.93,118.37 61.75,118.56 61.75,118.74 62.02,119.01 62.02,119.4 61.55,119.87 57.97,119.87 56.5,118.41 56.39,118.41 56,118.01 56,117.45 57.21,116.24 MEM1.C7 ; 66.34,107.41 68.26,105.49 68.79,105.49
QSAP_3: length 35.3
  TOP w0.102: GPU1.E19 73.47,102 73,102.47 72.51,102.47 72.43,102.5 72.4,102.53 71.98,102.53 71.89,102.44 71.01,102.44 71.01,102.44 69.86,102.44 69.54,102.77 69.54,103.07 69.34,103.27
  TOP w0.127: v1(55.98,114.57) 55.93,114.52 55.23,114.52 54.57,113.86 54.37,113.86 54.19,113.68 MEM1.F3 ; v1(68.51,102.9) 68.67,103.07 68.67,103.07 68.92,103.32 69.29,103.32 69.34,103.27
  L4 w0.152: v1(68.51,102.9) 68.64,103.03 68.64,106.15 66.83,107.95 66.83,108.74 64.8,110.78 64.8,111.65 65,111.86 65,112.09 64.81,112.29 64.57,112.29 64.01,111.72 63.52,111.72 63.14,112.1 63.14,112.59 63.78,113.23 63.78,113.44 63.57,113.66 63.35,113.66 62.59,112.89 62.1,112.89 61.72,113.27 61.72,113.75 62.49,114.52 62.49,114.74 62.27,114.95 62.06,114.95 61.78,114.67 61.31,114.67 60.89,115.09 59.71,115.09 59.28,115.52 57.7,115.52 57.1,114.93 56.47,114.93 56.43,114.88 56.29,114.88 v1(55.98,114.57)
QSAP_4: length 36.2
  TOP w0.102: v1(70.71,97.81) 71.17,98.27 72.36,98.27 72.58,98.37 72.87,98.41 73.16,98.49 GPU1.E15
  L4 w0.152: v1(70.71,97.81) 70.31,97.4 69.68,97.4 69.6,97.48 66.88,97.48 66.06,96.66 66.06,90.01 65.54,89.49 65.07,89.49 64.79,89.78 64.56,89.78 64.36,89.58 64.36,89.35 64.64,89.06 64.64,88.59 64.25,88.2 63.78,88.2 63.54,88.44 63.31,88.44 63.11,88.24 63.11,88.01 63.35,87.77 63.35,87.3 62.3,86.25 62.09,86.25 61.68,85.84 59.39,85.84 59.04,86.19 59.04,86.67 58.59,87.13 58.12,87.13 57.96,86.97 57.96,86.78 57.69,86.51 57.09,86.51 56.8,86.79 56.8,88.67 56.53,88.95 55.75,88.95 55.22,89.47 v1(54.6,89.47)
  BOTTOM w0.127: v4(71.71,98.55) 71.46,98.55 v1(70.71,97.81) ; v1(54.6,89.47) 54.45,89.62 MEM4.F3
QSAP_5: length 36.9
  TOP w0.102: GPU1.D10 73.07,94.8 72.77,94.5 72.64,94.47 72.55,94.47 72.34,94.53 71.68,94.53 70.79,94.53 70.53,94.27 70.16,94.27 69.42,93.53 69.4,93.53
  TOP w0.127: 69.4,93.53 67.58,93.53 66.77,92.71 64.44,92.71 64.17,92.44 64.17,89.44 ; 64.17,89.44 64.17,88.93 64.06,88.82 63.57,88.82 63.28,88.53 63.28,87.91 63.52,87.68 64.08,87.68 64.16,87.59 64.16,87.12 64.1,87.07 63.38,87.07 63.11,86.8 63.11,86.17 63.36,85.92 63.96,85.92 64.09,85.79 64.09,84.12 63.96,83.99 63.37,83.99 63.26,84.1 63.26,84.81 62.95,85.12 62.43,85.12 62.12,84.81 62.12,83.89 61.99,83.76 61.87,83.76 61.63,83.99 61.03,83.99 60.8,83.76 55.39,83.76 55.33,83.82 55.33,84.3 54.9,84.73 54.9,85.89 54.41,86.38 54.41,86.82 MEM2.C7 ; 64.17,89.44 v3(63.76,89.44)
QSAP_6: length 29.7
  TOP w0.102: GPU1.D6 73.4,91.42 73.25,91.27 72.54,91.27 72.31,91.36 71.97,91.36 70.83,90.23 70.31,90.23 v1(70.29,90.2)
  TOP w0.127: v1(57.61,90.02) 57.21,89.62 MEM2.F3
  L3 w0.152: v1(70.29,90.2) 70.11,90.38 70.11,90.38 69.7,90.78 67.74,90.78 66.56,89.6 66.56,88.18 66.43,88.06 66.2,88.06 66.07,88.18 66.07,88.94 65.76,89.25 65.26,89.25 64.95,88.94 64.95,88.18 64.82,88.06 64.6,88.06 64.47,88.18 64.47,88.94 64.16,89.25 63.66,89.25 63.35,88.94 63.35,88.18 63.22,88.06 62.94,88.06 62.82,88.18 62.82,88.94 62.51,89.25 61.9,89.25 61.6,88.94 61.6,88.01 61.47,87.88 61.12,87.88 60.99,88.01 60.99,90.01 60.69,90.32 59.72,90.32 59.42,90.01 59.42,89.3 59.29,89.17 57.32,89.17 57.13,89.36 57.13,89.77 57.38,90.02 v1(57.61,90.02)
QSAP_7: length 32.9
  TOP w0.102: v1(75.45,87.62) 75.45,88.02 75.32,88.15 75.32,88.42 75.42,88.52 75.42,88.73 75.65,88.96 75.7,89.01 75.73,89.04 75.73,89.34 75.63,89.54 75.63,89.75 75.68,89.81 75.71,89.85 75.73,89.91 75.73,90.47 GPU1.G5
  BOTTOM w0.127: MEM4.C7 57.12,87.13 56.55,87.13 56.07,86.64 56.07,85.62 57.06,84.63 59.9,84.63 60.36,84.18 61.84,84.18 62.53,84.87 62.53,85.87 62.66,86 63.01,86 63.14,85.87 63.14,84.89 63.42,84.61 64.01,84.61 64.28,84.89 64.28,85.83 64.41,85.96 64.77,85.96 64.89,85.83 64.89,84.99 65.17,84.71 65.9,84.71 66.17,84.99 66.17,86.28 66.44,86.56 67.14,86.56 ; v1(75.45,87.62) 75.11,87.62 74.99,87.51 74.38,87.51 73.43,86.56 67.14,86.56 ; 67.14,86.56 v4(67.14,86.21)
R_USB1N: length 7.9
  TOP w0.102: R80050.2 140.77,112.93 140.41,112.93 v1(140.11,113.23)
  BOTTOM w0.102: v1(140.11,113.23) 140.51,113.23 140.76,112.99 141.11,112.99 141.56,113.44 141.56,114.2 142.02,114.66 142.47,114.66 ; R80051.1 144.24,114.24 143.76,114.24 143.34,114.66 142.47,114.66 ; 142.47,114.66 v4(142.47,114.96)
R_USB1P: length 7.9
  TOP w0.102: R80052.2 140.84,112.72 140.31,112.72 v1(140.11,112.52)
  BOTTOM w0.102: v4(141.75,112.86) 141.52,113.09 ; 141.52,113.09 141.2,112.77 140.76,112.77 140.51,112.52 v1(140.11,112.52) ; 141.52,113.09 141.78,113.35 141.78,114.11 142.11,114.44 143.25,114.44 143.67,114.02 144.4,114.02 R80053.1
RASA0#: length 41.2
  TOP w0.127: v1(76.59,103.69) 76.42,103.86 76.06,103.86 75.71,104.2 GPU1.G22 ; MEM1.J3 54.46,111.28 54.77,110.97 55.04,110.97 55.36,110.65 55.47,110.65 55.76,110.37 56.35,110.37 56.48,110.5 56.48,110.65 v1(56.17,110.96)
  L3 w0.165: v1(56.17,110.96) 56.17,110.63 57.43,109.37 58.02,109.37 58.15,109.24 58.15,108.72 58.27,108.59 58.78,108.59 58.91,108.72 58.91,109.24 59.03,109.37 60.56,109.37 60.69,109.24 60.69,108.41 60.56,108.28 60.15,108.28 60.03,108.16 60.03,107.68 60.15,107.55 61.21,107.55 61.33,107.68 61.33,108.56 61.46,108.69 61.73,108.69 61.97,108.45 62.24,108.45 62.4,108.28 62.4,107.74 62.57,107.57 63.05,107.57 63.21,107.74 63.21,108.28 63.38,108.45 68.55,108.45 69.42,107.57 69.67,107.57 69.67,107.57 70.18,107.57 70.67,108.06 71.89,108.06 72.01,107.93 72.01,107.65 72.14,107.52 72.7,107.52 72.83,107.65 72.83,107.93 72.95,108.06 73.35,108.06 73.48,107.93 73.48,107.19 73.74,106.93 74.1,106.93 74.1,106.93 75.33,106.93 76.92,105.34 76.92,104.02 v1(76.59,103.69)
  BOTTOM w0.127: v1(56.17,110.96) 55.96,111.17 55.96,111.75 56.17,111.96 56.38,111.96 56.51,111.83 56.51,111.46 56.68,111.28 56.68,110.94 56.81,110.81 57.06,110.81 57.19,110.94 57.19,111.25 MEM3.J3
RASA1#: length 42.4
  TOP w0.127: v1(75.88,101.1) 75.88,101.07 GPU1.G17 ; MEM2.J3 57.47,92.02 57.57,92.12 57.57,92.37 57.47,92.47 56.22,92.47 56.07,92.33 v1(56.07,92.06)
  L3 w0.165: v1(75.88,101.1) 75.9,101.1 76.05,100.95 76.97,100.95 77.13,100.78 77.81,100.78 78.01,100.58 78.37,100.58 78.74,100.94 79.35,100.94 79.48,100.82 79.48,100.26 79.35,100.13 79.01,100.13 78.85,99.97 78.85,99.64 79.01,99.47 79.35,99.47 79.48,99.34 79.48,96.8 79.35,96.67 78.97,96.67 78.84,96.54 78.84,95.69 78.97,95.56 78.97,94.82 78.54,94.39 78.54,94.23 77.71,93.4 77.41,93.4 76.48,92.47 73.68,92.47 73.36,92.8 71.3,92.8 70.52,93.58 60.73,93.58 59.92,92.76 56.98,92.76 56.27,92.06 v1(56.07,92.06)
  BOTTOM w0.127: MEM4.J3 54.13,92.02 54.63,91.52 55.05,91.52 55.17,91.65 55.17,91.81 55.42,92.05 55.43,92.05 55.44,92.07 56.06,92.07 v1(56.07,92.06)
RCOMP_LPC_HVT: length 2.6
  TOP w0.254: v1(78.14,153.44) 78.14,153.46 CPU2.T4
  BOTTOM w0.254: R1259.2 77.48,152.23 77.93,152.68 78.18,152.68 78.24,152.74 v4(78.26,152.74) 78.26,152.99 78.16,153.09 78.16,153.42 v1(78.14,153.44)
RDY#: length 3.4
  TOP w0.102: TP4130.1 137.23,75.51 138.09,75.51 138.76,74.84 U4101.23
REMOTE1+: length 267
  TOP w0.203: U109.87 117.67,55.54 v2(118.19,55.02)
  TOP w0.254: RT3.1 76.83,201.41 v2(76.84,201.42)
  L3 w0.254: v2(118.19,55.02) 118.3,55.12 123.86,55.12 126.58,57.84 132.34,57.84 132.92,57.25 133.44,57.25 133.46,57.28 139.25,57.28 140.83,58.85 146.1,58.85 159.16,71.91 159.16,72.09 v1(159.85,72.77)
  L4 w0.254: v1(159.85,72.77) 159.85,86.82 165.11,92.08 165.11,93.4 165.74,94.03 165.74,107.8 164.73,108.81 164.73,120.99 166.44,122.71 166.44,127.22 165.88,127.77 165.63,127.77 164.33,129.07 164.33,135.42 165.44,136.53 165.44,142.57 160.56,147.45 160.56,172.83 157.32,176.07 149.16,176.07 145.5,179.74 145.5,183.72 146.79,185.01 146.79,187.96 144.65,190.1 144.65,191.47 133.73,202.39 83.55,202.39 82.36,201.2 77.05,201.2 v2(76.84,201.42)
  BOTTOM w0.254: v2(76.84,201.42) 76.23,202.02 v4(76.23,202.26) ; v2(118.19,55.02) 118.35,54.86 R404.1 119.98,54.86 C211.2
REMOTE1-: length 264.3
  TOP w0.254: RT3.2 76.83,200.52 v2(76.84,200.53)
  L3 w0.254: v2(120.89,54.33) 121.27,54.71 123.99,54.71 126.73,57.45 132.04,57.45 132.78,56.72 139.5,56.72 141.08,58.29 146.33,58.29 159.85,71.81 v1(159.85,72.01)
  L4 w0.254: v2(76.84,200.53) 82.48,200.53 83.78,201.83 133.5,201.83 144.09,191.24 144.09,189.87 145.27,188.7 146.24,187.73 146.24,185.25 144.94,183.95 144.94,179.5 148.93,175.51 157.09,175.51 160,172.6 160,147.21 163.57,143.64 163.58,143.64 163.89,143.32 163.89,143.32 164.88,142.33 164.88,136.78 163.77,135.67 163.77,127.19 164.63,126.34 164.63,124.89 164.17,124.43 164.17,108.58 165.18,107.57 165.18,94.28 162.29,91.39 162.29,90.8 158.83,87.34 158.83,73.02 v1(159.85,72.01)
  BOTTOM w0.254: R400.2 123.98,53.91 122.79,53.91 121.99,54.71 121.27,54.71 v2(120.89,54.33) 120.55,54 C211.1 ; v2(76.84,200.53) v4(75.78,200.53)
REXT: length 3.4
  TOP w0.127: U127.18 131.74,38.98 130.99,39.72 v3(130.99,39.95) 130.71,40.24 R79747.1
RING2: length 45.7
  TOP w0.203: v6(164.47,49.05) 164.32,49.05 164.24,48.97 U6.31
  TOP w0.305: v6(164.47,49.05) 164.75,49.33 R261.2
  TOP w1.016: 171.48,76.28 174.23,76.28 175.93,77.98 181.77,77.98 182.78,78.99 UHS1.3
  BOTTOM w1.016: v6(167.37,76.2) 168.84,74.73 168.84,69.24 166.48,66.88 166.48,54.99 165.92,54.43 165.92,53.29 v4(165.95,53.26) 165.92,53.23 165.92,50.13 164.84,49.05 v6(164.47,49.05)
ROM_CS#: length 3.2
  TOP w0.102: R1167.2 107.94,79.32 R1168.2 106.41,80.21 106.21,80.01 U49.1
ROM_SI_D3: length 6.2
  TOP w0.102: R1171.1 94.58,84.3 v3(97.54,84.3) 98.59,84.3 99.07,83.82 U49.5
ROM_SLK_D4: length 8.3
  TOP w0.102: U49.6 98.76,82.55 97.75,83.57 v3(95.56,83.57) R1170.1
ROM_SO_C4: length 3
  TOP w0.102: v3(107.81,82.27) 107.81,82.03 R1169.2 U49.2
RSMRST*_R: length 4.2
  TOP w0.102: Q30.2 141.49,65.51 141.69,65.71 143.12,65.71 v3(143.73,65.11) 143.76,65.14 R277.2
RSMRST_N: length 446
  TOP w0.102: R477.2 R94.2 v1(154.78,191.45) ; v2(151.04,122.17) 151.06,122.17 158.47,129.58 162.92,129.58 163.75,130.4 166.4,130.4 v2(166.63,130.18) ; CPU2.F18 v1(73.18,160.16) ; R390.2 111.15,57.7 111.15,57.13 v2(111.21,57.07) 111.44,56.85 R1592.1 ; U41.3 7,221.5 6.59,221.92 R722.2 6.7,222.59 7.09,222.2 v1(7.48,222.2)
  L3 w0.127: v1(73.18,160.16) 73.18,159.97 72.91,159.69 68.92,159.69 68.56,159.33 65.84,159.33 64.98,160.2 59.85,160.2 59.77,160.12 58.53,160.12 58.2,160.45 58.2,168.55 58.91,169.27 58.91,173.71 v2(58.96,173.76) ; v2(166.63,130.18) 166.63,130.15 166.45,129.97 166.45,123.45 164.16,121.16 164.16,107.62 165.12,106.66 165.12,94.33 163.29,92.5 163.29,87.46 158.91,83.08 158.91,75.16 156.03,72.27 156.03,71.43 144.91,60.31 139.67,60.31 139.39,60.03 137.93,60.03 136.91,61.05 131.46,61.05 130.66,60.26 126.1,60.26 125.39,59.55 119.86,59.55 119.1,58.79 112.93,58.79 v2(111.21,57.07)
  L4 w0.127: v2(166.63,130.18) 166.73,130.28 166.73,135.46 167.09,135.81 167.09,144.93 164.12,147.9 164.12,158.89 163.71,159.29 163.71,180.53 154.42,189.82 154.42,191.09 v1(154.78,191.45) ; v1(7.48,222.2) 7.48,191.8 11.34,187.93 v1(13.62,187.93)
  BOTTOM w0.102: v2(151.04,122.17) 151.04,121.87 148.63,119.46 143.62,119.46 142.8,118.64 142.33,118.64 141.51,119.46 138.46,119.46 137.37,120.55 121.19,120.55 v4(120.76,120.98) 119.67,122.07 110.6,122.07 109.63,123.04 103.56,123.04 98.71,127.89 98.71,127.95 96.33,130.33 90.71,130.33 87.86,130.93 78.69,140.11 71.35,140.11 66.54,144.92 65.58,147.39 65.54,147.69 65.54,155.94 69.22,159.61 69.65,159.61 70.61,160.57 72.64,160.57 73.04,160.16 v1(73.18,160.16) ; v1(13.62,187.93) 16.53,185.03 16.53,183.92 25.16,175.29 39.76,175.29 40.83,174.22 58.38,174.22 58.83,173.76 v2(58.96,173.76)
RSMRST_N_XDP: length 8.4
  TOP w0.102: XDP1.39 150.89,199.08 151.47,198.5 151.47,198.32 152.81,196.97 152.81,196.09 154.08,194.82 v5(154.08,194.44) 153.96,194.31 R477.1
RT: length 4.4
  BOTTOM w0.102: R79628.1 33.85,24.97 v4(32.98,24.97) 32.44,25.5 32.44,26.77 31.93,27.29 U120.10
RTC_INTRUDER: length 6.1
  TOP w0.102: v1(73.87,160.2) 74.25,160.57 CPU2.G18
  BOTTOM w0.102: v1(73.87,160.2) 73.87,160.4 v4(73.44,160.83) 70.38,160.83 70.2,160.66 70.19,160.66 69.66,160.13 R79797.1
RTCX_L: length 4.6
  TOP w0.102: v3(56.54,149.81) 56.54,149.89 56.52,149.9 R1261.2 55.91,151.42 55.91,153.19 55.54,153.56 X7.4
RTD_LVDS_BL_ADJ: length 9.9
  TOP w0.165: R44.1 45.41,121.56 45.13,121.28 45.13,119.33 44.14,118.34 Q21.3 43.81,117.74 43.61,117.53 43.61,117.49 42.83,116.71 v5(42.83,116.59) 42.82,116.57 R79682.2 41.64,113.86 R80236.2
RTL_ISOLATE_N: length 14.7
  TOP w0.102: U20.20 33.95,15.19 33.79,15.34 32.89,15.34 32.09,16.14 32.09,16.53 31.82,16.8 30.96,16.8 v1(29.63,18.14) 29.63,18.47 30.55,19.39 R332.1 31.45,18.45 R331.2
  BOTTOM w0.102: v1(29.63,18.14) 29.65,18.12 29.65,18.07 30.3,17.42 31.61,17.42 31.87,17.69 Q35.6 32.19,18.43 v4(33.42,18.43)
RTL_ISOLATE_N_1: length 7
  BOTTOM w0.102: R372.2 34.72,18.96 32.99,18.96 32.38,19.58 v4(32.14,19.58) 31.31,19.58 C207.1 R368.1 31.22,18.48 Q35.5
RTL_ISOLATE_N_2: length 6.1
  BOTTOM w0.102: R329.2 30.18,13.91 30.18,14.68 v4(30.43,14.92) 30.57,15.07 Q35.3 30.57,16.9 30.69,17.02 31.1,17.02 31.22,16.89 Q35.2
RTN1: length 20.6
  TOP w0.254: v2(22.17,33.43) 21.99,33.61 21.99,38.47 24.37,40.84 27.03,40.84 27.34,41.15 CONVT1.1 28.33,42.64 v3(28.99,43.31)
  BOTTOM w0.254: v2(22.17,33.43) 22.64,32.96 26.91,32.96 27.06,32.82 R79712.1
RTN2: length 16.1
  TOP w0.254: CONVT1.2 27.4,40.15 27.21,40.34 24.75,40.34 22.64,38.23 v3(22.64,36.58) 22.64,33.72 22.7,33.65 22.7,33.06 v2(22.15,32.51)
  BOTTOM w0.254: v2(22.15,32.51) 22.3,32.36 23.11,32.36 23.11,32.36 23.24,32.36 23.24,32.36 R53.1
RTN3: length 16.4
  TOP w0.254: CONVT1.5 25.47,37.15 24.42,36.09 24.42,33.32 22.6,31.5 v2(22.18,31.5) v3(22.18,30.58)
  BOTTOM w0.254: v2(22.18,31.5) 22.28,31.6 R79713.1
RTN4: length 12.4
  TOP w0.254: CONVT1.6 25.64,36.15 24.95,35.46 24.95,32.28 23.83,31.17 v2(23.83,30.96) 23.83,30.56 23.99,30.4 v3(23.99,29.44)
  BOTTOM w0.254: v2(23.83,30.96) 23.85,30.96 v4(24.46,30.36) 25.06,30.96 R79715.1
S_LVDS_BL_EN: length 5.8
  TOP w0.127: R143.2 37.69,23.88 R144.1 R135.1 37.35,25.73 36.74,26.34 v3(36.74,26.45) 36.74,26.54 37.07,26.87 R139.1 R1985.1
S_TXE0+: length 5.8
  TOP w0.102: LVDS1.18 v2(43.63,92.5)
  BOTTOM w0.102: v4(42.71,93.83) 42.5,93.62 ; 42.5,93.62 41.9,94.23 41.53,94.23 41.46,94.3 U126.31 ; 42.5,93.62 42.93,93.19 42.93,92.31 43.04,92.2 43.33,92.2 v2(43.63,92.5)
S_TXE0-: length 5.9
  TOP w0.102: LVDS1.19 v2(43.63,91.5)
  BOTTOM w0.102: v4(42.71,91.72) 42.93,91.95 ; 42.93,91.95 43.18,91.95 v2(43.63,91.5) ; 42.93,91.95 42.68,92.2 42.68,93.08 41.79,93.97 41.53,93.97 41.46,93.9 U126.32
S_TXE1+: length 5.3
  TOP w0.102: LVDS1.15 v2(43.63,95.5)
  BOTTOM w0.102: v4(44.61,95.48) 43.65,95.48 v2(43.63,95.5) 43.16,95.03 41.53,95.03 41.46,95.1 U126.29
S_TXE1-: length 5.1
  TOP w0.102: LVDS1.16 v2(43.63,94.5)
  BOTTOM w0.102: U126.30 41.46,94.7 41.53,94.77 43.36,94.77 v2(43.63,94.5) 44.09,94.5 v4(44.41,94.18)
S_TXE2+: length 6.5
  TOP w0.102: LVDS1.12 v2(43.63,98.5)
  BOTTOM w0.102: 42.49,97.93 42.75,98.19 43.33,98.19 v2(43.63,98.5) ; 42.49,97.93 42.49,96.18 42.14,95.83 41.53,95.83 41.46,95.9 U126.27 ; 42.49,97.93 v4(42.3,98.12)
S_TXE2-: length 6.6
  TOP w0.102: LVDS1.13 v2(43.63,97.5)
  BOTTOM w0.102: 42.57,95.9 42.74,96.08 42.74,97.83 42.86,97.94 43.19,97.94 v2(43.63,97.5) ; 42.57,95.9 42.24,95.57 41.53,95.57 41.46,95.5 U126.28 ; 42.57,95.9 v4(42.83,95.63)
S_TXE3+: length 8.6
  TOP w0.102: v2(43.64,102.39) 43.53,102.5 LVDS1.8
  BOTTOM w0.102: v2(43.64,102.39) 43.54,102.29 42.78,102.29 41.89,101.4 41.89,100.71 40.47,99.29 ; U126.23 39.58,98.39 40.47,99.29 ; 40.47,99.29 v4(40.22,99.54)
S_TXE3-: length 8.6
  TOP w0.102: LVDS1.9 42.96,101.5 43.16,101.7 43.38,101.7 v2(43.63,101.45)
  BOTTOM w0.102: v2(43.63,101.45) 43.63,101.74 43.34,102.03 42.89,102.03 42.15,101.29 42.15,100.81 ; 42.15,100.81 42.15,100.61 39.98,98.44 U126.24 ; 42.15,100.81 v4(42.5,100.81)
S_TXEC+: length 7.2
  TOP w0.102: LVDS1.10 v2(43.63,100.5)
  BOTTOM w0.102: v2(43.63,100.5) 43.23,100.1 42.88,100.1 41.83,99.05 ; 41.83,99.05 41.49,98.71 41.49,96.72 41.4,96.63 41.31,96.63 41.24,96.7 U126.25 ; 41.83,99.05 v4(41.59,99.29)
S_TXEC-: length 7.1
  TOP w0.102: LVDS1.11 v2(43.63,99.5)
  BOTTOM w0.102: v2(43.63,99.5) 43.28,99.85 42.98,99.85 42.6,99.47 ; 42.6,99.47 41.74,98.61 41.74,96.61 41.51,96.38 41.31,96.38 41.24,96.3 U126.26 ; 42.6,99.47 v4(42.81,99.26)
S_TXO0+: length 15.5
  TOP w0.102: LVDS1.29 43.65,81.5 v2(43.72,81.43)
  BOTTOM w0.102: 41.18,82.2 40.85,82.53 40.85,86.82 38.23,89.44 38.23,90.55 38.38,90.69 U126.41 ; 41.18,82.2 42.33,81.05 43.49,81.05 43.72,81.28 v2(43.72,81.43) ; 41.18,82.2 v4(41.43,82.45)
S_TXO0-: length 15.5
  TOP w0.102: v2(43.64,80.62) 43.53,80.5 LVDS1.30
  BOTTOM w0.102: 41.64,81.38 42.22,80.8 43.47,80.8 v2(43.64,80.62) ; 41.64,81.38 40.6,82.42 40.6,86.72 37.98,89.34 U126.42 ; 41.64,81.38 v4(41.41,81.15)
S_TXO1+: length 13.4
  TOP w0.102: LVDS1.27 43.52,83.5 v2(43.66,83.36)
  BOTTOM w0.102: 41.59,83.95 41.59,87.15 39.1,89.64 39.1,90.81 39.18,90.88 U126.39 ; 41.59,83.95 41.59,83.38 42.04,82.93 43.54,82.93 43.66,83.05 v2(43.66,83.36) ; 41.59,83.95 v4(41.94,83.95)
S_TXO1-: length 13.5
  TOP w0.102: v2(43.65,82.47) 43.62,82.5 LVDS1.28
  BOTTOM w0.102: v4(42.78,82.32) 42.78,82.67 ; 42.78,82.67 41.94,82.67 41.33,83.28 41.33,87.05 38.85,89.53 38.85,90.74 38.78,90.82 U126.40 ; 42.78,82.67 43.45,82.67 v2(43.65,82.47)
S_TXO2+: length 10.8
  TOP w0.102: LVDS1.25 v2(43.63,85.5)
  BOTTOM w0.102: v2(43.63,85.5) 43.63,85.33 43.05,84.75 42.69,84.75 42.32,85.12 42.32,85.83 ; v4(42.65,85.83) 42.32,85.83 ; 42.32,85.83 42.32,87.99 39.9,90.41 39.9,90.74 39.98,90.82 U126.37
S_TXO2-: length 10.8
  TOP w0.102: LVDS1.26 v2(43.63,84.5)
  BOTTOM w0.102: v2(43.63,84.5) 42.58,84.5 42.07,85.01 42.07,87.89 41.11,88.85 ; 41.11,88.85 40.04,89.92 40.04,89.92 40.04,89.92 39.65,90.31 39.65,90.74 39.58,90.82 U126.38 ; 41.11,88.85 v4(40.88,88.62)
S_TXO3+: length 7.5
  TOP w0.102: LVDS1.20 v2(43.63,90.5)
  BOTTOM w0.102: v4(44.31,91.01) 43.8,90.5 v2(43.63,90.5) 43.3,90.17 42.93,90.17 42.12,90.98 42.12,92.85 41.54,93.43 41.31,93.43 41.23,93.5 U126.33
S_TXO3-: length 7.6
  TOP w0.102: LVDS1.21 v2(43.63,89.5)
  BOTTOM w0.102: v4(44.31,89) 43.81,89.5 v2(43.63,89.5) 43.22,89.92 42.83,89.92 41.87,90.88 41.87,92.74 41.44,93.17 41.31,93.17 41.24,93.1 U126.34
S_TXOC+: length 7.9
  TOP w0.102: LVDS1.22 v2(43.63,88.5)
  BOTTOM w0.102: v2(43.63,88.5) 43.35,88.22 43.16,88.22 41.98,89.4 ; 41.98,89.4 v4(42.22,89.64) ; 41.98,89.4 41.46,89.91 41.46,92.48 41.24,92.7 U126.35
S_TXOC-: length 7.8
  TOP w0.102: LVDS1.23 v2(43.63,87.5)
  BOTTOM w0.102: v2(43.63,87.5) 43.63,87.59 43.37,87.86 43.16,87.86 43.06,87.96 ; 43.06,87.96 41.91,89.11 41.21,89.81 41.21,92.12 41.03,92.3 U126.36 ; 43.06,87.96 v4(42.83,87.73)
SATA__RXN0_C: length 8.1
  TOP w0.102: HDD1.5 12.28,143.8 13.09,143.8 14.49,142.41 15.94,142.41 16.92,143.39 C149.2
  BOTTOM w0.102: v4(10.24,142.95) 10.56,143.27 HDD1.5
SATA__RXN1_C: length 7.4
  TOP w0.102: ODD1.5 8.63,178.8 13.14,178.8 C118.2
  BOTTOM w0.102: ODD1.5 6.91,178.27 v4(6.59,177.95)
SATA__RXP0_C: length 7.4
  TOP w0.102: HDD1.6 12.28,144.01 13.18,144.01 14.58,142.62 15.85,142.62 16.19,142.96 16.19,143.26 16.06,143.39 C151.2
  BOTTOM w0.102: HDD1.6 10.48,144.54 v4(10.35,144.68)
SATA__RXP1_C: length 7.2
  TOP w0.102: C119.2 13.1,179.01 8.63,179.01 ODD1.6
  BOTTOM w0.102: v4(6.7,179.68) 6.83,179.54 ODD1.6
SATA__TXN0_C: length 6.3
  TOP w0.102: HDD1.3 12.28,140.2 15.74,140.2 C142.2
  BOTTOM w0.102: HDD1.3 12.98,140.73 v4(13.16,140.92)
SATA__TXN1_C: length 7.5
  TOP w0.102: ODD1.3 8.63,175.2 12.96,175.2 C115.2
  BOTTOM w0.102: v4(6.43,176.25) 6.95,175.73 ODD1.3
SATA__TXP0_C: length 6.3
  TOP w0.102: C141.2 15.78,139.99 12.28,139.99 HDD1.2
  BOTTOM w0.102: HDD1.2 13.05,139.46 v4(13.19,139.32)
SATA__TXP1_C: length 7.4
  TOP w0.102: C114.2 13.09,174.99 8.63,174.99 ODD1.2
  BOTTOM w0.102: ODD1.2 6.34,174.46 v4(6.33,174.45)
SATA_LED_N_C_1: length 9
  TOP w0.254: v1(141.26,7.59) 141.26,7.33 140.43,6.5 ; R80201.2 140.43,6.5 ; 140.43,6.5 Q9646.3 ; v1(139.07,10.87) 139.13,10.81 Q9646.6
  L3 w0.254: v1(139.07,10.87) 139.07,9.86 141.26,7.67 v1(141.26,7.59)
  BOTTOM w0.254: v4(138.72,11.58) 139.07,11.22 v1(139.07,10.87)
SATA_RCOMP_DN: length 2.7
  TOP w0.102: v1(75.97,166.89) 75.97,166.86 CPU2.M30
  BOTTOM w0.102: v4(75.27,168.63) 75.99,167.91 R519.1 75.99,166.91 v1(75.97,166.89)
SATA_RCOMP_DP: length 3.4
  TOP w0.102: CPU2.N30 76.69,166.86 v1(76.69,166.93)
  BOTTOM w0.102: v4(76.28,169.32) 76.33,169.27 76.33,168.26 R519.2 76.69,167.52 v1(76.69,166.93)
SATAHDR_RX_DN0: length 84.1
  TOP w0.102: L4104.4 16.58,153.01 16.43,153.16 16.43,153.73 16.07,154.09 16.07,155.13 16.3,155.35 16.54,155.35 v2(16.87,155.02) ; v1(76.03,165.95) 76.14,165.95 76.38,165.71 CPU2.M28
  BOTTOM w0.102: 15.91,169.04 15.31,168.44 15.31,156.02 16,155.33 16.56,155.33 v2(16.87,155.02) ; 15.91,169.04 v4(15.68,169.27) ; 15.91,169.04 18.71,171.84 57.42,171.84 59.46,169.81 66.11,169.81 68.21,167.71 70.38,167.71 71.52,166.57 73.49,166.57 74.15,165.91 74.15,165.84 74.44,165.55 75.62,165.55 v1(76.03,165.95)
SATAHDR_RX_DN0_EMI: length 7.6
  TOP w0.102: C149.1 16.99,144.75 16.89,144.85 16.69,144.85 16.59,144.95 16.59,149.42 16.32,149.69 16.32,150.63 16.55,150.86 L4104.3
SATAHDR_RX_DN1: length 74.4
  TOP w0.102: C118.1 14.73,178.84 17.08,178.84 v2(17.53,178.38) ; CPU2.K28 v1(75.31,165.95)
  BOTTOM w0.102: v4(15.96,177.42) 15.65,177.42 ; 15.65,177.42 15.65,173.76 16.75,172.67 57.77,172.67 59.76,170.68 66.31,170.68 68.8,168.19 70.8,168.19 71.38,167.6 73.04,167.6 73.05,167.59 74.2,167.59 74.69,167.11 74.69,166.58 v1(75.31,165.95) ; 15.65,177.42 15.65,178.28 16.21,178.84 17.08,178.84 v2(17.53,178.38)
SATAHDR_RX_DP0: length 84.5
  TOP w0.102: CPU2.N28 v1(76.74,165.95) ; L4104.1 15.9,153.02 16.21,153.34 16.21,153.64 15.86,154 15.86,155.22 16.21,155.57 16.54,155.57 v2(16.87,155.91)
  BOTTOM w0.102: v4(15.86,160.17) 15.53,160.17 ; 15.53,160.17 15.53,156.11 16.09,155.55 16.52,155.55 v2(16.87,155.91) ; 15.53,160.17 15.53,168.35 18.8,171.63 57.33,171.63 59.37,169.6 66.02,169.6 68.12,167.49 70.29,167.49 71.43,166.35 73.4,166.35 73.93,165.82 73.93,165.75 74.35,165.33 76.11,165.33 v1(76.74,165.95)
SATAHDR_RX_DP0_EMI: length 7.6
  TOP w0.102: C151.1 15.97,144.75 16.08,144.85 16.27,144.85 16.37,144.95 16.37,149.33 16.1,149.6 16.1,150.63 15.87,150.86 L4104.2
SATAHDR_RX_DP1: length 74.4
  TOP w0.102: C119.1 14.69,179.05 17.29,179.05 v2(17.53,179.3) ; CPU2.J28 v1(74.6,165.95)
  BOTTOM w0.102: 17.64,172.45 57.68,172.45 59.67,170.46 66.22,170.46 68.71,167.97 70.71,167.97 71.3,167.39 72.95,167.39 72.96,167.38 74.11,167.38 74.47,167.02 74.47,166.08 v1(74.6,165.95) ; 17.64,172.45 v4(17.64,172.14) ; 17.64,172.45 16.66,172.45 15.44,173.67 15.44,178.37 16.12,179.05 17.29,179.05 v2(17.53,179.3)
SATAHDR_TX_DN0: length 87.8
  TOP w0.089: 69.39,166.35 69.69,166.35 69.7,166.35 69.86,166.35 69.87,166.35 70.85,166.35 70.94,166.45 70.95,166.45 71.41,166.45 71.42,166.46 CPU2.B30
  TOP w0.102: 69.39,166.35 69.01,166.35 68.87,166.5 v1(68.87,166.75) ; v2(16.9,157.73) 17.01,157.85 17.37,157.85 17.88,157.34 17.88,146.74 18.56,144.03 18.56,143.53 18.32,143.29 L4103.1
  BOTTOM w0.102: 16.54,162.38 v4(16.85,162.38) ; 16.54,162.38 16.54,167.77 19.57,170.79 55,170.79 55.52,170.27 55.52,168.28 56.07,167.73 57.04,167.73 58,168.68 65.54,168.68 67.24,166.98 68.64,166.98 v1(68.87,166.75) ; 16.54,162.38 16.54,161.62 17.97,160.2 17.97,158.63 17.71,158.38 17.36,158.38 17.25,158.28 17.25,158.09 v2(16.9,157.73)
SATAHDR_TX_DN0_EMI: length 3.6
  TOP w0.102: C142.1 17.43,140.62 17.56,140.5 17.56,139.95 17.69,139.82 17.91,139.82 18.61,140.52 18.61,140.88 18.32,141.17 L4103.2
SATAHDR_TX_DN1: length 69.2
  TOP w0.089: 69.67,165.87 69.76,165.87 69.78,165.89 70.92,165.89 71.01,165.97 CPU2.A29
  TOP w0.102: 69.67,165.87 68.87,165.87 67.41,167.33 67.41,167.64 67.29,167.75 67.29,168.05 67.41,168.16 67.41,168.47 67.29,168.58 67.29,168.89 67.41,169 67.41,169.74 68.1,170.43 68.1,170.56 68.02,170.64 68.02,170.64 v1(67.85,170.81) ; C115.1 14.42,175.46 15.32,175.46 16.12,176.26 17.19,176.26 v2(17.53,176.61)
  BOTTOM w0.102: v1(67.85,170.81) 67.93,170.81 68.23,171.11 68.23,171.25 68.15,171.32 60,171.32 58.05,173.28 17.51,173.28 16.95,173.84 ; v4(16.72,173.61) 16.95,173.84 ; 16.95,173.84 16.43,174.36 16.43,175.83 16.86,176.26 17.19,176.26 v2(17.53,176.61)
SATAHDR_TX_DP0: length 88.3
  TOP w0.089: CPU2.C31 71.78,166.94 71.77,166.94 71.63,166.94 71.34,166.65 71.33,166.64 70.87,166.64 70.77,166.54 69.78,166.54
  TOP w0.102: L4103.4 19,143.29 18.77,143.53 18.77,144.06 18.09,146.77 18.09,157.43 17.1,158.42 v2(16.92,158.6) ; 69.78,166.54 v1(69.57,166.75)
  BOTTOM w0.102: v4(17.48,169.44) 17.7,169.23 ; 17.7,169.23 16.33,167.86 16.33,161.53 17.75,160.11 17.75,158.72 17.62,158.6 v2(16.92,158.6) ; 17.7,169.23 19.48,171.01 55.09,171.01 55.73,170.36 55.73,168.37 56.16,167.94 56.95,167.94 57.91,168.9 65.63,168.9 67.33,167.2 69,167.2 69.44,166.75 v1(69.57,166.75)
SATAHDR_TX_DP0_EMI: length 3.3
  TOP w0.102: L4103.3 19,141.08 18.83,140.9 18.83,140.43 18,139.61 C141.1
SATAHDR_TX_DP1: length 69.2
  TOP w0.089: 69.67,166.09 69.77,166.09 69.78,166.08 70.84,166.08 71.02,166.26 71.35,166.26 71.63,165.97 CPU2.C29
  TOP w0.102: v2(17.53,175.74) 17.23,176.05 16.21,176.05 15.41,175.25 14.81,175.25 C114.1 ; v1(68.54,170.76) 68.32,170.54 68.32,170.34 67.62,169.65 67.62,167.42 68.96,166.09 69.67,166.09
  BOTTOM w0.102: v1(68.54,170.76) 68.44,170.86 68.44,171.34 68.24,171.54 60.09,171.54 58.14,173.49 19.79,173.49 ; 19.79,173.49 17.6,173.49 16.64,174.45 16.64,175.74 16.95,176.05 17.23,176.05 v2(17.53,175.74) ; 19.79,173.49 v4(19.79,173.84)
SB3V: length 1124.5
  TOP w0.254: v2(111.56,65.23) 111.56,65.39 111.32,65.63 R382.2
  TOP w0.305: R79687.1 51.77,75.86 53.1,75.86 53.49,75.47 53.49,75.27 53.84,74.92 56.6,74.92 57.18,75.5 62.4,75.5 63.48,76.59 R531.1 64,77 64.41,77 64.84,76.57 67.81,76.57 v1(69.65,78.41) ; v1(95.26,127.74) 95.26,129.77 95.65,130.16 R551.1 ; R79772.1 138.04,63.06 v2(136.93,63.06) 136.35,63.06 R311.2 ; v2(91.09,125.18) 90.95,125.32 R1580.2 90.97,126.06 R54.2 ; R79762.2 R79763.2 135.53,55.88 R79759.2 135.68,55.28 135.07,54.67 ; 135.07,54.67 135.28,54.67 136.06,53.89 v2(136.06,53.75) ; 135.07,54.67 R79761.2 ; R80062.2 144.39,108.31 v1(140.65,108.31) ; R67.2 108.37,121.68 107.91,121.22 v1(107.91,121.03) ; R316.2 136.84,50.98 136.84,50.71 v2(136.83,50.71) ; v2(28.3,30.76) 28.36,30.7 R79720.1 ; R79721.1 R79719.1 31.5,31.72 v2(31.15,31.37) ; v2(42.35,177.5) 42.67,177.81 R1789.1 ; R390.1 112.47,57.71 v2(113.11,57.71)
  TOP w0.381: R1247.1 72.94,145.27 v2(72.94,146.41) ; R717.1 100.48,120.94 v2(100.82,120.6) ; v2(160.51,179.17) 160.09,178.75 157.32,178.75 156.85,179.22 156.85,179.49 157.04,179.68 157.04,180.24 156.85,180.43 156.85,181.06 R79944.2
  TOP w0.508: v1(7.63,223.44) 7.59,223.48 R722.1 ; 119.24,71.73 118.54,72.43 118.54,74.12 118.87,74.45 ; R665.1 134.15,5.8 v1(134.93,5.8) 134.93,5.87 R659.1 ; R80202.1 R80201.1 146.91,5.58 v1(147.25,5.23) ; R1256.2 64.87,157.84 60.42,157.84 59.74,158.51 58.92,159.33 52.89,159.33 51.04,161.19 51.04,161.44 47.2,165.28 v6(41.14,165.28) ; v2(45.9,8.41) 46.37,8.88 46.37,8.99 R705.1 ; R80152.2 77.71,133.32 R80121.2 ; 118.87,74.45 115.59,77.72 111.59,77.72 v1(110.55,78.69) ; 118.87,74.45 120.29,74.45 R348.1 ; R80148.1 68.68,143.39 68.23,143.84 v1(68.23,143.89) ; R6702.1 89.86,80.28 91.09,81.51 v1(91.27,81.51) ; v2(140.47,207.65) 141.1,207.01 R1568.1 ; v1(68.26,133.1) 68.32,133.16 R80150.2 69.83,133.16 70.5,133.83 71.58,133.83 72.97,135.23 74.9,135.23 76,136.32 77.61,136.32 R80146.2 77.71,136.23 R80121.2 ; v2(142.32,47.9) 141.78,47.9 141.1,48.58 137.52,48.58 137.13,48.19 v2(137.13,47.83) 136.81,47.83 R289.2 ; v2(84.67,209.68) 83.54,210.81 PR4402.1 PR4401.1 ; R80121.2 79.29,134.32 Q9641.S ; v1(84.46,124.66) 84.46,123.33 R80155.2
  TOP w1.016: v6(142.88,43.89) 142.88,40.87 144.03,39.73 144.03,32.7 142.27,30.95 140.13,30.95 139.3,30.12 139.3,29.18 136.41,26.29 v6(134.98,26.29)
  L3 w0.381: v1(107.91,121.03) 107.91,121.01 107.35,120.45 105.01,120.45 104.44,121.02 104.26,121.02 104.11,121.17 103.63,121.17 103.48,121.02 101.24,121.02 v2(100.82,120.6)
  L3 w0.508: v2(113.11,57.71) 113.76,57.71 113.87,57.6 114.94,57.6 115.13,57.41 118.96,57.41 120.66,59.11 121.83,59.11 v2(122.18,58.75) 122.54,59.11 125.9,59.11 125.95,59.05 126.49,59.05 127.21,59.77 135.64,59.77 135.95,60.07 137.12,60.07 137.19,59.99 v2(137.24,59.99) ; v1(108.54,6.78) 108.92,6.4 129.23,6.4 129.83,5.8 v1(134.93,5.8) ; v2(140.47,207.65) 140.06,207.65 138.39,209.32 v2(138.39,215.06) ; v6(28.18,11.65) 28.18,14.71 27.06,15.82 27.06,15.82 24.83,18.05 v1(24.83,22.12) ; v2(28.3,30.76) 30.54,30.76 v2(31.15,31.37) ; v2(137.13,47.83) 137.32,48.02 137.32,50.24 136.85,50.71 136.84,50.71 v2(136.83,50.71) 136.83,52.89 136.06,53.67 v2(136.06,53.75) ; v1(69.65,78.41) 79.56,78.41 82.58,81.43 91.19,81.43 v1(91.27,81.51) 95.29,81.51 95.87,82.09 98.24,82.09 99.83,80.51 106.69,80.51 108.03,79.16 110.08,79.16 v1(110.55,78.69) ; v2(72.94,146.41) 70.43,143.89 v1(68.23,143.89) 67.79,144.34 64.59,144.34 61.09,140.84 60.38,140.84 v1(60.26,140.97) 59.94,140.65 45.37,140.65 v6(44.59,139.88)
  L3 w1.016: v6(41.14,165.28) 36.69,165.28 33.26,168.71 33.26,170.97 28.74,175.49 28.74,183.77 23.71,188.8 23.71,191.44 19.85,195.3 19.85,196.46 17.94,198.36 17.94,202.49 15.02,205.41 v6(15.02,205.44) ; v1(7.63,223.44) 8.61,224.42 8.61,224.5 11.43,227.33 87.33,227.33 v6(87.41,227.25) 87.84,227.25 87.98,227.39 123.61,227.39 123.61,227.39 125.08,227.39 125.08,227.39 126.46,227.39 128.3,225.55 128.3,225.55 128.46,225.4 v2(128.51,225.4) 140.47,225.4 v6(140.62,225.25)
  L3 w1.27: 168.31,84.99 168.31,84.76 163.61,80.06 163.61,72.14 145.63,54.16 145.63,51.21 v2(142.32,47.9) 142.32,44.45 v6(142.88,43.89)
  L4 w0.508: v1(84.46,124.66) 85.12,125.32 90.79,125.32 90.93,125.18 v2(91.09,125.18) ; v1(147.25,5.23) 146.68,5.8 v1(134.93,5.8) ; v2(151.67,189.04) 151.73,189.04 152.61,188.16 154.01,188.16 154.17,188 155.12,188 155.51,187.61 155.51,186.66 160.51,181.66 v2(160.51,179.17) ; v2(28.3,30.76) 28.3,30.28 24.79,26.76 24.79,22.17 v1(24.83,22.12) ; v1(68.26,133.1) 67.13,134.23 65.2,134.23 60.26,139.17 v1(60.26,140.97) ; v6(41.14,165.28) 41.14,175.4 42.35,176.61 v2(42.35,177.5) ; v1(108.36,12.93) 107.78,13.51 107.78,21.51
  L4 w0.635: 170.22,88.44 170.49,88.71 170.49,94.48 169.21,95.77 169.21,104.45 169.76,105 169.76,124.71 173.01,127.96 173.01,127.97 176.15,131.1 v6(176.15,134.05)
  L4 w1.016: v6(15.02,205.44) 11.59,205.44 9.18,207.85 9.18,221.89 v1(7.63,223.44) ; v6(134.98,26.29) 134.96,26.26 130.61,26.26 126.4,22.05 ; 126.4,22.05 122.88,18.53 114.8,18.53 111.82,21.51 107.78,21.51 106.7,22.59 96.63,22.59 94.26,20.23 90.11,20.23 86.01,24.33 70.06,24.33 68.27,26.13 59.37,26.13 57.95,27.55 57.95,30.3 56.97,31.28 49.83,31.28 49.32,30.77 49.32,29.76 47.61,28.05 47.61,24.02 45.27,21.69 45.27,11.73 46.26,10.74 46.26,8.77 v2(45.9,8.41) 41.16,8.41 39.28,10.29 29.54,10.29 v6(28.18,11.65) ; 126.4,22.05 v1(126.4,21.97)
  BOTTOM w0.305: v6(44.59,139.88) 44.36,139.64 44.36,132.08 48.04,128.4 48.04,122.79 46.41,121.16 v4(46.41,121.11) ; R1740.1 150.5,189.57 R1741.1 151.15,189.12 151.16,189.1 151.61,189.1 v2(151.67,189.04)
  BOTTOM w0.381: v1(140.65,108.31) 140.65,110.93 139.48,112.1 139.48,115.12 136.27,118.33 v4(126.98,118.33) 119.92,118.33 118.16,120.09 109.86,120.09 108.92,121.03 v1(107.91,121.03) ; PR4501.1 PR4502.1 20.49,163.47 20.49,163.98 ; R79657.1 43.07,120.35 43.08,120.36 R79661.1 43.56,120.85 43.9,121.2 46.32,121.2 v4(46.41,121.11)
  BOTTOM w0.508: v2(72.94,146.41) 70.59,148.76 70.59,150.83 R1254.2 ; v1(126.4,21.97) 126.75,22.33 129.81,22.33 R79750.1 ; v1(84.46,124.66) 80.93,124.66 73.57,132.03 69.32,132.03 v1(68.26,133.1) ; v6(87.41,227.25) 87.49,227.25 89.84,224.9 89.84,214.38 89.82,214.37 v4(89.82,213.8) 89.82,212.02 87.49,209.68 v2(84.67,209.68) ; v2(128.51,225.4) 128.91,224.99 128.91,221.96 R1743.1 ; v2(113.11,57.71) 113.11,59.24 112.57,59.78 R391.1 112.39,61.21 112.39,64.48 111.64,65.23 ; 45.91,8.41 46.1,8.41 46.68,8.99 46.68,10.19 46.03,10.85 44.83,10.85 R378.2 ; 45.91,8.41 46.41,7.91 R702.1 ; 45.91,8.41 v2(45.9,8.41) ; 111.64,65.23 111.92,65.51 111.92,66.52 111.84,66.6 111.84,68.53 112.71,69.39 119.18,69.39 v2(120.25,68.33) ; 111.64,65.23 v2(111.56,65.23) ; v1(108.54,6.78) 108.36,6.96 v1(108.36,12.93) ; R549.1 PR5010.1 158.29,133.4 162.61,133.4 165.4,136.19 171.96,136.19 172.01,136.25 175.8,136.25 ; v2(91.09,125.18) 91.09,124.84 91.83,124.1 93.15,124.1 93.96,124.92 93.96,126.44 v1(95.26,127.74) 96.12,126.87 96.12,125.17 100.69,120.6 v2(100.82,120.6) ; v6(44.59,139.88) 44.59,141.21 45.91,142.52 45.91,156.31 42.45,159.77 42.45,163.96 v6(41.14,165.28) 40.2,166.22 32.18,166.22 31.35,167.04 25.29,167.04 24.9,167.43 21.6,167.43 21.04,166.88 v4(20.99,166.88) 20.99,166.82 20.49,166.33 20.49,163.98
  vias: v2(169.78,86.23) v4(136.02,212.67) v4(136.99,61.93) v4(162.9,198.83) v4(171.36,88.44) v4(176.84,140.72) v6(169.91,87.15) v6(170.62,86.21) v6(170.83,87.18)
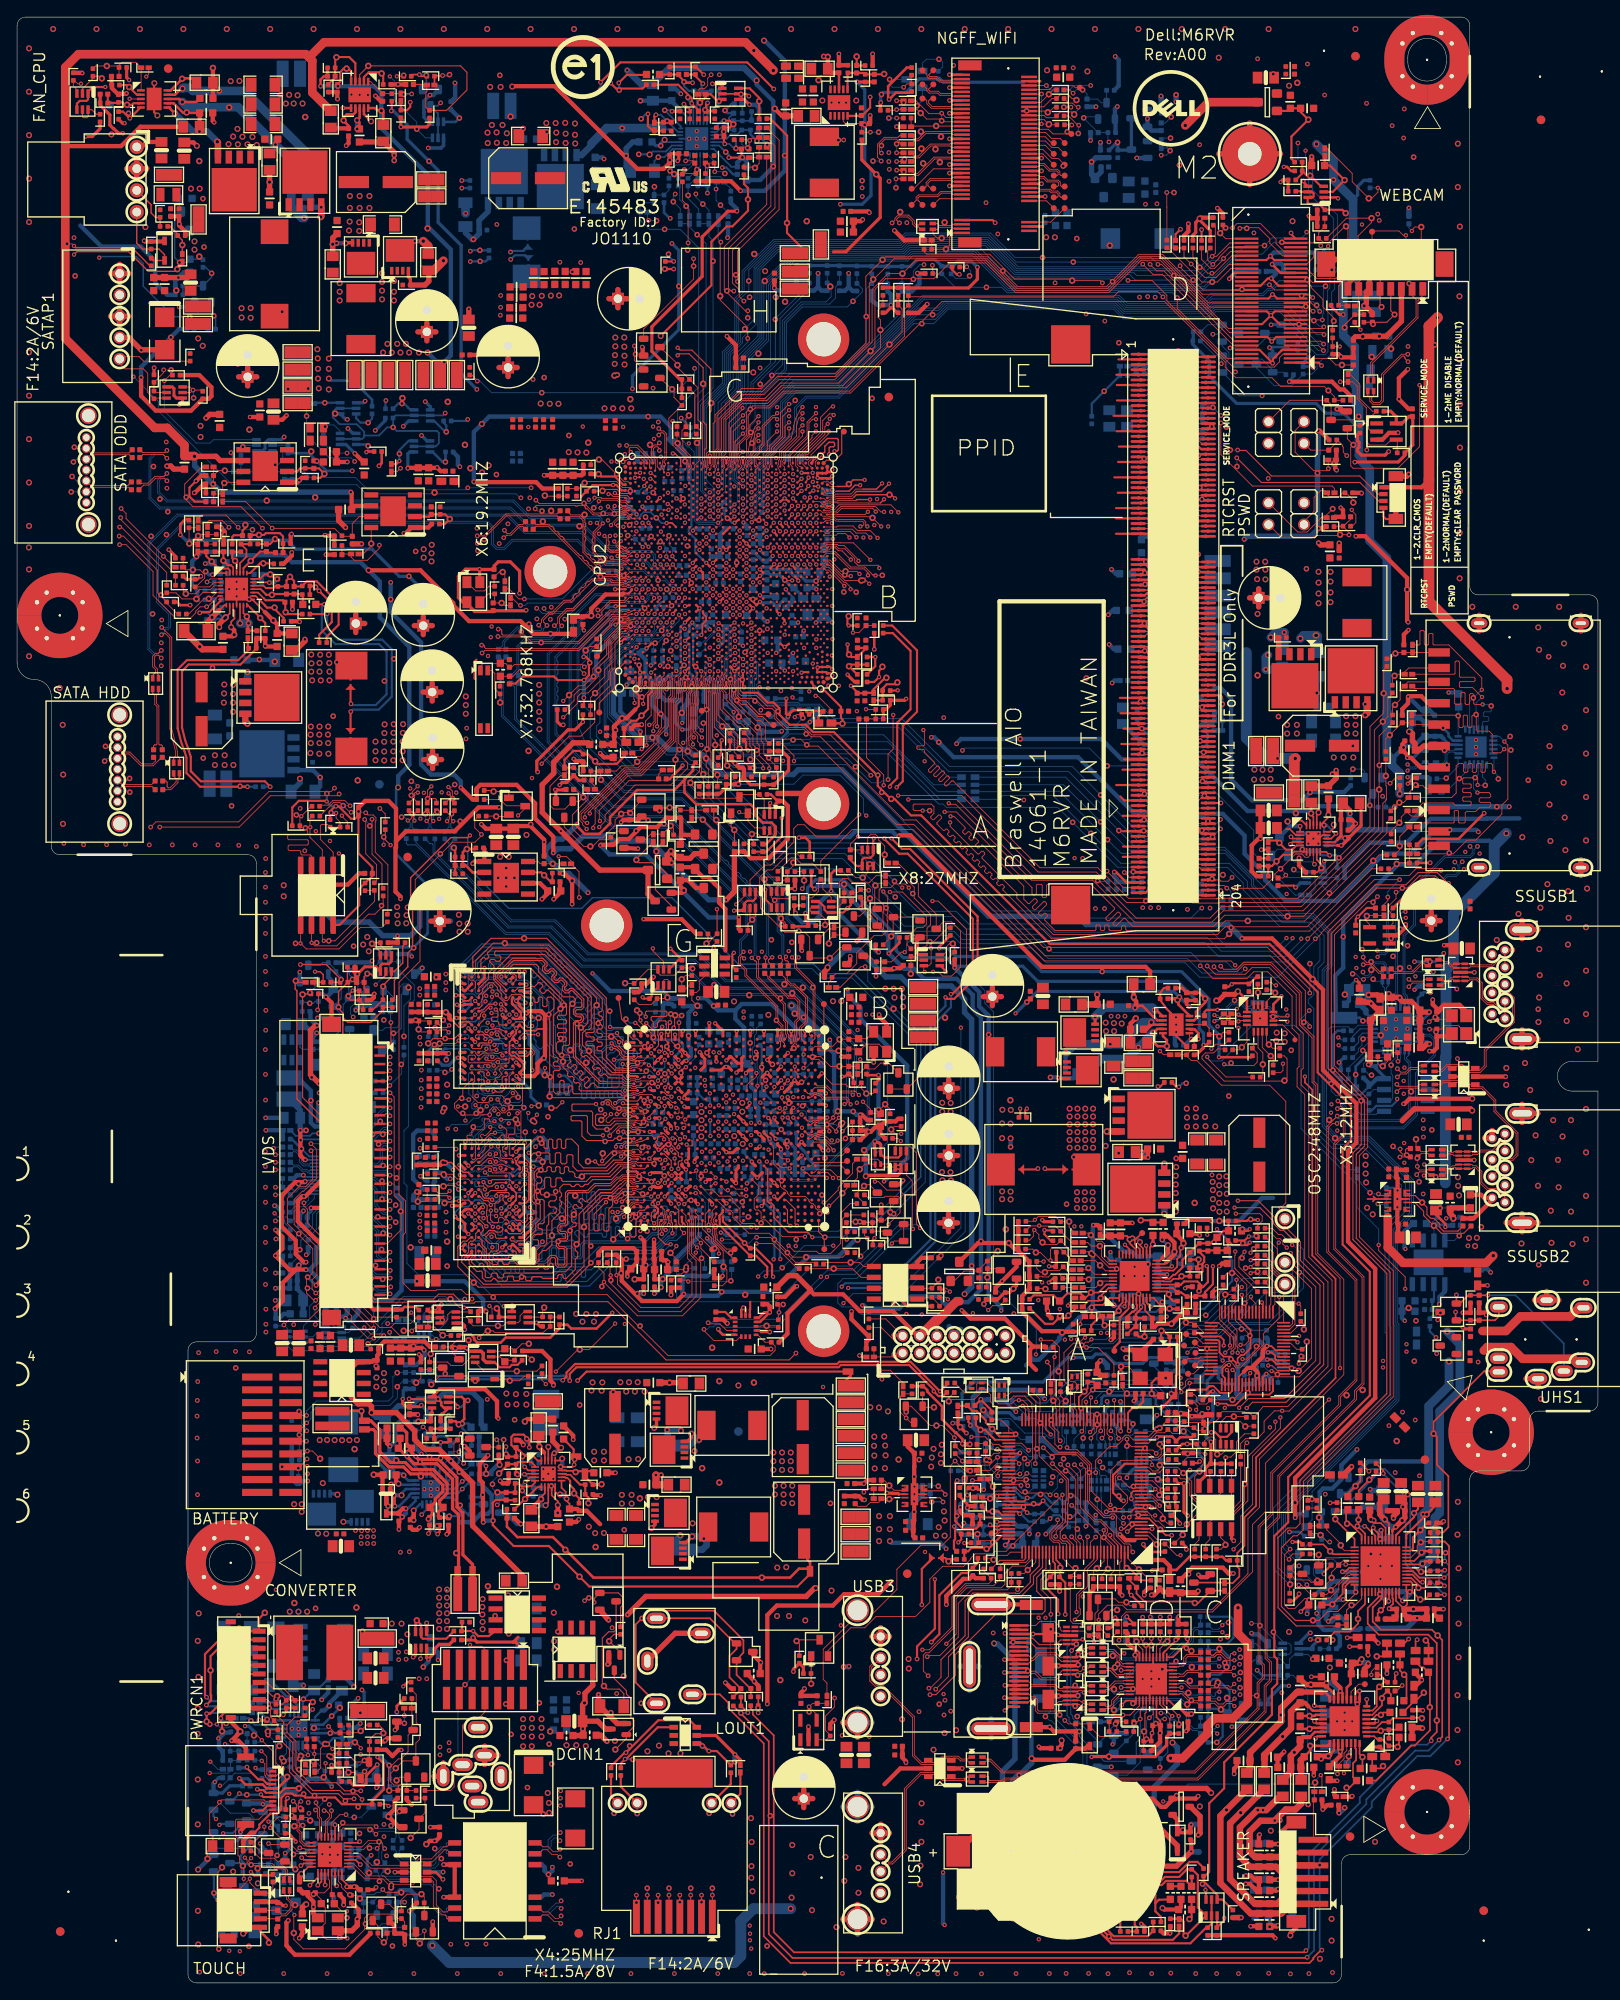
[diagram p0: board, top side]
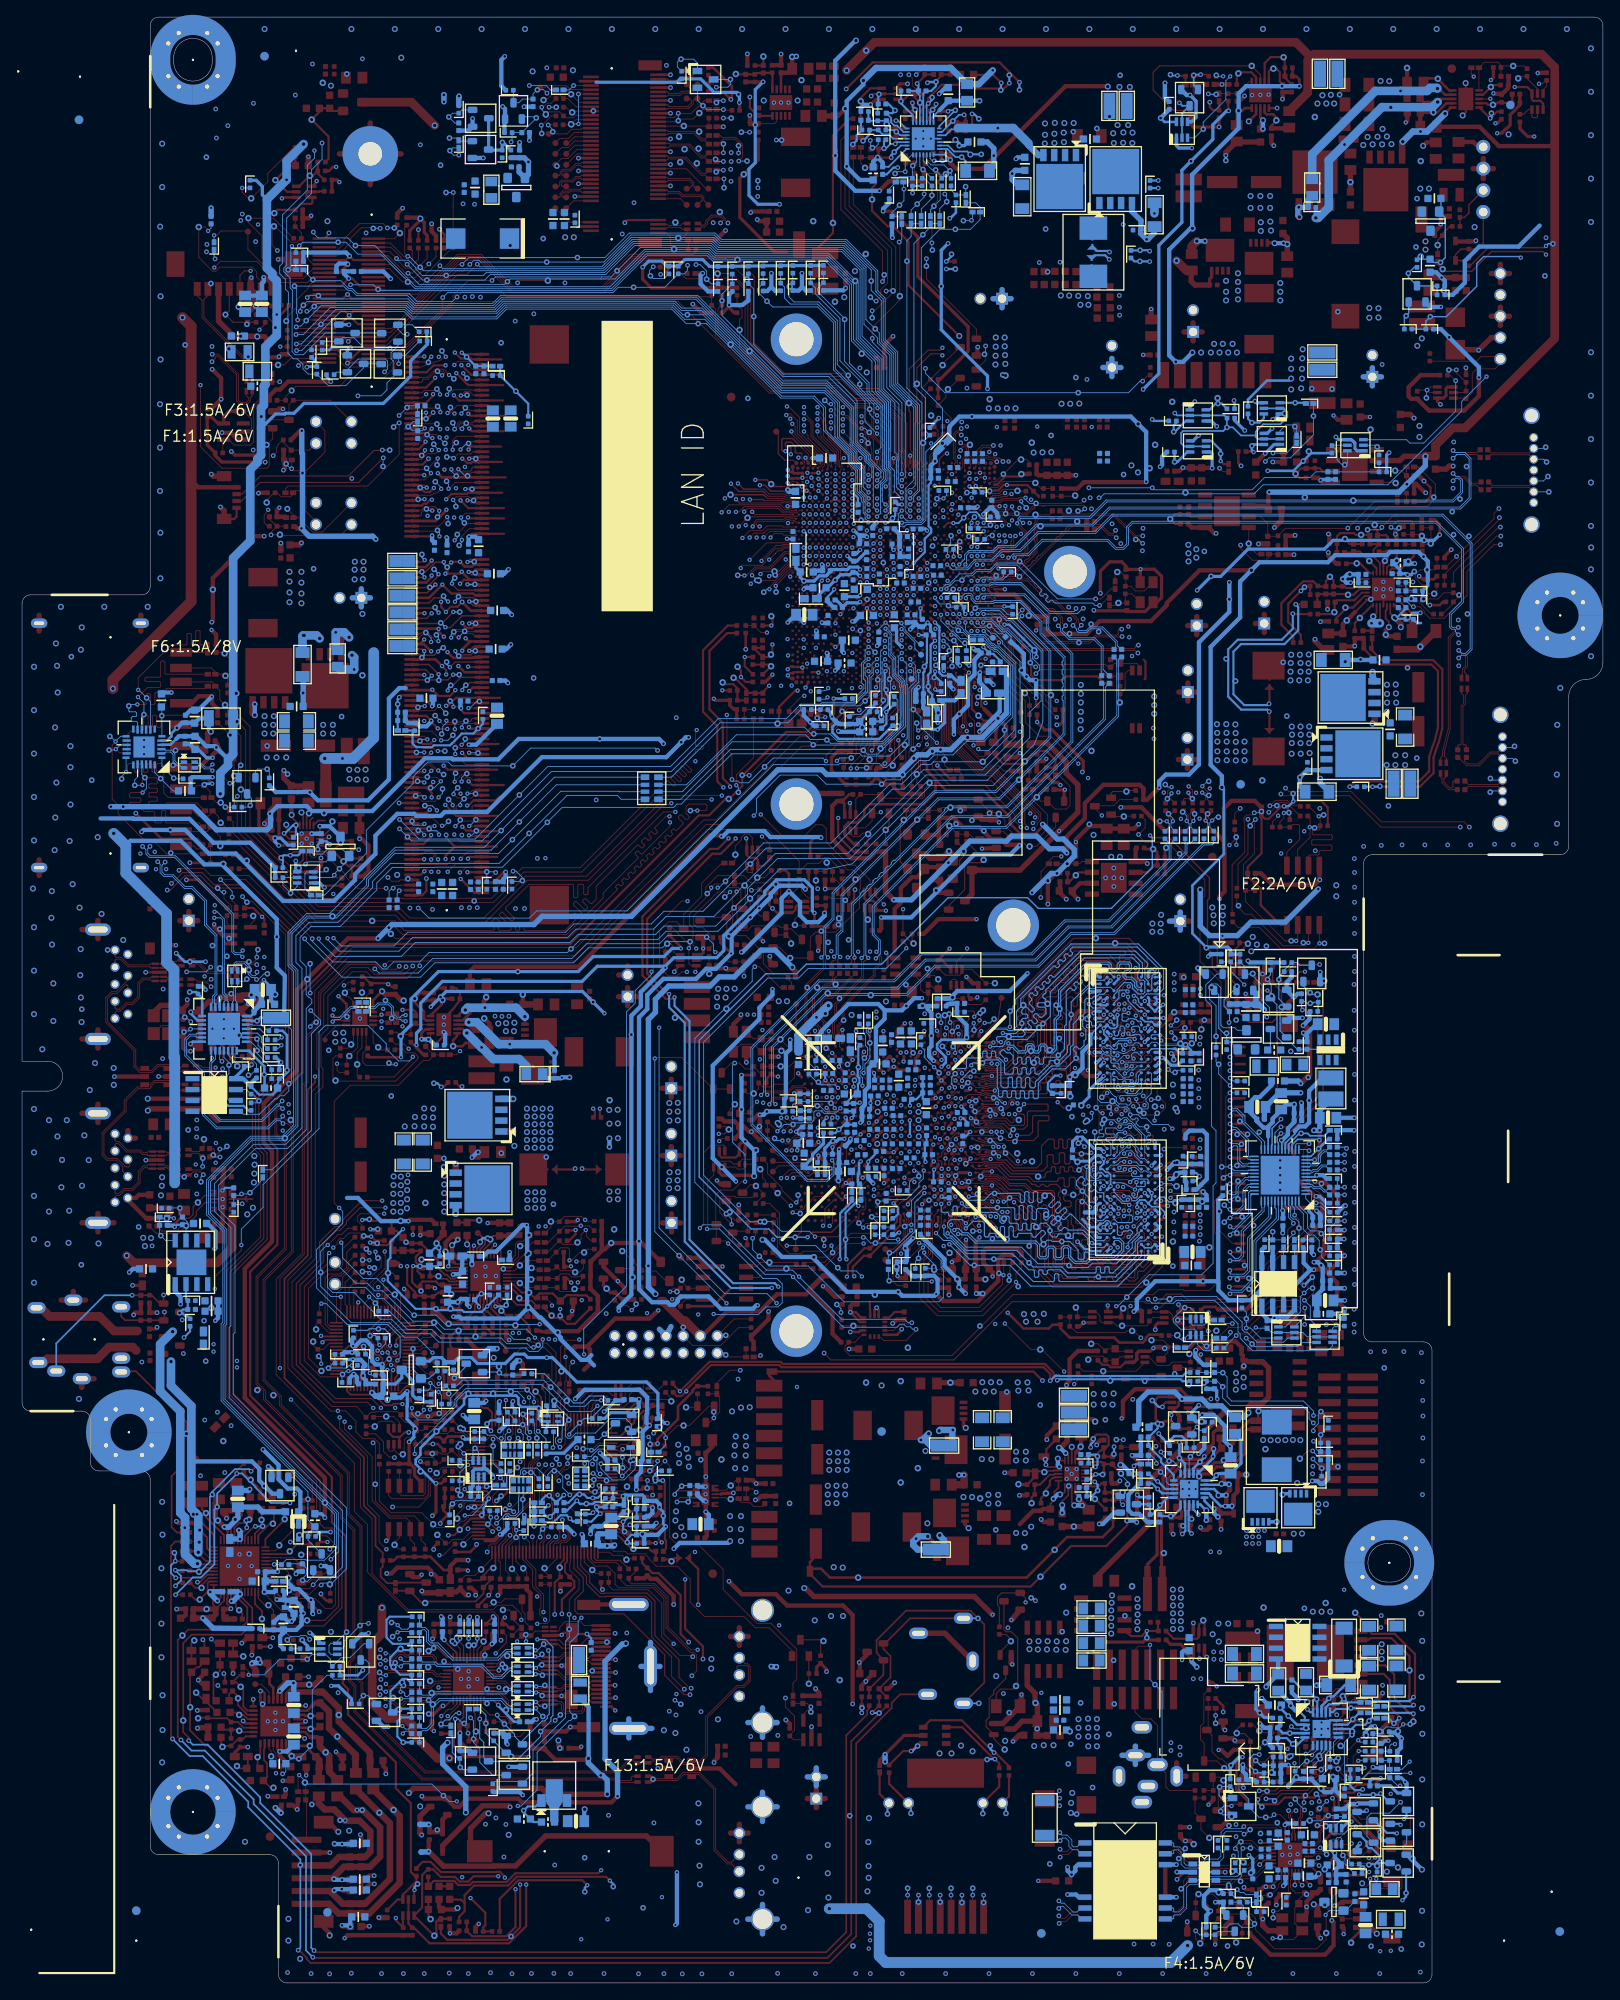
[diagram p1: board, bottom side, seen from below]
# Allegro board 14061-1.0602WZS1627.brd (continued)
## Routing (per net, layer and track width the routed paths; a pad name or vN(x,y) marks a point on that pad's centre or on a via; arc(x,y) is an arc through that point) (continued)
SB3V_5V_PG: length 393.9
  TOP w0.102: R79949.2 15.4,223.32 v1(15.12,223.04) ; R1689.1 21.62,177.37 19.62,175.37 19.62,173.68 20.57,172.73 26.19,172.73 v2(28.71,170.21)
  L3 w0.127: v2(38.62,178.99) 39.14,178.47 39.92,178.47 41.66,176.73 47.66,176.73 51.44,180.52 51.44,199.76 50.62,200.58 50.62,216.74 53.81,219.93 54.04,220.15 76.23,220.15 77.99,218.39 85.76,218.39 87.93,216.22 87.93,208.7 90,206.63 97,206.63 98.28,207.91 98.28,209.45 98.86,210.02 v2(98.89,210.02) ; v2(157.67,203.73) 157.21,203.28 157.21,197.23 156.77,196.8 156.77,192.13 157.47,191.43 157.47,177.99 157.83,177.63 157.83,171.61 161.3,168.14 161.3,144 161.23,143.94 161.23,142.22 160.22,141.2 160.22,140.01 160.31,139.92 160.31,135.22 153.03,127.94 153.03,115.54 151.25,113.77 v2(151.21,113.77) ; v2(28.71,170.21) 28.71,170.69 23.66,175.74 23.66,182.8 21.41,185.04 21.41,186.51 20.47,187.46 20.47,188.89 14.51,194.84 14.51,200.83 12.49,202.85 12.49,203.11 9.39,206.21 9.39,218.25 12.35,221.21 12.35,222.95 12.8,223.39 14.77,223.39 v1(15.12,223.04)
  L4 w0.127: v2(28.71,170.21) 37.5,178.99 v2(38.62,178.99) ; v2(157.67,203.73) 157.65,203.73 153.04,208.34 137.04,208.34 135.39,209.99 119.9,209.99 119.69,209.78 99.13,209.78 v2(98.89,210.02)
  BOTTOM w0.102: R1836.1 37,178.99 v2(38.62,178.99) ; v4(98.89,210.86) 98.89,210.77 98.89,210.77 v2(98.89,210.02) ; v2(151.21,113.77) 150.07,112.62 150.07,112.14 151.14,111.07 151.14,99.75 155.75,95.14 R1778.1
SB3V_5V_PG_L: length 3.5
  BOTTOM w0.102: R1836.2 35.85,181.89 v4(36.05,182.09) 36.23,182.28 37.09,182.28 37.8,181.56 Q1232.3
SB3V_D: length 3.2
  TOP w0.305: R1789.2 40.95,179.17 v1(40.88,179.1)
  BOTTOM w0.305: v1(40.88,179.1) 41.08,179.3 v4(41.08,179.83) 40.92,179.99 Q1232.6
SB3V_EN: length 9
  TOP w0.102: v2(159.24,91.16) 159.39,91.31 U54.5 ; U54.3 159.51,92.11 v2(159.32,92.3)
  BOTTOM w0.102: v2(159.24,91.16) 159.33,91.07 PR5258.2 C1700.1 159.48,92.14 v2(159.32,92.3) 158.48,92.3 v4(158.33,92.46) 158.31,92.46 157.28,93.48 157.28,93.6 156.83,94.06 R1778.2
SB5V: length 911.9
  TOP w0.203: PU5001.12 154.22,133.48 154.53,133.79
  TOP w0.305: R1687.1 92.75,133.49 92.25,134 v2(91.5,134)
  TOP w0.381: 154.53,133.79 154.93,134.2 154.93,136.09 PC5003.1
  TOP w0.508: CN2.1 164.36,174.99 165.22,175.84 ; PR4701.2 132.59,118.36 132.06,118.88 119.92,118.88 104.54,134.26 103.28,134.26 v1(103.17,134.15) ; R352.1 136.2,8.86 R673.1 134.22,8.59 v6(134.04,8.76) ; PC5003.1 154.93,137.78 PR5011.2 155.99,137.21 v2(155.99,136.8)
  TOP w0.635: PR4528.1 32.65,155.96 33.69,157 v2(33.69,157.2)
  TOP w1.27: v6(166.23,194.84) 165.22,193.84 165.22,161.61 174.37,152.46 v6(174.37,151.43)
  L3 w0.508: v2(33.69,157.2) 31.25,159.64 31.25,166.85 30.72,167.39 30.58,167.25 25.76,167.25 24.73,166.22 22.28,166.22 22.13,166.06 v2(22.02,166.06) ; v2(110.78,53.8) 112.12,53.8 114.41,56.08 118.65,56.08 v2(121.01,58.45) 121.37,58.09 122.46,58.09 122.79,58.42 135.57,58.42 136.28,59.13 139.48,59.13 139.96,59.61 145.79,59.61 157.97,71.8 157.97,72.69 159.99,74.71 159.99,82.31 164.55,86.87 v2(164.55,92.3) ; v2(91.5,134) 90.89,134 85.91,138.98 85.91,142.69 87.67,144.45 104.83,144.45 104.88,144.4 107.55,144.4 108.13,144.98 v2(109.94,144.98)
  L3 w0.635: v6(11.04,216.27) 11.04,207.08 14.14,203.97 14.14,203.54 16.29,201.39 16.29,195.5 22.12,189.67 22.12,188.14 26.45,183.81 26.45,175.49 31,170.94 31,167.67 30.72,167.39
  L3 w1.27: v6(90.53,8.69) 94.09,5.13 104.05,5.13 107.7,8.79 134.02,8.79 v6(134.04,8.76) ; v6(48.6,4.37) 47.71,4.37 46.57,5.51 41.79,5.51 40.46,4.18 30.44,4.18 25.28,9.33 v6(25.28,13.02)
  L4 w0.635: v2(71.4,223.77) 57.34,223.77 57.33,223.79 54.6,223.79 54.59,223.77 52.48,223.77 51.24,222.53 v2(51.24,222.3) 51.13,222.41 46.91,222.41 45.55,223.77 13.27,223.77 11.04,221.55 v6(11.04,216.27)
  L4 w1.016: v6(166.23,194.84) 166.23,209.14 151.77,223.6 150.63,223.6 147.22,227.01 89.79,227.01 86.55,223.77 v6(86.55,222.58)
  L4 w1.27: v6(134.04,8.76) 134.04,10.57 145.93,22.45 145.93,26.63 150.77,31.47 150.77,33.16 152.51,34.9 152.51,37.37 154.49,39.35 154.49,44.07 153.98,44.58 153.98,48.92 152.05,50.85 152.05,59.13 155.02,62.1 155.02,62.87 164.18,72.02 164.18,84.01 168.44,88.27 168.44,91.83 v6(168.74,92.14) ; v6(174.37,151.43) 175.5,150.3 175.5,138.51 v2(174.61,137.62) 174.28,137.29 v6(174.28,134.49)
  BOTTOM w0.508: v2(155.99,136.8) 155.11,137.68 151.68,137.68 151.11,137.11 144.02,137.11 137.84,143.28 134.69,143.28 134.57,143.15 129.27,143.15 126.88,145.54 v4(117.41,145.54) 110.46,145.54 109.94,145.02 v2(109.94,144.98) ; v2(110.78,53.8) 111.13,53.44 R648.2 ; v1(103.17,134.15) 102.99,134.15 102.37,134.77 98.14,134.77 97.43,134.06 91.56,134.06 v2(91.5,134) ; PR4530.1 22.83,166.06 v2(22.02,166.06) ; 172.86,133.08 172.3,133.63 166.43,133.63 163.66,130.86 161.61,130.86 155.19,124.44 v4(155.19,122.4) 155.19,118.78 154.25,117.84 R157.1 ; v6(86.55,222.58) 86.55,222.11 88.5,220.16 v4(88.5,212.53) 88.5,212.48 86.96,210.95 PR4430.1 ; v2(51.24,222.3) 51.26,222.28 51.26,220.61 R1788.1
  BOTTOM w0.635: v2(155.99,136.8) 155.92,136.74 155.92,135.34 156.35,134.91 162.23,134.91 164.94,137.62 v4(173.16,137.62) v2(174.61,137.62)
  BOTTOM w0.762: v6(86.55,222.58) 85.07,224.05 76.31,224.05 PR4428.1 73.03,222.15 v2(71.4,223.77)
  BOTTOM w1.27: v6(48.6,4.37) 50.58,2.39 83.93,2.39 84.69,3.15 84.69,7.21 86.16,8.69 v6(90.53,8.69) ; 167.14,93.6 167.14,108.23 167.22,108.31 167.22,118.52 168.08,119.39 168.08,125.08 172.86,129.85 172.86,133.08 v6(174.28,134.49)
  vias: v4(121.19,59.21) v4(166.02,94.31) v6(168.62,94.26) v6(168.64,93.26)
SB5V_D: length 3.5
  BOTTOM w0.305: v4(51.76,218.19) 51.3,217.73 49.93,217.73 Q1233.6
  BOTTOM w0.508: R1788.2 50.76,219.19 v4(51.76,218.19)
SCALAR_SIO_PU: length 86.8
  TOP w0.254: v2(117.08,46.03) 117.24,46.19 R1870.2
  TOP w0.305: v2(136.56,58.45) 135.92,58.45 R313.2
  TOP w0.381: v2(136.56,58.45) 136.56,55.08 v2(136.98,54.66)
  TOP w0.508: v2(108.75,44.27) 108.75,45.28 110.73,47.27 111.45,47.27 R1867.2 112.16,47.35 R1868.2 ; R79705.2 R79704.2 121.98,45.85 v2(122,45.82)
  TOP w0.584: R79691.2 134.17,45.73 R285.2 133.69,46.05 133.03,45.39 v2(132.75,45.39)
  TOP w0.635: R79691.2 136.06,45.73 R289.1 138.01,45.64 v2(138.21,45.85)
  L3 w0.508: v2(136.98,54.66) 137.2,54.66 138.88,52.98 138.88,46.59 138.21,45.92 v2(138.21,45.85)
  L3 w0.635: v2(117.08,46.03) 117.1,46.05 121.78,46.05 v2(122,45.82)
  L4 w0.635: v2(108.75,44.27) 110.09,45.62 116.66,45.62 v2(117.08,46.03) ; v2(132.75,45.39) 132.75,45.55 131.93,46.37 127.2,46.37 125.15,44.32 123.93,44.32 122.44,45.82 v2(122,45.82)
  BOTTOM w0.305: R79945.2 123.69,64.9 123.49,65.1 RN7.2 124.24,65.69 124.54,65.99 ; 124.54,65.99 124.19,66.34 RN7.1 123.49,67.4 R669.1 ; 124.54,65.99 124.54,67.21 v4(124.53,67.22) 124.7,67.39 126.56,67.39 126.91,67.73 126.91,68.43 127.2,68.72 132.9,68.72 133.27,68.35 133.27,67.7 138.37,62.6 138.37,61.81 138.94,61.24 138.94,60.72 136.67,58.45 v2(136.56,58.45)
SD_CD_BD: length 8.7
  TOP w0.102: MEMCD1.11 164.92,133.03 164.56,132.68 163.43,132.68 R1696.1 R80105.1 R1832.1 161.56,131.04 v3(161.45,130.92) 160.88,130.35 R80109.2
SD_CD_BD_CPU: length 119.8
  TOP w0.102: v1(105.98,137.16) 104.99,137.16 104.86,137.29 104.86,137.79 104.99,137.92 106.99,137.92 107.29,137.62 107.29,136.83 106.92,136.46 106.92,136.32 107.14,136.1 107.28,136.1 107.82,136.64 108,136.64 108.18,136.46 108.18,136.28 107.64,135.74 107.64,135.6 108.39,134.84 108.54,134.84 108.69,134.99 108.83,134.99 109.05,134.78 109.05,134.63 108.9,134.48 108.9,134.34 109.11,134.12 109.26,134.12 109.41,134.27 109.55,134.27 109.77,134.06 109.77,133.91 109.62,133.76 109.62,133.62 109.83,133.4 109.98,133.4 110.13,133.55 110.27,133.55 110.49,133.34 110.49,133.2 110.34,133.05 110.34,132.9 110.55,132.69 110.69,132.69 110.84,132.84 110.99,132.84 111.2,132.62 111.2,132.48 111.05,132.33 111.05,132.18 111.27,131.97 111.41,131.97 111.56,132.12 111.71,132.12 111.92,131.9 111.92,131.76 111.77,131.61 111.77,131.46 111.99,131.25 112.13,131.25 112.28,131.4 112.43,131.4 112.64,131.18 112.64,131.04 112.49,130.89 112.49,130.74 112.71,130.53 112.85,130.53 113,130.68 113.15,130.68 113.36,130.46 113.36,130.32 113.21,130.17 113.21,130.03 113.43,129.81 113.57,129.81 113.72,129.96 113.86,129.96 114.08,129.75 114.08,129.6 113.93,129.45 113.93,129.31 114.14,129.09 114.29,129.09 114.44,129.24 114.58,129.24 114.8,129.03 114.8,128.88 114.65,128.73 114.65,128.59 114.86,128.37 115.01,128.37 115.16,128.52 115.3,128.52 115.52,128.31 115.52,128.16 115.37,128.01 115.37,127.87 121.06,122.17 141.28,122.17 v3(141.84,122.73) 142.17,123.06 151.24,123.06 158.53,130.35 R80109.1 ; CPU2.K3 75.71,153 75.42,152.7 75.42,152.42 75.51,152.33 75.51,152.33 75.51,152.32 75.51,152.05 75.51,152.04 75.51,151.99 75.21,151.69 75.21,151.69 75.17,151.65 75.17,150.86 75.22,150.81 75.22,150.5 74.95,150.23 74.95,147.15 74.9,147.1 v1(74.9,147.02)
  L4 w0.127: v1(105.98,137.16) 105.98,137.46 101.59,141.85 92.61,141.85 91.32,140.56 80.41,140.56 77.68,143.29 75.47,145.5 75.47,146.06 75.37,146.16 75.37,146.37 74.9,146.84 v1(74.9,147.02)
  BOTTOM w0.102: v4(106.78,137.15) 105.98,137.15 v1(105.98,137.16)
SD_CD_BD_IC: length 23.2
  TOP w0.102: v1(174.05,145.24) 174.45,144.83 174.45,138.51 173.76,137.81 173.76,136.78 170.68,133.71 169.68,133.71 168.08,132.11 R80105.2
  BOTTOM w0.102: SU1.13 173.46,145.85 174.05,145.26 v1(174.05,145.24) 174.65,145.84 v4(174.72,145.84)
SD_CLK_BD: length 8.6
  TOP w0.102: R80107.2 160.17,145.53 v3(160.64,146) 162.07,147.43 SC6.1 R80103.2 163.44,147.22 MEMCD1.5
SD_CLK_BD_CPU: length 120.1
  TOP w0.089: CPU2.F2 73.2,152.43 73.2,151.87
  TOP w0.102: 73.2,151.87 72.93,151.6 v1(72.93,151.26) ; R80107.1 160.18,143.17 v3(160.18,141.22) 160.18,140.07 160.26,139.99 160.26,138.43 159.82,138 159.82,134.77 150.49,125.44 141.15,125.44 139.82,124.1 130.78,124.1 125.87,129.01 118.73,129.01 109.84,137.9 109.15,137.9 v1(109.02,138.02)
  L4 w0.127: v1(109.02,138.02) 107.77,138.02 106.97,138.82 106.97,139 107.03,139.06 107.03,139.24 106.76,139.51 106.58,139.51 106.52,139.45 106.34,139.45 106.07,139.72 106.07,139.9 106.13,139.96 106.13,140.14 105.86,140.41 105.68,140.41 105.62,140.35 105.44,140.35 105.17,140.62 105.17,140.8 105.23,140.86 105.23,141.04 104.96,141.31 104.78,141.31 104.72,141.25 104.54,141.25 104.28,141.52 104.28,141.7 104.33,141.76 104.33,141.94 104.07,142.21 103.89,142.21 103.83,142.15 103.65,142.15 103.38,142.42 103.38,142.6 103.44,142.65 103.44,142.83 103.17,143.1 102.99,143.1 102.93,143.04 102.75,143.04 102.34,143.45 92.06,143.45 90.99,142.39 88.76,142.39 88.54,142.61 86.24,142.61 85.72,142.09 81.29,142.09 78.39,144.99 78.39,145.4 77.41,146.38 77.41,146.81 76.51,147.71 76.51,147.89 76.88,148.27 76.88,148.45 76.7,148.63 76.53,148.63 76.15,148.25 75.97,148.25 75.79,148.43 75.79,148.61 76.1,148.92 76.1,149.1 75.92,149.28 75.74,149.28 75.43,148.97 75.25,148.97 75.07,149.15 75.07,149.33 75.38,149.64 75.38,149.82 75.2,150 75.02,150 74.71,149.69 74.54,149.69 72.97,151.26 v1(72.93,151.26)
SD_CLK_BD_IC: length 22.5
  TOP w0.102: R80103.1 168.63,148.32 168.73,148.22 168.73,146.99 168.83,146.89 169.14,146.89 169.24,146.99 169.24,148.22 169.34,148.32 169.64,148.32 169.74,148.22 169.74,146.99 169.85,146.89 170.15,146.89 170.25,146.99 170.25,148.22 170.35,148.32 170.66,148.32 170.76,148.22 170.76,146.59 170.9,146.46 172.27,146.46 172.63,146.1 172.63,144.04 172.75,143.92 173.59,143.92 v1(174.02,144.35)
  BOTTOM w0.102: SU1.15 173.5,144.85 174,144.35 v1(174.02,144.35) 174.13,144.24 v4(174.81,144.24)
SD_CMD_BD: length 7.4
  TOP w0.102: R80108.2 161.72,138.1 v3(161.75,138.1) 162.25,138.1 R80104.2 163,138.85 163,139.4 163.69,140.08 R1656.2 164.5,140.08 164.86,139.72 MEMCD1.2
SD_CMD_BD_CPU: length 121.1
  TOP w0.089: CPU2.D2 72.45,152.68 72.45,151.95 72.18,151.67
  TOP w0.102: R80108.1 160.31,135.8 160.31,134.54 150.55,124.79 v3(148.67,124.79) 148.55,124.92 141.31,124.92 140.02,123.62 130.58,123.62 129.64,124.56 129.5,124.56 128.62,123.68 128.44,123.68 128.26,123.86 128.26,124.04 129.14,124.91 129.14,125.06 128.92,125.27 128.78,125.27 127.78,124.27 127.6,124.27 127.42,124.45 127.42,124.63 128.42,125.63 128.42,125.78 125.67,128.53 120.57,128.53 120.47,128.42 120.47,127.09 120.36,126.98 120.07,126.98 119.96,127.09 119.96,128.42 119.86,128.53 119.38,128.53 119.28,128.42 119.28,127.44 119.15,127.32 118.89,127.32 118.77,127.44 118.77,128.15 109.92,137.01 v1(108.55,137.01) ; 72.18,151.67 72.17,151.66 72.17,150.23 72.26,150.14 v1(72.26,149.75)
  L4 w0.127: v1(108.55,137.01) 108.04,137.01 102.1,142.95 92.27,142.95 90.9,141.58 80.83,141.58 76.96,145.45 76.96,146.11 76.91,146.17 76.91,146.6 73.44,150.07 72.58,150.07 v1(72.26,149.75)
SD_CMD_BD_IC: length 21.6
  TOP w0.102: v1(172.82,141.68) 172.68,141.83 172.68,142.49 172.5,142.67 171.91,142.67 171.81,142.57 171.81,141.76 171.69,141.63 171.43,141.63 171.31,141.76 171.31,142.57 171.2,142.67 170.9,142.67 170.8,142.57 170.8,141.76 170.67,141.63 170.42,141.63 170.29,141.76 170.29,142.57 170.19,142.67 169.88,142.67 169.78,142.57 169.78,141.76 169.65,141.63 169.4,141.63 169.27,141.76 169.27,142.57 169.17,142.67 168.69,142.67 168.41,142.39 168.41,139.22 167.88,138.68 R80104.1
  BOTTOM w0.102: v4(173.34,140.87) 173.34,141.16 v1(172.82,141.68) SU1.18
SD_DATA0_B: length 20.6
  TOP w0.102: v1(171.51,149.58) 170.57,149.58 170.47,149.68 170.47,150.72 170.34,150.85 170.09,150.85 169.96,150.72 169.96,149.68 169.86,149.58 169.55,149.58 169.45,149.68 169.45,150.88 169.32,151 169.07,151 168.94,150.88 168.94,149.68 168.84,149.58 168.36,149.58 168.23,149.71 168.23,151.31 168.1,151.43 163.55,151.43 R79982.2
  BOTTOM w0.102: v1(171.51,149.58) 172.38,149.58 172.51,149.45 v4(172.51,149.4) 172.51,148.82 172.41,148.72 171.71,148.72 171.61,148.62 171.61,148.23 171.69,148.16 172.09,148.16 172.22,148.03 172.22,147.73 172.09,147.6 171.61,147.6 171.48,147.47 SU1.11
SD_DATA0_BD: length 8.3
  TOP w0.102: R80057.2 160.97,149.25 v3(161.25,149.53) 161.86,150.14 161.86,151.19 R79982.1 162.38,151.83 162.77,152.22 MEMCD1.7
SD_DATA0_CPU: length 119.2
  TOP w0.102: R80057.1 159.39,145.88 v3(159.39,139.62) 159.32,139.55 159.32,134.94 150.87,126.49 150.87,126.49 150.29,125.92 140.95,125.92 139.62,124.59 130.98,124.59 126.07,129.49 118.93,129.49 109.96,138.46 v1(104.3,138.46) ; v1(74.45,146.47) 74.45,147.17 74.75,147.47 74.75,150.41 74.96,150.62 74.96,151.73 75,151.77 75,151.78 75.13,151.91 75.13,152.13 CPU2.J1
  L4 w0.127: v1(74.45,146.47) 74.49,146.42 74.49,146.32 74.96,145.85 74.96,144.71 79.62,140.06 91.53,140.06 92.82,141.35 98.53,141.35 100.45,139.42 103.26,139.42 104.22,138.46 v1(104.3,138.46)
SD_DATA1_B: length 20.6
  TOP w0.102: R79981.2 168.18,153.11 168.28,153.21 168.28,154.53 168.4,154.66 168.66,154.66 168.79,154.53 168.79,152.86 168.89,152.76 170.49,152.76 170.62,152.63 170.62,152.38 170.49,152.25 168.89,152.25 168.79,152.15 168.79,151.67 168.89,151.56 170.31,151.56 v1(171.43,150.44)
  BOTTOM w0.102: v1(171.43,150.44) 170.74,149.75 170.74,148.4 v4(170.74,148.39) 170.98,148.16 SU1.10
SD_DATA1_BD: length 7
  TOP w0.102: R80056.2 160.94,152.68 v3(161.2,152.93) 161.37,153.11 R79981.1 162.38,153.38 162.84,153.85 MEMCD1.8
SD_DATA1_CPU: length 123
  TOP w0.102: R80056.1 160.94,150.8 160.41,150.27 160.41,148.16 v3(159.82,147.57) 158.83,146.58 158.83,135.14 150.38,126.69 150.38,126.69 150.09,126.4 140.75,126.4 140.71,126.36 140.61,126.36 140.59,126.34 138.21,126.34 138.19,126.36 137.54,126.36 137.5,126.4 137.44,126.41 129.83,126.41 126.27,129.97 119.5,129.97 110.53,138.94 103.13,138.94 v1(103.11,138.91) ; CPU2.J3 74.85,152.56 74.85,151.91 74.8,151.86 74.8,151.85 74.76,151.81 74.76,150.77 74.54,150.55 74.54,147.58 74.16,147.19 v1(73.98,147.19)
  L4 w0.127: v1(73.98,147.19) 73.98,147.01 73.85,146.87 73.85,145.85 74.46,145.24 74.46,143.95 78.85,139.55 91.74,139.55 93.03,140.84 98.32,140.84 100.24,138.91 v1(103.11,138.91)
SD_DATA2_B: length 22
  TOP w0.102: v1(170.9,139.27) 172.25,139.27 172.45,139.06 172.45,138.81 172.3,138.66 171.23,138.66 171.1,138.53 171.1,138.25 171.23,138.13 172.35,138.13 172.45,138.02 172.45,137.69 172.3,137.54 171.18,137.54 170.7,137.06 169.63,137.06 169.46,136.89 169.46,135.83 169.35,135.71 168.79,135.71 168.69,135.81 168.69,137.06 168.58,137.16 168.28,137.16 168.18,137.06 168.18,135.81 168.08,135.71 164.28,135.71 R79977.1
  BOTTOM w0.102: v1(170.9,139.27) 170.43,139.74 170.43,140.83 v4(170.62,141.02) 170.98,141.38 SU1.21
SD_DATA2_BD: length 7.8
  TOP w0.102: MEMCD1.9 163.33,134.72 162.94,135.12 R79977.2 161.81,134.12 v3(161.81,133.02) 161.81,132.6 R80055.2
SD_DATA2_CPU: length 120.3
  TOP w0.102: v1(73.65,144.81) 73.65,144.82 73.68,144.84 73.68,145.83 73.55,145.96 73.55,147.65 74.2,148.3 74.2,150.5 74.56,150.85 74.56,151.9 74.61,151.95 74.61,152.01 74.65,152.05 74.65,153.07 CPU2.H3 ; R80055.1 159.39,131.98 v3(158.71,131.29) 158.69,131.29 150.97,123.57 141.39,123.57 140.47,122.66 121.26,122.66 117,126.92 117,127.51 112.92,131.59 112.92,131.73 113.23,132.05 113.23,132.21 113.03,132.41 112.87,132.41 112.56,132.09 112.42,132.09 109.18,135.33 v1(109.18,135.78)
  L4 w0.127: v1(73.65,144.81) 73.85,144.61 73.85,143.84 78.64,139.04 91.95,139.04 93.24,140.33 96.48,140.33 97.27,139.54 97.45,139.54 98.02,140.11 98.2,140.11 98.38,139.93 98.38,139.75 97.81,139.19 97.81,139.01 97.99,138.83 98.17,138.83 98.74,139.4 98.92,139.4 99.09,139.22 99.09,139.04 98.53,138.47 98.53,138.29 98.7,138.11 98.88,138.11 99.45,138.68 99.63,138.68 99.81,138.5 99.81,138.32 99.24,137.75 99.24,137.57 100.16,136.65 100.8,136.65 100.93,136.78 100.93,137.46 101.06,137.59 101.31,137.59 101.44,137.46 101.44,136.78 101.56,136.65 101.82,136.65 101.94,136.78 101.94,137.46 102.07,137.59 102.33,137.59 102.45,137.46 102.45,136.78 102.58,136.65 104.5,136.65 105.23,135.93 109.03,135.93 v1(109.18,135.78)
SD_DATA3_B: length 20.6
  TOP w0.102: v1(170.92,140.16) 170.92,140.87 170.8,141 169.3,141 169.17,140.87 169.17,140.39 169.27,140.28 170.06,140.28 170.16,140.18 170.16,139.88 170.06,139.78 169.27,139.78 169.17,139.67 169.17,139.37 169.27,139.27 170.06,139.27 170.16,139.17 170.16,138.86 170.06,138.76 169.27,138.76 169.17,138.66 169.17,138.35 169.27,138.25 170.06,138.25 170.16,138.15 170.16,137.85 170.06,137.74 168.36,137.74 168.05,138.05 164.51,138.05 R79980.1
  BOTTOM w0.102: v1(170.92,140.16) 170.96,140.12 v4(171.81,140.12) 171.81,140.76 171.48,141.09 SU1.20
SD_DATA3_BD: length 7.8
  TOP w0.102: R80054.2 160.79,134.77 v3(161.75,135.74) 161.98,135.97 161.98,136.41 R79980.2 162.71,136.97 163.15,136.53 164.42,136.53 165.12,137.22 MEMCD1.1
SD_DATA3_CPU: length 120.5
  TOP w0.102: R80054.1 159.99,133.54 150.68,124.23 144.05,124.23 v3(144.03,124.26) 141.39,124.26 140.27,123.14 129.85,123.14 129.74,123.24 129.74,123.57 129.62,123.7 129.36,123.7 129.24,123.57 129.24,123.24 129.13,123.14 127.88,123.14 127.78,123.24 127.78,123.68 127.68,123.78 127.37,123.78 127.27,123.68 127.27,123.24 127.17,123.14 126.87,123.14 126.76,123.24 126.76,123.68 126.66,123.78 126.36,123.78 126.26,123.68 126.26,123.24 126.15,123.14 121.46,123.14 120.26,124.34 120.26,124.49 120.56,124.79 120.56,124.97 120.38,125.15 120.2,125.15 119.9,124.85 119.76,124.85 119.54,125.06 119.54,125.21 120.47,126.14 120.47,126.32 120.29,126.5 120.12,126.5 119.18,125.56 119.04,125.56 118.82,125.78 118.82,125.92 119.37,126.48 119.37,126.66 119.2,126.84 119.02,126.84 118.46,126.28 118.32,126.28 117.81,126.79 117.81,128.31 113,133.12 112.86,133.12 112.55,132.8 112.4,132.8 112.19,133.02 112.19,133.16 112.5,133.48 112.5,133.62 112.16,133.96 112.02,133.96 111.76,133.71 111.58,133.71 111.4,133.89 111.4,134.07 111.66,134.32 111.66,134.47 111.44,134.68 111.3,134.68 111.03,134.42 110.85,134.42 110.67,134.6 110.67,134.78 110.94,135.04 110.94,135.19 109.63,136.49 v1(109.24,136.49) ; v1(73.27,149.65) 73.3,149.68 73.3,150.48 73.95,151.13 73.95,152.55 CPU2.G2
  L4 w0.127: v1(73.27,149.65) 73.27,149.42 76.4,146.29 76.4,145.95 76.45,145.9 76.45,145.24 80.62,141.07 91.11,141.07 92.48,142.44 101.72,142.44 107.67,136.49 v1(109.24,136.49)
SD_WP_BD: length 6.4
  TOP w0.102: R80156.2 160.67,154.93 v3(161.3,155.55) 161.41,155.66 SC4.1 R80106.1 163.31,155.66 MEMCD1.10
SD_WP_BD_CPU: length 124.1
  TOP w0.102: v1(93.45,150.58) 93.53,150.51 93.76,150.51 95.23,149.03 R1780.2 ; v1(85.93,158.45) 86.29,158.8 CPU2.AM14 ; v1(106.05,146.58) 106.18,146.46 106.18,144.83 106.08,144.73 105.41,144.73 105.29,144.61 105.29,144.44 105.41,144.32 106.08,144.32 106.18,144.22 106.18,143.99 107.38,142.8 107.38,142.65 106.66,141.94 106.66,141.77 106.78,141.65 106.95,141.65 107.66,142.37 107.81,142.37 107.95,142.22 107.95,142.08 107.29,141.42 107.29,141.25 107.41,141.13 107.57,141.13 108.24,141.79 108.38,141.79 108.53,141.65 108.53,141.5 107.87,140.85 107.87,140.68 107.99,140.56 108.16,140.56 108.81,141.22 108.96,141.22 109.1,141.07 109.1,140.93 108.51,140.34 108.51,140.17 108.63,140.05 108.8,140.05 109.39,140.64 109.53,140.64 119.69,130.48 126.47,130.48 130.05,126.9 138.35,126.9 138.4,126.85 138.42,126.85 138.42,126.84 140.38,126.84 140.38,126.85 140.4,126.85 140.45,126.9 149.89,126.9 158.33,135.34 158.33,146.99 159.93,148.59 v3(159.93,150.88) 159.93,153.67 R80156.1
  L4 w0.127: v1(106.05,146.58) 104.45,148.18 103.82,148.18 101.3,150.7 94.33,150.7 94.14,150.51 93.56,150.51 93.49,150.58 v1(93.45,150.58) 93.34,150.7 92.53,150.7 90.55,152.67 89.96,152.67 89.34,153.29 89.34,153.88 88.41,154.81 88.41,155.97 v1(85.93,158.45)
SD_WP_BD_IC: length 22
  TOP w0.102: R80106.2 163.32,156.54 164.07,156.54 164.17,156.64 164.17,158.12 164.3,158.24 164.55,158.24 164.68,158.12 164.68,156.64 164.78,156.54 165.08,156.54 165.19,156.64 165.19,157.78 165.29,157.89 165.59,157.89 165.69,157.78 165.69,156.64 165.79,156.54 167.55,156.54 171.41,152.68 v1(171.41,151.28)
  BOTTOM w0.102: SU1.8 169.98,149.91 v4(170.42,150.36) 171.35,151.28 v1(171.41,151.28)
SDCARD_PWR_EN: length 5.8
  TOP w0.102: PR9810.2 78.96,137.22 PR9811.2 77.63,137.2 R80146.1 77.32,137.52 v3(76.36,137.52) 76.3,137.46 Q9642.C
SDMMC1_RCOMP: length 3.5
  TOP w0.102: CPU2.P13 v1(77.17,157.74)
  BOTTOM w0.102: v1(77.17,157.74) 76.52,157.09 76,157.09 v4(75.96,157.05) 75.53,156.62 R79788.1
SDMMC3_1P8_EN: length 10.8
  TOP w0.254: R80120.1 65.14,142.18 PR9806.2 64.06,143.1 65.11,144.15 65.86,144.15 R1661.2 66.8,143.77 v3(67.65,142.93) 67.95,142.63 70.17,142.63 71.11,143.56 R80153.1
SDMMC3_1P8_EN_R: length 11.6
  TOP w0.102: R80153.2 72.42,143.47 72.97,143.47 74.53,145.03 74.53,145.52 v3(74.34,145.71) 75.04,146.41 75.04,146.55 75.42,146.93 75.42,150.89 75.41,150.9 75.41,151.61 75.72,151.92 75.72,152.41 75.71,152.41 CPU2.K2
SDMMC3_PWR_EN: length 4.5
  TOP w0.102: PR9809.2 67.61,140.04 67.24,140.41 R80145.1 67.14,140.82 R80144.2 67.14,141.79 R80154.1 68.25,140.85 v3(68.33,140.77)
SDMMC3_PWR_EN_G: length 16.2
  TOP w0.102: PR9809.1 66.81,139.57 66.81,138.49 64.98,136.66 64.98,135.05 66.05,133.99 68.53,133.99 69.98,135.44 69.98,136.07 v3(70.69,136.78) 70.86,136.94 C12349.1 73.09,138.37 Q9642.B
SDMMC3_PWR_EN_R: length 15.7
  TOP w0.089: CPU2.L3 76.08,152.81 76.08,152.5 75.92,152.34 75.92,151.83 75.61,151.53 75.61,151.07 75.83,150.85
  TOP w0.102: 75.83,150.85 75.83,147.02 75.24,146.43 75.24,146.32 74.9,145.98 74.9,145.08 72.83,143.01 72.71,143.01 v3(72.58,142.88) 72.09,142.39 70.72,142.39 70.11,141.79 R80154.2
SDMMC_PWR_EN: length 10.6
  TOP w0.102: C12342.1 65.34,139.63 v3(66.25,138.72) 65.79,138.26 Q9635.B 64.1,137.34 62.79,137.34 62.36,137.77 62.36,140 63.65,141.3 PR9806.1
SDMMC_PWR_EN_G: length 9.8
  TOP w0.102: Q9636.G 70.18,134.76 R80150.1 69.18,133.76 68.13,133.76 67.34,132.97 v3(67.09,132.97) 66.32,132.97 64.04,135.25 64.04,136.35 Q9635.C
SDMMC_PWR_SEL: length 5.5
  TOP w0.102: Q9636.D 73.51,133.78 74.13,134.4 PR9808.2 PR9807.2 75.58,134.48 v3(76.49,135.38) 76.82,135.04 R80121.1
SEC_GPIO_SUS8: length 30.5
  TOP w0.089: CPU2.AF51 83.67,176.91 83.67,177.19 83.78,177.31 83.78,177.55 83.69,177.65 83.69,177.98 83.78,178.07 83.78,179.12 83.79,179.13 83.79,179.25
  TOP w0.102: 83.79,179.25 83.79,181.54 v1(84.94,182.69)
  BOTTOM w0.102: v1(84.94,182.69) 85.81,183.55 v4(85.81,184.12) 85.81,184.81 89.82,188.82 89.82,194.34 91.9,196.42 95.07,196.42 95.77,197.11 95.77,198.41 R1565.1 R1812.2
SEC_GPIO_SUS9: length 29.5
  TOP w0.089: CPU2.AF52 83.49,178.05 83.59,178.15 83.59,179.17 83.51,179.25
  TOP w0.102: 83.51,179.25 83.49,179.26 83.49,181.95 v1(84.94,183.4)
  BOTTOM w0.102: R1813.2 R1814.1 95.26,198.44 95.26,197.28 94.65,196.67 91.75,196.67 89.59,194.51 89.59,189.34 v4(88.32,188.08) 88.32,187.65 85.3,184.63 85.3,183.76 v1(84.94,183.4)
SEC_GPIO_SUS10: length 27.1
  TOP w0.089: 83.29,179.25 83.29,179.18 83.4,179.07 83.4,178.23 83.31,178.14 83.31,178.13 83.3,178.12 83.3,177.66 83.19,177.55 83.19,177.26 CPU2.AE51
  TOP w0.102: 83.29,179.25 83.29,182.52 84.89,184.12 v1(84.89,184.25)
  BOTTOM w0.102: v1(84.89,184.25) 84.89,184.54 86.96,186.61 v4(86.96,187.04) 86.96,187.48 89.28,189.8 89.28,194.76 92.13,197.61 92.13,198.31 R1816.1 R1815.2
SENSE_B: length 5
  TOP w0.102: U6.33 163.11,49.77 163.84,50.5 163.84,51.13 v3(164.27,51.56) 164.35,51.64 R266.2 R267.2
SER_IRQ: length 114.4
  TOP w0.102: U35.4 87.16,135.14 86.33,135.14 85.52,135.94 Q1253.2 84.64,136.85 v1(84.5,136.98) ; U109.36 128.81,65.1 128.63,64.92 128.63,64.16 128.91,63.88 v2(128.91,63.7) ; v1(107.12,126.57) 107.81,126.57 111.11,123.27 111.11,118.54 v1(111.34,118.31)
  L3 w0.127: v1(107.12,126.57) 106.99,126.7 101.63,126.7 101.12,127.2 94.29,127.2 93.84,126.75 90.66,126.75 84.5,132.9 v1(84.5,136.98)
  L4 w0.127: v2(128.91,63.7) 128.91,64.11 128.66,64.36 128.66,64.61 126.54,66.73 125.35,66.73 119.22,72.85 v1(119.22,73.53)
  BOTTOM w0.102: v1(111.34,118.31) 111.34,118.01 113.24,116.1 113.24,114.63 114.26,113.62 114.26,81.53 119.27,76.52 119.27,73.58 v1(119.22,73.53) ; v2(128.91,63.7) 129.31,63.7 129.69,64.08 130.51,64.08 R323.1 R79689.1 133.09,64.52 v4(133.38,64.81)
SFD_GPIO: length 194.5
  TOP w0.102: R79944.1 156.01,182.23 Q1205.G 155.67,180.66 v5(156.37,179.96) 156.07,179.65 156.07,177.5 156.34,177.22 161.59,177.22 164.12,179.74 v1(164.12,186.94) ; v2(121.76,54.18) 121.76,53.75 120.86,52.85 120.86,51.96 121.26,51.56 121.81,51.56 122.01,51.36 U109.108
  L3 w0.127: v1(164.12,186.94) 166.34,184.72 166.34,160.4 166.53,160.21 166.53,131.17 167.14,130.56 167.14,129.94 167.04,129.84 167.04,123.32 164.67,120.95 164.67,107.94 165.63,106.97 165.63,86.42 161.07,81.86 161.07,72.33 146.54,57.8 141.3,57.8 139.72,56.22 134.3,56.22 134.12,56.4 132.64,56.4 131.91,57.14 126.87,57.14 123.91,54.18 v2(121.76,54.18)
SIDE_USB3_RX0+: length 11.3
  TOP w0.102: L5.3 166.79,117.43 167.04,117.18 167.33,117.18 167.75,117.6 168.03,117.6 168.14,117.72 U7.9 U7.2 169.82,117.72 169.96,117.58 170.87,117.58 171.46,116.99 171.46,115.34 172.12,114.68 172.83,114.68 173.59,113.92 173.97,113.92 174.12,114.07 SSUSB1.6
SIDE_USB3_RX0-: length 11.2
  TOP w0.102: SSUSB1.5 174.12,113.49 173.91,113.7 173.5,113.7 173.21,113.99 172.74,114.47 172.03,114.47 171.24,115.25 171.24,116.9 170.78,117.36 169.96,117.36 169.84,117.24 U7.1 U7.10 168.18,117.24 168.03,117.39 167.84,117.39 167.42,116.97 166.99,116.97 166.77,116.75 L5.2
SIDE_USB3_RX1+: length 10.9
  TOP w0.102: SSUSB2.6 174.12,92.45 174,92.33 173.69,92.33 173.07,92.95 172.13,92.95 171.41,93.68 171.41,94.95 170.74,95.61 170.36,95.61 170.23,95.75 U51.2 U51.9 168.39,95.75 168.24,95.6 167.96,95.6 167.33,94.98 167.18,94.98 166.95,95.21 L37.3
SIDE_USB3_RX1-: length 10.6
  TOP w0.102: L37.2 166.98,94.53 167.21,94.76 167.42,94.76 168.05,95.38 168.33,95.38 168.44,95.27 U51.10 U51.1 170.23,95.27 170.36,95.4 170.65,95.4 171.19,94.86 171.19,93.59 172.04,92.74 172.98,92.74 173.6,92.11 173.96,92.11 174.12,91.96 SSUSB2.5
SIDE_USB3_TX0+: length 10.1
  TOP w0.102: L4.3 166.76,119.7 166.97,119.49 167.47,119.49 167.86,119.1 168,119.1 168.14,119.24 U7.6 U7.5 169.95,119.24 170.09,119.11 172.5,119.11 173.39,119.99 173.95,119.99 174.12,120.16 SSUSB1.9
  BOTTOM w0.102: SSUSB1.9 174.98,120.84 v4(174.99,120.85)
SIDE_USB3_TX0-: length 9.4
  TOP w0.102: SSUSB1.8 174.12,119.65 174,119.77 173.48,119.77 172.59,118.89 170.09,118.89 169.95,118.76 U7.4 U7.7 168.12,118.76 167.99,118.88 167.77,118.88 167.38,119.27 167.02,119.27 166.76,119.01 L4.2
SIDE_USB3_TX1+: length 9
  TOP w0.102: L36.3 167.3,97.5 167.54,97.26 167.73,97.26 167.86,97.13 168.03,97.13 168.16,97.27 U51.6 U51.5 170.23,97.27 170.36,97.13 170.83,97.13 171.13,97.43 172.65,97.43 173.66,98.45 173.97,98.45 174.12,98.6 SSUSB2.9
SIDE_USB3_TX1-: length 9
  TOP w0.102: L36.2 167.3,96.81 167.54,97.05 167.64,97.05 167.77,96.92 168.03,96.92 168.16,96.79 U51.7 U51.4 170.23,96.79 170.36,96.92 170.92,96.92 171.22,97.22 172.74,97.22 173.75,98.23 174,98.23 174.12,98.11 SSUSB2.8
SIO_AGND: length 44.1
  TOP w0.203: U109.84 114.86,56.74 v2(114.66,56.94) 114.86,57.14 U109.83
  TOP w0.254: v1(109.66,53.39) 109.77,53.28 109.77,51.88 109.64,51.75 109.64,50.81 C525.1
  TOP w0.508: C529.1 R657.2 110.8,54.71 110.42,55.09 110.42,55.63 v2(110.4,55.65)
  L3 w0.305: v2(125.08,53.43) 125.06,53.43 124.92,53.29 116.04,53.29 114.87,52.12 110.45,52.12 109.66,52.91 v1(109.66,53.39)
  BOTTOM w0.305: v2(110.4,55.65) 110.4,55.57 109.96,55.14 v4(109.96,54.64) 109.96,53.7 v1(109.66,53.39)
  BOTTOM w0.381: R656.2 112.19,56.86 112.41,57.09 114.52,57.09 v2(114.66,56.94) ; R79950.2 115.63,55.94 C535.2
  BOTTOM w0.508: R655.2 C527.1 110.62,52.43 v1(109.66,53.39) ; C528.1 R656.2 112.1,56.4 110.8,56.4 110.4,55.99 v2(110.4,55.65) ; v2(125.08,53.43) 125.1,53.46 125.1,53.47 125.15,53.52 125.15,54.01 R400.1 R399.1 R651.1 ; R79950.2 114.56,56.84 v2(114.66,56.94)
SIO_AMD SVID_EN: length 5.2
  TOP w0.102: U109.26 132.5,61.94 132.95,61.49 133.53,61.49 133.89,61.85 133.89,62.57 133.71,62.75 v3(133.71,63.02) 133.71,63.14 133.95,63.37 R310.1
SIO_ATXPG: length 7.1
  TOP w0.102: v2(129.01,59.08) 130.16,57.94 131.55,57.94 U109.16
  BOTTOM w0.102: v4(127.03,60.3) 127.45,59.88 R79780.1 128.3,59.5 128.3,58.45 128.51,58.24 R280.2 128.65,58.71 v2(129.01,59.08)
SIO_AVCC3: length 5.7
  TOP w0.203: v2(115.65,51.23) 116.06,51.64 U109.96
  BOTTOM w0.635: v2(115.65,51.23) 115.75,51.13 v4(116.52,51.13) 117.41,51.13 L9.2 117.66,52.39 C214.1 116.1,52.54 C215.1
SIO_CE_N: length 31.2
  TOP w0.102: R270.1 137.82,51.32 138.31,51.82 U15.1 138.31,53.85 139.1,54.64 141.94,54.64 143.64,56.34 143.64,62.92 v2(143.92,63.2) ; v2(133.31,61.95) 132.92,62.34 U109.27
  L3 w0.127: v2(143.92,63.2) 142.76,62.03 141.05,62.03 140.46,61.44 138.61,61.44 138.1,61.95 v2(133.31,61.95)
  BOTTOM w0.102: v4(133.96,62.75) 133.96,62.66 133.31,62.01 v2(133.31,61.95)
SIO_CLK_DB: length 37.4
  TOP w0.102: U109.48 124.01,66.99 123.76,67.24 123.76,69.08 124.08,69.41 RN6.2 124.08,70.01 123.71,70.38 123.25,70.38 122.99,70.64 122.99,73.48 123.89,74.37 124.44,74.37 125.04,74.97 125.4,74.97 v1(125.73,75.3)
  BOTTOM w0.102: v1(125.73,75.3) 127.45,75.3 128.09,75.93 135.72,75.93 136.71,76.92 139.52,76.92 142.65,80.06 143.49,80.06 143.75,80.31 143.75,80.33 144.8,81.38 147.99,81.38 CN1.4
SIO_COPEN#: length 4.6
  TOP w0.102: U109.65 116.06,64.97 115.16,65.87 R677.1 114.05,65.94 113.07,66.92 v3(113.07,67.03)
SIO_DAT_DB: length 38.8
  TOP w0.102: U109.49 123.61,67.03 123.27,67.36 123.27,69.33 123.43,69.49 RN6.1 123.29,69.9 123.05,69.9 122.51,70.44 122.51,73.75 123.62,74.85 124.24,74.85 124.88,75.49 v1(124.98,75.49)
  BOTTOM w0.102: CN1.3 145.93,81.86 144.6,81.86 143.71,80.98 142.81,80.98 139.24,77.41 136.51,77.41 135.58,76.48 125.97,76.48 v1(124.98,75.49)
SIO_DEBUG_RX: length 3.4
  TOP w0.102: R79666.1 126.96,47.73 v3(127.67,48.44) 127.61,48.5 U109.122
SIO_DEBUG_TX: length 3.6
  TOP w0.102: U109.121 127.21,49.36 v3(126.35,48.51) 125.94,48.1 R335.1
SIO_EUP_EN#: length 289.7
  TOP w0.203: v2(49.8,223.17) 49.76,223.13 48.89,223.13 R1840.1 48.84,222.05 PR5254.2 ; Q6706.D 141.24,46.84 R725.1 142.26,46.77 143.04,47.55 143.04,48.45 142.79,48.69 R296.1 142.79,50.3 143.63,51.15 143.63,54.47 144.99,55.83 144.99,61.48 154.29,70.78 154.29,82.38 151.57,85.1 151.57,104.5 150.71,105.36 v1(150.71,106.05)
  L3 w0.203: v2(49.8,223.17) 50.91,224.28 86.93,224.28 88.04,223.16 94.8,223.16 95.32,223.69 103.63,223.69 107.57,219.74 121.73,219.74 122.23,220.24 134.17,220.24 134.69,220.76 135.91,220.76 139.53,217.14 139.53,212.9 145.28,207.15 145.28,204.29 144.36,203.37 144.36,188.94 146.25,187.05 146.25,183.78 145.52,183.05 145.52,176.96 144.37,175.8 144.37,147.48 149.59,142.26 149.59,132.77 149,132.18 149,127.66 149.05,127.61 149.05,127.21 149,127.16 149,124.47 147.88,123.34 147.88,117.79 149.28,116.38 149.28,109.52 147.66,107.9 147.66,107.25 148.87,106.05 v1(150.71,106.05)
  BOTTOM w0.203: v4(50.6,223.27) 50.5,223.17 v2(49.8,223.17)
SIO_EUP_EN#_D: length 116.2
  TOP w0.203: v2(85.63,220.75) 85.37,221.02 Q1229.5 Q1229.2
  L3 w0.203: v2(85.63,220.75) 84.73,221.66 71.97,221.66 70.54,223.08 54.11,223.08 51.83,220.8 50.4,220.8 v2(49.56,219.96) 49.56,200.03 50.25,199.34 50.25,183.82 v2(50.1,183.66)
  BOTTOM w0.203: Q1230.2 Q1230.5 48.99,179.77 49.36,180.14 49.36,181.36 49.13,181.58 44.41,181.58 v4(44,182) ; 40.62,181.05 40.62,180.87 40.39,180.64 Q1232.5 Q1232.2 ; 40.62,181.05 42.35,181.05 43.3,182 v4(44,182) ; 40.62,181.05 40.62,181.48 39.73,182.37 37.74,182.37 36.94,183.18 36.94,183.81 37.35,184.23 Q1231.2 Q1231.5 ; v4(44,182) 44,183.08 R5290.2 44.29,183.4 Q1228.5 Q1228.2 49.83,183.4 v2(50.1,183.66) ; Q1233.2 Q1233.5 49.26,218.73 Q1234.D 49.22,219.62 v2(49.56,219.96)
SIO_EUP_EN#_G: length 4.7
  TOP w0.203: R1840.2 47.28,223.08 47.1,223.27 v2(47.08,223.27) 46.32,223.27 R1841.2
  BOTTOM w0.203: Q1234.G 47.89,222.03 v4(47.89,223.19) 47.81,223.27 v2(47.08,223.27)
SIO_GPU_EN: length 70.8
  TOP w0.102: v2(123.73,60.63) 124.44,59.92 124.44,55.6 126.09,53.95 126.78,53.95 127.59,53.14 127.59,52.73 127.44,52.58 127.44,52.08 128.41,51.11 U109.124 128.41,48.24 128,47.83 R354.1 ; PR5476.1 115,79.24 114.18,79.24 v1(113.65,78.71)
  L4 w0.127: v1(113.65,78.71) 112.99,79.38 110.61,79.38 110.26,79.03 107.32,79.03 106.38,79.98 101.86,79.98 99.14,77.26 99.14,71.26 101.28,69.13 102.66,69.13 104.25,69.13 106.62,66.75 111.11,66.75 116.58,61.28 123.08,61.28 v2(123.73,60.63)
  BOTTOM w0.102: v4(113.14,79.43) 113.14,79.22 v1(113.65,78.71)
SIO_GPU_RST: length 97.3
  TOP w0.102: v1(110.95,108.15) 110.83,108.28 107.81,108.28 104.08,104.56 D34.2 D34.1 ; v1(124.52,60.66) 125.03,60.15 125.03,55.34 126.19,54.18 126.88,54.18 128.35,52.7 128.35,52.02 129.21,51.17 U109.126 129.21,49.37 129.04,49.2 R79766.1
  L4 w0.127: v1(102.56,79.52) 102.52,79.47 102.07,79.47 99.65,77.05 99.65,71.47 101.49,69.63 102.37,69.63 102.87,69.63 102.88,69.63 103.3,69.63 104.46,69.63 106.83,67.26 111.32,67.26 117.05,61.53 123.59,61.53 124.47,60.66 v1(124.52,60.66)
  BOTTOM w0.102: v1(102.56,79.52) 103.93,80.88 103.93,80.91 v4(108.11,85.09) 108.14,85.09 110.95,87.91 v1(110.95,108.15)
SIO_GREEN: length 86.7
  TOP w0.203: U109.23 130.65,60.74
  TOP w0.254: v1(126,11.51) 126,6.64 128.01,4.64 137.31,4.64 139.14,6.46 R80202.2 139.78,6.92 Q9646.2 Q9646.5 ; 130.65,60.74 129.6,60.74 128.25,59.4 128.25,57.37 129.22,56.4 129.47,56.4 v2(129.48,56.4)
  L3 w0.254: v2(129.48,56.4) 129.5,56.4 129.82,56.08 130.75,56.08 131.71,55.13 131.71,54.11 132.01,53.8 132.01,53.2 132.6,52.61 133.08,52.61 134.35,51.34 134.35,47.06 138.8,42.6 138.8,33.42 138.63,33.25 138.63,26.02 135.36,22.75 135.36,20.64 128.74,14.02 128.34,14.02 126.03,11.71 126.03,11.53 v1(126,11.51)
  BOTTOM w0.254: v4(128.94,56.97) 129.22,56.69 129.22,56.68 129.48,56.42 v2(129.48,56.4)
SIO_GREEN_PWM: length 74.7
  TOP w0.203: U109.15 130.62,57.54 130.39,57.3 v2(130.39,56.67)
  TOP w0.254: v1(126.71,11.51) 126.71,6.51 128.18,5.04 135.25,5.04 135.99,5.78 R652.1
  L3 w0.254: v2(130.39,56.67) 130.7,56.67 132.09,55.28 132.09,54.53 132.95,53.67 133.05,53.67 134.75,51.96 134.75,47.23 139.34,42.64 139.34,33.38 139.03,33.08 139.03,25.85 135.77,22.58 135.77,20.48 128.91,13.61 128.51,13.61 126.71,11.82 v1(126.71,11.51)
  BOTTOM w0.254: v4(131.21,54.71) 130.99,54.93 130.99,55.58 130.74,55.83 130.74,56.18 130.41,56.52 130.41,56.64 v2(130.39,56.67)
SIO_GREEN_PWM_C_1: length 152.8
  TOP w0.254: R659.2 135.94,7.51 R652.2 136.22,7.45 136.52,7.15 136.52,5.75 v3(136.75,5.52) 136.78,5.52 Q9646.1 138.18,8.83 138.18,12.62 137.51,13.28 R663.1 136.89,13.28 136,12.4 134.32,12.4 133.78,11.86 132.78,11.86 132.16,12.47 129.28,12.47 v1(129.27,12.48)
  L3 w0.254: v1(24.11,17.5) 24.11,17.19 23.34,16.42 23.34,10.51 23.97,9.88 23.97,9.46 23.66,9.15 23.66,3.93 24.56,3.04 84.04,3.04 84.42,3.41 84.42,5.42 85.7,6.7 v1(85.73,6.7)
  L4 w0.254: v1(129.27,12.48) 129.27,12.57 129.22,12.62 129.22,12.75 128.96,13 118.89,13 110.78,4.9 87.53,4.9 v1(85.73,6.7)
  BOTTOM w0.254: v1(24.11,17.5) 24.42,17.5 24.47,17.55 25.28,17.55 26.76,19.03 Q65.G
SIO_HDD_LED: length 60.6
  TOP w0.203: v2(132.79,55.59) 132.79,55.7 132.55,55.94 U109.11
  TOP w0.254: R364.1 R362.2 131.03,6.52 130.79,6.76 130.79,8.2 v1(132.52,9.93)
  L3 w0.254: v2(132.79,55.59) 132.68,55.48 132.68,54.48 133.11,54.06 134.18,54.06 135.64,52.6 135.64,47.59 140.15,43.08 140.15,33.05 139.85,32.74 139.85,25.51 136.58,22.25 136.58,16.41 134.02,13.84 134.02,11.43 v1(132.52,9.93)
  BOTTOM w0.254: v2(132.79,55.59) 132.17,55.59 132.1,55.66 v4(132.06,55.66)
SIO_HDD_LED_1: length 134.7
  TOP w0.254: R364.2 129.1,9.83 126.92,12.01 119.44,12.01 v1(118.85,11.43)
  L3 w0.254: v1(23.68,18.49) 22.85,17.66 22.85,3.42 24.08,2.19 84.35,2.19 85.28,3.12 85.28,4.27 85.76,4.75 v1(85.76,4.99)
  L4 w0.254: v1(85.76,4.99) 86.66,4.09 111.63,4.09 118.85,11.31 v1(118.85,11.43)
  BOTTOM w0.254: v1(118.85,11.43) 119.15,11.14 v4(119.15,10.67) ; v1(23.68,18.49) 23.8,18.61 Q38.B
SIO_HOLD#: length 1.7
  TOP w0.102: U15.7 139.58,59.77 R79692.1
SIO_INT#: length 8.1
  TOP w0.102: U4101.39 143.37,69.27 142.32,68.22 v3(142.23,68.22) 139.67,68.22 R80212.1 139.64,68.19 139.19,67.73 138.39,67.73 138.01,68.11 138.01,68.58 137.74,68.85 R80211.1
SIO_INT_C: length 74.7
  TOP w0.102: v1(108.75,39.67) 109.89,40.82 109.89,44.97 111.15,46.23 115.18,46.23 115.6,46.65 115.6,47.89 116.48,48.77 117.94,48.77 118.81,49.64 U109.100 ; R80211.2 137.69,67.96 138.11,67.54 138.11,67.17 v1(137.98,67.04)
  L4 w0.127: v1(137.98,67.04) 137.98,66.15 137.27,65.44 137.27,64.19 136.25,63.18 136.25,61.13 135.52,60.39 135.52,59.55 135.33,59.36 135.33,57 135.43,56.9 135.43,55.05 135.08,54.71 135.08,53.06 135.58,52.57 135.58,51.9 134.56,50.88 134.56,49.3 133.89,48.62 133.89,44.92 133.21,44.23 131.72,44.23 131.03,43.55 129.91,43.55 129.23,42.87 129.23,42.75 126.47,40 126.47,39.1 125.03,37.66 116.93,37.66 116.62,37.35 114.64,37.35 112.3,39.68 108.75,39.68 v1(108.75,39.67)
  BOTTOM w0.102: v4(138.68,66.6) 138.23,66.6 137.99,66.84 137.99,67.03 v1(137.98,67.04)
SIO_K8PWR_EN: length 5.6
  TOP w0.102: U109.123 128.01,51.17 127.13,52.05 127.13,52.9 127.16,52.93 v1(127.16,52.96)
  BOTTOM w0.102: R80217.1 127.12,52.92 v1(127.16,52.96) ; v1(127.16,52.96) 127.19,52.93 v4(127.19,52.12) ; v1(127.16,52.96) 127.33,53.12 R79667.1
SIO_LVDS_BL_ADJ: length 192.1
  TOP w0.165: U109.10 130.79,55.54 130.39,55.14 127.48,55.14 v2(127.46,55.12) ; R131.2 R503.1 37.8,117.53 36.18,119.15 v2(33.15,119.15)
  L3 w0.165: v2(127.46,55.12) 127.74,54.84 127.74,54.19 126.7,53.15 126.7,52.39 126.71,52.37 126.71,51.92 122.96,48.16 115.43,48.16 114.54,47.27 110.24,47.27 106,43.03 100.21,43.03 96.32,39.14 89.33,39.14 81.86,46.6 61.08,46.6 58.86,48.82 35.96,48.82 33.07,51.72 33.07,52.25 30.29,55.03 30.29,69.79 34.39,73.89 34.39,81.96 35.06,82.63 35.06,89.64 35.85,90.44 35.85,100.36 34.02,102.19 34.02,118.28 v2(33.15,119.15)
  BOTTOM w0.165: v4(128.44,55.41) 127.76,55.41 v2(127.46,55.12)
SIO_MAIN_VCC3: length 3.6
  TOP w0.203: U109.89 115.27,54.74 114.85,55.16
  TOP w0.254: 114.85,55.16 v3(114.16,55.16) 113.54,55.16 R375.1
SIO_MEM_EVENT_L: length 103.7
  TOP w0.102: U109.53 122.01,68.16 121.47,68.69 121.47,70.35 121.33,70.49 121.33,73.1 121.41,73.17 v1(121.41,73.23) 121.48,73.3 121.48,74.14 R348.2
  L3 w0.127: v2(159.8,138.84) 159.8,135.43 152.52,128.15 152.52,121.63 152.51,121.62 152.51,121.28 150.74,119.51 150.74,111.69 151.66,110.77 151.66,104.15 150.81,103.3 150.81,88.29 149.78,87.26 149.78,84.44 148.46,83.12 147.94,83.12 143.67,78.85 138.78,78.85 138.42,78.5 134.27,78.5 132.08,76.3 130.13,76.3 127.63,73.8 121.97,73.8 v1(121.41,73.23)
  BOTTOM w0.102: v2(159.8,138.84) 160.17,138.47 R565.1 161.2,137.57 v4(161.21,137.57)
SIO_MEM_EVENT_L_B: length 3.4
  BOTTOM w0.102: R572.2 156.07,141.76 v4(156.32,142.01) 157.44,142.01 157.68,141.77 Q51.B
SIO_MEM_EVENT_L_C: length 2.7
  BOTTOM w0.102: Q51.C 158.15,138.59 158.15,137.92 v4(158.3,137.77) 158.5,137.57 R565.2
SIO_PCIRSTIN#: length 5.5
  TOP w0.102: U109.128 130.01,49.65 v3(131.28,48.38) 132,47.65 133.14,47.65 R285.1
SIO_PSON_D: length 3.7
  BOTTOM w0.102: Q66.D 115.58,65.48 v4(116.86,64.2) 117.49,63.57 R644.1
SIO_PSON_N: length 26.3
  TOP w0.102: U109.73 116.96,61.14 117.27,60.83 v2(117.27,60.74)
  BOTTOM w0.102: R669.2 122.39,67.54 121.01,66.16 v4(121.01,65.86) 121.39,65.48 121.39,63.98 121.14,63.73 120.78,63.73 120.53,63.98 120.53,63.99 120.19,64.33 117.91,64.33 116.21,66.03 114.35,66.03 113.71,65.39 Q66.G 113.66,63.77 113.08,63.18 113.08,60.92 113.25,60.74 113.25,60.14 114.54,58.85 115.95,58.85 117.27,60.17 v2(117.27,60.74)
SIO_PWNBTN_B: length 2.8
  TOP w0.102: v3(107.3,67.34) 106.1,67.34 Q18.B 105.97,68.9 R55.2
SIO_PWNBTN_N: length 202.2
  TOP w0.102: Q18.E 104.62,67.48 106.88,65.21 v3(107.59,65.21) 108.3,65.21 109.68,63.82 v2(109.68,63.78) 109.79,63.68 R1260.1 110.61,62 R662.1
  L3 w0.127: v2(109.68,63.78) 109.9,63.56 110.82,63.56 110.97,63.41 114.77,63.41 115.39,62.79 118.57,62.79 119.35,62.01 130.93,62.01 131.84,62.93 135.96,62.93 136.56,63.53 138.81,63.53 139.51,62.83 139.9,62.83 141.25,64.17 144.33,64.17 144.58,63.92 147.08,63.92 154.31,71.16 154.31,72.13 157.89,75.72 157.89,83.5 160.93,86.54 160.93,115.41 161.58,116.06 161.58,120.47 163.7,122.6 163.7,130.07 165.76,132.12 165.76,159.91 165.58,160.09 165.58,183.58 161.77,187.39 161.77,200.59 162.41,201.23 v2(162.41,201.71)
  BOTTOM w0.102: R395.2 109.68,62.93 v2(109.68,63.78) 109.68,64.1 R57.1 ; v2(162.41,201.71) 162.52,201.83 R47.1
SIO_SCK: length 14.2
  TOP w0.102: R312.2 136.06,60.81 C175.1 136.65,61.19 136.93,61.47 138.57,61.47 138.84,61.2 138.84,60.75 138.57,60.48 138.57,60.05 v3(138.37,59.84) 137.82,59.29 137.82,57.27 138.07,57.01 140.58,57.01 140.85,57.28 U15.6 140.85,59.82 R79693.1
SIO_SCK_R: length 4.2
  TOP w0.102: U109.22 132.45,60.34 132.9,59.89 133.41,59.89 133.66,60.15 133.66,60.53 v3(133.71,60.58) 134.03,60.89 134.39,60.89 R312.1
SIO_SI: length 16.4
  TOP w0.102: U109.21 132.4,59.94 132.67,59.66 133.64,59.66 134.3,60.33 135.81,60.33 136.35,59.78 136.35,59.78 v3(136.48,59.65) 137.46,58.67 137.46,57.12 137.92,56.65 141.73,56.65 142.12,57.05 U15.5 142.12,59.83 R79694.1
SIO_SMB2_CLK: length 34.2
  TOP w0.102: U109.63 118.01,67.09 117.67,67.42 v1(117.67,67.51) 117.25,67.51 117.11,67.37 114.56,67.37 113.93,68 113.93,68.82 113.58,69.19 113.51,69.26 113.42,69.35 113.21,69.55 RN9.3 112.87,69.52 112.87,69.14 112.78,69.05 112.78,69.05 111.99,68.25 109.23,68.25 v3(109.02,68.05) 109.02,68.43 R380.2
  BOTTOM w0.102: R80204.2 134.83,67.91 134.83,68.46 133.26,70.03 124.2,70.03 121.01,66.84 118.35,66.84 v1(117.67,67.51)
SIO_SMB2_DATA: length 33
  TOP w0.102: R379.2 110.9,69.02 112.07,69.02 112.3,69.25 112.3,70.05 112.45,70.2 RN9.4 113.53,70.2 114.41,69.31 114.41,68.19 114.85,67.75 116.38,67.75 116.8,68.17 v1(117.23,68.17) 117.7,68.17 118.26,67.61 118.26,67.26 118.41,67.11 U109.62
  BOTTOM w0.102: v1(117.23,68.17) 118.41,68.17 119.12,67.46 120.87,67.46 v4(123.12,69.71) 123.92,70.51 133.46,70.51 134.13,69.85 R80205.2
SIO_SMCLK0: length 190.8
  TOP w0.102: RN4302.4 115.93,68.74 116.33,69.14 117.64,69.14 117.64,69.14 118.1,69.14 119.22,68.01 119.22,67.19 119.21,67.18 U109.60 119.21,60.81 v2(119.16,60.76) ; v1(36.91,27.38) 36.33,27.96 v3(36.04,27.96) 35.52,27.44 35.52,25.12 35.1,24.7 R79633.2
  L3 w0.127: v2(43.37,77.14) 43.97,77.14 44.21,77.38 49.23,77.38 50.76,75.86 53.02,75.86 53.65,76.49 54.67,76.49 57.3,73.86 87.25,73.86 88.03,74.64 88.68,74.64 92.58,70.74 95.34,70.74 96.97,69.11 96.97,53.2 99.75,50.43 103.14,50.43 107.37,54.67 107.37,58.52 108.77,59.92 108.77,61.45 109.36,62.04 114.44,62.04 114.52,61.96 115.36,61.96 116.11,61.21 118.58,61.21 119.03,60.76 v2(119.16,60.76)
  L4 w0.127: v1(36.91,27.38) 36.91,28.04 41.74,32.87 41.74,43.96 29.2,56.5 29.2,68.86 37.29,76.95 39.16,76.95 39.86,77.65 42.86,77.65 v2(43.37,77.14)
  BOTTOM w0.102: v2(43.37,77.14) 44.22,77.14 R79685.2
SIO_SMCLK0_D: length 5.1
  BOTTOM w0.102: v4(49.77,77.55) 49.64,77.67 Q95.3 48.27,77.2 48.04,76.96 46.69,76.96 46.11,77.55 R79685.1
SIO_SMDAT0: length 190.5
  TOP w0.102: v1(36.1,25.7) 36.1,24.28 v3(35.88,24.06) 34.35,24.06 R79634.2 ; RN4302.3 114.9,68.39 115.05,68.23 116.18,68.23 116.6,68.66 117.9,68.66 118.74,67.81 118.74,67.26 118.81,67.19 U109.61 118.81,65.09 118.82,65.08 118.82,61.28 118.24,60.7 v2(118.24,60.7)
  L3 w0.127: v2(43.59,76.12) 43.67,76.12 44.42,76.87 48.9,76.87 50.43,75.35 53.23,75.35 53.86,75.98 54.46,75.98 57.09,73.36 89.24,73.36 92.37,70.23 94.53,70.23 96.47,68.29 96.47,52.99 99.54,49.92 103.35,49.92 107.88,54.46 107.88,58.25 109.28,59.65 109.28,61.24 109.57,61.53 113.59,61.53 114.85,60.27 117.55,60.27 117.98,60.7 v2(118.24,60.7)
  L4 w0.127: v1(36.1,25.7) 36.38,25.7 42.25,31.57 42.25,44.17 29.71,56.71 29.71,68.65 37.46,76.4 39.39,76.4 40.13,77.14 42.4,77.14 43.42,76.12 v2(43.59,76.12)
  BOTTOM w0.102: R79684.2 44.03,75.41 43.59,75.84 v2(43.59,76.12)
SIO_SMDAT0_D: length 3.2
  BOTTOM w0.102: R79684.1 46.16,74.5 v4(46.39,74.5) 46.57,74.5 46.97,74.9 Q95.6
SIO_SO: length 48.8
  TOP w0.102: v1(147.25,65.66) 147.25,64.8 144.03,61.57 144.03,56.4 142.01,54.38 140.01,54.38 139.58,53.95 U15.2 139.58,51.89 139.09,51.39 R275.1 ; U109.45 125.21,67.51 125.09,67.63 v1(125.09,67.97)
  L3 w0.127: v1(147.25,65.66) 147.25,65.81 145.33,67.73 141.12,67.73 140.65,67.26 v1(139.38,67.26)
  BOTTOM w0.102: v1(125.09,67.97) 125.09,68.61 v4(125.88,69.39) 126.03,69.55 133.06,69.55 134.35,68.26 134.35,67.65 136.14,65.86 138.66,65.86 139.38,66.58 v1(139.38,67.26)
SIO_VCORE: length 8
  TOP w0.203: v2(130.13,64.59) 130.01,64.72 U109.33 130.01,66.73 130.13,66.86
  TOP w0.254: 130.13,66.86 130.53,67.25 131.02,67.25 131.78,68.02 131.78,68.95 C182.1
  BOTTOM w0.254: C181.2 130.17,65.82 v4(130.59,65.41) 130.59,65.05 v2(130.13,64.59)
SIO_VIN1: length 6.1
  TOP w0.102: R80215.1 112.39,52.53 v3(112.4,52.51) 112.52,52.4 R80216.2 112.75,51.74 114,51.74 115,52.74 U109.94
SIO_VIN3: length 7
  TOP w0.203: U109.92 115,53.54 114.88,53.42 114.04,53.42 v2(113.88,53.59)
  BOTTOM w0.254: v2(113.88,53.59) 113.83,53.59 113.67,53.44 R648.1 C527.2 113.7,52.43 114.19,51.94 114.19,51.56 v4(114.18,51.55) 114.04,51.41 R655.1
SIO_VIN4: length 6.4
  TOP w0.203: v2(114.66,53.96) 114.68,53.94 U109.91
  BOTTOM w0.254: R656.1 C528.2 R649.1 114.1,54.46 114.6,53.96 v2(114.66,53.96) 114.66,52.98 v4(114.49,52.81)
SIO_VIN5: length 15.5
  TOP w0.203: U109.90 115,54.34 114.87,54.47 112.94,54.47 R657.1
  TOP w0.254: R657.1 C529.2 112.69,53.61 112.22,53.14 110.68,53.14 109.79,54.03 109.79,58.55 v2(110.02,58.78)
  BOTTOM w0.254: v2(110.02,58.78) 110.87,58.78 v4(110.89,58.76) 110.93,58.8 110.93,59.51 110.53,59.92 R650.1
SIO_VREF: length 8
  TOP w0.203: v2(117.33,54.89) 117.09,55.14 U109.88
  BOTTOM w0.254: R404.2 118.38,53.97 117.46,54.89 v2(117.33,54.89) 117.66,55.22 117.66,55.24 117.76,55.34 v4(117.76,55.67) 117.73,55.7 C535.1 116.76,55.78 R397.2 R658.2
SIO_WP#: length 3.3
  TOP w0.102: R279.1 140.9,50.75 v3(141.41,51.26) 141.41,51.54 140.85,52.1 U15.3
SIO_WRST#: length 6.2
  TOP w0.203: U109.47 124.41,67.12 124.25,67.28 124.25,68.54 v3(124.9,69.19) 125.28,69.57 R338.2
  TOP w0.254: C189.1 125.99,70.32 R338.2
SIO_YELLOW: length 193.9
  TOP w0.203: v2(135.11,52.37) 134.43,52.37 v3(133.78,53.02) 132.46,54.34 U109.7
  TOP w0.254: v1(127.25,10.96) 127.26,10.96 127.26,6.53 128.33,5.46 132.33,5.46 R665.2 R661.2
  L3 w0.254: v1(127.25,10.96) 127.26,10.97 127.26,11.79 128.68,13.21 129.08,13.21 136.18,20.31 136.18,22.42 139.44,25.68 139.44,32.91 139.74,33.21 139.74,42.81 135.24,47.32 135.24,52.25 v2(135.11,52.37) ; v1(85.91,4.01) 85.91,3.89 85.74,3.72 85.74,3.01 84.52,1.79 23.91,1.79 22.44,3.25 22.44,18.69 22.92,19.18 v1(23.27,19.18)
  L4 w0.254: v1(85.91,4.01) 86.04,3.89 86.1,3.89 86.3,3.68 111.99,3.68 120.32,12.01 126.92,12.01 127.22,11.72 127.22,11.02 127.26,10.98 127.26,10.96 v1(127.25,10.96)
  BOTTOM w0.254: Q68.G 22.98,19.49 23.27,19.2 v1(23.27,19.18)
SKEW1: length 14.4
  TOP w0.089: 82.28,150.44 82.28,151.11 82.18,151.2 82.18,151.89 82.3,152.01 82.3,152.36 82.23,152.43 82.23,152.71 82.47,152.95 82.47,153.03 82.52,153.08 CPU2.AD3
  TOP w0.102: 82.28,150.44 82.28,149.06 R562.1 85.76,145.58 85.76,144.71 85.99,144.48 85.99,143.31 v3(85.81,143.13) 86.37,142.57 86.37,141.52 R567.2
SKEW2: length 10.8
  TOP w0.089: CPU2.AC3 81.84,152.74 81.84,152.45 81.74,152.35 81.74,150.9
  TOP w0.102: R563.2 83.93,144.01 83.93,145.71 R560.1 82.61,147.02 v3(82.53,147.02) 81.82,147.73 81.82,150.83 81.74,150.9
SKEW3: length 13.1
  TOP w0.089: 81.36,150.62 81.34,150.64 81.34,152.35 81.26,152.43 81.26,152.71 81.54,152.99 CPU2.AB3
  TOP w0.102: R558.2 82.99,141.54 R555.1 81.57,142.96 81.57,144.23 81.7,144.36 v3(81.7,144.84) 81.7,145.43 81.36,145.76 81.36,150.62
SLEEVE: length 52.1
  TOP w0.203: v6(164.37,50.37) 164.37,50.24 163.5,49.37 U6.32
  TOP w0.305: R272.2 164.65,50.52 164.5,50.37 v6(164.37,50.37)
  TOP w1.016: 171.65,73.99 172.04,74.39 174.82,74.39 176.18,73.03 182.05,73.03 182.48,72.59 UHS1.4
  BOTTOM w0.508: Q28.D 155.69,57.24 157.24,58.79 157.24,60.16 158.1,61.01 165.13,61.01 165.18,60.96
  BOTTOM w1.016: v6(167.57,72.69) 167.57,69.88 165.18,67.49 165.18,55.49 164.65,54.96 164.65,54.95 v4(164.53,54.83) 164.37,54.67 v6(164.37,50.37)
SLEEVE_G: length 11.6
  BOTTOM w0.102: Q6711.C 151.53,51.79 R319.2 151.53,52.57 R322.1 151.54,54.18 v4(151.54,56.59) 151.54,57.48 153.21,59.14 Q28.G
SLP_S0_N: length 7.1
  TOP w0.102: R1580.1 90.86,127.03 90.44,127.03 90.27,126.86 88.4,126.86 88.26,127.01 Q1206.3 88.26,128.11 87.46,128.91 v3(87.46,129.11) 87.74,129.39 88.82,129.39 R1578.1
SLP_S3_N: length 405.7
  TOP w0.102: R54.1 93.01,126.95 93.78,127.72 93.78,128.86 R1576.1 94.29,128.89 94.29,127.99 95.27,127.02 Q16.3 95.83,126.53 96.22,126.92 96.22,128.78 96.64,129.2 97.25,129.2 97.74,128.71 99.69,128.71 100.54,129.55 R1669.1 103.62,129.55 104.99,128.19 104.99,126.94 106.89,125.04 106.89,123.8 106.48,123.39 106.48,121.4 v1(106.1,121.02) ; R80063.2 144.58,105.99 141.47,105.99 139.28,108.19 v1(139.28,108.36) ; R1747.2 R1776.2 99.5,57.81 v2(99.09,57.4) ; v1(162.44,81.2) 162.44,82.6 159.34,85.7 v1(159.34,86.33) ; R79961.2 145.16,88.58 145.71,89.14 145.71,89.73 145.44,90 v1(142.62,90) ; v2(118.36,62.32) 118.36,62.34 117.56,63.14 U109.68 ; PU4501.1 22.59,164.27 v2(22.23,163.91)
  L3 w0.127: v1(167.24,89.46) 167.58,89.12 167.58,87.85 167.01,87.27 167.01,85.9 162.44,81.33 v1(162.44,81.2) ; v2(33.13,137.41) 36.43,134.11 36.82,134.11 36.9,134.04 40.7,134.04 42.35,132.38 54.22,132.38 55.07,133.24 58.17,133.24 61.13,130.27 75.88,130.27 84.01,122.15 97.37,122.15 98.09,121.42 98.47,121.42 98.85,121.81 105.32,121.81 v1(106.1,121.02) 107.1,122.02 117.79,122.02 121.7,118.11 131.8,118.11 132.15,117.75 132.18,117.75 134.34,115.59 134.35,115.59 137.08,112.87 137.08,109.92 138.64,108.36 v1(139.28,108.36) 139.28,108.27 139.86,107.69 139.86,106.4 143.34,102.92 143.34,90.72 142.62,90 v1(142.62,90) 141.97,89.34 141.97,89.11 139.02,86.16 138.41,86.16 137.56,85.31 133.93,85.31 133.51,84.89 126.55,84.89 121.11,79.44 115.74,79.44 115.57,79.62 113.15,79.62 111.89,78.36 v1(111.85,78.36) ; v2(118.36,62.32) 118.35,62.32 118.33,62.31 118.33,62.31 117.55,61.53 117.16,61.53 116.92,61.77 115.91,61.77 115.18,62.5 115.18,62.63 114.91,62.9 114.52,62.9 114.16,62.55 109.45,62.55 108.49,63.51 107.67,63.51 107.2,63.04 107.03,63.04 106.69,62.7 106.69,62.69 106.43,62.43 106.43,60.66 106.42,60.64 106.42,60.16 106.65,59.93 106.65,54.66 102.93,50.94 99.96,50.94 98.7,52.2 98.7,57.01 v2(99.09,57.4)
  L4 w0.127: v1(111.85,78.36) 110.93,77.43 107.49,77.43 106.13,78.79 103.54,78.79 103.2,78.46 102.49,78.46 100.88,76.84 100.88,72.56 102.79,70.65 104.96,70.65 107.31,68.3 111.75,68.3 117.21,62.84 117.85,62.84 118.35,62.35 118.35,62.34 v2(118.36,62.32) ; v2(22.23,163.91) 20.89,162.56 20.89,158.95 19.13,157.19 19.13,142.23 23.19,138.17 32.37,138.17 v2(33.13,137.41)
  BOTTOM w0.102: PR5110.2 167.55,89.59 167.42,89.46 v1(167.24,89.46) ; v4(119.34,62.49) 118.53,62.49 v2(118.36,62.32) 118,62.32 117.44,62.89 116.3,62.89 D18.A ; v1(139.28,108.36) 139.28,108.27 139.67,107.87 140.96,107.87 142.37,109.29 142.37,109.88 144.53,112.04 149.47,112.04 150.25,111.26 150.25,99.95 156.8,93.4 156.8,90.73 159.34,88.19 v1(159.34,86.33) ; PR4502.2 PC4510.1 PR4503.1 22.28,163.86 v2(22.23,163.91)
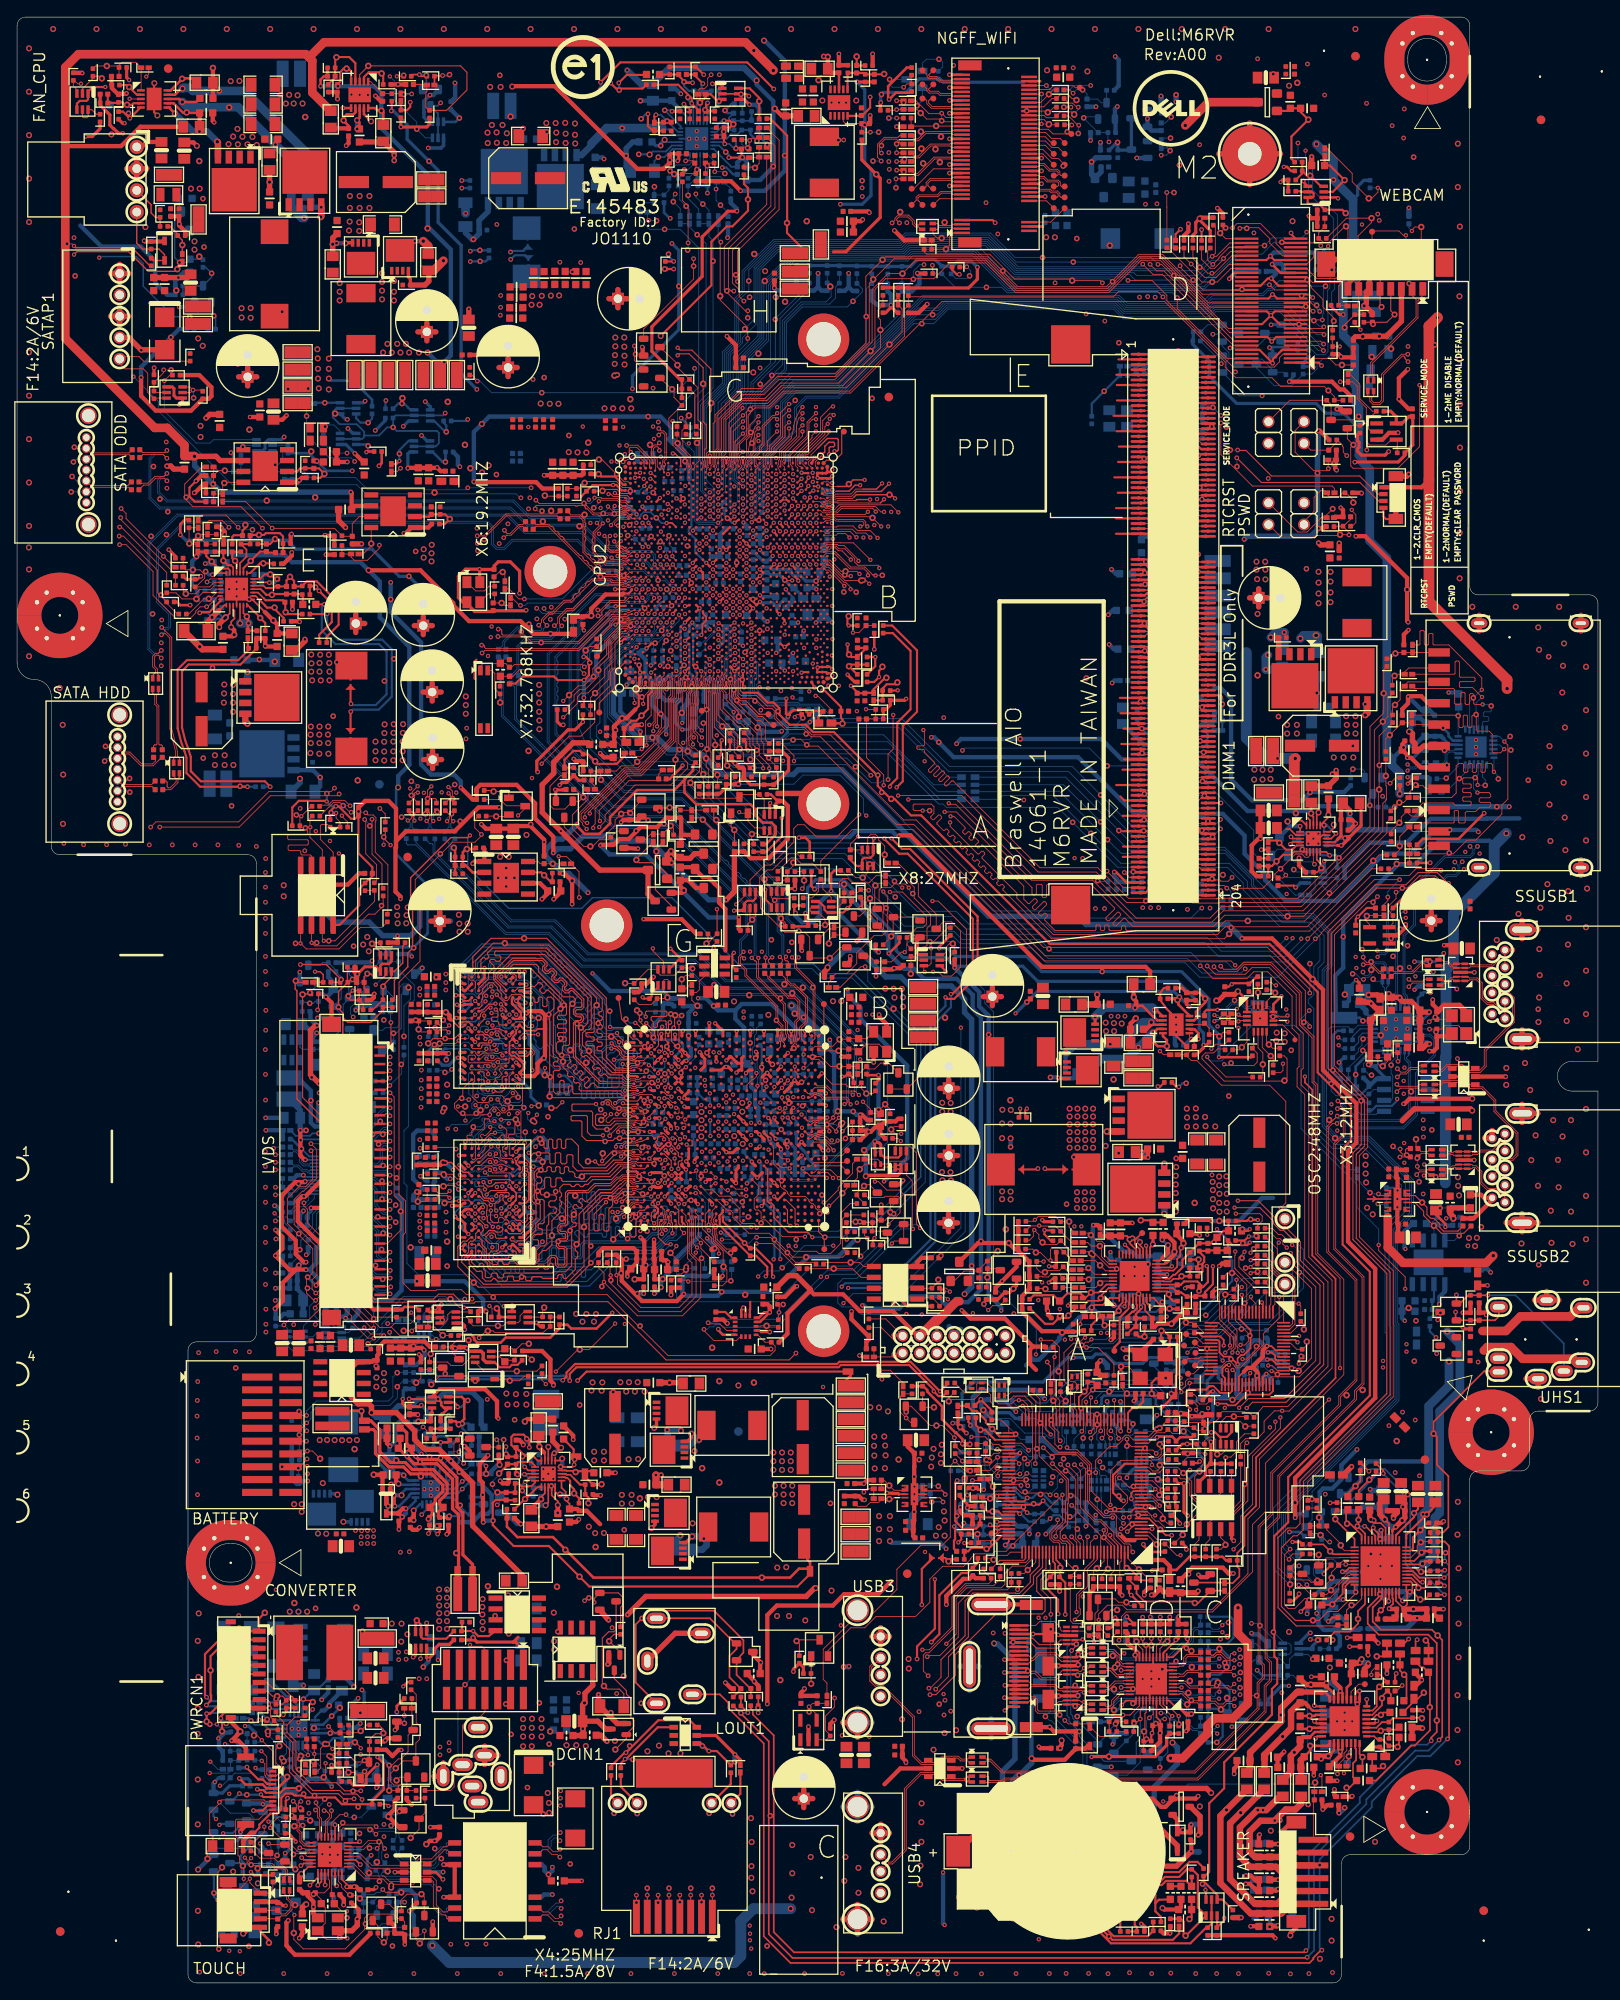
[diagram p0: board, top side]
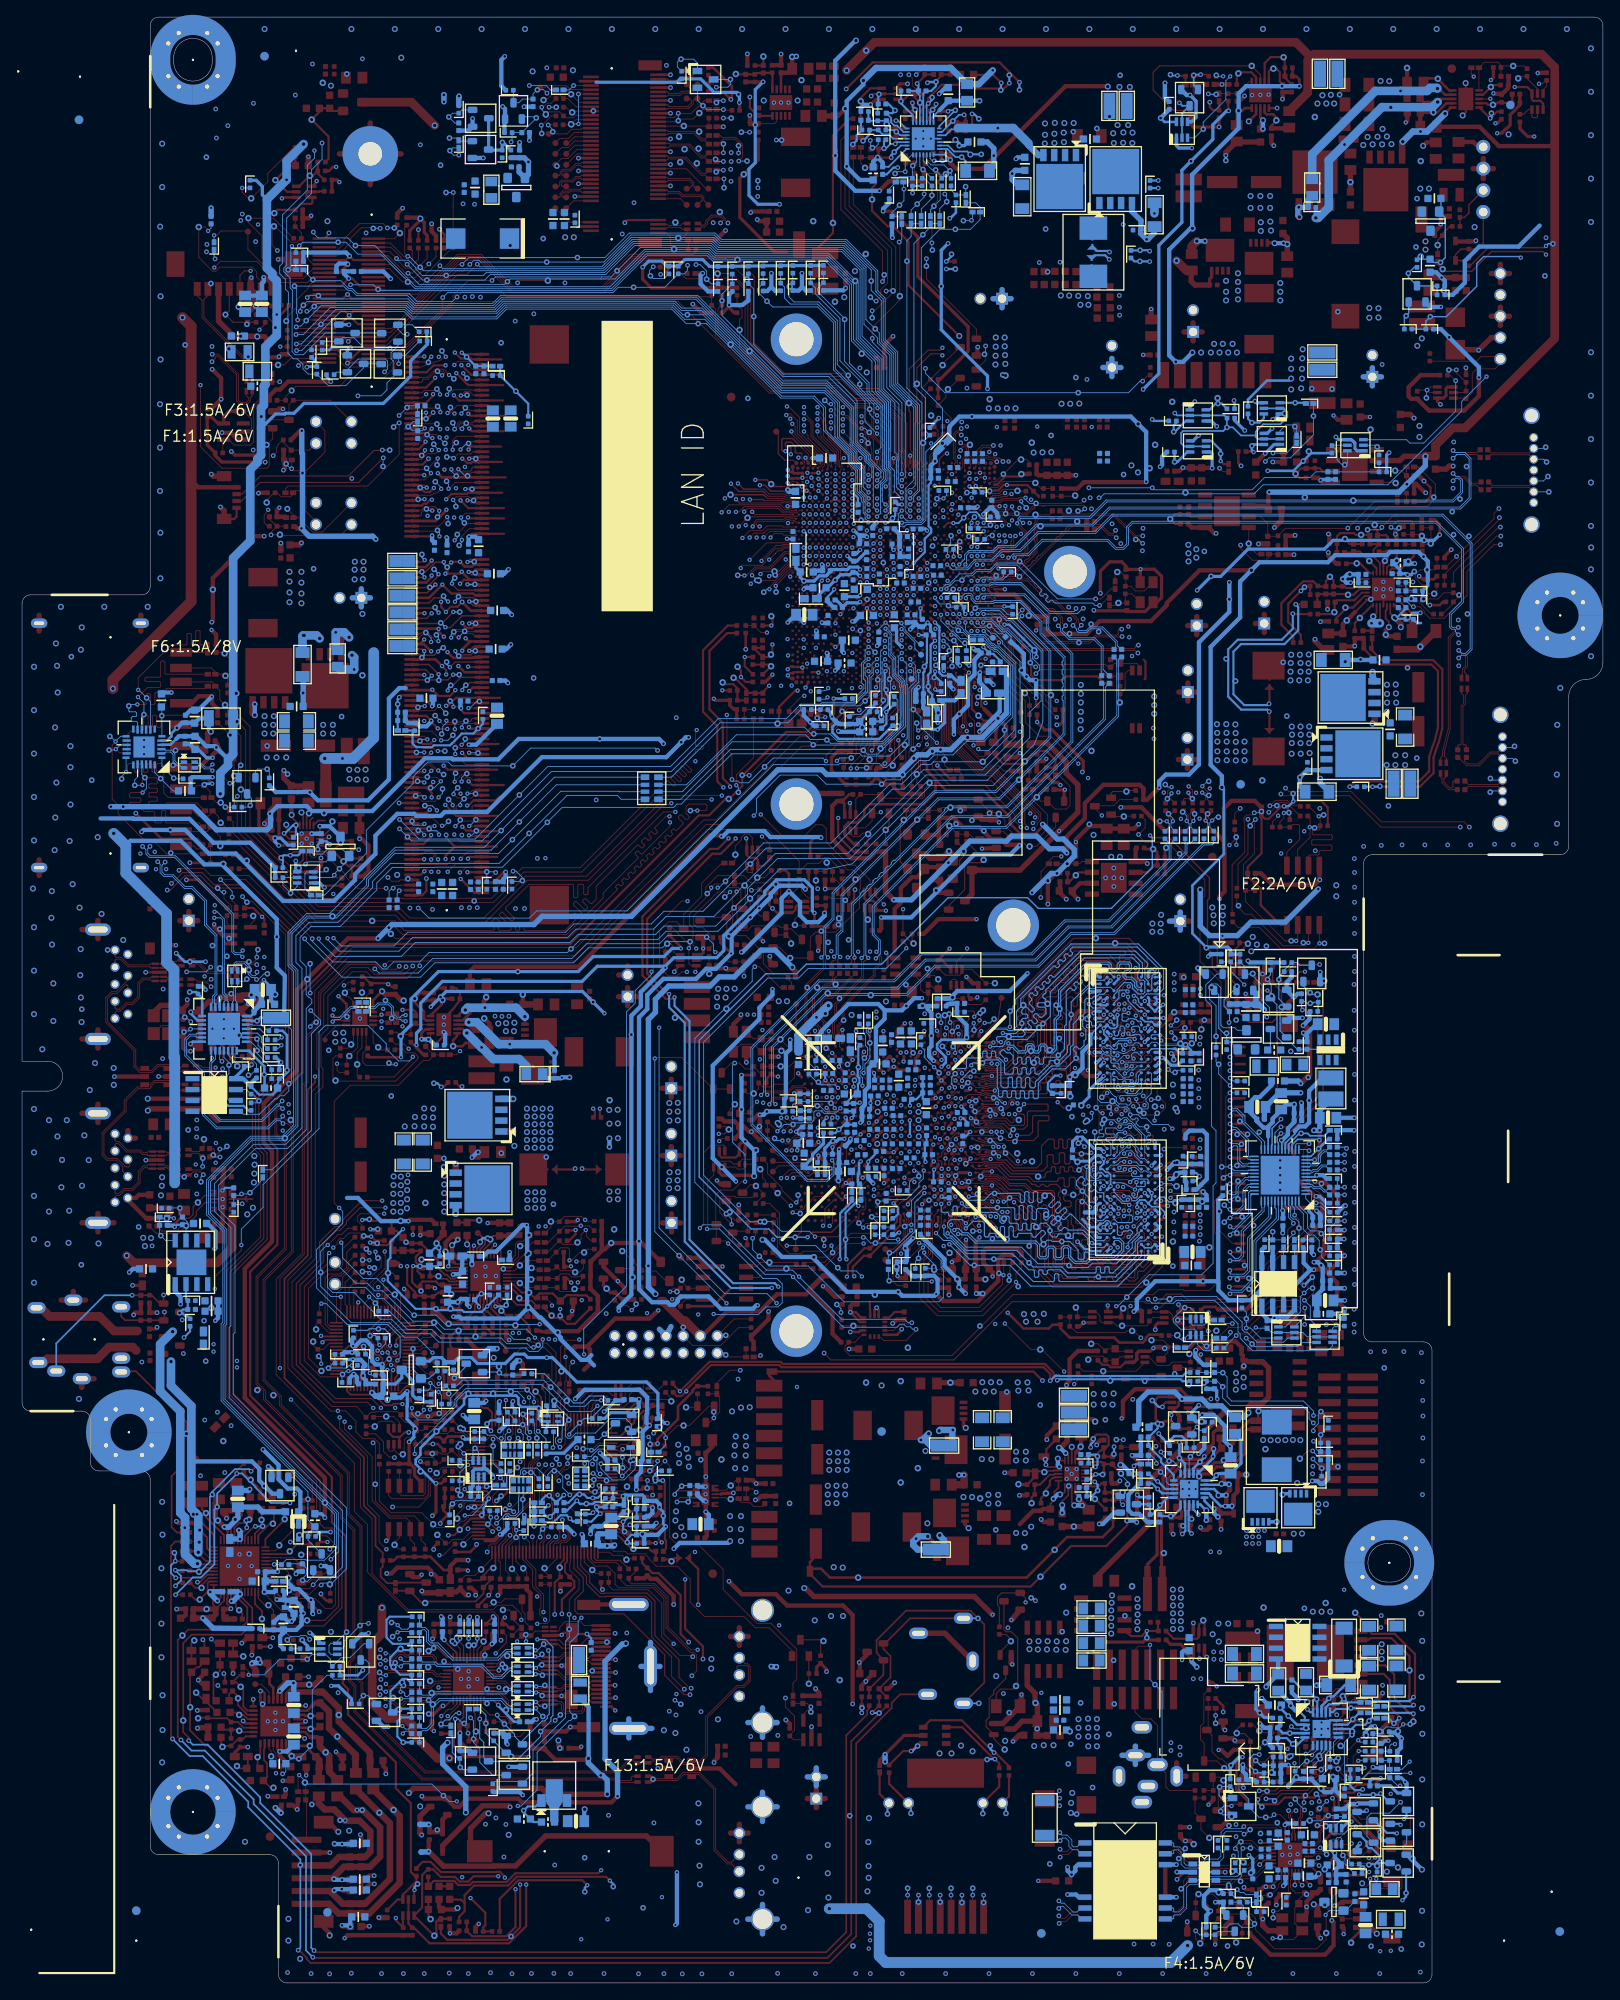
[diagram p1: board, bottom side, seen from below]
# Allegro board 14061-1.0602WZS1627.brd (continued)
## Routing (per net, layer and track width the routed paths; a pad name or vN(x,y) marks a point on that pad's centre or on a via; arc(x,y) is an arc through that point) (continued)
SLP_S3_N_EC: length 26.3
  TOP w0.102: R79961.1 146.87,88.29 147.61,87.55 148,87.55 149.22,86.33 v1(149.22,86.33) ; v1(147.7,80.28) 147.7,77.8 145.84,75.94 145.84,74.67 143.13,71.96 142.66,71.96 142.43,72.2 142.43,72.27 141.98,72.71 141.54,72.71 140.87,72.04 U4101.30
  BOTTOM w0.102: v1(149.22,86.33) 149.31,86.33 150.05,85.6 v4(150.05,83.13) 150.05,81.5 148.85,80.3 147.96,80.3 147.95,80.29 147.71,80.29 v1(147.7,80.28)
SLP_S3_N_G: length 4.2
  TOP w0.102: Q78.G 100.36,125.97 100.36,125.99 100.37,125.99 100.37,128.32 v3(100.44,128.4) 100.69,128.65 101.62,128.65 R1669.2
SLP_S3_N_R3: length 6.7
  TOP w0.102: U109.76 114.99,59.94 114.76,59.72 v2(114.76,59.31)
  BOTTOM w0.102: D18.K v4(113.79,61.1) 113.83,61.06 113.83,60.25 v2(114.76,59.31) 114.78,59.31 R676.1
SLP_S4_N: length 259.4
  TOP w0.102: v2(160.41,127.04) 160.41,126.62 159.95,126.16 R79660.2 ; R79960.2 145.16,87.44 145.45,87.73 146.75,87.73 147.41,87.07 147.8,87.07 148.12,86.75 148.12,86.46 148.53,86.04 148.56,86.04 v1(148.58,86.03) ; R1599.2 94.78,35.08 94.34,35.52 94.34,39.05 97.35,42.06 98.99,42.06 102.95,46.03 102.95,48.38 105.77,51.2 108.26,51.2 109.21,52.15 109.21,60.51 v2(109.76,61.06) 110.85,59.97 R385.2 ; PU5001.8 151.7,131.01 v2(151.82,130.89) ; v1(148.14,107.54) 148.14,106.76 147.88,106.5 R80064.2 ; v1(106.21,118.29) 106.1,118.39 Q17.3 106.7,119.01 106.97,119.28 v1(106.97,121.06) 106.97,121.53 108.88,123.45 R67.1 ; v2(161.78,129.08) 158.85,129.08 152.62,122.86 152.62,122.76 152.03,122.17 v2(151.93,122.17)
  L3 w0.127: v2(151.82,130.89) 151.82,129.25 151.25,128.68 151.25,124.06 149.83,122.64 149.83,121.99 150.12,121.7 151.46,121.7 v2(151.93,122.17) 152,122.09 152,121.49 150.22,119.71 150.22,109.63 v1(148.14,107.54) 149.03,106.65 150.87,106.65 151.15,106.37 151.15,104.86 150.32,104.04 150.32,103.54 150.3,103.51 150.3,88.5 148.61,86.81 148.61,86.06 v1(148.58,86.03)
  L4 w0.127: v1(106.21,118.29) 106.21,116.4 110.45,112.15 v1(110.45,111.76) ; v1(96.71,79.53) 96.45,79.27 93.18,79.27 91.97,78.06 91.97,75.3 91.99,75.28 91.99,75.23 96.34,70.88 96.34,70.83 97.59,69.57 97.59,68.12 100,65.71 102.78,65.71 104.86,63.62 108.33,63.62 109.76,62.19 v2(109.76,61.06)
  BOTTOM w0.102: v1(96.71,79.53) 97.82,80.64 102.76,80.64 110.45,88.33 v1(110.45,111.76) ; v2(160.41,127.04) 160.41,127.71 v2(161.78,129.08) ; Q1240.G 149.44,131.17 151.54,131.17 v2(151.82,130.89) ; v1(106.97,121.06) 106.83,121.2 v4(106.83,121.83) 109.34,121.83 110.07,121.11 118.72,121.11 120.48,119.35 136.69,119.35 138.37,117.67 147.54,117.67 151.93,122.06 v2(151.93,122.17)
SLP_S4_N_C: length 6.1
  TOP w0.102: U109.74 114.62,60.74 113.85,59.97 R385.1 112.31,59.55 112.07,59.31 111.16,59.31 v3(110.9,59.05)
SLP_S5_N_D: length 5.4
  BOTTOM w0.102: Q48.6 152.81,128.27 v4(153.58,127.51) 154.48,128.41 R549.2 154.45,129.34 Q48.5
SLP_S5_N_EC: length 21.3
  TOP w0.102: R79960.1 146.11,87.25 147.48,85.88 147.48,83.93 148,83.41 149.3,83.41 151.49,81.23 151.49,73.12 v3(149.97,71.6) 149.53,72.04 U4101.51
SLP_SLP_S0#_CPU: length 58.1
  TOP w0.089: CPU2.A13 71.08,158.1 70.67,158.1 69.4,156.83 69.4,156.79
  TOP w0.102: v1(63.91,148.08) 63.95,148.08 65.59,149.72 65.59,150.48 66.03,150.92 66.81,150.92 68.77,152.88 68.77,153.65 69.4,154.29 69.4,156.79 ; v2(91.88,128.02) 92.1,128.23 v3(92.1,128.98) 92.08,129 R1582.1 91.04,130.03 R1581.2
  L4 w0.127: v1(63.91,148.08) 63.44,147.61 63.44,142.79 69.86,136.37 69.86,135.98 70.65,135.19 71.08,135.19 78.87,127.39 81.61,127.39 82.05,127.84 85.71,127.84 86.11,127.44 91.31,127.44 v2(91.88,128.02)
SLP_SLP_S0#_CPU_D: length 3.9
  TOP w0.102: v3(89.39,124.54) 89.56,124.71 Q1206.6 ; v3(89.39,124.54) 88.91,125.03 Q1206.5 ; v3(89.39,124.54) 89.9,124.04 R1579.1
SLP_SLP_S0#_CPU_G: length 4.4
  TOP w0.102: Q1206.2 88.91,128.22 89.72,129.03 C1607.1 R1581.1 90.84,130.72 v3(90.84,131.08)
SM_RCOMP_1: length 19.2
  TOP w0.254: v3(101.26,153.99) 101.11,153.84 101.11,153.77 100.87,153.53 v1(100.87,152.78) 100.3,152.21 R1217.2 ; CPU2.BA26 91.41,164.15 91.41,164.06 v1(91.42,164.06)
  L3 w0.254: v1(100.87,152.78) 100.32,152.78 96.13,156.96 96.13,157.75 91.47,162.41 91.47,163.26 91.41,163.32 91.41,164.06 v1(91.42,164.06)
SMB0_ALERT#: length 7.8
  TOP w0.102: v2(123.57,221.1) 123.18,221.49 R1623.1
  BOTTOM w0.102: R1743.2 127.5,219.99 Q1210.D 126.86,219.98 126.43,220.41 PC5254.1 125.2,221.01 124.72,221.49 v4(124.7,221.49) 124.67,221.51 123.99,221.51 v2(123.57,221.1)
SMB0_ALERT#_C: length 159.8
  TOP w0.102: CPU2.AM9 v1(85.93,155.6)
  L3 w0.127: v2(132.3,197.29) 132.3,197.62 128.73,201.19 128.73,214.45 127.8,215.39 v2(127.77,215.39)
  L4 w0.127: v1(85.93,155.6) 86.38,155.15 86.38,154.21 88.53,152.07 88.53,151.17 90.23,149.47 99.53,149.47 101.83,147.17 104.41,147.17 109.8,141.78 110.63,141.78 113.11,139.29 119.4,133.01 137.69,133.01 139.87,135.19 139.87,161.02 141.13,162.28 141.13,173.93 141.77,174.56 141.77,186.87 139.76,188.87 139.76,190.82 135,195.58 134.02,195.58 v2(132.3,197.29)
  BOTTOM w0.102: Q1210.S 126.24,218.34 124.95,218.34 v4(124.82,218.21) 124.82,218.17 PC5251.1 R1742.2 127.66,215.51 v2(127.77,215.39)
SMB0_CLK_C: length 130.3
  TOP w0.102: CPU2.AM6 v1(85.93,154.18)
  L3 w0.127: v2(142.58,188.49) 142.58,188.41 142.63,188.36 142.63,181.85 140.38,179.6 140.38,150.22 140.52,150.09 140.52,138.45 140.32,138.25 140.32,135.61 140.83,135.1 v2(140.83,135.03)
  BOTTOM w0.102: v2(142.58,188.49) 142.22,188.85 142.22,189.74 142.47,189.99 145.67,189.99 146.93,188.73 Q1204.S 148.2,188.45 R1739.2 ; v1(85.93,154.18) 86.34,153.77 86.34,153 86.07,152.73 86.07,151.03 87.47,149.63 91.26,149.63 91.48,149.41 93.79,149.41 93.94,149.26 93.94,148.87 95.37,147.43 103.32,147.43 109.02,141.73 123.05,141.73 131.17,133.6 139.4,133.6 v4(139.9,134.1) v2(140.83,135.03)
SMB0_CLK_MAIN: length 306.8
  TOP w0.102: v2(80.87,77.24) 81,77.11 82.25,77.11 83.03,76.33 U6701.4 ; DIMM1.202 140.8,127.85 v2(140.87,127.78) ; Q123.6 102.76,97.88 102.9,98.02 104.34,98.02 105.24,97.12 105.24,88.82 105.67,88.39 v1(105.67,88.32) ; XDP1.53 148.26,202.58 147.33,203.5 147.33,204.02 145.51,205.84 142.75,205.84 v2(142.25,205.33)
  L3 w0.127: v1(126.84,76.05) 126.84,76.76 127.4,77.32 131.66,77.32 133.87,79.53 138.01,79.53 138.62,80.14 142.1,80.14 142.93,80.96 143.5,80.96 143.65,81.11 144.08,81.55 144.93,81.55 146.82,83.44 146.82,85.01 147.01,85.2 147.01,86.64 149.27,88.91 149.27,103.19 145.66,106.8 145.66,109.25 144.9,110.01 144.9,110.57 144.03,111.45 144.03,114.06 143.42,114.67 143.42,116.65 141.38,118.68 141.38,119.25 140.87,119.77 v2(140.87,127.78) 139.3,129.35 139.3,138.67 139.5,138.87 139.5,149.67 139.36,149.8 139.36,180.22 141.35,182.2 141.35,189.03 v2(140.93,189.45) 140.93,189.66 139.33,191.26 139.33,202.41 v2(142.25,205.33)
  L4 w0.127: v2(80.87,77.24) 74.64,77.24 71.63,80.25 71.07,80.25 53.48,80.25 v2(53.24,80) ; v1(94.06,82.63) 94.54,82.15 95.05,82.15 95.31,82.41 102.37,82.41 102.63,82.16 111.53,82.16 112.02,81.66 118.31,81.66 119.1,80.87 122.07,80.87 126.84,76.11 v1(126.84,76.05)
  BOTTOM w0.102: v2(140.87,127.78) 140.91,127.74 140.91,127.66 141.1,127.46 PC5256.1 ; v2(53.24,80) 52.76,79.53 50.24,79.53 49.93,79.83 45.41,79.83 42.71,77.13 42.71,76.19 42.45,75.93 42.45,75.43 40.99,73.96 32.21,73.96 31.63,74.55 Q7.4 ; v1(105.67,88.32) 105.29,88.7 103.18,88.7 97.87,83.39 94.83,83.39 v1(94.06,82.63) 89.08,77.64 81.7,77.64 81.3,77.24 v2(80.87,77.24) ; R1744.2 140.18,190.39 Q1212.S 140.93,190.25 v2(140.93,189.45) ; v2(142.25,205.33) v4(141.43,205.33)
SMB0_CLK_RESUME: length 187.2
  TOP w0.102: R14.1 123.06,219.94 123.52,219.94 124.01,219.46 v2(124.19,219.46)
  L3 w0.127: v1(154.62,110.62) 154.62,111.79 155.85,113.01 155.85,126.48 163.47,134.1 163.47,158.96 163.29,159.14 163.29,175.2 161.55,176.94 161.55,180.31 158.55,183.31 158.55,197.18 158.71,197.33 158.71,202.3 158.64,202.36 158.64,204.14 157.63,205.16 157.33,205.16 151.58,210.91 151.58,212.56 150.78,213.36 v1(150.78,214.38)
  L4 w0.127: v2(124.19,219.46) 124.61,219.46 127.95,216.12 138.27,216.12 140.23,218.08 146.11,218.08 149.81,214.38 v1(150.78,214.38)
  BOTTOM w0.102: v4(123.7,218.68) 124.19,219.17 v2(124.19,219.46) ; Q1212.D 143,189.43 Q1204.D 145.03,188.96 147.11,186.88 149.16,186.88 R1741.2 151.5,188.23 152.13,188.85 152.13,189.35 152.79,190.02 153.24,190.02 153.88,190.66 153.88,196.44 153.83,196.49 153.83,197.82 154.19,198.17 154.19,199.34 154.85,200 154.85,200.86 154.52,201.19 154.52,206.86 151.62,209.75 151.62,212.65 150.78,213.49 v1(150.78,214.38) ; R80238.2 154.97,110.34 154.69,110.62 v1(154.62,110.62)
SMB0_CVT_CLK: length 5.3
  TOP w0.102: C3456.1 34.78,26.79 v1(34.78,26.79) 34.8,26.77 34.8,26.63 34.81,26.62 R79633.1
  BOTTOM w0.102: v4(36.51,26.57) 36.29,26.79 v1(34.78,26.79) 34.63,26.79 33.93,27.49 U120.6
SMB0_CVT_DATA: length 4.5
  TOP w0.102: R79634.1 33.21,26.09 v3(33.21,26.55) 33.31,26.65 v1(34.04,26.65) 34.04,27.5 C43.1
  BOTTOM w0.102: v1(34.04,26.65) 34.04,26.69 33.43,27.31 U120.7
SMB0_DATA_C: length 132.8
  TOP w0.102: CPU2.AM7 v1(85.93,154.89)
  L3 w0.127: v2(140.83,136.12) 141.35,136.64 141.35,179.41 141.35,179.84 143.14,181.64 143.14,184.94 143.16,184.97 143.16,190.17 142.04,191.29 v2(141.94,191.29)
  BOTTOM w0.102: v1(85.93,154.89) 86.54,154.28 86.54,152.58 86.28,152.31 86.28,151.11 87.56,149.83 91.34,149.83 91.56,149.61 93.87,149.61 95.57,147.92 103.53,147.92 109.13,142.32 123.48,142.32 v4(126.8,138.99) 131.96,133.83 138.54,133.83 v2(140.83,136.12) ; v2(141.94,191.29) 144.96,191.29 146.15,192.48 146.66,192.48 146.7,192.51 147.47,192.51 Q1203.S 149.75,192.06 R1738.2
SMB0_DATA_MAIN: length 297.9
  TOP w0.102: XDP1.51 148.07,202.07 146.59,203.56 146.59,204.07 145.31,205.36 143.16,205.36 v2(143.09,205.28) ; v2(80.39,76.47) 80.39,76.31 81.53,75.17 84.19,75.17 84.64,75.61 U6701.6 ; Q123.3 104.06,94.52 104.76,93.83 104.76,88.29 v1(104.83,88.21) ; v2(141.56,128.09) 141.26,128.4 140.71,128.4 140.65,128.45 DIMM1.200
  L3 w0.127: v2(143.09,205.28) 140.42,202.62 140.42,193.37 v2(139.94,192.89) 139.96,192.86 139.96,191.35 141.43,189.87 141.43,189.66 141.85,189.24 141.85,181.79 139.87,179.81 139.87,150.01 140.01,149.88 140.01,138.66 139.81,138.46 139.81,129.97 141.56,128.22 v2(141.56,128.09) 141.56,119.79 141.89,119.46 141.89,119.04 143.95,116.98 143.95,114.86 144.53,114.27 144.53,111.66 145.41,110.79 145.41,110.22 146.17,109.46 146.17,107.01 149.78,103.4 149.78,88.69 148.1,87.02 148.1,86.25 147.52,85.67 147.52,84.99 147.35,84.83 147.35,83.25 145.14,81.04 144.51,81.04 142.84,79.38 138.57,79.38 138.2,79.01 134.06,79.01 131.87,76.81 128.13,76.81 127.59,76.28 127.59,76.07 v1(127.57,76.05)
  L4 w0.127: v1(94.77,82.6) 95.1,82.92 102.58,82.92 102.84,82.66 118.03,82.66 119.31,81.38 122.31,81.38 127.57,76.13 v1(127.57,76.05) ; v2(80.39,76.47) 74.7,76.47 71.42,79.74 53.69,79.74 53.48,79.54 52.86,79.54 v2(52.38,80.01)
  BOTTOM w0.102: R1745.2 139.33,194 Q1213.S 141.02,193.48 140.42,192.89 v2(139.94,192.89) ; v2(80.39,76.47) 80.75,76.47 81.05,76.76 81.5,76.76 81.75,77.01 82.3,77.01 82.61,76.71 88.89,76.71 v1(94.77,82.6) 95.08,82.91 98.08,82.91 103.39,88.21 v1(104.83,88.21) ; v4(143.9,205.28) v2(143.09,205.28) ; v2(141.56,128.09) 141.69,128.09 142.04,127.74 PC5255.1 ; Q4.4 36.88,75.45 37.36,74.97 40.48,74.97 41.65,76.14 41.92,76.14 42.22,76.44 42.22,77.33 45.21,80.31 50.13,80.31 50.44,80.01 v2(52.38,80.01)
SMB0_DATA_RESUME: length 186.9
  TOP w0.102: R1622.1 v2(123.32,219.46)
  L3 w0.127: v1(154.65,109.71) 154.11,110.25 154.11,112 155.34,113.23 155.34,126.98 162.71,134.35 162.71,139.46 162.25,139.92 162.25,143.52 162.31,143.58 162.31,175.46 161.04,176.73 161.04,180.09 158.05,183.08 158.05,196.95 157.74,197.26 157.74,199.31 157.73,199.32 157.73,199.69 157.74,199.7 157.74,201.85 158.14,202.25 158.14,203.93 157.45,204.62 157.15,204.62 151.07,210.69 151.07,212.05 149.89,213.23 v2(149.89,215.26)
  L4 w0.127: v2(149.89,215.26) 149.89,215.63 146.94,218.58 140.02,218.58 138.06,216.62 128.16,216.62 124.82,219.96 123.83,219.96 v2(123.32,219.46)
  BOTTOM w0.102: R80239.2 155.05,109.31 v1(154.65,109.71) ; v2(149.89,215.26) 149.89,213.36 151.12,212.13 151.12,209.39 154.03,206.48 154.03,200.97 154.36,200.64 154.36,200.2 153.63,199.47 153.63,198.32 153.35,198.04 153.35,195.99 153.4,195.94 153.4,190.86 153.04,190.5 152.08,190.5 151.51,191.07 R1740.2 151.11,191.44 149.51,193.04 Q1203.D 142.95,193.04 Q1213.D ; v2(123.32,219.46) v4(122.49,219.46)
SMBUS_ISP: length 120.2
  TOP w0.102: v1(40.62,76.68) 41.38,75.92 42.73,75.92 v2(42.91,75.74) ; v2(124.37,52.17) 124.81,51.73 U109.115
  L3 w0.127: v2(124.37,52.17) 121.6,49.4 114.81,49.4 114.05,48.64 104.58,48.64 104.34,48.4 98.9,48.4 94.72,52.58 94.72,65.47 88.11,72.09 55.8,72.09 54.19,73.7 50,73.7 48.49,75.21 43.44,75.21 v2(42.91,75.74)
  BOTTOM w0.102: R2079.2 44.35,74.3 v2(42.91,75.74) ; v2(124.37,52.17) 124.37,52.82 v4(124.08,53.11) 123.85,53.34 R297.2 ; Q7.5 Q7.2 34.6,75.59 35.11,76.1 Q4.5 Q4.2 38.81,76.1 C1877.1 40.53,76.59 v1(40.62,76.68)
SMBUS_ISP_G: length 13.5
  BOTTOM w0.102: R2079.1 45.52,73.99 46.74,73.99 47.45,74.7 47.45,74.89 47.62,75.06 ; Q95.2 47.62,78.35 48.28,79.01 v4(48.94,79.01) 49.02,79.01 50.27,77.76 50.27,77.34 49.42,76.48 47.8,76.48 47.62,76.3 Q95.5 47.62,75.06 ; 47.62,75.06 47.86,75.06 48.6,74.32 R2080.2
SOC_EXTSMI_N: length 31.7
  TOP w0.089: CPU2.AG53 83.97,179.04 84,179.06 84,179.25
  TOP w0.102: v1(84.94,181.26) 84.09,180.41 84.09,180.4 84,180.31 84,179.25
  BOTTOM w0.102: R1810.2 R1811.1 98.92,198.21 98.92,197.85 97.82,196.76 v4(97.82,196.75) 97.81,196.75 97.15,196.09 91.89,196.09 90.05,194.24 90.05,188.73 89.61,188.29 86.35,185.03 86.35,182.67 v1(84.94,181.26)
SOC_RUNTIME_SCI#: length 84.6
  TOP w0.089: CPU2.AG51 84.16,177.26 84.16,177.55 84.26,177.65 84.26,177.98 84.16,178.07 84.16,178.96 84.22,179.02 84.22,179.25
  TOP w0.102: 84.22,179.25 84.22,179.97 85.35,181.1 85.35,183.78 86.08,184.51 87.95,184.51 89.67,186.24 97.43,186.24 103.84,192.65 103.84,195.82 R1808.1 R1809.2 104.44,197.28 128.3,197.28 128.89,197.88 133.47,197.88 v2(134.09,197.26)
  BOTTOM w0.102: R1569.1 152.06,200.37 v4(150.97,199.27) 150.86,199.16 147.68,199.16 146.74,198.23 146.34,198.23 145.75,197.64 139.68,197.64 138.77,196.72 134.63,196.72 v2(134.09,197.26)
SOC_RUNTIME_SCI#_XDP: length 9.8
  TOP w0.102: v1(153.42,203.2) 153.02,202.8 152.09,202.8 151.72,202.43 151.72,201.9 150.9,201.07 XDP1.47
  BOTTOM w0.102: C1605.2 R1569.2 v4(153.86,200.43) 153.55,200.74 153.55,203.07 v1(153.42,203.2)
SPEED_100*_CON: length 4.9
  TOP w0.254: RJ1.12 69.5,21.81 UR6.2
  BOTTOM w0.254: v4(69.86,19.84) 69.86,20.62 RJ1.12
SPEED_100_N: length 61.1
  TOP w0.203: U20.26 35.61,11.85 v2(35.19,11.43)
  TOP w0.254: U6705.6 78.71,30.73 75.05,30.73 v2(71.25,26.94) 71.1,26.94 69.5,25.35 UR6.1
  L3 w0.254: v2(35.19,11.43) 36.53,12.77 37.62,12.77 38.78,13.93 38.78,17.07 41.37,19.66 57.07,19.66 62.42,25.01 70.82,25.01 71.81,26.01 71.81,26.38 v2(71.25,26.94)
  BOTTOM w0.254: v2(71.25,26.94) 71.6,27.28 71.69,27.35 v4(71.69,27.74)
SPEED_1000*_CON: length 5.3
  TOP w0.254: RJ1.11 70.65,22.96 UR7.2
  BOTTOM w0.254: v4(72.57,19.81) RJ1.11
SPEED_1000_N: length 55.9
  TOP w0.203: v2(34.27,11.43) 35.21,12.37 U20.25
  TOP w0.254: UR7.1 70.65,25.68 v2(71.15,26.19) 71.25,26.19 74.97,29.91 U6705.1
  L3 w0.254: v2(34.27,11.43) 36.1,13.25 37.26,13.25 38.37,14.36 38.37,17.24 41.2,20.07 56.78,20.07 62.26,25.55 70.51,25.55 v2(71.15,26.19)
  BOTTOM w0.254: v2(71.15,26.19) 72.02,26.19 v4(72.07,26.14)
SPI_CLK: length 62.4
  TOP w0.089: CPU2.W3 80.08,152.78 79.9,152.59 79.9,152.45 79.79,152.34 79.79,151.87 79.68,151.77 79.68,150.32
  TOP w0.102: v1(80.12,146.53) 79.59,147.06 79.59,149.45 79.68,149.55 79.68,150.32 ; v2(41.54,136.14) 41.54,132.06 42.7,130.9 42.7,128.21 R1714.1
  L3 w0.127: v2(41.54,136.14) 42.03,135.65 44.94,135.65 45.13,135.47 51.85,135.47 52.92,136.54 57.07,136.54 57.93,137.4 61.34,137.4 62.2,138.26 63.17,138.26 66.04,141.14 78.1,141.14 80.89,143.93 80.89,145.6 80.12,146.38 v1(80.12,146.53)
  BOTTOM w0.102: v1(80.12,146.53) 80.31,146.72 v4(80.31,147.4)
SPI_CLK_1: length 14.3
  TOP w0.102: R1714.2 42.84,126.02 41.87,125.04 41.12,125.04 37.41,121.34 34.83,121.34 v1(34.48,121.69) 34.45,121.72 U8.6
  BOTTOM w0.102: v1(34.48,121.69) 35.05,121.69 v4(35.06,121.7)
SPI_CS0_N: length 57.2
  TOP w0.102: CPU2.V4 v1(80.07,153.47) ; v1(38.01,136.56) 38.06,136.52 38.06,136.44 38.68,135.81 R1733.1
  L3 w0.127: v1(77.95,145.09) 77.95,145.07 75.51,142.63 65.56,142.63 65.19,142.26 64.22,142.26 60.76,138.8 53.21,138.8 52.11,137.7 43.95,137.7 42.88,138.77 39,138.77 38.01,137.78 v1(38.01,136.56)
  BOTTOM w0.102: v1(80.07,153.47) 80.07,152.2 80.89,151.38 80.89,149.17 v4(80.7,148.99) 79.8,148.08 79.8,146.94 v1(77.95,145.09)
SPI_CS0_N_ROM_1: length 10.2
  TOP w0.102: v1(37.33,136.88) 37.33,136.28 37.79,135.82 R1733.2 37.77,135.22 R172.2 36.32,135.53 35.62,135.53 35.49,135.41 35.49,133.78 36.99,132.28 U8.1
  BOTTOM w0.102: v4(36.75,136.92) 37.29,136.92 v1(37.33,136.88)
SPI_DATAIN: length 68.2
  TOP w0.089: 79.24,150.63 79.24,150.71 79.3,150.78 79.3,151.93 79.39,152.01 79.39,152.36 79.31,152.43 79.31,152.71 79.6,152.99 CPU2.V3
  TOP w0.102: v1(80.07,144.83) 79.64,145.26 79.64,145.87 79.18,146.33 79.18,149.62 79.24,149.68 79.24,150.63 ; v2(39.1,136.97) 39.08,136.99 38.91,136.99 37.78,138.13 37.06,138.13 36.5,137.57 36.47,137.57 R1731.2
  L3 w0.127: v2(39.1,136.97) 39.12,136.97 39.26,136.83 39.71,136.83 39.83,136.96 39.83,137.88 39.96,138.01 42.56,138.01 43.64,136.94 44.17,136.94 44.17,136.94 44.59,136.94 44.59,136.94 52.42,136.94 53.52,138.04 53.93,138.04 54.06,137.91 54.06,137.36 54.18,137.24 54.44,137.24 54.56,137.36 54.56,137.91 54.69,138.04 54.94,138.04 55.07,137.91 55.07,137.36 55.2,137.24 55.45,137.24 55.58,137.36 55.58,137.91 55.71,138.04 60.91,138.04 60.91,138.04 61.08,138.04 61.94,138.9 62.91,138.9 64.3,140.3 64.3,140.48 64.03,140.75 64.03,140.93 64.21,141.11 64.39,141.11 64.66,140.84 64.84,140.84 65.78,141.77 76.63,141.77 76.76,141.9 76.76,142.19 76.88,142.32 77.14,142.32 77.27,142.19 77.27,141.9 77.39,141.77 77.84,141.77 78.57,142.5 78.57,142.68 77.94,143.31 77.94,143.49 78.12,143.67 78.3,143.67 78.93,143.04 79.11,143.04 79.29,143.22 79.29,143.4 79.05,143.64 79.05,143.82 79.23,144 79.41,144 79.65,143.76 79.83,143.76 80.07,144 v1(80.07,144.83)
  BOTTOM w0.102: v1(80.07,144.83) 80.26,144.83 v4(80.73,144.36)
SPI_DATAOUT: length 66.2
  TOP w0.089: CPU2.V2 79.6,151.95 79.49,151.85 79.49,150.63 79.44,150.58
  TOP w0.102: v2(40.8,136.91) 41.05,136.65 41.68,136.65 41.99,136.33 41.99,135.95 41.92,135.88 41.92,132.29 43.39,130.82 43.39,125.09 R1732.1 ; v1(80.14,145.72) 79.38,146.48 79.38,149.54 79.44,149.6 79.44,150.58
  L3 w0.127: v2(40.8,136.91) 41.02,136.69 44.06,136.69 44.06,136.68 44.69,136.68 44.69,136.69 52.53,136.69 52.76,136.92 56.74,136.92 57.6,137.78 61.18,137.78 62.04,138.65 63.01,138.65 65.88,141.52 77.94,141.52 80.51,144.08 80.51,145.12 80.14,145.49 v1(80.14,145.72)
  BOTTOM w0.102: v2(40.8,136.91) 40.11,136.91 v4(39.96,137.06)
SPI_IO2: length 57.1
  TOP w0.089: 79.01,150.63 79.01,150.78 79.11,150.88 CPU2.U1
  TOP w0.102: v2(38.97,137.72) 38.34,138.35 36.97,138.35 36.41,137.79 35.53,137.79 R1730.2 ; v1(79.18,145.72) 78.98,145.92 78.98,149.71 79.01,149.74 79.01,150.63
  L3 w0.127: v1(79.18,145.72) 79.18,145.51 79.54,145.15 79.54,144.73 78.89,144.08 78.03,144.08 75.98,142.02 65.67,142.02 65.4,141.76 64.43,141.76 60.97,138.29 60.81,138.29 60.8,138.29 53.42,138.29 52.32,137.19 43.74,137.19 42.67,138.26 39.52,138.26 v2(38.97,137.72)
  BOTTOM w0.102: v4(38.16,137.75) 38.18,137.75 38.18,137.74 38.95,137.74 v2(38.97,137.72)
SPI_IO3: length 65.4
  TOP w0.089: 78.78,150.63 78.78,150.82 78.92,150.96 78.92,151.93 78.84,152.01 78.84,152.36 79.11,152.63 CPU2.U3
  TOP w0.102: R1729.1 42.07,128.97 42.07,130.84 40.8,132.11 40.8,135.99 v2(40.67,136.12) ; v1(79.1,144.91) 79.1,145.19 78.77,145.52 78.77,150.62 78.78,150.63
  L3 w0.127: v1(79.1,144.91) 78.67,144.48 77.88,144.48 75.67,142.28 65.57,142.28 65.3,142.01 64.33,142.01 60.86,138.55 53.31,138.55 52.21,137.45 43.85,137.45 42.78,138.52 39.11,138.52 38.5,137.91 38.5,136.74 39.12,136.12 40.67,136.12 v2(40.67,136.12)
  BOTTOM w0.102: v2(40.67,136.12) 41.27,135.52 v4(41.27,135.38)
SPI_MISO_ROM_1: length 7.1
  TOP w0.102: U8.2 35.72,132.59 34.27,134.03 34.27,135.18 v1(34.31,135.22) 34.27,135.25 34.27,136.26 R1731.1
  BOTTOM w0.102: v1(34.31,135.22) 33.82,135.22 v4(33.74,135.14)
SPI_MOSI_1: length 14.5
  TOP w0.102: 33.18,121.64 U8.5 SRCON1.5 ; 33.18,121.64 33.84,120.98 37.68,120.98 40.19,123.49 42.68,123.49 R1732.2 ; 33.18,121.64 v1(33.17,121.63)
  BOTTOM w0.102: v1(33.17,121.63) v4(32.58,121.63)
SPI_WP#: length 18.1
  TOP w0.102: R1730.1 34.42,137.66 v1(33.26,136.5) 33.09,136.34 R169.2 33.09,135.03 33.22,134.9 33.88,134.9 34.01,134.77 34.01,134.45 33.88,134.33 31.78,134.33 31.66,134.2 31.66,133.88 31.78,133.76 33.95,133.76 34.08,133.63 34.08,133.25 33.95,133.13 31.85,133.13 31.72,133 31.72,132.61 31.85,132.49 33.08,132.49 33.21,132.36 33.21,132.09 33.33,131.97 34.32,131.97 34.45,131.84 U8.3
  BOTTOM w0.102: v1(33.26,136.5) 33.1,136.65 v4(32.68,136.65)
SPKR_DET: length 92
  TOP w0.102: R1203.1 152.7,24.17 v1(152.56,24.31) ; v2(121.55,52.25) 121.6,52.3 121.6,52.85 122.69,53.94 122.69,56.38 122.77,56.46 122.77,58.81 121.54,60.04 121.24,60.04 119.61,61.67 U109.59 119.61,66.77 119.71,66.87 119.71,68.29 118.87,69.13 R388.1
  L3 w0.127: v2(121.55,52.25) 122.23,52.93 125.25,52.93 125.78,53.47 125.78,54.94 127.47,56.63 128.24,56.63 128.75,56.11 128.75,56.1 129.38,55.47 130.55,55.47 131.14,54.89 131.14,53.87 131.44,53.56 131.44,52.72 133.27,50.89 133.27,46.42 137.73,41.96 137.73,33.87 137.55,33.69 137.55,26.47 134.28,23.2 134.28,21.4 v1(134.12,21.23)
  BOTTOM w0.102: v1(134.12,21.23) 135.01,21.23 v4(135.69,21.91) 137.04,23.27 151.52,23.27 v1(152.56,24.31)
SPKR_DET_C: length 6.8
  TOP w0.102: SPK1.6 151.7,21.3 PC2127.2 R1203.2 151.81,23.36 v3(151.9,23.44)
SPKR_IN_L: length 5.5
  TOP w0.203: C199.2 160.76,33.77 C203.2 159.72,33.52 v3(159.72,33.3) 159.72,32.49 158.59,31.36 U21.6
SPKR_IN_R: length 6.3
  TOP w0.203: U21.31 156.6,27.45 156.7,27.36 156.7,26.06 156.34,25.7 156.34,24.09 C210.2 155.91,22.83 v3(155.58,22.83)
SPKR_L+_C: length 25.1
  TOP w0.762: L31.2 143.9,22.62 v3(141.52,20.24) 140.81,19.53 140.81,11.68 144.36,8.13 C226.1 R396.1 147.96,8.13 149.08,9.25 SPK1.1
SPKR_L+_SNB: length 3.3
  TOP w0.508: R396.2 147.43,6.6 v2(147.56,6.73)
  BOTTOM w0.508: v2(147.56,6.73) 146.76,6.73 146.6,6.56 v4(146.59,6.56) 146.59,6.57 146.59,7.54 C222.1
SPKR_L-_C: length 23.7
  TOP w0.762: L32.2 145.22,21.92 145.19,21.92 v3(143.19,19.91) 141.96,18.68 141.96,12.15 144.84,9.27 147.48,9.27 148.96,10.75 SPK1.2
SPKR_L-_SNB: length 3.4
  TOP w0.508: v2(147.58,10.97) 147.53,10.97 147.35,10.79 R403.2
  BOTTOM w0.508: C239.1 146.34,10.97 v2(147.58,10.97) 148.32,10.97 v4(148.47,10.83)
SPKR_OUT_L+: length 16.2
  TOP w0.305: 152.68,33.97 153.11,33.97 153.6,33.47 U21.16
  TOP w0.635: 152.68,33.97 152.62,34.04 C224.2
  TOP w0.762: C224.2 149.79,34.04 147.94,32.18 147.94,31.36 v3(147.93,31.35) 147.93,31.3 147.94,31.29 147.94,30.6 144.29,26.96 144.29,26.02 C225.1 144.28,25.07 L31.1
SPKR_OUT_L-: length 13
  TOP w0.305: U21.18 151.62,31.86 151.1,32.37
  TOP w0.508: C228.2 150.71,32.77 151.1,32.37
  TOP w0.762: C228.2 150.1,32.77 149.08,31.75 149.08,29.8 v3(148.1,28.82) 146,26.72 145.98,26.72 C235.1 145.98,24.61 L32.1
SPKR_OUT_R+: length 6.9
  TOP w0.305: U21.25 153.32,27.74 v3(151.33,27.74) 151.33,27.16 C223.2
  TOP w0.762: L33.1 150.27,25.17 C247.1 150.22,26.06 C223.2
SPKR_OUT_R-: length 8.6
  TOP w0.305: U21.23 151.87,29.36 151.26,28.75
  TOP w0.508: C229.2 150.45,28.75 151.26,28.75
  TOP w0.762: L34.1 149.05,24.69 C255.1 149.05,26.57 v3(149.47,26.98) 150.15,27.66 C229.2
SPKR_R+_C: length 19.3
  TOP w0.711: C248.1 R415.1
  TOP w0.762: SPK1.4 148.89,13.75 147.91,14.73 R415.1 ; C248.1 144.86,14.73 144.24,15.35 144.24,17.72 145.5,18.97 147.15,18.97 v2(147.18,19) 148.47,20.29 149.59,20.29 150.27,20.98 L33.2
  BOTTOM w0.254: v2(147.18,19) 147.75,19 v4(147.78,19.03)
SPKR_R+_SNB: length 3.2
  TOP w0.508: R415.2 147.54,16.26 v2(147.56,16.24)
  BOTTOM w0.508: C243.1 146.32,16.24 v2(147.56,16.24) 148.4,16.24 v4(148.44,16.28)
SPKR_R-_C: length 20.2
  TOP w0.711: C256.1 R419.1
  TOP w0.762: L34.2 147.78,21.82 146.18,20.22 v2(145.8,20.22) 145.12,20.22 143.1,18.19 143.1,14.77 144.28,13.59 C256.1 ; R419.1 147.33,13.59 148.67,12.25 SPK1.3
  BOTTOM w0.254: v2(145.8,20.22) 145.2,20.22 v4(145.19,20.23)
SPKR_R-_SNB: length 3.3
  TOP w0.508: R419.2 v2(147.56,12.06)
  BOTTOM w0.508: C263.1 146.31,12.06 v2(147.56,12.06) 148.4,12.06 v4(148.49,12.15)
SPV10: length 14.6
  TOP w0.254: GPU1.H8 76.2,93.2 76.57,93.58 v1(76.59,93.58)
  TOP w0.508: v3(72.27,82.32) 72.29,82.34 L51.2 C787.1 73.34,84.62 C789.1 C785.1 73.4,86.78 v1(72.95,87.23)
  L4 w0.356: v1(76.59,93.58) 76.38,93.37 76.38,91.8 73.56,88.98 73.56,87.83 72.96,87.23 v1(72.95,87.23)
SPV18: length 12.2
  TOP w0.254: GPU1.H7 75.81,92.01 75.8,92.01 v1(75.79,92)
  TOP w0.508: v3(75.56,82.35) 75.55,82.34 L49.2 C788.1 74.61,84.62 C792.1 C793.1 v1(74.54,86.95)
  L3 w0.508: v1(74.54,86.95) 73.94,87.55 73.94,89.28 75.79,91.13 v1(75.79,92)
SST_HOLDJ_1: length 12.8
  TOP w0.102: SRCON1.7 U8.7 35.72,122.1 v1(35.9,121.92) 37.2,121.92 41.84,126.56 41.84,127.8 R1729.2 40.75,127.83 R186.2
  BOTTOM w0.102: v1(35.9,121.92) v4(36.48,121.92)
SSTCMP: length 3.9
  BOTTOM w0.102: R45.1 31.14,26.15 v4(30.97,26.31) 31.53,26.87 31.53,28.16 U120.11
SSTCMP_1: length 2.8
  BOTTOM w0.102: C5.1 32.82,24.37 R45.2 31.21,25.26 v4(31,25.04)
STATUS: length 4.7
  BOTTOM w0.102: R61.1 34.87,25.93 v4(34.65,25.93) 34.12,25.93 32.93,27.13 U120.8
SUS_LED_GREEN_C: length 172.3
  TOP w0.254: v1(117.23,13.18) 117.58,12.83 127.27,12.83 128.29,11.81 132.26,11.81 132.61,11.45 133.95,11.45 134.44,11.94 136.81,11.94 R667.2 137.46,11.32 R663.2 ; v1(28.53,22.05) 28.83,21.75 PWRCN1.7
  L4 w0.254: v1(117.23,13.18) 117.23,12.05 110.49,5.31 91.55,5.31 88.11,8.75 88.11,19.58 85.36,22.33 68.55,22.33 67.49,23.38 62.12,23.38 57.79,19.05 48.44,19.05 47.84,18.45 47.84,17.98 48.14,17.68 48.14,7.67 46.62,6.15 46.62,4.5 45.98,3.86 28,3.86 26.71,5.15 26.21,5.15 24.25,7.1 24.25,10 23.66,10.6 23.66,14.48 25.05,15.88 25.05,21.19 v2(26.02,22.15)
  BOTTOM w0.254: v1(28.53,22.05) 28.5,22.02 v4(26.88,22.02) 26.16,22.02 v2(26.02,22.15) 25.1,21.23 Q68.D
SUS_LED_GREEN_C2: length 2.4
  TOP w0.254: v3(137.19,7.47) 137.45,7.72 R673.2 R667.1
SUS_PWR_ACK_CPU: length 177.6
  TOP w0.102: v1(133.71,55.83) 133.71,55.93 132.91,56.74 U109.13 ; v1(89.64,142.98) 89.53,143.09 R1697.2
  L3 w0.127: v2(139.61,125.76) 139.5,125.76 139.16,125.41 138.96,125.41 138.84,125.29 138.45,125.29 138.17,125.56 138.17,125.59 137.33,126.43 134.92,126.43 134.18,125.69 134.18,125.49 133.88,125.19 125.39,125.19 108.42,142.16 90.69,142.16 89.87,142.98 v1(89.64,142.98) ; v2(165.74,118.3) 165.2,117.75 165.2,114.84 165.96,114.08 165.96,86.28 161.4,81.72 161.4,72.19 146.68,57.47 141.56,57.47 139.98,55.89 135.04,55.89 134.98,55.83 v1(133.71,55.83)
  L4 w0.127: v2(139.61,125.76) 139.73,125.88 158.25,125.88 162.92,121.21 v2(162.92,118.85)
  BOTTOM w0.102: v2(165.74,118.3) 163.47,118.3 v2(162.92,118.85) ; v4(87.96,143.33) 89.3,143.33 v1(89.64,142.98)
SUS_PWR_ACK_CPU_R: length 14.4
  TOP w0.089: CPU2.AE3 83,152.63 83.3,152.34 83.3,151.87 83.36,151.81 83.36,150.9
  TOP w0.102: 83.36,150.9 83.36,150.14 86.62,146.88 v3(86.67,146.88) 87.08,146.47 87.08,145.28 87.38,144.97 87.38,143.79 88.86,142.32 R1697.1 88.86,141.41 R499.2
SUSCLK_NGFF: length 5.2
  TOP w0.102: NGFF1.50 119.46,217 119.58,216.88 120.68,216.88 121.22,216.33 TP101.1
SUSCLK_SIO_C: length 6.2
  TOP w0.089: CPU2.C15 71.93,159.17 71.63,159.17 71.34,158.87 70.64,158.87 70.28,158.52 70.26,158.52
  TOP w0.102: 70.26,158.52 68.78,157.04 68.78,156.12 TP100.1
SW_ON_N_SIO: length 7.9
  TOP w0.102: v1(111.68,63.88) 111.75,63.88 111.75,63.89 113.31,63.89 114.19,63.01 114.9,63.01 115.17,62.74 U109.69
  BOTTOM w0.102: v1(111.68,63.88) 111.5,63.7 v4(111.5,63.02) 111.4,62.92 R395.1 111.4,61.32 R391.2
SWR_LX: length 11.6
  BOTTOM w0.203: U126.17 37.18,98.22 36.05,99.35 36.05,99.64
  BOTTOM w0.508: L2.2 32.87,105.88 34.38,104.38 v4(34.38,103.24) 34.38,100.66 34.83,100.2 35.52,100.2 36.05,99.67 36.05,99.64
SWR_V12: length 27.4
  TOP w0.508: v2(37.47,90.37) 37.17,90.68 v2(34.4,90.68) ; v2(33.15,99.75) 33.15,98.63 v2(33.18,98.6) 33.15,98.58 33.15,96.81 33.66,96.3 v2(33.73,96.3)
  L3 w0.635: v2(33.73,96.3) 34.65,95.38 34.65,90.94 v2(34.4,90.68)
  BOTTOM w0.203: U126.15 36.38,98.05 35.73,98.69 33.27,98.69 v2(33.18,98.6) ; U126.11 v2(33.73,96.3) ; v2(37.47,90.37) 37.58,90.48 U126.43
  BOTTOM w0.381: v2(34.4,90.68) 34.4,90.29 33.95,89.85 C299.1 C297.1
  BOTTOM w0.508: C295.1 37.42,89.5 37.42,90.32 v2(37.47,90.37)
  BOTTOM w0.635: L2.1 33.13,102.12 C296.2 33.13,99.77 v2(33.15,99.75) v4(33.82,99.75)
SYNC: length 2.9
  TOP w0.102: TP24.1 157.01,34.95 156.1,34.05 U21.11
SYS_3VSB: length 5.4
  TOP w0.203: 114.42,63.57 114.45,63.54 U109.67
  TOP w0.254: R382.1 112.21,65.24 v3(112.75,64.71) 113.28,64.71 114.42,63.57
SYS_FAN_TACH1_1: length 5.7
  TOP w0.165: R76.2 16.73,206.55 R80.2 16.2,206.57 15.68,207.09 15.68,208.05 FANC3.3
SYS_FAN_TACH1_2: length 4.1
  TOP w0.165: R76.1 17.91,205.51 18.79,204.64 R73.2 19.34,203.89 v3(19.34,203.33) R74.2
SYS_PRES: length 5.4
  TOP w0.102: BAT2.7B 33.63,61.89 v2(33.97,62.23) 34.57,62.23 v3(35.46,61.34)
  BOTTOM w0.102: R79664.2 33.04,61.3 v2(33.97,62.23)
SYS_PWRGD: length 77.4
  TOP w0.102: R178.2 96.3,116.46 98.74,118.9 v2(99.25,118.9) ; v1(107.2,118.29) 107.81,118.29 108.29,117.81 109.36,117.81 110.4,118.85 110.4,123.08 109.34,124.14 108.39,124.14 Q79.D 107.56,125.05 105.47,127.14 105.47,128.65 103.1,131.02 R1601.2 ; R1920.1 99.25,92.2 99.55,91.9 101.46,91.9 101.59,92.03 103.11,92.03 103.33,91.81 103.33,90.12 v1(101.96,88.75)
  L3 w0.127: v1(107.2,118.29) 106.75,117.84 105.58,117.84 105.21,118.21 102.29,118.21 101.61,118.9 v2(99.25,118.9)
  BOTTOM w0.102: v2(99.25,118.9) 99.55,118.59 99.55,117.2 106.27,110.48 106.27,93.68 v4(102.58,89.98) 101.96,89.37 v1(101.96,88.75)
SYS_PWRGD_G: length 7
  TOP w0.102: R717.2 102.29,122.39 v3(102.29,122.45) 102.52,122.68 102.52,124.65 Q78.D 105.27,124.69 Q79.G
SYSTEM_FAN_PWM1_1: length 9.8
  TOP w0.165: R68.2 15.97,201.52 D1.A 17.25,202.21 16.61,202.86 R71.2 14.7,202.86 14,203.56 FANC3.4
TAP_PRDY#: length 99.2
  TOP w0.102: XDP1.5 148.16,190.57 147.73,190.14 147.73,189.67 147.11,189.05 142.3,189.05 140.46,190.89 140.46,190.89 140.34,191.02 140.34,191.02 134.55,196.8 134.55,197.45 132.81,199.19 v2(130,199.19) ; CPU2.AD45 v1(82.05,173.69)
  BOTTOM w0.102: v2(130,199.19) 129.6,199.59 117.17,199.59 117.17,199.59 116.09,199.59 v4(115.36,200.32) 112.64,203.05 104.48,203.05 103.79,202.36 90.6,202.36 87.16,198.92 87.16,192.4 84.62,189.86 84.62,186.31 83.38,185.07 83.38,179.59 83.41,179.56 83.41,177.41 82.89,176.89 82.89,174.53 v1(82.05,173.69)
TAP_PREQ#: length 132.1
  TOP w0.102: R1746.2 161.51,180.44 U2.4 160.81,180.56 160.17,179.92 158.28,179.92 157.89,180.3 157.89,184.28 156.83,185.35 156.83,186.82 156.31,187.34 R34.2 v2(154.85,187.34) ; CPU2.AF41 v1(83.95,172.26)
  L3 w0.127: v2(150.91,204.85) 150.91,203.2 152.13,201.98 152.13,201.1 153.58,199.66 153.58,188.61 v2(154.85,187.34)
  BOTTOM w0.102: v1(83.95,172.26) 83.95,172.39 83.53,172.82 83.53,176.96 83.84,177.27 83.84,184.88 85.13,186.18 85.13,189.69 87.71,192.27 87.71,198.83 90.79,201.9 103.98,201.9 104.67,202.59 112.05,202.59 116.19,198.45 138.89,198.45 143.71,203.27 v4(145.98,203.27) 146.88,204.17 150.35,204.17 150.91,204.72 v2(150.91,204.85)
TAP_PREQ#_R: length 18.1
  TOP w0.102: U2.2 158.48,181.51 158.15,181.84 158.15,182.97 R43.2 158.62,183.89 157.06,185.45 157.06,187.15 155.98,188.22 R34.1 156.39,188.86 C35.1 v3(155.04,189.3) 154.34,189.3 153.57,190.07 XDP1.3
TCK: length 3.3
  TOP w0.102: U4101.27 138.48,73.24 138.31,73.07 137.03,73.07 TP4126.1
TDI: length 3.4
  TOP w0.102: TP4128.1 136.81,74.32 138.13,74.32 138.24,74.21 138.25,74.21 138.42,74.04 U4101.25
TDO: length 2.1
  TOP w0.102: TP4129.1 138.34,74.44 U4101.24
TESTEN: length 10.8
  TOP w0.305: GPU1.K7 77.86,92.4 v1(78.22,92.03)
  L3 w0.508: v1(78.22,92.03) 79.06,91.2 79.06,88.8 80.71,87.15 80.71,87.15 v1(80.75,87.11)
  BOTTOM w0.508: R1897.1 R302.1 81.46,84.5 81.46,85.7 81.64,85.88 v4(81.64,85.94) 81.64,86.22 v1(80.75,87.11)
TMS: length 1.9
  TOP w0.102: U4101.26 137.97,73.64 TP4127.1
TP_AD13: length 4.5
  TOP w0.102: CPU2.AD13 82.11,158.4 v1(82.08,158.4)
  BOTTOM w0.089: 81.65,157.97 v1(82.08,158.4)
  BOTTOM w0.102: TP49.1 80.53,156.13 80.53,156.85 81.65,157.97
TP_AD14: length 4.1
  TOP w0.102: v1(82.09,159.1) 82.11,159.1 82.11,159.09 82.14,159.09 CPU2.AD14
  BOTTOM w0.089: 81.67,158.28 81.67,158.56 82.09,158.98 v1(82.09,159.1)
  BOTTOM w0.102: TP50.1 80.04,156.65 81.67,158.28
TP_DET: length 141.8
  TOP w0.102: R1719.2 29.93,10.77 29.66,10.5 TOUCH1.1 27.24,11.74 v1(27.24,12.19) 26.12,11.08 26.12,11.03 23.62,11.03 23.52,11.13 23.52,12.97 23.99,13.44 v3(23.99,13.51) ; U109.118 126.01,49.52 124.87,48.39 124.87,46.35 123.99,45.47 v1(123.99,43.38)
  L3 w0.127: v1(123.99,43.38) 122.43,41.83 117.75,41.83 113.47,37.55 113.47,35.99 110.55,33.07 v2(108.59,33.07)
  L4 w0.127: v2(108.59,33.07) 107.7,32.18 107.7,30.75 104.48,27.53 103.38,27.53 102.43,26.58 95.35,26.58 93.53,28.4 81.79,28.4 80.63,29.55 72.13,29.55 71.59,30.1 65.11,30.1 61.27,33.93 49.63,33.93 47.35,31.65 47.35,30.65 44.42,27.72 44.42,24.16 37.49,17.23 31.31,17.23 27.8,13.72 27.12,13.72 26.83,13.42 26.83,12.6 v1(27.24,12.19)
  BOTTOM w0.102: v4(107.91,32.61) 107.98,32.69 107.98,32.7 108.34,32.92 v2(108.59,33.07)
TP_GPU_CLKREQ#: length 4.9
  TOP w0.102: GPU1.N7 80,92.45 v1(79.38,93.07)
  BOTTOM w0.102: TP158.1 80.9,90.2 80.9,91.55 v1(79.38,93.07)
TP_NGFF_COEX1: length 4.7
  TOP w0.102: TP39.1 122.05,215.8 121.06,215.8 120.36,216.5 NGFF1.48
TP_NGFF_COEX2: length 3.2
  TOP w0.102: NGFF1.46 120.33,216 121.06,215.26 TP38.1
TP_NGFF_COEX3: length 4.8
  TOP w0.102: NGFF1.44 120.33,215.5 121.1,214.73 121.85,214.73 TP37.1
TP_NGFF_LED1: length 4.8
  TOP w0.102: NGFF1.6 119.4,206 119.42,206.02 120.96,206.02 TP63.1
TP_NGFF_LED2: length 3.2
  TOP w0.102: TP64.1 120.46,208.5 NGFF1.16
TP_NGFF_MLDIR: length 3.7
  TOP w0.102: TP62.1 107.95,208.75 NGFF1.17
TP_SIO_VIN0: length 2.2
  TOP w0.203: U109.93 115.1,53.14 114.98,53.02 114.77,53.02
  TOP w0.254: TP46.1 114.47,53.02 114.77,53.02
TP_Y3: length 4.8
  TOP w0.089: CPU2.Y3 80.57,152.99 80.28,152.71 80.28,152.43 80.38,152.34 80.38,151.87 80.48,151.77 80.48,151.39 80.47,151.38
  TOP w0.102: TP57.1 80.46,149.18 80.46,151.37 80.47,151.38
TPA3131_BSNL: length 2.7
  TOP w0.305: C228.1 151.13,31.24 151.14,31.23 v3(151.24,31.23) 151.25,31.24 151.84,31.24 151.96,31.36 U21.19
TPA3131_BSNR: length 2.8
  TOP w0.305: C229.1 150.4,29.72 v3(151.24,29.72) 151.32,29.72 151.45,29.86 U21.22
TPA3131_BSPL: length 5.4
  TOP w0.305: 153.23,34.72 154.1,33.85 U21.15
  TOP w0.635: C224.1 150.81,34.9 v3(151.4,34.9) 153.05,34.9 153.23,34.72
TPA3131_BSPR: length 3.1
  TOP w0.305: U21.26 154.1,27.2 153.63,26.72
  TOP w0.635: C223.1 152.23,26.54 v3(153.45,26.54) 153.63,26.72
TPA3131_FAULT#: length 2.9
  TOP w0.102: U21.30 156.1,27.37 155.85,27.11 v3(155.85,26.5) 155.85,26.18 155.57,25.91 R1597.2
TPA3131_GAIN: length 7
  TOP w0.203: U21.3 159.07,29.86 159.73,30.52 R361.2 160.98,30.96 163.23,30.96 R358.1 164.33,31.03 v3(164.4,30.97)
TPA3131_GVDD: length 5.1
  TOP w0.203: R361.1 159.72,29.63 v3(159.59,29.5) 159.45,29.36 U21.2 ; R361.1 161.42,29.63 C192.2 ; R361.1 R357.2
TPA3131_LINN: length 3.1
  TOP w0.203: C200.2 159.87,31.63 v3(159.6,31.36) 159.08,31.36 158.58,30.86 U21.5
TPA3131_LINN_1: length 3.6
  TOP w0.203: v3(164.63,33.96) 163.9,33.24 R346.2 163.47,32.93 C200.1
TPA3131_MUTE: length 6.6
  TOP w0.203: U21.7 158.61,31.86 159.11,32.36 159.11,34.34 v3(159.42,34.65) 159.95,35.18 R360.1 159.49,36.06 R1598.1
TPA3131_PLIMIT: length 5.3
  TOP w0.203: U21.1 158.81,28.86 159.18,28.49 R347.2 159.77,28.49 R357.1 161.44,27.72 v3(161.55,27.61) 161.72,27.78 C193.2
TPA3131_RINN: length 3.2
  TOP w0.203: C198.2 157.44,25.36 v3(157.44,26.42) 157.1,26.75 U21.32
TPA3131_RINN_1: length 2.7
  TOP w0.203: v3(159.85,25.37) 159.57,25.1 C198.1 158.58,25.21 R344.2
TPA3131_SD: length 18.4
  TOP w0.102: v1(158.48,36.04) 158.48,36.45 158.97,36.94 R1598.2
  BOTTOM w0.102: Q64.G 144.98,39.69 146.61,38.06 147.66,38.06 R639.2 148.9,37.25 148.9,37.87 149.47,38.44 Q63.3 151.05,38.44 v4(151.62,37.87) 154.85,37.87 156.67,36.04 v1(158.48,36.04)
TPA3131_SD1#: length 26.2
  TOP w0.102: v2(154.52,24.46) 154.68,24.63 R1597.1 154.68,25.62 155.29,26.22 155.29,26.86 155.6,27.18 U21.29
  BOTTOM w0.102: v2(154.52,24.46) 154.39,24.46 154.13,24.71 C521.1 153.58,26.21 v4(152.61,26.21) 151.04,27.79 151.04,34.26 149.31,35.99 R643.2 148.69,35.67 148.55,35.53 145.18,35.53 144.38,36.34 144.38,37.39 144.77,37.78 Q64.D
TSVDD: length 4.8
  TOP w0.254: v1(88.63,101.24) 88.7,101.17 88.7,100.91 89,100.62 GPU1.AD17
  BOTTOM w0.254: C758.1 C759.1 ; C759.1 88.76,100.41 89.34,99.94 89.34,99.92 v4(89.42,99.85) 89.43,99.85 89.81,99.44 L47.2 ; C759.1 88.48,101.09 v1(88.63,101.24)
U1.1: length 4.1
  BOTTOM w0.102: SR1.1 167.18,140.89 v4(167.25,140.96) 168.63,142.34 SU1.1
U1.6: length 3.5
  BOTTOM w0.102: SC2.1 168.64,149.24 v4(168.64,148.25) 168.63,148.24 SU1.6
U1.24: length 4.6
  BOTTOM w0.102: SU1.24 169.48,141.62 v4(168.77,140.91) 167.33,139.46 SC5.2
UART1_RX: length 136.7
  TOP w0.102: v1(82.05,157.74) 82.4,157.38 CPU2.AD12
  TOP w0.127: v2(142.73,178.44) 145.61,175.55 157.14,175.55 159.31,173.39 CN2.3
  L4 w0.127: v1(82.05,157.74) 83.22,156.57 83.22,153.61 84.35,152.48 84.84,152.48 89.66,147.65 92.26,147.65 92.58,147.97 100.3,147.97 101.35,146.91 104.3,146.91 109.7,141.51 110.53,141.51 113.01,139.04 119.3,132.75 137.8,132.75 140.13,135.08 140.13,160.92 141.38,162.18 141.38,173.6 142.73,174.94 v2(142.73,178.44)
  BOTTOM w0.102: v2(142.73,178.44) 142.76,178.41 v4(142.76,177.42)
UART1_TX: length 139.1
  TOP w0.102: v1(82.08,157.1) 82.5,156.67 CPU2.AD10
  TOP w0.127: CN2.2 159.25,174.19 157.13,176.31 146.79,176.31 143.8,179.3 142.88,179.3 v2(142.84,179.34)
  L4 w0.127: v1(82.08,157.1) 82.84,156.34 82.84,153.23 84.95,151.12 85.74,151.12 89.77,147.08 92.58,147.08 92.58,147.08 92.95,147.08 92.96,147.08 98.55,147.08 99.04,146.59 104.22,146.59 109.58,141.22 110.46,141.22 112.9,138.78 119.19,132.5 138.96,132.5 141.35,134.88 141.35,149.09 140.38,150.05 140.38,160.81 141.64,162.07 141.64,173.49 143.2,175.05 143.2,178.93 142.84,179.29 v2(142.84,179.34)
  BOTTOM w0.102: v2(142.84,179.34) v4(141.97,179.34)
USB1N_C_EXT: length 20.6
  TOP w0.102: TR6.1 166.48,104.43 166.61,104.56 166.61,105.03 166.92,105.35 167.7,105.35 U6704.6 168.21,105.35 169.46,105.35 169.93,104.88 169.93,104.75 170.06,104.62 171.41,104.62 172.83,103.2 172.83,101.96 175.42,99.36 175.42,96.93 174.96,96.47 173.87,96.47 172.99,95.59 172.99,95.58 172.89,95.48 172.52,95.48 172.4,95.61 172.4,96.12 SSUSB2.2
USB1P_C_EXT: length 20.2
  TOP w0.102: SSUSB2.3 173.21,94.93 173.21,95.5 173.96,96.25 175.05,96.25 175.64,96.84 175.64,99.45 173.04,102.05 173.04,103.29 171.5,104.84 170.9,104.84 U6704.1 170.02,105.09 169.55,105.56 166.83,105.56 166.39,105.12 TR6.4
USB2N_EXT: length 22.8
  TOP w0.102: USB3.2 101.06,38.03 100.38,37.34 100.1,37.34 99.79,37.03 99.79,35.32 100.53,34.58 101.26,34.58 104.78,31.06 104.78,26.57 105.79,25.57 107.64,25.57 108.38,26.3 109.08,26.3 U6703.3 109.58,26.3 110.08,26.3 110.41,25.97 111.23,25.97 111.46,25.74 TR7.4
USB2P_EXT: length 23.2
  TOP w0.102: USB3.3 101.33,36.3 101.33,37 101.2,37.13 100.19,37.13 100,36.94 100,35.41 100.62,34.8 101.35,34.8 105,31.15 105,26.66 105.87,25.78 106.37,25.78 U6703.4 106.9,25.78 107.55,25.78 108.29,26.52 110.17,26.52 110.5,26.19 111.23,26.19 111.47,26.43 TR7.1
USB3_OBSN: length 2.8
  TOP w0.102: CPU2.F34 73.54,168.37 73.84,168.07 73.86,168.07 v1(73.9,168.03)
  BOTTOM w0.102: v4(74.2,169.24) 74.15,169.19 73.53,169.19 R1236.1 73.25,168.73 73.9,168.08 v1(73.9,168.03)
USB3_OBSP: length 2.9
  TOP w0.102: v1(73.22,168) 73.21,168.01 73.21,168.01 72.86,168.35 CPU2.D34
  BOTTOM w0.102: v1(73.22,168) 73.22,168.05 R1236.2 71.93,169.34 v4(71.46,169.34)
USB3N_EXT: length 20.2
  TOP w0.102: USB4.2 101.95,14.14 102.36,14.14 103.83,15.61 103.83,22.73 105.71,24.61 107.65,24.61 108.38,23.89 109.08,23.89 U6703.1 109.58,23.89 110.94,23.89 111.24,24.19 TR5.1
USB3P_EXT: length 20.1
  TOP w0.102: USB4.3 101.95,13.92 102.45,13.92 104.05,15.52 104.05,22.64 105.8,24.4 106.38,24.4 U6703.6 106.89,24.4 107.56,24.4 108.29,23.67 110.95,23.67 111.12,23.51 TR5.4
USB30_RX_CPU_N0: length 132.8
  TOP w0.102: L5.1 164.74,116.75 164.51,116.99 163.3,116.99 v2(162.87,116.56) ; v1(72.56,165.93) 72.56,165.87 72.96,165.46 CPU2.D28
  L4 w0.127: v1(72.56,165.93) 72.56,165.16 71.38,163.98 71.38,158.15 71.78,157.75 71.78,155.89 71.34,155.45 71.34,153.67 71.88,153.13 71.88,151.4 71.51,151.03 71.51,147.89 72.08,147.33 72.08,144.28 81.33,135.03 89.25,135.03 89.64,135.42 92.52,135.42 92.91,135.03 96.62,135.03 97.26,135.67 103.79,135.67 104.46,135 111.18,135 122.05,124.13 140.62,124.13 141.34,124.85 155.78,124.85 156.68,123.94 158.92,123.94 161.5,121.36 161.5,116.83 161.78,116.55 162.86,116.55 162.87,116.56 v2(162.87,116.56)
USB30_RX_CPU_N1: length 158.3
  TOP w0.102: v2(163.79,94.56) 164.12,94.89 164.96,94.89 165.32,94.53 L37.1 ; CPU2.D30 73.19,166.96 73.2,166.97 v1(73.2,166.97)
  L4 w0.089: 71.53,165.84 71.53,165.86 71.57,165.9 71.57,166.23 71.88,166.54 73.14,166.54 73.29,166.7 73.29,166.88 v1(73.2,166.97)
  L4 w0.127: 71.53,165.84 71.53,165.4 70.45,164.32 70.45,158.08 71.18,157.36 71.18,156.34 70.61,155.77 70.61,147.51 71.09,147.03 71.09,143.98 80.95,134.12 89.67,134.12 90.05,134.51 92.16,134.51 92.54,134.12 97.17,134.12 97.33,134.28 97.77,134.72 103.44,134.72 104.06,134.1 110.54,134.1 121.41,123.23 140.99,123.23 141.57,123.8 155.24,123.8 156,123.04 158.54,123.04 160.6,120.99 160.6,115.13 161.7,114.02 161.92,113.8 161.92,109.46 163.77,107.61 163.77,97.24 162.8,96.26 162.8,95.36 163.24,94.91 163.44,94.91 v2(163.79,94.56)
  BOTTOM w0.102: v2(163.79,94.56) 164.06,94.29 v4(164.06,93.73)
USB30_RX_CPU_P0: length 132.8
  TOP w0.102: CPU2.F28 73.6,165.54 73.24,165.89 v1(73.24,165.93) ; L5.4 164.74,117.43 164.51,117.2 163.09,117.2 v2(162.87,117.42)
  L4 w0.127: v1(73.24,165.93) 73.16,165.93 72.82,165.59 72.82,165.05 71.65,163.87 71.65,158.26 72.04,157.86 72.04,155.78 71.61,155.34 71.61,153.78 72.15,153.24 72.15,151.29 71.78,150.92 71.78,148 72.34,147.44 72.34,144.39 81.44,135.29 89.14,135.29 89.53,135.69 92.63,135.69 93.02,135.29 96.51,135.29 97.15,135.94 103.9,135.94 104.57,135.27 111.29,135.27 122.16,124.4 140.51,124.4 141.23,125.12 155.89,125.12 156.79,124.21 159.03,124.21 161.77,121.47 161.77,116.94 161.89,116.81 162.46,116.81 162.87,117.23 v2(162.87,117.42)
USB30_RX_CPU_P1: length 158
  TOP w0.102: v1(73.87,166.93) 73.86,166.93 73.86,166.9 CPU2.F30 ; v2(163.86,95.53) 163.86,95.3 164.05,95.11 165.05,95.11 165.15,95.21 L37.4
  L4 w0.089: 71.8,165.84 71.8,165.86 71.76,165.9 71.76,166.15 71.96,166.35 73.22,166.35 73.8,166.93 v1(73.87,166.93)
  L4 w0.127: v2(163.86,95.53) 163.51,95.17 163.36,95.17 163.06,95.47 163.06,96.15 164.04,97.13 164.04,107.72 162.19,109.58 162.19,113.92 161.89,114.21 160.87,115.24 160.87,121.1 158.65,123.31 156.11,123.31 155.35,124.07 141.45,124.07 140.88,123.5 121.52,123.5 110.65,134.37 104.17,134.37 103.55,134.99 97.66,134.99 97.06,134.39 92.65,134.39 92.27,134.77 89.94,134.77 89.56,134.39 81.06,134.39 71.36,144.09 71.36,147.14 70.88,147.62 70.88,155.66 71.44,156.23 71.44,157.47 70.72,158.19 70.72,164.21 71.8,165.29 71.8,165.84
  BOTTOM w0.102: v2(163.86,95.53) 163.86,96.47 v4(163.84,96.49)
USB30_TX_CPU_N0: length 135.7
  TOP w0.089: CPU2.C32 71.99,167.43 71.69,167.13 71.45,167.13 71.34,167.24 70.86,167.24 70.75,167.34 69.75,167.34 69.74,167.33 69.71,167.33
  TOP w0.102: v1(68.74,169.29) 68.95,169.08 68.95,167.81 69.43,167.33 69.71,167.33 ; 158.71,118.77 158.81,118.67 159.07,118.4 159.34,118.14 159.53,118.14 C104.1 ; 158.71,118.77 158.34,119.14 v2(157.53,119.14) ; 158.71,118.77 v3(158.46,118.53)
  L4 w0.127: v2(157.53,119.14) 157.47,119.2 154.91,119.2 153.69,120.42 119.44,120.42 108.49,131.36 79.63,131.36 67.46,143.54 67.46,146.63 67.79,146.96 67.79,158.69 67.01,159.47 67.01,161.06 67.33,161.38 67.33,167.02 68.74,168.43 v1(68.74,169.29)
USB30_TX_CPU_N0_EMI: length 5
  TOP w0.102: C104.2 161.14,118.09 163.31,118.09 164.49,119.27 164.65,119.27 164.91,119.01 L4.1
USB30_TX_CPU_N1: length 157
  TOP w0.089: CPU2.C33 71.63,167.92 71.35,167.63 71.26,167.63 71.26,167.62 71.02,167.62
  TOP w0.102: v2(161.83,96.63) 161.94,96.63 162.06,96.75 162.45,96.75 162.58,96.63 163.02,96.63 C1604.2 ; 71.02,167.62 70.91,167.73 70.91,167.73 70.81,167.83 70.47,167.83 70.46,167.83 70.35,167.83 70.1,168.08 70.1,168.44 v1(69.88,168.66)
  L4 w0.127: v2(161.83,96.63) 161.54,96.91 161.21,96.91 160.93,97.2 160.93,100.29 162.87,102.23 162.87,107.24 159.38,110.73 159.38,115.81 158.18,117.01 158.18,120.17 157.75,120.6 155.01,120.6 154.18,121.43 120.11,121.43 118.22,123.32 109.28,132.26 80.14,132.26 79.98,132.42 68.8,143.61 68.8,143.83 68.8,157.02 68.49,157.33 68.49,160.83 68.18,161.13 68.18,167.08 69.76,168.66 v1(69.88,168.66)
  BOTTOM w0.102: v2(161.83,96.63) 162.39,96.63 v4(162.63,96.86)
USB30_TX_CPU_N1_EMI: length 1.9
  TOP w0.102: L36.1 165.33,96.81 165.08,97.07 164.35,97.07 C1604.1
USB30_TX_CPU_P0: length 136.5
  TOP w0.089: CPU2.B32 71.35,167.43 71.34,167.43 70.94,167.43 70.83,167.53 70.48,167.53 70.38,167.63 70.11,167.63 70.01,167.53 69.75,167.53 69.74,167.55 69.71,167.55
  TOP w0.102: C103.1 159.62,118.35 159.43,118.35 159.23,118.56 158.43,119.35 157.96,119.35 157.53,119.79 v2(157.53,120) ; 69.71,167.55 69.52,167.55 69.17,167.9 69.17,168.21 69.28,168.32 69.28,168.62 69.17,168.74 69.17,169.08 v1(69.38,169.29)
  L4 w0.127: v2(157.53,120) 157.53,119.83 157.17,119.47 155.02,119.47 153.8,120.68 119.55,120.68 117.34,122.89 117.34,123.09 117.07,123.36 116.87,123.36 116.6,123.63 116.6,123.82 116.33,124.09 116.14,124.09 115.87,124.36 115.87,124.55 115.6,124.82 115.41,124.82 115.07,125.16 115.07,125.36 114.8,125.63 114.6,125.63 114.33,125.9 114.33,126.09 114.06,126.36 113.87,126.36 113.6,126.63 113.6,126.74 113.25,127.09 113.14,127.09 112.87,127.36 112.87,127.56 112.6,127.83 112.4,127.83 112.13,128.09 112.13,128.29 111.87,128.56 111.67,128.56 108.6,131.63 79.75,131.63 67.72,143.65 67.72,146.52 68.05,146.85 68.05,158.8 67.28,159.58 67.28,160.95 67.6,161.26 67.6,166.91 69.01,168.32 69.01,168.92 v1(69.38,169.29)
  BOTTOM w0.102: v4(157.4,120.89) 157.53,120.77 v2(157.53,120)
USB30_TX_CPU_P0_EMI: length 5.4
  TOP w0.102: v3(161.83,118.69) 161.83,118.31 ; 161.83,118.31 161.14,118.31 C103.2 ; 161.83,118.31 163.22,118.31 164.4,119.49 164.65,119.49 164.86,119.7 L4.4
USB30_TX_CPU_P1: length 157.2
  TOP w0.102: v1(70.65,168.69) 70.44,168.69 70.31,168.56 70.31,168.17 70.44,168.05 70.55,168.05 70.56,168.04 70.9,168.04 71,167.95 71,167.95 71.03,167.92 CPU2.A33 ; v2(161.86,97.56) 161.86,97.25 162.13,96.97 162.36,96.97 162.49,97.1 162.49,97.49 162.62,97.62 C1603.2
  L4 w0.127: v2(161.86,97.56) 161.48,97.18 161.32,97.18 161.2,97.31 161.2,100.18 163.14,102.12 163.14,107.35 159.65,110.84 159.65,115.92 158.45,117.12 158.45,120.28 157.86,120.86 155.12,120.86 154.29,121.7 120.22,121.7 118.49,123.43 118.49,123.43 109.39,132.53 80.25,132.53 69.06,143.72 69.06,157.13 68.75,157.44 68.75,160.94 68.45,161.24 68.45,166.97 69.63,168.15 70.49,168.15 70.65,168.3 v1(70.65,168.69)
  BOTTOM w0.102: v4(161.02,97.87) 161.34,97.56 v2(161.86,97.56)
USB30_TX_CPU_P1_EMI: length 3
  TOP w0.102: L36.4 165.3,97.5 165.08,97.28 164.27,97.28 C1603.1 163.71,97.85 v3(163.71,98.7)
USB_CPU_PN4: length 141.1
  TOP w0.089: v1(69.5,170.56) 69.5,170.65 70.29,171.44 71.28,171.44 71.45,171.62 71.69,171.62 71.99,171.32 CPU2.C40
  L4 w0.127: v1(69.5,170.56) 69.25,170.31 67.73,170.31 66.67,169.24 66.67,161.71 66.24,161.27 66.24,159.07 66.88,158.43 66.88,147.41 66.53,147.07 66.53,143.19 79.26,130.46 108.09,130.46 119.03,119.52 153.11,119.52 154.76,117.87 157.1,117.87 v2(157.56,117.41)
  BOTTOM w0.102: TR3.1 159.77,118.64 160,118.87 160,119.12 159.88,119.24 158.96,119.24 158.53,118.81 158.53,118.02 158.14,117.63 157.78,117.63 v2(157.56,117.41) 157.33,117.41 156.68,118.06 v4(156.29,118.06)
USB_CPU_PP4: length 139.7
  TOP w0.089: CPU2.B40 71.51,171.25 70.37,171.25 69.91,170.79 69.91,170.61 70.01,170.51 v1(70.31,170.51)
  L4 w0.127: v1(70.31,170.51) 70.31,170.17 70.19,170.04 67.84,170.04 66.94,169.13 66.94,161.59 66.5,161.16 66.5,159.18 67.14,158.54 67.14,147.3 66.8,146.96 66.8,143.3 79.37,130.73 108.2,130.73 119.14,119.78 153.22,119.78 154.87,118.14 157.37,118.14 v2(157.5,118.27)
  BOTTOM w0.102: TR3.4 160.46,118.62 160.22,118.86 160.22,119.21 159.97,119.46 158.87,119.46 158.67,119.26 ; v4(158.45,119.48) 158.67,119.26 ; 158.67,119.26 158.31,118.9 158.31,118.11 158.05,117.84 157.73,117.84 157.5,118.07 v2(157.5,118.27)
USB_EN_1: length 3.6
  TOP w0.102: U125.4 158.28,123.85 157.76,124.37 157.76,124.64 v3(157.95,124.83) 157.99,124.88 C4260.1 R79660.1
USB_EN_2: length 4.8
  TOP w0.102: U124.4 93.57,31.42 v2(92.68,32.3) 93.09,32.7 C249.1 R1599.1
  BOTTOM w0.102: v4(92.69,31.7) 92.68,31.7 v2(92.68,32.3)
USB_HSIC_RCOMP: length 6.6
  TOP w0.203: CPU2.N38 77.09,170.36 76.64,170.81 76.03,170.81 v1(76.01,170.8)
  BOTTOM w0.203: R1779.1 71.83,171.36 72.69,171.36 72.98,171.65 72.98,171.74 73.31,172.07 74.15,172.07 v4(74.81,171.41) 75.42,170.8 v1(76.01,170.8)
USB_OBSP: length 4.5
  TOP w0.127: R80149.1 68.41,174.53 68.45,174.57 v3(68.51,174.57) 68.67,174.73 69.78,174.73 69.78,174.74 70.22,174.74 70.7,174.26 CPU2.B46
USB_OTG_ID: length 6.2
  TOP w0.102: R1791.1 67.13,177.92 67.44,178.23 v3(68.09,178.23) 68.44,178.23 71.04,175.64 71.52,175.64 71.71,175.44 CPU2.B48
USB_PCH_DN1_NN: length 13.6
  TOP w0.102: v3(158.53,190.25) 158.8,189.98 ; 158.8,189.98 158.4,189.59 158.4,188.19 158.07,187.86 TR1.4 ; 158.8,189.98 163.72,194.9 163.72,196.96 163.25,197.43 WEBCM1.2
USB_PCH_DN4_NN: length 7
  TOP w0.102: 32.18,9.12 32.18,9.49 31.74,9.92 31.74,10.2 31.9,10.35 TR13.3 ; 32.18,9.12 32.18,8.56 31.46,7.85 30.92,7.85 30.55,7.48 C6715.1 30.48,7.5 TOUCH1.4 ; 32.18,9.12 v3(32.54,9.12)
USB_PCH_DN5_NN: length 3.9
  TOP w0.102: NGFF1.5 109.48,205.75 109.35,205.62 108.54,205.62 ; TR12.3 107.69,205.85 107.92,205.62 108.54,205.62 ; v3(108.54,205.98) 108.54,205.62
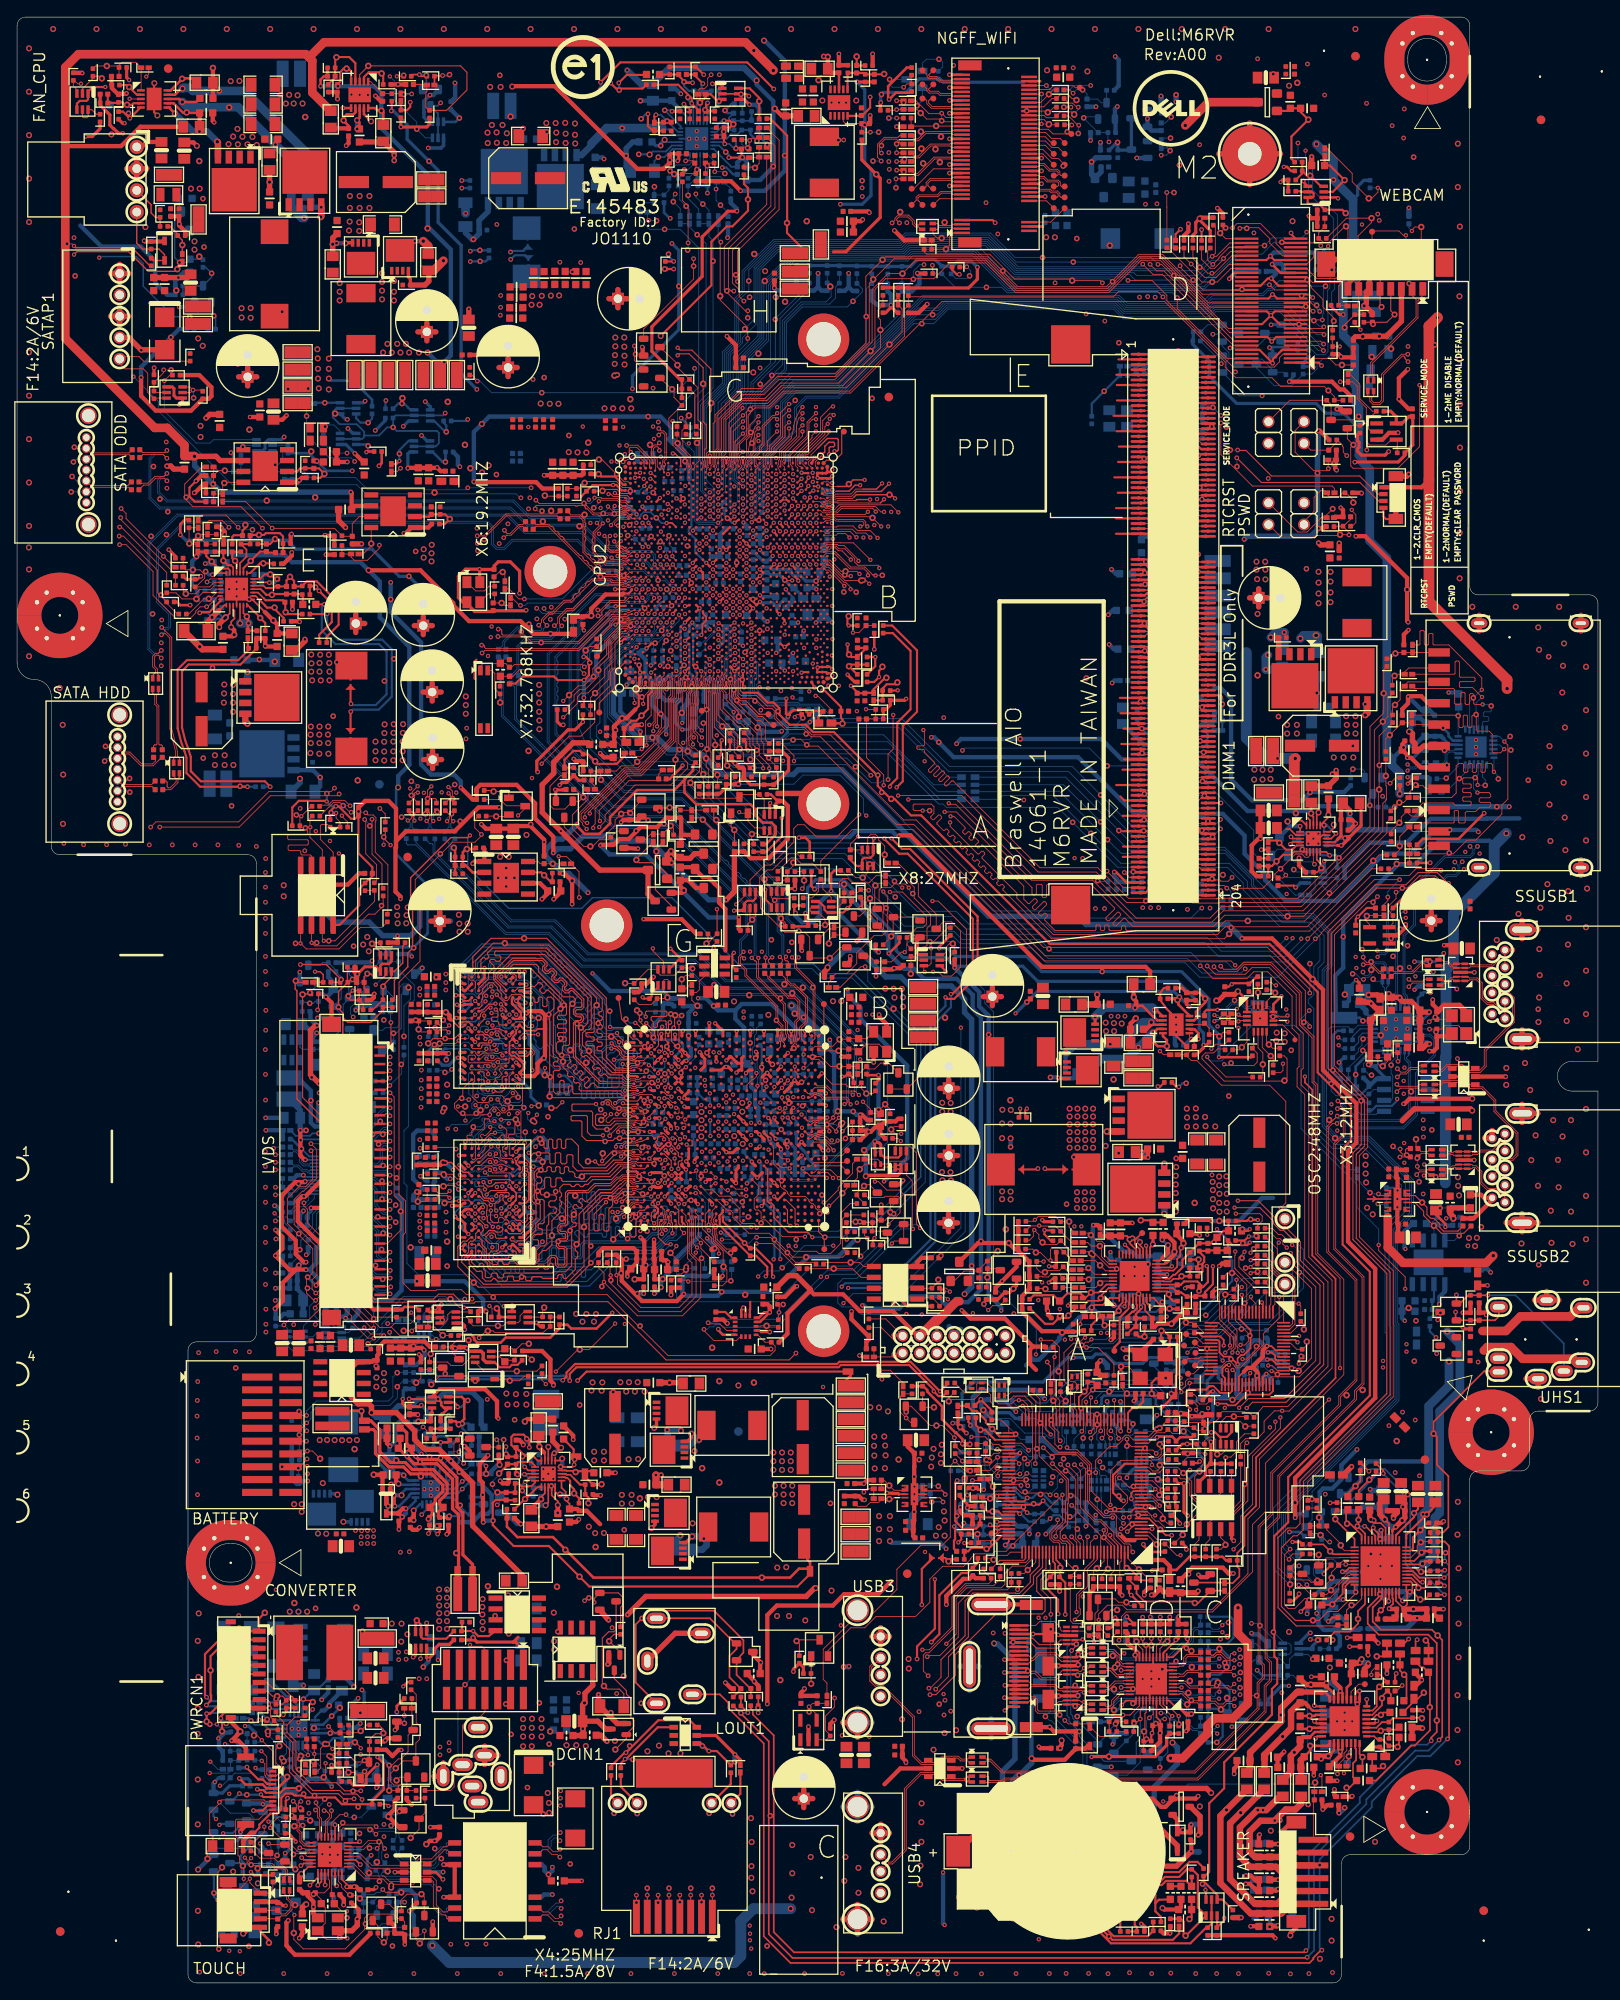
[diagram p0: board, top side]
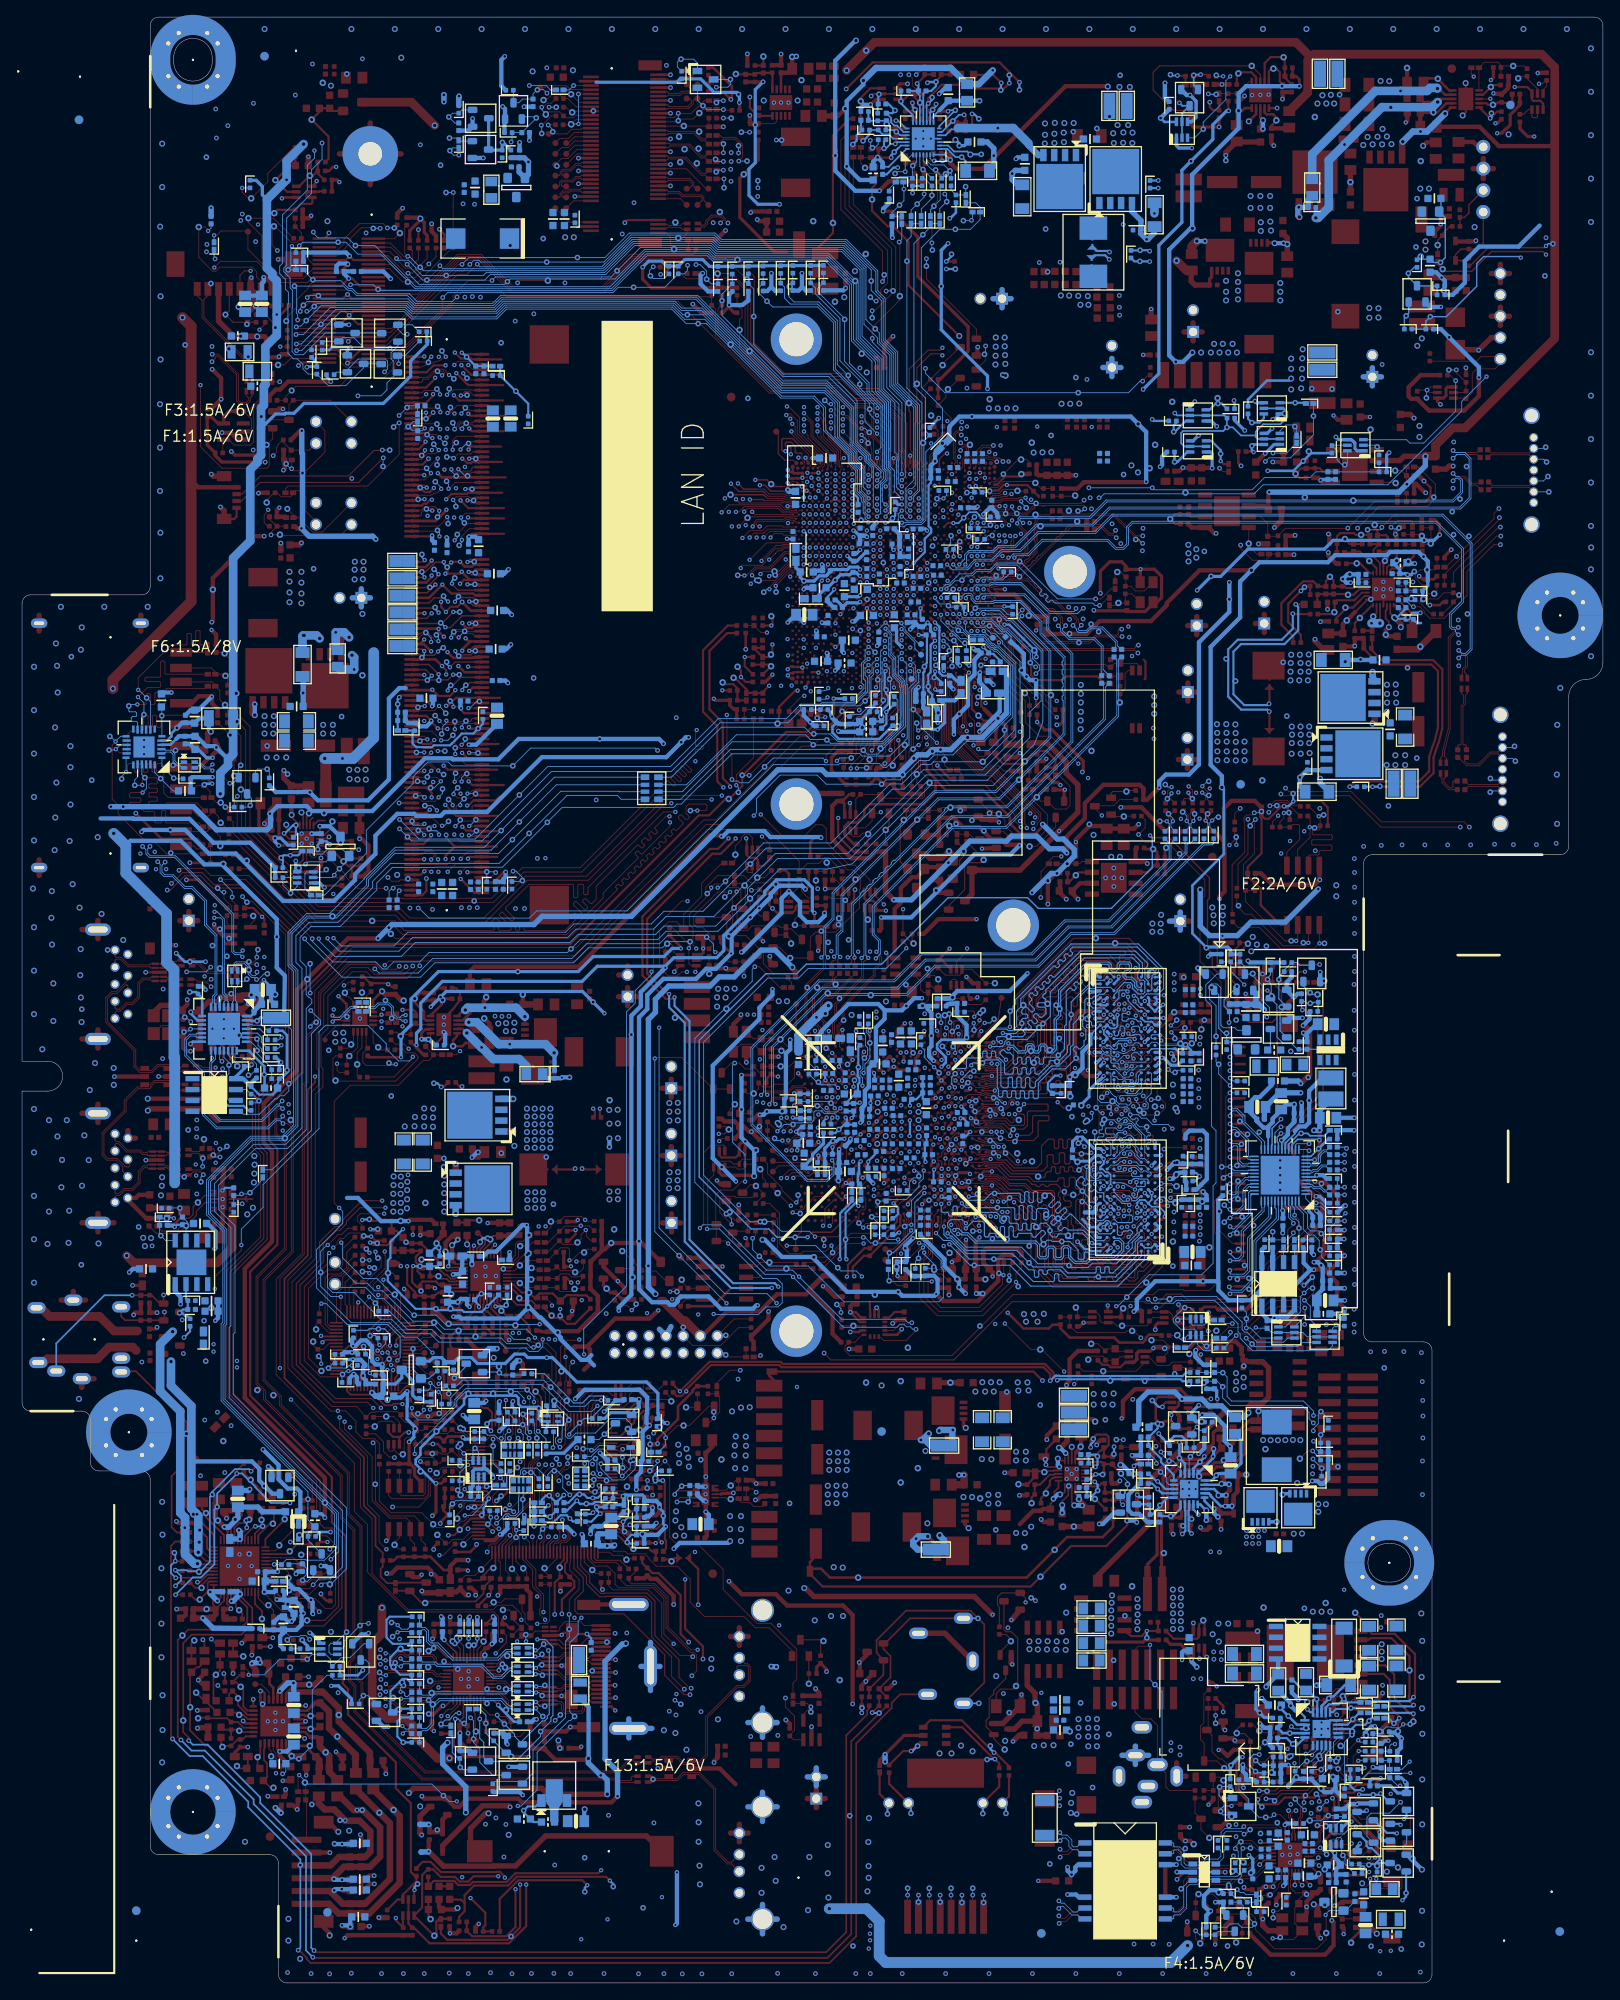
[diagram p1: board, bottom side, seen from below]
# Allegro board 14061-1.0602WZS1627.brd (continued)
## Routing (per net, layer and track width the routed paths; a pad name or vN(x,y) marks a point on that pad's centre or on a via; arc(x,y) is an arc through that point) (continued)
USB_PCH_DP1_PP: length 13.5
  TOP w0.102: 160.55,191.43 163.93,194.81 163.93,196.86 164.5,197.43 WEBCM1.1 ; 160.55,191.43 158.62,189.5 158.62,188.05 158.75,187.92 TR1.1 ; 160.55,191.43 v3(160.79,191.19)
USB_PCH_DP4_PP: length 6.4
  TOP w0.102: TR13.2 31.21,10.5 31.53,10.19 31.53,9.83 31.96,9.4 31.96,8.65 31.37,8.07 30.93,8.07 C711.1 30.49,8.5 TOUCH1.3
USB_PCH_DP5_PP: length 5.3
  TOP w0.102: v3(108.2,204.15) 107.68,204.15 107.16,204.67 TR12.2 107.69,205.17 107.92,205.4 109.43,205.4 109.58,205.25 NGFF1.3
USB_PN4_L: length 4.4
  BOTTOM w0.102: v4(158.69,117.44) 158.94,117.2 TR3.2 159.77,116.67 160.02,116.42 160.02,114.92 159.88,114.78 U6702.1
USB_PP4_L: length 3.5
  BOTTOM w0.102: 160.23,115.74 160.23,116.44 160.46,116.67 TR3.3 ; 160.23,115.74 v4(160.53,115.74) ; 160.23,115.74 160.23,114.92 160.38,114.78 U6702.2
USB_RCOMP: length 4.6
  TOP w0.254: v3(68.05,176.53) 68.33,176.25 69.96,176.25 70.92,175.29 CPU2.A48
  TOP w0.508: R79785.1 67.55,176.53 v3(68.05,176.53)
USB_VBUSSNS: length 8.1
  TOP w0.102: R1846.1 64.4,174.85 R80147.2 65.76,174.85 66.41,175.5 v3(66.42,175.5) 66.58,175.67 70.14,175.67 70.84,174.96 71.66,174.96 CPU2.B47
USB_VBUSSNS_R: length 2.7
  TOP w0.102: v3(61.76,174.02) 61.83,173.95 R1845.2 R1846.2
USBDN1_CHAR: length 37.5
  TOP w0.102: 163.13,104.69 161.89,104.69 v2(161.48,104.27) ; 163.13,104.69 163.93,104.69 164.18,104.43 TR6.2 ; 163.13,104.69 v3(163.13,104.29) ; U9625.11 148.59,113.09 v1(148.67,113.18)
  L4 w0.127: v1(148.67,113.18) 148.59,113.1 147.97,113.1 146.34,114.73 146.34,116.41 147.2,117.27 151.79,117.27 154.78,114.28 154.78,112.16 159.08,107.86 159.08,105.79 160.27,104.6 161.15,104.6 v2(161.48,104.27)
  BOTTOM w0.102: R80051.2 146.09,114.24 146.58,114.24 147.87,112.94 148.43,112.94 v1(148.67,113.18)
USBDP1_CHAR: length 38.2
  TOP w0.102: U9625.10 148.52,112.59 v1(148.65,112.47) ; v2(161.47,105.13) 161.7,104.9 163.94,104.9 164.15,105.12 TR6.3
  L4 w0.127: v2(161.47,105.13) 161.2,104.86 160.38,104.86 159.34,105.91 159.34,107.98 155.05,112.27 155.05,114.39 151.9,117.54 147.09,117.54 146.07,116.52 146.07,114.62 148.22,112.47 v1(148.65,112.47)
  BOTTOM w0.102: v1(148.65,112.47) 148.39,112.73 147.78,112.73 147.21,113.3 ; v4(146.97,113.06) 147.21,113.3 ; 147.21,113.3 146.49,114.02 145.98,114.02 R80053.2
USBOC01: length 119.9
  TOP w0.102: v1(78.12,158.44) 77.92,158.44 CPU2.P14 ; R80061.2 146.76,117.08 147.12,116.71 v1(147.33,116.71) ; U125.3 161.01,123.96 R79659.1 161.01,124.92 160.47,125.47 160.47,125.97 161.37,126.88 v2(161.37,127.61)
  L3 w0.127: v1(147.33,116.71) 147.33,116.76 147.44,116.88 147.44,123.5 148.57,124.63 v1(148.57,127.41)
  L4 w0.127: v1(78.12,158.44) 77.72,158.04 77.72,151.18 79.44,149.46 81.31,149.46 85.71,145.06 103.08,145.06 108.59,139.55 109.53,139.55 121.77,127.31 148.48,127.31 v1(148.57,127.41) 148.78,127.61 v2(161.37,127.61)
  BOTTOM w0.102: v4(162.11,128.09) 162.11,128.08 161.64,127.61 v2(161.37,127.61)
USBOC01_H: length 5.7
  BOTTOM w0.102: U6702.20 160.38,108.58 160.07,108.27 158.33,108.27 157.56,107.5 R79943.2 157.7,106.77 158.26,106.21 v4(158.5,106.21)
USBOC02: length 261.7
  TOP w0.102: v2(140.85,118.95) 141.21,118.59 142.7,118.59 143.47,119.37 146.79,119.37 150.27,115.89 150.27,112.22 151.77,110.72 151.77,105.48 152.2,105.05 152.2,85.36 155.25,82.32 155.25,71.16 145.4,61.31 145.4,55.66 144.04,54.3 144.04,47.88 139.82,43.66 129.9,43.66 129.36,44.19 127.61,44.19 126.57,43.16 v1(126.57,42.47) ; CPU2.P16 77.5,159.97 77.5,160.03 v1(77.47,160.06) ; U124.3 94.71,28.45 R709.1 95.16,28.99 94.6,29.55 94.6,31.22 95.66,32.29 v2(95.66,33.33)
  L3 w0.127: v1(99.37,136.58) 99.37,141.42 99.71,141.75 108.36,141.75 125.26,124.86 134.18,124.86 138.68,120.36 139.44,120.36 v2(140.85,118.95) ; v1(126.57,42.47) 124.73,40.64 124.48,40.64 122.33,38.48 115.55,38.48 114.62,37.55 114.62,35.78 109.2,30.35 105.66,30.35 103.96,32.05 96.94,32.05 v2(95.66,33.33)
  BOTTOM w0.102: v1(99.37,136.58) 99.04,136.91 99.04,138.57 96.3,141.31 91.96,141.31 90.89,140.25 v4(84.41,140.25) 83.9,140.76 82.24,140.76 79.98,143.03 78.87,143.03 78.23,143.67 76.05,143.67 74.49,145.24 72.46,145.24 69.31,148.38 69.31,154.12 71,155.8 71.24,155.8 71.5,156.06 71.7,156.06 72.33,156.69 73.96,156.69 74.15,156.88 74.15,156.97 74.45,157.27 75.17,157.27 75.66,157.76 75.68,157.76 76.07,158.15 76.24,158.15 77.47,159.38 v1(77.47,160.06)
USBOC02_H: length 2.2
  BOTTOM w0.102: U6702.19 160.88,108.57 159.89,107.58 R79703.2
USBP0N_EXT: length 20.4
  TOP w0.102: SSUSB1.2 172.62,117.33 173.97,115.98 174.51,115.98 175.2,115.28 175.2,112.38 171.91,109.09 171.91,107.22 171.23,106.53 169.78,106.53 169.06,107.25 168.21,107.25 U6704.4 167.7,107.25 167.41,107.25 166.8,106.64 TR4.1
USBP0P_EXT: length 20.2
  TOP w0.102: SSUSB1.3 172.62,116.66 172.73,116.77 172.76,116.77 172.77,116.78 172.87,116.78 173.88,115.76 174.42,115.76 174.99,115.19 174.99,112.47 171.7,109.18 171.7,107.31 171.14,106.74 170.9,106.74 U6704.3 170.39,106.74 169.87,106.74 169.15,107.47 167.32,107.47 166.71,106.86 166.57,106.86 166.47,106.96 166.47,107.07 166.21,107.33 TR4.4
USBVCC14: length 49.3
  TOP w0.305: v1(147.96,115.44) 147.02,114.5 U9625.12 ; U6704.5 169.01,106.05 v2(169.02,106.05)
  TOP w0.508: v1(162.24,102.84) 162.34,102.84 162.95,103.45 v6(170.29,103.45)
  TOP w0.635: 172.62,99.73 SSUSB2.1 171.73,98.84 ; TC11.1 165.49,125.34 ; TC11.1 164.43,124.28 ; TC11.1 165.49,123.23 ; TC11.1 166.54,124.28
  L3 w0.635: v2(169.02,106.05) 169.02,104.72 v6(170.29,103.45)
  L4 w0.381: v1(162.24,102.84) 160.46,102.84 152.31,111 152.31,115.63 151.52,116.41 148.6,116.41 148.01,115.82 148.01,115.49 v1(147.96,115.44)
  L4 w0.635: 172.62,97.95 SSUSB2.1 ; SSUSB2.1 172.62,99.73 ; SSUSB2.1 171.73,98.84 ; SSUSB1.1 172.62,121.23 ; SSUSB1.1 172.62,119.45 ; SSUSB1.1 171.73,120.34
  vias: v6(173.16,122.02)
USBVCC56: length 19
  TOP w0.508: 101.51,23.24 103.36,25.1 U6703.5
  TOP w0.635: 100.03,40.53 USB3.1 ; USB3.1 101.06,41.56 ; USB3.1 101.06,39.5 ; USB3.1 102.09,40.53 ; 100.03,17.53 USB4.1 ; USB4.1 101.06,18.56 ; USB4.1 102.09,17.53 ; USB4.1 101.06,16.5 ; TC20.1 93.11,21.56 ; TC20.1 92.06,22.62 ; TC20.1 92.06,20.51 ; TC20.1 91,21.56
  BOTTOM w0.635: v4(96.72,36.97) 96.74,37 97.3,37 v2(97.34,37.03)
USBVCCTP: length 4.6
  TOP w0.305: TOUCH1.5 28.47,6 29.47,5 v3(29.47,4.7)
  TOP w0.61: v6(26.46,5.76) 26.46,5.78 27.18,6.5 TOUCH1.5
  vias: v4(27.13,4.29)
V_1P5_HDMI: length 20.8
  TOP w0.203: U127.20 130.94,38.53 130.82,38.65 130.82,39.17 131.34,38.65 U127.19 ; v2(129.27,32.51) 129.79,33.03 U127.31 ; U127.12 134.14,38.6 134.21,38.67 134.21,38.67 134.34,38.81 134.35,38.81 135.59,40.05 v2(135.59,40.13) ; v2(135.75,32.41) 135.43,32.41 134.81,33.03 U127.40
  TOP w0.381: v2(135.59,40.13) 135.67,40.13 135.91,40.37 C4288.1 ; v2(135.75,32.41) 135.84,32.41 136.81,31.44 C4282.1
  TOP w0.508: v6(122.23,28.37) 122.23,27.8 C4284.1 ; C4290.2 129.95,40.88 129.95,39.7 v2(130,39.65) 130.06,39.65 130.54,39.17 130.82,39.17
  BOTTOM w0.305: v2(129.27,32.51) 129.27,32.41 127.41,30.56 C4281.1
  BOTTOM w0.508: v2(130,39.65) 129.69,39.96 C4286.1 ; C4287.1 135.79,40.33 v2(135.59,40.13)
  vias: v4(122.08,27.46)
V_1P05_LAN: length 11
  TOP w0.203: U20.24 34.09,13.59 v6(33.27,12.76) ; v2(40.17,13.84) 39.62,14.39 U20.3 ; U20.8 39.94,16.39 v2(40.09,16.54) ; v2(33.3,14.65) 33.57,14.39 U20.22 ; U20.30 37.21,11.54 v2(37.4,11.35)
  TOP w0.635: v6(33.27,12.76) 33.07,12.56 C202.2
  BOTTOM w0.508: v6(33.27,12.76) 33.66,12.37 34.2,12.37 C1801.1 ; v2(37.4,11.35) 37.14,11.61 C548.2
  vias: v4(40.07,17.49)
V_3_CARD_BD: length 14
  TOP w0.635: MEMCD1.4 164.63,144.72 164.03,144.25 C73.2 163.58,144.28 163.58,145.02 C75.2 163.29,146.17 163.06,146.4 v6(162.9,146.4)
  BOTTOM w0.305: v4(166.88,146.83) 167.52,146.18 167.52,145.85 168.02,145.35 SU1.5
  BOTTOM w0.508: v4(166.88,146.83) 166.27,147.43 C74.2 164.84,147.43 C72.2 164.24,147.96 F6.1 163.13,146.66 162.9,146.43 v6(162.9,146.4)
V_3P0_BAT_VREG: length 289.7
  TOP w0.508: R91.1 152.47,181.6 v2(152.26,181.6) ; v2(152.31,170.18) 152.81,170.18 153.06,170.43 R87.1 ; v2(149.56,54.43) v3(149.56,56.18) 149.56,59.08 158.94,68.45 158.94,83.55 155.75,86.73 155.75,97.34 156.73,98.31 156.73,102.9 152.83,106.79 152.83,116.2 152.01,117.01 152.01,117.03 v3(151.62,117.42) 151.62,117.45 146.87,122.2 v2(143.34,122.2)
  TOP w0.635: D5.3 137.31,20.62 138.44,19.49 138.44,17.51 v2(138.23,17.31)
  L3 w0.635: v2(143.61,168.91) 143.29,168.59 143.29,129.98 143.67,129.6 143.67,127.54 143.34,127.21 v2(143.34,122.2)
  L4 w0.508: v2(138.23,17.31) 144.53,23.61 144.53,27.03 149.5,32 149.5,33.73 150.15,34.38 150.15,41.61 149.33,42.42 149.33,49.07 149.89,49.63 149.89,54.1 v2(149.56,54.43)
  BOTTOM w0.381: v2(149.56,54.43) 149.56,54.48 149.97,54.89 R322.2
  BOTTOM w0.635: R1255.1 69.78,153.11 69.78,148.58 72.65,145.71 74.9,145.71 76.31,144.3 v4(77.52,144.3) 78.49,144.3 79.1,143.69 80.2,143.69 82.5,141.38 90.84,141.38 91.39,141.94 96.55,141.94 113.7,124.79 124.14,124.79 125.05,123.88 125.1,123.83 141.72,123.83 v4(142.07,123.47) v2(143.34,122.2) ; v2(152.26,181.6) 152.26,179 152.18,178.92 v4(152.18,176.66) 152.18,170.31 v2(152.31,170.18) 151.39,169.27 143.96,169.27 v2(143.61,168.91)
V_3P3_A: length 994
  TOP w0.305: R296.2 141.49,49.43 141.05,49.86 R279.2 R275.2 R270.2 137.2,49.86 135.65,48.31 C179.1 ; R1579.2 92.48,123.61 R51.2 92.58,124.07 92.26,124.38 v1(92.26,125.17) ; PR9787.1 139.16,109.73 v1(138.84,109.73) ; R80212.2 138.76,68.28 139.69,69.22 v1(139.94,69.22) ; R321.1 135.78,71.18 135.63,71.02 135.63,68.97 L7.1 135.36,68.66 133.87,67.16
  TOP w0.381: PR5214.1 48.27,217.47 47.94,217.14 v2(44.91,217.14) PR5480.1 ; R79692.2 139.59,60.74 139.07,60.22 139.07,59.35 138.31,58.6 U15.8 ; R79692.2 139.71,60.78 v2(139.71,63.3) ; R79692.2 R79693.2 R79694.2 ; v1(138.84,109.73) 138.84,109.42 138.01,108.58 PR4712.1 ; v1(8.03,216.03) 8.8,216.03 9.71,216.94 R719.1
  TOP w0.508: PR5257.1 PR5246.1 21.85,175.39 20.81,174.35 v2(20.73,174.35) ; v6(56.47,60.6) 56.4,60.68 56.4,61.11 56.37,61.13 PR5281.1 ; v2(36.02,169.37) 36.08,169.32 PR5213.1 PR5241.1 ; R304.2 132.41,46.22 131.91,45.72 v2(131.91,45.36) ; v1(129.07,52.48) 129.75,51.79 130.77,51.79 ; R79691.1 134.89,47.27 C179.1 134.89,48.76 134.17,49.48 132.82,49.48 v2(132.8,49.45) ; v2(115.31,21.84) 116.03,21.12 126.5,21.12 126.93,21.55 132.9,21.55 133.86,20.6 134.38,20.6 135.21,21.43 135.21,21.57 D5.1 137.93,21.57 v2(138.21,21.84) ; v1(109.72,118.77) R66.2 ; PR4450.2 61.42,73.94 62.42,72.95 62.42,70.46 62.77,70.1 v2(62.77,69.93)
  TOP w0.635: v6(93.46,46.19) 93.32,46.19 92.34,45.21 73.57,45.21 v1(71.43,43.08)
  TOP w1.016: 160.41,89.59 160.41,86.03 162.19,84.25 171.92,84.25 v6(172.75,85.09)
  L3 w0.381: v2(119.49,52.48) 119.39,52.48 117.55,50.63 115.41,50.63 115.36,50.68 113.93,50.68 113.71,50.46 109.06,50.46 v2(108.72,50.8)
  L3 w0.508: v2(62.77,69.93) 62.77,68.45 59.98,65.66 59.2,65.66 56.47,62.94 v6(56.47,60.6) ; v2(132.8,49.45) 132.8,49.11 131.91,48.22 v2(131.91,45.36) ; v1(27.9,25.16) 34.04,25.16 35.71,26.82 35.71,30.57 41.38,36.25 49.78,36.25 51.76,38.23 67.34,38.23 70.87,41.76 70.87,42.52 v1(71.43,43.08) ; v2(138.21,21.84) 138.21,22.58 140.04,24.41 145.11,29.48 145.11,36.56 v2(145.12,36.58) 145.12,42.83 147.58,45.29 147.58,51.43 v2(148.9,52.76)
  L3 w1.016: v6(56.47,60.6) 56.3,60.6 55.25,59.56 54.5,59.56 53.32,60.73 53.32,63.07 52.69,63.7 52.53,63.7 v2(51.98,64.26) ; 44.91,220.12 v2(44.91,217.14) ; 44.91,220.12 40.69,224.35 12.4,224.35 11.4,223.34 11.4,221.64 8.03,218.27 v1(8.03,216.03) 8.03,206.2 11.54,202.69 11.54,202.46 13.55,200.45 13.55,194.26 19.51,188.29 19.51,185.72 20.35,184.89 20.35,183.29 v6(21.47,182.17) v6(21.47,180.87) 21.85,180.49 21.85,175.23 20.96,174.35 v2(20.73,174.35) ; 44.91,220.12 44.91,221.06 45.22,221.36 45.22,221.4 46.17,222.35 47.45,222.35 50.25,225.14 94.68,225.14 95.05,224.76 108.34,224.76 109.19,225.61 125.72,225.61 127.86,223.47 151.72,223.47 167.8,207.39 167.8,161.01 167.99,160.82 167.99,160.1 177.21,150.89 177.21,129.79 171.45,124.03 171.45,91.22 173.26,89.41 173.26,85.6 v6(172.75,85.09)
  L3 w2.032: 139.95,69.47 142.65,69.47 143,69.11 148.64,69.11 155.79,76.26 155.79,84.81 156.37,85.39 ; 111.74,67.18 112.94,65.99 124.99,65.99 125.02,66.01 131.05,66.01 131.07,65.99 132.85,67.77
  L4 w0.381: v2(41.92,181.64) 40.19,179.91 40.19,177.79 39.31,176.91 v2(39.23,176.91) ; v2(123.6,73.15) 120.24,76.52 119.58,76.52 117.19,78.91 115.41,78.91 v1(115.17,78.66)
  L4 w0.508: v2(39.23,176.91) 35.97,173.66 35.97,169.42 v2(36.02,169.37) ; v2(131.91,45.36) 131.32,45.36 130.58,44.63 127.83,44.63 125.94,42.74 125.94,42.34 124.29,40.7 123.63,40.7
  L4 w0.635: 123.63,40.7 122.58,39.64 114.42,39.64 v6(114.33,39.73) 112.83,41.22 106.21,41.22 103.27,44.16 101.14,44.16 99.35,45.95 95.36,45.95 v6(95.31,45.9)
  L4 w1.016: v6(93.46,46.19) 93.35,46.19 93.34,46.2 64.61,46.2 57.61,53.2 57.61,59.46 v6(56.47,60.6)
  BOTTOM w0.305: v2(51.98,64.26) 51.98,64.2 51.47,63.66 PR4427.1 50.71,63.42 50.17,63.96 49.26,63.96 48.74,63.44 PR5289.1 ; v2(148.9,52.76) 150.13,52.76 R319.1 ; R65.1 34.14,178.98 v4(35.08,178.05) 36.21,176.91 v2(39.23,176.91) ; v1(27.9,25.16) 27.91,25.16 28.1,24.96 R370.1 ; v2(145.12,36.58) 145.7,35.99 R643.1 R639.1
  BOTTOM w0.356: R363.2 115.84,67.86 115.84,67.8 116.81,66.84 v2(116.89,66.84)
  BOTTOM w0.381: R5290.1 43.1,182.81 v2(41.92,181.64) ; v2(109.49,65.49) 109.82,65.49 110.33,66 R57.2 110.55,66.15 110.55,66.64 110.59,66.68 110.59,68.98 111.92,70.31 120.07,70.31 122.93,73.16 123.59,73.16 v2(123.6,73.15) 123.62,73.16 125.82,73.16 126.22,73.57 127.36,73.57 128.46,72.47 131.71,72.47 132.4,73.16 133.92,73.16 134.47,72.62 R80228.2 ; Q9649.S 137.3,72.75 136.89,73.16 135.91,73.16 135.53,72.77 C6725.2 ; v1(139.94,69.22) 139.92,69.2 139.92,67.49 139.95,67.45 139.95,65.96 139,65.01 v4(139,64.85) 139,64.58 139.15,64.42 139.15,63.85 v2(139.71,63.3) ; v1(138.84,109.73) 138.84,111.12 138.34,111.63 138.34,114.65 135.8,117.18 119.45,117.18 117.68,118.95 109.89,118.95 v1(109.72,118.77) 109.72,118.97 108.73,119.95 103.71,119.95 102.88,120.78 102.88,122.55 98.09,127.34 98.09,127.69 96.71,129.07 93.44,129.07 92.51,128.14 92.51,125.43 v1(92.26,125.17)
  BOTTOM w0.508: C216.1 132.91,65.94 v2(133.4,66.42) ; v6(56.47,60.6) 56.23,60.6 55.47,59.84 PR5273.1 PR4426.1 PR4425.1 54.21,58.42 55.53,57.1 55.53,55.32 55.09,54.88 54.27,54.88 53.31,53.91 PR5278.1 PR5286.2 ; C6725.2 135.53,72.62 R80228.2 ; v1(129.07,52.48) 128.89,52.48 128.21,53.15 R79667.2 ; R80232.1 141.37,68.5 140.65,68.5 v1(139.94,69.22) ; v2(119.49,52.48) 119.36,52.35 119.36,51.56 L9.1 ; v1(109.72,118.77) 110.07,118.41 110.09,118.41 112.58,115.93 112.58,115.91 112.59,115.89 112.59,114.26 113.7,113.16 v4(113.7,110.95) 113.7,80.52 115.17,79.04 v1(115.17,78.66) ; v6(102.14,51.69) 102.34,51.49 108.03,51.49 v2(108.72,50.8) ; R363.2 114.64,68.15 C183.1
  BOTTOM w0.635: v6(114.33,39.73) 114.41,39.65 114.75,39.65 116.77,37.62 116.77,26.21 115.31,24.75 v2(115.31,21.84)
  vias: v3(27.19,181.74) v3(29.22,173.43) v3(34.88,173.81) v6(100.87,54.61) v6(100.87,53.09) v6(100.87,51.69) v6(102.14,54.61) v6(102.14,53.09) v6(157.98,90.69) v6(158.64,89.92)
V_3P3_LAN: length 99.1
  TOP w0.203: U20.32 38.01,12.11 38.59,11.53 v2(38.59,11.25) ; U20.11 v2(37.21,18.49) ; U20.23 33.55,13.99 33.3,13.73 v2(33.21,13.73)
  TOP w0.305: v2(49.84,12.12) 49,12.95 U121.5
  TOP w0.381: R79618.1 84.64,26.09 v1(84.01,26.72) 81.77,28.96 U6705.5
  TOP w0.508: C554.2 40.22,10.9 40.03,10.9 39.68,11.25 v2(39.45,11.25) 38.59,11.25 v2(38.59,11.25)
  TOP w0.635: C232.1 33.38,8.84 33.74,9.19 v6(33.84,9.19)
  L3 w0.635: v1(84.01,26.72) 82.16,28.56 71.75,28.56 70.62,27.43 68.61,27.43 63.94,32.11 52.71,32.11 41.94,21.34 41.27,21.34 38.42,18.49 v2(37.21,18.49) 34.48,15.76 34.48,12.8 33.55,11.87 33.55,9.54 33.84,9.25 v6(33.84,9.19) ; v2(49.84,12.12) 47.19,12.12 v2(46.34,12.97) 43.57,10.2 41.01,10.2 39.96,11.25 v2(39.45,11.25)
  BOTTOM w0.305: v2(46.34,12.97) 46.34,12.98 46.31,12.95 U122.5
  BOTTOM w0.508: R372.1 37.05,18.65 v2(37.21,18.49)
  BOTTOM w0.635: v1(84.01,26.72) v4(84.01,25.88)
  vias: v4(34.68,10.36) v4(38.11,18.75) v4(38.95,10.31)
V_3P3_PCIVAUX: length 22.5
  TOP w0.305: NGFF1.4 120.06,205.5 ; NGFF1.72 119.74,222.5
  TOP w0.381: v2(101.06,220) 101.03,219.96 R1842.2
  BOTTOM w0.381: 117.84,222.38 108.38,222.38 107.99,222.77 R1844.1 105.59,222.77 104,221.18 101.35,221.18 101.15,220.98 v4(101.15,220.95) 101.06,220.87 v2(101.06,220)
  vias: v4(118.14,219.02) v4(124.01,204.09) v6(120.43,204.24) v6(120.53,223.78) v6(121.45,204.24)
V_5_CODEC: length 14.7
  TOP w0.203: 160.95,52.81 U6.39
  TOP w0.305: 160.95,52.81 160.95,52.96 v2(161.32,53.34)
  TOP w0.635: v2(161.32,53.34) v3(162.09,54.1) 162.09,54.11 162.4,54.43 C147.2 162.4,56.12 C146.1
  BOTTOM w0.635: v2(161.32,53.34) 160.79,53.34 159.75,54.38 C450.2 157.41,55.68 156.85,55.12 L19.1
V_5_LCD1:
  vias: v4(34.48,105.94)
V_5_LCD2:
  vias: v4(36.53,108.99)
V_5HDD: length 8.5
  TOP w0.635: 12,193.93 SATAP1.3 ; SATAP1.3 13.07,195 ; SATAP1.3 12,196.07 ; SATAP1.3 10.93,195 ; 10.93,200 SATAP1.1 ; SATAP1.1 13.07,200 ; SATAP1.1 12,198.93 ; SATAP1.1 12,201.07
  vias: v3(18.63,198.02)
V_5P0_A: length 557.8
  TOP w0.203: 159.02,91.71 158.73,92 ; 159.02,91.71 U54.4 ; 159.02,91.71 158.93,91.71 ; U52.4 103.18,57.18 ; 158.93,91.71 158.66,91.44 ; 158.93,91.71 158.03,91.71
  TOP w0.305: U9625.1 143.92,114.98 142.88,116.01 v6(142.87,116.01)
  TOP w0.381: 103.18,57.18 103.09,57.26 102.47,57.26 102.43,57.3 101.79,57.3 v2(101.76,57.33)
  TOP w0.508: 5.65,215.24 5.97,214.91 12.17,214.91 14.43,217.17 PR48.1 ; PU5201.6 39.58,172.82 PC5213.1 39.15,174.32 v2(39.05,174.42)
  TOP w0.584: 142.86,116.01 142.5,115.66 C314.1 140.6,114.92 v3(140.34,114.92)
  TOP w0.635: 162.11,100.86 163.51,102.26 170.08,102.26 v6(170.28,102.06) ; v6(20.76,178.61) 23.27,178.61 23.77,178.11 PU5203.6 ; v6(142.87,116.01) 142.86,116.01
  TOP w1.016: 34.16,225.29 33.8,225.65 7.17,225.65 5.65,224.13 5.65,192.4 16.1,181.94 17.56,181.94 19.59,179.91 PC5224.1 20.73,178.64 v6(20.76,178.61) ; 34.16,225.29 35.92,227.05 85.25,227.05 v3(86.22,226.09) 88.5,223.8 v6(88.5,223.75) ; 34.16,225.29 34.55,224.9 34.55,221.16 PR9793.2
  L3 w1.016: v6(125.26,223.65) 125.89,223.65 127.8,221.74 143.04,221.74 143.8,220.98 148.7,220.98 158.31,211.37 158.31,205.96 159.66,204.61 159.66,185.69 164.24,181.1 164.24,159.53 164.42,159.36 164.42,133.61 158.28,127.48 158.28,126.72 160.1,124.9 160.1,117.55 157.23,114.68 157.23,104.93 157.82,104.34 v6(157.82,96.75)
  L3 w2.54: 155.05,87.96 154.19,87.1 154.19,87.07 153.14,86.03 153.14,80.32 150.17,77.34 148.66,77.34 147.59,76.28 140.61,76.28 139.85,75.51 136.4,75.51 134.07,73.19 132.9,73.19 130.76,71.04 121.48,71.04 121.33,70.89 107.53,70.89 107.5,70.87 104.96,70.87 104.94,70.89 103.87,69.82
  L4 w0.381: v2(156.8,62.41) 165.39,70.99 165.39,76.07 165.5,76.18 165.55,78.34 165.55,79.54 171.85,85.84 171.85,89.17 171.38,89.64 171.38,96.64 170.61,97.41 170.61,101.73 v6(170.28,102.06)
  L4 w0.635: v6(157.82,96.75) 157.82,100.96 150.53,108.24 148.22,108.24 146.17,110.29 146.17,113.13 143.29,116.01 v6(142.87,116.01)
  L4 w1.016: v6(88.5,223.75) 101.04,223.75 102.91,225.61 123.34,225.61 125.26,223.7 v6(125.26,223.65)
  BOTTOM w0.508: v2(156.8,62.41) 156.8,62.41 154.98,60.59 154.98,58.91 153.9,57.84 152.82,57.84 152.43,57.45 152.43,55.32 L19.2 152.64,53.67 D21.K
  BOTTOM w0.635: v6(20.76,178.61) 20.78,178.59 20.78,177.5 v4(22.94,175.34) 23.86,174.42 v2(39.05,174.42)
  vias: v3(89.31,35.43) v3(103.16,61.24) v3(155.38,115.65) v4(95.18,56.11) v6(88.93,42.93) v6(88.96,48.59) v6(90.01,48.64) v6(90.33,42.93) v6(99.85,67.35) v6(100.31,63.91) v6(100.29,62.84) v6(100.31,61.7) v6(100.36,60.2) v6(100.86,67.31) v6(101.48,63.93) v6(101.58,62.87) v6(101.63,61.72) v6(101.56,60.22) v6(101.91,66.87) v6(157.79,95.73) v6(157.82,94.69) v6(157.87,93.65)
V_5P0_HDMI_CONN:
  vias: v2(115.6,40.89) v4(116.55,39.88)
V_5P0_HDMI_CONN_L:
  vias: v4(118.28,36.5)
V_19_INV: length 4.8
  BOTTOM w0.381: v2(40.35,34.28) 40.61,34.03 40.61,32.03 v4(40.17,31.6) 39.63,31.05 38.7,31.05 R79716.1
  vias: v3(39.71,43.92)
V_SM: length 62.1
  TOP w0.254: v2(145.6,132.59) 145.61,132.6 PR5014.2 PR5016.1 PC5002.1
  TOP w0.635: PTC21.1 145.3,163.11 ; PTC21.1 146.35,162.05 ; PTC21.1 144.24,162.05 ; PTC21.1 145.3,161
  TOP w1.27: v6(149.58,143.26) 149.46,143.14 PR5013.2
  L4 w0.381: v6(145.17,160.17) 143.9,158.9 143.9,150.67 145.35,149.22 145.35,145.01 147.42,142.94 147.42,133.75 146.26,132.59 v2(145.6,132.59)
  BOTTOM w0.635: PTC21.1 145.3,163.11 ; PTC21.1 144.24,162.05 ; PTC21.1 146.35,162.05 ; PTC21.1 145.3,161
  BOTTOM w1.27: v6(149.58,143.26) v4(147.51,143.26) 146.25,143.26 143.85,145.66 143.85,155.65
  vias: v4(150.88,165.46) v6(145.04,166.28) v6(145.04,165.35) v6(145.12,164.24) v6(146.06,166.28) v6(146.08,165.35) v6(146.08,164.21) v6(152.31,165.1) v6(152.31,163.83) v6(152.31,162.56) v6(152.31,161.42) v6(153.7,165.1) v6(153.7,163.96) v6(153.7,162.69) v6(153.7,161.54)
VGA_1P8_EN1: length 7.9
  TOP w0.102: Q97.3 76.3,117.23 76.13,117.4 75.78,117.4 75.65,117.27 Q97.2 75.65,116 76.11,115.54 v3(76.11,115.29) 75.98,115.16 R1914.1 74.21,114.48 72.77,114.48 R1164.2
VGA_1P8_EN2: length 9.4
  TOP w0.102: R1915.1 R1919.1 76.96,117.91 75.27,117.91 75,118.18 Q97.6 73.86,118.59 R1918.2 71.18,116.94 v3(71.15,116.97)
VGA_1P8_EN3: length 4.9
  TOP w0.102: v3(79.61,114.33) 78.96,114.97 R1916.2 79.52,115.88 79.84,116.2 79.84,117.2 80.42,117.78 U42.3
VGA_1P8_EN4: length 3.8
  TOP w0.102: R1915.2 78.23,117.87 v3(77.78,117.42) C859.1 78.24,116.31 78.7,116.77 R1916.1
VGA_CORE: length 41.8
  TOP w0.635: PT3.1 110.08,104.67 ; PT3.1 109.02,105.73 ; PT3.1 107.97,104.67 ; PT3.1 109.02,103.62 ; 109,87.87 PT1.1 ; PT1.1 107.94,88.93 ; PT1.1 109,89.98 ; PT1.1 110.05,88.93 ; PT4.1 110.08,96.8 ; PT4.1 107.97,96.8 ; PT4.1 109.02,95.74 ; PT4.1 109.02,97.85
  L3 w0.635: PT1.1 110.05,88.93 ; PT1.1 109,87.87 ; PT1.1 109,89.98 ; PT1.1 107.94,88.93 ; 107.97,96.8 PT4.1 ; PT4.1 109.02,95.74 ; PT4.1 110.08,96.8 ; PT4.1 109.02,97.85 ; 107.97,104.67 PT3.1 ; PT3.1 109.02,103.62 ; PT3.1 109.02,105.73 ; PT3.1 110.08,104.67
  L4 w0.635: PT1.1 109,89.98 ; PT1.1 110.05,88.93 ; PT1.1 107.94,88.93 ; PT3.1 110.08,104.67 ; PT3.1 109.02,103.62 ; PT3.1 109.02,105.73 ; PT3.1 107.97,104.67 ; 109.02,95.74 PT4.1 ; PT4.1 109.02,97.85 ; PT4.1 110.08,96.8 ; PT4.1 107.97,96.8
  BOTTOM w0.305: v1(86.86,96.12) 87.05,95.92 87.05,94.72 87.18,94.59 87.18,93.66 PC5271.2 86.82,93.3 PR28.1
  BOTTOM w0.508: v6(116.26,98.81) v4(116.26,97.82)
  vias: v1(80.07,102.7) v1(80.1,95.94) v1(80.15,97.24) v1(81.51,108.89) v1(82.05,100.76) v1(82.11,102.68) v1(82.1,99.95) v1(82.12,99.12) v1(82.12,97.08) v1(82.17,108.84) v1(83.13,96.11) v1(83.9,101.65) v1(83.98,103.05) v1(83.98,100.79) v1(85.84,98.04) v1(85.9,100.63) v1(85.91,99.19) v1(98.66,108.06) v3(115.7,88.16) v3(116.24,103.28) v4(80.73,108.82) v6(80.09,101.91) v6(80.09,100.94) v6(80.09,100) v6(80.07,99.04) v6(83.93,99.09) v6(84.87,102.97) v6(84.87,101.93) v6(84.92,98.17) v6(108.24,94.87) v6(108.26,102.97) v6(108.26,101.96) v6(108.26,100.91) v6(108.29,93.9) v6(108.29,92.99) v6(109.23,94.84) v6(109.25,102.95) v6(109.25,101.93) v6(109.25,100.89) v6(109.28,93.88) v6(109.28,92.96) v6(115.3,102.16) v6(115.27,100.56) v6(115.27,98.83) v6(115.27,92.61) v6(115.27,91.69) v6(116.29,102.13) v6(116.26,100.53) v6(116.26,92.58) v6(116.26,91.67)
VGG_HOT: length 9
  TOP w0.102: 20.92,163.33 22.52,163.33 23.06,163.87 PU4501.2 ; 20.92,163.33 21.96,164.37 21.96,164.77 21.39,165.33 v3(20.57,165.33) 19.72,165.33 R1606.2 R1830.2 ; 20.92,163.33 R1831.2
VGG_PG: length 177.5
  TOP w0.102: v2(81.64,211.91) 81.64,212.84 PR4403.1 PC4410.1 PR4402.2 ; PU4501.6 23.54,162.27 23.54,162.26 22.29,161.01 v2(22.18,161.01) 21.43,161.01 20.91,160.49 20.91,160.3 20.28,159.67 18.57,159.67 15.91,162.33 15.91,165.13 12.76,168.28 v2(12,168.28)
  L4 w0.127: v2(12,168.28) 12.2,168.28 12.82,168.9 12.82,184.65 5.64,191.84 5.64,224.61 6.48,225.46 80.7,225.46 82.69,223.47 82.69,220.53 81.64,219.48 v2(81.64,211.91)
  BOTTOM w0.102: v2(22.18,161.01) 22.21,161.04 22.33,161.04 23.06,161.76 PC4509.1 PR4501.2 ; v4(82.83,211.7) 82.62,211.91 v2(81.64,211.91) 81.64,213.11 80.85,213.9 PU4401.1
VGG_SENSEN_CPU_N: length 140
  TOP w0.102: v2(24.8,170.31) 23.99,171.12 22.47,171.12 22.28,170.93 R1589.1 ; v1(83,162.34) 82.99,162.34 CPU2.AD22
  L3 w0.127: v1(83,162.34) 82.57,162.78 82.57,163.27 83.05,163.75 85.64,163.75 85.97,163.42 86.86,163.42 90.9,159.38 90.9,158.56 91.68,157.78 91.68,154.99 92.45,154.22 92.45,152.49 92.15,152.19 92.15,150.83 87.96,146.63 85.28,146.63 83.81,145.17 83.81,144.06 79.36,139.61 66.67,139.61 63.8,136.74 63.52,136.74 61.87,135.09 52.91,135.09 52.28,134.45 44.7,134.45 44.52,134.64 41.61,134.64 41.14,135.1 38.7,135.1 38.55,135.25 36.84,135.25 33.51,138.58 32.44,138.58 30.59,140.44 21.05,140.44 19.28,142.21 19.28,165.14 24.45,170.31 v2(24.8,170.31)
  BOTTOM w0.102: v2(24.8,170.31) 24.62,170.13 23.96,170.13 v4(23.86,170.23)
VGG_SENSEN_CPU_P: length 139.6
  TOP w0.102: CPU2.AD24 82.98,163.11 82.98,163.11 v1(82.99,163.1) ; v2(25.87,170.31) 24.44,171.73 21.58,171.73 21.2,171.35 R1588.1
  L3 w0.127: v1(82.99,163.1) 83.41,163.52 85.47,163.52 85.81,163.18 86.78,163.18 90.67,159.29 90.67,158.46 91.45,157.68 91.45,154.86 92.22,154.09 92.22,152.6 91.74,152.12 91.74,150.78 87.98,147.02 84.94,147.02 82.39,144.47 82.39,143.99 78.52,140.12 66.46,140.12 63.59,137.25 63.31,137.25 62.09,136.03 53.13,136.03 52.06,134.96 44.91,134.96 44.73,135.14 41.82,135.14 41.35,135.61 38.91,135.61 38.76,135.76 37.13,135.76 33.76,139.14 32.6,139.14 30.8,140.94 21.26,140.94 19.78,142.42 19.78,164.71 23.86,168.78 24.25,168.78 25.77,170.31 v2(25.87,170.31)
  BOTTOM w0.102: v2(25.87,170.31) 25.87,170.17 26.02,170.02 v4(27.54,170.02)
VGG_SENSEN_N: length 4.6
  TOP w0.102: PR4511.2 PC4514.2 22.13,168.36 v3(21.19,169.3) 21.37,169.48 R1589.2 R1827.1
VGG_SENSEN_P: length 4
  TOP w0.102: PR4510.1 20.22,168.34 v3(20.15,168.4) 20.12,168.43 20.12,170.24 R1826.2 R1588.2
VGG_SVID_ALERT: length 7.1
  TOP w0.102: PU4501.4 23.27,163.07 22.89,162.69 21.75,162.69 v3(20.99,161.93) 19.31,161.93 18.6,162.64 R1648.2
VGG_SVID_ALERT_R: length 175.4
  TOP w0.102: v2(12,170.33) 12.2,170.33 17.51,165.03 R1648.1
  L4 w0.127: v2(77.02,209.3) 77.68,208.64 82.02,208.64 84.54,211.15 84.54,224.08 81.48,227.13 5.17,227.13 3.79,225.76 3.79,190.96 10.67,184.09 10.67,171.66 v2(12,170.33)
  BOTTOM w0.102: v2(77.02,209.3) 76.79,209.07 v4(76.79,208.41) 77.6,207.59 PR5222.2
VGG_SVID_CLK: length 5
  TOP w0.102: PU4501.5 23.33,162.67 22.61,161.95 v3(22.44,161.95) 21.88,161.95 20.08,160.16 R79792.2
VGG_SVID_CLK_R: length 185.6
  TOP w0.102: R79792.1 18.77,160.16 17.5,161.43 R79937.2 16.42,162.66 16.42,165.3 12.44,169.28 v2(11.95,169.28)
  L4 w0.127: v2(73.9,206.22) 75.67,208 82.25,208 85.12,210.87 85.12,224.26 81.57,227.8 4.76,227.8 3.15,226.2 3.15,190.63 9.97,183.81 9.97,171.26 v2(11.95,169.28)
  BOTTOM w0.102: PR5220.2 73.77,207.19 73.77,206.35 v2(73.9,206.22) 73.93,206.19 74.83,206.19 v4(74.84,206.18)
VGG_SVID_DATA: length 5.6
  TOP w0.102: PU4501.3 23.06,163.47 22.61,163.02 21.37,163.02 20.89,162.53 v3(19.74,162.53) 19.43,162.85 R1647.2
VGG_SVID_DATA_R: length 195.1
  TOP w0.102: R1647.1 18.53,163.53 R79793.2 18.53,164.81 12.12,171.23 v2(12.12,171.44)
  L4 w0.127: v2(12.12,171.44) 11.3,172.26 11.3,184.64 4.48,191.46 4.48,225.42 5.46,226.41 81.25,226.41 83.93,223.72 83.93,219.51 83.8,219.38 83.49,219.38 83.36,219.25 83.36,219 83.49,218.87 83.8,218.87 83.93,218.74 83.93,218.49 83.8,218.36 83.49,218.36 83.36,218.24 83.36,217.98 83.49,217.86 83.8,217.86 83.93,217.73 83.93,217.47 83.8,217.35 83.49,217.35 83.36,217.22 83.36,216.97 83.49,216.84 83.8,216.84 83.93,216.71 83.93,216.46 83.8,216.33 83.49,216.33 83.36,216.2 83.36,215.95 83.49,215.82 83.8,215.82 83.93,215.7 83.93,215.44 83.8,215.32 83.49,215.32 83.36,215.19 83.36,214.93 83.49,214.81 83.8,214.81 83.93,214.68 83.93,211.35 81.99,209.41 81.6,209.41 81.13,209.88 81.13,212.04 80.73,212.45 80.47,212.45 80.35,212.32 80.35,210.67 80.22,210.54 79.97,210.54 79.84,210.67 79.84,212.32 79.71,212.45 79.46,212.45 79.33,212.32 79.33,210.67 79.2,210.54 78.95,210.54 78.82,210.67 78.82,212.32 78.7,212.45 78.44,212.45 78.32,212.32 78.32,210.67 78.19,210.54 77.93,210.54 77.81,210.67 77.81,212.32 77.68,212.45 77.02,212.45 76.66,212.09 76.66,210.06 76.79,209.93 79.31,209.93 79.44,209.8 v2(79.44,209.31)
  BOTTOM w0.102: PR5221.2 80.96,207.42 v4(80.25,208.13) 79.44,208.94 v2(79.44,209.31)
VNN_SENSEN_CPU: length 54.7
  TOP w0.102: v2(53.86,187.41) 53.86,187.47 53.21,188.13 PR9766.1 ; CPU2.AC27 v1(81.43,165.38)
  L4 w0.127: v1(81.43,165.38) 81.85,165.8 81.85,166.78 81.34,167.29 81.34,168.02 82.16,168.84 82.16,170.13 81.48,170.82 81.48,175.52 80.64,176.36 80.64,186.38 79.28,187.73 v2(79.28,188.9)
  BOTTOM w0.102: v2(53.86,187.41) 54.17,187.41 55.52,186.06 v4(61.4,186.06) 77.02,186.06 79.28,188.32 v2(79.28,188.9)
VOUT_INV: length 5.2
  BOTTOM w0.305: U120.18 32.93,32.38 32.08,33.23 v4(32.08,33.28) 31.84,33.52 31.53,33.52 30.2,34.85 C39.1
  vias: v6(25.89,39.62) v6(25.89,38.76) v6(25.89,37.9)
VR_SVID_ALERT#: length 40.9
  TOP w0.102: CPU2.AD40 v1(82.05,170.84)
  BOTTOM w0.102: v1(82.05,170.84) 79.81,170.84 79.46,171.2 79.46,174.6 79.47,174.61 79.47,180.39 R79791.2 79.28,181.59 79.28,185.45 80.63,186.79 80.63,203.5 v4(79.58,204.54) 78.7,205.43 PR5234.1 PR5222.1
VR_SVID_CLK: length 51.4
  TOP w0.102: CPU2.AD42 v1(82.05,172.26)
  BOTTOM w0.102: v1(82.05,172.26) 82.45,171.86 82.45,170.67 82.22,170.43 81.7,170.43 81.5,170.64 79.73,170.64 79.24,171.13 79.24,179.12 78.65,179.72 78.44,179.72 78.2,179.95 78.2,180.16 77.28,181.08 77.28,184.23 79.76,186.72 79.76,203 77.59,205.17 v4(75.78,205.17) 74.02,205.17 72.88,206.3 PR5220.1 72.88,207.77 73.38,208.27 PR5233.1
VR_SVID_DATA: length 40
  TOP w0.102: CPU2.AD41 v1(82.05,171.55)
  BOTTOM w0.102: v1(82.05,171.55) 81.94,171.55 81.43,171.04 79.9,171.04 79.66,171.28 79.66,174.52 79.7,174.55 79.7,184.84 81.45,186.6 v4(81.45,201.45) 81.45,203.83 80.96,204.32 PR5221.1 PR5232.1
VR_TT#: length 7
  TOP w0.203: 129.83,78.64 130.08,78.89 130.08,79.35 130.09,79.36 130.09,79.54 130.18,79.62 U6706.4
  TOP w0.254: 129.83,78.64 129.04,77.85 129.04,75.01 128.4,74.37 TP204.1
VRAM1_VREFCA: length 7.8
  BOTTOM w0.178: MEM3.M8 52.8,109.29 50.27,109.29
  BOTTOM w0.305: C12335.1 48.22,109.15 v4(48.83,109.76) 49.18,109.42 R885.1 49.5,108.78 50.01,109.29 50.27,109.29
  BOTTOM w0.508: C12335.1 48.04,108.78 R886.2
VRAM1_VREFDQ: length 10.9
  BOTTOM w0.178: MEM3.H1 58.81,112.07 59.92,110.97
  BOTTOM w0.508: 59.92,110.97 59.99,110.9 59.99,109.84 60.9,108.92 60.9,107.05 61.53,106.43 61.96,106.43 v4(62.39,105.99) R928.1 R924.2 C12334.1
VRAM2_VREFCA: length 18.7
  TOP w0.178: v1(60.11,108.86) 59.68,108.42 59.29,108.42 59.26,108.45 58.72,108.45 58.29,108.88 MEM1.M8
  TOP w0.508: v2(50.51,108.74) 50.47,108.78 R230.1 C163.1 R1905.2
  L3 w0.178: v2(50.51,108.74) 51.41,109.64 51.87,109.64 52.85,110.62 53.96,110.62 54.23,110.88 54.98,110.88 55.27,110.6 55.81,110.6 58.23,108.18 59.42,108.18 59.66,108.42 59.66,108.42 60.09,108.86 v1(60.11,108.86)
  BOTTOM w0.305: v2(50.51,108.74) 50.22,108.45 v4(50.22,108.02)
VRAM2_VREFDQ: length 7.3
  TOP w0.178: 50.73,112.72 50.8,112.72 51.69,111.83 52.16,111.83 MEM1.H1
  TOP w0.508: 50.73,112.72 50.6,112.85 50.6,113.19 50.22,113.57 v3(50.17,113.57) R203.1 48.07,113.57 R202.2 C1854.1 C835.1
VRAM3_VREFCA: length 15
  L3 w0.178: v2(50.69,94.08) 50.7,94.08 53.65,94.08 53.95,94.39 55.25,94.39 55.5,94.63 56.38,94.63 56.59,94.85 58.84,94.85 59.16,94.53 v1(59.41,94.53)
  BOTTOM w0.178: v1(59.41,94.53) 59.33,94.53 59.05,94.81 58.69,94.81 58.29,94.42 MEM4.M8
  BOTTOM w0.508: R1924.1 48.76,93.7 R1923.2 C1869.1 49.67,94.76 v4(49.97,94.47) 50.35,94.08 v2(50.69,94.08)
VRAM3_VREFDQ: length 7.9
  BOTTOM w0.178: R1922.1 50.16,91.63 50.4,91.39 50.79,91.39 51.35,91.94 51.91,91.94 52.41,91.43 MEM4.H1
  BOTTOM w0.508: R1922.1 R1921.2 C1867.1 C1868.1 46.39,92.16 v4(46.79,92.56)
VRAM4_VREFCA: length 7.2
  TOP w0.178: MEM2.M8 53.21,94.43 52.81,94.84 52.23,94.84 52.02,95.04 51.77,95.04 50.82,95.99 v3(49.84,95.99)
  TOP w0.508: R1911.2 C1861.1 48.75,95.69 R79968.1 48.77,95.69 49.54,95.69 v3(49.84,95.99)
VRAM4_VREFDQ: length 19.2
  TOP w0.203: MEM2.H1 59.5,91.22 59.9,91.62 59.9,94.76 59.59,95.07 59.59,95.14 v1(59.58,95.15)
  L3 w0.178: v1(51.02,95.12) 51.02,95.59 51.8,96.37 51.89,96.37 52.02,96.5 55.52,96.5 55.54,96.53 56.53,96.53 57.7,95.36 59.37,95.36 v1(59.58,95.15)
  BOTTOM w0.508: v1(51.02,95.12) 50.34,95.79 50.29,95.79 v4(50.12,95.96) 50.06,95.96 49.95,95.84 R945.1 R946.2 C1860.1
VRAM_ZQ1: length 6.1
  BOTTOM w0.102: MEM3.L8 53.18,109.68 52.81,110.05 52.2,110.05 51.85,109.71 49.86,109.71 49.01,110.56 R870.2 49.01,111.65 v4(48.92,111.74)
VRAM_ZQ2: length 16.9
  TOP w0.102: MEM1.L8 58.38,109.32 60.22,109.32 60.52,109.02 60.52,108.69 60.29,108.46 v1(60.29,106.77)
  L3 w0.127: v1(60.29,106.77) 60.2,106.86 55.32,106.86 55.28,106.82 52.43,106.82 52.3,106.95 52.3,106.96 52.06,107.21 51.98,107.21 51.96,107.23 51.2,107.23 v2(50.85,106.88)
  BOTTOM w0.102: R899.2 49.82,106.78 v4(50.07,106.53) 50.5,106.53 v2(50.85,106.88)
VRAM_ZQ3: length 17.8
  TOP w0.102: R299.2 51.17,97.76 v2(51.37,97.56)
  L3 w0.127: v2(60.41,95.5) 59.7,96.21 59.29,96.21 59.05,95.97 57.86,95.97 56.38,97.45 55.86,97.45 55.83,97.42 51.51,97.42 v2(51.37,97.56)
  BOTTOM w0.102: MEM4.L8 58.34,93.95 58.95,93.95 59.01,93.89 60.22,93.89 60.41,94.09 v2(60.41,95.5) 60.93,95.5 v4(61.31,95.12)
VRAM_ZQ4: length 4.8
  TOP w0.102: MEM2.L8 52.78,94.05 51.51,94.05 50.96,94.61 v3(49.91,94.61) 48.91,94.61 R320.2
VREF: length 4
  BOTTOM w0.305: C4.2 37.63,32.03 v4(36.81,31.22) 35.81,30.22 U120.2
VREF_1: length 4.7
  TOP w0.203: v3(158.42,54.21) 158.83,53.8 159.6,53.8 160.14,53.25 U6.41
  TOP w0.635: v3(158.42,54.21) 158.29,54.34 C140.1
VREF_CA_0: length 12.8
  BOTTOM w0.254: R117.2 131.07,147.3 v4(131.62,146.75) 132.19,146.18 133.56,146.18 133.56,146.13 134.7,145 134.71,145 134.91,144.8 136.82,144.8 137.04,144.58 138.87,144.58 139.3,145.01 139.3,146.26 R122.1 139.07,146.53 R1671.2
VREF_CA_DIMM1: length 5.5
  TOP w0.254: DIMM1.126 140.62,150.65 v2(140.85,150.42)
  BOTTOM w0.254: R1671.1 141.04,146.54 C81.1 141.04,148.66 C82.2 v4(141.04,149.62) 141.04,150.22 v2(140.85,150.42)
VREF_DQ_0: length 7.2
  BOTTOM w0.254: R484.2 125.76,184.77 v4(127.21,186.22) R483.1 R1670.2
VREF_DQ_DIMM1: length 6.7
  TOP w0.254: DIMM1.1 133.36,190.55 v1(133.54,190.73)
  BOTTOM w0.254: v1(133.54,190.73) 133.47,190.73 v4(132.97,190.23) C302.1 C303.2 129.95,189.17 R1670.1
VREG_PCIAUX_PCH: length 7.6
  BOTTOM w0.381: R13.1 127.97,214.62 127.99,214.62 128.71,215.34 v4(128.79,215.34) 128.81,215.32 R10.2 130.34,214.44 Q3.D 130.4,218.14 Q6708.C
VREG_PCIAUX_PCH_1: length 5.9
  BOTTOM w0.61: PC1.2 126.84,211.87 Q1209.G 125.74,211.58 v4(125.74,213.06) 126.23,213.55 C1616.1 R13.2
VRP: length 5.5
  TOP w0.203: U6.38 161.35,52.37
  TOP w0.254: 161.35,52.37 163.48,54.51 v3(163.48,54.97) 163.94,55.42 C155.2
VSDIO: length 179.5
  TOP w0.305: v1(162.75,140.31) 163.41,140.97 R1656.1
  TOP w0.635: Q9634.D 73.84,127.39 Q9632.D 68.2,130.2 v1(63.63,134.77) 61.45,136.96 61.45,140.18 62.8,141.54 62.8,142.83 65.06,145.08 66.83,145.08 R1246.1
  L3 w0.381: v1(63.63,134.77) 63.89,134.77 67.13,138.02 84.28,138.02 85.65,136.65 85.65,132.5 90.78,127.37 93.57,127.37 93.92,127.72 93.92,132.83 92.58,134.18 92.58,135.37 86.74,141.22 86.74,142.35 88.01,143.62 92.57,143.62 93.25,142.94 v1(106.21,142.94)
  L4 w0.381: v1(106.21,142.94) 108.96,140.18 109.71,140.18 121.94,127.95 139.95,127.95 140.68,128.69 143.05,128.69 143.34,128.4 148.72,128.4 149.28,128.96 154.33,128.96 162.86,137.49 162.86,140.2 v1(162.75,140.31)
  BOTTOM w0.305: v1(162.75,140.31) 163.54,140.31 v4(163.66,140.19)
VSUM_RC: length 2
  TOP w0.254: PC14.2 138.21,83.71 138.21,84.58 v3(138.26,84.63) 137.31,84.63 PR34.2
VSUM_RR: length 50.2
  TOP w0.254: PR42.2 143.92,89.15 144.03,89.26 v1(145.19,89.26) ; PR51.1 117.97,101.43 117.97,102.08 v1(118.17,102.29)
  L4 w0.254: v1(118.17,102.29) 118.17,102.49 120.45,104.78 125.51,104.78 128.28,107.54 138.4,107.54 138.89,107.06 140.14,107.06 146.64,100.56 146.64,90.7 v1(145.19,89.26)
  BOTTOM w0.254: v1(145.19,89.26) 145.12,89.33 v4(144.36,89.33)
VTT_EN: length 241.2
  TOP w0.102: PU5001.7 151.3,131.92 151.07,131.7 150.72,131.7 150.34,132.08 149.58,132.08 147.86,130.35 147.82,130.35 147.07,129.61 147.07,129.37 145.77,128.07 v2(142.4,128.07) ; R1577.2 77.86,208.55 78.53,207.89 v2(78.53,203.59) ; v1(142.55,119.07) 142.05,119.57 120.22,119.57 104.84,134.95 97.73,134.95 94.05,131.28 R1576.2 93.09,130.99 91.72,130.99 91.07,131.64 90.61,131.64 89.04,130.07 R1578.2
  L3 w0.127: v2(144.74,204.75) 144.74,204.52 143.62,203.4 143.62,190.43 143.67,190.38 143.67,188.75 145.14,187.27 145.14,186.23 143.64,184.73 143.64,181.41 141.85,179.62 141.85,134.56 141.71,134.41 141.71,128.79 142.4,128.1 142.4,128.07 ; 142.4,128.07 v2(142.4,128.07) ; 142.4,128.07 142.07,127.74 142.07,120 142.4,119.67 142.4,119.25 142.55,119.09 v1(142.55,119.07)
  L4 w0.127: v2(78.53,203.59) 78.9,203.21 82.95,203.21 83.19,203.45 98.37,203.45 101.47,206.55 118.62,206.55 118.79,206.37 126.28,206.37 127.99,204.66 144.65,204.66 v2(144.74,204.75)
  BOTTOM w0.102: v4(78.47,202.74) 78.53,202.8 v2(78.53,203.59)
WAKE_N: length 372.4
  TOP w0.102: v2(29.42,16.31) 29.54,16.19 Q19.E 31.39,16.19 32.47,15.11 33.64,15.11 33.96,14.79 U20.21 ; R1628.2 v2(102.93,220.22)
  L3 w0.127: v2(82.19,223.26) 82.63,223.7 86.34,223.7 87.67,222.38 95.03,222.38 95.79,223.14 102.06,223.14 102.93,222.28 v2(102.93,220.22) ; v2(6.66,204.19) 6.14,203.66 6.14,187.41 12.64,180.9 12.64,151.37 13.34,150.67 13.34,136.85 16.18,134.01 27.62,134.01 29.64,131.99 29.64,126.49 29.95,126.18 29.95,98.48 30.76,97.67 30.76,78.6 30.11,77.95 30.11,73.86 27.33,71.09 27.33,53.78 29.2,51.91 29.2,46.19 26.98,43.97 25.55,43.97 22.79,41.21 22.79,31.44 22.42,31.07 22.42,26.94 25.55,23.81 25.55,20.18 v2(29.42,16.31)
  L4 w0.127: v2(6.66,204.19) 6.26,204.6 6.26,224.17 7.04,224.95 80.47,224.95 82.16,223.26 v2(82.19,223.26) ; v2(102.93,220.22) 105.72,220.22 107.78,222.28 119.49,222.28 119.84,222.63 125,222.63 v2(125.64,222)
  BOTTOM w0.102: R60.1 29.7,14.2 29.7,16.03 v2(29.42,16.31) ; v2(102.93,220.22) 103.51,220.22 v4(103.74,219.99) ; v2(125.64,222) 123.68,222 123.16,221.48 R1627.1
WAKE_N_APU: length 4.5
  TOP w0.102: CPU2.N16 76.74,159.18 v1(76.69,159.18)
  BOTTOM w0.102: R1263.1 74.01,157.14 74.85,157.99 75.19,157.99 v4(75.44,158.24) 75.73,158.54 76.05,158.54 v1(76.69,159.18)
WEA0#: length 43
  TOP w0.127: v1(75.01,106.43) 75.01,106.67 75.14,106.8 GPU1.G25 ; v3(61.75,106.2) 61.75,107.01 v1(61.78,107.04) ; MEM1.L3 54.01,109.85 54.13,109.97 55.18,109.97 v1(55.37,110.16)
  L3 w0.165: v1(61.78,107.04) 61.93,107.19 63.21,107.19 63.59,107.58 63.59,107.94 63.72,108.07 64.1,108.07 64.27,107.9 64.27,107.36 64.43,107.19 64.92,107.19 65.08,107.36 65.08,107.9 65.25,108.07 65.73,108.07 65.89,107.9 65.89,107.36 66.06,107.19 66.54,107.19 66.71,107.36 66.71,107.9 66.87,108.07 68.39,108.07 68.88,107.58 69.24,107.22 69.66,107.22 69.83,107.04 73.11,107.04 73.23,106.91 73.23,106.79 73.36,106.67 74.78,106.67 v1(75.01,106.43)
  L4 w0.165: v1(55.37,110.16) 55.67,110.16 55.77,110.25 56.53,110.25 57.42,109.37 57.8,109.37 57.92,109.25 57.92,108.8 58.07,108.66 58.72,108.66 58.85,108.78 58.85,109.46 59.01,109.62 60.73,109.62 62.35,108 62.35,102.36 62.22,102.23 61.91,102.23 61.78,102.36 v1(61.78,107.04)
  BOTTOM w0.127: v1(55.37,110.16) 55.45,110.24 56.66,110.24 MEM3.L3
WEA1#: length 40.6
  TOP w0.127: GPU1.H10 76.2,94.57 76.33,94.45 v1(76.6,94.45) ; v1(54.58,93.69) 55.05,93.22 55.59,93.22 55.99,93.62 MEM2.L3
  L3 w0.165: v1(76.6,94.45) 76.44,94.28 74.47,94.28 74.15,93.96 73.67,93.96 73.54,94.09 73.54,94.67 73.41,94.8 72.98,94.8 72.85,94.67 72.85,94.54 72.7,94.39 71.01,94.39 70.51,94.89 66.91,94.89 66.74,95.06 61.17,95.06 60.87,95.36 60.87,96.18 60.61,96.45 59.81,96.45 59.8,96.46 58.98,96.46 58.86,96.58 58.86,97 58.98,97.13 v1(59.87,97.13)
  L4 w0.102: v1(54.58,93.69) 54.63,93.69 55.27,94.32 57.44,94.32 57.57,94.46 57.57,94.68 57.67,94.79 58.08,94.79 58.18,94.68 58.18,94.48 58.28,94.38 58.58,94.38
  L4 w0.165: v1(59.87,97.13) 59.87,97.57 59.75,97.7 59.35,97.7 59.22,97.57 59.22,96.52 58.59,95.89 57.74,95.89 57.64,95.79 57.64,95.28 57.74,95.18 58.59,95.18 58.7,95.07 58.7,94.51 58.58,94.38
  BOTTOM w0.127: v1(54.58,93.69) 54.58,93.27 54.48,93.17 53.66,93.17 53.56,93.27 53.56,93.47 53.56,93.48 53.56,93.72 53.66,93.82 53.81,93.82 MEM4.L3 ; v4(61.03,97) 60,97 v1(59.87,97.13)
WEBCAM_DET: length 199.4
  TOP w0.102: R5.2 155.62,196.28 R7.2 154.66,198.56 157.51,201.42 161.78,201.42 v1(162.5,200.7) ; U109.114 124.41,51.45 123.88,51.97 123.88,58.9 v2(122.11,60.68)
  L3 w0.127: v2(122.11,60.68) 123.18,61.76 131.09,61.76 132,62.67 136.64,62.67 136.73,62.59 137.12,62.59 139.39,62.59 139.41,62.57 141.09,62.57 142.44,63.92 144.22,63.92 144.48,63.67 147.18,63.67 155.27,71.75 155.27,72.59 158.15,75.47 158.15,83.4 162.53,87.78 162.53,93.12 163.05,93.64 163.05,107.4 162.02,108.43 162.02,114.4 161.35,115.08 161.35,115.47 162.15,116.27 162.15,120.38 164.14,122.38 164.14,128.99 166.01,130.86 166.01,160.02 165.83,160.19 165.83,183.96 162.02,187.77 162.02,200.22 v1(162.5,200.7)
  BOTTOM w0.102: v2(122.11,60.68) 122.46,61.04 v4(122.46,61.33)
WEBCAM_DET_M: length 18.1
  TOP w0.102: v1(163.23,204.98) 163.23,205.1 163.57,205.44 v3(164.32,205.44) 164.32,201.9 162.68,200.27 162.33,200.27 161.85,200.74 158.08,200.74 157.55,200.22 157.55,199.58 157,199.03 WEBCM1.7 157,196.63 R5.1
  BOTTOM w0.102: v1(163.23,204.98) 162.88,205.33 PC124.2
XDP_H_TCK: length 102.8
  TOP w0.102: v2(152.56,203.25) 152.24,203.57 XDP1.57 ; CPU2.AF42 v1(83.95,172.97)
  BOTTOM w0.102: R466.2 152.95,202.86 v2(152.56,203.25) 152.16,203.66 v4(148.01,203.66) 147.09,203.66 145.7,202.27 143.04,202.27 138.98,198.22 116.04,198.22 111.9,202.36 104.76,202.36 104.08,201.68 90.88,201.68 87.94,198.73 87.94,192.13 85.54,189.73 85.54,186.26 84.07,184.79 84.07,177.21 83.77,176.91 83.77,175.82 84.34,175.25 84.34,174.91 84.33,174.91 84.33,173.35 v1(83.95,172.97)
XDP_H_TDI: length 92.6
  TOP w0.102: R457.2 139.33,202.68 139.33,201.57 139.83,201.07 v2(139.94,201.07) 140.66,201.79 140.66,201.9 141.84,203.07 XDP1.56 ; v1(82.05,174.4) 82.4,174.75 CPU2.AD47
  BOTTOM w0.102: v2(139.94,201.07) 138.11,199.24 v4(137.62,199.24) 130.85,199.24 130.22,199.87 116.71,199.87 113.3,203.28 104.38,203.28 103.7,202.59 89.09,202.59 86.93,200.42 86.93,192.5 84.39,189.96 84.39,186.4 82.86,184.88 82.86,179.12 82.59,178.85 82.59,178.23 82.66,178.16 82.66,175.01 v1(82.05,174.4)
XDP_H_TDO: length 95.2
  TOP w0.102: R473.2 137.6,201.76 139.33,200.03 v2(139.83,200.03) 139.84,200.05 140.13,200.05 142.15,202.07 XDP1.52 ; CPU2.AF40 v1(83.95,171.55)
  BOTTOM w0.102: v2(139.83,200.03) 138.52,198.73 128.53,198.73 v4(128.2,199.06) 128.19,199.06 127.88,199.36 117.27,199.36 115.6,199.36 112.14,202.82 104.57,202.82 103.89,202.13 90.69,202.13 87.38,198.82 87.38,192.31 84.84,189.77 84.84,186.21 83.61,184.98 83.61,177.33 83.32,177.04 83.32,172.67 83.52,172.47 83.52,172.03 83.95,171.6 v1(83.95,171.55)
XDP_H_TMS: length 92.9
  TOP w0.102: R458.2 140.22,205.41 140.22,202.37 v2(139.86,202.01) 140.34,202.01 141.91,203.57 XDP1.58 ; CPU2.AD48 82.46,175.4 v1(82.05,175.82)
  BOTTOM w0.102: v1(82.05,175.82) 81.64,176.23 81.64,184.99 83.45,186.79 83.45,190.44 84.91,191.9 84.91,192.49 86.47,194.06 86.47,200.61 88.9,203.05 103.51,203.05 104.19,203.73 112.11,203.73 113.52,203.73 116.93,200.33 138.01,200.33 v4(138.4,200.72) 139.69,202.01 v2(139.86,202.01)
XDP_H_TRST_N: length 94.1
  TOP w0.102: CPU2.AB48 v1(82.05,175.11) ; R456.2 138.62,201.65 139.66,200.61 140.13,200.61 141.18,201.66 v2(141.18,201.75) 142,202.58 XDP1.54
  BOTTOM w0.102: v1(82.05,175.11) 82.45,175.51 82.45,178.08 82.39,178.14 82.39,184.73 84.16,186.5 84.16,190.14 86.7,192.68 86.7,200.52 89,202.82 103.6,202.82 104.29,203.5 112.2,203.5 113.43,203.5 116.83,200.1 130.69,200.1 131.02,199.77 v4(135.36,199.77) 138.17,199.77 138.91,200.51 138.91,200.69 139.77,201.55 140.98,201.55 v2(141.18,201.75)
XDP_PRESENT_N: length 4.5
  TOP w0.102: XDP1.60 141.43,204.08 v3(140.78,204.73) 141.1,205.05 R1568.2
XDP_PWNBTN_N: length 17.9
  TOP w0.102: v1(162.52,204.47) 162.21,204.47 161.71,204.98 158.65,204.98 TP2.1 158.56,202.83 154.68,198.94 151.61,198.94 150.98,199.57 XDP1.41
  BOTTOM w0.102: R47.2 v1(162.52,204.47)
XRF_TDC2: length 14.4
  TOP w0.508: v2(49.92,10.03) 51.21,10.03 XF1.9 v2(49.92,13.84) ; C3452.1 49.44,17.04 49,16.61 v2(48.85,16.61) 48.27,16.61 v3(47.89,16.23)
  L3 w0.508: v2(48.85,16.61) 49.92,15.54 v2(49.92,13.84)
  BOTTOM w0.508: 51.21,10.03 v2(49.92,10.03) ; XF1.9 v2(49.92,13.84)
XTAL19D2M_IN: length 7.5
  TOP w0.102: R1240.2 57.08,164.82 v3(56.83,165.07) 56.42,165.07 55.85,164.5 C1601.2 55.81,163.49 R1239.1 55.24,163.41 54.69,162.86 53.66,162.86 X6.1
XTAL19D2M_IN_R: length 24.6
  TOP w0.102: R1240.1 57.55,163.11 58.73,161.93 v2(59.37,161.93) ; v1(77.45,163.06) CPU2.P24
  BOTTOM w0.102: v1(77.45,163.06) 76.98,163.53 76.97,163.53 76.89,163.61 76.88,163.63 76.88,163.63 76.52,163.63 75.29,164.86 73.87,164.86 73.35,165.37 71.71,165.37 70.94,166.14 68.43,166.14 v4(68.26,166.31) 68.2,166.31 63.82,161.93 v2(59.37,161.93)
XTAL19D2M_OUT: length 5.4
  TOP w0.102: R1241.2 56.97,161.18 56.7,161.44 v3(56.7,161.46) C1602.2 55.89,161.63 R1239.2 55.14,162.52 X6.3
XTAL19D2M_OUT_R: length 25.1
  TOP w0.102: CPU2.M22 76.77,163.11 v1(76.81,163.11) ; R1241.1 57.91,162.06 58.81,161.16 v2(58.91,161.16)
  BOTTOM w0.102: v1(76.81,163.11) 76.81,163.23 76.61,163.42 76.44,163.42 75.8,164.06 75.07,164.06 v4(75.01,164.12) 74.5,164.63 73.78,164.63 73.26,165.16 71.64,165.16 70.9,165.89 68.56,165.89 65.67,163.01 65.67,162.86 65.92,162.62 65.92,162.44 65.74,162.26 65.56,162.26 65.31,162.5 65.17,162.5 64.95,162.29 64.95,162.14 65.18,161.91 65.18,161.73 65,161.55 64.82,161.55 64.59,161.78 64.45,161.78 64.11,161.44 59.72,161.44 59.44,161.16 v2(58.91,161.16)
XTALIN: length 9
  TOP w0.102: X8.1 100.86,109.83 99.37,109.83 R1879.1 98.16,109.26 C756.1 96.37,109.26 96.16,109.06 v3(96.14,109.06) 96.12,109.04 93.96,109.04 GPU1.AM28
XTALOUT: length 8.1
  TOP w0.102: X8.3 99.43,110.47 R1879.2 97.4,110.47 C757.1 96.27,110.41 v3(96.25,110.39) 95.44,109.58 93.38,109.58 GPU1.AK28
N29033036: length 3.7
  TOP w0.127: v3(9.91,222.83) 9.67,223.08 R721.1 8.87,222.83 7.65,221.62 U41.2
N29033116: length 4
  TOP w0.127: R719.2 9.27,218.63 8.72,219.18 U41.6 8.3,218.35 8.19,218.24 7.75,218.24 7.65,218.34 U41.5
N31212897: length 4.4
  TOP w0.127: R505.1 43.26,20.9 v1(43.47,20.7)
  BOTTOM w0.127: v1(43.47,20.7) 44.36,20.7 44.74,20.32 v4(44.74,20.07) 44.74,19.94 44.46,19.67 Q47.2
N31244723: length 26.4
  TOP w0.127: PU4701.3 40.09,223.27 41.1,224.28 v3(41.1,224.29) 51.89,224.29 52.64,223.55 52.64,221.46 50.26,219.09 PR5214.2 48.2,219.09 47.84,219.46 47.84,221.21 47.95,221.32 PR5254.1 47.87,222.12 PC5211.1
N31772467: length 5
  TOP w0.127: v2(108.61,57.14) 108.49,57.27 108.49,57.35 108.27,57.58 U52.12
  BOTTOM w0.127: v2(108.61,57.14) 108.49,57.27 108.49,57.43 v4(107.81,58.12) 107.73,58.19 C1673.1
N31772502: length 4.9
  TOP w0.127: v2(108.35,56.27) 108.35,56.42 108,56.78 U52.10
  BOTTOM w0.127: C1672.1 106.85,56.48 v4(107.04,56.29) 108.33,56.29 v2(108.35,56.27)
N31826669: length 5.3
  TOP w0.127: CPU2.BH53 94.72,178.15 95.74,178.15 96.5,178.92 96.5,181.26 TP4116.1
N31993654: length 4
  BOTTOM w0.127: Q47.1 44.64,21.63 44.91,21.91 44.91,22.85 v4(44.86,22.91) 44.8,22.97 R502.2
N32783600: length 9.3
  TOP w0.127: C1706.1 168.61,87.96 166.92,87.96 166.5,88.38 166.5,88.75 165.79,89.46 165.42,89.46 164.98,89.9 164.98,90.75 v3(164.42,91.31) 163.62,92.11 U54.12
N32783618: length 9.7
  TOP w0.127: U54.10 163.57,91.31 164.6,90.28 164.6,89.78 165.73,88.65 165.74,88.65 v3(165.79,88.6) 166.68,87.71 169.29,87.71 C1705.1
N33728196: length 104.1
  TOP w0.127: R80116.2 80.85,121.78 v3(80.68,121.61) 80.78,121.61 R80115.2 81.92,125.61 v1(81.9,125.63) ; v1(43.71,133.12) 43.09,133.75 R80237.2
  L3 w0.127: v1(81.9,125.63) 76.74,130.78 61.35,130.78 58.39,133.74 54.86,133.74 54.14,133.02 43.82,133.02 43.72,133.12 v1(43.71,133.12)
  L4 w0.127: v2(30.23,89.15) 30.23,89.3 30.97,90.03 30.97,91.41 32.31,92.75 32.31,94.2 34.2,96.1 34.2,96.51 33.91,96.81 33.91,100.35 32.49,101.76 32.49,121.97 43.65,133.12 v1(43.71,133.12)
  BOTTOM w0.127: v2(30.23,89.15) R79675.2 31.98,88.26 R79680.1 31.98,88.09 R512.1
N33875524: length 3.2
  TOP w0.127: CPU2.P12 77.31,157.03 v1(77.17,157.03)
  BOTTOM w0.127: v1(77.17,157.03) 76.48,156.34 v4(76.48,155.87) 76.48,155.81 77.15,155.14 R79658.1
N33886165: length 2.5
  TOP w0.102: CPU2.Y6 v1(81.06,154.18)
  BOTTOM w0.089: v1(81.06,154.18) 80.66,153.78 80.66,152.8 TP4136.1
N34111482: length 9.1
  TOP w0.089: CPU2.AF3 83.64,153.13 83.64,152.84 83.77,152.71 83.77,152.43 83.7,152.36 83.7,152.01 83.78,151.93 83.78,151.14 83.84,151.09 83.84,150.63
  TOP w0.102: 83.84,150.63 83.84,150.51 84.78,149.57 85.32,149.57
  TOP w0.127: 85.32,149.57 86.71,148.17 87.24,148.17 88.24,147.17 TP4135.1
N34111484: length 6.4
  TOP w0.089: CPU2.AG1 83.97,151.22 84.05,151.14 84.05,150.75
  TOP w0.102: 84.05,150.75 84.05,150.58 84.62,150.01 85.29,150.01 85.88,149.42
  TOP w0.127: 85.88,149.42 85.88,149.4 86.83,148.45 86.85,148.45 86.86,148.44 TP4134.1
N34388192: length 3.3
  TOP w0.127: v3(92.92,35) 92.92,36.19 92.91,36.2 R79764.2 92.93,36.21 Q6702.1
N34388234: length 4.6
  TOP w0.127: Q6702.3 91.36,40.14 v3(91.22,40.01) 91.55,39.67 R79765.1
N35052779: length 3.6
  TOP w0.127: R79798.2 55.64,139.51 v3(55.76,139.4) 57.36,139.4 57.55,139.2 Q6715.1
N35059072: length 3.7
  TOP w0.127: R79690.2 83.95,134.88 v3(83.93,134.9) 83.55,135.27 Q1253.1
N37176357: length 7.2
  TOP w0.127: TP4117.1 68.13,149.76 69.9,151.52 69.9,153.26 CPU2.A6
N37302844: length 6
  TOP w0.127: PU4705.3 138.78,112.12 PC5436.1 139.5,111.72 PR9787.2 140.47,110.96 v3(140.69,110.75) 141.16,111.22 PR9785.1
N37429584: length 5.2
  TOP w0.127: PR9807.1 74.81,132.74 v3(74.81,132.38) 74.81,131.81 75.27,131.35 75.27,130.5 76.07,129.7 Q9632.G
N37429627: length 11.3
  TOP w0.127: Q9634.G 76.57,126.03 74.69,127.9 74.69,130.7 74.33,131.06 72.8,131.06 v3(72.47,131.39) 72.5,131.42 72.5,131.55 PR9808.1
N37652823: length 4.8
  TOP w0.127: v1(89.51,104.72) 89,104.21 GPU1.AD22
  BOTTOM w0.127: v1(89.51,104.72) 89.87,105.08 91.5,105.08 v4(91.8,105.38) 91.85,105.44 92.02,105.44 R80137.2
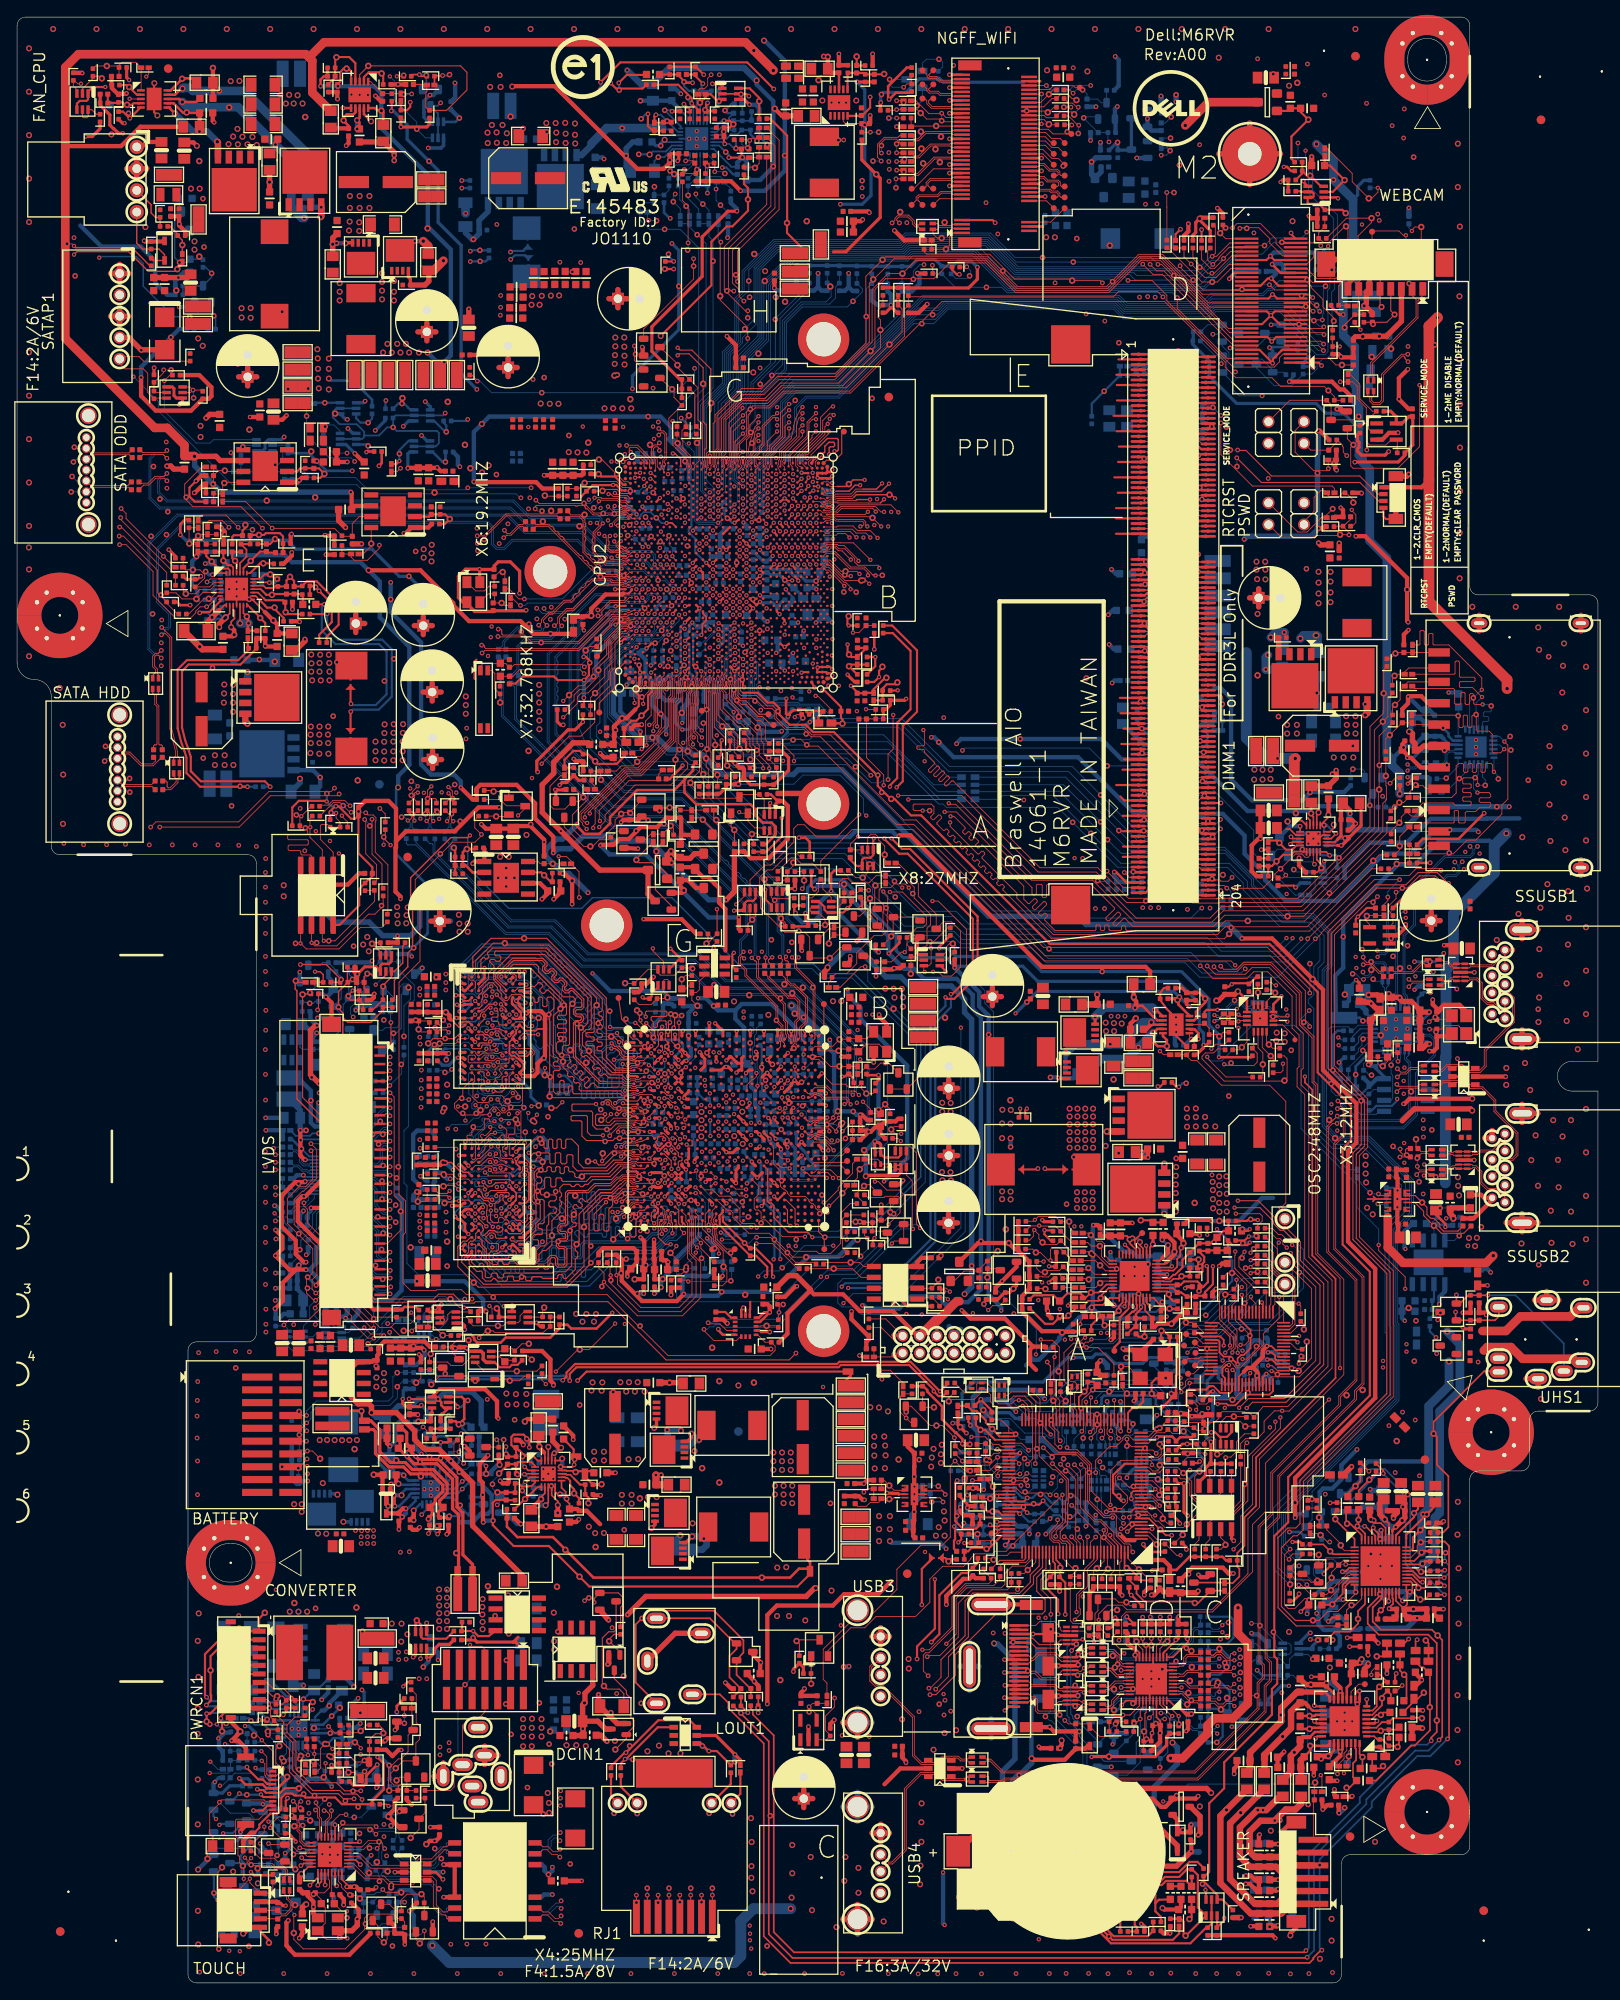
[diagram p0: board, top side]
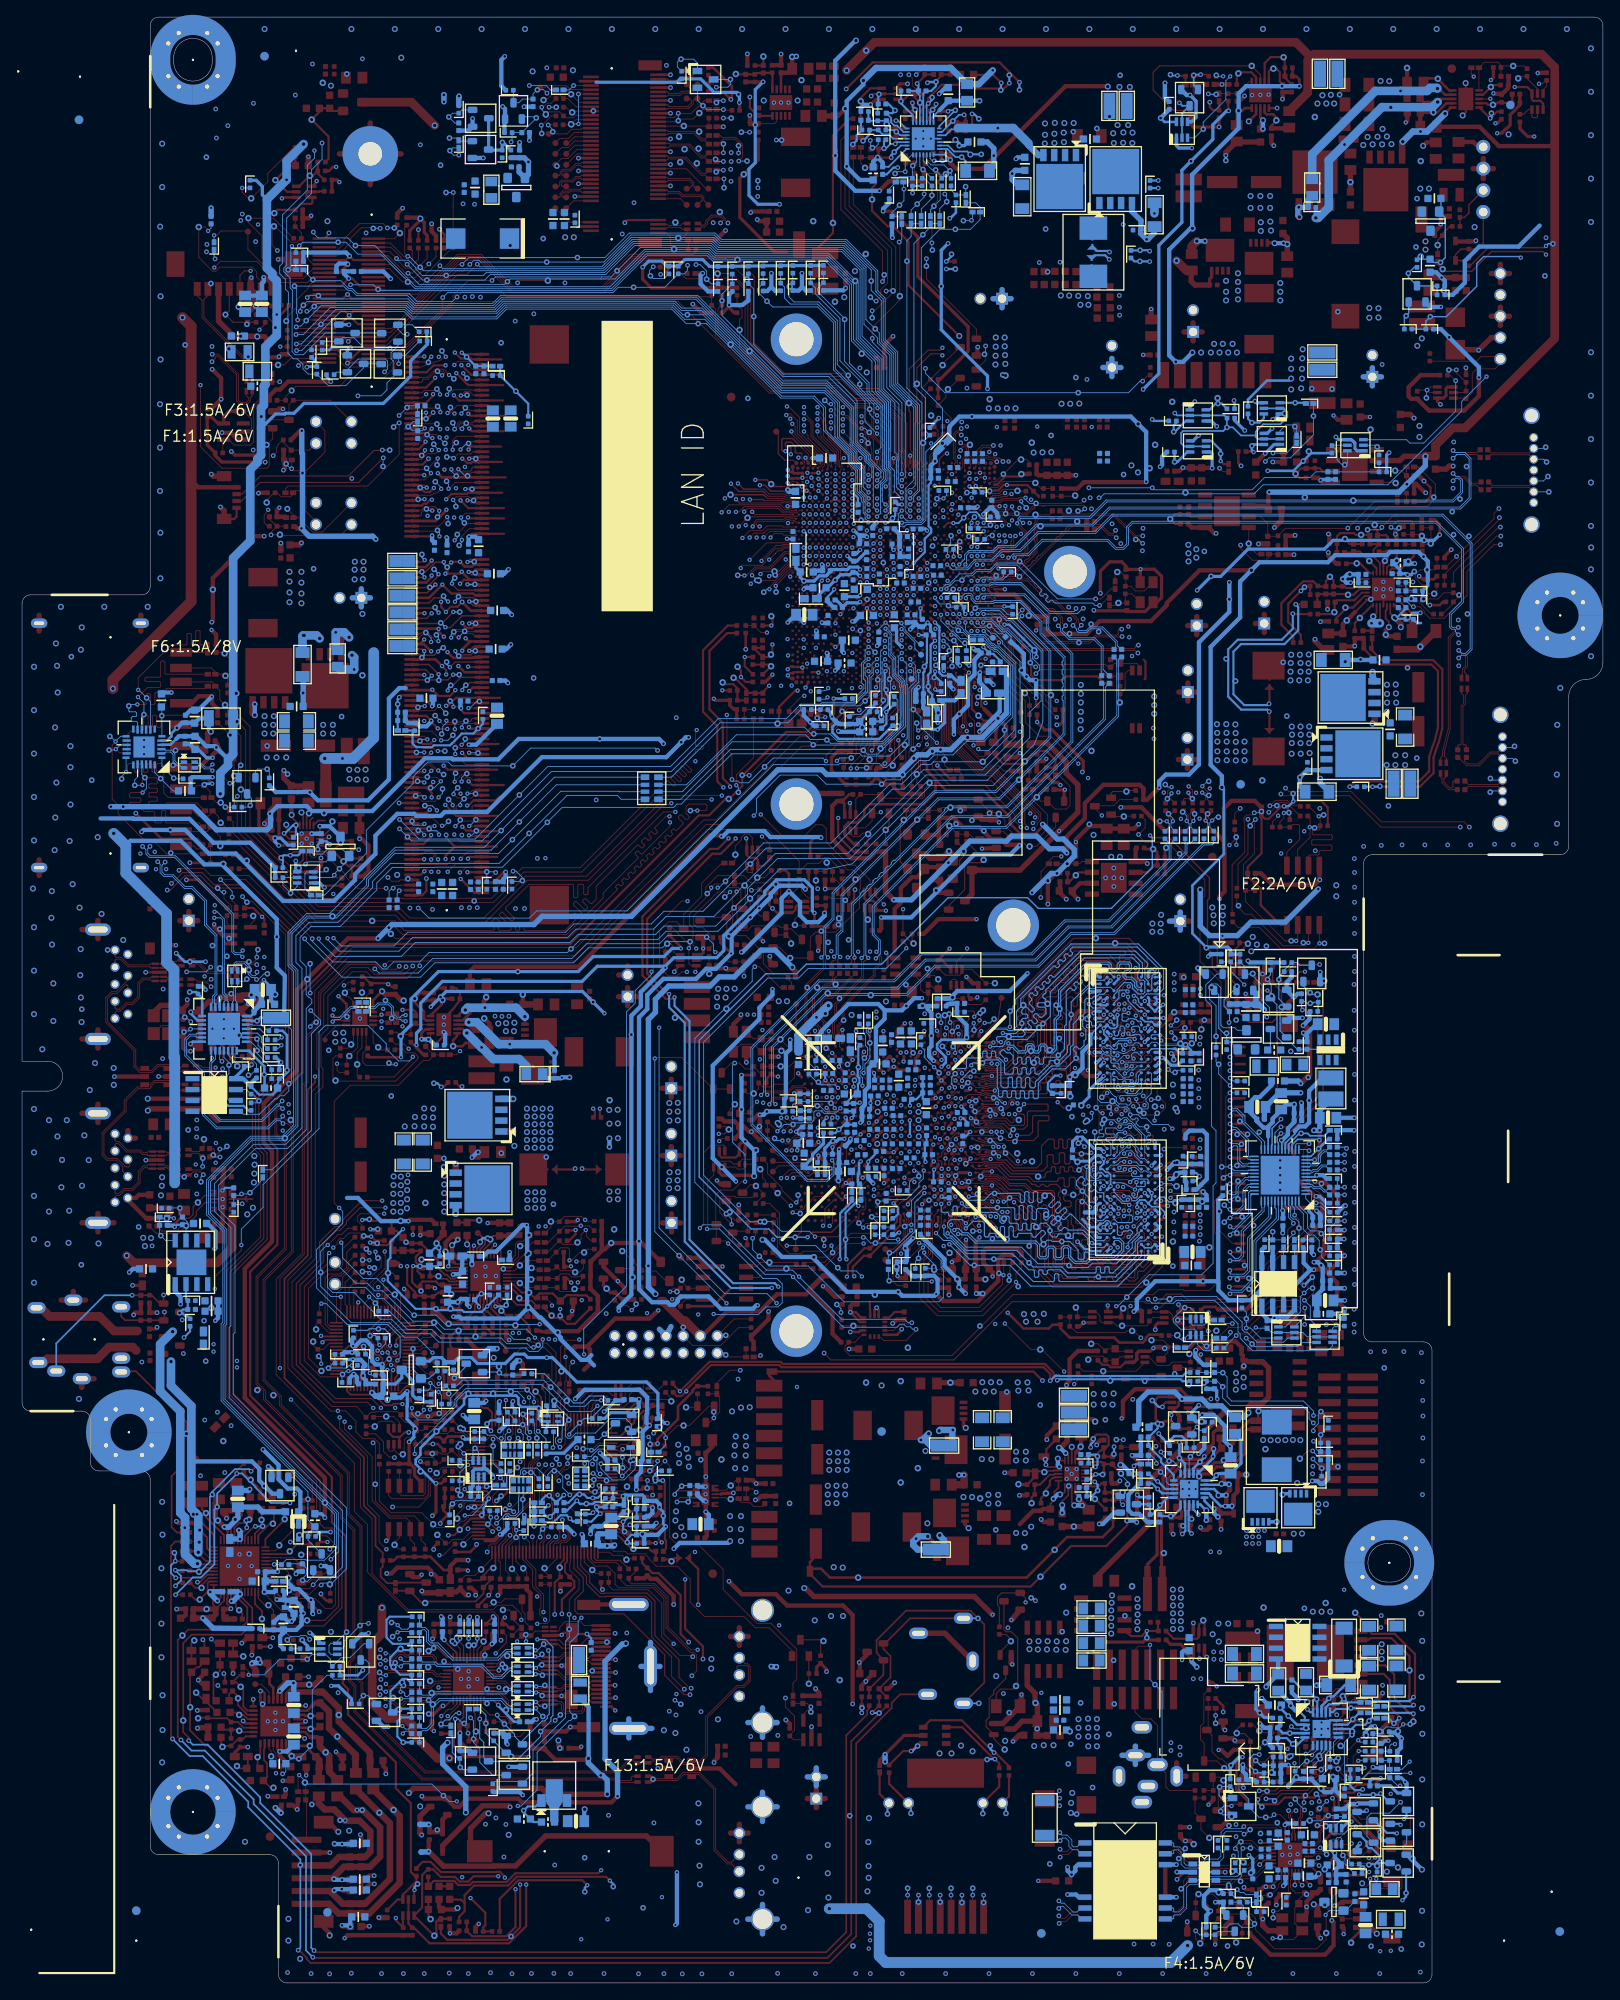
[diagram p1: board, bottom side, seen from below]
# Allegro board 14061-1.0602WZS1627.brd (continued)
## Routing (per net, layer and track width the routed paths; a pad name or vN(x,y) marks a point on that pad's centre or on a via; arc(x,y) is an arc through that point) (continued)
N37662300: length 1.6
  TOP w0.127: GPU1.AF17 90.6,100.77 90.18,101.19 v1(90.18,101.24)
  BOTTOM w0.127: R80143.2 90.32,101.1 v1(90.18,101.24)
N37690583: length 7.5
  TOP w0.127: Q9640.G 82.24,131.2 82.24,135.65 v3(81.82,136.07) 81.53,136.36 PR9810.1
N37690585: length 3.6
  TOP w0.127: Q9641.G 81.37,134.97 v3(80.25,136.09) 80.02,136.31 PR9811.1
N37778405: length 4.4
  TOP w0.127: v3(86.02,124.4) 86.42,124.8 Q9643.6 ; v3(86.02,124.4) 85.77,124.66 Q9643.5 ; v3(86.02,124.4) 85.54,123.92 R80155.1
N37779677: length 4.9
  TOP w0.127: R80112.2 126.74,41.53 R3586.1 127.47,42.46 Q2301.S 127.47,43.11 128,43.64 v3(128.73,43.64)
N37842456: length 5.1
  TOP w0.127: TP4131.1 70.76,112.73 72.2,111.3 GPU1.A32
N37842467: length 3.6
  TOP w0.127: GPU1.AM1 93.8,87.89 94.46,87.23 TP4132.1
N37842487: length 4
  TOP w0.127: GPU1.AM32 94.41,111.41 TP4133.1
N38212737: length 8.5
  BOTTOM w0.127: Q9647.G 43.6,110.09 R80233.1 44.03,111.1 v4(44.05,111.11) 44.36,111.11 44.95,111.7 44.95,115.59 Q9650.D

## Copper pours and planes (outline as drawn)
19V_AMP_PVCC on TOP: 153.58,35.26 153.35,35.48 153.35,36.42 153.02,36.75 153.02,38.51 153.25,38.73 155.02,38.73 155.35,38.4 155.35,37.13 154.59,36.37 154.59,35.41 154.44,35.26 ; 5 cut-outs
19V_AMP_PVCC on L3: 154.59,37.62 153.12,37.62 152.33,36.83 152.33,26.62 152.94,26.01 154.67,26.01 155.15,26.49 155.15,27.51 154.06,28.6 154.06,31.95 154.99,32.88 154.99,34.94 155.23,35.18 155.23,36.98
+5V_PWR on TOP: 93.89,57.91 93.51,58.29 93.51,62.87 93,63.37 85.76,63.37 85.38,63.75 85.38,70.36 86.01,70.99 97.19,70.99 97.44,70.74 97.44,58.17 97.19,57.91 ; 1 cut-out
AGND on TOP: 157.89,56.39 157.77,56.52 157.77,57.56 159.24,59.03 160.23,59.03 160.56,59.36 160.56,60.33 159.93,60.96 159.93,63.12 169.83,73.03 171.1,73.03 171.36,72.77 171.36,72.14 165.77,66.55 165.77,60.1 166.66,59.21 166.66,57.91 166.4,57.66 159.11,57.66 158.78,57.33 158.78,56.64 158.53,56.39 ; 1 cut-out
AGND on L2VCC: 150.1,4.13 154.24,4.13 154.24,1 154.17,0.83 154,0.76 86.96,0.76 86.96,28.27 83.42,31.81 73.01,31.81 71.98,32.84 71.98,42.34 73.39,43.75 81.49,43.75 85.14,40.1 85.14,37.74 86.08,36.8 86.08,35.71 87.13,34.66 87.13,31.51 88.87,29.77 88.87,6.27 91.01,4.13
AGND on L2VCC: outline of 108 points within 153.51,18.55 184.24,82.36
AGND on L5GND: 150.73,2.48 150.46,2.75 150.46,14.91 153.89,18.34 153.89,20.11 154.91,21.13 154.91,22.91 163.04,31.04 163.04,35.64 157.83,40.85 157.83,44.12 158.21,44.5 158.21,46.15 158.23,46.16 161.91,46.16 162.15,46.4 162.15,51.01 161.78,51.37 157.31,51.37 156.93,50.99 156.07,50.99 155.8,51.26 155.8,51.77 153.51,54.05 153.51,56.56 154.53,57.58 154.53,59.36 158.48,63.31 160.01,63.31 166.47,69.77 166.47,72.82 167.61,73.96 167.61,74.99 167.62,75.01 167.61,75.07 167.61,75.14 167.6,75.15 167.6,75.16 167.54,75.2 167.5,75.25 167.48,75.25 166.59,75.91 166.59,76.76 167.48,77.65 167.48,80.31 169.53,82.36 174.33,82.36 178.01,78.68 180.71,78.68 182.61,80.58 184.24,80.58 184.24,67.9 184.17,67.73 184,67.66 179.67,67.66 179.67,71.33 178.93,72.07 175.98,72.07 174.07,70.17 170.64,70.17 170.25,69.77 167.48,67.01 167.48,50.92 167.79,50.62 167.79,27.92 166.98,27.11 166.32,27.11 164.55,25.34 163.28,25.34 159.86,21.92 159.86,21.29 159.7,21.13 156.91,18.34 153,14.43 153,2.75 152.74,2.48
GND on TOP: 30.64,56.98 30.55,57.07 30.55,59.25 30.63,59.32 33.51,59.32 33.65,59.46 33.65,60.46 33.9,60.72 34.64,60.72 35.07,60.29 35.07,57.67 34.39,56.98
GND on TOP: 164.24,98.3 163.99,98.55 163.99,101.22 164.37,101.6 168.18,101.6 168.44,101.35 168.44,99.62 168.71,99.34 169.17,99.34 169.3,99.21 169.3,98.53 169.07,98.3 ; 1 cut-out
GND on TOP: 133.87,89.84 133.48,90.22 133.48,93.83 133.59,93.93 135.01,93.93 135.21,94.13 135.21,95.89 134.37,96.72 133.61,96.72 133.23,97.1 133.23,97.97 133.36,98.09 134.75,98.09 135.9,96.95 141.61,96.95 141.63,96.94 146.76,96.94 147.35,96.34 147.35,92.51 146.92,92.08 142.17,92.08 141.89,91.8 141.89,90.07 141.66,89.84 ; 3 cut-outs
GND on TOP: 46.18,81.36 45.04,82.5 45.04,116.93 47.27,119.15 47.98,119.15 48.2,118.94 48.2,114.29 48.1,114.19 46.51,114.19 46.51,114.2 45.75,114.2 45.5,113.94 45.5,113.23 45.8,112.93 46.18,112.93 46.26,112.85 46.26,111.33 46.26,111.33 46.67,110.92 47.23,110.92 47.4,110.74 47.4,109.6 47.15,109.35 46.59,109.35 46.46,109.22 46.46,108.19 46.51,108.15 48.42,108.15 48.49,108.07 48.49,102.64 48.31,102.46 48.31,97.43 48.11,97.23 48.11,96.51 47.98,96.39 46.28,96.39 46.13,96.24 46.13,95.22 46.31,95.04 48.11,95.04 48.29,94.86 48.29,93.72 48.06,93.49 48.04,93.49 47.59,93.04 46.59,93.04 46.36,92.81 46.36,91.79 47.07,91.08 48.19,91.08 48.29,90.98 48.29,88.01 48.17,87.88 48.17,81.58 47.94,81.36 ; 37 cut-outs
GND on TOP: 98.23,219.1 98.05,219.28 94.6,219.28 94.39,219.48 89.49,219.48 89.34,219.63 89.34,220.62 89.48,220.76 98.99,220.76 99.22,220.54 99.22,219.23 99.09,219.1 ; 2 cut-outs
GND on TOP: outline of 151 points within 57.64,131.29 129.66,195.58 ; 25 cut-outs
GND on TOP: 60.66,210.01 60.41,210.26 60.41,217.63 61.04,218.26 65.36,218.26 65.62,218.01 65.62,210.26 65.36,210.01
GND on TOP: 24.44,212.83 24.32,212.95 24.32,222.45 24.9,223.04 28.38,223.04 28.68,222.73 28.68,217.09 29.57,216.2 29.57,215.32 30.41,214.48 30.41,213.49 30.23,213.31 28.33,213.31 27.85,212.83 ; 2 cut-outs
GND on TOP: 64.04,24.38 63.66,24.77 63.66,27.81 63.91,28.07 67.72,28.07 67.98,27.81 67.98,24.64 67.72,24.38
GND on TOP: 90.15,54.79 88.3,56.64 88.3,58.42 88.55,58.67 92.87,58.67 93,58.55 93,54.99 92.79,54.79
GND on TOP: 79.33,110.36 78.87,110.82 78.87,112.47 77.22,114.12 77.22,115.19 77.43,115.39 78.39,115.39 78.43,115.43 78.44,115.42 79.74,115.42 80.07,115.75 80.07,116.56 80.22,116.71 81.31,116.71 81.64,116.38 81.64,115.29 82.23,114.71 82.23,112.85 82.96,112.12 82.96,110.74 82.58,110.36 ; 3 cut-outs
GND on TOP: 97.21,110.98 97.08,111.1 97.08,111.61 97.21,111.74 97.97,111.74 98.23,111.99 98.23,115.55 98.48,115.8 99.75,115.8 101.13,114.43 101.13,112.9 100.91,112.69 99.94,112.69 98.23,110.98 ; 5 cut-outs
GND on TOP: 52.48,145.29 52.23,145.54 52.23,146.94 53.5,148.21 53.5,154.18 53.88,154.56 53.63,154.56 53.5,154.69 53.5,155.19 53.75,155.45 66.35,155.45 66.58,155.22 66.58,154.94 66.33,154.69 57.97,154.69 57.82,154.53 57.41,154.53 57.18,154.76 55.51,154.76 54.74,154 54.74,152.65 54.77,152.68 55.46,152.68 55.53,152.6 55.53,150.83 56.09,150.27 57.01,150.27 57.26,150.52 57.26,152.02 57.46,152.22 57.95,152.22 58.96,153.24 63.05,153.24 63.61,152.68 66.43,152.68 66.58,152.53 66.58,152.27 66.45,152.15 63.15,152.15 62.57,152.73 59.24,152.73 58.06,151.55 58.06,148.45 54.9,145.29 ; 1 cut-out
GND on TOP: 95.54,26.92 95.16,27.3 95.16,28.07 95.92,28.83 95.92,30.1 97.06,31.24 98.97,31.24 100.11,30.1 100.11,27.05 99.98,26.92
GND on TOP: 91.14,5.18 89.49,6.83 89.49,16.87 90.1,17.48 91.98,17.48 94.19,15.27 97.95,15.27 99.19,14.02 99.19,9.96 99.8,9.35 102.14,9.35 104.68,11.89 104.68,21.89 105.01,22.23 107.17,22.23 107.75,21.64 107.75,12.32 104.45,9.02 104.45,6.45 103.18,5.18
GND on TOP: 88.24,59.05 87.79,59.5 87.79,62.58 88.25,63.04 92.64,63.04 92.87,62.81 92.87,59.31 92.62,59.05
GND on TOP: 118.14,115.72 116.52,117.35 113.34,117.35 112.91,117.78 112.91,119.51 113.37,119.96 117.05,119.96 119.06,117.96 120.78,117.96 121.34,117.4 121.34,116.28 120.78,115.72 ; 2 cut-outs
GND on TOP: 38.32,50.36 38.06,50.62 38.06,52.96 38.44,53.34 41.94,53.34 42.07,53.21 42.07,50.67 41.75,50.36 ; 2 cut-outs
GND on TOP: 24.57,148.29 23.21,149.64 20.53,149.64 20,150.18 20,153.2 20.52,153.72 25.33,153.72 26.25,152.81 27.16,152.81 27.47,152.5 27.47,149.45 27.34,149.33 25.94,149.33 25.69,149.07 25.69,148.46 25.51,148.29
GND on TOP: 41.49,30.73 41.38,30.84 41.38,33.43 42.45,34.49 42.45,38.99 42.58,39.12 45.56,39.12 45.73,38.94 45.73,38.1 45.74,38.09 45.74,37.33 45.37,36.96 45.37,34.98 43.42,33.02 43.42,30.96 43.19,30.73
GND on TOP: 39.78,202.95 39.78,204.42 39.68,204.52 38.59,204.52 37.57,205.54 37.17,205.54 36.94,205.77 36.94,206.83 37.32,207.21 37.32,211.71 37.57,211.96 41.82,211.96 42.45,211.33 42.45,203.2 42.2,202.95 ; 1 cut-out
GND on TOP: 83.24,98.28 82.99,98.53 82.99,98.79 82.48,99.29 82.48,99.67 82.99,100.18 82.99,100.56 82.35,101.2 82.35,101.45 82.99,102.09 82.99,102.6 82.35,103.23 82.35,103.36 82.48,103.48 82.73,103.48 83.62,102.6 83.62,102.09 83.11,101.58 83.11,101.07 83.62,100.56 83.62,100.31 83.11,99.8 83.11,99.42 83.62,98.91 83.62,98.53 83.37,98.28
GND on TOP: 69.62,65.53 69.62,65.53 69.32,65.53 66.58,68.28 66.58,70.1 67.09,70.61 74.07,70.61 74.2,70.48 74.2,69.85 75.47,68.58 75.47,66.6 75.37,66.5 74.05,66.5 73.69,66.14 73.69,65.66 73.57,65.53 ; 1 cut-out
GND on TOP: 121.19,123.95 121.06,124.08 121.06,128.14 121.19,128.27 125.26,128.27 127.54,125.98 127.54,125.6 125.89,123.95
GND on TOP: 125.76,109.22 125.64,109.35 125.64,111.63 125.76,111.76 126.78,111.76 126.99,111.98 126.99,112.76 127.29,113.06 127.29,114.94 127.41,115.06 129.95,115.06 130.34,114.68 130.34,113.03 129.45,112.14 129.45,109.47 129.19,109.22 ; 3 cut-outs
GND on TOP: 48.8,22.99 48.42,23.37 47.4,23.37 47.15,23.62 47.15,24.64 47.91,25.4 47.91,32.5 46.85,33.57 46.85,36.65 48.55,38.35 49.31,38.35 49.31,38.61 49.82,39.12 53.37,39.12 53.67,38.82 53.67,31.99 53.4,31.72 53.02,31.72 51.6,30.3 51.6,26.92 50.71,26.04 50.71,23.37 50.33,22.99
GND on TOP: 91.76,107.65 91.51,107.9 91.38,107.9 91.13,108.15 91.13,109.04 91.71,109.63 92.32,109.63 92.4,109.55 92.4,108.41 92.27,108.28 92.27,107.9 92.02,107.65
GND on TOP: 15.7,218.06 15.15,218.62 15.15,222.35 15.4,222.61 16.62,222.61 16.92,222.3 16.92,218.34 16.64,218.06
GND on TOP: 78.29,213.54 78.04,213.79 78.04,214.38 77.35,215.06 77.35,215.85 76.79,216.41 76.36,216.41 76.28,216.48 76.28,218.08 76.59,218.39 81.92,218.39 82.13,218.19 82.13,214.96 82.51,214.58 83.09,214.58 83.42,214.91 83.42,215.85 83.6,216.03 84.11,216.03 84.18,215.95 84.18,214.17 84.2,214.16 84.01,213.97 82.96,213.97 82.53,213.54 ; 21 cut-outs
GND on TOP: 153.83,142.88 153.58,143.13 153.58,150.5 153.63,150.55 157.06,150.55 157.13,150.47 157.13,147.7 157.64,147.19 157.64,143.26 157.26,142.88
GND on TOP: 58.62,19.39 58.24,19.77 58.24,22.82 58.49,23.08 62.3,23.08 62.56,22.82 62.56,19.65 62.3,19.39
GND on TOP: 56.42,193.8 55.66,194.56 55.66,200.15 57.12,201.61 67.22,201.61 67.72,201.1 67.72,200.03 67.47,199.77 58.96,199.77 58.2,199.01 58.2,194.44 57.56,193.8 ; 14 cut-outs
GND on TOP: 162.36,108.89 161.93,109.32 159.85,109.32 159.14,110.03 159.14,112.09 159.42,112.37 159.42,112.95 159.57,113.11 159.98,113.11 160.31,113.44 160.31,114.12 160.56,114.38 163.02,114.38 163.28,114.12 163.28,109.12 163.05,108.89 ; 10 cut-outs
GND on TOP: 80.57,95.36 80.45,95.48 80.45,95.61 80.96,96.12 80.96,96.88 80.45,97.39 80.45,97.64 80.96,98.15 80.96,98.91 80.45,99.42 80.45,99.67 80.96,100.18 80.96,100.82 80.45,101.33 80.45,101.58 80.96,102.09 80.96,102.6 80.32,103.23 80.32,103.48 80.45,103.61 80.7,103.61 81.72,102.6 81.72,102.21 81.21,101.71 81.21,101.07 81.72,100.56 81.72,100.31 81.21,99.8 81.21,99.29 81.84,98.66 81.84,98.53 81.34,98.02 81.34,97.26 82.86,95.74 82.86,95.48 82.73,95.36
GND on TOP: 72.42,22.35 71.92,22.86 71.92,26.16 74.68,28.93 74.71,28.93 74.99,29.21 77.88,29.21 78.65,28.45 78.65,26.97 79.08,26.54 81.57,26.54 82.33,25.78 82.33,22.61 82.08,22.35
GND on TOP: outline of 303 points within 0.76,0.79 184.24,229.24 ; 17 cut-outs
GND on TOP: 69.38,54.05 69.12,54.31 69.12,58.5 69.5,58.88 73.57,58.88 73.82,58.62 73.82,57.61 74.07,57.35 75.09,57.35 75.34,57.1 75.34,54.64 75.24,54.53 73.79,54.53 73.31,54.05 ; 1 cut-out
GND on TOP, BOTTOM: 63.41,20.45 63.28,20.57 63.28,22.61 63.41,22.73 66.45,22.73 66.58,22.61 66.58,20.57 66.45,20.45
GND on BOTTOM: 136.76,125.27 135.69,126.34 134.53,126.34 133.71,125.53 131.58,125.53 129.8,127.3 127.82,127.3 127.36,127.76 127.36,128.12 127.46,128.22 132.82,128.22 133.1,127.94 138.92,127.94 140.65,126.21 142.43,126.21 142.6,126.03 142.6,125.55 142.37,125.32 140.7,125.32 139.83,126.19 138.03,126.19 138.01,126.21 137.07,125.27 ; 17 cut-outs
GND on BOTTOM: 46.92,96.39 46.75,96.56 46.75,98.86 47.04,99.16 48.16,99.16 48.29,99.03 48.29,96.57 48.11,96.39 ; 2 cut-outs
GND on BOTTOM: 133.74,89.84 133.48,90.09 133.48,96.7 134.37,97.59 135.26,97.59 135.9,96.95 141.56,96.95 141.89,96.62 141.89,90.09 141.64,89.84
GND on BOTTOM: 157.77,46.61 157.51,46.86 157.51,47.37 157.13,47.75 157.13,48.39 155.86,49.66 154.59,49.66 154.21,50.04 152.31,50.04 152.05,50.29 152.05,52.7 152.18,52.83 153.45,52.83 155.74,50.55 157.26,50.55 157.64,50.93 161.32,50.93 161.7,50.55 161.7,47.12 161.2,46.61 ; 3 cut-outs
GND on BOTTOM: 22.26,146.94 21.62,147.57 21.62,154.43 22.44,155.24 25.53,155.24 25.81,154.97 25.81,151.61 26.04,151.38 27.34,151.38 27.47,151.26 27.47,148.21 27.34,148.08 26.7,148.08 25.56,146.94 ; 3 cut-outs
GND on BOTTOM: 35.29,11.96 35.01,12.24 35.01,14.38 34.58,14.81 34.58,16.76 34.73,16.92 34.73,17.63 34.88,17.78 35.67,17.78 36.45,17 37.23,17 37.35,16.89 39.35,16.89 39.48,16.76 39.48,15.9 39.38,15.8 39.38,13.26 39.25,13.13 38.36,13.13 38.16,12.93 36.53,12.93 36.38,12.78 36.38,12.27 36.08,11.96 ; 15 cut-outs
GND on BOTTOM: 23.78,160.53 23.66,160.66 23.66,164.03 24.32,164.69 24.32,165.18 24.61,165.48 27.72,165.48 27.97,165.23 27.97,160.66 27.85,160.53 ; 10 cut-outs
GND on BOTTOM: 87.55,94.41 87.37,94.59 87.37,96.18 86.8,96.75 86.8,97.39 86.54,97.64 86.54,97.9 87.05,98.4 87.05,98.79 86.29,99.55 86.26,99.55 86.14,99.67 85.53,99.67 85.4,99.8 85.4,100.26 85.5,100.36 86.62,100.36 87.05,99.93 88.83,99.93 88.92,99.84 88.92,99.23 88.85,99.17 87.94,99.17 87.69,98.91 87.69,98.28 88.78,97.18 88.78,95.69 88.58,95.48 88.58,94.59 88.39,94.41 ; 5 cut-outs
GND on BOTTOM: 83.88,109.93 83.73,110.08 83.73,110.34 83.47,110.59 82.61,110.59 82.61,110.6 80.45,110.6 80.19,110.34 79.43,110.34 79.18,110.6 79.18,113.54 79.29,113.65 79.42,113.65 79.59,113.82 79.59,114.5 79.69,114.6 80.22,114.6 80.32,114.5 80.32,113.49 81.16,112.65 83.42,112.65 84.59,111.48 84.59,110.01 84.51,109.93 ; 14 cut-outs
GND on BOTTOM: 64.1,27.19 63.66,27.64 63.66,30.99 63.67,31 63.67,33.64 63.86,33.83 66.3,33.83 67.06,33.07 67.06,27.46 66.8,27.19 ; 7 cut-outs
GND on BOTTOM: 83.17,105.33 82.94,105.56 81.08,105.56 81.01,105.64 81.01,107.24 80.73,107.52 80.73,108 80.88,108.15 84.46,108.15 84.64,107.98 84.64,105.38 84.59,105.33 ; 7 cut-outs
GND on BOTTOM: 153.83,143 153.58,143.26 153.58,148.46 153.2,148.84 153.2,149.73 153.32,149.86 156.5,149.86 157.01,149.35 157.01,143.26 156.75,143 ; 1 cut-out
GND on BOTTOM: 90.05,103.4 89.9,103.56 89.9,103.61 89.67,103.84 89.36,103.84 89.09,103.56 89.06,103.56 89.05,103.57 88.36,103.57 87.89,104.04 87.89,105.69 88.17,105.97 89.39,105.97 89.64,105.71 89.64,105.31 89.26,104.93 89.26,104.57 89.36,104.47 89.8,104.47 90.15,104.83 90.46,104.83 90.63,104.65 90.63,104.09 90.43,103.89 90.43,103.56 90.28,103.4 ; 1 cut-out
GND on BOTTOM: 60.54,213.11 60.28,213.36 60.28,218.01 60.54,218.26 65.57,218.26 65.87,217.96 65.87,215.06 65.69,214.88 65.18,214.88 65.06,215.01 64.8,215.01 64.68,214.88 64.68,213.23 64.55,213.11 ; 2 cut-outs
GND on BOTTOM: outline of 281 points within 0.76,0.76 184.24,229.24 ; 15 cut-outs
GND on BOTTOM: 46.9,83.44 46.01,84.33 46.01,90.93 46.08,91 48.48,91 48.55,90.93 48.55,90.56 48.29,90.3 48.29,86.97 48.01,86.69 48.01,83.54 47.91,83.44 ; 8 cut-outs
GND on BOTTOM: 131.86,202.69 131.22,203.33 131.22,209.42 131.61,209.8 133.51,209.8 133.64,209.68 133.64,206.63 134.53,205.74 136.05,205.74 136.43,205.36 136.43,203.33 135.8,202.69 ; 3 cut-outs
GND on BOTTOM: 164.37,98.42 164.24,98.55 164.24,106.17 164.5,106.43 165.77,106.43 166.02,106.17 166.02,98.93 165.51,98.42
GND on BOTTOM: 42.73,35.05 42.5,35.28 42.5,39.29 42.63,39.42 44.1,39.42 44.43,39.09 45.58,39.09 45.75,38.91 45.75,37.52 45.65,37.41 44.89,37.41 44.56,37.08 44.56,35.61 44,35.05
GND on BOTTOM: 8.39,134.39 8.16,134.62 8.16,138.81 8.31,138.96 10.32,138.96 10.45,138.84 10.45,137.54 10.65,137.34 13.04,137.34 13.24,137.13 13.24,134.42 13.22,134.39
GND on BOTTOM: 74.1,112.88 73.97,113.01 73.97,113.26 73.72,113.52 72.61,113.52 72.27,113.86 72.27,115.03 72.66,115.42 74.22,115.42 74.25,115.4 74.63,115.4 74.88,115.15 74.88,113.04 74.72,112.88 ; 4 cut-outs
GND on BOTTOM: 79.79,161.16 79.66,161.29 79.66,161.93 79.92,162.18 80.09,162.18 80.42,162.51 80.42,164.72 80.55,164.85 81.31,164.85 81.57,165.1 82.46,165.1 82.58,164.97 82.58,164.47 82.84,164.21 85.63,164.21 85.63,164.59 86.01,164.97 86.39,164.97 86.52,164.85 86.52,164.47 86.77,164.21 86.9,164.21 87.16,164.47 88.93,164.47 90.33,163.07 90.33,162.69 90.2,162.56 89.7,162.56 89.44,162.81 88.17,162.81 87.92,162.56 87.28,162.56 86.9,162.94 86.9,163.19 86.52,163.58 84.62,163.58 83.93,162.89 83.65,162.89 83.09,163.45 82.46,163.45 82.33,163.58 82.33,164.08 82.2,164.21 81.19,164.21 80.98,164.01 80.98,162.38 80.42,161.82 80.42,161.29 80.3,161.16 ; 4 cut-outs
GND on BOTTOM: 77.88,162.69 77.76,162.81 77.76,163.32 77.38,163.7 76.74,163.7 76.49,163.96 76.49,164.85 77.12,165.48 77.12,165.99 77.25,166.12 77.76,166.12 77.88,165.99 77.88,164.47 78.39,163.96 78.39,162.81 78.27,162.69 ; 2 cut-outs
GND on BOTTOM: 119.92,206.63 119.67,206.88 119.67,214.63 119.92,214.88 123.22,214.88 123.48,214.63 123.48,206.76 123.35,206.63 ; 5 cut-outs
GND on BOTTOM: 137.96,176.15 137.7,176.4 131.61,176.4 131.1,176.91 131.1,182.88 130.72,183.26 127.29,183.26 127.03,183.51 127.03,184.91 129.57,187.45 129.57,188.21 129.7,188.34 130.34,188.34 130.59,188.59 132.49,188.59 133.89,189.99 133.89,190.88 133.64,191.13 132.88,191.13 131.61,189.87 128.81,189.87 128.18,189.23 128.18,188.72 125.13,185.67 125.13,183.77 124.37,183.01 98.59,183.01 97.44,181.86 91.81,181.86 91.46,182.21 91.46,184.09 92.53,185.17 96.3,185.17 106.71,195.58 127.54,195.58 129.07,194.06 136.3,194.06 138.34,192.02 138.34,185.17 138.08,184.91 138.08,184.4 137.45,183.77 137.45,181.61 137.96,181.1 138.97,181.1 139.23,180.85 139.23,176.4 138.97,176.15 ; 6 cut-outs
GND on BOTTOM: 82.35,92.02 82,92.38 82,93.5 80.91,94.59 80.91,95.28 80.63,95.55 80.63,96.04 80.7,96.11 80.88,96.11 81.11,96.34 81.11,96.82 80.86,97.08 80.86,97.28 81.08,97.51 81.54,97.51 81.72,97.69 81.72,98.32 82.1,98.7 82.38,98.7 82.61,98.93 82.61,103.05 82.71,103.15 83.32,103.15 83.52,102.95 83.52,97.41 82.68,96.57 82.68,95.07 82.67,95.06 82.89,94.84 82.89,94.79 82.91,94.77 84.34,94.77 84.54,94.56 84.54,92.41 84.16,92.02 ; 8 cut-outs
GND on BOTTOM: 69.63,65.28 66.45,68.45 66.45,69.72 66.47,69.74 66.47,70.42 66.86,70.82 72.63,70.82 73.82,69.62 73.82,65.66 73.44,65.28
GND on BOTTOM: 4.74,169.39 4.51,169.62 4.51,173.81 4.66,173.96 6.67,173.96 6.8,173.84 6.8,172.54 7,172.34 9.3,172.34 9.3,169.39
GND on BOTTOM: 61.06,56.61 60.97,56.7 60.97,59.26 60.75,59.49 60.16,59.49 60.09,59.56 60.09,60.07 60.25,60.23 60.56,60.23 60.75,60.42 60.75,61.98 60.93,62.15 62.09,62.15 63.15,61.09 63.15,57.6 62.9,57.35 62.9,57 62.51,56.61 ; 6 cut-outs
GND on BOTTOM: 46.86,101.9 46.16,102.6 46.16,113.96 46.85,114.64 46.85,116.45 47.18,116.78 47.99,116.78 48.29,116.48 48.29,111.08 48.39,110.98 48.39,109.67 48.19,109.47 47.01,109.47 47.01,109.46 46.82,109.28 46.82,108.35 47.02,108.15 48.26,108.15 48.52,107.89 48.52,102.54 47.88,101.9 ; 16 cut-outs
GND on BOTTOM: 38.23,50.39 38.06,50.57 38.06,52.88 38.21,53.04 39.12,53.04 39.53,53.44 39.53,54.38 39.58,54.43 41.79,54.43 42.04,54.18 42.04,50.88 41.56,50.39
GND on BOTTOM: 57.64,178.66 57.54,178.77 57.54,181.97 57.87,182.3 74.53,182.3 74.53,182.27 74.76,182.04 74.76,178.79 74.63,178.66 ; 5 cut-outs
GND on BOTTOM: 79.53,88.24 79.43,88.35 79.43,91.32 79.51,91.39 79.84,91.39 80.45,90.78 80.45,88.35 80.35,88.24
GND on BOTTOM: 78.14,172.72 77.63,173.23 77.63,174.62 77.12,175.13 76.61,175.13 76.36,175.39 76.36,176.02 75.98,176.4 75.98,177.29 76.23,177.55 77.76,177.55 78.14,177.16 78.14,175.64 78.7,175.08 78.7,173.03 78.39,172.72 ; 6 cut-outs
GND on L2VCC: outline of 188 points within 0.76,0.76 184.24,229.24 ; 1 cut-out
GND on L3: 170.67,119.23 168.59,119.23 167.77,118.41 167.77,108.08 168.37,107.48 170.34,107.48 171.13,108.27 171.13,118.77
GND on L3: 99.6,154.56 101.38,152.78 101.38,152.15 103.79,149.73 105.82,149.73 123.35,132.21 123.35,128.12 125.93,125.54 134.08,125.54 134.27,125.73 134.27,126.92 133.76,127.43 126.27,127.43 125.13,128.57 125.13,131.83 101.25,155.7 99.98,155.7 99.6,155.32
GND on L3: outline of 180 points within 0.76,0.84 184.24,229.24
GND on L4: 121.7,135.89 121.7,135 121.19,134.49 120.94,134.49 105.7,149.73 104.17,149.73 98.46,155.45 98.46,157.73 97.95,158.24 97.7,158.24 97.44,157.99 97.44,155.6 97.17,155.33 97.14,155.33 96.85,155.03 93.99,155.03 93.7,155.33 90.58,155.33 89.31,156.59 89.31,161.16 88.04,162.43 88.04,163.96 88.55,164.47 92.36,164.47 93.89,162.94 93.89,162.69 95.16,161.42 95.54,161.42 97.44,159.51 98.08,159.51
GND on L4: 97.95,18.41 90.58,18.41 89.95,17.78 89.95,9.65 91.6,8 93.89,8 96.05,10.16 99.09,10.16 99.47,10.54 99.47,16.89
GND on L4: outline of 154 points within 0.76,0.79 184.24,229.24
GND on L5GND: outline of 124 points within 0.76,0.76 184.24,229.24 ; 1 cut-out
VCC on TOP: 105.7,57.91 105.7,58.67 105.57,58.8 105.57,64.26 105.7,64.39 108.62,64.39 108.87,64.14 108.87,58.55 108.24,57.91 ; 2 cut-outs
VCC on TOP: 19.85,190.35 19.67,190.53 19.67,192.1 20.35,192.79 20.91,192.79 21.39,193.27 21.39,200.69 20.23,201.85 20.23,205.94 20.25,205.97 22.77,205.97 24.15,204.58 24.15,192.29 22.21,190.35 ; 2 cut-outs
VCC on BOTTOM: 30.2,107.23 30.13,107.29 30.13,128.55 30.51,128.93 32.27,128.93 32.55,128.65 32.55,127.88 36.9,123.52 40.8,123.52 41.87,122.45 41.87,120.22 41.61,119.96 32.85,119.96 32.39,119.51 32.39,116.55 32.51,116.43 32.51,107.38 32.35,107.23
VCC on BOTTOM: 19.97,202.44 19.59,202.82 19.59,205.49 19.85,205.74 22,205.74 22.26,205.49 22.26,202.69 22,202.44
VCC on BOTTOM: 105.57,58.29 105.32,58.55 105.32,59.33 105.06,59.59 103.06,59.59 102.27,60.38 102.27,64.49 101.53,65.23 89.59,65.23 86.11,68.71 75.27,68.71 71.89,72.09 50.58,72.09 49.46,73.2 49.46,75.01 50.65,76.2 58.45,76.2 58.71,76.45 62.19,76.45 65.41,79.68 75.85,79.68 79.97,75.56 90.71,75.56 93.06,73.22 96.3,73.22 97.74,74.66 97.74,76.02 99.45,77.72 104.3,77.72 104.3,77.83 106.08,79.6 107.65,79.6 108.52,78.74 109.68,78.74 109.96,79.02 111.36,79.02 112.66,77.72 116.39,77.72 118.68,75.44 118.66,75.43 118.66,71.74 117.81,70.89 111.31,70.89 110.24,69.82 110.22,69.82 110.09,69.7 110.09,66.4 109.43,65.74 109.43,65.1 109.76,64.77 109.76,59.18 108.87,58.29 ; 3 cut-outs
VCC on L3: 62.54,77.36 63.11,76.78 68.78,76.78 69.43,77.43 69.43,78.44 69.38,78.48 69.38,80.38 69.29,80.48 62.76,80.48 62.54,80.26
VCC on L3: 43.01,122.71 46.9,118.82 46.9,117.35 46.54,116.99 44.76,116.99 41.75,120 41.22,120 40.1,121.13 40.1,122.31 40.5,122.71
VCC on L4: 30.1,126.87 30.42,126.55 32.01,126.55 32.6,127.14 32.6,130.74 32.59,130.75 32.59,131.74 32.57,131.76 32.57,133.66 29.39,136.83 19.44,136.83 15.9,140.38 15.9,169.2 20.3,173.6 20.3,181.84 22.37,183.91 22.37,192.94 21.62,193.69 20.4,193.69 19.81,193.1 19.81,185.04 14.05,179.28 14.05,171.02 13.35,170.31 13.35,139.37 18.55,134.16 28.15,134.16 30.1,132.21
VCC3 on TOP: 105.95,51.55 105.7,51.81 105.7,56.52 107.73,56.52 108.87,55.37 108.87,52.32 108.11,51.55 ; 1 cut-out
VCC3 on TOP: 110.04,79.25 109.71,79.58 109.71,80.82 110.4,81.51 110.4,82.35 110.85,82.8 112.68,82.8 112.81,82.68 112.81,79.48 112.58,79.25 ; 5 cut-outs
VCC3 on BOTTOM: 118.24,12.45 117.84,12.85 117.84,16.08 116.01,17.91 116.01,19.68 116.24,19.91 116.59,19.91 117.88,18.63 117.88,18.05 118.24,17.68 120.07,17.68 120.3,17.91 120.3,22.07 120.45,22.23 121.55,22.23 121.78,22 121.78,17.48 121.79,17.46 121.79,15.91 123.25,14.45 123.25,12.8 122.89,12.45
VCC3 on BOTTOM: 106.21,51.94 105.96,52.19 105.96,54.9 106.72,55.66 108.55,55.66 108.9,55.32 108.9,52.13 108.7,51.94
VCC3 on BOTTOM: 126.8,60.48 126.6,60.68 123.58,60.68 123.3,60.96 123.3,62.08 123.43,62.2 129.12,62.2 129.24,62.08 129.24,60.55 129.17,60.48 ; 8 cut-outs
VCC3 on L4: 107.98,56.01 122.54,56.01 123.07,55.47 123.5,55.47 124.87,56.85 124.87,60.96 126.37,62.45 128.02,62.45 129.13,63.56 129.13,64.48 129.51,64.86 129.51,71.01 129.12,71.4 129.12,73.63 129.52,74.04 133.16,74.04 133.59,73.61 133.59,62.66 131.5,60.58 131.5,52.12 131.94,51.69 131.94,51.23 131,50.29 128.94,50.29 128.05,49.4 122.13,49.4 121.8,49.07 107.83,49.07 107.07,49.83 107.07,55.09
VCC3_CAM on BOTTOM: 158.02,185.83 157.56,186.28 157.56,191.64 156.19,193.01 156.19,195.91 156.47,196.19 159.55,196.19 159.65,196.09 159.65,186.31 159.16,185.83 ; 4 cut-outs
VCC5_PANEL on TOP: 41.8,107.2 41.72,107.28 41.72,108.7 41.83,108.81 43.83,108.81 43.96,108.68 43.96,107.37 43.79,107.2
VCC5_PANEL on BOTTOM: 41.65,103.89 41.33,104.2 40.63,104.2 39.91,104.93 39.91,109.18 39.92,109.19 39.92,112.98 39.92,112.99 39.92,113.18 40.27,113.53 42.13,113.53 42.5,113.89 43.04,113.89 43.09,113.84 43.09,113.26 43.14,113.21 43.14,112.45 43.06,112.37 41.23,112.37 40.9,112.04 40.9,110.79 41.18,110.52 41.56,110.52 41.79,110.29 41.79,109.75 41.8,109.74 41.8,108.67 41.81,108.67 41.81,108.52 42.04,108.28 43.3,108.28 43.56,108.53 43.56,109.33 43.7,109.47 44.42,109.47 44.5,109.4 44.5,107.91 43.9,107.31 42.96,107.31 42.21,106.57 42.21,104.64 42.2,104.63 42.2,103.89 42.2,103.89 ; 4 cut-outs
VCC_FAN on TOP: 20.38,206.63 19.77,207.24 17.79,207.24 17.64,207.39 17.64,207.9 18.04,208.31 18.04,213.33 18.78,214.07 21.29,214.07 22.17,213.19 22.17,212.41 22.18,212.39 22.18,206.91 21.9,206.63 ; 3 cut-outs
VCC_FAN on BOTTOM: 20.48,206.5 20.23,206.76 20.23,208.03 19.85,208.41 19.85,210.31 20.1,210.57 22,210.57 22.13,210.44 22.13,206.63 22,206.5 ; 2 cut-outs
VCC_FAN_PWR on TOP: 16.34,207.14 15.98,207.49 15.98,209.85 15.2,210.64 12.71,210.64 12.53,210.82 12.53,213.51 12.78,213.77 15.27,213.77 16.01,214.5 17.28,214.5 17.56,214.22 17.56,208.38 17.18,208 17.18,207.26 17.05,207.14 ; 1 cut-out
VCCFHVCPU0SI0_1P15 on TOP: 88.87,196.15 88.3,196.72 88.3,197.31 88.7,197.71 89.01,197.71 89.24,197.94 89.24,198.83 89.39,198.98 90.69,198.98 90.84,198.83 90.84,196.4 90.59,196.15
VCCRAM0CPU0SI1_1P15 on TOP: 85.12,188.09 84.74,188.47 84.74,190.25 86.27,191.77 86.27,195.71 85.07,196.9 85.07,197.31 84.89,197.49 84.89,202.59 85.76,203.45 90.33,203.45 90.71,203.07 90.71,201.8 90.46,201.55 87.16,201.55 86.52,200.91 86.52,198.78 87.28,198.02 87.28,197.23 88.17,196.34 88.17,189.99 86.27,188.09 ; 3 cut-outs
VCCRAM0CPU0SI1_1P15 on TOP: 86.37,165.48 85.83,166.01 85.61,166.01 85.48,165.89 85.25,165.89 85.1,166.04 85.1,166.24 85.55,166.7 85.96,166.7 86.7,165.96 86.7,165.63 86.55,165.48
VCCRAM0CPU0SI1_1P15 on TOP: 85.63,168.61 85.28,168.96 85.28,169.49 85.96,170.18 86.27,170.18 86.39,170.05 86.39,169.77 86.27,169.65 86.14,169.65 85.83,169.34 85.83,168.99 85.91,168.91 85.91,168.68 85.83,168.61
VCCRAM0CPU0SI1_1P15 on BOTTOM: 86.08,169.7 85.87,169.9 85.87,170.07 86.56,170.76 86.56,171.06 86.69,171.19 86.69,171.63 86.7,171.63 86.93,171.86 86.93,172.26 86.98,172.31 87.33,172.31 87.44,172.2 87.44,171.14 87.33,171.03 87.33,170.07 87.13,169.87 86.48,169.87 86.31,169.7
VCCRAM0CPU0SI1_1P15 on BOTTOM: 85.89,165.17 85.79,165.27 85.79,165.58 85.5,165.87 85.25,165.87 85.14,165.99 85.14,166.29 85.7,166.85 86.31,166.85 86.48,166.68 86.48,165.26 86.39,165.17 ; 1 cut-out
VCCRAM0CPU0SI1_1P15 on L4: 85.35,178.44 85.2,178.28 85.2,165.96 85.53,165.63 86.27,165.63 86.7,166.07 86.7,167.92 86.95,168.17 86.95,171.35 86.55,171.75 86.55,188.67 86.37,188.85 85.96,188.85 85.35,188.24
VCCRTC_3P3 on BOTTOM: 71.42,153 71.15,153.27 71.16,153.29 71.16,154.8 71.6,155.24 72.51,155.24 73.08,154.67 73.08,154.03 72.57,153.52 72.57,153.38 72.19,153 ; 2 cut-outs
VCCSRAMGEN_1P15 on TOP: 87.28,198.51 87.05,198.73 87.05,200.94 87.36,201.24 90.58,201.24 90.74,201.09 90.74,199.52 90.61,199.39 89.42,199.39 89.06,199.75 88.27,199.75 87.98,199.45 87.98,198.64 87.85,198.51 ; 2 cut-outs
VDDC_CT on TOP: 86.34,102.2 86.22,102.32 86.22,103.49 86.32,103.59 86.36,103.59 87.48,103.59 87.6,103.47 87.6,102.32 87.48,102.2
0D95V_VGA_S0 on TOP: 83.25,103.2 82.77,103.68 82.44,103.68 81.98,103.23 81.25,103.23 80.76,103.72 79.65,103.72 78.38,104.99 78.38,106.67 78.64,106.94 78.64,107.7 78.77,107.82 79.35,107.82 79.68,107.49 79.68,106.69 79.86,106.51 82.44,106.51 82.69,106.77 83.2,106.77 84.85,105.12 84.85,104.48 83.57,103.2
0D95V_VGA_S0 on TOP: 103.46,109.7 102.88,110.29 102.88,112.14 101.51,113.51 101.51,114.6 101,115.11 101,117.07 101.2,117.27 105.47,117.27 105.72,117.02 105.72,110.03 105.39,109.7
0D95V_VGA_S0 on BOTTOM: 84.87,112.67 84.62,112.93 84.62,113.77 84.82,113.97 86.9,113.97 87.36,113.51 87.36,112.85 87.26,112.75 86.62,112.75 86.6,112.78 85.3,112.78 85.2,112.67 ; 3 cut-outs
0D95V_VGA_S0 on BOTTOM: 81.54,103.05 81.47,103.12 81.47,103.53 81.19,103.81 80.55,103.81 80.04,104.32 80.04,106.22 79.87,106.4 79.41,106.4 79.08,106.73 79.08,107.52 79.66,108.1 80.37,108.1 80.47,108 80.47,107.39 80.77,107.1 80.77,106.26 80.86,106.17 80.86,105.46 81.03,105.28 82.91,105.28 83.12,105.08 84.56,105.08 84.67,104.98 84.67,104.37 84.41,104.11 84.23,104.11 84.13,104.01 84.13,103.78 83.83,103.48 82.68,103.48 82.25,103.05 ; 6 cut-outs
0D95V_VGA_S0 on L3: 79.03,114.43 79.03,104.78 80.3,103.5 83.85,103.5 84.16,103.81 84.16,105.41 84.87,106.12 84.87,111.76 86.52,113.41 104.43,113.41 104.94,113.92 104.94,116.79 104.43,117.3 102.14,117.3 101.94,117.5 99.19,117.5 98.38,118.31 82.91,118.31
0P95V_A on TOP: 113.06,106.71 110.6,109.17 107.2,109.17 106.38,109.98 106.38,117.04 108.41,117.04 108.75,116.71 108.75,115.11 109.25,114.6 110.02,114.6 112.38,116.97 116.34,116.97 117.91,115.39 120.48,115.39 120.86,115.01 120.86,113.97 120.63,113.74 118.37,113.74 117.79,113.16 117.79,107.24 117.25,106.71 ; 2 cut-outs
1D5V_S0 on BOTTOM: 162.97,71.73 162.26,72.44 162.26,74.88 162.56,75.17 164.14,75.17 164.4,74.92 164.4,72.06 164.07,71.73
1D8V_S0 on TOP: 146.92,220.4 146.49,220.83 146.49,223.62 150.02,223.62 150.43,223.22 150.43,220.65 150.17,220.4 ; 6 cut-outs
1D8V_S5 on TOP: 33.65,181.52 33.22,181.95 33.22,185.31 33.23,185.32 33.23,191.57 33.56,191.9 37.24,191.9 37.75,191.39 37.75,181.86 37.41,181.52
1D8V_S5 on TOP: 66.76,118.47 61.53,123.7 58.33,123.7 55.81,126.22 55.81,131.89 55.29,132.41 55.29,133.61 55.47,133.78 58.96,133.78 59.22,134.04 59.22,134.42 59.24,134.42 59.57,134.75 59.82,134.75 60.5,134.07 60.5,132.6 60,132.1 59,132.1 58.56,131.67 58.56,128.07 58.82,127.81 60.57,127.81 60.81,127.57 60.81,126.6 61.48,125.93 62.01,125.93 67.52,120.42 70.42,120.42 73.67,123.67 77.58,123.67 80.36,120.89 82.16,120.89 82.54,121.27 82.99,121.27 83.25,121.01 83.25,118.74 83.18,118.67 79.84,118.67 79.76,118.75 79.76,118.85 79.19,119.42 78.84,119.42 78.32,119.94 78.32,119.99 76.64,121.67 74.46,121.67 73.26,120.47 73.26,120.32 71.41,118.47
1D8V_S5 on BOTTOM: 56.55,127.97 54.92,129.59 54.92,136.96 52.59,139.29 52.59,140.82 51.35,142.05 49.91,142.05 49.54,142.42 49.54,154.1 48.8,154.84 48.8,163.19 46.26,165.74 46.26,168.15 47.4,169.29 50.33,169.29 54.14,165.48 54.14,156.21 54.01,156.08 54.01,155.57 56.04,153.54 56.04,146.96 61.2,141.81 61.2,141.58 61.68,141.1 63.07,141.1 63.76,140.41 63.76,140.03 63.63,139.91 63.38,139.91 63.36,139.9 63.1,140.16 62.77,140.16 62.4,139.79 61.65,139.79 61.15,139.28 61.15,128.96 60.15,127.97
1D8V_S5 on BOTTOM: 33.43,186.06 33.18,186.31 33.18,191.39 33.56,191.77 36.1,191.77 37.12,190.75 37.12,186.31 36.86,186.06
1D8V_S5 on L3: 31.91,185.08 31.91,174.37 36.36,169.93 36.36,168.43 38.41,166.37 42.32,166.37 42.83,165.86 48.67,165.86 49.37,166.56 49.37,170.12 43.98,175.51 39.89,175.51 37.73,177.67 37.73,190.96 36.74,191.95 32.65,191.95 31.92,191.22 31.92,185.08
1D8V_VGA_AVDD on BOTTOM: 90.41,106.86 89.59,107.67 89.59,109.37 90.2,109.98 90.2,110.92 90.3,111.02 91.09,111.02 91.19,110.92 91.19,108.51 91.45,108.25 91.45,107.09 91.22,106.86 ; 3 cut-outs
1D8V_VGA_S0 on TOP: 93.67,109.77 93.56,109.88 93.56,110.29 93.62,110.34 94.04,110.34 95.08,111.39 95.08,115.11 95.24,115.27 96.3,115.27 96.83,115.8 97.9,115.8 97.97,115.72 97.97,112.12 97.85,111.99 97.08,111.99 96.83,111.74 96.81,111.74 96.81,111.28 95.56,110.03 95.02,110.03 94.76,109.77 ; 4 cut-outs
1D8V_VGA_S0 on TOP: 83.57,112.04 82.71,112.9 82.71,114.63 82.05,115.29 82.05,118.11 82.25,118.31 84.11,118.31 84.69,117.73 84.69,116.38 84.95,116.13 85.99,116.13 88.32,113.79 88.32,112.83 87.54,112.04 ; 3 cut-outs
1D8V_VGA_S0 on BOTTOM: 87.79,109.93 87.45,110.27 86.81,110.27 86.65,110.44 86.65,110.85 86.93,111.12 87.41,111.12 87.64,111.35 87.64,113.51 87.92,113.79 89.26,113.79 89.85,113.21 89.85,110.13 89.64,109.93
1D8V_VGA_S0 on L4: 96.55,116.71 82.79,116.71 82.35,116.28 82.35,114.07 83.42,113 96.65,113 97.29,113.64 97.29,115.98
1D8V_VGA_VDD1DI on BOTTOM: 90.1,105.36 89.9,105.56 89.9,105.82 89.49,106.22 88.27,106.22 88.17,106.32 88.17,106.73 88.02,106.88 87.54,106.88 87.46,106.96 87.46,107.24 87.03,107.67 87.03,109.27 87.31,109.55 88.6,109.55 88.73,109.42 88.73,107.42 89.21,106.93 90.25,106.93 90.43,106.76 90.43,105.46 90.33,105.36
1D8V_VGA_VDDR4 on TOP: 83.8,95.89 83.22,96.47 83.22,96.75 83.35,96.88 85.48,96.88 85.63,96.72 85.63,96.29 85.22,95.89
1D8V_VGA_VDDR4 on BOTTOM: 84.77,94.06 84.62,94.21 84.62,94.84 84.49,94.97 83.8,94.97 83.68,95.1 83.68,96.44 83.8,96.57 85.02,96.57 85.43,96.16 85.43,94.18 85.3,94.06 ; 1 cut-out
1D24V_S5 on TOP: 78.22,168.24 77.93,168.53 77.93,169.11 78.04,169.22 78.04,169.47 77.88,169.62 77.48,169.62 77.43,169.68 77.43,171.2 77.55,171.32 77.55,171.68 77.38,171.86 77,171.86 76.84,171.7 76.69,171.7 76.59,171.81 76.59,171.93 77.12,172.47 77.76,172.47 78.82,171.4 78.82,171.04 78.44,170.66 78.44,169.42 78.52,169.34 79,169.34 79.71,170.05 81.14,170.05 81.29,170.21 81.57,170.21 81.69,170.08 81.92,170.08 82.41,170.56 82.84,170.56 82.94,170.46 82.94,169.57 83.55,168.96 83.55,168.73 83.47,168.66 82.84,168.66 82.71,168.53 82.46,168.53 81.19,169.8 80.81,169.8 79.24,168.24
1D24V_S5 on TOP: 50.73,174.96 50.68,175.01 50.68,177.75 50.91,177.98 55.48,177.98 55.76,177.7 55.76,176.63 55.46,176.33 53.12,176.33 52.64,175.84 52.64,175.56 52.03,174.96 ; 2 cut-outs
1D24V_S5 on BOTTOM: 79.69,164.97 79.54,165.13 79.54,165.61 79.36,165.79 78.87,165.79 78.67,165.58 78.32,165.58 77.97,165.93 77.97,166.04 77.1,166.92 77.1,167.95 76.13,168.92 76.13,171.04 74.86,172.31 74.86,172.95 74.75,173.06 73.32,173.06 73.31,173.05 71.33,173.05 71.23,173.15 68.82,173.15 67.88,174.09 61.3,174.09 60.19,175.2 54.83,175.2 54.03,176 54.03,177.93 54.44,178.33 75.29,178.33 75.85,177.77 75.85,176.28 76.13,176 76.13,174.98 76.36,174.75 76.36,174.4 78.52,172.24 78.52,169.48 78.54,169.48 79.04,168.98 79.04,167.41 80.48,165.97 80.48,165.86 80.68,165.86 81.31,166.5 81.44,166.5 81.57,166.37 81.57,165.86 80.68,164.97 ; 15 cut-outs
1D35V_VGA_S0 on TOP: 48.47,81.46 48.47,85.27 48.42,85.32 48.42,85.6 48.45,85.63 48.45,86.39 48.39,86.46 48.39,87.62 48.59,87.83 48.59,90.85 48.7,90.95 49.33,90.95 49.76,91.38 51.11,91.38 51.64,90.85 51.64,90.01 53.09,88.56 53.09,87.52 52.58,87.01 51.87,87.01 51.21,86.36 51.21,83.11 49.56,81.46 ; 6 cut-outs
1D35V_VGA_S0 on TOP: 50.88,96.26 50.75,96.39 48.62,96.39 48.54,96.46 48.54,96.97 48.64,97.07 50.35,97.07 50.47,97.2 50.47,98.09 50.29,98.28 48.82,98.28 48.7,98.4 48.7,102.41 48.83,102.54 48.83,106.43 48.82,106.43 48.7,106.55 48.7,108.06 48.79,108.15 50.22,108.15 50.37,108 50.37,105.8 50.94,105.22 50.94,103.41 50.78,103.24 50.77,103.24 50.36,102.84 50.36,101.84 49.97,101.45 49.97,99.67 50.23,99.41 50.8,99.41 50.98,99.59 50.98,100.93 51.11,101.06 51.87,101.06 52.71,100.22 52.71,96.67 52.3,96.26 ; 9 cut-outs
1D35V_VGA_S0 on TOP: 48.9,114.17 48.59,114.47 48.59,118.29 48.57,118.31 48.57,119.66 47.43,120.8 47.43,127.15 49.13,128.85 51.42,128.85 51.9,129.34 51.9,129.97 51.95,130.02 52.56,130.02 53.58,129.01 55.43,129.01 55.51,128.93 55.51,123.72 52.94,121.16 52.94,118.77 52.56,118.39 52.56,117.25 52.79,117.02 53.34,117.02 53.44,116.92 53.44,115.36 52.76,114.68 50.88,114.68 50.37,114.17 ; 9 cut-outs
1D35V_VGA_S0 on BOTTOM: 48.67,113.26 48.57,113.36 48.57,118.34 48.58,118.35 48.58,125.28 48.6,125.3 48.6,125.83 48.93,126.16 52.84,126.16 53.73,125.27 53.73,121.66 50.55,118.49 50.55,113.49 50.32,113.26 ; 4 cut-outs
1D35V_VGA_S0 on BOTTOM: 48.55,83.44 48.42,83.57 48.42,85.93 48.59,86.1 48.59,90.04 48.95,90.4 48.95,90.82 49.13,91 50.22,91 50.37,91.16 52.17,91.16 52.66,90.67 52.66,89.55 52.17,89.07 51.64,89.07 51.46,88.89 51.46,88.21 51.87,87.8 52.48,87.8 52.86,88.18 53.29,88.18 53.44,88.03 53.44,86.38 53.29,86.23 53.09,86.23 52.58,86.74 51.92,86.74 51.64,86.46 51.64,85.85 51.87,85.62 52.12,85.62 52.3,85.8 52.66,85.8 52.73,85.72 52.73,84.6 52.75,84.59 52.75,83.7 52.48,83.44 ; 6 cut-outs
1D35V_VGA_S0 on BOTTOM: 52,94.97 50.57,96.39 48.77,96.39 48.59,96.57 48.59,101.15 48.85,101.41 48.85,105.86 49.05,106.06 50.8,106.06 51.18,105.68 51.18,101.65 52.61,100.22 52.61,95.17 52.4,94.97 ; 5 cut-outs
1D35V_VGA_S0 on BOTTOM: 60.51,89.26 60.51,91.29 61.78,92.56 61.78,96.88 61.91,97.01 62.29,97.01 62.54,97.26 62.54,99.29 61.52,100.31 61.52,103.48 58.73,106.28 58.73,108.18 58.86,108.31 59.24,108.31 61.4,106.15 61.4,106.02 62.92,104.5 63.56,104.5 64.19,103.87 64.19,103.1 65.08,102.21 66.48,102.21 67.49,101.2 71.94,101.2 72.19,101.45 72.19,103.76 72.6,104.17 76.05,104.17 76.51,104.63 76.51,105.9 76.64,106.02 77.91,106.02 78.16,106.28 78.92,106.28 79.05,106.15 79.05,103.99 78.67,103.61 78.67,97.39 78.8,97.26 78.8,93.71 78.42,93.32 77.78,93.32 77.02,92.56 72.95,92.56 71.56,93.96 65.72,93.96 61.02,89.26 ; 11 cut-outs
1D35V_VGA_S0 on L3: 52.25,83.79 52.07,83.97 50.89,83.97 48.17,86.69 48.17,87.5 48.04,87.63 48.04,99.31 48.17,99.44 48.17,127.99 49.12,128.94 52.1,128.94 53.73,127.32 53.73,123.67 53.25,123.19 53.25,115.57 52.23,114.55 52.23,112.14 51.98,111.89 50.96,111.89 50.83,111.76 50.83,110.24 52.23,108.84 52.23,105.54 51.21,104.52 51.21,102.36 51.98,101.6 51.98,92.33 50.93,91.28 52.25,91.28 52.38,91.16 52.38,88.23 52.89,87.73 52.89,85.31 53.39,84.81 55.55,84.81 57.08,86.33 57.71,86.33 58.35,85.69 58.35,84.43 57.7,83.79 ; 1 cut-out
1D35V_VGA_S0 on L4: 47.6,88.17 47.6,117.76 48.45,118.61 48.45,125.32 48.96,125.82 53.76,125.82 55.45,124.13 65.01,124.13 69.12,120.02 71.28,120.02 79.43,111.86 79.43,109.51 80.15,108.8 80.15,103.54 79.62,103.01 79.62,98.47 82.86,95.23 84.11,95.23 84.62,94.72 84.62,92.08 84.63,92.06 84.63,90.36 86.16,88.83 86.16,85.8 81.31,80.95 74.03,80.95 73.96,80.89 54.91,80.89 52.74,83.06 52.71,83.06 ; 1 cut-out
1P05V_A on TOP: 38.77,188.62 38.3,189.09 38.3,193.76 38.84,194.31 44.61,194.31 45.37,195.07 50.38,195.07 52.08,193.37 53.6,193.37 53.68,193.29 53.68,191.92 53.31,191.55 52.73,191.55 52.36,191.19 52.36,189.97 52.84,189.48 53.04,189.48 53.27,189.26 53.27,188.75 53.14,188.62 ; 2 cut-outs
1P05V_A on L3: 40.88,188.59 48.6,188.59 49.46,189.45 49.46,194.22 49.06,194.63 40.67,194.63 39.96,193.92 39.96,189.51
1P05V_S5 on TOP: 86.42,167.08 86.32,167.18 86.32,168.12 86.44,168.25 86.72,168.25 87.51,167.46 87.51,167.16 87.43,167.08
1P05V_S5 on TOP: 60.49,182.63 60.46,182.65 52.61,182.65 51.7,183.57 48.93,183.57 46.79,185.7 46.79,187.45 47.12,187.78 52.2,187.78 53.18,186.8 72.08,186.8 72.25,186.64 72.25,183.36 71.51,182.63 ; 12 cut-outs
1P05V_S5 on TOP: 86.42,161.77 86.32,161.87 86.32,162.81 86.47,162.97 87.36,162.97 87.49,162.84 87.49,162.53 86.72,161.77
1P05V_S5 on TOP: 78.67,162.43 78.49,162.61 78.49,163.75 78.85,164.11 78.85,164.39 78.52,164.72 78.52,165.2 79.26,165.94 79.56,165.94 79.66,165.84 79.66,165.66 79.56,165.56 79.56,165.2 79.69,165.07 79.69,164.82 79.28,164.41 79.28,164.11 79.66,163.73 79.66,162.59 79.51,162.43
1P05V_S5 on TOP: 80.16,166.37 80.05,166.49 80.05,167.02 79.34,167.73 79.34,168.2 80.81,169.67 81.19,169.67 81.57,169.29 81.57,168.28 81.58,168.26 81.58,167.78 81.97,167.39 81.97,167.03 81.31,166.37
1P05V_S5 on BOTTOM: 79.19,159.23 78.48,159.94 78.48,160.22 78.27,160.43 77.33,160.43 77.1,160.2 77.1,159.94 77,159.84 76.64,159.84 76.44,160.05 76.44,160.55 77.02,161.14 77.73,161.14 78.52,161.93 78.52,163.96 78.01,164.47 78.01,164.97 78.14,165.1 78.39,165.1 78.95,165.66 79.23,165.66 79.38,165.51 79.38,165 79.54,164.85 80.04,164.85 80.3,164.59 80.3,162.56 80.17,162.43 79.79,162.43 79.54,162.18 79.54,161.25 79.68,161.11 79.96,161.11 80.11,160.95 80.11,159.44 79.91,159.23 ; 4 cut-outs
1P05V_S5 on BOTTOM: 88.43,150.97 87.31,152.09 87.31,154.45 86.59,155.16 86.59,158.66 86.8,158.87 88.19,158.87 88.2,158.88 88.32,158.88 88.48,158.72 88.48,155.4 88.65,155.23 88.65,153.79 90.66,151.77 90.66,151.38 90.25,150.97 ; 6 cut-outs
1P05V_S5 on BOTTOM: 79.77,167.39 79.51,167.65 79.51,168.67 80.04,169.2 80.04,169.27 80.3,169.53 80.3,170.18 80.55,170.43 80.93,170.43 81.1,170.27 81.1,169.73 81.28,169.55 81.53,169.55 81.69,169.39 81.69,167.6 81.49,167.39 ; 2 cut-outs
1P05V_S5 on L3: 89.29,149.33 88.55,148.59 86.55,148.59 86.24,148.89 86.24,149.63 86.47,149.86 87.74,149.86 88.58,150.7 88.59,150.7 89.35,151.46 89.47,151.46 89.48,151.47 89.6,151.47 89.98,151.09 89.98,150.67 89.29,149.97
1P05V_S5 on L3: 73.92,184.96 74.44,184.44 74.44,179.08 75.85,177.67 75.85,169.85 76.28,169.43 80.69,169.43 80.95,169.16 80.95,166.77 80.32,166.14 69.81,166.14 67.98,167.97 67.98,184.33 68.61,184.96
1P05V_S5 on L4: 77.25,165.35 77.04,165.15 76.32,165.15 75.79,164.61 75.79,163.9 76.21,163.48 76.21,160.15 76.82,159.54 76.82,158.98 76.59,158.75 75.09,158.75 73.29,156.95 73.29,155.8 73.64,155.45 75.34,155.45 76.84,156.95 76.84,157.66 77.85,158.66 77.85,159.09 78.17,159.42 78.43,159.17 78.43,156.6 79.4,155.63 79.4,151.26 79.91,150.75 81.89,150.75 82.96,149.68 84.05,149.68 86.51,147.23 87.73,147.23 88.24,147.75 88.24,148.07 85.43,150.88 84.72,150.88 81.89,153.71 81.89,158.54 81.91,158.56 81.91,161.53 81.35,162.09 81.35,165.26 80.93,165.68 80.93,169.37 80.78,169.52 80.78,170.21 79.73,171.26 79.73,171.34 79.7,171.37 79.7,171.73 79.45,171.98 79.45,173.26 79.28,173.42 79.28,173.74 79.41,173.86 79.41,180.52 79,180.92 79,184.1 76.37,186.73 76.37,188.13 75.57,188.93 63.48,188.93 63.47,188.91 63.34,188.91 62.14,187.71 62.14,187.55 60.79,186.21 60.79,184.68 61.15,184.33 63.41,184.33 64.52,185.45 74.48,185.45 76.82,183.11 76.82,179.45 77.08,179.19 77.08,171.4 77.38,171.11 77.38,169.04 77.38,169.04 77.38,166.37 77.25,166.5
1P8V_PWR on TOP: 26.07,184.15 25.18,185.04 25.18,195.99 25.81,196.63 31.69,196.63 32.48,195.83 32.48,184.47 32.16,184.15 ; 2 cut-outs
1P8V_PWR on BOTTOM: 26.2,185.29 25.43,186.06 25.43,196.09 25.94,196.6 31.66,196.6 32.42,195.83 32.42,185.8 31.91,185.29
1P8V_PWR_PHASE on TOP: 26.45,200.28 24.93,201.8 24.93,204.34 22.64,206.63 22.64,212.22 22.77,212.34 28.1,212.34 28.23,212.22 28.23,208.91 28.61,208.53 30.89,208.53 31.15,208.79 34.58,208.79 34.7,208.66 34.7,201.42 33.56,200.28 ; 2 cut-outs
1P15V_S5 on TOP: 91.73,197.49 91.47,197.74 91.47,203.07 91.6,203.2 95.54,203.2 96.25,202.49 96.25,197.85 95.92,197.51 94.93,197.51 94.9,197.49
3D3V_RUN_FFS on TOP: 79.07,73.75 78.4,74.41 78.4,77.51 81.15,80.25 82.95,80.25 82.96,80.26 83.55,80.26 85.05,81.75 85.07,81.75 85.34,82.02 87.76,82.02 87.9,81.88 87.9,80.2 87.69,79.98 86.19,79.98 85.64,79.44 84.65,79.44 83.9,78.69 82.89,78.69 82.43,78.23 81.23,78.23 79.78,76.78 79.78,75.56 80.51,74.83 84.77,74.83 85.07,75.13 85.07,75.87 85.12,75.92 85.83,75.92 85.91,75.84 85.91,74.4 86.01,74.3 86.01,73.83 85.94,73.75 ; 5 cut-outs
3D3V_VGA_S0 on TOP: 99.45,79.63 99.32,79.76 99.32,81.48 99.5,81.66 101.18,81.66 101.46,81.94 101.46,84.35 101.37,84.44 99.28,84.44 98.99,84.73 98.2,84.73 97.67,85.27 97.67,86.5 97.66,86.51 97.66,87.5 97.72,87.56 97.72,88.15 97.79,88.22 98.36,88.22 98.6,87.98 98.6,87.2 99.14,86.66 99.14,86.41 99.73,85.83 101.66,85.83 102.45,85.04 102.45,83.59 102.85,83.19 106.51,83.19 107.58,84.25 107.58,85.04 107.86,85.32 110.4,85.32 110.78,84.94 110.78,83.74 110.22,83.19 107.73,83.19 106.46,81.92 104.07,81.92 101.79,79.63 ; 4 cut-outs
3D3V_VGA_S0 on TOP: 86.38,100.15 86.22,100.3 86.22,101.57 86.27,101.62 87.46,101.62 87.58,101.51 87.58,100.24 87.49,100.15
3D3V_VGA_S0 on L3: 99.78,94.79 98.25,94.79 97.24,93.78 97.24,86.87 97.75,86.36 98.59,86.36 98.94,86.72 98.94,92.33 99.91,93.29 99.91,94.67
3D3V_VGA_S0 on L4: 87.28,96.55 87.28,94.74 88.68,93.34 93.07,93.34 93.61,92.81 99.02,92.81 100.21,94.01 100.21,94.82 99.93,95.1 90.15,95.1 89.63,95.62 89.63,96.48 88.83,97.28 88.83,99.19 87.97,100.05 87.97,100.76 87.99,100.79 87.99,100.84 87.54,101.3 86.52,101.3 86.24,101.02 86.24,97.59
62883AGND on BOTTOM: 136.37,79.54 135.21,80.7 134.05,80.7 134.04,80.7 131.86,80.7 131.5,81.05 127.99,81.05 127.81,81.23 127.81,83.48 128.58,84.25 128.58,84.75 128.69,84.86 130.55,84.86 130.83,84.57 132.45,84.57 132.65,84.38 132.65,82.42 132.85,82.21 134.68,82.21 135.96,83.5 139.35,83.5 139.56,83.71 139.56,84.12 137.35,86.33 137.35,87.74 137.84,88.22 139.69,88.22 141.62,86.29 141.62,86.18 141.61,86.16 141.61,84.65 141.92,84.33 141.92,82.38 139.08,79.54 ; 9 cut-outs
+3D3V_PWR on TOP: 90.42,49.11 90.38,49.15 86.24,49.15 85.47,49.92 85.47,54.83 85.86,55.22 89.21,55.22 89.97,54.46 93.48,54.46 95.41,56.39 97.57,56.39 97.7,56.26 97.7,49.71 97.12,49.13 92.16,49.13 92.14,49.11 ; 2 cut-outs
+DCBATOUT_RT8243_1 on TOP: 66.76,48.59 65.51,49.83 65.51,53.26 66.12,53.87 68.38,53.87 69.16,53.1 73.1,53.1 73.67,52.53 76.61,52.53 76.87,52.27 76.87,48.84 76.61,48.59
+DCBATOUT_RT8243_1 on TOP: 67.29,60.43 66.35,61.37 66.35,63.86 63.63,66.57 63.05,66.57 62.35,67.27 62.35,68.98 62.61,69.24 64.8,69.24 64.82,69.22 65.17,69.22 69.66,64.73 73.53,64.73 73.92,64.34 76.97,64.34 77.1,64.21 77.1,60.58 76.94,60.43
+DCBATOUT_RT8243_1 on BOTTOM: 67.86,51.42 64.78,54.51 64.78,56.68 64.18,57.28 64.18,60.64 62.16,62.66 62.16,69.22 62.36,69.42 64.92,69.42 70.18,64.16 73.41,64.16 73.49,64.08 73.49,52.02 72.89,51.42
AD+_TO_SYS on TOP: 57.09,40.77 57.09,41.74 57.01,41.83 55,41.83 54.87,41.71 54.87,41.03 54.74,40.91 53.64,40.91 52.61,41.94 52.61,47.24 52.62,47.26 52.62,47.64 52.88,47.89 57.5,47.89 57.82,47.57 57.82,41.02 57.56,40.77 ; 1 cut-out
AD+_TO_SYS on BOTTOM: 54.52,37.03 54.01,37.54 54.01,44.91 54.01,44.91 54.01,44.96 54.52,45.47 58.71,45.47 59.34,44.83 59.34,37.13 59.24,37.03
AD_JK on TOP: 55.66,24.26 53.5,26.42 53.5,29.36 55.63,31.5 55.63,37.95 55.66,37.97 55.66,38.86 55.79,38.99 59.62,38.99 60.36,38.25 65.64,38.25 66.58,37.31 66.58,33.78 66.19,33.39 66.09,33.39 65.31,32.61 65.31,30.12 65.08,29.9 64.7,29.9 64.02,29.21 64.02,28.57 63.83,28.38 63.6,28.38 63.28,28.07 63.28,24.89 62.64,24.26 ; 2 cut-outs
AD_JK on BOTTOM: 55.28,21.77 54.68,22.36 54.68,23.48 53.02,25.15 53.02,26.01 51.9,27.13 51.9,31.67 53.75,33.53 63.23,33.53 63.28,33.48 63.28,25.17 59.88,21.77 ; 6 cut-outs
AD_JK on L3: 62.14,31.11 54.52,31.11 53.37,29.97 53.37,25.4 53.88,24.89 60.74,24.89 62.52,26.67 62.52,30.73
AMP_GND on L3: 157.96,37.08 159.16,37.08 161.2,35.05 162.47,35.05 162.59,34.92 162.59,34.04 162.34,33.78 161.7,33.78 161.58,33.91 160.69,33.91 157.64,30.86 157.64,28.7 156.88,27.94 156.88,23.24 155.86,22.23 155.86,21.69 156.34,21.21 156.9,21.21 163.1,27.41 163.96,27.41 164.94,28.38 164.94,35.75 162.09,38.61 157.89,38.61 157.75,38.47 157.75,37.29
BT+ on TOP: 34.77,66.15 34.45,66.47 34.45,66.75 33.95,67.24 31.05,67.24 30.71,67.58 30.71,74.21 31.01,74.51 34.83,74.51 35.07,74.75 36.99,74.75 37.65,75.41 38.59,75.41 38.74,75.26 38.74,73.61 38.72,73.61 38.47,73.36 38.47,68.96 38.48,68.95 38.48,68.29 39.48,67.28 39.48,66.43 39.2,66.15 ; 4 cut-outs
BT+_R on TOP: 37.27,62.02 36.97,62.32 35.46,62.32 34.54,63.24 34.54,65.36 34.9,65.71 39.4,65.71 39.52,65.6 39.52,65.28 40.42,65.28 40.67,65.02 40.67,62.69 40.01,62.02
BT+_R on BOTTOM: 35.21,62.99 34.96,63.25 34.96,66.8 35.34,67.18 39.91,67.18 40.42,66.67 40.42,63.25 40.17,62.99
CAGND on TOP: 33.19,28.23 31.94,29.49 31.94,30 32.67,30.73 34.07,30.73 35.34,32 35.34,33.35 35.47,33.48 40.14,33.48 40.52,33.1 40.52,30.33 40.06,29.87 37.68,29.87 37.17,30.38 35.97,30.38 35.67,30.07 35.67,28.78 35.12,28.23 ; 6 cut-outs
DC_19V on TOP: 60.87,38.61 60.1,39.37 58.58,39.37 58.33,39.62 58.33,46.61 58.35,46.63 58.35,47.73 58.5,47.89 63.72,47.89 64.63,46.98 64.63,45.71 67.72,42.62 67.72,39.24 67.09,38.61
DC_19V on BOTTOM: 59.98,37.01 59.85,37.13 59.85,44.58 60.1,44.83 65.49,44.83 67.55,42.77 67.55,38.46 66.1,37.01
DCBATOUT on TOP: 57.82,66.8 56.8,67.82 56.8,69.27 57.95,70.41 59.9,70.41 59.93,70.43 60.71,70.43 61.65,69.49 61.65,67.39 61.07,66.8 ; 2 cut-outs
DCBATOUT on TOP: 135.9,97.46 134.88,98.48 130.06,98.48 129.93,98.6 129.93,104.25 130.05,104.38 131.16,104.38 131.58,104.8 131.58,108.46 131.73,108.61 133.31,108.61 134.27,107.65 136.79,107.65 140.05,104.38 145.78,104.38 146.9,103.26 146.9,97.82 146.54,97.46 ; 2 cut-outs
DCBATOUT on TOP: 148.88,37.25 147.83,38.3 147.83,41.5 148.08,41.75 149.18,41.75 149.58,41.36 149.58,39.36 150.05,38.89 152.36,38.89 152.69,38.56 152.69,37.42 152.52,37.25 ; 2 cut-outs
DCBATOUT on TOP: 49.03,208.2 48.72,208.51 48.72,212.12 48.8,212.19 48.8,216.43 55.05,222.68 57.67,222.68 58.35,222 58.35,220.34 57.44,219.43 56.29,219.43 51.51,214.64 51.51,208.47 51.24,208.2
DCBATOUT on TOP: 39.89,68.43 39.68,68.63 39.68,71.58 39.73,71.63 39.73,71.78 39.68,71.83 41.54,71.83 41.99,72.29 42.58,72.29 43.16,72.87 43.16,73.13 43.26,73.23 46.59,73.23 46.59,70.97 44.05,68.43 ; 5 cut-outs
DCBATOUT on TOP: 143.8,140.34 143.54,140.59 143.54,143.64 143.67,143.76 147.99,143.76 148.12,143.64 148.12,140.59 147.86,140.34
DCBATOUT on TOP: 42.45,39.5 42.32,39.62 42.32,43.54 40.95,44.91 35.53,44.91 31.67,48.77 31.67,55.51 31.68,55.52 31.68,56.01 32.06,56.39 36.48,56.39 37.56,55.31 37.56,50.38 38.03,49.91 47.63,49.91 49.53,48.01 51.8,48.01 52.1,47.71 52.1,42.32 51.7,41.91 50.74,41.91 50.64,41.81 50.64,41.27 50.39,41.02 49.21,41.02 49.06,41.17 49.06,42.01 48.37,42.7 46.74,42.7 46.03,41.99 46.03,40.16 45.37,39.5 ; 2 cut-outs
DCBATOUT on BOTTOM: outline of 107 points within 25.55,37.82 158.63,111.44 ; 5 cut-outs
DCBATOUT on BOTTOM: 43.23,123.15 41.56,124.82 38.41,124.82 33.48,129.74 32,129.74 28.46,133.29 28.42,133.29 27.59,134.11 18.7,134.11 15.53,137.29 15.53,147.68 10.75,152.45 10.75,154.51 10.7,154.56 10.7,163.27 9.55,164.43 9.55,184.1 5.41,188.24 5.29,188.24 2.65,190.88 2.65,223.62 6.36,227.33 55.56,227.33 58.58,224.31 58.58,220.22 58.4,220.04 54.36,220.04 54.06,220.34 54.06,222.71 52.87,223.9 11.11,223.9 8.94,221.73 8.94,192.04 14.69,186.28 14.69,155.4 16.67,153.42 18.45,153.42 19.08,154.05 19.08,159 19.59,159.51 21.24,159.51 21.62,159.13 21.62,157.35 20.86,156.59 20.86,140.59 21.37,140.08 25.18,140.08 25.88,139.38 30.5,139.38 31.64,138.25 34.48,138.25 36.89,135.84 39.76,135.84 46.45,129.15 46.45,123.83 45.78,123.15
